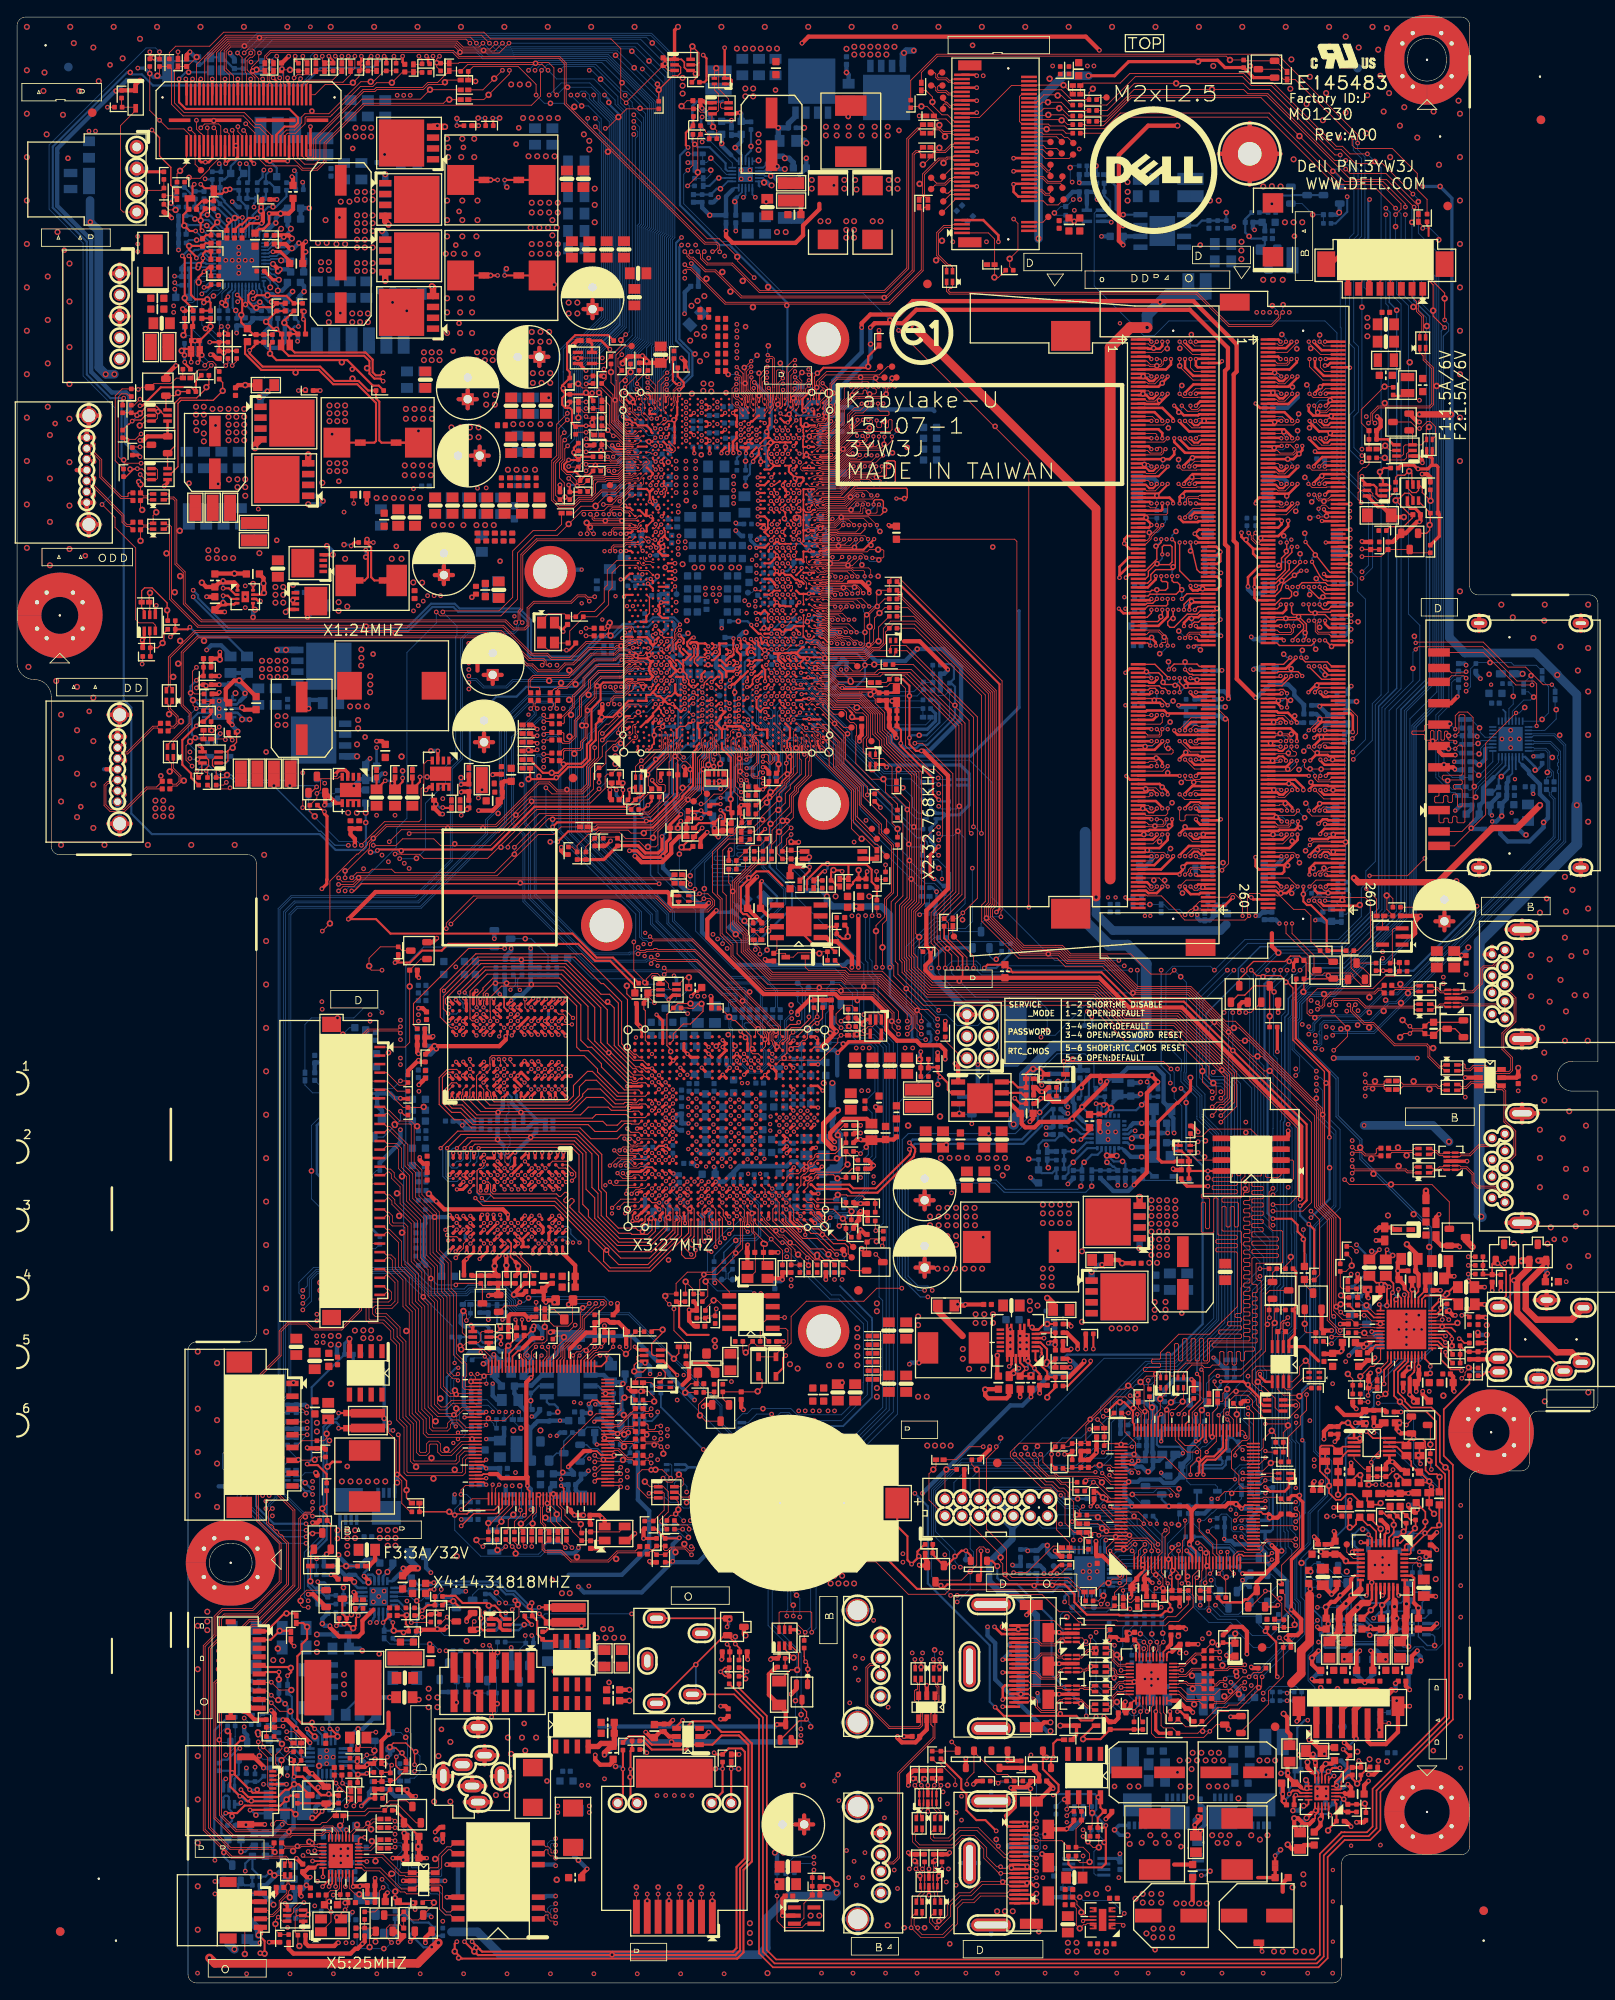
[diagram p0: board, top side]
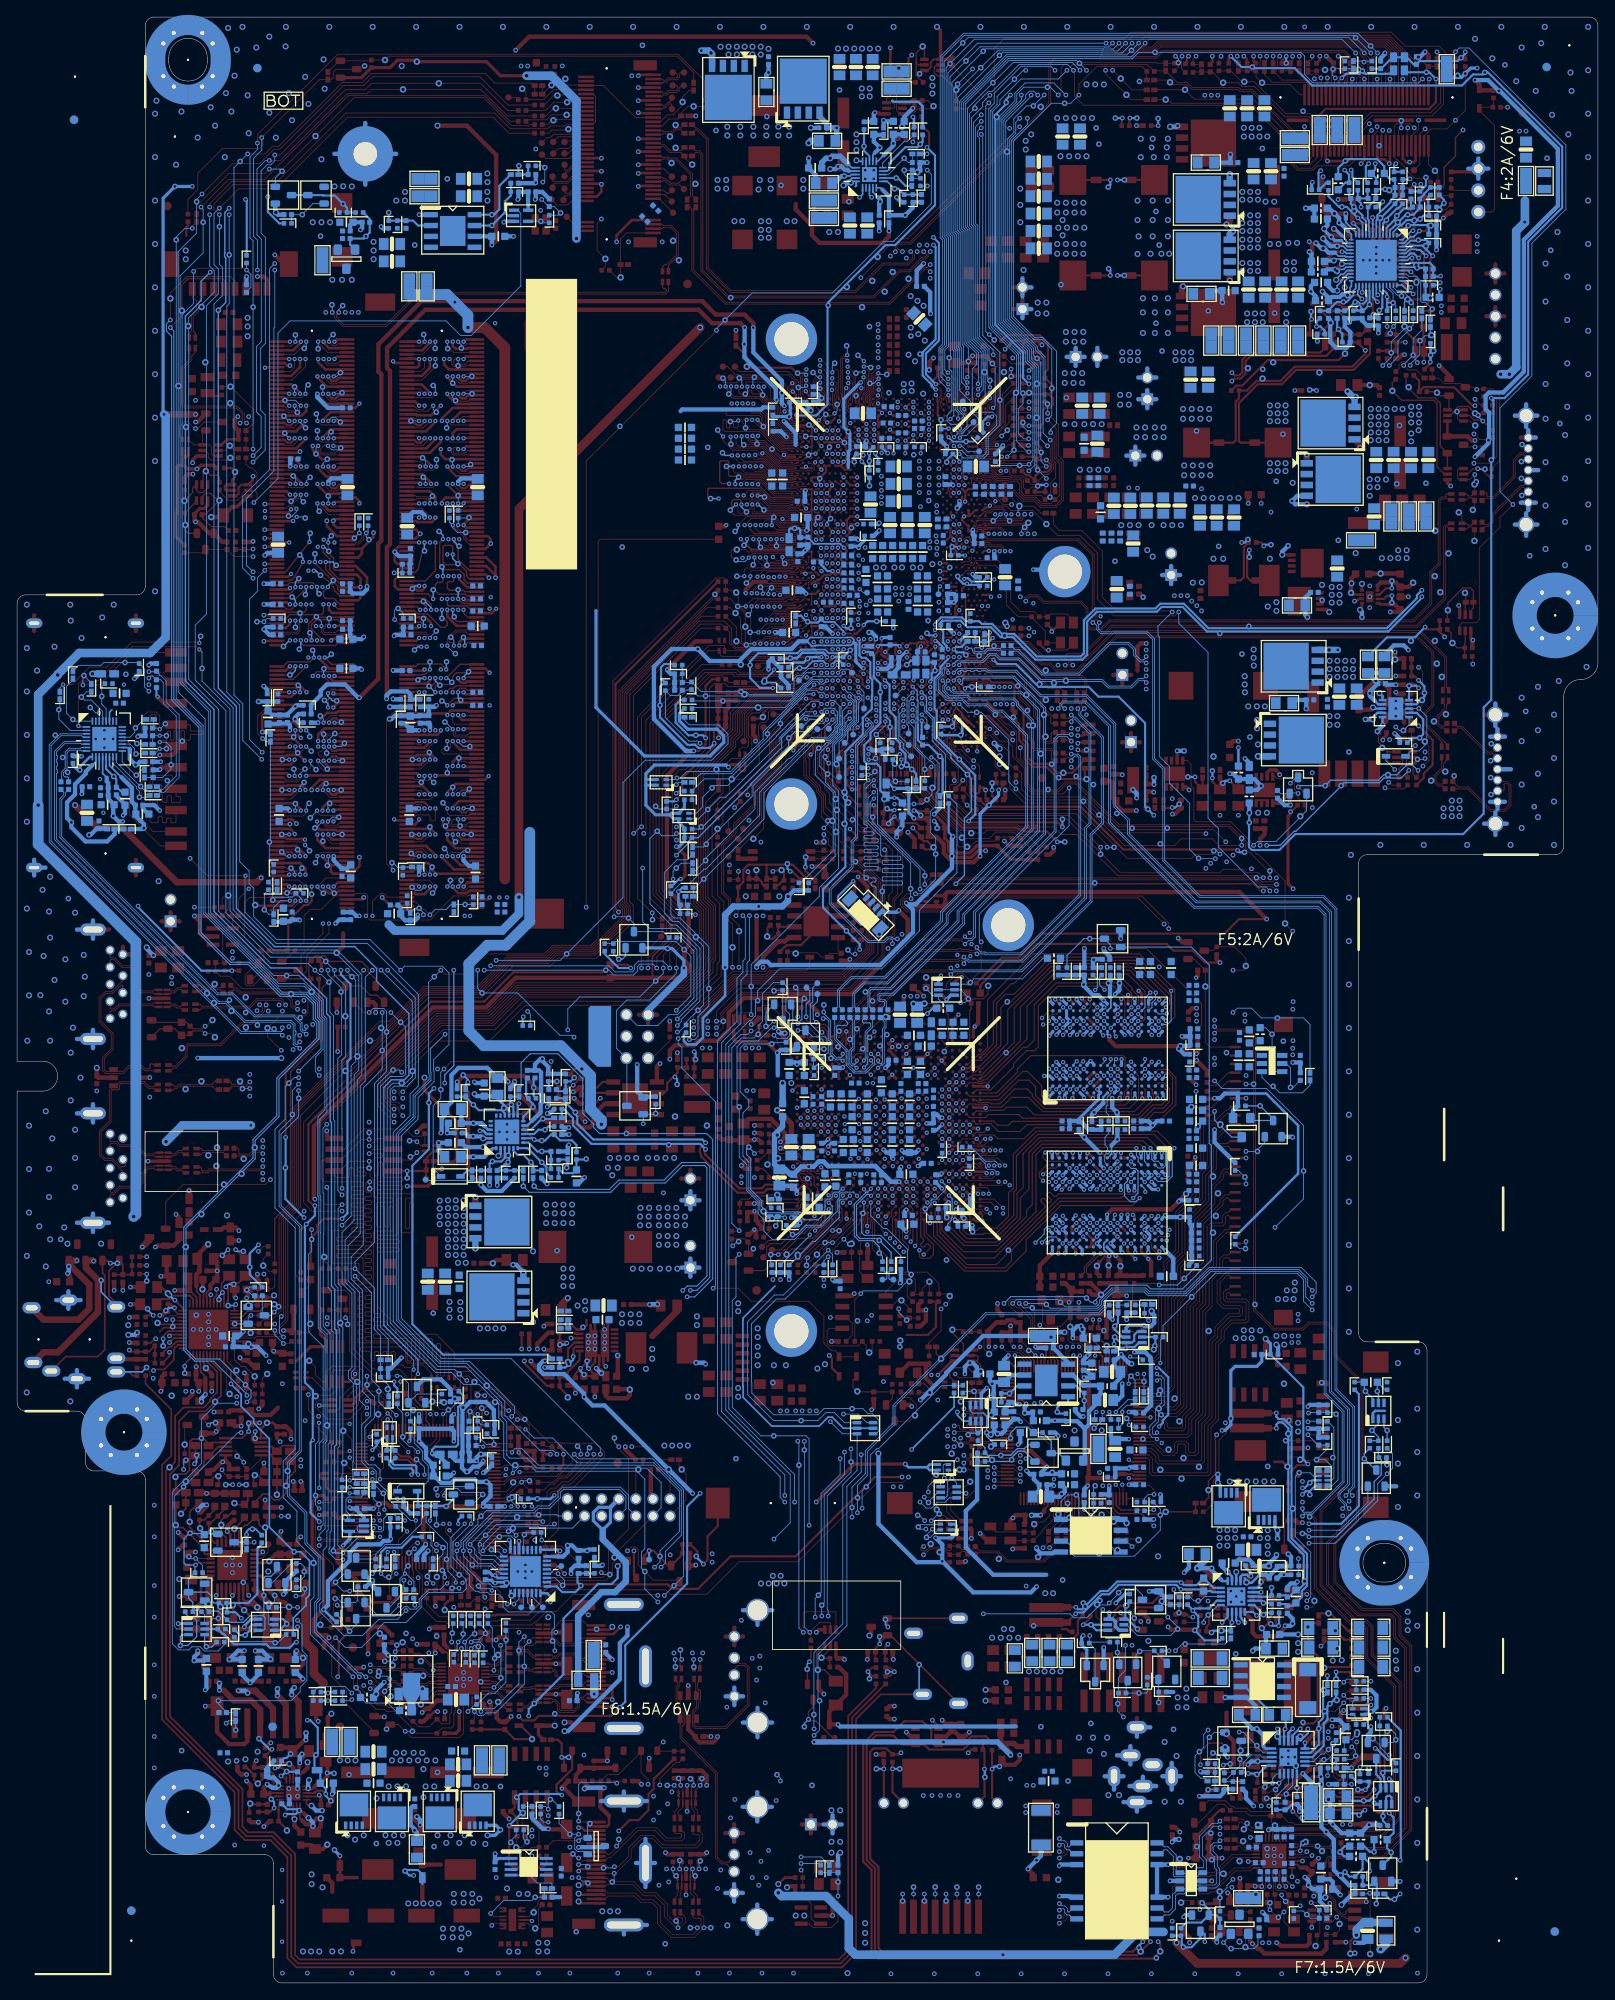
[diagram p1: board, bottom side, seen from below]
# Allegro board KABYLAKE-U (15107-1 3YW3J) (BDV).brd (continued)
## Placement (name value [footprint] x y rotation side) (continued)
R766  4K7R2J-2-GP  [R402H16]  53.5 55.24 270 bottom
R767  10KR2J-3-GP  [R402H16]  132.49 54.61 270 bottom
R768  1KR2J-1-GP  [R402H16]  140.88 54.36 270 bottom
R769  200KR2J-L1-GP  [R402H16]  138.08 55.37 180 bottom
R770  1KR2J-1-GP  [R402H16]  137.07 55.37 180 bottom
R771  -  [0R0402-PAD]  136.05 55.37 180 bottom
R772  10KR2F-2-GP  [R402H16]  140.88 53.34 270 bottom
R773  0R2J-2-GP  [R402H16]  124.11 52.7 270 bottom
R774  20KR2J-L2-GP  [R402H16]  156.37 51.94 0 bottom
R775  -  [0R0402-PAD]  158.15 51.18 180 bottom
R776  0R2J-2-GP  [R402H16]  117.43 50.27 0 bottom
R777  10KR2F-2-GP  [R402H16]  143.04 49.15 0 bottom
R778  -  [0R0402-PAD]  140.75 49.15 180 bottom
R779  -  [0R0402-PAD]  136.3 49.15 0 bottom
R780  0R2J-2-GP  [R402H16]  117.43 48.36 180 bottom
R781  0R2J-2-GP  [R402H16]  163.74 48.01 90 bottom
R782  1KR2J-1-GP  [R402H16]  144.69 46.35 90 bottom
R783  0R2J-2-GP  [R402H16]  139.05 46.02 90 bottom
R784  1KR2J-1-GP  [R402H16]  139.05 45.01 90 bottom
R785  160KR2F-GP  [R402H16]  49.03 44.7 180 bottom
R786  20KR2J-L2-GP  [R402H16]  160.94 44.45 270 bottom
R787  20KR2J-L2-GP  [R402H16]  160.43 42.93 180 bottom
R788  10KR2J-3-GP  [R402H16]  155.1 43.94 270 bottom
R789  0R2J-2-GP  [R402H16]  164.88 43.43 270 bottom
R790  0R2J-2-GP  [R402H16]  162.97 43.43 270 bottom
R791  100KR2J-1-GP  [R402H16]  147.61 42.67 0 bottom
R792  4K7R2F-GP  [R402H16]  133.97 42.49 180 bottom
R793  4K7R2F-GP  [R402H16]  132.95 42.49 180 bottom
R794  4K7R2F-GP  [R402H16]  131.94 42.49 180 bottom
R795  4K7R2F-GP  [R402H16]  130.92 42.49 180 bottom
R796  4K7R2F-GP  [R402H16]  129.9 42.49 180 bottom
R797  4K7R2F-GP  [R402H16]  127.8 41.66 180 bottom
R798  4K7R2J-2-GP  [R402H16]  161.07 41.4 270 bottom
R799  10KR2J-3-GP  [R402H16]  159.57 40.89 0 bottom
R800  1KR2J-1-GP  [R402H16]  153.07 40.77 270 bottom
R801  0R2J-2-GP  [R402H16]  161.2 39.88 270 bottom
R802  33R2J-2-GP  [R402H16]  56.68 39.88 270 bottom
R803  1K5R2J-3-GP  [R402H16]  59.98 39.75 90 bottom
R804  1R5J-2-GP  [R805H24]  37.88 39.12 270 bottom
R805  10KR2J-3-GP  [R402H16]  51.47 38.86 270 bottom
R806  4K7R2F-GP  [R402H16]  133.89 37.97 180 bottom
R807  D33R6F-GP  [R1206H26]  45.37 37.97 270 bottom
R808  4K7R2F-GP  [R402H16]  132.49 37.95 180 bottom
R809  4K99R2F-L-GP  [R402H16]  131.48 37.9 180 bottom
R810  4K7R2F-GP  [R402H16]  130.46 37.9 180 bottom
R811  D33R6F-GP  [R1206H26]  45.37 35.69 270 bottom
R812  100KR2J-1-GP  [R402H16]  52.74 35.31 0 bottom
R813  1KR2J-1-GP  [R402H16]  27.85 35.31 270 bottom
R814  -  [0R0402-PAD]  31.66 34.42 180 bottom
R815  -  [0R0402-PAD]  30.64 34.42 180 bottom
R816  10KR2J-3-GP  [R402H16]  27.85 34.29 270 bottom
R817  15KR2F-GP  [R402H16]  50.96 34.04 90 bottom
R818  36R3F-GP  [R603H22]  144.05 33.4 90 bottom
R819  1KR2J-1-GP  [R402H16]  27.85 33.27 270 bottom
R820  4K7R2F-GP  [R402H16]  131.22 33.02 0 bottom
R822  180R3F-GP  [R603H22]  139.48 31.88 270 bottom
R823  0R5J-5-GP  [R805H24]  41.05 31.37 270 bottom
R824  200R5J-GP  [R805H24]  37.5 31.37 90 bottom
R826  10KR2J-3-GP  [R402H16]  25.08 31.09 270 bottom
R827  1KR2J-1-GP  [R402H16]  27.85 30.23 270 bottom
R828  10KR2J-3-GP  [R402H16]  25.08 30.07 90 bottom
R829  10KR2F-2-GP  [R402H16]  30.64 28.83 0 bottom
R830  100R2F-L1-GP-U  [R402H14]  30.13 27.18 90 bottom
R831  33R2J-2-GP  [R402H16]  30.13 26.16 90 bottom
R832  4K7R2J-2-GP  [R402H16]  45.25 25.65 270 bottom
R833  10KR2J-3-GP  [R402H16]  23.63 25.27 180 bottom
R834  4K7R2J-2-GP  [R402H16]  32.04 25.15 270 bottom
R835  100KR2J-1-GP  [R402H16]  45.25 24.64 270 bottom
R836  10KR2F-2-GP  [R402H16]  42.2 24.64 270 bottom
R837  33R2J-2-GP  [R402H16]  29.32 24.18 270 bottom
R838  4K7R2J-2-GP  [R402H16]  43.72 24.13 180 bottom
R839  10KR2F-2-GP  [R402H16]  27.85 24 180 bottom
R840  -  [0R0402-PAD]  45.25 23.62 270 bottom
R841  10KR2J-3-GP  [R402H16]  42.71 23.11 0 bottom
R842  1KR2J-1-GP  [R402H16]  44.23 22.61 270 bottom
R843  10KR5F-2-GP  [R805H24]  30.39 21.84 90 bottom
R844  0R1206-PAD-1-GP  [0R1206-PAD-1]  33.56 21.08 180 bottom
R845  1KR2F-3-GP  [R402H16]  37.63 20.7 180 bottom
R846  100KR2F-L1-GP  [R402H16]  35.21 21.34 180 bottom
R847  4K7R2J-2-GP  [R402H16]  125.76 20.19 0 bottom
R848  0R2J-2-GP  [R402H16]  123.73 20.19 180 bottom
R849  47R2J-2-GP  [R402H16]  121.57 20.19 0 bottom
R850  10KR5F-2-GP  [R805H24]  30.39 19.84 90 bottom
R851  10KR2J-3-GP  [R402H16]  25.05 18.41 90 bottom
R852  75R3F-GP  [R603H22]  29.04 16.76 180 bottom
R853  75R3F-GP  [R603H22]  27.77 16.76 180 bottom
R854  75R3F-GP  [R603H22]  25.43 16.76 90 bottom
R855  75R3F-GP  [R603H22]  28.3 14.81 90 bottom
R856  0R2J-2-GP  [R402H16]  90.97 13.34 180 bottom
R857  -  [0R0402-PAD]  89.95 13.34 180 bottom
R858  0R2J-2-GP  [R402H16]  27.97 12.45 270 bottom
R859  0R2J-2-GP  [R402H16]  126.14 17.91 270 bottom
R860  4K7R2J-2-GP  [R402H16]  27.97 11.43 90 bottom
R861  -  [0R0402-PAD]  122.84 11.05 90 bottom
R862  10KR2J-3-GP  [R402H16]  27.97 10.41 90 bottom
R863  -  [0R0402-PAD]  25.43 10.41 90 bottom
R864  -  [0R0805-PAD]  40.93 9.91 270 bottom
R865  2KR2F-3-GP  [R402H16]  32.16 8.51 270 bottom
R868  1KR2J-1-GP  [R402H16]  35.59 7.98 180 bottom
R869  10KR2J-3-GP  [R402H16]  44.23 7.95 180 bottom
R870  10KR2J-3-GP  [R402H16]  49.82 5.97 0 bottom
R871  0R2J-2-GP  [R402H16]  48.8 5.97 180 bottom
R872  1KR2F-3-GP  [R402H16]  55.79 99.82 270 bottom
R873  1KR2F-3-GP  [R402H16]  59.22 100.33 180 bottom
R874  10KR2F-2-GP  [R402H16]  133.31 68.78 0 bottom
R875  -  [0R0402-PAD]  148.62 223.14 180 top
R876  10KR2J-3-GP  [R402H16]  165.01 206.5 180 top
R877  10KR2J-3-GP  [R402H16]  108.49 127.89 180 bottom
R879  10KR2J-3-GP  [R402H16]  43.47 20.19 270 top
R881  -  [0R0402-PAD]  33.69 106.05 180 bottom
R882  330R3J-L-GP  [R603H22]  39.53 111 180 bottom
R883  100KR2J-1-GP  [R402H16]  140.24 55.75 270 bottom
R884  0R2J-2-GP  [R402H16]  147.73 62.1 270 top
R885  0R2J-2-GP  [R402H16]  147.73 63.25 270 top
R886  10KR2J-3-GP  [R402H16]  86.14 141.73 0 bottom
R888  10KR2J-3-GP  [R402H16]  110.27 103.25 0 bottom
R889  0R2J-2-GP  [R402H16]  155.61 85.72 0 top
R890  10KR2J-3-GP  [R402H16]  152.31 48.64 180 bottom
R891  0R2J-2-GP  [R402H16]  152.31 46.74 0 bottom
R892  330R2F-GP  [R402H16]  82.56 26.29 0 top
R893  330R2F-GP  [R402H16]  72.42 28.32 270 top
R894  330R2F-GP  [R402H16]  70.9 27.69 0 top
R895  330R2F-GP  [R402H16]  72.42 27.3 270 top
RJ1  RJ45-8P-199-GP  [23-01120-2A03-A]  76.92 21.04 180 top
RN1  SRN10KJ-5-GP  [ARES2H18]  82.2 222.5 90 top
RN2  SRN10KJ-5-GP  [ARES2H18]  165.29 179.98 0 top
RN3  SRN10KJ-5-GP  [ARES2H18]  102.52 156.46 180 top
RN4  SRN2K2J-4-GP  [ARES8-CN24-UH20]  81.82 140.97 0 top
RN5  SRN10KJ-5-GP  [ARES2H18]  136.69 97.66 270 top
RN6  SRN2K2J-1-GP  [ARES2H16]  151.8 71.12 90 top
RN7  SRN33J-5-GP-U  [SMD-ARES4H18]  134.15 70.23 0 top
RN8  SRN33J-5-GP-U  [SMD-ARES4H18]  136.18 70.23 0 top
RN9  SRN10KJ-5-GP  [ARES2H18]  148.24 59.31 90 top
RN10  SRN10KJ-5-GP  [ARES2H18]  109.63 140.46 90 bottom
RN11  SRN10KJ-5-GP  [ARES2H18]  106.97 136.53 90 bottom
RN13  SRN10KJ-5-GP  [ARES2H18]  141.38 64.39 180 bottom
RN14  SRN33J-7-GP-U  [ARES8-CN24-UH20]  32.16 59.05 270 bottom
RN15  SRN10KJ-5-GP  [ARES2H18]  76.36 53.34 90 bottom
RN16  SRN10KJ-5-GP  [ARES2H18]  72.7 140.46 180 top
RN17  SRN10KJ-5-GP  [ARES2H18]  78.01 126.87 270 top
RN18  SRN10KJ-5-GP  [ARES2H18]  100.13 143.15 180 top
RN19  SRN4K7J-8-GP  [SMD-ARES4H18]  76.61 60.33 90 bottom
RN20  SRN10KJ-5-GP  [ARES2H18]  28.1 31.75 90 bottom
RN21  SRN10KJ-5-GP  [ARES2H18]  75.85 69.98 90 top
RV1  P4500SCLHLRP-GP  [TVS5436-1121H105]  65.06 18.16 0 top
SATAP1  CLX-CON5-18-GP-U  [CI2505P1H00-LF-U]  12 195 270 top
SCA1  RTD2506S-CG-GP  [LQFP128H63]  61.37 64.39 270 top
SPK1  JWT-CON6-20-GP  [A1501WV0-6PS-5E]  155.8 32.38 180 top
SRCON1  SKT-G6179HT0321-001-GP  [G6179HT0321-001]  144.42 96.9 270 top
SSUSB1  SKT-USB11-112-GP-U  [SKT-USB11-138165-1]  176.12 116.84 90 top
SSUSB2  SKT-USB11-112-GP-U  [SKT-USB11-138165-1]  176.12 95.34 90 top
TC1  ST330U2D5VDM-9GP  [CT7343H75]  146.97 205.1 180 top
TC2  ST100U6D3VBM-7GP  [CT3528H79]  15.91 201.52 180 top
TC3  E100U16VM-108-GP-U  [ECAP-100D6D3H237]  167.04 125.48 0 top
TC4  E100U16VM-108-GP-U  [ECAP-100D6D3H237]  90.84 18.54 90 top
TOUCH1  ENT-CON5-GP  [3703K-Q05N-11L]  24.7 8.5 270 top
TP1  -  [TPAD30]  106.94 223.52 90 top
TP2  -  [TPAD30]  108.26 223.52 90 top
TP3  -  [TPAD30]  106.97 222 90 top
TP4  -  [TPAD30]  108.29 222 90 top
TP5  -  [TPAD30]  108.36 220.57 90 top
TP6  -  [TPAD30]  127.49 220.6 0 top
TP7  -  [TPAD30]  108.36 219.25 270 top
TP8  -  [TPAD30]  120.94 215.39 0 top
TP9  -  [TPAD30]  122.26 215.39 0 top
TP10  -  [TPAD30]  123.6 215.26 0 top
TP11  -  [TPAD30]  120.94 214.05 0 top
TP12  -  [TPAD30]  122.26 214.05 0 top
TP13  -  [TPAD30]  123.58 213.92 0 top
TP14  -  [TPAD30]  120.94 212.72 0 top
TP15  -  [TPAD30]  21.52 212.09 0 top
TP16  -  [TPAD30]  120.94 211.4 0 top
TP17  -  [TPAD30]  108.36 211.33 90 top
TP18  -  [TPAD30]  122.33 211.35 0 top
TP19  -  [TPAD30]  106.97 211.2 90 top
TP20  -  [TPAD30]  122.33 210.03 0 top
TP21  -  [TPAD30]  106.97 209.88 90 top
TP22  -  [TPAD30]  120.94 209.93 0 top
TP23  -  [TPAD30]  108.36 209.75 0 top
TP24  -  [TPAD30]  121.06 208.61 0 top
TP25  -  [TPAD30]  108.24 207.11 0 top
TP26  -  [TPAD30]  108.39 208.43 0 top
TP27  -  [TPAD30]  122.46 208.66 0 top
TP28  -  [TPAD30]  120.68 206.63 0 top
TP29  -  [TPAD30]  71.92 191.52 0 top
TP30  -  [TPAD30]  101 189.1 0 top
TP31  -  [TPAD30]  102.4 189.1 0 top
TP32  -  [TPAD30]  101.51 187.83 0 top
TP33  -  [TPAD30]  102.9 187.83 0 top
TP34  -  [TPAD30]  69.38 175.23 0 top
TP35  -  [TPAD30]  69.38 173.58 0 top
TP36  -  [TPAD30]  98.33 154.05 0 top
TP37  -  [TPAD30]  96.48 148.44 0 top
TP38  -  [TPAD30]  97.65 146.89 0 top
TP39  -  [TPAD30]  99.98 145.29 0 top
TP40  -  [TPAD30]  80.73 139.12 0 top
TP41  -  [TPAD30]  79.18 138.25 0 top
TP42  -  [TPAD30]  100.03 135.03 0 top
TP43  -  [TPAD30]  101.76 134.75 0 top
TP44  -  [TPAD30]  100.62 133.86 0 top
TP45  -  [TPAD30]  101.76 131.83 0 top
TP46  -  [TPAD28]  91.35 115.7 180 bottom
TP47  -  [TPAD28]  92.62 116.46 180 bottom
TP48  -  [TPAD28]  91.35 116.97 180 bottom
TP49  -  [TPAD30]  96.65 85.75 0 top
TP50  -  [TPAD30]  97.67 84.89 0 top
TP51  -  [TPAD30]  97.85 86.11 0 top
TP52  -  [TPAD30]  155.61 51.31 0 top
TP53  -  [TPAD28]  111.03 49.53 90 bottom
TP54  -  [TPAD28]  74.33 185.04 180 bottom
TP55  -  [TPAD28]  73.06 182.63 180 bottom
TP56  -  [TPAD28]  72.42 179.2 180 bottom
TP57  -  [TPAD28]  85.53 162.66 180 bottom
TP58  -  [TPAD28]  77.17 162.48 180 bottom
TP59  -  [TPAD28]  87.28 153.29 180 bottom
TP60  -  [TPAD28]  93.51 152.4 180 bottom
TP61  -  [TPAD28]  82.2 150.62 180 bottom
TP62  -  [TPAD28]  85.89 149.1 180 bottom
TP63  -  [TPAD28]  93.25 147.07 180 bottom
TP64  -  [TPAD28]  78.52 146.94 180 bottom
TP65  -  [TPAD28]  91.35 146.69 180 bottom
TP66  -  [TPAD28]  90 146.74 180 bottom
TP67  -  [TPAD28]  80.68 146.18 180 bottom
TP68  -  [TPAD28]  87.16 146.05 180 bottom
TP69  -  [TPAD28]  88.15 145.08 180 bottom
TP70  -  [TPAD28]  80.65 144.83 180 bottom
TP71  -  [TPAD28]  80.37 143.51 180 bottom
TP72  -  [TPAD28]  88.81 143.26 180 bottom
TP73  -  [TPAD28]  88.81 141.1 180 bottom
TP74  -  [TPAD28]  137.19 93.98 180 bottom
TP75  -  [TPAD28]  76.11 88.27 180 bottom
TP76  -  [TPAD28]  83.73 82.3 180 bottom
TP77  -  [TPAD28]  82.46 82.3 180 bottom
TP78  -  [TPAD28]  121.32 48.77 270 bottom
TP79  -  [TPAD28]  126.02 43.94 270 bottom
TP80  -  [TPAD28]  124.75 43.94 270 bottom
TP81  -  [TPAD28]  123.48 43.94 270 bottom
TP82  -  [TPAD30]  109.63 122.43 0 top
TR1  MCM1012B900FBP-GP-U  [L125100-4P-1H37]  109.13 199.64 270 top
TR2  FILTER-4P-184-GP  [L125100-4P-4H28]  164.5 191.9 90 top
TR3  FILTER-4P-184-GP  [L125100-4P-4H28]  167.93 107.06 0 top
TR4  FILTER-4P-184-GP  [L125100-4P-4H28]  167.93 104.78 0 top
TR5  FILTER-4P-120-GP  [L125100-4P-1H28]  126.78 38.87 0 top
TR6  FILTER-4P-120-GP  [L125100-4P-1H28]  126.78 36.71 0 top
TR7  FILTER-4P-184-GP  [L125100-4P-4H28]  105.44 36.2 270 top
TR8  FILTER-4P-184-GP  [L125100-4P-4H28]  107.6 36.2 270 top
TR9  FILTER-4P-120-GP  [L125100-4P-1H28]  126.78 34.43 0 top
TR10  FILTER-4P-120-GP  [L125100-4P-1H28]  126.78 32.27 0 top
TR11  DLM11SN900HY2L-GP  [L125100-4P-4H24]  105.57 18.67 270 top
TR12  DLM11SN900HY2L-GP  [L125100-4P-4H24]  107.73 18.67 270 top
TR13  MCM1012B900FBP-GP-U  [L125100-4P-1H37]  31.66 13.21 90 top
TR14  DLM11SN900HY2L-GP  [L125100-4P-4H24]  105.57 8.89 270 top
TR15  DLM11SN900HY2L-GP  [L125100-4P-4H24]  107.73 8.89 270 top
U1  74LVC1G07GW-GP  [SC70-5H44]  66.45 190.12 90 top
U2  MMBT3904DW-GP  [SOT-363H44]  162.36 179.3 90 top
U3  AOZ1334DI-01-GP  [DFN8F3-G2517H32]  49.56 141.48 0 top
U4  AOZ1334DI-01-GP  [DFN8F3-G2517H32]  39.02 139.57 0 top
U5  G524B1T11U-GP  [SOT-23-5H58]  160.94 122.43 90 top
U6  AZ1045-04F-R7G-GP  [DFN10G2510H26]  167.93 115.19 270 top
U7  NL17SZ08DFT2G-GP  [SC70-5H44]  100.49 111.89 0 top
U8  W25Q128FVSIQ-GP  [SOIC8-1H86]  144.43 96.9 90 top
U9  AZ1045-04F-R7G-GP  [DFN10G2510H26]  167.8 96.14 270 top
U10  MX25L1006EMI-10G-GP  [SOIC8H69]  85.89 78.49 90 top
U11  ALC3661-CG-GP  [QFN48J6-G465H40]  162.59 76.45 90 top
U12  NCT7718W-GP  [MSOP8-1H44]  147.86 72.39 180 top
U13  TS5A22364DGSR-1-GP  [MSOP10H44]  158.53 62.74 270 top
U14  TPA3131D2RHBR-GP-U  [QFN32-G3D55H40]  159.8 48.9 0 top
U15  AZ1045-04F-R7G-GP  [DFN10G2510H26]  123.48 40.89 270 top
U16  AZ1045-04F-R7G-GP  [DFN10G2510H26]  123.48 37.36 90 top
U17  PS8407ATQFN40GTR2-A1-GP  [QFN40J5-G3D65H32]  132.75 35.56 270 top
U18  AZ1045-04F-R7G-GP  [DFN10G2510H26]  123.48 33.78 270 top
U19  AO4407AL-GP  [SOIC8H69]  64.93 30.2 0 top
U20  AZ1215-04S-R7G-GP  [SOT-6H58]  78.52 28.83 90 top
U21  AZ23C6V2-1-GP  [SOT-23-9H44]  111.03 26.16 180 top
U22  M24C02-WMN6TP-1-GP  [SOIC8H69]  124.87 24.26 180 top
U23  RTL8111G-CGT-1-GP-U2  [QFN32J4-G2D85H36]  37.88 14.86 270 top
U24  AZ1215-04S-R7G-GP  [SOT-6H58]  47.58 11.94 270 top
U25  G524B1T11U-GP  [SOT-23-5H58]  92.11 7.87 270 top
U26  AP22966DC8-7-GP  [SON14J3020-G2610H32]  127.03 7.37 270 top
U27  SN74AUP1G08DCKR-GP  [SC70-5H44]  126.02 206.76 90 bottom
U28  RTS5250S-GR-GP-U  [QFN32J4-G2D85H36]  174.79 145.54 90 bottom
U30  NCP81172MNTXG-GP-U  [LFQFN24G4-G2D9H40]  127.67 99.57 0 bottom
U31  G9661-25ADJF11U-1-GP  [SOIC8-G371264H65]  64.55 70.48 90 bottom
U32  TC7SZ08FU-2-GP  [SC70-5H44]  145.23 53.47 270 bottom
U33  W25Q80DVSSIG-1-GP  [SOIC8-1H86]  59.34 52.32 270 bottom
U34  NPCT650JA0YX-GP  [QFN32G5-G3D6H32]  125.51 48.13 270 bottom
U35  AZ1117CR-ADJTRG1-GP-U  [SOT-89-4541-3PH63]  138.84 33.78 180 bottom
U36  OZ554ALN-B-0-TR-GP  [QFN20-G2D1H32]  36.23 26.42 90 bottom
U37  AZ23C6V2-1-GP  [SOT-23-9H44]  117.23 16 270 bottom
U38  SY6288C10CAC-GP  [MSOP8-1H44]  125.13 13.59 270 bottom
U39  AZ1215-04S-R7G-GP  [SOT-6H58]  47.58 11.94 270 bottom
U40  NCT3521U-2-GP  [SOT-6-1H58]  38.13 107.57 270 bottom
UHS1  AUDIO-JK500-GP  [2SJ3082-038111F]  176.5 75.29 90 top
USB3  SKT-USB6-174-GP  [SKT-USB6-135063]  98.35 37.03 90 top
USB4  SKT-USB6-174-GP  [SKT-USB6-135063]  98.38 14.03 90 top
VRAM1  H5GC4H24AJR-T2C-GP  [BGA170D1214H48]  57.39 109.34 90 top
VRAM2  H5GC4H24AJR-T2C-GP  [BGA170D1214H48]  57.44 91.31 270 top
VRAM3  H5GC4H24AJR-T2C-GP  [BGA170D1214H48]  57.39 109.34 90 bottom
VRAM4  H5GC4H24AJR-T2C-GP  [BGA170D1214H48]  57.44 91.31 270 bottom
WEBCM1  JWT-CON8-4-GP  [A1251WR0-8PS-5E]  160.12 201.1 180 top
X1  XTAL-24MHZ-126-GP  [OSC-3225-4P-4H36]  62.14 157.99 270 top
X2  XTAL-32D768KHZ-67-GP  [SMD49-6914-0403H56]  95.54 131.95 0 top
X3  XTAL-27MHZ-85-GP-U  [OSC-3225-4P-4H30]  86.65 83.19 0 top
X4  XTAL-14D31818MHZ-37-GP  [OSC-3225-4P-3H36]  69.93 52.58 0 top
X5  XTAL-25MHZ-181-GP  [OSC-3225-4P-4H36]  36.74 6.73 0 top
XDP1  PAD-60P-GP  [PAD-60P]  27.08 217.93 0 top
XF1  XFORM-12P-48-GP  [XFORM12A127097H91]  56.29 11.94 90 top
XF2  XFORM-12P-48-GP  [XFORM12A127097H91]  56.29 11.94 270 bottom

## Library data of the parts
AFTP1 TP46-TP48 TP53-TP81 = TPAD28: tolerance: ZZ.PAD28.XXX
BAT2 = 51202-00901-W01-U: tolerance: 020.F0592.0009
BT1 = AAA-BAT-034-K01: tolerance: 62.70010.031
C1-C3 C6 C11 C16 C36 C42 C43 C45 C72 C74 C77 C80 C85 C93-C95 C99 C102 C105 C113 C118 C123 C127 C138 C139 C142 C143 C147 C156-C158 C160 C161 C163 C164 C167 C168 C171-C173 C190 C195 C198 C205 C210 C214 C233-C238 C241 C246 C251 C262 C265 C268 C269 C272 C281 C283 C284 C288 C293 C294 C310 C334 C337-C339 C343 C346 C355 C356 C359 C360 C363 C369 C378 C384 C388-C391 C400-C402 C406 C411 C414 C415 C417-C419 C422-C424 C430-C432 C453 C454 C459-C461 C480-C482 C488-C492 C500 C501 C503 C506 C508-C512 C516 C517 C520 C532-C534 C540-C543 C545-C547 C550 C552-C554 C556 C557 C559-C561 C563 C575 C578 C586 C588 C591 C592 C597-C603 C605 C609 C611 C612 C621 C627 C634 C637 C638 PC78 PC86 PC89 PC90 PC92 PC111 PC129 PC157 PC262 PC274 PC289 PC293 = C402H22: tolerance: 78.10421.2FLDL
C4 C119 C196 C239 C275 C291 C412 C413 C555 PC19 PC74 = C603H36: tolerance: 78.22523.5BLDL
C5 C130 = C402H22: tolerance: 78.10421.2FLLL
C7-C9 C97 C120 C136 C140 C141 C145 C146 C159 C301 C306 C308 C309 C315 C341 C426 C444 C445 C449-C451 C456 C483 C526 C529 PC81-PC83 = C603H36: tolerance: 78.10610.5BLDL
C10 C114 C121 C152 C154 C177 C178 C240 C428 C429 C443 C447 C469 C479 C502 C504 C513 C515 C519 C521 C530 PC7 PC11 PC84 PC91 PC113 PC133 PC134 PC141 PC142 PC146 PC259 = C603H36: tolerance: 078.10524.05BD
C12 C13 C18-C20 C35 C37 C39 C51 C55 C57 C59 C63 C66-C69 C73 C103 C131 C132 C134 C144 C162 C174 C175 C182 C274 C279 C280 C282 C290 C292 C296-C300 C302-C305 C307 C313 C314 C317-C319 C321 C322 C330-C333 C335 C336 C340 C342 C344 C345 C347-C349 C354 C357 C361 C362 C364 C365 C367 C371-C373 C375 C379 C381 C382 C386 C396 C403 C462 C464-C467 C470 C471 C478 C531 C593 C604 C606 C610 C620 C624 C628 C633 PC59 PC67 PC68 PC175 PC252 PC256 PC265 PC282 PC295 = C402H22: tolerance: 78.10523.5FLDL
C14 C15 C17 C75 C76 C109-C112 C115 C122 C126 C243 C261 C263 C264 C278 C407 C441 C442 C536 C537 C539 C549 C558 C585 C623 PC5 PC93 PC94 PC96 PC97 PC154 PC155 PC170-PC172 PC176 = C805H50: tolerance: 78.10623.51LDL
C21 C22 C24 C25 C40 C41 C52 C53 = C402H22: tolerance: 78.10324.2FLDL; signal model: 2pins
C23 C26 C324-C329 C350-C353 C358 C366 C377 C409 C410 PC200 PC201 PC209 PC225 PC241 PC243-PC246 PC251 = C603H40: tolerance: 78.22610.5BLDL
C27 C30 C254 C376 C380 C394 C395 C594 PC166 = C402H22: tolerance: 78.33034.1FLDL
C28 C29 C33 C34 C81 C82 C100 C101 C165 C166 C169 C170 C187 C189 C215 C219-C221 C223 C228 C230 C232 C257 C259 C370 C374 C398 C399 = C402H22: tolerance: 78.10421.2FLDL; signal model: 2pins
C31 C32 C38 C44 C46 C47 C49 C50 = C402H22: tolerance: 078.22423.05FD; signal model: 2pins
C48 C54 C151 C255 C258 C260 C383 C392 C393 C404 C405 C408 C420 C421 C455 C457 C458 C463 C468 C472-C477 C484-C487 C493-C497 C505 C514 C518 C596 C614 C630-C632 PC128 PC261 PC290 = C603H36: tolerance: 78.47520.5BLDL
C56 C65 C320 C368 C565 C567 PC25 PC27 PC30 PC34 PC35 PC38 PC39 PC45 PC49-PC51 PC62-PC66 PC72 PC73 PC79 PC80 PC210-PC212 PC214-PC217 PC229 PC230 PC234-PC236 PC238 PC239 PC247 PC249 PC250 = C402-TO0D2H28: tolerance: 078.10610.05FD
C58 C106 C116 C128 C135 C137 C148 C155 C183 C216 C217 C242 C528 C535 PC85 PC88 PC145 PC258 = C402H22: tolerance: 78.10134.1FLDL
C60-C62 C89-C92 C98 C104 C149 C499 C507 PC2 PC3 PC14-PC17 PC21 PC22 PC37 PC40 PC42-PC44 PC46-PC48 PC52-PC58 PC60 PC61 PC71 PC98 PC103 PC104 PC114 PC115 PC143 PC144 PC147 PC156 PC162 PC167 PC173 PC177 PC193 PC195-PC199 PC202 PC207 PC208 PC213 PC218-PC224 PC226-PC228 PC231-PC233 PC237 PC242 PC248 = C805H54: tolerance: 78.22610.51LDL
C64 = C603H40: tolerance: 078.4761T.05BN
C70 C71 = C402H22: tolerance: 78.3R374.1FLDL
C78 C125 C247 C248 C570 PC9 PC36 PC164 PC165 PC189 PC279 PC285 PC299 PC302 = C402H22: tolerance: 78.10422.5FLDL
C79 C117 C185 C224-C227 C249 C271 C273 C277 C427 PC6 PC18 PC24 PC28 PC33 PC41 PC76 PC99 PC101 PC131 PC135 PC149 PC192 PC255 PC267 PC273 PC294 PC296 = C402H22: tolerance: 78.10224.2FLDL
C84 C124 C211-C213 C244 C245 C256 C425 C571 C584 C589 PC8 PC10 PC110 PC124 PC190 = C402H22: tolerance: 78.10324.2FLDL
C86 PC20 PC26 PC29 PC119 PC174 PC194 PC278 = C402H22: tolerance: 78.47124.2FLDL
C87 C88 C446 C448 C522-C525 = C402H22: tolerance: 78.82124.2FLDL
C96 C498 = C805H54: tolerance: 78.47610.51LDL
C107 C108 C184 C186 C270 C276 PC13 PC191 = C402H22: tolerance: 78.15034.1FLDL
C129 PC87 PC106 PC126 PC130 PC183 PC257 = C402H22: tolerance: 78.22034.1FLDL
C133 C636 PC23 PC109 PC161 = C402H22: tolerance: 78.22224.2FLDL
C150 C193 C197 C222 C229 C285 PC69 PC100 PC102 PC105 PC108 PC117 PC118 PC136-PC140 PC152 PC153 PC184-PC187 PC203-PC206 PC240 PC253 PC254 PC269-PC271 PC280 PC286-PC288 PC297 PC303 PC304 = C805H58: tolerance: 78.10622.51LDL
C153 = C402H22: tolerance: 78.10322.2FLDL
C176 C179-C181 = C603H36: tolerance: 78.27324.2BLDL
C188 C192 C194 C231 C527 C544 C590 PC1 PC77 PC95 PC107 PC112 PC116 PC121 PC122 PC125 PC127 PC132 PC151 PC263 PC272 PC281 PC283 PC284 PC291 PC292 = C603H35: tolerance: 78.10424.2BLDL
C191 C548 C562 C566 C568 C569 = C402H22: tolerance: 78.10423.2FL
C199 = C402H22: tolerance: 78.10134.1FL
C200 = C402H22: tolerance: 78.22124.2FL
C201-C204 PC70 PC169 PC179 PC182 = C603H36: tolerance: 78.22422.2BLDL
C206-C209 = C603H36: tolerance: 078.68421.02BD
C218 = C603H36: tolerance: 78.10492.4BLLL
C250 C253 = C402H22: tolerance: 78.10491.4FLDL
C252 = C402H22: tolerance: 78.27034.1FLDL
C266 C267 PC276 PC277 = C402H22: tolerance: 78.10034.1FLDL
C286 C287 C289 C538 = C402H22: tolerance: 78.10520.5FL
C295 C385 C387 C629 = C402H22: tolerance: 78.22321.2FLDL
C311 C312 C316 C323 = C805H54: tolerance: 78.22610.51LLL
C397 = C402H22: tolerance: 78.6R874.1FLDL
C416 PC123 PC159 = C402H22: tolerance: 78.22124.2FLDL
C433-C440 = C402H22: tolerance: 078.22423.05FD
C551 = C402H22: tolerance: 78.22510.5FL
C564 = C603H36: tolerance: 78.10521.5BLDL
C572 C573 C576 C577 C583 = C1206H75: tolerance: 078.10525.022D
C574 = C603H36: tolerance: 78.33135.1BL
C579-C582 = C603H36: tolerance: 78.10324.2BLDL
C587 PC120 = C603H36: tolerance: 78.47422.5BLDL
C595 = C1808H87: tolerance: 078.1013N.014D
C607 = C603H36: tolerance: 78.10522.5BLDL
C615 = C402H22: tolerance: 78.10520.5FLDL
C635 = C402H22: tolerance: 78.8R064.1FLDL
CN1 = 88459-047N: tolerance: 20.F1897.004
CONVT1 = CI1410M1HRL-NH: tolerance: 20.F2266.010
CPU1 = BGA1356M4224-U2H52: tolerance: 071.SKYLA.000U
D1 D2 D5 D6 D9 D19 D23 D24 PD2 = SOD323AKH38: tolerance: 83.00355.D1F
D3 D8 = SOT-6H58: tolerance: 075.02304.007C
D4 = SOD523AKH28: tolerance: 83.02015.0AF
D7 = SOT-23-9H44: tolerance: 75.00040.07D
D10 = SOT-23-9H44: tolerance: 83.6R803.E31
D11 = SOT-23-9H44: tolerance: 75.00054.A7D
D12 = DO214AAAK-1121H97: tolerance: 83.P6SMB.KAG
D13 D14 = SLP2510P8-1H22: tolerance: 83.03010.0A0
D15 D25 = D402H24: tolerance: 83.05325.AA0
D16 = SOT23-2D4-312H44: tolerance: 75.00054.T7D
D17 D18 = SOT23-2D4-312H48: tolerance: 75.00054.R7D
D20 = SOT23-2D4-312H48: tolerance: 75.00099.F7D
D21 = D4724AKH44: tolerance: 83.3R010.C8M
D22 = SOD882-10D6-1H20: tolerance: 83.05725.0A0
DCIN1 = JPDA3B1-V4501-7F: tolerance: 022.10015.0581
DCIN2 = 88314-077N: tolerance: 20.F1498.007
DIMM1 = 40-42271-26001RHF: tolerance: 062.10011.00Q1
DIMM2 = 40-42275-26001RHF: tolerance: 062.10011.0E11
F1 F2 F6 F7 = POLYSW-2114H30: tolerance: 069.50001.0031
F3 = FUSE-1608H22: tolerance: 69.43001.441
F4 = POLYSW-2114H30: tolerance: 069.50003.0001
FANC3 = HF1804H: tolerance: 021.D0086.0104
GPU1 = BGA595M23H83: tolerance: 071.0N16S.0A0U
H1-H5 = HOLE237R158: tolerance: ZZ.0HOLE.011
H6 H9 = GEN8D5X8R5X4D5-8-F-A: tolerance: ZZ.00PAD.BV1
H7 = GEN315R138-8-F-A-1: tolerance: ZZ.00PAD.BU1
H10 = GEN315R178-8-F-A-1: tolerance: ZZ.00PAD.BR1
H11 = GEN315R138-8-F-A-2-S: tolerance: ZZ.00PAD.HK1
HDD1 ODD1 = 15-02070-5A61-A: tolerance: 020.80244.0007
HDMI1 HDMI2 = SKT-HDMI22-150077: tolerance: 062.10012.0121
HDMI3 HDMI4 = LVDFH-02004-TP00: tolerance: 20.F2139.020
HS6 = STF256R109H99: tolerance: 34.3NH01.001
JMP1 = 21S-92-03GB16: tolerance: 021.60308.0203
KBC1 = LQFP128H63: tolerance: 071.00285.0A0G
L1-L4 = L125100-4P-1H24: tolerance: 68.11500.201; signal model: 4pins1
L5 L6 L9 L10 = L125100-4P-1H36: tolerance: 68.12105.201; signal model: 4pins1
L7 L24-L28 L31 L32 = L603H38: tolerance: 68.00335.081
L8 L23 = L603H38: tolerance: 68.00335.051
L11 = L603H38: tolerance: 68.00230.231
L12 L13 L19 L20 = L402H24: tolerance: 68.00213.031
L14 = L603H38: tolerance: 68.00335.141
L15-L18 = L20125H42: tolerance: 68.00216.111
L21 = L8080-6020H158: tolerance: 068.33010.1061
L29 PR3 PR6 PR32-PR36 PR49-PR52 PR64 PR67 PR122 PR123 PR128-PR130 PR134 PR138 PR139 PR142 PR163 PR169 PR175 PR176 PR191-PR196 PR198-PR201 PR261 PR262 PR264 PR265 R67 R68 R156 R533 R535 R542 R711 R745 R864 = 0R0805-PAD: tolerance: ZZ.R0805.ZZZ
L30 = L402H22: tolerance: 68.00084.541
LED1 = LED1608AKH30: tolerance: 83.01608.Q70
LOUT1 = JAC331-0140A8B-9H: tolerance: 22.10277.2M1
LPC1 = HL5507F: tolerance: 21.60964.207
LVDS1 = 50524-0300N-001: tolerance: 020.K0005.0030
MEMCD1 = 156-5101902601: tolerance: 062.10002.0161
NGFF1 = 2199230-7: tolerance: 62.10043.K51
P1-P4 R46 R50 R53-R56 = 0R0402-PAD-1: tolerance: ZZ.00PAD.M11; signal model: 2pins
PC4 = C402H22: tolerance: 78.15224.2FLDL
PC12 PC31 PC180 = C402H22: tolerance: 78.15322.2FLDL
PC32 = C402H22: tolerance: 078.33322.02FD
PC75 = C402H22: tolerance: 78.18034.1FLDL
PC148 = C402H22: tolerance: 78.10421.L0L
PC158 = C402H22: tolerance: 78.15134.1FLDL
PC160 = C402H22: tolerance: 78.33124.2FLDL
PC163 = C402H22: tolerance: 78.18034.1FL
PC168 = C402H22: tolerance: 78.47322.2FL
PC181 = C402H22: tolerance: 78.68222.2FLDL
PC188 = C603H36: tolerance: 78.10224.2BLDL
PC260 = C402H22: tolerance: 78.47034.1FLDL
PC264 = C402H22: tolerance: 78.27224.2FLDL
PC266 = C402H22: tolerance: 78.10322.L0L
PC268 = C603H36: tolerance: 78.56224.2BLDL
PC275 = C603H36: tolerance: 78.10522.5BL
PD1 = SOD323AKH42: tolerance: 83.04148.D1H
PD3 = D1608-035030AKH28: tolerance: 83.1R003.N8F
PG1-PG23 = GAP-CLOSE-PWR-3: tolerance: ZZ.CLOSE.001
PL1 PL8 = L686647-127318H119: tolerance: 68.1R01B.10K
PL2-PL4 = L112100-2030H158: tolerance: 068.R1510.1011
PL5 = L686647-127318H119: tolerance: 68.R4710.10V
PL6 = L115100-2030H158: tolerance: 68.1R01B.10J
PL7 = L115100-2H158: tolerance: 68.R3610.10M
PL9 = L686647-127318H119: tolerance: 68.5R610.10U
PL10 PL11 = L686647-127318H119: tolerance: 68.2R21B.10J
PL13-PL15 = VARISTOR-402-H24: tolerance: 069.80001.0021
PQ1 Q52 Q59 = SOT23CBE2D4H44: tolerance: 84.T3906.A11
PQ2 PQ3 Q4 Q7 Q11 Q14 Q16 Q23 Q31 Q37 Q38 Q43 Q44 Q48 Q51 Q54 Q56 Q57 Q66 Q68-Q70 Q74 Q79 Q83 Q84 = SOT23DGS2D4H48: tolerance: 84.2N702.E31
PQ4 PQ8 Q34 Q36 Q39 Q60 Q65 Q72 = SOT-363H44: tolerance: 84.2N702.A3F
PQ5 Q9 = SOT-363H44: tolerance: 75.27002.F7C
PQ6 = SOT323CBE2D2H40: tolerance: 84.05212.B11
PQ7 = SOT323EBC2D2H40: tolerance: 084.05112.001K
PQ9 PQ11 = SOT-363H44: tolerance: 84.00512.03F
PQ10 Q2 Q28 Q29 Q40 Q63 Q67 Q82 = SOT23DGS2D4H44: tolerance: 84.2N702.J31
PR1 PR28 PR29 PR37 PR75 = NTC-402H22-U: tolerance: 69.60011.221
PR2 = NTC-402H22-U: tolerance: 69.60011.081
PR4 PR38 PR43 PR87 PR167 PR179 R752 = R603H22: tolerance: 64.2R205.55L
PR5 PR8 PR20 PR23 PR158 PR165 R253 R258 R483 R518 R545 R546 R596 R597 R600 R605 R676 R679 R684 R845 R872 R873 = R402H16: tolerance: 64.10015.6DL
PR7 = R402H16: tolerance: 64.24315.6DL
PR9 = R402H16: tolerance: 64.14025.6DL
PR10 = R402H16: tolerance: 64.29425.6DL
PR11 = R402H16: tolerance: 64.32425.6DL
PR12 PR53 = R402H16: tolerance: 64.12425.6DL
PR13 PR119 = R402H16: tolerance: 64.84525.6DL
PR14 PR181 = R402H16: tolerance: 64.51025.6DL
PR15 PR197 = R402H16: tolerance: 64.12415.6DL
PR16 R318 R336 R809 = R402H16: tolerance: 64.49915.6DL
PR17 PR18 PR228 R315 R865 = R402H16: tolerance: 64.20015.6DL
PR19 = R402H16: tolerance: 64.26115.6DL
PR21 PR178 = R603H22: tolerance: 64.75015.55L
PR22 PR182 PR215 PR217 R40 R69 R75 R87 R259 R565 R566 R580 R591 R607 R830 = R402H14: tolerance: 64.10005.6DL
PR24 PR174 = R402H16: tolerance: 64.13725.6DL
PR25 = R402H16: tolerance: 64.45R35.6DL
PR26 PR30 PR31 PR42 PR47 PR57 PR80 PR91 PR243 PR244 R16 R21 R26 R27 R36 R37 R39 R45 R47-R49 R51 R52 R64 R130 R177 R202 R208 R209 R214 R245 R247 R264 R268 R291 R292 R314 R328 R350 R360 R365 R370 R374 R378 R390 R394 R402 R404 R428 R439 R442 R443 R502 R504 R536 R550 R551 R561 R589 R640-R642 R647 R649 R650 R668 R672 R695 R696 R723 R725 R731 R743 R773 R776 R780 R781 R783 R789 R790 R801 R848 R856 R858 R859 R871 R884 R885 R889 R891 = R402H16: tolerance: 63.R0034.1DL
PR27 PR70-PR72 PR112 PR114 PR120 PR121 PR124 PR136 PR144 PR150 PR177 PR202 PR203 PR208 PR216 PR225 PR268 PR270 PR273 = R805H24: tolerance: 63.2R231.16L
PR39 PR55 PR74 PR115 PR118 PR137 PR159 PR190 PR207 PR241 PR251 PR254 R129 R131 R262 R263 R266 R267 R270 R271 R274-R276 R283-R285 R308 R309 R322 R334 R345 R376 R408 R487 R655 R685 R722 R732 R734 R762 R772 R777 R829 R836 R839 R874 = R402H16: tolerance: 64.10025.6DL
PR40 = R402H16: tolerance: 64.23725.6DL
PR41 = R402H16: tolerance: 64.47035.6DL
PR44 PR45 PR54 PR63 PR65 PR66 PR69 PR84 PR126 PR221 PR222 PR227 PR235 PR267 PR271 R6 R24 R29 R38 R42 R71 R77 R78 R85 R90 R91 R95 R97 R104 R106 R108 R109 R116 R118 R120 R121 R147 R152 R157-R159 R165-R167 R171 R172 R187-R192 R206 R216 R223 R226 R229 R235 R240-R242 R246 R252 R255 R297 R312 R316 R321 R324-R326 R330-R332 R341 R342 R379 R393 R398 R400 R434 R441 R466 R480 R488-R491 R501 R506 R510-R513 R515 R517 R522 R524 R534 R539-R541 R579 R588 R595 R628 R635 R645 R670 R673-R675 R681 R693 R706 R708-R710 R716 R718 R729 R735 R736 R740 R759 R761 R763 R764 R767 R788 R799 R805 R816 R826 R828 R833 R841 R851 R862 R869 R870 R876 R877 R879 R886 R888 R890 = R402H16: tolerance: 63.10334.1DL
PR46 PR48 PR82 PR184 PR213 PR218 PR233 R30 R34 R60 R88 R89 R217 R305 R401 R412 R427 R429 R456 R594 R683 R705 R707 R724 = 0R0402-PAD-1: tolerance: ZZ.00PAD.M11
PR58 PR108 PR231 R2 R3 R9 R20 R58 R65 R72-R74 R76 R81 R94 R98 R102 R107 R135 R160 R173 R185 R195 R199 R200 R213 R224 R225 R228 R261 R279 R281 R337 R344 R363 R364 R426 R449 R479 R495 R527 R530 R613 R618 R620 R633 R634 R654 R656 R726 R737 R768 R770 R782 R784 R800 R813 R819 R827 R842 R868 = R402H16: tolerance: 63.10234.1DL
PR59 = R402H16: tolerance: 64.31625.6DL
PR60 PR73 PR168 PR209 PR211 PR242 PR263 R296 R485 R733 R741 R846 = R402H16: tolerance: 64.10035.6DL
PR61 PR154 PR155 PR183 PR250 R294 R340 R484 = R402H14: tolerance: 64.10R05.6DL
PR62 PR131 PR141 PR146 PR149 PR223 PR240 = 0R0402-PAD: tolerance: ZZ.R0402.001
PR68 = R603H22: tolerance: 64.59015.55L
PR76 PR78 PR79 PR81 PR83 PR85 PR93 PR170 PR186 PR188 PR210 PR212 PR229 PR236-PR238 PR256 R4 R10-R12 R14 R15 R18 R22 R23 R28 R31 R43 R62 R63 R66 R80 R96 R101 R115 R125 R136 R138-R142 R144 R146 R148-R150 R153 R161 R163 R169 R170 R175 R178-R181 R184 R193 R201 R203-R205 R207 R210 R215 R220 R251 R256 R257 R265 R317 R339 R347 R348 R359 R361 R362 R367 R380 R388 R389 R397 R399 R410 R417 R418 R421 R422 R436 R440 R444-R446 R452 R475 R476 R482 R486 R498 R499 R505 R531 R571 R574 R575 R586 R592 R603 R617 R619 R627 R631 R632 R636-R639 R643 R646 R648 R652 R653 R682 R689 R713-R715 R720 R721 R730 R749-R751 R754 R756 R758 R760 R771 R775 R778 R779 R814 R815 R840 R857 R861 R863 R875 R881 = 0R0402-PAD: tolerance: ZZ.R0402.ZZZ
PR77 = R402H16: tolerance: 64.69815.6DL
PR86 = 0R0603-PAD-U: tolerance: ZZ.R0603.001
PR88 PR98 = R3720H40: tolerance: 64.R0105.7FL
PR89 PR100-PR103 PR107 PR132 PR248 R17 R25 R83 R288-R290 R354 R356 R358 R387 R405 R425 R432 R447 R451 R455 R457 R458 R468 R493 R500 R651 R692 R697 R699-R703 R727 R739 R744 R791 R812 R835 R883 = R402H16: tolerance: 63.10434.1DL
PR90 R128 R423 R424 R433 R629 = R402H16: tolerance: 63.10534.1DL
PR92 = R402H16: tolerance: 64.10735.6DL
PR94 = R402H16: tolerance: 64.56225.6DL
PR95 PR232 PR266 PR272 = R402H16: tolerance: 64.33025.6DL
PR96 PR219 R282 R306 = R402H16: tolerance: 64.47025.6DL
PR97 = R402H16: tolerance: 64.11035.6DL
PR99 R162 R164 R269 = R402H16: tolerance: 64.49925.6DL
PR104 = R402H16: tolerance: 64.30935.6DL
PR105 PR106 = R402H16: tolerance: 63.33234.1DL
PR109 PR110 PR257-PR260 R343 R823 = R805H24: tolerance: 63.R0031.16L
PR111 = R1206H28: tolerance: 63.33232.11L
PR113 PR214 = R402H16: tolerance: 64.82025.6DL
PR116 = R402H16: tolerance: 64.66515.6DL
PR117 = R402H16: tolerance: 64.15425.6DL
PR125 = R402H16: tolerance: 64.14335.6DL
PR127 = R603H22: tolerance: 64.5R105.55L
PR133 = R402H16: tolerance: 64.75035.6DL
PR135 = R402H16: tolerance: 64.21525.6DL
PR145 = R603H22: tolerance: 64.11035.55L
PR147 = R402H16: tolerance: 64.56035.6DL
PR148 = R402H16: tolerance: 64.22035.6DL
PR151 = R603H22: tolerance: 64.11535.55L
PR152 PR180 = R402H16: tolerance: 64.90905.6DL
PR153 PR156 = R402H16: tolerance: 64.35715.6DL
PR157 PR189 = R402H16: tolerance: 64.12725.6DL
PR160 R792-R797 R806 R808 R810 R820 = R402H16: tolerance: 64.47015.6DL
PR161 PR172 PR224 PR234 R313 R448 R578 R590 = R402H16: tolerance: 64.20025.6DL
PR162 = R402H16: tolerance: 64.15825.6DL
PR164 = R402H16: tolerance: 64.14725.6DL
PR166 PR185 R547 R548 R553 R587 R593 = R402H16: tolerance: 64.49R95.6DL
PR171 = R402H16: tolerance: 64.30925.6DL
PR173 = R603H24: tolerance: 64.2R205.L0L
PR187 = R402H16: tolerance: 64.11835.6DL
PR204 = R402H16: tolerance: 64.53625.6DL
PR206 = R402H16: tolerance: 64.51R05.6DL
PR220 = R402H16: tolerance: 64.35725.6DL
PR226 = R402H16: tolerance: 64.18025.6DL
PR230 R738 R746 R755 = R402H16: tolerance: 63.47334.1DL
PR239 = R402H16: tolerance: 63.47434.1DL
PR245 = R402H16: tolerance: 64.68035.6DL
PR246 = R805H24: tolerance: 64.20R05.16L
PR247 = R402H16: tolerance: 64.1R505.6DL
PR249 = R402H16: tolerance: 64.12035.6DL
PR252 = R402H16: tolerance: 63.33534.1DL
PR253 = R402H16: tolerance: 64.7R505.6DL
PR255 = R402H16: tolerance: 64.10235.6DL
PT1 PT2 PT5 PT9 PT13 PT17-PT19 = SE361414H241: tolerance: 79.47612.3GL
PT3 PT4 = CT7343H83: tolerance: 077.53371.0001
PT6-PT8 PT10 PT11 = ECAP-100D6D3H375: tolerance: 09.56710.A8L
PT12 PT14-PT16 = ECAP-100D6D3H375: tolerance: 09.8271V.08L
PT20 PT21 = SE3116H241: tolerance: 79.22710.30L
PU1 PU4 PU6 PU13 PU18 PU26 PU29 PU31 = PPAK-8P-5262H40: tolerance: 84.06520.037
PU2 PU3 PU5 PU12 PU19 PU22 PU23 PU25 PU27 PU30 = PPAK-8P-5262H40: tolerance: 084.06510.0037
PU7 PU35 PU36 = PPAK-8P-3232H36: tolerance: 84.07410.A37
PU8 = LFDFN8G2-G1309H40: tolerance: 074.81253.0AE3
PU9 PU37 PU38 = PPAK-8P-3232H36: tolerance: 84.07506.037
PU10 PU21 = SOIC8-G3530H63: tolerance: 74.05930.B3D
PU11 = SOIC8-G3530H63: tolerance: 74.05912.03D
PU14 = QFN23G4-G2P-1H42: tolerance: 074.08713.0043
PU15 PU16 U19 = SOIC8H69: tolerance: 84.04407.G37
PU17 = QFN20-G1D75H32: tolerance: 074.06575.0A43
PU20 = QFN20-G1D75H32: tolerance: 074.08231.0073
PU24 = LFQFN52J6-G4D8-1H40: tolerance: 074.81206.0B73
PU28 = DFN10G3-G265175H32: tolerance: 74.08237.B73
PU32 PU33 = PPAK-8P-2H45: tolerance: 84.00412.037
PU34 = QFN20G3D5-G2D15H40: tolerance: 74.24727.A73
PWRCN1 = 51530-01041-W01: tolerance: 20.K0642.010
Q1 Q3 Q5 Q8 Q10 Q12 Q13 Q33 Q45 Q58 Q71 Q78 U2 = SOT-363H44: tolerance: 84.M3904.B1F
Q6 Q22 Q30 Q46 Q47 Q49 Q73 Q76 Q77 Q80 = SOT23CBE2D4H44: tolerance: 84.T3904.C11
Q17 Q18 = SOT23DGS2D4H48: tolerance: 84.05067.031
Q21 Q53 = SOT-363H44: tolerance: 75.27002.D7C
Q24 = SOT23CBE2D4H44: tolerance: 84.T3904.H11
Q25 = SOT23DGS2D4H44: tolerance: 84.27002.W31
Q26 Q27 Q42 = SOT23-2D4-312H46: tolerance: 75.05125.07D
Q32 Q61 = SOT23DGS2D8H50: tolerance: 84.03418.A31
Q35 Q50 Q55 Q81 = SOT23DGS2D8H50: tolerance: 84.03413.B31
Q41 = SOT23DGS2D4H48: tolerance: 84.02130.031
Q62 = SOT23CBE2D4H44: tolerance: 84.T3906.E11
Q75 = SOIC8H69: tolerance: 084.04286.0037
R1 R13 R99 R100 R103 R105 R110 R111 R113 R114 R554 = R402H16: tolerance: 63.51034.1DL
R5 R453 R532 R803 = R402H16: tolerance: 63.15234.1DL
R7 R8 R32 R35 R182 R419 R420 R604 R608 R611 R616 R621 R624 = 0R0402-PAD: tolerance: ZZ.R0402.ZZZ; signal model: 2pins
R19 = R402H16: tolerance: 63.15134.1DL
R33 R280 R286 R287 R323 R333 R338 R467 R471-R473 = R402H16: tolerance: 63.22234.1DL
R41 R44 R320 = R402H16: tolerance: 63.R0034.1DL; signal model: 2pins
R57 R254 R329 R381 R470 R492 R503 R509 R585 R712 R765 R766 R798 R832 R834 R838 R847 R860 = R402H16: tolerance: 63.47234.1DL
R59 R626 = R402H16: tolerance: 64.82015.6DL
R61 R644 R717 R774 R786 R787 = R402H16: tolerance: 63.20334.1DL
R70 R680 R690 R691 = R402H16: tolerance: 64.60R45.6DL
R79 R84 R230 R304 R614 R625 R630 = R603H22: tolerance: 63.00000.00L
R82 = R402H16: tolerance: 64.49905.6DL
R86 = R402H16: tolerance: 64.54R95.6DL
R92 R413 = R402H16: tolerance: 63.56034.1DL
R93 = R402H16: tolerance: 63.22134.1DL
R112 R119 R250 = NTC-603H38: tolerance: 69.60035.041
R117 = R1206H28: tolerance: 63.10032.11L
R122 = R402H16: tolerance: 63.15434.1DL
R123 R124 = R402H16: tolerance: 63.33034.1DL; signal model: 2pins
R126 R127 R134 R311 R319 R327 R335 R474 R477 R802 R831 R837 = R402H16: tolerance: 63.33034.1DL
R132 = R402H16: tolerance: 64.18015.6DL
R133 R407 = R402H16: tolerance: 64.56015.6DL
R137 R273 R277 R278 R307 R366 R369 R373 R375 R377 R391 R392 R395 R396 R528 R529 R563 R581-R584 R615 R622 R667 R748 = 0R0603-PAD-1-U: tolerance: ZZ.00PAD.M21
R151 = R402H16: tolerance: 63.30234.1DL
R168 R244 R610 = R402H16: tolerance: 64.20005.6DL
R174 R186 R414-R416 R623 = R402H16: tolerance: 63.22034.1DL
R176 R196 R197 = R402H16: tolerance: 63.15034.1DL
R183 R194 = R402H16: tolerance: 63.15034.1DL; signal model: 2pins
R198 R430 = R402H16: tolerance: 63.10634.1DL
R231 R368 R516 R526 R817 = R402H16: tolerance: 64.15025.6DL
R233 R248 R353 R520 R525 R537 = R402H16: tolerance: 63.82234.1DL
R237 R238 R465 R664 R666 = R603H22: tolerance: 63.10333.15L
R243 R519 = R402H16: tolerance: 64.24915.6DL
R249 R298 R658 R698 = R402H16: tolerance: 64.93105.6DL
R260 = R402H16: tolerance: 64.40225.6DL
R293 R521 = R603H22: tolerance: 64.10045.55L
R295 R657 R671 R688 = R402H16: tolerance: 64.54905.6DL
R299 R659 R669 R694 = R402H16: tolerance: 64.13315.6DL
R300 R301 R577 R662 R663 = R402H16: tolerance: 64.12105.6DL
R302 R303 R660 R661 = R402H16: tolerance: 64.40R25.6DL
R310 R371 R372 R382 R383 = R402H16: tolerance: 64.24925.6DL
R346 = R402H16: tolerance: 64.51015.6DL
R349 = R402H16: tolerance: 64.68R05.6DL
R355 = R402H16: tolerance: 64.18725.6DL
R357 R523 R538 = R402H16: tolerance: 64.39225.6DL
R385 R386 = R603H22: tolerance: 64.10525.55L
R403 = R402H16: tolerance: 64.12025.6DL
R406 = R402H16: tolerance: 64.39015.6DL
R409 R411 R463 R464 R508 R849 = R402H16: tolerance: 63.47034.1DL
R431 = R603H22: tolerance: 63.10033.15L
R438 = R402H16: tolerance: 63.43034.1DL
R450 R742 = R402H16: tolerance: 63.33434.1DL
R454 R844 = 0R1206-PAD-1: tolerance: ZZ.R1206.ZZ1
R459-R462 = R603H22: tolerance: 64.3R305.55L
R469 = R603H22: tolerance: 63.24434.15L
R478 = R603H22: tolerance: 63.47333.15L
R481 R496 = R402H16: tolerance: 64.30035.6DL
R494 R507 R549 R552 R555 R556 R567 R568 R572 R573 = R402H14: tolerance: 63.10134.1DL
R514 R852-R855 = R603H22: tolerance: 64.75R05.55L
R543 R562 R598 R606 = R402H16: tolerance: 64.24R95.6DL
R544 R599 R601 = R402H16: tolerance: 63.2R034.1DL
R557-R560 R569 R570 = R402H16: tolerance: 64.24005.6DL
R564 = R402H16: tolerance: 64.27015.6DL
R576 = R402H16: tolerance: 64.80R65.6DL
R602 = R402H16: tolerance: 64.47005.6DL
R609 = R402H16: tolerance: 64.11305.6DL
R612 = R402H16: tolerance: 64.62015.6DL
R686 R687 = R402H16: tolerance: 64.40R25.6D1
R704 = R402H16: tolerance: 63.33334.1DL
R719 = R402H16: tolerance: 64.43225.6DL
R769 = R402H16: tolerance: 63.20434.1DL
R785 = R402H16: tolerance: 64.16035.6DL
R804 = R805H24: tolerance: 63.1R031.16L
R807 R811 = R1206H26: tolerance: 64.R3305.41L
R818 = R603H22: tolerance: 64.36R05.55L
R822 = R603H22: tolerance: 64.18005.55L
R824 = R805H24: tolerance: 63.20131.16L
R843 R850 = R805H24: tolerance: 64.10025.16L
R882 = R603H22: tolerance: 63.33133.15L
R892-R895 = R402H16: tolerance: 64.33005.6DL
RJ1 = 23-01120-2A03-A: tolerance: 062.10032.0041
RN1-RN3 RN5 RN9-RN11 RN13 RN15-RN18 RN20 RN21 = ARES2H18: tolerance: 66.10336.04L
RN4 = ARES8-CN24-UH20: tolerance: 66.22236.A8L
RN6 = ARES2H16: tolerance: 66.22236.04L
RN7 RN8 = SMD-ARES4H18: tolerance: 66.33036.04L
RN14 = ARES8-CN24-UH20: tolerance: 66.33036.A8L
RN19 = SMD-ARES4H18: tolerance: 66.47236.04L
RV1 = TVS5436-1121H105: tolerance: 069.A0007.0001
SATAP1 = CI2505P1H00-LF-U: tolerance: 021.60197.0105
SCA1 = LQFP128H63: tolerance: 071.02506.000G
SPK1 = A1501WV0-6PS-5E: tolerance: 21.D0278.106
SRCON1 = G6179HT0321-001: tolerance: 62.10089.011
SSUSB1 SSUSB2 = SKT-USB11-138165-1: tolerance: 022.10005.0391
TC1 = CT7343H75: tolerance: 77.23371.13L
TC2 = CT3528H79: tolerance: 77.21071.07L
TC3 TC4 = ECAP-100D6D3H237: tolerance: 09.1071D.F5L
TOUCH1 = 3703K-Q05N-11L: tolerance: 020.F0146.0005
TP1-TP45 TP49-TP52 TP82 = TPAD30: tolerance: ZZ.PAD30.XXX
TR1 TR13 = L125100-4P-1H37: tolerance: 68.01012.201; signal model: 4pins1
TR2 TR3 TR7 TR8 = L125100-4P-4H28: tolerance: 068.01012.2011; signal model: 4pins1
TR4 = L125100-4P-4H28: tolerance: 068.01012.2011
TR5 TR6 TR9 TR10 = L125100-4P-1H28: tolerance: 68.10129.201; signal model: 4pins1
TR11 TR12 TR14 TR15 = L125100-4P-4H24: tolerance: 68.00396.011; signal model: 4pins1
U1 = SC70-5H44: tolerance: 73.01G07.0HG
U3 U4 = DFN8F3-G2517H32: tolerance: 074.01334.0093
U5 U25 = SOT-23-5H58: tolerance: 074.00524.0B9F
U6 U9 U15 = DFN10G2510H26: tolerance: 75.01045.073
U7 = SC70-5H44: tolerance: 73.7SZ08.DAH
U8 = SOIC8-1H86: tolerance: 72.25128.0E1
U10 = SOIC8H69: tolerance: 72.25106.001
U11 = QFN48J6-G465H40: tolerance: 71.03661.003
U12 = MSOP8-1H44: tolerance: 74.07718.0B9
U13 = MSOP10H44: tolerance: 73.52364.009
U14 = QFN32-G3D55H40: tolerance: 74.03131.013
U16 U18 = DFN10G2510H26: tolerance: 75.01045.073; signal model: 10pins2
U17 = QFN40J5-G3D65H32: tolerance: 071.08407.0003
U20 U24 U39 = SOT-6H58: tolerance: 75.01215.07C
U21 U37 = SOT-23-9H44: tolerance: 75.23C62.07D
U22 = SOIC8H69: tolerance: 72.24C02.0C1
U23 = QFN32J4-G2D85H36: tolerance: 71.08111.U03
U26 = SON14J3020-G2610H32: tolerance: 074.22966.0093
U27 = SC70-5H44: tolerance: 73.01G08.DHH
U28 = QFN32J4-G2D85H36: tolerance: 071.05250.0A03
U30 = LFQFN24G4-G2D9H40: tolerance: 74.81172.073
U31 = SOIC8-G371264H65: tolerance: 074.09661.003D
U32 = SC70-5H44: tolerance: 73.7SZ08.EAH
U33 = SOIC8-1H86: tolerance: 072.25Q80.0A01
U34 = QFN32G5-G3D6H32: tolerance: 071.00650.0B03
U35 = SOT-89-4541-3PH63: tolerance: 074.01117.0038
U36 = QFN20-G2D1H32: tolerance: 074.00554.0073
U38 = MSOP8-1H44: tolerance: 074.06288.0079
U40 = SOT-6-1H58: tolerance: 74.03521.07P
UHS1 = 2SJ3082-038111F: tolerance: 022.10002.0881
USB3 USB4 = SKT-USB6-135063: tolerance: 022.10005.01E1
VRAM1-VRAM4 = BGA170D1214H48: tolerance: 072.05424.0A0U
WEBCM1 = A1251WR0-8PS-5E: tolerance: 20.F1245.008
X1 = OSC-3225-4P-4H36: tolerance: 082.30006.0021
X2 = SMD49-6914-0403H56: tolerance: 82.30001.G11
X3 = OSC-3225-4P-4H30: tolerance: 82.30034.641
X4 = OSC-3225-4P-3H36: tolerance: 82.30005.E21
X5 = OSC-3225-4P-4H36: tolerance: 82.30020.G71
XDP1 = PAD-60P: tolerance: ZZ.00PAD.Q81
XF1 XF2 = XFORM12A127097H91: tolerance: 68.68167.30D

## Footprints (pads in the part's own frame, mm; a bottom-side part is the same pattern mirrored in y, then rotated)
0R0402-PAD
  custom 0.14x0.14 smd: 1(0,0.445) 2(0,-0.445)
0R0402-PAD-1
  custom 0.14x0.14 smd: 1(0,0.445) 2(0,-0.445)
0R0603-PAD-1-U
  custom 0.216x0.216 smd: 1(0,0.762) 2(0,-0.762)
0R0603-PAD-U
  custom 0.216x0.216 smd: 1(0,0.762) 2(0,-0.762)
0R0805-PAD
  rect 1.397x1.562 smd: 1(0,0.965)
  rect 1.397x1.569 smd: 2(0,-0.965)
0R1206-PAD-1
  rect 1.651x2.057 smd: 1(0,1.397) 2(0,-1.397)
2SJ3082-038111F
  round 0.254 hole 1.27 unplated: (0,0) (0,-6)
  oval 1.321x2.134 hole 0.61x1.422: 1(3.8,3.1) 2(-3.7,-4.5) 3(3.7,-6.8) 4(-2.7,-6.6) 5(-2.2,3.1) 6(-3.8,3.1) MS1(-4.6,-1.5) MS2(4.6,-2.5)
15-02070-5A61-A
  round 1.041 hole 0.762: 1(3.81,-0.25) 2(2.54,-0.25) 3(1.27,-0.25) 4(0,-0.25) 5(-1.27,-0.25) 6(-2.54,-0.25) 7(-3.81,-0.25)
  round 1.93 hole 1.524: 8(6.37,0) 9(-6.37,0)
21S-92-03GB16
  round 1.422 hole 1.016: 1(-2.54,-1.27) 2(-2.54,1.27) 3(0,-1.27) 4(0,1.27) 5(2.54,-1.27) 6(2.54,1.27)
23-01120-2A03-A
  rect 0.813x3.988 smd: 1(-4.445,13.3) 2(-3.175,13.3) 3(-1.905,13.3) 4(-0.635,13.3) 5(0.635,13.3) 6(1.905,13.3) 7(3.175,13.3) 8(4.445,13.3)
  round 1.321 hole 0.914: 9(-6.645,0) 10(-4.355,0) 11(4.355,0) 12(6.645,0)
  rect 8.992x3.404 smd: 13(0,-3.5)
40-42271-26001RHF
  round 0.254 hole 1.6 unplated: (-34.4,0)
  round 0.254 hole 1.118 unplated: (34.4,0)
  rect 0.305x1.753 smd: 1(-33.375,-4.1) 2(-33.125,4.1) 3(-32.875,-4.1) 4(-32.625,4.1) 5(-32.375,-4.1) 6(-32.125,4.1) 7(-31.875,-4.1) 8(-31.625,4.1) 9(-31.375,-4.1) 10(-31.125,4.1) 11(-30.875,-4.1) 12(-30.625,4.1) 13(-30.375,-4.1) 14(-30.125,4.1) 15(-29.875,-4.1) 16(-29.625,4.1) 17(-29.375,-4.1) 18(-29.125,4.1) 19(-28.875,-4.1) 20(-28.625,4.1) 21(-28.375,-4.1) 22(-28.125,4.1) 23(-27.875,-4.1) 24(-27.625,4.1) 25(-27.375,-4.1) 26(-27.125,4.1) 27(-26.875,-4.1) 28(-26.625,4.1) 29(-26.375,-4.1) 30(-26.125,4.1) 31(-25.875,-4.1) 32(-25.625,4.1) 33(-25.375,-4.1) 34(-25.125,4.1) 35(-24.875,-4.1) 36(-24.625,4.1) 37(-24.375,-4.1) 38(-24.125,4.1) 39(-23.875,-4.1) 40(-23.625,4.1) 41(-23.375,-4.1) 42(-23.125,4.1) 43(-22.875,-4.1) 44(-22.625,4.1) 45(-22.375,-4.1) 46(-22.125,4.1) 47(-21.875,-4.1) 48(-21.625,4.1) 49(-21.375,-4.1) 50(-21.125,4.1) 51(-20.875,-4.1) 52(-20.625,4.1) 53(-20.375,-4.1) 54(-20.125,4.1) 55(-19.875,-4.1) 56(-19.625,4.1) 57(-19.375,-4.1) 58(-19.125,4.1) 59(-18.875,-4.1) 60(-18.625,4.1) 61(-18.375,-4.1) 62(-18.125,4.1) 63(-17.875,-4.1) 64(-17.625,4.1) 65(-17.375,-4.1) 66(-17.125,4.1) 67(-16.875,-4.1) 68(-16.625,4.1) 69(-16.375,-4.1) 70(-16.125,4.1) 71(-15.875,-4.1) 72(-15.625,4.1) 73(-15.375,-4.1) 74(-15.125,4.1) 75(-14.875,-4.1) 76(-14.625,4.1) 77(-14.375,-4.1) 78(-14.125,4.1) 79(-13.875,-4.1) 80(-13.625,4.1) 81(-13.375,-4.1) 82(-13.125,4.1) 83(-12.875,-4.1) 84(-12.625,4.1) 85(-12.375,-4.1) 86(-12.125,4.1) 87(-11.875,-4.1) 88(-11.625,4.1) 89(-11.375,-4.1) 90(-11.125,4.1) 91(-10.875,-4.1) 92(-10.625,4.1) 93(-10.375,-4.1) 94(-10.125,4.1) 95(-9.875,-4.1) 96(-9.625,4.1) 97(-9.375,-4.1) 98(-9.125,4.1) 99(-8.875,-4.1) 100(-8.625,4.1) 101(-8.375,-4.1) 102(-8.125,4.1) 103(-7.875,-4.1) 104(-7.625,4.1) 105(-7.375,-4.1) 106(-7.125,4.1) 107(-6.875,-4.1) 108(-6.625,4.1) 109(-6.375,-4.1) 110(-6.125,4.1) 111(-5.875,-4.1) 112(-5.625,4.1) 113(-5.375,-4.1) 114(-5.125,4.1) 115(-4.875,-4.1) 116(-4.625,4.1) 117(-4.375,-4.1) 118(-4.125,4.1) 119(-3.875,-4.1) 120(-3.625,4.1) 121(-3.375,-4.1) 122(-3.125,4.1) 123(-2.875,-4.1) 124(-2.625,4.1) 125(-2.375,-4.1) 126(-2.125,4.1) 127(-1.875,-4.1) 128(-1.625,4.1) 129(-1.375,-4.1) 130(-1.125,4.1) 131(-0.875,-4.1) 132(-0.625,4.1) 133(-0.375,-4.1) 134(-0.125,4.1) 135(0.125,-4.1) 136(0.375,4.1) 137(0.625,-4.1) 138(0.875,4.1) 139(1.125,-4.1) 140(1.375,4.1) 141(1.625,-4.1) 142(1.875,4.1) 143(2.125,-4.1) 144(2.375,4.1) 145(4.625,-4.1) 146(4.875,4.1) 147(5.125,-4.1) 148(5.375,4.1) 149(5.625,-4.1) 150(5.875,4.1) 151(6.125,-4.1) 152(6.375,4.1) 153(6.625,-4.1) 154(6.875,4.1) 155(7.125,-4.1) 156(7.375,4.1) 157(7.625,-4.1) 158(7.875,4.1) 159(8.125,-4.1) 160(8.375,4.1) 161(8.625,-4.1) 162(8.875,4.1) 163(9.125,-4.1) 164(9.375,4.1) 165(9.625,-4.1) 166(9.875,4.1) 167(10.125,-4.1) 168(10.375,4.1) 169(10.625,-4.1) 170(10.875,4.1) 171(11.125,-4.1) 172(11.375,4.1) 173(11.625,-4.1) 174(11.875,4.1) 175(12.125,-4.1) 176(12.375,4.1) 177(12.625,-4.1) 178(12.875,4.1) 179(13.125,-4.1) 180(13.375,4.1) 181(13.625,-4.1) 182(13.875,4.1) 183(14.125,-4.1) 184(14.375,4.1) 185(14.625,-4.1) 186(14.875,4.1) 187(15.125,-4.1) 188(15.375,4.1) 189(15.625,-4.1) 190(15.875,4.1) 191(16.125,-4.1) 192(16.375,4.1) 193(16.625,-4.1) 194(16.875,4.1) 195(17.125,-4.1) 196(17.375,4.1) 197(17.625,-4.1) 198(17.875,4.1) 199(18.125,-4.1) 200(18.375,4.1) 201(18.625,-4.1) 202(18.875,4.1) 203(19.125,-4.1) 204(19.375,4.1) 205(19.625,-4.1) 206(19.875,4.1) 207(20.125,-4.1) 208(20.375,4.1) 209(20.625,-4.1) 210(20.875,4.1) 211(21.125,-4.1) 212(21.375,4.1) 213(21.625,-4.1) 214(21.875,4.1) 215(22.125,-4.1) 216(22.375,4.1) 217(22.625,-4.1) 218(22.875,4.1) 219(23.125,-4.1) 220(23.375,4.1) 221(23.625,-4.1) 222(23.875,4.1) 223(24.125,-4.1) 224(24.375,4.1) 225(24.625,-4.1) 226(24.875,4.1) 227(25.125,-4.1) 228(25.375,4.1) 229(25.625,-4.1) 230(25.875,4.1) 231(26.125,-4.1) 232(26.375,4.1) 233(26.625,-4.1) 234(26.875,4.1) 235(27.125,-4.1) 236(27.375,4.1) 237(27.625,-4.1) 238(27.875,4.1) 239(28.125,-4.1) 240(28.375,4.1) 241(28.625,-4.1) 242(28.875,4.1) 243(29.125,-4.1) 244(29.375,4.1) 245(29.625,-4.1) 246(29.875,4.1) 247(30.125,-4.1) 248(30.375,4.1) 249(30.625,-4.1) 250(30.875,4.1) 251(31.125,-4.1) 252(31.375,4.1) 253(31.625,-4.1) 254(31.875,4.1) 255(32.125,-4.1) 256(32.375,4.1) 257(32.625,-4.1) 258(32.875,4.1) 259(33.125,-4.1) 260(33.375,4.1)
  rect 3.505x4.597 smd: 261(33.8,-12) 262(-33.8,-12)
40-42275-26001RHF
  round 0.254 hole 1.6 unplated: (-34.4,0)
  round 0.254 hole 1.118 unplated: (34.4,0)
  rect 0.305x1.753 smd: 1(-33.375,-4.1) 2(-33.125,4.1) 3(-32.875,-4.1) 4(-32.625,4.1) 5(-32.375,-4.1) 6(-32.125,4.1) 7(-31.875,-4.1) 8(-31.625,4.1) 9(-31.375,-4.1) 10(-31.125,4.1) 11(-30.875,-4.1) 12(-30.625,4.1) 13(-30.375,-4.1) 14(-30.125,4.1) 15(-29.875,-4.1) 16(-29.625,4.1) 17(-29.375,-4.1) 18(-29.125,4.1) 19(-28.875,-4.1) 20(-28.625,4.1) 21(-28.375,-4.1) 22(-28.125,4.1) 23(-27.875,-4.1) 24(-27.625,4.1) 25(-27.375,-4.1) 26(-27.125,4.1) 27(-26.875,-4.1) 28(-26.625,4.1) 29(-26.375,-4.1) 30(-26.125,4.1) 31(-25.875,-4.1) 32(-25.625,4.1) 33(-25.375,-4.1) 34(-25.125,4.1) 35(-24.875,-4.1) 36(-24.625,4.1) 37(-24.375,-4.1) 38(-24.125,4.1) 39(-23.875,-4.1) 40(-23.625,4.1) 41(-23.375,-4.1) 42(-23.125,4.1) 43(-22.875,-4.1) 44(-22.625,4.1) 45(-22.375,-4.1) 46(-22.125,4.1) 47(-21.875,-4.1) 48(-21.625,4.1) 49(-21.375,-4.1) 50(-21.125,4.1) 51(-20.875,-4.1) 52(-20.625,4.1) 53(-20.375,-4.1) 54(-20.125,4.1) 55(-19.875,-4.1) 56(-19.625,4.1) 57(-19.375,-4.1) 58(-19.125,4.1) 59(-18.875,-4.1) 60(-18.625,4.1) 61(-18.375,-4.1) 62(-18.125,4.1) 63(-17.875,-4.1) 64(-17.625,4.1) 65(-17.375,-4.1) 66(-17.125,4.1) 67(-16.875,-4.1) 68(-16.625,4.1) 69(-16.375,-4.1) 70(-16.125,4.1) 71(-15.875,-4.1) 72(-15.625,4.1) 73(-15.375,-4.1) 74(-15.125,4.1) 75(-14.875,-4.1) 76(-14.625,4.1) 77(-14.375,-4.1) 78(-14.125,4.1) 79(-13.875,-4.1) 80(-13.625,4.1) 81(-13.375,-4.1) 82(-13.125,4.1) 83(-12.875,-4.1) 84(-12.625,4.1) 85(-12.375,-4.1) 86(-12.125,4.1) 87(-11.875,-4.1) 88(-11.625,4.1) 89(-11.375,-4.1) 90(-11.125,4.1) 91(-10.875,-4.1) 92(-10.625,4.1) 93(-10.375,-4.1) 94(-10.125,4.1) 95(-9.875,-4.1) 96(-9.625,4.1) 97(-9.375,-4.1) 98(-9.125,4.1) 99(-8.875,-4.1) 100(-8.625,4.1) 101(-8.375,-4.1) 102(-8.125,4.1) 103(-7.875,-4.1) 104(-7.625,4.1) 105(-7.375,-4.1) 106(-7.125,4.1) 107(-6.875,-4.1) 108(-6.625,4.1) 109(-6.375,-4.1) 110(-6.125,4.1) 111(-5.875,-4.1) 112(-5.625,4.1) 113(-5.375,-4.1) 114(-5.125,4.1) 115(-4.875,-4.1) 116(-4.625,4.1) 117(-4.375,-4.1) 118(-4.125,4.1) 119(-3.875,-4.1) 120(-3.625,4.1) 121(-3.375,-4.1) 122(-3.125,4.1) 123(-2.875,-4.1) 124(-2.625,4.1) 125(-2.375,-4.1) 126(-2.125,4.1) 127(-1.875,-4.1) 128(-1.625,4.1) 129(-1.375,-4.1) 130(-1.125,4.1) 131(-0.875,-4.1) 132(-0.625,4.1) 133(-0.375,-4.1) 134(-0.125,4.1) 135(0.125,-4.1) 136(0.375,4.1) 137(0.625,-4.1) 138(0.875,4.1) 139(1.125,-4.1) 140(1.375,4.1) 141(1.625,-4.1) 142(1.875,4.1) 143(2.125,-4.1) 144(2.375,4.1) 145(4.625,-4.1) 146(4.875,4.1) 147(5.125,-4.1) 148(5.375,4.1) 149(5.625,-4.1) 150(5.875,4.1) 151(6.125,-4.1) 152(6.375,4.1) 153(6.625,-4.1) 154(6.875,4.1) 155(7.125,-4.1) 156(7.375,4.1) 157(7.625,-4.1) 158(7.875,4.1) 159(8.125,-4.1) 160(8.375,4.1) 161(8.625,-4.1) 162(8.875,4.1) 163(9.125,-4.1) 164(9.375,4.1) 165(9.625,-4.1) 166(9.875,4.1) 167(10.125,-4.1) 168(10.375,4.1) 169(10.625,-4.1) 170(10.875,4.1) 171(11.125,-4.1) 172(11.375,4.1) 173(11.625,-4.1) 174(11.875,4.1) 175(12.125,-4.1) 176(12.375,4.1) 177(12.625,-4.1) 178(12.875,4.1) 179(13.125,-4.1) 180(13.375,4.1) 181(13.625,-4.1) 182(13.875,4.1) 183(14.125,-4.1) 184(14.375,4.1) 185(14.625,-4.1) 186(14.875,4.1) 187(15.125,-4.1) 188(15.375,4.1) 189(15.625,-4.1) 190(15.875,4.1) 191(16.125,-4.1) 192(16.375,4.1) 193(16.625,-4.1) 194(16.875,4.1) 195(17.125,-4.1) 196(17.375,4.1) 197(17.625,-4.1) 198(17.875,4.1) 199(18.125,-4.1) 200(18.375,4.1) 201(18.625,-4.1) 202(18.875,4.1) 203(19.125,-4.1) 204(19.375,4.1) 205(19.625,-4.1) 206(19.875,4.1) 207(20.125,-4.1) 208(20.375,4.1) 209(20.625,-4.1) 210(20.875,4.1) 211(21.125,-4.1) 212(21.375,4.1) 213(21.625,-4.1) 214(21.875,4.1) 215(22.125,-4.1) 216(22.375,4.1) 217(22.625,-4.1) 218(22.875,4.1) 219(23.125,-4.1) 220(23.375,4.1) 221(23.625,-4.1) 222(23.875,4.1) 223(24.125,-4.1) 224(24.375,4.1) 225(24.625,-4.1) 226(24.875,4.1) 227(25.125,-4.1) 228(25.375,4.1) 229(25.625,-4.1) 230(25.875,4.1) 231(26.125,-4.1) 232(26.375,4.1) 233(26.625,-4.1) 234(26.875,4.1) 235(27.125,-4.1) 236(27.375,4.1) 237(27.625,-4.1) 238(27.875,4.1) 239(28.125,-4.1) 240(28.375,4.1) 241(28.625,-4.1) 242(28.875,4.1) 243(29.125,-4.1) 244(29.375,4.1) 245(29.625,-4.1) 246(29.875,4.1) 247(30.125,-4.1) 248(30.375,4.1) 249(30.625,-4.1) 250(30.875,4.1) 251(31.125,-4.1) 252(31.375,4.1) 253(31.625,-4.1) 254(31.875,4.1) 255(32.125,-4.1) 256(32.375,4.1) 257(32.625,-4.1) 258(32.875,4.1) 259(33.125,-4.1) 260(33.375,4.1)
  rect 2.007x3.505 smd: 261(37.75,-12) 262(-37.75,-8)
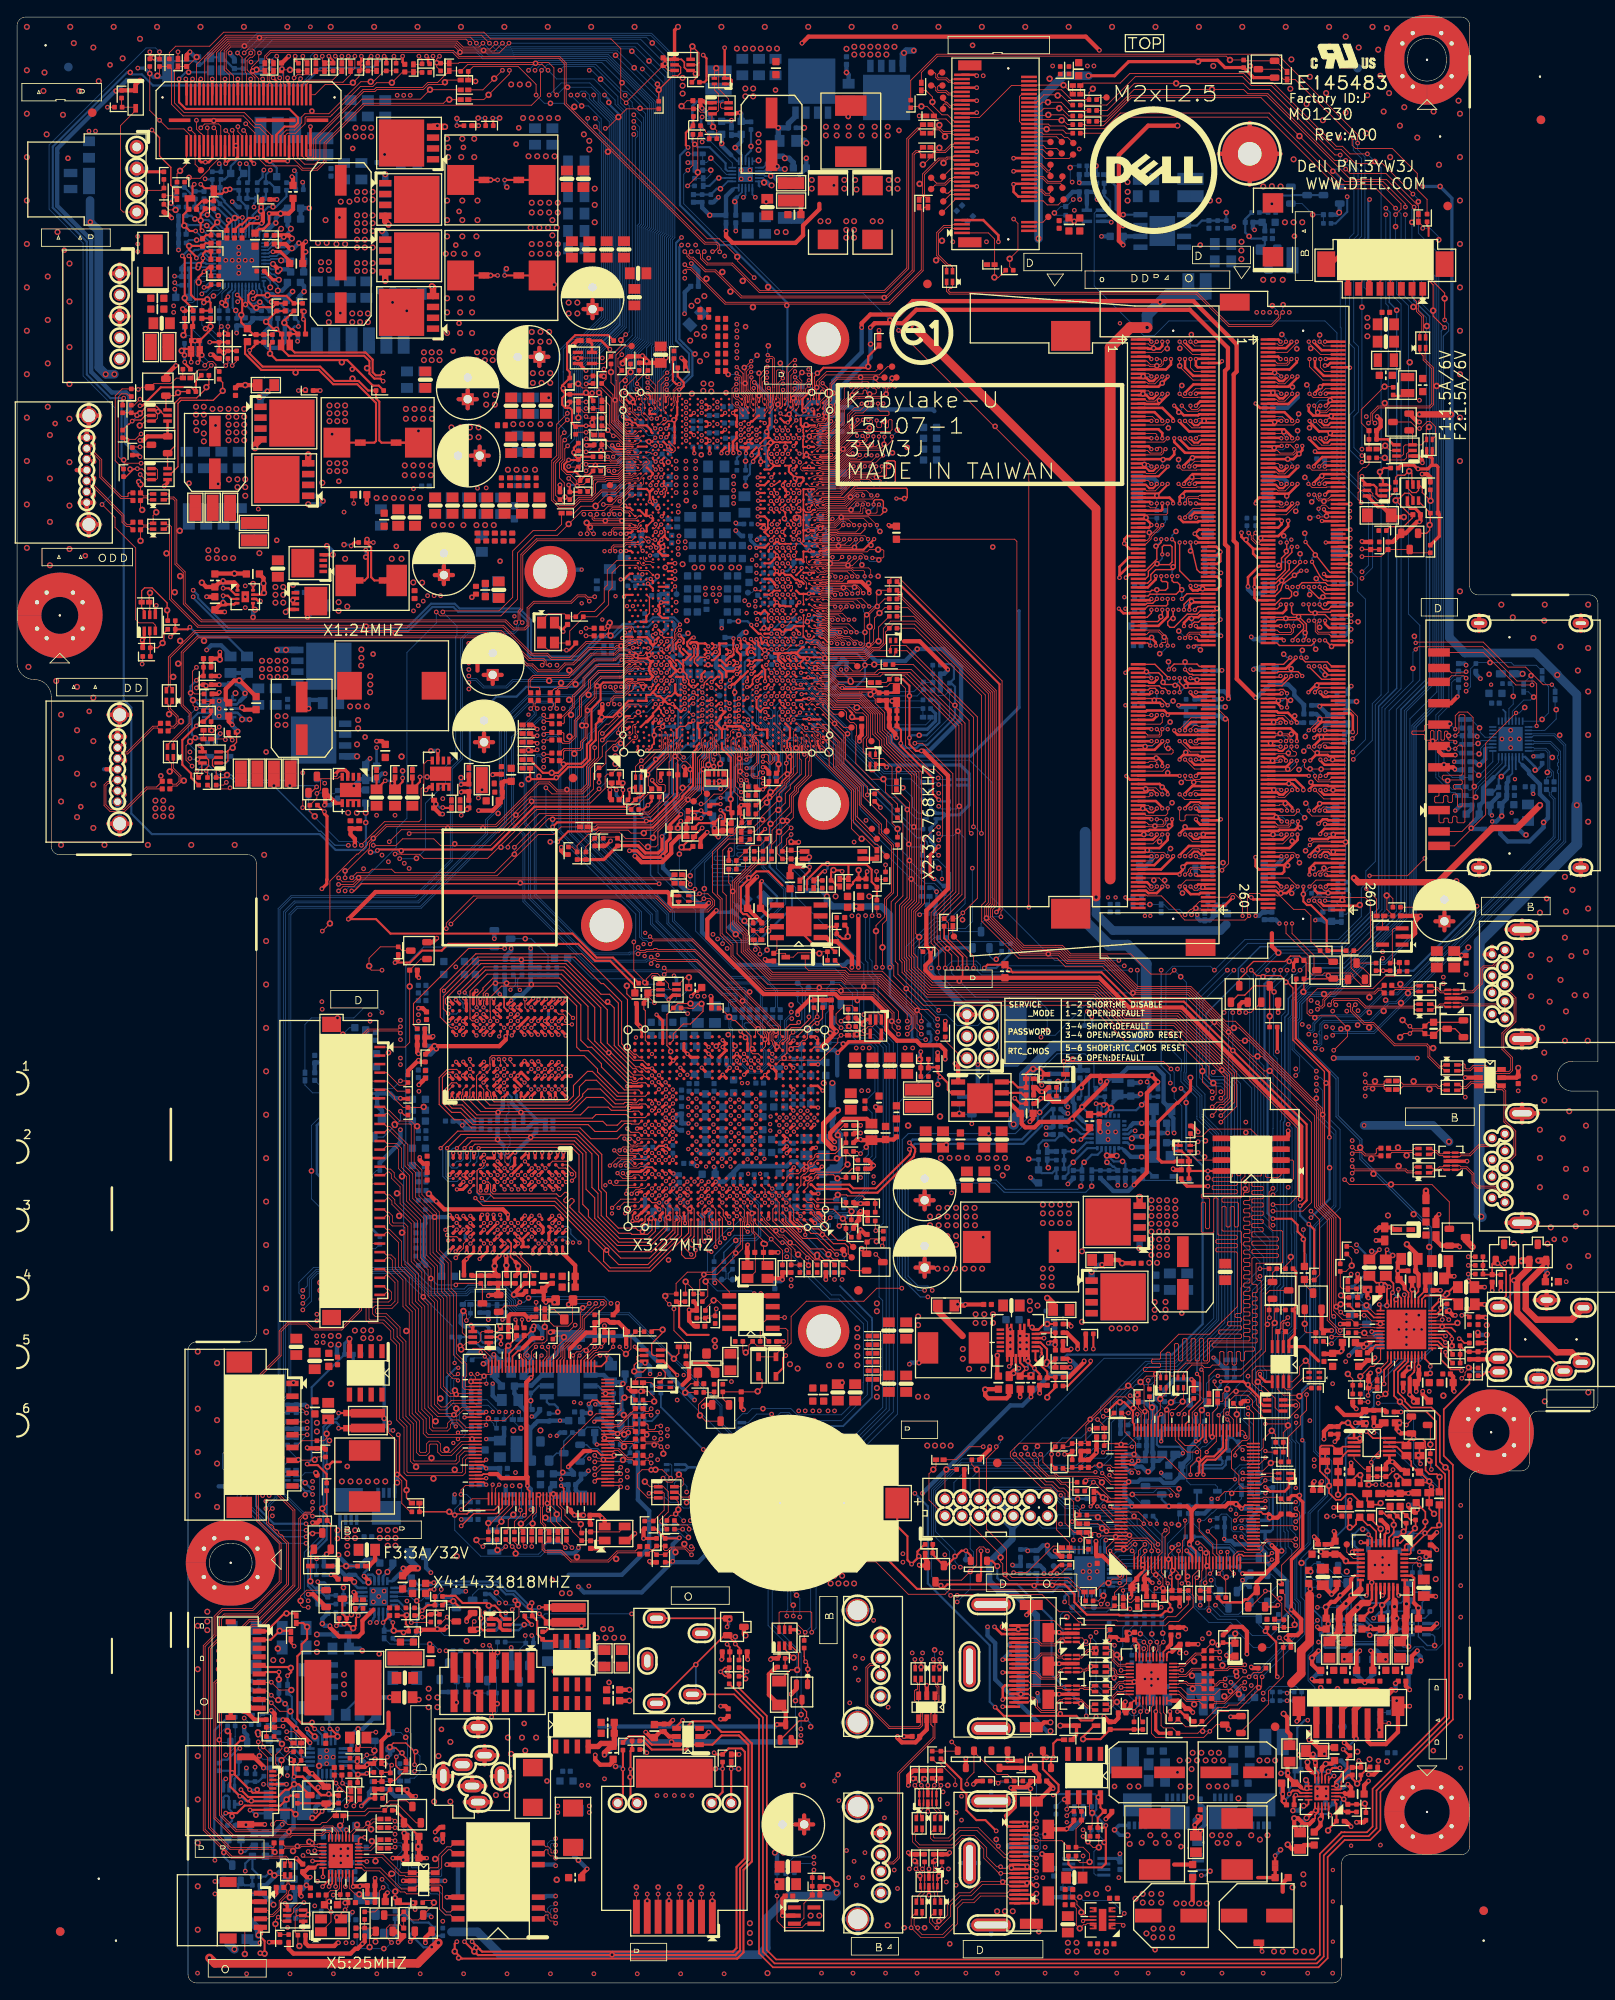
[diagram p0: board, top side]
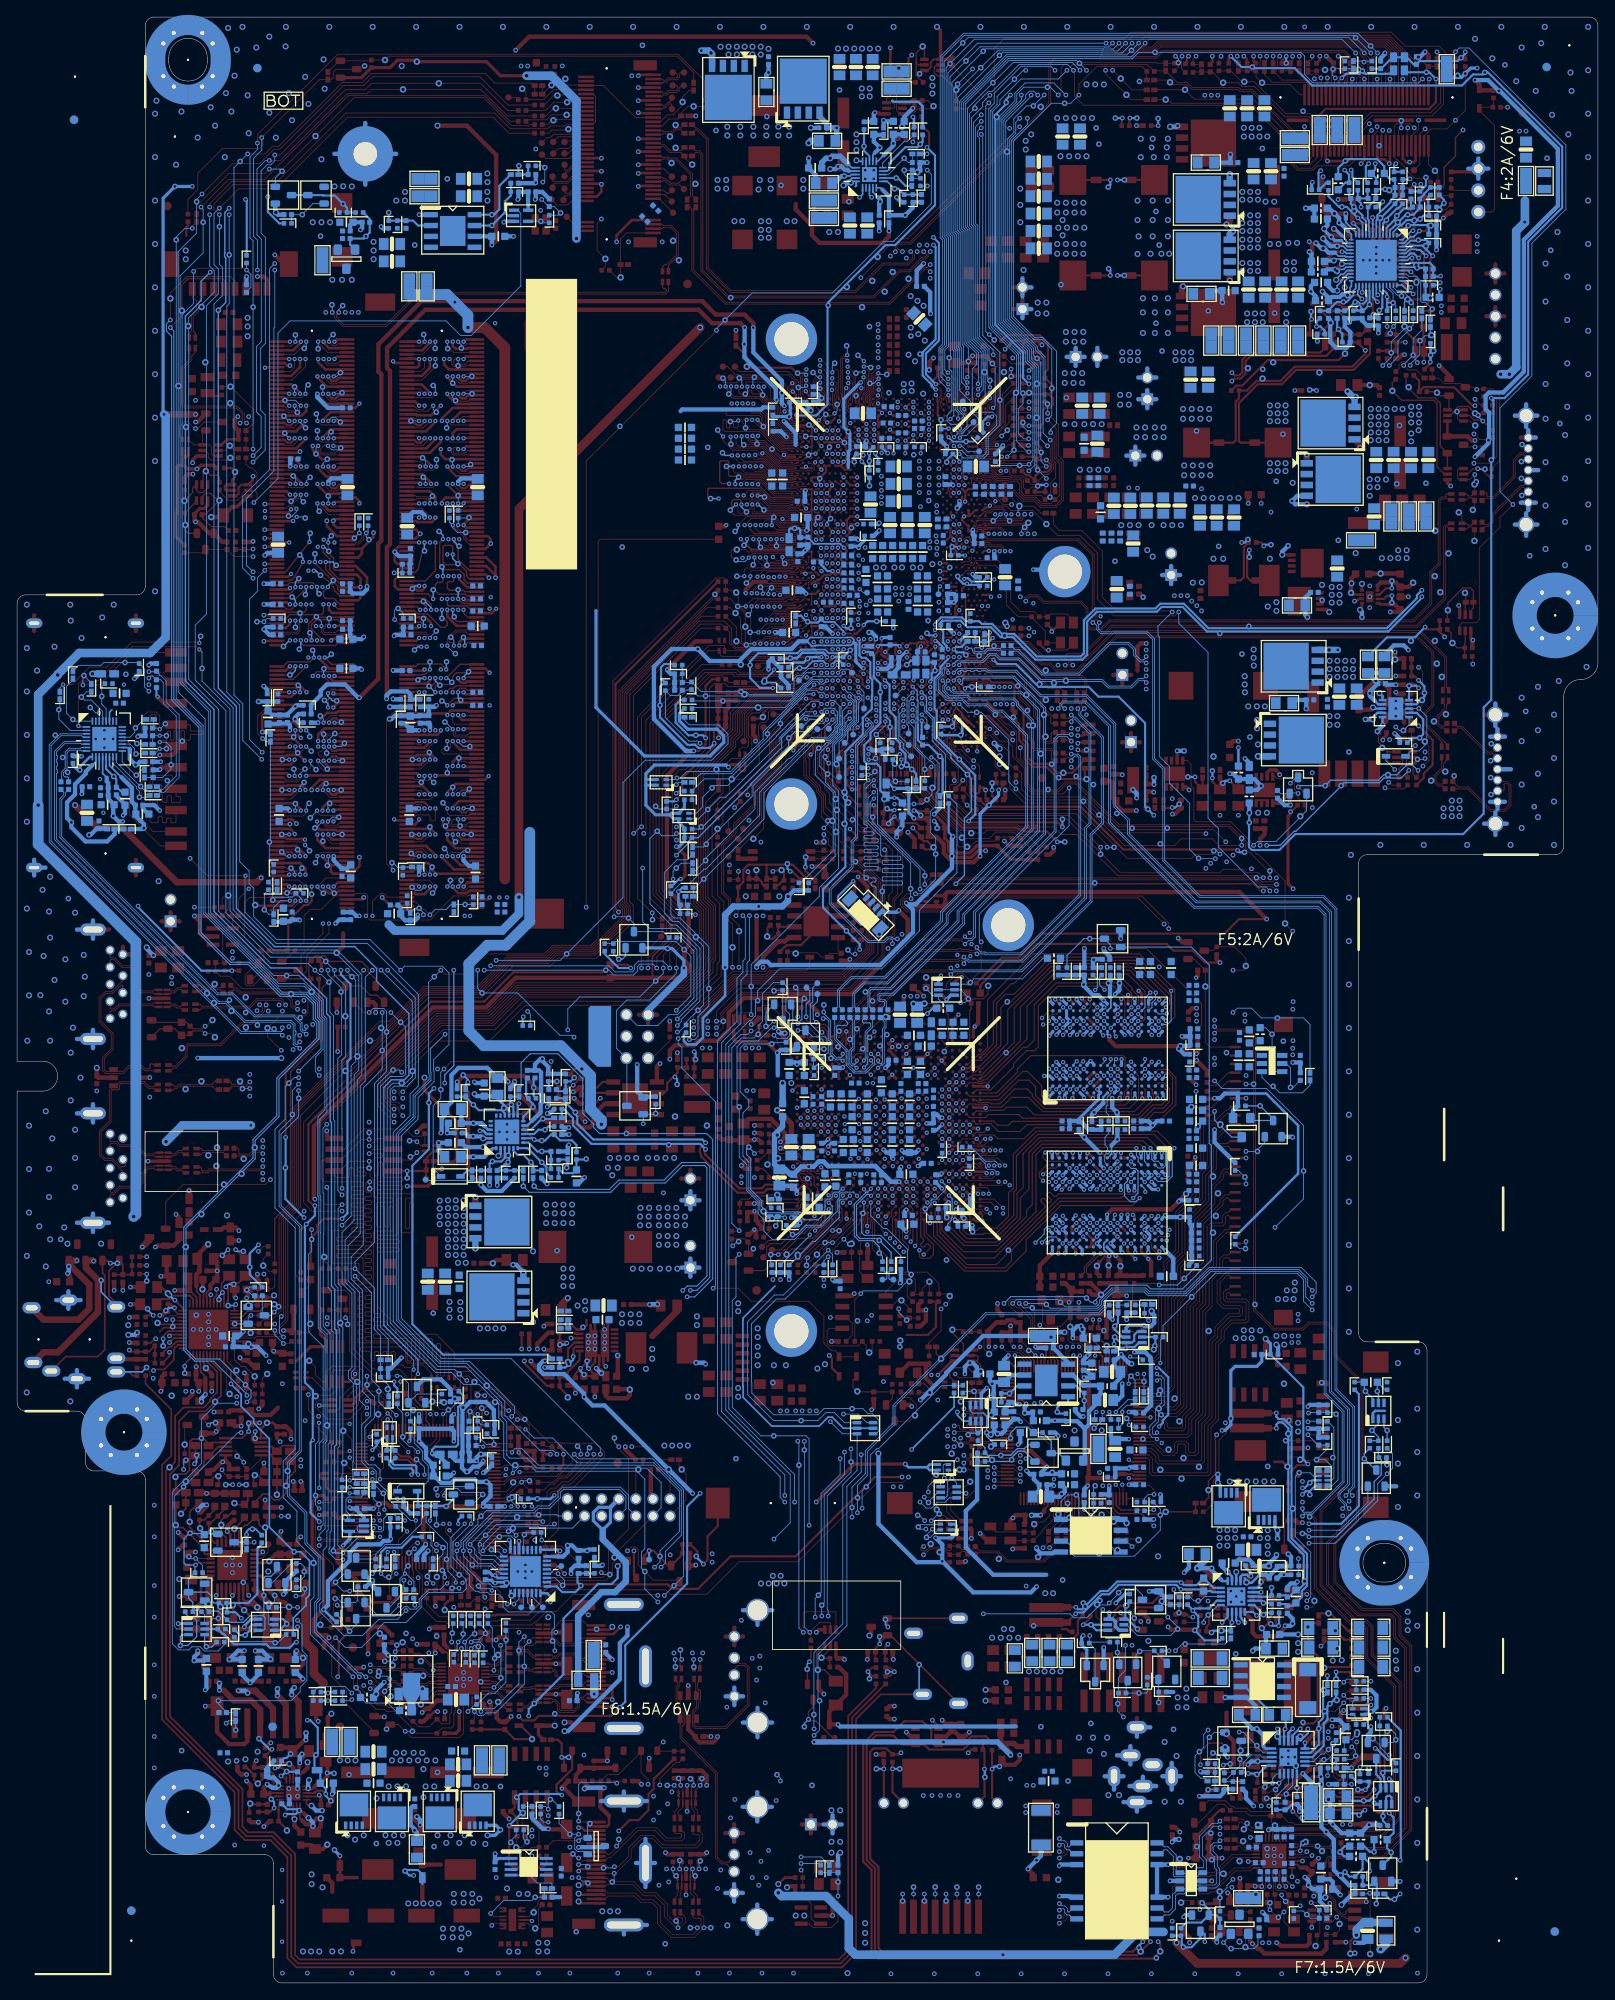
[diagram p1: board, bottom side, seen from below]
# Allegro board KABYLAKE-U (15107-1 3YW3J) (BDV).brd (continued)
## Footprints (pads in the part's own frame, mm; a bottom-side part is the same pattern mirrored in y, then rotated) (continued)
156-5101902601
  round 0.254 hole 1.702 unplated: (-12.65,0) (12.65,0)
  rect 0.991x2.54 smd: 1(-7.57,8.245) 2(-5.07,8.245) 3(-2.57,8.245) 4(-0.07,8.245) 5(2.43,8.245) 6(4.93,8.245) 7(7.43,8.245) 8(9.055,8.245) 9(-10.07,8.245) 10(10.875,8.245) 11(-11.755,8.245)
  oval 1.118x1.93 hole 0.406x1.219: 12(-14.3,3.55) 13(14.3,3.55) 14(-14.3,-8.35) 15(14.3,-8.35)
3703K-Q05N-11L
  rect 0.61x1.549 smd: 1(-2,3.775) 2(-1,3.775) 3(0,3.775) 4(1,3.775) 5(2,3.775)
  rect 1.194x2.007 smd: 6(-3.3,0) 7(3.3,0)
50524-0300N-001
  rect 0.305x1.295 smd: 1(-14.5,5.65) 2(-13.5,5.65) 3(-12.5,5.65) 4(-11.5,5.65) 5(-10.5,5.65) 6(-9.5,5.65) 7(-8.5,5.65) 8(-7.5,5.65) 9(-6.5,5.65) 10(-5.5,5.65) 11(-4.5,5.65) 12(-3.5,5.65) 13(-2.5,5.65) 14(-1.5,5.65) 15(-0.5,5.65) 16(0.5,5.65) 17(1.5,5.65) 18(2.5,5.65) 19(3.5,5.65) 20(4.5,5.65) 21(5.5,5.65) 22(6.5,5.65) 23(7.5,5.65) 24(8.5,5.65) 25(9.5,5.65) 26(10.5,5.65) 27(11.5,5.65) 28(12.5,5.65) 29(13.5,5.65) 30(14.5,5.65)
  rect 1.803x2.21 smd: 31(-17.15,0) 32(17.15,0)
51202-00901-W01-U
  rect 0.66x1.448 smd: 1(-6,6.225) 2(-4.5,6.225) 3(-3,6.225) 4(-1.5,6.225) 5(0,6.225) 6(1.5,6.225) 7(3,6.225) 8(4.5,6.225) 9(6,6.225)
  rect 2.489x2.997 smd: 10(-8.5,0) 11(8.5,0)
51530-01041-W01
  rect 0.305x0.838 smd: 1(-2.25,3.175) 2(-1.75,3.175) 3(-1.25,3.175) 4(-0.75,3.175) 5(-0.25,3.175) 6(0.25,3.175) 7(0.75,3.175) 8(1.25,3.175) 9(1.75,3.175) 10(2.25,3.175)
  rect 0.813x2.007 smd: 11(-3.95,0) 12(3.95,0)
88314-077N
  rect 0.838x3.556 smd: 1(-4.5,-3.225) 2(-3,-3.225) 3(-1.5,-3.225) 4(0,-3.225) 5(1.5,-3.225) 6(3,-3.225) 7(4.5,-3.225)
  rect 0.838x2.642 smd: 8(-4.5,0.675) 9(-3,0.675) 10(-1.5,0.675) 11(0,0.675) 12(1.5,0.675) 13(3,0.675) 14(4.5,0.675)
88459-047N
  rect 0.508x0.991 smd: 1(1.2,1.455) 2(0.4,1.455) 3(-0.4,1.455) 4(-1.2,1.455)
  rect 1.194x1.702 smd: 5(2.5,0) 6(-2.5,0)
2199230-7
  round 0.254 hole 1.6 unplated: (-10,0)
  round 0.254 hole 1.118 unplated: (10,0)
  rect 0.305x1.854 smd: 1(9.25,-5.423) 2(9,2.423) 3(8.75,-5.423) 4(8.5,2.423) 5(8.25,-5.423) 6(8,2.423) 7(7.75,-5.423) 16(5.5,2.423) 17(5.25,-5.423) 18(5,2.423) 19(4.75,-5.423) 20(4.5,2.423) 21(4.25,-5.423) 22(4,2.423) 23(3.75,-5.423) 24(3.5,2.423) 25(3.25,-5.423) 26(3,2.423) 27(2.75,-5.423) 28(2.5,2.423) 29(2.25,-5.423) 30(2,2.423) 31(1.75,-5.423) 32(1.5,2.423) 33(1.25,-5.423) 34(1,2.423) 35(0.75,-5.423) 36(0.5,2.423) 37(0.25,-5.423) 38(0,2.423) 39(-0.25,-5.423) 40(-0.5,2.423) 41(-0.75,-5.423) 42(-1,2.423) 43(-1.25,-5.423) 44(-1.5,2.423) 45(-1.75,-5.423) 46(-2,2.423) 47(-2.25,-5.423) 48(-2.5,2.423) 49(-2.75,-5.423) 50(-3,2.423) 51(-3.25,-5.423) 52(-3.5,2.423) 53(-3.75,-5.423) 54(-4,2.423) 55(-4.25,-5.423) 56(-4.5,2.423) 57(-4.75,-5.423) 58(-5,2.423) 59(-5.25,-5.423) 60(-5.5,2.423) 61(-5.75,-5.423) 62(-6,2.423) 63(-6.25,-5.423) 64(-6.5,2.423) 65(-6.75,-5.423) 66(-7,2.423) 67(-7.25,-5.423) 68(-7.5,2.423) 69(-7.75,-5.423) 70(-8,2.423) 71(-8.25,-5.423) 72(-8.5,2.423) 73(-8.75,-5.423) 74(-9,2.423) 75(-9.25,-5.423)
  rect 1.194x2.743 smd: 76(10.35,-4.5) 77(-10.35,-4.5)
A1251WR0-8PS-5E
  rect 0.813x1.6 smd: 1(-4.375,2.9) 2(-3.125,2.9) 3(-1.875,2.9) 4(-0.625,2.9) 5(0.625,2.9) 6(1.875,2.9) 7(3.125,2.9) 8(4.375,2.9)
  rect 2.108x2.997 smd: 9(-6.925,0) 10(6.925,0)
A1501WV0-6PS-5E
  rect 0.711x3.505 smd: 1(3.75,2) 2(2.25,2) 3(0.75,2) 4(-0.75,2) 5(-2.25,2) 6(-3.75,2)
  rect 1.499x2.311 smd: 7(5.8,0) 8(-5.8,0)
AAA-BAT-034-K01
  round 0.254 hole 1.067 unplated: (-7.5,0)
  round 0.254 hole 1.372 unplated: (0,0)
  rect 2.794x3.607 smd: 1(6.2,0)
  rect 2.997x2.591 smd: 2(-15.1,0)
ARES2H16
  rect 0.356x0.66 smd: 1(-0.325,-0.599) 2(0.325,-0.599) 3(0.325,0.599) 4(-0.325,0.599)
ARES2H18
  rect 0.356x0.66 smd: 1(-0.325,-0.599) 2(0.325,-0.599) 3(0.325,0.599) 4(-0.325,0.599)
ARES8-CN24-UH20
  rect 0.61x0.66 smd: 1(-0.9,-0.486) 4(0.9,-0.486) 5(0.9,0.486) 8(-0.9,0.486)
  rect 0.305x0.66 smd: 2(-0.25,-0.486) 3(0.25,-0.486) 6(0.25,0.486) 7(-0.25,0.486)
BGA170D1214H48
  round 0.406 smd: A1(-5.2,6.4) A2(-4.4,6.4) A3(-3.6,6.4) A12(3.6,6.4) A13(4.4,6.4) A14(5.2,6.4) B1(-5.2,5.6) B2(-4.4,5.6) B3(-3.6,5.6) B12(3.6,5.6) B13(4.4,5.6) B14(5.2,5.6) C1(-5.2,4.8) C2(-4.4,4.8) C3(-3.6,4.8) C12(3.6,4.8) C13(4.4,4.8) C14(5.2,4.8) R1(-5.2,-4.8) R2(-4.4,-4.8) R3(-3.6,-4.8) R12(3.6,-4.8) R13(4.4,-4.8) R14(5.2,-4.8) T1(-5.2,-5.6) T2(-4.4,-5.6) T3(-3.6,-5.6) T12(3.6,-5.6) T13(4.4,-5.6) T14(5.2,-5.6) U1(-5.2,-6.4) U2(-4.4,-6.4) U3(-3.6,-6.4) U12(3.6,-6.4) U13(4.4,-6.4) U14(5.2,-6.4)
  round 0.356 smd: A4(-2.8,6.4) A5(-2,6.4) A10(2,6.4) A11(2.8,6.4) B4(-2.8,5.6) B5(-2,5.6) B10(2,5.6) B11(2.8,5.6) C4(-2.8,4.8) C5(-2,4.8) C10(2,4.8) C11(2.8,4.8) D1(-5.2,4) D2(-4.4,4) D3(-3.6,4) D4(-2.8,4) D5(-2,4) D10(2,4) D11(2.8,4) D12(3.6,4) D13(4.4,4) D14(5.2,4) E1(-5.2,3.2) E2(-4.4,3.2) E3(-3.6,3.2) E4(-2.8,3.2) E5(-2,3.2) E10(2,3.2) E11(2.8,3.2) E12(3.6,3.2) E13(4.4,3.2) E14(5.2,3.2) F1(-5.2,2.4) F2(-4.4,2.4) F3(-3.6,2.4) F4(-2.8,2.4) F5(-2,2.4) F10(2,2.4) F11(2.8,2.4) F12(3.6,2.4) F13(4.4,2.4) F14(5.2,2.4) G1(-5.2,1.6) G2(-4.4,1.6) G3(-3.6,1.6) G4(-2.8,1.6) G5(-2,1.6) G10(2,1.6) G11(2.8,1.6) G12(3.6,1.6) G13(4.4,1.6) G14(5.2,1.6) H1(-5.2,0.8) H2(-4.4,0.8) H3(-3.6,0.8) H4(-2.8,0.8) H5(-2,0.8) H10(2,0.8) H11(2.8,0.8) H12(3.6,0.8) H13(4.4,0.8) H14(5.2,0.8) J1(-5.2,0) J2(-4.4,0) J3(-3.6,0) J4(-2.8,0) J5(-2,0) J10(2,0) J11(2.8,0) J12(3.6,0) J13(4.4,0) J14(5.2,0) K1(-5.2,-0.8) K2(-4.4,-0.8) K3(-3.6,-0.8) K4(-2.8,-0.8) K5(-2,-0.8) K10(2,-0.8) K11(2.8,-0.8) K12(3.6,-0.8) K13(4.4,-0.8) K14(5.2,-0.8) L1(-5.2,-1.6) L2(-4.4,-1.6) L3(-3.6,-1.6) L4(-2.8,-1.6) L5(-2,-1.6) L10(2,-1.6) L11(2.8,-1.6) L12(3.6,-1.6) L13(4.4,-1.6) L14(5.2,-1.6) M1(-5.2,-2.4) M2(-4.4,-2.4) M3(-3.6,-2.4) M4(-2.8,-2.4) M5(-2,-2.4) M10(2,-2.4) M11(2.8,-2.4) M12(3.6,-2.4) M13(4.4,-2.4) M14(5.2,-2.4) N1(-5.2,-3.2) N2(-4.4,-3.2) N3(-3.6,-3.2) N4(-2.8,-3.2) N5(-2,-3.2) N10(2,-3.2) N11(2.8,-3.2) N12(3.6,-3.2) N13(4.4,-3.2) N14(5.2,-3.2) P1(-5.2,-4) P2(-4.4,-4) P3(-3.6,-4) P4(-2.8,-4) P5(-2,-4) P10(2,-4) P11(2.8,-4) P12(3.6,-4) P13(4.4,-4) P14(5.2,-4) R4(-2.8,-4.8) R5(-2,-4.8) R10(2,-4.8) R11(2.8,-4.8) T4(-2.8,-5.6) T5(-2,-5.6) T10(2,-5.6) T11(2.8,-5.6) U4(-2.8,-6.4) U5(-2,-6.4) U10(2,-6.4) U11(2.8,-6.4)
BGA595M23H83
  round 0.432 smd: A2(-9.9,10.7) A3(-9.1,10.7) A25(9.1,10.7) A26(9.9,10.7) AE1(-10.7,-9.1) AE2(-9.9,-9.1) AE3(-9.1,-9.1) AE25(9.1,-9.1) AE26(9.9,-9.1) AE27(10.7,-9.1) AF1(-10.7,-9.9) AF2(-9.9,-9.9) AF3(-9.1,-9.9) AF25(9.1,-9.9) AF26(9.9,-9.9) AF27(10.7,-9.9) AG2(-9.9,-10.7) AG3(-9.1,-10.7) AG25(9.1,-10.7) AG26(9.9,-10.7) B1(-10.7,9.9) B2(-9.9,9.9) B3(-9.1,9.9) B25(9.1,9.9) B26(9.9,9.9) B27(10.7,9.9) C1(-10.7,9.1) C2(-9.9,9.1) C3(-9.1,9.1) C25(9.1,9.1) C26(9.9,9.1) C27(10.7,9.1)
  round 0.381 smd: A4(-8.3,10.7) A6(-6.6,10.7) A7(-5.8,10.7) A9(-4.12,10.7) A10(-3.32,10.7) A12(-1.64,10.7) A13(-0.84,10.7) A15(0.84,10.7) A16(1.64,10.7) A18(3.32,10.7) A19(4.12,10.7) A21(5.8,10.7) A22(6.6,10.7) A24(8.3,10.7) AA1(-10.7,-5.8) AA2(-9.9,-5.8) AA3(-9.1,-5.8) AA4(-8.3,-5.8) AA5(-7.5,-5.8) AA6(-6.66,-5.8) AA7(-5.8,-5.8) AA8(-4.96,-5.8) AA9(-4.12,-5.86) AA10(-3.32,-5.86) AA12(-1.64,-5.86) AA13(-0.84,-5.86) AA14(0,-5.86) AA15(0.84,-5.86) AA16(1.64,-5.86) AA18(3.32,-5.86) AA19(4.12,-5.86) AA20(4.96,-5.8) AA21(5.8,-5.8) AA22(6.66,-5.8) AA23(7.5,-5.8) AA24(8.3,-5.8) AA25(9.1,-5.8) AA26(9.9,-5.8) AA27(10.7,-5.8) AB1(-10.7,-6.6) AB2(-9.9,-6.6) AB3(-9.1,-6.6) AB4(-8.3,-6.6) AB5(-7.5,-6.6) AB6(-6.6,-6.6) AB7(-5.8,-6.66) AB8(-4.96,-6.66) AB9(-4.12,-6.66) AB10(-3.32,-6.66) AB11(-2.48,-6.66) AB12(-1.64,-6.66) AB13(-0.84,-6.66) AB14(0,-6.66) AB15(0.84,-6.66) AB16(1.64,-6.66) AB17(2.48,-6.66) AB18(3.32,-6.66) AB19(4.12,-6.66) AB20(4.96,-6.66) AB21(5.8,-6.66) AB22(6.6,-6.6) AB23(7.5,-6.6) AB24(8.3,-6.6) AB25(9.1,-6.6) AB26(9.9,-6.6) AB27(10.7,-6.6) AC2(-9.9,-7.45) AC3(-9.1,-7.45) AC4(-8.3,-7.45) AC5(-7.45,-7.45) AC6(-6.6,-7.5) AC7(-5.8,-7.5) AC8(-4.96,-7.5) AC9(-4.12,-7.5) AC10(-3.32,-7.5) AC11(-2.48,-7.5) AC12(-1.64,-7.5) AC13(-0.84,-7.5) AC14(0,-7.5) AC15(0.84,-7.5) AC16(1.64,-7.5) AC17(2.48,-7.5) AC18(3.32,-7.5) AC19(4.12,-7.5) AC20(4.96,-7.5) AC21(5.8,-7.5) AC22(6.6,-7.5) AC23(7.45,-7.45) AC24(8.3,-7.45) AC25(9.1,-7.45) AC26(9.9,-7.45) AD1(-10.7,-8.3) AD2(-9.9,-8.3) AD3(-9.1,-8.3) AD4(-8.3,-8.3) AD5(-7.45,-8.3) AD6(-6.6,-8.3) AD7(-5.8,-8.3) AD8(-4.96,-8.3) AD9(-4.12,-8.3) AD10(-3.32,-8.3) AD11(-2.48,-8.3) AD12(-1.64,-8.3) AD13(-0.84,-8.3) AD14(0,-8.3) AD15(0.84,-8.3) AD16(1.64,-8.3) AD17(2.48,-8.3) AD18(3.32,-8.3) AD19(4.12,-8.3) AD20(4.96,-8.3) AD21(5.8,-8.3) AD22(6.6,-8.3) AD23(7.45,-8.3) AD24(8.3,-8.3) AD25(9.1,-8.3) AD26(9.9,-8.3) AD27(10.7,-8.3) AE4(-8.3,-9.1) AE5(-7.45,-9.1) AE6(-6.6,-9.1) AE7(-5.8,-9.1) AE8(-4.96,-9.1) AE9(-4.12,-9.1) AE10(-3.32,-9.1) AE11(-2.48,-9.1) AE12(-1.64,-9.1) AE13(-0.84,-9.1) AE14(0,-9.1) AE15(0.84,-9.1) AE16(1.64,-9.1) AE17(2.48,-9.1) AE18(3.32,-9.1) AE19(4.12,-9.1) AE20(4.96,-9.1) AE21(5.8,-9.1) AE22(6.6,-9.1) AE23(7.45,-9.1) AE24(8.3,-9.1) AF4(-8.3,-9.9) AF5(-7.45,-9.9) AF6(-6.6,-9.9) AF7(-5.8,-9.9) AF8(-4.96,-9.9) AF9(-4.12,-9.9) AF10(-3.32,-9.9) AF11(-2.48,-9.9) AF12(-1.64,-9.9) AF13(-0.84,-9.9) AF14(0,-9.9) AF15(0.84,-9.9) AF16(1.64,-9.9) AF17(2.48,-9.9) AF18(3.32,-9.9) AF19(4.12,-9.9) AF20(4.96,-9.9) AF21(5.8,-9.9) AF22(6.6,-9.9) AF23(7.45,-9.9) AF24(8.3,-9.9) AG4(-8.3,-10.7) AG6(-6.6,-10.7) AG7(-5.8,-10.7) AG9(-4.12,-10.7) AG10(-3.32,-10.7) AG12(-1.64,-10.7) AG13(-0.84,-10.7) AG15(0.84,-10.7) AG16(1.64,-10.7) AG18(3.32,-10.7) AG19(4.12,-10.7) AG21(5.8,-10.7) AG22(6.6,-10.7) AG24(8.3,-10.7) B4(-8.3,9.9) B5(-7.45,9.9) B6(-6.6,9.9) B7(-5.8,9.9) B8(-4.96,9.9) B9(-4.12,9.9) B10(-3.32,9.9) B11(-2.48,9.9) B12(-1.64,9.9) B13(-0.84,9.9) B14(0,9.9) B15(0.84,9.9) B16(1.64,9.9) B17(2.48,9.9) B18(3.32,9.9) B19(4.12,9.9) B20(4.96,9.9) B21(5.8,9.9) B22(6.6,9.9) B23(7.45,9.9) B24(8.3,9.9) C4(-8.3,9.1) C5(-7.45,9.1) C6(-6.6,9.1) C7(-5.8,9.1) C8(-4.96,9.1) C9(-4.12,9.1) C10(-3.32,9.1) C11(-2.48,9.1) C12(-1.64,9.1) C13(-0.84,9.1) C14(0,9.1) C15(0.84,9.1) C16(1.64,9.1) C17(2.48,9.1) C18(3.32,9.1) C19(4.12,9.1) C20(4.96,9.1) C21(5.8,9.1) C22(6.6,9.1) C23(7.45,9.1) C24(8.3,9.1) D1(-10.7,8.3) D2(-9.9,8.3) D3(-9.1,8.3) D4(-8.3,8.3) D5(-7.45,8.3) D6(-6.6,8.3) D7(-5.8,8.3) D8(-4.96,8.3) D9(-4.12,8.3) D10(-3.32,8.3) D11(-2.48,8.3) D12(-1.64,8.3) D13(-0.84,8.3) D14(0,8.3) D15(0.84,8.3) D16(1.64,8.3) D17(2.48,8.3) D18(3.32,8.3) D19(4.12,8.3) D20(4.96,8.3) D21(5.8,8.3) D22(6.6,8.3) D23(7.45,8.3) D24(8.3,8.3) D25(9.1,8.3) D26(9.9,8.3) D27(10.7,8.3) E2(-9.9,7.45) E3(-9.1,7.45) E4(-8.3,7.45) E5(-7.45,7.45) E6(-6.6,7.5) E7(-5.8,7.5) E8(-4.96,7.5) E9(-4.12,7.5) E10(-3.32,7.5) E11(-2.48,7.5) E12(-1.64,7.5) E13(-0.84,7.5) E14(0,7.5) E15(0.84,7.5) E16(1.64,7.5) E17(2.48,7.5) E18(3.32,7.5) E19(4.12,7.5) E20(4.96,7.5) E21(5.8,7.5) E22(6.6,7.5) E23(7.45,7.45) E24(8.3,7.45) E25(9.1,7.45) E26(9.9,7.45) F1(-10.7,6.6) F2(-9.9,6.6) F3(-9.1,6.6) F4(-8.3,6.6) F5(-7.5,6.6) F6(-6.6,6.6) F7(-5.8,6.66) F8(-4.96,6.66) F9(-4.12,6.66) F10(-3.32,6.66) F11(-2.48,6.66) F12(-1.64,6.66) F13(-0.84,6.66) F14(0,6.66) F15(0.84,6.66) F16(1.64,6.66) F17(2.48,6.66) F18(3.32,6.66) F19(4.12,6.66) F20(4.96,6.66) F21(5.8,6.66) F22(6.6,6.6) F23(7.5,6.6) F24(8.3,6.6) F25(9.1,6.6) F26(9.9,6.6) F27(10.7,6.6) G1(-10.7,5.8) G2(-9.9,5.8) G3(-9.1,5.8) G4(-8.3,5.8) G5(-7.5,5.8) G6(-6.66,5.8) G7(-5.8,5.8) G8(-4.96,5.8) G9(-4.12,5.86) G10(-3.32,5.86) G12(-1.64,5.86) G13(-0.84,5.86) G14(0,5.86) G15(0.84,5.86) G16(1.64,5.86) G18(3.32,5.86) G19(4.12,5.86) G20(4.96,5.8) G21(5.8,5.8) G22(6.66,5.8) G23(7.5,5.8) G24(8.3,5.8) G25(9.1,5.8) G26(9.9,5.8) G27(10.7,5.8) H2(-9.9,4.96) H3(-9.1,4.96) H4(-8.3,4.96) H5(-7.5,4.96) H6(-6.66,4.96) H22(6.66,4.96) H23(7.5,4.96) H24(8.3,4.96) H25(9.1,4.96) H26(9.9,4.96) J1(-10.7,4.12) J2(-9.9,4.12) J3(-9.1,4.12) J4(-8.3,4.12) J5(-7.5,4.12) J6(-6.66,4.12) J7(-5.86,4.12) J21(5.86,4.12) J22(6.66,4.12) J23(7.5,4.12) J24(8.3,4.12) J25(9.1,4.12) J26(9.9,4.12) J27(10.7,4.12) K1(-10.7,3.32) K2(-9.9,3.32) K3(-9.1,3.32) K4(-8.3,3.32) K5(-7.5,3.32) K6(-6.66,3.32) K7(-5.86,3.32) K21(5.86,3.32) K22(6.66,3.32) K23(7.5,3.32) K24(8.3,3.32) K25(9.1,3.32) K26(9.9,3.32) K27(10.7,3.32) L2(-9.9,2.48) L3(-9.1,2.48) L4(-8.3,2.48) L5(-7.5,2.48) L6(-6.66,2.48) L22(6.66,2.48) L23(7.5,2.48) L24(8.3,2.48) L25(9.1,2.48) L26(9.9,2.48) M1(-10.7,1.64) M2(-9.9,1.64) M3(-9.1,1.64) M4(-8.3,1.64) M5(-7.5,1.64) M6(-6.66,1.64) M7(-5.86,1.64) M21(5.86,1.64) M22(6.66,1.64) M23(7.5,1.64) M24(8.3,1.64) M25(9.1,1.64) M26(9.9,1.64) M27(10.7,1.64) N1(-10.7,0.84) N2(-9.9,0.84) N3(-9.1,0.84) N4(-8.3,0.84) N5(-7.5,0.84) N6(-6.66,0.84) N7(-5.86,0.84) N21(5.86,0.84) N22(6.66,0.84) N23(7.5,0.84) N24(8.3,0.84) N25(9.1,0.84) N26(9.9,0.84) N27(10.7,0.84) P2(-9.9,0) P3(-9.1,0) P4(-8.3,0) P5(-7.5,0) P6(-6.66,0) P22(6.66,0) P23(7.5,0) P24(8.3,0) P25(9.1,0) P26(9.9,0) R1(-10.7,-0.84) R2(-9.9,-0.84) R3(-9.1,-0.84) R4(-8.3,-0.84) R5(-7.5,-0.84) R6(-6.66,-0.84) R7(-5.86,-0.84) R21(5.86,-0.84) R22(6.66,-0.84) R23(7.5,-0.84) R24(8.3,-0.84) R25(9.1,-0.84) R26(9.9,-0.84) R27(10.7,-0.84) T1(-10.7,-1.64) T2(-9.9,-1.64) T3(-9.1,-1.64) T4(-8.3,-1.64) T5(-7.5,-1.64) T6(-6.66,-1.64) T7(-5.86,-1.64) T21(5.86,-1.64) T22(6.66,-1.64) T23(7.5,-1.64) T24(8.3,-1.64) T25(9.1,-1.64) T26(9.9,-1.64) T27(10.7,-1.64) U2(-9.9,-2.48) U3(-9.1,-2.48) U4(-8.3,-2.48) U5(-7.5,-2.48) U6(-6.66,-2.48) U22(6.66,-2.48) U23(7.5,-2.48) U24(8.3,-2.48) U25(9.1,-2.48) U26(9.9,-2.48) V1(-10.7,-3.32) V2(-9.9,-3.32) V3(-9.1,-3.32) V4(-8.3,-3.32) V5(-7.5,-3.32) V6(-6.66,-3.32) V7(-5.86,-3.32) V21(5.86,-3.32) V22(6.66,-3.32) V23(7.5,-3.32) V24(8.3,-3.32) V25(9.1,-3.32) V26(9.9,-3.32) V27(10.7,-3.32) W1(-10.7,-4.12) W2(-9.9,-4.12) W3(-9.1,-4.12) W4(-8.3,-4.12) W5(-7.5,-4.12) W6(-6.66,-4.12) W7(-5.86,-4.12) W21(5.86,-4.12) W22(6.66,-4.12) W23(7.5,-4.12) W24(8.3,-4.12) W25(9.1,-4.12) W26(9.9,-4.12) W27(10.7,-4.12) Y2(-9.9,-4.96) Y3(-9.1,-4.96) Y4(-8.3,-4.96) Y5(-7.5,-4.96) Y6(-6.66,-4.96) Y22(6.66,-4.96) Y23(7.5,-4.96) Y24(8.3,-4.96) Y25(9.1,-4.96) Y26(9.9,-4.96)
  round 0.457 smd: K10(-4,4) K11(-3,4) K12(-2,4) K13(-1,4) K14(0,4) K15(1,4) K16(2,4) K17(3,4) K18(4,4) L10(-4,3) L11(-3,3) L12(-2,3) L13(-1,3) L14(0,3) L15(1,3) L16(2,3) L17(3,3) L18(4,3) M10(-4,2) M11(-3,2) M12(-2,2) M13(-1,2) M14(0,2) M15(1,2) M16(2,2) M17(3,2) M18(4,2) N10(-4,1) N11(-3,1) N12(-2,1) N13(-1,1) N14(0,1) N15(1,1) N16(2,1) N17(3,1) N18(4,1) P10(-4,0) P11(-3,0) P12(-2,0) P13(-1,0) P14(0,0) P15(1,0) P16(2,0) P17(3,0) P18(4,0) R10(-4,-1) R11(-3,-1) R12(-2,-1) R13(-1,-1) R14(0,-1) R15(1,-1) R16(2,-1) R17(3,-1) R18(4,-1) T10(-4,-2) T11(-3,-2) T12(-2,-2) T13(-1,-2) T14(0,-2) T15(1,-2) T16(2,-2) T17(3,-2) T18(4,-2) U10(-4,-3) U11(-3,-3) U12(-2,-3) U13(-1,-3) U14(0,-3) U15(1,-3) U16(2,-3) U17(3,-3) U18(4,-3) V10(-4,-4) V11(-3,-4) V12(-2,-4) V13(-1,-4) V14(0,-4) V15(1,-4) V16(2,-4) V17(3,-4) V18(4,-4)
BGA1356M4224-U2H52
  round 0.356 smd: A3(19.349,-11.314) A70(-19.852,-11.314) B2(19.832,-10.832) B71(-20.314,-10.852) BA1(20.314,10.852) BA71(-20.314,10.852) BB2(19.852,11.314) BB70(-19.852,11.314) C1(20.314,-10.349)
  round 0.33 smd: A4(18.699,-11.314) A69(-19.202,-11.314) AY1(20.314,10.202) AY71(-20.314,10.202) B3(19.197,-10.679) B70(-19.685,-10.685) BA2(19.685,10.685) BA70(-19.685,10.685) BB3(19.202,11.314) BB69(-19.202,11.314) C2(19.679,-10.197) C71(-20.314,-10.202) D1(20.314,-9.699)
  round 0.305 smd: A5(18.048,-11.314) A68(-18.552,-11.314) AA2(19.339,-0.511) AA4(18.363,-0.511) AA63(-15.112,-0.596) AA64(-15.763,-0.596) AA65(-16.413,-0.596) AA66(-17.063,-0.596) AA67(-17.713,-0.596) AA68(-18.364,-0.596) AA69(-19.014,-0.596) AA70(-19.664,-0.596) AA71(-20.314,-0.596) AB4(18.363,0.152) AB6(17.585,-0.133) AB7(16.935,-0.133) AB8(16.285,-0.133) AB9(15.635,-0.133) AB10(14.984,-0.133) AB11(14.334,-0.133) AB12(13.684,-0.133) AB13(13.034,-0.133) AB15(12.188,-0.009) AB16(11.538,-0.009) AB17(10.888,-0.009) AB18(10.237,-0.009) AB19(9.587,-0.009) AB20(8.937,-0.009) AB21(8.287,-0.009) AB62(-14.644,-0.138) AC3(18.689,0.815) AC63(-15.112,0.319) AC64(-15.763,0.319) AC65(-16.413,0.319) AC66(-17.063,0.319) AC67(-17.713,0.319) AC68(-18.364,0.319) AC69(-19.014,0.319) AC70(-19.664,0.319) AC71(-20.314,0.319) AD4(18.363,1.478) AD6(17.585,0.934) AD7(16.935,0.934) AD8(16.285,0.934) AD9(15.635,0.934) AD10(14.984,0.934) AD11(14.334,0.934) AD12(13.684,0.934) AD13(13.034,0.934) AD15(12.188,0.829) AD16(11.538,0.829) AD17(10.888,0.829) AD18(10.237,0.829) AD19(9.587,0.829) AD20(8.937,0.829) AD21(8.287,0.829) AD62(-14.644,0.776) AE62(-14.644,1.69) AE63(-15.112,1.233) AE64(-15.763,1.233) AE65(-16.413,1.233) AE66(-17.063,1.233) AE67(-17.713,1.233) AE68(-18.364,1.233) AE69(-19.014,1.233) AF2(19.339,2.141) AF4(18.363,2.141) AF6(17.585,2.001) AF7(16.935,2.001) AF8(16.285,2.001) AF9(15.635,2.001) AF10(14.984,2.001) AF11(14.334,2.001) AF12(13.684,2.001) AF13(13.034,2.001) AF15(12.188,1.668) AF16(11.538,1.668) AF17(10.888,1.668) AF18(10.237,1.668) AF19(9.587,1.668) AF20(8.937,1.668) AF21(8.287,1.668) AF63(-15.112,2.148) AF64(-15.763,2.148) AF65(-16.413,2.148) AF66(-17.063,2.148) AF67(-17.713,2.148) AF68(-18.364,1.939) AF69(-19.014,1.939) AG4(18.363,2.804) AG15(12.188,2.506) AG16(11.538,2.506) AG17(10.888,2.506) AG18(10.237,2.506) AG19(9.587,2.506) AG20(8.937,2.506) AG21(8.287,2.506) AG62(-14.644,2.605) AG69(-18.689,2.602) AH3(18.689,3.467) AH6(17.585,3.067) AH7(16.935,3.067) AH8(16.285,3.067) AH9(15.635,3.067) AH10(14.984,3.067) AH11(14.334,3.067) AH12(13.684,3.067) AH13(13.034,3.067) AH63(-15.112,3.062) AH64(-15.763,3.062) AH65(-16.413,3.062) AH66(-17.063,3.062) AH67(-17.713,3.062) AJ4(18.363,4.13) AJ15(12.188,3.344) AJ16(11.538,3.344) AJ17(10.888,3.344) AJ18(10.237,3.344) AJ19(9.587,3.344) AJ20(8.937,3.344) AJ21(8.287,3.344) AJ62(-14.644,3.519) AK6(17.585,4.007) AK7(16.935,4.007) AK8(16.285,4.007) AK9(15.635,4.007) AK10(14.984,4.007) AK11(14.334,4.007) AK12(13.684,4.007) AK13(13.034,4.007) AK15(12.188,4.182) AK16(11.538,4.182) AK17(10.888,4.182) AK18(10.237,4.182) AK19(9.587,4.182) AK20(8.937,4.182) AK21(8.287,4.182) AK22(7.596,4.009) AK23(6.681,4.009) AK25(5.767,4.009) AK27(4.852,4.009) AK28(3.938,4.009) AK30(3.024,4.009) AK32(2.109,4.009) AK33(1.195,4.009) AK35(0.28,4.009) AK37(-0.634,4.009) AK38(-1.548,4.009) AK40(-2.463,4.009) AK42(-3.377,4.009) AK43(-4.292,4.009) AK45(-5.206,4.009) AK46(-6.12,4.009) AK48(-7.035,4.009) AK50(-7.949,4.009) AK52(-8.864,4.009) AK53(-9.778,4.009) AK55(-10.692,4.009) AK56(-11.607,4.009) AK58(-12.521,4.009) AK60(-13.436,4.009) AK62(-14.46,4.144) AK63(-15.112,3.976) AK64(-15.763,3.976) AK65(-16.413,3.976) AK66(-17.063,3.976) AK67(-17.713,3.976) AK68(-18.364,3.829) AK69(-19.339,3.829) AL2(19.339,4.793) AL4(18.363,4.793) AL23(7.138,4.474) AL25(6.224,4.474) AL27(5.31,4.474) AL28(4.395,4.474) AL30(3.481,4.474) AL32(2.566,4.474) AL33(1.652,4.474) AL35(0.738,4.474) AL37(-0.177,4.474) AL38(-1.091,4.474) AL40(-2.006,4.474) AL42(-2.92,4.474) AL43(-3.834,4.474) AL45(-4.749,4.474) AL46(-5.663,4.474) AL48(-6.578,4.474) AL50(-7.492,4.474) AL52(-8.406,4.474) AL53(-9.321,4.474) AL55(-10.235,4.474) AL56(-11.15,4.474) AL58(-12.064,4.474) AL60(-12.978,4.474) AL61(-13.893,4.474) AL63(-15.112,4.845) AL64(-15.763,4.845) AL65(-16.413,4.845) AL66(-17.063,4.845) AM4(18.363,5.456) AM5(17.654,4.946) AM7(16.74,4.946) AM8(15.825,4.946) AM10(14.911,4.946) AM11(13.996,4.946) AM13(13.082,4.946) AM15(12.168,4.946) AM16(11.253,4.946) AM18(10.339,4.946) AM20(9.424,4.946) AM21(8.51,4.946) AM22(7.596,4.946) AM23(6.681,4.946) AM25(5.767,4.946) AM27(4.852,4.946) AM28(3.938,4.946) AM30(3.024,4.946) AM32(2.109,4.946) AM33(1.195,4.946) AM35(0.28,4.946) AM37(-0.634,4.946) AM38(-1.548,4.946) AM40(-2.463,4.946) AM42(-3.377,4.946) AM43(-4.292,4.946) AM45(-5.206,4.946) AM46(-6.12,4.946) AM48(-7.035,4.946) AM50(-7.949,4.946) AM52(-8.864,4.946) AM53(-9.778,4.946) AM55(-10.692,4.946) AM56(-11.607,4.946) AM58(-12.521,4.946) AM60(-13.436,4.946) AM61(-14.35,4.946) AM68(-18.039,5.056) AM69(-18.689,5.056) AN3(18.689,6.119) AN5(17.654,5.597) AN7(16.74,5.597) AN8(15.825,5.597) AN10(14.911,5.597) AN11(13.996,5.597) AN13(13.082,5.597) AN15(12.168,5.597) AN16(11.253,5.597) AN18(10.339,5.597) AN20(9.424,5.597) AN21(8.51,5.597) AN22(7.596,5.597) AN23(6.681,5.597) AN25(5.767,5.597) AN27(4.852,5.597) AN28(3.938,5.597) AN30(3.024,5.597) AN32(2.109,5.597) AN33(1.195,5.597) AN35(0.28,5.597) AN37(-0.634,5.597) AN38(-1.548,5.597) AN40(-2.463,5.597) AN42(-3.377,5.597) AN43(-4.292,5.597) AN45(-5.206,5.597) AN46(-6.12,5.597) AN48(-7.035,5.597) AN50(-7.949,5.597) AN52(-8.864,5.597) AN53(-9.778,5.597) AN55(-10.692,5.597) AN56(-11.607,5.597) AN58(-12.521,5.597) AN60(-13.436,5.597) AN61(-14.35,5.597) AN63(-15.264,5.597) AN65(-16.179,5.597) AN66(-17.093,5.597) AN68(-18.364,5.719) AN69(-19.014,5.719) AP4(18.363,6.782) AP5(17.654,6.247) AP7(16.74,6.247) AP8(15.825,6.247) AP10(14.911,6.247) AP11(13.996,6.247) AP13(13.082,6.247) AP15(12.168,6.247) AP16(11.253,6.247) AP18(10.339,6.247) AP20(9.424,6.247) AP21(8.51,6.247) AP22(7.596,6.247) AP23(6.681,6.247) AP25(5.767,6.247) AP27(4.852,6.247) AP28(3.938,6.247) AP30(3.024,6.247) AP32(2.109,6.247) AP33(1.195,6.247) AP35(0.28,6.247) AP37(-0.634,6.247) AP38(-1.548,6.247) AP40(-2.463,6.247) AP42(-3.377,6.247) AP43(-4.292,6.247) AP45(-5.206,6.247) AP46(-6.12,6.247) AP48(-7.035,6.247) AP50(-7.949,6.247) AP52(-8.864,6.247) AP53(-9.778,6.247) AP55(-10.692,6.247) AP56(-11.607,6.247) AP58(-12.521,6.247) AP60(-13.436,6.247) AP61(-14.35,6.247) AP63(-15.264,6.247) AP65(-16.179,6.247) AP66(-17.093,6.247) AP68(-18.039,6.332) AP70(-19.258,6.332) AR5(17.654,6.897) AR7(16.74,6.897) AR8(15.825,6.897) AR10(14.911,6.897) AR11(13.996,6.897) AR13(13.082,6.897) AR15(12.168,6.897) AR16(11.253,6.897) AR18(10.339,6.897) AR20(9.424,6.897) AR21(8.51,6.897) AR22(7.596,6.897) AR23(6.681,6.897) AR25(5.767,6.897) AR27(4.852,6.897) AR28(3.938,6.897) AR30(3.024,6.897) AR32(2.109,6.897) AR33(1.195,6.897) AR35(0.28,6.897) AR37(-0.634,6.897) AR38(-1.548,6.897) AR40(-2.463,6.897) AR42(-3.377,6.897) AR43(-4.292,6.897) AR45(-5.206,6.897) AR46(-6.12,6.897) AR48(-7.035,6.897) AR50(-7.949,6.897) AR52(-8.864,6.897) AR53(-9.778,6.897) AR55(-10.692,6.897) AR56(-11.607,6.897) AR58(-12.521,6.897) AR60(-13.436,6.897) AR61(-14.35,6.897) AR63(-15.264,6.897) AR65(-16.179,6.897) AR66(-17.093,6.897) AR68(-18.364,6.945) AR69(-19.014,6.945) AT2(19.339,7.445) AT4(18.363,7.445) AT5(17.654,7.547) AT7(16.74,7.547) AT8(15.825,7.547) AT10(14.911,7.547) AT11(13.996,7.547) AT13(13.082,7.547) AT15(12.168,7.547) AT16(11.253,7.547) AT18(10.339,7.547) AT20(9.424,7.547) AT21(8.51,7.547) AT22(7.596,7.547) AT23(6.681,7.547) AT25(5.767,7.547) AT27(4.852,7.547) AT28(3.938,7.547) AT30(3.024,7.547) AT32(2.109,7.547) AT33(1.195,7.547) AT35(0.28,7.547) AT37(-0.634,7.547) AT38(-1.548,7.547) AT40(-2.463,7.547) AT42(-3.377,7.547) AT43(-4.292,7.547) AT45(-5.206,7.547) AT46(-6.12,7.547) AT48(-7.035,7.547) AT50(-7.949,7.547) AT52(-8.864,7.547) AT53(-9.778,7.547) AT55(-10.692,7.547) AT56(-11.607,7.547) AT58(-12.521,7.547) AT60(-13.436,7.547) AT61(-14.35,7.547) AT63(-15.264,7.547) AT65(-16.179,7.547) AT66(-17.093,7.547) AT68(-18.039,7.509) AT69(-18.689,7.509) AU4(18.363,8.108) AU5(17.654,8.198) AU7(16.74,8.198) AU8(15.825,8.198) AU10(14.911,8.198) AU11(13.996,8.198) AU13(13.082,8.198) AU15(12.168,8.198) AU16(11.253,8.198) AU18(10.339,8.198) AU20(9.424,8.198) AU21(8.51,8.198) AU22(7.596,8.198) AU23(6.681,8.198) AU25(5.767,8.198) AU27(4.852,8.198) AU28(3.938,8.198) AU30(3.024,8.198) AU32(2.109,8.198) AU33(1.195,8.198) AU35(0.28,8.198) AU37(-0.634,8.198) AU38(-1.548,8.198) AU40(-2.463,8.198) AU42(-3.377,8.198) AU43(-4.292,8.198) AU45(-5.206,8.198) AU46(-6.12,8.198) AU48(-7.035,8.198) AU50(-7.949,8.198) AU52(-8.864,8.198) AU53(-9.778,8.198) AU55(-10.692,8.198) AU56(-11.607,8.198) AU58(-12.521,8.198) AU60(-13.436,8.198) AU61(-14.35,8.198) AU63(-15.264,8.198) AU65(-16.179,8.198) AU66(-17.093,8.198) AV3(18.689,8.799) AV68(-18.029,8.711) AV69(-19.014,8.901) AV70(-19.664,8.901) AW1(20.314,9.551) AW5(17.781,8.911) AW6(17.13,9.038) AW7(16.564,9.363) AW8(15.986,9.038) AW9(15.416,9.363) AW10(14.753,9.038) AW11(14.143,9.363) AW12(13.565,9.038) AW13(12.995,9.363) AW14(12.332,9.038) AW15(11.723,9.363) AW16(11.145,9.038) AW17(10.575,9.363) AW18(9.912,9.038) AW20(9.302,9.363) AW21(8.724,9.038) AW22(8.154,9.363) AW23(7.466,9.038) AW25(6.828,9.363) AW26(6.264,9.038) AW27(5.601,9.363) AW28(4.988,9.038) AW29(4.374,9.363) AW30(3.711,9.038) AW31(3.148,9.363) AW32(2.485,9.038) AW33(1.847,9.363) AW34(1.283,9.038) AW35(0.62,9.363) AW36(0.007,9.038) AW37(-0.607,9.363) AW38(-1.269,9.038) AW39(-1.833,9.363) AW41(-2.471,9.038) AW42(-3.108,9.363) AW43(-3.672,9.038) AW44(-4.335,9.363) AW45(-4.949,9.038) AW46(-5.562,9.363) AW47(-6.163,9.038) AW48(-6.727,9.363) AW49(-7.355,9.038) AW50(-7.984,9.363) AW51(-8.548,9.038) AW52(-9.149,9.363) AW53(-9.762,9.038) AW54(-10.375,9.363) AW55(-11.038,9.038) AW56(-11.602,9.363) AW57(-12.24,9.038) AW59(-12.877,9.363) AW60(-13.441,9.038) AW61(-14.104,9.363) AW62(-14.718,9.038) AW63(-15.331,9.363) AW64(-15.994,9.038) AW65(-16.558,9.363) AW66(-17.093,8.9) AW67(-18.018,9.371) AW68(-18.622,9.622) AW69(-19.267,9.536) AW70(-19.685,10.035) AW71(-20.314,9.551) AY2(19.685,10.034) AY3(19.028,10.028) AY4(18.274,10.043) AY5(17.665,9.689) AY8(15.986,9.689) AY12(13.565,9.689) AY16(11.145,9.689) AY21(8.724,9.689) AY26(6.264,9.689) AY27(5.601,10.014) AY29(4.374,10.014) AY30(3.711,9.689) AY34(1.283,9.689) AY35(0.62,10.014) AY37(-0.607,10.014) AY38(-1.269,9.689) AY43(-3.672,9.689) AY44(-4.335,10.014) AY46(-5.562,10.014) AY47(-6.163,9.689) AY51(-8.548,9.689) AY52(-9.149,10.014) AY54(-10.375,10.014) AY55(-11.038,9.689) AY60(-13.441,9.689) AY61(-14.104,10.014) AY63(-15.331,10.014) AY64(-15.994,9.689) AY66(-17.221,9.689) AY68(-18.535,10.267) B5(18.048,-10.664) B6(17.467,-10.339) B10(14.989,-10.339) B14(12.511,-10.339) B18(10.033,-10.339) B22(7.555,-10.339) B26(5.077,-10.339) B30(2.599,-10.339) B34(0.121,-10.339) B39(-2.357,-10.339) B44(-4.835,-10.339) B48(-7.313,-10.339) B53(-9.791,-10.339) B58(-12.269,-10.339) B62(-14.747,-10.339) B66(-17.226,-10.339) B69(-19.035,-10.685) BA3(19.035,10.685) BA5(17.715,10.626) BA8(15.986,10.339) BA12(13.565,10.339) BA16(11.145,10.339) BA21(8.724,10.339) BA23(7.466,10.258) BA28(4.988,10.258) BA32(2.485,10.258) BA36(0.007,10.258) BA41(-2.471,10.258) BA45(-4.949,10.258) BA49(-7.355,10.339) BA53(-9.762,10.258) BA57(-12.24,10.258) BA62(-14.718,10.258) BA68(-19.035,10.685) BB4(18.551,11.314) BB68(-18.552,11.314) C4(18.615,-10.336) C5(18.048,-10.014) C7(16.791,-10.014) C8(16.228,-10.339) C9(15.664,-10.014) C11(14.313,-10.014) C12(13.75,-10.339) C13(13.186,-10.014) C15(11.835,-10.014) C16(11.272,-10.339) C17(10.708,-10.014) C19(9.357,-10.014) C20(8.794,-10.339) C21(8.23,-10.014) C23(6.879,-10.014) C24(6.316,-10.339) C25(5.752,-10.014) C27(4.401,-10.014) C28(3.838,-10.339) C29(3.274,-10.014) C31(1.923,-10.014) C32(1.36,-10.339) C33(0.796,-10.014) C36(-0.555,-10.014) C37(-1.118,-10.339) C38(-1.682,-10.014) C40(-3.033,-10.014) C41(-3.596,-10.339) C42(-4.16,-10.014) C45(-5.511,-10.014) C46(-6.074,-10.339) C47(-6.638,-10.014) C50(-7.989,-10.014) C51(-8.552,-10.339) C52(-9.116,-10.014) C54(-10.467,-10.014) C55(-11.03,-10.339) C56(-11.594,-10.014) C59(-12.945,-10.014) C60(-13.508,-10.339) C61(-14.072,-10.014) C63(-15.423,-10.014) C64(-15.987,-10.339) C65(-16.55,-10.014) C67(-18.485,-10.299) C68(-18.622,-9.622) C70(-19.685,-10.034) D3(19.339,-9.608) D4(18.691,-9.669) D5(18.09,-9.363) D6(17.441,-9.323) D7(16.791,-9.363) D8(16.228,-9.689) D9(15.664,-9.363) D10(14.989,-9.323) D11(14.313,-9.363) D12(13.75,-9.689) D13(13.186,-9.363) D14(12.511,-9.323) D15(11.835,-9.363) D16(11.272,-9.689) D17(10.708,-9.363) D18(10.033,-9.323) D19(9.357,-9.363) D20(8.794,-9.689) D21(8.23,-9.363) D22(7.555,-9.323) D23(6.879,-9.363) D24(6.316,-9.689) D25(5.752,-9.363) D26(5.077,-9.323) D27(4.401,-9.363) D28(3.838,-9.689) D29(3.274,-9.363) D30(2.599,-9.323) D31(1.923,-9.363) D32(1.36,-9.689) D33(0.796,-9.363) D34(0.121,-9.323) D36(-0.555,-9.363) D37(-1.118,-9.689) D38(-1.682,-9.363) D39(-2.357,-9.323) D40(-3.033,-9.363) D41(-3.596,-9.689) D42(-4.16,-9.363) D44(-4.835,-9.323) D45(-5.511,-9.363) D46(-6.074,-9.689) D47(-6.638,-9.363) D48(-7.313,-9.323) D50(-7.989,-9.363) D51(-8.552,-9.689) D52(-9.116,-9.363) D53(-9.791,-9.323) D54(-10.467,-9.363) D55(-11.03,-9.689) D56(-11.594,-9.363) D58(-12.269,-9.323) D59(-12.945,-9.363) D60(-13.508,-9.689) D61(-14.072,-9.363) D62(-14.747,-9.323) D63(-15.423,-9.363) D64(-15.987,-9.689) D65(-16.55,-9.363) D66(-17.226,-9.323) D67(-17.899,-10.014) D68(-19.267,-9.535) D69(-18.562,-8.971) D71(-20.314,-9.551) E1(20.314,-9.04) E2(19.664,-9.04) E3(19.014,-9.04) E5(17.654,-8.591) E6(16.74,-8.591) E8(15.825,-8.591) E10(14.911,-8.591) E11(13.996,-8.591) E13(13.082,-8.591) E15(12.168,-8.591) E16(11.253,-8.591) E18(10.339,-8.591) E20(9.424,-8.591) E21(8.51,-8.591) E22(7.596,-8.591) E23(6.681,-8.591) E25(5.767,-8.591) E27(4.852,-8.591) E28(3.938,-8.591) E30(3.024,-8.591) E32(2.109,-8.591) E33(1.195,-8.591) E35(0.28,-8.591) E37(-0.634,-8.591) E38(-1.548,-8.591) E40(-2.463,-8.591) E42(-3.377,-8.591) E43(-4.292,-8.591) E45(-5.206,-8.591) E46(-6.12,-8.591) E48(-7.035,-8.591) E50(-7.949,-8.591) E52(-8.864,-8.591) E53(-9.778,-8.591) E55(-10.692,-8.591) E56(-11.607,-8.591) E58(-12.521,-8.591) E60(-13.436,-8.591) E61(-14.35,-8.591) E63(-15.315,-8.655) E65(-16.331,-8.655) E66(-17.347,-8.655) E68(-17.899,-9.363) F2(19.339,-8.466) F4(18.363,-8.466) F5(17.654,-7.941) F6(16.74,-7.941) F8(15.825,-7.941) F10(14.911,-7.941) F11(13.996,-7.941) F13(13.082,-7.941) F15(12.168,-7.941) F16(11.253,-7.941) F18(10.339,-7.941) F20(9.424,-7.941) F21(8.51,-7.941) F22(7.596,-7.941) F23(6.681,-7.941) F25(5.767,-7.941) F27(4.852,-7.941) F28(3.938,-7.941) F30(3.024,-7.941) F32(2.109,-7.941) F33(1.195,-7.941) F35(0.28,-7.941) F37(-0.634,-7.941) F38(-1.548,-7.941) F40(-2.463,-7.941) F42(-3.377,-7.941) F43(-4.292,-7.941) F45(-5.206,-7.941) F46(-6.12,-7.941) F48(-7.035,-7.941) F50(-7.949,-7.941) F52(-8.864,-7.941) F53(-9.778,-7.941) F55(-10.692,-7.941) F56(-11.607,-7.941) F58(-12.521,-7.941) F60(-13.436,-7.941) F61(-14.35,-7.941) F63(-15.315,-8.005) F65(-16.331,-8.005) F66(-17.347,-8.005) F68(-18.562,-8.32) G4(18.363,-7.803) G5(17.654,-7.291) G6(16.74,-7.291) G8(15.825,-7.291) G10(14.911,-7.291) G11(13.996,-7.291) G13(13.082,-7.291) G15(12.168,-7.291) G16(11.253,-7.291) G18(10.339,-7.291) G20(9.424,-7.291) G21(8.51,-7.291) G22(7.596,-7.291) G23(6.681,-7.291) G25(5.767,-7.291) G27(4.852,-7.291) G28(3.938,-7.291) G30(3.024,-7.291) G32(2.109,-7.291) G33(1.195,-7.291) G35(0.28,-7.291) G37(-0.634,-7.291) G38(-1.548,-7.291) G40(-2.463,-7.291) G42(-3.377,-7.291) G43(-4.292,-7.291) G45(-5.206,-7.291) G46(-6.12,-7.291) G48(-7.035,-7.291) G50(-7.949,-7.291) G52(-8.864,-7.291) G53(-9.778,-7.291) G55(-10.692,-7.291) G56(-11.607,-7.291) G58(-12.521,-7.291) G60(-13.436,-7.291) G61(-14.35,-7.291) G63(-15.315,-7.354) G65(-16.331,-7.354) G66(-17.347,-7.354) G68(-18.364,-7.66) G69(-19.014,-7.66) H3(18.689,-7.14) H5(17.654,-6.641) H6(16.74,-6.641) H8(15.825,-6.641) H10(14.911,-6.641) H11(13.996,-6.641) H13(13.082,-6.641) H15(12.168,-6.641) H16(11.253,-6.641) H18(10.339,-6.641) H20(9.424,-6.641) H21(8.51,-6.641) H63(-15.315,-6.704) H65(-16.331,-6.704) H66(-17.347,-6.704) H69(-18.689,-7.096) J4(18.363,-6.477) J5(17.654,-5.99) J6(16.74,-5.99) J8(15.825,-5.99) J10(14.911,-5.99) J11(13.996,-5.99) J13(13.082,-5.99) J22(7.138,-6.827) J23(6.224,-6.827) J25(5.31,-6.827) J27(4.395,-6.827) J28(3.481,-6.827) J30(2.566,-6.827) J32(1.652,-6.827) J33(0.738,-6.827) J35(-0.177,-6.827) J37(-1.091,-6.827) J38(-2.006,-6.827) J40(-2.92,-6.827) J42(-3.834,-6.827) J43(-4.749,-6.827) J45(-5.663,-6.827) J46(-6.578,-6.827) J48(-7.492,-6.827) J50(-8.406,-6.827) J52(-9.321,-6.827) J53(-10.235,-6.827) J55(-11.15,-6.827) J56(-12.064,-6.827) J58(-12.978,-6.827) J60(-13.893,-6.827) J68(-18.362,-6.52) K15(12.188,-5.876) K16(11.538,-5.876) K17(10.888,-5.876) K18(10.237,-5.876) K19(9.587,-5.876) K20(8.937,-5.876) K21(8.287,-5.876) K22(7.596,-6.362) K23(6.681,-6.362) K25(5.767,-6.362) K27(4.852,-6.362) K28(3.938,-6.362) K30(3.024,-6.362) K32(2.109,-6.362) K33(1.195,-6.362) K35(0.28,-6.362) K37(-0.634,-6.362) K38(-1.548,-6.362) K40(-2.463,-6.362) K42(-3.377,-6.362) K43(-4.292,-6.362) K45(-5.206,-6.362) K46(-6.12,-6.362) K48(-7.035,-6.362) K50(-7.949,-6.362) K52(-8.864,-6.362) K53(-9.778,-6.362) K55(-10.692,-6.362) K56(-11.607,-6.362) K58(-12.521,-6.362) K60(-13.436,-6.362) K61(-14.35,-6.362) K63(-15.133,-6.054) K64(-15.783,-6.054) K65(-16.433,-6.054) K66(-17.084,-6.054) K67(-17.734,-6.054) K68(-18.352,-5.846) K70(-19.339,-5.744) L2(19.339,-5.814) L4(18.363,-5.814) L6(17.585,-5.34) L7(16.935,-5.34) L8(16.285,-5.34) L9(15.635,-5.34) L10(14.984,-5.34) L11(14.334,-5.34) L12(13.684,-5.34) L13(13.034,-5.34) L15(12.188,-5.038) L16(11.538,-5.038) L17(10.888,-5.038) L18(10.237,-5.038) L19(9.587,-5.038) L20(8.937,-5.038) L21(8.287,-5.038) L62(-14.644,-5.625) L63(-15.112,-5.168) L64(-15.763,-5.168) L65(-16.413,-5.168) L66(-17.063,-5.168) L67(-17.713,-5.168) L68(-18.364,-5.168) L69(-19.014,-5.168) L70(-19.664,-5.168) L71(-20.314,-5.168) M4(18.363,-5.151) M62(-14.644,-4.71) N3(18.689,-4.488) N6(17.585,-4.4) N7(16.935,-4.4) N8(16.285,-4.4) N9(15.635,-4.4) N10(14.984,-4.4) N11(14.334,-4.4) N12(13.684,-4.4) N13(13.034,-4.4) N15(12.188,-4.2) N16(11.538,-4.2) N17(10.888,-4.2) N18(10.237,-4.2) N19(9.587,-4.2) N20(8.937,-4.2) N21(8.287,-4.2) N63(-15.112,-4.253) N64(-15.763,-4.253) N65(-16.413,-4.253) N66(-17.063,-4.253) N67(-17.713,-4.253) N68(-18.364,-4.253) N69(-19.014,-4.253) N70(-19.664,-4.253) N71(-20.314,-4.253) P4(18.363,-3.825) P15(12.188,-3.362) P16(11.538,-3.362) P17(10.888,-3.362) P18(10.237,-3.362) P19(9.587,-3.362) P20(8.937,-3.362) P21(8.287,-3.362) P62(-14.644,-3.796) R6(17.585,-3.333) R7(16.935,-3.333) R8(16.285,-3.333) R9(15.635,-3.333) R10(14.984,-3.333) R11(14.334,-3.333) R12(13.684,-3.333) R13(13.034,-3.333) R63(-15.112,-3.339) R64(-15.763,-3.339) R65(-16.413,-3.339) R66(-17.063,-3.339) R67(-17.713,-3.339) R68(-18.364,-3.339) R69(-19.014,-3.339) R70(-19.664,-3.339) R71(-20.314,-3.339) T2(19.339,-3.162) T4(18.363,-3.162) T15(12.188,-2.523) T16(11.538,-2.523) T17(10.888,-2.523) T18(10.237,-2.523) T19(9.587,-2.523) T20(8.937,-2.523) T21(8.287,-2.523) T62(-14.644,-2.882) U4(18.363,-2.499) U6(17.585,-2.267) U7(16.935,-2.267) U8(16.285,-2.267) U9(15.635,-2.267) U10(14.984,-2.267) U11(14.334,-2.267) U12(13.684,-2.267) U13(13.034,-2.267) U63(-15.112,-2.424) U64(-15.763,-2.424) U65(-16.413,-2.424) U66(-17.063,-2.424) U67(-17.713,-2.424) U68(-18.364,-2.424) U69(-19.014,-2.424) U70(-19.664,-2.424) U71(-20.314,-2.424) V3(18.689,-1.836) V15(12.188,-1.685) V16(11.538,-1.685) V17(10.888,-1.685) V18(10.237,-1.685) V19(9.587,-1.685) V20(8.937,-1.685) V21(8.287,-1.685) V62(-14.644,-1.967) W4(18.363,-1.173) W6(17.585,-1.2) W7(16.935,-1.2) W8(16.285,-1.2) W9(15.635,-1.2) W10(14.984,-1.2) W11(14.334,-1.2) W12(13.684,-1.2) W13(13.034,-1.2) W63(-15.112,-1.51) W64(-15.763,-1.51) W65(-16.413,-1.51) W66(-17.063,-1.51) W67(-17.713,-1.51) W68(-18.364,-1.51) W69(-19.014,-1.51) W70(-19.664,-1.51) W71(-20.314,-1.51) Y15(12.188,-0.847) Y16(11.538,-0.847) Y17(10.888,-0.847) Y18(10.237,-0.847) Y19(9.587,-0.847) Y20(8.937,-0.847) Y21(8.287,-0.847) Y62(-14.644,-1.053)
  oval 0.254x0.343 smd: A6(17.467,-10.989) A7(16.791,-11.314) A9(15.664,-11.314) A10(14.989,-10.989) A11(14.313,-11.314) A13(13.186,-11.314) A14(12.511,-10.989) A15(11.835,-11.314) A17(10.708,-11.314) A18(10.033,-10.989) A19(9.357,-11.314) A21(8.23,-11.314) A22(7.555,-10.989) A23(6.879,-11.314) A25(5.752,-11.314) A26(5.077,-10.989) A27(4.401,-11.314) A29(3.274,-11.314) A30(2.599,-10.989) A31(1.923,-11.314) A33(0.796,-11.314) A34(0.121,-10.989) A36(-0.555,-11.314) A38(-1.682,-11.314) A39(-2.357,-10.989) A40(-3.033,-11.314) A42(-4.16,-11.314) A44(-4.835,-10.989) A45(-5.511,-11.314) A47(-6.638,-11.314) A48(-7.313,-10.989) A50(-7.989,-11.314) A52(-9.116,-11.314) A53(-9.791,-10.989) A54(-10.467,-11.314) A56(-11.594,-11.314) A58(-12.269,-10.989) A59(-12.945,-11.314) A61(-14.072,-11.314) A62(-14.747,-10.989) A63(-15.423,-11.314) A65(-16.55,-11.314) A66(-17.226,-10.989) A67(-17.901,-11.314) AY7(16.551,10.014) AY9(15.416,10.014) AY11(14.131,10.014) AY13(12.995,10.014) AY15(11.71,10.014) AY17(10.575,10.014) AY20(9.289,10.014) AY22(8.154,10.014) AY25(6.828,10.014) AY31(3.148,10.014) AY33(1.847,10.014) AY39(-1.833,10.014) AY42(-3.108,10.014) AY48(-6.789,10.014) AY50(-7.922,10.014) AY56(-11.602,10.014) AY59(-12.877,10.014) AY65(-16.558,10.014) AY67(-17.901,10.014) B7(16.791,-10.664) B9(15.664,-10.664) B11(14.313,-10.664) B13(13.186,-10.664) B15(11.835,-10.664) B17(10.708,-10.664) B19(9.357,-10.664) B21(8.23,-10.664) B23(6.879,-10.664) B25(5.752,-10.664) B27(4.401,-10.664) B29(3.274,-10.664) B31(1.923,-10.664) B33(0.796,-10.664) B36(-0.555,-10.664) B38(-1.682,-10.664) B40(-3.033,-10.664) B42(-4.16,-10.664) B45(-5.511,-10.664) B47(-6.638,-10.664) B50(-7.989,-10.664) B52(-9.116,-10.664) B54(-10.467,-10.664) B56(-11.594,-10.664) B59(-12.945,-10.664) B61(-14.072,-10.664) B63(-15.423,-10.664) B65(-16.55,-10.664) B67(-17.901,-10.664) BA4(18.366,10.689) BA6(17.173,10.258) BA7(16.61,10.664) BA9(15.416,10.664) BA10(14.753,10.258) BA11(14.189,10.664) BA13(12.995,10.664) BA14(12.332,10.258) BA15(11.768,10.664) BA17(10.575,10.664) BA18(9.912,10.258) BA20(9.348,10.664) BA22(8.154,10.664) BA25(6.828,10.664) BA26(6.165,10.339) BA27(5.502,10.664) BA29(4.473,10.664) BA30(3.811,10.339) BA31(3.148,10.664) BA33(1.847,10.664) BA34(1.184,10.339) BA35(0.521,10.664) BA37(-0.507,10.664) BA38(-1.17,10.339) BA39(-1.833,10.664) BA42(-3.108,10.664) BA43(-3.771,10.339) BA44(-4.434,10.664) BA46(-5.463,10.664) BA47(-6.126,10.339) BA48(-6.789,10.664) BA50(-7.922,10.664) BA51(-8.585,10.339) BA52(-9.248,10.664) BA54(-10.276,10.664) BA55(-10.939,10.339) BA56(-11.602,10.664) BA59(-12.877,10.664) BA60(-13.54,10.339) BA61(-14.203,10.664) BA63(-15.232,10.664) BA64(-15.895,10.339) BA65(-16.558,10.664) BA66(-17.221,10.339) BA67(-17.901,10.664) BB5(17.786,11.314) BB6(17.173,10.989) BB7(16.61,11.314) BB9(15.416,11.314) BB10(14.753,10.989) BB11(14.189,11.314) BB13(12.995,11.314) BB14(12.332,10.989) BB15(11.768,11.314) BB17(10.575,11.314) BB18(9.912,10.989) BB20(9.348,11.314) BB22(8.154,11.314) BB23(7.466,10.908) BB25(6.828,11.314) BB26(6.165,10.989) BB27(5.502,11.314) BB29(4.473,11.314) BB30(3.811,10.989) BB31(3.148,11.314) BB32(2.485,10.908) BB33(1.847,11.314) BB34(1.184,10.989) BB35(0.521,11.314) BB37(-0.507,11.314) BB38(-1.17,10.989) BB39(-1.833,11.314) BB41(-2.471,10.908) BB42(-3.108,11.314) BB43(-3.771,10.989) BB44(-4.434,11.314) BB46(-5.463,11.314) BB47(-6.126,10.989) BB48(-6.789,11.314) BB50(-7.922,11.314) BB51(-8.585,10.989) BB52(-9.248,11.314) BB54(-10.276,11.314) BB55(-10.939,10.989) BB56(-11.602,11.314) BB57(-12.24,10.908) BB59(-12.877,11.314) BB60(-13.54,10.989) BB61(-14.203,11.314) BB63(-15.232,11.314) BB64(-15.895,10.989) BB65(-16.558,11.314) BB66(-17.221,10.989) BB67(-17.901,11.314)
  oval 0.343x0.254 smd: AA1(19.989,-0.511) AB1(20.314,0.152) AB2(19.664,0.152) AB3(19.014,0.152) AC1(19.989,0.815) AC2(19.339,0.815) AD1(20.314,1.478) AD2(19.664,1.478) AD3(19.014,1.478) AF1(19.989,2.141) AF70(-19.664,1.84) AF71(-20.314,1.84) AG1(20.314,2.804) AG2(19.664,2.804) AG3(19.014,2.804) AG70(-19.339,2.503) AG71(-19.989,2.503) AH1(19.989,3.467) AH2(19.339,3.467) AH68(-18.364,3.166) AH69(-19.014,3.166) AH70(-19.664,3.166) AH71(-20.314,3.166) AJ1(20.314,4.13) AJ2(19.664,4.13) AJ3(19.014,4.13) AK70(-19.989,3.829) AL1(19.989,4.793) AL68(-18.364,4.492) AL69(-19.014,4.492) AL70(-19.664,4.492) AL71(-20.314,4.492) AM1(20.314,5.456) AM2(19.664,5.456) AM3(19.014,5.456) AM70(-19.339,5.155) AM71(-19.989,5.155) AN1(19.989,6.119) AN2(19.339,6.119) AN70(-19.664,5.818) AN71(-20.314,5.818) AP1(20.314,6.782) AP2(19.664,6.782) AP3(19.014,6.782) AR70(-19.664,6.846) AR71(-20.314,6.846) AT1(19.989,7.445) AT70(-19.339,7.509) AT71(-19.989,7.509) AU1(20.314,8.108) AU2(19.664,8.108) AU3(19.014,8.108) AU68(-18.364,8.147) AU69(-19.014,8.172) AU70(-19.664,8.172) AU71(-20.314,8.172) AV1(20.314,8.828) AV2(19.364,8.799) AV71(-20.314,8.901) AW2(19.689,9.362) AW3(19.039,9.362) E70(-19.664,-9.009) E71(-20.314,-8.901) F1(19.989,-8.466) F70(-19.212,-8.32) F71(-19.862,-8.384) G1(20.314,-7.803) G2(19.664,-7.803) G3(19.014,-7.803) G70(-19.664,-7.759) G71(-20.314,-7.759) H1(19.989,-7.14) H2(19.339,-7.14) H70(-19.339,-7.096) H71(-19.989,-7.096) J1(20.314,-6.477) J2(19.664,-6.477) J3(19.014,-6.477) J69(-19.014,-6.433) J70(-19.664,-6.433) J71(-20.314,-6.433) K71(-19.989,-5.744) L1(19.989,-5.814) M1(20.314,-5.151) M2(19.664,-5.151) M3(19.014,-5.151) N1(19.989,-4.488) N2(19.339,-4.488) P1(20.314,-3.825) P2(19.664,-3.825) P3(19.014,-3.825) T1(19.989,-3.162) U1(20.314,-2.499) U2(19.664,-2.499) U3(19.014,-2.499) V1(19.989,-1.836) V2(19.339,-1.836) W1(20.314,-1.173) W2(19.664,-1.173) W3(19.014,-1.173)
C402-TO0D2H28
  custom 0.152x0.152 smd: 1(0,0.457) 2(0,-0.457)
C402H22
  custom 0.152x0.152 smd: 1(0,0.445) 2(0,-0.445)
C603H35
  custom 0.216x0.216 smd: 1(0,0.762) 2(0,-0.762)
C603H36
  custom 0.216x0.216 smd: 1(0,0.762) 2(0,-0.762)
C603H40
  custom 0.216x0.216 smd: 1(0,0.762) 2(0,-0.762)
C805H50
  rect 1.397x1.143 smd: 1(0,0.965) 2(0,-0.965)
C805H54
  rect 1.397x1.143 smd: 1(0,0.965) 2(0,-0.965)
C805H58
  rect 1.397x1.143 smd: 1(0,0.965) 2(0,-0.965)
C1206H75
  rect 1.651x1.27 smd: 1(0,1.397) 2(0,-1.397)
C1808H87
  rect 2.286x1.27 smd: 1(0,2.032) 2(0,-2.032)
CI1410M1HRL-NH
  rect 0.61x1.549 smd: 1(-4.5,3.325) 2(-3.5,3.325) 3(-2.5,3.325) 4(-1.5,3.325) 5(-0.5,3.325) 6(0.5,3.325) 7(1.5,3.325) 8(2.5,3.325) 9(3.5,3.325) 10(4.5,3.325)
  rect 0.61x1.194 smd: 11(-5.6,0) 12(5.6,0)
CI2505P1H00-LF-U
  round 1.422 hole 1.016: 1(-5,0) 2(-2.5,0) 3(0,0) 4(2.5,0) 5(5,0)
CT3528H79
  rect 2.286x2.286 smd: 1(0,1.905) 2(0,-1.905)
CT7343H75
  rect 2.413x2.286 smd: 1(0,3.15) 2(0,-3.15)
CT7343H83
  rect 2.413x2.286 smd: 1(0,3.15) 2(0,-3.15)
D402H24
  custom 0.14x0.14 smd: 1(0,0.445) 2(0,-0.445)
D1608-035030AKH28
  rect 0.559x0.991 smd: A(0,0.691) K(0,-0.691)
D4724AKH44
  rect 2.007x1.549 smd: A(0,2.221) K(0,-2.221)
DFN8F3-G2517H32
  rect 0.406x0.94 smd: 1(0.975,1.538) 2(0.325,1.538) 3(-0.325,1.538) 4(-0.975,1.538) 5(-0.975,-1.538)
  rect 0.025x0.025 smd: 6(-0.325,-1.538) 8(0.975,-1.538)
  custom 0.235x0.235 smd: 7(0.325,-1.538)
  rect 2.489x1.676 smd: 9(0,0)
DFN10G3-G265175H32
  rect 0.305x0.914 smd: 1(1,1.549) 2(0.5,1.549) 3(0,1.549) 4(-0.5,1.549) 5(-1,1.549) 6(-1,-1.549) 7(-0.5,-1.549) 8(0,-1.549) 9(0.5,-1.549) 10(1,-1.549)
  rect 2.642x1.753 smd: 11(0,0)
DFN10G2510H26
  rect 0.305x0.787 smd: 1(1,0.494) 5(-1,0.494) 6(-1,-0.494) 10(1,-0.494)
  rect 0.254x0.787 smd: 2(0.521,0.494) 4(-0.521,0.494) 7(-0.521,-0.494) 9(0.521,-0.494)
  rect 0.025x0.025 smd: 3(0,0.494)
  rect 0.406x1.753 smd: 8(0,-0.494)
DO214AAAK-1121H97
  rect 2.311x2.032 smd: A(0,2.322) K(0,-2.322)
ECAP-100D6D3H237
  rect 1.397x1.397 hole 0.991: 1(0,-1.27)
  round 1.397 hole 0.991: 2(0,1.27)
ECAP-100D6D3H375
  rect 1.397x1.397 hole 0.991: 1(0,-1.27)
  round 1.397 hole 0.991: 2(0,1.27)
FUSE-1608H22
  custom 0.216x0.216 smd: 1(0,0.762) 2(0,-0.762)
G6179HT0321-001
  rect 0.635x2.108 smd: 1(1.905,3.466) 2(0.635,3.466) 3(-0.635,3.466) 4(-1.905,3.466) 5(-1.905,-3.466) 6(-0.635,-3.466) 7(0.635,-3.466) 8(1.905,-3.466)
GAP-CLOSE-PWR-3
  rect 0.66x0.762 smd: 1(-0.305,0) 2(0.305,0)
GEN8D5X8R5X4D5-8-F-A
  round 0.254 hole 5.004x4.521 unplated: (0,0)
  round 0.864 hole 0.508: 1(3.136,1.664) 2(1.918,2.882) 3(-1.918,2.882) 4(-3.136,1.664) 5(-3.136,-1.664) 6(-1.918,-2.882) 7(1.918,-2.882) 8(3.136,-1.664)
GEN315R138-8-F-A-1
  round 0.254 hole 3.505 unplated: (0,0)
  round 0.864 hole 0.508: 1(2.667,1.54) 2(1.54,2.667) 3(-1.54,2.667) 4(-2.667,1.54) 5(-2.667,-1.54) 6(-1.54,-2.667) 7(1.54,-2.667) 8(2.667,-1.54)
GEN315R138-8-F-A-2-S
  round 0.254 hole 3.505 unplated: (0,0)
  round 0.864 hole 0.508: 1(2.667,1.54) 2(1.54,2.667) 3(-1.54,2.667) 4(-2.667,1.54) 5(-2.667,-1.54) 6(-1.54,-2.667) 7(1.54,-2.667) 8(2.667,-1.54)
GEN315R178-8-F-A-1
  round 0.254 hole 4.521 unplated: (0,0)
  round 0.864 hole 0.508: 1(2.882,1.664) 2(1.664,2.882) 3(-1.664,2.882) 4(-2.882,1.664) 5(-2.882,-1.664) 6(-1.664,-2.882) 7(1.664,-2.882) 8(2.882,-1.664)
HF1804H
  round 1.651 hole 1.016: 1(-3.81,0) 2(-1.27,0) 3(1.27,0) 4(3.81,0)
HL5507F
  round 0.254 hole 1.016 unplated: (5,0)
  round 1.321 hole 0.914: 1(-6,-1) 2(-6,1) 3(-4,-1) 4(-4,1) 5(-2,-1) 6(-2,1) 7(0,-1) 8(0,1) 9(2,-1) 10(2,1) 11(4,-1) 12(4,1) 13(6,-1) 14(6,1)
HOLE237R158
  round 6.02 hole 4.013: 1(0,0)
JAC331-0140A8B-9H
  oval 1.321x2.235 hole 0.61x1.524: 1(-4.95,2.1) 4(5,2.1) P(3.25,-3.15) Q(-3.9,-2.1)
  oval 2.235x1.422 hole 1.524x0.711: 5(0,3.17)
JPDA3B1-V4501-7F
  oval 1.422x2.413 hole 0.711x1.702: 1(-1.1,1.46)
  oval 1.473x2.413 hole 0.762x1.702: 2(2.5,0) 5(4.375,0.7) 7(-4.375,0.7)
  oval 1.524x2.413 hole 0.813x1.702: 3(0,-1.13)
  oval 2.413x1.473 hole 1.702x0.762: 4(1.35,3.375) 6(1.35,-3.375)
L402H22
  custom 0.14x0.14 smd: 1(0,0.445) 2(0,-0.445)
L402H24
  custom 0.14x0.14 smd: 1(0,0.445) 2(0,-0.445)
L603H38
  custom 0.216x0.216 smd: 1(0,0.762) 2(0,-0.762)
L8080-6020H158
  rect 6.502x3.15 smd: 1(0,2.944) 2(0,-2.944)
L20125H42
  rect 1.397x1.143 smd: 1(0,0.965) 2(0,-0.965)
L112100-2030H158
  rect 3.505x3.15 smd: 1(0,4.769) 2(0,-4.769)
L115100-2H158
  rect 3.759x3.251 smd: 1(0,5.022) 2(0,-5.022)
L115100-2030H158
  rect 3.251x2.896 smd: 1(0,4.944) 2(0,-4.944)
L125100-4P-1H24
  rect 0.762x0.432 smd: 1(0.625,0.341) 2(-0.625,0.341) 3(-0.625,-0.341) 4(0.625,-0.341)
L125100-4P-1H28
  rect 0.762x0.432 smd: 1(0.625,0.341) 2(-0.625,0.341) 3(-0.625,-0.341) 4(0.625,-0.341)
L125100-4P-1H36
  rect 0.762x0.432 smd: 1(0.625,0.341) 2(-0.625,0.341) 3(-0.625,-0.341) 4(0.625,-0.341)
L125100-4P-1H37
  rect 0.762x0.432 smd: 1(0.625,0.341) 2(-0.625,0.341) 3(-0.625,-0.341) 4(0.625,-0.341)
L125100-4P-4H24
  rect 0.762x0.432 smd: 1(-0.625,0.341) 2(0.625,0.341) 3(0.625,-0.341) 4(-0.625,-0.341)
L125100-4P-4H28
  rect 0.762x0.432 smd: 1(-0.625,0.341) 2(0.625,0.341) 3(0.625,-0.341) 4(-0.625,-0.341)
L686647-127318H119
  rect 3.683x2.413 smd: 1(0,2.986) 2(0,-2.986)
LED1608AKH30
  custom 0.216x0.216 smd: A(0,0.762) K(0,-0.762)
LFDFN8G2-G1309H40
  rect 0.305x0.483 smd: 1(0.75,0.911) 2(0.25,0.911) 3(-0.25,0.911) 4(-0.75,0.911) 5(-0.75,-0.911) 6(-0.25,-0.911) 7(0.25,-0.911) 8(0.75,-0.911)
  rect 1.295x0.889 smd: 9(0,0)
LFQFN24G4-G2D9H40
  rect 0.305x0.508 smd: 1(1.25,1.905) 2(0.75,1.905) 3(0.25,1.905) 4(-0.25,1.905) 5(-0.75,1.905) 6(-1.25,1.905) 13(-1.25,-1.905) 14(-0.75,-1.905) 15(-0.25,-1.905) 16(0.25,-1.905) 17(0.75,-1.905) 18(1.25,-1.905)
  rect 0.508x0.305 smd: 7(-1.905,1.25) 8(-1.905,0.75) 9(-1.905,0.25) 10(-1.905,-0.25) 11(-1.905,-0.75) 12(-1.905,-1.25) 19(1.905,-1.25) 20(1.905,-0.75) 21(1.905,-0.25) 22(1.905,0.25) 23(1.905,0.75) 24(1.905,1.25)
  rect 2.896x2.896 smd: 25(0,0)
LFQFN52J6-G4D8-1H40
  rect 0.203x0.533 smd: 1(2.4,2.911) 13(-2.4,2.911) 27(-2.4,-2.911) 39(2.4,-2.911)
  rect 0.203x0.584 smd: 2(2,2.911) 3(1.6,2.911) 4(1.2,2.911) 5(0.8,2.911) 6(0.4,2.911) 7(0,2.911) 8(-0.4,2.911) 9(-0.8,2.911) 10(-1.2,2.911) 11(-1.6,2.911) 12(-2,2.911) 28(-2,-2.911) 29(-1.6,-2.911) 30(-1.2,-2.911) 31(-0.8,-2.911) 32(-0.4,-2.911) 33(0,-2.911) 34(0.4,-2.911) 35(0.8,-2.911) 36(1.2,-2.911) 37(1.6,-2.911) 38(2,-2.911)
  rect 0.533x0.203 smd: 14(-2.911,2.4) 26(-2.911,-2.4) 40(2.911,-2.4) 52(2.911,2.4)
  rect 0.584x0.203 smd: 15(-2.911,2) 16(-2.911,1.6) 17(-2.911,1.2) 18(-2.911,0.8) 19(-2.911,0.4) 20(-2.911,0) 21(-2.911,-0.4) 22(-2.911,-0.8) 23(-2.911,-1.2) 24(-2.911,-1.6) 25(-2.911,-2) 41(2.911,-2) 42(2.911,-1.6) 43(2.911,-1.2) 44(2.911,-0.8) 45(2.911,-0.4) 46(2.911,0) 47(2.911,0.4) 48(2.911,0.8) 49(2.911,1.2) 50(2.911,1.6) 51(2.911,2)
  rect 4.801x4.801 smd: 53(0,0)
LQFP128H63
  rect 0.203x1.524 smd: 1(6.2,7.747) 2(5.8,7.747) 3(5.4,7.747) 4(5,7.747) 5(4.6,7.747) 6(4.2,7.747) 7(3.8,7.747) 8(3.4,7.747) 9(3,7.747) 10(2.6,7.747) 11(2.2,7.747) 12(1.8,7.747) 13(1.4,7.747) 14(0.999,7.747) 15(0.599,7.747) 16(0.199,7.747) 17(-0.199,7.747) 18(-0.599,7.747) 19(-0.999,7.747) 20(-1.4,7.747) 21(-1.8,7.747) 22(-2.2,7.747) 23(-2.6,7.747) 24(-3,7.747) 25(-3.4,7.747) 26(-3.8,7.747) 27(-4.2,7.747) 28(-4.6,7.747) 29(-5,7.747) 30(-5.4,7.747) 31(-5.8,7.747) 32(-6.2,7.747) 65(-6.2,-7.747) 66(-5.8,-7.747) 67(-5.4,-7.747) 68(-5,-7.747) 69(-4.6,-7.747) 70(-4.2,-7.747) 71(-3.8,-7.747) 72(-3.4,-7.747) 73(-3,-7.747) 74(-2.6,-7.747) 75(-2.2,-7.747) 76(-1.8,-7.747) 77(-1.4,-7.747) 78(-0.999,-7.747) 79(-0.599,-7.747) 80(-0.199,-7.747) 81(0.199,-7.747) 82(0.599,-7.747) 83(0.999,-7.747) 84(1.4,-7.747) 85(1.8,-7.747) 86(2.2,-7.747) 87(2.6,-7.747) 88(3,-7.747) 89(3.4,-7.747) 90(3.8,-7.747) 91(4.2,-7.747) 92(4.6,-7.747) 93(5,-7.747) 94(5.4,-7.747) 95(5.8,-7.747) 96(6.2,-7.747)
  rect 1.524x0.203 smd: 33(-7.747,6.2) 34(-7.747,5.8) 35(-7.747,5.4) 36(-7.747,5) 37(-7.747,4.6) 38(-7.747,4.2) 39(-7.747,3.8) 40(-7.747,3.4) 41(-7.747,3) 42(-7.747,2.6) 43(-7.747,2.2) 44(-7.747,1.8) 45(-7.747,1.4) 46(-7.747,0.999) 47(-7.747,0.599) 48(-7.747,0.199) 49(-7.747,-0.199) 50(-7.747,-0.599) 51(-7.747,-0.999) 52(-7.747,-1.4) 53(-7.747,-1.8) 54(-7.747,-2.2) 55(-7.747,-2.6) 56(-7.747,-3) 57(-7.747,-3.4) 58(-7.747,-3.8) 59(-7.747,-4.2) 60(-7.747,-4.6) 61(-7.747,-5) 62(-7.747,-5.4) 63(-7.747,-5.8) 64(-7.747,-6.2) 97(7.747,-6.2) 98(7.747,-5.8) 99(7.747,-5.4) 100(7.747,-5) 101(7.747,-4.6) 102(7.747,-4.2) 103(7.747,-3.8) 104(7.747,-3.4) 105(7.747,-3) 106(7.747,-2.6) 107(7.747,-2.2) 108(7.747,-1.8) 109(7.747,-1.4) 110(7.747,-0.999) 111(7.747,-0.599) 112(7.747,-0.199) 113(7.747,0.199) 114(7.747,0.599) 115(7.747,0.999) 116(7.747,1.4) 117(7.747,1.8) 118(7.747,2.2) 119(7.747,2.6) 120(7.747,3) 121(7.747,3.4) 122(7.747,3.8) 123(7.747,4.2) 124(7.747,4.6) 125(7.747,5) 126(7.747,5.4) 127(7.747,5.8) 128(7.747,6.2)
LVDFH-02004-TP00
  rect 0.305x1.295 smd: 1(-4.75,-1.95) 2(-4.25,-1.95) 3(-3.75,-1.95) 4(-3.25,-1.95) 5(-2.75,-1.95) 6(-2.25,-1.95) 7(-1.75,-1.95) 8(-1.25,-1.95) 9(-0.75,-1.95) 10(-0.25,-1.95) 11(0.25,-1.95) 12(0.75,-1.95) 13(1.25,-1.95) 14(1.75,-1.95) 15(2.25,-1.95) 16(2.75,-1.95) 17(3.25,-1.95) 18(3.75,-1.95) 19(4.25,-1.95) 20(4.75,-1.95)
  rect 1.194x2.692 smd: 21(-7.15,0) 22(7.15,0)
  rect 2.261x1.346 smd: 23(3.9,1.975) 24(0,1.975) 25(-3.9,1.975)
MSOP8-1H44
  rect 0.356x1.524 smd: 1(-0.975,-2.055) 2(-0.325,-2.055) 3(0.325,-2.055) 4(0.975,-2.055) 5(0.975,2.055) 6(0.325,2.055) 7(-0.325,2.055) 8(-0.975,2.055)
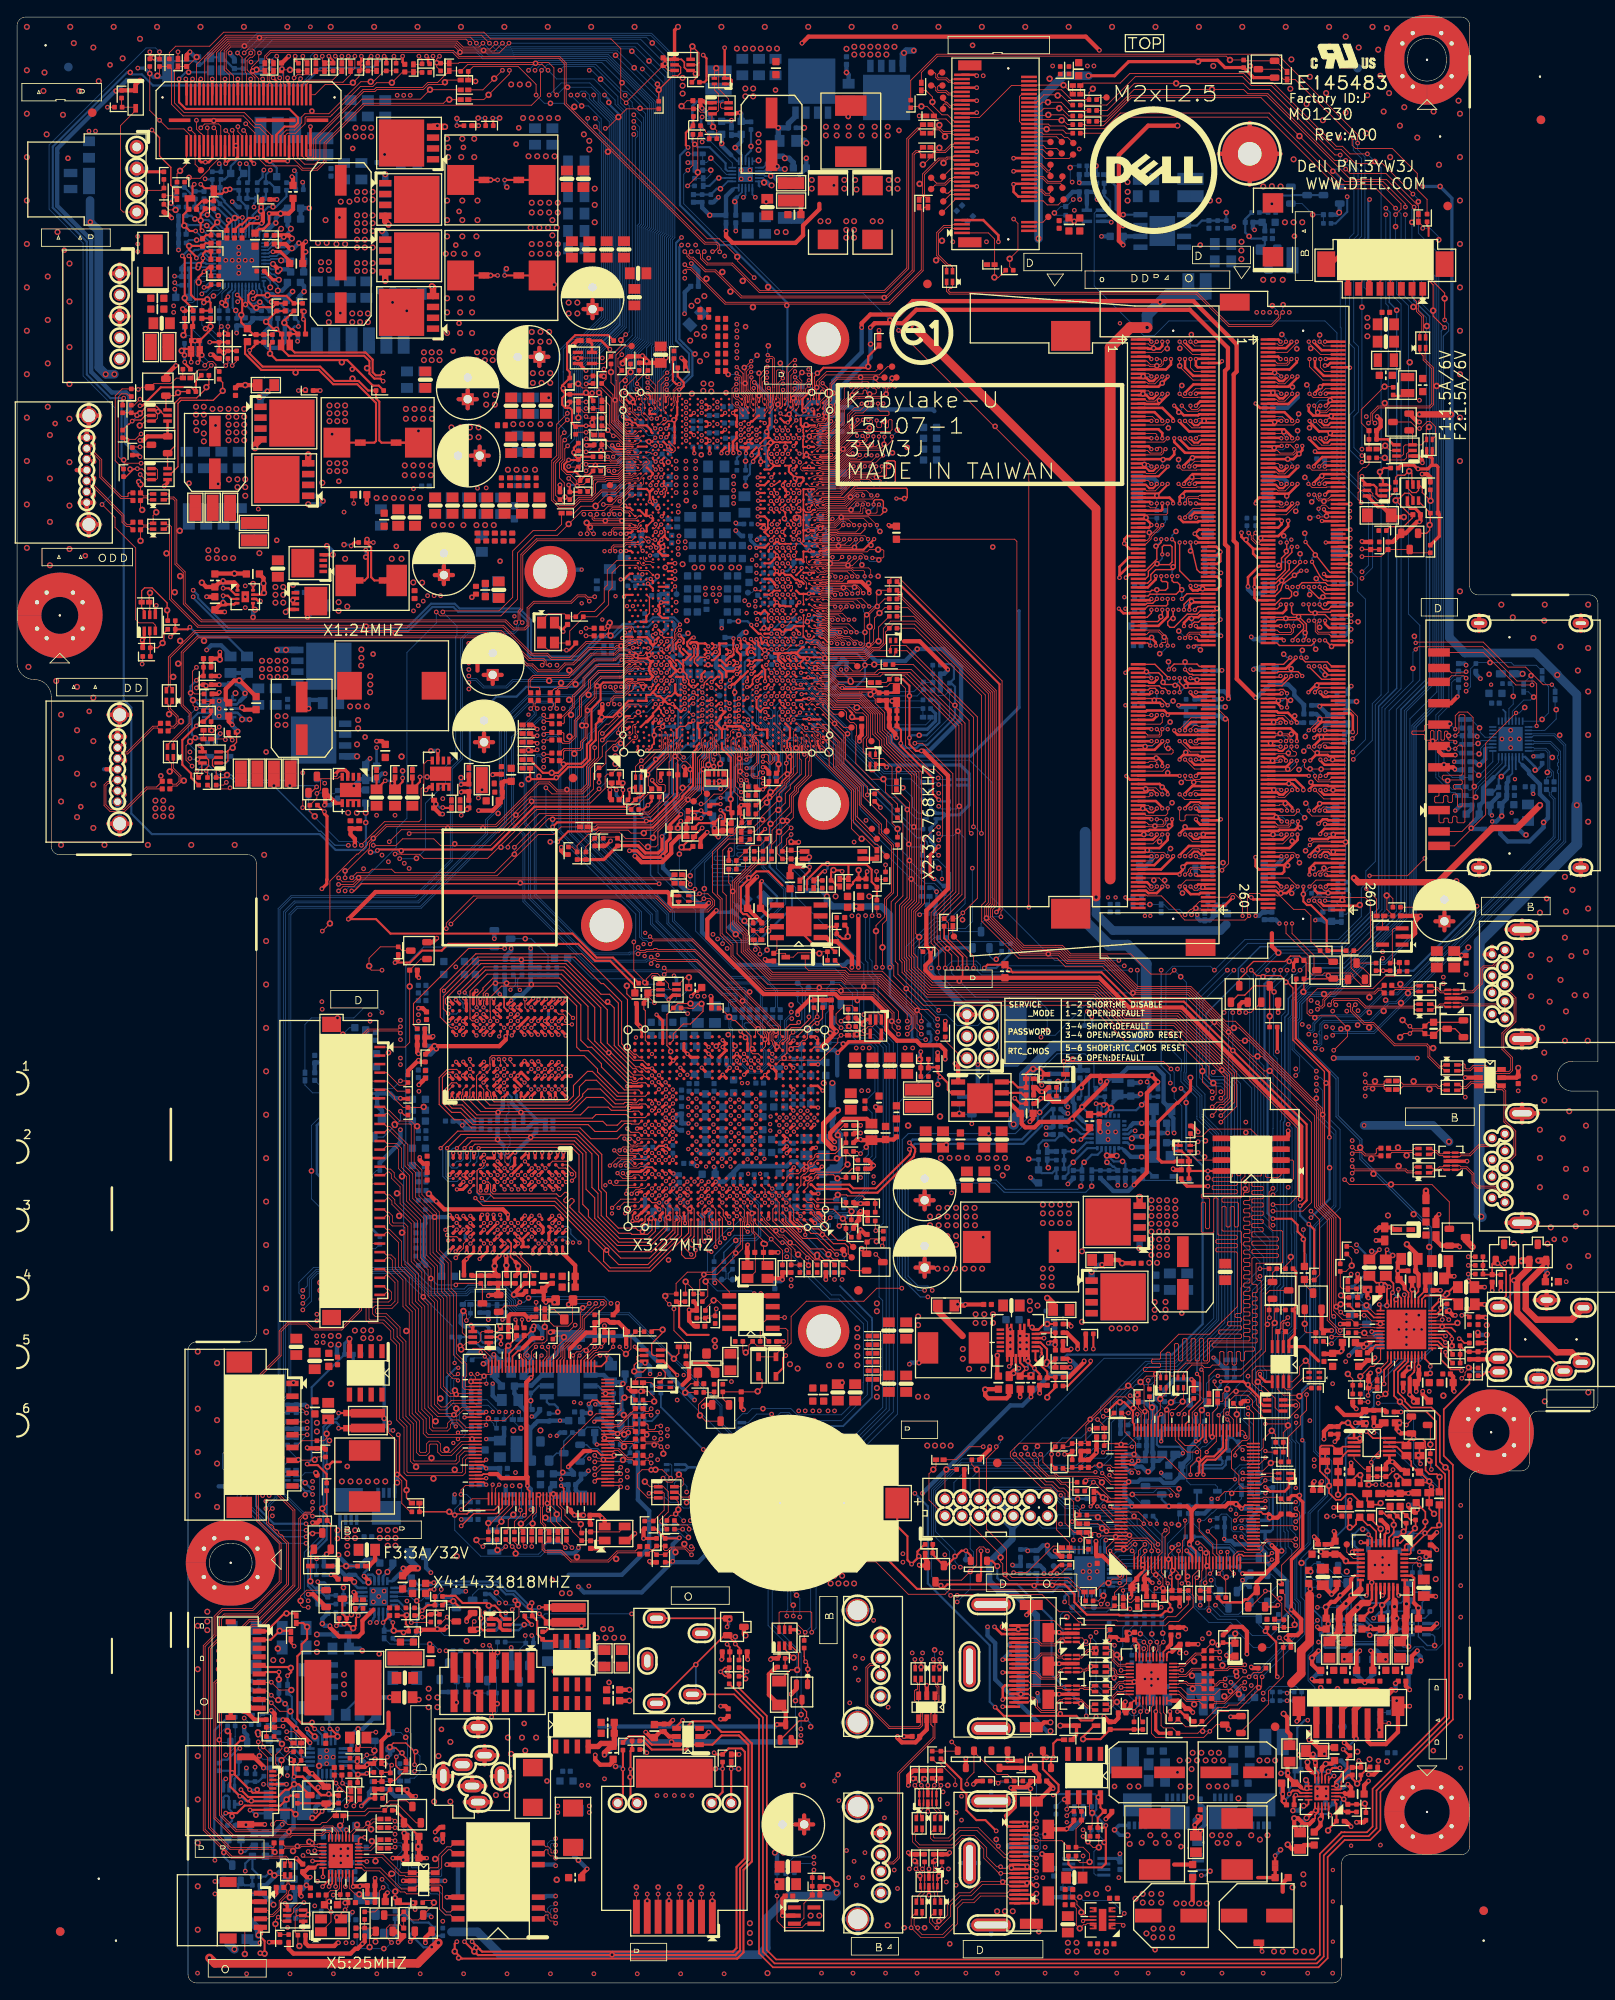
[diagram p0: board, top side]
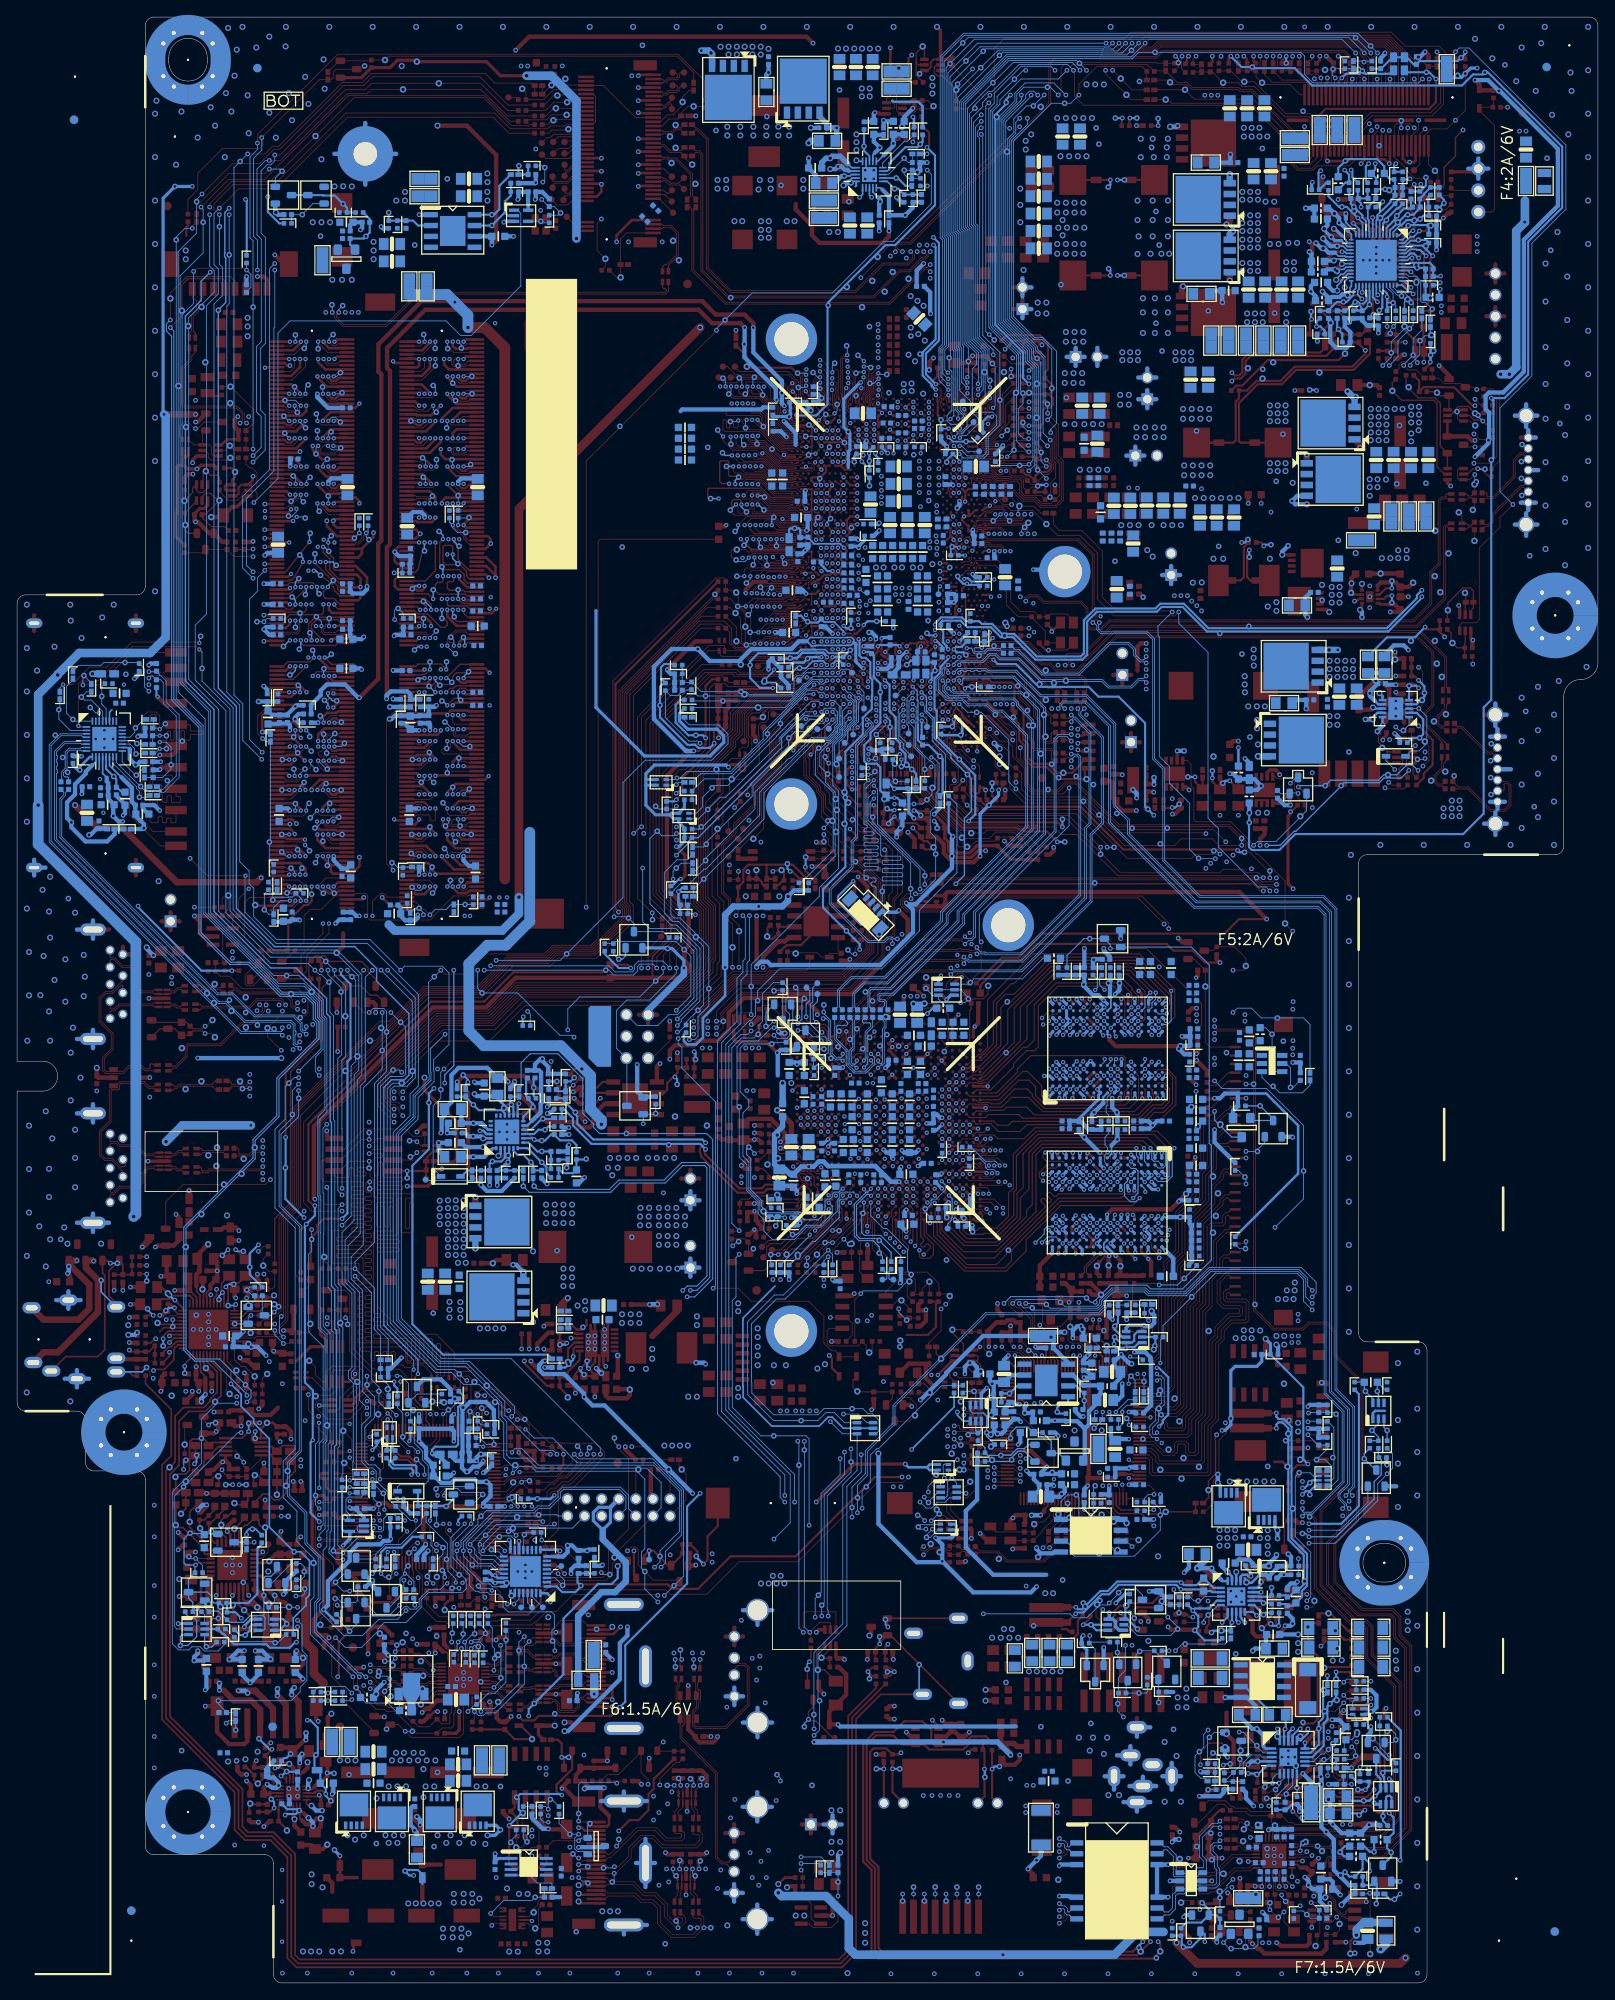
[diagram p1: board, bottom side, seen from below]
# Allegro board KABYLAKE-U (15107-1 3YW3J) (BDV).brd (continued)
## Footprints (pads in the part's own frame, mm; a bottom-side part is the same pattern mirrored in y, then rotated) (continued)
MSOP10H44
  rect 0.305x1.524 smd: 1(-0.999,-2.07) 2(-0.5,-2.07) 3(0,-2.07) 4(0.5,-2.07) 5(0.999,-2.07) 6(0.999,2.07) 7(0.5,2.07) 8(0,2.07) 9(-0.5,2.07) 10(-0.999,2.07)
NTC-402H22-U
  custom 0.14x0.14 smd: 1(0,0.445) 2(0,-0.445)
NTC-603H38
  custom 0.216x0.216 smd: 1(0,0.762) 2(0,-0.762)
OSC-3225-4P-3H36
  rect 1.397x0.914 smd: 1(-1.171,-0.825) 2(1.171,-0.825) 3(1.171,0.825) 4(-1.171,0.825)
OSC-3225-4P-4H30
  rect 1.397x1.067 smd: 1(-1.171,-0.756) 2(1.171,-0.756) 3(1.171,0.756) 4(-1.171,0.756)
OSC-3225-4P-4H36
  rect 1.397x1.067 smd: 1(-1.171,-0.756) 2(1.171,-0.756) 3(1.171,0.756) 4(-1.171,0.756)
PAD-60P
  round 0.254 hole 1.016 unplated: (-10.066,2.67) (10.066,2.67)
  rect 0.305x2.515 smd: 1(-7.25,-2.99) 2(-7.25,2.99) 3(-6.75,-2.99) 4(-6.75,2.99) 5(-6.25,-2.99) 6(-6.25,2.99) 7(-5.751,-2.99) 8(-5.751,2.99) 9(-5.25,-2.99) 10(-5.25,2.99) 11(-4.75,-2.99) 12(-4.75,2.99) 13(-4.249,-2.99) 14(-4.249,2.99) 15(-3.75,-2.99) 16(-3.75,2.99) 17(-3.25,-2.99) 18(-3.25,2.99) 19(-2.75,-2.99) 20(-2.75,2.99) 21(-2.25,-2.99) 22(-2.25,2.99) 23(-1.75,-2.99) 24(-1.75,2.99) 25(-1.25,-2.99) 26(-1.25,2.99) 27(-0.751,-2.99) 28(-0.751,2.99) 29(-0.25,-2.99) 30(-0.25,2.99) 31(0.25,-2.99) 32(0.25,2.99) 33(0.751,-2.99) 34(0.751,2.99) 35(1.25,-2.99) 36(1.25,2.99) 37(1.75,-2.99) 38(1.75,2.99) 39(2.25,-2.99) 40(2.25,2.99) 41(2.75,-2.99) 42(2.75,2.99) 43(3.25,-2.99) 44(3.25,2.99) 45(3.75,-2.99) 46(3.75,2.99) 47(4.249,-2.99) 48(4.249,2.99) 49(4.75,-2.99) 50(4.75,2.99) 51(5.25,-2.99) 52(5.25,2.99) 53(5.751,-2.99) 54(5.751,2.99) 55(6.25,-2.99) 56(6.25,2.99) 57(6.75,-2.99) 58(6.75,2.99) 59(7.25,-2.99) 60(7.25,2.99)
  rect 2.54x0.432 smd: 61(-8.065,0) 64(8.065,0)
  rect 4.699x0.432 smd: 62(-3.175,0) 63(3.175,0)
POLYSW-2114H30
  rect 1.6x0.965 smd: 1(0,0.94) 2(0,-0.94)
PPAK-8P-2H45
  rect 0.406x1.168 smd: 1(-0.975,-2.351) 2(-0.325,-2.351) 3(0.325,-2.351) 4(0.975,-2.351)
  rect 3.404x2.769 smd: 5(0,0)
  rect 0.025x0.025 smd: 6(1.029,0.902) 7(0.013,0.902) 8(-0.991,0.902)
PPAK-8P-3232H36
  rect 0.406x0.914 smd: 1(-0.975,-2.396) 2(-0.325,-2.396) 3(0.325,-2.396) 4(0.975,-2.396)
  rect 3.353x2.692 smd: 5(0,0)
  rect 0.025x0.025 smd: 6(0.65,0.838) 7(0,0.838) 8(-0.65,0.838)
PPAK-8P-5262H40
  rect 0.762x1.448 smd: 1(-1.905,-3.684) 2(-0.635,-3.684) 3(0.635,-3.684) 4(1.905,-3.684)
  rect 5.512x5.309 smd: 5(0,0)
  rect 0.025x0.025 smd: 6(0.635,2.146) 7(-0.635,2.146) 8(-1.905,2.146)
QFN20-G1D75H32
  rect 0.203x0.914 smd: 1(0.8,1.551) 2(0.4,1.551) 3(0,1.551) 4(-0.4,1.551) 5(-0.8,1.551) 11(-0.8,-1.551) 12(-0.4,-1.551) 13(0,-1.551) 14(0.4,-1.551) 15(0.8,-1.551)
  rect 0.914x0.203 smd: 6(-1.551,0.8) 7(-1.551,0.4) 8(-1.551,0) 9(-1.551,-0.4) 10(-1.551,-0.8) 16(1.551,-0.8) 17(1.551,-0.4) 18(1.551,0) 19(1.551,0.4) 20(1.551,0.8)
  rect 1.753x1.753 smd: 21(0,0)
QFN20-G2D1H32
  rect 0.305x1.092 smd: 1(0.999,1.956) 5(-0.999,1.956) 11(-0.999,-1.956) 15(0.999,-1.956)
  rect 0.305x1.143 smd: 2(0.5,1.93) 3(0,1.93) 4(-0.5,1.93) 12(-0.5,-1.93) 13(0,-1.93) 14(0.5,-1.93)
  rect 1.092x0.305 smd: 6(-1.956,0.999) 10(-1.956,-0.999) 16(1.956,-0.999) 20(1.956,0.999)
  rect 1.143x0.305 smd: 7(-1.93,0.5) 8(-1.93,0) 9(-1.93,-0.5) 17(1.93,-0.5) 18(1.93,0) 19(1.93,0.5)
  rect 2.108x2.108 smd: 21(0,0)
QFN20G3D5-G2D15H40
  rect 0.305x0.914 smd: 1(1,1.801) 5(-1,1.801) 11(-1,-1.801) 15(1,-1.801)
  rect 0.305x0.965 smd: 2(0.5,1.775) 3(0,1.775) 4(-0.5,1.775) 12(-0.5,-1.775) 13(0,-1.775) 14(0.5,-1.775)
  rect 0.914x0.305 smd: 6(-1.801,1) 10(-1.801,-1) 16(1.801,-1) 20(1.801,1)
  rect 0.965x0.305 smd: 7(-1.775,0.5) 8(-1.775,0) 9(-1.775,-0.5) 17(1.775,-0.5) 18(1.775,0) 19(1.775,0.5)
  rect 2.159x2.159 smd: 21(0,0)
QFN23G4-G2P-1H42
  rect 0.305x0.914 smd: 1(1.25,2.051) 2(0.75,2.051) 3(0.25,2.051) 4(-0.25,2.051) 5(-0.75,2.051) 6(-1.25,2.051)
  rect 0.914x0.305 smd: 7(-2.051,1.25) 18(2.051,-1.25) 19(2.051,-0.75) 20(2.051,-0.25) 21(2.051,0.25) 22(2.051,0.75) 23(2.051,1.25)
  rect 0.025x0.025 smd: 8(-2.051,0.75) 9(-2.051,0.25) 10(-2.051,-0.75) 11(-2.051,-1.25)
  rect 0.305x0.889 smd: 12(-1.25,-2.063) 13(-0.75,-2.063) 14(-0.25,-2.063) 15(0.25,-2.063) 16(0.75,-2.063) 17(1.25,-2.063)
  custom 0.36x0.36 smd: 24(0,0.67)
  custom 0.251x0.251 smd: 25(0,-0.926)
QFN32-G3D55H40
  rect 0.305x0.838 smd: 1(1.75,2.591) 8(-1.75,2.591) 17(-1.75,-2.591) 24(1.75,-2.591)
  rect 0.305x0.94 smd: 2(1.25,2.54) 3(0.751,2.54) 4(0.25,2.54) 5(-0.25,2.54) 6(-0.751,2.54) 7(-1.25,2.54) 18(-1.25,-2.54) 19(-0.751,-2.54) 20(-0.25,-2.54) 21(0.25,-2.54) 22(0.751,-2.54) 23(1.25,-2.54)
  rect 0.838x0.305 smd: 9(-2.591,1.75) 16(-2.591,-1.75) 25(2.591,-1.75) 32(2.591,1.75)
  rect 0.94x0.305 smd: 10(-2.54,1.25) 11(-2.54,0.751) 12(-2.54,0.25) 13(-2.54,-0.25) 14(-2.54,-0.751) 15(-2.54,-1.25) 26(2.54,-1.25) 27(2.54,-0.751) 28(2.54,-0.25) 29(2.54,0.25) 30(2.54,0.751) 31(2.54,1.25)
  rect 3.531x3.531 smd: 33(0,0)
QFN32G5-G3D6H32
  rect 0.305x0.914 smd: 1(1.75,2.551) 8(-1.75,2.551) 17(-1.75,-2.551) 24(1.75,-2.551)
  rect 0.305x0.991 smd: 2(1.25,2.513) 3(0.75,2.513) 4(0.25,2.513) 5(-0.25,2.513) 6(-0.75,2.513) 7(-1.25,2.513) 18(-1.25,-2.513) 19(-0.75,-2.513) 20(-0.25,-2.513) 21(0.25,-2.513) 22(0.75,-2.513) 23(1.25,-2.513)
  rect 0.914x0.305 smd: 9(-2.551,1.75) 16(-2.551,-1.75) 25(2.551,-1.75) 32(2.551,1.75)
  rect 0.991x0.305 smd: 10(-2.513,1.25) 11(-2.513,0.75) 12(-2.513,0.25) 13(-2.513,-0.25) 14(-2.513,-0.75) 15(-2.513,-1.25) 26(2.513,-1.25) 27(2.513,-0.75) 28(2.513,-0.25) 29(2.513,0.25) 30(2.513,0.75) 31(2.513,1.25)
  rect 3.607x3.607 smd: 33(0,0)
QFN32J4-G2D85H36
  rect 0.203x0.864 smd: 1(1.4,2.085) 2(1,2.085) 3(0.6,2.085) 4(0.2,2.085) 5(-0.2,2.085) 6(-0.6,2.085) 7(-1,2.085) 8(-1.4,2.085) 17(-1.4,-2.085) 18(-1,-2.085) 19(-0.6,-2.085) 20(-0.2,-2.085) 21(0.2,-2.085) 22(0.6,-2.085) 23(1,-2.085) 24(1.4,-2.085)
  rect 0.864x0.203 smd: 9(-2.085,1.4) 10(-2.085,1) 11(-2.085,0.6) 12(-2.085,0.2) 13(-2.085,-0.2) 14(-2.085,-0.6) 15(-2.085,-1) 16(-2.085,-1.4) 25(2.085,-1.4) 26(2.085,-1) 27(2.085,-0.6) 28(2.085,-0.2) 29(2.085,0.2) 30(2.085,0.6) 31(2.085,1) 32(2.085,1.4)
  rect 2.845x2.845 smd: 33(0,0)
QFN40J5-G3D65H32
  rect 0.203x0.94 smd: 1(1.8,2.538) 10(-1.8,2.538) 21(-1.8,-2.538) 30(1.8,-2.538)
  rect 0.203x0.965 smd: 2(1.4,2.526) 3(1,2.526) 4(0.6,2.526) 5(0.2,2.526) 6(-0.2,2.526) 7(-0.6,2.526) 8(-1,2.526) 9(-1.4,2.526) 22(-1.4,-2.526) 23(-1,-2.526) 24(-0.6,-2.526) 25(-0.2,-2.526) 26(0.2,-2.526) 27(0.6,-2.526) 28(1,-2.526) 29(1.4,-2.526)
  rect 0.94x0.203 smd: 11(-2.538,1.8) 20(-2.538,-1.8) 31(2.538,-1.8) 40(2.538,1.8)
  rect 0.965x0.203 smd: 12(-2.526,1.4) 13(-2.526,1) 14(-2.526,0.6) 15(-2.526,0.2) 16(-2.526,-0.2) 17(-2.526,-0.6) 18(-2.526,-1) 19(-2.526,-1.4) 32(2.526,-1.4) 33(2.526,-1) 34(2.526,-0.6) 35(2.526,-0.2) 36(2.526,0.2) 37(2.526,0.6) 38(2.526,1) 39(2.526,1.4)
  rect 3.658x3.658 smd: 41(0,0)
QFN48J6-G465H40
  rect 0.203x0.965 smd: 1(2.2,3.025) 2(1.8,3.025) 3(1.4,3.025) 4(1,3.025) 5(0.6,3.025) 6(0.2,3.025) 7(-0.2,3.025) 8(-0.6,3.025) 9(-1,3.025) 10(-1.4,3.025) 11(-1.8,3.025) 12(-2.2,3.025) 25(-2.2,-3.025) 26(-1.8,-3.025) 27(-1.4,-3.025) 28(-1,-3.025) 29(-0.6,-3.025) 30(-0.2,-3.025) 31(0.2,-3.025) 32(0.6,-3.025) 33(1,-3.025) 34(1.4,-3.025) 35(1.8,-3.025) 36(2.2,-3.025)
  rect 0.965x0.203 smd: 13(-3.025,2.2) 14(-3.025,1.8) 15(-3.025,1.4) 16(-3.025,1) 17(-3.025,0.6) 18(-3.025,0.2) 19(-3.025,-0.2) 20(-3.025,-0.6) 21(-3.025,-1) 22(-3.025,-1.4) 23(-3.025,-1.8) 24(-3.025,-2.2) 37(3.025,-2.2) 38(3.025,-1.8) 39(3.025,-1.4) 40(3.025,-1) 41(3.025,-0.6) 42(3.025,-0.2) 43(3.025,0.2) 44(3.025,0.6) 45(3.025,1) 46(3.025,1.4) 47(3.025,1.8) 48(3.025,2.2)
  rect 4.648x4.648 smd: 49(0,0)
R402H14
  custom 0.14x0.14 smd: 1(0,0.445) 2(0,-0.445)
R402H16
  custom 0.14x0.14 smd: 1(0,0.445) 2(0,-0.445)
R603H22
  custom 0.216x0.216 smd: 1(0,0.762) 2(0,-0.762)
R603H24
  custom 0.216x0.216 smd: 1(0,0.762) 2(0,-0.762)
R805H24
  rect 1.397x1.143 smd: 1(0,0.965) 2(0,-0.965)
R1206H26
  rect 1.651x1.27 smd: 1(0,1.397) 2(0,-1.397)
R1206H28
  rect 1.651x1.27 smd: 1(0,1.397) 2(0,-1.397)
R3720H40
  rect 4.013x1.041 smd: 1(0,0.867) 2(0,-0.867)
SC70-5H44
  rect 0.406x1.219 smd: 1(0.65,0.826) 2(0,0.826) 3(-0.65,0.826) 4(-0.65,-0.826) 5(0.65,-0.826)
SE3116H241
  rect 1.626x3.099 smd: 1(0,2.654) 2(0,-2.654)
SE361414H241
  rect 1.372x3.607 smd: 1(0,2.499) 2(0,-2.499)
SKT-HDMI22-150077
  rect 0.305x2.007 smd: 1(4.21,3.37) 2(3.71,3.37) 3(3.21,3.37) 4(2.71,3.37) 5(2.21,3.37) 6(1.71,3.37) 7(1.21,3.37) 8(0.71,3.37) 9(0.21,3.37) 10(-0.29,3.37) 11(-0.79,3.37) 12(-1.29,3.37) 13(-1.79,3.37) 14(-2.29,3.37) 15(-2.79,3.37) 16(-3.29,3.37) 17(-3.79,3.37) 18(-4.29,3.37) 19(-4.79,3.37)
  oval 4.928x1.524 hole 4.216x0.813: 20(0,-2.53)
  oval 1.524x4.674 hole 0.813x3.962: 21(-7.25,0) 22(7.25,0)
SKT-USB6-135063
  round 1.346 hole 0.94: 1(3.5,-2.71) 2(1,-2.71) 3(-1,-2.71) 4(-3.5,-2.71)
  round 2.718 hole 2.311: 5(6.57,0) 6(-6.57,0)
SKT-USB11-138165-1
  round 1.067 hole 0.711: 1(3.5,3.5) 2(1,3.5) 3(-1,3.5) 4(-3.5,3.5) 5(-4,2) 6(-2,2) 7(0,2) 8(2,2) 9(4,2)
  oval 1.422x3.023 hole 0.711x2.311: 10(-6.4,0) 11(6.4,0)
SLP2510P8-1H22
  rect 0.305x0.762 smd: 1(-1,-0.5) 5(1,-0.5) 6(1,0.5) 10(-1,0.5)
  rect 0.203x0.762 smd: 2(-0.5,-0.5) 4(0.5,-0.5) 7(0.5,0.5) 9(-0.5,0.5)
  rect 0.406x0.762 smd: 3(0,-0.5) 8(0,0.5)
SMD49-6914-0403H56
  rect 1.168x0.559 smd: 1(-3.38,-0.427) 2(3.38,-0.427) 3(3.38,0.427) 4(-3.38,0.427)
SMD-ARES4H18
  rect 0.356x0.66 smd: 1(-0.325,-0.599) 2(0.325,-0.599) 3(0.325,0.599) 4(-0.325,0.599)
SOD323AKH38
  rect 0.559x1.016 smd: A(0,1.143) K(0,-1.143)
SOD323AKH42
  rect 0.559x1.016 smd: A(0,1.143) K(0,-1.143)
SOD523AKH28
  rect 0.559x1.016 smd: A(0,0.762) K(0,-0.762)
SOD882-10D6-1H20
  custom 0.114x0.114 smd: 1(0,0.445) 2(0,-0.445)
SOIC8-1H86
  rect 0.635x1.651 smd: 1(-1.905,-3.493) 2(-0.635,-3.493) 3(0.635,-3.493) 4(1.905,-3.493) 5(1.905,3.493) 6(0.635,3.493) 7(-0.635,3.493) 8(-1.905,3.493)
SOIC8-G3530H63
  rect 0.635x1.651 smd: 1(-1.905,-2.555) 2(-0.635,-2.555) 3(0.635,-2.555) 4(1.905,-2.555) 5(1.905,2.555) 6(0.635,2.555) 7(-0.635,2.555) 8(-1.905,2.555)
  rect 3.505x2.997 smd: 9(0,0)
SOIC8-G371264H65
  rect 0.635x1.651 smd: 1(-1.905,-2.555) 2(-0.635,-2.555) 3(0.635,-2.555) 4(1.905,-2.555) 5(1.905,2.555) 6(0.635,2.555) 7(-0.635,2.555) 8(-1.905,2.555)
  rect 3.708x2.642 smd: 9(0,0)
SOIC8H69
  rect 0.635x1.651 smd: 1(-1.905,-2.54) 2(-0.635,-2.54) 3(0.635,-2.54) 4(1.905,-2.54) 5(1.905,2.54) 6(0.635,2.54) 7(-0.635,2.54) 8(-1.905,2.54)
SON14J3020-G2610H32
  rect 0.025x0.025 smd: 1(1.2,1.105) 6(-0.8,1.105) 9(-0.8,-1.105) 14(1.2,-1.105)
  custom 0.151x0.151 smd: 2(0.8,1.105) 7(-1.2,1.105) 8(-1.2,-1.105) 13(0.8,-1.105)
  rect 0.203x0.813 smd: 3(0.4,1.105) 4(0,1.105) 5(-0.4,1.105) 10(-0.4,-1.105) 11(0,-1.105) 12(0.4,-1.105)
  rect 2.591x0.889 smd: 15(0,0)
SOT23-2D4-312H44
  custom 0.191x0.191 smd: 1(-0.984,-0.953) 2(0.984,-0.953) 3(0,0.953)
SOT23-2D4-312H46
  custom 0.191x0.191 smd: 1(-0.984,-0.953) 2(0.984,-0.953) 3(0,0.953)
SOT23-2D4-312H48
  custom 0.191x0.191 smd: 1(-0.984,-0.953) 2(0.984,-0.953) 3(0,0.953)
SOT23CBE2D4H44
  custom 0.191x0.191 smd: B(-0.984,-0.953) C(0,0.953) E(0.984,-0.953)
SOT23DGS2D4H44
  custom 0.191x0.191 smd: D(0,0.953) G(-0.984,-0.953) S(0.984,-0.953)
SOT23DGS2D4H48
  custom 0.191x0.191 smd: D(0,0.953) G(-0.984,-0.953) S(0.984,-0.953)
SOT23DGS2D8H50
  custom 0.254x0.254 smd: D(0,1.118) G(-1.016,-1.118) S(1.016,-1.118)
SOT323CBE2D2H40
  custom 0.152x0.152 smd: B(-0.65,-0.902) C(0,0.902) E(0.65,-0.902)
SOT323EBC2D2H40
  custom 0.152x0.152 smd: B(-0.65,-0.902) C(0.65,-0.902) E(0,0.902)
SOT-6-1H58
  rect 0.584x1.219 smd: 1(-0.95,-1.194) 2(0,-1.194) 3(0.95,-1.194) 4(0.95,1.194) 5(0,1.194) 6(-0.95,1.194)
SOT-6H58
  rect 0.584x1.016 smd: 1(-0.953,-1.346) 2(0,-1.346) 3(0.953,-1.346) 4(0.953,1.346) 5(0,1.346) 6(-0.953,1.346)
SOT-23-5H58
  rect 0.508x1.524 smd: 1(-0.95,-1.143) 2(0,-1.143) 3(0.95,-1.143) 4(0.95,1.143) 5(-0.95,1.143)
SOT-23-9H44
  custom 0.178x0.178 smd: 1(-0.95,-0.999) 2(0.95,-0.999) 3(0,0.999)
SOT-89-4541-3PH63
  rect 0.991x1.499 smd: 1(-1.5,0) 3(1.5,0)
  custom 0.502x0.502 smd: 2(0,0)
SOT-363H44
  rect 0.406x1.016 smd: 1(-0.65,-0.94) 2(0,-0.94) 3(0.65,-0.94) 4(0.65,0.94) 5(0,0.94) 6(-0.65,0.94)
STF256R109H99
  round 6.502 hole 2.769: 1(0,0)
TPAD28
  round 0.711 smd: 1(0,0)
TPAD30
  round 0.762 smd: 1(0,0)
TVS5436-1121H105
  rect 2.337x2.007 smd: 1(0,2.299) 2(0,-2.299)
unnamed#2
  round 1.016 smd: (0,0)
VARISTOR-402-H24
  custom 0.14x0.14 smd: 1(0,0.445) 2(0,-0.445)
XFORM12A127097H91
  rect 0.635x1.524 smd: 1(-4.445,-4.699) 2(-3.175,-4.699) 3(-1.905,-4.699) 4(1.905,-4.699) 5(3.175,-4.699) 6(4.445,-4.699) 7(4.445,4.699) 8(3.175,4.699) 9(1.905,4.699) 10(-1.905,4.699) 11(-3.175,4.699) 12(-4.445,4.699)

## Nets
1V1_EN: C540.1 R718.2 U31.2
1V1_FB: R719.2 R727.1 U31.7
1V1_POK: R729.2 U31.1
1V_CPU_XDP_AB: R529.2 XDP1.43
1V_CPU_XDP_CD: R528.2 XDP1.44
1V_DCPDSW: C51.1 CPU1.AL1
1V_EDRAM: CPU1.AB62 CPU1.P62 CPU1.V62 R549.1 R550.2
1V_EOPIO: CPU1.AE62 CPU1.AG62 R551.2 R555.1
1V_S3: C65.1 R169.2 R170.2 R444.1 U3.6 U3.7 U3.8
1V_SIP_S5: CPU1.AB17 CPU1.Y18 R180.2
1V_VCC19P2: CPU1.A14 R142.2
1V_VCC24TBT: C39.1 CPU1.A10 R144.2
1V_VCCAMPHYPLL: C375.1 CPU1.K15 CPU1.L15 R583.2
1V_VCCAPLL: C634.1 CPU1.V15 R627.2
1V_VCCAPLLEBB: C373.1 CPU1.N18 R582.2
1V_VCCDTS: CPU1.T1 R139.2
1V_VCCF24NS: C61.1 CPU1.L19 R149.2 R564.2
1V_VCCF100: C60.1 CPU1.K19 R148.2
1V_VCCF100OC: C62.1 CPU1.N20 R150.2
1V_VCCF135: CPU1.L21 R138.2
1V_VCCFHV: CPU1.AK20 R141.2
1V_VCCFUSEPRG: CPU1.G20 R575.2
1V_VCCGT: C12.1 C13.1 C294.1 C296.1 C298.1 C299.1 C300.1 C302.1 C303.1 C304.1 C305.1 CPU1.A48 CPU1.A53 CPU1.A58 CPU1.A62 CPU1.A66 CPU1.AA63 CPU1.AA64 CPU1.AA66 CPU1.AA67 CPU1.AA69 CPU1.AA70 CPU1.AA71 CPU1.AC64 CPU1.AC65 CPU1.AC66 CPU1.AC67 CPU1.AC68 CPU1.AC69 CPU1.AC70 CPU1.AC71 CPU1.J43 CPU1.J45 CPU1.J46 CPU1.J48 CPU1.J50 CPU1.J52 CPU1.J53 CPU1.J55 CPU1.J56 CPU1.J58 CPU1.J60 CPU1.K48 CPU1.K50 CPU1.K52 CPU1.K53 CPU1.K55 CPU1.K56 CPU1.K58 CPU1.K60 CPU1.L62 CPU1.L63 CPU1.L64 CPU1.L65 CPU1.L66 CPU1.L67 CPU1.L68 CPU1.L69 CPU1.L70 CPU1.L71 CPU1.M62 CPU1.N63 CPU1.N64 CPU1.N66 CPU1.N67 CPU1.N69 CPU1.N70 CPU1.N71 CPU1.R63 CPU1.R64 CPU1.R65 CPU1.R66 CPU1.R67 CPU1.R68 CPU1.R69 CPU1.R70 CPU1.R71 CPU1.T62 CPU1.U65 CPU1.U68 CPU1.U71 CPU1.W63 CPU1.W64 CPU1.W65 CPU1.W66 CPU1.W67 CPU1.W68 CPU1.W69 CPU1.W70 CPU1.W71 CPU1.Y62 PC2.1 PC3.1 PC14.1 PC15.1 PC16.1 PC17.1 PC21.1 PC22.1 PC25.1 PC27.1 PC30.1 PC34.1 PC35.1 PC37.1 PC38.1 PC39.1 PC42.1 PC43.1 PC44.1 PC143.1 PC144.1 PC147.1 PC156.1 PC162.1 PC167.1 PC173.1 PC177.1 PC193.1 PC197.1 PC198.1 PC199.1 PC207.1 PC208.1 PC210.1 PC213.1 PC218.1 PC219.1 PC229.1 PC230.1 PC231.1 PC232.1 PC233.1 PG2.2 PG6.2 PL2.2 PL3.2 PT6.1 PT7.1 R69.1
1V_VCCGTUS: CPU1.AK42 CPU1.AK43 CPU1.AK45 CPU1.AK46 CPU1.AK48 CPU1.AK50 CPU1.AK52 CPU1.AK53 CPU1.AK55 CPU1.AK56 CPU1.AK58 CPU1.AK60 CPU1.AK70 CPU1.AL43 CPU1.AL46 CPU1.AL50 CPU1.AL53 CPU1.AL56 CPU1.AL60 CPU1.AM48 CPU1.AM50 CPU1.AM52 CPU1.AM53 CPU1.AM56 CPU1.AM58 CPU1.AU58 CPU1.AU63 CPU1.BB57 CPU1.BB66 R561.2
1V_VCCIO: C321.1 C340.1 C344.1 C348.1 CPU1.AK28 CPU1.AK30 CPU1.AL30 CPU1.AL42 CPU1.AM28 CPU1.AM30 CPU1.AM42 PC79.1 PC80.1 R19.1 R90.1 R562.1 R567.1 R574.2 R625.2 U4.6 U4.7 U4.8
1V_VCCMPHYAON: C55.1 CPU1.K17 CPU1.L1 R140.2
1V_VCCMPHYGTAON: C56.1 C59.1 C64.1 CPU1.N15 CPU1.N16 CPU1.N17 CPU1.P15 CPU1.P16 R156.2 R581.1 R582.1 R583.1
1V_VCCPRIM: C57.1 CPU1.AB19 CPU1.AB20 CPU1.P18 R146.2
1V_VCCPRIM_CORE: C365.1 CPU1.AF18 CPU1.AF19 CPU1.V20 CPU1.V21 R614.2 R615.2 R625.1
1V_VCCSA: C23.1 C26.1 C350.1 C351.1 C352.1 C353.1 C354.1 CPU1.AK23 CPU1.AK25 CPU1.G23 CPU1.G25 CPU1.G27 CPU1.G28 CPU1.J22 CPU1.J23 CPU1.J27 CPU1.K23 CPU1.K25 CPU1.K27 CPU1.K28 CPU1.K30 PC60.1 PC61.1 PC62.1 PC63.1 PC64.1 PC65.1 PC66.1 PC71.1 PC72.1 PC73.1 PC226.1 PC227.1 PC228.1 PC234.1 PC235.1 PC236.1 PC237.1 PC247.1 PC248.1 PC249.1 PC250.1 PG14.2 PL5.2 PT11.1 R568.1 R614.1
1V_VCCSFR: C367.1 CPU1.K20 CPU1.K21 R169.1
1V_VCCSRAM: C368.1 C372.1 CPU1.AF20 CPU1.AF21 CPU1.T19 CPU1.T20 R581.2
1V_VCCST: C66.1 CPU1.A18 PC36.1 PR22.1 PR23.1 PR25.1 PR26.1 R65.1 R83.2 R86.1 R87.1 R92.1 R94.1 R170.1
1V_VCCSTG: C362.1 CPU1.A22 R13.2 R81.1 R100.2 R103.2 R105.2 R107.2 R110.2 R111.2 R114.2 R574.1 R575.1
1V_XDP_S5: C283.1 C284.1 R1.1 R528.1 R529.1 R532.1 R533.2
3V3_VDD33: C508.1 C509.1 C510.1 C513.1 C514.2 C518.2 C519.1 GPU1.G8 GPU1.G9 GPU1.G10 GPU1.G12 R683.2
3V3AUX: GPU1.F11
3V3AUX_CR: C383.1 C384.2 R584.2 R588.2 U28.27
3V_VA: C142.2 C143.1 C145.1 C146.1 L13.2 U11.23 U11.25
+19V_AMP_AVCC: C188.1 R431.2 U14.12
+19V_AMP_PVCC: C192.1 C193.1 C194.1 C197.1 L14.2 R431.1 U14.13 U14.14 U14.27 U14.28
+VCCPRTC_3P3: C35.1 C36.2 CPU1.AK19 CPU1.BB14 R137.2
AGND: C109.2 C110.2 C113.1 C115.2 C116.2 C119.2 C122.2 C123.1 C126.2 C128.2 C135.2 C137.2 C142.1 C143.2 C144.2 C145.2 C146.2 C161.2 C162.2 C173.1 C177.1 C178.1 C185.2 C188.2 C216.2 C217.2 C234.2 LOUT1.5 LOUT1.P Q25.S Q38.S R277.2 R278.2 R297.2 R304.2 R307.2 R313.2 R341.2 R366.2 R385.2 R386.2 R387.2 R389.1 R395.1 R396.1 R401.2 R406.1 R407.2 R427.2 U11.22 U11.28 U11.42 U13.6 U14.4 UHS1.5
AV12: R631.1 R632.2 U28.10
AV12_L: C411.2 R631.2
DV12S: C406.2 C408.1 R632.1 U28.14
DV33_18: C396.2 U28.18
GND: AFTP1.1 BAT2.8 BAT2.9 BAT2.10 BAT2.11 BT1.2 C1.2 C2.2 C3.2 C4.2 C5.2 C6.2 C7.2 C8.2 C9.2 C10.2 C11.2 C12.2 C13.2 C14.2 C15.2 C16.2 C17.2 C18.2 C19.2 C20.2 C23.2 C26.2 C27.2 C30.2 C35.2 C36.1 C37.2 C39.2 C42.2 C43.2 C45.2 C48.2 C51.2 C54.2 C55.2 C56.2 C57.2 C58.2 C59.2 C60.2 C61.2 C62.2 C63.2 C64.2 C65.2 C66.2 C67.2 C68.2 C69.2 C70.2 C71.2 C72.2 C73.2 C74.2 C75.2 C76.2 C77.2 C78.2 C79.2 C80.2 C84.2 C85.2 C87.2 C88.2 C89.2 C90.2 C91.2 C92.2 C93.2 C94.1 C95.2 C96.2 C97.2 C98.2 C99.2 C102.2 C103.2 C104.2 C105.2 C106.1 C107.2 C108.2 C114.2 C117.2 C118.2 C120.2 C121.2 C124.1 C127.2 C129.1 C130.1 C134.2 C136.2 C138.2 C139.2 C140.2 C141.2 C148.1 C149.2 C150.2 C151.1 C152.2 C153.1 C155.1 C157.2 C159.2 C164.2 C167.2 C168.2 C171.2 C172.2 C182.2 C184.2 C185.1 C186.2 C190.2 C191.2 C192.2 C193.2 C194.2 C195.2 C196.2 C197.2 C198.2 C199.2 C200.2 C206.2 C207.2 C208.2 C209.2 C210.2 C211.2 C212.2 C213.2 C214.2 C218.2 C222.2 C224.2 C225.2 C226.2 C227.2 C229.2 C231.2 C233.2 C234.1 C235.2 C236.2 C237.2 C238.2 C239.2 C241.2 C246.2 C250.2 C251.2 C252.2 C253.2 C254.2 C255.2 C256.2 C258.2 C260.2 C261.2 C262.2 C263.2 C264.2 C265.2 C266.2 C267.2 C268.2 C269.2 C270.2 C271.2 C272.2 C273.2 C274.2 C275.2 C276.2 C277.2 C278.2 C279.2 C280.2 C281.2 C282.2 C283.2 C284.2 C285.2 C286.2 C287.2 C288.2 C289.2 C290.2 C291.2 C292.2 C293.2 C294.2 C296.2 C297.2 C298.2 C299.2 C300.2 C301.2 C302.2 C303.2 C304.2 C305.2 C306.2 C307.2 C308.2 C309.2 C310.2 C311.2 C312.2 C313.2 C314.2 C315.2 C316.2 C317.2 C318.2 C319.2 C320.2 C321.2 C322.2 C323.2 C324.2 C325.2 C326.2 C327.2 C328.2 C329.2 C330.2 C331.2 C332.2 C333.2 C334.2 C335.2 C336.2 C337.2 C338.2 C339.2 C340.2 C341.2 C342.2 C343.2 C344.2 C345.2 C346.2 C347.2 C348.2 C349.2 C350.2 C351.2 C352.2 C353.2 C354.2 C355.2 C356.2 C357.2 C358.2 C359.2 C360.2 C361.2 C362.2 C363.2 C364.2 C365.2 C366.2 C367.2 C368.2 C369.2 C371.2 C372.2 C373.2 C375.2 C376.2 C377.2 C378.2 C379.2 C380.2 C381.2 C382.2 C383.2 C384.1 C386.2 C388.2 C389.2 C390.2 C391.2 C392.2 C393.2 C394.2 C395.2 C396.1 C397.2 C400.1 C401.1 C402.1 C403.1 C404.2 C405.2 C406.1 C407.2 C408.2 C409.2 C410.2 C411.1 C412.2 C413.2 C414.2 C415.2 C416.2 C417.2 C418.2 C419.2 C420.2 C421.2 C422.2 C423.2 C424.2 C425.1 C426.2 C427.2 C428.2 C429.2 C430.2 C431.2 C432.2 C441.2 C442.2 C443.2 C444.2 C445.2 C446.2 C447.2 C448.2 C449.1 C450.2 C451.1 C453.2 C454.2 C455.1 C456.2 C457.1 C458.1 C459.2 C460.2 C461.2 C462.2 C463.1 C464.2 C465.2 C466.2 C467.2 C468.1 C469.2 C470.2 C471.2 C472.1 C473.1 C474.1 C475.1 C476.1 C477.1 C478.2 C479.2 C480.2 C481.2 C482.2 C483.2 C484.1 C485.1 C486.1 C487.1 C488.2 C489.2 C490.2 C491.2 C492.2 C493.1 C494.1 C495.1 C496.1 C497.1 C498.2 C499.2 C500.2 C501.2 C502.2 C503.2 C504.2 C505.1 C506.2 C507.2 C508.2 C509.2 C510.2 C511.2 C512.2 C513.2 C514.1 C515.2 C516.2 C517.2 C518.1 C519.2 C520.2 C521.2 C522.2 C523.2 C524.2 C525.2 C526.2 C527.2 C529.2 C531.2 C532.2 C534.1 C535.2 C537.2 C538.2 C539.2 C540.2 C541.2 C542.1 C543.2 C544.2 C545.2 C546.2 C549.2 C552.1 C553.2 C554.2 C555.2 C556.1 C557.1 C558.2 C559.1 C560.1 C561.2 C562.2 C563.2 C564.2 C565.2 C566.2 C567.2 C568.2 C569.2 C571.2 C572.2 C573.2 C574.2 C575.2 C576.2 C577.2 C578.2 C579.2 C580.2 C581.2 C582.2 C583.2 C584.2 C585.2 C586.2 C588.2 C589.2 C590.2 C591.2 C592.2 C594.2 C595.2 C596.2 C597.2 C598.2 C599.2 C600.2 C601.2 C602.2 C603.2 C604.2 C605.2 C606.2 C607.2 C609.2 C610.2 C611.2 C612.2 C614.2 C615.2 C620.2 C621.2 C623.2 C624.2 C627.2 C628.2 C629.2 C630.2 C631.2 C632.2 C633.2 C634.2 C635.2 C636.2 C637.2 C638.2 CN1.4 CN1.5 CN1.6 CONVT1.10 CONVT1.11 CONVT1.12 CPU1.A5 CPU1.A67 CPU1.A70 CPU1.AA2 CPU1.AA4 CPU1.AA65 CPU1.AA68 CPU1.AB8 CPU1.AB15 CPU1.AB16 CPU1.AB18 CPU1.AB21 CPU1.AD8 CPU1.AD13 CPU1.AD16 CPU1.AD19 CPU1.AD20 CPU1.AD21 CPU1.AD62 CPU1.AE64 CPU1.AE65 CPU1.AE66 CPU1.AE67 CPU1.AE68 CPU1.AE69 CPU1.AF1 CPU1.AF2 CPU1.AF4 CPU1.AF10 CPU1.AF15 CPU1.AF17 CPU1.AF63 CPU1.AG16 CPU1.AG17 CPU1.AG18 CPU1.AG19 CPU1.AG20 CPU1.AG21 CPU1.AG71 CPU1.AH6 CPU1.AH13 CPU1.AH63 CPU1.AH64 CPU1.AH67 CPU1.AJ4 CPU1.AJ15 CPU1.AJ18 CPU1.AJ20 CPU1.AK8 CPU1.AK11 CPU1.AK16 CPU1.AK18 CPU1.AK21 CPU1.AK22 CPU1.AK27 CPU1.AK63 CPU1.AK68 CPU1.AK69 CPU1.AL2 CPU1.AL4 CPU1.AL28 CPU1.AL32 CPU1.AL35 CPU1.AL38 CPU1.AL45 CPU1.AL48 CPU1.AL52 CPU1.AL55 CPU1.AL58 CPU1.AL64 CPU1.AL65 CPU1.AL66 CPU1.AM8 CPU1.AM13 CPU1.AM21 CPU1.AM25 CPU1.AM27 CPU1.AM43 CPU1.AM45 CPU1.AM46 CPU1.AM55 CPU1.AM60 CPU1.AM61 CPU1.AM68 CPU1.AM71 CPU1.AN20 CPU1.AN23 CPU1.AN28 CPU1.AN30 CPU1.AN32 CPU1.AN33 CPU1.AN35 CPU1.AN37 CPU1.AN38 CPU1.AN40 CPU1.AN42 CPU1.AN58 CPU1.AN63 CPU1.AP10 CPU1.AP18 CPU1.AP20 CPU1.AP23 CPU1.AP28 CPU1.AP32 CPU1.AP35 CPU1.AP38 CPU1.AP42 CPU1.AP58 CPU1.AP63 CPU1.AP68 CPU1.AP70 CPU1.AR5 CPU1.AR8 CPU1.AR11 CPU1.AR15 CPU1.AR16 CPU1.AR20 CPU1.AR23 CPU1.AR28 CPU1.AR35 CPU1.AR42 CPU1.AR43 CPU1.AR45 CPU1.AR46 CPU1.AR48 CPU1.AR50 CPU1.AR52 CPU1.AR53 CPU1.AR55 CPU1.AR58 CPU1.AR63 CPU1.AT2 CPU1.AT4 CPU1.AT20 CPU1.AT23 CPU1.AT28 CPU1.AT35 CPU1.AT42 CPU1.AT56 CPU1.AT58 CPU1.AT63 CPU1.AT68 CPU1.AT71 CPU1.AU10 CPU1.AU15 CPU1.AU20 CPU1.AU32 CPU1.AU38 CPU1.AV1 CPU1.AV68 CPU1.AV69 CPU1.AV70 CPU1.AV71 CPU1.AW6 CPU1.AW8 CPU1.AW10 CPU1.AW12 CPU1.AW14 CPU1.AW16 CPU1.AW18 CPU1.AW21 CPU1.AW23 CPU1.AW26 CPU1.AW28 CPU1.AW30 CPU1.AW32 CPU1.AW34 CPU1.AW36 CPU1.AW38 CPU1.AW41 CPU1.AW43 CPU1.AW45 CPU1.AW47 CPU1.AW49 CPU1.AW51 CPU1.AW53 CPU1.AW55 CPU1.AW57 CPU1.AW60 CPU1.AW62 CPU1.AW64 CPU1.AW66 CPU1.AY66 CPU1.B10 CPU1.B14 CPU1.B18 CPU1.B22 CPU1.B30 CPU1.B34 CPU1.B39 CPU1.B44 CPU1.B48 CPU1.B53 CPU1.B58 CPU1.B62 CPU1.B66 CPU1.B71 CPU1.BA1 CPU1.BA2 CPU1.BA6 CPU1.BA10 CPU1.BA14 CPU1.BA18 CPU1.BA23 CPU1.BA28 CPU1.BA32 CPU1.BA36 CPU1.BA41 CPU1.BA45 CPU1.BA49 CPU1.BA53 CPU1.BA57 CPU1.BA62 CPU1.BA66 CPU1.BA71 CPU1.BB6 CPU1.BB18 CPU1.BB26 CPU1.BB30 CPU1.BB34 CPU1.BB38 CPU1.BB43 CPU1.BB55 CPU1.BB60 CPU1.BB64 CPU1.BB67 CPU1.BB70 CPU1.C1 CPU1.C5 CPU1.C25 CPU1.D6 CPU1.D10 CPU1.D11 CPU1.D14 CPU1.D18 CPU1.D22 CPU1.D25 CPU1.D26 CPU1.D30 CPU1.D34 CPU1.D39 CPU1.D44 CPU1.D45 CPU1.D47 CPU1.D48 CPU1.D53 CPU1.D58 CPU1.D62 CPU1.D66 CPU1.D69 CPU1.E6 CPU1.E11 CPU1.E15 CPU1.E18 CPU1.E21 CPU1.E46 CPU1.E50 CPU1.E53 CPU1.E56 CPU1.E65 CPU1.E71 CPU1.F1 CPU1.F2 CPU1.F4 CPU1.F8 CPU1.F13 CPU1.F22 CPU1.F23 CPU1.F27 CPU1.F28 CPU1.F32 CPU1.F33 CPU1.F35 CPU1.F37 CPU1.F38 CPU1.F40 CPU1.F42 CPU1.F68 CPU1.G5 CPU1.G6 CPU1.G10 CPU1.G22 CPU1.G43 CPU1.G45 CPU1.G48 CPU1.G52 CPU1.G55 CPU1.G58 CPU1.G60 CPU1.G63 CPU1.G66 CPU1.H15 CPU1.H18 CPU1.H71 CPU1.J8 CPU1.J11 CPU1.J13 CPU1.J25 CPU1.J28 CPU1.J32 CPU1.J35 CPU1.J38 CPU1.J42 CPU1.K16 CPU1.K18 CPU1.K22 CPU1.K61 CPU1.K63 CPU1.K64 CPU1.K65 CPU1.K66 CPU1.K67 CPU1.K68 CPU1.K70 CPU1.K71 CPU1.L2 CPU1.L4 CPU1.L8 CPU1.L11 CPU1.L16 CPU1.L17 CPU1.L18 CPU1.L20 CPU1.N6 CPU1.N10 CPU1.N13 CPU1.N19 CPU1.N21 CPU1.N65 CPU1.N68 CPU1.P17 CPU1.P19 CPU1.P20 CPU1.P21 CPU1.R6 CPU1.R13 CPU1.T2 CPU1.T4 CPU1.T15 CPU1.T17 CPU1.T18 CPU1.T21 CPU1.U10 CPU1.U63 CPU1.U64 CPU1.U66 CPU1.U67 CPU1.U69 CPU1.U70 CPU1.V16 CPU1.V17 CPU1.V18 CPU1.W6 CPU1.W9 CPU1.W13 CPU1.Y17 CPU1.Y19 CPU1.Y20 CPU1.Y21 D3.2 D4.A D8.2 D10.1 D12.A D13.3 D13.8 D14.3 D14.8 D15.2 D20.1 D22.1 D25.2 DCIN1.2 DCIN1.4 DCIN1.5 DCIN1.6 DCIN1.7 DCIN2.5 DCIN2.6 DCIN2.7 DCIN2.12 DCIN2.13 DCIN2.14 DIMM1.1 DIMM1.2 DIMM1.5 DIMM1.6 DIMM1.9 DIMM1.10 DIMM1.14 DIMM1.15 DIMM1.18 DIMM1.19 DIMM1.22 DIMM1.23 DIMM1.26 DIMM1.27 DIMM1.30 DIMM1.31 DIMM1.35 DIMM1.36 DIMM1.39 DIMM1.40 DIMM1.43 DIMM1.44 DIMM1.47 DIMM1.48 DIMM1.51 DIMM1.52 DIMM1.56 DIMM1.57 DIMM1.60 DIMM1.61 DIMM1.64 DIMM1.65 DIMM1.68 DIMM1.69 DIMM1.72 DIMM1.73 DIMM1.77 DIMM1.78 DIMM1.81 DIMM1.82 DIMM1.85 DIMM1.86 DIMM1.89 DIMM1.90 DIMM1.93 DIMM1.94 DIMM1.98 DIMM1.99 DIMM1.102 DIMM1.103 DIMM1.106 DIMM1.107 DIMM1.167 DIMM1.168 DIMM1.171 DIMM1.172 DIMM1.175 DIMM1.176 DIMM1.180 DIMM1.181 DIMM1.184 DIMM1.185 DIMM1.188 DIMM1.189 DIMM1.192 DIMM1.193 DIMM1.196 DIMM1.197 DIMM1.201 DIMM1.202 DIMM1.205 DIMM1.206 DIMM1.209 DIMM1.210 DIMM1.213 DIMM1.214 DIMM1.217 DIMM1.218 DIMM1.222 DIMM1.223 DIMM1.226 DIMM1.227 DIMM1.230 DIMM1.231 DIMM1.234 DIMM1.235 DIMM1.238 DIMM1.239 DIMM1.243 DIMM1.244 DIMM1.247 DIMM1.248 DIMM1.251 DIMM1.252 DIMM1.261 DIMM1.262 DIMM2.1 DIMM2.2 DIMM2.5 DIMM2.6 DIMM2.9 DIMM2.10 DIMM2.14 DIMM2.15 DIMM2.18 DIMM2.19 DIMM2.22 DIMM2.23 DIMM2.26 DIMM2.27 DIMM2.30 DIMM2.31 DIMM2.35 DIMM2.36 DIMM2.39 DIMM2.40 DIMM2.43 DIMM2.44 DIMM2.47 DIMM2.48 DIMM2.51 DIMM2.52 DIMM2.56 DIMM2.57 DIMM2.60 DIMM2.61 DIMM2.64 DIMM2.65 DIMM2.68 DIMM2.69 DIMM2.72 DIMM2.73 DIMM2.77 DIMM2.78 DIMM2.81 DIMM2.82 DIMM2.85 DIMM2.86 DIMM2.89 DIMM2.90 DIMM2.93 DIMM2.94 DIMM2.98 DIMM2.99 DIMM2.102 DIMM2.103 DIMM2.106 DIMM2.107 DIMM2.167 DIMM2.168 DIMM2.171 DIMM2.172 DIMM2.175 DIMM2.176 DIMM2.180 DIMM2.181 DIMM2.184 DIMM2.185 DIMM2.188 DIMM2.189 DIMM2.192 DIMM2.193 DIMM2.196 DIMM2.197 DIMM2.201 DIMM2.202 DIMM2.205 DIMM2.206 DIMM2.209 DIMM2.210 DIMM2.213 DIMM2.214 DIMM2.217 DIMM2.218 DIMM2.222 DIMM2.223 DIMM2.226 DIMM2.227 DIMM2.230 DIMM2.231 DIMM2.234 DIMM2.235 DIMM2.238 DIMM2.239 DIMM2.243 DIMM2.244 DIMM2.247 DIMM2.248 DIMM2.251 DIMM2.252 DIMM2.261 DIMM2.262 FANC3.1 GPU1.A2 GPU1.A26 GPU1.AA7 GPU1.AB7 GPU1.AB11 GPU1.AB14 GPU1.AB17 GPU1.AB20 GPU1.AB24 GPU1.AC2 GPU1.AC5 GPU1.AC8 GPU1.AC22 GPU1.AC26 GPU1.AD12 GPU1.AD13 GPU1.AD15 GPU1.AD16 GPU1.AD18 GPU1.AD19 GPU1.AD21 GPU1.AD22 GPU1.AE11 GPU1.AE14 GPU1.AE17 GPU1.AE20 GPU1.AF1 GPU1.AF5 GPU1.AF8 GPU1.AF11 GPU1.AF14 GPU1.AF17 GPU1.AF20 GPU1.AF23 GPU1.AG2 GPU1.AG26 GPU1.B1 GPU1.B5 GPU1.B8 GPU1.B11 GPU1.B14 GPU1.B17 GPU1.B20 GPU1.B23 GPU1.B27 GPU1.E2 GPU1.E5 GPU1.E8 GPU1.E11 GPU1.E14 GPU1.E17 GPU1.E20 GPU1.E22 GPU1.E25 GPU1.H2 GPU1.H5 GPU1.H23 GPU1.H25 GPU1.K11 GPU1.K13 GPU1.K15 GPU1.K17 GPU1.L2 GPU1.L5 GPU1.L10 GPU1.L12 GPU1.L14 GPU1.L16 GPU1.L18 GPU1.L23 GPU1.L25 GPU1.M11 GPU1.M13 GPU1.M15 GPU1.M17 GPU1.N10 GPU1.N12 GPU1.N14 GPU1.N16 GPU1.N18 GPU1.P2 GPU1.P5 GPU1.P11 GPU1.P13 GPU1.P15 GPU1.P17 GPU1.P23 GPU1.P26 GPU1.R10 GPU1.R12 GPU1.R14 GPU1.R16 GPU1.R18 GPU1.T11 GPU1.T13 GPU1.T15 GPU1.T17 GPU1.U2 GPU1.U5 GPU1.U10 GPU1.U12 GPU1.U14 GPU1.U16 GPU1.U18 GPU1.U23 GPU1.U26 GPU1.V11 GPU1.V13 GPU1.V15 GPU1.V17 GPU1.Y2 GPU1.Y5 GPU1.Y23 GPU1.Y26 H1.1 H2.1 H3.1 H4.1 H5.1 H6.1 H6.2 H6.3 H6.4 H6.5 H6.6 H6.7 H6.8 H7.1 H7.2 H7.3 H7.4 H7.5 H7.6 H7.7 H7.8 H9.1 H9.2 H9.3 H9.4 H9.5 H9.6 H9.7 H9.8 H10.1 H10.2 H10.3 H10.4 H10.5 H10.6 H10.7 H10.8 H11.1 H11.2 H11.3 H11.4 H11.5 H11.6 H11.7 H11.8 HDD1.1 HDD1.4 HDD1.7 HDD1.8 HDD1.9 HDMI1.2 HDMI1.5 HDMI1.8 HDMI1.11 HDMI1.17 HDMI1.20 HDMI1.21 HDMI1.22 HDMI2.2 HDMI2.5 HDMI2.8 HDMI2.17 HDMI2.20 HDMI2.21 HDMI2.22 HDMI3.3 HDMI3.9 HDMI3.12 HDMI3.15 HDMI3.18 HDMI3.20 HDMI3.21 HDMI3.22 HDMI3.23 HDMI3.24 HDMI3.25 HDMI4.3 HDMI4.12 HDMI4.15 HDMI4.18 HDMI4.20 HDMI4.21 HDMI4.22 HDMI4.23 HDMI4.24 HDMI4.25 HS6.1 JMP1.4 KBC1.5 KBC1.18 KBC1.45 KBC1.78 KBC1.89 KBC1.116 LED1.K LPC1.12 LPC1.14 LVDS1.7 LVDS1.14 LVDS1.31 LVDS1.32 MEMCD1.3 MEMCD1.6 MEMCD1.12 MEMCD1.13 MEMCD1.14 MEMCD1.15 NGFF1.7 NGFF1.18 NGFF1.23 NGFF1.24 NGFF1.29 NGFF1.30 NGFF1.33 NGFF1.36 NGFF1.39 NGFF1.45 NGFF1.57 NGFF1.63 NGFF1.69 NGFF1.75 NGFF1.76 NGFF1.77 ODD1.1 ODD1.4 ODD1.7 ODD1.8 ODD1.9 PC1.2 PC2.2 PC3.2 PC5.2 PC7.2 PC8.2 PC9.2 PC10.2 PC11.2 PC13.1 PC14.2 PC15.2 PC16.2 PC17.2 PC18.2 PC19.2 PC20.1 PC21.2 PC22.2 PC25.2 PC27.2 PC30.2 PC34.2 PC35.2 PC36.2 PC37.2 PC38.2 PC39.2 PC40.2 PC41.2 PC42.2 PC43.2 PC44.2 PC45.2 PC46.2 PC47.2 PC48.2 PC49.2 PC50.2 PC51.2 PC52.2 PC53.2 PC54.2 PC55.2 PC56.2 PC57.2 PC58.2 PC59.2 PC60.2 PC61.2 PC62.2 PC63.2 PC64.2 PC65.2 PC66.2 PC67.2 PC68.2 PC69.2 PC71.2 PC72.2 PC73.2 PC74.2 PC76.2 PC78.2 PC79.2 PC80.2 PC81.1 PC82.2 PC83.1 PC84.2 PC86.2 PC87.2 PC89.2 PC90.2 PC91.2 PC92.2 PC93.2 PC94.2 PC95.2 PC96.2 PC97.2 PC98.2 PC99.2 PC100.2 PC101.2 PC102.2 PC103.2 PC104.2 PC105.2 PC107.2 PC108.2 PC109.2 PC110.2 PC111.2 PC113.2 PC114.2 PC115.2 PC116.2 PC117.2 PC118.2 PC119.2 PC127.2 PC128.2 PC129.2 PC131.2 PC133.2 PC134.2 PC135.2 PC136.2 PC137.2 PC138.2 PC139.2 PC140.2 PC141.2 PC142.2 PC143.2 PC144.2 PC146.2 PC147.2 PC148.2 PC149.2 PC152.2 PC153.2 PC154.2 PC155.2 PC156.2 PC157.2 PC162.2 PC167.2 PC168.2 PC170.2 PC171.2 PC172.2 PC173.2 PC174.1 PC176.2 PC177.2 PC183.1 PC184.2 PC185.2 PC186.2 PC187.2 PC188.2 PC189.2 PC191.2 PC192.2 PC193.2 PC194.1 PC195.2 PC196.2 PC197.2 PC198.2 PC199.2 PC200.2 PC201.2 PC202.2 PC203.2 PC204.2 PC205.2 PC206.2 PC207.2 PC208.2 PC209.2 PC210.2 PC211.2 PC212.2 PC213.2 PC214.2 PC215.2 PC216.2 PC217.2 PC218.2 PC219.2 PC220.2 PC221.2 PC222.2 PC223.2 PC224.2 PC225.2 PC226.2 PC227.2 PC228.2 PC229.2 PC230.2 PC231.2 PC232.2 PC233.2 PC234.2 PC235.2 PC236.2 PC237.2 PC238.2 PC239.2 PC240.2 PC241.2 PC242.2 PC243.2 PC244.2 PC245.2 PC246.2 PC247.2 PC248.2 PC249.2 PC250.2 PC251.2 PC252.2 PC253.2 PC254.2 PC255.2 PC256.2 PC259.2 PC261.2 PC262.2 PC264.2 PC265.2 PC266.2 PC267.2 PC268.2 PC269.2 PC270.2 PC271.2 PC272.2 PC274.2 PC276.2 PC277.2 PC278.2 PC279.2 PC280.2 PC282.1 PC286.2 PC287.2 PC288.2 PC289.2 PC290.2 PC291.2 PC292.2 PC293.2 PC294.2 PC296.2 PC297.2 PC299.2 PC302.2 PC303.2 PC304.2 PL13.2 PL14.2 PL15.2 PQ2.S PQ3.S PQ5.1 PQ5.4 PQ6.E PQ8.1 PQ8.4 PQ9.1 PQ9.4 PQ10.S PQ11.1 PQ11.4 PR1.1 PR8.1 PR9.2 PR10.2 PR11.1 PR12.2 PR13.2 PR14.1 PR28.2 PR31.1 PR40.2 PR41.2 PR47.1 PR55.2 PR60.2 PR63.2 PR69.2 PR74.2 PR75.2 PR82.2 PR90.2 PR93.1 PR113.2 PR115.2 PR118.2 PR119.2 PR125.2 PR137.2 PR157.1 PR161.2 PR168.2 PR171.1 PR172.1 PR181.2 PR187.2 PR189.1 PR197.2 PR204.2 PR217.2 PR219.2 PR220.2 PR221.2 PR223.2 PR231.2 PR235.2 PR239.2 PR242.1 PR245.2 PR249.2 PT1.2 PT2.2 PT3.2 PT4.2 PT5.2 PT6.2 PT7.2 PT8.2 PT9.2 PT10.2 PT11.2 PT12.2 PT13.2 PT14.2 PT15.2 PT16.2 PT17.2 PT18.2 PT19.2 PT20.2 PT21.2 PU2.1 PU2.2 PU2.3 PU3.1 PU3.2 PU3.3 PU5.1 PU5.2 PU5.3 PU8.6 PU8.9 PU9.1 PU9.2 PU9.3 PU10.1 PU11.1 PU12.1 PU12.2 PU12.3 PU14.4 PU14.12 PU14.13 PU14.14 PU14.15 PU14.19 PU17.21 PU19.1 PU19.2 PU19.3 PU20.1 PU20.3 PU20.14 PU20.21 PU21.1 PU22.1 PU22.2 PU22.3 PU23.1 PU23.2 PU23.3 PU24.53 PU25.1 PU25.2 PU25.3 PU27.1 PU27.2 PU27.3 PU28.11 PU30.1 PU30.2 PU30.3 PU33.1 PU33.2 PU33.3 PU34.14 PU34.21 PU37.1 PU37.2 PU37.3 PU38.1 PU38.2 PU38.3 PWRCN1.4 PWRCN1.11 PWRCN1.12 Q1.1 Q1.4 Q3.1 Q3.4 Q4.S Q5.4 Q6.E Q7.S Q8.4 Q9.1 Q9.4 Q10.4 Q11.S Q12.1 Q12.4 Q13.4 Q14.S Q16.S Q21.1 Q21.4 Q22.E Q23.S Q26.3 Q27.3 Q30.E Q31.S Q32.S Q33.1 Q33.4 Q34.1 Q34.4 Q37.S Q40.S Q42.3 Q43.S Q44.S Q45.1 Q45.4 Q46.E Q47.E Q48.S Q49.E Q51.S Q53.1 Q53.4 Q56.S Q58.1 Q58.4 Q59.C Q63.S Q66.S Q67.S Q68.S Q69.S Q71.4 Q72.1 Q73.E Q76.E Q77.E Q78.1 Q78.4 Q79.S Q80.E Q83.S Q84.S R16.2 R24.2 R25.2 R43.1 R61.1 R63.1 R66.1 R71.2 R72.2 R73.2 R74.2 R75.2 R98.2 R99.2 R112.2 R113.2 R119.2 R132.2 R147.2 R168.2 R173.1 R185.2 R187.2 R190.2 R191.2 R193.1 R231.2 R240.1 R241.2 R242.1 R243.2 R246.1 R253.2 R254.2 R255.2 R260.1 R261.2 R263.2 R266.2 R270.2 R271.2 R276.2 R277.1 R278.1 R283.2 R284.2 R288.2 R299.2 R300.2 R301.2 R304.1 R306.2 R307.1 R310.2 R318.2 R330.1 R331.1 R336.2 R356.2 R358.1 R364.2 R366.1 R368.2 R370.1 R374.1 R379.1 R389.2 R393.2 R401.1 R403.2 R424.2 R427.1 R430.2 R432.2 R451.2 R455.2 R458.2 R465.2 R468.1 R478.2 R485.2 R488.1 R489.1 R490.1 R491.1 R493.2 R500.2 R510.1 R511.1 R512.1 R513.1 R516.2 R517.2 R519.1 R526.2 R543.2 R546.2 R547.2 R548.2 R550.1 R551.1 R552.2 R553.2 R554.2 R556.2 R561.1 R565.2 R572.2 R573.2 R576.2 R577.2 R580.2 R585.2 R587.2 R591.2 R593.2 R596.2 R598.2 R605.2 R606.2 R609.2 R610.2 R612.2 R613.2 R637.1 R638.1 R647.1 R648.1 R651.2 R652.1 R653.1 R659.2 R662.2 R663.2 R669.2 R676.2 R684.2 R687.2 R691.2 R692.2 R694.2 R697.2 R699.2 R700.2 R701.2 R706.2 R710.2 R713.1 R714.1 R717.2 R727.2 R736.1 R738.2 R750.2 R755.2 R761.2 R764.2 R769.2 R775.2 R782.2 R806.2 R807.2 R808.2 R809.2 R810.2 R811.2 R817.2 R818.2 R820.2 R835.2 R844.1 R868.2 R873.2 R883.1 R886.2 R888.2 R890.2 RJ1.13 RN3.1(A) RN3.2(A) RV1.1 SATAP1.2 SATAP1.4 SCA1.3 SCA1.13 SCA1.33 SCA1.75 SCA1.90 SCA1.95 SPK1.5 SPK1.7 SPK1.8 SRCON1.4 SSUSB1.4 SSUSB1.7 SSUSB1.10 SSUSB1.11 SSUSB2.4 SSUSB2.7 SSUSB2.10 SSUSB2.11 TC1.2 TC2.2 TC3.2 TC4.2 TOUCH1.2 U1.3 U2.1 U2.4 U3.5 U4.5 U5.2 U6.3 U6.8 U7.3 U8.4 U9.3 U9.8 U10.4 U11.49 U12.5 U14.8 U14.9 U14.10 U14.17 U14.20 U14.21 U14.24 U14.33 U15.3 U15.8 U16.3 U16.8 U17.8 U17.15 U17.35 U17.41 U18.3 U18.8 U20.2 U21.3 U22.1 U22.2 U22.3 U22.4 U23.33 U24.2 U25.2 U26.11 U26.15 U27.3 U28.33 U30.22 U30.25 U31.8 U31.9 U32.3 U33.4 U34.9 U34.16 U34.23 U34.32 U34.33 U36.20 U37.3 U38.1 U39.2 U40.2 UHS1.MS1 UHS1.MS2 USB3.4 USB3.5 USB3.6 USB4.4 USB4.5 USB4.6 VRAM1.A1 VRAM1.A3 VRAM1.A12 VRAM1.A14 VRAM1.B5 VRAM1.B10 VRAM1.C1 VRAM1.C3 VRAM1.C4 VRAM1.C11 VRAM1.C12 VRAM1.C13 VRAM1.C14 VRAM1.D10 VRAM1.E1 VRAM1.E3 VRAM1.E12 VRAM1.E14 VRAM1.F5 VRAM1.F10 VRAM1.G5 VRAM1.G10 VRAM1.H1 VRAM1.H2 VRAM1.H13 VRAM1.H14 VRAM1.K1 VRAM1.K2 VRAM1.K13 VRAM1.K14 VRAM1.L5 VRAM1.L10 VRAM1.M5 VRAM1.M10 VRAM1.N1 VRAM1.N3 VRAM1.N12 VRAM1.N14 VRAM1.P10 VRAM1.R1 VRAM1.R3 VRAM1.R4 VRAM1.R11 VRAM1.R12 VRAM1.R14 VRAM1.T5 VRAM1.T10 VRAM1.U1 VRAM1.U3 VRAM1.U12 VRAM1.U14 VRAM2.A1 VRAM2.A3 VRAM2.A12 VRAM2.A14 VRAM2.B5 VRAM2.B10 VRAM2.C1 VRAM2.C3 VRAM2.C4 VRAM2.C11 VRAM2.C12 VRAM2.C13 VRAM2.C14 VRAM2.D10 VRAM2.E1 VRAM2.E3 VRAM2.E12 VRAM2.E14 VRAM2.F5 VRAM2.F10 VRAM2.G5 VRAM2.G10 VRAM2.H1 VRAM2.H2 VRAM2.H13 VRAM2.H14 VRAM2.K1 VRAM2.K2 VRAM2.K13 VRAM2.K14 VRAM2.L5 VRAM2.L10 VRAM2.M5 VRAM2.M10 VRAM2.N1 VRAM2.N3 VRAM2.N12 VRAM2.N14 VRAM2.P10 VRAM2.R1 VRAM2.R3 VRAM2.R4 VRAM2.R11 VRAM2.R12 VRAM2.R14 VRAM2.T5 VRAM2.T10 VRAM2.U1 VRAM2.U3 VRAM2.U12 VRAM2.U14 VRAM3.A1 VRAM3.A3 VRAM3.A12 VRAM3.A14 VRAM3.B5 VRAM3.B10 VRAM3.C1 VRAM3.C3 VRAM3.C4 VRAM3.C11 VRAM3.C12 VRAM3.C13 VRAM3.C14 VRAM3.D10 VRAM3.E1 VRAM3.E3 VRAM3.E12 VRAM3.E14 VRAM3.F5 VRAM3.F10 VRAM3.G5 VRAM3.G10 VRAM3.H1 VRAM3.H2 VRAM3.H13 VRAM3.H14 VRAM3.K1 VRAM3.K2 VRAM3.K13 VRAM3.K14 VRAM3.L5 VRAM3.L10 VRAM3.M5 VRAM3.M10 VRAM3.N1 VRAM3.N3 VRAM3.N12 VRAM3.N14 VRAM3.P10 VRAM3.R1 VRAM3.R3 VRAM3.R4 VRAM3.R11 VRAM3.R12 VRAM3.R14 VRAM3.T5 VRAM3.T10 VRAM3.U1 VRAM3.U3 VRAM3.U12 VRAM3.U14 VRAM4.A1 VRAM4.A3 VRAM4.A12 VRAM4.A14 VRAM4.B5 VRAM4.B10 VRAM4.C1 VRAM4.C3 VRAM4.C4 VRAM4.C11 VRAM4.C12 VRAM4.C13 VRAM4.C14 VRAM4.D10 VRAM4.E1 VRAM4.E3 VRAM4.E12 VRAM4.E14 VRAM4.F5 VRAM4.F10 VRAM4.G5 VRAM4.G10 VRAM4.H1 VRAM4.H2 VRAM4.H13 VRAM4.H14 VRAM4.K1 VRAM4.K2 VRAM4.K13 VRAM4.K14 VRAM4.L5 VRAM4.L10 VRAM4.M5 VRAM4.M10 VRAM4.N1 VRAM4.N3 VRAM4.N12 VRAM4.N14 VRAM4.P10 VRAM4.R1 VRAM4.R3 VRAM4.R4 VRAM4.R11 VRAM4.R12 VRAM4.R14 VRAM4.T5 VRAM4.T10 VRAM4.U1 VRAM4.U3 VRAM4.U12 VRAM4.U14 WEBCM1.6 WEBCM1.8 WEBCM1.9 WEBCM1.10 X1.2 X1.4 X2.2 X2.3 X3.2 X3.4 X4.2 X4.4 X5.2 X5.4 XDP1.2 XDP1.7 XDP1.8 XDP1.13 XDP1.14 XDP1.19 XDP1.20 XDP1.25 XDP1.26 XDP1.31 XDP1.32 XDP1.37 XDP1.38 XDP1.49 XDP1.50 XDP1.59
GND_AUD: C109.1 C113.2 U11.40
PVCC_3V3: C127.1 C542.2 C552.2 C557.2 C560.2 C563.1 L26.2 R321.1 R325.1 R329.2 R716.2 R735.2 R763.1 R765.2 R766.2 SCA1.40 SCA1.76 SCA1.89 SCA1.94 SCA1.108 U33.7 U33.8
V0.85A_VID0: CPU1.AN11 TP73.1
V0.85A_VID1: CPU1.AN13 TP69.1
VBAT1: BT1.1 R426.1
VBAT1_R: D7.2 Q40.G R426.2 R430.1 TP53.1
VCC: C278.1 C281.1 C586.1 C628.1 D9.A F4.1 F6.1 LPC1.8 PC91.1 PR80.2 PR87.1 PR208.1 PR216.1 PU11.6 R67.1 R68.1 R233.1 R475.1 R535.1 R704.1 RN19.3(B) RN19.4(B) U26.13 U26.14 U40.6
VCC3: C138.1 C139.1 C140.1 C141.1 C147.2 C157.1 C159.1 C195.1 C196.1 C214.1 C263.1 C268.1 C400.2 C407.1 C412.1 C413.1 C414.1 C415.1 C529.1 C531.1 C584.1 C585.1 D1.K DIMM1.255 DIMM2.255 F2.1 KBC1.4 L13.1 LPC1.4 PR190.1 Q35.S Q36.2 Q36.5 Q72.5 R9.1 R33.1 R76.2 R84.1 R97.1 R102.2 R160.1 R162.2 R164.2 R165.1 R166.2 R167.2 R172.2 R188.1 R189.1 R192.1 R224.1 R225.1 R235.1 R292.2 R312.1 R315.1 R316.1 R324.1 R332.1 R342.1 R343.2 R353.2 R354.1 R355.1 R381.1 R400.1 R425.1 R433.1 R434.2 R467.1 R473.1 R501.1 R524.2 R527.1 R540.2 R541.1 R584.1 R626.2 R628.2 R633.1 R634.1 R640.2 R641.2 R642.2 R643.2 R649.2 R650.2 R726.1 R745.1 R784.2 R792.1 R793.1 R794.1 R795.1 R796.1 R797.1 R798.2 R826.1 R841.1 R842.1 R877.1 RN1.1(A) RN1.2(A) RN6.1(A) RN6.2(A) RN10.3(B) RN10.4(B) RN11.3(B) RN11.4(B) RN15.1(A) RN15.2(A) RN16.3(B) RN16.4(B) RN17.1(A) RN17.2(A) RN18.3(B) RN18.4(B) RN21.1(A) RN21.2(A) U11.7 U11.11 U12.1 U17.11 U17.37 U26.8 U26.9 U28.11 U35.3
VCC3_CAM: C11.1 C15.1 C17.1 F1.2 F2.2 R79.2 R84.2 WEBCM1.3
VCC5_33_CT1: C277.1 U26.12
VCC5_33_CT2: C273.1 U26.10
VCC5_33_EN: C615.1 R861.1 U26.3 U26.5
VCC5_PANEL: C449.2 C451.2 C453.1 C630.1 LVDS1.2 LVDS1.3 Q55.S R258.1 R675.1 R693.1 R882.2 U40.1
VCC_CORE: C19.1 C20.1 C310.1 C313.1 C317.1 C318.1 C322.1 C324.1 C325.1 C326.1 C327.1 C328.1 C329.1 C332.1 C335.1 C336.1 C342.1 C345.1 CPU1.A30 CPU1.A34 CPU1.A39 CPU1.A44 CPU1.AK33 CPU1.AK35 CPU1.AK37 CPU1.AK38 CPU1.AK40 CPU1.AL33 CPU1.AL37 CPU1.AL40 CPU1.AM32 CPU1.AM33 CPU1.AM35 CPU1.AM37 CPU1.AM38 CPU1.G30 CPU1.G32 CPU1.G33 CPU1.G35 CPU1.G37 CPU1.G38 CPU1.G40 CPU1.G42 CPU1.J30 CPU1.J33 CPU1.J37 CPU1.J40 CPU1.K33 CPU1.K35 CPU1.K37 CPU1.K38 CPU1.K40 CPU1.K42 CPU1.K43 PC40.1 PC45.1 PC46.1 PC47.1 PC48.1 PC49.1 PC50.1 PC51.1 PC52.1 PC53.1 PC54.1 PC55.1 PC56.1 PC57.1 PC58.1 PC195.1 PC196.1 PC201.1 PC202.1 PC211.1 PC212.1 PC214.1 PC215.1 PC216.1 PC217.1 PC220.1 PC221.1 PC222.1 PC223.1 PC224.1 PC225.1 PC238.1 PC239.1 PC241.1 PC242.1 PC243.1 PC244.1 PC245.1 PC246.1 PG12.2 PL4.2 PT8.1 PT10.1 R566.1
VCC_FAN: C285.1 F4.2 FANC3.2 R57.1 R535.2
VCCCORE_SENSE: CPU1.E32 PG8.2 R566.2
VCCCOREG0: CPU1.K32 TP58.1
VCCCOREG1: CPU1.AK32 TP57.1
VCCGT_SENSE: CPU1.J70 PG4.2 R69.2
VCCIO_EN_C_1: Q13.6 Q14.G R157.1
VCCIO_EN_C_2: Q13.2 R159.2
VCCIO_EN_C_3: PC67.1 Q13.5 R120.1 R158.2
VCCIO_EN_C_4: PR47.2 Q13.1 Q13.3
VCCIO_VR_FB: CPU1.AM23 R567.2
VCCK_1V1: C534.2 C559.2 C631.1 L31.2 SCA1.51 SCA1.93 SCA1.109
VCCRTCEXT: C43.1 CPU1.BB10
VCCSA_SENSE: CPU1.H20 PG9.2 R568.2
VCCSENSE_EDRAM_VR: CPU1.AC63 R549.2
VCCSENSE_EOPIO_VR: CPU1.AL63 R555.2
VCCST_GD_1: Q1.2 R38.2
VCCST_GD_2: Q1.5 Q1.6 R29.1
VCCST_GD_CPU: CPU1.B65 R70.2
VCCST_GD_R: C633.1 Q1.3 R3.1 R65.2 R70.1 U1.4
VCCSTG_EN: D16.1 PC256.1 Q14.D R171.1 U4.4
VCCSTU_EN: D16.2 PC68.1 Q11.D R121.1 U3.4
VCCSTU_EN_C_1: Q10.6 Q11.G R116.1
VCCSTU_EN_C_2: Q10.2 R109.2
VCCSTU_EN_C_3: PC59.1 Q10.5 R118.1
VCCSTU_EN_C_4: PR31.2 Q10.1 Q10.3
VDDQ_BLEED_R1: Q9.6 R117.2
VDDQ_BLEED_R2: Q9.2 Q9.3 R106.2
VSS_AY3: CPU1.AY3 R193.2
VSS_AY71: CPU1.AY71 R66.2
VSSCORE_SENSE: CPU1.E33 PG7.2 R565.1
VSSGT_SENSE: CPU1.J69 PG3.2 R75.1
VSSIO_VR_FB: CPU1.AM22 R572.1
VSSSA_SENSE: CPU1.H21 PG10.2 R573.1
VSSSENSE_EDRAM_VR: CPU1.AE63 R556.1
VSSSENSE_EOPIO_VR: CPU1.AJ62 R552.1
1D0V_S5: C48.1 C54.1 PC75.1 PC78.1 PL6.2 PR39.1 PT12.1 PT14.1 R138.1 R139.1 R140.1 R141.1 R142.1 R144.1 R146.1 R148.1 R149.1 R150.1 R156.1 R180.1 R533.1 R615.1 R627.1 U3.1 U3.2 U3.9 U4.1 U4.2 U4.9
1D2V_VCCSFR_OC: C357.1 CPU1.AL23 R571.1
1D2V_VDDQ_CPUCLK: C319.1 C320.1 CPU1.AM40 R563.2
1D8V_EDRAM: CPU1.G61 CPU1.H63
1D8V_S5: PC82.1 PC83.2 PC85.1 PR53.1 PU10.3 PU10.4 R177.1 R178.1 R179.2 R208.1 R209.1 R630.1
1D8V_SIP_S5: C68.1 CPU1.AA1 R179.1
1D8V_VCCPGPPF: CPU1.AF16 R178.2
1P8V_PWR_PG: PR48.1 R220.1
2D5V_VPP: C418.1 C419.1 C423.1 C424.1 DIMM1.257 DIMM1.259 DIMM2.257 DIMM2.259 PR175.2 PR176.2
3D3V_1D8V_VCCHDA: C371.1 CPU1.AJ19 R122.1 R622.2 R630.2
3D3V_1D8V_VCCPGPPA: CPU1.AK15 R203.2 R209.2
3D3V_1D8V_VCCPGPPD: CPU1.Y15 R177.2 R181.2
3D3V_1D8V_VCCPSPI: CPU1.AJ16 R207.2 R208.2
3D3V_AUX_KBC: PR103.1 PR105.1 PR106.1 Q41.D R268.1 R372.1 R382.1 R441.2 R447.2 R744.2 R748.2 R752.2 R759.1 R762.2 R777.1 R874.2 RN9.1(A) RN9.2(A) RN13.1(A) RN13.2(A) U32.5
3D3V_AUX_KBC_VCC: C545.1 C546.1 C555.1 C561.1 C562.1 C566.1 KBC1.19 KBC1.46 KBC1.76 KBC1.88 KBC1.115 R752.1
3D3V_VCCPDSW: C606.1 CPU1.AD17 CPU1.AD18 CPU1.AJ17 R135.1 R216.2 R226.1 R230.2 R595.1 U38.6 U38.7 U38.8
3D3V_VCCPGPPB: CPU1.AG15 R210.2
3D3V_VCCPGPPC: C69.1 CPU1.Y16 R184.2
3D3V_VCCPGPPE: C67.1 CPU1.T16 R175.2
3D3V_VCCPGPPG: CPU1.AD15 R619.2
3D3V_VCCPRIM: C63.1 CPU1.AJ21 CPU1.V19 R151.1 R161.2
3D3V_VCCPRTCPRIM: C72.1 C73.1 CPU1.AK17 R204.2
3P3V_SPI: C103.1 R265.2 R268.2 RN5.1(A) RN5.2(A) SRCON1.8 U8.8
14MHZ_IN_SCALAR: C184.1 R423.2 SCA1.118 X4.3
14MHZ_OUT_SCALAR: C186.1 R423.1 SCA1.117 X4.1
1117_ADJ: R818.1 R822.2 U35.1
2136_HPD_C: R347.2 R356.1 R363.2 RN21.4(B)
+V_1P05_VGA: C89.1 C90.1 C91.1 C92.1 C443.1 C444.1 C445.1 C450.1 C455.2 C456.1 C462.1 C463.2 C464.1 C465.1 C466.1 GPU1.AA10 GPU1.AA12 GPU1.AA13 GPU1.AA16 GPU1.AA18 GPU1.AA19 GPU1.AA20 GPU1.AA21 GPU1.AA22 GPU1.AB22 GPU1.AB23 GPU1.AC23 GPU1.AC24 GPU1.AD24 GPU1.AD25 GPU1.AE25 GPU1.AE26 GPU1.AE27 GPU1.AF26 GPU1.AF27 L7.1 L8.1 L23.2 PR64.2 PR67.2 R237.1 R667.2
+V_1P05_VGA_DISCHIG: Q21.6 R237.2
+V_1P35_VGA: C85.1 C93.1 C102.1 C105.1 C114.1 C118.1 C120.1 C121.1 C149.1 C150.1 C151.2 C152.1 C426.1 C428.1 C429.1 C430.1 C431.1 C432.1 C459.1 C461.1 C469.1 C479.1 C480.1 C481.1 C482.1 C483.1 C489.1 C490.1 C491.1 C492.1 C502.1 C503.1 C504.1 C505.2 C506.1 C516.1 C517.1 C520.1 C521.1 C526.1 GPU1.B26 GPU1.C25 GPU1.E23 GPU1.E26 GPU1.F14 GPU1.F21 GPU1.G13 GPU1.G14 GPU1.G15 GPU1.G16 GPU1.G18 GPU1.G19 GPU1.G20 GPU1.G21 GPU1.H24 GPU1.H26 GPU1.J21 GPU1.K21 GPU1.L22 GPU1.L24 GPU1.L26 GPU1.M21 GPU1.N21 GPU1.R21 GPU1.T21 GPU1.V21 GPU1.W21 PR76.2 PR78.2 PR79.2 PR81.2 PR83.2 PR85.2 PR222.1 PR227.1 R295.1 R657.1 R664.1 R671.1 R679.1 R680.2 R686.2 R688.1 R690.2 R872.1 VRAM1.B1 VRAM1.B3 VRAM1.B12 VRAM1.B14 VRAM1.C5 VRAM1.C10 VRAM1.D1 VRAM1.D3 VRAM1.D11 VRAM1.D12 VRAM1.D14 VRAM1.E5 VRAM1.E10 VRAM1.F1 VRAM1.F3 VRAM1.F12 VRAM1.F14 VRAM1.G1 VRAM1.G2 VRAM1.G4 VRAM1.G11 VRAM1.G13 VRAM1.G14 VRAM1.H3 VRAM1.H12 VRAM1.K3 VRAM1.K12 VRAM1.L1 VRAM1.L2 VRAM1.L4 VRAM1.L11 VRAM1.L13 VRAM1.L14 VRAM1.M1 VRAM1.M3 VRAM1.M12 VRAM1.M14 VRAM1.N5 VRAM1.N10 VRAM1.P1 VRAM1.P3 VRAM1.P11 VRAM1.P12 VRAM1.P14 VRAM1.R5 VRAM1.R10 VRAM1.T1 VRAM1.T3 VRAM1.T12 VRAM1.T14 VRAM2.B1 VRAM2.B3 VRAM2.B12 VRAM2.B14 VRAM2.C5 VRAM2.C10 VRAM2.D1 VRAM2.D3 VRAM2.D11 VRAM2.D12 VRAM2.D14 VRAM2.E5 VRAM2.E10 VRAM2.F1 VRAM2.F3 VRAM2.F12 VRAM2.F14 VRAM2.G1 VRAM2.G2 VRAM2.G4 VRAM2.G11 VRAM2.G13 VRAM2.G14 VRAM2.H3 VRAM2.H12 VRAM2.K3 VRAM2.K12 VRAM2.L1 VRAM2.L2 VRAM2.L4 VRAM2.L11 VRAM2.L13 VRAM2.L14 VRAM2.M1 VRAM2.M3 VRAM2.M12 VRAM2.M14 VRAM2.N5 VRAM2.N10 VRAM2.P1 VRAM2.P3 VRAM2.P11 VRAM2.P12 VRAM2.P14 VRAM2.R5 VRAM2.R10 VRAM2.T1 VRAM2.T3 VRAM2.T12 VRAM2.T14 VRAM3.B1 VRAM3.B3 VRAM3.B12 VRAM3.B14 VRAM3.C5 VRAM3.C10 VRAM3.D1 VRAM3.D3 VRAM3.D11 VRAM3.D12 VRAM3.D14 VRAM3.E5 VRAM3.E10 VRAM3.F1 VRAM3.F3 VRAM3.F12 VRAM3.F14 VRAM3.G1 VRAM3.G2 VRAM3.G4 VRAM3.G11 VRAM3.G13 VRAM3.G14 VRAM3.H3 VRAM3.H12 VRAM3.K3 VRAM3.K12 VRAM3.L1 VRAM3.L2 VRAM3.L4 VRAM3.L11 VRAM3.L13 VRAM3.L14 VRAM3.M1 VRAM3.M3 VRAM3.M12 VRAM3.M14 VRAM3.N5 VRAM3.N10 VRAM3.P1 VRAM3.P3 VRAM3.P11 VRAM3.P12 VRAM3.P14 VRAM3.R5 VRAM3.R10 VRAM3.T1 VRAM3.T3 VRAM3.T12 VRAM3.T14 VRAM4.B1 VRAM4.B3 VRAM4.B12 VRAM4.B14 VRAM4.C5 VRAM4.C10 VRAM4.D1 VRAM4.D3 VRAM4.D11 VRAM4.D12 VRAM4.D14 VRAM4.E5 VRAM4.E10 VRAM4.F1 VRAM4.F3 VRAM4.F12 VRAM4.F14 VRAM4.G1 VRAM4.G2 VRAM4.G4 VRAM4.G11 VRAM4.G13 VRAM4.G14 VRAM4.H3 VRAM4.H12 VRAM4.K3 VRAM4.K12 VRAM4.L1 VRAM4.L2 VRAM4.L4 VRAM4.L11 VRAM4.L13 VRAM4.L14 VRAM4.M1 VRAM4.M3 VRAM4.M12 VRAM4.M14 VRAM4.N5 VRAM4.N10 VRAM4.P1 VRAM4.P3 VRAM4.P11 VRAM4.P12 VRAM4.P14 VRAM4.R5 VRAM4.R10 VRAM4.T1 VRAM4.T3 VRAM4.T12 VRAM4.T14
+V_1P35_VGA_DISCHG: Q53.6 R664.2
+V_3P3_VGA: C130.2 C457.2 C458.2 C460.1 C627.1 GPU1.AA8 GPU1.AA9 GPU1.AB8 PR65.1 PR66.1 PR84.1 PR209.2 PR211.2 PR230.1 PR232.1 Q35.D Q54.G Q60.2 Q60.5 R262.1 R267.1 R269.1 R274.1 R275.1 R285.1 R286.1 R287.1 R289.2 R290.2 R308.1 R309.1 R322.1 R334.1 R343.1 R670.1 R673.1 R674.1 R683.1 R685.2 R702.1 R703.1 U7.5 U10.3 U10.7 U10.8
+V_VGA_CORE: C104.1 C467.1 C468.2 C470.1 C471.1 C472.2 C473.2 C474.2 C475.2 C476.2 C477.2 C478.1 C484.2 C485.2 C486.2 C487.2 C493.2 C494.2 C495.2 C496.2 C497.2 C498.1 C499.1 GPU1.K10 GPU1.K12 GPU1.K14 GPU1.K16 GPU1.K18 GPU1.L11 GPU1.L13 GPU1.L15 GPU1.L17 GPU1.M10 GPU1.M12 GPU1.M14 GPU1.M16 GPU1.M18 GPU1.N11 GPU1.N13 GPU1.N15 GPU1.N17 GPU1.P10 GPU1.P12 GPU1.P14 GPU1.P16 GPU1.P18 GPU1.R11 GPU1.R13 GPU1.R15 GPU1.R17 GPU1.T10 GPU1.T12 GPU1.T14 GPU1.T16 GPU1.T18 GPU1.U11 GPU1.U13 GPU1.U15 GPU1.U17 GPU1.V10 GPU1.V12 GPU1.V14 GPU1.V16 GPU1.V18 PC98.1 PL7.2 PR215.1 PT15.1 PT16.1 R666.1
AC_IN: PQ3.D PQ11.2 PR102.2
AC_IN_KBC#: KBC1.65 PQ5.6 Q63.G R744.1
AC_OK#: PQ3.G PR101.2 PU34.5 R359.1
AC_PRESENT: CPU1.AY15 KBC1.52 R759.2
AC_PROTECT: PR248.2 PR249.1 PR252.1 PU34.3 R785.1
AD+_2: C240.2 PQ7.C R469.2 R478.1 U19.4
AD+_G_1: PQ11.5 PQ11.6 PR99.2
AD+_G_2: PR99.1 PR107.2 PU16.4
AD+_TO_SYS: PG18.1 PR98.1 PR107.1 PR109.2 PR110.2 PR257.2 PR258.2 PR259.2 PR260.2 PU16.1 PU16.2 PU16.3
AD_IA: PR256.2 R367.1
AD_IA_HW1: KBC1.54 PQ4.2 RN9.4(B)
AD_IA_HW2: KBC1.55 PQ4.5 RN9.3(B)
AD_IA_R: C164.1 KBC1.97 R367.2 R368.1
AD_JK: C240.1 C589.1 C590.1 D12.K DCIN1.1 DCIN2.1 DCIN2.2 DCIN2.3 DCIN2.8 DCIN2.9 DCIN2.10 PQ7.E PR111.1 R457.1 R469.1 U19.1 U19.2 U19.3
AD_OFF_L: PQ6.C PQ7.B
ADAPTOR_PSID: D20.3 KBC1.99 R802.2 R803.2
ADAPTOR_PSID_R: Q74.S R802.1
ADC_3V3: C541.1 L25.2 SCA1.25
ADP_V_DET: PQ5.2 R455.1 R457.2
ALERT#: R355.2 U12.6
ALL_PWRGD_2: Q37.D R353.1 R357.1
ALL_SYS_PWRGD: KBC1.10 PR30.2 Q4.D R38.1 R76.1 R80.2 R108.1 U1.2
AMD_RST#_L: D17.2 R245.1 R246.2 R247.2 R251.1 U7.4
AMP_SPKR_L: R377.1 R385.1 R391.2 U13.4
AMP_SPKR_R: R375.1 R386.1 R392.2 U13.8
AMP_SWITCH_C_L: R373.1 R377.2
AMP_SWITCH_C_R: R369.1 R375.2
AUD_BEEP_C: C125.2 U11.2
AUD_BEEP_R: C125.1 R282.2 R305.2 R306.1 R889.2
AUD_DMIC_CLK: C155.2 L12.2 WEBCM1.4
AUD_DMIC_CLK_R: R349.1 U11.12
AUD_DMIC_CLK_R_1: L12.1 R349.2
AUD_DMIC_DATA: C148.2 R348.1 WEBCM1.5
AUD_DMIC_DATA_R: R348.2 U11.13
AUD_GP3: R312.2 U11.3
AUD_LINK_BCLK: C129.2 R124.1 U11.5
AUD_LINK_RST_N: R127.1 R337.1 U11.6
AUD_LINK_RST_N_2: Q71.1 Q71.3
AUD_LINK_RST_N_R: C134.1 Q30.B R337.2
AUD_LINK_SDIN: CPU1.BA21 R327.1
AUD_LINK_SDIN_1: R327.2 U11.8
AUD_LINK_SDO: C528.2 Q57.D R123.1 R320.2
AUD_LINK_SDO_1: C528.1 Q57.G R704.2
AUD_LINK_SDO_N: Q57.S R320.1 U11.4
AUD_LINK_SDO_R1: JMP1.5 R654.1
AUD_LINK_SYNC: R126.1 U11.9
AUD_REGREF: C136.1 U11.10
AUDIO_3V3: C533.1 C536.1 L24.2 SCA1.62
BAT_ALERT: BAT2.7 R374.2
BAT_IN#: KBC1.14 R447.1 RN14.2(A)
BAT_IN#_1: BAT2.5 PC278.1 PL15.1 RN14.7(B)
BATA_SCL_1: BAT2.3 PC276.1 PL13.1 RN14.5(B)
BATA_SDA_1: BAT2.4 PC277.1 PL14.1 RN14.6(B)
BATLOW#: CPU1.AU13 R595.2
BATT_AMBER_LED#_C: PWRCN1.10 R850.2
BATT_WHITE_LED#_C: PWRCN1.8 Q77.C Q78.3 R843.2
BIST_DISABLE: KBC1.118 R706.1 R707.1 R708.2
BIST_DISABLE_1: Q58.5 R707.2
BIST_EN: Q33.2 Q58.3 Q58.6 R332.2
BIST_EN_INV: KBC1.42 Q33.3 Q33.6 R324.2 SCA1.63
BIST_ENABLE: KBC1.43 R705.1
BIST_ENABLE_1: Q33.5 R705.2 R709.2 R710.1
BIST_PIN25: KBC1.82 Q56.G
BKLT_ADJ: C251.1 C252.1 R487.2 R492.2
BKLT_EN: C592.1 Q76.C R836.2 R838.2 R841.2
BKLT_EN1: Q76.B R832.2
BP_PWRGD_RST#: C1.1 R4.1 XDP1.41
BPM_CPU_N0: CPU1.C55 XDP1.21
BPM_CPU_N1: CPU1.D55 XDP1.23
BPM_CPU_N2: CPU1.B54 TP35.1
BPM_CPU_N3: CPU1.C56 TP34.1
BQ24737_REGN: PC282.2 PD3.A PR248.1 PU34.16
BT+: BAT2.1 BAT2.2 PC105.1 PC107.1 PC108.1 PC109.1 PC116.1 PC117.1 PG15.1 PR88.2 PU15.5 PU15.6 PU15.7 PU15.8
BUFRST_N: GPU1.D11 R697.1
BUZZER_SPKR_R: C183.1 R305.1
CAGND: C242.2 C243.1 C244.2 C245.2 C247.2 C248.2 C249.2 C587.2 C593.2 R481.2 R496.2 R829.2 R844.2 R845.2 R846.2 U36.15 U36.21
CATERR#_CPU: CPU1.D63 TP56.1
CBN: C154.2 U11.21
CBP: C154.1 U11.24
CE: R416.1 R761.1 R765.1 SCA1.106
CE#_1: R416.2 U33.1
CFG: R796.2 U17.23
CFG0: CPU1.E68 R20.1 XDP1.9
CFG1: CPU1.B67 XDP1.11
CFG2: CPU1.D65 R72.1 XDP1.15
CFG3: CPU1.D67 R58.1 R73.1 XDP1.17
CFG4: CPU1.E70 R74.1 XDP1.27
CFG5: CPU1.C68 XDP1.29
CFG6: CPU1.D68 XDP1.33
CFG7: CPU1.C67 XDP1.35
CFG8: CPU1.F71 XDP1.10
CFG9: CPU1.G69 XDP1.12
CFG10: CPU1.F70 XDP1.16
CFG11: CPU1.G68 XDP1.18
CFG12: CPU1.H70 XDP1.28
CFG13: CPU1.G71 XDP1.30
CFG14: CPU1.H69 XDP1.34
CFG15: CPU1.G70 XDP1.36
CFG16: CPU1.E63 XDP1.6
CFG17: CPU1.F63 XDP1.4
CFG18: CPU1.E66 XDP1.24
CFG19: CPU1.F66 XDP1.22
CFG_RCOMP: CPU1.E60 R553.1
CHG_AGND: C570.2 PC120.2 PC121.2 PC122.2 PC123.2 PC124.2 PC285.2 PQ4.1 PQ4.4 PR93.2 PR95.2 PR96.2 PR97.2
CHG_ON#: KBC1.28 PQ2.G PR103.2
CHG_SMB2_CLK: KBC1.70 PR105.2 PU34.9 RN14.4(A)
CHG_SMB2_DATA: KBC1.69 PR106.2 PU34.8 RN14.3(A)
CLINK_CLK_LAN: NGFF1.42 TP12.1
CLINK_DATA_LAN: NGFF1.40 TP11.1
CLINK_RST_LAN_N: NGFF1.38 TP13.1
CLK: R413.2 SCA1.103
CLK_1: R413.1 U33.6
CLK_CR_N: CPU1.D40 U28.6
CLK_CR_P: CPU1.C40 U28.5
CLK_GFX_N: CPU1.D42 GPU1.AD8
CLK_GFX_P: CPU1.C42 GPU1.AE8
CLK_GLAN_N: CPU1.B42 U23.16
CLK_GLAN_P: CPU1.A42 U23.15
CLK_WLAN_N: CPU1.D41 R46.2
CLK_WLAN_P: CPU1.C41 R50.2
CLKA0: GPU1.D24 R303.1 VRAM2.J12 VRAM4.J12
CLKA0#: GPU1.D25 R302.1 VRAM2.J11 VRAM4.J11
CLKA1: GPU1.N22 R660.1 VRAM1.J12 VRAM3.J12
CLKA1#: GPU1.M22 R661.1 VRAM1.J11 VRAM3.J11
CORE_PLLVDD: C98.1 C99.1 C501.1 GPU1.L6 L8.2
CPU_A16_TP: CPU1.BB9 TP38.1
CPU_A17_TP: CPU1.BA9 TP37.1
CPU_B16_TP: CPU1.AP7 TP65.1
CPU_B17_TP: CPU1.AP8 TP66.1
CPU_C18_TP: CPU1.U8 TP70.1
CPU_C19_TP: CPU1.U9 TP71.1
CPU_D4_TP: CPU1.V1 TP40.1
CPU_D5_TP: CPU1.V2 TP41.1
CPU_FAN_CTRL_SIO: KBC1.81 R40.1
CPU_FAN_TACH_SIO: KBC1.31 R60.1
CPU_POPIRCOMP: CPU1.AT16 R587.1
CPU_SCALAR_SCL: R411.2 R421.2 RN15.4(B)
CPU_SCALAR_SDA: R409.2 R422.2 RN15.3(B)
CPVEE: C144.1 U11.20
CR_CLKREQ_R: R594.1 U28.2
CRCLK_REQ_N: R594.2 R617.2 RN10.1(A)
CSI2_COMP: CPU1.E13 R591.1
DACA_VDD: GPU1.W5
DACA_VREF: C84.1 GPU1.AE2
DB_UART1_RX: KBC1.113 R394.2
DB_UART1_TX: KBC1.111 R390.2
DC_19V: C231.1 PC273.2 PR89.1 PR104.1 PR109.1 PR110.1 PR239.1 PR246.1 PR251.1 PR257.1 PR258.1 PR259.1 PR260.1 PU15.4 PU16.5 PU16.6 PU16.7 PU16.8 R465.1 U19.5 U19.6 U19.7 U19.8
DC_IN_D: PQ11.3 PR251.2
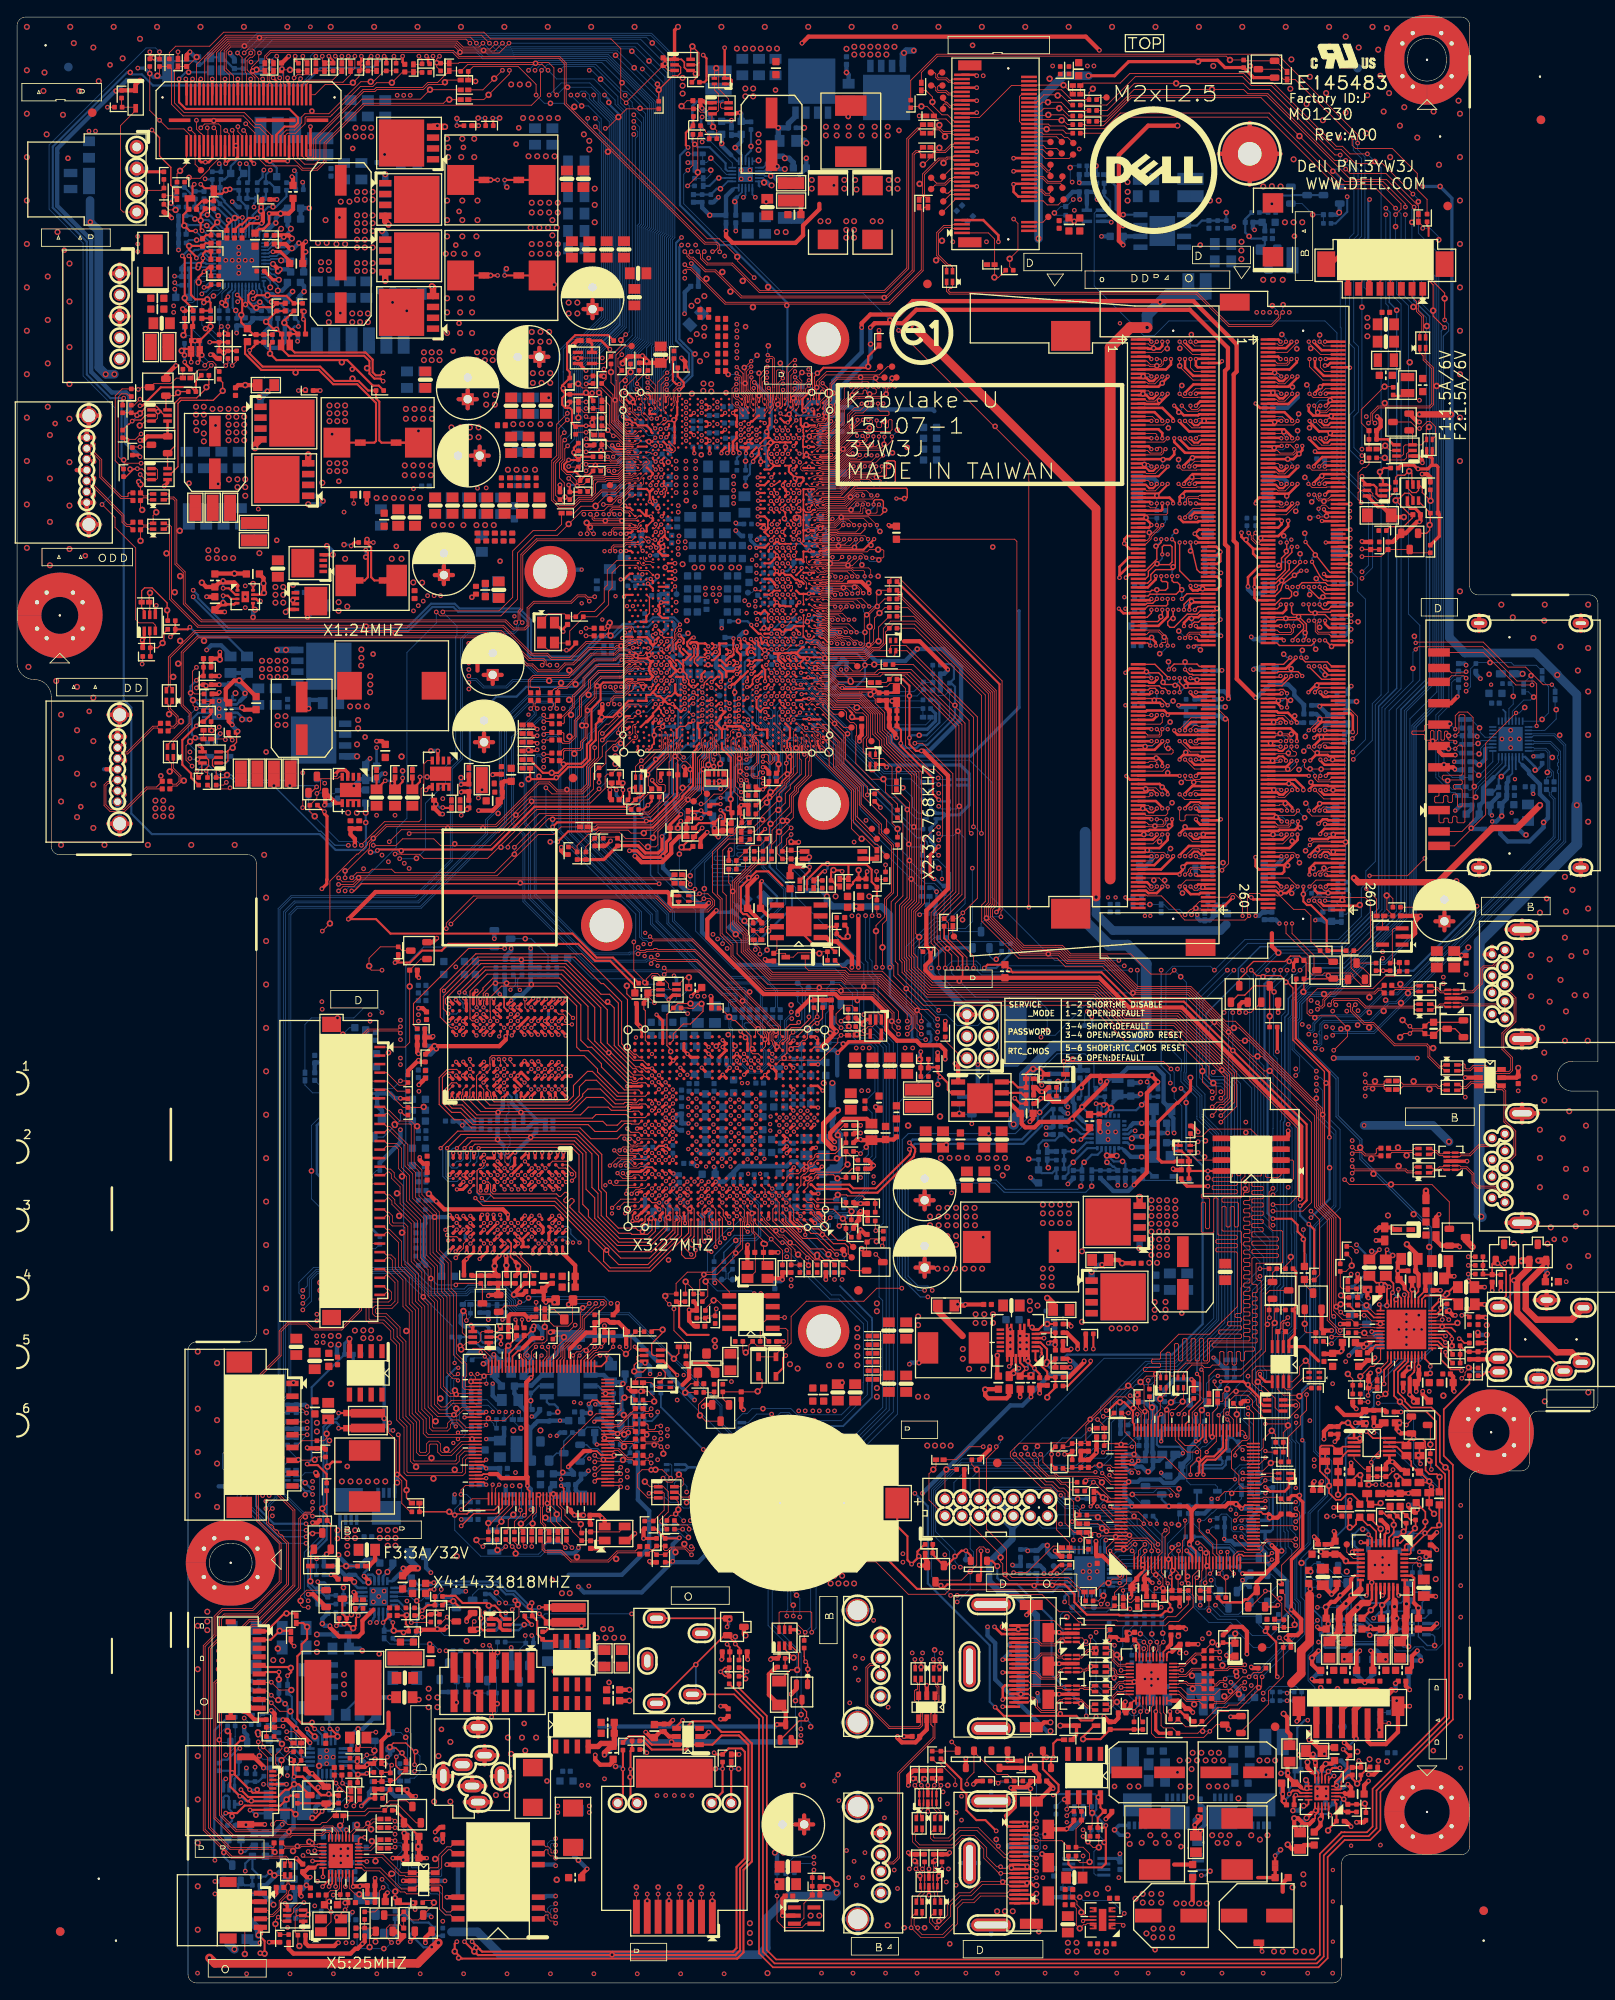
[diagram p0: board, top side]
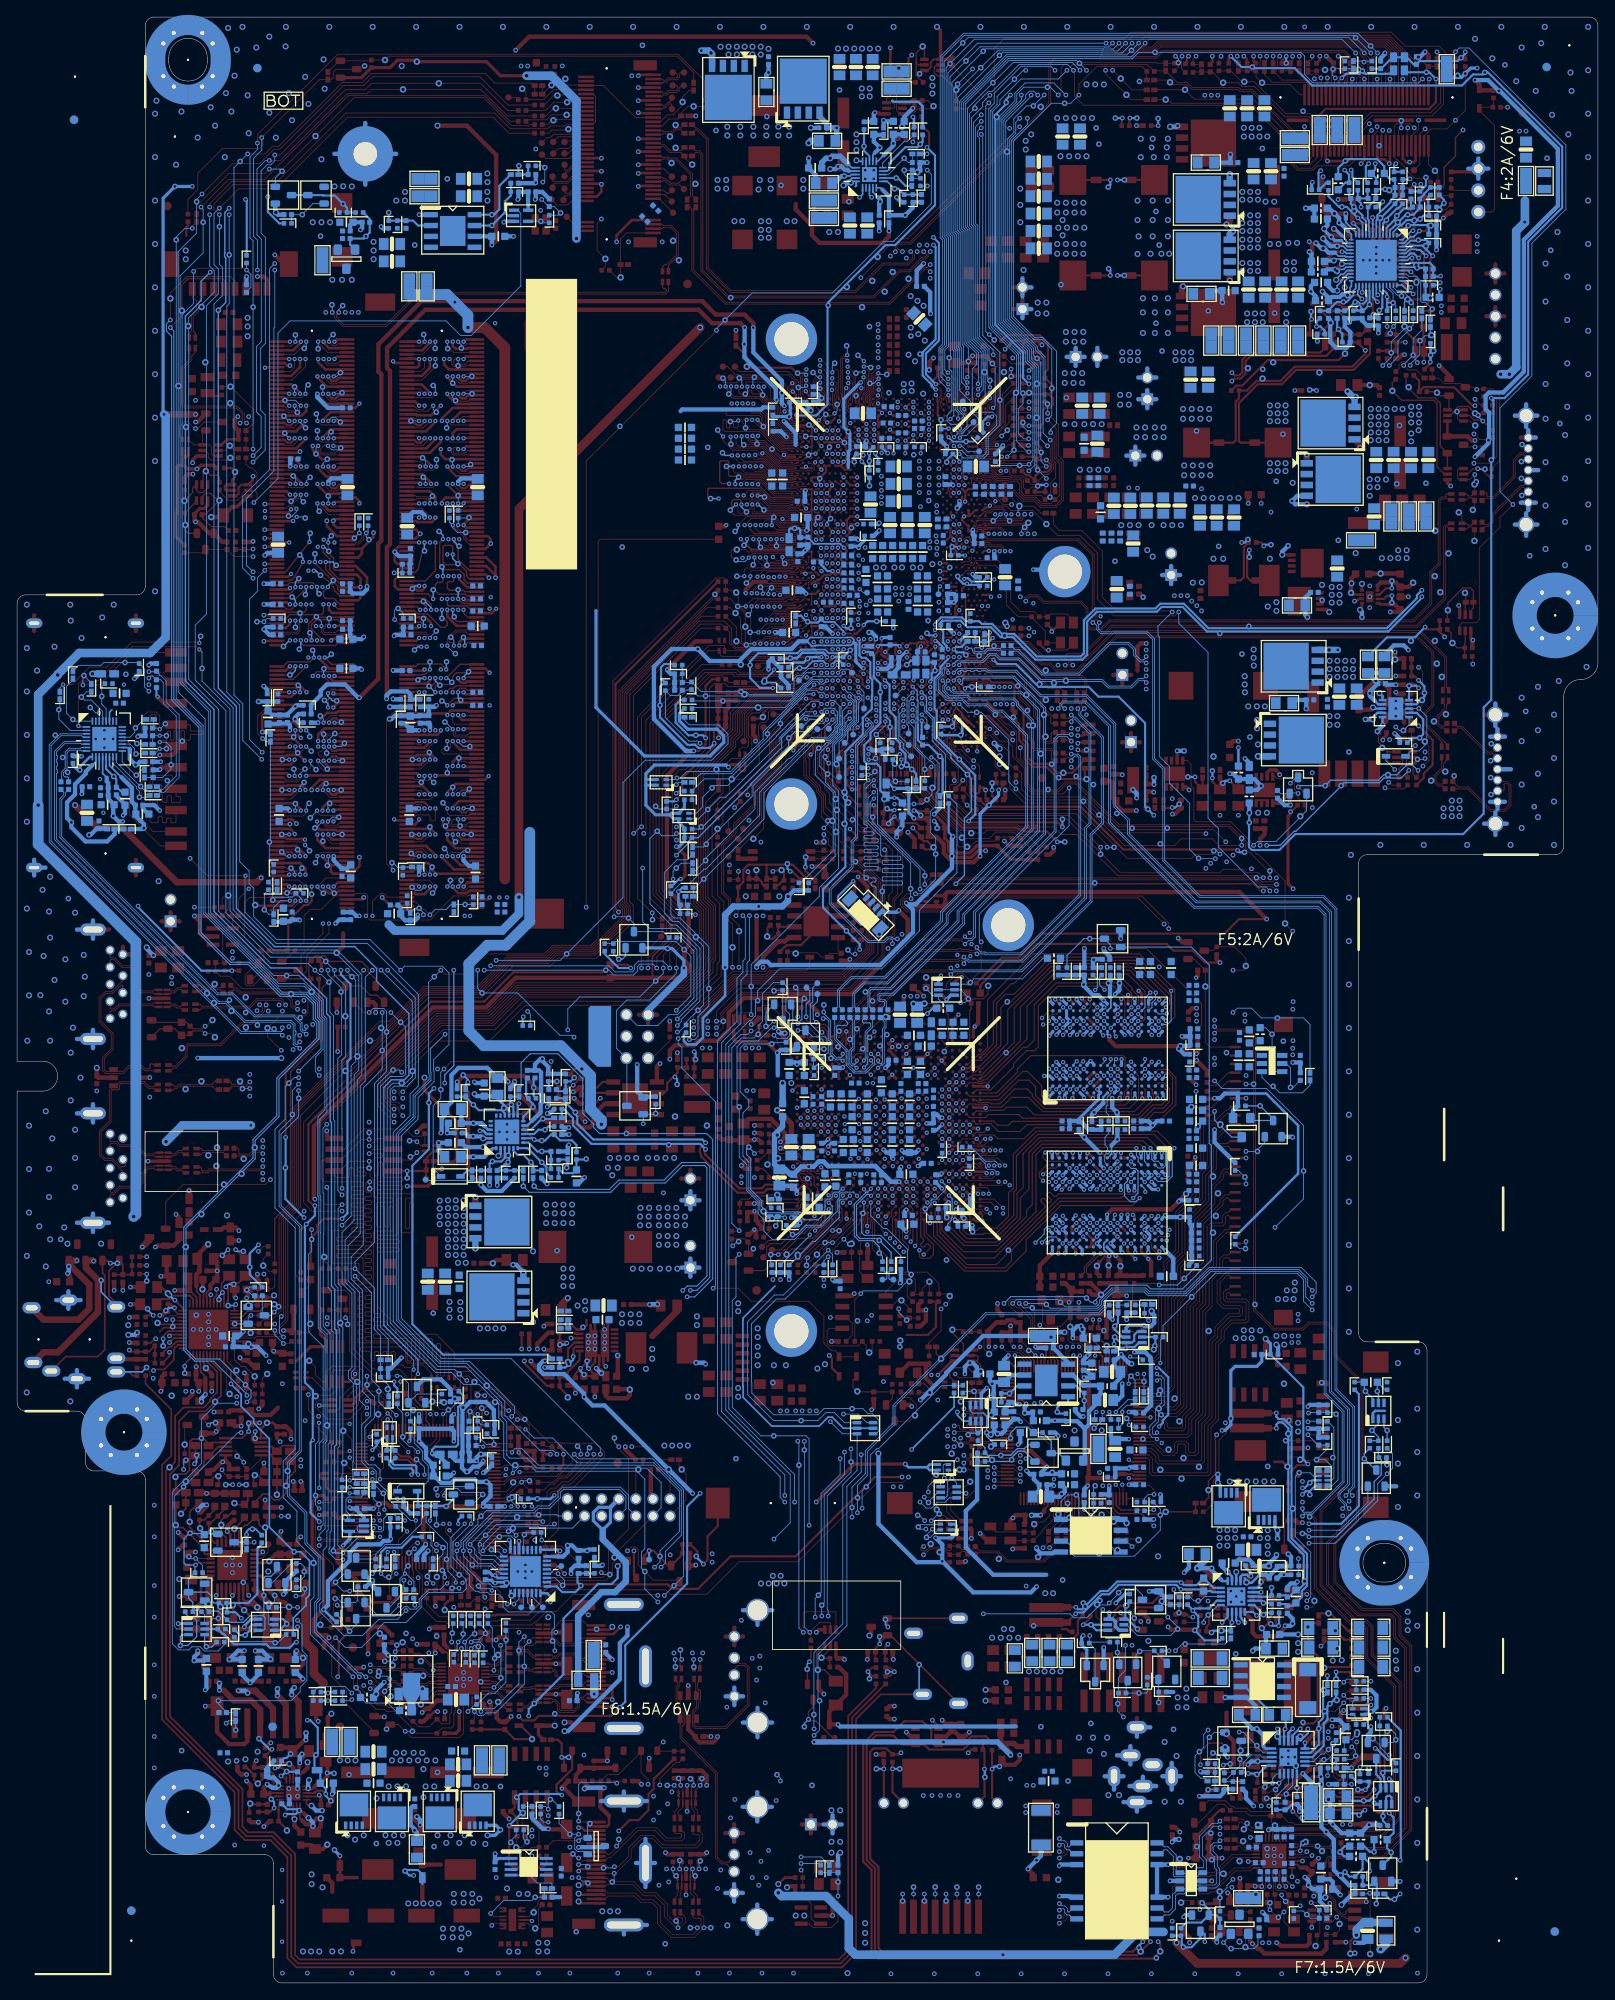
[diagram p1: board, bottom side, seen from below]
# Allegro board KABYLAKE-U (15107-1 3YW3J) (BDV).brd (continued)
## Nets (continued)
DCBATOUT: C218.1 C527.1 F3.1 L14.1 PC100.1 PC118.1 PC269.1 PC270.1 PC273.1 PC279.1 PC280.1 PG17.1 PR32.2 PR33.2 PR34.2 PR35.1 PR36.1 PR49.1 PR50.1 PR51.1 PR52.1 PR73.1 PR91.1 PR98.2 PR114.1 PR122.1 PR123.1 PR128.1 PR129.1 PR130.1 PR134.1 PR142.1 PR191.1 PR192.1 PR193.1 PR194.1 PR195.1 PR196.1 PR198.2 PR199.2 PR200.2 PR201.1 PR236.1 PR237.1 PR238.1 PR261.1 PR262.1 PR264.1 PR265.1 PT17.1 PU13.5 PU13.6 PU13.7 PU13.8 PU15.1 PU15.2 PU15.3 PU31.5 PU31.6 PU31.7 PU31.8 PU32.5 PU32.6 PU32.7 PU32.8 R454.1 R742.1 R746.1
DCBATOUT_1D35V_VGA: PC102.1 PC271.1 PC272.1 PR236.2 PR237.2 PR238.2 PU14.8 PU14.9 PU14.22 PU14.24
DCBATOUT_RT6575_1: PC127.1 PR114.2 PU17.12
DCBATOUT_RT6575_3V: PC288.1 PC292.1 PC297.1 PR264.2 PR265.2 PT18.1 PU36.5 PU36.6 PU36.7 PU36.8
DCBATOUT_RT6575_5V: PC286.1 PC287.1 PC291.1 PR261.2 PR262.2 PT19.1 PU35.5 PU35.6 PU35.7 PU35.8
DCBATOUT_VCCGTA: PC139.1 PC140.1 PC152.1 PC153.1 PC299.1 PC304.1 PR5.2 PR128.2 PR129.2 PR130.2 PR134.2 PR142.2 PT2.1 PU1.5 PU1.6 PU1.7 PU1.8
DCBATOUT_VCCGTB: PC184.1 PC185.1 PC186.1 PC187.1 PR191.2 PR192.2 PR193.2 PR194.2 PR195.2 PR196.2 PT5.1 PU4.5 PU4.6 PU4.7 PU4.8
DCBATOUT_VCCSA: PC69.1 PC240.1 PR35.2 PR36.2 PR201.2 PU7.5 PU7.6 PU7.7 PU7.8
DCBATOUT_VCORE: PC203.1 PC204.1 PC205.1 PC206.1 PC303.1 PR32.1 PR33.1 PR34.1 PR198.1 PR199.1 PR200.1 PT9.1 PU6.5 PU6.6 PU6.7 PU6.8 PU26.5 PU26.6 PU26.7 PU26.8
DCIN_EN: R792.2 U17.13
DDC5V_HDMI: C253.1 D11.3 R506.1 R509.1 R847.1 U22.8
DDC5V_HDMI_R: D11.2 R475.2
DDC_WP: R507.2 SCA1.34
DDC_WP_1: R506.2 R507.1 U22.7
DDCBUF: R793.2 R806.1 U17.14
DDPB_CTRL_CLK_CONN: HDMI1.15 HDMI3.5 R471.2 U15.1 U15.10 U17.32
DDPB_CTRL_DATA_CONN: HDMI1.16 HDMI3.4 R472.2 U15.2 U15.9 U17.33
DDR0_A_ALERT_N: CPU1.AW50 DIMM1.116
DDR0_A_PARITY: CPU1.AT52 DIMM1.143
DDR1_B_ALERT_N: CPU1.AN43 DIMM2.116
DDR1_B_PARITY: CPU1.AP43 DIMM2.143
DDR_VDDQ: C297.1 C301.1 C306.1 C307.1 C308.1 C309.1 C311.1 C312.1 C314.1 C315.1 C316.1 C323.1 C330.1 C331.1 C333.1 C337.1 C338.1 C339.1 C341.1 C343.1 C346.1 C347.1 C349.1 C355.1 C356.1 C358.1 C359.1 C360.1 C361.1 C363.1 C364.1 C366.1 C369.1 C377.1 C378.1 C382.1 C386.1 C409.1 C410.1 C635.1 C636.1 CPU1.AU23 CPU1.AU28 CPU1.AU35 CPU1.AU42 CPU1.BB23 CPU1.BB32 CPU1.BB41 CPU1.BB47 CPU1.BB51 DIMM1.12 DIMM1.33 DIMM1.54 DIMM1.75 DIMM1.96 DIMM1.111 DIMM1.112 DIMM1.117 DIMM1.118 DIMM1.123 DIMM1.124 DIMM1.129 DIMM1.130 DIMM1.135 DIMM1.136 DIMM1.141 DIMM1.142 DIMM1.147 DIMM1.148 DIMM1.153 DIMM1.154 DIMM1.159 DIMM1.160 DIMM1.163 DIMM1.178 DIMM1.199 DIMM1.220 DIMM1.241 DIMM2.12 DIMM2.33 DIMM2.54 DIMM2.75 DIMM2.96 DIMM2.111 DIMM2.112 DIMM2.117 DIMM2.118 DIMM2.123 DIMM2.124 DIMM2.129 DIMM2.130 DIMM2.135 DIMM2.136 DIMM2.141 DIMM2.142 DIMM2.147 DIMM2.148 DIMM2.153 DIMM2.154 DIMM2.159 DIMM2.160 DIMM2.163 DIMM2.178 DIMM2.199 DIMM2.220 DIMM2.241 PC7.1 PC96.1 PC97.1 PC200.1 PC209.1 PC251.1 PL1.2 PR3.1 PR6.1 PR170.2 PT3.1 PT4.1 PU11.5 PU11.9 R117.1 R118.2 R120.2 R545.1 R557.1 R558.1 R559.1 R560.1 R563.1 R569.1 R570.1 R571.2 R597.1 R600.1 R602.1
DDR_VREF_CA: C385.1 CPU1.AY67 R599.1
DDR_VTT_CNTL: CPU1.AW67 R42.1 R47.1
DDR_VTT_CNTL_L1: C5.1 Q3.2 R42.2
DDR_VTT_CNTL_L2: Q3.5 Q3.6 RN1.3(B)
DDR_VTT_CNTL_L3: Q3.3 R48.1 RN1.4(B)
DDSP_B_HPD_CONN: HDMI1.19 HDMI3.1 R451.1 U15.4 U15.7 U17.28
DET_HDMI#: Q70.G R479.1 R480.2 SCA1.38 U21.2
DET_HDMI_C: HDMI2.11 HDMI4.9 R479.2
DGPU_PWR_EN#: Q21.2 Q21.3 Q53.2 Q53.5 R238.2
DIMM_CA_CPU_VREF_A_RC: C385.2 R598.1
DIMM_CA_VREF_A_R: C390.1 C391.1 C393.1 DIMM1.164 R599.2 R600.2 R605.1
DIMM_CB_CPU_VREF_A_RC: C387.2 R606.1
DIMM_CB_VREF_A_R: C388.1 C389.1 C392.1 DIMM2.164 R596.1 R597.2 R601.2
DISP_UTIL_CPU: CPU1.B52 R402.2
DP_AUXN: NGFF1.20 TP24.1
DP_AUXN_C: C187.2 R420.2
DP_AUXP: NGFF1.22 TP22.1
DP_AUXP_C: C189.2 R419.2
DP_HPD: NGFF1.31 TP17.1
DP_LANE0N_C: C169.2 SCA1.12
DP_LANE0P_C: C170.2 SCA1.11
DP_LANE1N_C: C165.2 SCA1.15
DP_LANE1P_C: C166.2 SCA1.14
DP_LANE2N_C: C160.2 SCA1.17
DP_LANE2P_C: C163.2 SCA1.16
DP_LANE3N_C: C156.2 SCA1.19
DP_LANE3P_C: C158.2 SCA1.18
DP_ML0N: NGFF1.32 TP16.1
DP_ML0P: NGFF1.34 TP14.1
DP_ML1N: NGFF1.26 TP20.1
DP_ML1P: NGFF1.28 TP18.1
DP_ML2N: NGFF1.25 TP21.1
DP_ML2P: NGFF1.27 TP19.1
DP_ML3N: NGFF1.19 TP26.1
DP_ML3P: NGFF1.21 TP23.1
DPLVDS_BL_EN: KBC1.26 R766.1 R772.1 R840.2 SCA1.97
DPLVDS_HPD: R363.1 SCA1.21
DPLVDS_PANEL_VCC: R716.1 R881.1 SCA1.64
DPLVDS_PWMIN: R399.1 R402.1 SCA1.100
DPLVDS_PWMOUT: R486.2 SCA1.101
DS3_PWRCTL: R859.2 U38.4
EAPD_DEPOP: R800.1 U11.14
EAPD_DEPOP_1: R798.1 R799.1 R800.2
EAPD_DEPOP_2: Q71.5 R799.2
EAPD_DEPOP_2_D: Q72.6 R790.2
EC_AGND: C547.2 C548.1 C550.2 C551.2 KBC1.103 R733.2 R741.2 R750.1
EC_AVCC: C550.1 C551.1 KBC1.102 R734.1 R740.2 R748.1
EC_BEEP_GPIO: KBC1.121 R891.1
EC_BEEP_GPIO_R: Q84.G R890.1 R891.2
EC_CLEAR_RTC: KBC1.32 Q83.G R888.1
EC_HDMI_PD_N: KBC1.117 Q43.G R466.2
EC_LAN_DISABLE_N: KBC1.119 R522.1 R767.1
EC_OSD_MENU: KBC1.56 R378.1
EC_PECI: R115.2 R438.2
EC_PECI_R: C199.1 KBC1.13 R438.1
EC_PROCHOT#: KBC1.24 Q69.G R783.2 R784.1
EC_PROCHOT#_G: C571.1 PQ10.G R785.2
EC_SCI#: CPU1.N9 R628.1 R778.1
EC_SCI#_R: KBC1.29 R778.2
EC_SERIRQ: KBC1.125 R436.1
EC_SMI#: CPU1.G4 R779.1 RN16.2(A)
EC_SMI#_R: KBC1.11 R779.2
EC_SPI_CLK: KBC1.92 RN7.1(A)
EC_SPI_CS0#: KBC1.90 RN7.2(A)
EC_SPI_SI: KBC1.87 RN8.1(A)
EC_SPI_SO: KBC1.86 RN8.2(A)
EC_SPKR: KBC1.22 R889.1
EC_SWI#: CPU1.J3 R167.1 R410.1
EC_SWI#_R: KBC1.123 R410.2
EC_VBKUP: KBC1.114 R397.1
EC_VTT: C198.1 KBC1.12 R444.2
ECRST#: C538.1 KBC1.85 Q59.E R725.2 R874.1
EDID_RDY: CPU1.J1 R152.1 SCA1.46
EDP_AUX_CPU_N: C187.1 CPU1.E45 R424.1 R425.2
EDP_AUX_CPU_P: C189.1 CPU1.F45 R432.1 R433.2
EDP_HPD_CPU: CPU1.L10 R347.1
EDP_RCOMP_CPU: CPU1.E52 R562.2
EDP_TX_CPU_N0: C169.1 CPU1.C47
EDP_TX_CPU_N1: C165.1 CPU1.D46
EDP_TX_CPU_N2: C160.1 CPU1.A45
EDP_TX_CPU_N3: C156.1 CPU1.A47
EDP_TX_CPU_P0: C170.1 CPU1.C46
EDP_TX_CPU_P1: C166.1 CPU1.C45
EDP_TX_CPU_P2: C163.1 CPU1.B45
EDP_TX_CPU_P3: C158.1 CPU1.B47
EDRAM_OPIO_RCOMP: CPU1.H66 R547.1
EMMC_RCOMP: CPU1.AT1 R168.1
EOPIO_RCOMP: CPU1.H65 R548.1
EQ: R795.2 R810.1 U17.17
ESPI_RST#: CPU1.BA11 TP39.1
EXT_PWR_GATE#: CPU1.AM10 R644.2
FB_CAL_PD_VDDQ: GPU1.D22 R686.1
FB_CAL_PU_GND: GPU1.C24 R687.1
FB_CAL_TERM_GND: GPU1.B25 R691.1
FB_PLLAVDD: C488.1 C507.1 C511.1 C512.1 C515.1 GPU1.F16 GPU1.H22 GPU1.P22 L23.1
FB_VREF: GPU1.D23 TP75.1
FBA_CMD0: GPU1.C27 VRAM2.G12 VRAM4.L12
FBA_CMD1: GPU1.C26 VRAM2.H10 VRAM4.K10
FBA_CMD2: GPU1.E24 VRAM2.H11 VRAM4.K11
FBA_CMD3: GPU1.F24 VRAM2.K11 VRAM4.H11
FBA_CMD4: GPU1.D27 VRAM2.K10 VRAM4.H10
FBA_CMD5: GPU1.D26 VRAM2.L12 VRAM4.G12
FBA_CMD6: GPU1.F25 VRAM2.K4 VRAM4.H4
FBA_CMD7: GPU1.F26 VRAM2.K5 VRAM4.H5
FBA_CMD8: GPU1.F23 VRAM2.J4 VRAM4.J4
FBA_CMD9: GPU1.G22 VRAM2.J5 VRAM4.J5
FBA_CMD10: GPU1.G23 VRAM2.H4 VRAM4.K4
FBA_CMD11: GPU1.G24 VRAM2.H5 VRAM4.K5
FBA_CMD12: GPU1.F27 VRAM2.G3 VRAM4.L3
FBA_CMD13: GPU1.G25 PR235.1 VRAM2.J2 VRAM4.J2
FBA_CMD14: GPU1.G27 PR227.2 VRAM2.J3 VRAM4.J3
FBA_CMD15: GPU1.G26 VRAM2.L3 VRAM4.G3
FBA_CMD16: GPU1.M24 VRAM1.L12 VRAM3.G12
FBA_CMD17: GPU1.M23 VRAM1.K10 VRAM3.H10
FBA_CMD18: GPU1.K24 VRAM1.K11 VRAM3.H11
FBA_CMD19: GPU1.K23 VRAM1.H11 VRAM3.K11
FBA_CMD20: GPU1.M27 VRAM1.H10 VRAM3.K10
FBA_CMD21: GPU1.M26 VRAM1.G12 VRAM3.L12
FBA_CMD22: GPU1.M25 VRAM1.H4 VRAM3.K4
FBA_CMD23: GPU1.K26 VRAM1.H5 VRAM3.K5
FBA_CMD24: GPU1.K22 VRAM1.J4 VRAM3.J4
FBA_CMD25: GPU1.J23 VRAM1.J5 VRAM3.J5
FBA_CMD26: GPU1.J25 VRAM1.K4 VRAM3.H4
FBA_CMD27: GPU1.J24 VRAM1.K5 VRAM3.H5
FBA_CMD28: GPU1.K27 VRAM1.L3 VRAM3.G3
FBA_CMD29: GPU1.K25 PR221.1 VRAM1.J2 VRAM3.J2
FBA_CMD30: GPU1.J27 PR222.2 VRAM1.J3 VRAM3.J3
FBA_CMD31: GPU1.J26 VRAM1.G3 VRAM3.L3
FBA_DBI0: GPU1.D19 VRAM2.D2
FBA_DBI1: GPU1.D14 VRAM4.P13
FBA_DBI2: GPU1.C17 VRAM2.P13
FBA_DBI3: GPU1.C22 VRAM4.D2
FBA_DBI4: GPU1.P24 VRAM3.D2
FBA_DBI5: GPU1.W24 VRAM1.P13
FBA_DBI6: GPU1.AA25 VRAM3.P13
FBA_DBI7: GPU1.U25 VRAM1.D2
FBA_DEBUG0: GPU1.F22 R690.1
FBA_DEBUG1: GPU1.J22 R680.1
FBA_EDC0: GPU1.E19 VRAM2.C2
FBA_EDC1: GPU1.C15 VRAM4.R13
FBA_EDC2: GPU1.B16 VRAM2.R13
FBA_EDC3: GPU1.B22 VRAM4.C2
FBA_EDC4: GPU1.R25 VRAM3.C2
FBA_EDC5: GPU1.W23 VRAM1.R13
FBA_EDC6: GPU1.AB26 VRAM3.R13
FBA_EDC7: GPU1.T26 VRAM1.C2
FBA_SEN0: R684.1 VRAM2.J10 VRAM4.J10
FBA_SEN2: R253.1 VRAM1.J10 VRAM3.J10
FBA_SOE0: R676.1 VRAM2.J1
FBA_SOE1: R872.2 VRAM4.J1
FBA_SOE2: R679.2 VRAM1.J1
FBA_SOE3: R873.1 VRAM3.J1
FBA_VREF_FET_H: Q51.D R249.2 R658.2
FBA_VREF_FET_L: Q31.D R298.2 R698.2
FBA_VREFC0: C117.1 R295.2 R298.1 R299.1 VRAM2.J14 VRAM4.J14
FBA_VREFC1: C427.1 R657.2 R658.1 R659.1 VRAM1.J14 VRAM3.J14
FBA_VREFD_H: C87.1 C88.1 C446.1 C448.1 R249.1 R669.1 R671.2 VRAM1.A10 VRAM1.U10 VRAM3.A10 VRAM3.U10
FBA_VREFD_L: C522.1 C523.1 C524.1 C525.1 R688.2 R694.1 R698.1 VRAM2.A10 VRAM2.U10 VRAM4.A10 VRAM4.U10
FBA_WCK01: GPU1.D18 VRAM2.D4 VRAM4.P4
FBA_WCK01#: GPU1.C18 VRAM2.D5 VRAM4.P5
FBA_WCK23: GPU1.D17 VRAM2.P4 VRAM4.D4
FBA_WCK23#: GPU1.D16 VRAM2.P5 VRAM4.D5
FBA_WCK45: GPU1.T24 VRAM1.P4 VRAM3.D4
FBA_WCK45#: GPU1.U24 VRAM1.P5 VRAM3.D5
FBA_WCK67: GPU1.V24 VRAM1.D4 VRAM3.P4
FBA_WCK67#: GPU1.V25 VRAM1.D5 VRAM3.P5
FBA_ZQ0: R301.1 VRAM2.J13
FBA_ZQ1: R300.1 VRAM4.J13
FBA_ZQ2: R663.1 VRAM1.J13
FBA_ZQ3: R662.1 VRAM3.J13
FIVR_EN_R: R19.2 R20.2 XDP1.45
FLASH_WP: R763.2 R764.1 SCA1.96 U33.3
FWH_ID0: LPC1.6 R379.2
GC6_FB_EN: GPU1.C6 R264.2
GDI_1V1: C537.1 L31.1 L32.1 R719.1 U31.6
GDI_1V1_SCALAR: C543.1 C632.1 L32.2 SCA1.20
GPD2/LAN_WAKE#: CPU1.AM15 R226.2
GPIO: R588.1 U28.28
GPIO0_TPM: TP80.1 U34.29
GPIO1_FBVDDQCTL: GPU1.B2 TP51.1
GPIO1_TPM: TP81.1 U34.30
GPIO2_BL_PWM: GPU1.D6 R692.1
GPIO2_TPM: R434.1 U34.3
GPIO3_PPEN_R: GPU1.C7 R288.1
GPIO4_BLEN: GPU1.F9 R701.1
GPIO5_PWM_VID_BOOT_EN: GPU1.A3 TP50.1
GPIO6_FB_CLAMP_TGL_REQ: GPU1.A4 TP49.1
GPIO7_3D_STEREO: GPU1.B6 R699.1
GPIO8_OVERT#: GPU1.A6 Q28.S R290.1
GPIO9_ALERT#: GPU1.F8 PR212.1 R685.1
GPIO10_MEM_VREF_CTL: GPU1.C5 Q31.G Q51.G R700.1
GPIO11_PWM_VID: GPU1.E7 PR233.2
GPIO12_AC_DETECT: GPU1.D7 R289.1
GPIO13_NVVDD_PSI: GPU1.B4 R682.2
GPIO_FB_CLAMP_GPU: GPU1.F3 PR69.1 R264.1
GPP_B2/VRALERT#: CPU1.AM11 TP72.1
GPP_B18/GSPI0_MOSI: CPU1.AR7 R633.2
GPP_B22/GSPI1_MOSI: CPU1.AN5 R160.2
GPP_B23/SML1ALERT#: CPU1.AM7 R645.1
GPP_C2/SMBALERT#: CPU1.R10 R620.1
GPP_C5/SML0ALERT#: CPU1.W1 R613.1 R618.2
GPU_1D05V: PC93.1 PC94.1 PC95.1 PR61.2 PR64.1 PR67.1 PU11.3 PU11.4
GPU_1D05V_EN: D2.A PC89.1 PR62.2 PU11.8
GPU_1D05V_FB_M: PC88.2 PR59.2 PR60.1 PU11.2
GPU_1D05V_FB_M1: PC88.1 PR59.1 PR61.1
GPU_1D05V_PG: D6.A PC274.1 PR240.2 PU14.2
GPU_1D05V_POK: PC90.1 PR66.2 PR240.1 PU11.7
GPU_1D05V_VGA_EN: PR62.1 PR210.1
GPU_ALLPWR: CPU1.A7 KBC1.96 R350.1
GPU_CLK0_TER: C124.2 R302.2 R303.2
GPU_CLK1_TER: C425.2 R660.2 R661.2
GPU_DMINUS: R696.1 TP77.1
GPU_DMINUS_G: GPU1.E12 R696.2
GPU_DPLUS: R695.1 TP76.1
GPU_DPLUS_G: GPU1.F12 R695.2
GPU_PEX_RST_HOLD: D17.1 R670.2 R689.1
GPU_PEX_RST_HOLD_GPU#: GPU1.C4 R689.2
GPU_TESTMODE: GPU1.AD9 R241.1
GPU_THERM_SHUTDOWN_N: PR229.1 TP74.1
GPU_VCC3_CTL: C153.2 D5.A Q37.G R354.2
GPU_VCC3_CTL_2: C147.1 Q35.G R357.2
H_CPUPWRGD: CPU1.A68 R71.1
H_PROCHOT_N: PQ10.D PR23.2 PR182.1 PR244.1 Q69.D R81.2 R82.1 R783.1
H_RCIN#: CPU1.AW13 R404.1 RN10.2(A)
H_RCIN#_R: KBC1.122 R404.2
HDA_BITCLK_CPU: CPU1.AY22 R124.2
HDA_RST#_CPU: CPU1.AW22 R127.2
HDA_SDOUT_CPU: CPU1.BB22 Q52.C R122.2 R123.2 R654.2
HDA_SPKR: CPU1.AW5 R282.1 R634.2
HDA_SYNC_CPU: CPU1.BA22 R126.2
HDMI1_CK+: D13.4 D13.7 R490.2 SCA1.8 TR12.4
HDMI1_CK+_C: HDMI2.10 HDMI4.10 TR12.3
HDMI1_CK-: D13.5 D13.6 R491.2 SCA1.9 TR12.1
HDMI1_CK-_C: HDMI2.12 HDMI4.8 TR12.2
HDMI1_CTRL_CLK_CPU: CPU1.L13 R473.2 U17.38
HDMI1_CTRL_DATA_CPU: CPU1.L12 R467.2 R468.2 U17.39
HDMI1_D0+: D13.1 D13.10 R488.2 SCA1.2 TR11.4
HDMI1_D0+_C: HDMI2.7 HDMI4.13 TR11.3
HDMI1_D0-: D13.2 D13.9 R489.2 SCA1.1 TR11.1
HDMI1_D0-_C: HDMI2.9 HDMI4.11 TR11.2
HDMI1_D1+: D14.2 D14.9 R512.2 SCA1.5 TR15.4
HDMI1_D1+_C: HDMI2.4 HDMI4.16 TR15.3
HDMI1_D1-: D14.1 D14.10 R513.2 SCA1.4 TR15.1
HDMI1_D1-_C: HDMI2.6 HDMI4.14 TR15.2
HDMI1_D2+: D14.5 D14.6 R510.2 SCA1.7 TR14.4
HDMI1_D2+_C: HDMI2.1 HDMI4.19 TR14.3
HDMI1_D2-: D14.4 D14.7 R511.2 SCA1.6 TR14.1
HDMI1_D2-_C: HDMI2.3 HDMI4.17 TR14.2
HDMI1_DATA_CPU_N0: C230.1 CPU1.E55
HDMI1_DATA_CPU_N1: C223.1 CPU1.E58
HDMI1_DATA_CPU_N2: C220.1 CPU1.F53
HDMI1_DATA_CPU_N3: C215.1 CPU1.F56
HDMI1_DATA_CPU_P0: C232.1 CPU1.F55
HDMI1_DATA_CPU_P1: C228.1 CPU1.F58
HDMI1_DATA_CPU_P2: C221.1 CPU1.G53
HDMI1_DATA_CPU_P3: C219.1 CPU1.G56
HDMI1_DATA_IC_N0: C230.2 U17.2
HDMI1_DATA_IC_N1: C223.2 U17.5
HDMI1_DATA_IC_N2: C220.2 U17.7
HDMI1_DATA_IC_N3: C215.2 U17.10
HDMI1_DATA_IC_P0: C232.2 U17.1
HDMI1_DATA_IC_P1: C228.2 U17.4
HDMI1_DATA_IC_P2: C221.2 U17.6
HDMI1_DATA_IC_P3: C219.2 U17.9
HDMI1_OUT_HPD: CPU1.L9 R458.1 U17.3
HDMI1_SCL: R417.2 R504.2
HDMI1_SDA: R418.2 R848.2
HDMI_5V: C250.1 D10.3 D11.1 HDMI2.18 HDMI4.2 R485.1 R495.1
HDMI_DET_SIO: KBC1.9 Q70.D R791.2
HDMI_HDCP_READY: R494.1 R495.2 SCA1.22 U21.1
HDMI_HPDET: HDMI2.19 HDMI4.1 R493.1 R494.2
HDMI_IN_DET#_R: Q70.S R782.1
HDMI_LANE0_DN: HDMI1.3 HDMI3.17 TR10.2 U18.2 U18.9
HDMI_LANE0_DP: HDMI1.1 HDMI3.19 TR10.3 U18.1 U18.10
HDMI_LANE0_IC_DN: TR10.1 U17.29
HDMI_LANE0_IC_DP: TR10.4 U17.30
HDMI_LANE1_DN: HDMI1.6 HDMI3.14 TR9.2 U18.5 U18.6
HDMI_LANE1_DP: HDMI1.4 HDMI3.16 TR9.3 U18.4 U18.7
HDMI_LANE1_IC_DN: TR9.1 U17.26
HDMI_LANE1_IC_DP: TR9.4 U17.27
HDMI_LANE2_DN: HDMI1.9 HDMI3.11 TR6.2 U16.4 U16.7
HDMI_LANE2_DP: HDMI1.7 HDMI3.13 TR6.3 U16.5 U16.6
HDMI_LANE2_IC_DN: TR6.1 U17.24
HDMI_LANE2_IC_DP: TR6.4 U17.25
HDMI_LANE3_DN: HDMI1.12 HDMI3.8 TR5.2 U16.1 U16.10
HDMI_LANE3_DP: HDMI1.10 HDMI3.10 TR5.3 U16.2 U16.9
HDMI_LANE3_IC_DN: TR5.1 U17.21
HDMI_LANE3_IC_DP: TR5.4 U17.22
HDMI_OUT_DDC_VCC: C237.1 D9.K R471.1 R472.1
HDMI_SCL_IN: HDMI2.15 HDMI4.5 R508.1 U37.1
HDMI_SCL_IN_C: C254.1 R504.1 R508.2 R509.2 U22.6
HDMI_SDA_IN: HDMI2.16 HDMI4.4 R849.1 U37.2
HDMI_SDA_IN_C: C594.1 R847.2 R848.1 R849.2 U22.5
HP_MUTE: R330.2 R801.1 SCA1.36
HP_MUTE_D: Q72.3 R789.2
HP_MUTE_L: Q72.4 R801.2
HPOL_CON: C116.1 Q26.1 R280.2 R281.2 R294.2 R297.1 UHS1.1
HPOR_CON: C137.1 Q26.2 R338.2 R340.2 R341.1 R344.2 UHS1.2
HPOUT-JD: R346.1 UHS1.6
HPOUT-L: R294.1 U11.26
HPOUT-R: R340.1 U11.27
HSI_C_DN8: C399.1 U28.8
HSI_C_DP8: C398.1 U28.7
HSI_LAN_DN1_R: C259.1 U23.18
HSI_LAN_DP1_R: C257.1 U23.17
I2CC_SCL_PU: GPU1.A9 R286.2
I2CC_SDA_PU: GPU1.B9 R287.2
I2CS_SCL_G: GPU1.D9 Q60.1 R703.2
I2CS_SDA_G: GPU1.D8 Q60.4 R702.2
IFPA_IOVDD: GPU1.W6
IFPAB_PLLVDD_1: GPU1.V7
IFPAB_PLLVDD_2: GPU1.W7
IFPB_IOVDD: GPU1.Y6
IFPC_IOVDD: GPU1.P6
IFPC_PLLVDD_1: GPU1.M7
IFPC_PLLVDD_2: GPU1.N7
IFPD_IOVDD: GPU1.R6
IFPD_PLLVDD_1: GPU1.R7
IFPD_PLLVDD_2: GPU1.T7
IFPE_IOVDD: GPU1.H6
IFPEF_PLLVDD_1: GPU1.J7
IFPEF_PLLVDD_2: GPU1.K7
IFPF_IOVDD: GPU1.J6
IMS: KBC1.35 LVDS1.4 R255.1 R731.2
IMS_SCALAR: R731.1 R735.1 R736.2 SCA1.78
INIT_3V: LPC1.2 R381.2
ISEN1: R446.2 U36.17
ISEN2: R452.2 U36.16
ISEN3: R814.2 U36.14
ISEN4: R815.2 U36.13
ISET: R797.2 R820.1 U17.34
ISP_CLK1: Q39.6 Q65.6 RN19.1(A)
ISP_DAT1: Q39.3 Q65.3 RN19.2(A)
ISW: C242.1 R824.2 U36.19
ISW_1: Q75.1 Q75.2 Q75.3 R807.1 R811.1 R824.1
ITP_PMODE: CPU1.E8 R531.2 R532.2
JACK_PSID: DCIN1.3 DCIN2.4 DCIN2.11 L30.1
JDREF: R313.1 U11.35
JTAG_TCLK: GPU1.AE5 R242.2
JTAG_TDI: GPU1.AE6 TP46.1
JTAG_TDO: GPU1.AF6 TP47.1
JTAG_TMS: GPU1.AD6 TP48.1
JTAG_TRST: GPU1.AG4 R240.2
KBC_ON#_GATE: C205.1 Q41.G Q67.G R448.2
KBC_ON#_GATE_L: R448.1 R449.2 R450.1
KBC_VCORF: C182.1 KBC1.44
L_AD0: CPU1.AY13 KBC1.126 LPC1.5 U34.24
L_AD1: CPU1.BA13 KBC1.127 LPC1.7 U34.21
L_AD2: CPU1.BB13 KBC1.128 LPC1.9 U34.18
L_AD3: CPU1.AY12 KBC1.1 LPC1.11 U34.15
L_BKLTCTL: CPU1.R11 R399.2
L_FRAME_N: KBC1.3 LPC1.13 R153.1 U34.20
L_FRAME_N_R: CPU1.BA12 R153.2
LAN_DISABLE_N: CPU1.AW17 R216.1 R869.1
LAN_DISABLE_N_1: C624.1 Q80.B R869.2 R871.1
LAN_DISABLE_N_2: Q47.B Q80.C R870.1 R871.2
LAN_DISABLE_N_3: Q46.C Q47.C R520.2 R523.1
LAN_DISABLE_N_4: C280.1 PC295.2 Q81.G R523.2
LAN_DISABLE_V3: C279.1 Q46.B R522.2 R524.1
LAN_LEDACT_R#: R892.2 RJ1.10
LAN_MDI0_C_DN: RJ1.2 XF1.2
LAN_MDI0_C_DP: RJ1.1 XF1.1
LAN_MDI0_DN: U23.2 U24.3 XF1.11
LAN_MDI0_DP: U23.1 U24.4 XF1.12
LAN_MDI1_C_DN: RJ1.6 XF1.6
LAN_MDI1_C_DP: RJ1.3 XF1.5
LAN_MDI1_DN: U23.5 U24.1 XF1.7
LAN_MDI1_DP: U23.4 U24.6 XF1.8
LAN_MDI2_C_DN: RJ1.5 XF2.5
LAN_MDI2_C_DP: RJ1.4 XF2.6
LAN_MDI2_DN: P3.2 U39.3 XF2.8
LAN_MDI2_DN_R: P3.1 U23.7
LAN_MDI2_DP: P4.2 U39.4 XF2.7
LAN_MDI2_DP_R: P4.1 U23.6
LAN_MDI3_C_DN: RJ1.8 XF2.1
LAN_MDI3_C_DP: RJ1.7 XF2.2
LAN_MDI3_DN: P1.2 U39.1 XF2.12
LAN_MDI3_DN_R: P1.1 U23.10
LAN_MDI3_DP: P2.2 U39.6 XF2.11
LAN_MDI3_DP_R: P2.1 U23.9
LAN_RSET: R519.2 U23.31
LAN_XTALI: C270.1 R521.2 U23.28 X5.1
LAN_XTALO: R518.1 R521.1 U23.29
LAN_XTALO_C: C276.1 R518.2 X5.3
LANCLK_REQ_N: Q82.D R505.2 R635.2 R636.2
LANCLK_REQ_U_N: Q82.S R505.1 R879.2 U23.12
LDR: R823.2 U36.1
LDR_1: Q75.4 R823.1
LED_5VSB: LED1.A R453.2
LEDC_ISET: R829.1 U36.12
LINE2-VREFO: R323.1 R333.1 U11.29
LINEOUT-JD: LOUT1.Q R345.1
LINEOUT-L: R463.1 U11.19
LINEOUT-R: R464.1 U11.18
LINEOUT_C-L: L19.1 R463.2
LINEOUT_C-R: L20.1 R464.2
LINEOUT_CON-L: C216.1 L19.2 LOUT1.4 Q42.1
LINEOUT_CON-R: C217.1 L20.2 LOUT1.1 Q42.2
LINK_ACTIVITY_N: R892.1 U20.4 U23.27
LINK_PWR: R482.1 RJ1.9
LPC_CLK0: R174.1 R380.2
LPC_CLK0_R: CPU1.AW9 R174.2
LPC_CLK1: KBC1.2 R186.1 U34.19
LPC_CLK1_R: CPU1.AY9 R186.2
LPC_CLK_D: LPC1.1 R380.1
LPC_CLKRUN#_CPU: CPU1.AW11 R623.2 R626.1
LPC_PME#: KBC1.91 R360.1
LPC_PME_N: CPU1.AU11 R339.1 R342.2 R360.2
LPCPD_TPM: TP79.1 U34.28
LPF: C593.1 U36.9
LPSS_UART2_RXD: CN1.3 CPU1.AD1 R162.1
LPSS_UART2_TXD: CN1.2 CPU1.AD2 R164.1
LVDS_BL_ADJ: R486.1 R492.1 R500.1 R501.2
LVDS_DET_A*: KBC1.59 LVDS1.17 R681.2
LVDS_DET_B*: KBC1.58 Q16.D R223.2
LVDS_DET_B_C*: C80.1 LVDS1.1 Q16.G
LVDS_PU_5: LVDS1.5 R258.2
LVDS_PU_6: LVDS1.6 R259.2
LVDS_PU_6_1: Q55.D R259.1
LVDS_PU_24: LVDS1.24 R693.2
LX: D21.A L21.2 Q75.5 Q75.6 Q75.7 Q75.8 R804.1
M1_SMB_CLK: NGFF1.60 R41.2
M1_SMB_DATA: NGFF1.58 R44.2
M_A_A0: CPU1.AY50 DIMM1.144
M_A_A1: CPU1.BB50 DIMM1.133
M_A_A2: CPU1.AY51 DIMM1.132
M_A_A3: CPU1.BA50 DIMM1.131
M_A_A4: CPU1.BB52 DIMM1.128
M_A_A5: CPU1.BA51 DIMM1.126
M_A_A6: CPU1.BA52 DIMM1.127
M_A_A7: CPU1.AW52 DIMM1.122
M_A_A8: CPU1.AY52 DIMM1.125
M_A_A9: CPU1.BB54 DIMM1.121
M_A_A10: CPU1.AT50 DIMM1.146
M_A_A11: CPU1.BA54 DIMM1.120
M_A_A12: CPU1.AW54 DIMM1.119
M_A_A13: CPU1.AU46 DIMM1.158
M_A_A14: CPU1.AT46 DIMM1.151
M_A_A15: CPU1.AU48 DIMM1.156
M_A_A16: CPU1.AU50 DIMM1.152
M_A_ACT_N: CPU1.BA55 DIMM1.114
M_A_BG0: CPU1.AY55 DIMM1.115
M_A_BG1: CPU1.AY54 DIMM1.113
M_A_BS0: CPU1.AU52 DIMM1.150
M_A_BS1: CPU1.AT48 DIMM1.145
M_A_CKE0: CPU1.BA56 DIMM1.109
M_A_CKE1: CPU1.BB56 DIMM1.110
M_A_CLK0: CPU1.AT53 DIMM1.137
M_A_CLK1: CPU1.AT55 DIMM1.138
M_A_CLK#0: CPU1.AU53 DIMM1.139
M_A_CLK#1: CPU1.AU55 DIMM1.140
M_A_CS#0: CPU1.AU45 DIMM1.149
M_A_CS#1: CPU1.AU43 DIMM1.157
M_A_DQ0: CPU1.AL71 DIMM1.8
M_A_DQ1: CPU1.AL68 DIMM1.7
M_A_DQ2: CPU1.AN68 DIMM1.17
M_A_DQ3: CPU1.AN69 DIMM1.20
M_A_DQ4: CPU1.AL70 DIMM1.4
M_A_DQ5: CPU1.AL69 DIMM1.3
M_A_DQ6: CPU1.AN70 DIMM1.21
M_A_DQ7: CPU1.AN71 DIMM1.16
M_A_DQ8: CPU1.AR70 DIMM1.25
M_A_DQ9: CPU1.AR68 DIMM1.24
M_A_DQ10: CPU1.AU71 DIMM1.42
M_A_DQ11: CPU1.AU68 DIMM1.38
M_A_DQ12: CPU1.AR71 DIMM1.29
M_A_DQ13: CPU1.AR69 DIMM1.28
M_A_DQ14: CPU1.AU70 DIMM1.41
M_A_DQ15: CPU1.AU69 DIMM1.37
M_A_DQ16: CPU1.BB65 DIMM1.45
M_A_DQ17: CPU1.AW65 DIMM1.49
M_A_DQ18: CPU1.AW63 DIMM1.59
M_A_DQ19: CPU1.AY63 DIMM1.63
M_A_DQ20: CPU1.BA65 DIMM1.50
M_A_DQ21: CPU1.AY65 DIMM1.46
M_A_DQ22: CPU1.BA63 DIMM1.58
M_A_DQ23: CPU1.BB63 DIMM1.62
M_A_DQ24: CPU1.BA61 DIMM1.66
M_A_DQ25: CPU1.AW61 DIMM1.67
M_A_DQ26: CPU1.BB59 DIMM1.84
M_A_DQ27: CPU1.AW59 DIMM1.80
M_A_DQ28: CPU1.BB61 DIMM1.70
M_A_DQ29: CPU1.AY61 DIMM1.71
M_A_DQ30: CPU1.BA59 DIMM1.79
M_A_DQ31: CPU1.AY59 DIMM1.83
M_A_DQ32: CPU1.AY39 DIMM1.173
M_A_DQ33: CPU1.AW39 DIMM1.170
M_A_DQ34: CPU1.AY37 DIMM1.182
M_A_DQ35: CPU1.AW37 DIMM1.187
M_A_DQ36: CPU1.BB39 DIMM1.169
M_A_DQ37: CPU1.BA39 DIMM1.174
M_A_DQ38: CPU1.BA37 DIMM1.183
M_A_DQ39: CPU1.BB37 DIMM1.186
M_A_DQ40: CPU1.AY35 DIMM1.191
M_A_DQ41: CPU1.AW35 DIMM1.190
M_A_DQ42: CPU1.AY33 DIMM1.203
M_A_DQ43: CPU1.AW33 DIMM1.207
M_A_DQ44: CPU1.BB35 DIMM1.194
M_A_DQ45: CPU1.BA35 DIMM1.195
M_A_DQ46: CPU1.BA33 DIMM1.208
M_A_DQ47: CPU1.BB33 DIMM1.204
M_A_DQ48: CPU1.AY31 DIMM1.211
M_A_DQ49: CPU1.AW31 DIMM1.212
M_A_DQ50: CPU1.AY29 DIMM1.224
M_A_DQ51: CPU1.AW29 DIMM1.229
M_A_DQ52: CPU1.BB31 DIMM1.215
M_A_DQ53: CPU1.BA31 DIMM1.216
M_A_DQ54: CPU1.BA29 DIMM1.228
M_A_DQ55: CPU1.BB29 DIMM1.225
M_A_DQ56: CPU1.AY27 DIMM1.237
M_A_DQ57: CPU1.AW27 DIMM1.236
M_A_DQ58: CPU1.AY25 DIMM1.245
M_A_DQ59: CPU1.AW25 DIMM1.249
M_A_DQ60: CPU1.BB27 DIMM1.232
M_A_DQ61: CPU1.BA27 DIMM1.233
M_A_DQ62: CPU1.BA25 DIMM1.246
M_A_DQ63: CPU1.BB25 DIMM1.250
M_A_DQS_DN0: CPU1.AM70 DIMM1.11
M_A_DQS_DN1: CPU1.AT69 DIMM1.32
M_A_DQS_DN2: CPU1.BA64 DIMM1.53
M_A_DQS_DN3: CPU1.AY60 DIMM1.74
M_A_DQS_DN4: CPU1.BA38 DIMM1.177
M_A_DQS_DN5: CPU1.AY34 DIMM1.198
M_A_DQS_DN6: CPU1.BA30 DIMM1.219
M_A_DQS_DN7: CPU1.AY26 DIMM1.240
M_A_DQS_DN8: DIMM1.95 R558.2
M_A_DQS_DP0: CPU1.AM69 DIMM1.13
M_A_DQS_DP1: CPU1.AT70 DIMM1.34
M_A_DQS_DP2: CPU1.AY64 DIMM1.55
M_A_DQS_DP3: CPU1.BA60 DIMM1.76
M_A_DQS_DP4: CPU1.AY38 DIMM1.179
M_A_DQS_DP5: CPU1.BA34 DIMM1.200
M_A_DQS_DP6: CPU1.AY30 DIMM1.221
M_A_DQS_DP7: CPU1.BA26 DIMM1.242
M_A_DQS_DP8: DIMM1.97 R557.2
M_A_EVENT#: DIMM1.134 R570.2
M_A_ODT0: CPU1.AT45 DIMM1.155
M_A_ODT1: CPU1.AT43 DIMM1.161
M_B_A0: CPU1.BA46 DIMM2.144
M_B_A1: CPU1.AY46 DIMM2.133
M_B_A2: CPU1.AY47 DIMM2.132
M_B_A3: CPU1.BB46 DIMM2.131
M_B_A4: CPU1.BA47 DIMM2.128
M_B_A5: CPU1.AY48 DIMM2.126
M_B_A6: CPU1.BA48 DIMM2.127
M_B_A7: CPU1.AP48 DIMM2.122
M_B_A8: CPU1.BB48 DIMM2.125
M_B_A9: CPU1.AP50 DIMM2.121
M_B_A10: CPU1.AW46 DIMM2.146
M_B_A11: CPU1.AN48 DIMM2.120
M_B_A12: CPU1.AN50 DIMM2.119
M_B_A13: CPU1.BA43 DIMM2.158
M_B_A14: CPU1.AY44 DIMM2.151
M_B_A15: CPU1.AY43 DIMM2.156
M_B_A16: CPU1.AW44 DIMM2.152
M_B_ACT_N: CPU1.AN53 DIMM2.114
M_B_BG0: CPU1.AP52 DIMM2.115
M_B_BG1: CPU1.AN52 DIMM2.113
M_B_BS0: CPU1.BB44 DIMM2.150
M_B_BS1: CPU1.BA44 DIMM2.145
M_B_CKE0: CPU1.AN56 DIMM2.109
M_B_CKE1: CPU1.AP55 DIMM2.110
M_B_CLK0: CPU1.AP45 DIMM2.137
M_B_CLK1: CPU1.AP46 DIMM2.138
M_B_CLK#0: CPU1.AN45 DIMM2.139
M_B_CLK#1: CPU1.AN46 DIMM2.140
M_B_CS#0: CPU1.BB42 DIMM2.149
M_B_CS#1: CPU1.AY42 DIMM2.157
M_B_DQ0: CPU1.AF65 DIMM2.28
M_B_DQ1: CPU1.AF64 DIMM2.24
M_B_DQ2: CPU1.AK65 DIMM2.42
M_B_DQ3: CPU1.AK64 DIMM2.41
M_B_DQ4: CPU1.AF66 DIMM2.29
M_B_DQ5: CPU1.AF67 DIMM2.25
M_B_DQ6: CPU1.AK67 DIMM2.37
M_B_DQ7: CPU1.AK66 DIMM2.38
M_B_DQ8: CPU1.AF70 DIMM2.8
M_B_DQ9: CPU1.AF68 DIMM2.4
M_B_DQ10: CPU1.AH71 DIMM2.21
M_B_DQ11: CPU1.AH68 DIMM2.17
M_B_DQ12: CPU1.AF71 DIMM2.3
M_B_DQ13: CPU1.AF69 DIMM2.7
M_B_DQ14: CPU1.AH70 DIMM2.16
M_B_DQ15: CPU1.AH69 DIMM2.20
M_B_DQ16: CPU1.AT66 DIMM2.58
M_B_DQ17: CPU1.AU66 DIMM2.62
M_B_DQ18: CPU1.AP65 DIMM2.46
M_B_DQ19: CPU1.AN65 DIMM2.50
M_B_DQ20: CPU1.AN66 DIMM2.49
M_B_DQ21: CPU1.AP66 DIMM2.45
M_B_DQ22: CPU1.AT65 DIMM2.63
M_B_DQ23: CPU1.AU65 DIMM2.59
M_B_DQ24: CPU1.AT61 DIMM2.71
M_B_DQ25: CPU1.AU61 DIMM2.67
M_B_DQ26: CPU1.AP60 DIMM2.80
M_B_DQ27: CPU1.AN60 DIMM2.84
M_B_DQ28: CPU1.AN61 DIMM2.66
M_B_DQ29: CPU1.AP61 DIMM2.70
M_B_DQ30: CPU1.AT60 DIMM2.83
M_B_DQ31: CPU1.AU60 DIMM2.79
M_B_DQ32: CPU1.AU40 DIMM2.174
M_B_DQ33: CPU1.AT40 DIMM2.170
M_B_DQ34: CPU1.AT37 DIMM2.183
M_B_DQ35: CPU1.AU37 DIMM2.186
M_B_DQ36: CPU1.AR40 DIMM2.173
M_B_DQ37: CPU1.AP40 DIMM2.169
M_B_DQ38: CPU1.AP37 DIMM2.182
M_B_DQ39: CPU1.AR37 DIMM2.187
M_B_DQ40: CPU1.AT33 DIMM2.195
M_B_DQ41: CPU1.AU33 DIMM2.190
M_B_DQ42: CPU1.AU30 DIMM2.208
M_B_DQ43: CPU1.AT30 DIMM2.204
M_B_DQ44: CPU1.AR33 DIMM2.194
M_B_DQ45: CPU1.AP33 DIMM2.191
M_B_DQ46: CPU1.AR30 DIMM2.203
M_B_DQ47: CPU1.AP30 DIMM2.207
M_B_DQ48: CPU1.AU27 DIMM2.225
M_B_DQ49: CPU1.AT27 DIMM2.215
M_B_DQ50: CPU1.AT25 DIMM2.228
M_B_DQ51: CPU1.AU25 DIMM2.211
M_B_DQ52: CPU1.AP27 DIMM2.216
M_B_DQ53: CPU1.AN27 DIMM2.212
M_B_DQ54: CPU1.AN25 DIMM2.224
M_B_DQ55: CPU1.AP25 DIMM2.229
M_B_DQ56: CPU1.AT22 DIMM2.236
M_B_DQ57: CPU1.AU22 DIMM2.237
M_B_DQ58: CPU1.AU21 DIMM2.232
M_B_DQ59: CPU1.AT21 DIMM2.245
M_B_DQ60: CPU1.AN22 DIMM2.249
M_B_DQ61: CPU1.AP22 DIMM2.233
M_B_DQ62: CPU1.AP21 DIMM2.246
M_B_DQ63: CPU1.AN21 DIMM2.250
M_B_DQS_DN0: CPU1.AH66 DIMM2.32
M_B_DQS_DN1: CPU1.AG69 DIMM2.11
M_B_DQS_DN2: CPU1.AR66 DIMM2.53
M_B_DQS_DN3: CPU1.AR61 DIMM2.74
M_B_DQS_DN4: CPU1.AT38 DIMM2.177
M_B_DQS_DN5: CPU1.AT32 DIMM2.198
M_B_DQS_DN6: CPU1.AR25 DIMM2.219
M_B_DQS_DN7: CPU1.AR22 DIMM2.240
M_B_DQS_DN8: DIMM2.95 R559.2
M_B_DQS_DP0: CPU1.AH65 DIMM2.34
M_B_DQS_DP1: CPU1.AG70 DIMM2.13
M_B_DQS_DP2: CPU1.AR65 DIMM2.55
M_B_DQS_DP3: CPU1.AR60 DIMM2.76
M_B_DQS_DP4: CPU1.AR38 DIMM2.179
M_B_DQS_DP5: CPU1.AR32 DIMM2.200
M_B_DQS_DP6: CPU1.AR27 DIMM2.221
M_B_DQS_DP7: CPU1.AR21 DIMM2.242
M_B_DQS_DP8: DIMM2.97 R560.2
M_B_EVENT#: DIMM2.134 R569.2
M_B_ODT0: CPU1.BA42 DIMM2.155
M_B_ODT1: CPU1.AW42 DIMM2.161
M_VREF_DQ_DIM0: C295.1 CPU1.AY68 R544.1
M_VREF_DQ_DIM0_R: R544.2 R545.2 R546.1
M_VREF_DQ_DIM0_RC: C295.2 R543.1
M_VREF_DQ_DIM1: C387.1 CPU1.BA67 R601.1
MCT_R: R514.2 RV1.2 XF1.3 XF1.4 XF2.3 XF2.4
MCT_R_1: C595.1 R514.1
MDA0: GPU1.E18 VRAM2.A4
MDA1: GPU1.F18 VRAM2.A2
MDA2: GPU1.E16 VRAM2.B4
MDA3: GPU1.F17 VRAM2.B2
MDA4: GPU1.D20 VRAM2.E4
MDA5: GPU1.D21 VRAM2.E2
MDA6: GPU1.F20 VRAM2.F4
MDA7: GPU1.E21 VRAM2.F2
MDA8: GPU1.E15 VRAM4.U11
MDA9: GPU1.D15 VRAM4.U13
MDA10: GPU1.F15 VRAM4.T11
MDA11: GPU1.F13 VRAM4.T13
MDA12: GPU1.C13 VRAM4.N11
MDA13: GPU1.B13 VRAM4.N13
MDA14: GPU1.E13 VRAM4.M11
MDA15: GPU1.D13 VRAM4.M13
MDA16: GPU1.B15 VRAM2.U11
MDA17: GPU1.C16 VRAM2.U13
MDA18: GPU1.A13 VRAM2.T11
MDA19: GPU1.A15 VRAM2.T13
MDA20: GPU1.B18 VRAM2.N11
MDA21: GPU1.A18 VRAM2.N13
MDA22: GPU1.A19 VRAM2.M11
MDA23: GPU1.C19 VRAM2.M13
MDA24: GPU1.B24 VRAM4.A4
MDA25: GPU1.C23 VRAM4.A2
MDA26: GPU1.A25 VRAM4.B4
MDA27: GPU1.A24 VRAM4.B2
MDA28: GPU1.A21 VRAM4.E4
MDA29: GPU1.B21 VRAM4.E2
MDA30: GPU1.C20 VRAM4.F4
MDA31: GPU1.C21 VRAM4.F2
MDA32: GPU1.R22 VRAM3.A4
MDA33: GPU1.R24 VRAM3.A2
MDA34: GPU1.T22 VRAM3.B4
MDA35: GPU1.R23 VRAM3.B2
MDA36: GPU1.N25 VRAM3.E4
MDA37: GPU1.N26 VRAM3.E2
MDA38: GPU1.N23 VRAM3.F4
MDA39: GPU1.N24 VRAM3.F2
MDA40: GPU1.V23 VRAM1.U11
MDA41: GPU1.V22 VRAM1.U13
MDA42: GPU1.T23 VRAM1.T11
MDA43: GPU1.U22 VRAM1.T13
MDA44: GPU1.Y24 VRAM1.N11
MDA45: GPU1.AA24 VRAM1.N13
MDA46: GPU1.Y22 VRAM1.M11
MDA47: GPU1.AA23 VRAM1.M13
MDA48: GPU1.AD27 VRAM3.U11
MDA49: GPU1.AB25 VRAM3.U13
MDA50: GPU1.AD26 VRAM3.T11
MDA51: GPU1.AC25 VRAM3.T13
MDA52: GPU1.AA27 VRAM3.N11
MDA53: GPU1.AA26 VRAM3.N13
MDA54: GPU1.W26 VRAM3.M11
MDA55: GPU1.Y25 VRAM3.M13
MDA56: GPU1.R26 VRAM1.A4
MDA57: GPU1.T25 VRAM1.A2
MDA58: GPU1.N27 VRAM1.B4
MDA59: GPU1.R27 VRAM1.B2
MDA60: GPU1.V26 VRAM1.E4
MDA61: GPU1.V27 VRAM1.E2
MDA62: GPU1.W27 VRAM1.F4
MDA63: GPU1.W25 VRAM1.F2
ME_CNTL: KBC1.23 R655.1 R656.2
ME_CNTL1: Q52.B R656.1
MEM_VTT: C417.1 C420.1 C421.1 C422.1 DIMM1.258 DIMM2.258 PR163.1 PR169.1
MHL_3V3: C554.1 L27.2 SCA1.10
MIC2-L: C112.1 U11.47
MIC2-L-1: C112.2 R281.1
MIC2-R: C111.1 U11.48
MIC2-R-1: C111.2 R344.1
MIC2-VREFO-L: R280.1 U11.1
MIC2-VREFO-R: R338.1 U11.30
MIC-CAP: C126.1 U11.36
MINI_POWER_CTRL: KBC1.27 R62.2 R441.1
MODEL_ID_DET: C547.1 KBC1.95 R733.1 R734.2
MONITOR_NAME_ID0: CPU1.BA5 SCA1.98
MONITOR_NAME_ID1: CPU1.AY5 SCA1.99
MPCIE_DISABLE_N: KBC1.40 R45.1
NCP81172_FB1: PC260.1 PR206.1
NCT_CLK: Q36.1 RN6.3(B) U12.8
NCT_DATA: Q36.4 RN6.4(B) U12.7
NGFF_ALERT#: CPU1.H2 R39.1 RN16.1(A)
NGFF_ALERT_N: NGFF1.62 R39.2
NGFF_BT_DISABLE: CPU1.W4 R49.1 R365.1
NGFF_BT_DISABLE_EC: KBC1.100 R365.2
NGFF_CLKREQ0_N: NGFF1.53 R31.1
NGFF_CLKREQ0_NGFF#: Q2.S R6.2 R31.2 R875.2
NGFF_CLKREQ1_N: NGFF1.68 R36.2
NGFF_CLKREQ1_N_TP: R36.1 TP6.1
NGFF_DETECT_PCIE: CPU1.BB7 R37.2 R166.1
NGFF_DETECT_PCIE_C: NGFF1.51 R37.1 R43.2
NGFF_DETECT_USB: CPU1.U6 R64.2
NGFF_DETECT_USB_C: NGFF1.1 R63.2 R64.1
NGFF_PCIE0_RXN: NGFF1.43 R53.1
NGFF_PCIE0_RXP: NGFF1.41 R54.1
NGFF_PCIE0_TXN: NGFF1.37 R55.1
NGFF_PCIE0_TXP: NGFF1.35 R56.1
NGFF_PCIE1_RXN: NGFF1.67 TP4.1
NGFF_PCIE1_RXP: NGFF1.65 TP3.1
NGFF_PCIE1_TXN: NGFF1.61 TP5.1
NGFF_PCIE1_TXP: NGFF1.59 TP7.1
NGFF_PEWAKE0_N: NGFF1.55 NGFF1.70 R30.1 R34.2
NGFF_POWER_CTRL_1: Q48.G R62.1
NGFF_POWER_CTRL_V2: C290.1 Q49.B R540.1
NGFF_REFCLKN0: NGFF1.49 R46.1
NGFF_REFCLKN1: NGFF1.73 TP2.1
NGFF_REFCLKP0: NGFF1.47 R50.1
NGFF_REFCLKP1: NGFF1.71 TP1.1
NGFF_W_DISABLE1_N: NGFF1.56 R45.2
NGFF_W_DISABLE2_N: NGFF1.54 R49.2
NGFFCLK_REQ_N: Q2.D R639.2 R875.1 R876.2
OS_MODE_SEL: CPU1.AC2 RN17.3(B) SCA1.47
OSD_BIST_N: KBC1.39 R476.2 R712.1
OSD_BIST_N_1: Q58.2 R712.2
OSD_CONTROL_SEL: CPU1.M2 RN17.4(B) SCA1.48
OSD_DN: C236.1 R205.2 R470.1 R474.1 SCA1.43
OSD_DN_CPU: CPU1.AD4 R205.1
OSD_DN_R: PWRCN1.2 R474.2
OSD_MENU: C588.1 R163.2 R378.2 R831.1 R834.1 SCA1.44
OSD_MENU_CPU: CPU1.M3 R163.1
OSD_MENU_R: PWRCN1.1 R831.2
OSD_UP: C246.1 R201.2 R476.1 R477.1 R483.2 SCA1.42
OSD_UP_CPU: CPU1.AD3 R201.1
OSD_UP_R: PWRCN1.3 R477.2
OZ554_ENA: C244.1 R481.1 R836.1 U36.3
OZ554_PWM: C249.1 R487.1 R496.1 U36.5
OZ554_VIN: C245.1 R484.2 U36.4
P3P3V: C161.1 C162.1 C539.1 C549.1 C553.1 L24.1 L25.1 L26.1 L27.1 L28.1 Q61.S R718.1 R729.1 R745.2 R755.1 U13.1 U31.3
P5P0V: C532.1 R711.2 U31.4
P2800_DXN: C86.2 C133.2 Q24.E R250.2 U12.3
P2800_DXP: C86.1 C133.1 Q24.B Q24.C R250.1 U12.2
PANEL_OFF: CPU1.J4 Q32.D R316.2 R317.2
PANEL_OFF_C: Q32.G R317.1 R321.2 SCA1.53
PANEL_ON: R325.2 R326.1 SCA1.52
PANEL_ON1: Q34.2 R326.2
PANEL_ON2: Q34.5 Q34.6 RN21.3(B)
PANEL_ON3: Q34.3 R339.2
PANEL_ON_1: R881.2 U40.3
PANEL_ON_2: C629.1 U40.5
PANEL_ON_3: R882.1 U40.4
PANEL_SEL1_CABLE: KBC1.107 R721.1 R813.1
PANEL_SEL1_CABLE_C: CONVT1.7 R813.2 R816.2
PANEL_SEL1_CABLE_S: R721.2 SCA1.65
PANEL_SEL2_CABLE: KBC1.106 R720.1 R819.1
PANEL_SEL2_CABLE_C: CONVT1.8 R819.2 RN20.3(B)
PANEL_SEL2_CABLE_S: R720.2 SCA1.66
PANEL_SEL3_CABLE: KBC1.105 R730.1 R827.1
PANEL_SEL3_CABLE_C: CONVT1.9 R827.2 RN20.4(B)
PANEL_SEL3_CABLE_S: R730.2 SCA1.77
PB_IN_N_1: C190.1 R362.1 R428.2 R429.2
PB_IN_SW1: D22.2 PWRCN1.6 R837.1 R839.2
PC_MONITOR_SW: R329.1 R388.2 SCA1.39 U13.5 U13.7
PC_MONITOR_SW_G: C173.2 Q38.G R387.1 R388.1
PCB_VER_ID: C548.2 KBC1.98 R740.1 R741.1
PCH_ALW_ON: KBC1.20 R859.1
PCH_AUD_RST_N: KBC1.30 R788.1
PCH_AUD_RST_N_1: Q71.2 R788.2
PCH_DPWROK: CPU1.BB20 R130.2 R358.2 R884.1 R885.1
PCH_DPWROK_EC13: KBC1.62 R885.2
PCH_DPWROK_EC76: KBC1.83 R884.2
PCH_DVI_CLK: Q39.1 R411.1
PCH_DVI_DATA: Q39.4 R409.1
PCH_JTAG_TCK: CPU1.B56 R26.2 R28.1 R113.1
PCH_JTAG_TDI: CPU1.D59 R14.1 R110.1
PCH_JTAG_TDO: CPU1.A56 R11.1 R114.1
PCH_JTAG_TMS: CPU1.C59 R15.1 R105.1
PCH_POPIRCOMP: CPU1.AU16 R593.1
PCH_PWROK: Q7.D R102.1 R217.1 TP82.1
PCH_PWROK_C_1: Q7.G Q8.6 R77.2
PCH_PWROK_C_2: Q8.2 R108.2
PCH_PWROK_C_3: Q8.5 R78.2
PCH_RTCRST_DOWN: JMP1.2 R254.1
PCH_RTCRST_PULLUP: C381.1 CPU1.AM16 JMP1.1 Q83.D R589.1 R590.2
PCH_SATA_LED_1: Q78.5 Q78.6 R851.2
PCH_SATA_LED_R: Q78.2 R833.2
PCH_SRTCRSTB_PULLUP: C379.1 CPU1.AN18 R578.2 R585.1 R589.2
PCH_SYSPWROK_G: Q29.G R291.1 R292.1
PCH_THERMTRIP_N: R94.2 R96.1
PCH_WAKE_N: CPU1.BB15 R136.1
PCIE_CLKREQ1_CPU_N: CPU1.AT7 R636.1
PCIE_CLKREQ2_CPU_N: CPU1.AT8 R639.1
PCIE_CLKREQ3_CPU_N: CPU1.AT10 R617.1
PCIE_RST#: NGFF1.52 NGFF1.66 R754.2
PCIE_RX_CPU_N4: C259.2 CPU1.F16
PCIE_RX_CPU_N5: CPU1.G18 R53.2
PCIE_RX_CPU_N8: C399.2 CPU1.E22
PCIE_RX_CPU_P4: C257.2 CPU1.E16
PCIE_RX_CPU_P5: CPU1.F18 R54.2
PCIE_RX_CPU_P8: C398.2 CPU1.E23
PCIE_TX_CON_N4: C33.1 U23.14
PCIE_TX_CON_N5: C374.1 R55.2
PCIE_TX_CON_N8: C28.1 U28.4
PCIE_TX_CON_P4: C34.1 U23.13
PCIE_TX_CON_P5: C370.1 R56.2
PCIE_TX_CON_P8: C29.1 U28.3
PCIE_TX_CPU_N4: C33.2 CPU1.C19
PCIE_TX_CPU_N5: C374.2 CPU1.D20
PCIE_TX_CPU_N8: C28.2 CPU1.B23
PCIE_TX_CPU_P4: C34.2 CPU1.D19
PCIE_TX_CPU_P5: C370.2 CPU1.C20
PCIE_TX_CPU_P8: C29.2 CPU1.A23
PD4405_A: PD1.A PQ1.B
PD4405_K: PD1.K PR91.2
PD_N: Q43.D U17.36
PECI_EC: CPU1.A54 R115.1
PEG_C_RXN0: C435.2 GPU1.AB9
PEG_C_RXN1: C437.2 GPU1.AC10
PEG_C_RXN2: C434.2 GPU1.AC11
PEG_C_RXN3: C440.2 GPU1.AB12
PEG_C_RXP0: C436.2 GPU1.AC9
PEG_C_RXP1: C438.2 GPU1.AB10
PEG_C_RXP2: C433.2 GPU1.AD11
PEG_C_RXP3: C439.2 GPU1.AC12
PEG_C_TXN0: C47.2 CPU1.B17
PEG_C_TXN1: C49.2 CPU1.D16
PEG_C_TXN2: C38.2 CPU1.D17
PEG_C_TXN3: C31.2 CPU1.B19
PEG_C_TXP0: C46.2 CPU1.A17
PEG_C_TXP1: C50.2 CPU1.C16
PEG_C_TXP2: C44.2 CPU1.C17
PEG_C_TXP3: C32.2 CPU1.A19
PEG_CLK_CPU: CPU1.E43 R7.2
PEG_CLK_CPU#: CPU1.F43 R8.2
PEG_CLK_XDP: R7.1 XDP1.40
PEG_CLK_XDP#: R8.1 XDP1.42
PEG_CLKREQ0_CPU#: CPU1.AR10 Q54.D R672.1 R877.2
PEG_CLKREQ4_CPU#: CPU1.AU8 RN11.2(A)
PEG_CLKREQ5_CPU#: CPU1.AU7 RN11.1(A)
PEG_RCOMPN_CPU: CPU1.F5 R607.1
PEG_RCOMPP_CPU: CPU1.E5 R607.2
PEG_RXN0: C435.1 CPU1.H13
PEG_RXN1: C437.1 CPU1.G11
PEG_RXN2: C434.1 CPU1.H16
PEG_RXN3: C440.1 CPU1.G15
PEG_RXP0: C436.1 CPU1.G13
PEG_RXP1: C438.1 CPU1.F11
PEG_RXP2: C433.1 CPU1.G16
PEG_RXP3: C439.1 CPU1.F15
PEG_TXN0: C47.1 GPU1.AG7
PEG_TXN1: C49.1 GPU1.AE7
PEG_TXN2: C38.1 GPU1.AF9
PEG_TXN3: C31.1 GPU1.AG10
PEG_TXP0: C46.1 GPU1.AG6
PEG_TXP1: C50.1 GPU1.AF7
PEG_TXP2: C44.1 GPU1.AE9
PEG_TXP3: C32.1 GPU1.AG9
PEX_CLKREQ: GPU1.AC6 Q54.S R672.2 R674.2
PEX_PLLVDD_GPU: C441.1 C442.1 C447.1 C454.1 GPU1.AA14 GPU1.AA15 R667.1
PEX_RST_GPU: GPU1.AC7 R251.2 R279.1 R668.2 R673.2
PEX_RST_GPU_D#: D17.3 R668.1
PEX_TERMP: GPU1.AF25 R243.1
PEX_TSTCLK_OUT: GPU1.AF22 R244.2
PEX_TSTCLK_OUT#: GPU1.AE22 R244.1
PIRQA#: CPU1.BB11 RN18.1(A)
PLT_RST#_EC: C200.1 KBC1.7 R445.1
PLT_RST#_TPM: R443.2 U34.17
PLTRST#_PCH: CPU1.AN10 D25.1 R646.1
PLTRST*_SIO: R445.2 R749.2 R751.2
PLTRST_CR: R758.2 U28.1
PLTRST_LAN_N: R760.2 U23.19
PLTRST_N: C416.1 LPC1.3 R443.1 R530.1 R646.2 R651.1 R749.1 U32.1 U32.2
PLTRST_N_1A: C106.2 Q28.G R279.2
PLTRST_N_D: R751.1 R754.1 R756.1 R758.1 R760.1 U32.4
PLTRST_SL_N: R247.1 R756.2 U7.2
PM_CLKRUN#_EC: KBC1.8 R623.1 R773.1
PM_CLKRUN#_TPM: R773.2 U34.13
PM_PCH_PWROK: CPU1.BA20 R217.2 RN3.3(B)
PM_PWRBTN_N: CPU1.BA15 R4.2 R412.2 R428.1
PM_RSMRST_PWRGD_XDP: R2.2 R3.2 XDP1.39
PM_SLP_S3#_R: R328.1 SCA1.45
PORTC_SPK_L: C174.1 U11.43
PORTC_SPK_L_1: C174.2 R391.1
PORTC_SPK_R: C175.1 U11.44
PORTC_SPK_R_1: C175.2 R392.1
PP_TPM: TP78.1 U34.4
PQ4206_D: PQ5.3 PR111.2
PQ4406_2: PQ8.2 PR243.2 R743.1
PQ4406_3: PQ8.3 PR244.2
PQ4406_5: PC275.1 PQ8.5 PR242.2
PQ4406_6: PC275.2 PQ8.6 PR241.1
PQ4409_C: PQ1.C PR243.1 PR245.1
PQ4409_E: PQ1.E PR89.2 PR90.1
PRE: R794.2 R808.1 U17.16
PROC_SELECT#: CPU1.C64 R83.1
PROCHOT#_CPU: CPU1.C65 R82.2
PSID_D: L30.2 Q74.D R812.1
PSID_D_1: Q73.B R812.2 R817.1
PSID_G: Q73.C Q74.G R805.2
PSL_IN1#: KBC1.73 R359.2
PSL_IN2#: KBC1.93 R362.2
PSL_OUT#: KBC1.74 R449.1
PSYS: PR172.2 PU24.50
PURE_HW_SHUTDOWN#: D19.K Q28.D Q29.D Q59.B R725.1 R732.2
PW_CLEAR: CPU1.U7 JMP1.3 R252.1
PWR_1D0V_BOOT: PR43.1 PU28.10
PWR_1D0V_BOOT_R: PC77.2 PR43.2
PWR_1D0V_CS: PR204.1 PU28.2
PWR_1D0V_EN: D23.A PC76.1 PR42.2 PR44.2 PU28.3
PWR_1D0V_FB: PC75.2 PR39.2 PR40.1 PU28.4
PWR_1D0V_LGATE: PU27.4 PU28.6
PWR_1D0V_PG: PR45.2 PR46.1 PU28.1
PWR_1D0V_PHASE: PC77.1 PL6.1 PR203.1 PU27.5 PU27.6 PU27.7 PU27.8 PU28.8 PU29.1 PU29.2 PU29.3
PWR_1D0V_RF: PR41.1 PU28.5
PWR_1D0V_SNB: PC255.1 PR203.2
PWR_1D0V_UGATE: PU28.9 PU29.4
PWR_1D0V_VCC: PC252.1 PR202.1 PR273.1 PU28.7
PWR_1D35V_VGA: PC103.1 PC104.1 PC106.1 PC114.1 PC115.1 PL8.2 PR76.1 PR77.1 PR78.1 PR79.1 PR81.1 PR83.1 PR85.1
PWR_2D5V_EN_R: PR146.2 PU21.8
PWR_2D5V_FB: PC145.2 PR135.2 PR137.1 PU21.2
PWR_2D5V_PG: PC157.1 PR159.2 PU21.7 U27.2
PWR_2D5V_VIN: PC154.1 PC155.1 PR138.1 PR139.1 PU21.5 PU21.9
PWR_2D5V_VOUT: PC145.1 PC172.1 PC176.1 PR135.1 PR175.1 PR176.1 PU21.3 PU21.4
PWR_2V5_EN: C287.1 PR146.1 R534.2
PWR_3D3V_5V_PG: PR263.2 PU17.7
PWR_3D3V_BOOT2: PR112.2 PU17.9
PWR_3D3V_BOOT2_A: PC125.2 PR112.1
PWR_3D3V_CS2: PR113.1 PU17.5
PWR_3D3V_EN2: PC289.1 PR266.1 PR272.1 PU17.6
PWR_3D3V_FB2: PC126.2 PR115.1 PR116.2 PU17.4
PWR_3D3V_FB2_A: PC126.1 PG23.1 PR116.1
PWR_3D3V_HG2: PU17.10 PU36.4
PWR_3D3V_LDO3: PC128.1 PG21.2 PU17.3
PWR_3D3V_LG2: PU17.11 PU38.4
PWR_3D3V_PH2: PC125.1 PL10.2 PR268.1 PU17.8 PU36.1 PU36.2 PU36.3 PU38.5 PU38.6 PU38.7 PU38.8
PWR_3D3V_SN: PC294.1 PR268.2
PWR_5V3V_EMN_R: D18.3 D19.A R769.1 R770.1 R771.1
PWR_5V_BOOT1: PR120.1 PU17.17
PWR_5V_BOOT1_A: PC132.1 PR120.2
PWR_5V_BYP1: PC129.1 PG19.1 PU17.14
PWR_5V_CS1: PR119.1 PU17.1
PWR_5V_EN1: PC293.1 PR267.1 PR271.1 PU17.20
PWR_5V_FB1: PC130.2 PR117.2 PR118.1 PU17.2
PWR_5V_FB1_A: PC130.1 PG20.1 PR117.1
PWR_5V_HG1: PU17.16 PU35.4
PWR_5V_LDO5: PC290.1 PG22.1 PU17.13
PWR_5V_LG1: PU17.15 PU37.4
PWR_5V_PH1: PC132.2 PL11.1 PR121.1 PU17.18 PU35.1 PU35.2 PU35.3 PU37.5 PU37.6 PU37.7 PU37.8
PWR_5V_SN: PC131.1 PR121.2
PWR_CHG_ACDET: PC124.1 PR96.1 PR104.2 PU34.6
PWR_CHG_ACN: PC121.1 PC283.2 PG17.2 PU34.1
PWR_CHG_ACP: PC122.1 PC283.1 PG18.2 PU34.2
PWR_CHG_AD_OFF: KBC1.63 PQ5.5 PR108.1
PWR_CHG_AD_OFF_R: PQ6.B PR108.2
PWR_CHG_BT_LR: PG16.1 PL9.2 PR88.1
PWR_CHG_BTST: PR247.1 PU34.17
PWR_CHG_BTST_1: PC281.1 PD3.K PR247.2
PWR_CHG_CMPIN: PR92.1 PR94.2 PR97.1 PR252.2 PR255.2 PU34.4
PWR_CHG_CMPIN_R: PQ4.6 PR92.2
PWR_CHG_CMPIN_RR: PQ4.3 PR94.1
PWR_CHG_HIDRV: PU32.4 PU34.18
PWR_CHG_ILIM: PQ2.D PR95.1 PR100.2 PU34.10
PWR_CHG_IOUT: PC123.1 PR255.1 PR256.1 PU34.7
PWR_CHG_LODRV: PC119.1 PU33.4 PU34.15
PWR_CHG_NC: PR254.1 PU34.11
PWR_CHG_PHASE: PC281.2 PL9.1 PU32.1 PU32.2 PU32.3 PU33.5 PU33.6 PU33.7 PU33.8 PU34.19
PWR_CHG_SRN: PR253.1 PU34.12
PWR_CHG_SRN_1: PC284.2 PC285.1 PG15.2 PR253.2
PWR_CHG_SRP: PR250.1 PU34.13
PWR_CHG_SRP_1: C570.1 PC284.1 PG16.2 PR250.2
PWR_CHG_VCC: PC120.1 PR246.2 PU34.20
PWR_DCBATOUT_1D0V: PC253.1 PC254.1 PC302.1 PR49.2 PR50.2 PR51.2 PR52.2 PT13.1 PU29.5 PU29.6 PU29.7 PU29.8
PWR_DCBATOUT_VDDQ: PC1.1 PC136.1 PC137.1 PC138.1 PR122.2 PR123.2 PR133.1 PT1.1 PU18.5 PU18.6 PU18.7 PU18.8
PWR_DDR_SN: PC135.1 PR124.2
PWR_LED_YELLOW_C: PWRCN1.9 Q79.D R502.1 R854.2
PWR_LED_YELLOW_C2: R853.2 R854.1
PWR_V1P8A_EN: D24.A PC87.1 PR57.1 PR58.2 PU10.8
PWR_V1P8A_FB: PC85.2 PR53.2 PR55.1 PU10.2
PWR_V1P8A_PG: PC86.1 PR54.2 PU10.7 R220.2
PWR_VCC_CSN_SA: PC180.1 PC181.2 PG14.1 PR37.2 PU24.45
PWR_VCCGT_BSTA: PR167.2 PU24.14
PWR_VCCGT_BSTA_R: PC169.1 PR167.1
PWR_VCCGT_BSTB: PR173.1 PU24.22
PWR_VCCGT_BSTB_R: PC179.1 PR173.2
PWR_VCCGT_COMP: PC161.2 PC166.1 PU24.4
PWR_VCCGT_COMP_R: PC161.1 PR160.1
PWR_VCCGT_CSCOMP: PC158.1 PC160.1 PR2.2 PR148.1 PR164.2 PU24.6
PWR_VCCGT_CSNA: PG2.1 PR154.1
PWR_VCCGT_CSNB: PG6.1 PR155.1
PWR_VCCGT_CSPA: PC164.1 PR153.1 PU24.10
PWR_VCCGT_CSPB: PC165.2 PR156.1 PR165.2 PU24.9
PWR_VCCGT_CSREF: PC8.1 PC164.2 PC165.1 PR154.2 PR155.2 PU24.8
PWR_VCCGT_CSSUM: PC158.2 PC160.2 PR145.1 PR147.2 PR151.1 PU24.7
PWR_VCCGT_DIFFOUT: PR158.1 PR166.1 PR168.1 PU24.2
PWR_VCCGT_DIFFOUT_R: PC159.2 PR166.2
PWR_VCCGT_FB: PC159.1 PC166.2 PR158.2 PR160.2 PU24.3
PWR_VCCGT_ILIM: PR164.1 PU24.5
PWR_VCCGT_ILIM_NTC: PR2.1 PR147.1 PR148.2
PWR_VCCGT_IOUT: PC174.2 PR171.2 PU24.1
PWR_VCCGT_LGA: PR9.1 PU2.4 PU22.4 PU24.17
PWR_VCCGT_LGB: PR10.1 PU3.4 PU23.4 PU24.19
PWR_VCCGT_SNB1: PC149.1 PR144.2
PWR_VCCGT_SNB2: PC188.1 PR177.2
PWR_VCCGT_SWA: PC169.2 PG1.2 PL2.1 PR144.1 PU1.1 PU1.2 PU1.3 PU2.5 PU2.6 PU2.7 PU2.8 PU22.5 PU22.6 PU22.7 PU22.8 PU24.16
PWR_VCCGT_SWB: PC179.2 PG5.2 PL3.1 PR177.1 PU3.5 PU3.6 PU3.7 PU3.8 PU4.1 PU4.2 PU4.3 PU23.5 PU23.6 PU23.7 PU23.8 PU24.20
PWR_VCCGT_SWNA: PG1.1 PR151.2 PR153.2
PWR_VCCGT_SWNB: PG5.1 PR145.2 PR156.2
PWR_VCCGT_TSENSE: PC9.1 PR152.1 PU24.11
PWR_VCCGT_TSENSE_NTC: PR1.2 PR152.2 PR157.2
PWR_VCCGT_UGA: PU1.4 PU24.15
PWR_VCCGT_UGB: PU4.4 PU24.21
PWR_VCCGT_VSN: PC4.2 PR7.2 PU24.52
PWR_VCCGT_VSN_G: PC4.1 PC6.1 PG3.1 PR7.1
PWR_VCCGT_VSP: PC6.2 PG4.1 PU24.51
PWR_VCCSA_BST: PR38.1 PU8.1
PWR_VCCSA_BST_RC: PC70.1 PR38.2
PWR_VCCSA_COMP: PC12.2 PC13.2 PU24.47
PWR_VCCSA_COMP_1: PC12.1 PR8.2
PWR_VCCSA_CSP: PC180.2 PC181.1 PR174.2 PR178.1 PU24.44
PWR_VCCSA_CSP_R: PR37.1 PR174.1
PWR_VCCSA_DRVH: PU7.4 PU8.8
PWR_VCCSA_DRVL: PU8.5 PU9.4
PWR_VCCSA_ILIM: PC18.1 PR11.2 PU24.46
PWR_VCCSA_IOUT: PC20.2 PR13.1 PU24.43
PWR_VCCSA_PH: PC70.2 PG13.2 PL5.1 PR270.2 PU7.1 PU7.2 PU7.3 PU8.7 PU9.5 PU9.6 PU9.7 PU9.8
PWR_VCCSA_PWM: PR14.2 PU8.2 PU24.40
PWR_VCCSA_SNB: PC296.1 PR270.1
PWR_VCCSA_SWN: PG13.1 PR178.2
PWR_VCCSA_VSN: PC24.2 PR20.2 PU24.48
PWR_VCCSA_VSN_G: PC24.1 PC33.1 PG10.1 PR20.1
PWR_VCCSA_VSP_: PR18.2 PR19.1 PU24.49
PWR_VCCSA_VSP_G: PC26.1 PC33.2 PG9.1 PR19.2
PWR_VCCSA_VSP_RC: PC26.2 PR18.1
PWR_VCORE_ALERT#: PR184.2 PU24.37
PWR_VCORE_BST: PR179.1 PU24.26
PWR_VCORE_BST_R: PC182.2 PR179.2
PWR_VCORE_COMP: PC190.1 PC191.1 PU24.30
PWR_VCORE_COMP_RC: PC190.2 PR197.1
PWR_VCORE_CSN: PC31.2 PC32.2 PG12.1 PR29.1 PU24.32
PWR_VCORE_CSP: PC31.1 PC32.1 PR21.1 PR24.1 PU24.33
PWR_VCORE_CSP_NTC: PR24.2 PR29.2
PWR_VCORE_DRON: PU8.3 PU24.39
PWR_VCORE_EN: PR186.1 PU24.41
PWR_VCORE_ILIM: PC192.1 PR181.1 PU24.31
PWR_VCORE_IOUT: PC194.2 PR187.1 PU24.34
PWR_VCORE_LG: PR12.1 PU5.4 PU24.23 PU25.4
PWR_VCORE_SCLK: PR185.2 PU24.38
PWR_VCORE_SDIO: PR183.2 PU24.36
PWR_VCORE_SNB: PC41.1 PR27.2
PWR_VCORE_SW: PC182.1 PG11.2 PL4.1 PR27.1 PU5.5 PU5.6 PU5.7 PU5.8 PU6.1 PU6.2 PU6.3 PU24.24 PU25.5 PU25.6 PU25.7 PU25.8 PU26.1 PU26.2 PU26.3
PWR_VCORE_SWN: PG11.1 PR21.2
PWR_VCORE_TSENSE: PC189.1 PR180.1 PU24.27
PWR_VCORE_TSENSE_NTC: PR28.1 PR180.2 PR189.2
PWR_VCORE_UG: PU6.4 PU24.25 PU26.4
PWR_VCORE_VCC: PC11.1 PR4.2 PU24.13
PWR_VCORE_VR_RDY: PR188.1 PU24.42
PWR_VCORE_VRHOT#: PR182.2 PU24.35
PWR_VCORE_VRMP: PC10.1 PR5.1 PU24.12
PWR_VCORE_VSN: PC23.1 PR15.1 PU24.29
PWR_VCORE_VSN_G: PC23.2 PC28.1 PG7.1 PR15.2
PWR_VCORE_VSP: PR16.2 PR17.1 PU24.28
PWR_VCORE_VSP_G: PC28.2 PC29.2 PG8.1 PR16.1
PWR_VCORE_VSP_RC: PC29.1 PR17.2
PWR_VDDQ_BOOT: PR150.1 PU20.18
PWR_VDDQ_BOOT_A: PC151.1 PR150.2
PWR_VDDQ_CS: PR125.1 PU20.13
PWR_VDDQ_EN: PC148.1 PR141.2 PU20.8
PWR_VDDQ_EN_R: C289.1 PR141.1 R539.2
PWR_VDDQ_FB: PC163.2 PR161.1 PR162.2 PU20.6
PWR_VDDQ_HG: PR136.2 PU20.17
PWR_VDDQ_HG_R: PR126.1 PR136.1 PU18.4
PWR_VDDQ_LG: PU19.4 PU20.15
PWR_VDDQ_PG: D16.3 KBC1.101 PR132.2 PU20.10 R91.1
PWR_VDDQ_PG_N: Q5.5 R90.2 R91.2
PWR_VDDQ_PH: PC151.2 PL1.1 PR124.1 PR126.2 PU18.1 PU18.2 PU18.3 PU19.5 PU19.6 PU19.7 PU19.8 PU20.16
PWR_VDDQ_TON: PR133.2 PU20.9
PWR_VDDQ_VDD: PC141.1 PR131.1 PU20.12
PWR_VDDQ_VDDQ: PC163.1 PR162.1 PR170.1 PU20.5
PWR_VDDQ_VID: PC142.1 PR127.1 PU20.11
PWR_VDDQ_VLDOIN: PC5.1 PR3.2 PR6.2 PU20.19
PWR_VDDQ_VTT: PC170.1 PC171.1 PR163.2 PR169.2 PU20.2 PU20.20
PWR_VDDQ_VTTREF: PC168.1 PU20.4
PWR_VGA_CORE_BOOT1: PR225.1 U30.1
PWR_VGA_CORE_BOOT1_1: PC263.1 PR225.2
PWR_VGA_CORE_COMP: PC257.1 PR214.2 U30.12
PWR_VGA_CORE_COMP_1: PC258.2 PR214.1
PWR_VGA_CORE_EN: PC265.1 PD2.A PR229.2 PR230.2 U30.3
PWR_VGA_CORE_FB: PC257.2 PC258.1 PR206.2 PR207.1 U30.11
PWR_VGA_CORE_FBRTN: PR218.2 U30.10
PWR_VGA_CORE_FS: PR219.1 U30.9
PWR_VGA_CORE_LGATE1: PR220.1 PU12.4 PU30.4 U30.23
PWR_VGA_CORE_PGOOD: PR209.1 PR210.2 U30.16
PWR_VGA_CORE_PHASE1: PC263.2 PL7.1 PR70.2 PU12.5 PU12.6 PU12.7 PU12.8 PU13.1 PU13.2 PU13.3 PU30.5 PU30.6 PU30.7 PU30.8 PU31.1 PU31.2 PU31.3 U30.24
PWR_VGA_CORE_PSI: PC266.1 PR231.1 PR232.2 R682.1 U30.4
PWR_VGA_CORE_PVCC: PC261.1 PR216.2 U30.21
PWR_VGA_CORE_REFIN: PC264.1 PR226.1 PR228.2 U30.7
PWR_VGA_CORE_SENCE+: GPU1.F2 PR213.1 PR215.2
PWR_VGA_CORE_SENCE-: GPU1.F1 PR217.1 PR218.1
PWR_VGA_CORE_SENSE+_1: PC260.2 PR207.2 PR213.2
PWR_VGA_CORE_SNB: PC99.1 PR70.1
PWR_VGA_CORE_TALERT#: PR211.1 PR212.2 U30.14
PWR_VGA_CORE_TSNS: PC92.1 PR68.2 PR75.1 U30.13
PWR_VGA_CORE_UGATE1: PR72.1 U30.2
PWR_VGA_CORE_UGATE1_R: PR72.2 PU13.4 PU31.4
PWR_VGA_CORE_VCC: PC259.1 PR208.2 U30.15
PWR_VGA_CORE_VID: PC267.1 PR233.1 U30.5
PWR_VGA_CORE_VIDBUF: PR234.1 U30.6
PWR_VGA_CORE_VREF: PC262.1 PR68.1 PR224.1 U30.8
PWR_VGA_CORE_VREF_1: PC268.1 PR224.2 PR228.1 PR234.2
PWR_VGA_CORE_VREF_2: PR223.1 PR226.2
PWR_VGA_VRAM_BOOT: PR86.1 PU14.20
PWR_VGA_VRAM_BOOT_RC: PC112.1 PR86.2
PWR_VGA_VRAM_FB: PC106.2 PR74.1 PR77.2 PU14.5
PWR_VGA_VRAM_LX: PC112.2 PL8.1 PR71.2 PU14.10 PU14.11 PU14.16 PU14.17 PU14.18 PU14.25
PWR_VGA_VRAM_PFM: PR80.1 PR82.1 PU14.3
PWR_VGA_VRAM_POK: PC111.1 PR84.2 PU14.1 R350.2
PWR_VGA_VRAM_SNB: PC101.1 PR71.1
PWR_VGA_VRAM_SS: PC110.1 PU14.23
PWR_VGA_VRAM_TON: PR73.2 PU14.6
PWR_VGA_VRAM_VCC: PC113.1 PR87.2 PU14.21
PWR_VTT_EN: PR149.2 PU20.7
PWR_VTT_EN_R: C286.1 PR149.1 R536.2
PWRBTN_N: C591.1 R429.1 R837.2
PWRCN_DET_N: C58.1 CPU1.H3 PWRCN1.5 R172.1
PWRGD_3V: C535.1 Q23.G R291.2 R715.2 R717.1 R724.2
PWRGD_3V_B: Q22.B Q23.D R248.2
PWRGD_3V_C: C78.1 Q17.G Q18.G Q22.C R233.2
PWROK3_1: KBC1.84 R724.1 R726.2
Q1212_G: Q79.G R858.1 R860.2 R863.1
Q9637_AB_EC: Q5.1 Q5.3
Q9639_AB_EC: Q8.1 Q8.3
Q9664_D: Q63.D R743.2
REXT: R809.1 U17.18
RING2: C135.1 Q27.2 R333.2 U11.31 UHS1.3
ROM_CS*: GPU1.D12 R335.1
ROM_CS_R*: R334.2 R335.2 U10.1
ROM_SCLK: GPU1.C12 R318.1 R319.1 R322.2
ROM_SCLK_R: R319.2 U10.6
ROM_SI: GPU1.B12 R309.2 R310.1 R311.1
ROM_SI_R: R311.2 U10.5
ROM_SO: GPU1.A12 R308.2 R336.1 U10.2
RREF: R612.1 U28.9
RSMRST_N: CPU1.AY17 KBC1.15 Q12.3 R2.1 R130.1 R768.1 RN3.4(B)
RSMRST_N_B: Q12.5 R125.1
RSMRST_PWRGD#: KBC1.51 PR30.1 PR46.2 PR48.2
RSVD_TP_AK12: CPU1.AK12 TP68.1
RSVD_TP_AK13: CPU1.AK13 TP62.1
RSVD_TP_BA68: CPU1.BA68 TP31.1
RSVD_TP_BA70: CPU1.BA70 TP30.1
RSVD_TP_BB68: CPU1.BB68 TP33.1
RSVD_TP_BB69: CPU1.BB69 TP32.1
RSVD_TP_F65: CPU1.F65 TP54.1
RSVD_TP_G65: CPU1.G65 TP55.1
RT: R846.1 U36.10
RTC_DET#: KBC1.120 Q40.D R762.1
RTD2506S_VREF: C530.1 SCA1.57
RTD_PIN110: R417.1 SCA1.110
RTD_PIN111: R418.1 SCA1.111
RTD_PIN112: R419.1 SCA1.112
RTD_PIN113: R420.1 SCA1.113
RTD_PIN114: R421.1 SCA1.114
RTD_PIN115: R422.1 SCA1.115
RTD_REXT: R403.1 SCA1.120
RTL_ISOLATE_N: Q45.6 R526.1 R527.2 U23.20
RTL_ISOLATE_N_1: C620.1 Q45.5 R865.2 R868.1
RTL_ISOLATE_N_2: Q45.2 Q45.3 R525.2
RTN1: CONVT1.1 R446.1
RTN2: CONVT1.2 R452.1
RTN3: CONVT1.5 R814.1
RTN4: CONVT1.6 R815.1
RX_3V3: C556.2 C558.1 L28.2 SCA1.119
S5_ENABLE: KBC1.6 Q67.D R770.2 R777.2
S_LVDS_BL_EN: R832.1 R835.1 R838.1 R840.1 R842.2
S_TXE0+: LVDS1.18 SCA1.73
S_TXE0-: LVDS1.19 SCA1.74
S_TXE1+: LVDS1.15 SCA1.71
S_TXE1-: LVDS1.16 SCA1.72
S_TXE2+: LVDS1.12 SCA1.69
S_TXE2-: LVDS1.13 SCA1.70
S_TXE3+: LVDS1.8 SCA1.67
S_TXE3-: LVDS1.9 SCA1.68
S_TXO0+: LVDS1.29 SCA1.87
S_TXO0-: LVDS1.30 SCA1.88
S_TXO1+: LVDS1.27 SCA1.85
S_TXO1-: LVDS1.28 SCA1.86
S_TXO2+: LVDS1.25 SCA1.83
S_TXO2-: LVDS1.26 SCA1.84
S_TXO3+: LVDS1.20 SCA1.79
S_TXO3-: LVDS1.21 SCA1.80
S_TXOC+: LVDS1.10 LVDS1.22 SCA1.81
S_TXOC-: LVDS1.11 LVDS1.23 SCA1.82
SA0_DIMM1: DIMM1.256 R650.1 R653.2
SA0_DIMM2: DIMM2.256 R642.1 R648.2
SA1_DIMM1: DIMM1.260 R649.1 R652.2
SA1_DIMM2: DIMM2.260 R643.1 R647.2
SA2_DIMM1: DIMM1.166 R638.2 R641.1
SA2_DIMM2: DIMM2.166 R637.2 R640.1
SATA__RXN0_C: C41.2 HDD1.5
SATA__RXN1_C: C22.2 ODD1.5
SATA__RXP0_C: C40.2 HDD1.6
SATA__RXP1_C: C21.2 ODD1.6
SATA__TXN0_C: C53.2 HDD1.3
SATA__TXN1_C: C24.2 ODD1.3
SATA__TXP0_C: C52.2 HDD1.2
SATA__TXP1_C: C25.2 ODD1.2
SATA_LED_N: CPU1.H1 R165.2 R833.1
SATA_RXN0_C_N: C41.1 L3.1
SATA_RXN1_C_N: C22.1 L1.1
SATA_RXP0_C_N: C40.1 L3.4
SATA_RXP1_C_N: C21.1 L1.4
SATA_TXN0_C_N: C53.1 L4.1
SATA_TXN1_C_N: C24.1 L2.4
SATA_TXP0_C_N: C52.1 L4.4
SATA_TXP1_C_N: C25.1 L2.1
SATAHDR_RX_DN0: CPU1.F20 L3.2
SATAHDR_RX_DN1: CPU1.G21 L1.2
SATAHDR_RX_DP0: CPU1.E20 L3.3
SATAHDR_RX_DP1: CPU1.F21 L1.3
SATAHDR_TX_DN0: CPU1.B21 L4.2
SATAHDR_TX_DN1: CPU1.D21 L2.3
SATAHDR_TX_DP0: CPU1.A21 L4.3
SATAHDR_TX_DP1: CPU1.C21 L2.2
SB3V: C16.1 C274.1 C275.1 C288.1 C291.1 C293.1 C621.1 C638.1 D20.2 F1.1 JMP1.6 PC81.2 PC133.1 PC175.1 PC295.1 PG23.2 PL10.1 PR44.1 PR45.1 PR54.1 PR58.1 PR132.1 PR138.2 PR139.2 PR159.1 PT20.1 PU10.5 PU10.9 Q50.S Q52.E Q61.D Q81.S R5.1 R17.1 R29.2 R77.1 R79.1 R85.1 R106.1 R116.2 R121.2 R152.2 R157.2 R161.1 R171.2 R175.1 R181.1 R184.1 R199.1 R203.1 R204.1 R206.1 R207.1 R210.1 R213.1 R223.1 R228.1 R229.1 R238.1 R252.2 R265.1 R398.2 R466.1 R470.2 R480.1 R483.1 R503.1 R515.1 R520.1 R525.1 R537.1 R542.1 R579.1 R618.1 R619.1 R620.2 R622.1 R635.1 R644.1 R645.2 R681.1 R708.1 R709.1 R722.1 R767.2 R768.2 R772.2 R776.1 R780.1 R791.1 R803.1 R816.1 R834.2 R860.1 R862.1 R864.1 R870.2 R876.1 RN2.1(A) RN2.2(A) RN4.1(A) RN4.2(A) RN4.3(A) RN4.4(A) RN20.1(A) RN20.2(A) U1.5 U26.6 U26.7 U27.5
SB5V: C282.1 CN1.1 F7.1 PC19.1 PC74.1 PC84.1 PC134.1 PC146.1 PG19.2 PG20.2 PL11.2 PR4.1 PR127.2 PR131.2 PR165.1 PR273.2 PT21.1 PU8.4 PU10.6 PU21.6 PU24.18 R248.1 R273.2 R453.1 R711.1 R805.1 R843.1 R850.1 R851.1 R852.1 R853.1 U3.3 U4.3 U5.5 U25.5 U26.1 U26.2 U26.4
SCA_AGND: C530.2 C533.2 C536.2 R713.2 R714.2 SCA1.54
SCALAR_EN: KBC1.33 R722.2 R723.2
SCALAR_EN_G: PQ9.2 R723.1
SCALAR_MUTE: Q72.2 R331.2 SCA1.35
SCALAR_OUT_L: C132.1 SCA1.58
SCALAR_OUT_L_C: C132.2 U13.2
SCALAR_OUT_R: C131.1 SCA1.59
SCALAR_OUT_R_C: C131.2 U13.10
SCALAR_PC_SW1: Q62.E R746.2
SCALAR_PC_SW2: Q62.B R739.1 R742.2
SCALAR_PC_SW3: C544.1 Q61.G Q62.C R737.1 R738.1
SCALAR_PC_SW4: PQ9.5 PQ9.6 R739.2
SCALAR_PC_SW5: PQ9.3 R737.2
SD_CD#: MEMCD1.11 U28.30
SD_CLK_C_1: C397.1 MEMCD1.5 R616.2
SD_CMD: MEMCD1.2 R611.2
SD_DAT0: C380.1 MEMCD1.7 R621.2
SD_DAT1: C376.1 MEMCD1.8 R624.2
SD_DAT2: C394.1 MEMCD1.9 R604.2
SD_DAT3: C395.1 MEMCD1.1 R608.2
SD_RCOMP: CPU1.AB7 R610.1
SD_VDD2: C402.2 C404.1 U28.13
SD_WAKE#_IC: R586.2 U28.32
SD_WAKE_N: CPU1.B7 R579.2 R586.1
SD_WP: MEMCD1.10 R592.2
SDIN: R414.2 SCA1.104
SDIN_1: R414.1 U33.5
SDOUT: R415.1 SCA1.105
SDREG2: U28.24
SE_BJT_B1: R104.2 U2.2
SE_BJT_B2: C18.1 R97.2 R98.1 R101.2
SE_BJT_B3: R101.1 U2.5
SE_VDDQ_EN: R539.1 U27.4
SE_VPP_EN: Q6.C R534.1 RN2.3(B)
SE_VPP_EN_B: Q6.B RN2.4(B) U2.3 U2.6
SE_VTT_EN: R47.2 R48.2 R51.2 R536.1
SENSE_A: R376.2 U11.34
SENSE_A_C: Q38.D R376.1
SENSE_B: R345.2 R346.2 U11.33
SERIRQ_CPU: CPU1.AY11 R436.2 R442.1 RN18.2(A)
SERIRQ_TPM: R442.2 U34.27
SIDE_USB3_RX0+: L6.3 SSUSB1.6 U6.2 U6.9
SIDE_USB3_RX0-: L6.2 SSUSB1.5 U6.1 U6.10
SIDE_USB3_RX1+: L10.3 SSUSB2.6 U9.2 U9.9
SIDE_USB3_RX1-: L10.2 SSUSB2.5 U9.1 U9.10
SIDE_USB3_TX0+: L5.3 SSUSB1.9 U6.5 U6.6
SIDE_USB3_TX0-: L5.2 SSUSB1.8 U6.4 U6.7
SIDE_USB3_TX1+: L9.3 SSUSB2.9 U9.5 U9.6
SIDE_USB3_TX1-: L9.2 SSUSB2.8 U9.4 U9.7
SIO_EUP_EN: D23.K D24.K PR266.2 PR267.2 R771.2
SIO_GPU_EN: CPU1.A6 D2.K D5.K D6.K PD2.K PR63.1 PR65.2 Q21.5 R235.2
SIO_GPU_RST: CPU1.AN7 U7.1
SIO_GREEN_PWM: KBC1.16 R863.2
SIO_HDD_LED: KBC1.109 R826.2 R828.1
SIO_HDD_LED_1: Q77.B R828.2
SIO_SMCLK0: KBC1.67 Q36.6 Q60.6 R499.2 RN13.3(B)
SIO_SMDAT0: KBC1.68 Q36.3 Q60.3 R498.2 RN13.4(B)
SIO_UART1_RX: R394.1 SCA1.50
SIO_UART1_TX: R390.1 SCA1.49
SIO_YELLOW: KBC1.47 Q44.G R502.2 R503.2
SKEW1: CPU1.U1 R191.1 R192.2
SKEW2: CPU1.U2 R189.2 R190.1
SKEW3: CPU1.U3 R187.1 R188.2
SKTOCC#: CPU1.A65 TP29.1
SLEEVE: C128.1 Q25.D Q27.1 R323.2 U11.32 UHS1.4
SLEEVE_G: Q25.G Q30.C R293.1 R296.2
SLP_A_N: CPU1.AN16 TP59.1
SLP_LAN_N: CPU1.AW15 TP60.1
SLP_S0_N: CPU1.AT11 R158.1
SLP_S3_N: CPU1.AP15 KBC1.64 R51.1 R95.1 R159.1 R328.2 R861.2
SLP_S4_N: CPU1.BA16 Q9.5 R104.1 R109.1 R215.1 R440.2 R857.1 U27.1
SLP_S4_N_SIO: KBC1.21 R439.1 R440.1
SLP_S5_N: CPU1.AY16 R439.2
SLP_SUSB: CPU1.AN15 KBC1.108 PR42.1 PR57.2 PR271.2 PR272.2 R133.1
SLP_SUSB_C: Q12.6 R125.2 R129.1
SLP_SUSB_R: Q12.2 R131.1 R132.1 R133.2
SLP_WLAN_N: CPU1.BB17 TP36.1
SM_DRAMRST#: CPU1.AT13 R602.2 R603.1
SM_DRAMRST#_R: C334.1 D15.1 DIMM1.108 DIMM2.108 R603.2
SM_INTRUDER#: CPU1.AP16 R629.2
SM_RCOMP_0: CPU1.AR18 R577.1
SM_RCOMP_1: CPU1.AT18 R576.1
SM_RCOMP_2: CPU1.AU18 R580.1
SMB0_CVT_CLK: C248.1 R499.1 U36.6
SMB0_CVT_DATA: C247.1 R498.1 U36.7
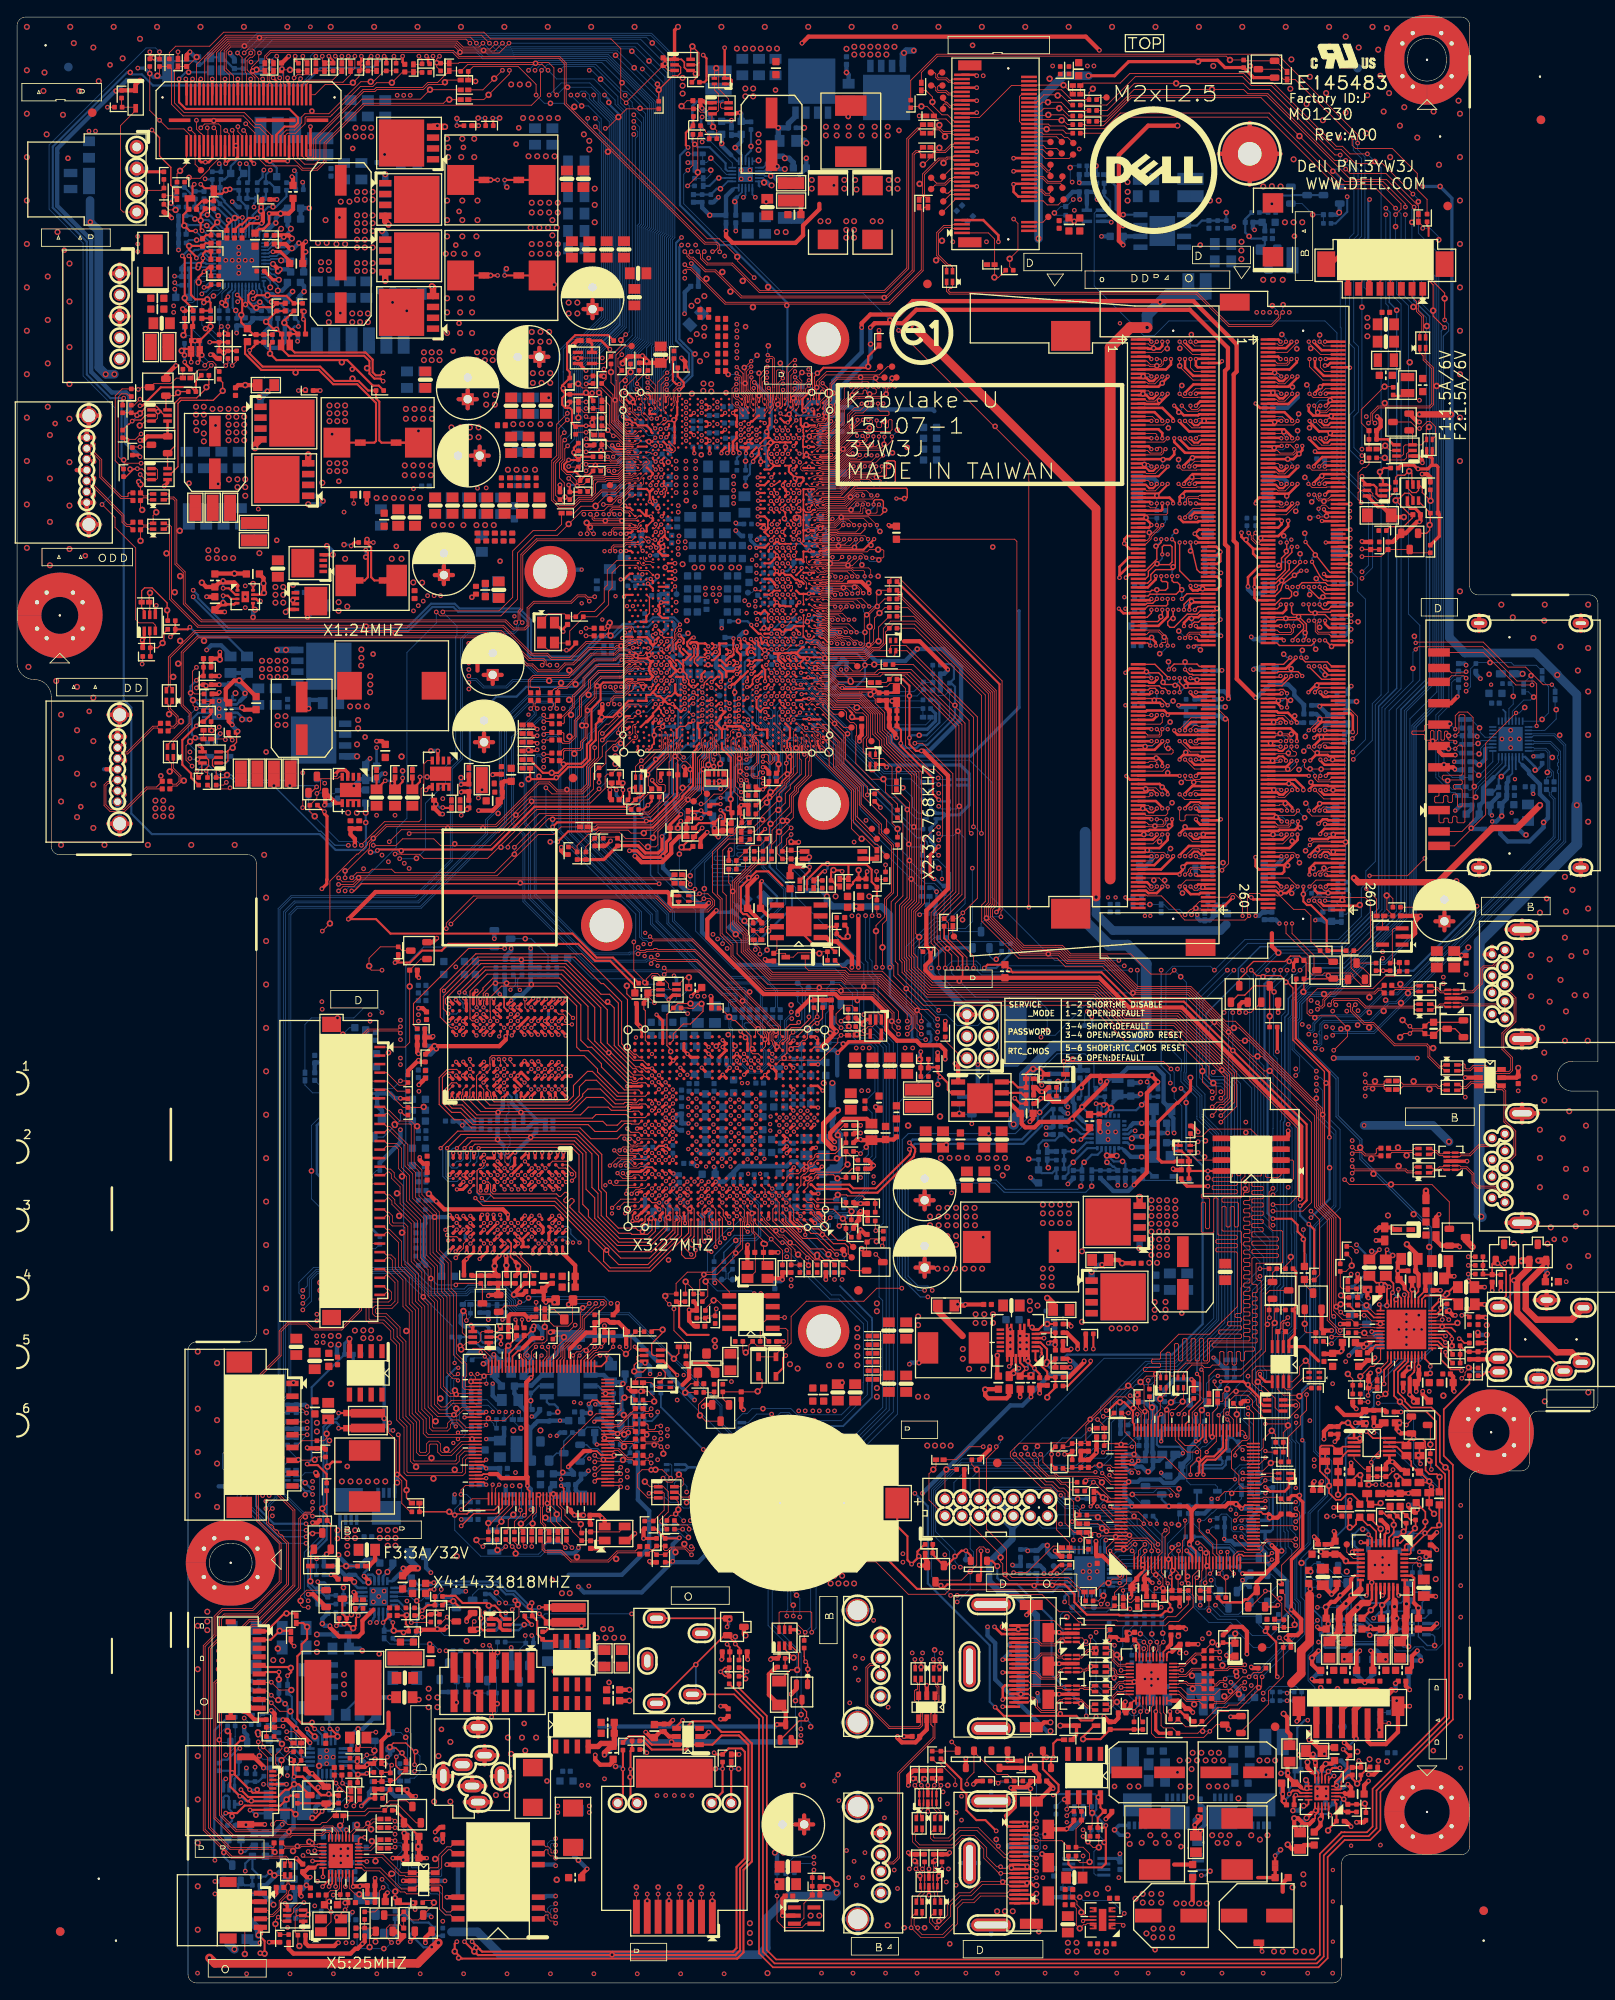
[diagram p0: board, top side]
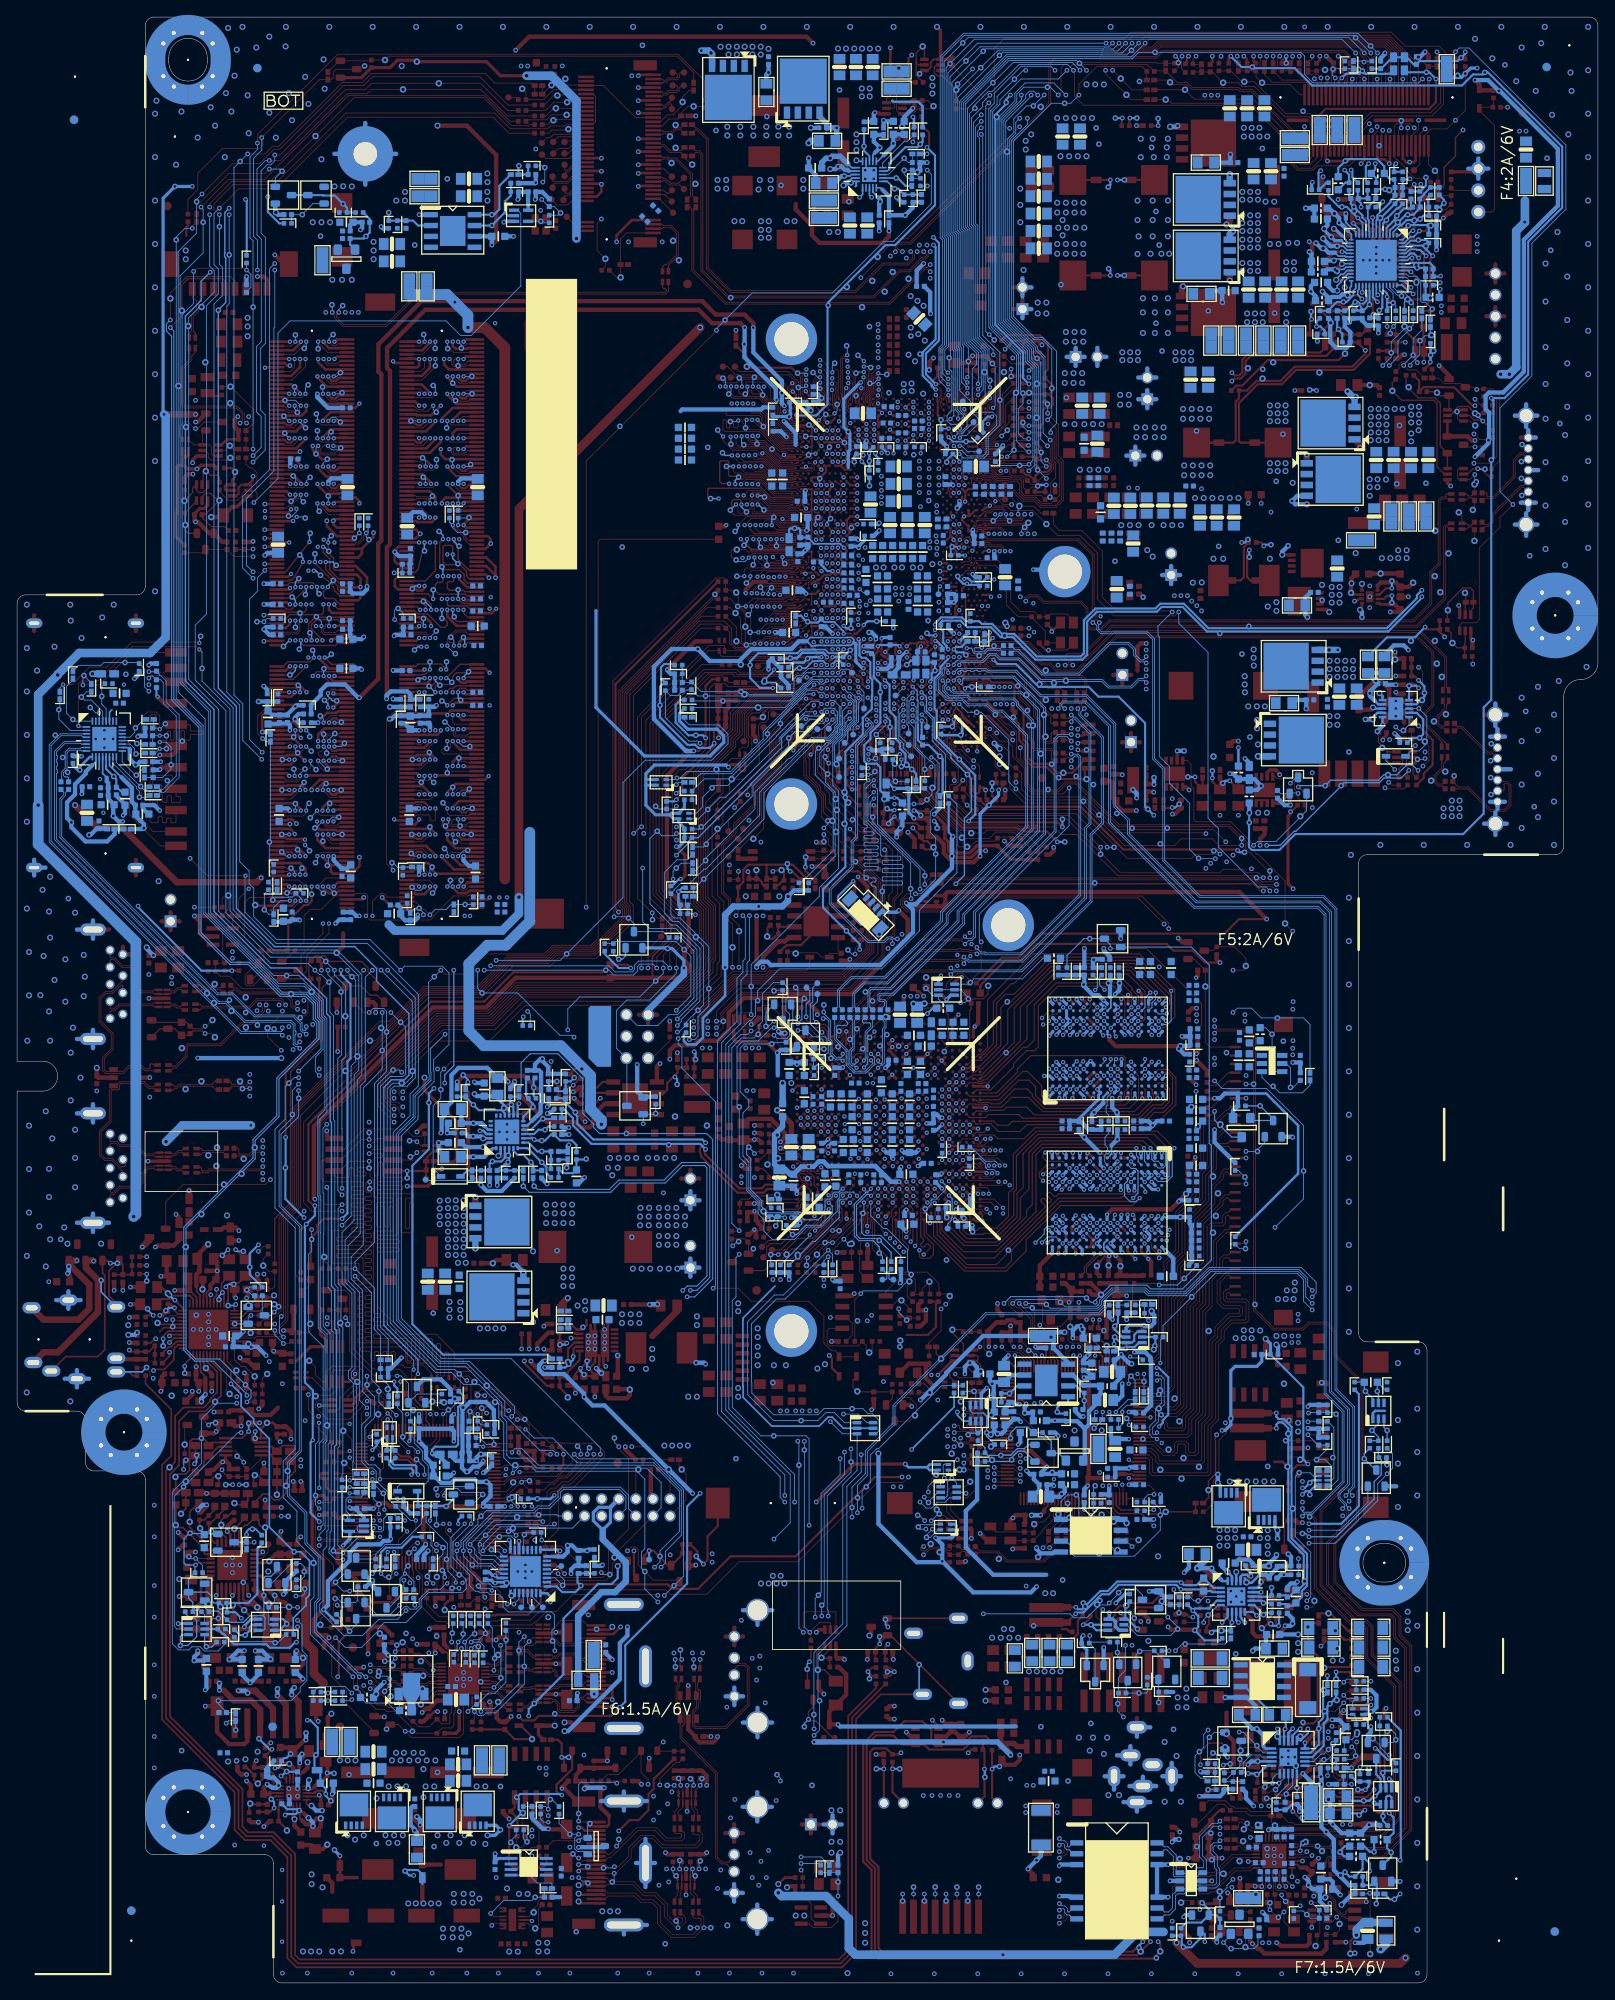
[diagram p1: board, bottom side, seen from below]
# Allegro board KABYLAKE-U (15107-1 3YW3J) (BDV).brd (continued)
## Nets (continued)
SMB_CLK_MAIN: DIMM1.253 DIMM2.253 Q17.S Q65.1 R32.2 R224.2
SMB_CLK_RESUME: CPU1.R7 Q17.D R41.1 R213.2
SMB_DATA_MAIN: DIMM1.254 DIMM2.254 Q18.S Q65.4 R35.2 R225.2
SMB_DATA_RESUME: CPU1.R8 Q18.D R44.1 R228.2
SMBUS_ISP: KBC1.50 Q39.2 Q39.5 Q65.2 Q65.5 R393.1 R400.2
SML0_CLK: CPU1.R9 RN4.5(B)
SML0_DATA: CPU1.W2 RN4.6(B)
SML1_CLK: CPU1.W3 RN4.7(B)
SML1_DATA: CPU1.V3 RN4.8(B)
SNB: C574.1 R804.2
SO_1: R415.2 U33.2
SP1: R624.1 U28.15
SP2: R621.1 U28.16
SP3: R616.1 U28.17
SP4: R611.1 U28.19
SP5: R608.1 U28.20
SP6: R604.1 U28.21
SP7: R592.1 U28.29
SP_PLLVDD: C95.1 C96.1 C97.1 C500.1 GPU1.M6 GPU1.N6 L7.2
SPDIF_IC: SCA1.37 U11.16
SPEAKER1_L1: C180.1 R373.2 U13.3
SPEAKER1_R1: C176.1 R369.2 U13.9
SPEED_100*_CON: R894.2 RJ1.12
SPEED_100_N: R894.1 U20.6 U23.25
SPEED_1000*_CON: R893.2 R895.2 RJ1.11
SPEED_1000_N: R893.1 U20.1 U23.26
SPI_CLK: R183.1 RN7.4(B) SRCON1.6 U8.6
SPI_CLK_CPU: CPU1.AV2 R183.2
SPI_CS0_N: R182.2 RN7.3(B) SRCON1.1 U8.1
SPI_CS_CPU_N0: CPU1.AU3 R182.1
SPI_HOLD_CPU: CPU1.AU4 R173.2 R176.2
SPI_IO2: R196.1 R261.1 RN5.4(B) SRCON1.3 U8.3
SPI_IO3: R176.1 RN5.3(B) SRCON1.7 U8.7
SPI_MISO: R197.1 RN8.3(B) SRCON1.2 U8.2
SPI_MOSI: R194.1 RN8.4(B) SRCON1.5 U8.5
SPI_SI_CPU: CPU1.AV3 R185.1 R194.2 R199.2 R200.2
SPI_SI_XDP: R5.2 R23.2 R200.1
SPI_SO_CPU: CPU1.AW3 R197.2
SPI_WP_CPU: CPU1.AW2 R195.2 R196.2
SPI_WP_XDP: R18.1 R195.1
SPKR_DET: C637.1 KBC1.48 R398.1 R456.1
SPKR_DET_C: R456.2 SPK1.6
SPKR_IN_L: C180.2 C183.2 U14.6
SPKR_IN_R: C176.2 U14.31
SPKR_L+_C: C224.1 L15.2 R459.1 SPK1.1
SPKR_L+_SNB: C582.1 R459.2
SPKR_L-_C: C225.1 L16.2 R460.1 SPK1.2
SPKR_L-_SNB: C581.1 R460.2
SPKR_OUT_L+: C201.2 C206.1 L15.1 U14.16
SPKR_OUT_L-: C202.2 C207.1 L16.1 U14.18
SPKR_OUT_R+: C204.2 C209.1 L18.1 U14.25
SPKR_OUT_R-: C203.2 C208.1 L17.1 U14.23
SPKR_R+_C: C227.1 L18.2 R462.1 SPK1.4
SPKR_R+_SNB: C579.1 R462.2
SPKR_R-_C: C226.1 L17.2 R461.1 SPK1.3
SPKR_R-_SNB: C580.1 R461.2
SSTCMP: R830.1 U36.11
SSTCMP_1: C587.1 R830.2
STATUS: R845.1 U36.8
STRAP0: GPU1.D1 R269.2 R270.1
STRAP1: GPU1.D2 R271.1 R274.2
STRAP2: GPU1.E4 R262.2 R263.1
STRAP3: GPU1.E3 R266.1 R267.2
STRAP4: GPU1.D3 R275.2 R276.1
STRAP_REF0: GPU1.F6 R260.2
SUS_CLK: R52.1 R134.2 R361.2
SUS_CLK_EC: KBC1.77 R361.1
SUS_CLK_PCH: CPU1.BA17 R134.1
SUS_LED_GREEN_C: PWRCN1.7 Q44.D R855.2 R858.2
SUS_LED_GREEN_C2: R852.2 R855.1
SUS_PWR_ACK: CPU1.AP11 KBC1.25 R202.2 R883.2
SUS_WARNB: CPU1.AR13 KBC1.79 R202.1 R206.2
SUSCLK_NGFF: NGFF1.50 R52.2
SW_ON_N_SIO: KBC1.124 R412.1
SYS_FAN_TACH1_1: FANC3.3 R57.2 R59.2
SYS_FAN_TACH1_2: R59.1 R60.2 R61.2
SYS_PEX_RST_MON_GPU#: GPU1.D10 R245.2
SYS_PRES: BAT2.6 R370.2
SYS_PWROK: CPU1.B6 R27.1 R147.1 R715.1
SYSTEM_FAN_PWM1_1: D1.A FANC3.4 R33.2 R40.2
T_CRIT#: R314.1 R315.2 U12.4
THERM_SYS_SHDN#: Q29.S R314.2
THERMTRIP#_CPU: CPU1.C63 R96.2
TP1_AY4: CPU1.AY4 TP44.1
TP2_BB3: CPU1.BB3 TP42.1
TP4_BB5: CPU1.BB5 TP43.1
TP5_AU5: CPU1.AU5 TP45.1
TP6_AT5: CPU1.AT5 TP63.1
TP3131_GVDD: C177.2 R405.1 R408.2 U14.2
TP_DDPC_CTRLDATA: CPU1.N8 TP64.1
TP_DET_N: KBC1.72 R862.2 TOUCH1.1
TP_L_BKLTEN: CPU1.R12 TP67.1
TP_L_VDDEN: CPU1.U13 TP61.1
TP_NGFF_COEX1: NGFF1.48 TP10.1
TP_NGFF_COEX2: NGFF1.46 TP9.1
TP_NGFF_COEX3: NGFF1.44 TP8.1
TP_NGFF_LED1: NGFF1.6 TP28.1
TP_NGFF_LED2: NGFF1.16 TP27.1
TP_NGFF_MLDIR: NGFF1.17 TP25.1
TP_PMODE_XDP_RST_R_N: R530.2 R531.1 XDP1.46
TPA3113_SD: Q68.G Q71.6 Q84.D R787.2 R790.1
TPA3113_SD1#: C564.1 Q66.G Q68.D R781.1 R786.2 R789.1 U14.29
TPA3131_BSNL: C202.1 U14.19
TPA3131_BSNR: C203.1 U14.22
TPA3131_BSPL: C201.1 U14.15
TPA3131_BSPR: C204.1 U14.26
TPA3131_FAULT#: R781.2 U14.30
TPA3131_GAIN: R405.2 R407.1 U14.3
TPA3131_LINN: C181.2 U14.5
TPA3131_LINN_1: C181.1 R396.2
TPA3131_MUTE: Q66.D R774.2 R775.1 U14.7
TPA3131_PLIMIT: C178.2 R406.2 R408.1 U14.1
TPA3131_RINN: C179.2 U14.32
TPA3131_RINN_1: C179.1 R395.2
TPA3131_SYNC: TP52.1 U14.11
TPM_VDD: C191.1 C565.1 C569.1 R776.2 U34.8 U34.14 U34.22
TPM_VSB: C567.1 C568.1 R780.2 U34.1
USB2_C_N1: R257.1 TR4.4
USB2_C_P1: R256.1 TR4.1
USB2_ID: CPU1.AG3 R886.1
USB2_N0: CPU1.AB9 TR3.4
USB2_N1: CPU1.AD6 R257.2
USB2_N2: CPU1.AH3 TR7.1
USB2_N3: CPU1.AD9 TR8.4
USB2_N4: CPU1.AJ1 TR2.1
USB2_N5: CPU1.AF6 TR13.4
USB2_N6: CPU1.AH1 TR1.4
USB2_NGFF_N6: NGFF1.5 TR1.3
USB2_NGFF_P6: NGFF1.3 TR1.2
USB2_P0: CPU1.AB10 TR3.1
USB2_P1: CPU1.AD7 R256.2
USB2_P2: CPU1.AJ3 TR7.4
USB2_P3: CPU1.AD10 TR8.1
USB2_P4: CPU1.AJ2 TR2.4
USB2_P5: CPU1.AF7 TR13.1
USB2_P6: CPU1.AH2 TR1.1
USB2_PWR_EN: C605.1 R856.2 R857.2 U25.4
USB2N_EXT: D8.3 TR7.2 USB3.2
USB2P_EXT: D8.4 TR7.3 USB3.3
USB3_PWR_EN: C74.1 R214.2 R215.2 U5.4
USB3_TX0_EMI_DN: C82.2 L5.1
USB3_TX0_EMI_DP: C81.2 L5.4
USB3_TX1_EMI_DN: C101.2 L9.1
USB3_TX1_EMI_DP: C100.2 L9.4
USB3N_EXT: D8.1 TR8.3 USB4.2
USB3P_EXT: D8.6 TR8.2 USB4.3
USB30_RX_CPU_N0: CPU1.H8 L6.1
USB30_RX_CPU_N1: CPU1.J6 L10.1
USB30_RX_CPU_P0: CPU1.G8 L6.4
USB30_RX_CPU_P1: CPU1.H6 L10.4
USB30_TX_CPU_N0: C82.1 CPU1.C13
USB30_TX_CPU_N1: C101.1 CPU1.B13
USB30_TX_CPU_P0: C81.1 CPU1.D13
USB30_TX_CPU_P1: C100.1 CPU1.A13
USB_EN_S3WAKE: KBC1.71 R214.1 R856.1
USB_OC#0_1: C79.1 CPU1.A9 R229.2 R231.1 U5.3
USB_OC#2_3: C271.1 CPU1.C9 R515.2 R516.1 U25.3
USB_PCH_DN4_NN: TR2.2 WEBCM1.2
USB_PCH_DP4_PP: TR2.3 WEBCM1.1
USB_TOUCH_N: C267.1 TOUCH1.4 TR13.3
USB_TOUCH_P: C266.1 TOUCH1.3 TR13.2
USBCOMP: CPU1.AB6 R609.1
USBP0N_EXT: D3.1 SSUSB1.2 TR3.3
USBP0P_EXT: D3.6 SSUSB1.3 TR3.2
USBP1N_EXT: D3.3 SSUSB2.2 TR4.3
USBP1P_EXT: D3.4 SSUSB2.3 TR4.2
USBVCC01: C75.1 C76.1 C77.1 C94.2 D3.5 SSUSB1.1 SSUSB2.1 TC3.1 U5.1
USBVCC23: C241.1 C261.1 C264.1 C272.1 D8.5 TC4.1 U25.1 USB3.1 USB4.1
USBVCCTP: C623.1 F7.2 TOUCH1.5
V_1P5_HDMI: C210.1 C211.1 C212.1 C213.1 C233.1 C235.1 C575.1 R822.1 U17.12 U17.19 U17.20 U17.31 U17.40 U35.2
V_1P05_LAN: C269.1 C596.1 C600.1 C601.1 C602.1 C603.1 C607.1 C610.1 C611.1 C612.1 U23.3 U23.8 U23.22 U23.24 U23.30
V_3_CARD: C401.2 C403.2 C405.1 MEMCD1.4 U28.12
V_3P0_BAT_VREG: C37.1 C42.1 C45.1 D7.3 R137.1 R293.2 R397.2 R578.1 R590.1 R629.1
V_3P3_A: C205.2 C604.1 D7.1 KBC1.75 PG21.1 PR100.1 PR101.1 PR102.1 PR241.2 PR254.2 PR263.1 Q41.S R230.1 R296.1 R371.1 R383.1 R450.2 R655.2 R732.1 R774.1 R786.1 R787.1 R839.1 U38.2 U38.3
V_3P3_LAN: C238.1 C239.1 C255.1 C258.1 C260.1 C262.1 C265.1 C597.1 C598.1 C599.1 C609.1 C614.1 Q81.D Q82.G R482.2 R517.1 R864.2 R865.1 R879.1 R895.1 U20.5 U23.11 U23.23 U23.32 U24.5 U39.5
V_3P3_PCIVAUX: C4.1 C6.1 C7.1 C8.1 NGFF1.2 NGFF1.4 NGFF1.72 NGFF1.74 Q2.G Q50.D R6.1 R24.1 R25.1 R542.2 TC1.1
V_5_CODEC: C110.1 C115.1 C123.2 L11.1 U11.39
V_5_CODEC_R: D4.K L11.2 R273.1
V_5HDD: C9.1 C10.1 C14.1 R67.2 R68.2 SATAP1.1 SATAP1.3 TC2.1
V_5P0_A: PG22.2 PR202.2 R129.2 R131.2
V_5P0_HDMI_CONN: C578.1 HDMI1.18 HDMI3.2 L29.1
V_5P0_HDMI_CONN_L: F6.2 L29.2
V_19_INV: C222.1 C229.1 F3.2 L21.1 R454.2 R484.1
VD1_EN#: KBC1.66 R364.1
VD_IN1: C171.1 C172.1 KBC1.104 R112.1 R382.2 R383.2
VD_IN2: C167.1 C168.1 KBC1.94 R119.1 R371.2 R372.2
VD_OUT1#: D18.2 KBC1.110
VD_OUT2#: D18.1 KBC1.112
VGA_CORE_DISCHG: Q53.3 R666.2
VIDALERT#_CPU: CPU1.B63 R93.1
VIDALERT#_CPU_R: PR26.2 PR184.1 R92.2 R93.2
VIDSCK_CPU: CPU1.A63 R89.2
VIDSCK_CPU_R: PR25.2 PR185.1 R86.2 R89.1
VIDSOUT_CPU: CPU1.D64 R88.2
VIDSOUT_CPU_R: PR22.2 PR183.1 R87.2 R88.1
VOUT_INV: C572.1 C573.1 C576.1 C577.1 C583.1 CONVT1.3 CONVT1.4 D21.K U36.18
VR_EN: PR186.2 R80.1
VR_EN_C_1: Q4.G Q5.6 R85.2
VR_EN_C_2: Q5.2 R95.2
VR_RDY: PR188.2 PR190.2 R78.1
VREF: C243.2 U36.2
VREF_1: C119.1 U11.41
VREG_PCIAUX_PCH: Q48.D Q49.C R537.2 R538.1
VREG_PCIAUX_PCH_1: C292.1 PC175.2 Q50.G R538.2
VRP: C122.1 U11.38
WAKE_N: R30.2 R34.1 R135.2 R136.2 U23.21
WEBCAM_DET_N: KBC1.34 PC183.2 R541.2 WEBCM1.7
XCLK_BIASREF: CPU1.E42 R564.1
XDP_DBRESET#: CPU1.B5 R10.1 R151.2
XDP_DBRESET_XDP#: C2.1 R9.2 R10.2 XDP1.48
XDP_PRDY#: CPU1.D56 TP15.1 XDP1.5
XDP_PREQ#: CPU1.D61 R1.2 XDP1.3
XDP_PRSENT_PIN60: R16.1 R17.2 R18.2 XDP1.60
XDP_PRSNT_PIN1: R58.2 XDP1.1
XDP_SMBCLK: R32.1 XDP1.53
XDP_SMBDAT: R35.1 XDP1.51
XDP_SYS_PWROK: C3.1 R23.1 R27.2 XDP1.47
XDP_TCK_JTAGX: CPU1.A59 R21.2 R22.1 R107.1
XDP_TCLK: CPU1.B61 R22.2 R26.1 R99.1 XDP1.57
XDP_TCLK1: R28.2 XDP1.55
XDP_TDI: CPU1.D60 R14.2 R111.1 XDP1.56
XDP_TDO: R11.2 R12.1 R13.1 R21.1 XDP1.52
XDP_TDO_CPU: CPU1.A61 R12.2 R100.1
XDP_TMS: CPU1.C60 R15.2 R103.1 XDP1.58
XDP_TRST#: CPU1.B59 CPU1.C61 R554.1 XDP1.54
XRF_TDC2: C256.1 XF1.9 XF1.10 XF2.9 XF2.10
XTAL_OUTBUFF: GPU1.C10 R284.1 R285.2
XTAL_SSFOUT: GPU1.A10 R283.1
XTALIN: C107.1 GPU1.C11 X3.1
XTALOUT: C108.1 GPU1.B10 X3.3
XTL_24M_X1_CPU: C27.1 CPU1.E37 R128.1 X1.1
XTL_24M_X2_CPU: C30.1 CPU1.E35 R128.2 X1.3
XTL_32K_X1_CPU: C71.1 CPU1.AM18 R198.1 X2.1
XTL_32K_X2_CPU: C70.1 CPU1.AM20 R198.2 X2.4
N37189306: Q55.G Q56.D R675.2

Pads without a net: CPU1 A3 A4 A11 A15 A25 A26 A27 A29 A31 A33 A36 A38 A40 A50 A52 A69 AB1 AB2 AB3 AB4 AB11 AB12 AB13 AC1 AC3 AD11 AD12 AF8 AF9 AF11 AF12 AF13 AG1 AG2 AG4 AH7 AH8 AH9 AH10 AH11 AH12 AK6 AK7 AK9 AK10 AK62 AL25 AL27 AL61 AM1 AM2 AM3 AM4 AM5 AN1 AN2 AN3 AN8 AN55 AP1 AP2 AP3 AP4 AP5 AP13 AP53 AP56 AR56 AT15 AU1 AU2 AU56 AW1 AW7 AW20 AW48 AW56 AW68 AW69 AW70 AW71 AY1 AY2 AY7 AY8 AY20 AY21 AY56 B2 B3 B9 B11 B15 B25 B26 B27 B29 B31 B33 B36 B38 B40 B50 B69 B70 BA3 BA4 BA7 BA8 BB2 BB4 C2 C4 C7 C8 C11 C12 C15 C23 C24 C27 C28 C29 C31 C32 C33 C36 C37 C38 C50 C51 C52 C54 C70 C71 D1 D3 D4 D5 D7 D8 D9 D12 D15 D23 D24 D27 D28 D29 D31 D32 D33 D36 D37 D38 D50 D51 D52 D54 D71 E1 E2 E3 E10 E25 E27 E28 E30 E38 E40 E48 E61 F6 F10 F25 F30 F46 F48 F50 F52 F60 F61 G1 G2 G3 G46 G50 H5 H10 H11 J2 J5 J10 J68 J71 K45 K46 L6 L7 M1 M4 N1 N2 N3 N7 N11 N12 P1 P2 P3 P4 U4 U11 U12 W7 W8 W10 W11 W12; D10 2; DIMM1 87 88 91 92 100 101 104 105 162 165; DIMM2 87 88 91 92 100 101 104 105 162 165; GPU1 A7 A16 A22 AA1 AA2 AA3 AA4 AA5 AA6 AB1 AB2 AB3 AB4 AB5 AB6 AB13 AB15 AB16 AB18 AB19 AB21 AB27 AC3 AC4 AC13 AC14 AC15 AC16 AC17 AC18 AC19 AC20 AC21 AD1 AD2 AD3 AD4 AD5 AD7 AD10 AD14 AD17 AD20 AD23 AE1 AE3 AE4 AE10 AE12 AE13 AE15 AE16 AE18 AE19 AE21 AE23 AE24 AF2 AF3 AF4 AF10 AF12 AF13 AF15 AF16 AF18 AF19 AF21 AF24 AG3 AG12 AG13 AG15 AG16 AG18 AG19 AG21 AG22 AG24 AG25 B3 B7 B19 C1 C2 C3 C8 C9 C14 D4 D5 E6 E9 E10 F4 F5 F7 F10 F19 G1 G2 G3 G4 G5 G6 G7 H3 H4 J1 J2 J3 J4 J5 K1 K2 K3 K4 K5 K6 L3 L4 M1 M2 M3 M4 M5 N1 N2 N3 N4 N5 P3 P4 P25 R1 R2 R3 R4 R5 T1 T2 T3 T4 T5 T6 T27 U3 U4 U6 V1 V2 V3 V4 V5 V6 W1 W2 W3 W4 W22 Y3 Y4; HDMI1 13 14; HDMI2 13 14; HDMI3 6 7; HDMI4 6 7; KBC1 17 36 37 38 41 49 53 57 60 61 80; LPC1 10; NGFF1 64; PU14 7; PU17 19; RN14 1 8; SATAP1 5; SCA1 23 24 26 27 28 29 30 31 32 41 55 56 60 61 91 92 102 107 116 121 122 123 124 125 126 127 128; TOUCH1 6 7; U1 1; U11 15 17 37 45 46; U15 5 6; U20 3; U28 22 23 25 26 31; U30 17 18 19 20; U31 5; U34 2 5 6 7 10 11 12 25 26 31; U38 5; VRAM1 A5 A11 A13 B11 B13 D13 E11 E13 F11 F13 M2 M4 N2 N4 P2 R2 T2 T4 U2 U4 U5; VRAM2 A5 A11 A13 B11 B13 D13 E11 E13 F11 F13 M2 M4 N2 N4 P2 R2 T2 T4 U2 U4 U5; VRAM3 A5 A11 A13 B11 B13 D13 E11 E13 F11 F13 M2 M4 N2 N4 P2 R2 T2 T4 U2 U4 U5; VRAM4 A5 A11 A13 B11 B13 D13 E11 E13 F11 F13 M2 M4 N2 N4 P2 R2 T2 T4 U2 U4 U5; XDP1 61 62 63 64

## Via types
v1: diameter 0.508, hole 0.254, TOP to BOTTOM, 1994 vias
v2: diameter 0.66, hole 0.33, TOP to BOTTOM, 1238 vias
v3: diameter 0.559, hole 0.305, TOP to BOTTOM, 2025 vias
v4: diameter 0.762, hole 0.381, TOP to BOTTOM, 500 vias
v5: diameter 0.711, hole 0.406, TOP to BOTTOM, 1057 vias

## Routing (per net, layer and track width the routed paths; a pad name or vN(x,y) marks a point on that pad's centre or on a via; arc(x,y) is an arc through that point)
1V1_EN: length 4.2
  BOTTOM w0.254: U31.2 61.07,69.85 60.24,69.02 R718.2 v2(60.1,68.12) 60.1,67.25 C540.1
1V1_FB: length 4.1
  BOTTOM w0.254: R727.1 R719.2 v2(68.87,68.96) 67.98,69.85 U31.7
1V1_POK: length 3.8
  BOTTOM w0.254: R729.2 63.09,66.61 v2(63.28,66.8) 63.28,67.31 62.9,67.69 62.26,67.69 61.99,67.96 U31.1
1V_CPU_XDP_AB: length 26.5
  TOP w0.254: v3(18.96,222.76) 18.96,220.03 19.73,219.25 31.86,219.25 32.86,218.25 32.86,217.61 32.45,217.2 31.3,217.2 30.33,216.23 XDP1.43
  BOTTOM w0.254: v3(18.96,222.76) 19.74,223.55 v2(20.07,223.55) 22.41,223.55 R529.2
1V_CPU_XDP_CD: length 8.8
  TOP w0.254: v3(29.97,222.88) 30.33,222.52 XDP1.44
  BOTTOM w0.254: R528.2 24.32,223.37 27.24,223.37 v2(27.57,223.7) 27.9,223.37 29.49,223.37 v3(29.97,222.88)
1V_DCPDSW: length 4.1
  TOP w0.127: CPU1.AL1 87.79,144.9 88.49,144.21
  TOP w0.254: C51.1 89.11,141.77 v4(89.11,142.6) 89.11,143.59 88.49,144.21
1V_EDRAM: length 2.2
  TOP w0.305: CPU1.P62 79.2,179.02 v1(79.26,178.97) ; CPU1.AB62 82.86,179.63 82.43,179.2 v1(82.43,178.97) ; CPU1.V62 81.03,178.99 v1(81.06,178.97)
  vias: v2(80.07,178.79)
1V_EOPIO: length 4.6
  TOP w0.305: CPU1.AE62 CPU1.AG62 85.3,179.34 v1(85.3,178.97)
  BOTTOM w0.305: R551.2 85.3,179.18 v1(85.3,178.97) 85.25,178.92 v2(85.25,178.05) R555.1
1V_S3: length 186.1
  TOP w0.254: R444.1 134.53,44.64 134.6,44.64 134.96,44.28 v4(134.96,43.64) 134.81,43.48 134.36,43.48 133.88,43 129,43 128.92,43.08 125.19,43.08 123.73,44.54 123.73,45.49 122.59,46.63 122.07,46.63 108.86,46.63 108.33,46.1 105.32,46.1 101.51,49.91 93.89,49.91 84.62,59.18 v3(81.44,59.18)
  L3 w0.254: v3(58.33,59.72) 56.32,61.72 51.78,61.72 46.63,66.87 46.63,76.16 36.79,86 36.79,120.18 49.26,132.65 49.26,137.71 49.82,138.27 v3(49.82,138.56)
  L4 w0.254: v3(58.33,59.72) 64.78,59.72 66.35,58.14 67.82,58.14 68.94,59.27 68.94,59.84 69.96,60.86 71.25,60.86 71.94,60.16 71.94,60 73.93,58.01 80.32,58.01 81.44,59.14 v3(81.44,59.18)
1V_SIP_S5: length 26.1
  TOP w0.254: v1(83.4,154.43) 83.08,154.11 CPU1.AB17 82.34,154.76 CPU1.Y18 ; v3(77.68,135.93) 77.31,135.56 R180.2
  L4 w0.254: v1(83.4,154.43) 81.44,154.43 79.61,152.6 79.61,151.89 79.64,151.86 79.64,147.03 77.15,144.54 77.15,136.46 v3(77.68,135.93)
  BOTTOM w0.254: v3(77.68,135.93) 77.33,135.58 v2(77.33,135.1)
1V_VCC19P2: length 21.3
  TOP w0.254: R142.2 60.49,142.68 60.49,142.63 61.53,141.58 v4(62.57,141.58) 63.3,141.58 64.36,142.65 66.01,142.65 66.68,143.32 66.68,144.9 67.22,145.44 67.22,149.05 68.28,150.12 68.28,151.85 68.58,152.15 70.92,152.15 71.3,152.53 71.97,152.53 CPU1.A14
1V_VCC24TBT: length 19.3
  TOP w0.254: R144.2 60.04,141.03 v4(59.85,140.84) 63.1,140.84 64.52,142.27 66.16,142.27 67.06,143.17 67.06,144.75 67.72,145.41 67.72,147.26 C39.1 68.57,148.11 69.7,148.11 71.11,149.51 71.11,149.56 71.56,150.01 CPU1.A10
1V_VCCAMPHYPLL: length 5
  TOP w0.254: v1(78.13,152.27) 77.96,152.44 CPU1.L15 CPU1.K15
  BOTTOM w0.254: v1(78.13,152.27) 77.97,152.43 77.97,153.17 77.63,153.52 77.6,153.52 v2(77.58,153.54) 77.58,154.44 C375.1 78.43,154.5 R583.2
1V_VCCAPLL: length 16.5
  TOP w0.152: v1(80.19,151.66) 80.42,151.89 80.42,152.1 81.13,152.81 CPU1.V15
  BOTTOM w0.152: 79.58,147.23 79.58,147.87 79.57,147.87 79.57,150.06 79.66,150.15 79.66,151.14 v1(80.19,151.66)
  BOTTOM w0.254: R627.2 76.66,139.2 76.66,143.18 v2(77,143.51) 78.33,144.84 C634.1 79.58,145.39 79.58,147.23
1V_VCCAPLLEBB: length 4.9
  TOP w0.191: v1(79.22,156.35) 79.22,155.28 78.8,154.86 CPU1.N18
  BOTTOM w0.254: v2(80.88,154.23) 80.4,154.71 R582.2 79.62,154.9 C373.1 79.62,155.95 v1(79.22,156.35)
1V_VCCDTS: length 40.6
  TOP w0.254: v3(63.26,133.5) 64.48,134.72 67.14,134.72 67.37,134.95 67.75,134.95 67.98,135.18 74.41,135.18 77.86,138.63 77.86,138.84 79.1,140.08 79.1,143.97 79.52,144.39 79.52,144.69 CPU1.T1 ; R139.2 60.29,145.92 v3(60.87,145.92)
  L3 w0.254: v3(63.26,133.5) 62.11,133.5 59.95,135.66 59.95,145.01 v3(60.87,145.92)
  BOTTOM w0.254: v2(62.39,133.5) v3(63.26,133.5)
1V_VCCF24NS: length 60.5
  TOP w0.254: R149.2 C61.1 45.12,140.54 v3(45.12,140.97) ; CPU1.L19 77.54,155.83 v1(77.54,156.35)
  L3 w0.254: v1(74.07,167) 74.07,165.1 76.61,162.56 76.61,156.61 76.87,156.35 v1(77.54,156.35)
  L4 w0.191: 74.84,156.46 74.86,156.49 76.22,156.49 76.36,156.35 v1(77.54,156.35)
  L4 w0.203: 74.01,155.64 74.84,156.46
  L4 w0.254: 74.01,155.64 70.52,152.15 59.76,152.15 56.73,149.11 56.73,143.43 56.04,142.75 46.9,142.75 v3(45.12,140.97)
  BOTTOM w0.254: v3(45.12,140.97) v2(45.12,141.81) ; R564.2 74.1,167.03 v1(74.07,167)
1V_VCCF100: length 52.4
  TOP w0.089: v1(77.58,158.29) 77.1,157.82 77.1,157.21 76.84,156.95 76.84,155.7 CPU1.K19
  TOP w0.254: v3(43.09,140.65) 43.03,140.59 43.01,140.59 C60.1 R148.2
  L4 w0.178: v1(77.58,158.29) 76.66,158.29 75.79,157.41 74.5,157.41 73.33,156.25 73.33,155.45
  L4 w0.254: 73.33,155.45 70.41,152.53 59.47,152.53 55.99,149.05 55.99,144.06 55.76,143.83 55.76,143.48 55.41,143.13 46.26,143.13 43.78,140.65 v3(43.09,140.65)
  BOTTOM w0.254: v2(43.9,140.36) 43.61,140.65 v3(43.09,140.65)
1V_VCCF100OC: length 47.9
  TOP w0.254: R150.2 C62.1 47.15,140.54 v3(47.15,141.1) ; v1(79.18,157.4) 78.97,157.4 78.43,156.87 78.43,156.43 CPU1.N20
  L4 w0.203: v1(79.18,157.4) 79.18,156.96 76.88,154.66 74.55,154.66 74.2,154.32 74.2,154.31
  L4 w0.254: v3(47.15,141.1) 48.04,141.99 56.36,141.99 58.3,143.93 58.3,148.59 60.46,150.75 70.97,150.75 74.2,153.98 74.2,154.31
  BOTTOM w0.254: v3(47.15,141.1) v2(47.99,141.1)
1V_VCCF135: length 33.4
  TOP w0.254: CPU1.L21 78.01,156.76 78.01,157.22 77.58,157.66 v1(77.53,157.66) ; v3(60.87,146.69) 60.36,147.19 R138.2
  L4 w0.178: 74.06,153.27 74.54,153.75 77.24,153.75 79.66,156.17 79.66,157.55 79.36,157.85 77.72,157.85 v1(77.53,157.66)
  L4 w0.203: 71.06,150.41 71.2,150.41 74.06,153.27
  L4 w0.254: v3(60.87,146.69) 60.83,146.69 59.34,148.18 59.34,149.09 60.37,150.11 70.77,150.11 71.06,150.41
  BOTTOM w0.254: v2(78.52,157.91) 78.27,157.66 v1(77.53,157.66)
1V_VCCFHV: length 81.8
  TOP w0.254: v1(86.52,157.22) 86.75,156.84 86.75,156.49 CPU1.AK20 ; v3(60.87,144.27) 60.74,144.15 R141.2
  L3 w0.254: v3(86.39,120.9) 85.57,120.9 78.46,128.02 72.26,128.02 60.87,139.41 v3(60.87,144.27)
  BOTTOM w0.254: v3(86.39,120.9) 86.39,121.54 v2(87.94,123.09) 90.69,125.83 90.69,127.96 88.07,130.58 v2(88.07,138.68) 88.07,144.04 86.03,146.08 86.03,148.01 84.98,149.06 84.98,150.49 84.93,150.54 84.93,152.47 85.15,152.7 85.15,154.53 85.66,155.04 86.15,155.04 86.42,155.31 86.42,157.12 v1(86.52,157.22)
1V_VCCFUSEPRG: length 4.3
  TOP w0.254: v1(75.38,156.03) 75.38,155.9 CPU1.G20
  BOTTOM w0.254: R575.2 73.79,156.97 74.46,156.31 75.11,156.31 v1(75.38,156.03) 75.03,155.68 74.26,155.68 v2(73.96,155.37)
1V_VCCGT: length 50
  TOP w0.127: CPU1.A53 71.88,174.79 70.52,173.43 v1(70.52,173.35) ; CPU1.A62 72,179.76 70.51,179.76 v1(70.33,179.94) ; CPU1.A58 71.06,177.27 70.28,176.49 69.67,176.49 v1(69.25,176.91) ; v1(71.37,182.41) 71.82,182.41 71.93,182.3 71.93,182.3 CPU1.A66
  TOP w0.254: CPU1.A48 71.73,172.59 71.41,172.59 v1(71.16,172.84) ; PG6.2 PL3.2 ; PL2.2 PG2.2
  TOP w0.508: PT6.1 68.4,195.83 ; PT6.1 67.34,194.78 ; PT6.1 66.29,195.83 ; PT6.1 67.34,196.89 ; 60.07,190.25 PT7.1 ; PT7.1 61.12,189.19 ; PT7.1 62.17,190.25 ; PT7.1 61.12,191.3
  L3 w0.508: 60.07,190.25 PT7.1 ; PT7.1 62.17,190.25 ; PT7.1 61.12,189.19 ; PT7.1 61.12,191.3 ; 66.29,195.83 PT6.1 67.34,196.89
  L4 w0.508: v1(69.25,176.91) 69.25,174.62 v1(70.52,173.35) 70.65,173.35 v1(71.16,172.84) 71.28,172.72 75.47,172.72 v3(77.12,174.37)
  BOTTOM w0.508: C294.1 78.14,197.8 78.14,195.33 v3(78.11,195.29) ; 66.29,195.83 PT6.1 67.34,194.78 ; PT7.1 61.12,191.3 ; PT7.1 60.07,190.25 ; PT7.1 61.12,189.19 ; PT7.1 62.17,190.25
  vias: v1(78.29,184.99) v1(78.29,184.34) v1(78.29,183.69) v1(78.29,183.03) v1(78.29,182.38) v1(78.29,181.73) v1(78.29,181.08) v1(78.29,180.43) v1(80.12,184.99) v1(80.12,184.34) v1(80.12,183.69) v1(80.12,181.08) v1(80.12,180.43) v1(81.95,184.99) v1(81.95,184.34) v1(81.95,182.38) v1(81.95,180.43) v2(58.4,215.14) v2(62.21,185.47) v2(62.85,198.7) v2(78.32,173.43) v2(80.4,192.68) v2(82.96,186.06) v3(77.12,178.05) v3(77.12,177.16) v3(77.12,176.15) v3(77.12,175.26) v3(77.38,172.85) v3(77.38,172.09) v3(78.27,178.05) v3(78.27,177.16) v3(78.27,176.15) v3(78.27,175.26) v3(78.27,174.37) v3(79.28,172.72) v3(79.41,178.05) v3(79.41,177.16) v3(79.41,176.15) v3(79.41,175.26) v3(79.41,174.37) v5(59.85,213.72) v5(60.1,205.36) v5(60.23,208.28) v5(60.23,207.14) v5(60.23,203.45) v5(60.23,202.31) v5(60.23,193.17) v5(60.23,192.02) v5(60.36,188.34) v5(60.36,187.2) v5(60.87,213.72) v5(61.12,205.36) v5(61.25,208.28) v5(61.25,207.14) v5(61.25,203.45) v5(61.25,202.31) v5(61.25,193.17) v5(61.25,192.02) v5(61.37,188.34) v5(61.37,187.2) v5(61.88,213.72) v5(62.14,205.36) v5(62.26,208.28) v5(62.26,207.14) v5(62.26,203.45) v5(62.26,202.31) v5(62.26,193.17) v5(62.26,192.02) v5(62.39,188.34) v5(62.39,187.2) v5(62.64,206.25) v5(62.64,204.47) v5(62.9,213.72) v5(63.15,205.36) v5(63.28,208.28) v5(63.28,207.14) v5(63.28,203.45) v5(63.28,202.31) v5(64.55,196.6) v5(64.55,195.33) v5(65.57,196.6) v5(65.57,195.33) v5(78.77,192.15) v5(78.97,185.94) v5(79.54,192.91) v5(79.92,189.74) v5(80.32,187.13) v5(80.3,186.27) v5(80.42,193.68) v5(80.68,190.5) v5(81.23,187.06) v5(81.24,186.2)
1V_VCCGTUS: length 27.5
  TOP w0.102: CPU1.BB57 95.75,177.24 97.47,178.97 v1(97.78,178.97)
  TOP w0.127: CPU1.BB66 94.77,182.22 v1(95.26,182.72)
  TOP w0.152: v3(86.27,187.26) 86.67,186.86 86.67,186.17 86.9,185.94 86.9,185.06 CPU1.AK70
  TOP w0.254: v1(86.68,170.66) 86.68,170.66 CPU1.AL46 ; CPU1.AL50 86.68,172.49 v1(86.68,172.49) ; v1(86.68,176.14) 86.68,176.15 CPU1.AL56 ; CPU1.AL53 86.68,174.32 v1(86.68,174.32)
  TOP w0.305: v1(90.87,179.81) 91.2,180.13 CPU1.AU63 ; CPU1.AU58 91.2,177.39 v1(90.87,177.06)
  BOTTOM w0.381: 87.74,177.32 87.74,177.74 87.73,177.75 87.73,178.2 87.74,178.22 87.74,178.65 87.73,178.67 87.73,179.15 87.54,179.34 87.54,181.27 87.73,181.46 v2(87.73,181.48) 88.25,182 88.25,185.33 87.98,185.6 86.32,187.26 v3(86.27,187.26)
  BOTTOM w0.508: 93.89,179.96 93.89,181.34 v1(95.26,182.72)
  vias: v2(87.36,170.26) v2(96.65,179.45)
1V_VCCIO: length 197
  TOP w0.254: R90.1 12.35,185.29 v3(12.48,185.42) ; v1(86.52,167.89) 86.57,167.94 87.45,167.94 CPU1.AL42 87.49,167.92 CPU1.AM42
  TOP w0.305: R19.1 43.21,225.17 v3(42.96,225.43)
  L4 w0.381: v1(86.39,161.67) 87.1,162.37 87.1,167.32 v1(86.52,167.89)
  L4 w0.508: v1(71.15,157.99) 73.06,159.89 79.77,159.89 80.48,159.18 84.69,159.18 85.63,158.25 86.93,158.25 87.28,158.59 87.28,160.32 86.56,161.04 v1(86.39,161.04)
  BOTTOM w0.254: v5(40.8,136.91) v2(40.8,135.76) 40.83,135.74 40.83,132.88 40.51,132.56 37.28,132.56 35.42,134.41 15.77,134.41 13.37,136.81 13.37,149.22 12.48,150.11 v2(12.48,178.18) 12.23,178.44 12.23,185.17 v3(12.48,185.42) 10.93,185.42 8.16,188.19 8.16,203.72 4.18,207.71 4.18,214.84 12.86,223.52 v2(13.24,223.52) 13.47,223.29 14.61,223.29 15.91,222 33.45,222 35.48,224.03 40.32,224.03 v2(40.44,224.16) 41.69,224.16 v3(42.96,225.43)
  BOTTOM w0.305: R574.2 71.34,157.8 v1(71.15,157.99)
  BOTTOM w0.381: C321.1 86.71,168.08 v1(86.52,167.89) 86.52,168.09 86.34,168.27 86.33,168.27 86.33,168.28 85.97,168.64 85.82,168.79 R562.1
  BOTTOM w0.508: R625.2 v5(40.8,136.91) ; v5(70.01,144.4) v2(70.64,145.03)
  vias: v5(38.74,136.91) v5(39.76,136.91) v5(70.01,143.51) v5(70.01,142.62)
1V_VCCMPHYAON: length 58.9
  TOP w0.127: 77.31,142.56 77.31,143.07 77.04,143.34 77.04,144.24 77.19,144.55 77.19,144.69 CPU1.L1
  TOP w0.178: CPU1.K17 77.12,154.3 76.79,154.63 76.79,154.69 76.37,155.12 v1(76.03,155.12)
  TOP w0.254: 77.31,142.56 C55.1 77.25,141.29 77.25,138.88 74.31,135.94 v3(73.64,135.94) 73.49,135.79 63.2,135.79 v3(62.67,135.25) ; R140.2 60.74,145.16 v3(60.87,145.03)
  L3 w0.254: v3(62.67,135.25) 60.33,137.59 60.33,144.5 v3(60.87,145.03)
  BOTTOM w0.254: v1(76.03,155.12) 76.03,154.89 76.94,153.99 76.94,153.33 77.63,152.64 77.63,149.09 77.38,148.84 77.38,145.8 v2(74.73,143.15) 72.87,141.29 72.87,136.72 v3(73.64,135.94) ; v3(62.67,135.25) v2(62.67,136.14)
1V_VCCMPHYGTAON: length 33.1
  L4 w0.508: v3(53.98,138.63) 55.87,138.63 58.18,140.94 62.16,140.94 62.92,141.7 62.92,142.39 68.11,147.57 71.53,147.57 74.46,150.5 75.93,150.5 77.38,151.94 77.38,152.39 77.87,152.88 78.54,152.88 v1(79.11,152.32)
  BOTTOM w0.508: v3(53.98,138.63) 53.98,139.17 v2(54.41,139.6)
1V_VCCPRIM: length 43.8
  TOP w0.163: v1(80.87,155.09) 80.62,155.09 80.62,155.09 80.34,155.09 80.34,155.09 79.97,155.09 CPU1.P18
  TOP w0.254: CPU1.AB20 83.07,156.06 v1(83.4,155.73) 83.08,155.41 CPU1.AB19
  TOP w0.508: R146.2 C57.1 52.01,140.27 v3(51.95,140.21)
  L4 w0.203: 74.13,152.57 74.4,152.83 76.92,152.83 79.17,155.09 v1(80.87,155.09)
  L4 w0.254: v1(80.87,155.09) 81.05,154.91 82.57,154.91 v1(83.4,155.73)
  L4 w0.508: 74.13,152.57 71.13,149.57 71.13,149.35 70.11,148.34 67.98,148.34 67.85,148.21 67.84,148.21 62.29,142.66 62.29,141.97 61.9,141.58 57.92,141.58 56.55,140.21 v3(51.95,140.21)
  BOTTOM w0.508: v3(51.95,140.21) v2(51.95,141.02)
1V_VCCPRIM_CORE: length 62.7
  TOP w0.254: CPU1.V21 81.38,156.71 v1(81.72,156.38) 81.69,156.35 81.6,156.35 CPU1.V20
  TOP w0.305: v1(84.27,156.39) 84.24,156.36 84.24,155.81 84.63,155.41 CPU1.AF19 CPU1.AF18
  L4 w0.254: v3(43.09,141.48) 44.07,141.48 46.1,143.51 54.34,143.51 55.61,144.78 55.61,149.21 59.31,152.91 69.52,152.91 73.06,156.44 73.06,157.79 74.7,159.42 79.57,159.42 81.72,157.28 v1(81.72,156.38)
  BOTTOM w0.254: v1(81.72,156.38) 81.87,156.53 C365.1 84.13,156.53 v1(84.27,156.39)
  BOTTOM w0.508: R625.1 39.89,139.57 v2(39.41,140.06) 40.2,140.84 R615.2 R614.2 42.71,141.48 v3(43.09,141.48)
1V_VCCSA: length 48.7
  TOP w0.305: PG14.2 PL5.2
  TOP w0.508: 48.89,164.72 PT11.1 ; PT11.1 51,164.72 ; PT11.1 49.94,163.66 ; PT11.1 49.94,165.77
  L4 w0.305: v3(42.07,144.53) 42.32,144.78 47.94,144.78 49.77,146.61 51.14,146.61 58.05,153.52 58.05,156.57 56.42,158.19 56.42,164.97 54.52,166.88 v5(52.1,166.88)
  BOTTOM w0.305: v3(42.07,144.53) R614.1
  BOTTOM w0.508: PT11.1 51,164.72 ; PT11.1 49.94,165.77 ; PT11.1 48.89,164.72 ; PT11.1 49.94,163.66
  vias: v1(71.38,161.09) v1(72.07,161.09) v1(74.73,160.61) v1(85.38,160.27) v1(86.61,159.56) v1(86.56,158.89) v2(44.38,168.07) v2(56.52,166.34) v2(69.15,158.72) v2(78.39,159.38) v3(77.12,161.54) v3(77.12,160.53) v5(43.85,166.62) v5(44.99,166.62) v5(46.36,163.86) v5(47.4,163.83) v5(52.74,167.64)
1V_VCCSFR: length 52.2
  TOP w0.203: CPU1.K20 77.09,156.1 77.09,156.68 CPU1.K21
  TOP w0.254: CPU1.K21 77.14,156.71 77.45,157.02 v1(77.53,157.02) ; R169.1 49.86,137.48 v3(49.82,137.52)
  L4 w0.178: v1(77.53,157.02) 77.62,157.02 77.99,156.65 77.99,156.17 77.39,155.57 74.55,155.57 74.19,155.21
  L4 w0.254: v3(49.82,137.52) 48.83,138.5 48.83,139.35 47.97,140.21 47.28,140.21 46.62,140.88 46.62,141.32 47.67,142.37 56.2,142.37 57.49,143.66 57.49,148.67 59.94,151.13 70.87,151.13 72.15,152.41 72.15,153.16 74.19,155.21
  BOTTOM w0.254: v2(49,137.92) 49.06,137.92 49.46,137.52 v3(49.82,137.52) ; v1(77.53,157.02) 77.4,157.02 76.74,156.36 C367.1
1V_VCCSRAM: length 11.8
  TOP w0.254: CPU1.T20 80.48,156.05 80.79,155.73 ; v1(84.49,157.23) 84.67,157.05 CPU1.AF21 84.75,156.63 84.75,156.14 CPU1.AF20 ; 80.79,155.73 v1(80.89,155.73) ; 80.79,155.73 CPU1.T19
  L4 w0.254: v1(84.49,157.23) 84.44,157.23 84.03,156.82 83.53,156.82 81.96,155.25 81.39,155.25 81.07,155.57 81.05,155.57 v1(80.89,155.73)
  BOTTOM w0.356: C372.1 81.67,155.07 81,155.73 v1(80.89,155.73)
  BOTTOM w0.508: R581.2 82.53,153.21 81.82,153.92 C368.1 81.82,155.05 C372.1 ; v2(85.3,158.01) 85,158.01 84.49,157.51 v1(84.49,157.23)
1V_VCCST: length 169.8
  TOP w0.127: v1(70.75,154.81) 70.9,154.97 CPU1.A18
  TOP w0.254: R87.1 67.42,185.22 v4(66.58,186.06) 66.39,185.86 R86.1 64.23,185.86 ; PR23.1 PR22.1 ; PR22.1 PC36.1 PR25.1 PR26.1 ; PR22.1 v3(22.54,191.96) ; 64.23,185.86 63.79,185.42 63.79,184.66 64.17,184.28 64.68,184.28 64.93,184.02 64.93,182.51 R94.1 65.46,182.18 v3(66.58,182.18) R92.1 ; 64.23,185.86 63.79,186.31 63.79,186.88 R83.2 64.68,188.47 64.37,188.77 64.37,191.85 65.31,192.79 69.18,192.79 R65.1
  L4 w0.254: 60.25,175.62 63.35,178.71 64.06,178.71 65.06,179.71 65.06,180.85 66.39,182.18 v3(66.58,182.18) ; 60.25,175.62 63,172.87 63,170.92 68.69,165.23 71.58,165.23 71.85,165.5 73.6,165.5 74.63,164.46 74.63,162.86 70.07,158.3 70.07,155.49 v1(70.75,154.81) ; 60.25,175.62 52.91,175.62 47.04,169.75 26.37,169.75 18.6,177.52 18.6,179.7 17.74,180.57 17.74,190.17 19.53,191.96 v3(22.54,191.96)
  BOTTOM w0.254: v3(51.98,136.61) 51.98,136.63 v2(52.66,137.31) 52.99,137.64 52.99,147.4 56.09,150.5 58.45,150.5 59.6,151.64 65.44,151.64 68.11,154.31 70.24,154.31 v1(70.75,154.81)
1V_VCCSTG: length 135.8
  TOP w0.254: R100.2 65.16,179.62 65.16,178.78 R105.2 ; R13.2 36.99,224.92 v3(36.48,225.43) ; R105.2 65.63,178.18 v3(64.55,178.18) 64.02,177.65 64.02,177.2 64.43,176.78 65.36,176.78 65.88,176.26 R110.2 66.49,176.38 66.87,176.38 R107.2 ; R105.2 66.01,178.56 R103.2 ; v3(66.58,187.07) 67.33,187.07 R81.1 ; v3(64.55,175.26) 64.68,175.13 R114.2 65.82,174.43 R111.2 ; CPU1.A22 71.95,157.51 70.98,157.51 v1(70.82,157.35)
  L4 w0.254: v3(66.58,187.07) 67.98,185.67 67.98,182.82 67.65,182.49 67.65,179.15 67.1,178.6 64.97,178.6 v3(64.55,178.18) 64.02,177.65 64.02,175.79 v3(64.55,175.26) 64.55,170.19 68.8,165.94 73.64,165.94 74.97,164.61 74.97,162.57 70.62,158.22 70.62,157.56 v1(70.82,157.35) ; v3(68.74,220.88) 68.62,220.88 63.5,226 51.81,226 50.83,226.97 38.03,226.97 v3(36.48,225.43)
  BOTTOM w0.254: v3(68.74,220.88) 69.25,220.37 v2(69.25,220.01) 69.25,219.84 70.52,218.57 70.52,194 67.27,190.75 67.27,187.76 v3(66.58,187.07) ; v3(64.55,175.26) 65.44,175.26 v2(65.57,175.13) ; v2(36.48,224.61) v3(36.48,225.43) ; v1(70.82,157.35) 71.27,156.91 R574.1 72.8,156.91 R575.1 C362.1
1V_XDP_S5: length 13.4
  TOP w0.254: R1.1 v3(15.53,225.93)
  BOTTOM w0.254: R532.1 C284.1 25.37,223.96 24.04,225.3 R528.1 R529.1 22.39,225.3 21.56,224.47 C283.1 20.86,224.85 17.7,224.85 R533.2 16.39,224.87 v2(16.01,225.25) 15.53,225.73 v3(15.53,225.93)
3V3_VDD33:
  vias: v1(85.55,94.67) v1(86.95,94.67) v2(92.49,94.11)
3V3AUX_CR: length 1.5
  BOTTOM w0.203: 173.9,148.97 174.19,148.68 U28.27
  vias: v2(172.27,153.11)
3V_VA: length 5.7
  TOP w0.203: U11.25 165.62,74.06
  TOP w0.508: L13.2 v3(161.96,66.8)
  L3 w0.508: v3(161.96,66.8) 163.48,66.8 165.26,68.58 v3(165.26,69.22)
  vias: v4(166.91,68.71)
+19V_AMP_AVCC: length 4.6
  TOP w0.305: U14.12 155.74,49.15 155.61,49.28
  TOP w0.508: R431.2 C188.1 154.72,50.16 155.51,49.38 v4(155.51,49.35) 155.53,49.35 155.61,49.28
+19V_AMP_PVCC: length 14.3
  L3 w1.016: v5(155.61,48.13) 155.61,46.23 157.51,44.32 163.1,44.32 v5(166.02,47.24)
  vias: v4(150.31,49.14)
+VCCPRTC_3P3: length 28.2
  TOP w0.127: v1(96.55,151.51) 96.27,151.51 95,152.77 94.1,152.77 CPU1.BB14 ; CPU1.AK19 87.8,156.03 v1(88.27,156.03)
  TOP w0.254: R137.2 102.46,150.94 C36.2 C35.1 100.43,151.38 96.68,151.38 v1(96.55,151.51)
  BOTTOM w0.203: 91.61,155.99 90.42,155.99 90,155.58 88.73,155.58 v1(88.27,156.03)
  BOTTOM w0.254: 91.61,155.99 93.26,155.99 93.67,155.57 98.25,155.57 99.22,154.61 v2(99.22,154.18) 99.22,152.68 98.05,151.51 v1(96.55,151.51)
AGND: length 68.3
  TOP w0.203: U11.22 163.99,72.26 164.04,72.22 v3(164.04,72.1) ; U11.28 166.64,75.45 v3(167.17,74.93) ; 162.38,81.22 162.85,80.75 162.85,80.26 162.79,80.21 U11.42
  TOP w0.305: U14.4 160.05,52.47 v3(160.41,52.83) ; v3(160.94,60.96) 160.6,61.3 U13.6
  TOP w0.381: C161.2 C162.2 154.59,63.7 v3(154.21,63.32)
  TOP w0.508: C185.2 165.58,52.13 v3(166.15,52.7) ; R277.2 v3(159.04,86.87) ; 167.24,82.68 v3(168.18,82.68) ; 167.24,82.68 167.5,82.93 C110.2 ; 167.24,82.68 C115.2 ; R386.2 162.34,60.02 161.98,60.02 161.04,60.96 v3(160.94,60.96) 160.46,60.96 160.18,60.68 C173.1 R387.2 ; v3(152.69,58.67) 152.55,58.53 R389.1 ; C109.2 161.58,84.3 v3(161.58,83.31) ; R427.2 153.86,51.31 C188.2 154.24,52.7 v3(154.11,52.83) ; C144.2 v3(162.21,69.22) ; C216.2 82.52,37.91 v3(82.46,37.85) ; v3(162.82,55.93) 162.82,55.73 163.49,55.05 R406.1 ; v3(163.74,69.22) C145.2 164.05,70.55 C142.1 164.05,72.08 v3(164.04,72.1) ; C123.1 v3(166.56,81.03) ; UHS1.5 173.27,72.96 C137.2 R341.2 ; C217.2 85.44,37.91 v3(85.5,37.85) ; C234.2 82.9,32.38 v3(82.33,32.38) ; v3(161.58,83.31) 161.58,82.45 C119.2 161.73,82.28 162.38,81.64 162.38,81.22 ; v3(161.58,83.31) C113.1 ; v3(159.42,80.14) 159.55,80.26 R307.2 ; C126.2 171.71,79.4 v3(171.74,79.38) ; C128.2 171.8,77.91 v3(171.86,77.85) ; C122.2 v3(171.74,81.41) ; v3(179.1,83.01) 178.85,82.75 R304.2 ; R385.2 v3(156.12,60.83) ; v3(155.99,56.52) 155.93,56.45 R401.2 ; C143.2 168.05,70.93 C146.2 168.05,69.34 v3(168.18,69.22) ; R407.2 159.66,54.14 160.35,53.45 160.35,53.27 160.41,53.21 v3(160.41,52.83) ; R395.1 163.05,57.35 162.97,57.28 v3(162.82,57.28) C178.1 C177.1 159.55,57.28 R396.1 ; C135.2 171.8,74.87 v3(171.86,74.93) ; R297.2 v3(173.64,81.03) ; R313.2 167.61,78.55 168.05,78.11 v3(168.31,78.11) ; C116.2 v3(172.63,81.03) ; v3(168.82,86.11) 168.66,86.26 Q25.S 166.68,86.26 166.05,86.89 R278.2 ; Q38.S 161.93,64.29 v3(161.7,64.52) 161.45,64.77 R366.2
  BOTTOM w0.508: v3(162.82,55.93) 163.28,55.93 v2(163.84,55.37) ; v3(179.1,83.01) 178.95,83.16 v2(178.95,83.82)
AV12: length 17.6
  BOTTOM w0.203: U28.10 175.79,142.89 176.18,142.49
  BOTTOM w0.508: R632.2 R631.1 173.58,134.43 174.45,133.55 176.99,133.55 178.64,135.2 v2(178.64,135.78) 179.15,136.29 179.15,138.13 178.21,139.06 178.21,140.23 176.94,141.5 176.94,141.73 176.18,142.49
AV12_L: length 2.5
  BOTTOM w0.508: v2(176.59,134.32) 176.41,134.32 175.66,135.06 C411.2 174.53,135.06 R631.2
DV12S: length 11.6
  BOTTOM w0.203: 172.8,141.07 174.19,142.45 U28.14
  BOTTOM w0.508: 172.8,141.07 171.56,139.83 171.56,138.19 C406.2 171.17,136.82 C408.1 171.1,136.49 170.58,135.97 170.54,135.97 170.16,135.59 v2(170.16,135.1) 170.27,135.1 170.37,135 R632.1
DV33_18: length 4.4
  BOTTOM w0.203: 171.79,144.34 171.99,144.54 U28.18
  BOTTOM w0.508: 171.79,144.34 171.81,144.32 171.81,143.18 v2(171.14,142.52) 170.98,142.52 170.62,142.88 C396.2
GND: length 2611.6
  TOP w0.089: CPU1.BB67 94.51,183.1 94.52,183.1 95.18,183.77 v1(95.18,183.87) ; CPU1.B62 72.4,179.49 71.88,179.49 71.83,179.51 71.21,179.51 71.16,179.46 ; v1(86.21,186.6) 86.21,186.28 86.6,185.89 86.6,185.21 86.57,185.07 86.57,184.91 86.62,184.72 86.62,184.55 CPU1.AK69 ; v1(69.88,176.91) 70.34,176.91 70.91,177.48 71.79,177.48 71.8,177.48 71.92,177.53 72.12,177.53 72.25,177.47 72.46,177.47 CPU1.B58
  TOP w0.102: 73.31,166.85 73.31,166.55 73.54,166.32 74.18,166.32 74.3,166.19 74.56,166.19 ; CPU1.BB38 94.02,166.14 94.73,166.14 94.84,166.03 97.3,166.03 v1(98.04,166.78) ; v3(64.3,155.93) 62.29,155.93 62.26,155.97 62.12,155.97 61.38,156.71 X1.2 ; CPU1.G5 75.36,146.99 74.89,146.99 CPU1.F4
  TOP w0.127: CPU1.BB30 95.57,161.19 v1(95.74,161.02) ; CPU1.AP70 89.56,184.49 89.56,186.31 v1(89.64,186.39) ; CPU1.AW32 92.01,162.48 92.01,161.72 92.04,161.69 CPU1.AW30 ; v1(95.48,168.92) 95.17,168.92 95.04,168.8 94.02,168.8 CPU1.BB43 ; CPU1.AG71 85.5,185.63 84.96,186.17 84.96,188.3 v1(84.22,189.04) ; v1(97.89,177.44) 97.62,177.44 96.13,175.95 94.24,175.95 94.2,175.94 CPU1.BB55 ; v1(94.96,180.86) 94.93,180.89 CPU1.BB64 ; CPU1.D18 73.68,155 74.03,155.35 74.03,155.72 74.41,156.1 CPU1.E21 ; CPU1.AW28 92.04,159.58 92.01,159.55 92.01,158.77 CPU1.AW26 ; CPU1.AT71 90.51,185.84 90.99,186.32 v1(90.99,186.54) ; 97.34,163.93 97.16,163.75 94.74,163.75 94.67,163.82 CPU1.BB34 ; v1(94.27,187.17) 94.83,186.61 94.83,185.4 94.31,184.88 CPU1.BB70 ; CPU1.BA28 93.5,160.01 93.65,159.86 94.42,159.86 94.62,159.65 95.25,159.65 v1(95.41,159.49) ; CPU1.AM71 88.17,185 88.17,186.39 v1(87.97,186.59) ; v1(96.31,158.03) 96.09,158.25 95.24,158.25 94.65,158.83 CPU1.BB26 ; CPU1.AW60 92.01,178.47 92.01,179.69 CPU1.AW62
  TOP w0.152: CPU1.L4 77.57,147.02 78.21,147.02 CPU1.N6 ; v1(75.38,157.86) 75.38,157.73 CPU1.G22 75.71,157.41 76.63,157.41 CPU1.K22 ; CPU1.G52 75.85,174 75.85,174.46 76.03,174.64 76.03,174.92 75.79,175.16 75.54,175.16 v1(75.47,175.23) ; CPU1.D26 74,160.25 74,162.07 CPU1.D30 ; CPU1.BA23 92.94,157.22 92.36,157.22 CPU1.AW23 92,157.58 92,158.69 CPU1.AW26 ; CPU1.K67 76.14,182.73 75.76,182.35 CPU1.G66
  TOP w0.178: CPU1.G45 75.71,170.03 75.82,169.91 75.82,169.41 CPU1.G43 ; 92.02,171.87 92.02,172.34 CPU1.AW49 92.33,172.06 92.81,172.06 92.84,172.09 92.88,172.09 93.14,172.36 CPU1.BA49 ; CPU1.AM25 87.83,159.35 87.83,160.03 CPU1.AM27 ; CPU1.N13 78.6,152.43 78.38,152.65 78.38,153.05 CPU1.L16 ; CPU1.AW66 92.02,181.98 92.02,181.75 91.98,181.72 91.98,181.4 92.04,181.34 CPU1.AW64 ; CPU1.AT42 CPU1.AR42 CPU1.AP42 ; CPU1.P17 79.26,154.49 79.26,154.92 79.64,155.3 CPU1.P19 ; CPU1.AM60 87.83,178.55 87.83,179.23 CPU1.AM61 ; CPU1.AP20 CPU1.AR20
  TOP w0.203: VRAM1.D10 53.39,111.23 v1(53.76,110.85) ; CPU1.A67 72.03,182.56 72.32,182.56 72.65,182.23 CPU1.B66 ; v1(133.38,137.41) 133.26,137.29 133.26,137.24 132.95,136.93 132.48,136.93 132.13,137.28 DIMM1.213 ; U17.8 136.29,36.56 v3(136.3,36.58) ; v1(61.12,89.79) 61.44,89.47 VRAM2.D10 ; CPU1.AW12 90.9,151.43 v1(90.87,151.46) ; v1(77.49,185.79) 77.31,185.61 77.31,185.04 CPU1.K71 CPU1.K70 ; v1(90.11,144.29) 90.12,144.29 90.12,145.33 CPU1.AT2 ; v1(146.08,55.63) 145.95,55.5 KBC1.45 ; CPU1.AD19 83.85,155.44 83.85,156.04 CPU1.AD20 83.81,156.08 83.81,156.69 CPU1.AD21 ; CPU1.AW49 92.02,172.37 92.02,173.53 CPU1.AW51 92.02,173.57 92.02,174.74 CPU1.AW53 92.57,174.76 v1(92.73,174.6) ; CPU1.D45 73.8,170.51 CPU1.E46 ; CPU1.AM8 87.41,149.17 87.01,148.78 CPU1.AK8 ; v1(85.52,88.57) 85.48,88.61 GPU1.B11 ; v1(73.74,144.21) 73.79,144.26 74.02,144.26 74.3,144.54 74.3,144.78 CPU1.F1 CPU1.F2 CPU1.F4 ; v1(137.96,66.55) 137.94,66.53 KBC1.78 ; Q1.4 78.44,223.76 78.09,224.11 78.09,224.71 77.74,225.06 Q1.1 ; CPU1.AM45 87.87,170.28 87.87,171.04 CPU1.AM46 ; DIMM1.205 132.22,139.28 132.49,139.55 132.95,139.55 133.38,139.11 v1(133.38,139.06) ; CPU1.AJ15 86.34,152.78 86.07,152.51 CPU1.AH13 ; v3(136.88,50.56) 137.3,50.14 137.33,50.14 137.47,50.01 137.47,49.97 137.54,49.9 KBC1.18 ; CPU1.L8 77.2,149.17 CPU1.J8 ; v1(54.9,60.2) 54.51,60.59 53.63,60.59 ; v1(68.99,73.41) 68.99,72.77 68.36,72.14 SCA1.33 ; CPU1.AR45 89.9,170.11 v1(89.55,169.77) 89.55,169.7 89.9,169.36 CPU1.AR43 ; SCA1.3 67.91,58.99 v3(67.6,58.67) ; CPU1.G6 75.36,148.61 75.36,148.87 CPU1.F8 75.06,149.31 v1(75.38,149.63) ; CPU1.AP32 CPU1.AN32 ; SCA1.13 67.85,62.99 v1(67.85,62.99) ; CPU1.AR11 89.9,150.87 v1(89.57,150.55) ; GPU1.B27 72.03,89.83 72.03,89.15 v1(72.03,89.15) 72.04,89.15 72.11,89.08 72.75,89.08 72.97,89.3 GPU1.A26 ; CPU1.AK63 87.63,180.76 CPU1.AL64 88.1,180.76 CPU1.AN63 ; v1(85.12,157.23) 85.12,157.1 85.51,156.72 CPU1.AG21 ; CPU1.AN63 CPU1.AP63 ; CPU1.AN63 87.95,179.61 CPU1.AM61 ; v1(92.64,179.72) CPU1.AW62 91.97,179.79 91.97,180.53 92.04,180.6 CPU1.AW64 ; KBC1.5 132.34,48.01 ; v1(54.9,58.29) 54.6,58.59 53.63,58.59 ; CPU1.G10 76.17,150.55 76.55,150.55 77,151 CPU1.J11 ; v1(133.89,66.55) 133.54,66.2 KBC1.89 ; v1(92.74,164.87) 92.62,164.99 CPU1.AW36 ; 92.02,166.29 92.02,167.45 CPU1.AW41 92.63,167.47 v1(92.76,167.59) ; GPU1.AF11 85.48,110.49 v1(84.67,111.3) ; GPU1.E8 88.35,92.11 v1(88.37,92.11) ; U17.15 132.95,39.06 v3(133,39.12) ; KBC1.116 128.18,55.5 v1(127.92,55.75) ; v1(87.96,111.32) GPU1.AF8 ; CPU1.K18 77.31,154.76 CPU1.L17 CPU1.L18 ; CPU1.AW18 CPU1.BA18 CPU1.BB18 ; 53.63,66.59 54.68,66.59 v1(54.9,66.8) ; CPU1.AR58 90.47,177.52 ; CPU1.AR50 89.53,172.59 v1(89.53,172.48) 89.53,172.4 CPU1.AR48 CPU1.AR46 ; U26.11 124.87,7.37 v1(124.75,7.24) ; v3(132.75,34.8) 132.55,34.6 U17.35 ; CPU1.BA2 93.68,144.98 93.76,144.91 93.76,144.78 CPU1.BA1 ; 92.02,171.87 92.02,171.18 CPU1.AW47 92.02,171.14 92.02,169.97 CPU1.AW45 92.02,169.93 92.02,168.69 CPU1.AW43
  TOP w0.254: R185.2 86.84,134.3 v1(87.54,135) ; CPU1.AW57 92.53,177.24 v1(92.68,177.39) 92.83,177.24 CPU1.BA57 ; v1(83.83,157.3) CPU1.AD21 ; CPU1.U67 80.71,182.71 v1(81.03,182.39) 80.71,182.06 CPU1.U66 ; v1(88.92,165.18) 88.6,165.5 CPU1.AN37 ; v1(88.92,165.18) 88.6,164.85 CPU1.AN35 ; v1(88.92,165.18) 88.92,165.04 CPU1.AP35 89.25,164.74 89.57,165.07 ; v1(134.65,177.42) 134.65,177.34 133.59,176.28 DIMM1.65 ; R500.2 41.18,21.59 v3(40.29,20.7) ; v1(85.94,154.46) 86.04,154.46 CPU1.AJ18 CPU1.AK18 ; v1(85.94,154.46) 85.63,154.76 CPU1.AG18 ; v1(85.94,154.46) 85.85,154.46 CPU1.AG17 ; DIMM2.69 147.31,175.28 147.7,174.88 148.16,174.88 148.58,175.3 v1(148.58,175.39) ; CPU1.F68 CPU1.D69 ; v3(74.33,140.72) 74.33,140.58 75.15,139.75 C58.2 ; DIMM2.176 153.1,146.53 v1(153.07,146.56) ; CPU1.U69 80.71,184.01 v1(81.03,184.34) 80.71,184.66 CPU1.U70 ; CPU1.N65 78.88,181.41 v1(79.2,181.09) ; CPU1.AW8 91.75,149.3 v1(91.75,149.5) ; v1(85.34,144.4) 85.14,144.6 CPU1.AF1 CPU1.AF2 ; CPU1.AW14 92.5,152.67 v1(92.58,152.75) 92.6,152.75 92.68,152.67 CPU1.BA14 ; CPU1.B71 71.41,186.06 v1(71.15,186.06) ; v1(137.32,134.37) 137.32,134.28 137.74,133.86 138.2,133.86 138.37,134.03 DIMM1.226 ; v1(85.46,150.37) 85.11,150.02 CPU1.AF10 ; CPU1.E71 74.1,185.66 v1(73.78,185.98) ; CPU1.AM46 87.93,171.12 CPU1.AL48 86.68,171.58 v1(86.68,171.57) ; DIMM2.40 153.71,182.53 153.43,182.25 152.94,182.25 152.52,182.67 v1(152.52,182.75) ; CPU1.BA1 93.85,144.52 v1(94.16,144.21) ; CPU1.G55 75.71,175.47 v1(75.47,175.23) ; CPU1.AM13 87.95,151.9 v1(87.55,151.5) ; 88.93,168.82 88.81,168.7 88.81,168.59 CPU1.AN42 ; 88.93,168.82 v1(88.93,168.83) ; 88.93,168.82 88.93,168.69 CPU1.AP42 ; CPU1.AL4 CPU1.AJ4 86.89,146.64 v1(86.63,146.89) 86.34,147.19 86.3,147.19 CPU1.AH6 ; CPU1.A70 71.15,185.38 v1(71.15,185.42) ; CPU1.Y17 82.34,154.11 CPU1.AB16 ; CPU1.AN32 88.27,162.57 v1(88.27,162.43) 88.27,162.43 CPU1.AL32 ; v1(70.9,183.26) 71.26,182.9 CPU1.A67 ; CPU1.AN30 88.6,161.84 v1(88.92,161.52) ; v1(85.6,180.42) 85.77,180.6 85.9,180.6 CPU1.AH64 ; v1(85.6,180.42) 85.91,180.11 CPU1.AH63 ; v1(85.6,180.42) 85.29,180.11 CPU1.AF63 ; DIMM1.61 132.13,177.28 132.49,176.91 132.96,176.91 133.38,177.34 v1(133.38,177.42) ; HDMI2.8 119.05,13.32 v3(119.29,13.08) ; CPU1.AW16 91.87,153.86 v1(91.52,154.2) 91.52,154.31 92.04,154.83 CPU1.AW18 ; CPU1.L2 CPU1.L4 ; v1(80.2,147.62) 80,147.41 CPU1.R6 79.67,146.81 CPU1.T4 CPU1.T2 ; CPU1.AN58 88.62,177.5 89.22,177.5 CPU1.AP58 ; CPU1.AN58 88.27,177.85 v1(88.27,177.98) 87.95,178.3 CPU1.AM60 ; CPU1.AN58 88.14,177.06 CPU1.AL58 ; CPU1.F40 75.31,167.72 75.31,168.12 CPU1.F42 ; DIMM2.185 147.52,144.28 147.65,144.15 148.07,144.15 148.5,144.57 v1(148.5,144.65) ; CPU1.AL52 86.72,173.41 v1(86.72,173.41) ; v1(91.55,175.26) 92.04,175.75 CPU1.AW55 91.92,176.15 91,176.15 CPU1.AT56 90.32,176.83 90.32,177.3 CPU1.AT58 90.47,177.52 ; v1(152.52,131.83) 152.52,131.91 152.94,132.33 153.4,132.33 153.71,132.03 DIMM2.234 ; v1(75.4,168.84) 75.4,168.99 CPU1.G43 75.72,169.29 CPU1.J42 ; CPU1.AK11 86.68,150.34 v1(86.54,150.34) 86.54,149.18 CPU1.AK8 ; DIMM1.48 139.4,180.52 138.51,180.52 138.2,180.21 137.74,180.21 137.32,180.64 v1(137.32,180.72) ; v1(78.17,88.88) 78.13,88.92 78.13,89.69 78.04,89.79 GPU1.B20 ; CPU1.AP68 89.8,182.57 v1(90.19,182.57) ; CPU1.U63 80.71,180.11 v1(81.03,180.44) 80.71,180.76 CPU1.U64 ; CPU1.B53 CPU1.D53 74.04,174.43 74.04,173.33 v1(74.04,173.33) 74.41,172.96 CPU1.E50 ; Q9.4 158.77,175.28 159.09,174.96 159.09,174.21 159.32,173.97 Q9.1 ; v1(137.32,131.83) 137.32,131.95 137.73,132.36 138.18,132.36 138.51,132.03 DIMM1.234 ; CPU1.AR8 89.58,149.5 89.58,149.63 v1(89.57,149.63) 89.25,149.96 CPU1.AP10 ; v1(88.92,167.01) 88.92,167.14 CPU1.AN40 ; v1(88.92,167.01) 88.92,166.95 88.6,166.63 CPU1.AN38 88.14,166.09 CPU1.AL38 ; v1(88.92,167.01) 89.25,166.68 CPU1.AP38 ; v1(78.14,149.03) 78.04,149.03 77.72,148.71 CPU1.L8 ; CPU1.K63 CPU1.K64 CPU1.K65 CPU1.K66 CPU1.K67 77.15,182.94 CPU1.K68 77.26,183.45 CPU1.K70 ; v1(92.14,143.72) 91.83,144.02 CPU1.AV1 ; CPU1.AW34 91.79,163.97 91.56,163.97 91.35,164.18 91.09,164.18 CPU1.AT35 90.52,164.74 89.92,164.74 CPU1.AR35 89.57,165.04 89.57,165.07 ; CPU1.B66 CPU1.D66 74.19,181.71 74.19,181.49 CPU1.E65 ; CPU1.AB21 CPU1.Y21 82.2,156.66 82.2,156.11 CPU1.Y20 82.24,155.98 82.24,155.5 CPU1.Y19 81.5,154.76 CPU1.V18 ; CPU1.AW6 92.67,147.87 v1(92.7,147.89) 92.7,147.87 92.74,147.83 CPU1.BA6 CPU1.BB6 ; CPU1.BA53 92.89,174.76 v1(92.73,174.6) ; CPU1.AW45 92.59,169.95 v3(92.6,169.94) ; CPU1.AM43 87.93,169.29 CPU1.AL45 87.49,169.75 CPU1.AM45 ; v1(94.22,186.19) 93.85,185.82 CPU1.BA71 ; CPU1.BA41 92.88,167.47 v1(92.76,167.59) ; CPU1.H71 75.9,185.66 v1(76.01,185.77) ; v1(148.5,147.45) 148.5,147.53 148.07,147.96 147.65,147.96 147.47,147.77 146.4,147.77 DIMM2.171 ; CPU1.BB60 94.03,178.58 95.08,178.58 v1(95.26,178.77) ; CPU1.BA10 v1(92.67,150.25) CPU1.AW10 91.88,150.09 CPU1.AU10 ; CPU1.AK68 86.71,183.36 CPU1.AH67 85.93,182.71 v1(85.6,182.39) ; CPU1.AB8 82.73,148.71 82.39,149.05 v1(82.35,149.05) ; v1(89.57,165.18) 89.57,165.07 ; v1(82.86,183.69) 82.54,183.36 CPU1.AA68 ; GPU1.AA7 88.85,105.85 88.85,106.61 GPU1.AB7 ; GPU1.H23 75.87,94.67 v1(75.92,94.67) ; DIMM1.40 139.4,182.52 138.48,182.52 138.2,182.25 137.74,182.25 137.32,182.67 v1(137.32,182.75) ; v3(64.3,155.93) 64.62,155.93 65.36,156.68 65.36,156.76 C30.2 ; v1(85.42,151.62) 85.72,151.62 CPU1.AH13 ; CPU1.W9 82.12,149.69 v1(82.37,149.69) ; CPU1.N10 78.92,150.33 79.1,150.33 v1(79.12,150.35) ; CPU1.AL64 87.86,180.78 87.86,180.78 87.92,180.84 87.92,181.34 CPU1.AL65 CPU1.AL66 88.06,182.27 CPU1.AM68 ; 75.08,163.35 CPU1.J32 ; CPU1.L18 78.15,154.76 CPU1.N19 78.61,155.41 CPU1.L20 ; DIMM2.189 147.42,143.28 147.65,143.51 148.12,143.51 148.5,143.13 v1(148.5,143) ; CPU1.D45 73.68,170.47 CPU1.D44 73.41,169.84 73.22,170.02 v1(73.16,170.02) 72.97,169.84 CPU1.B44 ; CPU1.AJ15 86.46,152.93 86.65,152.93 CPU1.AK16 ; v1(79.2,183.69) 78.88,183.36 CPU1.N68 ; CPU1.BA62 v1(92.64,179.72) ; v1(72.65,144.1) 72.65,144.31 CPU1.C1 ; CPU1.AP63 89.27,180.24 89.87,180.24 CPU1.AR63 89.92,180.24 90.52,180.24 CPU1.AT63 ; CPU1.AD16 84.15,153.78 v1(84.26,153.78) ; CPU1.B48 72.86,172.31 73.54,171.64 CPU1.D47 74.11,171.64 v1(74.18,171.58) ; CPU1.AV69 CPU1.AV70 CPU1.AV71 92.7,186.11 v1(92.7,186.23) ; CPU1.N6 78.88,147.41 v1(79.14,147.68) ; v1(86.68,175.25) 86.69,175.24 CPU1.AL55 87.93,175.69 CPU1.AM55 ; v1(82.35,151.6) 82.17,151.6 CPU1.W13 ; CPU1.J25 75.52,159.69 CPU1.F27 75.22,160.31 75.22,160.9 CPU1.F28 75.06,161.2 v1(75.38,161.52) 75.39,161.52 CPU1.J28 ; CPU1.G60 75.38,178.11 v1(75.38,177.98) 75.71,177.65 CPU1.G58 ; CPU1.AU20 91.9,156.28 CPU1.AW21 ; CPU1.L17 CPU1.L16 CPU1.K16 76.49,152.83 CPU1.H15 ; CPU1.D58 73.75,177.27 CPU1.E56 74.41,176.5 v1(74,176.09) ; CPU1.B14 CPU1.D14 ; CPU1.E11 74.41,151.06 74.76,151.41 74.76,151.62 CPU1.F13 ; CPU1.E11 74.09,150.69 CPU1.D11 73.64,150.05 CPU1.D10 CPU1.B10 ; CPU1.E11 74.87,150.55 75.25,150.55 CPU1.G10 76.17,149.63 v1(76.69,149.63) ; CPU1.AN23 88.62,158.34 89.22,158.34 CPU1.AP23 89.57,158 v1(89.57,157.86) 89.9,158.19 CPU1.AR23 CPU1.AT23 90.97,158.74 91.66,158.74 91.66,158.74 CPU1.AW26 ; CPU1.AM21 v1(87.63,156.98) CPU1.AK21 CPU1.AK22 ; v1(88.92,161.52) 89.25,161.19 CPU1.AP28 89.31,161.12 89.84,161.12 CPU1.AR28 CPU1.AT28 ; v1(88.92,161.52) 88.6,161.19 CPU1.AN28 ; v1(92.74,164.87) 92.88,164.87 93,164.99 CPU1.BA36 ; CPU1.B18 CPU1.D18 73.76,154.97 74.06,154.66 CPU1.E18 ; CPU1.AT20 90.52,155.6 89.92,155.6 CPU1.AR20 ; CPU1.AR16 89.61,154.04 89.61,154.18 v1(89.59,154.2) ; v1(85.93,156.39) 86.26,156.06 CPU1.AJ20 ; 71.16,179.46 70.08,179.46 v1(69.65,179.88) ; CPU1.F23 75.38,158 75.38,157.86 v1(75.38,157.86) ; CPU1.D26 73.64,159.88 CPU1.D25 CPU1.C25 ; CPU1.AU38 91.76,166.55 CPU1.AW38 ; v1(90.87,153.29) 90.88,153.29 90.88,153.15 CPU1.AU15 ; CPU1.AR5 90.44,146.8 CPU1.AT4 CPU1.AT2 ; CPU1.AE68 CPU1.AE67 ; v1(81.27,150.24) 81.05,150.02 CPU1.U10 ; CPU1.BA32 93.23,162.55 v1(92.67,162.55) 92.63,162.52 CPU1.AW32 91.57,162.52 CPU1.AU32 ; v1(74.3,107) 74.28,107.02 73.61,107.02 73.18,107.45 GPU1.AC26 ; CPU1.D62 CPU1.B62 ; CPU1.N13 78.9,151.66 v1(79.15,151.66) 79.37,151.66 CPU1.R13 ; CPU1.BA66 CPU1.AY66 92.56,182.09 CPU1.AW66 91.71,182.28 CPU1.AV68 ; DIMM1.73 131.92,174.27 131.93,174.27 133.62,174.27 134.65,175.3 v1(134.65,175.39) ; v1(80.89,156.38) 80.56,156.71 CPU1.T21 CPU1.P21 79.7,156.65 79.7,156.13 CPU1.P20 CPU1.P19 ; v1(75.45,171.58) 75.71,171.84 CPU1.G48 ; v1(84.46,148.93) 84.25,148.71 CPU1.AD8 ; CPU1.AR15 90.22,153.16 v1(90.22,153.29) ; v1(133.38,175.39) 133.38,175.3 132.96,174.88 132.5,174.88 132.11,175.28 DIMM1.69 ; CPU1.AR53 89.62,175.05 v1(89.62,175.23) 89.62,175.42 CPU1.AR55 ; CPU1.C5 73.59,147.56 CPU1.D6 ; CPU1.F8 74.41,148.52 CPU1.E6 ; CPU1.AG16 84.86,152.81 CPU1.AF15 ; v1(137.96,146.56) 137.99,146.53 DIMM1.176 ; CPU1.G63 76.18,179.78 v1(76.18,179.75) 76.24,179.75 CPU1.K61 ; DIMM2.48 153.68,180.53 153.37,180.21 152.94,180.21 152.52,180.64 v1(152.52,180.72) ; v1(136.69,137.41) 136.69,137.5 137.34,138.15 138.39,138.15 138.51,138.03 DIMM1.210 ; CPU1.AA2 CPU1.AA4 ; v1(86.45,160.29) 86.87,160.29 CPU1.AK27 87.47,160.6 CPU1.AL28 87.93,160.15 CPU1.AM27 ; v3(77,165.18) CPU1.J35 ; CPU1.D22 CPU1.B22
  TOP w0.305: CPU1.F42 75.06,168.49 v1(75.4,168.84) ; v1(137.96,173.1) 138.03,173.03 DIMM1.78 ; CPU1.J13 CPU1.J11 77.35,150.67 CPU1.L11 ; DIMM2.172 152.64,147.53 151.8,146.69 v1(151.8,146.56) ; C233.2 136.71,31.2 136.16,31.75 v3(135.8,31.75) ; DIMM2.231 148.9,132.78 149.85,133.73 v1(149.85,134.37) ; DIMM2.68 153.17,175.53 v1(153.03,175.39) ; v3(112.3,223.14) 112.19,223.25 NGFF1.75 ; DIMM2.209 148.48,138.28 149.22,137.53 149.22,137.2 v1(149.26,137.16) ; v1(147.86,145.29) 147.85,145.28 DIMM2.181 ; CPU1.AE69 84.1,184.01 v1(83.78,183.69) 84.1,183.36 CPU1.AE68 ; DIMM2.235 147.9,131.78 v1(147.95,131.83) ; NGFF1.69 112.29,221.75 v3(112.3,221.74) ; v1(132.75,146.69) 132.66,146.77 131.2,146.77 DIMM1.175 ; v1(84.26,153.78) 84.34,153.78 CPU1.AF17 ; v1(147.99,137.16) 147.87,137.28 DIMM2.213 ; VRAM2.H13 58.41,86.74 v1(58.64,86.51) ; NGFF1.36 116.63,213.5 v3(116.62,213.49) ; CPU1.AB18 83.45,155.22 83.64,155.22 CPU1.AD19 ; DIMM2.31 147.41,184.78 147.45,184.73 148.78,184.73 149.85,185.81 v1(149.85,185.93) ; DIMM1.19 132.17,187.78 132.52,187.43 132.97,187.43 133.38,187.84 v1(133.38,187.96) ; DIMM2.65 147.26,176.28 147.31,176.23 148.78,176.23 149.85,177.3 v1(149.85,177.42) ; DIMM1.193 132.66,142.28 v1(132.75,142.37) ; GPU1.B5 90.45,89.19 v1(91.61,88.02) ; GPU1.AB20 78.03,106.66 v1(77.63,107.06) ; DIMM1.107 130.09,165.78 129.01,164.7 ; v3(45.12,225.43) 45.12,224.73 C3.2 ; NGFF1.23 112.24,210.25 v3(112.3,210.19) ; DIMM1.93 129.94,169.27 129.57,168.91 v3(129.57,168.4) 130.2,167.78 DIMM1.99 ; DIMM2.56 152.74,178.53 151.76,177.54 v1(151.76,177.42) ; v1(94.18,95.5) 93.86,95.19 93.32,95.19 93.17,95.04 GPU1.H2 ; v1(147.86,189.99) 147.58,190.28 DIMM2.9 ; CPU1.AR53 89.9,174.63 v1(90.23,174.29) 89.9,173.96 CPU1.AR52 ; DIMM1.185 133.12,144.28 134.02,145.17 v1(134.02,145.29) ; DIMM1.89 132.46,170.27 v1(132.75,170.56) 132.75,170.65 132.12,171.27 DIMM1.85 ; DIMM1.15 134.45,188.78 135.03,189.36 v1(135.03,189.99) ; v1(137.96,184.53) 138.45,185.03 DIMM1.30 ; v1(148.58,187.96) 148.58,187.84 148.17,187.43 147.72,187.43 147.37,187.78 DIMM2.19 ; VRAM2.C14 62.24,85.52 v1(62.39,85.37) ; HDMI4.20 119.08,9.32 v5(119.29,9.53) ; DIMM2.103 145.09,166.78 144.65,167.22 144.65,167.78 ; DIMM2.64 152.78,176.53 151.76,175.51 v1(151.76,175.39) ; DIMM1.94 138.35,169.03 v3(137.83,169.54) 138.31,170.03 DIMM1.90 ; v1(153.16,129.67) 153.3,129.53 DIMM2.244 ; CPU1.D22 74.12,157.01 74.12,156.78 CPU1.E21 74.73,156.82 v1(74.73,156.95) 74.73,157.08 CPU1.F22 ; v1(132.75,173.1) 132.57,173.27 DIMM1.77 ; DIMM2.193 148.52,142.28 149.13,142.88 v1(149.13,143) ; 144.65,167.78 DIMM2.99 ; 144.65,167.78 144.65,167.82 143.29,169.18 v3(143.29,169.67) ; DIMM1.214 138.34,137.03 v1(137.96,137.41) ; DIMM1.197 136,141.28 v1(136.05,141.22) ; DIMM2.248 153.41,128.53 v1(153.16,128.27) ; XDP1.31 27.33,213.24 v3(27.72,212.85) ; DIMM2.188 153.51,143.53 153.38,143.66 151.98,143.66 v1(151.34,143.03) ; PU14.19 116.38,72.4 v3(116.11,72.14) ; v1(90.19,182.57) 90.51,182.89 CPU1.AT68 ; v3(112.3,218.82) 112.23,218.75 NGFF1.57 ; CPU1.E53 74.38,174.78 74.04,174.43 ; v3(119.29,18.16) 118.91,18.16 118.56,17.82 HDMI2.17 HDMI4.3 ; PU8.6 27.97,161.93 28.23,161.67 v3(28.48,161.67) ; v1(149.85,187.96) 149.85,187.84 148.78,186.77 147.45,186.77 147.44,186.78 DIMM2.23 ; v1(151.25,139.57) 151.25,139.69 151.66,140.11 153.38,140.11 153.46,140.03 DIMM2.202 ; DIMM2.86 152.72,171.03 v1(152.7,171.05) ; U14.24 161.55,45.49 v3(161.7,45.34) ; R147.2 v3(68.11,140.46) ; GPU1.E14 83.4,92.9 83.4,92.91 v1(83.42,92.93) ; DIMM1.184 137.33,144.53 136.69,145.17 v1(136.69,145.29) ; v1(63.94,97.16) 63.94,96.62 VRAM2.A1 ; v3(140.81,167.42) 140.41,167.03 DIMM1.102 ; v3(140.81,167.42) 140.81,166.34 140.5,166.03 DIMM1.106 ; v3(140.81,167.42) 140.81,167.58 140.36,168.03 DIMM1.98 ; v1(133.38,185.93) 133.38,185.81 132.97,185.39 132.53,185.39 132.15,185.78 DIMM1.27 ; DIMM1.103 130.11,166.78 129.01,165.68 129.01,164.7 ; C67.2 81.25,137.92 v1(82.33,137.92) ; v1(137.96,192.02) 137.96,192.03 DIMM1.2 ; v1(149.85,139.57) 149.85,139.69 149.27,140.28 DIMM2.201 ; v1(137.96,139.06) 137.99,139.03 DIMM1.206 ; DIMM1.251 131.2,127.78 132.12,127.78 132.39,127.51 133.38,127.51 134.02,128.15 v1(134.02,128.27) ; v1(83.4,151.64) 83.72,151.97 CPU1.AD13 84.67,152.7 CPU1.AF15 ; v1(136.69,146.56) 136.69,146.8 137.41,147.53 DIMM1.172 ; XDP1.25 25.83,213.63 25.56,213.36 24.93,213.36 v3(24.42,212.85) 24.33,212.93 XDP1.19 ; XDP1.8 21.33,222.6 v3(21.5,222.76) ; DIMM2.14 155.94,189.03 v1(155.99,188.98) ; v3(120.18,75.44) 120.17,75.43 PU14.4 ; GPU1.H5 90.51,95.04 v1(90.9,95.43) ; DIMM1.201 133.7,140.28 134.65,139.32 v1(134.65,139.06) ; CPU1.AE65 84.18,181.36 84.18,180.81 CPU1.AE64 83.78,180.31 CPU1.AD62 83.78,179.05 v1(83.83,178.99) ; v1(88.91,163.37) 88.6,163.69 CPU1.AN33 88.14,164.26 CPU1.AL35 ; HDMI2.5 118.52,11.82 118.91,11.43 v5(119.29,11.43) ; DIMM1.218 140.76,136.03 v1(140.88,136.14) ; v1(72.93,111.89) 73.09,111.73 73.09,111.33 73.1,111.31 GPU1.AG26 ; v1(153.16,189.99) 153.19,190.03 DIMM2.10 ; U14.17 158.05,45.49 v3(157.89,45.34) ; DIMM2.230 152.33,133.03 151.25,131.95 v1(151.25,131.83) ; GPU1.Y5 90.5,104.89 v1(90.85,104.54) ; R16.2 40.29,224.85 v3(40.29,225.43) ; v1(136.69,192.02) 136.69,191.9 137.56,191.03 DIMM1.6 ; v1(134.65,185.93) 134.65,185.81 133.58,184.73 131.95,184.73 131.91,184.78 DIMM1.31 ; v1(136.05,173.1) 136.05,173.86 136.71,174.52 139.4,174.52 DIMM1.72 ; v1(136.69,185.93) 136.69,186.05 137.66,187.03 DIMM1.22 ; XDP1.2 19.83,222.64 19.74,222.73 v3(19.74,222.76) ; CPU1.AG19 85.4,155.52 85.4,155.96 CPU1.AG20 85.83,156.39 v1(85.93,156.39) 85.61,156.71 CPU1.AG21 ; CPU1.AB8 82.33,148.18 82.33,147.94 CPU1.W6 81.8,147.33 CPU1.AA4 82.87,147.02 83.03,147.02 83.04,147.03 83.76,147.03 83.77,147.02 84.1,147.02 84.11,147.03 84.75,147.03 CPU1.AF4 ; XDP1.13 22.83,213.43 22.44,213.03 v3(22.04,213.03) 21.52,213.03 21.33,213.22 XDP1.7 ; v1(137.96,128.27) 138.21,128.53 DIMM1.248 ; DIMM1.238 136.9,131.03 136.41,130.53 136.41,130.2 136.05,129.84 v1(136.05,129.67) 135.94,129.78 DIMM1.243 ; GPU1.Y23 75.5,104.98 v1(75.08,105.39) ; VRAM2.N14 54.14,86.01 v1(54.14,85.47) ; CPU1.BA45 93.24,169.94 93.21,169.94 v3(92.6,169.94) ; v3(114.84,203.71) 114.84,204.47 113.06,206.25 NGFF1.7 ; v1(153.07,144.65) 153.2,144.53 DIMM2.184 ; DIMM1.39 132.73,182.78 v1(132.75,182.75) ; CPU1.E46 74.41,171.34 v1(74.18,171.58) ; v1(153.16,185.93) 153.25,186.03 DIMM2.26 ; CPU1.AD16 CPU1.AB16 CPU1.AB15 ; v1(134.02,131.83) 134.02,131.71 133.09,130.78 DIMM1.239 ; v1(151.32,133.76) 151.49,133.76 151.56,133.83 153.38,133.83 153.57,134.03 DIMM2.226 ; DIMM1.235 132.7,131.78 v1(132.75,131.83) ; CPU1.H18 76.36,154.6 76.46,154.5 76.46,154.49 76.55,154.41 76.55,154.12 77.12,153.54 CPU1.K16 ; v3(157.39,176.28) 157.45,176.22 157.45,175.8 Q9.4 ; CPU1.G10 75.71,149.96 v1(75.38,149.63) ; DIMM2.168 156.05,148.53 156.32,148.26 156.32,146.38 v3(156.29,146.35) ; GPU1.AC8 87.99,107.5 88.36,107.13 v1(88.36,107.13) ; v1(152.52,139.57) 152.52,139.45 152.95,139.03 DIMM2.206 ; v3(116.62,211.96) 116.66,212 NGFF1.30 ; CPU1.AW18 91.68,155.09 CPU1.AU20 91.14,155.58 91.09,155.63 90.6,155.63 CPU1.AT20 ; v1(153.16,184.53) 153.65,185.03 DIMM2.30 ; DIMM2.85 147.78,171.27 v3(147.99,171.07) 147.99,170.66 147.61,170.27 DIMM2.89 ; DIMM2.43 148.28,181.78 149.22,180.84 v1(149.22,180.72) ; U14.9 156.47,50.65 v3(156.24,50.42) 156.52,50.14 U14.10 ; v1(134.02,192.02) 134.02,191.52 133.7,191.19 132.37,191.19 132.29,191.28 DIMM1.5 ; v1(132.75,128.27) 132.24,128.78 DIMM1.247 ; DIMM1.26 138.05,186.03 v1(137.96,185.93) ; v1(89.59,154.2) 89.59,154.32 CPU1.AP18 89.06,154.85 89.06,155.35 89.25,155.53 CPU1.AP20 89.2,155.52 88.65,155.52 CPU1.AN20 ; VRAM2.C4 62.25,94.11 v1(62.64,93.72) ; XDP1.50 31.83,222.23 31.66,222.4 v3(31.66,222.88) ; DIMM2.197 151.11,141.28 v1(151.16,141.22) ; v1(149.89,135.89) 149.89,135.25 149.54,134.9 147.73,134.9 147.6,134.78 DIMM2.223 ; v1(137.83,177.42) 137.93,177.52 139.4,177.52 DIMM1.60 ; v3(31.53,23.24) 31.52,23.25 PWRCN1.4 ; v1(137.96,145.29) 138.19,145.53 DIMM1.180 ; v1(50.88,103.5) 50.88,104.04 VRAM1.A1 ; DIMM2.72 153.48,174.53 v1(153.07,174.12) ; CPU1.F40 75.52,167.01 CPU1.J38 ; v1(134.02,137.41) 134.02,137.53 133.28,138.28 DIMM1.209 ; v1(151.89,128.27) 151.89,127.83 152.2,127.51 153.5,127.51 153.51,127.53 DIMM2.252 ; v1(153.07,192.02) 153.07,192.03 DIMM2.2 ; v3(152.31,135.64) 152.81,136.14 153.3,136.14 153.42,136.03 DIMM2.218 ; DIMM2.81 148.51,172.27 149.22,172.98 v1(149.22,173.1) ; v1(151.25,180.72) 151.25,180.6 152.33,179.52 152.33,179.53 DIMM2.52 ; DIMM1.23 132.24,186.78 132.25,186.77 133.58,186.77 134.65,187.84 v1(134.65,187.96) ; GPU1.Y2 93.7,104.96 v1(94.27,104.39) ; DIMM1.82 137.78,172.03 137.32,171.57 v1(137.32,171.45) ; v1(145.45,71.25) 145.45,70.99 146.11,70.34 U12.5 ; DIMM1.18 137.64,188.03 136.69,188.98 v1(136.69,189.99) ; GPU1.U5 90.5,102.41 v1(90.85,102.06) ; v1(80.93,109.5) 80.53,109.9 GPU1.AF17 ; v1(134.02,182.75) 134.02,182.87 133.12,183.78 DIMM1.35 ; XDP1.26 v3(25.83,222.76) ; v1(83.4,107.06) GPU1.AB14 ; DIMM1.14 138.16,189.03 137.96,189.23 v1(137.96,189.99) 137.99,190.03 DIMM1.10 ; DIMM1.227 132.91,133.78 133.38,134.25 v1(133.38,134.37) ; v1(150.4,179.83) 150.4,179.32 149.35,178.28 DIMM2.57 ; DIMM2.239 148.29,130.78 ; 148.29,130.78 149.22,131.71 v1(149.22,131.83) ; 148.29,130.78 148.29,130.03 148.03,129.78 DIMM2.243 ; GPU1.AD16 81.33,108.3 v1(80.93,108.7) 80.53,109.1 GPU1.AE17 ; v1(136.05,134.37) 136.05,134.49 136.59,135.03 DIMM1.222 ; v1(152.51,134.42) 152.51,134.53 153.01,135.03 DIMM2.222 ; DIMM2.1 147.61,192.28 v1(147.86,192.02) ; v1(149.13,192.02) 149.13,191.9 148.49,191.26 147.55,191.26 147.53,191.28 DIMM2.5 ; LVDS1.14 41.2,96.5 v3(41.18,96.52) ; R98.2 160.43,180.59 161.08,179.95 U2.4 ; DIMM2.27 147.35,185.78 147.73,185.39 148.17,185.39 148.58,185.81 v1(148.58,185.93) ; GPU1.AC22 76.79,107.89 v1(76.79,107.9) 76.79,107.91 GPU1.AD22 ; XDP1.38 28.83,222.66 v3(28.74,222.76) ; U14.8 157.34,51.49 v3(157.26,51.56) ; v1(93.73,102.41) 93.66,102.48 GPU1.U2 ; DIMM2.247 147.44,128.78 v1(147.95,128.27) ; DIMM2.60 154.6,177.52 153.13,177.52 v1(153.03,177.42) ; DIMM2.251 147.32,127.78 147.59,127.51 148.58,127.51 149.22,128.15 v1(149.22,128.27) ; HDMI3.3 115.22,40.82 v3(114.38,41.66) ; DIMM1.1 132.5,192.28 v1(132.75,192.02) ; DIMM1.56 139.4,178.52 137.54,178.52 136.56,177.54 v1(136.56,177.42) ; v1(153.16,141.22) 153.46,141.52 DIMM2.196 ; DIMM2.94 v3(156.01,169.03) ; v1(135.42,179.45) 135.42,178.82 134.87,178.28 DIMM1.57 ; v1(132.75,145.29) 132.74,145.28 DIMM1.181 ; DIMM1.167 132.12,148.78 132.22,148.87 134.25,148.87 134.65,148.46 v1(134.65,148.34) 134.84,148.53 DIMM1.168 ; v1(147.95,173.1) 147.77,173.27 DIMM2.77 ; CPU1.AL2 CPU1.AL4 ; v1(136.05,171.45) 136.05,171.33 136.46,170.92 138.18,170.92 138.28,171.03 DIMM1.86 ; v3(112.3,211.71) 112.26,211.75 NGFF1.29 ; LVDS1.7 41.19,103.5 v3(41.18,103.5) ; DIMM2.82 153.23,172.03 152.94,172.31 v1(152.94,172.42) ; DIMM2.175 146.4,146.77 149.04,146.77 149.77,146.05 v1(149.77,145.29) ; v1(151.8,137.16) 151.8,137.29 152.54,138.03 DIMM2.210 ; DIMM2.73 147.41,174.27 147.44,174.24 148.83,174.24 149.85,175.27 v1(149.85,175.39) ; v1(60.36,85.34) 60.36,85.83 VRAM2.E14 ; DIMM2.214 153.23,137.03 153.09,137.16 v1(153.07,137.16) ; DIMM1.188 138.31,143.53 138.18,143.66 136.46,143.66 136.05,143.25 v1(136.05,143.13) ; v1(134.02,173.1) 134.02,172.38 133.89,172.25 132.07,172.25 132.05,172.27 DIMM1.81 ; v1(137.83,175.39) 137.97,175.52 139.4,175.52 DIMM1.68 ; CPU1.A5 71.45,146.72 v1(71.15,146.72) ; GPU1.Y26 73.04,104.9 71.88,104.9 71.87,104.9 v1(71.41,104.9) ; v1(136.69,139.06) 136.69,139.18 137.53,140.03 DIMM1.202 ; XDP1.32 27.33,222.75 v3(27.34,222.76) ; DIMM2.180 152.55,145.53 151.8,144.77 v1(151.8,144.65) ; v1(75.95,102.87) 75.56,102.48 GPU1.U23 ; DIMM2.51 147.93,179.78 v1(147.99,179.83) ; DIMM2.90 v3(156.01,170.03) ; GPU1.U26 73.03,102.41 71.71,102.41 v1(71.66,102.36) ; DIMM1.244 138.1,129.53 v1(137.96,129.67) ; NGFF1.63 112.27,220.25 v3(112.3,220.22) ; v5(119.29,10.44) 119.17,10.32 HDMI2.2 ; DIMM1.47 132.69,180.78 v1(132.75,180.72) ; NGFF1.18 117.17,209 116.62,209.55 v3(116.62,210.44) 116.68,210.5 NGFF1.24 ; v1(151.89,189.99) 151.89,189.05 152.91,188.03 DIMM2.18 ; XDP1.59 v3(34.33,217.18) ; Q5.4 17.61,180.96 Q7.S ; XDP1.37 28.83,213.51 29.2,213.15 v3(31.66,213.15) 31.66,213.16 31.83,213.33 XDP1.49 ; v1(147.95,180.72) 147.89,180.78 DIMM2.47 ; v1(151.25,129.67) 151.25,130.39 151.89,131.03 DIMM2.238 ; v1(137.32,143.13) 137.32,143.01 137.8,142.52 DIMM1.192 ; v1(136.56,175.39) 136.66,175.49 136.66,175.61 137.58,176.52 139.4,176.52 DIMM1.64 ; v1(137.96,141.22) 138.26,141.52 DIMM1.196 ; CPU1.P21 79.49,156.86 78.95,156.86 CPU1.N21 ; v1(152.52,143.13) 152.52,143.01 153,142.52 DIMM2.192 ; XDP1.14 v3(22.83,222.76) ; C254.2 123.67,18.81 122.89,18.03 v3(122.84,18.03) ; XDP1.20 v3(24.33,222.76) ; v1(134.02,180.72) 134.02,181.33 133.57,181.78 DIMM1.43 ; v1(76.69,149.63) 77.01,149.31 CPU1.J8 ; DIMM1.44 139.4,181.52 137.16,181.52 136.05,182.63 v1(136.05,182.75) ; U14.21 160.05,45.59 v3(159.8,45.34) 159.55,45.59 U14.20 ; DIMM1.51 132.42,179.78 v1(132.75,179.45) ; v1(135.42,184.53) 136.54,183.41 138.21,183.41 138.33,183.52 139.4,183.52 DIMM1.36 ; v1(136.05,131.83) 136.05,131.95 137.13,133.03 DIMM1.230 ; v1(148.58,134.37) 148.58,134.25 148.11,133.78 DIMM2.227 ; GPU1.AD12 84.63,108.3 v1(84.23,108.7) 83.84,108.3 GPU1.AD13 ; DIMM2.6 152.68,191.03 151.8,191.9 v1(151.8,192.02) ; NGFF1.45 112.28,215.75 v3(112.3,215.77) ; CPU1.D69 74.03,184 v1(74.15,184.12) ; C27.2 63.91,158.43 v3(63.91,158.12) 62.89,159.14 X1.4 ; v1(77.25,71.12) 75.61,72.76 Q34.1 ; HDMI3.20 v3(115.35,32.32) ; v3(112.3,212.72) 112.28,212.75 NGFF1.33 ; v3(144.05,163.38) 144.05,164.47 145.36,165.78 DIMM2.107 ; v1(136.05,180.72) 136.05,180.6 137.13,179.52 139.4,179.52 DIMM1.52 ; v1(82.86,181.74) 82.54,181.41 CPU1.AA65 ; v3(148.75,171.07) 148.75,170.43 147.59,169.27 DIMM2.93 ; v1(151.89,185.93) 151.89,186.05 152.86,187.03 DIMM2.22 ; v1(133.38,148.34) 133.38,148.22 132.94,147.77 131.2,147.77 DIMM1.171 ; v1(148.58,139.57) 148.58,139.45 148.17,139.04 147.74,139.04 147.68,139.11 147.66,139.11 147.49,139.28 DIMM2.205 ; v3(115.35,37.82) HDMI3.9 ; v1(147.95,182.75) 147.93,182.78 DIMM2.39 ; HDMI1.8 v3(115.35,36.32) ; DIMM1.9 132.46,190.28 v1(132.75,189.99) ; DIMM2.15 148.93,188.78 149.77,189.61 v1(149.77,189.99) ; CPU1.E18 74.08,154.33 74.08,154.05 73.96,153.93 73.96,153.56 74.08,153.45 74.08,153.22 74.41,152.89 CPU1.E15 74.07,152.49 CPU1.D14 ; DIMM2.35 148.32,183.78 149.22,182.87 v1(149.22,182.75) ; DIMM1.217 132.62,136.28 v1(132.75,136.14) ; GPU1.AE11 GPU1.AF11 ; DIMM2.98 v3(156.01,168.03) ; v1(149.77,147.45) 149.77,147.57 148.73,148.61 147.59,148.61 147.42,148.78 DIMM2.167 ; v1(134.65,134.37) 134.65,133.73 133.7,132.78 DIMM1.231 ; v1(148.58,177.42) 148.58,177.3 148.17,176.89 147.72,176.89 147.33,177.28 DIMM2.61 ; 129.01,164.7 v3(129.01,164.41) ; HDMI1.5 HDMI3.15 115.62,34.82 115.35,34.54 v3(115.35,33.15) 115.52,33.32 HDMI1.2 ; v1(147.99,135.89) 147.6,136.28 DIMM2.217 ; CPU1.D47 73.64,172.27 CPU1.D48 ; v1(136.69,128.27) 136.69,128.02 137.33,127.38 138.33,127.38 138.48,127.53 DIMM1.252 ; DIMM1.223 132.4,134.78 132.53,134.9 134.68,134.9 135.16,135.38 v1(135.16,136.14) ; DIMM2.106 v3(156.01,166.03) ; DIMM1.189 133.59,143.28 134.02,142.85 v1(134.02,142.37) ; DIMM2.78 v3(156.01,173.03) ; GPU1.AB24 v1(74.3,107) ; DIMM2.102 v3(156.01,167.03) ; NGFF1.39 112.3,214.25 v3(112.3,214.25) ; DIMM2.36 153.68,183.53 153.53,183.38 151.68,183.38 151.16,183.9 v1(151.16,184.53) ; CPU1.AE67 84.23,182.65 84.18,182.6 84.18,182.18 84.23,182.13 CPU1.AE66 ; DIMM2.44 152.36,181.53 152.36,181.52 151.25,182.63 v1(151.25,182.75)
  TOP w0.33: VRAM1.A3 50.98,105.74 50.58,106.14 v1(50.55,106.14) ; VRAM2.A3 63.85,94.91 64.25,94.52 v1(64.27,94.52) ; v1(61.02,115.08) 61.02,114.97 VRAM1.N14
  TOP w0.356: v1(55.05,89.88) 55.05,89.84 55.04,89.83 VRAM2.M10 ; VRAM1.B10 51.79,111.36 v1(52.18,111.75) ; VRAM1.E12 v1(54.59,112.54) ; v1(51.44,88.13) 51.44,88.11 VRAM2.U12 ; 58.24,95.71 58.24,96.51 VRAM2.H1 ; 58.24,95.71 VRAM2.H2 ; 58.24,95.71 v1(57.84,95.31) ; VRAM1.M10 60.19,110.93 v1(60.21,110.93) ; 52.19,106.15 52.19,106.14 VRAM1.C3 ; 52.19,106.15 52.58,106.54 VRAM1.C4 ; 52.19,106.15 v1(52.19,106.16) ; v1(58.64,86.51) 58.24,86.12 VRAM2.H14 ; VRAM1.R11 62.17,112.14 v1(61.78,112.53) 62.18,112.94 VRAM1.R12 ; GPU1.AB17 80.17,107.01 80.17,107.04 v1(80.13,107.08) ; v1(60.21,89.75) 60.21,89.74 59.84,89.37 VRAM2.F10 ; VRAM2.A12 63.89,87.71 v1(64.27,88.09) ; v1(54.64,88.11) 54.24,87.71 VRAM2.N12 ; v1(56.23,96.11) 56.63,95.71 VRAM2.K2 ; VRAM2.F5 59.84,93.31 v1(60.24,93.71) ; VRAM1.P10 61.39,111.3 v1(61.78,110.91) ; Q12.1 14.88,157.34 v3(14.64,157.1) ; GPU1.AB11 85.48,106.65 v1(85.08,106.25) ; GPU1.B23 75.25,89.8 v1(75.25,89.31) ; VRAM1.E1 v1(54.19,103.55) ; v1(75.93,97.14) 75.55,97.52 GPU1.L23 ; 57.78,114.14 58.18,113.74 VRAM1.K13 ; 57.78,114.14 v1(57.77,114.14) ; 57.78,114.14 57.78,114.14 58.19,114.54 VRAM1.K14 ; v1(62.43,97.13) 62.43,97.12 62.26,96.95 62.26,96.54 VRAM2.C1 ; v1(50.6,94.54) 50.98,94.91 VRAM2.U3 ; v1(60.98,106.14) 60.59,105.74 VRAM1.N3 ; VRAM1.F10 54.99,111.33 v1(54.59,110.94) ; v1(63.45,92.89) 63.04,93.3 VRAM2.B5 ; 82.98,109.9 v1(82.57,109.5) 82.97,109.1 ; 82.98,109.9 GPU1.AF14 ; 82.98,109.9 82.97,109.9 v1(82.57,110.3) ; 82.97,109.1 82.17,108.3 GPU1.AD15 ; 82.97,109.1 GPU1.AE14 ; VRAM1.E14 54.19,115.06 v1(54.23,115.1) ; v1(72.55,99.95) 72.6,100 GPU1.P26 ; v1(60.13,103.58) 60.21,103.66 60.21,103.76 VRAM1.N1 ; v1(63.39,112.52) 63.79,112.92 63.79,112.94 ; v1(51.47,89.72) 51.47,89.68 VRAM2.T10 ; VRAM1.G5 55.79,107.38 55.74,107.42 v1(55.74,108.08) ; v1(53.04,89.74) 53.44,89.35 VRAM2.P10 ; v1(73.5,94.64) 73.9,95.04 GPU1.H25 ; VRAM2.R11 53.03,88.12 v1(53.04,88.12) 52.64,87.71 VRAM2.R12 ; GPU1.E20 78.11,92.5 v1(78.47,92.13) ; v1(75.92,99.63) 75.55,100 GPU1.P23 ; VRAM2.R1 v1(52.64,97.08) ; VRAM2.U14 51.04,86.11 v1(50.58,85.65) ; GPU1.AF5 90.5,109.9 v1(90.86,110.26) ; v1(76.78,92.95) 76.71,92.88 76.71,92.81 GPU1.E22 ; VRAM1.H2 v1(56.19,104.54) 56.59,104.14 VRAM1.H1 ; VRAM2.T5 51.84,93.33 v1(52.23,93.72) ; v1(88.36,107.13) 88.36,107.13 88.8,106.69 GPU1.AB7 ; VRAM1.E3 54.19,105.74 v1(54.59,106.14) ; v1(52.61,85.47) 52.64,85.5 VRAM2.R14 ; GPU1.E5 90.43,92.55 v1(90.03,92.15) ; v1(62.59,106.16) 62.19,105.75 VRAM1.R3 ; VRAM2.E1 60.64,97.08 v1(60.61,97.1) ; VRAM2.G10 59.04,89.38 v1(59.43,89.77) ; VRAM2.R3 52.64,94.89 v1(52.24,94.49) 52.27,94.49 52.64,94.13 VRAM2.R4 ; Q12.4 16.18,161.05 v3(16.29,161.16) ; VRAM1.R1 62.39,103.94 v1(62.39,103.58) ; v1(73.48,92.14) 73.51,92.14 73.9,92.53 GPU1.E25 ; v1(55.76,89.87) 55.76,89.39 VRAM2.L10 ; v1(50.55,112.56) 50.93,112.94 VRAM1.A12 ; VRAM2.B10 63.04,89.29 v1(62.65,88.9) ; v1(62.77,115.08) 62.75,115.08 62.21,114.54 VRAM1.R14 ; VRAM1.L10 59.37,110.95 v1(59.37,110.93) ; v1(72.3,74.42) 72.66,74.06 Q34.4 ; v1(62.57,106.95) 62.57,106.92 VRAM1.R4 ; v1(80.93,90.46) 80.89,90.46 80.53,90.1 GPU1.B17 ; GPU1.L25 73.9,97.48 v1(73.53,97.11) ; GPU1.AF23 75.55,112.57 v1(74.84,113.28) ; v1(50.55,114.95) 50.58,114.95 VRAM1.A14 ; v1(63.91,85.34) 63.84,85.42 VRAM2.A14 ; VRAM2.K14 56.64,86.12 v1(57.04,86.51) 56.64,86.91 VRAM2.K13 ; v1(59.42,92.87) 59.42,92.89 59.04,93.28 VRAM2.G5 ; GPU1.B14 83,90 v1(83.34,89.66) ; v1(93.73,107.46) 93.71,107.45 GPU1.AC2 ; VRAM1.L5 58.99,107.47 v1(59.38,107.87) 59.79,107.46 VRAM1.M5 ; VRAM1.F5 54.98,107.34 v1(54.59,106.94) ; GPU1.AF1 93.7,110.41 v1(93.55,110.56) 93.41,110.7 GPU1.AG2 ; GPU1.AF20 GPU1.AE20 78.05,109.1 v1(78.46,108.69) 78.85,108.3 GPU1.AD19 GPU1.AD18 ; v1(87.92,89.41) 87.96,89.45 GPU1.B8 ; v1(90.84,107.06) 90.45,107.45 GPU1.AC5 ; v1(54.64,96.9) 54.63,96.9 VRAM2.N1 ; 63.79,114.54 63.79,114.55 64.17,114.93 v1(64.17,115.04) ; GPU1.E2 93.12,92.33 v1(93.76,92.33) ; v1(63.35,110.93) 63.35,110.97 VRAM1.T10 ; VRAM1.G10 55.79,111.32 v1(55.38,110.91) ; VRAM2.N3 v1(54.64,94.51) ; VRAM2.C13 VRAM2.C12 62.24,87.74 v1(62.63,88.13) 62.6,88.13 62.24,88.5 VRAM2.C11 ; VRAM1.C13 VRAM1.C14 52.52,114.6 52.52,115.01 v1(52.33,115.21) ; VRAM2.L5 v1(55.84,92.77) ; VRAM1.B5 51.79,107.35 v1(51.38,107.76) ; v1(80.88,92.91) 80.88,92.86 GPU1.E17 ; GPU1.AD21 77.19,108.3 v1(76.79,107.9) ; VRAM1.C1 52.59,103.9 52.43,103.74 v1(52.43,103.53) ; VRAM1.C11 52.59,112.16 52.22,112.52 v1(52.19,112.52) 52.59,112.92 VRAM1.C12 ; v1(62.64,94.49) 62.24,94.89 VRAM2.C3 ; GPU1.E11 85.53,92.5 85.89,92.86 v1(85.89,92.86) ; v1(64.3,103.63) 63.79,104.14 ; v1(63.38,107.73) VRAM1.T5 ; VRAM1.K2 58.2,104.94 v1(58.58,104.56) 58.58,104.53 VRAM1.K1 ; VRAM1.H14 56.58,114.54 v1(56.18,114.14) 56.58,113.74 VRAM1.H13 ; VRAM2.E12 v1(60.24,88.11) ; VRAM2.M5 55.04,92.98 54.9,92.84 v1(54.9,92.71) ; VRAM1.N12 60.58,112.94 v1(60.18,112.54) ; VRAM2.U1 v1(51.04,97.08) ; v1(64.8,106.11) 64.14,106.11 63.79,105.76 63.79,105.74 ; v1(56.45,97.18) 56.64,97 VRAM2.K1 ; VRAM2.E3 60.64,94.91 v1(60.24,94.51)
  TOP w0.381: C51.2 87.98,141.8 87.54,142.24 v1(87.28,142.24) ; v1(132.88,46.81) 132.8,46.81 132.37,47.24 C195.2 131.92,47.59 132.34,48.01 ; Q1.1 75.77,225.06 C633.2 ; CPU1.E6 73.71,147.56 CPU1.D6 ; U3.5 48.22,139.94 v3(47.85,139.57) ; PR47.1 24.73,145.99 25.18,145.54 v3(25.18,145.41) ; v3(69.45,133.6) 68.88,133.03 R191.2 ; GPU1.L2 93.09,97.71 v1(93.48,97.71) ; v1(90.08,97.08) 90.5,97.5 GPU1.L5 ; U1.3 65.76,189.47 v3(66.58,188.65) ; R424.2 v3(73.31,52.01) ; D14.8 v3(106.71,10.29) ; GPU1.P5 90.86,100.36 90.86,100.38 v1(90.89,100.41) ; GPU1.P2 93.28,100.38 v1(93.28,100.41) ; GPU1.B1 93.83,90.1 v3(94.39,89.53) ; v3(149.39,118.49) 149.39,119.32 C78.2 ; Q13.4 21.7,144.45 v3(21.37,144.78) ; D13.3 v3(106.59,20.07) ; Q10.4 162.7,172.89 163.08,172.52 163.61,172.52 164.23,171.89 PC59.2 ; D13.8 v3(106.59,23.11) ; D14.3 v3(106.71,13.34)
  TOP w0.406: v3(121.95,41.02) 122.08,40.89 U15.8 U15.3 ; PQ5.1 89.17,38.15 R455.2 ; Q21.1 75.29,117.09 74.72,117.67 v1(74.46,117.67) ; v3(84.62,218.82) 84.25,218.82 84.11,218.68 Q3.4 ; C5.2 80.3,220.22 80.54,219.98 Q3.1 ; v3(121.95,37.34) 121.97,37.36 U16.3 U16.8 ; Q1.1 76.94,228.46 v5(77.34,228.86) ; v3(164.46,177.85) 164.46,178.17 163.98,178.65 U2.1 ; 37.29,138.03 U4.5 ; U18.3 U18.8 v3(121.95,33.78) ; Q33.4 53.32,76.76 v3(53.12,76.96) ; PQ5.4 91.17,41.33 v3(91.47,41.02) ; v1(93.38,88.9) 93.3,88.9 GPU1.A2 ; Q45.1 v3(33.48,6.49) ; Q21.4 76.73,115.55 v1(76.23,115.06) ; v3(169.68,96.14) U9.3 U9.8 ; v3(55.28,74.17) 55.2,74.24 Q33.1 ; v3(99.09,112.14) 99.09,112.46 99.35,112.71 U7.3 ; v3(17.23,175.13) 17.61,175.51 Q8.4 ; v3(31.36,9.31) 31.61,9.07 Q45.4 ; U6.8 U6.3 v3(169.58,115.19)
  TOP w0.457: 97.34,163.93 98.81,163.93
  TOP w0.508: C39.2 68.49,148.91 v1(68.49,149.61) ; C54.2 57.01,140.59 C56.2 56.75,139.36 C59.2 56.8,139.31 56.8,138.68 C64.2 56.42,137.92 55.66,137.16 v3(54.01,137.16) ; 53.95,20.06 DCIN1.5 ; DCIN1.5 52.39,21.16 ; DCIN1.5 55.51,21.16 ; 7.08,170.63 ODD1.8 ; ODD1.8 8.4,171.95 ; ODD1.8 8.4,169.31 ; ODD1.8 9.72,170.63 ; 10.68,135.63 HDD1.8 ; HDD1.8 13.32,135.63 ; HDD1.8 12,134.31 ; v3(111.92,23.24) 112.3,23.62 R493.2 ; 148.12,10.67 148.12,11.68 PC134.2 ; X3.2 89.44,82.43 v3(89.57,82.3) R283.2 R284.2 ; PR74.2 122.84,76.07 124.11,74.8 v3(124.11,74.17) ; v3(14.38,180.47) 14.77,180.47 15.24,180.94 Q7.S ; v1(85.5,86.36) 85.44,86.3 C107.2 85.48,85.44 X3.4 ; 57.53,190.25 PT7.2 ; PT7.2 58.58,191.3 ; PT7.2 58.58,189.19 ; Q43.S 143.14,31.13 v3(142.02,31.13) ; R61.1 17.34,207.04 17.56,207.04 v3(18.09,206.5) ; C168.2 C167.2 C171.2 C172.2 125.47,61.2 126.3,62.03 v1(126.3,62.06) 126.3,62.26 126.33,62.29 R368.2 C164.2 ; v3(136.76,41.4) 136.57,41.59 C211.2 C210.2 ; TOUCH1.2 v3(27.11,9.5) ; PR118.2 157.6,18.8 v3(156.75,18.8) ; PQ2.S 34.67,45.47 v3(34.07,45.47) ; v3(76.74,30.73) 76.3,30.29 C238.2 74.65,30.29 C239.2 ; D10.1 v3(115.92,25.97) R485.2 ; v3(127.19,31.17) 127.81,30.54 C237.2 128.43,30.54 128.87,30.99 C235.2 ; Q42.3 85.06,40.83 v5(85.25,40.64) ; v3(82.33,30.86) 82.9,30.86 C234.1 ; PC80.2 PC79.2 39.02,134.37 39.53,133.86 v3(39.53,133.1) ; WEBCM1.8 155.75,199.28 156.12,199.64 v3(156.88,199.64) ; v3(109.13,15.24) 108.94,15.05 R513.1 R512.1 ; HDMI3.23 121.28,33.78 v3(121.95,33.78) ; v3(91.47,133.48) 91.41,133.41 C70.2 ; R276.2 98.52,87.95 v1(98.71,88.14) 99.28,87.57 C106.1 ; PQ6.E 91.2,34.4 v3(90.58,33.78) ; v3(85,67.06) 84.74,67.31 C153.1 ; Q16.S 48.64,121.76 v3(49.12,122.24) ; DCIN1.6 50.97,24.18 ; DCIN1.6 49.88,22.62 ; DCIN1.6 48.78,24.18 ; DCIN1.6 49.88,25.74 ; R526.2 v3(29.5,4.76) ; v3(135.29,95.25) 135.42,95.12 C103.2 ; v3(30.13,10.29) 30.32,10.48 C266.2 ; v3(118.14,43.05) 118.69,43.6 HDMI3.21 ; PC78.2 55.72,141.41 v3(55.66,141.35) ; SRCON1.4 U8.4 148.5,98.81 148.75,99.06 v3(148.75,99.69) ; v3(109.76,107.57) 110.13,107.2 PU11.1 ; 53.95,28.81 DCIN1.7 ; DCIN1.7 52.39,29.9 ; DCIN1.7 53.95,31 ; PC113.2 v3(117.38,68.55) ; v3(143.04,113.54) 143.04,114.43 143.35,114.74 Q22.E ; v3(159.04,88.01) 159.42,88.39 R277.1 160.82,88.39 161.07,88.14 D4.A ; v3(102.9,145.67) 102.78,145.8 102.78,146.18 102.08,146.88 C45.2 C42.2 C37.2 101.76,149.16 C36.1 C35.2 ; X2.2 100.51,131.53 R193.1 ; R266.2 99.86,95.25 v3(100.24,95.63) 99.6,96.27 PR69.2 ; HDD1.9 12,149.69 ; HDD1.9 10.68,148.37 ; HDD1.9 13.32,148.37 ; HDD1.9 12,147.05 ; C120.2 61.63,79.88 v3(61.88,79.63) 62.11,79.86 Q32.S ; C120.2 62.33,81.85 C118.2 ; C120.2 61.37,80.9 C124.1 ; C214.2 v3(138.21,39.62) ; R455.2 88.3,37.97 v3(88.17,37.85) ; C233.2 137.41,30.61 R468.1 ; v3(28.99,18.54) 28.98,18.55 PWRCN1.12 ; v5(94.9,11.18) 94.78,11.3 R516.2 C271.2 ; v3(119.67,69) PC110.2 PC111.2 ; C198.2 C199.2 v3(136.05,44.07) ; PT6.2 67.34,199.43 ; PT6.2 66.29,198.37 ; PT6.2 68.4,198.37 ; PC92.2 126.65,99.69 v3(126.78,99.57) ; v5(137.45,9.3) 137.57,9.42 137.57,12.32 ; SSUSB1.11 176.12,124.31 ; SSUSB1.11 176.12,122.17 ; SSUSB1.11 174.25,123.24 ; SSUSB1.11 177.99,123.24 ; PC67.2 157.45,168.59 v3(157.39,168.66) ; C5.2 79.98,219.52 v3(80.17,219.33) ; R74.2 75.31,189.55 PC37.2 ; R74.2 73.82,189.74 v3(73.19,190.37) 73.12,190.31 R71.2 71.57,190.31 70.8,189.55 R72.2 ; R74.2 R73.2 ; v3(156.12,18.29) 155.48,18.92 PR119.2 ; PR115.2 159.23,24.83 158.78,24.38 v3(158.15,24.38) ; v3(14.64,157.1) 14.7,157.04 R132.2 ; R261.2 137.51,100.27 v3(138.21,99.57) ; PT15.2 107.26,94.11 ; PT15.2 105.15,94.11 ; PT15.2 106.21,95.16 ; v3(164.42,176.53) 165.01,176.53 165.39,176.15 PR31.1 ; v3(151.8,52.2) 152.24,51.75 R427.1 ; v3(34.58,53.85) 35.15,53.85 PR90.2 ; 98.81,163.93 99.73,163.02 v1(99.73,162.6) ; v3(33.78,203.73) 33.43,203.38 PC19.2 ; SPK1.5 158.05,28.29 158.4,27.94 160.18,27.94 161.6,29.36 SPK1.8 v3(162.97,32.38) ; PR82.2 v3(123.25,72.01) ; C68.2 84.55,137.6 v1(84.74,137.79) R168.2 R173.1 ; PT8.2 52.74,188.89 ; PT8.2 53.79,187.83 ; PT8.2 51.68,187.83 ; v3(158.39,71.36) 158.39,71.36 158.15,71.12 C148.1 ; v3(162.97,34.29) 162.53,34.73 C227.2 ; v3(73.31,52.01) 73.31,53.02 R393.2 ; U25.2 v3(89.57,7.87) 89.57,9.84 C272.2 ; v3(141.54,38.33) 141.64,38.23 LED1.K ; 56.62,22.62 DCIN1.4 ; DCIN1.4 55.53,24.18 ; DCIN1.4 57.72,24.18 ; X4.2 71.47,51.75 v3(72.3,52.58) ; C256.2 49.5,18.22 v3(48.93,17.65) ; v3(42.07,145.29) 42.71,145.29 C48.2 ; TC4.2 89.57,19.6 ; TC4.2 89.57,17.49 ; TC4.2 88.51,18.54 ; 7.27,173.19 ODD1.1 ; ODD1.1 9.03,173.19 ; ODD1.1 8.15,172.31 ; R310.2 79.54,79.36 R318.2 78.71,78.68 v3(78.65,78.74) 78.65,77.47 79.28,76.83 C130.1 ; v3(158.15,80.14) 158.02,80.26 R307.1 ; R253.2 47.16,107.76 v3(46.97,107.95) 45.75,106.73 R255.2 ; Q46.E 44.42,6.03 44.93,5.52 C280.2 45.25,5.41 v3(44.59,4.76) ; R358.1 137.7,70.36 v1(137.45,70.61) ; C231.2 v5(71.66,33.02) ; 176.12,87.87 SSUSB2.10 ; SSUSB2.10 174.25,88.94 ; SSUSB2.10 177.99,88.94 ; SSUSB2.10 176.12,90.01 ; 171.1,131.4 MEMCD1.12 171.1,129.58 ; v3(81.19,115.44) 81.25,115.38 R241.2 ; R491.1 R490.1 R489.1 R488.1 104.87,24.83 104.3,24.26 v3(104.3,23.11) ; R75.2 78.2,189.67 v3(77.76,190.12) ; v3(36.74,47.75) 37.05,47.75 PC119.2 ; v3(51.98,139.32) 52.04,139.38 C57.2 C66.2 ; C117.2 R299.2 ; C117.2 56.29,80.55 Q31.S 55.25,80.49 v3(55.15,80.39) ; C117.2 R300.2 R301.2 ; v3(166.02,45.21) 165.97,45.26 C197.2 ; v3(151.8,58.67) 151.66,58.53 R389.2 ; C184.2 67.03,53.75 R403.2 68.13,54.74 v3(68.46,54.41) 68.76,54.11 X4.4 ; v3(164.12,50.42) 164.88,50.42 C192.2 ; R430.2 106.27,49.66 106.49,49.43 Q40.S 105.63,48.83 v3(105.57,48.9) ; PC128.2 157.64,23.11 v3(158.15,23.62) ; C190.2 122.11,49.91 v3(121.47,50.55) ; C246.2 34.27,24.5 v3(34.53,24.5) 36.08,22.96 Q44.S ; v3(166.4,89.92) 166.05,89.56 R278.1 ; v3(113.83,62.74) 113.83,62.42 R379.1 ; v1(102.01,170.56) 102.14,170.43 R119.2 ; v3(23.66,151) 23.46,150.81 PC76.2 ; v3(166.15,50.67) 165.58,51.24 C185.1 ; v1(149.64,54.74) 149.13,54.74 149,54.86 C182.2 ; 37.29,138.03 Q14.S 36.07,137.89 v3(35.97,137.79) ; SSUSB1.10 176.12,111.51 ; SSUSB1.10 176.12,109.37 ; SSUSB1.10 177.99,110.44 ; DCIN1.2 53.25,24.12 ; DCIN1.2 51.69,23.03 ; DCIN1.2 54.81,23.03 ; HS6.1 147.86,214 ; HS6.1 140.64,214 ; HS6.1 144.25,217.61 ; HS6.1 144.25,210.39 ; 183,131.4 MEMCD1.14 183,129.58 ; D8.2 v3(106.46,34.8) ; D3.2 v3(169.48,105.92) ; v3(70.26,79.5) 70.26,78.68 C127.2 ; PC36.2 23.36,190.06 22.91,190.5 v3(22.64,190.5) ; v3(47.02,105.08) 47.44,105.5 47.44,105.51 C93.2 ; PR75.2 v3(125.06,74.17) ; C95.2 102.59,98.68 C97.2 101.56,98.6 C96.2 98.79,98.6 v3(98.71,98.68) 98.27,98.68 R263.2 ; PR28.2 v3(35.47,186.31) ; C250.2 121.24,22.87 v1(121.24,22.73) 120.94,22.73 119.42,21.22 HDMI4.21 ; v3(32.7,14.58) 33.37,13.91 C262.2 ; 177.58,79.89 UHS1.MS2 ; UHS1.MS2 179,78.87 ; UHS1.MS2 179,80.91 ; UHS1.MS2 180.42,79.89 ; v1(168.26,141.99) 168.26,142.04 168.07,142.22 MEMCD1.3 ; v3(43.34,10.54) 43.09,10.29 C275.2 ; U24.2 v3(45.19,11.94) ; R364.2 143.48,68.07 v1(144.05,68.07) ; PC129.2 148.12,21.27 v3(148.12,22.1) 148.12,23.24 PC127.2 ; v3(47.79,4.7) 47.79,5.3 Q47.E ; v5(120.94,30.48) 120.18,30.48 119.61,29.92 HDMI3.22 ; ODD1.9 9.72,183.37 ; ODD1.9 8.4,182.05 ; ODD1.9 7.08,183.37 ; ODD1.9 8.4,184.69 ; ODD1.7 8.15,181.69 ; ODD1.7 9.03,180.81 ; ODD1.7 7.27,180.81 ; R270.2 v3(98.71,91.19) 98.01,91.19 R271.2 ; C105.2 C102.2 47.54,95.85 47.12,96.27 v1(47.12,96.6) ; R451.2 128.62,40.45 v3(128.94,40.13) C213.2 C212.2 ; v3(152.18,41.66) 152.43,41.4 C206.2 ; Q6.E 163.89,182.63 v3(164.12,182.63) ; R366.1 159.55,65.15 v3(158.78,65.15) C157.2 ; v3(28.84,25.15) 28.84,25.3 27.68,26.45 PWRCN1.11 ; v3(39.4,45.72) 39.59,45.53 PR93.1 ; Q4.S 17.42,188.07 v3(18.58,189.23) ; PR113.2 155.39,28.09 v3(155.3,28.09) ; SPK1.7 150,30.84 v3(149.77,30.61) ; R500.2 41.88,22.61 C251.2 C252.2 ; C2.2 30.98,224.62 v3(31.78,225.43) ; v3(74.01,49.33) 74.12,49.21 R432.2 ; v3(151.54,35.56) 151.8,35.31 C224.2 ; v3(121.95,37.34) 120.93,37.34 HDMI3.24 ; 171.1,160 MEMCD1.13 171.1,158.17 ; CONVT1.12 25,31.93 v3(24.8,32.13) ; C136.2 155.1,74.04 v3(154.97,73.91) 154.85,73.79 154.08,73.79 C140.2 153.89,73.6 C139.2 ; PC86.2 87.16,124.05 PC84.2 85.48,128.3 v1(86.6,129.41) ; C80.2 46.83,117.79 v1(47.02,117.6) ; v3(65.06,191.64) 65.57,192.15 C16.2 ; C69.2 79.98,133.85 v3(80.75,134.62) ; v3(166.15,42.04) 165.51,41.4 C209.2 ; R246.1 98.5,112.55 98.51,112.55 98.92,112.14 v3(99.09,112.14) ; R112.2 v3(40.93,173.1) ; v3(104.3,15.24) 104.49,15.05 R510.1 R511.1 ; v3(68.74,76.89) R330.1 R331.1 ; v3(100.87,193.35) R66.1 ; C159.2 157.59,65.53 v3(156.62,65.53) ; R254.2 v3(108.62,112.52) ; R478.2 69.76,25.91 69.38,25.53 68.23,25.53 67.66,26.1 v3(67.66,26.67) ; v3(158.91,73.15) 158.59,72.83 C138.2 157.32,72.14 C141.2 ; v3(87.03,80.64) 87.28,80.39 88.43,80.39 ; PR1.1 v3(54.01,217.3) ; C108.2 v3(89.06,85.47) ; v3(156.88,82.93) 156.88,82.23 R306.2 ; C63.2 69.38,138.62 v3(69.38,139.57) ; C194.2 154.47,46.1 v3(153.83,45.47) 152.81,46.48 C193.2 ; SSUSB2.11 176.12,102.81 ; SSUSB2.11 176.12,100.67 ; SSUSB2.11 177.99,101.74 ; v1(72.93,111.89) 72.52,112.29 72.52,114.54 R243.2 ; v3(122.84,18.03) 122.78,17.97 HDMI4.25 ; v1(168.56,150.5) 167.79,149.72 MEMCD1.6 ; v1(78.01,142.29) 78.2,142.1 C55.2 ; U5.2 163.23,122.43 163.61,122.81 163.61,124.21 v3(164.24,124.84) C74.2 ; v1(63.91,85.34) 65.31,83.95 C114.2 C121.2 ; v3(156.73,67.16) 156.31,67.58 C155.1 ; v3(80.3,67.44) 80.49,67.63 Q37.S ; v3(33.26,10.14) 33.12,10.29 C267.2 ; v3(46.97,114.05) 47.47,114.05 C85.2 ; R98.2 C18.2 159.57,182.08 159.57,182.85 v3(159.16,183.26) ; 103.79,156.97 105.62,156.97 v1(108.92,153.67) ; C65.2 49.51,136.75 v3(49.79,136.75) ; PC91.2 118.91,101.14 v3(118.52,100.76) ; PR40.2 v3(23.66,152.91) ; v3(127.41,19.18) 128.11,19.88 C253.2 ; R401.1 v3(154.08,55.63) ; PC74.2 v3(22.18,162.18) ; v3(97.7,118.82) 97.7,120.08 PR55.2 95.16,121.86 94.71,122.3 PU10.1 ; R374.1 35.97,62.55 R370.1 34.01,62.55 v3(33.94,62.61) ; 10.87,145.81 HDD1.7 ; HDD1.7 12.63,145.81 ; HDD1.7 11.75,146.69 ; C43.2 98.84,146.02 98.59,145.76 v3(98.59,145.29) ; 183,158.17 MEMCD1.15 183,160 ; PC87.2 87.73,119.57 v3(87.54,119.76) ; WEBCM1.6 158.25,199.54 v3(158.15,199.64) ; C200.2 132.18,46.04 C196.2 131.99,47.18 C195.2 ; v3(121.95,41.02) 120.72,41.02 HDMI3.25 ; v3(153.83,76.33) 153.13,76.33 C134.2 152.88,76.33 152.66,76.55 Q30.E ; C87.2 C88.2 46.83,108.85 v3(46.97,108.71) ; R43.1 v3(105.57,218.44) ; C241.2 v3(103.79,28.83) ; C129.1 v3(154.85,77.09) ; C226.2 157.92,35.31 v3(157.72,35.1) 157.51,35.31 C225.2 ; v3(63.69,132.87) 63.69,132.46 64.13,132.02 R187.2 ; C208.2 158.66,41.4 v3(158.4,41.66) 158.15,41.4 C207.2 ; R190.2 R191.2 ; v3(94.65,82.3) R288.2 ; ODD1.4 6.98,177 ; PR60.2 v3(107.73,108.84) ; R113.2 v3(63.53,175.26) ; PC59.2 164.23,171.06 v3(164.12,170.94) 163.84,170.94 162.5,169.61 Q11.S 160.97,168.59 PC68.2 ; v3(68.49,50.76) 68.41,50.84 C186.2 ; v3(80.93,29.34) 80.42,28.83 U20.2 ; R465.2 v5(71.66,34.29) ; HDD1.4 10.43,142 ; v3(154.85,202.18) 153.76,201.1 WEBCM1.10 ; v3(23.66,151.89) PR41.2 ; R458.2 144.56,36.83 v3(144.43,36.96) ; v3(41.89,12.24) 41.89,11.39 C265.2 R517.2 R519.1 ; Q23.S v3(147.58,113.54) ; U21.3 v3(111.03,26.29) ; v3(20.23,225.93) 19.85,225.55 C1.2 ; v1(71.53,69.6) 71.92,69.22 R356.2 ; PC90.2 PC89.2 119.24,104.78 119.75,104.27 v3(119.92,104.27) 120.18,104.27 120.68,104.78 PR63.2 ; v3(91.98,130.63) 91.97,130.62 C71.2 90.46,130.49 PC81.1 ; R260.1 v3(98.71,100.33) ; v3(52.61,42.29) 52.61,42.58 PQ3.S ; v3(66.64,179.89) 67.47,179.89 R99.2 ; C255.2 C258.2 C260.2 v3(43.98,14.61) ; C236.2 30.13,31.5 v3(29.75,31.88) ; CONVT1.10 27.45,32.15 27.08,32.51 v3(26.58,32.51) ; v3(91.35,113.28) 91.35,113.67 92.68,115 R240.1 R242.1 C84.2 ; R336.2 v3(89.7,75.06)
  L3 w0.508: 9.03,177 ODD1.4 7.27,177 ; 7.27,173.19 ODD1.1 ; ODD1.1 8.15,172.31 ; ODD1.1 9.03,173.19 ; 12.63,142 HDD1.4 10.87,142 ; ODD1.9 9.72,183.37 ; ODD1.9 7.08,183.37 ; ODD1.9 8.4,184.69 ; ODD1.9 8.4,182.05 ; DCIN1.6 49.88,25.74 ; DCIN1.6 49.88,22.62 ; DCIN1.6 50.97,24.18 ; DCIN1.6 48.78,24.18 ; HDD1.8 12,136.95 ; HDD1.8 13.32,135.63 ; HDD1.8 12,134.31 ; HDD1.8 10.68,135.63 ; ODD1.7 9.03,180.81 ; ODD1.7 8.15,181.69 ; ODD1.7 7.27,180.81 ; HDD1.1 12.63,138.19 ; HDD1.1 11.75,137.31 ; HDD1.1 10.87,138.19 ; SSUSB1.10 177.99,110.44 ; SSUSB1.10 176.12,109.37 ; SSUSB1.10 174.25,110.44 ; SSUSB1.10 176.12,111.51 ; HDD1.9 12,149.69 ; HDD1.9 13.32,148.37 ; HDD1.9 12,147.05 ; HDD1.9 10.68,148.37 ; HDD1.7 11.75,146.69 ; HDD1.7 10.87,145.81 ; HDD1.7 12.63,145.81 ; 52.39,21.16 DCIN1.5 55.51,21.16 ; SSUSB2.10 176.12,90.01 ; SSUSB2.10 177.99,88.94 ; SSUSB2.10 174.25,88.94 ; SSUSB2.10 176.12,87.87 ; SSUSB2.11 176.12,102.81 ; SSUSB2.11 176.12,100.67 ; SSUSB2.11 177.99,101.74 ; SSUSB2.11 174.25,101.74 ; 181.68,130.49 MEMCD1.14 ; MEMCD1.14 183,131.4 ; MEMCD1.14 183,129.58 ; H5.1 96.95,76.25 ; H5.1 91.82,76.25 ; H5.1 94.39,73.68 ; H5.1 94.39,78.82 ; 180.42,79.89 UHS1.MS2 179,78.87 ; 51.69,23.03 DCIN1.2 ; DCIN1.2 53.25,24.12 ; DCIN1.2 54.81,23.03 ; 66.43,123.75 H4.1 ; H4.1 71.57,123.75 ; H4.1 69,121.18 ; SSUSB1.11 177.99,123.24 ; SSUSB1.11 176.12,124.31 ; SSUSB1.11 176.12,122.17 ; ODD1.8 9.72,170.63 ; ODD1.8 8.4,171.95 ; ODD1.8 8.4,169.31 ; ODD1.8 7.08,170.63 ; 56.62,22.62 DCIN1.4 ; DCIN1.4 57.72,24.18 ; DCIN1.4 55.53,24.18
  L4 w0.508: 10.68,148.37 HDD1.9 ; HDD1.9 12,147.05 ; HDD1.9 12,149.69 ; HDD1.9 13.32,148.37 ; 162.12,222.29 H6.7 161.33,223.08 ; 10.87,142 HDD1.4 12.63,142 ; SSUSB2.10 176.12,90.01 ; SSUSB2.10 176.12,87.87 ; SSUSB2.10 177.99,88.94 ; SSUSB2.10 174.25,88.94 ; 8.4,169.31 ODD1.8 ; ODD1.8 9.72,170.63 ; ODD1.8 8.4,171.95 ; ODD1.8 7.08,170.63 ; 162.55,228.14 H6.5 ; H6.5 164.12,228.14 ; H6.5 163.34,228.92 ; 7.27,173.19 ODD1.1 ; ODD1.1 9.03,173.19 ; ODD1.1 8.15,172.31 ; H5.1 96.95,76.25 ; H5.1 91.82,76.25 ; H5.1 94.39,73.68 ; H5.1 94.39,78.82 ; UHS1.MS2 180.42,79.89 ; UHS1.MS2 179,80.91 ; UHS1.MS2 179,78.87 ; 7.08,183.37 ODD1.9 ; ODD1.9 8.4,182.05 ; ODD1.9 8.4,184.69 ; 176.12,109.37 SSUSB1.10 ; SSUSB1.10 174.25,110.44 ; SSUSB1.10 177.99,110.44 ; SSUSB1.10 176.12,111.51 ; 165.88,221.86 H6.1 ; H6.1 166.66,221.08 ; H6.1 167.45,221.86 ; 162.12,227.71 H6.6 161.33,226.92 ; 181.68,130.49 MEMCD1.14 ; MEMCD1.14 183,131.4 ; MEMCD1.14 183,129.58 ; 10.87,145.81 HDD1.7 ; HDD1.7 11.75,146.69 ; HDD1.7 12.63,145.81 ; H6.4 166.66,228.92 ; H6.4 165.88,228.14 ; H6.4 167.45,228.14 ; 9.03,177 ODD1.4 7.27,177 ; HDD1.1 12.63,138.19 ; HDD1.1 10.87,138.19 ; HDD1.1 11.75,137.31 ; 167.88,227.71 H6.3 168.67,226.92 ; 167.88,222.29 H6.2 168.67,223.08 ; 162.55,221.86 H6.8 ; H6.8 164.12,221.86 ; H6.8 163.34,221.08 ; ODD1.7 8.15,181.69 ; ODD1.7 7.27,180.81 ; ODD1.7 9.03,180.81 ; HDD1.8 13.32,135.63 ; HDD1.8 12,136.95 ; HDD1.8 10.68,135.63 ; HDD1.8 12,134.31 ; 176.12,100.67 SSUSB2.11 ; SSUSB2.11 174.25,101.74 ; SSUSB2.11 176.12,102.81 ; SSUSB2.11 177.99,101.74 ; 176.12,122.17 SSUSB1.11 177.99,123.24
  BOTTOM w0.203: v1(61.12,89.79) 61.44,89.47 VRAM2.D10 ; v3(74.96,66.8) 74.96,66.42 74.28,65.74 PQ9.4 ; PU20.14 85.65,212.2 v3(85.76,212.09) ; v3(85,208.91) 85.25,209.17 PU20.3 ; v3(86.39,208.91) 86.05,209.26 PU20.1 ; v1(53.76,110.85) 53.39,111.23 VRAM1.D10
  BOTTOM w0.254: Q58.1 53.7,74.91 54.21,74.41 55.04,74.41 v3(55.28,74.17) ; v1(51.34,65.1) 50.93,65.51 50.93,65.82 50.28,66.48 50.28,70.87 51.37,71.96 v1(51.63,71.96) ; C634.2 79.14,145.85 v1(79.14,147.68) ; R647.1 151.89,127.89 v1(151.89,128.27) ; v1(89.57,165.18) 90.15,165.18 90.58,165.61 ; R548.2 71.96,182.71 71.41,183.26 v1(70.9,183.26) ; C380.2 168.69,150.62 v1(168.56,150.5) ; R577.2 88.47,154.4 88.47,154.4 88.76,154.68 89.16,154.68 89.59,154.25 v1(89.59,154.2)
  BOTTOM w0.305: U34.16 127.26,51.66 v3(127.41,51.82) ; v1(129.04,46.77) 128.98,46.84 128.86,46.84 128.82,46.88 U34.23 ; Q71.4 157.62,42.56 158.4,41.78 v3(158.4,41.66) ; v1(62.39,85.37) 62.24,85.52 VRAM2.C14 ; v3(166.15,42.04) 166.13,42.05 Q72.1 ; D25.2 107.13,128.14 v3(107.6,127.67) 107.6,126.3 C416.2 R651.2 ; PQ8.1 26.34,66.66 26.07,66.93 24.93,66.93 ; v1(57.77,114.14) 58.05,114.42 58.07,114.42 VRAM1.K14 ; v1(62.64,93.72) 62.25,94.11 VRAM2.C4 ; C333.2 90.9,165.93 90.58,165.61 ; U30.22 130.04,99.32 130.42,99.69 v3(130.84,99.69) ; v3(121.47,50.55) 121.6,50.55 121.74,50.68 U34.9 ; VRAM2.N14 54.14,86.01 v1(54.14,85.47) ; VRAM2.H13 58.45,86.7 58.45,86.7 v1(58.64,86.51) ; v3(39.4,45.72) 39.58,45.72 39.59,45.71 PU34.14 ; U34.32 122.96,45.58 122.59,45.21 v3(122.59,44.58) ; U36.20 37.23,28.81 37.5,29.08 v3(37.5,29.72) ; v1(56.45,97.18) 56.45,96.7 VRAM2.K1
  BOTTOM w0.356: v1(54.59,106.94) 54.98,107.34 VRAM1.F5 ; 63.79,105.74 64.16,106.11 v1(64.8,106.11) ; v1(63.91,85.34) 63.84,85.42 VRAM2.A14 ; VRAM1.C14 52.59,114.95 v1(52.33,115.21) ; v1(59.37,110.93) 59.37,110.95 VRAM1.L10 ; v1(64.17,115.04) 64.17,114.93 63.79,114.55 63.79,114.54 ; VRAM1.G10 55.79,111.32 v1(55.38,110.91) ; VRAM2.B5 63.04,93.3 v1(63.45,92.89) ; VRAM2.K14 56.64,86.12 v1(57.04,86.51) 56.64,86.91 VRAM2.K13 ; v1(50.55,114.95) 50.58,114.95 VRAM1.A14 ; v1(54.9,92.71) 54.9,92.84 55.04,92.98 VRAM2.M5 ; v1(63.35,110.93) 63.35,110.97 VRAM1.T10 ; U38.1 128.66,14.56 C604.2 ; VRAM1.A1 50.88,104.04 v1(50.88,103.5) ; v1(54.59,110.94) 54.99,111.33 VRAM1.F10 ; VRAM1.N1 60.21,103.76 60.21,103.66 v1(60.13,103.58) ; 58.24,95.71 58.24,96.51 VRAM2.H1 ; 58.24,95.71 VRAM2.H2 ; 58.24,95.71 v1(57.84,95.31) ; VRAM2.A1 63.84,97.05 v1(63.94,97.16) ; VRAM1.N12 60.58,112.94 v1(60.18,112.54) ; VRAM2.E3 60.64,94.91 v1(60.24,94.51) ; VRAM2.B10 63.04,89.29 v1(62.65,88.9) ; v1(52.61,85.47) 52.64,85.5 VRAM2.R14 ; v1(55.74,108.08) 55.74,107.42 55.79,107.38 VRAM1.G5 ; 63.79,112.94 63.79,112.92 v1(63.39,112.52) ; v1(62.57,106.95) 62.57,106.92 VRAM1.R4 ; VRAM2.C11 62.6,88.15 62.61,88.15 v1(62.63,88.13) 62.61,88.13 62.24,87.76 VRAM2.C12 ; VRAM1.C12 52.59,112.9 52.21,112.52 v1(52.19,112.52) 52.21,112.5 52.23,112.5 VRAM1.C11 ; v1(62.39,103.58) 62.39,103.94 VRAM1.R1 ; VRAM1.A3 50.98,105.74 50.58,106.14 v1(50.55,106.14) ; v1(50.58,85.65) 51.04,86.11 VRAM2.U14 ; v1(63.38,107.73) VRAM1.T5 ; VRAM1.E1 v1(54.19,103.55) ; v1(62.77,115.08) 62.75,115.08 62.21,114.54 VRAM1.R14 ; VRAM1.N3 60.59,105.74 v1(60.98,106.14) ; v1(58.64,86.51) 58.24,86.12 VRAM2.H14 ; v1(61.02,115.08) 61.02,115 60.59,114.57 VRAM1.N14 ; VRAM2.A3 63.87,94.91 v1(64.27,94.52) ; VRAM2.R1 v1(52.64,97.08) ; v1(62.59,106.16) 62.19,105.75 VRAM1.R3 ; v1(51.44,88.13) 51.04,87.73 VRAM2.U12 ; VRAM1.C1 52.59,103.68 v1(52.43,103.53) ; VRAM1.P10 61.39,111.3 v1(61.78,110.91) ; v1(60.24,93.71) 59.84,93.31 VRAM2.F5 ; v1(62.43,97.13) 62.24,96.94 VRAM2.C1 ; v1(54.23,115.1) 54.19,115.06 VRAM1.E14 ; v1(54.64,88.11) 54.24,87.71 VRAM2.N12 ; VRAM1.K13 58.18,113.74 57.78,114.14 v1(57.77,114.14) ; VRAM1.B5 51.79,107.35 v1(51.38,107.76) ; VRAM1.C4 52.58,106.54 52.45,106.41 52.44,106.41 v1(52.19,106.16) 52.43,105.92 52.43,105.89 VRAM1.C3 ; v1(60.36,85.34) 60.36,85.83 VRAM2.E14 ; VRAM2.T5 51.84,93.33 v1(52.23,93.72) ; VRAM2.E12 v1(60.24,88.11) ; VRAM2.R3 52.64,94.87 52.26,94.49 v1(52.24,94.49) 52.26,94.47 52.28,94.47 VRAM2.R4 ; v1(50.6,94.54) 50.98,94.91 VRAM2.U3 ; v1(60.21,89.75) 60.21,89.74 59.84,89.37 VRAM2.F10 ; v1(51.47,89.72) 51.47,89.68 VRAM2.T10 ; v1(59.42,92.87) 59.04,93.25 VRAM2.G5 ; VRAM2.A12 63.89,87.71 v1(64.27,88.09) ; v1(55.05,89.88) 55.04,89.87 VRAM2.M10 ; VRAM2.L5 v1(55.84,92.77) ; VRAM2.K2 56.24,96.11 v1(56.23,96.11) ; v1(53.04,89.74) 53.44,89.35 VRAM2.P10 ; v1(54.59,106.14) 54.19,105.74 VRAM1.E3 ; v1(54.64,96.9) 54.63,96.9 VRAM2.N1 ; VRAM1.M10 60.19,110.93 v1(60.21,110.93) ; VRAM2.C3 62.24,94.89 v1(62.64,94.49) ; VRAM2.L10 55.81,89.34 55.81,89.81 v1(55.76,89.87) ; VRAM2.E1 60.64,97.08 v1(60.61,97.1) ; VRAM2.N3 v1(54.64,94.51) ; v1(64.3,103.63) 63.79,104.14 ; VRAM1.K2 58.2,104.94 v1(58.58,104.56) 58.58,104.53 VRAM1.K1 58.45,103.87 58.45,103.38 60.74,101.09 R676.2 ; VRAM1.E12 v1(54.59,112.54) ; VRAM2.U1 v1(51.04,97.08) ; VRAM2.R11 52.65,88.51 v1(53.04,88.12) 52.64,87.71 VRAM2.R12 52.43,87.51 52.43,87.12 VRAM4.C13 ; VRAM1.H13 56.19,114.14 v1(56.18,114.14) 56.58,114.54 VRAM1.H14 ; VRAM1.A12 50.93,112.94 v1(50.55,112.56) ; VRAM2.G10 59.04,89.38 v1(59.43,89.77) ; VRAM1.B10 51.79,111.36 v1(52.18,111.75) ; VRAM1.M5 59.79,107.46 v1(59.38,107.87) 58.99,107.47 VRAM1.L5 ; VRAM1.H2 v1(56.19,104.54) 56.59,104.14 VRAM1.H1 ; v1(62.59,111.75) 62.58,111.75 62.19,112.14 VRAM1.R11 62.03,112.29 62.02,112.29 v1(61.78,112.53) 61.78,112.53 VRAM1.R12 VRAM3.C13
  BOTTOM w0.381: v1(83.83,157.3) 83.72,157.42 C365.2 ; v3(26.2,21.08) 26.02,20.9 Q78.4 ; R886.2 85.75,142.18 85.68,142.11 v1(85.38,142.11) ; C512.2 76.79,92.95 v1(76.78,92.95) ; v1(74.73,156.95) 73.76,157.93 C362.2 ; v1(129.04,46.77) 129.1,46.84 129.22,46.84 129.5,47.12 130.14,47.12 C569.2 ; v3(33.42,210.68) 33.5,210.6 PR157.1
  BOTTOM w0.406: U32.3 144.41,54.47 144.99,55.06 145,55.06 145.26,55.31 C562.2 ; Q78.1 24.15,23.61 v3(24.42,23.88) ; Q53.1 77.17,117.55 v1(76.87,117.86) ; PQ11.1 56.02,41.26 56.45,41.69 56.45,42.26 56.76,42.56 PQ11.4 57.18,42.74 v3(57.18,43.31) ; v3(128.05,205.99) 127.94,206.11 U27.3 ; Q58.4 55.2,76.66 54.9,76.96 v3(53.12,76.96) ; Q53.4 75.74,115.55 v1(76.23,115.06) ; v1(71.53,69.6) 72.15,68.98 PQ9.1
  BOTTOM w0.457: C389.2 153.49,147.35 154.17,147.35 C388.2 154.45,147.29 C392.2
  BOTTOM w0.508: C562.2 145.96,55.5 v1(146.08,55.63) ; v5(37.63,74.68) 37.43,74.49 PR239.2 ; v3(57.82,121.03) 57.82,120.78 57.12,120.08 C425.1 ; R605.2 139.67,147.38 C393.2 138.84,146.56 v1(137.96,146.56) ; v1(85.6,180.42) 85.69,180.33 R551.1 85.78,179.77 R552.2 ; 56.62,22.62 DCIN1.4 ; DCIN1.4 57.72,24.18 ; DCIN1.4 55.53,24.18 ; UHS1.MS2 179,80.91 ; UHS1.MS2 177.58,79.89 ; UHS1.MS2 180.42,79.89 ; UHS1.MS2 179,78.87 ; PR82.2 v3(123.25,72.01) ; PR204.2 23.19,145.58 v3(23.78,146.18) ; C537.2 69.5,72.9 v1(68.99,73.41) ; v1(60.23,66.27) 60.54,66.27 61.16,66.89 C540.2 ; C503.2 79.15,95.89 79.46,95.58 v1(79.59,95.58) ; C526.2 49.69,84.76 v1(50.58,85.65) ; v3(81.66,81.9) 81.57,81.99 R697.2 ; C413.2 132.11,130.68 132.75,131.32 v1(132.75,131.83) ; R612.2 178.38,143.51 v1(177.45,143.51) ; C571.2 50.74,45.15 PQ10.S 52.5,45.82 v3(52.51,45.82) ; v1(147.95,131.83) 147.95,131.34 C414.2 146.4,130.37 C412.2 ; v3(122.97,101.73) 122.72,101.73 122.57,101.88 122.5,101.88 PR217.2 ; C505.1 81.69,95.33 v1(81.54,95.48) ; C316.2 138.67,172.09 137.69,172.09 137.32,171.71 v1(137.32,171.45) ; C294.2 79.72,198.5 79.72,200.35 v3(78.9,201.17) ; C338.2 C343.2 145.77,162.56 144.55,162.56 144.05,163.06 v3(144.05,163.38) ; C559.1 v1(60.1,55.37) ; v1(133.89,59.69) 134.27,59.31 C555.2 ; v3(23.66,151.89) 24.73,151.89 PC252.2 ; v3(151.54,35.56) 152.31,36.32 C582.2 ; C591.2 v3(31.53,23.24) ; C563.2 v3(51.98,54.23) ; v1(92.67,162.55) 93.06,162.94 C341.2 ; C286.2 PC148.2 v3(78.49,212.98) ; C357.2 90.39,158.69 v1(89.57,157.86) ; v3(66.86,59.92) 66.46,59.51 C554.2 66.01,58.93 C556.1 65.37,57.67 C558.2 ; C290.2 154.47,206.88 v5(154.72,207.14) 154.78,207.2 Q48.S ; PC289.2 v3(152.18,22.73) ; HDD1.8 12,136.95 ; HDD1.8 12,134.31 ; HDD1.8 13.32,135.63 ; HDD1.8 10.68,135.63 ; 111.46,11.21 HDMI2.20 ; HDMI2.20 110.34,14.03 ; HDMI2.20 112.58,14.03 ; HDMI2.20 111.46,16.85 ; PT8.2 53.79,187.83 ; PT8.2 52.74,188.89 ; PT8.2 51.68,187.83 ; R699.2 R700.2 R288.2 v3(94.65,82.3) ; v3(80.17,219.33) 81.19,218.31 PC142.2 ; 8.4,169.31 ODD1.8 ; ODD1.8 8.4,171.95 ; ODD1.8 7.08,170.63 ; ODD1.8 9.72,170.63 ; v1(78.57,100.56) 77.85,100.56 C488.2 C478.2 77.52,101.66 77.49,101.65 77.4,101.63 76.98,101.22 v1(76.74,101.22) ; v3(33.94,64.9) 33.88,64.83 PC277.2 ; v1(67.67,67.69) 68.21,67.69 68.46,67.94 R727.2 68.93,67.73 69.38,67.28 C632.2 69.31,66.87 C543.2 ; v1(79.51,97.46) 79.81,97.16 C497.1 81.19,97.16 v1(81.45,97.41) ; 100.03,33.53 USB3.4 ; USB3.4 101.06,34.56 ; USB3.4 102.09,33.53 ; USB3.4 101.06,32.5 ; C458.1 93.49,107.7 v1(93.73,107.46) 93.96,107.7 C457.1 ; R598.2 140.94,150.18 v3(141,150.24) ; C408.2 169.63,136.75 170.28,137.4 C406.1 168.94,137.79 v1(168.31,137.16) ; USB4.5 98.38,22.31 ; USB4.5 100.1,20.6 ; USB4.5 98.38,18.88 ; USB4.5 96.67,20.6 ; DCIN1.2 54.81,23.03 ; DCIN1.2 51.69,23.03 ; DCIN1.2 53.25,24.12 ; v3(89.57,82.3) 89.38,82.11 C627.2 ; USB4.4 102.12,10.53 ; USB4.4 100.06,10.53 ; USB4.4 101.09,11.56 ; USB4.4 101.09,9.5 ; v1(85.93,156.39) 85.01,156.39 C371.2 ; C321.2 86.71,168.97 v1(86.57,168.84) ; v3(24.93,225.81) 24.93,225.68 25.43,225.17 C284.2 ; C381.2 C379.2 R585.2 108.49,153.16 108.92,153.59 v1(108.92,153.67) ; v1(153.03,177.42) 153.03,178.28 C307.2 ; USB3.6 100.07,30.46 ; USB3.6 98.35,32.17 ; USB3.6 96.64,30.46 ; USB3.6 98.35,28.74 ; DCIN1.6 50.97,24.18 ; DCIN1.6 49.88,22.62 ; DCIN1.6 48.78,24.18 ; DCIN1.6 49.88,25.74 ; 53.95,28.81 DCIN1.7 52.39,29.9 ; 57.53,190.25 PT7.2 ; PT7.2 58.58,189.19 ; PT7.2 58.58,191.3 ; PC256.2 36.67,137.79 v3(35.97,137.79) ; R736.1 56.99,63.94 C549.2 56.32,63.63 v1(54.9,63.63) ; C575.2 142.02,38.81 v3(141.54,38.33) ; HDD1.4 10.18,142 ; 176.12,122.17 SSUSB1.11 ; SSUSB1.11 177.99,123.24 ; SSUSB1.11 176.12,124.31 ; C376.2 169.39,154.37 v3(169.58,154.18) ; R706.2 57.18,77.98 v1(56.8,77.6) ; v1(80.93,90.46) 81.12,90.27 C520.2 ; 176.12,87.87 SSUSB2.10 ; SSUSB2.10 176.12,90.01 ; SSUSB2.10 177.99,88.94 ; SSUSB2.10 174.25,88.94 ; v3(153.83,45.47) 153.61,45.69 Q84.S 153.61,46.96 152.74,47.83 152.67,47.83 R890.2 ; v3(65.69,50.93) 65.69,50.76 65.2,50.27 63.81,50.27 63.66,50.42 U33.4 ; C565.2 C567.2 ; C567.2 119.72,48.82 120.18,48.36 v3(120.18,47.88) ; C567.2 119.27,48.81 C568.2 ; C312.2 131.15,176.02 133.01,176.02 133.38,175.65 v1(133.38,175.39) ; v1(85.34,144.4) 85.31,144.38 85.1,144.38 84.93,144.21 R609.2 ; v1(172.6,136.6) 172.6,136.6 172.37,136.83 C404.2 172.37,137.9 173.39,138.91 C402.1 ; 176.12,100.67 SSUSB2.11 ; SSUSB2.11 176.12,102.81 ; SSUSB2.11 177.99,101.74 ; v3(35.71,107.7) 34.89,107.7 C628.2 C629.2 ; v3(84.11,170.81) 84.23,170.69 R561.1 ; v1(82.48,96.42) 82.58,96.52 C496.1 83.26,97.16 v1(83.6,97.5) ; v3(43.34,26.42) 43.66,26.73 Q76.E ; PR137.2 142.21,205.3 v3(142.4,205.49) ; SSUSB1.10 176.12,111.51 ; SSUSB1.10 176.12,109.37 ; SSUSB1.10 177.99,110.44 ; PR125.2 84.81,217.74 PC141.2 84.74,218.69 v3(84.62,218.82) ; U37.3 116.36,15.88 v3(119.29,15.88) ; v1(90.99,186.54) 91.21,186.54 91.43,186.75 R543.2 ; v3(52.1,100.33) 52.61,100.84 C481.2 ; v3(52.1,100.33) 52.48,99.95 C490.2 ; v3(52.1,100.33) 51.6,100.84 C482.2 ; R687.2 73.5,90.81 73.48,90.83 v1(73.48,92.14) ; v3(34.53,24.5) 33.56,23.53 R844.1 ; R546.2 95.65,181.55 v1(94.96,180.86) ; v3(128.81,93.32) PC266.2 PR231.2 ; ODD1.9 9.72,183.37 ; ODD1.9 8.4,182.05 ; ODD1.9 7.08,183.37 ; ODD1.9 8.4,184.69 ; v1(92.73,174.6) 92.81,174.53 C314.2 ; C315.2 92.49,170.05 v3(92.6,169.94) ; v1(65.82,74.42) 65.69,74.3 C532.2 ; v1(55.66,70.1) 55.66,68.71 56.17,68.2 C539.2 ; R554.2 69.63,179.77 69.63,179.86 v1(69.65,179.88) ; v1(137.96,137.41) C410.2 ; v3(140.81,167.42) 140.33,166.94 C330.2 138.97,166.05 C334.2 D15.2 ; v3(162.97,34.29) 162.85,34.42 C579.2 ; v3(28.42,4.7) 27.39,4.7 C623.2 ; v1(83.4,107.06) 83.03,107.42 C454.2 ; C592.2 41.18,22.29 41.18,21.59 v3(40.29,20.7) ; C545.2 v1(137.96,66.55) ; 181.68,130.49 MEMCD1.14 ; MEMCD1.14 183,129.58 ; MEMCD1.14 183,131.4 ; TC4.2 89.57,19.6 ; TC4.2 88.51,18.54 ; TC4.2 89.57,17.49 ; TC4.2 90.62,18.54 ; PC259.2 131.35,105.28 v3(131.48,105.41) ; Q63.S 23.59,58.1 ; R710.2 51.92,78.11 51.92,77.23 52.31,76.84 52.48,76.84 52.48,76.83 52.99,76.83 v3(53.12,76.96) ; v3(84.11,204.98) PC168.2 ; R613.2 83.41,143.64 R609.2 ; C423.2 C424.2 145.77,125.29 145.32,124.84 v1(144.94,124.84) ; v3(129.07,15.11) C604.2 ; v3(32.82,192.07) 32.86,192.11 PR189.1 ; HDMI2.21 116.68,21.28 ; HDMI2.21 113.99,22.4 ; HDMI2.21 111.3,21.28 ; HDMI2.21 113.99,20.16 ; C287.2 v3(124.3,210.63) 124.37,210.57 PC157.2 ; v1(75.47,175.23) 75.55,175.31 PC210.2 ; R692.2 93.63,88.65 v1(93.38,88.9) 93.38,89.15 93.76,89.53 v3(94.39,89.53) ; PC264.2 120.62,97.28 PR223.2 120.56,97.92 v3(120.43,98.04) ; R738.2 63.53,64.39 v1(63.15,64.01) ; v1(73.17,164.81) 72.83,164.47 R565.2 ; C293.2 146.02,205.68 C291.2 C292.2 144.62,205.3 v3(144.81,205.1) ; v3(24.67,60.58) 24.73,60.64 PR245.2 ; C624.2 44.59,5.24 v3(44.59,4.76) ; C552.1 54.77,60.33 v1(54.9,60.2) C553.2 R755.2 ; R638.1 137.93,130.52 137.93,130.12 137.96,130.09 v1(137.96,129.67) ; v3(153.2,21.84) 153.13,21.78 PC293.2 ; v1(88.36,107.13) 88.42,107.07 C460.2 ; C322.2 C317.2 73.16,169.45 v1(73.16,170.02) ; v3(18.89,202.76) PR172.1 PC174.1 PR171.1 PR168.2 ; v3(143.42,47.12) 144.18,46.35 R782.2 ; v3(143.42,47.12) 143.64,47.12 Q67.S ; v3(143.42,47.12) 143.38,47.09 143.38,46.42 Q69.S ; UHS1.MS1 179.42,70.69 ; UHS1.MS1 176.58,70.69 ; UHS1.MS1 178,71.71 ; UHS1.MS1 178,69.67 ; v1(136.69,146.56) 136.69,147.26 C391.2 C390.2 ; R835.2 46.39,24.64 v3(46.52,24.77) ; C360.2 C364.2 140.75,157.73 v3(140.88,157.61) ; R593.2 94.71,151.85 95.6,152.74 R587.2 R580.2 95.77,153.92 96.62,154.77 R576.2 96.68,154.94 97.06,154.56 v1(97.06,153.67) ; HDD1.7 11.75,146.69 ; HDD1.7 12.63,145.81 ; HDD1.7 10.87,145.81 ; USB4.6 100.1,7.46 ; USB4.6 96.67,7.46 ; USB4.6 98.38,9.17 ; USB4.6 98.38,5.74 ; C594.2 124.75,19.3 123.48,18.03 v3(122.84,18.03) ; v1(54.9,66.8) 54.2,66.8 C542.1 ; C607.2 31.35,12.14 31.02,11.81 C614.2 30.82,10.97 v3(30.13,10.29) ; v3(156.14,151.72) 155.74,151.32 R596.2 ; Q79.S v3(23.15,11.87) ; C394.2 C395.2 170.77,145.92 v3(170.87,145.82) ; R691.2 74.9,88.96 v1(75.25,89.31) ; 7.27,173.19 ODD1.1 ; ODD1.1 8.15,172.31 ; ODD1.1 9.03,173.19 ; v3(82.08,208.91) 81.5,208.34 PR161.2 ; v3(26.58,29.97) 26.58,29.34 26.93,28.99 Q77.E ; v1(140.01,73.15) 141.28,71.88 C535.2 R717.2 ; 11.75,137.31 HDD1.1 ; HDD1.1 10.87,138.19 ; HDD1.1 12.63,138.19 ; Q56.S 35.78,99 v3(35.72,98.93) ; C631.2 60.17,72.52 C534.1 60.23,72.89 59.98,73.14 59.98,73.15 v1(59.72,73.41) 59.53,73.6 R713.1 ; v3(55.28,74.17) 55.3,74.19 56.22,74.19 56.5,73.91 R714.1 ; v1(119.41,33.91) 119.48,33.85 C586.2 ; USB3.5 100.07,43.6 ; USB3.5 98.35,41.88 ; USB3.5 96.64,43.6 ; C621.2 38.76,7.79 v3(39.25,8.28) ; 111.3,6.78 HDMI2.22 113.99,5.66 ; C574.2 v5(35.09,40.77) ; v1(153.07,146.56) 153.07,147.15 C389.2 ; C615.2 121.45,10.03 ; 67.34,197.32 PT6.2 ; PT6.2 66.29,198.37 ; PT6.2 67.34,199.43 ; C578.2 116.11,38.58 v3(115.35,37.82) ; v1(130.46,59.69) 130.34,59.69 129.45,60.58 R750.2 ; H2.1 62.62,165.35 v1(66.07,165.35) ; v1(51.21,57.15) 51.15,57.09 R764.2 ; v1(67.85,62.99) 67.6,63.25 C544.2 ; 10.68,148.37 HDD1.9 ; HDD1.9 12,149.69 ; HDD1.9 12,147.05 ; PC268.2 119.23,93.6 v3(118.6,94.23) ; ODD1.4 6.98,177 ; C489.2 C480.2 60.8,100.84 R676.2 60.52,100.77 59.63,99.89 R873.2 59.15,99.82 PR235.2 PR221.2 ; PC277.2 PL14.2 ; PC277.2 PC278.2 PL15.2 ; v3(136.88,50.56) 137.38,50.06 C566.2 ; R609.2 83.79,144.4 82.77,144.4 R610.2 ; v3(124.37,208.66) 124.3,208.72 C288.2 123.54,209.55 C289.2 ; v3(156.01,167.03) 155.73,167.31 C323.2 ; C397.2 168.32,141.92 v1(168.26,141.99) ; v1(93.76,92.33) 93.76,92.71 C515.2 94.32,93.27 C507.2 ; R761.2 57.25,57.15 C560.1 v1(57.18,58.17) ; C378.2 140.97,153.54 v3(141,153.57) ; v1(54.9,58.29) C557.1 ; C588.2 v3(28.84,25.15) ; v3(144.43,157.48) 144.69,157.23 C366.2 146.02,157.54 C361.2 C356.2 ; v3(33.94,67.44) 33.75,67.63 PC276.2 PL13.2 ; R591.2 v1(70.7,151.64) ; C363.2 155.48,157.73 v3(156.12,158.37) 155.86,158.62 C359.2 ; C580.2 158.66,36.04 v3(157.72,35.1) 156.75,36.07 C581.2 ; PR220.2 v3(134.65,99.44) 134.65,100.46 PC261.2 ; v1(149.85,185.93) 149.85,185.51 148.62,184.28 C297.2 ; C377.2 144.81,153.8 v3(144.69,153.67) ; v3(112.43,107.44) 112.43,104.3 Q83.S 111.63,103.7 R888.2 ; C605.2 88.93,14.99 v5(88.68,15.24) ; D22.1 v3(26.83,25.15) ; C311.2 146.39,176.02 148.21,176.02 148.58,175.65 v1(148.58,175.39) ; v3(148.12,22.1) 147.99,22.23 PC127.2 ; C417.2 140.11,125.79 C420.2 140.11,124.84 139.59,124.32 R652.1 138.42,124.32 138.11,124.64 v1(138.11,124.97) ; PC251.2 96.27,157.99 v1(96.31,158.03) ; HS6.1 144.25,217.61 ; HS6.1 147.86,214 ; HS6.1 144.25,210.39 ; HS6.1 140.64,214 ; PC146.2 v3(126.91,204.34) ; R659.2 C427.2 v3(60.1,121.03) ; C331.2 93.15,167.2 v1(92.76,167.59) 92.41,167.94 92.41,168.26 C319.2 93.29,168.26 C320.2 ; C400.1 177.39,139.16 v1(177.43,139.12) ; Q51.S v3(55.85,122.17) ; v1(70.65,167.51) 70.65,166.81 C332.2 ; Q59.C 138.21,69.85 v1(137.45,70.61) 135.42,70.61 134.27,69.47 C538.2 ; Q80.E 48.25,7.94 v3(48.47,7.72) ; v1(80.96,87.93) 81.57,88.54 C521.2 ; 7.27,180.81 ODD1.7 8.15,181.69 ; v1(75.38,157.86) 76.01,158.49 R573.2 ; C409.2 153.32,137.41 v1(153.07,137.16) ; v3(156.29,146.35) 155.6,146.35 R637.1 ; PC262.2 v3(120.4,99.26) ; DCIN1.5 55.51,21.16 ; DCIN1.5 53.95,20.06 ; DCIN1.5 52.39,21.16 ; v1(168.18,142.88) C396.1 ; PR219.2 121.13,100.08 v3(120.43,100.08) ; PC267.2 123.6,94.11 v3(122.97,93.47) ; v3(20.23,225.93) 20.8,225.36 C283.2 ; PC282.1 37.5,47.37 37.12,47.75 v3(36.74,47.75) PR249.2 ; C337.2 v3(156.12,163.7) ; R606.2 v1(149.77,147.45) ; v3(25.69,193.04) PR187.2 25.74,193.92 PC194.1 27.01,193.92 27.59,194.5 PC192.2 PR181.2 PC191.2 29.62,193.78 28.96,193.12 28.96,192.04 PR197.2 29.03,191.71 29.42,191.31 30.64,191.31 31.33,192 31.33,194.55 PC189.2 ; C372.2 82.7,154.19 C368.2 82.79,154.15 83.19,153.75 84.22,153.75 v1(84.26,153.78) ; C349.2 v3(156.12,161.29) ; R818.2 143.01,33.68 143.01,34.21 v3(142.04,35.18) ; v1(82.46,158.5) 82.46,159.3 R572.2 ; v1(139.78,56.64) 139.78,55.77 R883.1 138.97,54.93 R769.2 ; U39.2 v3(50.07,11.94) ; D20.1 57.85,39.21 v3(57.82,39.24) ; v1(133.89,66.55) 134.15,66.29 C546.2 ; R817.2 49.69,34.04 ; C561.2 v1(127.92,55.75) ; PC265.2 v3(129.7,93.32) ; v1(151.93,124.33) 151.99,124.4 C422.2 153,124.21 C421.2 153.89,124.14 R648.1 ; PC183.1 v3(158.15,199.64) ; R553.2 76.36,178.9 76.36,179.15 76.18,179.32 v1(76.18,179.75) 76.87,180.43 R547.2 ; PU21.1 v3(137.96,206.88) ; C342.2 75.34,162.5 C345.2 75.15,161.75 v1(75.38,161.52) 76.07,161.52 C354.2 C342.2
  vias: v1(51.05,63.17) v1(58.2,159.89) v1(59.85,148.39) v1(65.18,67.94) v1(65.95,67.82) v1(65.99,158.04) v1(66.07,161.42) v1(66.96,61.34) v1(68.49,159.51) v1(68.79,151.64) v1(68.84,93.33) v1(69.62,90.03) v1(70.03,162.25) v1(70.52,149.61) v1(73.31,121.54) v1(73.44,120.14) v1(73.51,122.85) v1(74.96,120.27) v1(74.96,119) v1(79.51,103.45) v1(79.51,101.5) v1(81.49,103.48) v1(81.47,101.45) v1(81.55,99.58) v1(83.47,103.35) v1(83.53,101.5) v1(83.5,95.5) v1(83.57,99.52) v1(84.54,102.46) v1(84.51,100.48) v1(84.49,98.5) v1(86.32,98.5) v1(86.49,102.51) v1(86.47,100.48) v1(86.52,96.49) v1(87.28,144.15) v1(87.28,140.34) v1(97.6,186.76) v1(97.98,159.51) v1(98.3,181.02) v1(99.61,175.38) v1(99.86,177.43) v1(99.99,178.73) v1(100.81,186.77) v1(101.38,184.79) v1(102.72,186.79) v1(129.07,194.18) v1(129.57,162.13) v1(129.7,160.78) v1(129.7,149.48) v1(131.99,124.84) v1(132.62,124.84) v1(134.65,146.69) v1(149.77,144.65) v1(151.16,174.12) v1(153.98,13.21) v1(153.98,9.53) v1(153.98,4.83) v1(156.12,16.05) v1(172.5,151.89) v1(174.91,136.91) v1(175.29,140.84) v2(4.45,182.45) v2(5.52,202.72) v2(7.45,137.62) v2(7.98,166.98) v2(8.44,148.77) v2(10.88,224.41) v2(23.22,182.22) v2(23.58,36.7) v2(28.46,3.48) v2(32.27,161.77) v2(37.73,206.55) v2(38.72,15.72) v2(47.02,33.15) v2(49.66,29.67) v2(51.01,190.93) v2(51.67,2.92) v2(53.22,162.13) v2(58.71,217.04) v2(62.39,182.37) v2(85.25,193.78) v2(86.82,185.7) v2(91.98,23.11) v2(104.17,179.65) v2(109.15,4.57) v2(111.82,226.69) v2(130.74,35.23) v2(135.8,24.64) v2(144.33,224.28) v2(158.53,46.86) v2(164.04,78.13) v2(165.74,27.18) v2(179,126.87) v2(179.89,87) v3(8.42,216.66) v3(9.18,216.66) v3(14.13,204.34) v3(14.13,203.45) v3(14.13,202.56) v3(18.32,196.22) v3(18.32,195.45) v3(21.12,1.14) v3(23.66,149.99) v3(23.66,149.1) v3(23.66,148.21) v3(24.42,201.55) v3(25.18,201.55) v3(25.94,203.07) v3(25.94,202.31) v3(25.94,201.55) v3(25.94,200.79) v3(25.94,200.03) v3(26.7,201.55) v3(26.7,163.45) v3(26.7,162.18) v3(26.7,160.91) v3(26.86,1.07) v3(27.47,201.55) v3(28.23,172.44) v3(29.12,56.36) v3(29.88,54.65) v3(31.66,6.48) v3(31.94,1.07) v3(34.32,228.85) v3(34.58,58.67) v3(34.58,56.26) v3(34.83,9.02) v3(35.09,78.23) v3(35.09,77.47) v3(35.06,75.69) v3(35.06,74.93) v3(35.67,114.81) v3(35.71,113.92) v3(35.82,75.69) v3(35.82,74.93) v3(37.02,1.07) v3(37.07,14.86) v3(37.88,15.67) v3(37.88,14.86) v3(37.88,14.05) v3(38.49,4.7) v3(38.69,14.86) v3(39.25,4.7) v3(41.18,106.17) v3(41.31,113.28) v3(41.31,112.52) v3(41.69,45.85) v3(41.69,44.58) v3(42.07,136.61) v3(42.1,1.07) v3(42.32,45.21) v3(42.96,45.85) v3(42.96,44.58) v3(44.23,136.61) v3(44.23,17.4) v3(44.48,220.85) v3(44.86,112.65) v3(44.86,110.36) v3(45.25,220.85) v3(46.01,220.85) v3(46.39,174.82) v3(46.39,160.53) v3(46.95,161.14) v3(46.97,113.28) v3(46.97,112.52) v3(47.02,104.32) v3(47.18,1.07) v3(47.53,161.67) v3(48.04,162.31) v3(48.8,162.31) v3(49.56,162.31) v3(51.34,118.87) v3(52.26,1.07) v3(52.87,155.96) v3(52.87,153.67) v3(52.87,151.38) v3(57.34,1.07) v3(61.63,149.1) v3(61.63,146.81) v3(61.63,144.53) v3(61.63,142.24) v3(62.42,1.07) v3(63.18,154.18) v3(63.28,20.7) v3(63.28,19.94) v3(63.91,149.1) v3(66.07,23.11) v3(66.84,23.11) v3(66.96,20.7) v3(66.96,19.94) v3(67.5,1.07) v3(71.41,59.94) v3(71.41,59.18) v3(71.41,57.94) v3(72.58,1.07) v3(74.58,63.75) v3(74.89,21.93) v3(74.96,61.21) v3(75.9,21.93) v3(76.11,64.77) v3(76.11,64.01) v3(76.11,62.74) v3(76.92,21.93) v3(77.66,1.07) v3(77.94,21.93) v3(78.14,199.44) v3(78.19,168.63) v3(78.19,167.89) v3(78.52,203.33) v3(78.95,21.93) v3(79.41,203.33) v3(79.66,115.44) v3(80.42,115.44) v3(80.55,163.19) v3(80.55,162.43) v3(80.93,201.8) v3(81.44,163.19) v3(81.44,162.43) v3(81.44,122.68) v3(81.57,58.04) v3(81.82,161.67) v3(82.2,163.19) v3(82.2,162.43) v3(82.46,58.04) v3(82.74,1.07) v3(82.8,202.04) v3(83.09,121.03) v3(83.85,176.28) v3(83.85,175.39) v3(83.85,174.62) v3(83.85,173.86) v3(83.85,173.1) v3(84.23,194.06) v3(84.23,193.29) v3(84.23,192.53) v3(84.23,191.64) v3(84.23,190.88) v3(84.23,190.12) v3(84.74,212.09) v3(84.74,211.07) v3(85.15,161.72) v3(85.63,161.21) v3(85.76,211.07) v3(85.76,167.94) v3(91.47,66.93) v3(92.24,66.93) v3(93.12,66.93) v3(93.89,66.93) v3(94.14,1.14) v3(94.9,66.93) v3(95.66,66.93) v3(96.17,21.34) v3(97.06,15.49) v3(97.32,12.32) v3(97.44,32.77) v3(97.82,1.14) v3(97.95,133.48) v3(97.95,14.22) v3(98.08,38.23) v3(98.08,36.83) v3(98.2,109.39) v3(98.2,11.43) v3(98.46,35.43) v3(98.84,104.39) v3(98.97,109.39) v3(98.97,37.97) v3(98.97,12.32) v3(99.22,15.24) v3(99.6,104.39) v3(99.73,109.39) v3(100.24,42.42) v3(101,21.46) v3(101.51,19.3) v3(101.63,1.14) v3(101.94,32.26) v3(102.65,13.21) v3(103.03,11.05) v3(103.92,109.39) v3(104.43,13.34) v3(104.81,109.39) v3(104.76,38.61) v3(105.32,1.14) v3(105.96,38.61) v3(108.13,38.59) v3(108.36,22.35) v3(108.75,11.81) v3(108.87,20.95) v3(109,13.34) v3(109.51,203.71) v3(109.89,19.94) v3(109.89,11.43) v3(110.52,21.84) v3(110.52,19.05) v3(111.03,1.14) v3(113.06,223.14) v3(113.44,203.71) v3(114.71,1.14) v3(120.05,12.32) v3(120.3,1.14) v3(121.19,224.28) v3(123.1,25.15) v3(123.1,24.38) v3(123.73,207.39) v3(123.86,25.15) v3(123.99,1.14) v3(124.3,214.57) v3(124.75,48.13) v3(125.26,224.28) v3(125.51,48.9) v3(125.51,48.13) v3(125.51,47.37) v3(126.02,224.28) v3(126.4,48.13) v3(127.67,100.46) v3(127.67,99.57) v3(127.67,98.68) v3(128.56,99.57) v3(128.68,1.14) v3(131.99,35.56) v3(132.37,1.14) v3(132.75,36.32) v3(132.75,35.56) v3(133.51,35.56) v3(136.43,1.14) v3(140.88,104.27) v3(141,1.14) v3(144.43,34.8) v3(145.07,195.45) v3(145.83,195.45) v3(145.83,1.14) v3(146.59,195.45) v3(148.88,195.45) v3(150.4,112.14) v3(151.04,1.14) v3(151.43,114.95) v3(151.42,113.67) v3(151.93,110.87) v3(152.18,21.84) v3(152.7,109.2) v3(153.2,111.89) v3(153.2,110.62) v3(153.2,22.73) v3(153.96,113.7) v3(153.96,1.14) v3(155.61,113.7) v3(156.24,98.55) v3(156.24,96.27) v3(156.24,93.98) v3(156.93,113.75) v3(157.77,106.3) v3(157.77,103.76) v3(157.89,183.26) v3(158.91,48.9) v3(159.55,16.13) v3(159.8,49.78) v3(159.8,48.9) v3(159.8,48.01) v3(160.56,48.9) v3(161.7,76.45) v3(162.59,78.23) v3(162.59,77.34) v3(162.59,76.45) v3(162.59,75.56) v3(162.59,74.68) v3(163.48,76.45) v3(164.37,76.45) v3(166.91,117.68) v3(166.91,116.92) v3(168.94,55.88) v3(168.94,52.2) v3(168.94,46.48) v3(168.94,42.8) v3(168.94,37.21) v3(168.94,33.53) v3(168.94,28.83) v3(168.94,25.15) v3(169.48,103.63) v3(169.58,151.89) v3(169.58,117.98) v3(173.77,145.54) v3(174.79,146.56) v3(174.79,145.54) v3(174.79,144.53) v3(175.67,104.37) v3(175.8,145.54) v3(181.29,82.04) v5(1.14,228.86) v5(1.14,223.78) v5(1.14,218.7) v5(1.14,213.62) v5(1.14,208.54) v5(1.14,203.46) v5(1.14,198.38) v5(1.14,193.3) v5(1.14,188.22) v5(1.14,183.14) v5(1.14,178.06) v5(1.14,172.98) v5(1.14,167.9) v5(1.33,153.97) v5(3.08,221.36) v5(3.21,223.52) v5(3.46,216.28) v5(3.59,199.64) v5(3.59,194.56) v5(3.59,189.48) v5(3.59,184.4) v5(3.84,181.1) v5(3.84,176.02) v5(3.84,170.94) v5(3.84,165.86) v5(4.58,152.32) v5(4.73,204.85) v5(5.14,148.38) v5(5.14,143.3) v5(5.14,138.22) v5(5.14,133.14) v5(5.37,218.57) v5(6.13,201.17) v5(6.13,196.72) v5(6.13,191.39) v5(6.13,187.07) v5(6.13,183.01) v5(6.13,177.93) v5(6.13,172.85) v5(6.13,167.77) v5(6.22,228.86) v5(6.64,226.95) v5(7.02,151.64) v5(7.02,146.56) v5(7.02,141.48) v5(7.02,136.4) v5(7.27,221.36) v5(8.92,226.44) v5(8.92,150.37) v5(8.92,145.29) v5(8.92,140.21) v5(8.92,135.13) v5(9.56,222.5) v5(10.22,133.14) v5(11.3,228.86) v5(12.35,225.17) v5(14.38,227.46) v5(15.3,133.14) v5(16.38,228.86) v5(20.38,133.14) v5(20.94,184.4) v5(20.94,183.49) v5(20.94,182.58) v5(20.99,181.66) v5(21.14,73.86) v5(21.14,67.18) v5(21.14,62.1) v5(21.14,57.02) v5(21.14,41.78) v5(21.14,36.7) v5(21.14,31.62) v5(21.14,26.54) v5(21.14,21.46) v5(21.14,16.38) v5(21.14,11.3) v5(21.14,6.22) v5(21.46,228.86) v5(21.85,184.4) v5(21.85,183.49) v5(21.85,182.58) v5(21.85,181.28) v5(21.85,180.37) v5(22.87,184.15) v5(23.4,72.52) v5(23.4,65.84) v5(23.4,60.76) v5(23.4,55.68) v5(23.66,38.86) v5(23.66,37.72) v5(23.78,184.15) v5(24.75,184.15) v5(24.75,183.24) v5(24.75,182.32) v5(24.75,181.41) v5(24.75,180.49) v5(25.46,133.14) v5(25.66,184.15) v5(25.66,183.24) v5(25.66,182.32) v5(25.66,181.41) v5(25.66,180.49) v5(26.54,228.86) v5(26.58,184.15) v5(26.58,183.24) v5(26.58,182.32) v5(26.58,181.41) v5(26.58,180.49) v5(28.66,154.69) v5(28.66,153.72) v5(28.66,152.81) v5(28.91,131.98) v5(29.14,126.97) v5(29.14,121.89) v5(29.14,116.81) v5(29.14,111.73) v5(29.14,106.65) v5(29.14,101.57) v5(29.14,96.49) v5(29.14,91.41) v5(29.14,86.33) v5(29.14,81.25) v5(29.14,76.17) v5(29.57,154.69) v5(29.57,153.72) v5(29.57,152.81) v5(30.23,163.32) v5(30.23,162.41) v5(30.23,161.49) v5(30.49,154.69) v5(30.49,153.72) v5(30.49,152.81) v5(31.15,163.32) v5(31.15,162.41) v5(31.15,161.49) v5(31.4,154.69) v5(31.4,153.72) v5(31.4,152.81) v5(31.62,228.86) v5(32.29,163.58) v5(35.09,65.53) v5(35.09,64.52) v5(35.09,39.75) v5(35.09,38.73) v5(35.21,203.58) v5(35.57,201.32) v5(35.57,200.41) v5(36.1,206.25) v5(36.23,203.58) v5(36.48,201.32) v5(36.48,200.41) v5(36.7,228.86) v5(36.71,75.69) v5(36.71,74.68) v5(37.37,203.45) v5(37.63,75.69) v5(37.88,208.41) v5(38.39,203.45) v5(38.64,52.96) v5(38.64,52.04) v5(38.64,51.13) v5(38.64,50.22) v5(38.9,208.41) v5(39.56,52.96) v5(39.56,52.04) v5(39.78,209.55) v5(39.78,208.64) v5(39.78,206.81) v5(39.78,205.89) v5(39.78,204.98) v5(39.78,203.96) v5(39.78,203.05) v5(39.78,201.22) v5(39.78,200.3) v5(40.7,209.55) v5(40.7,208.64) v5(40.7,206.81) v5(40.7,205.89) v5(40.7,204.98) v5(40.7,203.96) v5(40.7,203.05) v5(40.7,201.22) v5(40.7,200.3) v5(41.61,209.55) v5(41.61,208.64) v5(41.61,206.81) v5(41.61,205.89) v5(41.61,204.98) v5(41.61,203.96) v5(41.61,203.05) v5(41.61,201.22) v5(41.61,200.3) v5(41.78,228.86) v5(42.07,173.74) v5(43.09,173.74) v5(44.1,173.74) v5(45.12,173.74) v5(46.13,173.74) v5(46.86,228.86) v5(47.15,173.74) v5(47.61,190.78) v5(47.61,189.87) v5(48.17,34.42) v5(48.17,33.4) v5(48.17,32.26) v5(48.52,190.78) v5(48.52,189.87) v5(48.8,170.56) v5(48.8,21.21) v5(49.18,33.4) v5(49.18,32.26) v5(49.31,26.54) v5(49.44,190.78) v5(49.44,189.87) v5(49.82,170.56) v5(50.71,28.19) v5(50.71,21.21) v5(50.83,170.56) v5(51.94,228.86) v5(52.23,170.56) v5(53.83,190.78) v5(53.83,189.87) v5(53.75,170.56) v5(54.74,190.78) v5(54.74,189.87) v5(54.77,170.56) v5(55.66,190.78) v5(55.66,189.87) v5(55.79,170.56) v5(56.04,21.97) v5(57.02,228.86) v5(57.28,21.97) v5(57.44,177.04) v5(58.07,182.37) v5(58.45,177.04) v5(59.09,182.37) v5(59.22,218.19) v5(59.47,177.04) v5(60.1,182.37) v5(60.23,218.19) v5(60.61,177.04) v5(61.25,218.19) v5(61.25,182.37) v5(62.1,228.86) v5(62.26,218.19) v5(63.28,218.19) v5(66.33,216.28) v5(66.96,215.52) v5(66.96,214.5) v5(67.18,228.86) v5(67.22,200.41) v5(67.6,209.93) v5(67.6,208.03) v5(67.6,205.99) v5(72.26,228.86) v5(78.92,196.22) v5(79.63,196.8) v5(80.42,197.36) v5(82.42,228.86) v5(84.23,226.31) v5(85.2,226.31) v5(86.11,226.31) v5(86.77,216.28) v5(86.77,215.37) v5(86.77,214.45) v5(87.03,226.31) v5(87.5,228.86) v5(87.82,1.14) v5(87.99,226.31) v5(88.68,20.19) v5(88.68,16.51) v5(88.93,226.31) v5(88.93,204.85) v5(89.7,20.19) v5(89.7,16.51) v5(89.7,15.24) v5(89.95,204.85) v5(92.58,228.86) v5(94.01,206.12) v5(94.93,206.12) v5(97.04,206.12) v5(97.04,205.1) v5(97.04,204.19) v5(97.06,226.29) v5(97.66,228.86) v5(97.98,226.53) v5(97.98,225.62) v5(97.95,206.12) v5(97.95,205.1) v5(97.95,204.19) v5(98.94,226.53) v5(98.94,225.62) v5(99.73,127.13) v5(99.86,226.53) v5(99.86,225.62) v5(100.13,206.12) v5(100.62,79.5) v5(100.62,78.59) v5(100.62,69.6) v5(100.62,68.58) v5(100.77,226.53) v5(100.77,225.62) v5(101.05,206.12) v5(101.73,226.53) v5(101.73,225.62) v5(102.74,228.86) v5(102.67,226.53) v5(105.44,77.98) v5(105.44,76.96) v5(105.44,68.58) v5(106.46,68.58) v5(107.82,228.86) v5(108.11,96.52) v5(109.13,96.52) v5(110.14,96.52) v5(111.16,96.52) v5(112.17,78.23) v5(112.17,77.22) v5(112.56,96.52) v5(112.9,228.86) v5(113.19,78.23) v5(113.19,77.22) v5(113.57,96.52) v5(114.21,78.23) v5(114.21,77.22) v5(114.59,96.52) v5(114.71,95.38) v5(115.35,94.49) v5(115.6,96.52) v5(115.86,95.38) v5(117.98,228.86) v5(123.06,228.86) v5(126.4,3.66) v5(127.41,3.66) v5(127.67,11.05) v5(128.14,228.86) v5(129.97,211.71) v5(129.95,210.69) v5(129.97,209.55) v5(129.95,208.53) v5(132.49,84.25) v5(132.75,91.57) v5(132.75,90.65) v5(132.75,89.74) v5(132.75,88.82) v5(132.75,87.91) v5(132.75,87) v5(132.75,86.08) v5(132.75,85.17) v5(133.22,228.86) v5(133.41,84.25) v5(133.66,91.57) v5(133.66,90.65) v5(133.66,89.74) v5(133.66,88.82) v5(133.66,87.91) v5(133.66,87) v5(133.66,86.08) v5(133.66,85.17) v5(134.58,91.57) v5(134.58,90.65) v5(134.58,89.74) v5(134.58,88.82) v5(134.58,87.91) v5(134.58,87) v5(134.58,86.08) v5(134.58,85.17) v5(135.54,91.52) v5(135.54,90.6) v5(135.54,89.69) v5(135.54,88.77) v5(135.67,9.3) v5(136.05,26.04) v5(136.18,22.99) v5(136.56,9.3) v5(137.07,26.04) v5(137.19,22.99) v5(137.45,25.02) v5(137.57,26.92) v5(138.08,26.04) v5(138.3,228.86) v5(138.34,9.3) v5(138.59,26.92) v5(139.1,26.04) v5(139.23,9.3) v5(139.48,22.99) v5(139.73,26.92) v5(139.99,224.28) v5(140.11,26.04) v5(140.5,22.99) v5(140.65,26.92) v5(141.13,26.04) v5(141.51,22.99) v5(143.29,203.71) v5(143.28,202.69) v5(143.28,201.68) v5(143.38,228.86) v5(145.83,210.19) v5(146.85,210.21) v5(147.1,3.68) v5(147.86,210.19) v5(148.12,3.68) v5(148.46,228.86) v5(149,221.62) v5(149.13,225.04) v5(149.39,213.36) v5(149.64,3.68) v5(150.6,3.68) v5(150.91,219.84) v5(151.29,223.01) v5(151.54,3.68) v5(152.81,217.93) v5(153.2,221.11) v5(153.54,228.86) v5(153.58,226.57) v5(154.72,215.9) v5(155.48,227.71) v5(155.48,218.82) v5(157.01,226.44) v5(157.89,216.41) v5(158.02,220.85) v5(158.02,194.82) v5(158.02,193.8) v5(158.02,192.66) v5(158.62,228.86) v5(159.29,226.19) v5(159.55,223.14) v5(159.93,218.95) v5(160.31,228.73) v5(160.56,221.11) v5(160.69,213.61) v5(161.83,217.3) v5(162.34,219.46) v5(163.86,215.9) v5(165.77,218.95) v5(166.4,212.72) v5(168.69,220.22) v5(168.86,218.7) v5(168.86,213.62) v5(168.86,208.54) v5(168.86,203.46) v5(168.86,198.38) v5(168.86,193.3) v5(168.86,188.22) v5(168.86,183.14) v5(168.86,178.06) v5(168.86,162.82) v5(173.7,161.26) v5(175.04,159.77) v5(175.17,86.49) v5(177.07,117.73) v5(177.2,120.27) v5(177.2,115.44) v5(177.45,157.35) v5(177.58,105.92) v5(178.21,125.22) v5(178.21,99.82) v5(178.21,96.52) v5(178.21,93.09) v5(178.47,111.76) v5(178.72,159.38) v5(178.72,108.84) v5(178.72,103.25) v5(178.78,161.26) v5(178.78,68.04) v5(179.1,86.49) v5(179.36,119.76) v5(179.36,114.81) v5(179.48,88.39) v5(180.63,156.34) v5(180.63,117.35) v5(180.88,98.81) v5(181.14,129.41) v5(181.14,122.3) v5(181.14,110.24) v5(181.14,87) v5(181.26,125.35) v5(181.26,113.67) v5(181.26,95.25) v5(181.26,91.95) v5(181.64,101.98) v5(181.64,83.82) v5(181.9,120.14) v5(182.02,127.89) v5(182.28,115.57) v5(182.41,88.52) v5(182.66,153.54) v5(183.6,120.62) v5(183.6,115.54) v5(183.6,100.3) v5(183.6,95.22) v5(183.6,90.14) v5(183.8,110.24) v5(183.86,161.26) v5(183.86,156.18) v5(183.86,151.1) v5(183.86,146.02) v5(183.86,140.94) v5(183.86,135.86) v5(183.86,125.7) v5(183.86,85.06) v5(183.88,69.09)
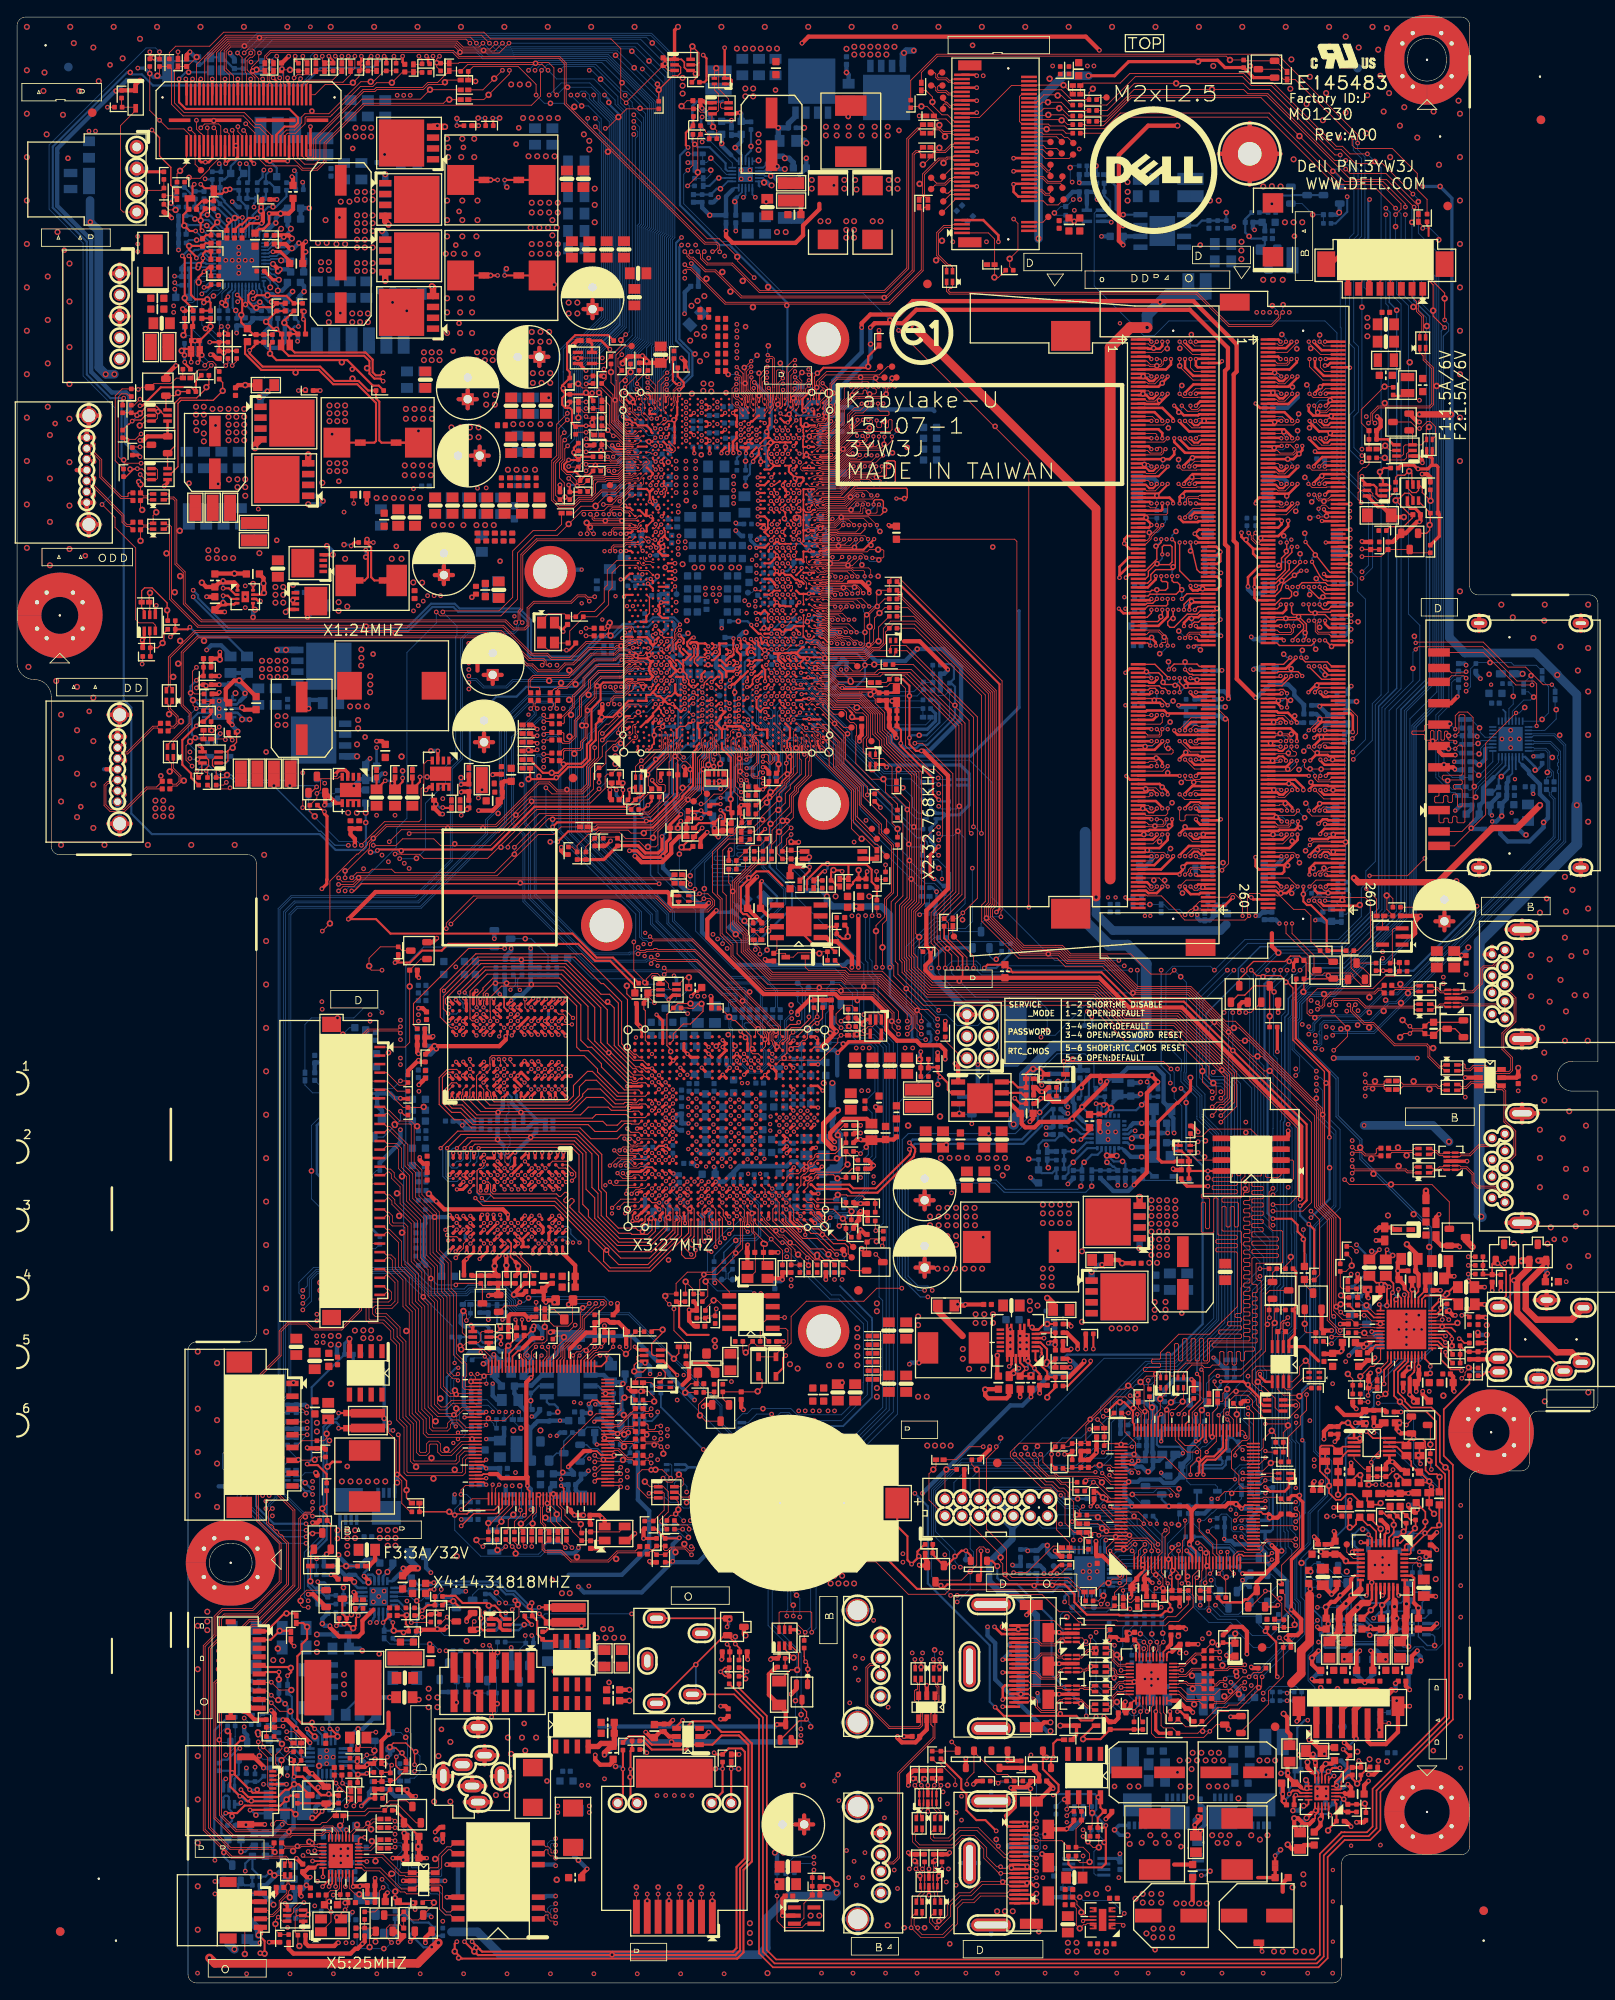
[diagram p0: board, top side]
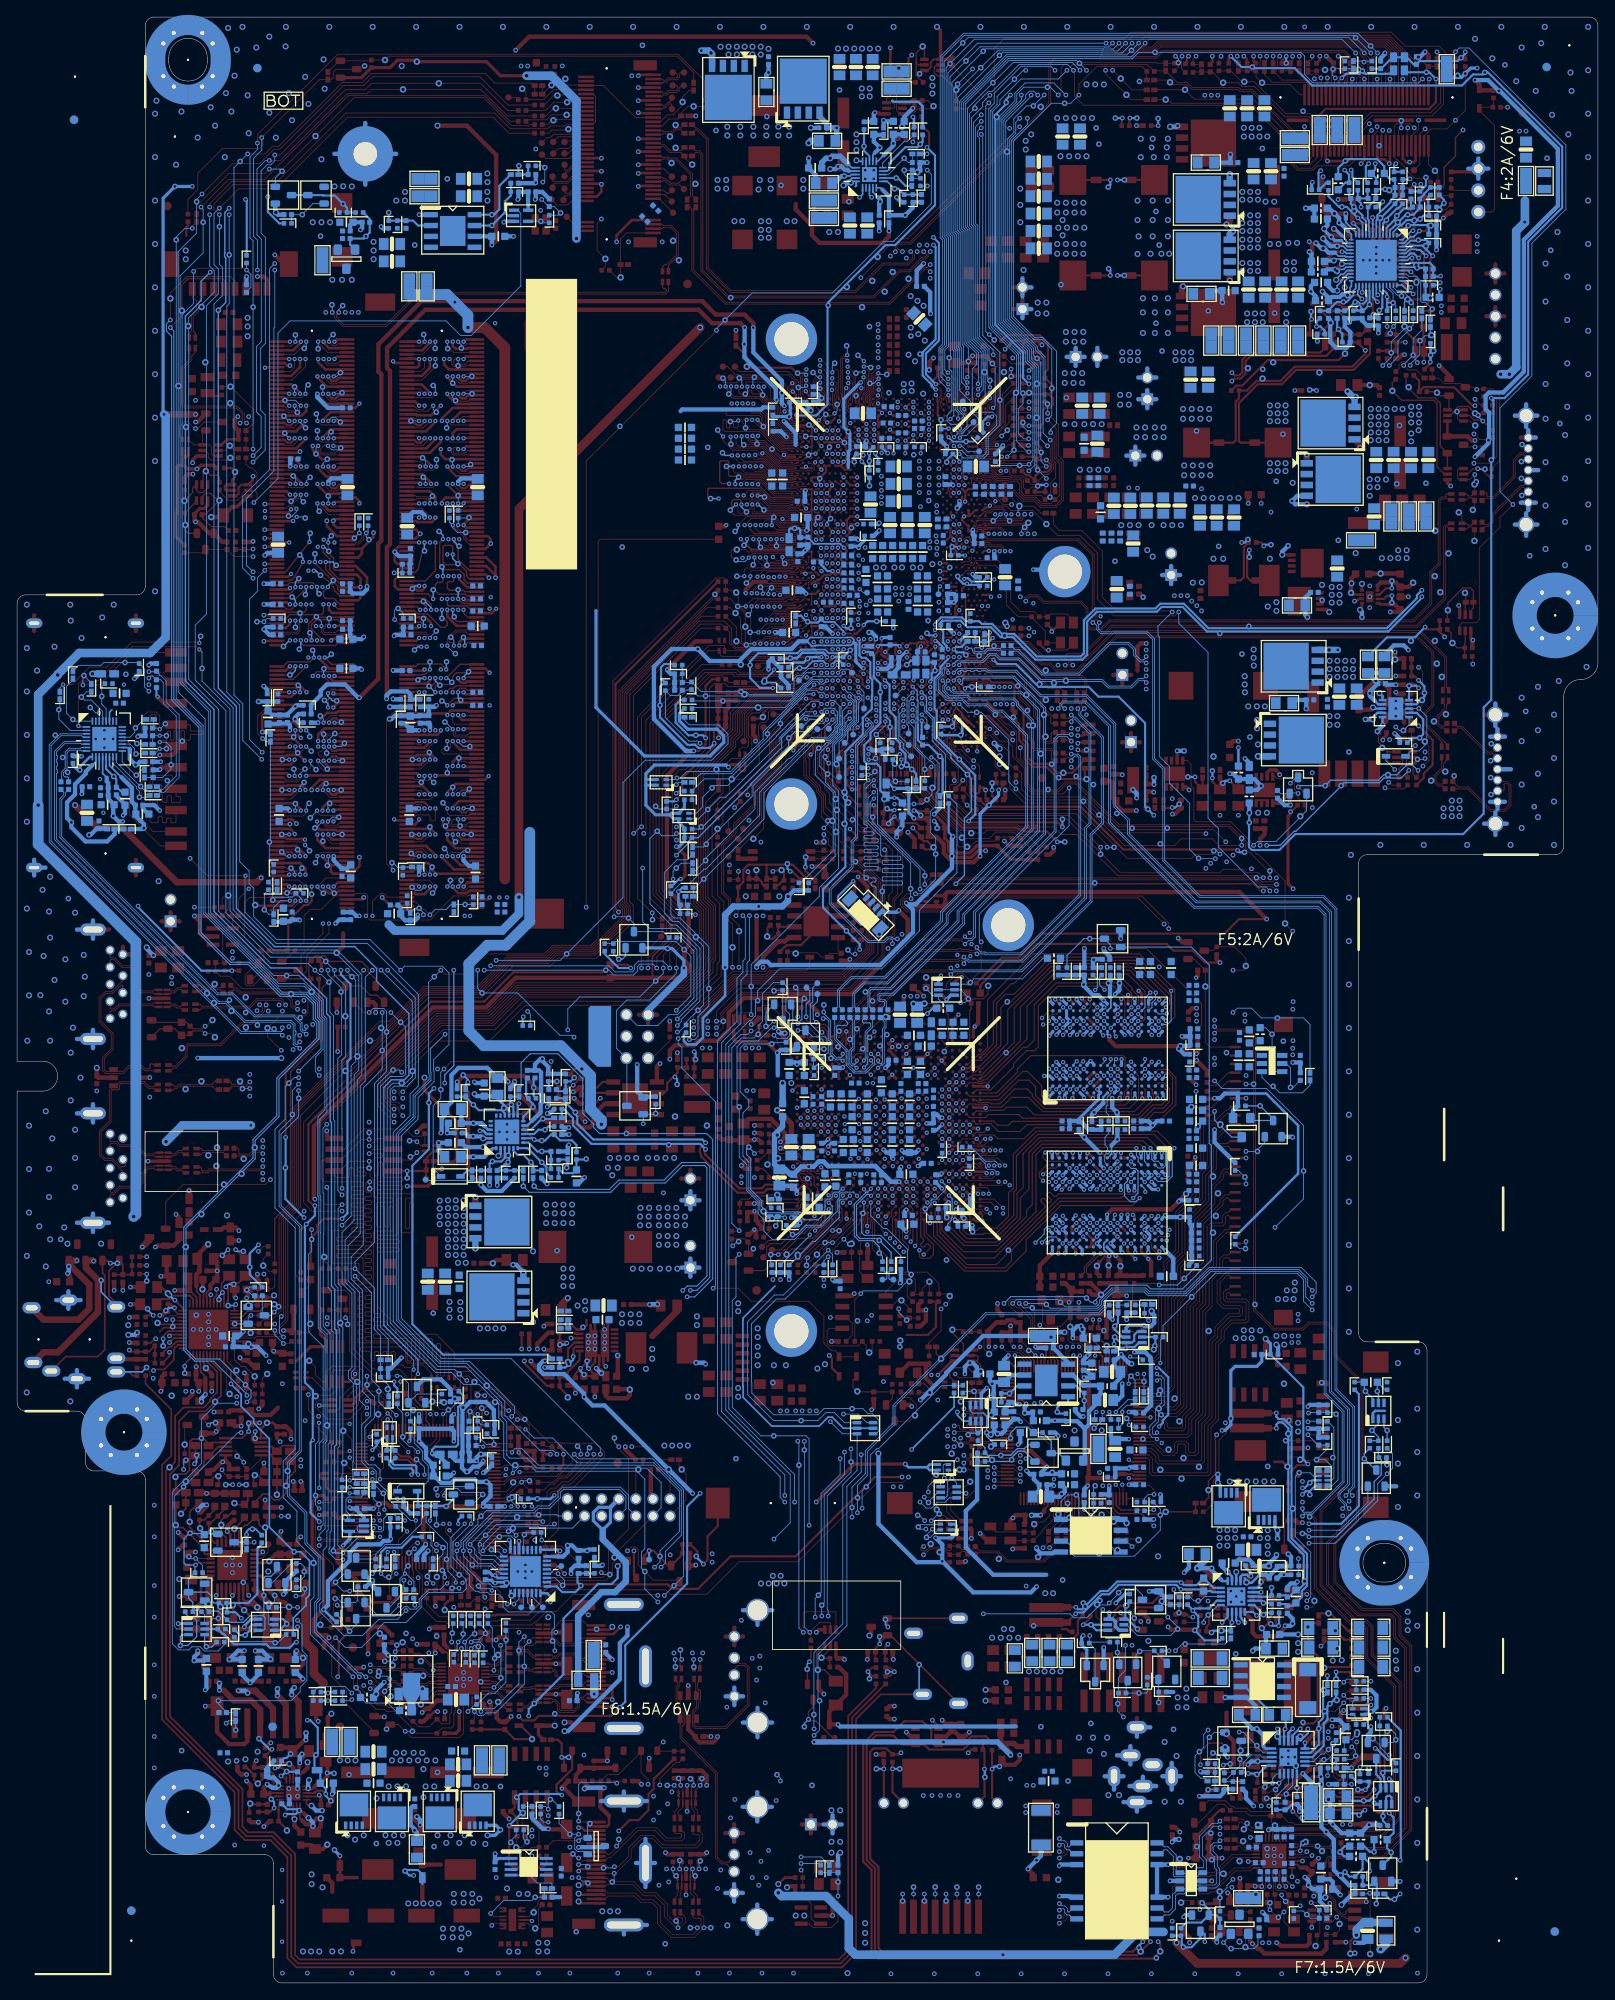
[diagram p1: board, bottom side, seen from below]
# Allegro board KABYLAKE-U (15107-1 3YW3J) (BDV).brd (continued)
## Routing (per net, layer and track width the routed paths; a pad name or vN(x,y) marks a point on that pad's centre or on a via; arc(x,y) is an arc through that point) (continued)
GND_AUD: length 7.9
  TOP w0.203: 164.02,81.52 163.99,81.49 163.99,80.9 163.59,80.5 U11.40
  TOP w0.508: v4(162.64,86.42) 163.91,85.15 C109.1 163.67,84.47 C113.2 163.67,83.23 164.02,82.89 164.02,81.52
PVCC_3V3: length 51.1
  TOP w0.203: 53.63,58.99 54.83,58.99 v1(54.9,59.05) ; SCA1.40 64.77,73.01 64.57,73.21 64.57,74.08 64.69,74.19 ; v3(59.36,54.71) 59.57,54.92 SCA1.108 ; 53.63,66.19 52.38,66.19 v1(52.36,66.17) ; v1(54.9,61.21) 54.67,60.99 53.63,60.99
  TOP w0.508: v1(71.28,74.42) 71.28,76.01 R325.1 70.39,77.28 C127.1 69.36,77.28 69.09,77.55 68.41,77.55 68.14,77.28 R321.1 R329.2 66.58,76.09 64.69,74.19
  L4 w0.508: v1(54.25,73.8) 54.26,73.81 54.26,74.09 55.82,75.64 60.76,75.64 61.19,76.07 63.1,76.07 63.74,75.44 70.4,75.44 71.28,74.56 v1(71.28,74.42)
  BOTTOM w0.356: U33.8 56.08,54.46 59.07,54.46 59.32,54.71 v3(59.36,54.71)
  BOTTOM w0.508: v1(54.25,73.8) 52.98,73.8 52.37,73.19 R716.2 52.28,72.81 52.28,67.58 C542.2
  vias: v2(53.25,63.63)
V0.85A_VID0: length 11.9
  TOP w0.102: v1(88.27,150.55) 88.6,150.87 CPU1.AN11
  BOTTOM w0.102: v1(88.27,150.55) 87.79,150.07 87.38,150.07 87.14,149.83 87.14,147.76 87.83,147.08 87.83,146.89 88.21,146.51 88.21,146.04 89.34,144.92 89.34,142.9 88.81,142.37 TP73.1
V0.85A_VID1: length 8.4
  TOP w0.102: v1(88.27,151.46) 88.6,151.79 CPU1.AN13
  BOTTOM w0.102: TP69.1 87.83,145.4 87.83,146.35 87.45,146.73 87.45,146.92 86.76,147.61 86.76,149.99 86.94,150.17 86.94,150.47 87.48,151 87.81,151 v1(88.27,151.46)
VBAT1: length 12.1
  TOP w0.254: R426.1 106.21,51.31 105.37,50.47 105.37,49.68 v3(104.68,49) 104.2,49.48 104.2,52.25 103,53.45 BT1.1
  BOTTOM w0.254: v2(105.52,49.91) 105.52,49.83 v3(104.68,49)
VBAT1_R: length 8.8
  TOP w0.254: R426.2 R430.1 107.16,50.13 Q40.G 108.78,48.83 110.52,50.57 v3(111.03,50.57) 111.61,50 D7.2
  BOTTOM w0.254: TP53.1 v3(111.03,50.57)
VCC: length 325.9
  TOP w0.254: R233.1 149.64,117.41 149.64,110.49 153.58,106.55 v3(153.58,98.93)
  TOP w0.381: v3(91.47,56.26) 87.03,60.71 v3(81.06,60.71) ; D9.A 123.99,29.02 R475.1
  TOP w0.508: v3(123.22,72.77) 122.97,73.03 PR80.2 ; D9.A v5(122.08,30.1) ; PR87.1 v3(118.65,68.55) ; PU11.6 116.24,102.87 PC91.1 117.56,101.55 117.56,100.53 117.99,100.1 119.06,100.1 119.69,100.74 122.99,100.74 127.44,105.19 127.44,105.36 v3(127.54,105.46)
  TOP w1.016: v5(22.51,2.92) 23.15,2.29 46.9,2.29 v5(49.31,4.7)
  L3 w0.381: v3(105.95,57.28) 105.35,57.87 93.09,57.87 v3(91.47,56.26)
  L3 w0.508: v3(105.95,57.28) 106.98,58.3 112.91,58.3 LPC1.8
  L4 w0.254: v3(156.75,86.36) 154.59,86.36 v3(151.42,89.53)
  L4 w0.381: v3(127.54,105.46) 128.32,104.69 135.17,104.69 139.82,100.04 141.85,100.04 143.29,101.47 144.31,101.47 146.85,98.93 v3(153.58,98.93)
  L4 w0.508: v3(123.22,72.77) 123.23,72.78 123.77,72.78 124.54,72.01 131.99,72.01 137.92,77.94 137.92,94.39 135.45,96.86 135.45,99.4 v3(135.42,99.44)
  L4 w1.016: 121.22,5.11 121.22,16.61 120.84,16.99 120.84,19.77 120.35,20.26 120.35,27.03 122.08,28.76 v5(122.08,30.1)
  BOTTOM w0.254: v3(151.42,89.53) 153.6,91.72 v2(153.6,95.38) 153.6,95.61 153.58,95.63 v3(153.58,98.93) ; v3(156.75,86.36) 157.77,85.34 v2(157.77,83.74) 157.77,82.87 R704.1
  BOTTOM w0.305: 78.52,60.33 78.19,60 RN19.4 ; 78.52,60.33 80.68,60.33 v3(81.06,60.71) ; 78.52,60.33 78.19,60.65 RN19.3
  BOTTOM w0.381: 115.56,53.89 116.47,52.98 117.56,54.08 117.56,55.03 116.95,55.65 115.56,55.65 115.56,53.89
  BOTTOM w0.508: v3(105.95,57.28) 116.24,67.56 117.66,67.56 v3(118.65,68.55) 118.65,68.92 120.98,71.25 123.42,71.25 123.91,71.74 123.91,72.28 123.42,72.77 v3(123.22,72.77) ; v3(135.42,99.44) 135.31,99.54 135.31,101.15 134.98,101.48 PR216.1 134.17,103.05 134.17,106.22 133.33,107.06 129.98,107.06 PR208.1 127.95,105.87 v3(127.54,105.46) ; LPC1.8 115.56,55.65
  BOTTOM w0.762: F6.1 119.34,42.97 116.59,45.72 115.02,45.72 113.76,46.98 113.76,49.21 116.47,51.92 116.47,52.98
  BOTTOM w1.016: v5(11.39,188.21) v5(10.37,188.21) 9.56,189.03 9.56,204.98 8.54,205.99 ; 8.54,208.53 8.54,205.99 ; 8.54,205.99 v2(8.57,206.02)
  vias: v2(36.81,110.19) v2(122.08,31.5) v3(35.68,110.24) v3(35.72,109.35) v3(35.72,108.58) v5(22.26,43.43) v5(22.26,42.29) v5(22.26,41.27) v5(85.76,6.99) v5(85.76,5.84) v5(85.76,4.7) v5(92.87,7.87) v5(93.89,7.87) v5(122.97,4.7) v5(122.97,3.68) v5(123.99,4.7) v5(123.99,3.68)
VCC3: length 1121.6
  TOP w0.203: 135.16,38.73 134.78,38.73 134.55,38.5 U17.11 ; U11.7 158.58,76.25 v3(158.53,76.2) ; 158.53,74.17 159.01,74.65 U11.11 ; KBC1.4 131.94,48.34 131.61,48.01 ; v3(133.26,31.75) 133.35,31.84 U17.37
  TOP w0.254: v3(38.77,124.46) 42.01,124.46 43.7,122.77 65,122.77 67.81,119.96 69.74,119.96 R235.1 ; F2.1 162.39,185.67 161.16,185.67 R97.1 ; v3(71.66,139.57) 71.66,138.62 R165.1 ; R433.1 76.61,49.21 v3(76.73,49.33) ; v3(101.04,137.52) 101,137.56 101,137.6 R166.2 ; v5(154.92,80.44) 155.16,80.2 R312.1 ; RN18.4 100.46,141.96 100.28,141.78 99.92,141.78 99.81,141.89 RN18.3 ; R434.2 121.95,48.9 v3(120.94,47.88) ; R400.1 74.71,53.15 R425.1 77.44,52.01 v3(77.5,52.07) ; R224.1 153.26,120.9 153.26,124.27 151.42,126.11 150.95,126.11 150.53,126.54 v1(150.53,128.27) ; R167.2 74.26,138.24 v3(73.82,137.79) 73.31,137.29 R172.2
  TOP w0.305: R160.1 87.98,140.31 87.3,139.64 v1(87.28,139.64) ; v1(140.87,70.36) 143.53,70.36 145.45,68.44 145.45,67.94 145.83,67.56 Q36.2 ; RN1.1 83.4,222.18 83.6,222.38 83.6,222.63 83.4,222.83 RN1.2 v3(82.8,226.41) ; R225.1 R224.1 ; R9.1 32.58,224.94 32.55,224.94 v3(32.55,225.43) ; R76.2 20.29,188.82 19.62,189.49 v3(19.62,189.64) ; DIMM2.255 144.66,126.78 v3(144.43,127) ; R292.2 149.66,83.22 149.66,79.08 R315.1 149.52,78.54 149.52,75.87 148.84,75.18 U12.1 ; v1(129.7,127) 129.92,126.78 DIMM1.255 ; v3(71.66,139.57) 71.95,139.86 RN16.3 72.38,139.36 72.55,139.19 72.85,139.19 73.03,139.37 RN16.4 ; v3(149.64,67.56) Q36.5
  TOP w0.356: RN17.1 76.54,127.2 76.36,127.38 ; RN17.2 77.41,125.99 77.38,125.96 ; RN18.4 101.45,142.55 v3(101.76,142.24)
  TOP w0.381: R164.2 R162.2 86.77,139.64 v1(87.28,139.64) ; R188.1 R189.1 68.66,131.43 R192.1 70.29,133.06 72.66,133.06 73.52,132.21 75.04,132.21 75.47,132.64 v3(75.47,134.12) ; R473.1 133.64,29.21 133.26,29.59 v3(133.26,31.75) ; v3(134.91,31.75) 134.97,31.69 R467.1 ; v1(107.35,129.16) 107.22,129.16 106.84,129.54 106.84,131.95 v3(107.84,132.95) ; 131.61,48.01 131.03,47.43 C195.1 130.46,46.67 C196.1 130.44,46.2 130.44,45.29 v3(130.26,45.11) ; R102.2 14.19,178.75 v3(14.38,178.56) ; 152.31,72.77 150.63,74.44 U12.1
  TOP w0.508: R524.2 40.67,4.83 v3(40.42,4.57) 39.85,4 39.59,4 39.02,3.43 32.34,3.43 31.78,3.99 R527.1 ; L13.1 160.05,66.99 C157.1 157.73,66.99 C159.1 157.18,66.45 155.33,66.45 154.47,67.31 ; R381.1 110.84,56.88 LPC1.4 ; C138.1 158.08,73.72 158.53,74.17 ; v3(14.38,222.63) 13.88,222.12 D1.K 13.69,221.42 R33.1 ; R332.1 R324.1 57.5,77.98 57.75,78.23 59.35,78.23 59.85,77.73 v1(59.85,77.6) 60.17,77.91 R316.1 ; v3(136.05,38.61) 136.11,38.67 C214.1 136.05,39.62 135.16,38.73 ; 77.88,69.98 78.65,70.74 78.65,72.07 R342.1 80.64,72.45 Q35.S ; v3(46.64,21.84) 46.13,21.84 45.37,22.61 R501.1 ; v3(98.46,118.82) v3(98.46,124.84) ; v3(38.77,124.46) 41.94,127.64 76.11,127.64 76.36,127.38 76.36,126.34 76.74,125.96 80.55,125.96 v3(80.94,126.35)
  TOP w0.762: v5(178.21,137.79) 175.55,135.13 172.64,135.13 166.29,128.78 156.95,128.78 v3(156.45,129.29) ; v3(164.12,183.51) v3(167.8,183.51)
  L3 w0.254: 119.73,45.91 120.94,47.12 v3(120.94,47.88) ; v3(158.28,208.66) 157.95,208.98 v3(155.66,208.98)
  L3 w0.305: 15.15,181.61 16.1,182.57 16.1,185.38 16.11,185.39 16.11,185.95 19.62,189.46 v3(19.62,189.64)
  L3 w0.381: v3(71.66,139.57) 73.44,137.79 v3(73.82,137.79) ; 15.15,181.61 15.15,179.32 v3(14.38,178.56) ; 107.48,129.79 107.48,129.92 101.04,136.36 v3(101.04,137.52) 99.53,136.02 v3(99.35,136.02) ; v3(158.28,208.66) 159.8,210.19 v3(164.5,210.19)
  L3 w0.508: v1(59.85,77.6) 65.01,77.6 65.04,77.62 76.33,77.62 v3(83.6,70.36) ; v3(98.46,124.84) 98.46,127.76 99.86,129.16 v1(107.35,129.16) 107.35,129.67 107.48,129.79 108.77,129.79 110.2,128.36 128.34,128.36 v1(129.7,127) ; v3(40.42,4.57) 40.42,4.98 45.47,10.03 46.56,10.03 48.19,11.66 48.19,13.06 46.01,15.24 46.01,21.21 v3(46.64,21.84) 47.73,22.94 47.73,29.54 54.52,36.32 v3(54.52,39.5) ; LPC1.4 109.55,57.67 107.87,57.67 106.33,56.13 105.62,56.13 98.21,48.72 98.16,48.72
  L3 w0.762: v3(164.12,185.17) v3(164.12,183.51)
  L3 w1.27: v5(84.2,61.94) 84.33,61.81 84.33,55.33 86.85,52.81 89.21,52.81 92.39,49.63 97.25,49.63 99.92,46.96 118.68,46.96 v5(122.84,42.8)
  L4 w0.305: v3(14.38,222.63) 14.38,223.27 14.89,223.77 28.1,223.77 29.12,224.79 31.94,224.79 32.55,225.4 v3(32.55,225.43) ; v3(75.47,134.12) 74.2,135.39 74.2,137.41 v3(73.82,137.79) ; v3(46.64,21.84) 46.64,21.72 45.5,20.57 42.74,20.57 42.24,20.07 37.12,20.07 34.58,17.53 33.31,17.53 30.13,14.35 v3(23.15,14.35) ; v3(82.8,226.41) 83.9,227.51 138.13,227.51 154.78,210.86 156.08,210.86 v3(158.28,208.66) ; v3(149.64,67.56) 151.29,65.91 v3(151.29,65.79)
  L4 w0.381: v1(87.28,139.64) 87.28,139.32 91.73,134.87 98.2,134.87 v3(99.35,136.02) ; v3(153.96,70.1) 153.7,70.36 v1(140.87,70.36)
  L4 w0.508: v3(54.52,39.5) 54.52,39.33 55.26,38.58 59.16,38.58 65.69,45.11 v3(65.69,46.35) ; v3(38.77,124.46) 38.29,124.46 34.25,128.5 34.25,133.45 29.85,137.85 24.07,137.85 18.64,143.27 18.64,159.88 13.93,164.59 13.93,175.21 13.27,175.87 13.27,177.98 13.75,178.46 14.28,178.46 v3(14.38,178.56)
  L4 w0.711: v3(77.25,68.2) 72.26,68.2 72.16,68.1 68.66,68.1 68.08,68.68 63.86,68.68 59.82,64.64 v5(58.07,64.64)
  L4 w0.762: v5(84.2,61.94) 80.93,65.21 80.23,65.21 v3(77.25,68.2) ; v5(180.25,153.03) 176.31,153.03 v5(176.18,153.16)
  BOTTOM w0.203: 175.42,141.99 175.38,142.02 U28.11
  BOTTOM w0.254: v3(155.66,208.98) 155.66,207.21 154.31,205.87 R540.2 ; v3(23.15,14.35) 23.07,14.43 23.07,29.53 R826.1 ; v1(140.87,70.36) 140.87,69.9 140.5,69.53 R726.1 ; R628.2 75.98,134.63 v3(75.47,134.12) ; v3(158.28,208.66) 158.12,208.51 158.12,202.15 R541.1 ; v3(152.31,39.88) 152.43,39.88 153.09,39.22 155.43,39.22 155.84,39.62 159.62,39.62 160.83,40.83 160.94,40.83 R798.2 Q72.5 ; v1(107.35,129.16) 107.52,129.16 108.34,128.33 R877.1
  BOTTOM w0.305: PR190.1 19.59,190.45 v2(19.59,190.45) 19.59,190.45 19.59,189.66 19.62,189.64 v3(19.62,189.64) ; v3(138.46,44.2) 138.46,44.87 R784.2
  BOTTOM w0.356: R633.1 106.9,135.13 107.57,135.79 RN11.4 108.17,136.2 108.63,136.66 ; v3(77.5,52.07) 75.57,52.07 75.11,52.54 75.11,53.01 ; 108.63,136.66 110.28,136.66 111.41,137.79 ; 108.63,136.66 108.44,136.85 RN11.3 106.9,137.51 R626.2 ; RN10.3 111.36,140.79 111.41,140.84 ; 111.41,140.08 111.36,140.14 RN10.4 ; 75.11,53.01 75.09,53.03 75.09,53.53 75.23,53.67 RN15.2 ; 75.11,53.01 RN15.1
  BOTTOM w0.381: 111.41,137.79 111.41,141.48 110.4,142.49 102.01,142.49 v3(101.76,142.24) ; v3(164.5,210.19) v2(166.53,210.19) 167.91,208.8 167.91,183.63 v3(167.8,183.51) ; R633.1 R634.1 106.9,133.57 107.52,132.95 v3(107.84,132.95)
  BOTTOM w0.508: v3(46.64,21.84) 44.23,21.84 43.78,22.29 R842.1 43.72,22.67 R841.1 ; v3(75.47,134.12) 75.6,133.99 v2(75.6,131.83) 75.6,130.44 79.84,126.2 80.79,126.2 ; 157.61,74.42 156.88,74.42 v3(155.86,73.41) ; 157.61,74.42 C531.1 159.67,74.49 159.67,75.44 C529.1 159.04,75.69 v3(158.53,76.2) ; 157.61,74.42 v2(157.59,74.4) ; v3(65.69,46.35) 66.35,45.69 73.1,45.69 v3(76.73,49.33) ; v3(80.94,126.35) 80.79,126.2 ; 80.79,126.2 80.15,125.56 80.15,122.93 83.98,119.1 96.81,119.1 97.19,119.48 97.97,119.48 98.46,118.99 v3(98.46,118.82) ; v5(84.2,61.94) 84.2,53.71 79.71,49.23 76.83,49.23 v3(76.73,49.33) ; v3(76.73,49.33) 76.73,51.3 v3(77.5,52.07) ; v3(14.38,222.63) 12.86,222.63 v2(11.59,221.36) 11.46,221.36 4.69,214.59 4.69,214.11 4.69,214.11 4.69,207.92 8.67,203.93 8.67,188.49 11.08,186.08 12.75,186.08 13.14,185.69 13.14,184.12 12.73,183.72 12.73,180.57 v2(12.81,180.49) 12.81,180.14 v3(14.38,178.56)
  BOTTOM w0.762: v5(176.18,153.16) R584.1
  BOTTOM w1.016: v5(182.53,137.79) 182.53,150.75 v5(180.25,153.03) 180.25,153.09 177.73,155.6 169.43,155.6 167.61,157.42 167.61,183.32 v3(167.8,183.51)
  BOTTOM w1.27: v5(182.53,137.79) 182.53,133.22 171.1,121.79 171.1,89.92 v5(171.36,89.66)
  vias: v2(135.9,40.56) v3(136.81,38.61) v3(151.8,61.21) v3(151.8,60.45) v3(155.48,72.69) v5(125.26,10.41) v5(126.27,10.41) v5(160.43,89.79)
VCC3_CAM:
  vias: v4(162.97,189.61)
VCC5_33_CT1: length 4.9
  TOP w0.102: C277.1 123.96,8.72 123.96,6.73 124.32,6.38 v4(124.37,6.38) 124.8,6.81 125.08,6.81 125.24,6.97 U26.12
VCC5_33_CT2: length 3.8
  TOP w0.102: U26.10 125.12,7.77 124.63,8.26 v4(124.54,8.26) 124.54,8.64 124.04,9.15 124.04,9.54 C273.1
VCC5_33_EN: length 12.5
  TOP w0.102: v3(129.45,6.73) 129.21,6.97 U26.3 ; v3(129.57,8.13) 129.21,7.77 U26.5
  L4 w0.127: v3(129.45,6.73) 129.45,8 v3(129.57,8.13)
  BOTTOM w0.102: R861.1 C615.1 v2(124.37,10.03) 124.75,9.65 128.05,9.65 v3(129.57,8.13)
VCC5_PANEL: length 36.1
  TOP w0.381: R258.1 44.93,103.44 v3(44.86,103.5)
  L4 w0.381: v3(44.86,103.5) 44.27,104.1 44.27,106.85 v3(44.86,107.44)
  BOTTOM w0.305: 42.07,104.06 38.82,104.06 35.09,100.33 35.09,94.68 R693.1
  BOTTOM w0.508: Q55.S 42.71,102.04 R675.1 42.13,104 42.07,104.06 43.67,104.06 44.23,103.5 v3(44.86,103.5)
  vias: v2(43.47,108.84) v3(44.86,108.2)
VCC_CORE: length 25.2
  TOP w0.254: CPU1.A44 71.85,169.67 71.43,169.67 v1(71.31,169.54) ; CPU1.A34 71.7,164.88 71.03,164.21 v1(70.65,164.21) ; v1(71.28,167.55) 71.82,167.55 CPU1.A39 ; v3(77,166.09) CPU1.J37 ; v1(71.03,162.18) 71.25,162.4 CPU1.A30 ; v3(77,164.26) CPU1.J33
  TOP w0.305: PG12.2 PL4.2
  TOP w0.508: 53.08,178.69 PT10.1 ; PT10.1 54.14,177.63 ; PT10.1 54.14,179.74 ; PT10.1 55.19,178.69 ; PT8.1 52.74,186.35 ; PT8.1 52.74,184.24 ; PT8.1 53.79,185.29 ; PT8.1 51.68,185.29
  BOTTOM w0.508: PT10.1 55.19,178.69 ; PT10.1 54.14,177.63 ; PT10.1 54.14,179.74 ; PT10.1 53.08,178.69 ; PT8.1 52.74,186.35 ; PT8.1 53.79,185.29 ; PT8.1 51.68,185.29 ; PT8.1 52.74,184.24
  vias: v1(68.63,171.83) v1(68.74,169.54) v1(68.74,167.51) v1(70.54,171.83) v1(70.65,169.54) v1(86.01,166.5) v1(86.52,167) v1(86.52,165.86) v1(86.52,164.97) v1(86.52,164.21) v2(46.97,181.58) v2(64.12,173.84) v2(75.85,165.61) v3(65.95,169.54) v3(66.33,171.83) v3(77.38,168.61) v3(77.35,167.84) v3(77.38,167.13) v3(77.46,169.29) v5(45.37,177.55) v5(45.37,176.4) v5(45.5,184.15) v5(45.5,183.01) v5(46.39,177.55) v5(46.39,176.4) v5(46.52,184.15) v5(46.52,183.01) v5(47.4,177.55) v5(47.4,176.4) v5(47.53,184.15) v5(47.53,183.01) v5(48.42,177.55) v5(48.42,176.4) v5(48.55,184.15) v5(48.55,183.01) v5(50.83,181.99) v5(50.83,180.85) v5(51.85,181.99) v5(51.85,180.85) v5(52.99,181.99) v5(52.99,180.85) v5(54.01,181.99) v5(54.01,180.85) v5(54.9,185.8) v5(54.9,184.66) v5(55.91,185.8) v5(55.91,184.66) v5(77.88,165.99) v5(79.28,165.61) v5(80.17,165.61) v5(81.44,165.61) v5(82.33,165.61) v5(83.6,165.61) v5(84.49,165.61)
VCC_FAN: length 8.1
  TOP w0.381: R57.1 14.37,211.9 FANC3.2
  BOTTOM w0.508: FANC3.2 15.18,212.27 ; FANC3.2 14,211.09 ; FANC3.2 12.82,212.27 ; FANC3.2 14,213.45
  vias: v2(5.95,213.49)
VCCCORE_SENSE: length 65.2
  TOP w0.254: CPU1.E32 74.41,163.13 v1(73.83,163.71) ; v3(42.83,188.39) 42.53,188.09 41.97,188.09 41.61,188.45 41.61,189.92 40.77,190.75 32.49,190.75 PG8.2
  L3 w0.254: v3(53.88,174.88) 53.62,174.62 52.61,174.62 49.94,177.29 49.94,186.97 48.83,188.09 43.14,188.09 v3(42.83,188.39)
  L4 w0.254: v1(73.83,163.71) 73.66,163.88 72.48,163.88 71.79,163.19 69.07,163.19 58.53,173.74 54.9,173.74 53.88,174.75 v3(53.88,174.88)
  BOTTOM w0.254: v2(74.91,164.57) 74.91,164.34 74.29,163.71 v1(73.83,163.71) 73.7,163.58 72.49,163.58 R566.2
VCCCOREG0: length 1.6
  TOP w0.102: v1(77,163.4) 76.64,163.04 CPU1.K32
  BOTTOM w0.102: TP58.1 77.17,163.22 v1(77,163.4)
VCCCOREG1: length 1.7
  TOP w0.102: CPU1.AK32 86.57,162.89 v1(86.39,163.07)
  BOTTOM w0.102: TP57.1 85.99,162.66 v1(86.39,163.07)
VCCGT_SENSE: length 101.7
  TOP w0.089: v1(77.49,187.06) 76.78,186.35 76.78,185.58 76.79,185.54 76.84,185.4 76.84,185.4 76.84,185.21 76.78,185.08 76.78,184.87 CPU1.J70
  TOP w0.254: PG4.2 20.53,210.24 v3(20.73,210.44) ; R69.2 76.74,189.93 76.74,187.45 77.14,187.06 v1(77.49,187.06)
  L4 w0.254: v3(77.76,204.22) 77.41,204.57 77.41,210.03 68.11,219.33 59.12,219.33 56.2,222.25 48.55,222.25 47.91,222.88 34.67,222.88 27.05,215.26 22.86,215.26 20.99,213.39 20.99,210.69 v3(20.73,210.44)
  BOTTOM w0.254: v2(78.27,188.72) 78.64,188.72 ; 78.64,188.72 78.64,188.22 v1(77.49,187.06) ; 78.64,188.72 78.64,190.63 77.6,191.67 77.12,192.15 77.12,203.58 v3(77.76,204.22)
VCCIO_EN_C_1: length 19.4
  TOP w0.152: Q14.G 34.38,139.26 v3(35.05,139.93) ; Q13.6 21.62,142.66 21.62,141.41 R157.1 21.05,141.22 v3(21.05,141.86)
  BOTTOM w0.152: v3(21.05,141.86) 21.69,142.49 22.39,142.49 23.53,141.35 25.05,141.35 25.69,140.72 31.28,140.72 v2(31.91,140.08) 34.9,140.08 v3(35.05,139.93)
VCCIO_EN_C_2: length 4.5
  TOP w0.152: v4(24.57,141.33) 24.28,141.03 R159.2 23.3,142.01 22.87,142.45 22.87,143.1 23.15,143.38 Q13.2
VCCIO_EN_C_3: length 217.4
  TOP w0.152: R120.1 PC67.1 157.45,167.7 v3(157.39,167.77) ; R158.2 22.28,141.71 v3(22.13,141.86) 22.13,142.11 22.41,142.39 22.41,143.1 22.13,143.38 Q13.5
  L4 w0.152: v3(134.96,105.28) 134.87,105.28 133.69,106.46 122.09,106.46 118.91,109.65 118.91,111 113.67,116.23 82.77,116.23 71.24,127.76 45.05,127.76 40.28,132.52 39.34,132.52 v3(38.77,133.1) ; v3(157.39,167.77) 158.73,166.42 158.73,127.67 153.76,122.69 137.21,122.69 133.89,119.38 v3(133.89,118.49)
  BOTTOM w0.152: v3(38.77,133.1) 37.2,133.1 35.56,134.74 35.35,134.74 30.06,140.03 v2(30.06,140.08) 29.7,140.44 25.57,140.44 25.04,140.97 23.02,140.97 v3(22.13,141.86) ; v3(134.96,105.28) 134.96,106.25 133.89,107.31 v3(133.89,118.49)
VCCIO_EN_C_4: length 6.2
  TOP w0.152: PR47.2 25.69,146.24 25.69,145.16 25.23,144.7 v4(25.23,144.5) 25.03,144.5 24.67,144.15 ; 24.67,144.15 24.66,144.16 24.53,144.03 Q13.3 ; 24.67,144.15 24.67,143 24.4,142.73 Q13.1
VCCIO_VR_FB: length 2.5
  TOP w0.254: CPU1.AM23 87.95,158.45 v1(88.27,158.78)
  BOTTOM w0.254: v1(88.27,158.78) 87.99,158.5 v2(87.41,158.5) R567.2
VCCK_1V1: length 43.5
  TOP w0.203: v1(59.72,58.17) 59.72,57.78 59.97,57.53 SCA1.109 ; 55.31,59.54 54.56,59.54 54.41,59.39 53.63,59.39 ; SCA1.51 60.37,71.05 v1(60.15,70.83)
  TOP w0.508: v1(60.15,70.83) 59.6,70.27 59.6,59.31 59.72,59.18 ; 59.72,59.18 v1(59.72,58.17) ; 59.72,59.18 59.6,59.05 56.68,59.05 56.19,59.54 55.31,59.54
  L4 w0.381: v1(60.15,70.83) 60.57,71.25 v1(74.07,71.25)
  BOTTOM w0.508: C559.2 60.1,57.78 v1(59.72,58.17) ; L31.2 72.68,72.06 73.16,72.54 v2(73.49,72.54) 73.62,72.54 74.07,72.09 v1(74.07,71.25) ; v1(60.15,70.83) 59.38,70.83 C631.1 59.91,71.69 C534.2
VCCRTCEXT: length 6.1
  TOP w0.102: 97.44,148.84 97.09,149.2 95.66,149.2
  TOP w0.114: 95.66,149.2 94.62,150.25 CPU1.BB10
  TOP w0.254: C43.1 97.91,147.92 v4(97.72,148.11) 97.72,148.56 97.44,148.84
VCCSA_SENSE: length 103
  TOP w0.089: v1(77.58,158.93) 77.05,158.39 77.05,158.16 76.92,158.04 76.92,157.29 76.66,157.02 76.66,155.88 CPU1.H20
  TOP w0.254: v3(20.38,189.63) 20.35,189.65 PG9.2
  L3 w0.254: v3(20.38,189.63) 20.54,189.46 20.54,189.07 16.63,185.16 16.63,182.31 15.91,181.59 15.91,168.15 20.61,163.45 v3(20.61,162.94)
  BOTTOM w0.254: v2(40.85,158.72) 40.85,158.5 ; 40.85,158.5 24.7,158.5 21.18,162.02 21.18,162.37 v3(20.61,162.94) ; 40.85,158.5 45.58,158.5 48.45,161.37 51.21,161.37 51.77,160.81 58.79,160.81 60.15,159.44 60.15,155.56 60.52,155.19 65.66,155.19 68.3,157.84 69.73,157.84 70.89,159 72.11,159 72.42,159.32 R568.2 73.98,159.32 74.42,159.77 76.87,159.77 77.58,159.06 v1(77.58,158.93)
VCCSENSE_EDRAM_VR: length 2.2
  TOP w0.254: CPU1.AC63 83.32,179.2 v3(83.12,178.99)
  BOTTOM w0.254: v3(83.12,178.99) 83.14,178.99 83.79,179.64 R549.2
VCCSENSE_EOPIO_VR: length 6.3
  TOP w0.102: CPU1.AL63 87.56,179.83 87.1,179.83 86.8,179.53 86.8,179.32
  TOP w0.254: 86.8,179.32 86.8,178.82 86.14,178.16 v3(86.14,178)
  BOTTOM w0.254: v2(85.25,175.16) R555.2 85.31,176.09 85.76,176.53 85.76,177.62 v3(86.14,178)
VCCST_GD_1: length 6.2
  TOP w0.152: Q1.2 77.38,224.41 77.66,224.13 77.66,223.47 77.32,223.14 76.74,223.14 v4(75.09,221.49) R38.2
VCCST_GD_2: length 7.5
  TOP w0.152: Q1.5 79.54,224.41 79.79,224.66 ; 79.79,224.66 79.79,223.2 R29.1 ; 79.79,224.66 79.79,225.81 v4(79.03,226.57) 78.82,226.36 Q1.6
VCCST_GD_CPU: length 10
  TOP w0.089: 71.39,181.3 71.4,181.29 72.08,181.29 CPU1.B65
  TOP w0.102: 71.39,181.3 71.37,181.3 69.92,182.74 69.92,186.82 69.5,187.24 v4(69.5,188.47) R70.2
VCCST_GD_R: length 103.9
  TOP w0.102: v3(71.23,192.86) 70.71,192.34 R65.2 70.71,191.59 69.6,190.48 69.6,190.48 69.5,190.38 R70.1 68.66,189.47 U1.4 ; Q1.3 76.18,223.76 C633.1 71.28,220.03 v3(71.28,219.96) 70.65,220.6 70.65,226.31 69.5,227.46 55.41,227.46 54.63,228.23 24.18,228.23 22.54,226.59 18.56,226.59 17.81,225.85 R3.1
  BOTTOM w0.102: v3(71.28,219.96) 71.64,219.61 71.64,193.21 71.29,192.86 v3(71.23,192.86) 71.23,192.8 70.65,192.23 v2(70.65,192.23)
VCCSTG_EN: length 11
  TOP w0.102: v4(34.83,136.5) 34.26,137.07 R171.1 35.09,138.62 v3(35.09,139.17) 35.51,139.59 35.51,140.74 35.35,140.89 ; 35.35,140.89 37.51,140.89 37.72,141.11 U4.4 ; 35.35,140.89 Q14.D
  BOTTOM w0.102: v3(35.09,139.17) 35.15,139.23 35.97,139.23 D16.1 37.12,139.13 PC256.1
VCCSTU_EN: length 209.6
  TOP w0.102: R121.1 163.36,167.32 Q11.D PC68.1 159.61,166.88 v3(157.39,166.88) ; v3(40.29,133.1) 40.29,133.17 42.98,135.86 47.02,135.86 47.28,136.12 47.28,139.7 47.59,140.02 47.59,140.27 47.61,140.28 47.61,142.62 48.01,143.02 U3.4
  L4 w0.127: v3(119.83,110.65) 119.81,110.65 113.84,116.62 82.93,116.62 71.4,128.16 45.23,128.16 v3(40.29,133.1) ; v3(157.39,166.88) 157.86,166.41 157.86,164.14 157.83,164.12 157.83,128.78 158.34,128.27 158.34,127.83 153.6,123.09 137.04,123.09 132.45,118.49 v3(131.1,118.49)
  BOTTOM w0.102: D16.2 34.1,137.12 37.66,133.55 39.83,133.55 v3(40.29,133.1) ; v3(119.83,110.65) 120.05,110.87 121.48,110.87 126.44,115.82 v2(130.59,115.82) 131.1,116.33 v3(131.1,118.49)
VCCSTU_EN_C_1: length 5.6
  TOP w0.152: Q10.6 164.01,173.35 R116.1 165.4,170.68 v4(165.31,170.59) 165.31,169.95 164.97,169.61 Q11.G
VCCSTU_EN_C_2: length 4.2
  TOP w0.152: Q10.2 163.23,175.44 163.23,176.63 162.99,176.87 v4(162.91,176.87) 162.86,176.87 162.39,176.4 161.58,176.4 161.32,176.15 R109.2
VCCSTU_EN_C_3: length 9.8
  TOP w0.152: Q10.5 163.36,173.86 162.93,174.29 162.39,174.29 161.82,173.72 161.56,173.72 161.35,173.51 161.35,173.48 v4(161.32,173.46) 162.97,171.81 163.32,171.81 PC59.1 163.28,171.72 163.28,171.4 162.26,170.38 160.7,170.38 R118.1
VCCSTU_EN_C_4: length 6.6
  TOP w0.152: PR31.2 165.51,174.56 165.51,173.51 v4(165.41,173.41) 164.45,174.37 164.45,174.9 164.04,175.31 Q10.1 164.01,174.64 163.74,174.37 163.24,174.37 162.7,174.91 Q10.3
VDDQ_BLEED_R1: length 5.3
  TOP w0.406: Q9.6 157.99,173.97 159.25,172.72 159.8,172.72
  TOP w0.508: 159.8,172.72 R117.2 161.02,171.5 v4(162.29,171.5)
VDDQ_BLEED_R2: length 5.3
  TOP w0.254: R106.2 159.95,177.24 v4(159.49,176.78) 159.49,176.2 159.85,175.84 Q9.3 160.55,175.28 160.69,175.13 160.69,174.75 160.56,174.62 Q9.2
VSS_AY3: length 16.9
  TOP w0.089: CPU1.AY3 93.03,145.89 93.38,145.54 93.38,144.93 93.51,144.81 93.51,144.27
  TOP w0.102: 93.51,144.27 93.51,143.64 97.65,139.5 97.65,135.05 v4(98.84,133.86) 99.28,133.86 R193.2
VSS_AY71: length 12.4
  TOP w0.127: 93.8,188.4 93.32,187.93 93.32,185.75 93.2,185.62 CPU1.AY71
  TOP w0.254: 93.8,188.4 94.37,188.98 99.47,188.98 v4(99.6,189.1) 99.6,190.31 R66.2
VSSCORE_SENSE: length 66.7
  TOP w0.254: v4(40.95,188.93) 41.23,188.93 ; 41.23,188.93 41.23,189.76 40.62,190.37 31.78,190.37 30.89,191.26 PG7.2 ; 41.23,188.93 41.23,188.29 41.82,187.71 42.53,187.71 v3(42.83,187.4) ; v1(74.15,164.26) 74.41,164 CPU1.E33
  L3 w0.254: v3(54.9,174.92) 54.22,174.24 52.45,174.24 49.56,177.13 49.56,186.82 48.67,187.71 43.14,187.71 v3(42.83,187.4)
  L4 w0.254: v1(74.15,164.26) 72.32,164.26 71.63,163.58 69.23,163.58 58.69,174.12 55.06,174.12 54.9,174.27 v3(54.9,174.92)
  BOTTOM w0.254: v1(74.15,164.26) 74.07,164.34 73.69,164.34 73.31,163.96 71.98,163.96 R565.1
VSSGT_SENSE: length 101
  TOP w0.089: v1(77.49,186.42) 77.41,186.49 77.19,186.49 76.97,186.27 76.97,186.27 76.97,185.57 77.03,185.44 77.03,185.19 76.97,185.07 76.97,184.61 76.79,184.43 76.79,184.24 CPU1.J69
  TOP w0.254: v1(77.49,186.42) 77.62,186.42 78.01,186.82 78.01,187.26 77.31,187.96 R75.1 ; PG3.2 21.95,209.98 v3(21.5,210.44)
  L4 w0.254: v3(77.76,203.33) 77.03,204.06 77.03,209.87 67.95,218.95 58.96,218.95 56.04,221.87 48.39,221.87 47.75,222.5 34.83,222.5 27.21,214.88 23.02,214.88 21.37,213.23 21.37,210.57 v3(21.5,210.44)
  BOTTOM w0.254: v2(79.33,190.58) 79.03,190.58 ; 79.03,190.58 79.03,188.06 77.97,187 77.97,186.86 77.53,186.42 v1(77.49,186.42) ; 79.03,190.58 79.03,190.79 77.99,191.83 77.5,192.31 77.5,203.07 v3(77.76,203.33)
VSSIO_VR_FB: length 5.5
  TOP w0.127: 87,157.86 87.46,157.4 CPU1.AM22
  TOP w0.254: v1(85.92,158.88) 85.92,158.72 86.77,157.86 87,157.86 87,157.86
  BOTTOM w0.254: v1(85.92,158.88) 85.49,159.31 v2(84.41,159.31) R572.1
VSSSA_SENSE: length 103.2
  TOP w0.254: v1(76.03,156.03) 76.03,156.16 CPU1.H21 ; PG10.2 21.37,189.81 v3(21.14,189.57)
  L3 w0.254: v3(21.14,189.57) 20.92,189.36 20.92,188.91 17.02,185 17.02,182.16 16.29,181.43 16.29,168.31 21.24,163.35 21.24,162.81 v3(20.61,162.18)
  BOTTOM w0.254: 44.25,158.12 24.54,158.12 20.61,162.05 v3(20.61,162.18) ; 44.25,158.12 45.74,158.12 48.61,160.99 51.06,160.99 51.61,160.43 58.63,160.43 59.77,159.28 59.77,155.4 60.36,154.81 65.82,154.81 68.46,157.45 69.88,157.45 71.05,158.62 73.82,158.62 74.58,159.38 76.71,159.38 76.9,159.19 R573.1 76.9,158.4 76.61,158.12 76.61,156.82 76.22,156.43 76.22,156.22 v1(76.03,156.03) ; 44.25,158.12 v2(44.25,157.89)
VSSSENSE_EDRAM_VR: length 2.5
  TOP w0.254: v3(84.54,178.99) 84.54,179.1 84.23,179.4 CPU1.AE63
  BOTTOM w0.254: R556.1 84.23,178.44 84.54,178.74 v3(84.54,178.99)
VSSSENSE_EOPIO_VR: length 3
  TOP w0.254: CPU1.AJ62 85.96,179.09 v3(85.96,178.74)
  BOTTOM w0.254: v2(87.03,177.98) 87.03,178.63 R552.1 86.1,178.88 v3(85.96,178.74)
1D0V_S5: length 214.8
  TOP w0.381: v3(71.66,132.46) 72.54,132.46 73.3,131.7 75.25,131.7 75.98,132.43 75.98,133.46 76.42,133.9 R180.1 76.42,135.52 77.63,136.73 v3(77.68,136.73)
  TOP w0.508: PT12.1 56.71,153.03 ; PT12.1 54.6,153.03 ; PT12.1 55.66,151.98 ; 53.59,145.16 PT14.1 ; PT14.1 54.64,146.22 ; PT14.1 54.64,144.11 ; PT14.1 55.7,145.16 ; 53.88,153.54 53.88,156.34 53.5,156.72 v3(52.87,156.72) ; PR39.1 PC75.1 23.63,154.94 v4(23.73,154.84) v3(23.73,155.7)
  L4 w0.381: v3(41.31,143.26) 40.36,142.3 37.35,142.3 36.65,141.6 36.65,136.92 38.44,135.13 44.36,135.13 45.61,133.87 46.68,133.87 47.81,132.74 55.13,132.74 55.6,132.27 71.47,132.27 v3(71.66,132.46) ; PT12.1 54.01,154.69 54.01,157.99 53.02,158.98 22.87,158.98 16.44,165.41 16.44,178.99 15.7,179.73 15.7,192.95 15.72,192.97 15.72,215.8 13.72,217.79 13.72,223.62 v3(14.13,224.03)
  L4 w0.508: v3(23.73,155.7) 23.73,155.78 25.92,157.96 51.62,157.96 v3(52.87,156.72)
  BOTTOM w0.381: v3(14.13,224.03) 14.89,224.03 v2(15.53,223.39) 15.98,222.94 R533.1 ; v3(77.68,136.73) 77,137.41 R627.1
  BOTTOM w0.508: R615.1 40.8,142.75 v3(41.31,143.26)
  vias: v4(44.99,143.48)
1D2V_VCCSFR_OC: length 7.8
  TOP w0.254: v1(88.27,157.86) CPU1.AL23
  BOTTOM w0.203: C357.1 90.55,159.23 89.76,159.23 89.76,159.23 89.38,159.23 88.27,158.12 v1(88.27,157.86)
  BOTTOM w0.254: C357.1 91.31,159.16 92.39,159.16 v2(92.49,159.26) 92.56,159.26 93.26,159.96 R571.1
1D2V_VDDQ_CPUCLK: length 9.6
  TOP w0.254: CPU1.AM40 87.95,167.63 v1(88.24,167.92)
  BOTTOM w0.201: C319.1 92.44,169.09 91.72,168.37 91.34,168.37 91.33,168.38 89.82,168.38 89.81,168.37 89.43,168.37 89.42,168.38 88.7,168.38 v1(88.24,167.92)
  BOTTOM w0.254: C319.1 92.48,169.11 C320.1 93.35,170.03 93.51,170.18 v2(94.01,170.18) 94.52,170.18 94.65,170.05 R563.2
1D8V_EDRAM: length 2.9
  TOP w0.127: CPU1.G61 75.74,179.32 76.23,179.32 76.51,179.05 76.76,179.05 77.01,179.29 77.01,179.6 CPU1.H63
1D8V_S5: length 22.5
  TOP w0.508: R179.2 R178.1 R177.1 81.57,134.57 v3(82.08,134.06)
  L4 w0.762: v3(82.08,134.06) 85.43,134.06 90.97,128.52 94.64,128.52 95.79,127.37 v5(95.79,127.13)
  BOTTOM w0.508: R630.1 81.39,135.33 v2(81.62,135.1) 82.08,134.65 v3(82.08,134.06)
1D8V_SIP_S5: length 9.9
  TOP w0.254: CPU1.AA1 82.49,144.4 83.51,143.38 v4(83.51,138.51) 83.51,137.13 83.47,137.1 C68.1 83.6,136.84 R179.1
1D8V_VCCPGPPF: length 21.1
  TOP w0.254: CPU1.AF16 84.34,153.14 v1(84.23,153.14) ; v1(82.33,137.21) 82.84,136.7 82.84,135.95 R178.2
  L4 w0.254: v1(82.33,137.21) 82.32,137.21 81.03,138.5 81.03,144.42 82.86,146.25 82.86,150.39 83.98,151.51 83.98,152.88 v1(84.23,153.14)
  BOTTOM w0.254: v1(82.33,137.21) 83.01,137.21 v2(83.19,137.39)
1P8V_PWR_PG: length 78.6
  TOP w0.102: PR48.1 24.29,145.54 v3(24.37,145.46) ; R220.1 86.2,121.48 86.27,121.41 86.55,121.41 86.93,121.03 v3(86.93,120.37)
  L4 w0.127: v3(86.93,120.37) 86.93,120.37 86.58,120.02 85.08,120.02 74.07,131.03 47.23,131.03 45.53,132.73 45.01,132.73 43.75,133.99 37.96,133.99 34.87,137.08 34.87,137.8 31.83,140.84 28.99,140.84 24.89,144.95 v3(24.37,145.46)
  BOTTOM w0.102: v2(87.77,120.85) 87.28,120.37 v3(86.93,120.37)
2D5V_VPP: length 81.3
  TOP w0.508: 146.85,122.81 146.85,121.28 v4(147.61,120.52)
  TOP w1.27: v5(132.24,193.68) 130.27,193.68 127.92,191.33 127.92,129.16
  BOTTOM w0.508: C424.1 C423.1 147.29,124.4 v1(147.73,123.95)
  BOTTOM w1.27: PR175.2 PR176.2 134.65,197.54 v2(133.76,196.65) 132.24,195.12 v5(132.24,193.68)
  vias: v1(127.67,127) v1(128.56,127)
3D3V_1D8V_VCCHDA: length 105.2
  TOP w0.254: R122.1 114.97,151.96 114.97,125.65 v3(114.61,125.29) ; CPU1.AJ19 86.03,155.73 v1(85.91,155.73)
  L4 w0.254: v3(114.61,125.29) 113.11,126.8 101.82,126.8 99.73,128.89 95.76,128.89 95.16,129.49 94.33,129.49 94.27,129.54 91.26,129.54 85,135.8 85,135.99 v1(82.33,138.66)
  BOTTOM w0.254: v1(85.91,155.73) 85.21,155.73 C371.1 84.74,155.26 84.74,152.77 83.98,152.01 v2(83.98,151) 83.97,151 83.97,147.41 85.13,146.25 85.13,145.55 85.86,144.82 85.86,142.96 85.55,142.65 84.39,142.65 83.98,142.24 83.98,139.5 R622.2 83.14,138.66 v1(82.33,138.66) 82,138.66 R630.2
3D3V_1D8V_VCCPGPPA: length 32.7
  TOP w0.254: CPU1.AK15 87.07,152.81 86.63,152.37 v1(86.63,152.34) ; v3(96.55,130.05) 96.43,130.17 95.57,130.17 v4(95.54,130.2) 95.26,129.92 R209.2 95.34,128.99 95.89,128.45 96.11,128.45 R203.2
  L3 w0.203: v1(86.63,152.34) 87.09,151.88 87.09,149.47 87.39,149.17 87.73,149.17 88.3,148.6 88.3,148.24
  L3 w0.254: v3(96.55,130.05) 98.48,131.98 98.48,134.98 98.34,135.11 98.34,138.19 88.3,148.24
3D3V_1D8V_VCCPGPPD: length 23.3
  TOP w0.254: CPU1.Y15 81.9,152.81 v1(81.29,152.2) ; R181.2 79.79,135.7 R177.2 82.33,136.46 v1(82.33,136.47)
  L4 w0.254: v1(82.33,136.47) 80.65,138.15 80.65,144.88 82.17,146.4 82.17,148.14 81.83,148.48 81.83,151.66 v1(81.29,152.2)
  BOTTOM w0.254: v1(82.33,136.47) 82.89,135.92 82.89,135.76 v2(83.01,135.64)
3D3V_1D8V_VCCPSPI: length 40.6
  TOP w0.254: v3(94.52,130.05) 94.28,130.05 R207.2 R208.2 ; v1(85.94,153.16) 86.04,153.16 CPU1.AJ16
  L4 w0.254: v3(94.52,130.05) 94.52,130.43 94.78,130.68 99.73,130.68 99.98,130.94 99.98,135.18 99.88,135.29 99.88,136.65 93,143.53 93,143.54 90.47,146.06 86.78,146.06 86.06,146.79 86.06,153.04 v1(85.94,153.16)
  BOTTOM w0.254: v2(94.85,130.94) 94.85,130.38 v3(94.52,130.05)
3D3V_AUX_KBC: length 151.2
  TOP w0.305: Q41.D 144.01,44.86 143.7,44.86 143.37,44.53 141.05,44.53 140.56,45.02 R441.2 ; v3(122.59,61.85) 123.11,61.85 R372.1 R382.1 ; RN9.2 149.34,59.63 149.51,59.46 149.51,59.16 149.36,59.01 149.34,59.01 149.31,58.98 RN9.1 148.84,58 148.34,57.51 146.62,57.51 146.32,57.81 146.28,57.81 v1(146.08,58.01)
  TOP w0.381: v3(139.35,93.22) 136.91,93.22 136.24,93.89 R268.1
  TOP w0.508: Q41.D 145.07,46.86 146.08,47.88 ; 146.08,47.88 147.1,48.9 147.11,48.9 147.48,49.27 147.48,50.56 146.85,51.18 v1(146.85,51.18) ; 146.08,47.88 v3(143.42,47.88)
  L3 w0.305: v1(122.14,57.05) 122.14,61.37 122.38,61.62 122.38,61.65 v3(122.59,61.85)
  L3 w0.381: v3(139.35,93.22) 139.48,93.09 139.48,77.07 133.72,71.31 131.24,71.31 129.01,69.09 129.01,66.23 125.78,62.99 122.92,62.99 122.59,62.66 v3(122.59,61.85)
  L3 w0.483: v1(143.42,62.36) 143.67,62.36 144.04,61.99 144.04,51.69 143.42,51.06 v3(143.42,47.88)
  L4 w0.381: v1(136.43,61.98) 136.33,62.08 130.16,62.08 129.29,62.94 126.28,62.94 126.27,62.93 125.32,62.93 125.28,62.89 125.1,62.89 124.82,62.61 123.35,62.61 v3(122.59,61.85)
  L4 w0.508: v1(143.42,62.36) 140.5,62.36 139.61,61.47 136.94,61.47 v1(136.43,61.98)
  BOTTOM w0.254: RN13.2 141.06,62.6 PR105.1 PR106.1 141.71,62.35 RN13.1 142.24,63.79 142.72,63.31 R744.2 142.91,62.87 v1(143.42,62.36) ; v1(136.43,61.98) 136.43,62.36 136.05,62.74 133.64,62.74 133.38,62.99 133.38,67.36 132.77,67.97 132.77,68.69 R874.2 ; v1(146.08,58.01) 146.12,57.98 R759.1 146.97,53.09 146.7,52.82 U32.5 ; PR103.1 142.4,48.7 142.4,50.38 141.85,50.93 139.99,50.93 138.72,52.2 R447.2
  BOTTOM w0.305: 142.4,48.7 R777.1 143.04,48.26 v3(143.42,47.88) ; v1(122.14,57.05) 122.54,56.64 v2(124.11,56.64) R762.2
  BOTTOM w0.406: U32.5 146.06,51.97 v1(146.85,51.18)
  BOTTOM w0.508: R752.2 134.78,60.81 135.54,61.57 R748.2 136.3,61.85 v1(136.43,61.98)
3D3V_AUX_KBC_VCC: length 52.2
  TOP w0.203: v3(137.19,51.31) 137.94,50.56 KBC1.19 ; KBC1.115 130.32,55.9 v1(130.46,55.75) ; v1(143.29,55.5) 143.69,55.9 KBC1.46 ; v1(137.96,63.37) 138.26,63.37 138.74,63.86 KBC1.76 ; v1(133.89,63.37) 133.94,63.42 KBC1.88
  TOP w0.508: v1(143.29,55.5) 142.65,56.13 141.77,56.13 141.38,55.75 137.96,55.75 137.45,55.24 ; v1(130.46,55.75) 136.94,55.75 137.45,55.24 ; 137.45,55.24 137.45,51.83 137.19,51.57 v3(137.19,51.31)
  BOTTOM w0.508: C561.1 v1(130.46,55.75) 130.46,56.08 129.6,56.95 129.6,58.24 129.98,58.62 v2(130.08,58.62) 131.17,58.62 131.44,58.9 133.79,58.9 134.19,58.5 135.36,58.5 136.18,59.31 C555.1 R752.1 137.14,61.42 137.14,62.56 v1(137.96,63.37) C545.1 C546.1 133.89,64.58 v1(133.89,63.37) ; v3(137.19,51.31) 137.19,51.18 137.54,50.83 137.54,50.8 138.27,50.06 C566.1 ; C562.1 v1(143.29,55.5)
3D3V_VCCPDSW: length 277.9
  TOP w0.203: R216.2 108.49,122.24 110.65,120.08 110.65,117.73 110.52,117.6
  TOP w0.254: v3(105.82,144.15) 105.2,144.15 104.43,144.91 v3(104.43,145.67) 104.43,151.76 103.67,152.53 R135.1 ; 84.24,154.43 84.15,154.43 CPU1.AD17 ; 84.24,154.43 v1(84.26,154.43) ; 84.24,154.43 83.91,154.76 CPU1.AD18 ; CPU1.AJ17 86.04,153.81 v1(85.94,153.81)
  TOP w0.508: v3(105.82,144.15) 106.05,144.15 108.95,141.25 108.95,128.02 106.41,125.48 106.41,121.34 106.9,120.84 R226.1 106.9,119.63 106.31,119.04 106.31,118.47 107.18,117.6 R230.2 126.65,117.6 130.13,114.12 136.34,114.12 150.27,100.19 150.27,91.82 v3(150.15,91.69)
  L3 w0.508: v3(113.57,41.66) 113.57,41.78 114.19,42.39 117.03,42.39 119.17,40.26 122.7,40.26 123.67,39.29 125.47,39.29 128.81,42.63 128.81,43.28 129.96,44.42 131.1,44.42 131.35,44.68 133.64,44.68 134.73,45.77 140.29,45.77 141.36,46.84 141.36,48.04 140.24,49.16 140.24,50.68 140.62,51.06 140.62,52.49 141.19,53.06 141.19,55.72 141.82,56.35 141.82,63.55 143.29,65.02 143.29,71.58 147.92,76.21 147.92,86.17 149.39,87.63 149.39,91.1 149.98,91.69 v3(150.15,91.69)
  L4 w0.381: v1(85.94,153.81) 85.1,153.81 84.47,154.43 v1(84.26,154.43)
  L4 w0.508: v3(120.3,15.88) 119.95,16.23 119.95,19.41 119.46,19.89 119.46,20 119.46,27.99 v5(120.94,29.46)
  BOTTOM w0.178: 87.06,156.84 87.06,157.14 87.35,157.43 87.81,157.43 87.83,157.4 91.85,157.4 92.18,157.4 92.59,157
  BOTTOM w0.203: 87.06,156.84 87.41,156.49 87.73,156.49 87.74,156.49 88.73,156.49 88.73,156.49 91.51,156.49 91.59,156.41 92,156.41 92.59,157 92.62,156.97
  BOTTOM w0.254: v3(104.43,145.67) 104.73,145.97 v2(105.57,145.97) 106.44,145.97 107.93,147.46 107.93,149.53 107.35,150.11 R595.1
  BOTTOM w0.381: v1(85.94,153.81) 86.06,153.81 86.84,154.58 86.84,156.62 87.06,156.84
  BOTTOM w0.508: 92.62,156.97 93.51,156.97 94.41,156.07 99.08,156.07 100.49,154.66 103.94,154.66 v2(105.34,156.07) 108.4,156.07 110.47,153.99 110.47,147.88 106.73,144.15 v3(105.82,144.15) ; v5(120.94,29.46) 120.52,29.46 114.46,35.52 114.46,39.76 113.57,40.65 v3(113.57,41.66)
3D3V_VCCPGPPB: length 30.2
  TOP w0.254: v1(85.41,152.27) 85.41,152.27 85.51,152.37 CPU1.AG15 ; R210.2 92.74,130.11 v3(92.74,130.56)
  L4 w0.254: v1(85.41,152.27) 85.4,152.27 84.94,151.82 84.94,150.52 84.98,150.49 84.98,147.04 85.86,146.15 85.86,135.96 91.72,130.1 92.29,130.1 v3(92.74,130.56)
  BOTTOM w0.254: v3(92.74,130.56) 92.72,130.58 v2(92.72,131.72)
3D3V_VCCPGPPC: length 25
  TOP w0.254: v1(82.36,152.24) 82.52,152.39 82.52,153.09 CPU1.Y16 ; v3(80.17,135.13) 79.22,134.18 R184.2 79.22,133.89 78.9,133.58 78.47,133.58 v4(77.76,132.86) 78.01,132.61 78.73,132.61 C69.1
  L3 w0.254: v1(82.36,152.24) 82.39,152.24 82.86,151.77 82.86,143.79 81.41,142.34 81.41,136.35 80.19,135.13 v3(80.17,135.13)
3D3V_VCCPGPPE: length 20.7
  TOP w0.254: v1(80.09,152.4) 80.09,153.08 CPU1.T16 ; R175.2 79.98,137.1 v3(80.04,137.16) 80.36,136.84 C67.1
  L3 w0.254: v3(80.04,137.16) 80.65,137.77 80.65,145.9 80.7,145.94 80.7,151.84 80.13,152.4 v1(80.09,152.4)
  BOTTOM w0.254: v3(80.04,137.16) 79.81,137.16 v2(79.26,136.6)
3D3V_VCCPGPPG: length 13.8
  TOP w0.254: CPU1.AD15 83.44,152.42 v1(83.44,152.4)
  BOTTOM w0.254: v1(83.44,152.4) 82.9,151.85 82.9,148.8 82.18,148.08 82.18,145.54 81.67,145.03 81.67,144.42 81.03,143.79 81.03,142.72 v2(80.3,141.99) 79.79,141.48 R619.2
3D3V_VCCPRIM: length 42.6
  TOP w0.254: v1(81.76,155.73) 81.63,155.73 CPU1.V19 ; CPU1.AJ21 85.89,157.17 v1(85.89,157.23) ; R151.1 R161.2 70.9,139.97 v3(70.9,139.57) 70.9,138.87 C63.1
  L3 w0.254: v1(81.76,155.73) 81.76,155.69 81.77,155.67 81.77,146.54 81.03,145.8 81.03,136.51 80.19,135.66 79.95,135.66 79.69,135.4 75.07,135.4 v3(70.9,139.57)
  L4 w0.254: v1(81.76,155.73) 82.46,156.43 82.46,156.61 83.63,157.78 85.33,157.78 v1(85.89,157.23)
  BOTTOM w0.254: v3(70.9,139.57) v2(70.9,140.39)
3D3V_VCCPRTCPRIM: length 38.5
  TOP w0.254: CPU1.AK17 87.18,153.98 87.55,153.61 87.55,152.32 v1(87.53,152.3) ; C72.1 v4(98.48,130.2) ; C72.1 C73.1 99.35,129.9 v3(99.47,130.02) ; C72.1 98.22,129.17 97.82,128.78 97.82,128.6 97.51,128.28 R204.2
  L4 w0.254: v1(87.53,152.3) 87.18,151.95 87.18,151.81 87.07,151.7 87.07,150.85 87.02,150.81 87.02,150.14 86.88,150 86.88,147.47 87.18,147.17 91.98,147.17 92.15,147.33 92.55,147.33 98.97,140.91 98.97,138.1 100.42,136.65 100.42,130.74 99.7,130.02 v3(99.47,130.02)
3P3V_SPI: length 10.5
  TOP w0.254: U8.8 v3(139.35,95) 137.26,95 C103.1 ; RN5.1 135.49,97.99 135.29,97.79 135.29,97.54 135.49,97.34 RN5.2 136.27,97.34 137.13,96.48 R265.2 C103.1 ; C103.1 R268.2
  BOTTOM w0.254: v2(139.35,94.18) v3(139.35,95)
14MHZ_IN_SCALAR: length 10.9
  TOP w0.102: SCA1.118 63.57,55.88 64.12,55.33 64.12,54.69 64.89,53.92 65.72,53.92 v4(65.97,53.67) 65.97,52.74 R423.2 66.2,52.77 C184.1 67.99,52.77 70.47,52.77 X4.3
14MHZ_OUT_SCALAR: length 8.8
  TOP w0.102: SCA1.117 63.17,55.93 63.72,55.38 63.72,54.23 65.03,52.93 65.03,52.8 R423.1 66.1,51.73 C186.1 68.74,51.73 X4.1
1117_ADJ: length 8.5
  BOTTOM w0.102: U35.1 140.34,32.61 140.24,32.51 R822.2 140.75,31.88 141.61,32.74 144.15,32.74 R818.1 144.81,34.04 v2(145.32,34.54)
2136_HPD_C: length 6.7
  TOP w0.102: RN21.4 74.78,69.65 74.2,70.23 R347.2 R356.1 73.87,69.22 74.56,68.53 v4(74.56,68.03) 73.42,68.03 R363.2
+V_1P05_VGA: length 14.4
  TOP w0.305: v3(78.9,115.44) 79.1,115.65 79.1,115.67 79.43,116 79.66,116 R237.1
  L3 w0.254: v3(78.9,115.44) 77.86,114.4 77.86,113.27 78.98,112.15 78.98,106.78 v1(78.44,106.24)
  BOTTOM w0.762: v5(95.41,105.28) L23.2
  vias: v1(72.42,110.62) v1(74.3,108.68) v1(77.6,106.24) v1(84.84,105.28) v1(85.5,105.28) v2(76.49,108.97) v5(94.39,105.28)
+V_1P05_VGA_DISCHIG: length 3
  TOP w0.102: Q21.6 77.44,116.86 78.24,117.65 v4(78.62,117.65) 78.62,116.48 R237.2
+V_1P35_VGA: length 93.6
  TOP w0.203: GPU1.H26 73.25,95.04 73.65,95.43 74.31,95.43 GPU1.H24
  TOP w0.254: GPU1.L24 75.12,97.94 75.92,97.94 v1(75.93,97.94) 75.93,97.93 GPU1.L22
  TOP w0.305: VRAM2.G2 58.24,94.91 VRAM2.H3 ; GPU1.E26 73.05,92.55 72.77,92.55 v1(72.55,92.33) ; GPU1.H26 72.98,94.92 71.71,94.92 v1(71.53,94.74) ; v1(71.92,97.41) 72.66,97.41 72.77,97.52 GPU1.L26 ; v1(51.32,85.59) 51.84,86.11 VRAM2.T14 ; v1(56.21,88.91) 56.21,88.89 56.01,88.68 56,88.68 VRAM2.L11 55.04,87.71 VRAM2.M12 ; VRAM2.D1 61.44,97.09 61.45,97.1 v1(61.45,97.13) ; VRAM2.B3 63.04,94.89 v1(63.43,94.49) ; v1(72.55,89.53) 72.55,89.6 73.05,90.1 GPU1.B26 ; v1(53.31,103.49) 53.39,103.56 VRAM1.D1 ; VRAM2.B14 63.15,86 v1(63.15,85.34) ; VRAM2.F14 VRAM2.G14 ; VRAM1.F14 54.99,114.78 54.99,114.78 54.99,115.41 54.99,115.42 54.99,115.58 v1(54.97,115.6) ; VRAM2.F12 VRAM2.G13
  TOP w0.33: v1(60.39,115.18) 60.39,115.16 59.79,114.56 VRAM1.M14 ; v1(54.14,84.71) 55.04,85.61 VRAM2.M14
  TOP w0.356: VRAM1.D12 53.39,112.95 v1(53.79,113.35) ; v1(63.51,115.07) 63.3,114.86 63.3,114.86 VRAM1.T14 ; VRAM2.C10 62.61,89.69 v1(62.61,89.74) ; v1(57.83,94.52) 58.23,94.91 VRAM2.H3 ; VRAM1.G14 55.79,115.1 v1(55.77,115.12) ; v1(51.34,115.03) 51.42,114.95 51.42,114.91 VRAM1.B14 ; v1(54.64,107.77) 54.62,107.77 VRAM1.E5 ; VRAM1.N5 60.59,107.47 v1(60.23,107.82) ; v1(55.07,103.55) 54.99,103.63 54.99,103.93 54.99,103.93 VRAM1.F1 ; VRAM1.H12 56.59,112.94 v1(56.19,113.34) VRAM1.G13 ; VRAM2.F1 59.84,96.97 v1(59.72,97.08) 59.61,97.08 VRAM2.G1 ; v1(60.24,95.31) 59.84,94.91 VRAM2.F3 ; 58.59,114.14 VRAM1.L14 ; 58.59,114.14 v1(58.58,114.14) ; 58.59,114.14 58.98,113.74 VRAM1.L13 ; VRAM2.N5 54.25,93.3 v1(54.25,92.71) ; VRAM2.P12 53.05,87.32 v1(53.05,87.31) ; v1(55.82,97.09) 55.84,97.07 VRAM2.L1 VRAM2.M1 ; v1(54.41,89.86) 54.24,89.69 VRAM2.N10 ; VRAM1.M1 59.79,104.07 59.23,103.5 v1(59.11,103.5) 58.99,103.63 VRAM1.L1 ; VRAM1.T1 63,104.13 63,103.55 v1(63.02,103.53) ; VRAM1.F3 54.98,105.74 v1(54.59,105.34) ; v1(52.21,110.91) 52.21,110.96 VRAM1.C10 ; v1(58.58,113.32) 58.52,113.26 58.51,113.26 VRAM1.K12 ; v1(59.43,88.93) 59.43,88.91 VRAM2.G11 ; v1(53.79,111.73) 53.39,112.14 VRAM1.D11 ; v1(53,106.14) 53,106.12 VRAM1.D3 ; VRAM1.D14 53.39,115.71 v1(53.75,116.08) ; v1(62.59,110.91) 62.59,110.93 VRAM1.R10 ; VRAM1.P1 61.39,103.63 61.5,103.52 v1(61.5,103.5) ; v1(53.05,94.51) 53.05,94.52 53.44,94.91 VRAM2.P3 ; VRAM2.D12 61.57,87.85 61.57,88.38 VRAM2.D11 61.28,88.67 61.28,88.68 v1(61.03,88.92) ; VRAM1.C5 52.22,107.71 v1(52.22,107.78) ; v1(60.21,88.91) 60.61,89.31 VRAM2.E10 ; VRAM2.L13 55.84,86.92 v1(56.24,87.31) 56.63,87.71 VRAM2.K12 ; VRAM2.G4 59.42,93.73 v1(59.42,93.71) ; VRAM2.B1 63.25,96.73 63.25,97.14 v1(63.27,97.16) ; v1(55.66,85.47) 55.84,85.65 VRAM2.L14 ; v1(55.96,103.55) 55.96,103.72 55.86,103.82 55.86,103.87 55.79,103.95 VRAM1.G1 ; VRAM1.P11 v1(61.78,111.75) ; v1(53.49,97.06) 53.44,97.01 VRAM2.P1 ; VRAM1.M12 59.79,112.94 VRAM1.L11 v1(58.59,111.74) ; VRAM2.L4 55.84,94.11 56.21,93.73 v1(56.21,93.71) ; VRAM2.D3 v1(61.04,94.51) ; v1(61.12,85.34) 61.12,85.8 VRAM2.D14 ; VRAM1.N10 60.84,111.09 60.84,111.06 v1(60.97,110.93) ; VRAM2.P11 v1(53.05,88.9) ; v1(51.56,103.5) 51.57,103.51 51.57,103.92 VRAM1.B1 ; v1(55.39,111.74) 55.79,112.14 VRAM1.G11 ; VRAM1.P3 61.39,105.74 61.78,106.13 v1(61.78,106.16) ; VRAM2.K3 56.64,94.91 v1(56.24,95.31) VRAM2.L2 ; v1(75.95,92.95) 75.95,92.95 GPU1.E23 ; VRAM1.T3 62.99,105.76 63.38,106.16 v1(63.38,106.16) ; v1(54.61,111.74) 54.21,111.34 VRAM1.E10 ; VRAM1.G2 55.79,104.94 v1(56.19,105.34) 56.58,105.74 VRAM1.H3 ; VRAM1.P14 61.39,114.61 v1(61.88,115.1) ; VRAM2.G14 59.22,86.29 59.22,86.73 VRAM2.G13 v1(58.63,87.31) 58.24,87.71 VRAM2.H12 ; VRAM1.R5 62.58,107.73 v1(62.59,107.73) ; v1(51.79,97.08) 51.84,97.03 VRAM2.T1 ; v1(52.23,89.74) 52.23,89.72 VRAM2.R10 ; VRAM1.M3 59.79,105.74 VRAM1.L4 58.58,106.14 v1(58.58,106.13) 58.58,106.13 58.58,106.13 VRAM1.K3 VRAM1.L2 ; VRAM1.F12 v1(54.59,113.34) ; v1(56.19,106.94) 55.79,106.54 VRAM1.G4 ; VRAM2.P14 53.44,85.54 v1(52.61,84.71) ; v1(62.59,112.52) 62.99,112.92 VRAM1.T12 ; v1(51.47,92.84) 51.48,92.83 52.15,92.83 VRAM2.R5 ; VRAM2.E5 60.14,92.82 v1(60.14,92.81) ; GPU1.C25 GPU1.B26 ; VRAM2.T12 51.84,87.73 v1(52.24,88.14) ; v1(60.99,112.54) 61.38,112.94 VRAM1.P12 ; VRAM2.C5 62.24,93.31 v1(62.75,92.81) ; VRAM2.M3 v1(55.44,94.51)
  TOP w0.406: VRAM1.B12 51.79,112.91 v1(51.39,112.51) ; VRAM2.T3 51.84,94.89 v1(51.44,94.49) ; v1(63.44,88.14) 63.04,87.74 VRAM2.B12 ; v1(51.39,106.16) 51.39,106.14 VRAM1.B3
  TOP w0.508: v1(52.61,84.71) 52.29,84.39 R295.1
  L4 w0.305: v1(61.04,94.51) v1(60.24,95.31) ; v1(57.83,94.52) 58.64,93.71 v1(59.42,93.71)
  BOTTOM w0.356: VRAM2.B3 63.04,94.89 v1(63.43,94.49) ; v1(53.49,97.06) 53.44,97.01 VRAM2.P1 ; v1(51.79,97.08) 51.84,97.03 VRAM2.T1 ; VRAM2.N5 54.25,93.3 v1(54.25,92.71) ; VRAM2.P3 53.44,94.91 53.32,94.79 53.32,94.79 v1(53.05,94.51) ; 54.99,115.58 v1(54.97,115.6) ; v1(58.63,87.31) 58.24,87.71 VRAM2.H12 ; v1(60.14,92.81) 60.14,92.82 VRAM2.E5 ; v1(55.66,85.47) 55.84,85.65 VRAM2.L14 ; v1(51.47,92.84) 52.16,92.84 VRAM2.R5 ; VRAM2.D3 v1(61.04,94.51)
  BOTTOM w0.406: v1(63.44,88.14) 63.04,87.74 VRAM2.B12 ; VRAM2.T3 51.84,94.89 v1(51.44,94.49)
  vias: v1(76.74,104.52) v1(79.28,93.75) v2(68.99,85.72) v2(69.12,114.81) v2(69.25,108.84) v2(76.23,84.58) v2(81.69,74.42) v2(96.55,70.23) v5(90.46,72.39) v5(91.35,71.88) v5(95.03,72.26) v5(96.43,72.26) v5(98.33,76.58) v5(98.33,75.56) v5(98.33,74.42) v5(98.33,73.41) v5(98.33,72.26)
+V_1P35_VGA_DISCHG: length 12.1
  BOTTOM w0.102: Q53.6 73.63,116.86 v2(73.44,117.04) 73.01,117.47 67.34,117.47 64.92,119.89 R664.2
+V_3P3_VGA: length 162.2
  TOP w0.254: v1(87.54,106.22) 87.79,105.97 87.79,105.97 GPU1.AA8 ; v1(87.54,106.22) 87.5,106.22 87.14,105.86 GPU1.AA9 ; v1(87.54,106.22) 87.96,106.65 GPU1.AB8 ; 80.93,75.82 78.39,75.82 77.48,76.73 77.48,79.39 R308.1 R309.1
  TOP w0.406: U7.5 101.14,110.38 100.87,110.11 97.32,110.11 v3(96.05,108.84)
  TOP w0.508: v3(126.78,105.46) 126.78,106.12 ; 126.78,106.12 132.8,106.12 v3(133.51,105.41) 132.21,104.11 132.21,94.84 v3(130.72,93.34) ; 126.78,106.12 125.67,106.12 122.64,103.1 121.22,103.1 120.75,103.57 PR65.1 120.49,103.5 v3(119.79,103.5) 119.16,102.87 PR66.1 ; v3(98.71,99.44) 98.01,99.44 R262.1 ; PR84.1 123.1,70.87 124.87,72.64 v3(124.87,72.77) ; R673.1 R269.1 98.84,90.17 v1(98.71,90.3) 98.52,90.11 R274.1 98.28,89.04 98.28,88.85 97.89,88.46 R275.1
  L3 w0.508: v3(96.05,108.84) 96.43,108.46 104.1,108.46 110.07,102.49 118.78,102.49 v3(119.79,103.5)
  L4 w0.508: v3(124.87,72.77) 124.87,73.03 125.28,73.43 131.76,73.43 132.37,74.04 132.49,74.04 136.78,78.33 136.78,92.58 136.02,93.34 v3(130.72,93.34)
  BOTTOM w0.203: Q60.5 Q60.2 88.31,64.9 89.6,66.19 90.09,66.19 91.13,65.15 96.68,65.15 100.03,68.5 100.03,69.84 100.07,69.87 100.07,77.54 100.03,77.57 100.03,77.8 96.3,81.53
  BOTTOM w0.508: v3(96.05,108.84) 96.01,108.81 ; 96.01,108.81 95.66,109.16 R670.1 94.11,109.16 Q54.G ; 96.01,108.81 95.98,108.78 95.98,106.17 ; PR230.1 v3(130.72,93.34) 130.03,92.66 128.28,92.66 127.13,93.81 127.13,93.81 PR232.1 ; v3(126.78,105.46) 126.78,105.26 127.29,104.76 PR211.2 ; PR209.2 v3(133.51,105.41)
  vias: v1(100.24,94.36) v1(100.24,93.6) v2(86.65,77.47) v2(98.84,85.9) v3(85,78.11) v3(85.5,77.47) v3(90.58,82.3) v3(90.58,81.53) v3(95.66,82.3) v3(96.55,82.3) v3(98.71,94.23) v4(81.64,75.16)
+V_VGA_CORE: length 67.3
  TOP w0.508: 105.15,91.57 PT15.1 ; PT15.1 106.21,90.51 ; PT15.1 107.26,91.57 ; PT15.1 106.21,92.62 ; PT16.1 106.21,84.75 ; PT16.1 105.15,83.69 ; PT16.1 107.26,83.69 ; PT16.1 106.21,82.64
  L3 w0.254: v1(78.56,103.45) 78.56,105.68 79.36,106.48 79.36,112.52 v3(78.47,113.41)
  L3 w0.508: 105.15,91.57 PT15.1 ; PT15.1 106.21,92.62 ; PT15.1 107.26,91.57 ; PT15.1 106.21,90.51 ; PT16.1 107.26,83.69 ; PT16.1 105.15,83.69 ; PT16.1 106.21,82.64 ; PT16.1 106.21,84.75 ; v3(109.36,92.43) 116.09,92.43 117,93.34 117,97.92 121.57,102.49 v3(122.97,102.49)
  L4 w0.508: 106.21,82.64 PT16.1 ; PT16.1 105.15,83.69 ; PT16.1 107.26,83.69 ; PT16.1 106.21,84.75 ; 105.15,91.57 PT15.1 ; PT15.1 106.21,90.51 ; PT15.1 107.26,91.57 ; PT15.1 106.21,92.62
  BOTTOM w0.254: R666.1 77.83,114.05 v3(78.47,113.41)
  BOTTOM w0.508: v3(122.97,102.49) 122.78,102.68 PR215.1 ; PT16.1 106.21,84.75 ; PT16.1 107.26,83.69 ; PT16.1 106.21,82.64 ; PT16.1 105.15,83.69 ; PT15.1 107.26,91.57 ; PT15.1 106.21,92.62 ; PT15.1 106.21,90.51 ; PT15.1 105.15,91.57
  vias: v1(78.52,102.49) v1(78.54,99.47) v1(78.54,97.56) v1(78.6,101.52) v1(79.52,102.44) v1(79.51,100.43) v1(79.51,98.45) v1(79.48,96.42) v1(80.63,95.51) v1(81.49,102.46) v1(81.49,100.43) v1(81.5,98.46) v1(81.45,96.45) v1(82.52,95.56) v1(83.53,102.49) v1(83.5,100.51) v1(83.53,98.5) v1(83.46,96.42) v1(84.41,97.44) v1(84.48,103.34) v1(84.49,101.42) v1(84.46,99.4) v1(85.48,96.37) v1(86.32,97.5) v1(86.44,99.44) v1(86.49,103.43) v1(86.49,101.5) v1(87.46,96.42) v1(88.13,100.48) v1(88.15,99.72) v1(88.18,101.37) v1(89.25,101.25) v1(89.19,100.36) v1(89.21,99.59) v1(90.05,101.25) v1(90.05,100.41) v1(90.1,99.59) v1(90.89,101.25) v1(90.91,99.59) v1(91.7,102.03) v1(91.69,101.25) v1(91.69,100.41) v1(92.49,102.03) v1(92.49,101.25) v1(92.49,100.41) v1(93.3,101.22) v2(113.06,87.25) v5(106.84,89.66) v5(106.84,88.65) v5(107.73,83.57) v5(107.86,90.68) v5(107.86,89.66) v5(107.86,88.65) v5(107.86,87.38) v5(107.86,86.36) v5(108.75,83.57) v5(108.87,90.68) v5(108.87,89.66) v5(108.87,88.65) v5(108.87,87.38) v5(108.87,86.36) v5(109.76,83.57) v5(109.89,90.68) v5(109.89,89.66) v5(109.89,88.65) v5(109.89,87.38) v5(109.89,86.36) v5(110.9,83.57) v5(111.03,90.68) v5(111.08,89.66) v5(111.08,88.65) v5(111.92,83.57) v5(112.05,90.68) v5(112.1,89.66) v5(112.1,88.65) v5(112.94,83.57)
AC_IN: length 11.4
  TOP w0.102: PR102.2 49.75,42.23 v3(50.33,42.8) 50.83,42.29 PQ3.D
  BOTTOM w0.102: PQ11.2 55.15,41.91 53.88,40.64 49.99,40.64 49.23,41.4 v2(49.18,41.4) 49.18,41.66 v3(50.33,42.8)
AC_IN_KBC#: length 216.3
  TOP w0.102: KBC1.65 143.43,64.64 143.75,64.33 v1(143.75,63.88) ; v3(93,41.02) 93,43.31 92.87,43.43 89.3,43.43 89.17,43.31 PQ5.6
  L4 w0.127: v3(93,41.02) 92.24,40.26 87.84,40.26 87.21,39.62 87.21,32.46 85.01,30.26 67.11,30.26 64.55,32.83 52.76,32.83 46.97,27.04 46.97,26.82 42.76,22.61 39.45,22.61 38.72,21.88 30.13,21.88 27.61,19.37 25.99,19.37 22.65,22.7 22.65,34.81 28.21,40.37 29.23,40.37 33.22,44.36 33.22,45.82 33.35,45.95 33.35,52.49 v3(33.82,52.96) ; v1(143.75,63.88) 143.69,63.82 130.21,63.82 129.95,64.08 125.81,64.08 125.8,64.07 125.22,64.07 125.21,64.08 124.86,64.08 124.53,63.75 94.01,63.75 v3(93.63,63.37)
  BOTTOM w0.102: Q63.G 26.93,56.24 30.2,52.96 v3(33.82,52.96) ; R744.1 143.43,64.2 v1(143.75,63.88) ; v3(93.63,63.37) 93.51,63.25 v2(93.51,60.58) 93.51,41.53 v3(93,41.02)
AC_OK#: length 123.9
  TOP w0.102: v3(53.5,42.29) 53.31,42.1 PQ3.G ; v1(140.14,70.36) 140.14,69.95 140.5,69.6 R359.1 ; PR101.2 48.36,42.16 v3(46.13,42.16)
  L3 w0.127: v1(140.14,70.36) 139.86,70.08 139.86,66.17 139.45,65.76 139.12,65.76 134.91,61.54 134.91,59.23 132.09,56.41 130.44,56.41 127.44,53.42 127.44,52.52 126.96,52.04 126.96,52.02 126.94,52.01 126.94,51.47 126.02,50.55 123.35,50.55 122.87,50.06 117.86,50.06 117.51,50.42 114.21,50.42 113.7,49.91 112.43,49.91 112.25,50.09 v3(108.57,50.09)
  L4 w0.127: v3(46.13,42.16) 46.13,42.96 47.21,44.03 51.76,44.03 v3(53.5,42.29) 57.21,42.29 58.41,43.49 58.41,46.37 61.72,49.67 69.1,49.67 69.36,49.92 72.66,49.92 73.71,50.98 78.05,50.98 79.13,52.06 95.63,52.06 96.23,51.46 105.27,51.46 106.64,50.09 v3(108.57,50.09)
  BOTTOM w0.102: PU34.5 44.44,44.21 v2(45.61,43.04) 46.13,42.52 v3(46.13,42.16)
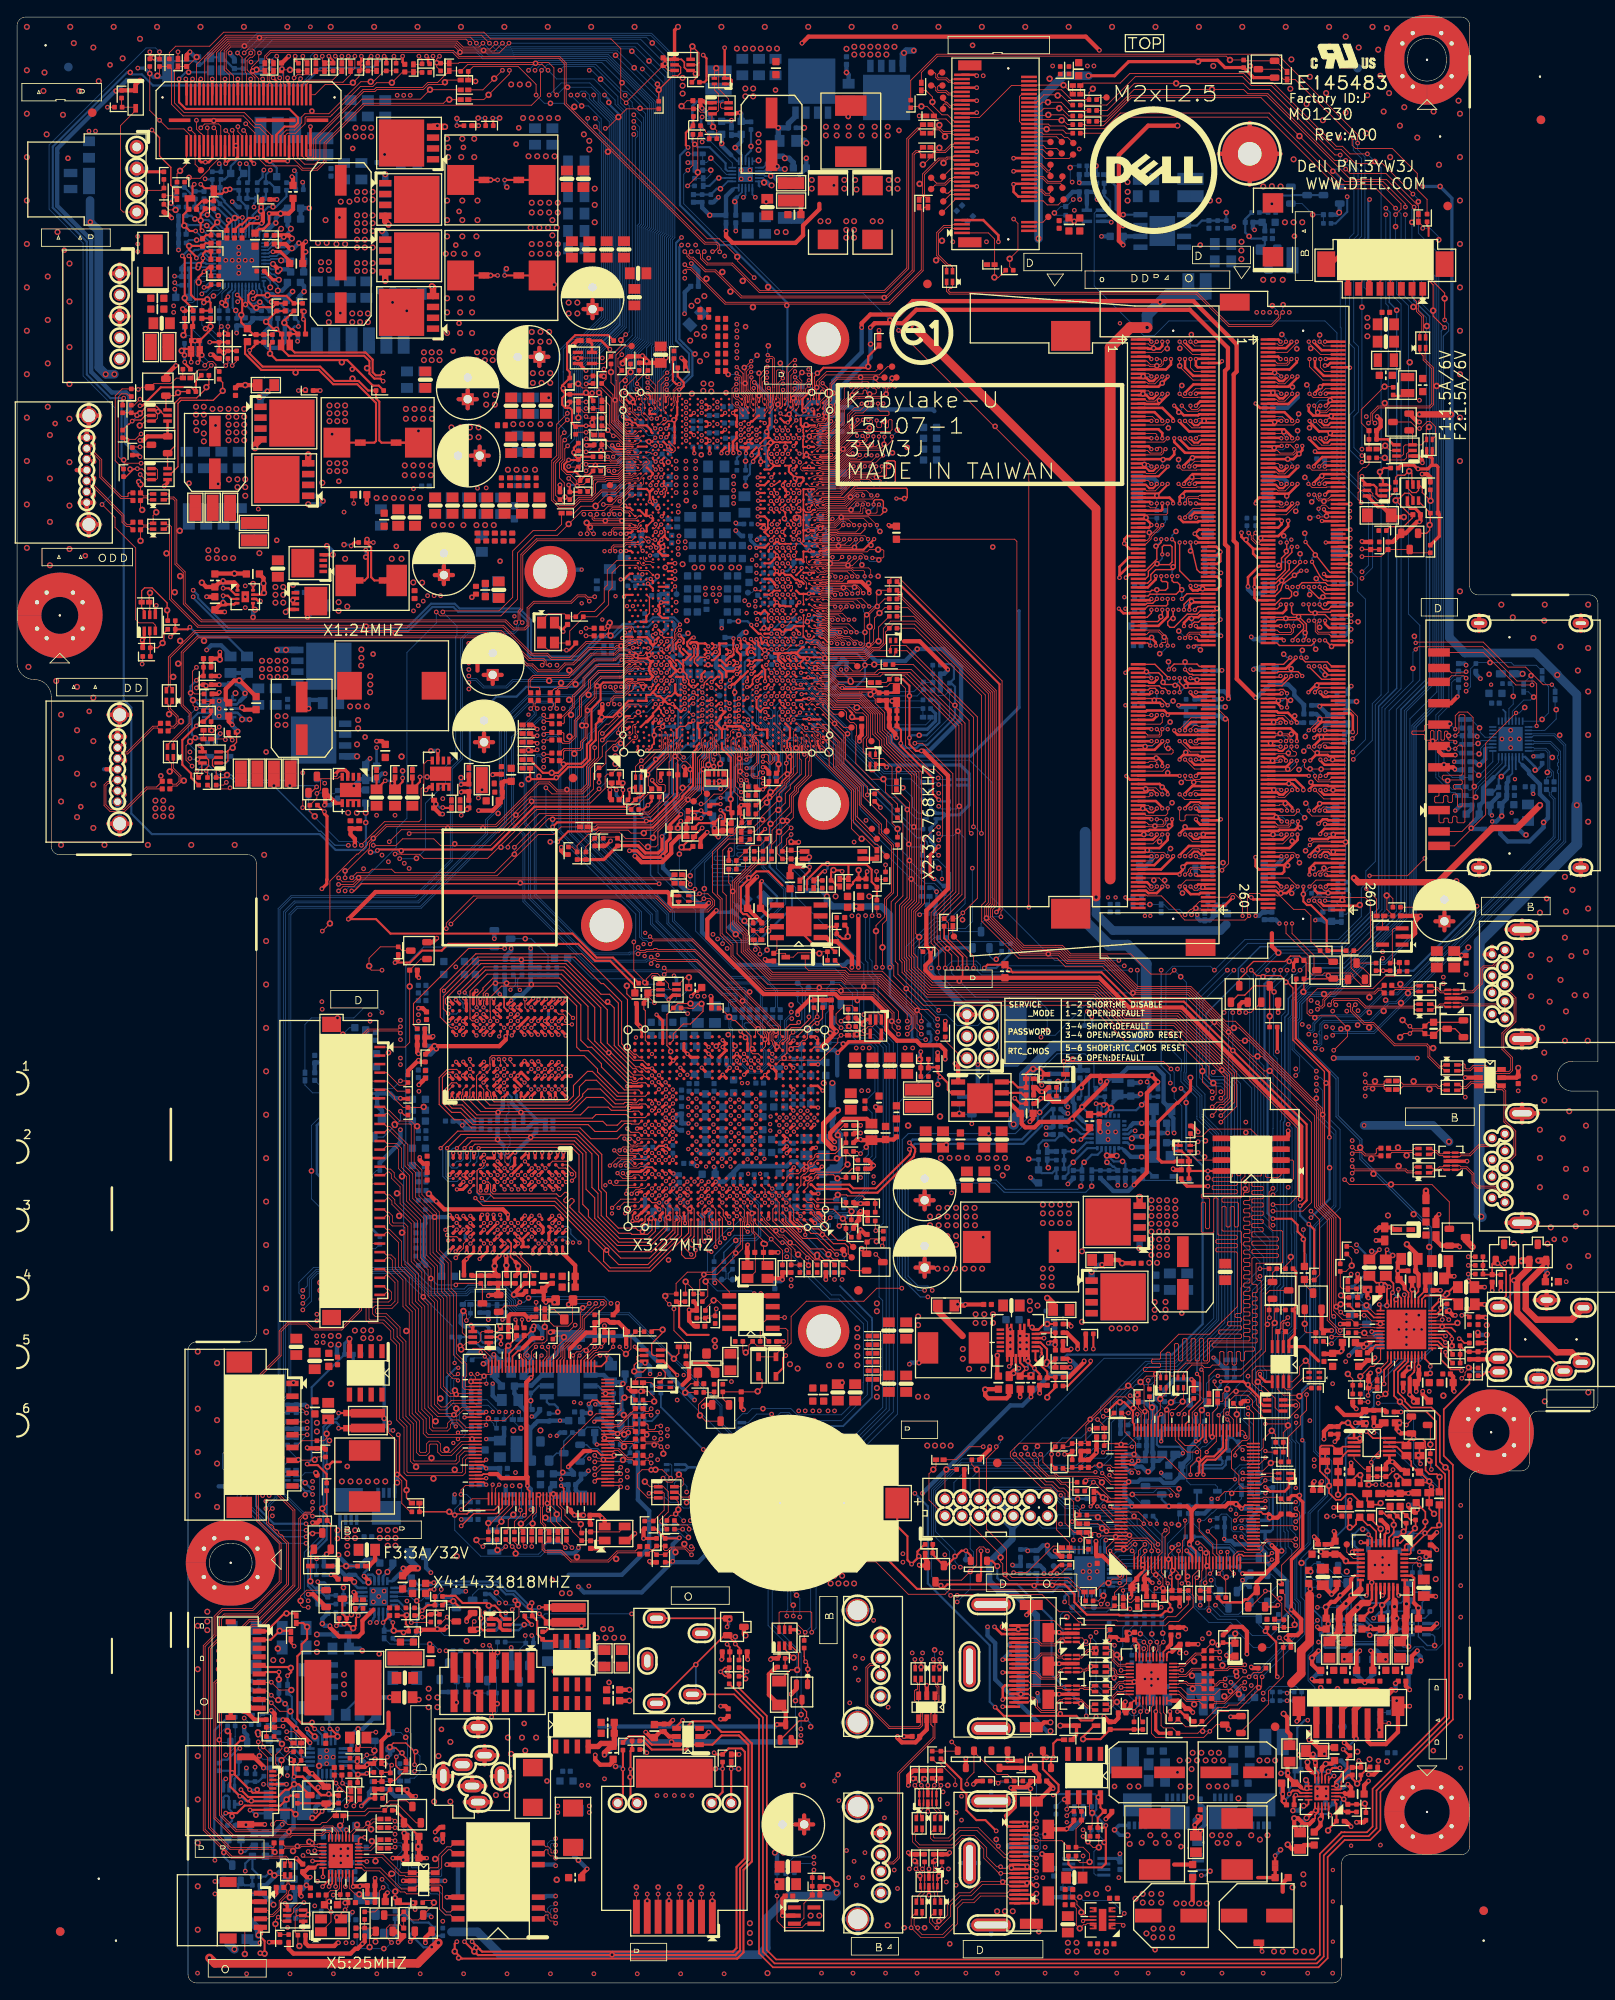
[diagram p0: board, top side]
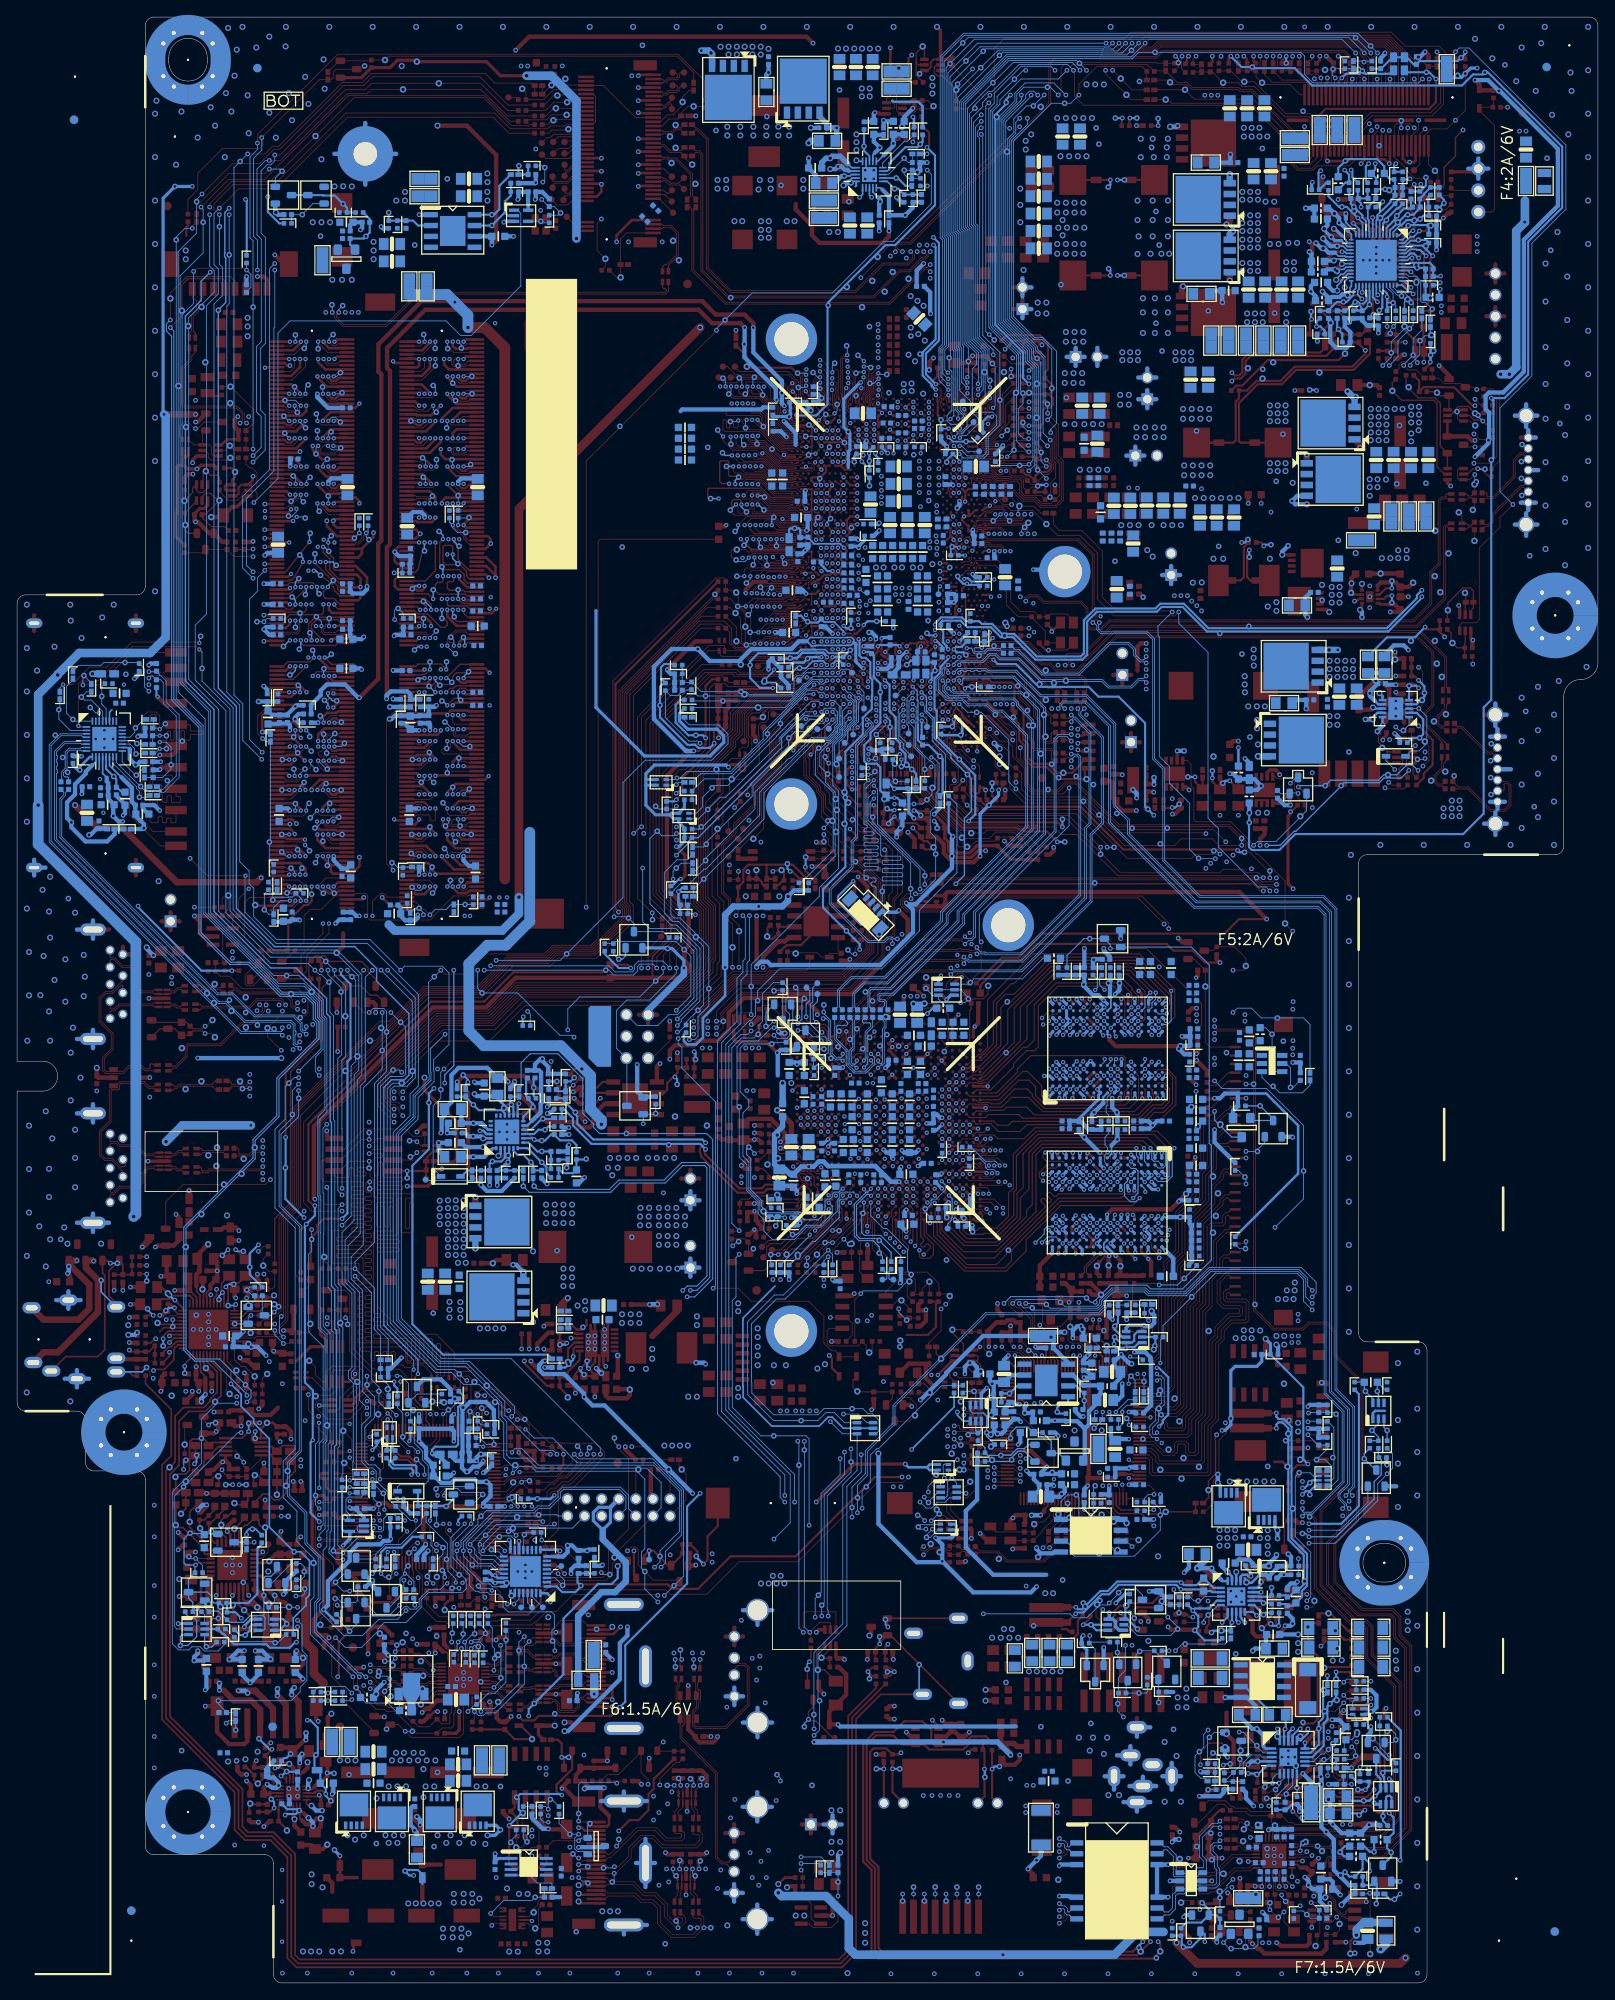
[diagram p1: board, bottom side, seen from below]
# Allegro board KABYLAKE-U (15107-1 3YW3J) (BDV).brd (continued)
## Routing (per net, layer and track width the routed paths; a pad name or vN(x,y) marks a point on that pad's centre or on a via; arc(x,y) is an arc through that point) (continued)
AC_PRESENT: length 141.7
  TOP w0.089: CPU1.AY15 93.18,153.29 93.64,152.83 93.64,152.61 93.81,152.43 93.91,152.41 94.08,152.41 94.17,152.44 95.04,152.44 96.45,151.03
  TOP w0.102: 96.45,151.03 98.57,151.03 99.6,151.03 v4(99.88,150.75) 100.43,150.2 100.43,149.73 101.53,148.63 101.53,146.69 102.31,145.91 102.31,145.2 105.82,141.69 105.82,126.28 104.94,125.39 104.94,120.41 105.34,120 105.34,118.83 107.15,117.02 126.63,117.02 129.95,113.69 136.16,113.69 149.84,100.01 149.84,92.04 148.87,91.06 v3(146.97,91.06) ; v1(146.08,58.8) 145.58,58.3 KBC1.52
  BOTTOM w0.102: v3(146.97,91.06) 147.43,90.6 147.43,81.8 147.09,81.46 147.09,76.84 146.88,76.64 146.88,59.56 146.97,59.47 R759.2 146.91,58.8 v1(146.08,58.8)
AC_PROTECT: length 28.2
  L4 w0.127: v3(35.06,49.63) 35.8,48.9 36.36,48.9 37.5,47.75 37.5,46.61 40.11,43.99 43.64,43.99 45.4,45.76 46.81,45.76 48.35,47.3 49,47.3 49.64,46.66 v3(49.64,46.02)
  BOTTOM w0.102: PU34.3 46.01,45.21 46.52,44.7 v2(46.77,44.7) 47.28,44.7 47.72,45.15 PR252.1 R785.1 49.64,45.76 v3(49.64,46.02) ; PR249.1 PR248.2 35.02,49.59 v3(35.06,49.63)
AD+_2: length 32.5
  TOP w0.635: U19.4 67.98,27.66 68.33,28.02 69.43,28.02 R478.1 ; PQ7.C 90.63,28.44 90.88,28.19 v3(91.73,28.19) ; v3(68.74,26.67) 68.74,26.92 69.5,27.69 R478.1 ; R469.2 C240.2 69.88,27.81 R478.1
  BOTTOM w0.635: v3(68.74,26.67) 70.26,28.19 v2(76.59,28.19) v3(91.73,28.19)
AD+_G_1: length 6.5
  TOP w0.254: PR99.2 59.41,42.74 v3(60.23,41.91)
  BOTTOM w0.254: PQ11.6 58.69,41.26 v2(59.34,41.91) ; v2(59.34,41.91) v3(60.23,41.91) ; v2(59.34,41.91) PQ11.5
AD+_G_2: length 6.1
  TOP w0.254: PU16.4 61.69,40.01 PR107.2 60.87,40.83 60.87,42.35 PR99.1 60.29,43.62 60,43.92 v4(60,44.04)
AD+_TO_SYS: length 1.4
  TOP w0.254: 62.77,41.4 62.14,41.4 61.82,41.08 PR107.1
  vias: v2(66.05,41.78) v5(67.85,40.39) v5(68.59,41.4) v5(68.87,40.39) v5(69.5,41.4) v5(69.88,40.39) v5(70.9,40.39)
AD_IA: length 106
  TOP w0.102: R367.1 125.64,64.9 v1(125.51,64.77)
  L4 w0.127: v3(49.44,38.86) 49.91,39.33 53.3,39.33 54.14,40.17 57.79,40.17 60.62,43.01 60.62,45.88 62.51,47.76 70.79,47.76 70.99,47.97 79.8,47.97 81.28,49.44 101.76,49.44 101.76,49.4 102.78,48.39 109.38,48.39 v3(109.63,48.64)
  BOTTOM w0.102: v1(125.51,64.77) 124.49,63.75 122.32,63.75 120.56,61.99 120.56,61.96 119.45,60.86 110.47,60.86 107.27,57.66 107.27,52.35 109.13,50.5 109.13,49.15 v3(109.63,48.64) ; PR256.2 43.63,39.65 v2(48.29,39.65) 48.65,39.65 v3(49.44,38.86)
AD_IA_HW1: length 111.8
  TOP w0.102: v3(54.77,43.31) 54.77,42.29 55.15,41.91 PQ4.2 ; v1(143.42,58.93) 143.58,59.1 KBC1.54 145.49,59.1 145.63,59.23 147.04,59.23 147.29,58.98 RN9.4
  L4 w0.127: v3(54.77,43.31) 55.24,42.84 56.06,42.84 56.55,43.33 56.55,43.34 57.19,43.98 57.38,43.98 57.65,44.26 57.65,46.33 61.51,50.18 68.89,50.18 69.15,50.43 72.45,50.43 73.5,51.48 77.84,51.48 79.01,52.65 105.15,52.65 106.49,51.32 122.16,51.32 122.89,50.58 126.87,50.58 128.4,52.12 134.73,52.12 135.15,52.54 139.02,52.54 140.06,51.5 143.47,51.5 144.5,52.52 144.5,57.85 v1(143.42,58.93)
  BOTTOM w0.102: v2(54.26,42.67) 54.26,42.8 v3(54.77,43.31)
AD_IA_HW2: length 110.9
  TOP w0.102: v3(57.95,43.69) 58.02,43.69 v4(58.61,44.27) 58.61,44.22 58.73,44.09 58.73,42.88 57.77,41.91 PQ4.5 ; v1(143.42,59.69) 143.61,59.5 KBC1.55 145.57,59.5 145.7,59.63 RN9.3
  L4 w0.127: v1(143.42,59.69) 144.75,58.36 144.75,52.29 143.71,51.24 139.95,51.24 138.91,52.29 135.25,52.29 134.83,51.87 128.56,51.87 127.02,50.33 122.78,50.33 122.05,51.06 106.39,51.06 105.05,52.4 79.11,52.4 77.94,51.23 73.61,51.23 72.55,50.18 69.25,50.18 69,49.92 61.61,49.92 58.07,46.38 58.07,43.81 v3(57.95,43.69)
AD_IA_R: length 6.3
  TOP w0.102: KBC1.97 127.45,63.1 R368.1 C164.1 R367.2 127.22,65.16 126.47,65.92 v3(126.44,65.92)
  BOTTOM w0.102: v2(125.59,65.94) 126.42,65.94 v3(126.44,65.92)
AD_JK: length 41.1
  TOP w0.508: v3(88.93,30.23) 88.95,30.24 PQ7.E 89.95,31.75 PR111.1 87.98,33.72 87.98,36.1 88.84,36.96 R457.1 ; DCIN1.1 54.71,27.7 ; DCIN1.1 56.27,26.63 ; DCIN1.1 54.71,25.56
  L3 w0.508: DCIN1.1 54.71,27.7 ; DCIN1.1 56.27,26.63 ; DCIN1.1 54.71,25.56
  BOTTOM w0.508: DCIN1.1 56.27,26.63 ; DCIN1.1 54.71,25.56 ; DCIN1.1 54.71,27.7 ; 68.13,30 88.7,30 v3(88.93,30.23)
  vias: v2(59.34,30.35) v2(62.01,23.62) v2(65.18,29.97) v5(57.44,28.7) v5(57.82,26.8) v5(59.09,28.7) v5(59.47,27.18) v5(60.74,28.7)
AD_OFF_L: length 7.7
  TOP w0.152: PQ6.C 91.85,32.26 92.39,31.72 v3(92.39,30.84) 92.21,30.66 91.52,30.66 PQ7.B
  BOTTOM w0.152: v2(92.87,29.97) 92.87,30.35 v3(92.39,30.84)
ADAPTOR_PSID: length 99.7
  TOP w0.102: KBC1.99 127.42,62.3 127.19,62.06 v1(127.08,62.06)
  L4 w0.127: v3(59.47,40.64) 59.98,41.15 60.13,41.15 61.59,42.6 61.59,46.33 62.77,47.51 70.89,47.51 71.1,47.71 79.91,47.71 81.38,49.19 98.11,49.19 99.23,48.07 109.82,48.07 v3(110.4,48.64)
  BOTTOM w0.102: R802.2 59.41,39.88 R803.2 ; v3(59.47,40.64) 59.53,40.58 R803.2 ; R803.2 58.83,39.05 D20.3 ; v3(110.4,48.64) 109.76,49.28 v2(109.76,49.91) 109.76,50.55 107.49,52.81 107.49,57.56 110.51,60.58 124.01,60.58 125.94,62.51 126.75,62.51 127.08,62.18 v1(127.08,62.06)
ADAPTOR_PSID_R: length 2.7
  BOTTOM w0.102: R802.1 v2(56.23,38.66) 56.23,38.23 56.01,38 Q74.S
ADC_3V3: length 5.7
  TOP w0.203: v1(66.91,67.75) 67.33,68.17 67.87,68.17 68.26,67.79 SCA1.25
  BOTTOM w0.508: v1(66.91,67.75) 66.91,67.56 67.04,67.44 67.04,67.43 67.09,67.38 v2(67.09,66.67) 66.26,66.67 C541.1 66.14,65.85 66.07,65.79
ADP_V_DET: length 3.9
  TOP w0.152: PQ5.2 89.82,39.09 v4(90.86,38.05) 90.79,37.97 R455.1 R457.2
ALERT#: length 5.6
  TOP w0.102: U12.6 147.54,69.41 148.19,68.76 149.89,68.76 150,68.65 v4(150.07,68.65) 151.01,69.6 R355.2
ALL_PWRGD_2: length 8
  TOP w0.102: Q37.D 80.59,65.72 v4(79.92,66.4) 79.74,66.57 79.74,67.67 80.57,68.5 81.34,68.5 81.57,68.73 R353.1 81.5,69.09 R357.1
ALL_SYS_PWRGD: length 378.3
  TOP w0.102: U1.2 v3(68.49,190.12) ; R38.1 71.33,219.27 v4(70.37,218.3) 69.05,216.98 v3(68.84,216.98) ; R108.1 11.49,178.09 11.49,185.7 12.29,186.5 PR30.2 14.12,186.5 v3(14.18,186.44) 14.31,186.44 14.56,186.69 Q4.D 15.59,186.69 16.02,187.12 17.98,187.12 18.63,187.76 19.38,187.76 R80.2 R76.1 ; KBC1.10 134.34,50.2 134.35,50.21 134.35,52.2 134.83,52.68 134.83,53.29 v1(134.4,53.72)
  L3 w0.127: v3(68.84,216.98) 68.56,216.7 66.68,216.7 66.55,216.83 58.71,216.83 56.46,219.07 40.04,219.07 39.62,218.66 29.33,218.66 26.45,215.77 18.03,215.77 16.04,213.78 16.04,188.16 14.31,186.44 v3(14.18,186.44)
  L4 w0.127: v3(68.84,216.98) 68.84,216.95 68.7,216.82 68.7,194.02 68.49,193.8 v3(68.49,190.12) ; v1(134.4,53.72) 133.95,53.28 124.53,53.28 123.71,52.46 106.96,52.46 105.61,53.81 93.58,53.81 93.38,54.01 90.61,54.01 90.41,53.81 88.72,53.81 88.33,53.42 80.72,53.42 78.63,55.5 74.83,55.5 73.06,57.27 72.86,57.47 55.09,57.47 52.42,60.14 52.42,65.47 51.91,65.98 51.91,67.58 37.32,82.17 37.32,110.92 33.04,115.2 33.04,132.95 29.36,136.64 23.57,136.64 17.17,143.04 17.17,158.54 13.36,162.35 13.36,174.97 12.45,175.87 12.45,184.58 14.18,186.31 v3(14.18,186.44)
AMD_RST#_L: length 10.4
  TOP w0.102: R246.2 96.81,112.9 v3(96.43,112.52) ; R246.2 R247.2 98.14,111 R251.1 99.23,110.87 99.42,111.06 U7.4 ; R246.2 R245.1
  BOTTOM w0.102: v3(96.43,112.52) 96.45,112.52 97.06,111.91 v2(97.37,111.91) 97.37,113.52 D17.2
AMP_SPKR_L: length 6.3
  TOP w0.203: U13.4 155.72,62.24 155.2,61.72 155.2,61.65 R377.1 R385.1 R391.2 v4(154.59,57.12)
AMP_SPKR_R: length 7.9
  TOP w0.203: U13.8 161.45,62.74 162.49,61.7 R375.1 162.59,61.59 163.15,61.04 163.15,60.5 163.89,59.77 R386.1 164.17,59.77 v4(165.26,58.67) 165.13,58.55 R392.2
AMP_SWITCH_C_L: length 2.4
  TOP w0.203: R373.1 R377.2 153.35,60.76 v4(153.35,59.89)
AMP_SWITCH_C_R: length 3.3
  TOP w0.203: R369.1 R375.2 164.12,60.96 164.24,60.83 v3(164.24,60.73)
  BOTTOM w0.203: v2(163.99,61.72) 163.99,60.99 v3(164.24,60.73)
AUD_BEEP_C: length 3.1
  TOP w0.102: U11.2 158.94,78.25 v4(157.92,79.27) 157.88,79.31 C125.2
AUD_BEEP_R: length 8.1
  TOP w0.102: R889.2 156.19,84.7 v4(156.19,83.92) 155.52,83.25 R282.2 154.85,81.46 155.09,81.22 R305.2 R306.1 156.88,81.09 C125.1
AUD_DMIC_CLK: length 161.1
  TOP w0.127: v3(167.06,193.68) 165.72,195.02 v4(165.72,195.66) 165.72,198.68 165.01,199.39 160.94,199.39 160.75,199.2 WEBCM1.4 ; L12.2 C155.2 158.1,67.97 v3(158.1,67.97)
  BOTTOM w0.127: v3(158.1,67.97) 157.63,68.44 157.63,69.33 v2(158.28,69.98) 161.3,73 164.09,73 165.24,74.14 165.24,88.31 157.13,96.41 157.13,98.57 154.35,101.36 154.35,105.77 149.68,110.44 149.68,112.44 150.09,112.85 150.09,114.63 151.13,115.67 154.11,115.67 157.85,119.42 159.99,119.42 163.47,122.89 163.47,147.01 166.66,150.2 166.66,193.27 v3(167.06,193.68)
AUD_DMIC_CLK_R: length 5.6
  TOP w0.127: R349.1 v4(157.2,70.97) 158.36,72.14 158.78,72.14 159.57,72.92 U11.12
AUD_DMIC_CLK_R_1: length 2.6
  TOP w0.127: v4(155.74,71.25) 156.31,70.68 R349.2 L12.1
AUD_DMIC_DATA: length 161.7
  TOP w0.127: WEBCM1.5 159.5,199.09 160.05,199.64 165.13,199.64 167.06,197.71 v4(167.06,197.08) v3(167.06,194.56) ; v3(158.1,68.73) 158.15,68.78 C148.2 R348.1
  BOTTOM w0.127: v3(167.06,194.56) 167.53,194.09 167.53,193.28 166.91,192.66 166.91,150.1 163.72,146.91 163.72,122.79 160.1,119.16 157.96,119.16 154.21,115.42 151.24,115.42 150.34,114.53 150.34,112.75 149.93,112.34 149.93,110.55 154.6,105.88 154.6,101.46 157.39,98.68 157.39,96.52 165.49,88.41 165.49,74.04 164.2,72.75 161.98,72.75 158.1,68.86 v3(158.1,68.73)
AUD_DMIC_DATA_R: length 3.4
  TOP w0.127: U11.13 160.39,72.71 v4(159.34,71.65) 159.34,71.65 159.16,71.48 R348.2
AUD_GP3: length 5.3
  TOP w0.203: v4(154.9,79.4) 155.77,79.4 R312.2 156.56,78.61 158.02,78.61 158.78,77.85 U11.3
AUD_LINK_BCLK: length 120.8
  TOP w0.102: R124.1 103.55,161.93 114.35,151.12 114.35,126.1 113.93,125.68 113.93,124.64 117.64,120.93 122.13,120.93 123.13,119.94 127.48,119.94 131.06,116.36 137.27,116.36 141.89,111.73 v4(142.4,111.73) 143.02,111.73 152.51,102.24 152.51,91.06 154.08,89.49 154.08,78.65 155.14,77.6 156.18,77.6 C129.2 156.72,77.05 U11.5
AUD_LINK_RST_N: length 123.9
  TOP w0.102: v3(153.83,74.8) 153.13,74.8 R337.1 ; R127.1 104.93,159.89 113.89,150.93 113.89,126.29 113.47,125.87 113.47,124.45 117.45,120.48 121.94,120.48 122.94,119.48 127.29,119.48 130.87,115.9 137.08,115.9 144.57,108.41 v4(145.17,108.41) 145.7,108.41 152.05,102.05 152.05,90.87 153.58,89.35 153.58,77.6 v3(154.85,76.33) 155.1,76.58 157.13,76.58 157.26,76.71 158.78,76.71 158.84,76.65 U11.6
  BOTTOM w0.102: v3(153.83,74.8) 154.85,75.82 v3(154.85,76.33)
AUD_LINK_RST_N_2: length 3.6
  BOTTOM w0.254: Q71.3 153.87,42.56 153.45,42.14 v2(153.45,42.01) 153.53,42.01 154.28,41.26 Q71.1
AUD_LINK_RST_N_R: length 4.9
  TOP w0.102: Q30.B v4(150.69,77.11) 150.69,76.28 150.89,76.07 C134.1 R337.2
AUD_LINK_SDIN: length 129.6
  TOP w0.089: CPU1.BA21 93.66,156.28 94.03,155.91 94.47,155.91 94.95,155.43 95.51,155.43
  TOP w0.102: R327.1 155.6,75.87 154.66,75.87 154.39,76.14 154.39,76.46 153.32,77.53 153.32,89.28 151.82,90.78 151.82,101.47 v4(146.59,106.71) 145.95,106.71 136.98,115.67 130.78,115.67 127.19,119.25 122.84,119.25 121.85,120.25 117.35,120.25 113.24,124.36 113.24,125.96 113.67,126.39 113.67,150.84 105.17,159.33 102.23,159.33 101.38,158.48 101.38,156.74 100.88,156.25 100.07,156.25 99.27,155.45 95.54,155.45 95.51,155.43
AUD_LINK_SDIN_1: length 3.1
  TOP w0.102: U11.8 158.95,75.85 158.78,75.69 158.02,75.69 v4(157.67,76.05) 157.64,76.07 R327.2
AUD_LINK_SDO: length 121.4
  TOP w0.102: R123.1 102.97,162.83 114.58,151.21 114.58,126.01 114.16,125.58 114.16,124.74 117.73,121.16 122.23,121.16 123.22,120.17 127.57,120.17 131.15,116.59 137.36,116.59 141.43,112.52 142.56,112.52 152.74,102.34 152.74,91.16 154.34,89.56 154.34,79.04 v3(154.9,78.49) 155.28,78.11 R320.2
  BOTTOM w0.102: v2(154.39,79.12) 154.39,78.99 v3(154.9,78.49) 155.28,78.11 Q57.D 156.31,78.36 C528.2
AUD_LINK_SDO_1: length 3.9
  BOTTOM w0.102: R704.2 157.79,81.41 v2(158.12,81.08) 157.44,80.39 C528.1 157.2,79.85 Q57.G
AUD_LINK_SDO_N: length 5.9
  TOP w0.102: U11.4 158.53,77.45 157.88,78.11 v3(157.64,78.11) R320.1
  BOTTOM w0.102: v3(157.64,78.11) 157.96,77.79 Q57.S v2(159.55,77.12)
AUD_LINK_SDO_R1: length 17.9
  BOTTOM w0.102: JMP1.5 112.43,112.01 110.02,112.01 108.75,113.28 107.72,113.28 105.8,115.2 105.8,120.75 107.35,122.3 R654.1
AUD_LINK_SYNC: length 123.2
  TOP w0.102: U11.9 157.16,75.45 157,75.62 153.88,75.62 v3(153.83,75.56) ; R126.1 104.24,160.91 114.12,151.02 114.12,126.2 113.7,125.77 113.7,124.55 117.54,120.71 122.04,120.71 123.03,119.71 127.38,119.71 130.97,116.13 137.17,116.13 143.07,110.24 v4(143.7,110.24) 144.19,110.24 152.28,102.15 152.28,90.97 153.83,89.42 153.83,78.23 v3(154.08,77.98)
  BOTTOM w0.102: v3(154.08,77.98) 154.29,77.77 154.29,76.02 v3(153.83,75.56)
AUD_REGREF: length 3.2
  TOP w0.203: U11.10 158.53,75.05 158.4,74.93
  TOP w0.508: C136.1 156.85,74.7 157.88,74.7 v4(157.93,74.75) 158.11,74.93 158.4,74.93
AUDIO_3V3: length 8
  TOP w0.203: v3(55.79,73.53) 55.97,73.35 SCA1.62
  BOTTOM w0.508: v2(54.57,72.44) 54.77,72.44 54.97,72.64 55,72.64 55.79,73.43 v3(55.79,73.53) 56.42,72.9 C533.1 56.61,72.22 C536.1 55.89,70.77 56.68,69.99 L24.2
BAT_ALERT: length 4
  TOP w0.102: R374.2 35.15,61.53 v4(34.83,61.21) 34.78,61.16 32.25,61.16 BAT2.7
BAT_IN#: length 133
  TOP w0.102: v3(135.92,50.55) 135.94,50.53 KBC1.14
  L4 w0.127: v3(135.92,50.55) 134.6,50.55 133.87,49.81 128.88,49.81 128.87,49.82 125.77,49.82 125.57,49.62 120.32,49.62 118.01,47.31 98.91,47.31 97.79,48.43 81.7,48.43 80.23,46.95 71.41,46.95 71.18,46.72 68.65,46.72 59.56,37.63 43.87,37.63 38.18,43.32 35.45,43.32 v3(34.07,44.7)
  BOTTOM w0.102: R447.1 136.56,52.01 136.56,51.18 v3(135.92,50.55) ; v3(34.07,44.7) 33.61,45.16 33.61,50.39 35.42,52.2 35.42,59.23 v2(34.96,59.69) 33.69,59.69 33.31,59.31 RN14.2
BAT_IN#_1: length 10.4
  TOP w0.102: v3(33.94,64.14) 33.94,64.14 BAT2.5
  BOTTOM w0.102: v3(33.94,64.14) 32.74,62.93 PC278.1 PL15.1 31.66,62.48 v2(32.93,61.21) 31.91,61.21 31.15,60.45 31.15,59.44 31.28,59.31 RN14.7
BATA_SCL_1: length 14.5
  TOP w0.102: v3(33.87,66.68) 33.41,67.14 BAT2.3
  BOTTOM w0.102: RN14.5 31.11,58.15 30.41,58.85 30.41,66.32 v2(30.64,66.55) 30.83,66.74 PL13.1 PC276.1 33.81,66.74 v3(33.87,66.68)
BATA_SDA_1: length 12
  TOP w0.102: v3(33.94,65.66) 33.92,65.64 BAT2.4
  BOTTOM w0.102: RN14.6 31.14,58.8 30.89,59.05 30.89,61.34 v2(31.02,61.47) 30.89,61.59 30.89,64.96 PL14.1 PC277.1 33.88,65.72 v3(33.94,65.66)
BATLOW#: length 16.9
  TOP w0.102: v1(90.87,152.38) 91.2,152.05 CPU1.AU13
  BOTTOM w0.102: v1(90.87,152.38) 90.99,152.49 91.95,152.49 92.6,151.84 92.76,151.84 94.61,149.99 v2(102.4,149.99) 105.89,149.99 R595.2
BATT_AMBER_LED#_C: length 8
  TOP w0.254: v3(27.26,20.22) 27.3,20.25 PWRCN1.10 32.08,20.25 v4(32.6,19.74)
  BOTTOM w0.254: R850.2 28.15,19.84 v2(27.95,19.63) 27.37,20.22 v3(27.26,20.22)
BATT_WHITE_LED#_C: length 20.9
  TOP w0.254: v4(24.65,29.46) 24.95,29.16 24.95,22.96 v3(26.07,21.84) 26.38,21.84 26.98,21.25 PWRCN1.8
  BOTTOM w0.254: R843.2 28.89,21.31 v2(27.41,21.31) 26.72,21.31 26.19,21.84 v3(26.07,21.84) 25.45,22.46 Q78.3 25.45,23.89 25.94,24.38 Q77.C
BIST_DISABLE: length 91
  TOP w0.102: KBC1.118 128.22,54.7 v1(127.16,55.75)
  L4 w0.127: v3(86.66,55.01) 87.52,55.01 87.7,54.83 89.98,54.83 90.19,55.03 93.8,55.03 94,54.83 106.05,54.83 107.35,53.52 121.25,53.52 122.91,55.18 126.59,55.18 v1(127.16,55.75)
  BOTTOM w0.102: v3(86.66,55.01) 86.65,55.02 v2(86.65,56.77) 86.65,58.21 85.5,59.35 85.5,62.15 82.26,65.39 82.26,67.48 71.56,78.18 58.31,78.18 R706.1 R707.1 R708.2
BIST_DISABLE_1: length 3.8
  BOTTOM w0.254: Q58.5 55.66,75.56 56.55,76.45 v2(56.55,76.83) 56.17,77.22 R707.2
BIST_EN: length 7.5
  TOP w0.254: v3(56.62,74.75) 56.61,74.76 R332.2 Q33.2
  BOTTOM w0.254: v3(56.62,74.75) 56.62,75.49 v2(56.55,75.56) 55.9,74.91 Q58.6 54.53,74.91 54.26,75.18 54.26,75.82 53.87,76.22 Q58.3
BIST_EN_INV: length 119.8
  TOP w0.102: v1(53.88,71.25) 53.93,71.2 55.48,71.2 55.57,71.29 SCA1.63 55.57,73.1 54.43,74.24 53.37,74.24 53.25,74.12 v4(51.98,74.12) 51.98,74.32 52.57,74.91 Q33.6 53.99,74.91 54.26,75.18 54.26,76.07 54.4,76.22 Q33.3 56.25,76.22 R324.2 ; v1(143.29,54.1) 143.48,54.3 KBC1.42
  L4 w0.127: v1(53.88,71.25) 53.94,71.18 53.94,65.24 56.53,62.66 65.02,62.66 66.55,64.2 70.33,64.2 73.65,60.88 73.65,60.71 74.01,60.36 79.81,60.36 80.62,61.18 81.26,61.18 83.72,58.71 103.57,58.71 104.41,57.87 122.96,57.87 123.86,56.97 131.88,56.97 132.76,57.85 141.61,57.85 143.73,55.72 143.73,54.55 v1(143.29,54.1)
BIST_ENABLE: length 111
  TOP w0.102: v1(142.53,54.1) 143.12,54.7 KBC1.43
  L4 w0.127: v3(87.3,54.5) 87.62,54.18 88.01,54.18 88.41,54.57 90.09,54.57 90.29,54.78 93.69,54.78 93.9,54.57 105.94,54.57 107.29,53.22 123.39,53.22 125.1,54.93 132.93,54.93 133.31,55.31 141.35,55.31 142.53,54.13 v1(142.53,54.1)
  BOTTOM w0.102: v3(87.3,54.5) v2(87.3,55.63) 87.3,58 85.73,59.56 85.73,62.24 82.49,65.48 82.49,67.57 71.66,78.41 58.44,78.41 57.64,79.21 57.64,79.59 57.4,79.83 52.51,79.83 52.17,79.49 R705.1
BIST_ENABLE_1: length 8.5
  TOP w0.102: v3(52.58,77.5) 52.58,78.26 v4(52.23,78.61) 52.1,78.49 52.1,76.07 52.61,75.56 Q33.5
  BOTTOM w0.102: v3(52.58,77.5) 53.06,77.98 R710.1 R705.2 53.12,79.31 R709.2
BIST_PIN25: length 122.2
  TOP w0.102: KBC1.82 136.34,66.25 v1(136.63,66.55)
  L4 w0.127: v3(41.18,97.28) 42.68,95.78 42.68,85.02 51.51,76.19 60.67,76.19 61,76.52 64.55,76.52 65.19,75.88 75.03,75.88 75.47,75.44 81.96,75.44 89.36,68.03 97.66,68.03 99.59,66.1 121.38,66.1 123.81,68.53 129.21,68.53 129.9,67.84 130.39,67.84 130.76,67.48 135.71,67.48 v1(136.63,66.55)
  BOTTOM w0.102: Q56.G 39.02,98.96 39.02,98.3 39.85,97.47 v2(39.85,97.28) v3(41.18,97.28)
BKLT_ADJ: length 4.9
  TOP w0.165: v3(43.84,25.48) 43.84,25.47 43.67,25.3 R492.2 43.61,24.64 R487.2 42.64,23.62 C252.1 C251.1
  BOTTOM w0.165: v2(43.04,25.62) 43.7,25.62 v3(43.84,25.48)
BKLT_EN: length 7.7
  BOTTOM w0.102: C592.1 R841.2 43.59,23.56 R838.2 43.59,23.69 R836.2 41.9,25.38 v2(41.9,26.17) 41.9,28.18 Q76.C
BKLT_EN1: length 5.2
  BOTTOM w0.102: R832.2 45.69,28.51 v2(45.47,28.73) 44.9,29.31 Q76.B
BP_PWRGD_RST#: length 21.3
  TOP w0.102: XDP1.41 29.83,216.11 28.52,217.42 27.95,217.42 27.57,217.81 27.57,217.86 26.6,218.82 19.55,218.82 18.42,219.95 18.42,223.81 R4.1 C1.1 19.91,224.22 v4(21.01,225.32)
BPM_CPU_N0: length 106.9
  TOP w0.089: 70.39,175.19 71.12,175.93 72.03,175.93 72.13,176.03 CPU1.C55
  TOP w0.102: 70.39,175.19 69.87,174.68 68.35,174.68 67.26,173.58 65.84,173.58 65.12,172.87 63.47,172.87 62.8,173.54 62.8,177.89 63.41,178.5 63.41,181.89 v3(64.4,182.88) ; XDP1.21 24.83,216.32 v3(24.42,216.73)
  L3 w0.127: v3(24.42,216.73) 24.42,216.78 26.92,219.29 39.36,219.29 39.77,219.71 56.72,219.71 58.88,217.55 66.17,217.55 v3(66.77,218.16)
  BOTTOM w0.102: v3(64.4,182.88) 64.4,182.91 63.91,183.39 63.91,186.46 63.92,186.46 v2(63.92,186.57) 63.92,188.49 63.91,188.49 63.91,191.15 65.07,192.3 66.03,192.3 68.61,194.88 68.61,215.59 66.77,217.42 v3(66.77,218.16)
BPM_CPU_N1: length 114.7
  TOP w0.089: CPU1.D55 73.31,175.39 73.06,175.13 72.26,175.13 71.9,175.05 arc(71.85,175.03) 71.81,175 70.61,173.81 70.4,173.81 70.11,173.51
  TOP w0.102: 70.11,173.51 70.04,173.44 70.04,173.38 69.63,172.97 v3(68.61,172.97) ; XDP1.23 25.33,216.61 v3(25.18,216.76) ; v3(86.26,199.51) 84.28,201.49 v4(84.28,201.96) 82.18,204.06 80.78,204.06 v3(67.67,217.17)
  L3 w0.127: v3(67.67,217.17) 67.64,217.21 58.87,217.21 56.62,219.46 39.88,219.46 39.46,219.04 27.03,219.04 25.18,217.19 v3(25.18,216.76)
  L4 w0.127: v3(68.61,172.97) 68.61,184.73 70.73,186.86 70.73,186.86 70.98,187.11 70.99,187.11 83.39,199.51 v3(86.26,199.51)
BPM_CPU_N2: length 3.7
  TOP w0.089: 70.49,173.99 71.61,175.11 arc(71.68,175.16) 71.75,175.19 71.88,175.25 CPU1.B54
  TOP w0.102: 70.49,173.99 70.26,173.99 69.86,173.58 TP35.1
BPM_CPU_N3: length 4.2
  TOP w0.089: CPU1.C56 72.79,176.59 72.5,176.3 72.12,176.3 71.95,176.13 71.01,176.13 70.49,175.61 69.75,175.61 TP34.1
BQ24737_REGN: length 8.3
  BOTTOM w0.305: 39.58,47.75 40.52,46.81 41.12,46.81 PU34.16
  BOTTOM w0.508: v2(36.23,50.16) 35.91,49.85 PR248.1 PD3.A 38.45,47.63 PC282.2 38.83,47.75 39.58,47.75
BT+:
  vias: v4(36.74,70.1)
BUFRST_N: length 10.6
  TOP w0.127: v1(85.9,91.3) 85.5,91.7 GPU1.D11
  BOTTOM w0.127: R697.1 81.57,85.09 83.94,87.46 85.85,87.46 86.16,87.78 86.16,89.89 v2(86.01,90.04) 85.9,90.16 v1(85.9,91.3)
BUZZER_SPKR_R: length 35.9
  TOP w0.102: v3(156.12,82.93) 155.74,82.55 R305.1 ; C183.1 v3(154.08,54.61)
  L3 w0.127: v3(156.12,82.93) 157.64,81.41 157.64,79.76 158.11,79.29 158.11,76.45 157.92,76.26 157.92,69.75 151.33,63.16 151.33,57.37 v3(154.08,54.61)
  BOTTOM w0.102: v2(153.27,54.58) 153.37,54.58 153.37,54.58 154.06,54.58 v3(154.08,54.61)
CAGND: length 19.6
  TOP w0.508: v3(31.1,30.78) 31.59,30.78 v3(34.27,28.1)
  L3 w0.508: v3(36.23,25.65) 36.23,21.97 34.93,20.68 v3(34.93,20.07)
  BOTTOM w0.254: R845.2 C593.2 36.42,20.26 35.78,20.89 R846.2
  BOTTOM w0.305: U36.15 v3(34.27,28.1)
  BOTTOM w0.508: 33.56,19.68 33.94,20.07 v3(34.93,20.07) 34.93,20.61 R846.2 ; v3(31.1,30.78) 30.31,30.78 C587.2 30.2,29.27 R829.2
  vias: v3(35.47,26.42) v3(36.23,27.18) v3(36.23,26.42) v3(36.99,26.42) v4(35.34,25.4)
CATERR#_CPU: length 3.8
  TOP w0.102: CPU1.D63 74.22,179.84 v1(74.69,179.84)
  BOTTOM w0.102: TP56.1 73.82,179.2 74.46,179.84 v1(74.69,179.84)
CBN: length 6.9
  TOP w0.203: 162.97,70.76 162.97,70.96 163.51,71.49 163.51,71.65 163.53,71.67 163.53,72.57 163.59,72.63 U11.21
  TOP w0.508: 162.97,70.76 v3(162.97,68.83) C154.2
  BOTTOM w0.508: v2(163.43,68.02) 163.43,68.38 v3(162.97,68.83)
CBP: length 7.1
  TOP w0.203: U11.24 164.79,72.98 165.39,72.39 v3(165.39,72.14)
  TOP w0.508: C154.1 164.5,68.83 v3(164.5,69.22)
  L3 w0.508: v3(164.5,69.22) 164.5,71.25 v3(165.39,72.14)
  BOTTOM w0.203: v3(165.39,72.14) v2(165.39,71.32)
CE: length 7.2
  TOP w0.102: SCA1.106 58.77,55.43 v3(58.9,55.31) 58.9,54.67 58.2,53.98 R416.1
  BOTTOM w0.102: v2(58.83,58.17) 59.02,57.98 R761.1 R765.1 59.02,55.44 v3(58.9,55.31)
CE#_1: length 12.3
  TOP w0.102: R416.2 58.2,51.56 v3(58.71,51.05)
  BOTTOM w0.102: U33.1 62.83,56.32 62.06,57.1 v2(61.04,57.1) 60.74,56.79 60.74,54.61 58.71,52.58 v3(58.71,51.05)
CFG: length 6.9
  TOP w0.102: v3(129.2,36.57) 129.21,36.56 U17.23
  BOTTOM w0.102: v3(129.2,36.57) 129.2,36.58 129.12,36.66 v2(129.12,37.97) 129.12,39.1 129.4,39.38 129.4,41.54 R796.2
CFG0: length 103
  TOP w0.089: CPU1.E68 73.63,182.9 73.04,183.48 73.04,183.96 v1(72.81,184.19)
  TOP w0.102: v3(44.1,225.43) 44.36,225.17 R20.1 ; v3(20.99,217.93) 20.99,216.9 21.51,216.38 21.56,216.38 21.83,216.1 XDP1.9
  L4 w0.127: v3(71.15,220.85) 70.45,220.15 64.86,220.15 64.17,220.85 64.17,222.41 62.04,224.54 44.99,224.54 v3(44.1,225.43) 43.02,224.35 29.3,224.35 27.97,223.02 27.97,220.06 25.84,217.93 v3(20.99,217.93)
  BOTTOM w0.102: v3(71.15,220.85) 71.99,220.01 71.99,219.53 73.31,218.21 73.31,205.71 73.03,205.43 73.03,192.32 71.71,191 71.71,185.29 72.06,184.94 v2(72.07,184.94) 72.07,184.93 v1(72.81,184.19)
CFG1: length 93.1
  TOP w0.089: v1(70.78,184.28) 70.89,184.17 70.89,183.95 71.65,183.18 72.03,183.18 72.31,182.9 CPU1.B67
  TOP w0.102: v3(22.26,217.04) 22.33,216.97 XDP1.11
  L3 w0.127: v3(22.26,217.04) 25.94,220.73 34.04,220.73 35.43,222.11 55.5,222.11 55.5,222.11 56.12,222.11 58.39,219.84 69.51,219.84 71.54,217.81 v3(72.17,217.81)
  BOTTOM w0.102: v1(70.78,184.28) 70.54,184.52 70.54,189.13 v2(70.87,189.46) 71.25,189.84 71.25,191.19 72.58,192.51 72.58,205.62 72.85,205.9 72.85,217.12 v3(72.17,217.81)
CFG2: length 95.8
  TOP w0.089: CPU1.D65 73.25,181.94 71.26,181.94 70.99,182.21
  TOP w0.102: v3(70.77,190.5) 70.31,190.04 70.31,189.12 R72.1 70.31,188.2 70.31,182.89 70.99,182.21 ; v3(23.02,217.04) 23.33,216.73 XDP1.15
  L3 w0.127: v3(23.02,217.04) 23.02,217.08 26.41,220.47 34.14,220.47 35.53,221.86 56.01,221.86 58.29,219.58 69.41,219.58 71.95,217.04 v3(72.17,217.04)
  BOTTOM w0.102: v3(70.77,190.5) 70.77,191.03 72.35,192.61 72.35,215.81 72.63,216.09 72.63,216.59 v3(72.17,217.04) ; v2(23.02,217.88) v3(23.02,217.04)
CFG3: length 107.1
  TOP w0.102: R73.1 72.8,188.34 v1(71.15,186.69) 70.75,186.28 70.75,185.19 71.38,184.56 71.38,184.08 71.56,183.9 71.79,183.9 72.79,182.9 CPU1.D67 ; v3(21.5,217.04) 21.95,217.5 23.58,217.5 23.83,217.24 XDP1.17 23.83,213.62 23.53,213.31 23.47,213.31 22.51,212.36 22.51,212.23 21.42,211.14 20.05,211.14 R58.1
  L3 w0.127: v3(72.17,218.57) 71.14,218.57 69.62,220.09 58.5,220.09 56.22,222.37 55.4,222.37 55.4,222.37 35.26,222.37 33.87,220.98 25.43,220.98 v3(21.5,217.04)
  BOTTOM w0.102: v3(72.17,218.57) 73.08,217.65 73.08,205.8 72.8,205.52 72.8,192.42 71.48,191.1 71.48,187.83 71.16,187.51 v2(71.16,187.48) 71.15,187.47 v1(71.15,186.69)
CFG4: length 96.8
  TOP w0.089: CPU1.E70 73.82,184.84 73.82,185.35 73.19,185.98 73.19,186.46 v1(72.55,187.1)
  TOP w0.102: v1(72.55,187.1) 72.55,187.38 73.82,188.65 R74.1 ; v3(25.84,217.18) 25.84,216.6 26.33,216.1 XDP1.27
  L4 w0.127: v3(25.84,217.18) 25.84,217.57 28.27,219.99 28.27,222.95 29.4,224.09 43.13,224.09 43.28,224.24 59.38,224.24 v3(59.85,223.77)
  BOTTOM w0.102: v1(72.55,187.1) 72.5,187.15 72.5,190.77 73.72,191.99 73.72,205.14 74,205.42 74,219.84 68.93,224.92 60.99,224.92 v2(60.67,224.6) v3(59.85,223.77)
CFG5: length 102
  TOP w0.102: v3(26.5,216.74) 26.83,216.4 XDP1.29 ; CPU1.C68 73.46,183.62 74.06,183.02 v1(74.24,183.02)
  L4 w0.127: v3(26.5,216.74) 26.64,216.74 29.5,219.6 29.5,223.08 30,223.58 48.61,223.58 49.18,223.01 61.68,223.01 63.91,220.78 63.91,220.74 64.82,219.84 69.63,219.84 69.97,219.49 71.47,219.49 73.06,221.08 73.06,223.82 v3(73.17,223.93)
  BOTTOM w0.102: v3(73.17,223.93) 73.17,223.91 v2(74.94,222.15) 75.37,221.72 75.37,204.85 75.09,204.57 75.09,191.31 74.92,191.14 74.92,184.05 74.24,183.37 v1(74.24,183.02)
CFG6: length 93.8
  TOP w0.089: v1(72.54,186.45) 72.93,186.06 72.93,185.96 72.94,185.96 72.94,185.6 73.1,185.44 73.1,185.05 73.46,184.68 CPU1.D68
  TOP w0.102: v3(26.76,217.52) 27.83,216.44 XDP1.33
  L4 w0.127: v3(26.76,217.52) 29.24,220.01 29.24,223.18 29.9,223.84 48.72,223.84 49.25,223.3 60.14,223.3 v3(60.61,223.77)
  BOTTOM w0.102: v3(60.61,223.77) 61.53,224.69 68.44,224.69 v2(70.8,222.33) 73.77,219.35 73.77,205.52 73.49,205.24 73.49,192.09 72.17,190.77 72.17,187.4 72.14,187.37 72.14,186.84 v1(72.54,186.45)
CFG7: length 94.8
  TOP w0.089: v1(72.54,185.79) 72.5,185.76 72.5,185.23 72.32,185.05 72.21,184.98 72.19,184.98 72.03,184.82 72.02,184.71 72.02,183.93 72.46,183.49 CPU1.C67
  TOP w0.102: v3(61.37,223.77) 61.25,223.65 61.25,220.74 60.19,219.68 40.65,219.68 36.15,215.19 36.15,213.09 35.15,212.08 33.34,212.08 32.83,212.6 29.12,212.6 28.33,213.38 XDP1.35
  BOTTOM w0.102: v3(61.37,223.77) 62.06,224.46 67.72,224.46 70.87,221.31 71.34,221.31 72.91,219.75 72.91,219.34 v2(72.91,219.33) 73.54,218.7 73.54,205.61 73.26,205.33 73.26,192.23 71.94,190.91 71.94,186.39 v1(72.54,185.79)
CFG8: length 97.1
  TOP w0.089: CPU1.F71 74.56,184.92 74.56,186.48 v1(73.78,187.25)
  TOP w0.102: XDP1.10 21.83,222.45 21.95,222.57 21.95,225.1 24.5,227.65 53.06,227.65 v3(53.75,226.95)
  BOTTOM w0.102: v3(53.75,226.95) v2(54.59,226.11) 55.13,225.58 58.13,225.58 58.16,225.6 69.21,225.6 74.68,220.13 74.68,205.14 74.4,204.86 74.4,191.71 74.23,191.53 74.23,187.7 v1(73.78,187.25)
CFG9: length 97.4
  TOP w0.089: CPU1.G69 74.88,184.48 74.88,185.01 74.74,185.15 74.74,186.93 v1(73.78,187.88)
  TOP w0.102: v3(52.99,226.95) 52.52,227.42 24.6,227.42 22.33,225.16 XDP1.12
  BOTTOM w0.102: v3(52.99,226.95) 54.59,225.35 58.23,225.35 58.25,225.37 69.11,225.37 74.46,220.03 74.46,205.23 74.18,204.95 74.18,191.8 73.68,191.3 v2(73.68,189.73) 73.68,187.99 v1(73.78,187.88)
CFG10: length 97.4
  TOP w0.089: v1(73.78,186.61) 74.36,186.04 74.36,185.16 74.36,185.16 74.36,184.69 74.68,184.37 CPU1.F70
  TOP w0.102: XDP1.16 23.33,225.83 24.69,227.19 51.5,227.19 52.2,226.49 54.06,226.49 v3(54.52,226.95)
  BOTTOM w0.102: v3(54.52,226.95) 55.66,225.81 58.04,225.81 58.06,225.83 69.71,225.83 70.01,225.53 v2(70.04,225.53) 70.04,225.5 74.91,220.62 74.91,205.04 74.63,204.76 74.63,191.5 74.46,191.33 74.46,187.29 v1(73.78,186.61)
CFG11: length 100
  TOP w0.102: v1(74.87,183.01) 75.23,183.36 CPU1.G68 ; v3(56.04,226.95) 55.35,226.26 52.11,226.26 51.41,226.96 24.79,226.96 23.83,226.01 XDP1.18
  BOTTOM w0.102: v1(74.87,183.01) 74.87,183.73 75.15,184.01 75.15,191.04 75.32,191.21 75.32,204.48 75.6,204.76 75.6,222.35 v2(71.94,226.01) 71.66,226.29 57.87,226.29 57.85,226.26 56.73,226.26 v3(56.04,226.95)
CFG12: length 100.5
  TOP w0.089: CPU1.H70 76.21,184.64 76.21,185.37 76.42,185.58 76.42,186 v1(76.01,186.4)
  TOP w0.102: v3(25.79,225.81) 26.33,225.26 XDP1.28
  BOTTOM w0.102: v1(76.01,186.4) 77.12,187.51 77.12,191.32 76.69,191.75 76.69,203.91 76.97,204.19 76.97,225.37 74.24,228.1 28.09,228.1 v2(26.6,226.62) v3(25.79,225.81)
CFG13: length 96.7
  TOP w0.089: CPU1.G71 75.36,185.43 75.36,186.99
  TOP w0.102: v3(27.34,225.81) 26.69,225.16 26.69,223.56 26.83,223.41 XDP1.30 ; 75.36,186.99 v1(76.04,187.67)
  BOTTOM w0.102: v3(27.34,225.81) 29.17,227.63 73.67,227.63 v2(74.33,226.97) 76.51,224.79 76.51,204.38 76.23,204.1 76.23,191.56 76.66,191.13 76.66,188.3 v1(76.04,187.67)
CFG14: length 102.2
  TOP w0.089: CPU1.H69 75.9,183.82 75.7,184.02 75.67,184.13 75.63,184.24 75.61,184.25 75.61,186.63
  TOP w0.102: v3(26.58,225.81) 27.03,226.26 27.59,226.26 27.83,226.02 27.83,225.6 27.53,225.3 27.29,225.3 26.92,224.93 26.92,223.82 27.83,222.91 XDP1.34 ; 75.61,186.63 v1(76.02,187.04)
  BOTTOM w0.102: v3(26.58,225.81) v2(28.36,227.59) 28.63,227.86 74.16,227.86 76.74,225.28 76.74,204.28 76.46,204.01 76.46,191.66 76.89,191.23 76.89,187.91 v1(76.02,187.04)
CFG15: length 96
  TOP w0.089: CPU1.G70 75.24,184.9 74.98,185.16 74.98,187.3
  TOP w0.102: XDP1.36 28.33,222.07 28.28,222.12 28.28,222.79 27.44,223.63 27.44,224.13 28.28,224.97 28.28,225.73 v3(28.35,225.81) ; 74.98,187.3 v1(76.08,188.4)
  BOTTOM w0.102: v3(28.35,225.81) 29.95,227.41 72.97,227.41 v2(75.83,224.55) 76.28,224.1 76.28,204.47 76,204.19 76,191.47 76.44,191.03 76.44,188.76 v1(76.08,188.4)
CFG16: length 105.2
  TOP w0.102: CPU1.E63 74.35,180.42 74.68,180.76 v1(74.68,180.79) ; v3(55.28,226.95) 54.35,227.88 24.41,227.88 20.99,224.46 20.99,222.53 20.83,222.38 XDP1.6
  BOTTOM w0.102: v1(74.68,180.79) 74.42,181.05 73.88,181.05 72.52,182.41 72.52,183.06 73.44,183.97 73.44,185.06 74.69,186.31 74.69,191.23 74.86,191.4 74.86,204.67 75.14,204.95 75.14,221.16 v2(72.22,224.08) 70.24,226.06 57.97,226.06 57.94,226.03 56.19,226.03 v3(55.28,226.95)
CFG17: length 110.8
  TOP w0.102: v3(20.53,222.76) 20.33,222.56 XDP1.4 ; CPU1.F63 75,180.2 v1(75.37,179.83)
  BOTTOM w0.102: v1(75.37,179.83) 74.85,179.31 74.46,179.31 73.81,178.66 71.94,178.66 71.6,179.01 71.6,181.01 70.36,182.25 70.36,183.3 70.83,183.77 72.97,183.77 73.22,184.02 73.22,188.84 72.73,189.33 72.73,190.68 73.95,191.9 73.95,205.05 74.23,205.33 74.23,219.94 69.02,225.15 58.35,225.15 58.32,225.12 54.5,225.12 53.74,225.88 v2(51.82,225.88) 34.77,225.88 34.32,225.44 34.32,223.3 33.33,222.3 20.99,222.3 v3(20.53,222.76)
CFG18: length 103.1
  TOP w0.102: v1(74.68,181.88) 74.35,182.21 CPU1.E66 ; v3(57.56,226.95) 56.42,225.81 51.92,225.81 51.22,226.5 24.98,226.5 24.47,226 24.47,223.98 25.33,223.11 XDP1.24
  BOTTOM w0.102: v3(57.56,226.95) 72.59,226.95 76.06,223.48 76.06,204.57 75.78,204.29 75.78,190.3 v2(75.93,190.14) 75.93,188.86 75.65,188.58 75.65,188.57 75.6,188.52 75.6,183.94 76.18,183.37 76.18,182.8 75.72,182.35 75.15,182.35 v1(74.68,181.88)
CFG19: length 101
  TOP w0.102: v3(56.8,226.95) 55.89,226.03 52.01,226.03 51.31,226.73 24.88,226.73 24.24,226.09 24.24,223.82 24.83,223.23 XDP1.22 ; CPU1.F66 75.15,182.35 v1(75.77,182.97)
  BOTTOM w0.102: v1(75.77,182.97) 75.38,183.37 75.38,190.95 75.55,191.12 75.55,204.38 75.83,204.66 75.83,222.99 v2(73.95,224.87) 72.3,226.52 57.78,226.52 57.75,226.49 57.26,226.49 v3(56.8,226.95)
CFG_RCOMP: length 3.1
  TOP w0.203: CPU1.E60 74.41,178.3 v1(74.73,177.98)
  BOTTOM w0.203: v2(76.21,177.93) 76.21,178.17 R553.1 74.73,178.14 v1(74.73,177.98)
CHG_AGND: length 32.2
  TOP w0.406: v3(55.86,43.31) 55.48,42.93 PQ4.1 56.15,42.56 56.52,42.19 56.52,41.57 56.83,41.26 PQ4.4
  TOP w0.508: v3(36.61,41.78) 36.61,41.61 37.68,40.54 39.96,40.54 40.42,41 40.42,42.39 41.69,43.66
  L3 w0.508: v3(35.19,46.94) 36.61,45.51 v3(36.61,41.78)
  L4 w0.508: v3(55.86,43.31) 54.49,44.68 v3(45.63,44.68)
  BOTTOM w0.508: v3(36.61,41.78) 35.97,41.78 v2(35.72,42.04) 35.72,42.61 PC285.2 ; v3(35.19,46.94) 35.38,46.74 35.93,46.74 36.36,46.31 C570.2
CHG_ON#: length 124.7
  TOP w0.102: PQ2.G 33.87,45.94 33.18,45.26 v4(33.18,44.7) 33.18,44.2 33.43,43.94 v3(34.07,43.94) ; v1(141.64,50.42) 141.54,50.32 KBC1.28
  L4 w0.127: v3(34.07,43.94) 34.95,43.07 38.07,43.07 43.76,37.38 59.66,37.38 68.75,46.47 71.29,46.47 71.52,46.7 80.33,46.7 81.8,48.17 97.69,48.17 98.8,47.05 118.11,47.05 120.43,49.36 125.67,49.36 125.88,49.57 128.76,49.57 128.78,49.56 133.97,49.56 134.43,50.01 136.08,50.01 136.77,49.31 140.53,49.31 v1(141.64,50.42)
  BOTTOM w0.102: PR103.2 141.77,50.29 v1(141.64,50.42)
CHG_SMB2_CLK: length 150.4
  TOP w0.203: KBC1.70 141.14,63.23 141.13,63.22
  TOP w0.254: 141.13,63.22 141.13,62.64 140.08,61.59 139.09,61.59 138.36,60.86 138.36,59.72 138.08,59.44 v1(138.08,59.46)
  L3 w0.254: v1(138.08,59.46) 138.08,59.44 138.31,59.2 138.31,58.82 134.8,55.3 131.15,55.3 128.43,52.58 128.43,50.34 127.9,49.81 123.75,49.81 123.41,49.47 117.83,49.47 117.39,49.91 114.33,49.91 113.88,49.47 110.86,49.47 110.77,49.56 107.2,49.56 106.84,49.91 105.47,49.91 103.95,51.44 102.65,51.44 102.17,50.96 102.17,50.01 102.65,49.53 103.36,49.53 v3(103.67,49.23) ; v3(41.31,42.16) 41.48,42.34 41.48,42.85 40.52,43.81 39.35,43.81 35.59,47.57 35.59,56.99 35.2,57.39 34.82,57.39 v3(34.58,57.15)
  L4 w0.254: v3(103.67,49.23) 103.36,49.53 102.7,49.53 102.34,49.89 81.09,49.89 79.62,48.41 69.91,48.41 69.71,48.21 62.32,48.21 60.04,45.93 60.04,43.05 57.6,40.61 42.86,40.61 v3(41.31,42.16)
  BOTTOM w0.254: v2(33.71,57.12) 33.71,57.53 ; 33.71,57.53 34.2,57.53 v3(34.58,57.15) ; 33.71,57.53 33.09,58.15 RN14.4 ; v1(138.08,59.46) 138.26,59.64 138.26,60.41 138.43,60.58 140.88,60.58 141.07,60.77 141.07,61.09 PR105.2 ; v3(41.31,42.16) 41.69,42.55 41.69,42.67 41.82,42.81 PU34.9
CHG_SMB2_DATA: length 148.7
  TOP w0.203: 141.54,63.53 KBC1.69
  TOP w0.254: 141.54,63.53 141.51,63.51 141.51,62.48 140.24,61.21 139.25,61.21 138.74,60.71 138.74,59.54 138.84,59.44 v1(138.84,59.46)
  L3 w0.254: v1(138.84,59.46) 138.84,59.44 138.7,59.29 138.7,58.66 134.96,54.92 131.31,54.92 128.81,52.42 128.81,50.18 128.06,49.43 123.91,49.43 123.57,49.09 117.67,49.09 117.23,49.53 114.48,49.53 114.04,49.09 110.71,49.09 110.62,49.17 107.04,49.17 106.68,49.53 105.32,49.53 103.79,51.05 102.81,51.05 102.55,50.8 102.55,50.16 102.81,49.91 103.36,49.91 v3(103.67,50.21) ; v3(34.58,57.91) 34.72,57.77 35.35,57.77 35.97,57.15 35.97,47.73 39.5,44.2 40.67,44.2 41.86,43 41.86,42.37 v3(42.07,42.16)
  L4 w0.254: v3(42.07,42.16) 42.07,41.94 43.02,41 57.44,41 59.66,43.21 59.66,46.09 62.16,48.59 69.55,48.59 69.75,48.79 79.46,48.79 80.94,50.27 102.5,50.27 102.85,49.91 103.36,49.91 v3(103.67,50.21)
  BOTTOM w0.254: RN14.3 33.43,58.8 v2(33.71,58.52) 34.32,57.91 v3(34.58,57.91) ; v1(138.84,59.46) 138.64,59.66 138.64,59.94 138.89,60.2 141.03,60.2 141.45,60.61 141.45,61.09 PR106.2 ; PU34.8 42.32,42.42 v3(42.07,42.16)
CLINK_CLK_LAN: length 4.2
  TOP w0.102: NGFF1.42 120.06,215 120.43,214.63 121.67,214.63 TP12.1
CLINK_DATA_LAN: length 2.7
  TOP w0.102: TP11.1 120.51,214.05 120.05,214.5 NGFF1.40
CLINK_RST_LAN_N: length 5.6
  TOP w0.102: NGFF1.38 119.79,214 120.33,213.46 123.12,213.46 TP13.1
CLK: length 5.1
  TOP w0.102: SCA1.103 57.57,55.89 55.48,53.8 v4(55.15,53.8) R413.2
CLK_1: length 4.2
  TOP w0.102: v3(54.52,51.05) 54.39,51.05 53.75,51.69 v4(53.75,51.82) 53.88,51.94 55.09,51.94 R413.1
  BOTTOM w0.102: v3(54.52,51.05) 55.15,51.69 U33.6
CLK_CR_N: length 198.5
  TOP w0.102: CPU1.D40 74.06,168.03 v1(74.15,167.94)
  L3 w0.127: v1(74.15,167.94) 74.15,167.82 73.48,167.14 73.48,166.41 71.78,164.71 68.6,164.71 64.87,160.97 61.08,160.97 60.17,160.06 60.17,153.35 62.26,151.26 62.9,151.26 64.8,149.35 64.8,148.72 63.28,147.19 63.28,138.08 72.02,129.34 79.09,129.34 93.87,114.55 125.49,114.55 129.93,110.11 150.58,110.11 150.93,109.75 151.57,109.75 v3(151.93,110.11)
  BOTTOM w0.102: v3(151.93,110.11) 152.24,109.79 152.34,109.79 152.47,109.92 152.47,110.91 152.36,111.02 152.36,111.31 152.47,111.42 152.47,112.18 152.9,112.61 158.29,112.61 160.41,114.73 ; U28.6 177.46,144.94 177.55,145.03 179.38,145.03 180.4,144.02 180.4,143.66 180.29,143.55 180.29,143.24 180.4,143.13 180.4,142.83 180.29,142.71 180.29,142.41 180.4,142.3 180.4,141.99 180.29,141.88 180.29,141.58 180.4,141.46 180.4,133.84 161.35,114.8 160.47,114.8 160.41,114.73 ; v2(160.15,114.99) 160.41,114.73
CLK_CR_P: length 198.5
  TOP w0.102: CPU1.C40 72.99,167.78 v1(73.21,167.56)
  L3 w0.127: v1(73.21,167.56) 73.21,166.52 71.66,164.97 68.49,164.97 64.75,161.24 60.97,161.24 59.9,160.17 59.9,153.24 62.15,150.99 62.79,150.99 64.54,149.24 64.54,148.83 63.01,147.3 63.01,137.97 71.91,129.07 78.98,129.07 93.76,114.29 125.38,114.29 129.82,109.84 150.46,109.84 150.82,109.49 151.79,109.49 v3(151.93,109.35)
  BOTTOM w0.102: v3(151.93,109.35) 152.15,109.58 152.43,109.58 152.69,109.83 152.69,112.09 152.99,112.39 156.88,112.39 ; U28.5 177.46,145.34 177.55,145.25 179.47,145.25 180.61,144.11 180.61,133.75 161.44,114.58 160.56,114.58 158.38,112.39 156.88,112.39 ; v2(156.88,112.06) 156.88,112.39
CLK_GFX_N: length 99.7
  TOP w0.102: v1(88.37,107.9) 87.97,108.3 GPU1.AD8 ; CPU1.D42 73.95,169.16 74.26,168.85 v1(74.68,168.85)
  L3 w0.127: v1(74.68,168.85) 74.46,169.06 73.72,169.06 73.44,168.78 73.44,168.78 72.41,167.75 72.41,166.86 71.25,165.7 68.2,165.7 64.44,161.94 58.67,161.94 57.46,160.73 57.46,158.7 59.08,157.09 59.08,150.43 58.49,149.84 58.49,134.71 59.36,133.85 64.29,128.92 65.95,127.25 78.14,127.25 89.36,116.04 89.36,113.16 89.69,112.83 v3(90.66,112.83)
  BOTTOM w0.102: v1(88.37,107.9) 88.48,108 89.16,108 89.56,108.39 ; 89.56,108.39 v2(89.77,108.18) ; 89.56,108.39 89.85,108.69 89.85,110.11 90.01,110.27 90.01,112.54 90.3,112.83 v3(90.66,112.83)
CLK_GFX_P: length 100.2
  TOP w0.102: v1(73.9,168.63) 73.72,168.63 73.19,169.16 CPU1.C42 ; v1(88.37,108.7) 87.97,109.1 GPU1.AE8
  L3 w0.127: v3(90.61,113.59) 90.12,113.09 89.8,113.09 89.62,113.27 89.62,116.15 87.77,118.01 87.77,118.2 87.5,118.47 87.3,118.47 87.04,118.74 87.04,118.93 86.77,119.2 86.57,119.2 86.3,119.47 86.3,119.67 86.03,119.94 85.84,119.94 78.25,127.52 68.8,127.52 68.66,127.66 68.28,127.66 68.15,127.52 67.77,127.52 67.63,127.66 67.25,127.66 67.11,127.52 66.06,127.52 63.88,129.7 63.88,129.89 63.61,130.16 63.42,130.16 63.15,130.43 63.15,130.63 62.88,130.9 62.68,130.9 62.41,131.17 62.41,131.36 62.15,131.63 61.95,131.63 60.96,132.62 60.96,132.82 60.69,133.09 60.49,133.09 60.22,133.36 60.22,133.55 59.95,133.82 59.76,133.82 58.76,134.82 58.76,149.73 59.34,150.32 59.34,157.2 57.73,158.81 57.73,160.62 58.78,161.67 64.55,161.67 68.31,165.43 71.36,165.43 72.68,166.75 72.68,167.64 73.67,168.63 v1(73.9,168.63)
  BOTTOM w0.102: v1(88.37,108.7) 88.37,108.47 88.63,108.22 89.07,108.22 89.63,108.78 89.63,110.2 89.8,110.36 89.8,112.63 90.61,113.44 v3(90.61,113.59) 90.58,113.62 v2(90.58,114.43)
CLK_GLAN_N: length 209.9
  TOP w0.102: v3(29.5,57.02) 29.2,57.32 29.2,57.54 29.36,57.7 29.84,57.7 32.29,55.24 32.29,46.54 28.28,42.53 27.16,42.53 26.32,41.7 26.32,38.43 23.03,35.14 23.03,19.27 23.16,19.14 23.16,19.14 25.23,17.07 32,17.07 32.21,17.27 35.75,17.27 36.1,17.63 36.47,17.63 36.57,17.53 36.57,17.4 36.48,17.31 U23.16 ; v3(59.11,159.16) 58.85,159.42 58.85,160.4 59.18,160.73 59.18,167.04 60.87,168.74 71.91,168.74 CPU1.B42
  BOTTOM w0.102: v2(51.21,133.27) 50.92,133.27 ; 50.92,133.27 50.92,142.01 52.1,143.19 52.1,157.17 52.79,157.86 58.17,157.86 58.64,158.33 58.64,158.8 59,159.16 v3(59.11,159.16) ; 50.92,133.27 50.92,131.28 46.63,126.99 32.15,126.99 30.77,125.6 30.77,69.4 28.68,67.32 28.68,58.14 29.2,57.62 29.2,57.32 v3(29.5,57.02)
CLK_GLAN_P: length 209.9
  TOP w0.102: CPU1.A42 71.48,168.95 60.78,168.95 58.96,167.13 58.96,160.82 58.63,160.49 58.63,159.44 v3(58.35,159.16) ; U23.15 36.88,17.33 36.79,17.42 36.79,17.62 36.56,17.84 36.01,17.84 35.66,17.49 32.12,17.49 31.91,17.28 25.32,17.28 23.25,19.36 23.25,35.05 26.54,38.34 26.54,41.61 27.25,42.32 28.37,42.32 32.51,46.45 32.51,55.33 29.93,57.91 29.27,57.91 28.99,57.63 28.99,57.28 v3(28.74,57.02)
  BOTTOM w0.102: 50.71,135.1 50.71,131.37 46.54,127.2 32.06,127.2 30.55,125.69 30.55,69.49 28.47,67.41 28.47,58.05 28.99,57.53 28.99,57.28 v3(28.74,57.02) ; 50.71,135.1 v2(50.4,135.1) ; 50.71,135.1 50.71,142.1 51.89,143.28 51.89,157.26 52.7,158.08 58.08,158.08 58.43,158.42 58.43,159.08 v3(58.35,159.16)
CLK_WLAN_N: length 96.1
  TOP w0.102: R46.2 105.61,217.02 105.35,217.02 104.12,215.79 104.12,200.65 101.46,197.99 87.89,197.99 ; v3(80.42,202.56) 80.2,202.34 80.2,201.83 80.81,201.22 83.73,201.22 86.95,197.99 87.89,197.99 ; 87.89,197.99 v4(87.89,198.42) ; CPU1.D41 73.13,168.6 72.8,168.28 72.55,168.28 72.5,168.33 71.33,168.33 71.03,168.02 69.88,168.02 69.76,167.89 69.76,167.77 v1(70.01,167.51)
  L3 w0.127: v3(80.42,202.56) 80.18,202.33 80.18,200.42 78.07,198.31 75.35,198.31 67.71,190.67 67.71,176.29 68.99,175.01 70.26,175.01 72.17,173.1 72.17,169.42 71.15,168.4 70.21,168.4 69.83,168.02 69.83,167.7 v1(70.01,167.51)
CLK_WLAN_P: length 96
  TOP w0.102: R50.2 105.61,216.81 105.44,216.81 104.34,215.7 104.34,200.56 101.55,197.78 86.86,197.78 85.21,199.43 ; v4(84.92,199.14) 85.21,199.43 ; 85.21,199.43 83.64,201 80.72,201 79.99,201.74 79.99,202.24 v3(79.66,202.56) ; CPU1.C41 72.61,168.54 71.24,168.54 70.94,168.24 69.79,168.24 69.54,167.98 69.54,167.68 v1(69.38,167.51)
  L3 w0.127: v1(69.38,167.51) 69.56,167.7 69.56,168.13 70.1,168.67 71.04,168.67 71.9,169.53 71.9,172.99 70.15,174.74 68.88,174.74 67.44,176.18 67.44,190.78 75.24,198.58 77.96,198.58 79.92,200.53 79.92,202.31 v3(79.66,202.56)
CLKA0: length 38.1
  TOP w0.127: v1(57.81,88.12) 57.44,87.74 VRAM2.J12 ; v1(58.96,85.34) 58.96,84.94 60.1,83.8 60.1,83.12 R303.1 ; v1(75.16,92.14) 74.72,91.7 GPU1.D24
  L3 w0.152: v1(57.81,88.12) 57.35,87.65 57.35,87.39 57.81,86.92 57.81,86.16 58.15,85.83 58.48,85.83 v1(58.96,85.34) 58.76,85.14 58.76,84.91 58.96,84.71 74.43,84.71 75.19,85.48 76.13,85.48 76.31,85.65 76.31,85.91 76.13,86.09 75.19,86.09 74.86,86.42 74.86,86.97 75.19,87.3 76.31,87.3 76.49,87.48 76.49,87.74 76.31,87.91 75.24,87.91 74.38,88.77 74.38,90.95 74.71,91.28 74.71,91.69 v1(75.16,92.14)
  BOTTOM w0.127: VRAM2.J12 57.44,87.74 v1(57.81,88.12)
CLKA0#: length 38.6
  TOP w0.127: v1(58.2,85.34) 59.47,84.07 59.85,83.69 59.85,83.12 R302.1 ; v1(57.04,88.11) 57.44,88.51 VRAM2.J11 ; v1(75.14,91.28) 74.32,91.28 GPU1.D25
  L3 w0.152: v1(57.04,88.11) 57.04,87.26 57.51,86.8 57.51,86.03 v1(58.2,85.34) 58.45,85.09 58.45,84.79 58.83,84.4 74.55,84.4 75.32,85.17 76.26,85.17 76.61,85.53 76.61,86.03 76.26,86.39 75.32,86.39 75.17,86.54 75.17,86.85 75.32,87 76.43,87 76.79,87.36 76.79,87.86 76.43,88.22 75.36,88.22 74.68,88.9 74.68,90.82 v1(75.14,91.28)
  BOTTOM w0.127: VRAM2.J11 57.44,88.51 v1(57.04,88.11)
CLKA1: length 42
  TOP w0.127: VRAM1.J12 57.39,112.94 v1(57.79,113.35) ; GPU1.N22 76.34,99.41 76.49,99.56 v1(76.74,99.56)
  L4 w0.152: v1(76.74,99.56) 76.74,99.32 76.87,99.19 77.07,99.19 77.39,99.51 77.39,104.64 76.74,105.29 76.74,106.35 75.9,107.19 75.9,107.8 66.77,116.93 58.24,116.93 58.05,116.74 58.05,116.5 58.36,116.19 58.82,116.19 v1(58.83,116.18) 58.83,115.82 58.58,115.57 57.74,115.57 57.19,115.02 57.19,113.11 57.31,112.99 57.69,112.99 57.79,113.09 v1(57.79,113.35)
  BOTTOM w0.127: VRAM1.J12 57.39,112.94 v1(57.79,113.35) ; v1(58.83,116.18) 58.58,116.43 58.58,117.41 R660.1
CLKA1#: length 42
  TOP w0.127: v1(57.79,112.56) 57.39,112.16 VRAM1.J11 ; GPU1.M22 v1(76.74,98.76)
  L4 w0.152: v1(57.79,112.56) 57.67,112.68 57.19,112.68 56.88,112.99 56.88,115.14 57.74,116 v1(57.74,116.2) 57.74,116.87 58.11,117.23 66.9,117.23 76.21,107.92 76.21,107.31 77.05,106.48 77.05,105.42 77.7,104.77 77.7,99.38 77.2,98.88 76.86,98.88 v1(76.74,98.76)
  BOTTOM w0.127: VRAM1.J11 57.39,112.16 v1(57.79,112.56) ; R661.1 58.33,117.67 58.33,116.78 v1(57.74,116.2)
CORE_PLLVDD: length 13.4
  TOP w0.381: v1(90.08,97.87) 90.01,97.87 GPU1.L6
  TOP w0.635: v4(96.05,102.11) 95.97,102.11 94.39,100.53 94.39,98.68 95.41,97.66 v3(95.66,97.66)
  L3 w0.508: v3(95.66,97.66) 94.65,97.66 93.9,98.41 93.01,98.41 92.7,98.1 90.31,98.1 v1(90.08,97.87)
  BOTTOM w0.381: C501.1 89.72,98.23 v1(90.08,97.87)
CPU_A16_TP: length 4.6
  TOP w0.102: CPU1.BB9 94.31,149.3 96.73,146.89 TP38.1
CPU_A17_TP: length 3.6
  TOP w0.089: 94.83,149.17 94.83,149.48 94.47,149.84 94.21,149.84 94.1,149.8 94.02,149.8 CPU1.BA9
  TOP w0.102: TP37.1 95.56,148.44 94.83,149.17
CPU_B16_TP: length 2.8
  TOP w0.102: v1(89.57,147.8) 89.25,148.13 CPU1.AP7
  BOTTOM w0.102: v1(89.57,147.8) 89.98,147.4 90.09,147.4 90.81,146.69 TP65.1
CPU_B17_TP: length 3.1
  TOP w0.102: CPU1.AP8 89.25,149.05 v1(89.57,148.72)
  BOTTOM w0.102: v1(89.57,148.72) 89.16,148.31 89.16,147.62 90,146.79 TP66.1
CPU_C18_TP: length 5.3
  TOP w0.102: CPU1.U8 80.75,148.71 80.95,148.92 v1(81.26,148.92)
  BOTTOM w0.102: v1(81.26,148.92) 81.69,148.49 81.69,145.87 TP70.1
CPU_C19_TP: length 7.6
  TOP w0.102: CPU1.U9 80.95,149.59 v1(81.28,149.59)
  BOTTOM w0.102: TP71.1 80.37,143.59 81.26,144.47 81.26,145 81.88,145.63 81.88,148.98 v1(81.28,149.59)
CPU_D4_TP: length 6.4
  TOP w0.089: 81.06,144.47 81.16,144.57 CPU1.V1
  TOP w0.102: TP40.1 80.32,139.52 80.32,142.86 80.86,143.4 80.86,144.27 81.06,144.47
CPU_D5_TP: length 8.2
  TOP w0.089: 80.46,143.26 80.68,143.48 80.68,144.4 80.81,144.53 80.81,145.16 81.16,145.52 CPU1.V2
  TOP w0.102: 80.46,143.26 80.09,142.9 80.09,139.17 TP41.1
CPU_FAN_CTRL_SIO: length 328.6
  TOP w0.165: v1(138.08,71.25) 138.43,70.9 138.43,68.19 137.14,66.9 137.14,65.8 136.74,65.4 KBC1.81 ; R40.1 v3(10.57,219.46)
  L3 w0.165: v3(160.18,207.65) 159.74,208.08 145.07,208.08 137.1,216.05 130.74,216.05 123.99,222.8 123.99,226.19 122.21,227.97 16.87,227.97 10.57,221.67 v3(10.57,219.46)
  BOTTOM w0.165: v1(138.08,71.25) 138.08,72.94 142.08,76.93 142.08,104.76 141.18,105.66 139.69,105.66 139.14,106.2 139.14,113.41 142.93,117.2 142.93,118.69 145.47,121.24 154.85,121.24 159.34,125.73 159.34,149.35 161.45,151.47 v2(161.45,195.71) 161.45,195.75 160.58,196.61 160.58,201.83 160.72,201.96 160.72,202.41 160.69,202.44 160.69,207.14 v3(160.18,207.65)
CPU_FAN_TACH_SIO: length 351.8
  TOP w0.165: v1(146.85,50.29) 146.51,49.95 143.5,49.95 143.33,50.12 142.95,50.12 142.74,49.91 KBC1.31 ; v3(15.78,216.79) 16.67,215.9 16.67,213.74 17.99,212.42 17.99,210.32 R60.1
  L3 w0.165: v3(15.78,216.79) 15.78,220.63 17.04,221.89 33.45,221.89 35.07,223.5 48.2,223.5 49.8,225.1 58.63,225.1 59.22,225.69 78.04,225.69 80.04,223.7 80.04,220.28 79.68,219.93 79.68,216.57 80.68,215.58 80.68,209.62 82.63,207.66 86.97,207.66 87.7,208.39 120.12,208.39 126.21,214.48 136.46,214.48 144.42,206.52 146.77,206.52 148.24,205.05 157.5,205.05 v3(162.39,200.15)
  BOTTOM w0.165: v3(162.39,200.15) 163.46,199.08 163.46,196.83 165.3,194.99 165.3,152.36 161.96,149.01 161.96,125.39 155.31,118.75 152.34,118.75 148.78,115.18 148.78,113.4 148.36,112.99 148.36,100.83 148.21,100.68 148.21,81.53 147.83,81.15 147.83,76.53 147.63,76.33 147.63,62.96 147.85,62.73 147.85,51.04 147.99,50.91 v2(147.99,50.55) 147.73,50.29 v1(146.85,50.29)
CPU_POPIRCOMP: length 6
  TOP w0.203: CPU1.AT16 90.55,153.88 v1(90.23,154.2)
  BOTTOM w0.203: v1(90.23,154.2) 90.23,154.21 90.69,154.66 91.33,154.66 91.86,154.66 92.67,153.85 v2(93.43,153.85) 93.77,153.85 R587.1
CPU_SCALAR_SCL: length 23
  TOP w0.102: R411.2 v3(77.88,53.09) ; R421.2 63.28,51.82 v3(64.17,50.93)
  L4 w0.127: v3(77.88,53.09) 77.38,53.59 74.04,53.59 72.12,55.52 67.2,55.52 67.06,55.37 64.17,52.48 v3(64.17,50.93)
  BOTTOM w0.102: RN15.4 77.22,53.01 78.11,52.12 v2(78.57,52.12) 78.57,52.4 v3(77.88,53.09)
CPU_SCALAR_SDA: length 24.8
  TOP w0.102: v3(78.65,53.09) 78.65,53.34 78.42,53.57 77.46,53.57 R409.2 ; R422.2 64.3,51.56 v3(64.93,50.93)
  L4 w0.127: v3(78.65,53.09) 78.14,52.58 77.67,52.58 77.17,53.09 73.83,53.09 71.91,55.01 67.41,55.01 64.93,52.53 v3(64.93,50.93)
  BOTTOM w0.102: RN15.3 77.76,53.67 77.82,53.61 79.27,53.61 v2(79.54,53.34) 79.28,53.09 v3(78.65,53.09)
CPVEE: length 2.8
  TOP w0.203: v4(162.9,71.94) 163.12,72.16 163.12,72.56 163.19,72.63 U11.20
  TOP w0.508: v4(162.9,71.94) 162.21,71.25 C144.1
CR_CLKREQ_R: length 6.2
  BOTTOM w0.102: U28.2 178.42,146.54 178.43,146.55 178.79,146.55 180.12,147.88 v2(180.12,148.97) 179.99,149.1 R594.1
CRCLK_REQ_N: length 119
  TOP w0.102: v1(163.67,156.78) 163.76,156.87 171.58,156.87 174.51,153.95 176.54,153.95 178.6,151.89 v1(179.61,151.89)
  L4 w0.127: v1(163.67,156.78) 164.12,156.34 164.12,132.42 153.94,122.25 137.9,122.25 134.4,118.75 134.4,118.33 134.09,118.02 129.89,118.02 122.72,125.19 122.72,125.74 111.04,137.42 111.04,138.04 108.87,140.21 v3(107.86,140.21)
  BOTTOM w0.102: R594.2 179.99,151.51 v1(179.61,151.89) ; R617.2 107.6,140.46 v3(107.86,140.21) 107.93,140.14 RN10.1 ; v2(163.52,157.55) 163.67,157.41 v1(163.67,156.78)
CSI2_COMP: length 2.5
  TOP w0.203: CPU1.E13 74.41,151.79 v1(74.08,151.45)
  BOTTOM w0.203: v1(74.08,151.45) 73.89,151.64 v2(73.26,151.64) R591.1
DACA_VREF: length 7.8
  TOP w0.152: 94.17,109.57 94.1,109.49 93.29,109.49 GPU1.AE2
  TOP w0.508: C84.1 95.28,111.94 v3(95.89,111.33) 95.28,110.72 95.28,110.67 94.17,109.57
  BOTTOM w0.508: v3(95.89,111.33) 95.69,111.12 v2(95.16,111.12)
DB_UART1_RX: length 6.5
  TOP w0.102: R394.2 125.76,58.38 125.76,58.39 125.95,58.59 v3(125.97,58.59) 126.08,58.59 127.97,56.7 KBC1.113
  BOTTOM w0.102: v3(125.97,58.59) 125.8,58.75 v2(125.05,58.75)
DB_UART1_TX: length 5.3
  TOP w0.102: R390.2 125.41,59.04 126.48,59.04 v4(126.95,58.57) 127.03,58.49 127.03,58.18 127.72,57.5 KBC1.111
DC_19V: length 95.2
  TOP w0.254: PR89.1 36.23,59.54 35.19,60.58 34.07,60.58 v3(33.94,60.71)
  TOP w0.508: 38.9,73.91 v5(38.9,75.36) ; PR104.1 46.88,41.33 49.97,41.33 v3(50.3,41.66)
  L3 w0.381: v3(48.42,48.01) 48.42,48.51 51.72,51.82 52.61,51.82 ; 52.61,51.82 56.42,48.01 v3(56.42,44.45) 56.46,44.41 56.46,42.81 62.82,36.45 v5(62.9,36.45) ; 52.61,51.82 52.61,57.33 51.02,58.93 48.97,58.93 43.98,63.92 v3(43.98,64.64)
  L3 w0.508: v3(48.42,48.01) 48.85,48.01 50.3,46.56 50.3,45.59 49.44,44.73 49.44,42.52 v3(50.3,41.66)
  BOTTOM w0.254: PR239.1 34.48,69.68 34.48,61.24 v3(33.94,60.71)
  BOTTOM w0.381: PR251.1 55.34,45.5 55.82,45.02 55.85,45.02 v3(56.42,44.45) ; v5(38.9,75.36) 38.32,74.79 PR239.1 PC273.2 39.34,72.71 39.91,72.14 42.45,72.14 42.96,71.63 v2(42.96,66.04) 42.96,65.32 43.64,64.64 v3(43.98,64.64)
  BOTTOM w0.508: PR246.1 47.86,48.56 v3(48.42,48.01)
  vias: v2(69.27,35.15) v5(63.84,36.45) v5(64.75,36.45) v5(65.67,36.45) v5(66.58,36.45)
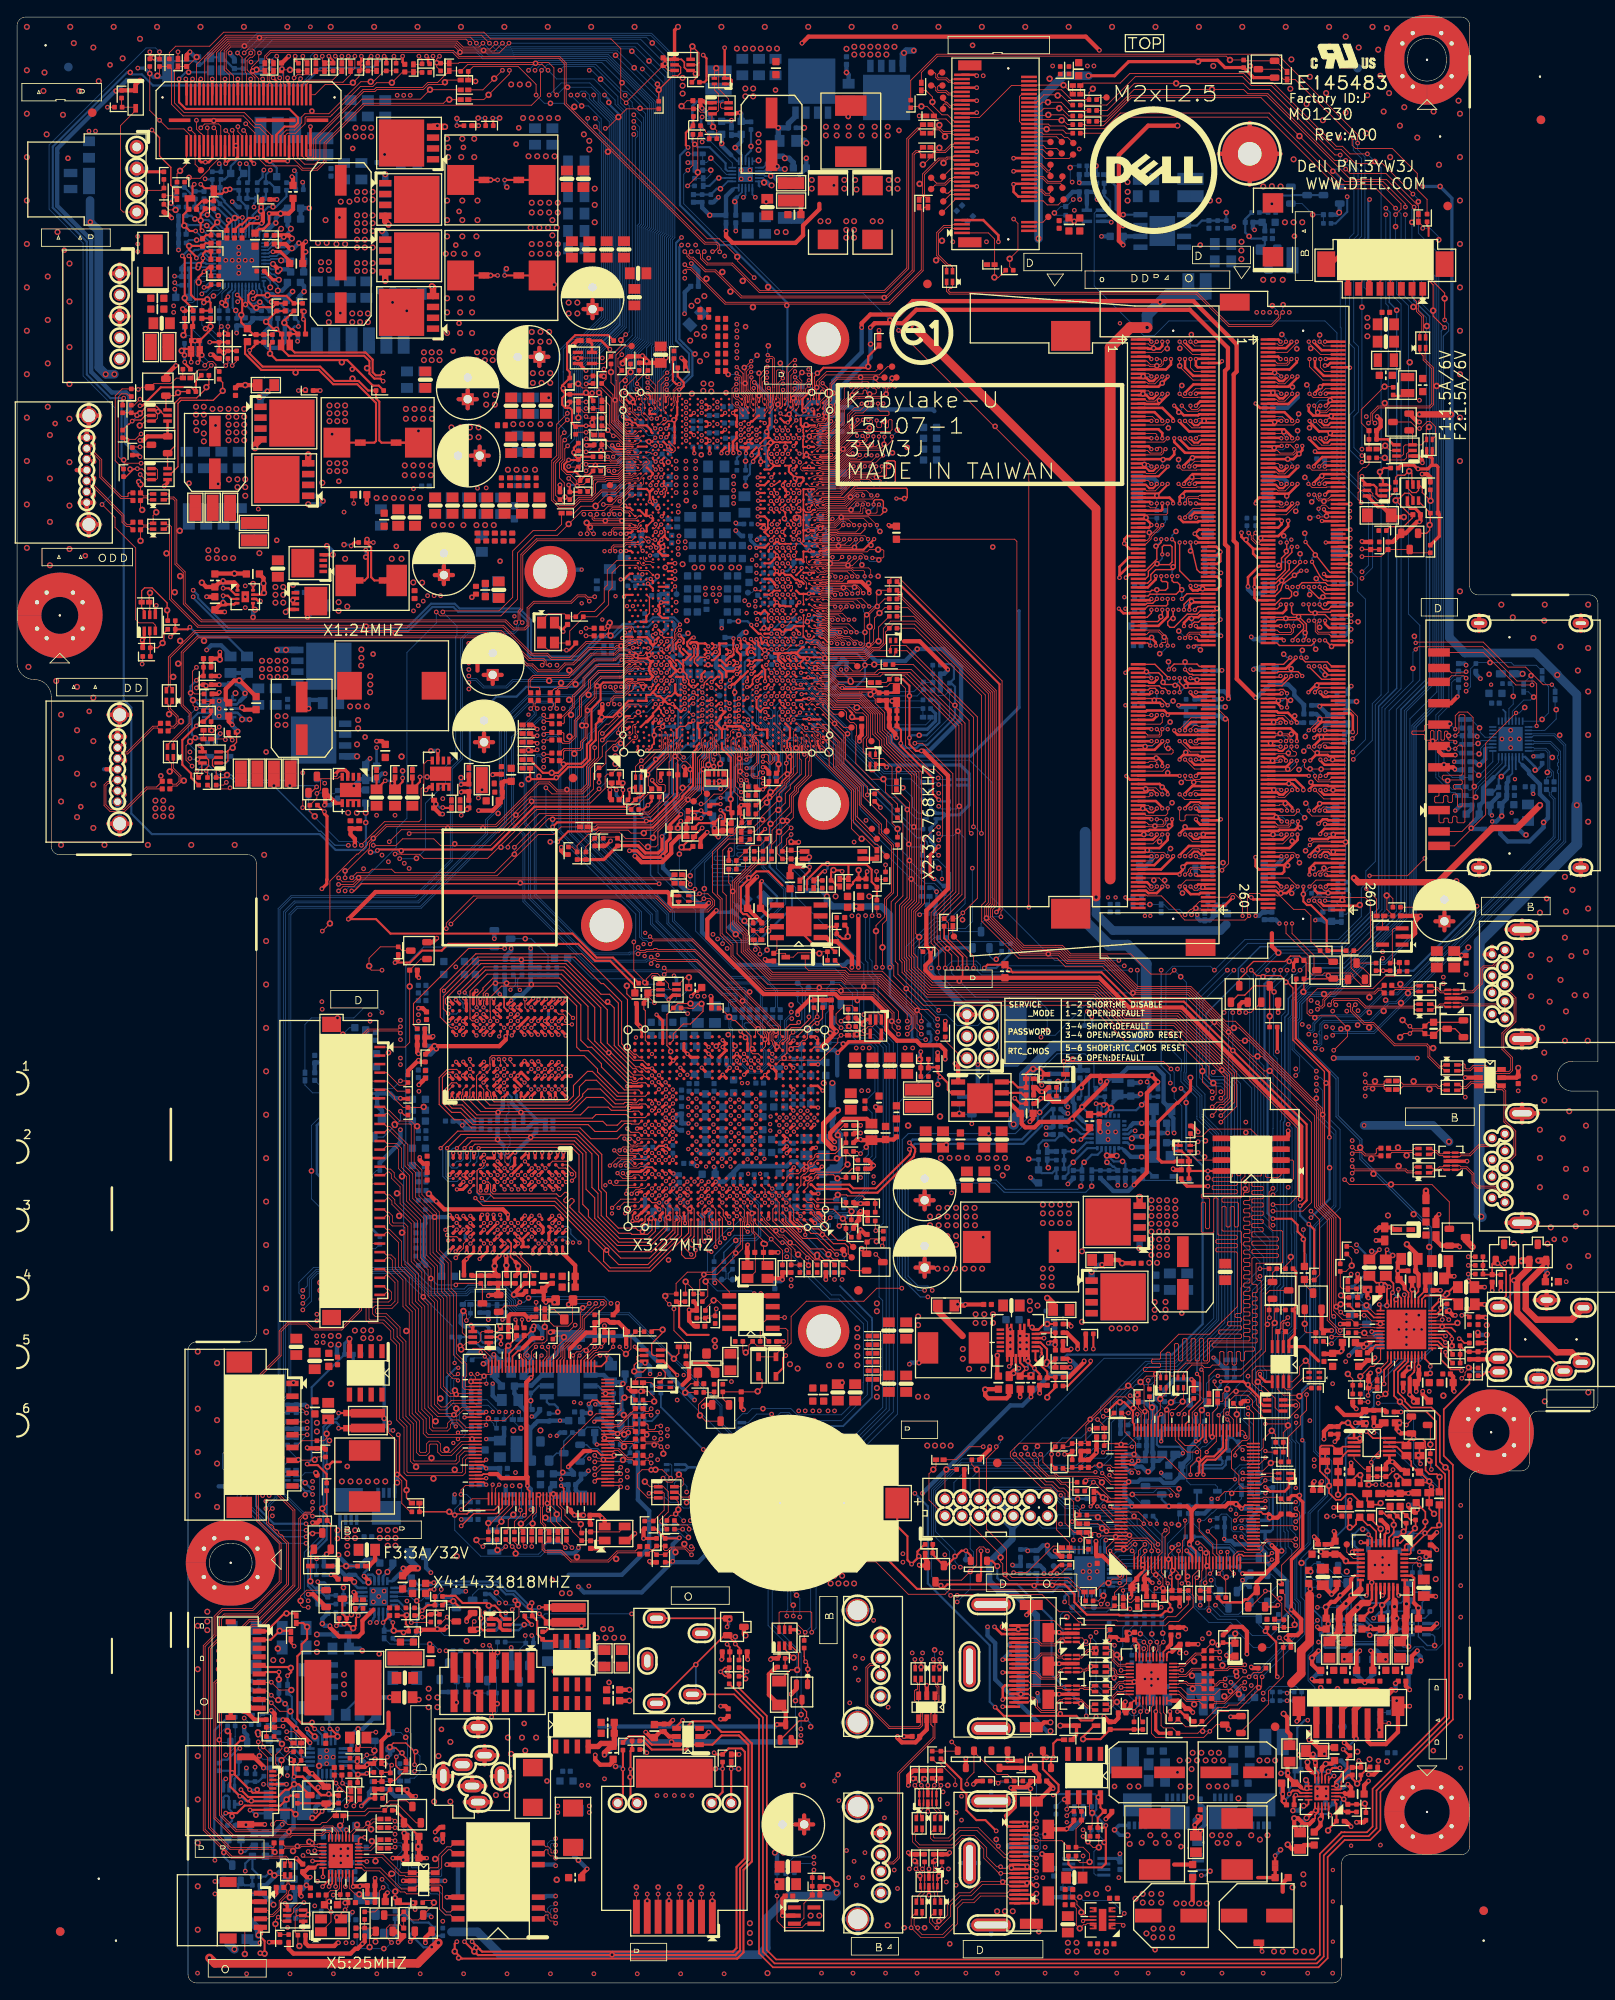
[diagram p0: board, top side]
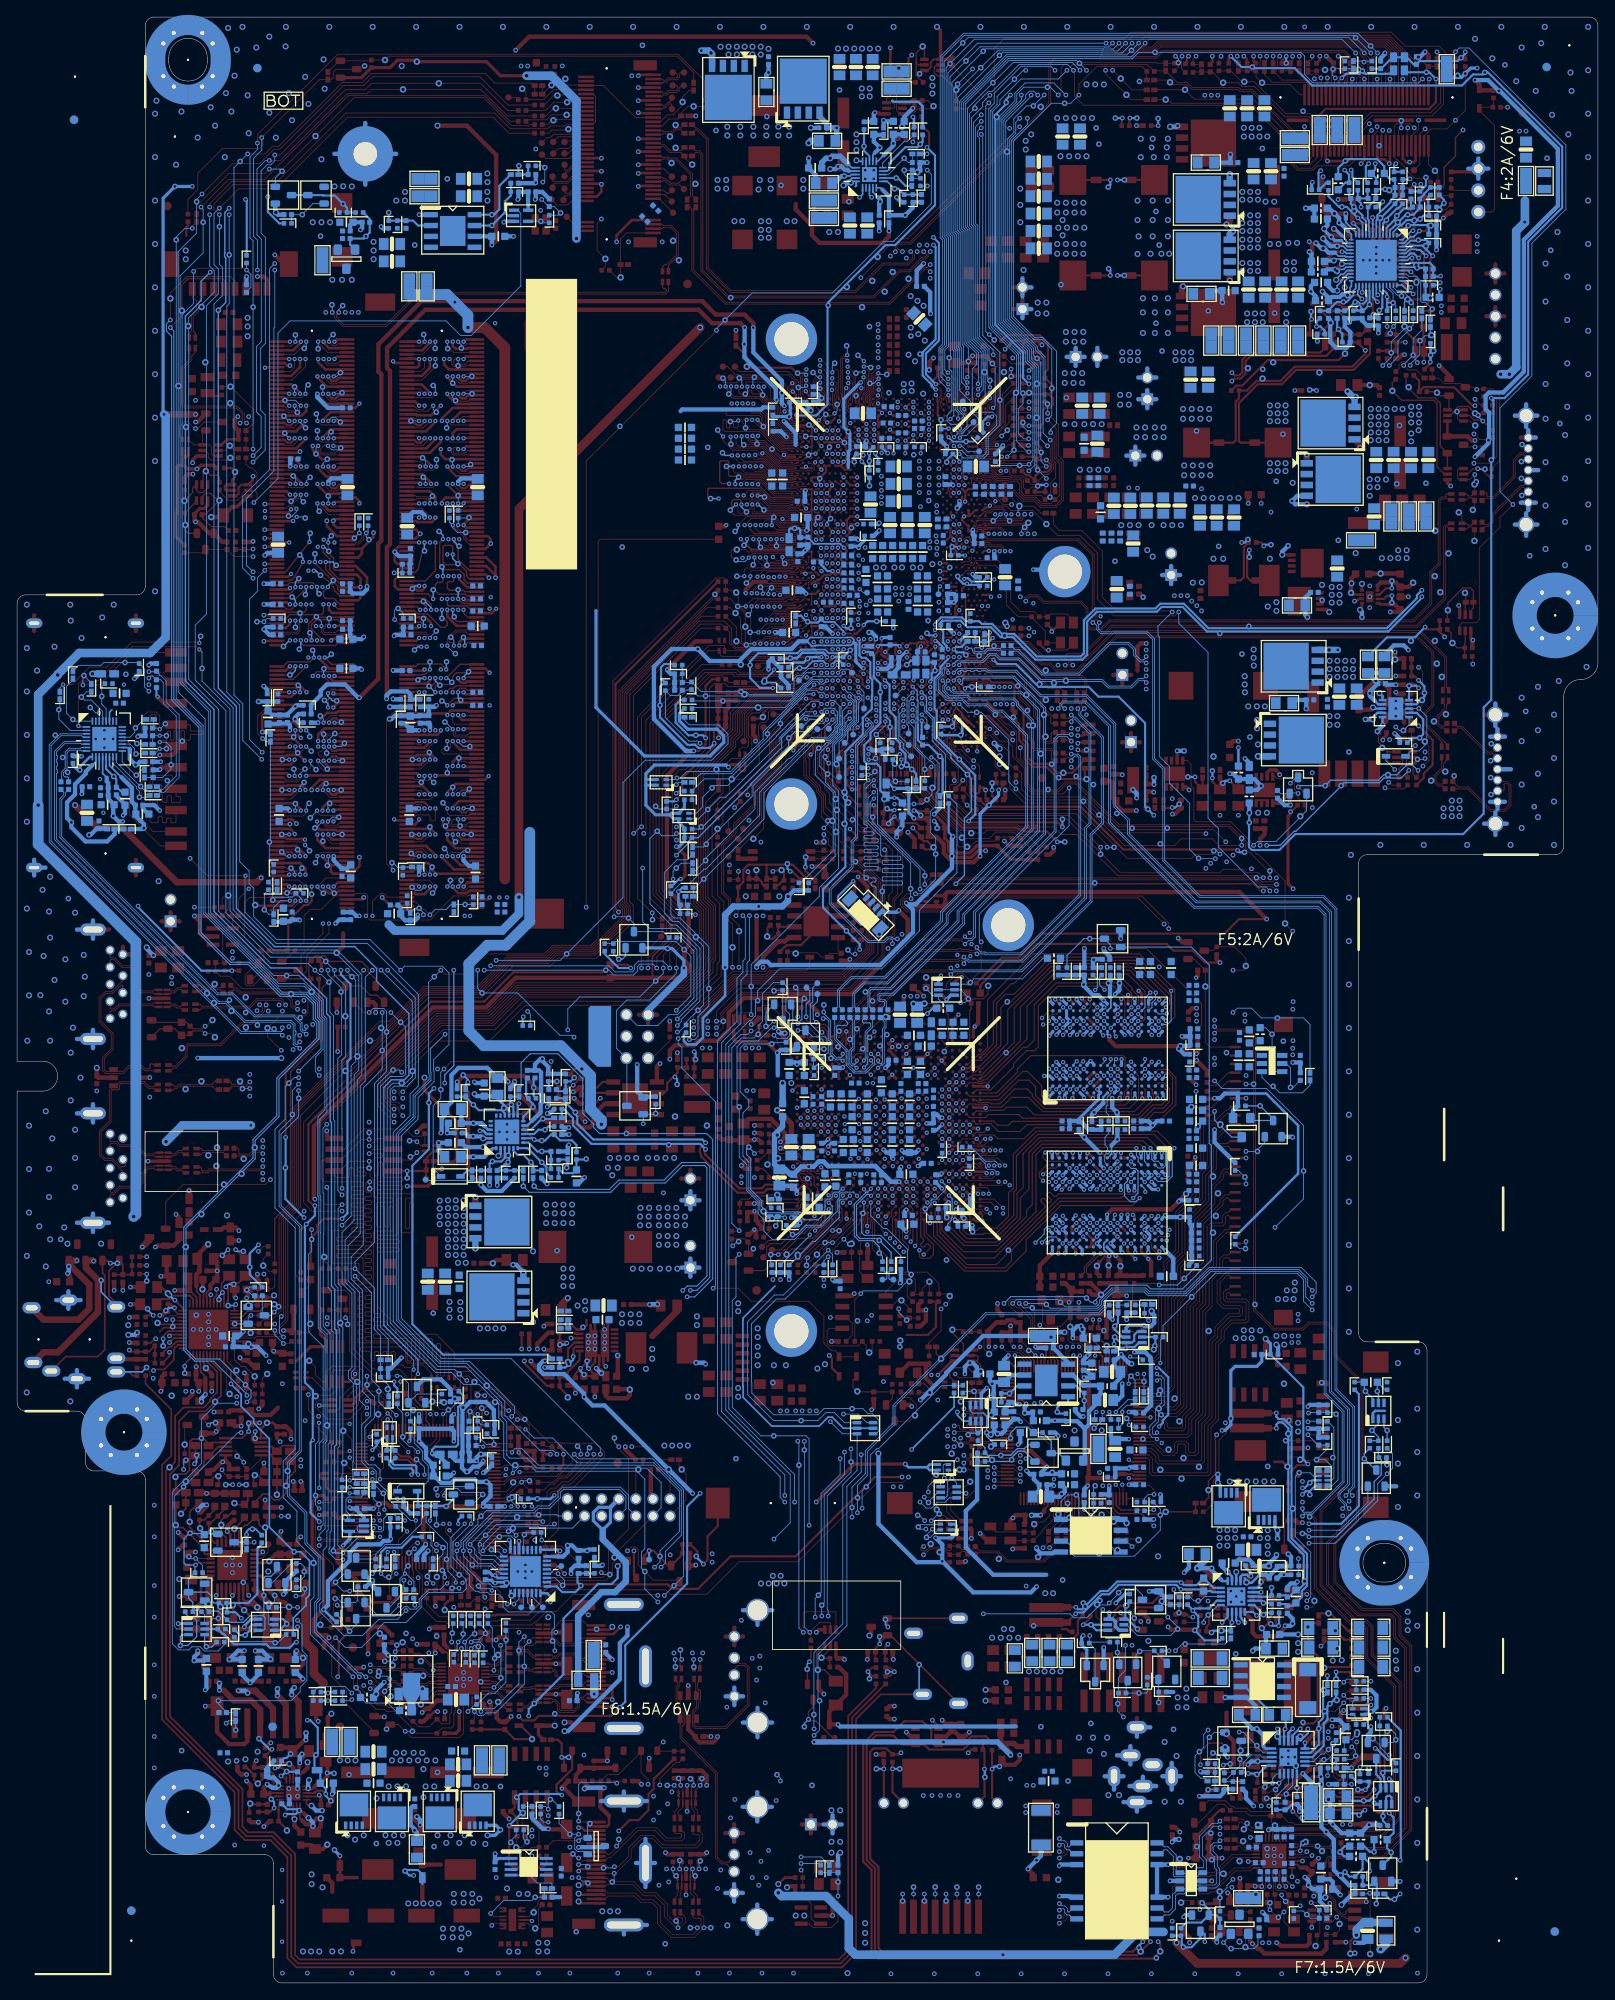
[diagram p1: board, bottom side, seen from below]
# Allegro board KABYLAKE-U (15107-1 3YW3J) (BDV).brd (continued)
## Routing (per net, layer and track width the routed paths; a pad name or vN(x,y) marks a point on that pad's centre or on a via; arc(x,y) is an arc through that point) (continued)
DC_IN_D: length 4.4
  BOTTOM w0.254: PR251.2 55.3,44.11 55.3,42.74 PQ11.3 55.04,42.56 v2(53.88,41.4)
DCBATOUT: length 51.7
  TOP w0.508: PC118.1 41.89,49.48 41.18,48.77 PR91.1 ; PR114.1 149,27.91 149,29.08 148.65,29.44 148.65,30.96 148.62,31.09 v5(148.22,31.5) ; v3(123.35,76.83) 123.1,77.09 PR73.1
  TOP w1.016: 151.26,45.36 151.26,39.85 150.27,38.86 150.27,36.2 149.13,35.05
  L3 w1.27: v5(52.61,40.01) 51.47,41.15 v5(51.47,49.91)
  BOTTOM w0.508: 64.55,47.75 70.77,47.75 73.97,50.95 73.97,55.22 72.65,56.54 72.65,60.97 R746.1 R742.1
  vias: v2(16.49,183.85) v2(16.82,141.22) v2(25.61,214.96) v2(39.23,188.8) v2(40.14,79.38) v2(53.65,222.48) v2(62.64,47.14) v2(79.38,223.37) v2(100.87,61.34) v2(136.3,78.36) v2(141.77,29.69) v5(16.19,138.33) v5(16.19,137.41) v5(16.19,136.5) v5(17.1,138.33) v5(17.1,137.41) v5(17.1,136.5) v5(18.07,137.41) v5(18.07,136.5) v5(22.39,167.61) v5(22.39,166.7) v5(23.38,167.61) v5(23.38,166.7) v5(24.29,166.7) v5(25.28,166.7) v5(35.47,81.94) v5(35.49,81.03) v5(35.62,80.01) v5(36.41,81.03) v5(36.53,80.01) v5(37.45,80.01) v5(39.53,76.33) v5(40.52,76.35) v5(40.52,75.44) v5(41.44,76.35) v5(41.44,75.44) v5(42.4,75.44) v5(42.45,52.98) v5(42.45,52.07) v5(43.37,52.98) v5(43.37,52.07) v5(43.37,51.16) v5(44.28,52.98) v5(44.28,52.07) v5(44.28,51.16) v5(57.82,222.12) v5(58.83,222.12) v5(59.85,222.12) v5(63.76,45.59) v5(64.68,45.59) v5(77.88,222.88) v5(77.88,221.97) v5(77.88,221.06) v5(95.21,46.74) v5(95.64,47.62) v5(96.12,46.74) v5(96.55,47.62) v5(97.04,46.74) v5(97.95,46.74) v5(106.51,62.87) v5(107.42,62.87) v5(108.34,62.87) v5(109.25,62.87) v5(128.1,76.58) v5(129.01,76.58) v5(129.93,76.58) v5(130.84,76.58) v5(133.13,79.65) v5(133.13,78.74) v5(133.13,77.83) v5(134.4,79.68) v5(134.4,78.77) v5(134.4,77.85)
DCBATOUT_1D35V_VGA: length 1.1
  TOP w0.305: PU14.22 117.88,73.9 v3(118.14,74.17)
  vias: v2(118.78,76.71) v3(117.38,75.69) v3(117.38,74.93) v3(117.38,74.17) v3(118.14,75.69) v3(118.14,74.93) v5(118.52,79.76) v5(118.52,78.74) v5(119.41,79.25)
DCBATOUT_RT6575_1: length 5.8
  TOP w0.203: PU17.12 150.51,22.63 150.27,22.86
  TOP w0.508: 150.27,22.86 149.77,23.37 PC127.1 148.67,24.21 148.67,24.51 v3(148.72,24.56) 148.67,24.61 148.67,25.65 PR114.2
  BOTTOM w0.305: v3(148.72,24.56) 147.96,24.56 v2(147.91,24.51)
DCBATOUT_RT6575_3V:
  vias: v2(128.43,22.99) v5(130.21,22.99) v5(131.22,22.99)
DCBATOUT_RT6575_5V:
  vias: v2(146.16,24.36) v5(145.4,26.04) v5(146.31,26.04) v5(147.23,26.04)
DCBATOUT_VCCGTA: length 12.2
  TOP w0.508: PR5.2 v3(30.41,208.66)
  L4 w0.254: v5(38.69,216.03) 38.01,216.03 33.51,211.53 33.51,211.53 30.64,208.66 v3(30.41,208.66)
  vias: v2(34.5,219) v2(39.28,214.63) v5(39.61,217.04) v5(39.61,216.03) v5(40.52,217.04) v5(40.52,216.03) v5(41.44,217.04) v5(41.44,216.03)
DCBATOUT_VCCGTB:
  vias: v2(37.83,195.38) v2(45.6,195.63) v5(36.46,195.33) v5(36.48,194.31) v5(39.23,195.33) v5(39.23,194.31) v5(40.14,195.33) v5(40.14,194.31) v5(41.05,195.33) v5(41.05,194.31)
DCBATOUT_VCCSA:
  vias: v2(30.39,168.78) v5(28.35,167.28)
DCBATOUT_VCORE:
  vias: v2(20.12,175.46) v2(23.53,175.39) v5(24.8,175.9) v5(25.79,175.92) v5(25.79,175.01) v5(26.7,175.92) v5(26.7,175.01) v5(26.7,173.99)
DCIN_EN: length 4.2
  TOP w0.102: U17.13 133.75,39.48 v3(134.15,39.88)
  BOTTOM w0.102: v3(134.15,39.88) 134.15,40.84 v2(134.07,40.92) 134.07,41.95 R792.2
DDC5V_HDMI: length 31.6
  TOP w0.254: 126.78,21.72 126.78,20.51 C253.1 126.46,19.3 R506.1 127.16,18.16 v3(127.41,18.41) 127.41,13.97 126.96,13.51 123.43,13.51 123.03,13.91 R509.1 ; D11.3 120.05,25.01 121.88,23.18 121.88,22.4 121.45,21.97 v1(121.24,21.97)
  BOTTOM w0.254: v1(121.24,21.97) 121.37,22.1 126.14,22.1 v2(126.53,21.72) 126.3,21.49 126.3,20.28 R847.1 126.08,19.75 v3(127.41,18.41)
DDC5V_HDMI_R: length 5.2
  TOP w0.254: R475.2 121.7,28.45 121.27,28.02 v3(121.27,26.39) 121,26.12 D11.2
  BOTTOM w0.254: v2(120.45,26.39) v3(121.27,26.39)
DDC_WP: length 97.7
  TOP w0.102: SCA1.34 67.17,72.86 67.72,73.41 v1(68.23,73.41) ; R507.2 126.59,17.02 v4(126.59,15.85) 125.92,15.85 124.75,17.02 v3(124.75,17.14)
  L3 w0.127: v1(68.23,73.41) 68.79,72.85 74.25,72.85 78.47,68.62 78.47,58.7 86.59,50.57 88.25,50.57 97.3,41.52 97.3,35.33 101.89,30.74 101.89,28.95 103.15,27.69 107.18,27.69 109.47,25.4 119.2,25.4 123.86,20.75 123.86,18.03 v3(124.75,17.14)
DDC_WP_1: length 4.8
  TOP w0.102: 125.51,21.72 125.51,20.21 v4(125.81,19.9) 125.81,18.4 R506.2 R507.1
DDCBUF: length 6.1
  TOP w0.102: v3(133.38,39.88) 133.51,39.75 133.51,38.98 133.35,38.82 U17.14
  BOTTOM w0.102: R806.1 133.51,38.8 133.51,39.75 v3(133.38,39.88) 132.8,40.46 v2(132.8,40.83) 132.8,40.98 132.8,40.98 132.8,41.9 R793.2
DDPB_CTRL_CLK_CONN: length 23.9
  TOP w0.102: R471.2 v3(130.72,31.75) 130.72,31.88 131.35,32.51 U17.32 ; HDMI1.15 119.44,39.82 119.82,39.43 121.51,39.43 121.97,39.89 U15.10 U15.1 124.19,39.89 124.59,39.49 125.26,39.49 125.64,39.87 v3(125.64,40.51)
  BOTTOM w0.102: v3(130.72,31.75) 130.39,32.08 129.19,32.08 126.27,35 v2(126.27,38.89) 126.27,39.88 v3(125.64,40.51)
DDPB_CTRL_DATA_CONN: length 23.9
  TOP w0.102: HDMI1.16 119.26,40.32 119.92,39.66 121.41,39.66 122.12,40.37 U15.9 U15.2 124.65,40.37 v3(125.07,39.95) ; R472.2 131.48,30.8 v3(131.48,31.75) 131.75,32.02 U17.33
  BOTTOM w0.102: v3(131.48,31.75) 131.02,31.29 130.44,31.29 130.13,31.6 128.99,31.6 125.64,34.95 v2(125.64,37.03) 125.64,39.38 v3(125.07,39.95)
DDR0_A_ALERT_N: length 59.2
  TOP w0.089: CPU1.AW50 92.92,173.18 93.1,173.18 93.2,173.15 93.25,173.1 93.32,173.03 93.32,173 93.35,172.86 93.41,172.76 93.44,172.74 93.5,172.64 93.67,172.47 94.56,172.47 94.76,172.67 97.03,172.67 97.08,172.72 97.97,173.61 100.1,173.61 100.53,174.04 v1(100.68,174.04)
  TOP w0.165: v1(137.96,163.45) 138.03,163.53 DIMM1.116
  L3 w0.089: 103.57,173.33 103.45,173.21 102.78,173.21 v1(100.68,174.04)
  L3 w0.216: v1(137.96,163.45) 138.34,160.78 138.34,160.4 137.68,159.74 136.18,159.74 134.15,159.26 131.99,159.26 131,159.8 128.51,160.15 114.66,174 107.79,174 107.38,173.6 103.84,173.6 103.57,173.33
  BOTTOM w0.165: v1(137.96,163.45) 138.41,163.45 v2(138.74,163.12)
DDR0_A_PARITY: length 58
  TOP w0.165: v1(90.25,173.4) 90.55,173.7 CPU1.AT52 ; v1(132.62,156.46) 132.31,156.78 DIMM1.143
  L3 w0.089: 103.56,171.22 103.13,171.65 96.55,171.65 96.36,171.84 96.36,171.97 96.58,172.19 96.58,172.31 96.45,172.44 96.33,172.44 96.11,172.22 95.99,172.22 95.86,172.35 95.86,172.47 96.08,172.69 96.08,172.81 95.95,172.94 95.83,172.94 95.61,172.72 95.48,172.72 95.36,172.85 95.36,172.97 95.57,173.19 95.57,173.32 95.45,173.44 95.32,173.44 95.11,173.23 94.98,173.23 94.78,173.43 94.27,173.43 94.18,173.34 94.18,172.95 94.08,172.85 93.93,172.85 93.82,172.95 93.82,173.34 93.74,173.43 93.56,173.43 93.47,173.34 93.47,172.95 93.36,172.85 93.22,172.85 93.11,172.95 93.11,173.34 93.02,173.43 92.85,173.43 92.76,173.34 92.76,173.06 92.67,172.97 92.49,172.97 92.4,173.06 92.4,173.34 92.31,173.43 92.04,173.43 91.61,173.86 90.5,173.86 90.25,173.61 v1(90.25,173.4)
  L3 w0.216: v1(132.62,156.46) 132.49,156.34 127.82,156.34 113.29,170.87 103.99,170.87 103.79,171.07 103.72,171.07 103.56,171.22
  BOTTOM w0.165: v1(132.62,156.46) 132.62,157.28 v2(132.77,157.42)
DDR1_B_ALERT_N: length 79.6
  TOP w0.165: DIMM2.116 153.39,163.53 153.09,163.83 150.38,163.83 150.06,163.51 150.06,163.49 v1(149.89,163.32) ; v3(88.27,168.81) 88.27,168.97 CPU1.AN43
  L4 w0.089: v3(88.27,168.81) 88.27,169.06 87.79,169.54 87.79,171.45 88.24,171.9 94.08,171.9 96.93,174.75 101.68,174.75 101.81,174.89
  L4 w0.216: 101.81,174.89 102.16,175.23 123.68,175.23 132.29,166.62 134.19,166.62 134.4,166.41 134.4,165.82 134.62,165.61 135.05,165.61 135.26,165.82 135.26,166.41 135.48,166.62 136.05,166.62 137.05,165.62 141.4,165.62 142.63,164.39 147.93,164.39 148.36,163.96 149.31,163.96 149.89,163.38 v1(149.89,163.32)
  BOTTOM w0.165: v1(149.89,163.32) 149.89,162.76 v2(149.65,162.52)
DDR1_B_PARITY: length 80.2
  TOP w0.165: DIMM2.143 147.43,156.78 147.73,156.48 151.47,156.48 151.8,156.81 v1(151.8,157.08) ; v1(89.62,168.83) 89.25,169.2 CPU1.AP43
  L4 w0.089: v1(89.62,168.83) 90.1,169.31 91.69,169.31 91.71,169.33 94.3,169.33 96.19,171.22 102.88,171.22 103.01,171.09
  L4 w0.216: v1(151.8,157.08) 151.8,157.68 151.54,157.93 150.52,157.93 150.38,158.07 147.56,158.07 146.92,158.71 144.18,158.71 142.56,157.09 140.5,157.09 138.21,159.38 136.43,159.38 135.29,158.25 131.57,158.25 130.67,159.16 130.67,160.76 129.79,161.63 129.78,161.64 128.44,161.64 126.31,163.77 124.17,163.77 117.81,170.13 103.97,170.13 103.01,171.09
  BOTTOM w0.165: v2(151.97,156.04) 151.8,156.21 v1(151.8,157.08)
DDR_VDDQ: length 277.3
  TOP w0.127: v1(98.28,175.33) 96.72,173.78 94.18,173.78 CPU1.BB51 ; CPU1.AU42 91.2,168.17 v1(90.91,167.89) ; v1(95.73,162.4) 95.61,162.52 CPU1.BB32 ; CPU1.BB47 95.26,171.13 v1(95.42,171.29)
  TOP w0.203: v1(91.81,165.55) 91.81,165.33 CPU1.AU35 ; v1(95.3,156.79) 95.2,156.88 94.85,156.88 94.38,157.35 94.09,157.35 CPU1.BB23
  TOP w0.254: v1(100.3,168.93) 99.06,167.69 94.7,167.69 94.57,167.56 94,167.56 CPU1.BB41 ; CPU1.AU28 91.2,161.19 v1(91.53,161.53) ; v1(91.52,157.86) 91.52,157.99 CPU1.AU23
  TOP w0.305: DIMM1.159 131.2,150.77 132.52,150.77 v1(132.75,151) ; v1(144.81,163.32) 144.81,164.34 145.25,164.78 DIMM2.111 ; v1(144.81,163.32) 144.81,162.05 145.09,161.78 DIMM2.123 ; v1(144.81,163.32) 144.86,163.28 DIMM2.117 ; DIMM1.117 132.32,163.28 133.26,164.21 v1(133.26,164.59) ; v3(144.94,131.7) 144.94,130.66 145.32,130.28 DIMM2.241 ; v1(153.07,154.05) 153.59,153.53 DIMM2.148 ; DIMM1.136 138.18,158.53 v1(137.96,158.75) ; DIMM2.141 148.05,157.28 v1(148.24,157.08) ; DIMM2.142 156.06,157.03 v3(156.12,156.97) ; v1(147.99,149.22) 147.44,149.78 DIMM2.163 ; v1(133.26,156.46) 133.26,156.84 132.83,157.28 DIMM1.141 ; DIMM1.153 132.37,152.28 132.53,152.12 133.03,152.12 133.38,152.48 v1(133.38,152.65) ; v1(137.32,153.67) 137.46,153.53 DIMM1.148 ; v1(137.96,157.35) 138.28,157.03 DIMM1.142 ; v1(136.69,152.65) 136.69,152.4 137.06,152.03 DIMM1.154 ; v3(153.07,135.58) 153.13,135.53 DIMM2.220 ; v1(137.19,160.66) 137.19,161.16 137.56,161.53 DIMM1.124 ; DIMM2.129 148.12,160.28 148.51,160.67 v1(148.51,161.29) ; v1(148.5,152.91) 148.5,152.79 147.98,152.28 DIMM2.153 ; DIMM2.124 153.43,161.53 153.2,161.29 v1(153.07,161.29) ; v1(137.32,151) 137.32,150.88 137.73,150.47 138.18,150.47 138.23,150.53 DIMM1.160 ; v1(153.16,168.53) 153.16,168.53 DIMM2.96 ; v3(153.07,189.23) 153.38,189.23 153.68,189.53 DIMM2.12 ; v1(129.82,141.2) 130.24,140.77 131.2,140.77 DIMM1.199 ; v1(141,189.74) 140.79,189.52 139.4,189.52 DIMM1.12 ; v1(129.7,153.29) 130.19,153.77 131.2,153.77 DIMM1.147 ; DIMM1.112 140.45,164.53 140.81,164.16 140.81,163.43 140.41,163.03 DIMM1.118 138.29,163.03 138.18,162.92 137.6,162.92 137.32,163.19 v1(137.32,163.45) ; DIMM1.220 138.45,135.53 137.96,136.02 v1(137.96,136.14) ; v1(152.52,151) 152.52,150.88 152.93,150.47 153.38,150.47 153.43,150.53 DIMM2.160 ; v1(151.12,151) 152.15,152.03 DIMM2.154 ; DIMM1.33 134.02,184.28 135.29,183.01 v1(135.29,182.75) ; v1(136.56,158.75) 136.56,159.13 137.21,159.79 138.23,159.79 138.47,160.03 DIMM1.130 ; v3(151.89,179.17) 152.04,179.03 DIMM2.54 ; v1(147.86,158.75) 147.84,158.78 DIMM2.135 ; DIMM2.159 147.89,150.78 v1(147.99,150.88) ; DIMM1.96 139.4,168.52 137.96,168.52 v1(137.96,168.53) ; DIMM1.111 130.14,164.78 v3(129.78,164.41) ; DIMM2.199 146.4,140.77 149.58,140.77 150.53,139.83 v3(150.53,139.57) ; DIMM1.54 136.68,179.03 135.42,180.29 v1(135.42,180.72) ; DIMM1.135 133.56,158.78 134.65,159.87 v1(134.65,160.66) ; DIMM2.118 153.24,163.03 v1(153.07,163.19) ; v1(153.07,159.38) 153.07,159 153.55,158.53 DIMM2.136 ; v1(152.94,164.85) 153.26,164.53 DIMM2.112 ; DIMM2.75 145.36,173.78 144.94,173.35 v1(144.94,173.1) ; v1(149.64,155.07) 149.64,154.95 148.47,153.77 146.4,153.77 DIMM2.147 ; DIMM2.33 145.45,184.28 v1(144.94,184.78) ; DIMM1.129 130.21,160.28 130.18,160.25 129.47,160.25 v1(128.94,160.78) ; v1(135.42,146.56) 135.42,146.43 135.82,146.02 138.18,146.02 138.18,146.03 DIMM1.178 ; v1(151.8,145.67) 152.15,146.02 153.29,146.02 153.29,146.03 DIMM2.178 ; DIMM1.123 132.09,161.78 132.09,161.78 132.6,161.78 v1(132.75,161.93) ; v1(135.29,173.1) 135.29,173.35 134.87,173.78 DIMM1.75 ; v1(134.02,149.48) 133.72,149.77 131.2,149.77 DIMM1.163 ; DIMM2.130 156.11,160.03 v3(156.12,160.02) ; v1(135.29,131.83) 135.29,131.7 133.86,130.28 DIMM1.241
  TOP w0.508: PR6.1 91.73,208.36 PC7.1 ; v3(82.96,204.98) 82.96,204.34 83.73,203.58 91.09,203.58 91.98,204.47 91.98,205.61 93.89,207.52 93.89,208.15
  BOTTOM w0.381: 117.25,160.53 117.25,149.22 111.58,143.55 103.92,143.55 102.31,145.16 102.31,145.92 103.07,146.69 106.52,146.69 107.49,147.65 107.49,148.51 R602.1
  BOTTOM w0.508: PR170.2 v3(82.96,204.98) ; R545.1 97.7,184.34 97.94,184.1 107.14,184.1 107.35,183.9
  BOTTOM w1.27: v5(116.62,100.46) 116.62,100.97 117.89,102.23 117.89,106.17 121.37,109.65 130.39,109.65 132.14,111.4 132.14,119.23 129.95,121.41 127.8,121.41 125,124.21 125,134.62
  vias: v1(133.26,168.91) v1(133.38,160.66) v1(134.02,161.93) v1(134.02,151) v1(134.53,168.91) v1(134.53,164.59) v1(134.65,167.13) v1(135.29,161.93) v1(135.29,156.46) v1(135.42,153.67) v1(135.42,152.65) v1(135.42,151) v1(135.8,164.59) v1(135.92,160.66) v1(136.05,157.35) v1(136.69,168.53) v1(137.07,156.34) v1(147.86,168.53) v1(149.12,168.86) v1(149.26,163.32) v1(149.51,166.24) v1(149.82,168.02) v1(149.77,152.91) v1(149.89,157.08) v1(150.02,158.75) v1(150.53,163.32) v1(150.53,161.29) v1(150.78,166.24) v1(150.91,165.23) v1(150.91,155.07) v1(151.16,159.38) v1(151.16,157.08) v1(151.8,163.32) v1(151.8,161.29) v1(151.8,154.05) v1(152.43,157.08) v1(155.99,172.21) v1(155.99,171.45) v2(95.59,210.31) v2(103.33,162.46) v2(114.18,168) v2(114.46,182.12) v5(93,210.95) v5(93,209.93) v5(96.81,210.95) v5(96.81,209.93) v5(98.08,210.95) v5(98.23,209.83) v5(102.01,210.95) v5(102.01,209.93) v5(103.03,210.95) v5(103.03,209.93)
DDR_VREF_CA: length 106.1
  TOP w0.089: CPU1.AY67 93.29,182.63 93.69,182.63 93.81,182.66 94.17,182.66 94.23,182.64 94.47,182.64 94.65,182.82 94.65,182.92 95.12,183.39 95.33,183.39 95.44,183.5
  TOP w0.127: 95.97,185.08 95.64,184.75 95.64,183.7 95.44,183.5
  TOP w0.508: v3(99.86,193.68) 100.36,194.18 103.67,194.18 105.24,195.76 137.24,195.76 141.7,191.29 141.7,188.95 141.36,188.61 141.36,168.32 141.72,167.96 141.72,150.28 v3(141.77,150.24) ; 95.97,185.08 v1(96.11,185.22)
  BOTTOM w0.508: v3(99.86,193.68) 99.86,191.77 v2(99.88,191.74) 99.88,190.2 96.21,186.53 96.21,185.33 v1(96.11,185.22) ; v3(141.77,150.24) 141.77,150.62 141.28,151.11 139.33,151.11 138.97,150.75 C385.1 R599.1
DDR_VTT_CNTL: length 46.3
  TOP w0.102: v1(93.82,183.43) 93.58,183.19 92.55,183.19 CPU1.AW67
  TOP w0.254: v3(78.52,214.76) 78.27,215.01 78.27,216.47 R47.1 79.15,217.36 R42.1
  BOTTOM w0.254: v3(78.52,214.76) 77.58,213.82 77.58,208.85 77.58,208.85 77.58,207.99 82.24,203.33 83.37,203.33 83.65,203.05 90.08,196.63 v2(90.08,196.27) 90.15,196.19 90.15,184.71 91.47,183.39 93.77,183.39 v1(93.82,183.43)
DDR_VTT_CNTL_L1: length 5.7
  TOP w0.102: Q3.2 81.06,219.33 80.6,218.87 79.98,218.87 79.59,219.27 R42.2 78.07,219.27 v4(77.76,219.58) 78.39,220.22 C5.1
DDR_VTT_CNTL_L2: length 8.3
  TOP w0.102: Q3.5 82.46,219.33 82.31,219.47 82.31,219.84 82.46,219.98 Q3.6 83.27,220.42 82.11,221.58 82.11,223.74 v4(81.82,224.03) 81.6,223.81 RN1.3
DDR_VTT_CNTL_L3: length 7.3
  TOP w0.102: RN1.4 81.6,221.49 82.08,221.02 82.08,219.05 81.97,218.95 81.95,218.95 81.68,218.68 Q3.3 81.31,218.6 81.31,217.55 81.44,217.42 v4(81.44,217.17) 81.88,216.73 R48.1
DDSP_B_HPD_CONN: length 20.3
  TOP w0.102: HDMI1.19 118.23,41.82 118.83,42.42 121.32,42.42 122.32,41.41 U15.7 U15.4 124.3,41.41 124.37,41.48 127.78,41.48 R451.1 127.46,40.88 127.46,40.01 127.77,39.7 128.23,39.7 v3(128.43,39.5) ; U17.28 129.21,34.56 v3(129.2,34.57)
  BOTTOM w0.102: v3(129.2,34.57) 128.38,35.39 v2(128.38,35.69) 128.38,39.45 v3(128.43,39.5)
DET_HDMI#: length 123.8
  TOP w0.102: v3(109.38,28.19) 110.08,27.49 U21.2 110.03,27.11 R480.2 R479.1 ; v1(65.82,73.41) 65.57,73.16 SCA1.38
  L3 w0.127: v3(109.38,28.19) 109.13,27.94 103.25,27.94 102.14,29.05 102.14,30.85 97.56,35.43 97.56,40.99 97.56,41.63 88.33,50.85 86.67,50.85 78.72,58.8 78.72,68.83 74.35,73.2 69.83,73.2 69.18,73.85 66.26,73.85 v1(65.82,73.41)
  L4 w0.127: v3(109.38,28.19) 109.38,28.63 112.12,31.37 115.49,31.37 120.57,36.45 122.36,36.45 128.08,42.16 133.39,42.16 136.42,45.2 139.24,45.2 v3(140.24,44.2)
  BOTTOM w0.102: Q70.G 142.95,43.13 141.31,43.13 v3(140.24,44.2) ; v2(66.61,73.99) 66.4,73.99 v1(65.82,73.41)
DET_HDMI_C: length 22.6
  TOP w0.102: v3(109.79,23.16) 109.79,23.89 107.9,25.78 107.54,25.78 R479.2 ; v3(119.29,14.61) 119.07,14.82 HDMI2.11
  L3 w0.127: v3(119.29,14.61) 118.27,14.61 117.71,15.16 117.71,17.32 115.6,19.43 111.84,19.43 109.79,21.49 v3(109.79,23.16)
  BOTTOM w0.102: v2(119.95,15.09) 119.46,14.61 v3(119.29,14.61)
DGPU_PWR_EN#: length 9.8
  TOP w0.102: R238.2 73.82,115.44 v3(74.58,114.68) ; R238.2 74.09,115.55 Q21.3 ; R238.2 74.2,116.2 Q21.2
  BOTTOM w0.102: v3(74.58,114.68) 74.1,114.68 v2(73.67,115.11) 73.67,115.29 74.58,116.2 Q21.2 Q53.2
DIMM_CA_CPU_VREF_A_RC: length 2.4
  BOTTOM w0.508: C385.2 R598.1 v2(141.38,149.29)
DIMM_CA_VREF_A_R: length 11.3
  TOP w0.305: DIMM1.164 135.97,149.53 v3(135.92,149.48)
  BOTTOM w0.508: R599.2 R600.2 ; R600.2 C391.1 C390.1 137.89,148.21 C393.1 139.03,148.27 R605.1 140.79,148.27 141.18,147.88 v2(141.41,147.88) ; R600.2 136.11,149.29 v3(135.92,149.48)
DIMM_CB_CPU_VREF_A_RC: length 2.5
  BOTTOM w0.508: R606.1 152.05,147.45 v2(152.46,147.85) 152.46,148.06 152.05,148.46 C387.2
DIMM_CB_VREF_A_R: length 10.5
  TOP w0.305: v3(152.43,149.35) 152.61,149.53 DIMM2.164
  BOTTOM w0.457: C388.1 155.16,148.35 C392.1
  BOTTOM w0.508: R596.1 155.74,148.92 C392.1 ; R596.1 R597.2 ; R596.1 v2(156.75,149.92) ; C388.1 C389.1 153.37,148.41 v3(152.43,149.35) 152.31,149.48 R601.2
DISP_UTIL_CPU: length 153
  TOP w0.102: v3(43.59,65.53) 43.47,65.41 43.47,64.39 44.36,63.5 44.36,59.41 45.02,58.75 45.02,56.11 46.01,55.12 R402.2 ; v3(49.06,160.4) 49.51,159.94 56.61,159.94 58.55,161.89 58.55,167.3 60.61,169.36 63.22,169.36 v4(64.55,170.69) 66.12,172.26 68.66,172.26 69.18,172.78 70.52,172.78 71.59,173.85 72.07,173.85 CPU1.B52
  L3 w0.127: v3(38.39,127.76) 33.22,122.59 33.22,82.74 34.41,81.55 34.41,79.79 36.1,78.11 40.51,78.11 43.34,75.27 43.34,65.79 v3(43.59,65.53)
  BOTTOM w0.102: v3(49.06,160.4) 49.06,159.09 45.63,155.66 45.63,136.27 44.42,135.06 44.42,132.91 39.73,128.22 38.84,128.22 v3(38.39,127.76)
DP_AUXN: length 3.3
  TOP w0.102: TP24.1 121.06,208.91 120.81,209.17 120.3,209.17 119.83,209.64 119.64,209.64 119.5,209.5 NGFF1.20
DP_AUXN_C: length 14.1
  TOP w0.102: R420.2 61.65,51.27 61.65,50.8 61.84,50.61 63.75,50.61 64.89,49.47 65.51,49.47 ; C187.2 72.35,50.53 70.2,50.53 69.13,49.47 65.51,49.47 ; 65.51,49.47 v4(65.51,49.83)
DP_AUXP: length 3.2
  TOP w0.102: NGFF1.22 119.5,210 119.64,209.86 119.92,209.86 120.39,209.38 120.81,209.38 120.94,209.51 TP22.1
DP_AUXP_C: length 14.2
  TOP w0.102: 69.84,49.87 70.29,50.32 72.72,50.32 C189.2 ; 69.84,49.87 v4(70.11,49.61) ; 69.84,49.87 69.22,49.25 64.8,49.25 63.66,50.39 61.75,50.39 61.44,50.71 61.44,51.69 R419.2
DP_HPD: length 2.6
  TOP w0.102: TP17.1 109.29,212.25 NGFF1.31
DP_LANE0N_C: length 3.8
  TOP w0.102: C169.2 72.07,61.43 71.5,61.43 70.43,62.5 69.88,62.5 69.79,62.59 SCA1.12
DP_LANE0P_C: length 4.3
  TOP w0.102: C170.2 71.98,61.21 71.41,61.21 71.17,61.46 ; SCA1.11 69.79,62.19 69.88,62.28 70.34,62.28 71.17,61.46 ; 71.17,61.46 v4(70.9,61.19)
DP_LANE1N_C: length 3.5
  TOP w0.102: C165.2 72.07,63.33 70.86,63.33 70.5,63.7 69.88,63.7 69.79,63.79 SCA1.15
DP_LANE1P_C: length 4
  TOP w0.102: C166.2 71.98,63.12 71.03,63.12 ; v4(71.03,62.74) 71.03,63.12 ; 71.03,63.12 70.77,63.12 70.41,63.48 69.88,63.48 69.79,63.39 SCA1.14
DP_LANE2N_C: length 3.7
  TOP w0.102: SCA1.17 69.79,64.59 69.88,64.5 70.55,64.5 71.17,65.11 72.07,65.11 C160.2
DP_LANE2P_C: length 4.1
  TOP w0.102: 70.78,64.43 71.26,64.9 71.98,64.9 C163.2 ; 70.78,64.43 70.64,64.28 69.88,64.28 69.79,64.19 SCA1.16 ; 70.78,64.43 v4(71.05,64.16)
DP_LANE3N_C: length 4.4
  TOP w0.102: SCA1.19 69.79,65.39 69.88,65.3 70.36,65.3 71.25,66.19 ; v4(71,66.45) 71.25,66.19 ; 71.25,66.19 71.83,66.76 71.94,66.76 C156.2
DP_LANE3P_C: length 4
  TOP w0.102: SCA1.18 69.79,64.99 69.88,65.08 70.45,65.08 71.92,66.55 72.11,66.55 C158.2
DP_ML0N: length 3.3
  TOP w0.102: NGFF1.32 119.5,212.5 119.64,212.64 119.74,212.64 120.52,211.86 120.81,211.86 120.94,211.74 TP16.1
DP_ML0P: length 3.5
  TOP w0.102: NGFF1.34 119.5,213 119.64,212.86 119.83,212.86 120.61,212.08 120.81,212.08 120.94,212.21 TP14.1
DP_ML1N: length 4.6
  TOP w0.102: NGFF1.26 119.5,211 119.64,211.14 119.98,211.14 120.56,210.57 122.08,210.57 122.33,210.31 TP20.1
DP_ML1P: length 4.7
  TOP w0.102: NGFF1.28 119.5,211.5 119.64,211.36 120.07,211.36 120.65,210.78 122.17,210.78 122.33,210.95 TP18.1
DP_ML2N: length 4.1
  TOP w0.102: NGFF1.25 109.5,210.75 109.36,210.89 109.2,210.89 108.66,210.35 107.44,210.35 TP21.1
DP_ML2P: length 4.2
  TOP w0.102: TP19.1 107.6,210.57 108.57,210.57 109.11,211.11 109.36,211.11 109.5,211.25 NGFF1.27
DP_ML3N: length 2.5
  TOP w0.102: TP26.1 109.21,209.25 NGFF1.19
DP_ML3P: length 2.5
  TOP w0.102: TP23.1 108.71,209.4 108.98,209.4 109.33,209.75 NGFF1.21
DPLVDS_BL_EN: length 138.4
  TOP w0.102: KBC1.26 140.74,49.92 140.39,50.27 140.39,51.79 v1(139.35,52.83) ; v3(51.98,55.37) 53.25,56.64 SCA1.97
  L3 w0.127: v3(45.63,29.59) 45.63,34.24 47.95,36.57 47.95,45.24 47.49,45.7 47.49,48.9 51.47,52.87 51.47,54.86 v3(51.98,55.37)
  L4 w0.127: v1(139.35,52.83) 139.23,52.96 135.03,52.96 134.57,52.5 127.44,52.5 126.94,52.01 126.94,51.57 126.33,50.97 123.05,50.97 122.32,51.7 106.65,51.7 105.31,53.04 80.56,53.04 78.48,55.12 74.68,55.12 72.75,57.04 53.65,57.04 v3(51.98,55.37)
  BOTTOM w0.102: v3(45.63,29.59) 46.13,29.08 46.13,27.56 v2(46.64,27.05) 47.15,26.54 47.15,24.61 46.49,23.95 46.02,23.95 R840.2 ; R766.1 52.1,55.24 v3(51.98,55.37) ; R772.1 139.86,53.34 v1(139.35,52.83)
DPLVDS_HPD: length 5
  TOP w0.102: SCA1.21 69.84,66.19 70.67,67.03 70.67,68.08 v4(71.08,68.48) 71.13,68.53 72.03,68.53 R363.1
DPLVDS_PANEL_VCC: length 64.7
  TOP w0.102: SCA1.64 55.17,72.88 54.77,73.28 v1(54.74,73.28)
  L3 w0.127: v3(42.71,113.54) 42.71,90.99 44.44,89.25 44.44,86.02 52.09,78.38 52.09,74.47 53.25,73.3 54.7,73.3 54.73,73.28 v1(54.74,73.28)
  BOTTOM w0.102: v1(54.74,73.28) 54.58,73.13 53.49,73.13 R716.1 ; R881.1 33.69,112.14 34.45,112.9 v2(37.5,112.9) 39.4,112.9 40.55,114.05 42.2,114.05 v3(42.71,113.54)
DPLVDS_PWMIN: length 11.6
  TOP w0.165: SCA1.100 56.37,55.88 55.82,55.33 53.13,55.33 52.66,54.86 50.83,54.86 v4(50.58,55.12) R402.1 R399.1
DPLVDS_PWMOUT: length 45.3
  TOP w0.165: SCA1.101 56.77,55.56 56.12,54.91 53.42,54.91 v3(51.98,53.47) ; R486.2 45.5,26.31 44.33,27.48 43.72,27.48 v4(43.62,27.58) 43.62,27.66 44.03,28.07 45.5,28.07 46.52,27.05 v3(46.52,25.53)
  L3 w0.165: v3(51.98,53.47) 51.98,52.82 47.89,48.73 47.89,45.87 48.35,45.41 48.35,36.4 46.52,34.56 v3(46.52,25.53)
DS3_PWRCTL: length 7.2
  BOTTOM w0.102: R859.2 126.59,17.27 127.22,16.64 v2(127.22,16.43) 127.07,16.43 126.02,15.38 126.02,12.83 126.23,12.61 U38.4
EAPD_DEPOP: length 38.1
  TOP w0.203: v3(159.98,70.08) 159.98,71.73 160.79,72.55 U11.14
  BOTTOM w0.203: R800.1 152.69,40.83 152.69,42.67 151.19,44.17 151.19,44.96 150.78,45.37 150.78,49.41 151.81,50.44 v2(152.58,50.44) 155.48,53.34 155.48,63.67 157.31,65.5 157.31,65.99 158.78,67.46 158.78,68.88 v3(159.98,70.08)
EAPD_DEPOP_1: length 8.2
  BOTTOM w0.102: R800.2 154.48,39.8 v2(154.8,39.8) 154.92,39.93 159.05,39.93 R799.1 160.52,41.4 R798.1
EAPD_DEPOP_2: length 3.8
  BOTTOM w0.254: R799.2 158.92,40.69 v2(158.3,40.69) 157.77,41.22 157.77,41.66 157.51,41.91 Q71.5
EAPD_DEPOP_2_D: length 3.4
  BOTTOM w0.102: v2(161.45,42.65) 161.48,42.62 162.09,42.62 162.65,42.05 Q72.6 163.05,43.07 R790.2
EC_AGND: length 10.4
  TOP w0.203: v1(131.22,61.09) 130.74,60.6 130.26,60.6 130.17,60.7 KBC1.103
  BOTTOM w0.508: R733.2 C547.2 132.18,64.77 R741.2 C548.1 132.18,62.1 C550.2 C551.2 v1(131.22,61.09) 131.22,61.47 130.84,61.85 v2(130.72,61.85) 129.76,61.85 R750.1
EC_AVCC: length 20.2
  TOP w0.203: v1(130.46,61.09) 130.45,61.1 KBC1.102
  BOTTOM w0.508: C551.1 133.64,61.09 134.02,61.47 R748.1 ; C551.1 132.94,60.26 132.49,59.82 v2(132.37,59.82) 132.19,59.82 131.61,60.4 131.01,60.4 130.46,60.95 v1(130.46,61.09) ; C551.1 C550.1 132.88,62.04 132.88,67.08 131.99,67.97 130.13,67.97 129.19,67.03 129.19,65.88 129.13,65.82 R734.1 R740.2
EC_BEEP_GPIO: length 47.1
  TOP w0.102: KBC1.121 131.47,53.5 133.51,51.46 v3(133.51,51.31)
  L4 w0.127: v3(152.37,45.28) 151.16,46.48 151.16,55.37 150.15,56.38 150.15,58.03 148.68,59.5 145.79,59.5 145,58.71 145,52.18 143.81,50.99 139.85,50.99 138.8,52.03 135.62,52.03 134.9,51.31 v3(133.51,51.31)
  BOTTOM w0.102: R891.1 151.53,46.29 v2(151.34,46.1) 151.34,45.54 151.61,45.28 v3(152.37,45.28)
EC_BEEP_GPIO_R: length 7.5
  BOTTOM w0.102: R891.2 151.73,47.18 151.39,47.52 v2(151.39,48.13) 151.39,48.68 151.8,49.09 R890.1 152.88,49.09 155.16,46.8 Q84.G
EC_CLEAR_RTC: length 95.1
  TOP w0.102: KBC1.32 146.46,49.15 v1(146.85,49.53)
  L4 w0.127: v3(148.75,93.09) 148.37,93.47 144.69,93.47 144.47,93.26 142.74,93.26 141.64,94.36 138.76,94.36 137.52,95.6 135.9,97.22 135.9,99.62 134.29,101.23 112.44,101.23 v3(111.73,100.52)
  BOTTOM w0.102: v3(111.73,100.52) Q83.G 110.36,101.63 v2(110.27,101.73) R888.1 ; v3(148.75,93.09) 148.6,92.94 148.6,81.37 148.22,80.99 148.22,76.37 148.01,76.17 148.01,63.12 148.24,62.89 148.24,52.84 148.39,52.69 148.39,50.91 148.5,50.81 148.5,50.34 147.69,49.53 v1(146.85,49.53)
EC_HDMI_PD_N: length 45.8
  TOP w0.102: v3(147.73,40.39) 148.24,39.88 148.24,39.31 R466.2 148.18,35.87 146.46,34.15 146.46,32.64 143.23,29.4 Q43.G ; KBC1.117 131.25,55.1 v1(132.62,53.72)
  BOTTOM w0.102: v3(147.73,40.39) 146.59,39.24 144.69,39.24 142.76,41.17 142.76,41.42 142.01,42.16 139.48,42.16 137.73,43.92 137.73,44.8 136.95,45.57 136.85,45.67 132.9,45.67 132.44,46.13 132.44,47.17 133.03,47.75 v2(133.26,47.75) 134.22,48.72 134.22,52.12 v1(132.62,53.72)
EC_LAN_DISABLE_N: length 125.1
  TOP w0.102: KBC1.119 131.28,54.3 v1(131.86,53.72) ; R522.1 41.88,8.32 42.39,8.83 42.39,10.73 v3(42.83,11.18)
  L4 w0.127: v3(122.08,38.86) 121.38,38.86 116.14,33.62 114.61,33.62 112.99,32 110.67,32 103.68,25.02 88.1,25.02 87.21,24.13 69.3,24.13 69.08,24.35 63.81,24.35 58.05,18.59 49.2,18.59 45.37,14.76 45.37,13.84 42.83,11.3 v3(42.83,11.18)
  BOTTOM w0.102: R767.1 131.86,54.42 v1(131.86,53.72) 133.99,51.59 133.99,49.73 132.04,47.78 132.04,46.48 131.38,45.82 131,45.82 130.87,45.69 129.95,45.69 129.73,45.47 128.64,45.47 128.13,44.95 128.13,44.01 127.52,43.41 122.47,43.41 122.12,43.06 122.12,41.5 122.41,41.21 122.41,40.08 v2(122.33,40.01) 122.08,39.75 v3(122.08,38.86)
EC_OSD_MENU: length 3.7
  TOP w0.102: KBC1.56 145.78,59.9 v4(146.72,60.83) 146.85,60.96 R378.1
EC_PECI: length 239.9
  TOP w0.102: R115.2 63.72,170.65 62.99,169.92 60.38,169.92 58,167.53 58,167.07 58,167.07 58,162.12 56.41,160.53 49.94,160.53 v3(49.82,160.4) ; R438.2 137.07,44.32 135.59,42.85 134.63,42.85 134.12,42.34 128.76,42.34 128.66,42.44 124.92,42.44 123.1,44.27 123.1,45.22 122.33,45.99 109.12,45.99 108.6,45.47 104.3,45.47 100.49,49.28 93.62,49.28 84.35,58.55 81.31,58.55 v3(80.68,59.18)
  L3 w0.127: v3(44.77,131.54) 44.77,131.45 35.2,121.88 35.2,85.5 45.55,75.15 45.55,65.93 54.4,57.09 56.87,57.09 v3(57.95,58.17)
  L4 w0.127: v3(80.68,59.18) 80.08,58.59 74.17,58.59 72.51,60.24 72.51,60.4 70.43,62.48 66.45,62.48 65.44,61.47 59.41,61.47 57.86,59.91 57.86,58.25 v3(57.95,58.17)
  BOTTOM w0.102: v3(44.77,131.54) 46.69,131.54 v2(46.73,131.58) 47.79,132.63 47.79,138.03 50.15,140.39 50.15,142.33 51.33,143.51 51.33,157.5 51.48,157.65 51.48,158.74 v3(49.82,160.4)
EC_PECI_R: length 4.5
  TOP w0.102: R438.1 C199.1 135.87,46.09 135.87,47.49 v4(135.88,47.5) 135.88,48 135.54,48.34 KBC1.13
EC_PROCHOT#: length 8.8
  TOP w0.102: KBC1.24 139.94,48.21 v1(139.61,47.88)
  BOTTOM w0.102: v1(139.61,47.88) 139.46,47.88 138.58,47 138.58,46.05 R783.2 138.6,45.9 R784.1 ; v1(139.61,47.88) 139.62,47.88 140.19,47.31 140.19,46.57 140.78,45.98 Q69.G ; v1(139.61,47.88) 139.63,47.9 139.63,48.41 v2(139.25,48.79)
EC_PROCHOT#_G: length 3.5
  BOTTOM w0.102: v2(49.03,43.31) R785.2 C571.1 50.99,44.26 PQ10.G
EC_SCI#: length 170.6
  TOP w0.102: CPU1.N9 78.91,149.68 v1(79.13,149.68)
  L4 w0.127: v1(140.88,50.42) 140.53,50.08 136.7,50.08 136.39,50.38 136.39,51.5 136.12,51.78 135.73,51.78 134.79,50.84 134.49,50.84 133.73,50.08 123.42,50.08 110.31,50.08 109.58,50.81 106.28,50.81 105.16,51.93 v3(96.43,51.93)
  BOTTOM w0.102: v3(96.43,51.93) 94.52,53.84 94.52,59.48 102.06,67.03 102.06,109.82 99.28,112.6 99.13,112.6 98.59,113.15 98.59,114.68 v2(98.33,114.94) 98.33,116.08 95.77,118.64 83.83,118.64 79.41,123.07 79.41,125.5 75.01,129.89 75.01,137.91 R628.1 76.36,139.26 76.36,143.76 77.9,145.31 77.9,147.87 78.8,148.76 78.8,149.34 v1(79.13,149.68) ; R778.1 140.75,50.29 v1(140.88,50.42)
EC_SCI#_R: length 4.1
  TOP w0.102: KBC1.29 141.94,48.34 v1(142.4,47.88)
  BOTTOM w0.102: R778.2 140.75,48.51 141.13,48.13 141.13,47.79 141.45,47.47 v2(141.51,47.47) 141.99,47.47 v1(142.4,47.88)
EC_SERIRQ: length 10.8
  TOP w0.102: R436.1 126.05,45.99 126.35,45.99 127.15,46.79 v4(127.72,46.79) 128.18,47.24 129.23,47.24 129.48,47.5 129.48,47.51 129.5,47.52 129.5,48.27 127.49,50.27 127.49,50.91 128.48,51.9 KBC1.125
EC_SMI#: length 172.6
  TOP w0.089: CPU1.G4 75.46,146.38 75.46,145.23 75.42,145.16 75.42,144.87 75.46,144.78 75.46,144.58 75.41,144.49 75.2,144.27
  TOP w0.102: 75.2,144.27 74.51,144.27 73.24,143 v3(73.06,143) 72.38,142.32 RN16.2
  L3 w0.127: v3(149.64,106.93) 150.11,106.46 150.11,105.1 149.22,104.21 149.22,92.54 148.58,91.91 148.58,87.82 145.98,85.22 145.98,82.32 145.27,81.61 145.27,74.54 142.59,71.87 142.59,65.31 141.12,63.84 141.12,56.64 140.5,56.01 140.5,53.35 139.42,52.27 139.42,48.67 138.68,47.94 138.68,47.42 138.67,47.41 138.67,47.27 137.66,46.27 136.77,46.27 v1(136.3,46.74)
  L4 w0.127: v3(73.06,143) 73.31,143 74.84,141.48 74.84,139.36 75.53,138.67 75.53,135.08 76.19,134.42 76.19,134.1 87.8,122.5 112.95,122.5 125.98,109.47 146.21,109.47 148.75,106.93 v3(149.64,106.93)
  BOTTOM w0.102: R779.1 136.3,48.51 136.98,47.84 v2(136.98,47.56) 136.98,47.41 v1(136.3,46.74)
EC_SMI#_R: length 5.7
  TOP w0.102: v3(135.92,51.31) 134.74,50.12 KBC1.11
  BOTTOM w0.102: R779.2 135.73,49.59 135.16,50.16 v2(135.16,50.93) 135.54,51.31 v3(135.92,51.31)
EC_SPI_CLK: length 9.9
  TOP w0.102: RN7.1 133.22,69.63 133.13,69.72 133.13,70.87 133,70.99 132.16,70.99 v4(131.48,70.31) 131.88,69.9 131.88,67.4 132.42,66.86 132.42,65.97 132.34,65.88 KBC1.92
EC_SPI_CS0#: length 5.5
  TOP w0.102: KBC1.90 133.14,65.81 133.18,65.85 133.18,66.5 133.79,67.1 133.79,68.32 v4(133.78,68.33) 134.47,69.02 RN7.2
EC_SPI_SI: length 5.6
  TOP w0.102: KBC1.87 134.34,67.22 v4(135.03,67.92) 135.85,68.74 RN8.1
EC_SPI_SO: length 6
  TOP w0.102: RN8.2 136.5,68.12 v4(136.41,68.02) 135.49,67.11 135.08,67.11 134.73,66.75 134.73,65.58 134.74,65.57 KBC1.86
EC_SPKR: length 64.8
  TOP w0.102: KBC1.22 139.14,46.91 v3(139.04,46.81) ; R889.1 156.18,86.17 v3(156.75,85.6)
  L4 w0.127: v3(139.04,46.81) 139.2,46.65 143.61,46.65 145.45,48.48 145.45,58.79 145.9,59.25 148.31,59.25 v1(149.64,57.91) ; v3(156.75,85.6) 153.07,85.6 v3(150.53,88.14)
  BOTTOM w0.102: v3(150.53,88.14) v2(150.53,87) 150.53,85.6 150.88,85.24 150.88,76.17 149.18,74.47 149.18,63.61 149.64,63.15 v1(149.64,57.91)
EC_SWI#: length 177
  TOP w0.089: 76.11,143.39 76.25,143.53 76.25,144.77 76.3,144.87 76.3,145.14 76.26,145.23 76.26,145.44 76.3,145.52 76.3,145.76 CPU1.J3
  TOP w0.102: v3(57.44,132.87) 57.44,133.15 61.09,136.8 73.03,136.8 73.21,136.98 73.91,136.98 75.15,138.23 R167.1 75.85,139.46 75.85,140.08 75.73,140.21 75.13,140.21 74.86,140.48 74.86,142.14 76.11,143.39 ; v3(117.51,61.85) 117.51,61.57 120.46,58.62 121.23,58.62 121.97,57.89 122.49,57.89 122.99,57.39 122.99,56.93 123.65,56.28 123.65,54.45 123.93,54.16 123.93,54.09 R410.1
  L3 w0.127: v1(78.01,71.12) 72.72,76.42 65.19,76.42 64.48,77.13 54.96,77.13 45.59,86.5 45.59,89.72 44.39,90.92 44.39,115.99 56.12,127.71 56.12,131.55 v3(57.44,132.87)
  L4 w0.127: v3(117.51,61.85) 116.96,61.3 105.86,61.3 105.03,62.14 91.9,62.14 90.58,63.46 87.09,63.46 79.43,71.12 v1(78.01,71.12)
  BOTTOM w0.102: v2(56.62,132.87) v3(57.44,132.87)
EC_SWI#_R: length 4.4
  TOP w0.102: KBC1.123 127.48,52.7 127.46,52.71 127.46,52.72 127,53.19 v4(126.98,53.19) 126.98,53.21 126.47,53.72 R410.2
EC_VBKUP: length 3.7
  TOP w0.203: 127.96,56.3 KBC1.114
  TOP w0.254: R397.1 126.4,57.47 127.06,56.8 v4(127.07,56.8) 127.58,56.3 127.96,56.3
EC_VTT: length 5.3
  TOP w0.203: C198.1 135.14,45.93 135.14,47.29 v3(134.96,47.47) 134.96,47.68 135.14,47.86 KBC1.12
  TOP w0.254: C198.1 R444.2
  BOTTOM w0.254: v3(134.96,47.47) 134.96,47.98 v2(135.24,48.26)
ECRST#: length 8.7
  TOP w0.102: KBC1.85 135.14,66.53 v1(135.16,66.55)
  BOTTOM w0.102: 133.32,68.33 133.79,68.33 134.11,68.01 C538.1 R725.2 135.42,67.88 Q59.E ; 133.32,68.33 R874.1 ; 133.32,68.33 133.32,68.11 134.25,67.18 134.4,67.18 v2(134.53,67.06) 135.03,66.55 v1(135.16,66.55)
EDID_RDY: length 106.8
  TOP w0.102: v3(58.2,132.87) 61.91,136.58 73.13,136.58 73.31,136.75 74.01,136.75 76.3,139.04 R152.1 76.3,142.86 76.52,143.09 CPU1.J1 ; SCA1.46 62.37,73.06 62.93,73.62 62.93,74.35 v1(62.86,74.42)
  L3 w0.127: v3(58.2,132.87) 57.73,133.34 57.24,133.34 55.86,131.96 55.86,127.82 44.14,116.09 44.14,90.81 45.33,89.62 45.33,86.39 54.89,76.83 61.4,76.83 62.86,75.38 v1(62.86,74.42)
  BOTTOM w0.102: v2(58.2,132.05) v3(58.2,132.87)
EDP_AUX_CPU_N: length 177
  TOP w0.102: 78.09,50.99 78.25,50.99 78.7,50.55 79.1,50.55 79.23,50.67 79.23,50.93 79.1,51.05 v3(78.9,51.05) ; 78.09,50.99 v4(78.09,51.36) ; 78.09,50.99 76.5,50.99 76.11,50.6 75.79,50.6 75.66,50.72 75.66,50.93 R425.2 R424.1 74.44,50.72 74.09,50.72 C187.1 ; v1(74.74,170.67) 74.83,170.58 74.83,170.39 74.59,170.16 74.46,170.16 CPU1.E45
  L3 w0.127: v1(74.74,170.67) 74.72,170.69 74.34,170.69 73.96,170.31 73.96,169.82 73.17,169.02 73.05,169.02 72.04,168.02 72.04,167.13 71.11,166.2 67.99,166.2 64.23,162.45 57.75,162.45 56.95,161.65 56.95,158.49 58.57,156.88 58.57,150.74 57.95,150.11 57.95,134.8 42.19,119.04 42.19,90.79 43.94,89.04 43.94,85.81 51.51,78.24 51.51,74.33 53.04,72.8 54.49,72.8 54.95,72.34 72.23,72.34 77.83,66.74 77.83,54.65 77.03,53.85 77.03,51.59 77.88,50.74 78.59,50.74 v3(78.9,51.05)
EDP_AUX_CPU_P: length 177.1
  TOP w0.102: CPU1.F45 75.06,170.32 v1(75.37,170.63) ; v3(78.93,50.09) 78.85,50.09 78.16,50.77 77.05,50.77 ; C189.1 74.09,50.5 74.44,50.5 R432.1 R433.2 75.92,50.1 76.59,50.77 77.05,50.77 ; v4(77.05,50.39) 77.05,50.77
  L3 w0.127: v1(75.37,170.63) 75.06,170.94 75.06,170.94 74.91,171.09 74.37,171.09 73.69,170.42 73.69,169.93 73.06,169.29 72.93,169.29 71.78,168.13 71.78,167.24 71,166.47 67.88,166.47 64.12,162.71 57.64,162.71 56.69,161.76 56.69,158.38 58.3,156.77 58.3,150.85 57.68,150.22 57.68,134.91 41.92,119.15 41.92,90.68 43.67,88.93 43.67,85.7 51.24,78.13 51.24,74.22 52.93,72.53 54.38,72.53 54.84,72.07 72.12,72.07 77.57,66.63 77.57,54.76 76.77,53.96 76.77,51.48 77.77,50.48 78.54,50.48 v3(78.93,50.09)
EDP_HPD_CPU: length 146
  TOP w0.102: CPU1.L10 77.98,150.34 v1(78.13,150.34) ; v3(35.72,123.06) 35.9,123.24 35.91,123.24 36.18,123.51 36.18,123.52 v4(36.61,123.95) 36.61,128.92 38.9,131.21 38.9,131.23 39.23,131.55 39.25,131.55 39.77,132.08 39.92,132.08 41,133.16 41,133.38 43.13,135.51 56,135.51 61,140.51 62.31,140.51 63.25,139.57 65.97,139.57 66.63,140.24 66.63,142.3 67.57,143.24 67.57,144.5 v3(67.6,144.53) ; v1(75.22,71.25) 74.79,70.82 72.56,70.82 72.36,70.61 R347.1
  L4 w0.127: v3(35.72,123.06) 39.28,119.51 39.28,86.04 50.52,74.8 51.57,74.8 54.52,71.86 61.08,71.86 61.25,71.69 74.77,71.69 v1(75.22,71.25) ; v1(78.13,150.34) 77.11,149.32 77.11,147.63 76.62,147.14 70.98,147.14 70.91,147.07 68.71,147.07 67.6,145.95 v3(67.6,144.53)
EDP_RCOMP_CPU: length 13.5
  TOP w0.254: CPU1.E52 74.41,173.66 v1(74.71,173.36)
  L3 w0.508: v3(84.11,169.93) 83.55,169.93 79.99,173.48 74.84,173.48 v1(74.71,173.36)
  BOTTOM w0.508: v2(74.99,172.57) 74.71,172.84 v1(74.71,173.36) ; v3(84.11,169.93) 84.74,169.29 R562.2
EDP_TX_CPU_N0: length 159.8
  TOP w0.102: CPU1.C47 72.76,171.64 72.49,171.37 72.47,171.37 72.4,171.3 67.59,171.3 67.51,171.38 67.51,171.49 v3(67.85,171.83) ; v3(74.2,61.72) 73.86,61.39 73.59,61.39 C169.1
  L3 w0.127: v3(67.85,171.83) 67.36,171.34 67.36,171.23 66.46,170.33 60.25,170.33 53.8,163.89 53.8,149.6 52.74,148.53 52.74,133.97 38.31,119.55 38.31,89.87 39.4,88.77 39.4,85.9 48.41,76.89 48.41,70.18 50.5,68.08 64.28,68.08 68.18,64.19 70.59,64.19 73.45,61.33 73.81,61.33 v3(74.2,61.72)
  BOTTOM w0.102: v2(67.72,172.72) 67.85,172.59 v3(67.85,171.83)
EDP_TX_CPU_N1: length 160.3
  TOP w0.089: v1(69.38,169.54) 69.55,169.72 69.55,170.02 69.83,170.3 70.95,170.3 70.96,170.29 71.47,170.29 71.63,170.21 71.73,170.21 71.89,170.28 72.14,170.28 72.23,170.25 72.36,170.24 72.44,170.25 72.49,170.27 72.51,170.28 72.57,170.33 72.59,170.34 72.78,170.77 CPU1.D46
  TOP w0.102: v3(75.34,63.63) 75.01,63.29 73.59,63.29 C165.1
  L3 w0.127: v1(69.38,169.54) 69.38,168.91 69.19,168.72 68.8,168.72 67.36,167.27 65.21,167.27 64.21,168.28 61.1,168.28 55.87,163.05 55.87,157.9 57.53,156.25 57.53,151.33 56.9,150.71 56.9,135.23 40.37,118.69 40.37,91.06 42.8,88.64 42.8,85.48 50.46,77.81 50.46,73.9 52.61,71.75 54.06,71.75 54.54,71.27 71.83,71.27 76.75,66.35 76.75,63.88 76.35,63.47 75.5,63.47 v3(75.34,63.63)
  BOTTOM w0.102: v2(74.56,62.94) 74.65,62.94 v3(75.34,63.63)
EDP_TX_CPU_N2: length 158.7
  TOP w0.102: v3(67.47,169.54) 67.34,169.54 66.92,169.96 66.92,170.27 67.22,170.56 71.64,170.56 CPU1.A45 ; v3(75.33,65.16) 75.24,65.25 74.81,65.25 74.71,65.15 74.71,64.9 74.54,64.73 73.97,64.73 73.85,64.86 73.85,65.28 73.72,65.41 C160.1
  L3 w0.127: v3(67.47,169.54) 67.24,169.32 67.24,169.01 66.89,168.67 65.65,168.67 64.76,169.56 60.57,169.56 54.58,163.57 54.58,149.28 53.51,148.21 53.51,133.65 39.09,119.23 39.09,90.29 40.23,89.15 40.23,86.17 49.18,77.22 49.18,70.5 50.82,68.86 69.36,68.86 73.57,64.66 74.71,64.66 74.84,64.78 74.84,65.04 74.96,65.16 v3(75.33,65.16)
  BOTTOM w0.102: v2(67.09,170.31) 67.47,169.93 v3(67.47,169.54)
EDP_TX_CPU_N3: length 156.6
  TOP w0.102: v3(74.2,67.18) 73.86,66.85 73.59,66.85 C156.1 ; CPU1.A47 71.69,171.88 71.57,172 71.06,172 70.68,172.38 69.73,172.38 69.6,172.25 69.6,172.06 69.83,171.83 v1(69.9,171.83)
  L3 w0.127: v3(74.2,67.18) 73.71,66.69 72.92,66.69 69.95,69.66 51.12,69.66 49.96,70.82 49.96,77.58 42.17,85.37 42.17,88.34 39.86,90.65 39.86,118.9 56.4,135.44 56.4,150.92 57.02,151.54 57.02,155.99 55.35,157.65 55.35,163.25 60.89,168.78 64.44,168.78 65.33,167.89 67.22,167.89 68.32,169 68.32,170.51 69.01,171.2 70.04,171.2 70.21,171.37 70.21,171.52 v1(69.9,171.83)
  BOTTOM w0.102: v2(70.77,171.07) 70.66,171.07 v1(69.9,171.83)
EDP_TX_CPU_P0: length 159.6
  TOP w0.102: CPU1.C46 72.49,171.07 72.49,171.08 67.5,171.08 67.3,171.29 67.3,171.62 v3(67.09,171.83) ; C170.1 73.59,61.17 73.86,61.17 v3(74.2,60.83)
  L3 w0.127: v3(74.2,60.83) 73.97,61.06 73.34,61.06 70.48,63.92 68.07,63.92 64.17,67.82 50.39,67.82 48.14,70.07 48.14,76.78 39.14,85.79 39.14,88.66 38.04,89.75 38.04,119.66 52.47,134.08 52.47,148.64 53.54,149.71 53.54,164 60.14,170.6 66.35,170.6 67.09,171.34 v3(67.09,171.83)
  BOTTOM w0.102: v2(74.2,60.02) v3(74.2,60.83)
EDP_TX_CPU_P1: length 160.1
  TOP w0.089: CPU1.C45 72.72,170.19 72.65,170.15 72.6,170.12 72.44,170.06 72.39,170.05 72.24,170.05 72.15,170.08 72.1,170.1 71.92,170.1 71.76,170.04 71.59,170.04 71.43,170.11 70.96,170.11 70.95,170.11 69.91,170.11 69.74,169.94 69.74,169.81 v1(70.01,169.54)
  TOP w0.102: C166.1 73.59,63.07 75.01,63.07 v3(75.34,62.74) 75.63,62.46 v4(75.63,61.92)
  L3 w0.127: v1(70.01,169.54) 69.97,169.54 69.64,169.22 69.64,168.8 69.3,168.45 68.91,168.45 67.47,167 65.1,167 64.1,168.01 61.21,168.01 56.14,162.94 56.14,158.01 57.79,156.36 57.79,151.22 57.17,150.6 57.17,135.12 40.63,118.58 40.63,91.17 43.06,88.75 43.06,85.59 50.73,77.92 50.73,74.01 52.72,72.02 54.17,72.02 54.65,71.54 71.94,71.54 77.02,66.46 77.02,63.77 76.46,63.21 75.81,63.21 v3(75.34,62.74)
EDP_TX_CPU_P2: length 158.2
  TOP w0.102: 66.92,170.57 66.71,170.36 v3(66.71,169.54) ; 66.92,170.57 v4(66.66,170.84) ; 66.92,170.57 67.13,170.78 71.84,170.78 CPU1.B45 ; C163.1 75.2,64.52 v3(75.32,64.39)
  L3 w0.127: v3(66.71,169.54) 66.97,169.28 66.97,169.12 66.78,168.94 65.76,168.94 64.87,169.82 60.46,169.82 54.31,163.68 54.31,149.39 53.25,148.32 53.25,133.76 38.82,119.34 38.82,90.18 39.96,89.04 39.96,86.06 48.92,77.11 48.92,70.39 50.71,68.59 69.25,68.59 73.46,64.39 v3(75.32,64.39)
EDP_TX_CPU_P3: length 156.3
  TOP w0.102: C158.1 73.59,66.63 73.99,66.63 v3(74.2,66.42) ; v1(69.27,171.83) 69.39,171.95 69.39,172.34 69.64,172.59 70.77,172.59 71.15,172.21 71.69,172.21 72.26,171.64 CPU1.B47
  L3 w0.127: v3(74.2,66.42) 72.81,66.42 69.84,69.39 51.01,69.39 49.69,70.71 49.69,77.47 41.9,85.26 41.9,88.23 39.59,90.54 39.59,119.02 56.13,135.55 56.13,151.03 56.75,151.65 56.75,155.88 55.09,157.54 55.09,163.36 60.78,169.05 64.55,169.05 65.44,168.16 67.11,168.16 68.05,169.11 68.05,170.62 v1(69.27,171.83)
  BOTTOM w0.102: v2(68.84,171.07) 69.27,171.49 v1(69.27,171.83)
EDRAM_OPIO_RCOMP: length 2.6
  TOP w0.203: v1(75.98,181.85) 76.3,182.17 CPU1.H66
  BOTTOM w0.203: v2(76.87,182.88) R547.1 76.82,181.85 v1(75.98,181.85)
EMMC_RCOMP: length 9.2
  TOP w0.203: R168.1 86.57,137.79 88.1,139.32 v4(88.17,139.32) 88.41,139.32 89.49,140.4 89.49,140.54 90.57,141.62 90.57,144.48 90.44,144.6 CPU1.AT1
EOPIO_RCOMP: length 4.4
  TOP w0.203: CPU1.H65 76.3,181.15 v1(75.99,180.85)
  BOTTOM w0.203: R548.1 73.03,180.34 v2(73.95,180.34) 73.96,180.33 75.48,180.33 75.81,180.66 75.81,180.67 v1(75.99,180.85)
EQ: length 8.4
  TOP w0.102: U17.17 132.15,38.76 132.32,38.93 132.32,39.42 v3(131.86,39.88)
  BOTTOM w0.102: R795.2 130.18,41.31 v2(130.18,40.89) 130.92,40.16 131.58,40.16 v3(131.86,39.88) 130.84,39.88 130.36,39.4 130.36,38.44 R810.1
ESPI_RST#: length 10.6
  TOP w0.089: 95.95,149.85 94.73,151.07 93.93,151.07 93.67,150.81 CPU1.BA11
  TOP w0.102: TP39.1 99.86,145.41 99.86,148.48 98.49,149.84 95.96,149.84 95.95,149.85
EXT_PWR_GATE#: length 26.2
  TOP w0.102: v1(87.55,149.66) 87.95,150.06 CPU1.AM10
  BOTTOM w0.102: v1(87.55,149.66) 88.4,148.81 88.4,147.13 88.79,146.74 88.79,146.28 89.9,145.16 90.23,145.16 90.91,144.48 v2(91.19,144.48) 91.57,144.09 91.57,141.33 89.49,139.25 89.49,132.48 93.26,128.71 R644.2
FB_CAL_PD_VDDQ: length 2.5
  TOP w0.356: v1(75.99,91.32) 76.37,91.7 GPU1.D22
  BOTTOM w0.457: v2(76.21,89.56) 76.3,89.65 R686.1
  BOTTOM w0.508: R686.1 76.3,91.01 v1(75.99,91.32)
FB_CAL_PU_GND: length 2.4
  TOP w0.356: GPU1.C24 74.74,90.9 v1(75.15,90.49)
  BOTTOM w0.508: v1(75.15,90.49) 75.08,90.42 R687.1 74.39,89.65 v2(74.2,89.46)
FB_CAL_TERM_GND: length 3.4
  TOP w0.152: GPU1.B25 73.9,90.1 73.49,89.69 73.49,89.08 73.21,88.8 v1(73.21,88.65)
  BOTTOM w0.508: R691.1 73.88,88.65 v1(73.21,88.65) 73.21,88.03 73.19,88 v2(73.19,87.88)
FB_PLLAVDD: length 26.7
  TOP w0.305: GPU1.P22 76.34,100.05 v1(76.73,100.44)
  TOP w0.356: GPU1.F16 81.37,93.34 v1(81.76,93.74) ; v1(76.81,94.7) 76.68,94.7 GPU1.H22
  BOTTOM w0.381: C488.1 77.42,99.76 v1(76.73,100.44)
  BOTTOM w0.508: v1(76.81,94.7) 76.96,94.55 C512.1
  BOTTOM w0.559: v1(81.76,93.74) 82.72,93.74 83.54,94.55 C511.1 83.85,94.86 84.56,95.57 90.09,95.57 90.62,96.1 91.18,96.1 91.77,95.5 v2(92.36,95.5) 93.23,95.5 94.12,94.61 C515.1
  BOTTOM w0.635: L23.1 95.41,100.2 96.36,99.25 96.36,95.77 C507.1 95.11,95.2 94.52,94.61 C515.1
FB_VREF: length 4.8
  TOP w0.127: GPU1.D23 75.55,91.74 v1(75.95,92.14)
  BOTTOM w0.127: TP75.1 76.11,88.77 75.67,89.21 75.67,89.48 75.57,89.58 75.57,91.76 v1(75.95,92.14)
FBA_CMD0: length 25.1
  TOP w0.102: VRAM2.G12 59.04,87.72 58.65,88.1 v1(58.65,88.11) ; GPU1.C27 71.88,90.9 v1(71.53,90.55)
  L3 w0.127: v1(58.65,88.11) 59.14,87.62 59.14,87.43 60.49,86.08 64.24,86.08 64.76,85.56 73.59,85.56 74,85.97 74,87.74 73.87,87.87 73.87,89.48 72.8,90.55 v1(71.53,90.55)
  BOTTOM w0.102: VRAM2.G12 59.04,87.72 58.65,88.1 v1(58.65,88.11)
FBA_CMD1: length 27.1
  TOP w0.102: GPU1.C26 72.72,90.52 72.2,90.52 71.72,90.04 v1(71.15,90.04) ; VRAM2.H10 58.24,89.3 v1(58.62,88.91)
  L3 w0.127: v1(58.62,88.91) 59.06,89.34 60.03,89.34 60.04,89.33 60.39,89.33 60.4,89.34 61.21,89.34 61.55,89 61.55,87.23 61.74,87.03 65.99,87.03 67.1,85.93 73.44,85.93 73.63,86.12 73.63,89.28 72.87,90.04 v1(71.15,90.04)
  BOTTOM w0.102: VRAM2.H10 58.34,89.21 58.34,89.2 v1(58.62,88.91)
FBA_CMD2: length 27.9
  TOP w0.102: v1(57.83,88.91) 58.23,88.51 VRAM2.H11 ; v1(74.31,92.15) 74.7,92.54 GPU1.E24
  L3 w0.127: v1(57.83,88.91) 58.23,88.51 58.23,87.51 58.22,87.49 58.22,86.34 58.46,86.1 59.44,86.1 59.71,85.83 64.13,85.83 64.76,85.19 73.79,85.19 74.37,85.76 74.37,87.74 74.1,88.01 74.1,91.94 v1(74.31,92.15)
  BOTTOM w0.102: v1(57.83,88.91) 58.23,88.51 VRAM2.H11
FBA_CMD3: length 31.4
  TOP w0.102: GPU1.F24 74.7,93.34 v1(74.3,92.94) ; v1(57.06,88.91) 57.04,88.91 56.64,88.51 VRAM2.K11
  L3 w0.127: v1(57.06,88.91) 57.47,89.33 58.12,89.33 59,90.21 61.29,90.21 61.81,89.69 61.81,87.55 62.06,87.3 66.25,87.3 67.25,86.3 72.91,86.3 73.26,86.65 73.26,87.78 72.37,88.67 71.71,88.67 70.73,89.65 70.73,90.34 71.91,91.52 72.34,91.52 73.06,92.25 73.06,92.31 73.69,92.94 v1(74.3,92.94)
  BOTTOM w0.102: VRAM2.K11 56.64,88.51 57.04,88.91 v1(57.06,88.91)
FBA_CMD4: length 27.8
  TOP w0.102: VRAM2.K10 56.64,89.75 v1(56.52,89.87) ; GPU1.D27 70.65,91.7 v1(69.63,90.68)
  L3 w0.127: v1(56.52,89.87) 56.52,89.92 57.32,90.72 61.79,90.72 62.31,90.2 63.58,90.2 63.89,89.89 63.89,88.82 64.04,88.67 64.47,88.67 65.11,88.03 66.65,88.03 67.65,87.03 72.23,87.03 72.42,87.22 72.42,87.6 72.16,87.87 71.43,87.87 71.16,88.14 70.07,89.23 70.07,90.23 v1(69.63,90.68)
  BOTTOM w0.102: v1(56.52,89.87) 56.64,89.75 VRAM2.K10
FBA_CMD5: length 30.8
  TOP w0.102: v1(56.24,88.11) 55.84,87.72 VRAM2.L12 ; v1(70.39,90.68) 71.05,91.34 72.74,91.34 GPU1.D26
  L3 w0.127: v1(56.24,88.11) 56.63,88.51 56.63,89.09 56.98,89.44 56.98,90.02 57.42,90.46 61.4,90.46 62.06,89.8 62.06,87.66 62.17,87.55 64.6,87.55 64.71,87.66 66.4,87.66 67.4,86.66 72.69,86.66 72.89,86.87 72.89,87.57 72.22,88.24 71.58,88.24 70.44,89.38 70.44,90.63 v1(70.39,90.68)
  BOTTOM w0.102: v1(56.24,88.11) 55.84,87.72 VRAM2.L12
FBA_CMD6: length 29.4
  TOP w0.102: VRAM2.K4 56.64,94.11 v1(57.04,94.51) ; v1(71.92,92.33) 72.44,92.85 72.92,92.85 73.03,92.96 73.46,92.96 GPU1.F25
  L3 w0.127: v1(57.04,94.51) 56.63,94.11 56.63,92.66 58.09,91.21 61.88,91.21 62.52,90.58 63.79,90.58 64.3,90.07 64.3,89.41 65.3,88.4 66.83,88.4 67.83,87.4 70.39,87.4 70.67,87.68 70.67,88.11 69.17,89.61 69.17,90.81 69.46,91.1 70.68,91.1 v1(71.92,92.33)
  BOTTOM w0.102: VRAM2.K4 57.04,94.51 v1(57.04,94.51)
FBA_CMD7: length 27.1
  TOP w0.102: v1(71.28,92.33) 71.28,92.81 71.53,93.06 72.76,93.06 GPU1.F26 ; v1(57.05,92.84) 57.05,92.84 56.64,93.26 VRAM2.K5
  L3 w0.127: v1(57.05,92.84) 57.06,92.84 57.06,92.72 58.26,91.52 62.16,91.52 62.72,90.96 64.24,90.96 64.68,90.53 64.68,89.61 65.52,88.77 67.93,88.77 68.05,88.64 68.05,87.9 68.18,87.77 69.87,87.77 69.98,87.88 69.98,88.24 69.86,88.37 68.93,88.37 68.8,88.49 68.8,90.97 69.26,91.43 70.38,91.43 v1(71.28,92.33)
  BOTTOM w0.102: v1(57.05,92.84) 57.05,92.84 56.64,93.26 VRAM2.K5
FBA_CMD8: length 29.8
  TOP w0.102: v1(75.1,92.96) 75.5,93.36 GPU1.F23 ; v1(57.05,93.72) 57.44,94.1 VRAM2.J4
  L3 w0.127: v1(57.05,93.72) 57.05,93.7 57.47,93.28 57.47,92.66 58.34,91.8 62.44,91.8 62.9,91.34 64.75,91.34 65.06,91.03 65.06,89.79 65.71,89.14 67.23,89.14 67.36,89.26 67.36,91.21 67.48,91.34 67.74,91.34 67.86,91.21 67.86,89.28 67.99,89.15 68.26,89.15 68.38,89.28 68.38,91.11 69.07,91.8 70.1,91.8 71.11,92.81 72.99,92.81 73.54,93.36 74.7,93.36 v1(75.1,92.96)
  BOTTOM w0.102: VRAM2.J4 57.44,94.1 v1(57.05,93.72)
FBA_CMD9: length 30
  TOP w0.102: v1(75.94,93.81) 76.33,94.2 GPU1.G22 ; VRAM2.J5 57.44,93.29 v1(57.89,92.84)
  L3 w0.127: v1(57.89,92.84) 58.59,92.14 62.68,92.14 63.1,91.72 63.94,91.72 64.24,92.02 64.24,92.53 64.37,92.66 64.57,92.66 64.7,92.53 64.7,91.87 64.83,91.74 65.08,91.74 65.21,91.87 65.21,92.71 65.34,92.84 65.59,92.84 65.72,92.71 65.72,91.11 65.45,90.84 65.45,90.13 66.07,89.51 66.76,89.51 66.99,89.74 66.99,92.04 67.11,92.16 67.43,92.16 67.56,92.04 67.56,91.85 67.68,91.72 67.94,91.72 68.07,91.85 68.07,92.04 68.19,92.16 69.97,92.16 71.06,93.26 72.64,93.26 73.01,93.62 73.93,93.62 74.41,94.11 75.64,94.11 v1(75.94,93.81)
  BOTTOM w0.102: v1(57.89,92.84) 57.44,93.29 VRAM2.J5
FBA_CMD10: length 29
  TOP w0.102: GPU1.G23 75.49,94.2 v1(75.09,94.6) ; v1(57.83,93.72) 58.23,94.11 VRAM2.H4
  L3 w0.127: v1(57.83,93.72) 58.12,94.01 58.35,94.01 58.48,93.88 58.48,93.4 58.61,93.27 58.87,93.27 59,93.4 59,94.31 59.03,94.34 59.03,94.7 60.07,95.73 62.27,95.73 62.4,95.61 62.4,95.15 62.53,95.02 62.78,95.02 62.91,95.15 62.91,95.61 63.03,95.73 63.29,95.73 63.42,95.61 63.42,95.15 63.54,95.02 63.8,95.02 63.92,95.15 63.92,95.61 64.05,95.73 64.3,95.73 64.43,95.61 64.43,95.24 64.64,95.03 66.21,95.03 66.48,94.77 66.48,93.22 66.8,92.9 70,92.9 71.13,94.03 71.8,94.03 72.02,94.25 72.02,94.95 72.14,95.07 72.43,95.07 72.55,94.95 72.55,94.54 72.68,94.41 72.94,94.41 73.06,94.54 73.06,95.12 73.19,95.25 74.79,95.25 75.09,94.94 v1(75.09,94.6)
  BOTTOM w0.102: v1(57.83,93.72) 58.23,94.11 VRAM2.H4
FBA_CMD11: length 28.5
  TOP w0.102: v1(58.65,92.84) 58.24,93.25 VRAM2.H5 ; v1(74.32,94.62) 74.7,94.25 GPU1.G24
  L3 w0.127: v1(74.32,94.62) 73.73,94.03 72.67,94.03 72.31,93.68 71.1,93.68 69.96,92.53 66.78,92.53 66.62,92.37 66.62,90.04 66.49,89.92 66.23,89.92 66.1,90.04 66.1,94.46 65.97,94.59 65.58,94.59 65.45,94.46 65.45,93.46 65.26,93.27 64.42,93.27 63.54,92.39 61.39,92.39 61.26,92.52 61.26,93.12 61.14,93.24 60.88,93.24 60.75,93.12 60.75,92.52 60.63,92.39 59.1,92.39 v1(58.65,92.84)
  BOTTOM w0.102: v1(58.65,92.84) 58.24,93.25 VRAM2.H5
FBA_CMD12: length 28.2
  TOP w0.102: v1(58.61,94.51) 59.01,94.91 VRAM2.G3 ; GPU1.F27 72.22,93.32 69.78,93.32 v1(69.38,93.73)
  L3 w0.127: v1(58.61,94.51) 58.28,94.85 58.28,95.38 58.4,95.5 58.86,95.5 58.99,95.63 58.99,95.94 58.86,96.06 58.4,96.06 58.28,96.19 58.28,96.54 58.4,96.66 59.71,96.66 59.93,96.44 59.93,96.25 60.07,96.1 60.65,96.1 60.78,96.23 60.78,96.6 60.9,96.72 61.16,96.72 61.28,96.6 61.28,96.23 61.41,96.1 61.67,96.1 61.79,96.23 61.79,96.6 61.92,96.72 62.17,96.72 62.3,96.6 62.3,96.23 62.43,96.1 62.68,96.1 62.81,96.23 62.81,96.6 62.94,96.72 63.19,96.72 63.32,96.6 63.32,96.23 63.44,96.1 63.7,96.1 63.82,96.23 63.82,96.6 63.95,96.72 64.21,96.72 64.33,96.6 64.33,96.23 64.46,96.1 64.7,96.1 64.83,95.97 64.83,95.55 64.96,95.43 65.21,95.43 65.34,95.55 65.34,95.97 65.46,96.1 65.68,96.1 66.85,94.93 66.85,93.4 66.97,93.27 67.25,93.27 67.36,93.37 67.36,94.01 67.48,94.13 67.74,94.13 67.86,94.01 67.86,93.4 67.99,93.27 68.26,93.27 68.38,93.4 68.38,93.88 68.51,94.01 69.1,94.01 v1(69.38,93.73)
  BOTTOM w0.102: v1(58.61,94.51) 59.01,94.91 VRAM2.G3
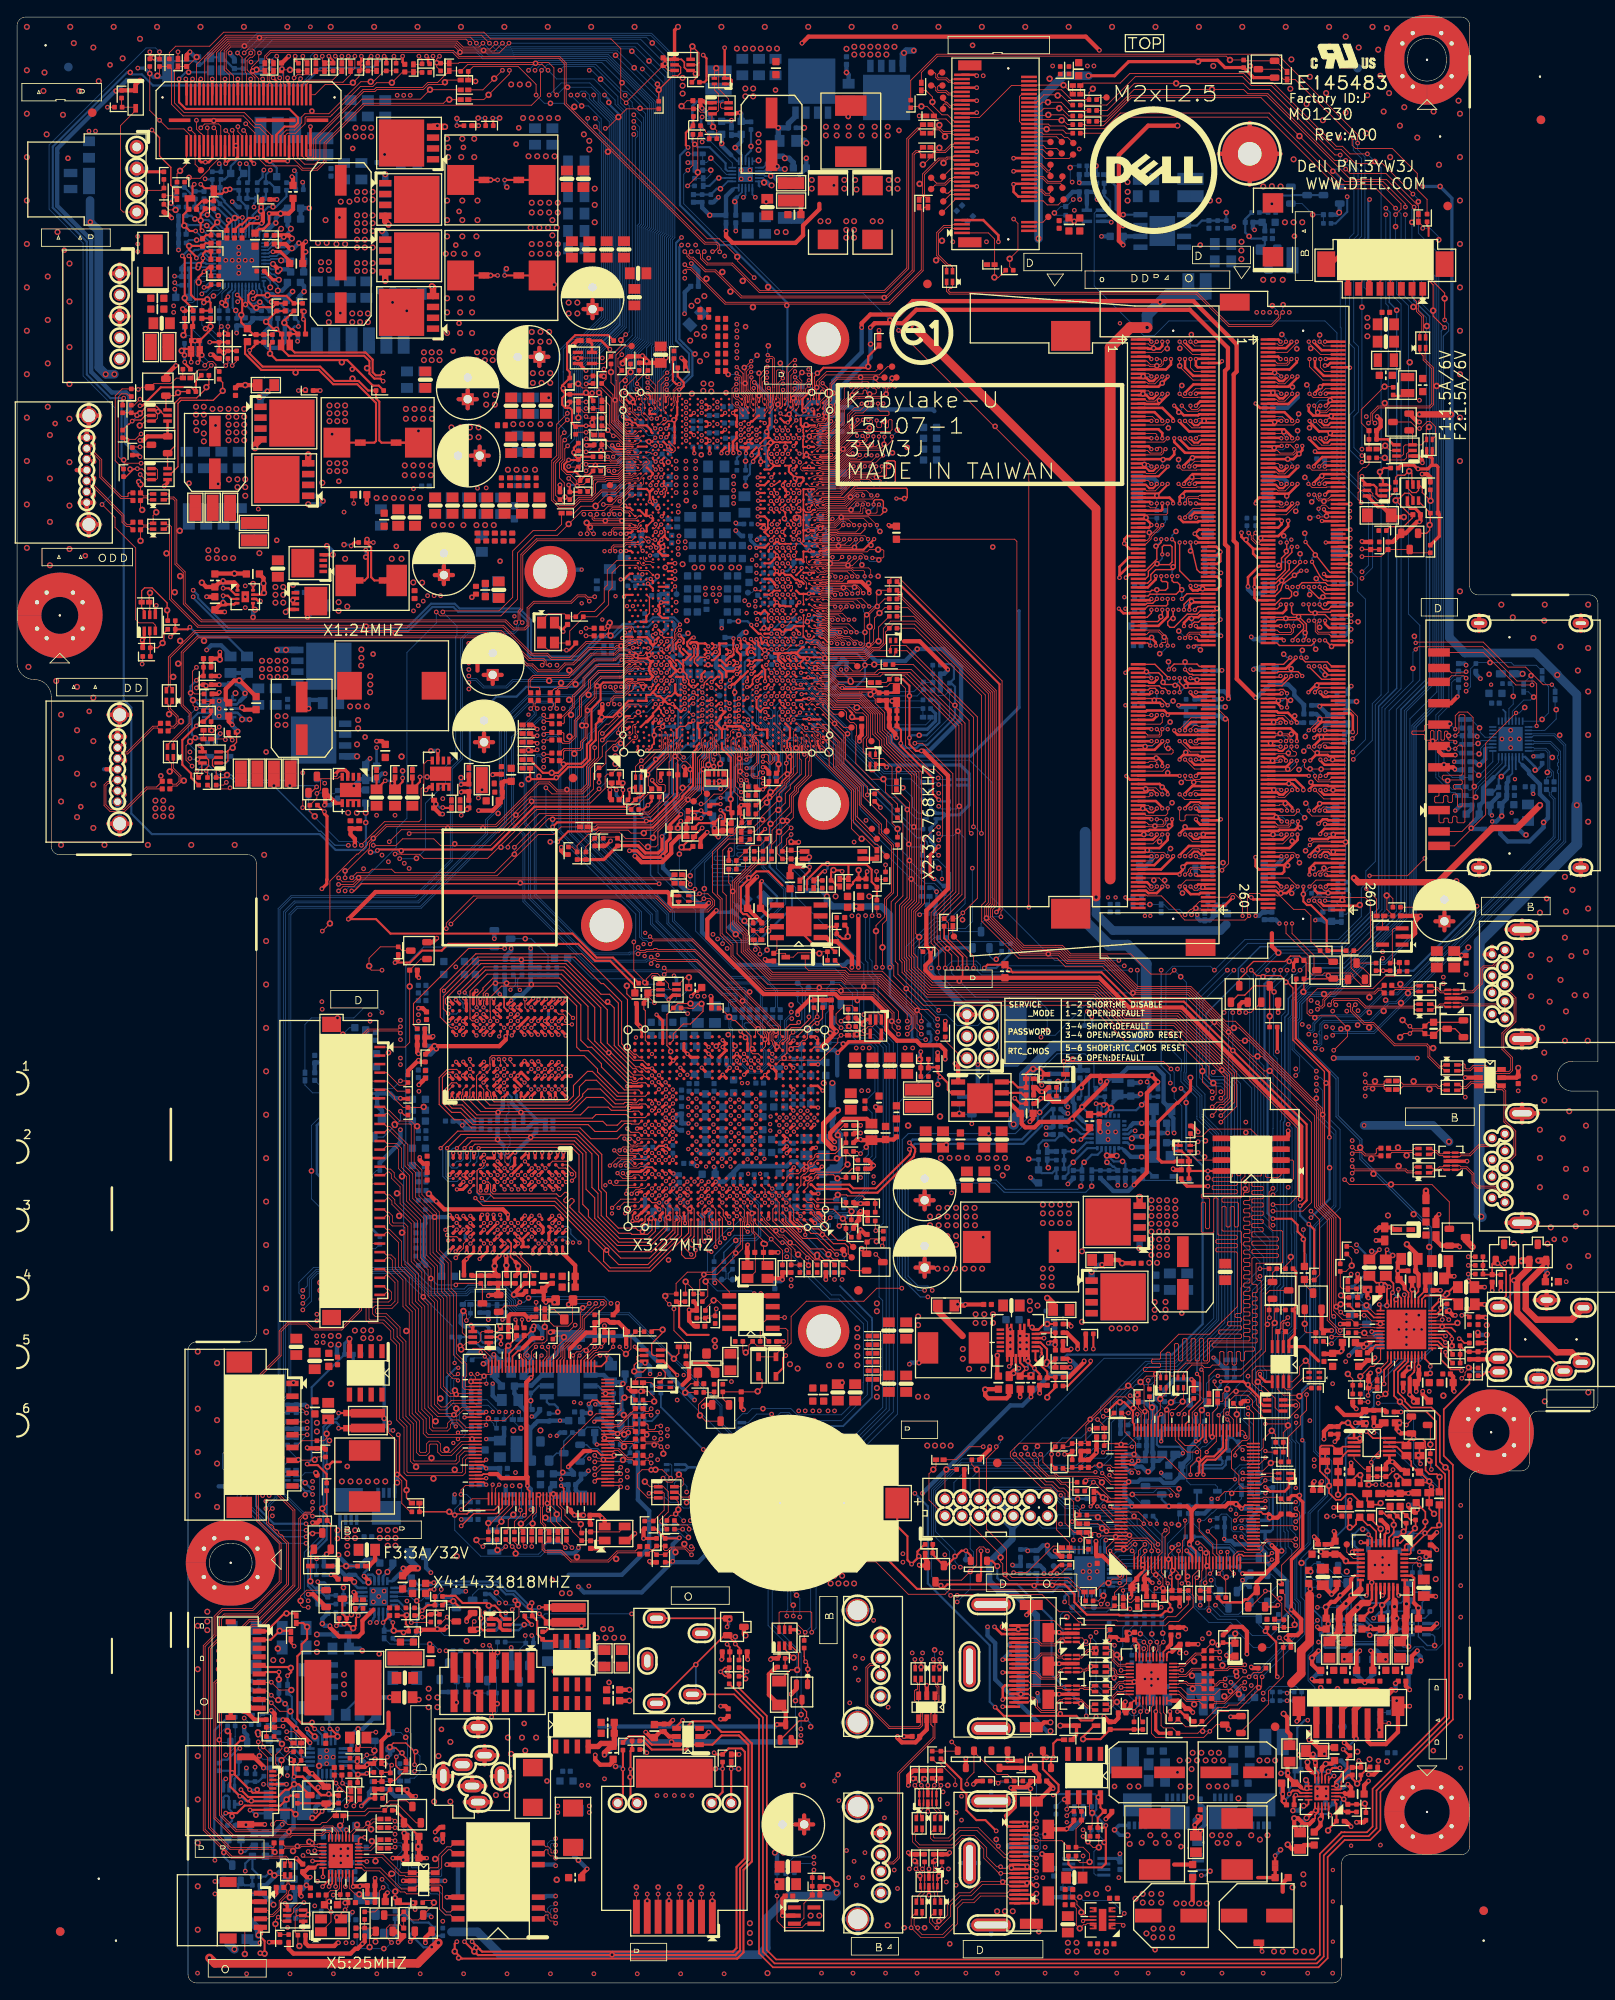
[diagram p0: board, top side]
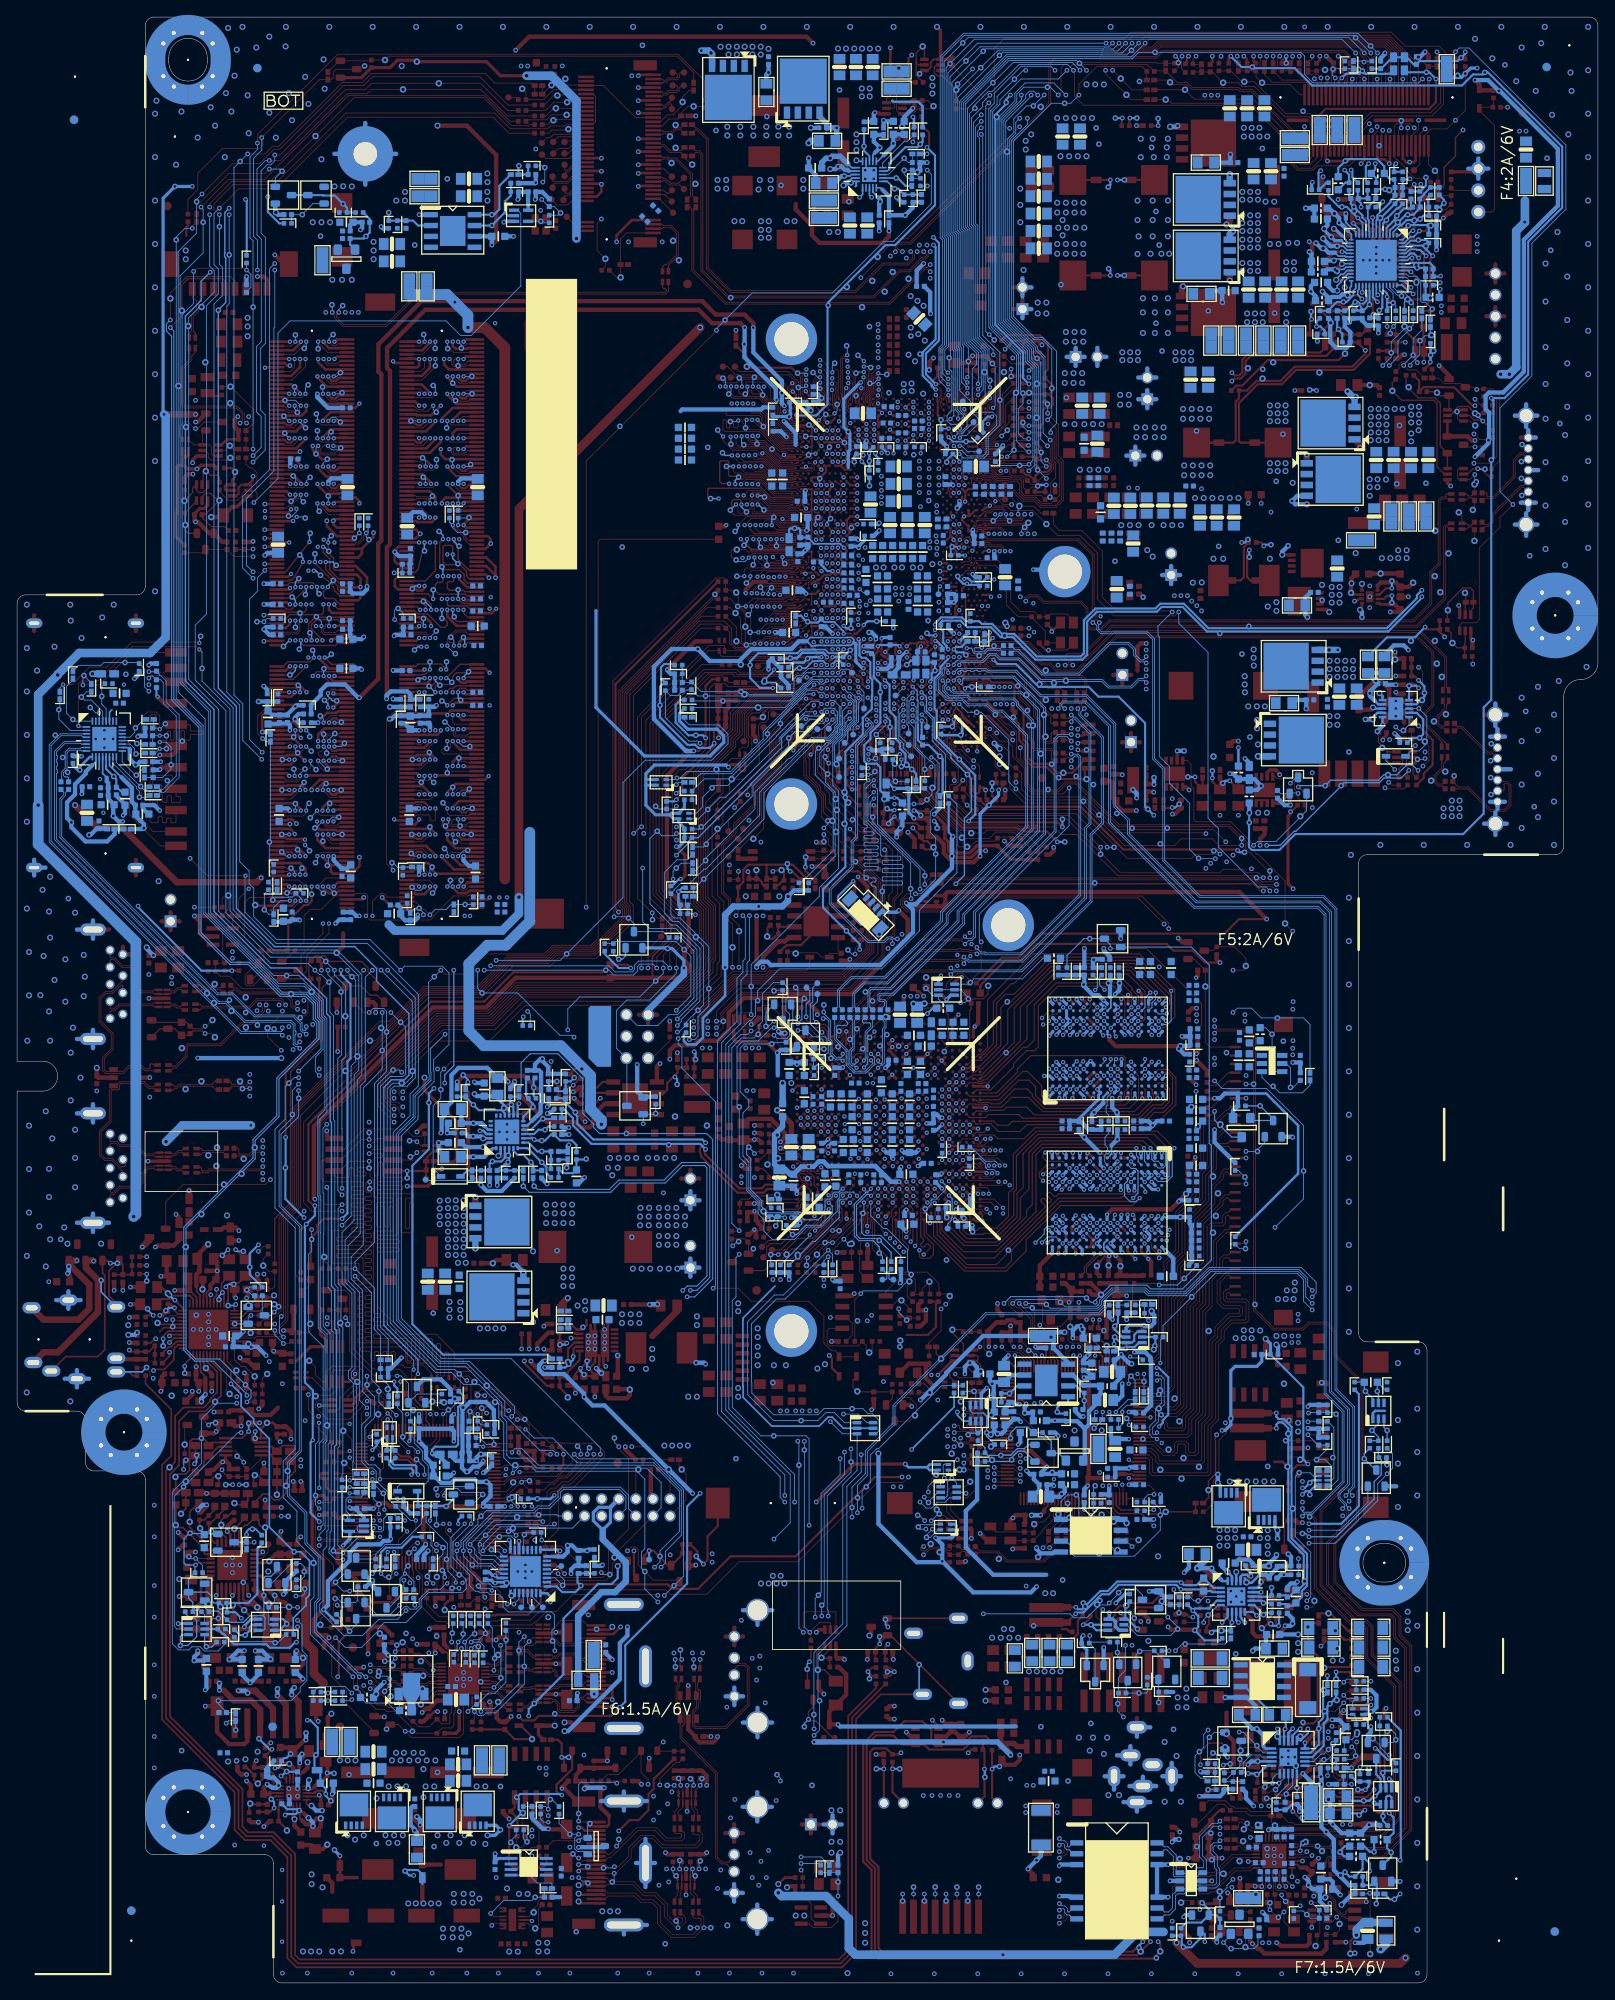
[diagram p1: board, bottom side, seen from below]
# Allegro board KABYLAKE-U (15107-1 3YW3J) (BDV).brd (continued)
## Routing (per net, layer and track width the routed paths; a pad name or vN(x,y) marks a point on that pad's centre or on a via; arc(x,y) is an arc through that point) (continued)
FBA_CMD13: length 32.6
  TOP w0.102: VRAM2.J2 57.09,96.06 57.09,96.87 v1(57.38,97.16) ; GPU1.G25 73.56,93.86 70.27,93.86 v1(70.14,93.73)
  L3 w0.127: v1(57.38,97.16) 57.38,98.32 57.56,98.5 57.76,98.5 57.89,98.37 57.89,97.74 58.02,97.61 58.27,97.61 58.4,97.74 58.4,98.37 58.52,98.5 58.78,98.5 58.91,98.37 58.91,97.74 59.03,97.61 59.29,97.61 59.41,97.74 59.41,98.37 59.54,98.5 59.79,98.5 59.92,98.37 59.92,97.74 60.05,97.61 60.3,97.61 60.43,97.74 60.43,98.37 60.56,98.5 60.81,98.5 60.94,98.37 60.94,97.74 61.06,97.61 61.32,97.61 61.45,97.74 61.45,98.37 61.57,98.5 61.83,98.5 61.95,98.37 61.95,97.74 62.08,97.61 64.81,97.61 68.02,94.4 69.46,94.4 v1(70.14,93.73)
  BOTTOM w0.102: PR235.1 57.25,99.38 57.69,98.93 57.69,98.04 57.38,97.73 v1(57.38,97.16) 57.77,96.78 57.77,96.27 57.65,95.93 VRAM2.J2
FBA_CMD14: length 32.1
  TOP w0.102: v1(57.04,95.31) 57.44,94.92 VRAM2.J3 ; v1(70.26,94.74) 70.87,94.13 72.23,94.13 GPU1.G27
  L3 w0.127: v1(70.26,94.74) 70.24,94.77 68.24,94.77 64.14,98.87 63.96,98.87 63.83,98.74 63.83,98.12 63.71,97.99 63.45,97.99 63.33,98.12 63.33,98.74 63.2,98.87 62.95,98.87 62.82,98.74 62.82,98.12 62.69,97.99 62.44,97.99 62.31,98.12 62.31,98.74 62.18,98.87 55.51,98.87 55.38,98.74 55.38,98.48 55.51,98.35 56.81,98.35 56.96,98.2 56.96,95.39 v1(57.04,95.31)
  BOTTOM w0.102: PR227.2 72.3,96.46 71.69,95.84 71.69,95.46 71.64,95.41 71.64,95.4 71.41,95.17 70.7,95.17 v1(70.26,94.74) ; VRAM2.J3 57.44,94.92 v1(57.04,95.31)
FBA_CMD15: length 29.8
  TOP w0.102: VRAM2.L3 55.84,94.91 v1(56.23,94.51) ; GPU1.G26 72.76,94.54 72.14,94.54 71.93,94.34 71.31,94.34 v1(70.9,94.74)
  L3 w0.127: v1(56.23,94.51) 55.19,95.56 55.19,98.06 54.83,98.42 53.45,98.42 53.32,98.55 53.32,99.11 53.45,99.24 64.29,99.24 68.37,95.16 70.48,95.16 v1(70.9,94.74)
  BOTTOM w0.102: v1(56.23,94.51) 55.84,94.91 VRAM2.L3
FBA_CMD16: length 35.5
  TOP w0.102: v1(58.59,112.54) 58.99,112.94 VRAM1.L12 ; v1(72.7,98.75) 74.31,98.75 GPU1.M24
  L3 w0.127: v1(58.59,112.54) 59.37,113.32 65.93,113.32 67.3,111.95 67.3,111.78 66.53,111 66.53,110.83 66.71,110.65 66.88,110.65 67.66,111.42 67.84,111.42 68.02,111.24 68.02,111.06 67.24,110.29 67.24,110.11 67.42,109.93 67.6,109.93 68.37,110.7 68.55,110.7 68.73,110.52 68.73,110.34 67.96,109.57 67.96,109.39 68.14,109.21 68.32,109.21 69.09,109.98 69.27,109.98 70.9,108.35 70.9,101.05 71.83,100.12 71.83,99.63 v1(72.7,98.75)
  BOTTOM w0.102: VRAM1.L12 58.99,112.94 v1(58.59,112.54)
FBA_CMD17: length 39.4
  TOP w0.102: v1(57.89,110.86) 58.19,111.16 VRAM1.K10 ; v1(75.9,98.73) 75.54,98.37 75.51,98.37 GPU1.M23
  L3 w0.127: v1(57.89,110.86) 57.54,111.21 56.95,111.21 56.59,111.57 56.59,112.14 56.71,112.27 56.71,115.21 57.03,115.53 57.03,116.08 57.57,116.62 64.14,116.62 73.07,107.68 73.07,99.41 73.35,99.13 75.5,99.13 v1(75.9,98.73)
  BOTTOM w0.102: v1(57.89,110.86) 58.19,111.16 VRAM1.K10
FBA_CMD18: length 36.2
  TOP w0.102: VRAM1.K11 58.18,112.14 v1(57.78,111.75) ; GPU1.K24 74.7,96.71 v1(74.31,97.1)
  L3 w0.127: v1(57.78,111.75) 59.13,110.4 66.42,110.4 68.38,108.43 68.59,108.43 69.26,109.1 69.44,109.1 69.62,108.92 69.62,108.75 68.83,107.96 68.83,107.78 69.01,107.6 69.19,107.6 69.98,108.39 70.16,108.39 70.34,108.21 70.34,108.03 69.55,107.24 69.55,107.06 70.49,106.12 70.49,102.78 70.37,102.65 69.6,102.65 69.48,102.52 69.48,102.27 69.6,102.14 70.37,102.14 70.49,102.01 70.49,101.76 70.37,101.63 69.6,101.63 69.48,101.51 69.48,101.25 69.6,101.13 70.37,101.13 70.49,101 70.49,100.05 71.01,99.53 71.51,99.53 72.16,98.88 72.16,98.7 73.2,97.66 73.74,97.66 v1(74.31,97.1)
  BOTTOM w0.102: v1(57.78,111.75) 58.18,112.14 VRAM1.K11
FBA_CMD19: length 36
  TOP w0.102: v1(57,111.75) 56.61,112.14 VRAM1.H11 ; v1(75.11,97.1) 75.5,96.7 GPU1.K23
  L3 w0.127: v1(75.11,97.1) 74.62,97.58 74.47,97.58 72.6,99.44 72.47,99.44 72.13,99.78 72.13,107.99 64.37,115.75 57.69,115.75 57,115.06 v1(57,111.75)
  BOTTOM w0.102: VRAM1.H11 56.61,112.14 v1(57,111.75)
FBA_CMD20: length 31
  TOP w0.102: v1(71.7,98.75) 71.91,98.75 GPU1.M27 ; VRAM1.H10 56.59,110.91 v1(56.42,110.74)
  L3 w0.127: v1(71.7,98.75) 71.7,98.75 71.24,99.21 70.83,99.21 69.07,100.96 69.07,103.3 69.2,103.43 69.96,103.43 70.09,103.55 70.09,103.81 69.96,103.93 69.2,103.93 69.07,104.06 69.07,104.31 69.2,104.44 69.96,104.44 70.09,104.57 70.09,104.82 69.96,104.95 69.2,104.95 69.07,105.08 69.07,105.33 69.2,105.46 69.96,105.46 70.09,105.58 70.09,105.84 69.96,105.97 69.2,105.97 69.07,106.09 69.07,106.95 66.02,110.01 57.16,110.01 v1(56.42,110.74)
  BOTTOM w0.102: VRAM1.H10 56.59,110.91 v1(56.42,110.74)
FBA_CMD21: length 32.6
  TOP w0.102: GPU1.M26 72.91,98.17 72.6,98.17 72.44,98.02 72.16,98.02 72.16,98.02 71.84,98.02 v1(71.07,98.79) ; v1(56.18,112.54) 55.79,112.94 VRAM1.G12
  L3 w0.127: v1(56.18,112.54) 56,112.36 56,110.57 56.82,109.75 65.75,109.75 68.71,106.8 68.71,103.95 68.58,103.82 67.83,103.82 67.7,103.69 67.7,103.44 67.83,103.31 68.58,103.31 68.71,103.18 68.71,102.93 68.58,102.8 67.83,102.8 67.7,102.68 67.7,102.42 67.83,102.29 68.58,102.29 68.71,102.17 68.71,100.72 70.54,98.88 70.97,98.88 v1(71.07,98.79)
  BOTTOM w0.102: VRAM1.G12 55.79,112.94 v1(56.18,112.54)
FBA_CMD22: length 32.4
  TOP w0.102: v1(56.99,106.94) 56.59,106.54 VRAM1.H4 ; v1(70.52,97.41) 70.92,97.82 72.07,97.82 72.07,97.81 72.53,97.81 72.63,97.92 73.46,97.92 GPU1.M25
  L3 w0.127: v1(56.99,106.94) 59.03,106.94 60.49,105.49 65.18,105.49 65.31,105.36 65.31,102.59 65.18,102.46 61.35,102.46 61.22,102.34 61.22,102.03 61.35,101.9 65.31,101.9 69.39,97.83 70.06,97.83 70.48,97.41 v1(70.52,97.41)
  BOTTOM w0.102: v1(56.99,106.94) 56.99,106.94 VRAM1.H4
FBA_CMD23: length 31.6
  TOP w0.102: GPU1.K26 72.76,97.02 72.1,97.02 72.08,97 71.56,97 v1(71.15,97.41) ; v1(56.38,108.08) 56.59,107.87 VRAM1.H5
  L3 w0.127: v1(56.38,108.08) 57.05,107.4 58.28,107.4 59.21,108.33 63.95,108.33 64.08,108.2 64.08,107.59 64.2,107.47 64.46,107.47 64.58,107.59 64.58,108.2 64.71,108.33 65.41,108.33 65.72,108.03 65.72,107.3 65.59,107.18 64.96,107.18 64.83,107.05 64.83,106.8 64.96,106.67 65.59,106.67 65.72,106.54 65.72,102.97 65.84,102.84 66.4,102.84 66.53,102.71 66.53,102.46 66.4,102.33 65.84,102.33 65.72,102.2 65.72,102.03 69.69,98.06 70.51,98.06 v1(71.15,97.41)
  BOTTOM w0.102: v1(56.38,108.08) 56.59,107.87 VRAM1.H5
FBA_CMD24: length 41.2
  TOP w0.102: VRAM1.J4 57.37,106.54 v1(56.99,106.16) ; v1(75.9,96.28) 76.3,96.68 GPU1.K22
  L3 w0.127: v1(56.99,106.16) 57.39,106.55 58.76,106.55 59,106.31 59,105.96 58.97,105.93 58.97,105.16 59.53,104.6 59.53,102.65 58.86,101.98 53.04,101.98 52.79,101.73 52.79,101.35 53.06,101.08 65.09,101.08 69.37,96.8 72.17,96.8 73.44,95.53 75.15,95.53 v1(75.9,96.28)
  BOTTOM w0.102: v1(56.99,106.16) 57.01,106.16 VRAM1.J4
FBA_CMD25: length 35.6
  TOP w0.102: VRAM1.J5 57.39,107.41 57.01,107.78 v1(57.01,108.08) ; v1(75.11,96.28) 75.5,95.88 GPU1.J23
  L3 w0.127: v1(75.11,96.28) 74.68,95.86 73.86,95.86 72.64,97.07 72.64,97.27 71.87,98.04 70.9,98.04 70.52,98.42 69.85,98.42 66.91,101.36 66.91,103.28 66.78,103.41 66.23,103.41 66.1,103.54 66.1,103.79 66.23,103.92 66.78,103.92 66.91,104.05 66.91,104.3 66.78,104.43 66.23,104.43 66.1,104.55 66.1,104.81 66.23,104.93 66.78,104.93 66.91,105.06 66.91,105.32 66.78,105.44 66.23,105.44 66.1,105.57 66.1,105.82 66.23,105.95 66.78,105.95 66.91,106.08 66.91,106.33 66.78,106.46 66.23,106.46 66.1,106.59 66.1,106.84 66.23,106.97 66.78,106.97 66.91,107.09 66.91,107.55 65.73,108.74 59.06,108.74 57.98,107.66 57.43,107.66 v1(57.01,108.08)
  BOTTOM w0.102: VRAM1.J5 57.39,107.41 57.01,107.78 v1(57.01,108.08)
FBA_CMD26: length 38.2
  TOP w0.102: VRAM1.K4 58.19,106.53 v1(57.79,106.13) ; GPU1.J25 73.71,95.88 73.34,95.5 72.93,95.5 72.76,95.33 71.58,95.33 v1(71.28,95.63)
  L3 w0.127: v1(71.28,95.63) 70.62,96.29 70.31,96.29 70.05,96.55 69.11,96.55 64.94,100.71 52.91,100.71 52.45,101.17 51.28,101.17 51.14,101.31 51.14,101.93 51.44,102.23 57.72,102.23 58.16,102.68 58.16,105.76 v1(57.79,106.13)
  BOTTOM w0.102: VRAM1.K4 57.79,106.14 v1(57.79,106.13)
FBA_CMD27: length 33.1
  TOP w0.102: GPU1.J24 74.7,95.88 v1(74.3,96.28) ; v1(57.71,108.08) 57.71,107.81 VRAM1.K5
  L3 w0.127: v1(57.71,108.08) 58.76,109.12 65.87,109.12 67.29,107.69 67.29,107.02 67.42,106.89 68.08,106.89 68.21,106.77 68.21,106.51 68.08,106.38 67.42,106.38 67.29,106.26 67.29,106 67.42,105.88 68.08,105.88 68.21,105.75 68.21,105.5 68.08,105.37 67.42,105.37 67.29,105.24 67.29,104.99 67.42,104.86 68.08,104.86 68.21,104.73 68.21,104.48 68.08,104.35 67.42,104.35 67.29,104.23 67.29,101.57 70.21,98.65 70.61,98.65 70.97,98.3 71.94,98.3 72.93,97.31 72.93,97.11 73.76,96.28 v1(74.3,96.28)
  BOTTOM w0.102: VRAM1.K5 57.71,107.81 v1(57.71,108.08)
FBA_CMD28: length 30.9
  TOP w0.102: GPU1.K27 72.18,96.8 70.49,96.8 v1(69.88,97.41) ; VRAM1.L3 v1(59.39,105.34)
  L3 w0.127: v1(69.88,97.41) 69.28,97.41 65.24,101.45 59.88,101.45 59.75,101.57 59.75,101.85 59.88,101.98 60.66,101.98 60.79,102.11 60.79,102.41 60.66,102.54 60.05,102.54 59.93,102.67 59.93,102.96 60.05,103.09 64.65,103.09 64.78,103.21 64.78,104.83 64.65,104.96 59.77,104.96 v1(59.39,105.34)
  BOTTOM w0.102: VRAM1.L3 v1(59.39,105.34)
FBA_CMD29: length 42.9
  TOP w0.102: v1(69.38,95.63) 70.27,96.52 71.97,96.52 72.16,96.34 73.56,96.34 GPU1.K25 ; v1(56.99,104.55) 56.99,104.56 57.36,104.94 VRAM1.J2
  L3 w0.127: v1(56.99,104.55) 56.42,103.99 50.35,103.99 49.99,103.63 49.99,99.92 50.73,99.19 52.2,99.19 52.62,99.61 64.45,99.61 68.42,95.63 v1(69.38,95.63)
  BOTTOM w0.102: PR221.1 57.25,101.54 57.56,101.85 57.56,102.49 57.44,102.62 57.44,103.62 56.99,104.07 v1(56.99,104.55) 56.99,104.56 57.36,104.94 VRAM1.J2
FBA_CMD30: length 42.3
  TOP w0.102: VRAM1.J3 57.39,105.73 56.99,105.33 v1(56.99,105.31) ; v1(70.01,95.63) 70.7,96.32 71.86,96.32 GPU1.J27
  L3 w0.127: v1(70.01,95.63) 69.59,96.05 68.52,96.05 64.6,99.97 52.47,99.97 52.05,99.56 50.88,99.56 50.36,100.08 50.36,102.53 50.83,103 57.18,103 57.46,103.28 57.46,104.84 v1(56.99,105.31)
  BOTTOM w0.102: v1(56.99,105.31) 56.99,105.33 57.39,105.73 VRAM1.J3 ; v1(70.01,95.63) 70.52,96.14 71.69,96.14 73.35,97.79 PR222.2
FBA_CMD31: length 40.5
  TOP w0.102: VRAM1.G3 55.79,105.74 v1(56.19,106.14) ; GPU1.J26 72.8,95.88 72.46,95.54 72.16,95.54 71.62,96.07 71.09,96.07 v1(70.65,95.63)
  L3 w0.127: v1(70.65,95.63) 69.96,96.32 68.78,96.32 64.75,100.34 52.76,100.34 52.3,100.8 51.84,100.8 51.63,100.6 51.63,100.18 51.42,99.96 51,99.96 50.73,100.23 50.73,102.36 50.99,102.62 57.31,102.62 57.82,103.12 57.82,105.08 57.16,105.73 56.59,105.73 v1(56.19,106.14)
  BOTTOM w0.102: VRAM1.G3 56.19,106.14 v1(56.19,106.14)
FBA_DBI0: length 19.8
  TOP w0.127: VRAM2.D2 v1(61.84,95.31) ; v1(78.47,91.31) 78.86,91.7 GPU1.D19
  L4 w0.102: v1(78.47,91.31) 78.09,91.69 77.45,91.69 76.38,92.77 76.38,93.1 76.08,93.4 75.34,93.4 74.88,93.87
  L4 w0.165: 74.88,93.87 70.62,93.87 70.32,94.16 67.26,94.16 65.93,95.5 62.02,95.5 v1(61.84,95.31)
FBA_DBI1: length 32.6
  TOP w0.127: v1(83.43,92.06) 83.07,91.7 GPU1.D14
  L4 w0.165: v1(61.83,86.51) 62.39,85.95 63.92,85.95 64.36,85.51 64.36,83.37 64.9,82.83 79.2,82.83 83.78,87.41 83.78,90.02 83.6,90.2 83.6,91.88 v1(83.43,92.06)
  BOTTOM w0.127: VRAM4.P13 61.44,86.9 v1(61.83,86.51)
FBA_DBI2: length 38.6
  TOP w0.127: VRAM2.P13 53.44,86.89 v1(53.05,86.51) ; v1(80.93,87.25) 80.47,87.71 80.47,89.64 80.16,89.95 80.16,90.54 GPU1.C17
  L3 w0.165: v1(53.05,86.51) 53.05,84.58 54.65,82.98 57.13,82.98 57.89,82.23 77.75,82.23 80.77,85.25 80.77,85.71 80.93,85.87 v1(80.93,87.25)
FBA_DBI3: length 38
  TOP w0.127: GPU1.C22 76.76,90.54 76.76,88.07 74.23,85.55 70.44,85.55 65.76,90.23 65.76,96.9 64.91,97.75 54.1,97.75 v1(54.01,97.66)
  BOTTOM w0.127: VRAM4.D2 53.81,96.08 53.81,96.6 54.01,96.8 v1(54.01,97.66)
FBA_DBI4: length 16.4
  TOP w0.127: v1(74.3,100.38) 74.33,100.38 74.7,100.01 GPU1.P24
  L4 w0.102: v1(74.3,100.38) 73.92,100 73.12,100 72.73,100.39 71.13,100.39
  L4 w0.165: 71.13,100.39 70.88,100.39 70.67,100.18 65.17,100.18 61.94,103.41 61.94,104.37 v1(61.77,104.54)
  BOTTOM w0.127: v1(61.77,104.54) 61.39,104.92 VRAM3.D2
FBA_DBI5: length 19
  TOP w0.127: VRAM1.P13 61.39,113.76 v1(61.77,114.14) ; GPU1.W24 74.7,104.15 v1(75.11,104.56)
  L4 w0.102: 73.31,106 73.55,105.76 73.55,105.27 74.27,104.56 v1(75.11,104.56)
  L4 w0.165: v1(61.77,114.14) 62.38,113.54 65.29,113.54 65.84,112.98 65.84,112.56 71.03,107.37 71.94,107.37 73.31,106
FBA_DBI6: length 32.9
  TOP w0.127: GPU1.AA25 73.61,105.8 73.19,106.22 72.12,106.22 68.31,110.03 68.31,114.09 63.9,118.5 54.81,118.5 52.38,116.07 v1(52.38,115.87)
  BOTTOM w0.127: VRAM3.P13 53.01,114.12 53.01,115.24 v1(52.38,115.87)
FBA_DBI7: length 24.9
  TOP w0.127: VRAM1.D2 52.99,104.55 52.99,103.76 52.89,103.66 52.89,103.31 54.26,101.94 64.97,101.94 66.63,103.6 68.62,103.6 69.74,102.48 71.18,102.48 71.49,102.78 71.83,102.78 71.88,102.74 72.76,102.74 72.86,102.84 73.54,102.84 GPU1.U25
FBA_DEBUG0: length 6.6
  TOP w0.127: GPU1.F22 76.41,93.4 v1(76.8,93.79)
  BOTTOM w0.102: 78.04,91.57 77.91,91.69 77.45,91.69 76.38,92.77 76.38,93.37 v1(76.8,93.79)
  BOTTOM w0.127: 78.04,91.57 78.04,91.1 78.57,90.58 v2(78.72,90.58) 78.72,90.18 R690.1
FBA_DEBUG1: length 1.4
  TOP w0.127: v1(76.74,96.28) GPU1.J22
  BOTTOM w0.127: R680.1 v1(76.74,96.28)
FBA_EDC0: length 20.6
  TOP w0.127: VRAM2.C2 62.66,96.14 64.55,96.14 64.93,96.52 64.93,96.9 v1(64.68,97.16) ; GPU1.E19 78.88,92.5 v1(78.46,92.92)
  L4 w0.165: v1(78.46,92.92) 78,93.38 78,94.51 76.95,95.55 73.7,95.55 72.7,96.55 69.55,96.55 68.94,97.16 v1(64.68,97.16)
FBA_EDC1: length 29.6
  TOP w0.127: v1(83.35,88.9) 82.92,89.32 82.92,89.49 82.64,89.77 82.64,90.42 GPU1.C15
  L4 w0.165: v1(83.35,88.9) 83.35,88.41 80.51,85.58 80.51,85.28 78.49,83.26 67.52,83.26 66.18,84.6 65.95,84.6 65.46,84.11 65.23,84.11 64.99,84.34 64.99,84.58 65.48,85.07 65.48,85.3 64.71,86.07 64.3,86.07 63.86,86.51 v1(62.64,86.51)
  BOTTOM w0.127: VRAM4.R13 v1(62.64,86.51)
FBA_EDC2: length 41.2
  TOP w0.127: v1(81.25,85.53) 80.83,85.53 80.69,85.67 80.69,86.25 81.38,86.93 81.38,88.76 81,89.14 81,89.74 GPU1.B16 ; VRAM2.R13 52.64,86.89 52.23,86.49 52.23,85.98 51.72,85.47 51.72,85.22 v3(51.34,84.84)
  L3 w0.165: v3(51.34,84.84) 53.61,82.56 56.96,82.56 57.71,81.81 77.92,81.81 81.25,85.13 v1(81.25,85.53)
FBA_EDC3: length 37
  TOP w0.127: GPU1.B22 76.21,89.91 76.21,89.65 76.04,89.48 76.04,88.15 74.17,86.28 70.24,86.28 66.86,89.66 66.86,90.42 66.2,91.08 66.2,97 65.06,98.13 53.59,98.13 v1(53.12,97.66)
  BOTTOM w0.127: v1(53.12,97.66) 53.07,97.61 53.07,96.14 VRAM4.C2
FBA_EDC4: length 13.9
  TOP w0.127: GPU1.R25 73.9,100.79 v1(73.52,100.41)
  L4 w0.165: v1(73.52,100.41) 73.09,100.41 72.77,100.72 70.75,100.72 70.62,100.6 66.57,100.6 63.2,103.97 63.16,103.97 v1(62.59,104.54)
  BOTTOM w0.127: VRAM3.C2 v1(62.59,104.54)
FBA_EDC5: length 21.9
  TOP w0.127: VRAM1.R13 v1(62.59,114.14) ; GPU1.W23 75.5,104.12 v1(75.93,104.55)
  L4 w0.102: 73.74,106.16 73.91,105.99 73.91,105.2 74.15,104.96 75.51,104.96 v1(75.93,104.55)
  L4 w0.165: 73.74,106.16 69.95,109.95 69.72,109.95 69.55,109.78 69.32,109.78 69.09,110.02 69.09,110.25 69.25,110.42 69.25,110.65 69.02,110.88 68.78,110.88 68.62,110.72 68.38,110.72 68.15,110.95 68.15,111.19 68.32,111.35 68.32,111.59 68.08,111.82 67.85,111.82 67.68,111.65 67.45,111.65 67.22,111.89 67.22,112.12 67.38,112.29 67.38,112.52 67.15,112.75 66.92,112.75 66.75,112.59 66.52,112.59 66.28,112.82 66.28,113.05 66.45,113.22 66.45,113.45 65.76,114.14 v1(62.59,114.14)
FBA_EDC6: length 32.5
  TOP w0.127: GPU1.AB26 72.8,106.6 72.45,106.96 72.07,106.96 70.69,108.34 70.68,108.34 69.07,109.95 69.07,113.86 64.06,118.88 54.65,118.88 51.75,115.97 v1(51.75,115.86)
  BOTTOM w0.127: v1(51.75,115.86) 51.79,115.82 51.79,115.07 52.19,114.67 52.19,114.14 VRAM3.R13
FBA_EDC7: length 24.4
  TOP w0.127: GPU1.T26 72.74,102 72.1,102 72.05,101.94 71.49,101.94 71.33,102.1 69.54,102.1 69.17,102.46 66.84,102.46 65.94,101.56 53.81,101.56 52.01,103.36 52.01,103.85 52.16,103.99 52.16,104.51 VRAM1.C2
FBA_SEN0: length 12.7
  TOP w0.356: v1(57.44,89.88) VRAM2.J10
  TOP w0.508: v4(48.19,92.33) 48.19,92.3 v3(49.06,91.44) 49.99,90.5 56.85,90.5 57.44,89.92 v1(57.44,89.88)
  BOTTOM w0.356: VRAM2.J10 v1(57.44,89.88)
  BOTTOM w0.508: R684.1 48.93,91.57 v3(49.06,91.44)
FBA_SEN2: length 11.8
  TOP w0.254: VRAM1.J10 57.39,110.96 v1(57.18,110.76)
  TOP w0.508: v1(57.18,110.76) 57.18,110.35 56.43,109.6 v4(48.85,109.6) 48.74,109.6 R253.1
  BOTTOM w0.254: VRAM1.J10 57.39,110.96 v1(57.18,110.76)
FBA_SOE0: length 4.9
  TOP w0.254: VRAM2.J1 58.08,97.16 v1(58.28,97.16)
  BOTTOM w0.508: R676.1 60.74,99.57 v2(60.1,98.93) 58.33,97.16 v1(58.28,97.16)
FBA_SOE1: length 3.8
  BOTTOM w0.203: 56.92,97.99 56.92,96.97 57.38,96.51 VRAM4.J1
  BOTTOM w0.508: R872.2 v2(56.23,98.68) 56.92,97.99
FBA_SOE2: length 3.8
  TOP w0.356: VRAM1.J1 57.39,104.05 v1(56.84,103.5)
  BOTTOM w0.508: R679.2 56.23,101.79 v2(56.29,101.85) 56.84,102.4 v1(56.84,103.5)
FBA_SOE3: length 4.1
  BOTTOM w0.254: 57.88,103 57.88,103.65 VRAM3.J1
  BOTTOM w0.508: R873.1 59.22,101.6 v2(58.96,101.85) 57.88,102.93 57.88,103
FBA_VREF_FET_H: length 24.5
  TOP w0.127: R249.2 46.39,112.08 46.39,114.58 52.84,121.03 v3(57.06,121.03)
  BOTTOM w0.127: R658.2 62.14,120.19 60.15,122.17 v2(59.47,122.17) Q51.D 57.06,121.48 v3(57.06,121.03)
FBA_VREF_FET_L: length 10.8
  TOP w0.127: Q31.D 54.45,81.66 R298.2 51.53,81.85 v3(51.34,81.66)
  BOTTOM w0.127: v3(51.34,81.66) 49.18,81.66 v2(48.42,82.42) 46.96,83.88 R698.2
FBA_VREFC0: length 8.8
  TOP w0.305: v1(56.44,85.07) 56.44,85.08 57.44,86.08 VRAM2.J14
  TOP w0.508: v1(56.44,85.07) 55.89,84.53 v4(55.89,83.87) 55.89,83.15 C117.1 R299.1 R298.1 53.25,82.74 R295.2
  BOTTOM w0.305: v1(56.44,85.07) 56.44,85.08 57.44,86.08 VRAM2.J14
FBA_VREFC1: length 8.6
  TOP w0.356: VRAM1.J14 57.41,114.54 57.83,114.96 v1(57.83,114.96)
  BOTTOM w0.356: VRAM1.J14 57.41,114.54 57.78,114.9 57.78,114.9 v1(57.83,114.96)
  BOTTOM w0.508: v1(57.83,114.96) 58.45,115.57 59.09,115.57 60.18,116.66 v2(60.18,116.81) 60.1,116.89 C427.1 R659.1 R658.1 R657.2
FBA_VREFD_H: length 27.7
  TOP w0.356: v1(51.39,110.9) 50.99,111.3 VRAM1.A10 ; v1(64.19,110.83) 64.19,110.93 63.79,111.34
  TOP w0.508: C87.1 48.55,110.62 v3(48.67,110.74) ; C87.1 C88.1 ; C87.1 R249.1
  L4 w0.508: v3(48.67,110.74) 51.23,110.74 v1(51.39,110.9) 51.39,110.6 51.85,110.13 59.82,110.13 59.99,110.3 63.66,110.3 v1(64.19,110.83)
  BOTTOM w0.305: v1(64.19,110.83) 64.19,110.84 63.79,111.24 63.79,111.34
  BOTTOM w0.356: VRAM1.A10 50.99,111.3 v1(51.39,110.9)
  BOTTOM w0.508: C448.1 C88.1 47.82,109.63 48.72,109.63 v2(49.06,109.3) 48.41,108.65 R671.2 ; C448.1 v3(48.67,110.74) ; C448.1 R249.1
FBA_VREFD_L: length 24.8
  TOP w0.356: VRAM2.A10 63.84,89.35 v1(63.44,89.75) ; v1(50.63,89.82) 50.94,89.51 50.94,89.5 51.04,89.4 VRAM2.U10
  L4 w0.508: v1(50.63,89.82) 51.3,90.49 62.73,90.49 63.22,89.99 63.22,89.96 v1(63.44,89.75)
  BOTTOM w0.356: VRAM2.A10 63.84,89.35 v1(63.44,89.75) ; VRAM2.U10 51.04,89.4 50.94,89.5 50.94,89.51 v1(50.63,89.82)
  BOTTOM w0.508: R698.1 47.85,84.11 47.54,84.42 R694.1 47.57,85.06 C525.1 C524.1 C523.1 C522.1 47.79,88.86 R688.2 v2(48.86,89.6) 50.41,89.6 v1(50.63,89.82)
FBA_WCK01: length 26.9
  TOP w0.127: VRAM2.D4 61.44,94.11 v1(61.83,93.73) ; GPU1.D18 79.74,91.7 v1(80.12,92.08)
  L4 w0.102: v1(61.83,93.73) 62.31,93.24 62.31,92.51 62.49,92.33 62.64,92.33 ; v1(80.12,92.08) 79.71,91.67 79.71,89.82 79.51,89.61
  L4 w0.152: 62.64,92.33 65.42,92.33 66.59,91.16 66.59,89.99 69.31,87.26 74.71,87.26 74.91,87.46 76.23,87.46 77.19,88.42 78.31,88.42 79.51,89.61
  BOTTOM w0.127: VRAM2.D4 61.44,94.11 v1(61.83,93.73)
FBA_WCK01#: length 27.1
  TOP w0.127: VRAM2.D5 61.82,92.93 v1(61.82,92.91) ; GPU1.C18 79.68,91.19 79.8,91.31 v1(80.12,91.31)
  L4 w0.102: v1(80.12,91.31) 79.92,91.1 79.92,89.73 79.75,89.57 79.75,89.42
  L4 w0.152: v1(61.82,92.91) 61.42,92.51 61.42,92.15 61.55,92.02 65.3,92.02 66.28,91.04 66.28,89.86 69.19,86.96 74.84,86.96 75.03,87.15 76.35,87.15 77.31,88.11 78.44,88.11 79.75,89.42
  BOTTOM w0.127: v1(61.82,92.91) 61.82,92.93 VRAM2.D5
FBA_WCK23: length 37.4
  TOP w0.127: VRAM2.P4 53.44,94.11 v1(53.04,93.71) ; GPU1.D17 80.53,91.7 v1(80.92,92.09)
  L4 w0.102: 53.7,91.36 53.47,91.36 53.2,91.64 53.2,92.12 53.45,92.38 53.45,93.3 v1(53.04,93.71)
  L4 w0.152: v1(80.92,92.09) 80.55,91.72 80.55,91.13 80.18,90.75 80.18,89.49 77.25,86.56 75.19,86.56 75.06,86.44 68.94,86.44 64.02,91.36 53.7,91.36
  BOTTOM w0.127: VRAM2.P4 53.44,94.11 v1(53.04,93.71)
FBA_WCK23#: length 37.8
  TOP w0.127: GPU1.D16 81.36,91.39 81.27,91.3 v1(80.99,91.3) ; VRAM2.P5 52.97,92.84 v1(52.97,92.56)
  L4 w0.152: v1(80.99,91.3) 80.99,91.14 80.86,91.01 80.86,91 80.48,90.63 80.48,89.36 77.38,86.26 75.32,86.26 75.19,86.13 68.82,86.13 63.89,91.06 53.35,91.06 52.28,92.13 52.28,92.43 52.41,92.56 v1(52.97,92.56)
  BOTTOM w0.127: VRAM2.P5 52.97,92.84 v1(52.97,92.56)
FBA_WCK45: length 27
  TOP w0.127: GPU1.T24 74.71,101.64 v1(75.13,102.06) ; VRAM1.P4 61.4,106.54 v1(61.78,106.92)
  L4 w0.102: v1(75.13,102.06) 74.74,101.67 74.11,101.67 73.25,102.53 72.71,102.53 72.2,103.04 72.12,103.04 72.11,103.06
  L4 w0.152: v1(61.78,106.92) 61.78,106.97 62.1,107.28 62.1,108.37 62.29,108.56 65.2,108.56 66.16,107.6 66.16,107.38 65.84,107.07 65.84,106.56 66.2,106.2 66.7,106.2 67.02,106.52 67.23,106.52 67.45,106.3 67.45,106.09 66.68,105.31 66.68,104.81 67.04,104.45 67.54,104.45 68.31,105.23 68.53,105.23 68.74,105.01 68.74,104.8 67.59,103.64 67.59,103.13 67.95,102.78 68.45,102.78 69.61,103.93 69.82,103.93 70.45,103.3 71.86,103.3 72.11,103.06
  BOTTOM w0.127: v1(61.78,106.92) 61.4,106.54 VRAM1.P4
FBA_WCK45#: length 27.4
  TOP w0.127: v1(74.3,102.08) 74.54,102.08 74.7,102.23 GPU1.U24 ; VRAM1.P5 61.39,107.43 v1(60.99,107.82)
  L4 w0.102: 72.32,103.28 72.34,103.26 72.34,103.19 72.8,102.73 73.33,102.73 73.99,102.08 v1(74.3,102.08)
  L4 w0.152: v1(60.99,107.82) 60.99,107.53 61.17,107.35 61.63,107.35 61.79,107.52 61.79,108.5 62.16,108.86 65.32,108.86 66.46,107.73 66.46,107.26 66.14,106.94 66.14,106.69 66.32,106.51 66.57,106.51 66.89,106.83 67.36,106.83 67.76,106.43 67.76,105.96 66.98,105.19 66.98,104.94 67.17,104.76 67.41,104.76 68.19,105.53 68.66,105.53 69.05,105.14 69.05,104.67 67.89,103.51 67.89,103.26 68.07,103.08 68.32,103.08 69.48,104.24 69.95,104.24 70.58,103.61 71.99,103.61 72.32,103.28
  BOTTOM w0.127: VRAM1.P5 61.39,107.43 v1(60.99,107.82)
FBA_WCK67: length 28.2
  TOP w0.127: GPU1.V24 74.7,103.32 v1(75.11,102.91) ; v1(53,106.93) 53.39,106.54 VRAM1.D4
  L4 w0.102: v1(75.11,102.91) 74.92,102.91 74.49,102.48 74.02,102.48 73.53,102.97 73.27,102.97 72.11,104.14 71.79,104.14 71.72,104.14 71.69,104.1 71.67,104.1
  L4 w0.152: 71.67,104.1 70.79,104.1 65.59,109.3 61.37,109.3 60.93,108.85 54.91,108.85 54.15,108.09 54.15,107.39 53.83,107.06 53.12,107.06 v1(53,106.93)
  BOTTOM w0.127: VRAM1.D4 53,106.93 v1(53,106.93)
FBA_WCK67#: length 28.7
  TOP w0.127: GPU1.V25 74.23,103.32 74.32,103.24 v1(74.32,102.89) ; VRAM1.D5 53,107.73 v1(53,108.08)
  L4 w0.102: v1(74.32,102.89) 73.9,102.89 73.62,103.17 73.36,103.17 72.19,104.34 71.72,104.34 71.7,104.37 71.7,104.38 71.67,104.41
  L4 w0.152: 71.67,104.41 70.91,104.41 65.72,109.6 61.25,109.6 60.8,109.15 54.79,109.15 53.85,108.22 53.85,107.51 53.7,107.36 53.17,107.36 53,107.54 v1(53,108.08)
  BOTTOM w0.127: v1(53,108.08) 53,107.73 VRAM1.D5
FBA_ZQ0: length 4.9
  TOP w0.203: 58.33,84.35 57.74,84.94 57.74,85.53 57.82,85.61 57.82,86.53 VRAM2.J13
  TOP w0.508: 58.33,84.35 58.63,84.05 v4(58.63,83.88) 58.63,83.04 R301.1
FBA_ZQ1: length 4.6
  TOP w0.508: R300.1 57.26,82.79 v4(57.26,83.95) 57.26,84.96 v1(57.18,85.04)
  BOTTOM w0.203: VRAM4.J13 57.82,86.53 57.82,85.81 57.31,85.31 57.31,85.16 v1(57.18,85.04)
FBA_ZQ2: length 4.8
  TOP w0.203: v1(56.49,115.67) 56.99,115.17 56.99,114.13 VRAM1.J13
  BOTTOM w0.508: R663.1 55.99,117.87 v2(55.99,116.97) 55.99,116.17 v1(56.49,115.67)
FBA_ZQ3: length 4.6
  BOTTOM w0.203: VRAM3.J13 56.99,114.13 56.99,115.25 57.1,115.36
  BOTTOM w0.508: R662.1 57.06,117.2 v2(57.28,116.97) 57.28,116.92 57.1,116.73 57.1,115.36
FIVR_EN_R: length 18.2
  TOP w0.102: R20.2 R19.2 42.96,223.71 41.69,222.44 v4(41.38,222.44) 40.23,222.44 36.48,218.69 33.67,218.69 33.31,218.33 33.31,217.62 32.47,216.79 31.52,216.79 30.83,216.11 XDP1.45
FLASH_WP: length 22.9
  TOP w0.102: v3(51.95,57.15) 51.95,57.68 52.46,58.19 53.63,58.19
  BOTTOM w0.102: U33.3 62.26,51.69 61.76,51.18 61.76,50.42 61.26,49.92 54.25,49.92 51.21,52.96 v2(51.21,54.74) 51.21,55.44 R764.1 R763.2 53.06,56.71 52.62,57.15 v3(51.95,57.15)
FWH_ID0: length 4.9
  TOP w0.102: LPC1.6 112.59,59.78 v4(112.3,60.07) 111.73,60.64 R379.2
GC6_FB_EN: length 19.3
  TOP w0.127: v3(98.71,97.03) 98.59,97.03 98.33,97.28 R264.2 ; GPU1.C6 89.63,90.9 v1(90.02,90.51)
  BOTTOM w0.127: v1(90.02,90.51) 91.25,89.28 92.88,89.28 93.57,89.98 95.52,89.98 95.65,90.11 97.14,90.11 97.86,90.83 97.86,91.54 99.16,92.83 99.16,96.46 99.63,96.93 99.63,97.54 v2(99.37,97.79) 98.71,97.13 v3(98.71,97.03)
GDI_1V1: length 8.9
  BOTTOM w0.508: L32.1 70.71,66.87 R719.1 70.71,69.91 v2(70.9,70.1) ; v2(70.9,70.1) 70.72,70.28 C537.1 68.66,71.12 U31.6 ; v2(70.9,70.1) 71.15,70.36 L31.1
GDI_1V1_SCALAR: length 6.8
  TOP w0.203: SCA1.20 67.68,65.79 v1(67.55,65.66)
  BOTTOM w0.508: v1(67.55,65.66) 67.86,65.98 C543.1 69.06,65.28 C632.1 69.38,64.64 69.77,64.25 v2(70.27,64.25) 70.65,64.62 L32.2
GPD2/LAN_WAKE#: length 44.4
  TOP w0.102: v3(107.84,135.24) 107.59,135.24 106.21,133.86 106.21,126.34 105.16,125.3 105.16,122.77 v4(105.57,122.37) 105.57,121.1 R226.2 ; CPU1.AM15 87.95,152.7 v1(88.27,152.37)
  L3 w0.127: v3(107.84,135.24) 106.59,136.49 106.59,137.29 106.06,137.81 106.06,138.69 93.45,151.31 91.63,151.31 91.05,151.88 88.77,151.88 v1(88.27,152.37)
GPIO: length 4.8
  BOTTOM w0.102: R588.1 175.09,151.65 v2(175.09,150.53) 175.09,149.61 174.59,149.1 U28.28
GPIO0_TPM: length 1.9
  BOTTOM w0.102: U34.29 125.26,44.45 TP80.1
GPIO1_FBVDDQCTL: length 6.7
  TOP w0.127: GPU1.B2 93.12,89.88 93.12,89.86 94.9,88.07 94.9,88.01 96.05,86.87 97.09,86.87 TP51.1
GPIO1_TPM: length 2.2
  BOTTOM w0.102: TP81.1 123.48,43.94 124.76,45.22 U34.30
GPIO2_BL_PWM: length 9.1
  TOP w0.127: GPU1.D6 89.61,91.7 v1(90.03,91.29)
  BOTTOM w0.127: v1(90.03,91.29) 89.6,90.86 89.6,90.01 90.96,88.65 92.67,88.65 93.77,87.55 v2(94.24,87.55) 94.97,88.28 R692.1
GPIO2_TPM: length 5.9
  TOP w0.102: R434.1 122.14,47.88 v3(121.7,47.88)
  BOTTOM w0.102: U34.3 122.03,47.38 v2(121.16,46.51) 120.94,46.74 120.94,47.12 v3(121.7,47.88)
GPIO3_PPEN_R: length 11
  TOP w0.127: R288.1 94.55,84.01 93.96,84.59 93.37,84.59 89.95,88.01 89.59,88.01 v3(89.57,88.03) 88.44,89.15 88.44,90.54 GPU1.C7
  BOTTOM w0.127: v2(88.81,88.01) 89.55,88.01 v3(89.57,88.03)
GPIO4_BLEN: length 13
  TOP w0.127: v1(87.54,92.1) 87.54,92.84 87.12,93.25 GPU1.F9
  BOTTOM w0.102: 88.68,91.62 88.6,91.69 87.97,91.69 87.56,92.1 v1(87.54,92.1)
  BOTTOM w0.127: 88.68,91.62 88.79,91.5 88.79,89.55 91.6,86.74 91.85,86.74 v2(93.63,84.96) 94.58,84.01 R701.1
GPIO5_PWM_VID_BOOT_EN: length 7.9
  TOP w0.127: TP50.1 97.26,85.29 97.26,86.11 96.88,86.49 95.54,86.49 93.81,88.21 93.19,88.21 GPU1.A3
GPIO6_FB_CLAMP_TGL_REQ: length 6.8
  TOP w0.127: TP49.1 95.64,85.75 93.7,87.69 92.91,87.69 GPU1.A4
GPIO7_3D_STEREO: length 10.9
  TOP w0.127: GPU1.B6 89.96,89.74 89.96,89.09 91.94,87.11 93.65,87.11 94.95,85.8 95.19,85.8 95.78,85.22 v3(95.92,85.22)
  BOTTOM w0.127: R699.1 96.81,84.14 v2(96.81,85.22) v3(95.92,85.22)
GPIO8_OVERT#: length 12.4
  TOP w0.127: GPU1.A6 89.6,89.12 92.84,85.88 94.31,85.88 v4(94.95,85.23) 95.5,84.68 96.01,84.68 R290.1 96.88,83.81 97.09,83.81 97.55,83.34 Q28.S
GPIO9_ALERT#: length 91.7
  TOP w0.127: v1(88.38,92.93) 87.96,93.34 GPU1.F8
  L4 w0.165: v3(106.59,80.26) 106.46,80.39 99.61,80.39 97.01,82.99 96.37,82.99 93.76,85.6 93.76,86.62 91.74,88.65 89.53,88.65 86.26,91.91 86.26,92.28 86.91,92.93 v1(88.38,92.93)
  BOTTOM w0.127: PR212.1 126.02,104.84 126.02,107.65 124.95,108.71 121.72,108.71 118.8,105.79 118.8,101.75 117.53,100.48 117.53,100.08 116.83,99.38 v2(113.7,99.38) 104.3,99.38 103.59,98.67 103.59,82.37 105.7,80.26 v3(106.59,80.26) ; R685.1 95.38,90.21 93.48,90.21 93.38,90.11 91.88,90.11 91.87,90.12 90.79,90.12 90.46,90.45 90.46,91.45 90.2,91.71 89.87,91.71 89.61,91.97 89.61,92.27 89.36,92.52 88.85,92.52 88.44,92.93 v1(88.38,92.93)
GPIO10_MEM_VREF_CTL: length 111.8
  TOP w0.127: v3(58.83,79.63) 58.43,79.22 57.06,79.22 Q31.G ; v1(92.24,87.53) 92.24,87.99 91.29,88.94 91.15,88.94 90.88,89.22 90.88,90.47 GPU1.C5
  L4 w0.165: v3(69.5,79.5) 69.99,79.99 70.47,79.99 70.96,79.5 75.73,79.5 76.13,79.89 82.13,79.89 89.76,87.53 v1(92.24,87.53)
  BOTTOM w0.127: Q51.G 47.56,121.19 45.49,119.11 45.49,98.23 45.23,97.98 45.23,84.58 48.62,81.19 52.32,81.19 52.77,81.64 57.03,81.64 58.83,79.84 v3(58.83,79.63) 59.34,79.63 v2(59.85,80.14) 60,80.29 68.71,80.29 v3(69.5,79.5) ; v1(92.24,87.53) 92.24,87.44 R700.1
GPIO11_PWM_VID: length 62.9
  TOP w0.127: v1(89.19,92.1) 88.8,92.49 GPU1.E7
  L4 w0.165: v3(106.21,81.03) 105.95,80.77 99.86,80.77 96.81,83.82 96.05,83.82 94.39,85.47 94.39,86.49 91.85,89.03 90.88,89.03 89.19,90.72 v1(89.19,92.1)
  BOTTOM w0.127: v3(106.21,81.03) 105.44,81.03 103.93,82.54 103.93,95.5 104.4,95.97 107.24,95.97 109.28,93.93 114.58,93.93 115.66,92.85 124.12,92.85 v2(124.49,93.22) 124.62,93.34 PR233.2
GPIO12_AC_DETECT: length 11.3
  TOP w0.127: R289.1 95.07,84.61 94.47,84.61 93.89,85.19 v4(93.63,85.19) 93.21,85.19 89.19,89.21 89.19,91.31 GPU1.D7
GPIO13_NVVDD_PSI: length 60.4
  TOP w0.127: GPU1.B4 91.3,90.09 v1(91.69,89.7)
  L4 w0.165: v3(107.09,81.03) 106.33,81.79 99.47,81.79 96.93,84.33 96.15,84.33 95.03,85.45 95.03,86.36 91.69,89.7 v1(91.69,89.7)
  BOTTOM w0.127: v3(107.09,81.03) 106.59,81.53 105.44,81.53 104.27,82.7 104.27,95.36 104.54,95.63 107.09,95.63 109.14,93.59 114.44,93.59 115.52,92.51 125.05,92.51 v2(125.76,93.22) R682.2
GPIO_FB_CLAMP_GPU: length 9.8
  TOP w0.127: PR69.1 98.1,96.27 97.08,97.28 R264.1 97,95.95 v4(97.19,95.76) 97.12,95.76 96.24,94.87 93.45,94.87 93.26,94.68 92.88,94.68 92.54,94.35 92.54,94.14 92.1,93.7 GPU1.F3
GPP_B2/VRALERT#: length 8.9
  TOP w0.102: v1(87.57,150.52) 87.57,150.66 87.92,151 CPU1.AM11
  BOTTOM w0.102: v1(87.57,150.52) 87.57,150.52 86.95,149.91 86.95,147.69 87.64,147 87.64,146.81 88.02,146.43 88.02,145.96 88.81,145.18 TP72.1
GPP_B18/GSPI0_MOSI: length 22.8
  TOP w0.127: v1(90.22,148.72) 89.9,148.39 CPU1.AR7
  BOTTOM w0.127: R633.2 105.19,135 v2(104.94,135.25) 104.78,135.25 95.52,144.51 95.52,145.66 92.87,148.31 92.53,148.31 92.42,148.21 91.06,148.21 91.05,148.22 90.72,148.22 v1(90.22,148.72)
GPP_B22/GSPI1_MOSI: length 8.8
  TOP w0.089: CPU1.AN5 89.5,146.44 89.5,144.29
  TOP w0.127: 89.5,144.29 90.03,143.76 90.03,142.71 v3(90.02,142.7) 90.03,142.69 90.03,141.74 R160.2
  BOTTOM w0.127: v2(90.43,143.46) 90.43,143.12 v3(90.02,142.7)
GPP_B23/SML1ALERT#: length 24.3
  TOP w0.102: CPU1.AM7 87.95,148.31 v1(87.57,148.69)
  BOTTOM w0.102: v1(87.57,148.69) 88.21,148.04 88.21,147.05 88.59,146.67 88.59,146.2 89.82,144.97 90,144.97 90.69,144.29 90.69,144.26 91.07,143.88 91.07,142.36 v2(90.15,141.44) 90.38,141.21 90.38,140.46 89.26,139.34 89.26,131.81 R645.1
GPP_C2/SMBALERT#: length 11.3
  TOP w0.102: v1(80.21,150.32) 79.97,150.32 CPU1.R10
  BOTTOM w0.102: R620.1 v2(78.77,141.99) 78.77,143.3 80.03,144.56 80.03,146.87 80.62,147.46 80.62,149.92 v1(80.21,150.32)
GPP_C5/SML0ALERT#: length 6.2
  TOP w0.102: v1(81.69,143.76) 81.83,143.9 CPU1.W1
  BOTTOM w0.102: R618.2 80.87,140.59 v2(82.2,140.59) 82.52,140.91 R613.1 81.88,143.76 v1(81.69,143.76)
GPU_1D05V:
  vias: v4(108.01,101.37)
GPU_1D05V_EN: length 7.5
  TOP w0.254: PU11.8 116.49,105.41 117.13,104.78 PC89.1 PR62.2 118.08,106.36 118.65,106.93 v4(118.91,106.93) 119.77,106.93 D2.A
GPU_1D05V_FB_M: length 7.7
  TOP w0.254: PU11.2 109.29,104.14 108.92,104.51 108.92,105.28 108.21,105.99 v3(108.01,105.99) 108.01,106.2 107.73,106.48 PR60.1 106.71,107.12 PC88.2 PR59.2
  BOTTOM w0.254: v3(108.01,105.99) 107.75,105.74 v2(107.75,105.13)
GPU_1D05V_FB_M1: length 3.9
  TOP w0.254: v3(105.76,108.95) PR59.1 PC88.1 PR61.1
  BOTTOM w0.254: v3(105.76,108.95) 105.6,108.79 v2(105.6,108.05)
GPU_1D05V_PG: length 41.9
  TOP w0.254: D6.A 88.81,71.12 89.64,71.96 89.64,73.1 v3(89.95,73.41) ; PU14.2 119.65,74.43 119.89,74.19 119.89,73.75 119.92,73.71 v3(119.92,73.28)
  L4 w0.254: v3(89.95,73.41) 90.97,73.41 92.74,71.63 102.4,71.63 104.05,69.98 118.52,69.98 119.92,71.38 v3(119.92,73.28)
  BOTTOM w0.254: v3(119.92,73.28) 119.92,72.89 v2(120.43,72.39) 120.81,72.01 PC274.1 PR240.2
GPU_1D05V_POK: length 74.3
  TOP w0.254: v3(116.75,103.5) 117.38,102.87 PR66.2 PC90.1 117.76,103.89 117.51,104.14 PU11.7
  L3 w0.254: v3(136.22,104.65) 136.22,104.99 134.7,106.5 118.98,106.5 116.75,104.27 v3(116.75,103.5)
  BOTTOM w0.254: v3(136.22,104.65) 136.81,104.06 v2(136.81,103) 136.81,97.54 138.74,95.61 138.74,77.09 135.16,73.51 122.88,73.51 PR240.1
GPU_1D05V_VGA_EN: length 16.2
  TOP w0.254: v3(119.92,105.03) 119.16,105.79 PR62.1
  L3 w0.254: v3(132.24,105.41) 131.66,105.99 120.89,105.99 v3(119.92,105.03)
  BOTTOM w0.254: PR210.1 132.49,105.16 v3(132.24,105.41) 132.24,105.66 v2(132.8,106.22)
GPU_ALLPWR: length 153.6
  TOP w0.203: KBC1.96 130.74,65.41 130.56,65.58
  TOP w0.254: CPU1.A7 71.28,148.21 v3(68.49,145.41) ; v3(125.64,72.77) 125.64,72.51 122.98,69.85 R350.1 ; v3(127.46,66.96) 127.7,66.96 128.68,67.94 v4(129.07,67.94) 129.57,67.94 130.56,66.95 130.56,66.92 130.59,66.9 130.59,66.45 130.56,66.43 130.56,65.58
  L3 w0.254: v3(127.46,66.96) 127.41,67.01 127.41,70.99 v3(125.64,72.77) 132.67,72.77 137.68,77.77 137.68,104.7 135.8,106.58 v3(135.8,106.93)
  L4 w0.254: v3(68.49,145.41) 69.82,145.41 71.38,143.85 71.38,141.35 72.19,140.54 72.19,135.43 74.95,132.67 75.56,132.67 87.39,120.84 112.55,120.84 125.71,107.68 135.05,107.68 v3(135.8,106.93)
GPU_CLK0_TER: length 4.5
  TOP w0.508: R303.2 R302.2 59.35,81.85 58.15,80.64 v4(58.15,80.52) 59.15,80.52 C124.2
GPU_CLK1_TER: length 3
  BOTTOM w0.508: R661.2 R660.2 59.09,119.63 v2(59.01,119.71) 58.96,119.76 C425.2
GPU_DMINUS: length 1.7
  BOTTOM w0.127: TP77.1 82.84,82.3 82.96,82.42 82.96,83.25 R696.1
GPU_DMINUS_G: length 12.4
  TOP w0.127: v1(85.07,92.09) 85.05,92.09 GPU1.E12
  BOTTOM w0.127: R696.2 82.71,85.47 v2(84.11,86.87) 84.34,87.1 86.36,87.1 86.77,87.51 86.77,91.01 86.07,91.72 85.69,92.09 85.55,92.24 85.21,92.24 v1(85.07,92.09)
GPU_DPLUS: length 1.9
  BOTTOM w0.127: R695.1 83.22,82.99 83.22,82.42 83.35,82.3 TP76.1
GPU_DPLUS_G: length 12.4
  TOP w0.127: GPU1.F12 84.77,93.21 84.79,93.21 v1(85.09,92.91)
  BOTTOM w0.127: R695.2 83.73,85.01 v2(84.11,85.39) 84.11,86.13 84.82,86.84 86.47,86.84 87.03,87.4 87.03,91.12 86.17,91.97 85.87,92.27 85.72,92.42 85.65,92.5 85.5,92.5 v1(85.09,92.91)
GPU_PEX_RST_HOLD: length 32.5
  BOTTOM w0.102: R689.1 97.29,89.66 98.08,90.45 98.08,91.45 99.37,92.74 99.37,96.06 100.06,96.75 100.06,101.78 99.37,102.46 99.37,103.27 100.39,104.29 100.39,109.37 99.92,109.84 96.69,109.84 v2(96.68,109.86) 96.49,110.05 R670.2 94.22,110.86 94.22,114.28 D17.1
GPU_PEX_RST_HOLD_GPU#: length 7
  TOP w0.102: GPU1.C4 91.73,90.47 93.05,90.47 93.33,90.19 93.33,89.95 94.18,89.1 94.72,89.1 v3(95.16,89.53)
  BOTTOM w0.102: v2(96.22,88.57) 95.98,88.81 R689.2 95.28,89.66 v3(95.16,89.53)
GPU_TESTMODE: length 8.5
  TOP w0.127: R241.1 82.33,114.05 v4(83.35,113.03) 83.78,112.6 84.06,112.6 85.89,110.77 85.89,108.92 86.09,108.71 86.74,108.71 87.12,108.33 GPU1.AD9
GPU_THERM_SHUTDOWN_N: length 5.6
  BOTTOM w0.127: PR229.1 132.01,93.89 137.1,93.89 TP74.1
GPU_VCC3_CTL: length 8.1
  TOP w0.127: D5.A 87.18,70.56 87.18,69.72 v4(86.67,69.22) 86.61,69.15 C153.2 R354.2 82.58,68.36 Q37.G
GPU_VCC3_CTL_2: length 4.6
  TOP w0.127: R357.2 78.21,69.09 v4(78.19,69.06) 78.19,69.47 78.82,70.1 C147.1 79.66,70.29 Q35.G
H_CPUPWRGD: length 6.9
  TOP w0.102: CPU1.A68 71.64,183.55 71.19,184 71.19,184.48 70.52,185.15 70.52,187.2 v4(71.79,188.47) R71.1
H_PROCHOT_N: length 358.7
  TOP w0.102: v3(33.43,141.58) 33.43,137.52 v3(33.42,137.5) ; v3(66.58,187.83) 66.77,188.02 R81.2 R82.1 ; PR23.2 v3(24.67,193.8)
  L3 w0.127: v3(33.42,137.5) 29.92,134 29.92,64.81 v3(24.67,59.56) ; v3(33.43,141.58) 26.98,141.58 22.75,145.8 22.75,157.91 25.51,160.67 25.51,165.81 26.07,166.37 26.07,166.93 30.97,171.83 38.01,171.83 v3(38.26,172.09)
  L4 w0.127: v3(66.58,187.83) 65.77,187.83 62.14,184.2 62.14,182.49 58.97,179.32 56.42,179.32 54.81,177.71 52.02,177.71 46.39,172.09 v3(38.26,172.09) 38.02,171.84 27.24,171.84 20.7,178.39 20.7,179.73 20.7,180.63 19.97,181.36 19.97,185.23 20.8,186.06 23.44,186.06 26.2,188.81 26.2,189.99 24.67,191.52 v3(24.67,193.8) ; v3(139.73,47.12) 138.96,47.89 135.97,47.89 135.92,47.94 132.1,47.94 131.38,47.22 127.68,47.22 126.27,45.81 112.26,45.81 108.35,41.9 88.89,41.9 86.86,43.93 72.66,43.93 v3(71.92,43.18) ; v3(33.82,51.44) 33.82,49.68 39.94,43.56 43.82,43.56 45.56,45.3 56.33,45.3 v3(57.18,44.45)
  BOTTOM w0.102: PR244.1 24.04,61.91 24.04,60.2 v3(24.67,59.56) 24.67,59.51 25.76,58.42 25.76,56.43 30.76,51.44 v3(33.82,51.44) ; Q69.D 141.48,43.88 140.22,45.14 140.22,45.29 R783.1 139.73,46.27 v3(139.73,47.12) ; PQ10.D 53.31,45.4 54,46.09 55.67,46.09 v2(56.09,45.67) 56.09,45.55 56.97,44.68 56.97,44.67 v3(57.18,44.45) 57.41,44.22 58.3,44.22 59.8,42.72 61.31,42.72 61.77,43.18 v3(71.92,43.18) ; PR182.1 v3(24.67,193.8)
H_RCIN#: length 155.6
  TOP w0.102: v1(124.75,55.75) 124.3,55.31 R404.1 ; v1(91.71,151.89) 91.82,152 CPU1.AW13
  L3 w0.127: v1(124.75,55.75) 125.7,56.71 128.51,56.71 129.64,57.84 130.72,57.84 132.49,59.61 132.49,61.2 134.4,63.11 134.4,67.82 136.95,70.38 136.95,70.75 142.32,76.12 142.32,87.55 v3(146.97,92.2)
  L4 w0.127: v3(148.62,118.49) 145.83,121.28 139.01,121.28 134.93,117.21 129.43,117.21 121.9,124.73 121.9,125.23 113.27,133.86 112.82,133.86 112.38,134.3 112.38,135.06 112.39,135.07 112.39,135.46 110.61,137.24 110.61,137.86 109.13,139.34 108.77,139.7 107.7,139.7 107.39,140.01 107.39,140.56 v3(107.79,140.97)
  BOTTOM w0.102: RN10.2 107.98,140.79 v3(107.79,140.97) 107.41,140.97 106.65,141.73 101.49,141.73 97.7,145.53 97.7,146.36 92.68,151.38 92.22,151.38 v1(91.71,151.89) ; v3(148.62,118.49) 148.62,117.98 147.1,116.46 v2(147.1,115.95) 147.1,115.7 147.02,115.62 147.02,108.58 147.47,108.14 147.47,92.7 v3(146.97,92.2)
H_RCIN#_R: length 4.7
  TOP w0.102: KBC1.122 127.88,53.1 v4(126.49,54.49) 126.24,54.74 R404.2
HDA_BITCLK_CPU: length 14.1
  TOP w0.089: 95.3,156.04 95.1,156.04 94.69,156.45 94.3,156.45 93.99,156.76 93.99,156.94 93.81,157.11 93.28,157.11 CPU1.AY22
  TOP w0.102: 95.3,156.04 98.94,156.04 99.78,156.87 v4(99.78,158.67) 99.78,160.18 101.52,161.93 R124.2
HDA_RST#_CPU: length 13
  TOP w0.089: 95.13,155.64 94.99,155.64 94.54,156.09 94.11,156.09 93.62,156.58 93.51,156.58 93.48,156.61 93.19,156.61 93.17,156.59 92.86,156.59 92.6,156.85 CPU1.AW22
  TOP w0.102: 95.13,155.64 99.19,155.64 100.52,156.97 v4(100.82,156.97) 100.82,158.64 R127.2
HDA_SDOUT_CPU: length 68.6
  TOP w0.102: CPU1.BB22 94.52,156.64 94.77,156.64 95.16,156.25 98.87,156.25 99.15,156.53 99.15,159.82 100.6,161.28 100.6,162.45 v4(100.85,162.69) 101.1,162.94 R123.2 R122.2 102.08,164.15 102.31,164.38 103.23,164.38 115.27,152.33 115.27,125.52 115.13,125.38 v3(115.13,124.74)
  BOTTOM w0.102: v3(115.13,124.74) 113.59,124.74 v2(113.44,124.59) 112.81,123.95 Q52.C 109.38,123 R654.2
HDA_SPKR: length 109.6
  TOP w0.152: v1(92.35,146.85) 91.98,147.22 CPU1.AW5 ; R282.1 154.85,89.41 152.99,91.26 152.99,106.63 149.31,110.31 149.31,116.41 147.86,117.86 145.07,117.86 v3(144.43,118.49)
  L4 w0.152: v3(144.43,118.49) 143.63,117.69 140.3,117.69 136.64,114.03 136.45,113.84 128.03,113.84 116.81,125.06 116.81,125.5 113.81,128.5 111.82,128.5 109.49,130.82 108.96,130.82 v3(107.84,131.94)
  BOTTOM w0.152: v1(92.35,146.85) 92.79,146.41 93.94,146.41 v2(94.7,145.64) 94.7,144.68 99.14,140.24 99.14,140.15 105.31,133.99 R634.2 106.51,133.49 106.51,133.41 106.52,133.4 106.52,133.26 v3(107.84,131.94)
HDA_SYNC_CPU: length 12.5
  TOP w0.089: CPU1.BA22 93.66,156.78 94.18,156.27 94.61,156.27 95.05,155.83 95.35,155.83
  TOP w0.102: R126.2 101.56,160.91 v4(100.92,160.27) 100.34,159.69 100.34,158.44 100.24,158.34 100.24,156.95 99.12,155.83 95.35,155.83
HDMI1_CK+: length 90
  TOP w0.089: R490.2 107.48,23.56 107.48,23.24 v3(107.35,23.11) 107.09,22.85 D13.7 D13.4 107.09,20.55 107.68,19.96 107.68,19.79 107.39,19.49 TR12.4 ; SCA1.8 68.29,60.99 68.23,61.05 67.68,61.05 v3(67.6,60.96)
  L3 w0.102: v3(67.6,60.96) 67.98,60.96 68.11,61.09 68.11,61.26 68.23,61.39 71.78,61.39 75.38,57.79 75.38,57.39 75.68,57.09 76.51,57.09 76.61,56.99 76.61,56.68 76.51,56.58 75.68,56.58 75.38,56.29 75.38,55.71 75.68,55.41 76.51,55.41 76.61,55.31 76.61,55.01 76.51,54.91 75.68,54.91 75.38,54.61 75.38,51.41 78.15,48.64 80.18,48.64 80.48,48.94 80.48,51.13 80.61,51.26 80.86,51.26 80.99,51.13 80.99,48.94 81.28,48.64 81.86,48.64 82.15,48.94 82.15,49.99 82.26,50.09 82.56,50.09 82.66,49.99 82.66,48.94 82.96,48.64 87.58,48.64 95.46,40.76 95.46,34.56 96.35,33.67 96.35,29.71 98.66,27.4 99.08,27.4 99.66,27.98 99.8,27.98 100.02,27.77 100.02,27.62 99.44,27.04 99.44,26.62 100.4,25.65 104.22,25.65 104.33,25.55 104.33,24.73 104.62,24.43 105.2,24.43 105.49,24.73 105.49,25.55 105.6,25.65 106.51,25.65 107.78,24.39 107.78,23.67 107.65,23.55 107.48,23.55 107.35,23.42 v3(107.35,23.11)
  BOTTOM w0.089: v3(107.35,23.11) 107.35,23.7 v2(107.58,23.93)
HDMI1_CK+_C: length 17.2
  TOP w0.089: v3(119.29,13.84) 118.81,14.32 HDMI2.10 116.17,14.32 115.84,14.65 115.52,14.65 112.35,17.82 110.33,17.82 109.13,16.61 107.21,16.61 106.89,16.93 106.89,17.55 TR12.3
  BOTTOM w0.089: v2(118.21,13.59) 118.46,13.84 v3(119.29,13.84)
HDMI1_CK-: length 89.9
  TOP w0.089: SCA1.9 67.93,61.39 v3(67.6,61.72) ; R491.2 107.86,23.69 107.86,23.37 v3(108.11,23.11) 107.59,22.59 D13.6 D13.5 107.59,20.54 108.03,20.1 108.03,19.34 TR12.1
  L3 w0.102: v3(67.6,61.72) 71.91,61.72 75.71,57.92 75.71,57.52 75.81,57.42 76.65,57.42 76.94,57.13 76.94,56.55 76.65,56.25 75.81,56.25 75.71,56.15 75.71,55.85 75.81,55.74 76.65,55.74 76.94,55.45 76.94,54.87 76.65,54.58 75.81,54.58 75.71,54.47 75.71,51.55 78.29,48.97 80.05,48.97 80.15,49.07 80.15,51.27 80.47,51.59 81,51.59 81.32,51.27 81.32,49.07 81.42,48.97 81.72,48.97 81.82,49.07 81.82,50.12 82.12,50.42 82.7,50.42 82.99,50.12 82.99,49.07 83.09,48.97 87.71,48.97 95.79,40.89 95.79,34.7 96.68,33.81 96.68,29.84 98.79,27.73 98.94,27.73 99.52,28.31 99.94,28.31 100.35,27.9 100.35,27.49 99.77,26.9 99.77,26.76 100.54,25.98 104.36,25.98 104.66,25.69 104.66,24.87 104.76,24.77 105.06,24.77 105.16,24.87 105.16,25.69 105.46,25.98 106.65,25.98 108.11,24.52 v3(108.11,23.11)
  BOTTOM w0.089: v2(108.92,23.11) v3(108.11,23.11)
HDMI1_CK-_C: length 14.8
  TOP w0.089: TR12.2 108.07,17.54 108.01,17.48 107.35,17.48 107.23,17.36 107.23,17.07 107.35,16.95 108.98,16.95 110.19,18.16 112.49,18.16 114.65,16 v3(114.84,16) 114.84,15.81 115.66,14.99 115.84,14.99 116.17,15.32 HDMI2.12
  BOTTOM w0.089: v3(114.84,16) 114.59,16.26 v2(114.59,16.79)
HDMI1_CTRL_CLK_CPU: length 201.5
  TOP w0.102: v1(78.12,151.63) 77.79,151.97 CPU1.L13 ; v3(145.7,35.81) 145.65,35.76 145.65,34.67 143.01,32.03 142.01,32.03 141.74,31.76 140.72,31.76 138.18,29.21 R473.2 135.35,29.72 135.34,29.72 135.23,29.83 134.16,29.83 133.88,30.11 133.88,31.5 133.75,31.63 U17.38
  L4 w0.089: v1(78.12,151.63) 78.72,151.03 78.72,148.82 78.73,148.8
  L4 w0.127: v3(152.05,105.92) 151.42,106.55 151.42,107.12 148.05,110.49 126.4,110.49 113.06,123.83 112.64,123.83 87.91,123.82 77.21,134.53 77.21,134.84 76.55,135.5 76.55,145.38 78.63,147.46 78.63,148.46 78.73,148.56 78.73,148.8
  BOTTOM w0.102: v3(152.05,105.92) 152.56,105.92 v2(153.2,105.28) 153.63,104.85 153.63,101.06 154.82,99.86 154.82,90.68 152.46,88.32 152.46,62.46 153.86,61.06 153.86,56.79 152.26,55.19 152.26,51.64 150.25,49.63 150.25,45.15 150.66,44.74 150.66,40.77 v3(145.7,35.81)
HDMI1_CTRL_DATA_CPU: length 199.4
  TOP w0.102: v3(144.94,35.81) 145.17,35.59 145.17,34.87 142.81,32.51 141.81,32.51 141.54,32.24 140.52,32.24 138.89,30.61 R468.2 138.02,29.97 136.75,29.97 R467.2 135.31,30.31 134.48,30.31 134.36,30.43 134.36,31.44 134.15,31.66 U17.39 ; CPU1.L12 77.8,151.32 v1(78.13,150.98)
  L4 w0.089: v1(78.13,150.98) 78.54,150.58 78.54,148.73 78.49,148.69
  L4 w0.127: 78.49,148.69 78.42,148.62 78.42,147.55 76.04,145.17 76.04,135.29 76.7,134.63 76.7,134.32 87.7,123.32 112.85,123.32 126.19,109.98 147.84,109.98 150.91,106.91 150.91,106.3 v3(152.05,105.16)
  BOTTOM w0.102: v3(144.94,35.81) 150.17,41.05 150.17,44.54 149.77,44.95 149.77,49.83 151.32,51.38 151.32,54.94 153.37,56.99 153.37,60.86 151.98,62.26 151.98,88.52 154.34,90.88 154.34,99.66 152.79,101.21 v2(152.79,101.6) 152.79,104.42 v3(152.05,105.16)
HDMI1_D0+: length 87.2
  TOP w0.089: TR11.4 105.4,19.46 105.4,20.22 105.68,20.51 105.68,20.99 D13.1 D13.10 105.59,22.59 v3(105.06,23.11) 105.37,23.43 105.37,23.63 R488.2 ; SCA1.2 70.43,58.59 v3(70.65,58.8)
  L3 w0.102: v3(105.06,23.11) 105.06,22.83 105.24,22.66 105.72,22.66 105.85,22.53 105.85,22.02 105.6,21.77 104.49,21.77 102.77,23.48 102.77,23.63 103.48,24.33 103.48,24.78 103.17,25.1 102.59,25.1 101.95,24.45 101.8,24.45 101.36,24.89 100.48,24.89 95.87,29.51 95.87,33.47 94.98,34.36 94.98,37.11 94.68,37.4 93.92,37.4 93.78,37.53 93.78,37.78 93.91,37.91 94.68,37.91 94.98,38.2 94.98,38.78 94.68,39.08 91.6,39.08 91.47,39.2 91.47,39.46 91.6,39.58 94.68,39.58 94.98,39.88 94.98,40.56 87.5,48.03 76.07,48.03 74.9,49.21 74.9,51.67 74.6,51.97 74.2,51.97 74.1,52.07 74.1,52.37 74.2,52.47 74.6,52.47 74.9,52.77 74.9,53.35 74.6,53.64 74.2,53.64 74.1,53.74 74.1,54.05 74.2,54.15 74.6,54.15 74.9,54.45 74.9,55.44 74.6,55.73 73.16,55.73 73.03,55.86 73.03,56.11 73.16,56.24 74.6,56.24 74.9,56.54 74.9,57.47 73.64,58.72 70.72,58.72 v3(70.65,58.8)
  BOTTOM w0.089: v3(105.06,23.11) 104.86,23.32 v2(104.86,23.9)
HDMI1_D0+_C: length 17.8
  TOP w0.089: TR11.3 105.23,17.84 104.78,17.39 104.78,16.51 105.49,15.8 109.53,15.8 110.62,16.89 111.89,16.89 113.13,15.66 113.13,14.62 114.92,12.82 v3(115.12,12.82) HDMI4.13
  BOTTOM w0.089: v2(115.35,11.81) 115.12,12.04 v3(115.12,12.82)
HDMI1_D0-: length 87.2
  TOP w0.089: R489.2 105.72,23.58 105.72,23.22 v3(105.82,23.11) 106.09,22.85 D13.9 D13.2 106.03,21.04 106.03,20.37 105.74,20.08 105.74,19.46 TR11.1 ; SCA1.1 70.5,58.19 v3(70.65,58.04)
  L3 w0.102: v3(70.65,58.04) 71,58.39 73.51,58.39 74.57,57.33 74.57,56.67 74.47,56.57 73.02,56.57 72.7,56.25 72.7,55.72 73.02,55.4 74.47,55.4 74.57,55.3 74.57,54.58 74.47,54.48 74.06,54.48 73.77,54.19 73.77,53.61 74.06,53.31 74.47,53.31 74.57,53.21 74.57,52.91 74.47,52.8 74.06,52.8 73.77,52.51 73.77,51.93 74.06,51.64 74.47,51.64 74.57,51.53 74.57,49.07 75.94,47.7 87.37,47.7 94.65,40.42 94.65,40.02 94.55,39.91 91.46,39.91 91.14,39.59 91.14,39.07 91.46,38.75 94.55,38.75 94.65,38.64 94.65,38.34 94.55,38.24 93.77,38.24 93.45,37.92 93.45,37.4 93.78,37.07 94.55,37.07 94.65,36.97 94.65,34.23 95.54,33.34 95.54,29.37 100.35,24.56 101.23,24.56 101.67,24.12 102.08,24.12 102.73,24.77 103.03,24.77 103.15,24.65 103.15,24.47 102.44,23.76 102.44,23.35 104.35,21.44 105.73,21.44 106.18,21.88 106.18,22.76 v3(105.82,23.11)
  BOTTOM w0.089: v2(106.21,23.88) 105.82,23.5 v3(105.82,23.11)
HDMI1_D0-_C: length 18
  TOP w0.089: HDMI4.11 116.16,13.82 115.73,13.39 115.3,13.39 v3(115.1,13.59) 114.64,13.59 113.47,14.76 113.47,15.8 112.03,17.23 110.48,17.23 109.39,16.14 105.64,16.14 105.13,16.65 105.13,17.25 105.25,17.37 105.78,17.37 105.91,17.5 TR11.2
  BOTTOM w0.089: v2(116.37,13.46) 115.22,13.46 v3(115.1,13.59)
HDMI1_D1+: length 88.8
  TOP w0.089: SCA1.5 70.11,59.79 v3(70.65,60.33) ; R512.2 107.22,13.59 v3(107.48,13.34) 107.21,13.07 D14.2 D14.9 107.29,11.23 107.29,10.55 107.39,10.45 TR15.4
  L3 w0.102: v3(107.48,13.34) 107.48,14.38 106.51,15.34 106.51,18.12 104.19,20.44 101.06,23.57 100.19,23.57 94.72,29.03 94.72,32.38 92.67,34.43 92.67,35.95 89.26,39.36 89.26,40.27 89.56,40.57 90.46,40.57 90.58,40.69 90.58,40.95 90.46,41.07 89.56,41.07 89.26,41.37 89.26,44.17 86.54,46.89 72,46.89 71.71,47.18 71.71,48.56 71.58,48.69 71.33,48.69 71.2,48.56 71.2,47.18 70.91,46.89 70.13,46.89 67.04,49.98 67.04,55.4 69.17,57.53 69.17,59.74 69.76,60.33 v3(70.65,60.33)
  BOTTOM w0.089: v3(107.48,13.34) 107.48,14.3 v2(107.45,14.33)
HDMI1_D1+_C: length 16.1
  TOP w0.089: TR15.3 106.76,7.64 106.76,7.11 107.42,6.45 v3(107.65,6.45) 107.9,6.45 109.25,7.8 109.25,9.1 110.36,10.2 111.65,10.2 112.97,11.52 115.98,11.52 116.19,11.32 HDMI2.4
  BOTTOM w0.089: v3(107.65,6.45) 107.65,7.02 v2(107.88,7.25)
HDMI1_D1-: length 88.7
  TOP w0.089: SCA1.4 70.47,59.39 v3(70.65,59.56) ; TR15.1 108.07,9.87 107.73,10.21 107.73,10.6 107.63,10.69 107.63,11.23 D14.10 D14.1 107.71,12.94 108.11,13.34 v3(108.24,13.34) R513.2
  L3 w0.102: v3(70.65,59.56) 70.21,59.99 69.89,59.99 69.5,59.6 69.5,57.39 67.37,55.26 67.37,50.11 70.26,47.22 70.77,47.22 70.87,47.32 70.87,48.7 71.19,49.02 71.72,49.02 72.04,48.7 72.04,47.32 72.14,47.22 86.68,47.22 89.59,44.3 89.59,41.51 89.7,41.41 90.59,41.41 90.91,41.08 90.91,40.56 90.59,40.24 89.7,40.24 89.59,40.14 89.59,39.5 93,36.09 93,34.57 95.05,32.52 95.05,29.17 100.32,23.9 101.19,23.9 104.42,20.67 106.84,18.25 106.84,15.48 107.81,14.52 107.81,13.65 108.12,13.34 v3(108.24,13.34)
  BOTTOM w0.089: v2(107.88,12.52) 108.24,12.88 v3(108.24,13.34)
HDMI1_D1-_C: length 18.5
  TOP w0.089: v3(119.29,12.32) 119.29,12.32 HDMI2.6 116.06,12.32 115.6,11.86 112.83,11.86 111.51,10.54 110.21,10.54 108.91,9.24 108.91,7.95 107.89,6.92 107.44,6.92 107.11,7.25 107.11,7.47 107.31,7.67 107.94,7.67 108.07,7.8 TR15.2
  BOTTOM w0.089: v2(118.19,11.68) 118.43,11.91 118.88,11.91 v3(119.29,12.32)
HDMI1_D2+: length 86.4
  TOP w0.089: R510.2 105.42,13.93 105.42,13.56 v3(105.19,13.34) 105.31,13.34 105.71,12.94 D14.5 D14.6 105.82,11.21 105.82,10.61 105.4,10.19 105.4,9.68 TR14.4 ; v3(67.6,60.2) 67.87,60.2 68.27,60.59 SCA1.7
  L3 w0.102: v3(67.6,60.2) 68.03,59.77 68.23,59.77 68.69,59.3 68.69,57.9 66.56,55.77 66.56,49.78 70.08,46.25 86.49,46.25 88.78,43.97 88.78,39.16 92.19,35.75 92.19,34.23 94.13,32.29 94.13,28.95 94.24,28.83 99.99,23.09 100.86,23.09 105.24,18.7 105.24,14.95 103.87,13.58 103.87,12.95 104.08,12.75 104.27,12.55 105.52,12.55 105.62,12.65 105.62,13.02 105.3,13.34 v3(105.19,13.34)
  BOTTOM w0.089: v2(105.04,14.28) 105.19,14.13 v3(105.19,13.34)
HDMI1_D2+_C: length 18.7
  TOP w0.089: TR14.3 104.63,7.67 v3(104.63,6.45) 105.76,5.32 108.46,5.32 110.07,6.93 110.07,8.76 110.69,9.39 111.99,9.39 112.76,10.16 115.86,10.16 116.2,9.82 HDMI4.19
  BOTTOM w0.089: v3(104.63,6.45) v2(103.82,6.45)
HDMI1_D2-: length 86.3
  TOP w0.089: SCA1.6 68.35,60.19 v3(67.6,59.44) ; TR14.1 105.74,9.69 105.74,10.05 106.16,10.47 106.16,11.26 D14.7 D14.4 106.21,13.07 v3(105.95,13.34) 106.21,13.59 R511.2
  L3 w0.102: v3(105.95,13.34) 105.95,12.51 105.66,12.22 104.14,12.22 103.84,12.51 103.54,12.82 103.54,13.72 104.91,15.09 104.91,18.57 100.72,22.76 99.85,22.76 94.01,28.6 93.8,28.81 93.8,32.16 91.86,34.09 91.86,35.61 88.45,39.02 88.45,43.83 86.36,45.92 69.94,45.92 69.32,46.55 66.23,49.64 66.23,55.91 68.36,58.04 68.36,59.17 68.09,59.44 v3(67.6,59.44)
  BOTTOM w0.089: v3(105.95,13.34) 105.95,12.83 v2(105.65,12.52)
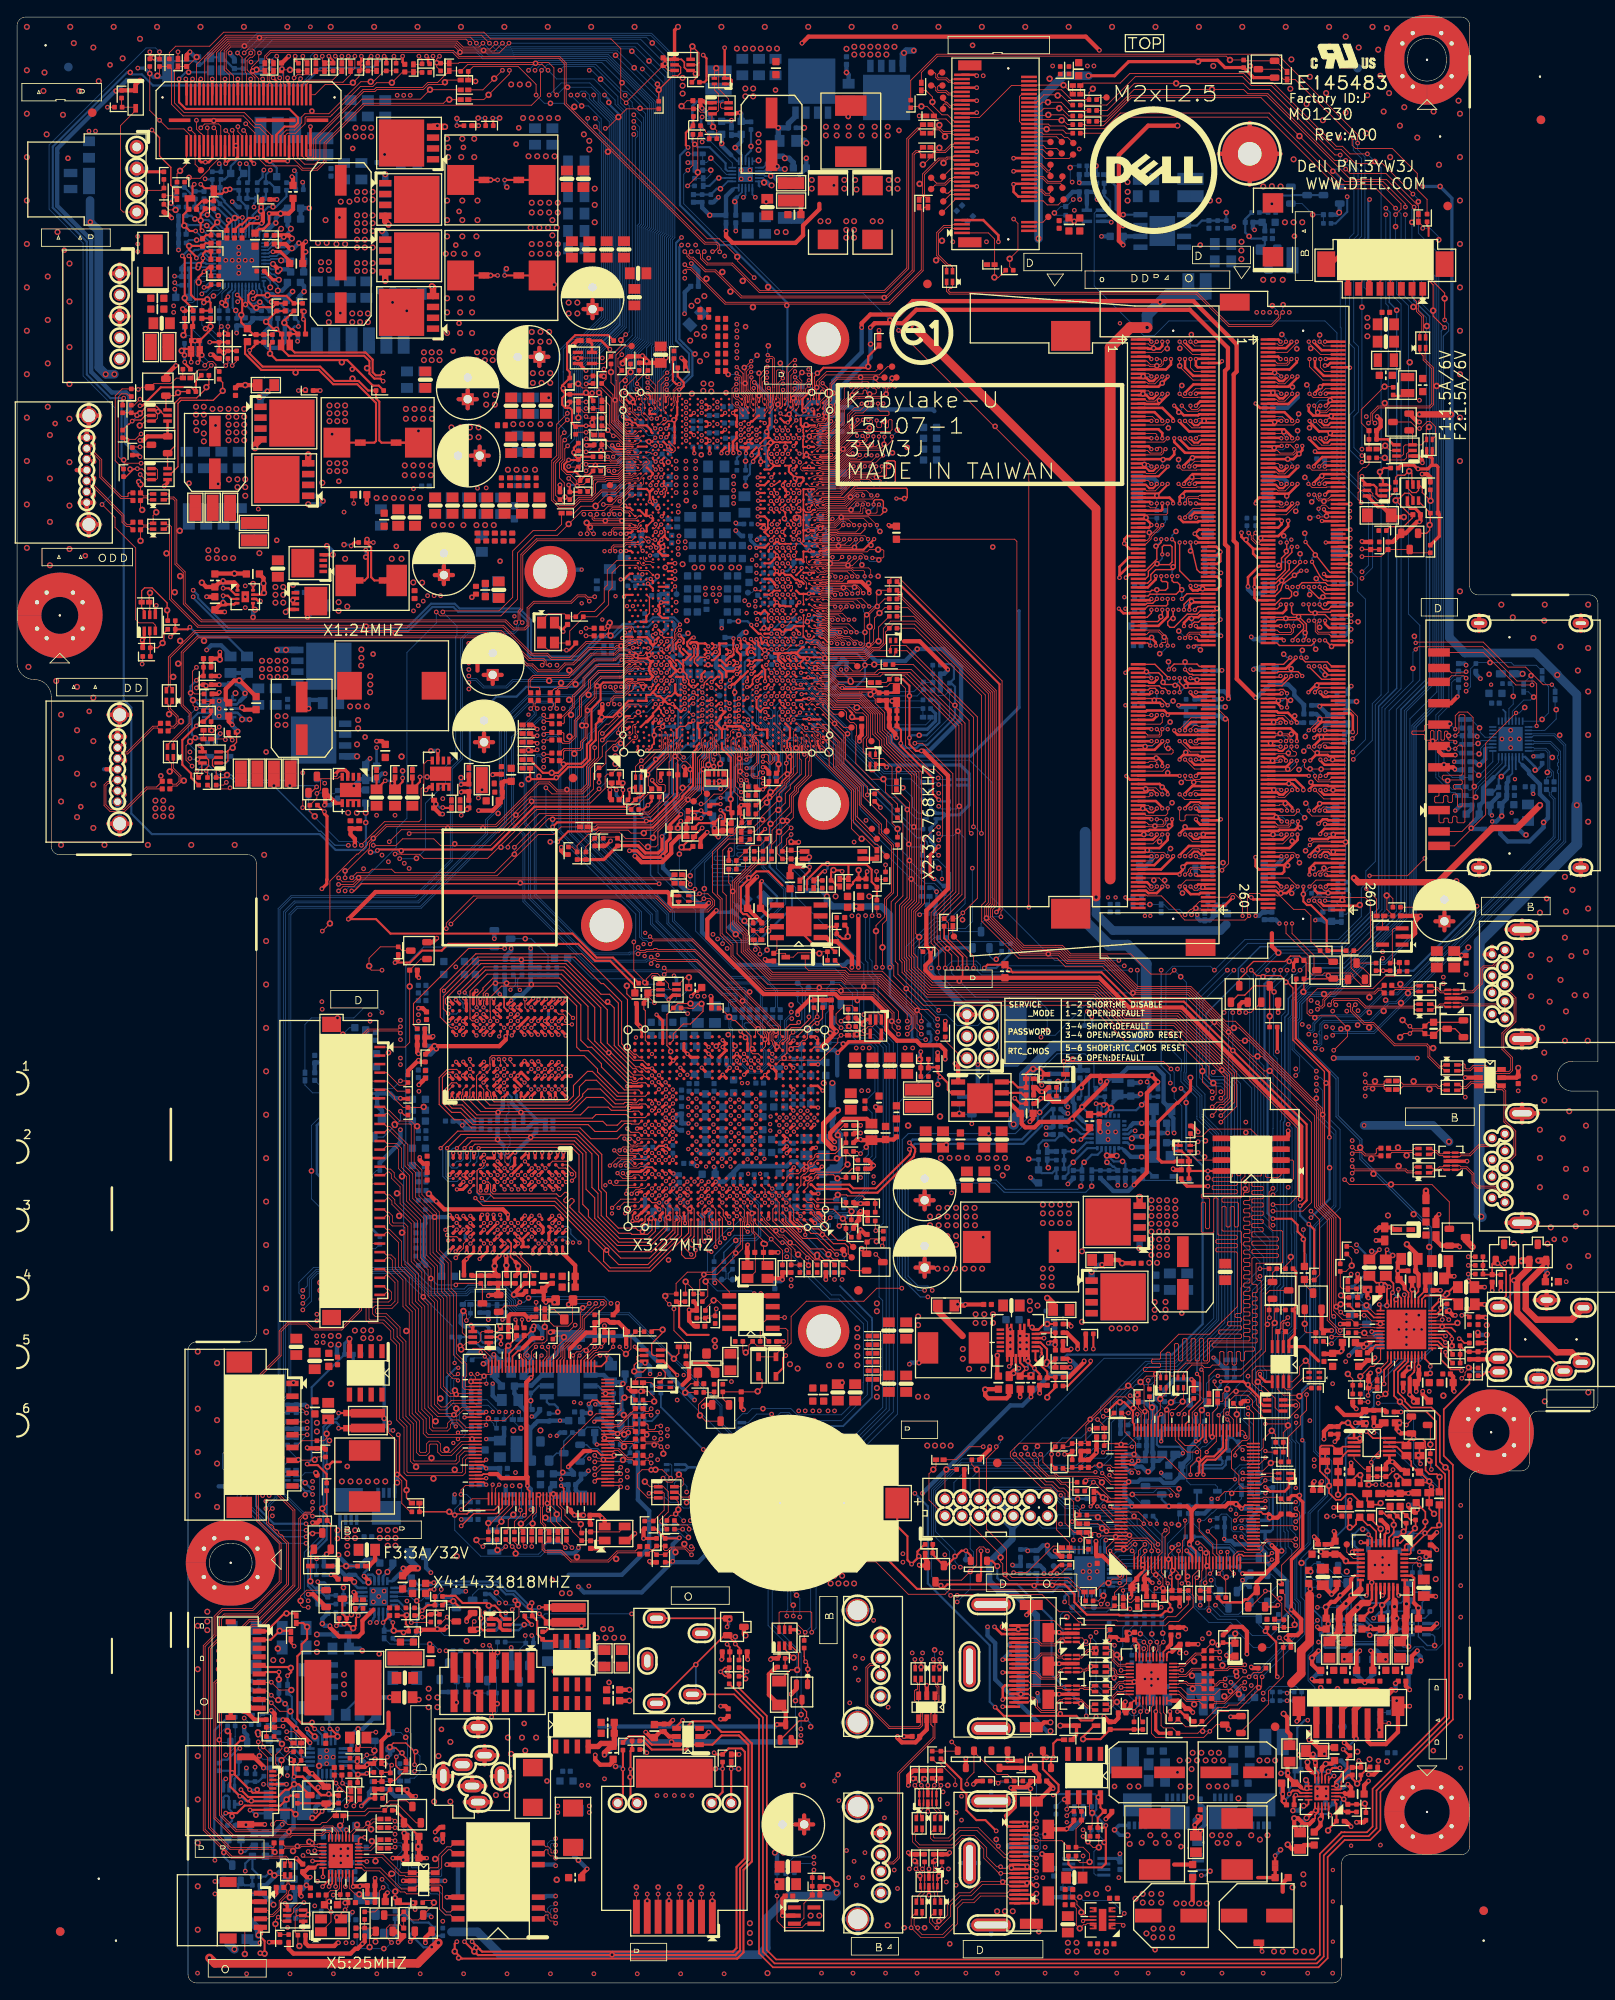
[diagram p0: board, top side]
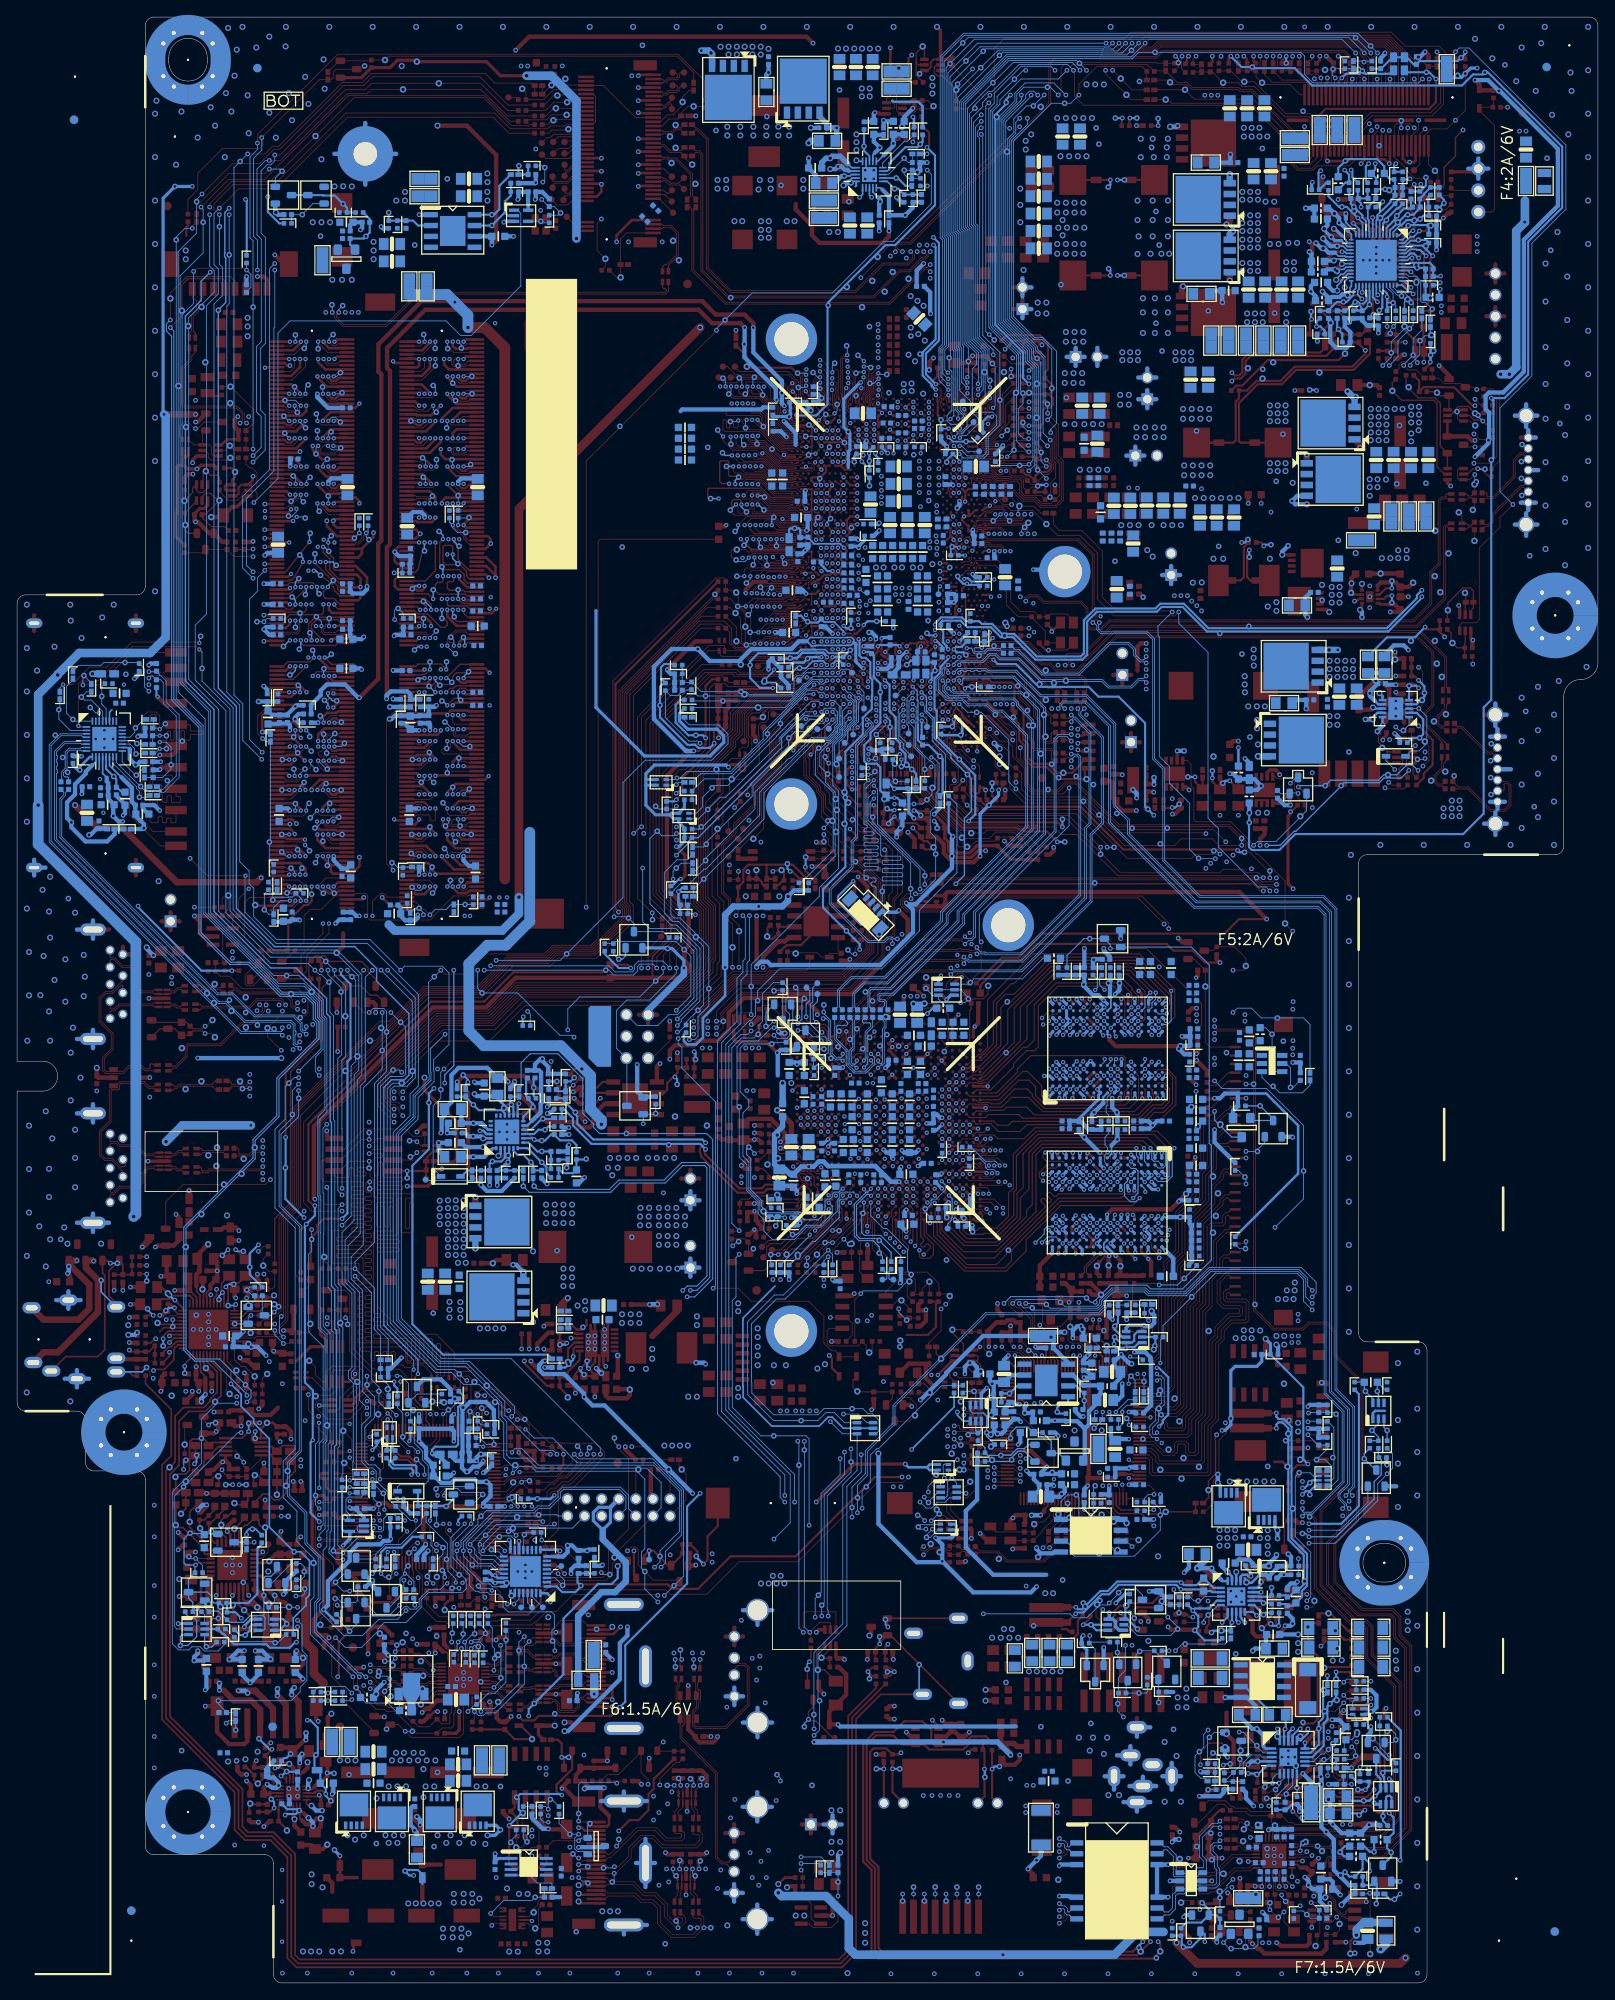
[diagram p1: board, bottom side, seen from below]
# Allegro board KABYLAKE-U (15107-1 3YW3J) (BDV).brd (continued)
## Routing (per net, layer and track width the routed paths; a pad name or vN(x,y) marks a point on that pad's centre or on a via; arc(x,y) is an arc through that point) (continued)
HDMI1_D2-_C: length 18.7
  TOP w0.089: HDMI4.17 116.2,10.82 115.88,10.5 112.62,10.5 111.84,9.73 110.55,9.73 109.72,8.9 109.72,7.07 108.31,5.66 105.9,5.66 105.39,6.17 v3(105.39,6.45) 105.29,6.45 104.97,6.77 104.97,7.45 105.09,7.57 105.74,7.57 105.91,7.74 TR14.2
  BOTTOM w0.089: v3(105.39,6.45) v2(106.21,6.45)
HDMI1_DATA_CPU_N0: length 288.8
  TOP w0.102: C230.1 140.13,32.94 141.25,32.94 141.56,33.25 ; v4(141.28,33.53) 141.56,33.25 ; 141.56,33.25 143.19,34.87 143.36,34.87 v3(143.67,35.18) ; v1(74.13,175.23) 74.13,175.53 74.3,175.69 CPU1.E55
  L3 w0.127: v3(143.67,35.18) 143.16,35.18 143.04,35.3 143.04,35.94 142.27,36.7 142.27,39.9 148.38,46.01 148.38,68.79 152.47,72.88 152.47,84.62 161.72,93.86 161.72,116.6 162.3,117.18 162.3,192.44 156.97,197.78 129.18,197.78 124.82,202.14 86.25,202.14 73.98,189.87 73.24,189.87 69.95,186.57 69.95,182.11 71.32,180.74 71.32,177.26 73.18,175.4 73.97,175.4 v1(74.13,175.23)
HDMI1_DATA_CPU_N1: length 277.7
  TOP w0.102: v1(74.73,177.06) 74.41,177.39 CPU1.E58 ; v3(141.38,35.56) 141.18,35.36 140.71,35.36 140.32,34.96 140.14,34.96 C223.1
  L3 w0.127: v3(141.38,35.56) 141.02,35.2 139.63,35.2 139.23,35.6 139.23,39.7 145.77,46.24 145.77,50.09 146.4,50.72 146.4,54.7 146.83,55.13 146.83,69.43 150.92,73.52 150.92,85.26 160.07,94.4 160.07,117.23 160.75,117.92 160.75,187.51 156.38,191.88 156.38,194.42 154.58,196.23 128.54,196.23 124.19,200.58 88.98,200.58 77.67,189.27 75.92,189.27 75.18,188.53 75.18,186.22 73.31,184.35 73.31,178.37 74.41,177.28 74.52,177.28 v1(74.73,177.06)
  BOTTOM w0.102: v3(141.38,35.56) 141.72,35.89 142.48,35.89 v2(142.73,35.89)
HDMI1_DATA_CPU_N2: length 291.6
  TOP w0.102: 141.05,36.75 141.56,36.75 141.81,37 143.46,37 v3(143.67,37.21) ; 141.05,36.75 v4(141.05,37.16) ; 141.05,36.75 140.13,36.75 C220.1 ; CPU1.F53 75.06,174.55 74.87,174.36 v1(74.76,174.36)
  L3 w0.127: v3(143.67,37.21) 143.42,36.96 143.16,36.96 143.05,37.07 143.05,38.48 149.16,44.59 149.16,68.44 153.25,72.53 153.25,84.29 162.49,93.54 162.49,116.28 163.08,116.86 163.08,192.81 157.34,198.55 129.5,198.55 125.14,202.91 85.58,202.91 81.11,198.45 80,198.45 72.04,190.5 72.04,189.76 68.96,186.68 68.96,179.54 69.42,179.08 70.08,179.08 70.44,178.72 70.44,176.99 72.9,174.54 74.58,174.54 v1(74.76,174.36)
HDMI1_DATA_CPU_N3: length 276.8
  TOP w0.102: CPU1.F56 75.06,176.46 v1(74.74,176.14) ; C215.1 140.62,38.86 v3(140.75,38.73)
  L3 w0.127: v3(140.75,38.73) 140.52,38.51 140.24,38.51 140.13,38.62 140.13,38.85 147.61,46.33 147.61,69.11 151.7,73.2 151.7,84.94 160.84,94.08 160.84,116.87 161.53,117.56 161.53,187.88 157.27,192.13 157.27,194.79 155.06,197 128.86,197 124.5,201.36 86.59,201.36 74.2,188.98 73.46,188.98 71.78,187.29 71.78,183.45 72.36,182.87 72.36,177.86 73.69,176.53 74.2,176.53 74.58,176.15 74.73,176.15 v1(74.74,176.14)
  BOTTOM w0.102: v2(140.56,39.53) 140.56,38.93 v3(140.75,38.73)
HDMI1_DATA_CPU_P0: length 288.8
  TOP w0.102: CPU1.F55 75.06,175.51 v1(74.79,175.24) ; v4(142.98,33.78) 142.69,34.07 ; 142.69,34.07 141.34,32.72 140.13,32.72 C232.1 ; 142.69,34.07 143.28,34.66 143.43,34.66 v3(143.67,34.42)
  L3 w0.127: v3(143.67,34.42) 143.56,34.53 143.43,34.53 142.77,35.19 142.77,35.83 142.01,36.59 142.01,40.01 148.12,46.12 148.12,68.9 152.2,72.99 152.2,84.73 161.45,93.97 161.45,116.71 162.03,117.29 162.03,192.33 156.86,197.51 129.07,197.51 124.71,201.87 86.36,201.87 74.09,189.6 73.35,189.6 70.21,186.46 70.21,182.22 71.58,180.85 71.58,177.37 73.29,175.67 74.3,175.67 74.73,175.24 v1(74.79,175.24)
HDMI1_DATA_CPU_P1: length 277.1
  TOP w0.102: v1(75.38,177.06) 75.06,177.39 CPU1.F58 ; v3(141.38,34.8) 141.38,34.92 141.17,35.14 140.8,35.14 140.41,34.75 140.13,34.75 C228.1
  L3 w0.127: v1(75.38,177.06) 74.9,177.55 74.52,177.55 73.58,178.48 73.58,184.24 75.45,186.11 75.45,188.42 76.03,189 77.78,189 89.09,200.31 124.08,200.31 128.43,195.96 154.47,195.96 156.12,194.31 156.12,191.77 160.48,187.4 160.48,118.03 159.8,117.34 159.8,94.51 150.66,85.37 150.66,73.63 146.57,69.54 146.57,55.24 146.13,54.81 146.13,50.83 145.5,50.2 145.5,46.35 138.96,39.81 138.96,35.49 139.51,34.93 141.25,34.93 v3(141.38,34.8)
  BOTTOM w0.102: v2(141.99,34.11) 141.99,34.14 141.38,34.75 v3(141.38,34.8)
HDMI1_DATA_CPU_P2: length 291.5
  TOP w0.102: 142.65,36.79 141.9,36.79 141.65,36.54 140.14,36.54 C221.1 ; 142.65,36.79 v4(142.65,36.4) ; 142.65,36.79 143.33,36.79 v3(143.67,36.45) ; v1(75.4,174.31) 75.4,174.46 CPU1.G53
  L3 w0.127: v3(143.67,36.45) 143.43,36.69 143.05,36.69 142.78,36.96 142.78,38.59 148.89,44.7 148.89,68.55 152.98,72.64 152.98,84.4 162.22,93.65 162.22,116.39 162.81,116.97 162.81,192.7 157.22,198.29 129.39,198.29 125.03,202.65 85.69,202.65 81.22,198.18 80.11,198.18 72.31,190.39 72.31,189.65 69.22,186.57 69.22,179.65 69.53,179.35 70.19,179.35 70.71,178.83 70.71,177.1 73.01,174.8 74.91,174.8 75.4,174.32 v1(75.4,174.31)
HDMI1_DATA_CPU_P3: length 277.4
  TOP w0.102: C219.1 140.03,38.2 140.52,38.2 v3(140.75,37.97) ; CPU1.G56 75.71,176.46 v1(75.39,176.14)
  L3 w0.127: v1(75.39,176.14) 75.35,176.14 74.9,176.59 74.51,176.59 74.31,176.8 73.8,176.8 72.63,177.97 72.63,182.98 72.04,183.56 72.04,187.18 73.57,188.71 74.32,188.71 86.7,201.09 124.39,201.09 128.75,196.74 154.95,196.74 157.01,194.68 157.01,192.02 161.26,187.77 161.26,117.67 160.57,116.98 160.57,94.19 151.43,85.05 151.43,73.31 147.34,69.22 147.34,46.44 139.86,38.96 139.86,38.51 140.13,38.24 140.48,38.24 v3(140.75,37.97)
  BOTTOM w0.102: v2(141.97,37.64) 141.08,37.64 v3(140.75,37.97)
HDMI1_DATA_IC_N0: length 4.2
  TOP w0.102: C230.2 138.72,33.09 138.51,33.09 138.44,33.16 136.91,33.16 135.91,34.16 U17.2
HDMI1_DATA_IC_N1: length 3.9
  TOP w0.102: U17.5 135.91,35.36 136.01,35.27 136.84,35.27 137.08,35.03 138.63,35.03 C223.2
HDMI1_DATA_IC_N2: length 4.1
  TOP w0.102: U17.7 135.91,36.16 136.01,36.07 136.74,36.07 137.48,36.81 138.63,36.81 C220.2
HDMI1_DATA_IC_N3: length 5.7
  TOP w0.102: v4(139.89,39.85) 138.91,38.87 C215.2 138.63,38.59 137.88,38.59 136.56,37.27 136.01,37.27 135.91,37.36 U17.10
HDMI1_DATA_IC_P0: length 4.5
  TOP w0.102: U17.1 136.01,33.76 136.82,32.94 137.75,32.94 ; C232.2 138.35,32.94 137.75,32.94 ; v4(137.75,32.59) 137.75,32.94
HDMI1_DATA_IC_P1: length 4.3
  TOP w0.102: v4(137.57,34.42) 137.57,34.82 ; 137.57,34.82 136.99,34.82 136.75,35.05 136.01,35.05 135.91,34.96 U17.4 ; 137.57,34.82 138.51,34.82 C228.2
HDMI1_DATA_IC_P2: length 4.6
  TOP w0.102: 137.21,36.23 137.57,36.6 138.51,36.6 C221.2 ; 137.21,36.23 136.83,35.85 136.01,35.85 135.91,35.76 U17.6 ; 137.21,36.23 v4(137.5,35.94)
HDMI1_DATA_IC_P3: length 4.7
  TOP w0.102: C219.2 138.51,38.37 137.97,38.37 137.5,37.9 ; 137.5,37.9 136.65,37.05 136.01,37.05 135.91,36.96 U17.9 ; 137.5,37.9 v4(137.75,37.64)
HDMI1_OUT_HPD: length 193.5
  TOP w0.102: U17.3 136.2,34.56 137,33.76 138.71,33.76 140.16,33.76 140.72,34.32 141.92,34.32 143.42,35.81 v3(144.18,35.81) 144.68,36.32 145.64,36.32 R458.1 ; CPU1.L9 77.82,149.37 v1(78.13,149.67)
  L4 w0.127: v3(152.05,104.39) 150.66,105.79 150.66,106.58 147.51,109.73 126.08,109.73 112.83,122.99 87.67,122.99 76.45,134.21 76.45,134.52 75.79,135.18 75.79,145.23 77.4,146.84 77.4,148.95 v1(78.13,149.67)
  BOTTOM w0.102: v3(152.05,104.39) v2(152.05,103.5) 152.05,101.35 154.11,99.29 154.11,90.98 151.75,88.61 151.75,62.16 153.14,60.77 153.14,57.09 151.09,55.03 151.09,51.49 149.54,49.94 149.54,44.85 149.94,44.44 149.94,41.19 145.03,36.27 144.75,36.27 144.29,35.81 v3(144.18,35.81)
HDMI1_SCL: length 90.6
  TOP w0.102: R504.2 123.35,20.07 v3(122.84,19.56) ; v3(59.47,51.05) 59.22,51.31 R417.2
  L3 w0.127: v3(122.84,19.56) 122.72,19.56 117.38,24.89 109.26,24.89 106.97,27.18 102.94,27.18 101.38,28.74 101.38,30.53 96.79,35.11 96.79,41.31 88.04,50.06 84.84,50.06 80.82,54.09 v3(78.79,54.09)
  L4 w0.127: v3(59.47,51.05) 59.47,53.11 61.07,54.71 61.07,55.91 61.7,56.53 72.54,56.53 74.46,54.61 78.25,54.61 78.63,54.23 78.65,54.23 v3(78.79,54.09)
  BOTTOM w0.102: v3(78.79,54.09) 79.41,54.71 v2(79.61,54.71)
HDMI1_SDA: length 88.5
  TOP w0.102: R418.2 v3(60.23,51.05)
  L3 w0.127: v3(78.01,54.06) 78.5,53.58 80.61,53.58 84.63,49.56 87.83,49.56 96.29,41.1 96.29,34.9 100.87,30.32 100.87,28.53 102.73,26.67 106.76,26.67 109.05,24.38 117.13,24.38 122.72,18.8 v1(122.84,18.8)
  L4 w0.127: v3(78.01,54.06) 77.97,54.1 74.25,54.1 72.33,56.03 65.2,56.03 v3(60.23,51.05)
  BOTTOM w0.102: v1(122.84,18.8) 123.35,18.8 123.73,19.18 R848.2 ; v3(78.01,54.06) 77.21,54.86 v2(77.07,54.86)
HDMI_5V: length 18.7
  TOP w0.305: 115.73,19.56 115.73,18.54 115.95,18.32 HDMI2.18
  TOP w0.508: 115.73,19.56 116.75,20.57 116.75,22.38 v3(116.29,22.83) 116.34,22.83 116.42,22.91 118.07,22.91 118.59,23.43 R495.1 C250.1 119.6,24.32 119.1,24.83 D11.1 117.59,25.16 R485.1 117.43,25.16 D10.3
  BOTTOM w0.508: v3(116.29,22.83) 118.5,22.83 v2(118.6,22.73)
HDMI_DET_SIO: length 20.2
  TOP w0.102: KBC1.9 133.94,47.98 134.45,47.47 134.45,46.94 v1(134.65,46.74)
  BOTTOM w0.102: v1(134.65,46.74) 134.78,46.74 135.47,46.05 136.79,46.05 137.05,45.8 137.96,44.89 137.96,44.06 138.27,43.74 139.01,43.74 139.29,44.02 139.67,44.02 140.79,42.9 145.03,42.9 Q70.D 145.32,41.91 v2(146.08,41.15) 147.1,42.16 147.1,42.61 R791.2
HDMI_HDCP_READY: length 97.6
  TOP w0.102: SCA1.22 67.76,66.59 63.66,62.48 v1(63.66,58.93) ; v3(111.16,23.24) 111.16,23.82 111.98,24.64 U21.1 112.3,26.84 112.3,26.71 114.63,24.38 115.92,24.38 R494.1 R495.2
  L3 w0.127: v1(63.66,58.93) 63.22,58.48 63.22,51.21 69.1,45.33 85.89,45.33 87.96,43.26 87.96,38.82 91.37,35.41 91.37,33.89 93.3,31.95 93.3,28.6 95.66,26.24 v3(95.66,23.62)
  L4 w0.127: v3(95.66,23.62) 95.75,23.71 110.69,23.71 v3(111.16,23.24)
  BOTTOM w0.102: v2(96.07,24.36) 95.66,23.95 v3(95.66,23.62)
HDMI_HPDET: length 13
  TOP w0.102: HDMI2.19 119.18,18.82 v3(119.29,18.92) ; R494.2 115.07,23.62 v3(114.82,23.37) 114.56,23.62 R493.1
  BOTTOM w0.102: v3(114.82,23.37) 114.92,23.47 119.03,23.47 119.29,23.22 v2(119.29,19.81) v3(119.29,18.92)
HDMI_IN_DET#_R: length 4.5
  BOTTOM w0.102: v2(147.78,44.97) 147.5,44.97 147.04,44.51 Q70.S 145.38,44.51 145.13,44.77 R782.1
HDMI_LANE0_DN: length 11.4
  TOP w0.102: TR10.2 126,32.61 125.76,32.38 125.34,32.38 124.58,33.13 124.37,33.13 124.24,33.26 U18.2 U18.9 122.44,33.26 122.31,33.13 121.99,33.13 121.57,32.71 121.57,32.02 121.41,31.86 119.92,31.86 119.41,32.37 119.41,33.01 118.99,33.43 118.71,33.43 118.32,33.82 HDMI1.3
HDMI_LANE0_DP: length 11.4
  TOP w0.102: HDMI1.1 118.32,32.82 118.71,33.21 118.91,33.21 119.2,32.92 119.2,32.28 119.83,31.65 121.5,31.65 121.79,31.93 121.79,32.62 122.08,32.91 122.31,32.91 122.44,32.78 U18.10 U18.1 124.23,32.78 124.37,32.91 124.49,32.91 125.25,32.16 125.76,32.16 126,31.93 TR10.3
HDMI_LANE0_IC_DN: length 4.2
  TOP w0.102: U17.29 129.56,34.16 129.48,34.08 128.73,34.08 128.13,33.48 128.13,32.58 127.92,32.38 127.8,32.38 127.56,32.61 TR10.1
HDMI_LANE0_IC_DP: length 4.5
  TOP w0.102: v4(128.71,32.87) 128.34,32.87 ; 128.34,32.87 128.34,32.49 128.01,32.16 127.8,32.16 127.56,31.93 TR10.4 ; 128.34,32.87 128.34,33.39 128.82,33.86 129.48,33.86 129.58,33.76 U17.30
HDMI_LANE1_DN: length 9.3
  TOP w0.102: TR9.2 126,34.77 125.76,34.53 124.95,34.53 124.84,34.65 124.37,34.65 124.23,34.78 U18.5 U18.6 122.44,34.78 122.31,34.65 121.83,34.65 121.55,34.93 118.71,34.93 118.32,35.32 HDMI1.6
HDMI_LANE1_DP: length 9.3
  TOP w0.102: TR9.3 125.94,34.09 125.7,34.32 124.86,34.32 124.75,34.43 124.37,34.43 124.23,34.3 U18.4 U18.7 122.44,34.3 122.31,34.43 121.74,34.43 121.46,34.71 118.71,34.71 118.32,34.32 HDMI1.4
HDMI_LANE1_IC_DN: length 3.3
  TOP w0.102: TR9.1 127.56,34.77 127.8,34.53 128.29,34.53 128.43,34.67 128.43,34.76 128.95,35.28 129.48,35.28 129.56,35.36 U17.26
HDMI_LANE1_IC_DP: length 3.3
  TOP w0.102: U17.27 129.58,34.96 129.48,35.06 129.04,35.06 128.65,34.67 128.65,34.58 128.38,34.32 127.82,34.32 127.59,34.09 TR9.4
HDMI_LANE2_DN: length 10.1
  TOP w0.102: TR6.2 125.62,37.05 125.39,36.82 125.12,36.82 125,36.71 124.64,36.71 124.51,36.84 U16.7 U16.4 122.44,36.84 122.31,36.71 122.12,36.71 121.83,36.41 121.83,36.07 121.52,35.76 119.92,35.76 119.25,36.43 118.71,36.43 118.32,36.82 HDMI1.9
HDMI_LANE2_DP: length 10.1
  TOP w0.102: HDMI1.7 118.32,35.82 118.71,36.21 119.16,36.21 119.83,35.55 121.61,35.55 122.04,35.98 122.04,36.32 122.21,36.49 122.31,36.49 122.44,36.36 U16.5 U16.6 124.51,36.36 124.64,36.49 125.09,36.49 125.21,36.6 125.39,36.6 125.62,36.37 TR6.3
HDMI_LANE2_IC_DN: length 3.4
  TOP w0.102: TR6.1 127.54,37.05 127.77,36.82 128.36,36.82 128.65,36.53 128.65,36.28 128.85,36.08 129.75,36.08 129.83,36.16 U17.24
HDMI_LANE2_IC_DP: length 3.4
  TOP w0.102: U17.25 129.85,35.76 129.75,35.86 128.76,35.86 128.43,36.2 128.43,36.44 128.27,36.6 127.8,36.6 127.56,36.37 TR6.4
HDMI_LANE3_DN: length 9.9
  TOP w0.102: TR5.2 125.99,39.21 125.75,38.98 125.25,38.98 124.49,38.23 124.37,38.23 124.24,38.36 U16.10 U16.1 122.44,38.36 122.31,38.23 121.9,38.23 121.53,38.59 119.83,38.59 119.16,37.93 118.71,37.93 118.32,38.32 HDMI1.12
HDMI_LANE3_DP: length 9.9
  TOP w0.102: TR5.3 126,38.53 125.76,38.76 125.34,38.76 124.58,38.01 124.37,38.01 124.23,37.88 U16.9 U16.2 122.44,37.88 122.31,38.01 121.81,38.01 121.45,38.38 119.92,38.38 119.25,37.71 118.71,37.71 118.32,37.32 HDMI1.10
HDMI_LANE3_IC_DN: length 4.5
  TOP w0.102: U17.21 129.83,37.36 129.75,37.28 128.92,37.28 128.34,37.86 128.34,38.38 ; 128.34,38.38 128.34,38.75 128.11,38.98 127.82,38.98 127.59,39.21 TR5.1 ; 128.34,38.38 v4(128.71,38.38)
HDMI_LANE3_IC_DP: length 4.2
  TOP w0.102: TR5.4 127.56,38.53 127.8,38.76 128.02,38.76 128.13,38.66 128.13,37.77 128.83,37.06 129.75,37.06 129.85,36.96 U17.22
HDMI_OUT_DDC_VCC: length 9.8
  TOP w0.254: R472.1 R471.1 C237.1 126.79,28.52 v4(124.75,28.52) 124.75,28.8 126.04,30.1 D9.K
HDMI_SCL_IN: length 9.1
  TOP w0.102: HDMI2.15 119.1,16.82 v3(119.29,16.64) 122.27,16.64 R508.1
  BOTTOM w0.102: v2(117.97,18.64) 118.23,18.38 U37.1 118.97,16.95 v3(119.29,16.64)
HDMI_SCL_IN_C: length 11.2
  TOP w0.102: 124.24,21.72 124.24,20.38 R504.1 C254.1 124.56,18.67 123.92,18.03 R508.2 124.75,15.88 125.51,15.11 v4(125.51,14.15) 125.43,14.07 124.39,14.07 123.92,14.54 R509.2
HDMI_SDA_IN: length 9.5
  TOP w0.102: HDMI2.16 119.21,17.32 v3(119.29,17.4)
  BOTTOM w0.102: R849.1 121.57,18.67 v2(120.3,17.4) v3(119.29,17.4) 119.74,16.94 119.74,15.69 119.42,15.37 118.54,15.37 U37.2
HDMI_SDA_IN_C: length 7.1
  TOP w0.102: 122.97,21.72 122.97,20.45 v3(122.84,20.32)
  BOTTOM w0.102: R847.2 C594.1 R848.1 123.16,20.64 v3(122.84,20.32) 122.84,21.21 v2(122.59,21.46) 122.4,21.46 R849.2
HP_MUTE: length 145.7
  TOP w0.102: R330.2 68.74,74.8 v1(68.36,74.42) 68.21,74.42 67.78,73.99 67.51,73.99 66.37,72.85 SCA1.36
  L4 w0.127: v3(159.29,67.82) 159.25,67.78 159.25,64.19 158.19,63.13 155.79,63.13 154.31,64.6 144.62,64.6 144.33,64.9 141.74,64.9 141.43,64.58 130.6,64.58 129.97,65.21 126.76,65.21 126.74,65.2 126.14,65.2 125.83,65.51 125.08,65.51 124.09,64.52 91.33,64.52 91.11,64.73 89.09,64.73 86.14,67.68 86.14,68.84 81.32,73.66 69.73,73.66 68.97,74.42 v1(68.36,74.42)
  BOTTOM w0.102: v3(159.29,67.82) 161.59,67.82 163.43,65.98 v2(163.43,63.73) 163.43,60.76 165.64,58.55 165.72,58.55 166.83,57.44 166.83,39.69 166.11,38.96 164.9,38.96 164.55,39.32 163.56,39.32 163.08,38.84 161.48,38.84 160.75,39.56 R801.1
HP_MUTE_D: length 8.2
  BOTTOM w0.152: R789.2 165.32,43.24 164.75,42.67 164.24,42.67 163.99,42.42 163.99,40.51 165.03,39.47 v2(165.9,39.47) 165.9,40.51 165.66,40.75 Q72.3
HP_MUTE_L: length 3
  BOTTOM w0.152: Q72.4 163.05,39.55 v2(162.85,39.34) 162.8,39.29 162.22,39.29 R801.2
HPOL_CON: length 16.1
  TOP w0.203: UHS1.1 173.4,79.54 174.25,80.39 174.25,83.31 Q26.1 172.63,84.11 C116.1 ; R280.2 R281.2 R294.2 171.61,82.87 C116.1 ; C116.1 R297.1
  BOTTOM w0.203: UHS1.1 175.17,80.86 v2(175.17,82.19)
HPOR_CON: length 37.2
  TOP w0.203: v3(174.09,84.2) 174.4,84.52 Q26.2 175.01,83.08 174.73,82.8 174.73,74.09 175.55,73.28 179.31,73.28 UHS1.2 ; R344.2 R340.2 R338.2 169.58,73.85 R341.1 C137.1 171.67,73.85 v3(171.86,74.04)
  L3 w0.203: v3(174.09,84.2) 173.77,84.2 170.85,81.28 170.85,75.06 v3(171.86,74.04)
  BOTTOM w0.203: v3(174.09,84.2) v2(173.26,84.2)
HPOUT-JD: length 6.4
  TOP w0.203: UHS1.6 171.92,71.49 171.48,71.06 R346.1
  BOTTOM w0.203: v2(169.84,72.01) 170.36,71.49 UHS1.6
HPOUT-L: length 19
  TOP w0.203: v3(169.04,71.64) 168.9,71.78 167.77,71.78 166.66,72.9 166.66,74.19 166.2,74.65 U11.26 ; R294.1 v3(169.83,82.93)
  L3 w0.203: v3(169.04,71.64) 169.07,71.67 169.07,73.28 170.26,74.47 170.26,82.5 v3(169.83,82.93)
  BOTTOM w0.203: v3(169.83,82.93) v2(169.83,82.12)
HPOUT-R: length 3.1
  TOP w0.203: R340.1 167.99,73.68 167.25,74.42 166.95,74.42 166.66,74.72 166.32,75.05 U11.27
HSI_C_DN8: length 6.8
  BOTTOM w0.102: C399.1 178.98,141 179.08,141.1 179.41,141.1 179.57,141.26 179.57,141.6 179.31,141.86 ; 179.31,141.86 v2(179.08,141.63) ; 179.31,141.86 179.15,142.01 179.15,143.92 178.84,144.23 177.55,144.23 177.46,144.14 U28.8
HSI_C_DP8: length 6.7
  BOTTOM w0.102: U28.7 177.46,144.54 177.55,144.45 178.93,144.45 179.37,144.01 179.37,143.38 ; 179.37,143.38 179.37,142.1 179.79,141.69 179.79,140.61 C398.1 ; 179.37,143.38 v2(179.66,143.38)
HSI_LAN_DN1_R: length 5.5
  TOP w0.102: v4(32.29,15.43) 32.29,15.77 ; 32.29,15.77 33.08,15.77 33.26,15.95 35.11,15.95 35.2,15.86 U23.18 ; 32.29,15.77 31.36,15.77 C259.1
HSI_LAN_DP1_R: length 5.5
  TOP w0.102: C257.1 31.35,15.99 32.99,15.99 33.17,16.17 34.2,16.17 ; v4(34.2,16.51) 34.2,16.17 ; 34.2,16.17 35.11,16.17 35.2,16.26 U23.17
I2CC_SCL_PU: length 7.8
  TOP w0.102: R286.2 92.6,84.01 v4(91.4,85.22) 91.04,85.58 91.04,85.78 89.56,87.26 89.16,87.26 GPU1.A9
I2CC_SDA_PU: length 10.3
  TOP w0.102: GPU1.B9 87.12,89.79 87.46,89.44 87.46,89.29 89.25,87.5 89.7,87.5 90.84,86.36 91.09,86.36 92.49,84.96 v3(92.49,84.84) 92.74,84.84 93.57,84.01 R287.2
  BOTTOM w0.102: v3(92.49,84.84) 92.62,84.71 v2(92.62,83.95)
I2CS_SCL_G: length 45.7
  TOP w0.102: GPU1.D9 87.12,91.67 v1(87.52,91.27)
  L3 w0.127: v3(90.08,85.72) 90.29,85.94 90.29,88.5 v1(87.52,91.27)
  BOTTOM w0.102: R703.2 89.57,85.22 v3(90.08,85.72) 95.31,80.49 96.35,80.49 99.53,77.31 99.53,70.09 99.5,70.06 99.5,68.83 96.46,65.79 v2(93.25,65.79) 91.29,65.79 90.35,66.73 89.34,66.73 88.17,65.55 Q60.1
I2CS_SDA_G: length 47.5
  TOP w0.102: GPU1.D8 87.96,91.7 v1(88.38,91.29)
  L3 w0.127: v1(88.38,91.29) 88.38,90.74 90.52,88.59 90.52,85.41 v3(90.08,84.96)
  BOTTOM w0.102: v3(90.08,84.96) 90.58,84.45 R702.2 91.16,84.01 91.9,83.27 91.9,83.22 95.11,80.01 96.15,80.01 99.05,77.11 99.05,70.29 99.02,70.26 99.02,69.03 96.46,66.47 91.28,66.47 90.55,67.21 87.31,67.21 v2(87.28,67.18) 86.01,67.18 85.42,66.6 84.91,66.6 84.13,65.82 84.13,64.62 84.51,64.25 Q60.4
IMS: length 171.5
  TOP w0.102: v3(44.86,105.54) 45.56,105.54 R255.1 45.44,105.03 44.71,105.03 43.24,106.5 LVDS1.4 ; v1(143.29,52.2) 143.29,52.18 143.97,51.5 KBC1.35
  L3 w0.127: v3(37.79,88.39) 37.79,85.81 47.2,76.39 47.2,69.68 50.27,66.61 54.46,66.61 54.71,66.36 56.74,66.36 v1(57.18,66.8)
  L4 w0.127: v1(143.29,52.2) 144.24,53.15 144.24,55.93 141.82,58.36 132.53,58.36 131.65,57.48 124.07,57.48 123.17,58.38 104.62,58.38 103.79,59.22 83.93,59.22 81.22,61.94 75.01,61.94 72.24,64.71 66.34,64.71 64.8,63.17 57.9,63.17 54.45,66.62 54.45,66.99 54.71,67.25 56.74,67.25 v1(57.18,66.8)
  BOTTOM w0.102: R731.2 56.99,66.61 v1(57.18,66.8) ; v3(44.86,105.54) 43.98,104.65 38.77,104.65 34.45,100.33 v2(34.45,95) 34.45,91.73 v3(37.79,88.39)
IMS_SCALAR: length 5.7
  TOP w0.102: v1(54.9,65.28) 54.79,65.39 53.63,65.39
  BOTTOM w0.102: R731.1 R736.2 55.79,65.21 55.79,65.41 v2(55.15,66.04) 54.9,65.79 v1(54.9,65.28) 54.64,65.02 R735.1
INIT_3V: length 4.7
  TOP w0.102: LPC1.2 108.59,59.91 v4(108.75,60.07) R381.2
ISEN1: length 17
  TOP w0.254: v3(34.83,29.72) 34.2,30.35 33.32,30.35 32.8,30.87 32.8,38.23 33.31,38.73 33.31,39.62 33.94,40.26 v4(33.94,41.66) 33.5,42.1 R446.2
  BOTTOM w0.254: U36.17 35.73,28.95 34.96,29.72 v3(34.83,29.72)
ISEN2: length 15.3
  TOP w0.254: v3(32.42,39.41) 32.04,39.79 R452.2 ; v4(34.83,28.83) v3(33.94,29.72)
  L4 w0.254: v3(32.42,39.41) 32.42,30.1 32.8,29.72 v3(33.94,29.72)
  BOTTOM w0.254: v3(33.94,29.72) 33.94,29.21 34.78,28.37 U36.16
ISEN3: length 8.5
  BOTTOM w0.254: R814.2 32.16,33.46 32.16,30.99 32.67,30.48 v2(32.67,29.76) 32.67,27.87 33.63,26.92 U36.14
ISEN4: length 9.6
  BOTTOM w0.254: U36.13 33.41,26.42 32.09,27.74 32.09,30.34 31.66,30.78 31.66,32.36 v2(31.36,32.66) 30.64,33.38 R815.2
ISET: length 13.2
  TOP w0.102: U17.34 132.15,31.84 v3(132.24,31.75)
  BOTTOM w0.102: v3(132.24,31.75) 131.41,32.58 R820.1 131.17,32.58 129.83,33.91 129.07,33.91 127.8,35.18 v2(127.8,40.13) R797.2
ISP_CLK1: length 7.4
  TOP w0.102: Q39.6 77.72,58.05 77.96,58.29 77.96,58.98 v4(77.45,59.49) 77.45,59.37 76.66,58.59 76.07,58.59 v3(75.6,59.05)
  BOTTOM w0.102: RN19.1 76.01,59.47 v3(75.6,59.05) 75.04,58.5 Q65.6
ISP_DAT1: length 14.4
  TOP w0.102: Q39.3 73.82,56.75 72.63,57.95 72.63,59.54 73.13,60.05 v4(74.71,60.05) 75.5,60.05 v3(76.49,59.05)
  BOTTOM w0.102: RN19.2 76.07,60.71 76.49,60.71 76.61,60.58 76.61,59.18 v3(76.49,59.05) 76.09,58.66 76.09,57.02 76.36,56.75 Q65.3
ISW: length 5.8
  TOP w0.254: v3(36.61,29.72) 36.74,29.72 37.5,28.96 v4(37.5,28.83) 36.22,28.83 C242.1
  BOTTOM w0.254: U36.19 36.73,29.6 v3(36.61,29.72) 36.53,29.79 R824.2
ISW_1: length 5
  BOTTOM w0.254: Q75.3 41.31,34.67 38.46,31.83 R824.1
  vias: v2(42.37,38.49)
ITP_PMODE: length 169.8
  TOP w0.102: v3(45.88,134.47) 45.98,134.57 56.39,134.57 60.22,138.4 66.81,138.4 v3(68.11,139.7) ; v1(74.73,149.63) 74.41,149.31 CPU1.E8
  L3 w0.127: v3(45.88,134.47) 44.46,133.05 43.26,133.05 40.77,135.53 38.74,135.53 36.44,137.83 36.44,137.99 36.12,138.32 34.73,138.32 34.07,138.98 23.21,138.98 16.04,146.15 16.04,149.86 11.76,154.14 11.76,187.01 13.28,188.54 13.28,201.23 12.48,202.04 12.48,219.15 17.6,224.27 26.91,224.27 v3(27.38,224.74)
  BOTTOM w0.102: R532.2 27.26,224.85 v3(27.38,224.74) 27.49,224.85 R531.2 ; v1(74.73,149.63) 73.77,148.67 v2(72.7,148.67) 72.16,148.67 68.94,145.45 68.94,140.54 v3(68.11,139.7)
JACK_PSID: length 22.3
  TOP w0.102: DCIN2.11 55.64,31.22 v3(55.53,31.11) ; DCIN2.4 55.64,39.14 v3(55.28,39.5)
  L3 w0.127: v3(55.53,31.11) 52.74,31.11 52.12,30.5 DCIN1.3
  BOTTOM w0.102: v3(55.53,31.11) 56.19,31.78 v2(56.19,32.66) 56.19,33.82 L30.1 56.1,35.75 55.28,36.58 v3(55.28,39.5)
JDREF: length 3.5
  TOP w0.203: U11.35 166.15,78.25 166.58,78.69
  TOP w0.254: R313.1 167.03,79.44 v3(166.58,78.99) 166.58,78.69
  BOTTOM w0.254: v2(167.59,78.66) 167.26,78.99 v3(166.58,78.99)
JTAG_TCLK: length 10.5
  TOP w0.127: GPU1.AE5 90.89,109.54 91.45,109.54 91.66,109.75 91.66,109.99 91.94,110.28 92.22,110.28 92.48,110.54 92.48,111.44 93.31,112.27 v3(93.63,112.27) 94.27,112.9 R242.2
  BOTTOM w0.127: v2(92.87,115.19) 93.15,114.91 93.15,112.75 v3(93.63,112.27)
JTAG_TDI: length 8.6
  TOP w0.102: 89.96,111.38 89.96,110.57 89.74,110.36 89.57,110.36 89.26,110.04 89.26,109.44 GPU1.AE6
  TOP w0.127: v3(91.47,112.39) 91.22,112.14 90.46,112.14 89.96,111.64 89.96,111.38
  BOTTOM w0.127: v3(91.47,112.39) 91.83,112.75 91.83,114.33 91.35,114.81 TP46.1
JTAG_TDO: length 8.8
  TOP w0.127: v3(92.67,113.03) 92.67,112.7 91.73,111.76 90.61,111.76 90.18,111.33 90.18,110.48 GPU1.AF6
  BOTTOM w0.127: v3(92.67,113.03) 92.67,114.5 92.24,114.94 92.24,116.08 TP47.1
JTAG_TMS: length 10.3
  TOP w0.127: GPU1.AD6 90.09,108.79 90.09,110.05 90.41,110.37 90.41,110.83 v3(90.81,111.23)
  BOTTOM w0.127: TP48.1 91.89,116.42 91.89,114.77 92.17,114.49 92.17,112.2 91.19,111.23 v3(90.81,111.23)
JTAG_TRST: length 8.1
  TOP w0.127: GPU1.AG4 91.3,110.74 93.59,113.03 v3(93.63,113.03) 93.63,113.73 R240.2
  BOTTOM w0.127: v2(93.89,116.46) 93.63,116.2 v3(93.63,113.03)
KBC_ON#_GATE: length 12.4
  TOP w0.102: C205.1 147.23,42.48 R448.2 148,42.72 148,44.39 146.54,45.85 v3(146.08,45.85) 146.08,45.72 144.37,44.01 Q41.G
  BOTTOM w0.102: v3(146.08,45.85) 146.85,45.85 147.73,46.73 v2(147.73,46.88) 146.79,47.82 Q67.G
KBC_ON#_GATE_L: length 7
  TOP w0.102: R450.1 147.23,41.59 R448.1 149.26,41.59 149.51,41.85 v4(149.51,41.91) 149.51,42.55 148.37,43.69 148.37,45.4 R449.2
KBC_VCORF: length 3.9
  TOP w0.203: KBC1.44 145.6,55.1 145.83,54.86 146.46,54.86
  TOP w0.508: 146.46,54.86 146.6,54.73 v4(146.6,54.46) 146.85,54.46 146.87,54.43 147.49,54.43 C182.1
L_AD0: length 199.2
  TOP w0.089: 95.83,151.35 94.91,152.27 94.21,152.27 94.12,152.23 93.88,152.23 93.76,152.26 93.74,152.27 93.35,152.27 93.09,152 CPU1.AY13
  TOP w0.102: KBC1.126 129.91,51.5 130.46,52.04 132.29,52.04 133.05,51.28 133.05,51.03 v3(133.54,50.55) ; v3(140.88,100.71) 142.73,102.57 142.73,106.61 135.93,113.41 129.84,113.41 126.51,116.74 107.03,116.74 104.96,118.81 104.96,119.99 104.66,120.29 104.66,125.51 105.54,126.4 105.54,141.57 102.03,145.09 102.03,145.79 101.25,146.57 101.25,148.43 98.84,150.84 96.34,150.84 95.83,151.35
  L3 w0.127: v3(140.88,100.71) 140.83,100.66 140.83,76.51 135.63,71.31 135.63,70.92 132.46,67.75 132.46,65.87 127.54,60.96 125.99,60.96 123.9,58.87 123.9,56.77 123.4,56.28 123.4,55.05 122.66,54.31 122.66,53.58 122.25,53.17 116.84,53.17 115.73,54.28 115.73,54.69 114.94,55.48 113.44,55.48 LPC1.5
  BOTTOM w0.102: U34.24 128.76,46.38 128.81,46.33 129.32,46.33 129.68,46.69 130.53,46.69 133.54,49.69 v3(133.54,50.55) 133.05,51.03 133.05,51.71 131.07,53.69 131.07,54.25 v2(130.72,54.61) 130.06,55.27 124.62,55.27 124.09,55.8 122.77,55.8 121.7,56.87 121.7,57.47 121.18,58 114.38,58 113.44,57.06 113.44,55.48 LPC1.5
L_AD1: length 192
  TOP w0.102: KBC1.127 129.91,51.1 130.58,51.77 132.18,51.77 132.75,51.19 132.75,50.57 v3(132.77,50.55) ; v3(140.88,102.23) 141.04,102.23 142.17,103.36 142.17,106.38 135.7,112.85 129.61,112.85 126.28,116.18 106.8,116.18 104.4,118.58 104.4,119.76 104.1,120.06 104.1,125.74 104.99,126.63 104.99,141.34 101.47,144.85 101.47,145.56 100.69,146.34 100.69,148.45 98.7,150.44 96.17,150.44 94.97,151.65 94.24,151.65 93.88,152 CPU1.BA13
  L3 w0.127: v3(140.88,102.23) 141.35,101.77 141.35,96.59 141.13,96.38 141.13,76.38 135.94,71.19 135.94,70.8 132.76,67.62 132.76,65.75 127.67,60.66 126.12,60.66 124.2,58.74 124.2,56.64 123.71,56.15 123.71,54.92 122.97,54.19 122.97,53.45 122.38,52.86 116.35,52.86 LPC1.7
  BOTTOM w0.102: LPC1.7 113.75,55.46 113.75,56.97 114.49,57.72 121.06,57.72 121.43,57.35 121.43,56.75 122.65,55.52 123.97,55.52 124.5,54.99 129.38,54.99 132.77,51.6 v3(132.77,50.55) 132.77,49.94 v2(131.73,48.9) 131.61,48.77 129.57,48.77 128.9,48.1 128.64,48.1 128.42,47.88 U34.21
L_AD2: length 167.6
  TOP w0.102: KBC1.128 129.98,50.7 130.59,51.31 v3(130.84,51.31) ; v3(140.88,101.47) 142.45,103.05 142.45,106.49 135.81,113.13 129.72,113.13 126.4,116.46 106.92,116.46 104.68,118.7 104.68,119.87 104.38,120.18 104.38,125.62 105.27,126.51 105.27,141.45 101.75,144.97 101.75,145.68 100.97,146.45 100.97,148.44 98.77,150.65 96.25,150.65 95.04,151.86 94.46,151.86 CPU1.BB13
  L3 w0.127: v3(140.88,101.47) 140.41,101 140.41,100.26 140.52,100.15 140.52,76.63 135.33,71.44 135.33,71.05 132.15,67.88 132.15,66 127.42,61.26 125.86,61.26 123.59,58.99 123.59,56.9 123.1,56.4 123.1,55.18 122.36,54.44 122.36,53.94 v3(122.11,53.69) 121.89,53.47 117.74,53.47 LPC1.9
  BOTTOM w0.102: v3(122.11,53.69) 122.31,53.49 123.68,53.49 123.83,53.64 128.91,53.64 v2(130.18,52.37) 130.84,51.71 v3(130.84,51.31) 130.94,51.21 130.94,50.36 130.61,50.02 129.06,50.02 128.42,49.38 U34.18
L_AD3: length 171.1
  TOP w0.089: CPU1.AY12 92.97,151.72 93.53,151.72 93.8,151.45
  TOP w0.102: v3(130.49,50.55) 130.74,50.29 KBC1.1 ; 93.8,151.45 94.9,151.45 96.09,150.25 98.62,150.25 100.41,148.46 100.41,146.22 101.19,145.45 101.19,144.74 104.71,141.22 104.71,126.74 103.82,125.85 103.82,119.95 104.12,119.64 104.12,118.46 106.69,115.9 126.16,115.9 129.49,112.57 135.58,112.57 141.89,106.26 141.89,103.48 141.18,102.77 140.76,102.77 140.32,102.32 140.32,101.93 v3(139.86,101.47)
  L3 w0.127: v3(139.86,101.47) 139.86,100.39 140.1,100.15 140.1,100.14 140.22,100.02 140.22,76.76 135.02,71.57 135.02,71.18 131.85,68 131.85,66.13 127.29,61.57 125.74,61.57 123.29,59.12 123.29,57.02 122.79,56.53 122.79,55.63 120.94,53.78 119.44,53.78 LPC1.11
  BOTTOM w0.102: U34.15 126.76,51.85 127.21,52.3 128.46,52.3 v2(128.56,52.2) 128.84,52.2 v3(130.49,50.55) 130.49,51.02 130.39,51.12 130.39,51.44 128.46,53.37 123.95,53.37 123.79,53.21 120,53.21 LPC1.11
L_BKLTCTL: length 141.8
  TOP w0.165: v3(44.61,64.14) 44.76,63.99 44.76,59.56 45.58,58.74 v4(45.58,57.66) 45.58,56.76 R399.2 ; v3(75.14,128.6) 40.28,128.6 39.45,127.76 v3(39.15,127.76) ; CPU1.R11 79.49,150.67 v1(79.16,151)
  L3 w0.165: v3(44.61,64.14) 44.61,64.76 44.36,65.02 44.36,74.82 33.62,85.56 33.62,122.43 38.46,127.27 38.66,127.27 v3(39.15,127.76)
  BOTTOM w0.165: v3(75.14,128.6) 74.14,129.6 74.14,136.26 73.33,137.06 73.33,140.92 v2(73.79,141.38) 75.72,143.31 75.72,143.71 77.68,145.67 77.68,147.96 78.57,148.85 78.57,150.42 79.15,151 v1(79.16,151)
L_FRAME_N: length 148.6
  TOP w0.102: v3(132.01,50.55) 132.01,50.34 131.54,49.86 KBC1.3 ; R153.1 104.43,138.11 104.43,126.86 103.54,125.97 103.54,119.83 103.84,119.53 103.84,118.35 106.57,115.62 126.05,115.62 129.38,112.29 135.46,112.29 141.61,106.14 141.61,103.59 141.07,103.05 140.42,103.05 v3(139.86,102.49)
  L3 w0.127: LPC1.13 121.36,54.63 122.49,55.75 122.49,56.66 122.98,57.15 122.98,60.39 125.15,62.56 125.96,62.56 129.53,66.13 129.53,66.94 133.47,70.88 133.9,70.88 139.91,76.89 139.91,99.89 139.8,100.01 139.8,100.02 139.39,100.43 139.39,102.02 v3(139.86,102.49)
  BOTTOM w0.102: LPC1.13 121.69,54.63 121.83,54.76 v2(123.96,54.76) 124.1,54.63 129.35,54.63 132.44,51.53 132.44,50.98 v3(132.01,50.55) 132.01,50.06 131.01,49.05 129.46,49.05 128.79,48.38 U34.20
L_FRAME_N_R: length 17.3
  TOP w0.089: 94.82,151.26 93.52,151.26 CPU1.BA12
  TOP w0.102: 94.82,151.26 96.04,150.04 98.57,150.04 100.13,148.47 100.13,146.11 100.91,145.33 100.91,144.62 101.38,144.15 101.8,143.73 103.16,142.37 v4(103.16,141.98) 102.9,141.72 R153.2
LAN_DISABLE_N: length 272.1
  TOP w0.089: 95.83,153.58 95.44,153.97 93.96,153.97 93.77,154.17 92.86,154.17 92.6,154.43 CPU1.AW17
  TOP w0.102: v3(111.16,118.75) 111.16,119.97 109,122.13 109,124.02 R216.1 110.93,126.96 110.93,147.38 104.64,153.67 100.78,153.67 100.38,153.26 96.15,153.26 95.83,153.58
  L3 w0.127: v3(42.71,12.12) 42.71,15.65 39.05,19.3 36.61,19.3 35.21,17.91 30.89,17.91 30.51,18.29 30.51,21.08 30.64,21.21 30.64,28.07 28.44,30.27 28.42,30.42 28.42,38.8 32.2,42.58 32.2,125.21 36.78,129.79 42.07,129.79 v3(43.45,131.18)
  L4 w0.127: v3(111.16,118.75) 109.8,117.39 83.25,117.39 71.72,128.92 45.71,128.92 v3(43.45,131.18)
  BOTTOM w0.102: v3(42.71,12.12) 43.41,11.41 43.41,11.13 44.23,10.31 v2(44.23,9.96) R869.1
LAN_DISABLE_N_1: length 8.2
  BOTTOM w0.254: Q80.B 46.41,7.06 48.15,7.06 R871.1 ; Q80.B 44.66,7.94 R869.2 C624.1 ; Q80.B 45.53,8.59 v2(46.31,9.37)
LAN_DISABLE_N_2: length 8.7
  TOP w0.254: Q47.B 46.55,5.37 v3(46.01,4.83)
  BOTTOM w0.254: R870.1 R871.2 48.7,5.42 48.7,4.37 v2(48.52,4.19) 48.5,4.17 47.56,4.17 46.52,5.21 Q80.C 46.35,6.03 46.01,5.69 v3(46.01,4.83)
LAN_DISABLE_N_3: length 8.9
  TOP w0.102: Q46.C 44.86,7.94 R523.1 46.2,7.37 46.96,7.37 Q47.C 48.78,9.18 48.78,9.4 v4(48.78,9.4) 48.53,9.65 47.72,9.65 R520.2
LAN_DISABLE_N_4: length 12.3
  TOP w0.102: v3(43.82,4.72) 43.24,5.31 43.24,6.41 43.61,6.78 44.88,6.78 C280.1 R523.2
  BOTTOM w0.102: 42.96,5.74 42.96,5.59 v3(43.82,4.72) 43.11,4.01 v2(42.92,4.01) 40.22,4.01 39.78,4.45 39.78,5.4 PC295.2
LAN_DISABLE_V3: length 5.6
  TOP w0.102: R522.2 R524.1 ; R524.1 C279.1 ; R524.1 41.59,6.41 Q46.B 41.26,5.31 41.26,4.19 v4(41.25,4.19)
LAN_LEDACT_R#: length 6.2
  TOP w0.254: RJ1.10 82.56,22.32 v3(82.56,25.04) R892.2
  BOTTOM w0.254: v2(81.72,25.04) v3(82.56,25.04)
LAN_MDI0_C_DN: length 28
  TOP w0.089: v3(63.03,7.75) 62.86,7.58 62.57,7.58 62.48,7.67 62.48,8.01 62.19,8.3 61.88,8.3 61.42,8.76 XF1.2 ; RJ1.2 v3(80.1,10.4)
  L4 w0.102: v3(80.1,10.4) 80.76,10.4 80.89,10.27 80.89,8 79.87,6.99 64.34,6.99 63.8,7.53 63.24,7.53 v3(63.03,7.75)
  BOTTOM w0.089: v2(80.1,11.21) v3(80.1,10.4)
LAN_MDI0_C_DP: length 27.9
  TOP w0.089: XF1.1 61.37,7.49 61.84,7.96 62.05,7.96 62.14,7.87 62.14,7.53 62.43,7.24 62.77,7.24 v3(63.03,6.99) ; RJ1.1 v3(81.37,10.4)
  L4 w0.102: v3(63.03,6.99) 63.24,7.2 63.66,7.2 64.21,6.65 80.01,6.65 81.22,7.86 81.22,10.27 81.34,10.4 v3(81.37,10.4)
  BOTTOM w0.089: v2(81.37,9.58) v3(81.37,10.4)
LAN_MDI0_DN: length 16.4
  TOP w0.089: U23.2 40.38,13.86 40.79,13.45 42.54,13.45 43.51,12.48 ; 43.51,12.48 45,10.99 U24.3 46.43,10.99 46.77,11.33 47.91,11.33 48.03,11.45 49.54,11.45 49.78,11.21 49.78,8.78 50.26,8.3 50.71,8.3 51.17,8.76 XF1.11 ; 43.51,12.48 v4(43.8,12.78)
LAN_MDI0_DP: length 16.4
  TOP w0.089: U23.1 40.3,13.46 40.65,13.11 42.4,13.11 44.53,10.97 ; 44.53,10.97 44.86,10.64 45.37,10.64 45.6,10.41 46.9,10.41 47.02,10.54 47.02,10.92 47.09,10.99 U24.4 49.13,10.99 49.44,10.68 49.44,8.64 50.12,7.96 50.71,7.96 51.17,7.49 XF1.12 ; 44.53,10.97 v4(44.25,10.69)
LAN_MDI1_C_DN: length 29.8
  TOP w0.089: RJ1.6 v3(75.02,10.4) ; XF1.6 61.42,16.38 61.88,15.92 62.19,15.92 62.48,15.63 62.48,15.29 62.57,15.2 62.86,15.2 v3(63.03,15.37)
  L4 w0.102: v3(63.03,15.37) 63.24,15.15 63.9,15.15 64.55,14.5 64.55,9.27 65.57,8.26 76.61,8.26 76.87,8.51 76.87,9.53 76.74,9.65 75.22,9.65 75.02,9.85 v3(75.02,10.4)
  BOTTOM w0.089: v2(75.02,11.21) v3(75.02,10.4)
LAN_MDI1_C_DP: length 29.8
  TOP w0.089: RJ1.3 v3(78.83,10.4) ; XF1.5 61.37,15.11 61.84,15.58 62.05,15.58 62.14,15.49 62.14,15.15 62.43,14.86 62.77,14.86 v3(63.03,14.61)
  L4 w0.102: v3(78.83,10.4) 78.08,9.65 77.39,9.65 77.2,9.46 77.2,8.37 76.75,7.92 65.43,7.92 64.22,9.13 64.22,14.37 63.77,14.82 63.24,14.82 v3(63.03,14.61)
  BOTTOM w0.089: v2(78.83,9.58) v3(78.83,10.4)
LAN_MDI1_DN: length 15.2
  TOP w0.089: 49.35,14.5 49.35,13.63 49.18,13.46 48.29,13.46 47.91,13.08 47.02,13.08 46.83,12.89 U24.1 44.95,12.89 42.84,15 40.6,15 40.54,15.06 U23.5 ; 49.35,14.5 v4(48.93,14.5) ; 49.35,14.5 49.35,14.96 50.31,15.92 50.75,15.92 51.21,16.38 XF1.7
LAN_MDI1_DP: length 15.2
  TOP w0.089: XF1.8 51.21,15.11 50.75,15.58 50.45,15.58 49.69,14.81 49.69,13.48 49.1,12.89 U24.6 48.21,12.89 48.05,12.74 47.19,12.74 46.88,12.43 45.49,12.43 45.37,12.55 44.81,12.55 42.7,14.66 41.94,14.66 ; v4(41.94,14.25) 41.94,14.66 ; 41.94,14.66 U23.4
LAN_MDI2_C_DN: length 23.8
  TOP w0.089: RJ1.5 v3(76.29,10.4)
  L3 w0.102: v3(63.03,9.27) 63.24,9.06 63.96,9.06 65.29,7.73 76.23,7.73 77.02,8.51 77.02,10.27 76.89,10.4 v3(76.29,10.4)
  BOTTOM w0.089: v3(63.03,9.27) 62.77,9.02 62.39,9.02 62.08,8.71 62.08,8.39 61.99,8.3 61.88,8.3 61.42,8.76 XF2.5 ; v3(76.29,10.4) 76.28,10.39 v2(76.28,9.58)
LAN_MDI2_C_DP: length 23.7
  TOP w0.089: RJ1.4 v3(77.56,10.4)
  L3 w0.102: v3(77.56,10.4) 77.35,10.19 77.35,8.37 76.37,7.4 65.15,7.4 65.06,7.49 63.83,8.72 63.24,8.72 v3(63.03,8.51)
  BOTTOM w0.089: v2(77.56,11.23) v3(77.56,10.4) ; XF2.6 61.42,7.49 61.88,7.96 62.14,7.96 62.43,8.25 62.43,8.57 62.53,8.67 62.86,8.67 v3(63.03,8.51)
LAN_MDI2_DN: length 16.7
  TOP w0.089: v3(44.23,16.64) 44.1,16.76 P3.2
  BOTTOM w0.089: v2(45.19,14.4) 44.86,14.4 ; 44.86,14.4 44.86,14.73 45.37,15.24 45.37,16 44.99,16.38 44.48,16.38 v3(44.23,16.64) ; 44.86,14.4 44.86,13.46 44.61,13.21 44.61,11.68 44.84,11.45 47.02,11.45 47.49,10.99 U39.3 49.12,10.99 49.78,10.33 49.78,8.78 50.26,8.3 50.73,8.3 51.19,8.76 XF2.8
LAN_MDI2_DN_R: length 3.3
  TOP w0.089: 41.77,16.33 41.23,15.8 40.42,15.8 40.36,15.86 U23.7 ; 41.77,16.33 41.82,16.38 42.13,16.38 P3.1 ; 41.77,16.33 v4(41.51,16.59)
LAN_MDI2_DP: length 16.7
  TOP w0.089: P4.2 44.1,15.75 v3(44.23,15.88)
  BOTTOM w0.089: XF2.7 51.17,7.49 50.71,7.96 50.12,7.96 49.44,8.64 49.44,10.18 49.2,10.41 48.42,10.41 48.19,10.64 47.34,10.64 47,10.99 U39.4 46.11,11.11 44.7,11.11 44.27,11.54 44.27,12.78 ; 44.27,12.78 44.27,13.35 44.52,13.6 44.52,14.87 45.03,15.38 45.03,15.86 44.85,16.04 44.39,16.04 v3(44.23,15.88) ; 44.27,12.78 v2(43.92,12.78)
LAN_MDI2_DP_R: length 2.9
  TOP w0.089: U23.6 41.38,15.46 41.96,16.04 42.22,16.04 P4.1
LAN_MDI3_C_DN: length 24.9
  TOP w0.089: RJ1.8 v3(72.48,10.4)
  L3 w0.102: v3(72.48,10.4) 73,10.4 73.11,10.29 73.11,9.14 72.93,8.97 66.08,8.97 64.75,10.3 64.75,15.97 64.05,16.68 63.24,16.68 v3(63.03,16.89)
  BOTTOM w0.089: v2(72.48,11.21) v3(72.48,10.4) ; XF2.1 61.42,16.38 61.88,15.92 61.99,15.92 62.08,16.01 62.08,16.33 62.39,16.64 62.77,16.64 v3(63.03,16.89)
LAN_MDI3_C_DP: length 24.9
  TOP w0.089: RJ1.7 v3(73.75,10.4)
  L3 w0.102: v3(73.75,10.4) 73.44,10.09 73.44,9.01 73.07,8.64 65.95,8.64 64.42,10.16 64.42,15.84 63.91,16.34 63.24,16.34 v3(63.03,16.13)
  BOTTOM w0.089: XF2.2 61.42,15.11 61.88,15.58 62.14,15.58 62.43,15.87 62.43,16.19 62.53,16.29 62.86,16.29 v3(63.03,16.13) ; v2(73.74,9.58) 73.74,10.4 v3(73.75,10.4)
LAN_MDI3_DN: length 16.8
  TOP w0.089: v3(44.23,18.92) 43.98,19.18 P1.2
  BOTTOM w0.089: v2(46.95,15.95) 46.6,15.95 ; 46.6,15.95 46.6,17.2 45.13,18.67 44.48,18.67 v3(44.23,18.92) ; 46.6,15.95 46.6,14.72 46.13,14.25 46.13,13.55 46.22,13.46 46.9,13.46 47.02,13.34 47.02,12.89 47.14,12.77 48.42,12.77 48.54,12.89 U39.1 49.14,12.89 49.35,13.1 49.35,14.96 50.31,15.92 50.75,15.92 51.21,16.38 XF2.12
LAN_MDI3_DN_R: length 5.2
  TOP w0.089: P1.1 41.56,19.18 40.51,18.12 39.78,18.12 ; U23.10 38.88,17.49 39.51,18.12 39.78,18.12 ; 39.78,18.12 v4(39.78,18.49)
LAN_MDI3_DP: length 16.8
  TOP w0.089: P2.2 v3(44.23,18.16)
  BOTTOM w0.089: 45.54,17.77 44.99,18.33 44.39,18.33 v3(44.23,18.16) ; 45.54,17.77 46.26,17.06 46.26,14.86 45.79,14.39 45.79,13.17 46.07,12.89 U39.6 46.45,12.89 46.92,12.43 49.56,12.43 49.69,12.55 49.69,14.81 50.45,15.58 50.75,15.58 51.21,15.11 XF2.11 ; 45.54,17.77 v2(45.3,17.53)
LAN_MDI3_DP_R: length 5.3
  TOP w0.089: 41.14,18.27 40.65,17.78 39.66,17.78 39.28,17.4 U23.9 ; 41.14,18.27 v4(41.44,17.98) ; 41.14,18.27 41.7,18.83 41.91,18.83 42.03,18.71 42.03,18.22 42.1,18.16 P2.1
LAN_RSET: length 4.5
  TOP w0.102: R519.2 40.99,9.41 v4(40.04,10.36) 39.58,10.36 38.88,11.06 38.88,12.77 U23.31
LAN_XTALI: length 9.7
  TOP w0.102: X5.1 36.74,7.15 v3(36.74,8.31) 36.74,8.33 35.97,9.09 R521.2 36.16,9.33 C270.1 36.67,10.79 37.45,10.79 37.74,11.08 37.74,12.21 37.68,12.26 U23.28
  BOTTOM w0.102: v3(36.74,8.31) 36.75,8.31 v2(37.4,7.66)
LAN_XTALO: length 5.6
  TOP w0.102: U23.29 38.08,12.26 37.96,12.15 37.96,10.49 R518.1 ; v3(37.02,10.29) 37.07,10.34 R518.1 ; R518.1 37.82,9.46 R521.1
  BOTTOM w0.102: v3(37.02,10.29) 37.02,10.01 v2(36.54,9.53)
LAN_XTALO_C: length 4
  TOP w0.102: X5.3 37.91,8.08 v3(38.39,8.56) 38.7,8.88 C276.1 R518.2
  BOTTOM w0.102: v2(38.39,9.37) v3(38.39,8.56)
LANCLK_REQ_N: length 240.6
  TOP w0.102: Q82.D 45.59,21.31 43.57,21.31 42.9,20.65 42.68,20.65 42.47,20.44 41.04,20.44 40.66,20.07 37.5,20.07 37.31,19.88 R505.2 36.99,19.56 36.2,18.77 35.7,18.77 35.47,18.54 31.67,18.54 31.21,19 30.34,19 v3(29.88,18.54)
  L3 w0.127: v3(40.55,130.35) 36.73,130.35 31.77,125.39 31.77,42.87 27.99,39.09 27.99,30 30.13,27.86 30.13,21.76 29.88,21.51 v3(29.88,18.54)
  L4 w0.127: v3(40.55,130.35) 44.52,126.38 70.92,126.38 82.28,115.01 104.61,115.01 106.83,112.79 106.83,112.4 107.09,112.14 107.09,111.89 v3(107.73,111.25)
  BOTTOM w0.102: v3(107.73,111.25) 107.54,111.25 R635.2 106.71,112.39 v2(105.32,113.79) 104.68,114.43 104.68,121.29 107.57,124.18 108.28,124.18 109.25,125.16 109.25,129.92 107.77,131.41 106.56,131.41 R636.2
LANCLK_REQ_U_N: length 13.4
  TOP w0.102: U23.12 38.08,17.66 37.8,17.94 v4(37.8,18.41) 38.2,18.81 R505.1 40.73,19.56 41.21,20.03 42.86,20.03 R879.2 43.73,20.9 44.53,20.9 46.71,18.73 Q82.S
LDR: length 6.3
  BOTTOM w0.305: 39.15,27.69 38.88,27.42 U36.1
  BOTTOM w0.508: R823.2 42.02,31.29 40.44,29.72 v2(39.91,29.72) 39.15,28.96 39.15,27.69
LDR_1: length 5
  BOTTOM w0.508: R823.1 40.09,32.44 41.05,33.4 Q75.4 v2(43.61,33.4)
LED_5VSB: length 2.6
  TOP w0.254: v4(142.55,40.87) 142.53,40.84 LED1.A 141.19,39.75 R453.2
LEDC_ISET: length 4.8
  BOTTOM w0.102: U36.12 33.26,25.92 32.41,26.77 32.07,26.77 v2(31.53,27.3) 30.64,28.2 R829.1
LINE2-VREFO: length 9.8
  TOP w0.203: R323.1 169.77,78.11 v3(169.07,78.11) ; R333.1 169.37,74.87 168.9,75.34 168.79,75.34 v3(168.77,75.36) ; U11.29 167,75.85 v3(167.17,75.69)
  L3 w0.203: v3(169.07,78.11) 168.77,77.8 v3(168.77,75.36) 168.21,75.92 167.39,75.92 v3(167.17,75.69)
  BOTTOM w0.203: v2(169.73,78.87) 169.73,78.77 v3(169.07,78.11)
LINEOUT-JD: length 185.4
  TOP w0.203: R345.1 169.96,70.1 166.96,67.11 166.96,61.67 168.03,60.6 168.03,30.81 159.55,22.33 159.55,17.91 158.35,16.71 155.36,16.71 153.37,14.72 153.37,2.9 152.3,1.83 88.45,1.83 86.82,3.46 86.82,30.86 83.93,33.76 LOUT1.Q
  BOTTOM w0.203: LOUT1.Q 79.43,34.16 v2(79.43,37.24)
LINEOUT-L: length 182
  TOP w0.203: U11.19 162.79,72.69 161.6,71.5 161.6,69.09 162.44,68.25 162.44,68.03 163.14,67.33 165.51,67.33 166.51,66.33 166.51,60.98 v4(167.17,60.33) 167.57,59.92 167.57,31 159.09,22.52 159.09,18.1 158.16,17.17 155.17,17.17 152.92,14.91 152.92,3.09 152.11,2.29 88.64,2.29 87.28,3.65 87.28,31.05 R463.1
LINEOUT-R: length 180
  TOP w0.203: U11.18 162.39,72.83 161.15,71.58 161.15,68.68 v4(161.83,68) 162.95,66.87 164.89,66.87 166.05,65.71 166.05,60.58 167.11,59.51 167.11,31.19 158.63,22.71 158.63,18.29 157.97,17.63 155.36,17.63 154.98,17.63 152.46,15.1 152.46,3.28 151.93,2.74 88.83,2.74 87.74,3.84 87.74,31.24 84.49,34.49 R464.1
LINEOUT_C-L: length 3.3
  TOP w0.203: R463.2 82.85,35.88 v3(82.33,36.4) 82.82,36.89 L19.1
  BOTTOM w0.203: v2(83.14,36.4) v3(82.33,36.4)
LINEOUT_C-R: length 3.2
  TOP w0.203: L20.1 84.96,36.89 v3(85.43,36.42) 84.88,35.88 R464.2
  BOTTOM w0.203: v2(85.25,35.59) 85.25,36.25 v3(85.43,36.42)
LINEOUT_CON-L: length 14.4
  TOP w0.203: LOUT1.4 83.13,42.66 Q42.1 83.15,41.72 v3(83.09,41.66) ; v3(83.09,39.62) 83.41,39.31 C216.1 83.41,37.85 L19.2
  L3 w0.203: v3(83.09,41.66) v3(83.09,39.62)
  BOTTOM w0.203: v3(83.09,41.66) 83.37,41.94 v2(83.37,42.52)
LINEOUT_CON-R: length 16
  TOP w0.203: LOUT1.1 82.79,40.67 Q42.2 84.06,39.77 v3(84.06,39.65) 84.55,39.15 C217.1 84.55,37.85 L20.2
  BOTTOM w0.203: v2(84.06,40.51) v3(84.06,39.65)
LINK_ACTIVITY_N: length 88.4
  TOP w0.203: U23.27 v3(37.28,11.28)
  TOP w0.254: v3(53.25,4.83) 53.76,4.31 53.77,4.31 54.14,3.94 54.14,3.93 54.41,3.66 83.78,3.66 84.19,4.08 84.19,13.56 85.17,14.54 85.17,27.03 84.77,27.43 83.26,27.43 R892.1 81.76,26.73 v3(81.57,26.92) ; v3(77.88,30.73) 77.17,30.02 U20.4
  L3 w0.254: v3(81.57,26.92) 81.57,27.05 v3(77.88,30.73)
  L4 w0.254: v3(37.28,11.28) 37.84,11.84 40.34,11.84 41.44,10.74 41.44,10.03 46,5.46 49.44,5.46 51.01,3.89 52.31,3.89 v3(53.25,4.83)
  BOTTOM w0.254: v3(53.25,4.83) 53.7,4.37 v2(53.7,4.11)
LINK_PWR: length 5.7
  TOP w0.254: R482.1 v3(83.57,25.04) 83.57,21.05 RJ1.9
  BOTTOM w0.254: v2(84.44,25.04) v3(83.57,25.04)
LPC_CLK0: length 129.5
  TOP w0.102: R174.1 103.67,135.7 103.67,127.17 102.78,126.29 102.78,119.52 103.08,119.21 103.08,118.03 106.25,114.86 125.73,114.86 129.06,111.53 135.15,111.53 135.92,110.76 139.48,107.2 139.48,105.79 v4(139.99,105.28) 140.32,104.95 140.32,103.96 v3(139.86,103.5) ; R380.2 109.89,61.21 111.41,62.74 v3(113.06,62.74)
  L3 w0.127: v3(139.86,103.5) 139.49,103.5 138.58,102.59 138.58,100.09 138.68,99.99 138.68,96.47 138.25,96.04 138.25,77.54 132.91,72.2 130.65,72.2 128.05,69.6 128.05,66.52 125.46,63.93 114.26,63.93 v3(113.06,62.74)
LPC_CLK0_R: length 20.5
  TOP w0.089: CPU1.AW9 92.59,149.58 92.99,149.98 94.07,149.98 94.18,150.02 94.54,150.02 95.06,149.5 95.06,149.4
  TOP w0.102: R174.2 103.03,137.92 101.63,139.32 101.63,140.59 v4(101.38,140.84) 101.36,140.83 100,140.83 98.15,142.67 98.15,145.89 98.23,145.96 98.23,147.14 97.9,147.47 97.49,147.47 97.06,147.9 97.06,148.66 96.72,149 95.46,149 95.06,149.4
LPC_CLK1: length 139.7
  TOP w0.102: R186.1 103.03,127.22 102.29,126.49 102.29,119.32 102.6,119.01 102.6,117.83 106.05,114.38 125.53,114.38 129.7,110.21 135.79,110.21 135.97,110.03 136.49,109.51 138.72,107.28 v4(138.72,106.68) 138.72,105.41 v3(139.86,104.27) ; KBC1.2 131.14,49.82 131.23,49.91 131.23,50.55 v3(131.99,51.31)
  L3 w0.127: v3(123.48,53.98) 124.21,54.71 124.21,55.94 125.49,57.21 128.3,57.21 129.43,58.34 130.51,58.34 131.98,59.82 131.98,61.41 133.27,62.69 133.27,67.41 136.44,70.59 136.44,70.97 141.64,76.17 141.64,96.17 141.85,96.38 141.85,103.95 141.07,104.74 140.33,104.74 v3(139.86,104.27)
  BOTTOM w0.102: v3(123.48,53.98) 123.63,54.13 129.17,54.13 v3(131.99,51.31) 131.45,50.77 131.45,50.18 130.81,49.54 129.26,49.54 128.6,48.88 U34.19
LPC_CLK1_R: length 20
  TOP w0.102: CPU1.AY9 93.18,149.58 93.53,149.23 93.89,149.23 96.94,146.18 96.94,143.2 100.57,139.57 100.66,139.57 102.4,137.83 102.4,135.71 103.03,135.08 v4(103.03,135.03) R186.2
LPC_CLK_D: length 7.7
  TOP w0.102: R380.1 107.54,60.39 v4(107.22,60.07) 106.71,59.56 106.71,56.5 LPC1.1
LPC_CLKRUN#_CPU: length 21.1
  TOP w0.102: CPU1.AW11 92.08,150.86 92.06,150.84 91.89,150.84 91.83,150.78 91.81,150.78 v1(91.81,150.78)
  BOTTOM w0.102: R626.1 R623.2 104.59,140.87 101.64,140.87 95.66,146.84 v2(95.66,147.35) 95.66,147.82 92.71,150.78 v1(91.81,150.78)
LPC_PME#: length 4.2
  TOP w0.102: KBC1.91 132.74,65.8 132.9,65.97 132.9,67.25 v4(132.82,67.34) 132.52,67.64 R360.1
LPC_PME_N: length 193.7
  TOP w0.102: CPU1.AU11 91.2,150.87 v1(90.87,150.55) ; v3(76.87,78.87) 76.87,76.33 78.33,74.87 R339.1 78.27,74.36 R342.2 ; v3(132.37,70.48) 132.37,69.63 R360.2
  L4 w0.127: v3(141.64,118.49) 141.15,118.01 140.17,118.01 136.32,114.16 128.16,114.16 117.13,125.19 117.13,125.63 113.94,128.82 111.95,128.82 109.63,131.14 109.34,131.14 108.07,132.41 107.72,132.41 106.97,133.16 106.97,134.6 94.57,147 94.57,147.58 91.84,150.3 91.66,150.3 91.42,150.55 v1(90.87,150.55) ; v3(132.37,70.48) 131.58,71.27 120.45,71.27 118.71,69.53 102.84,69.53 101.38,70.99 90.67,70.99 83.39,78.27 77.46,78.27 v3(76.87,78.87)
  BOTTOM w0.102: v3(141.64,118.49) 138.4,115.25 138.4,105.9 139.38,104.92 140.87,104.92 141.33,104.46 141.33,77.24 135.88,71.78 133.79,71.78 v2(133.26,71.25) 132.49,70.48 v3(132.37,70.48)
LPCPD_TPM: length 1.8
  BOTTOM w0.102: U34.28 125.76,44.2 TP79.1
LPF: length 3.7
  BOTTOM w0.102: C593.1 36.61,21.97 v2(36.48,22.1) 36.48,22.35 35.73,23.11 U36.9
LPSS_UART2_RXD: length 39.8
  TOP w0.102: CPU1.AD1 84.66,144.51 84.66,141.44 v1(85.38,140.72) 85.57,140.53 R162.1
  BOTTOM w0.102: v1(85.38,140.72) 85.89,140.21 85.89,135.59 85.78,135.49 85.62,135.49 85.5,135.37 85.5,135.2 85.62,135.08 85.78,135.08 85.89,134.98 85.89,134.78 85.78,134.67 84.86,134.67 84.74,134.56 84.74,134.39 84.86,134.27 85.78,134.27 85.89,134.17 85.89,133.96 85.78,133.86 84.34,133.86 84.23,133.76 84.23,133.56 84.34,133.46 85.78,133.46 85.89,133.35 85.89,133.15 85.78,133.05 84.34,133.05 84.23,132.95 84.23,132.74 84.34,132.64 85.78,132.64 85.89,132.54 85.89,132.34 85.78,132.24 84.34,132.24 84.23,132.13 84.23,131.93 84.34,131.83 85.78,131.83 85.89,131.73 85.89,131.52 85.78,131.42 84.34,131.42 84.23,131.32 84.23,131.12 84.34,131.02 85.78,131.02 85.89,130.92 85.89,130.71 85.78,130.61 84.34,130.61 84.23,130.51 84.23,130.31 84.34,130.2 85.78,130.2 85.89,130.1 85.89,129.54 v2(85.63,129.29) 84.62,129.29 84.49,129.16 84.49,128.93 84.62,128.8 84.92,128.8 85.05,128.68 85.05,128.45 84.92,128.32 84.62,128.32 84.49,128.19 84.49,126.93 CN1.3
LPSS_UART2_TXD: length 41.1
  TOP w0.089: CPU1.AD2 84.28,145.14 84.28,144.92 84.22,144.79 84.22,144.41 84.47,144.16 84.47,140.99 v1(84.74,140.72)
  TOP w0.102: R164.1 85.57,139.13 85.15,139.55 85.15,140.31 v1(84.74,140.72)
  BOTTOM w0.102: v1(84.74,140.72) 85.66,139.8 85.66,135.89 83.93,134.16 83.93,131.95 83.8,131.83 81.69,131.83 81.59,131.73 81.59,131.45 81.69,131.35 83.65,131.35 83.75,131.24 83.75,130.96 83.65,130.86 81.44,130.86 81.31,130.74 81.31,130.51 81.44,130.38 83.65,130.38 83.75,130.28 83.75,130 83.65,129.9 81.49,129.9 81.36,129.77 81.36,129.54 81.49,129.42 83.65,129.42 83.75,129.31 83.75,129.03 83.65,128.93 81.52,128.93 81.39,128.81 81.39,128.58 81.52,128.45 83.65,128.45 83.75,128.35 v2(83.75,127.71) 83.75,126.54 CN1.2
LVDS_BL_ADJ: length 8.1
  TOP w0.165: v3(44.38,26.44) 44.33,26.39 44.33,25.4 44.78,24.96 R486.1 44.23,23.69 R492.1 43.67,22.62 R501.2 42.77,21.72 R500.1
  BOTTOM w0.165: v3(44.38,26.44) 44.84,26.9 v2(45.05,26.9)
LVDS_DET_A*: length 126.7
  TOP w0.102: LVDS1.17 41.21,93.5 v3(41.18,93.47) ; v1(143.42,61.34) 143.66,61.1 KBC1.59
  L4 w0.127: v3(41.18,93.47) 41.18,89 40.71,88.53 40.71,86.26 54.79,72.19 61.11,72.19 61.35,71.95 75.44,71.95 76.96,70.42 79.41,70.42 86.88,62.95 90.37,62.95 91.69,61.63 104.81,61.63 105.65,60.79 124.98,60.79 125.54,61.35 127.8,61.35 128.76,60.39 141.85,60.39 142.48,61.02 143.1,61.02 v1(143.42,61.34)
  BOTTOM w0.102: v3(41.18,93.47) 41.18,94.16 v2(41.31,94.28) 42.08,95.06 R681.2
LVDS_DET_B*: length 160.1
  TOP w0.102: v1(146.08,61.47) 146.08,61.38 145.4,60.7 KBC1.58 ; Q16.D 45.05,120.78 R223.2 42.51,121.22 41.18,119.89 41.18,119 v4(41.2,118.98) 41.2,118.75 41.45,118.49 v3(42.71,118.49)
  L4 w0.127: v3(42.71,118.49) 40.71,116.5 40.71,95.59 42.43,93.88 42.43,84.91 54.87,72.47 61.19,72.47 61.46,72.2 75.54,72.2 77.06,70.68 79.51,70.68 86.98,63.21 90.48,63.21 91.8,61.89 104.92,61.89 105.76,61.05 124.87,61.05 125.43,61.61 127.9,61.61 128.87,60.64 141.74,60.64 142.38,61.28 142.74,61.28 142.97,61.51 142.97,61.53 143.23,61.79 145.77,61.79 v1(146.08,61.47)
LVDS_DET_B_C*: length 14.7
  TOP w0.102: Q16.G 47.25,119.79 C80.1 v4(45.94,116.59) 45.94,110.05 45.4,109.5 LVDS1.1
LVDS_PU_5: length 6.1
  TOP w0.102: v3(41.18,105.16) 41.53,105.5 LVDS1.5 43.33,105.5 44.5,104.33 R258.2
  BOTTOM w0.102: v3(41.18,105.16) v2(40.29,105.16)
LVDS_PU_6: length 6.1
  TOP w0.102: v4(47.58,102.49) 47.52,102.43 R259.2 45.18,102.43 44.18,103.43 44.18,103.63 43.31,104.5 LVDS1.6
LVDS_PU_6_1: length 6.1
  TOP w0.152: R259.1 45.31,101.54 v3(44.86,101.98)
  BOTTOM w0.152: v3(44.86,101.98) 44.86,100.97 v2(44.23,100.33) 42.86,98.96 Q55.D
LVDS_PU_24: length 3.7
  TOP w0.102: v3(41.18,86.74) 41.42,86.5 LVDS1.24
  BOTTOM w0.102: R693.2 41.93,85.9 v2(41.24,85.9) 41.18,85.96 v3(41.18,86.74)
LX:
  vias: v2(34.52,30.48) v5(38.26,36.07) v5(38.26,34.92) v5(38.26,33.78)
M1_SMB_CLK: length 7.6
  TOP w0.102: NGFF1.60 119.44,219.5 119.98,220.04 v4(120.63,220.04) 122.18,220.04 123.14,219.07 R41.2
M1_SMB_DATA: length 5.6
  TOP w0.102: NGFF1.58 119.85,219 120.18,219.33 121.95,219.33 v4(121.95,219.33) 122.21,219.33 123.1,218.44 R44.2
M_A_A0: length 56.2
  TOP w0.165: CPU1.AY50 93.01,172.86 v1(92.66,172.51) ; DIMM1.144 137.89,156.53 v1(137.7,156.34)
  L3 w0.089: v1(92.66,172.51) 94.58,172.51 94.67,172.6 94.67,172.89 94.76,172.97 94.94,172.97 95.03,172.89 95.03,172.6 95.12,172.51 95.3,172.51 96.33,171.48 102.88,171.48 103.16,171.2
  L3 w0.216: v1(137.7,156.34) 137.7,156.21 137.31,155.82 127.64,155.82 113.08,170.37 103.98,170.37 103.16,171.2
  BOTTOM w0.165: v1(137.7,156.34) 138.11,156.34 v2(138.49,155.96)
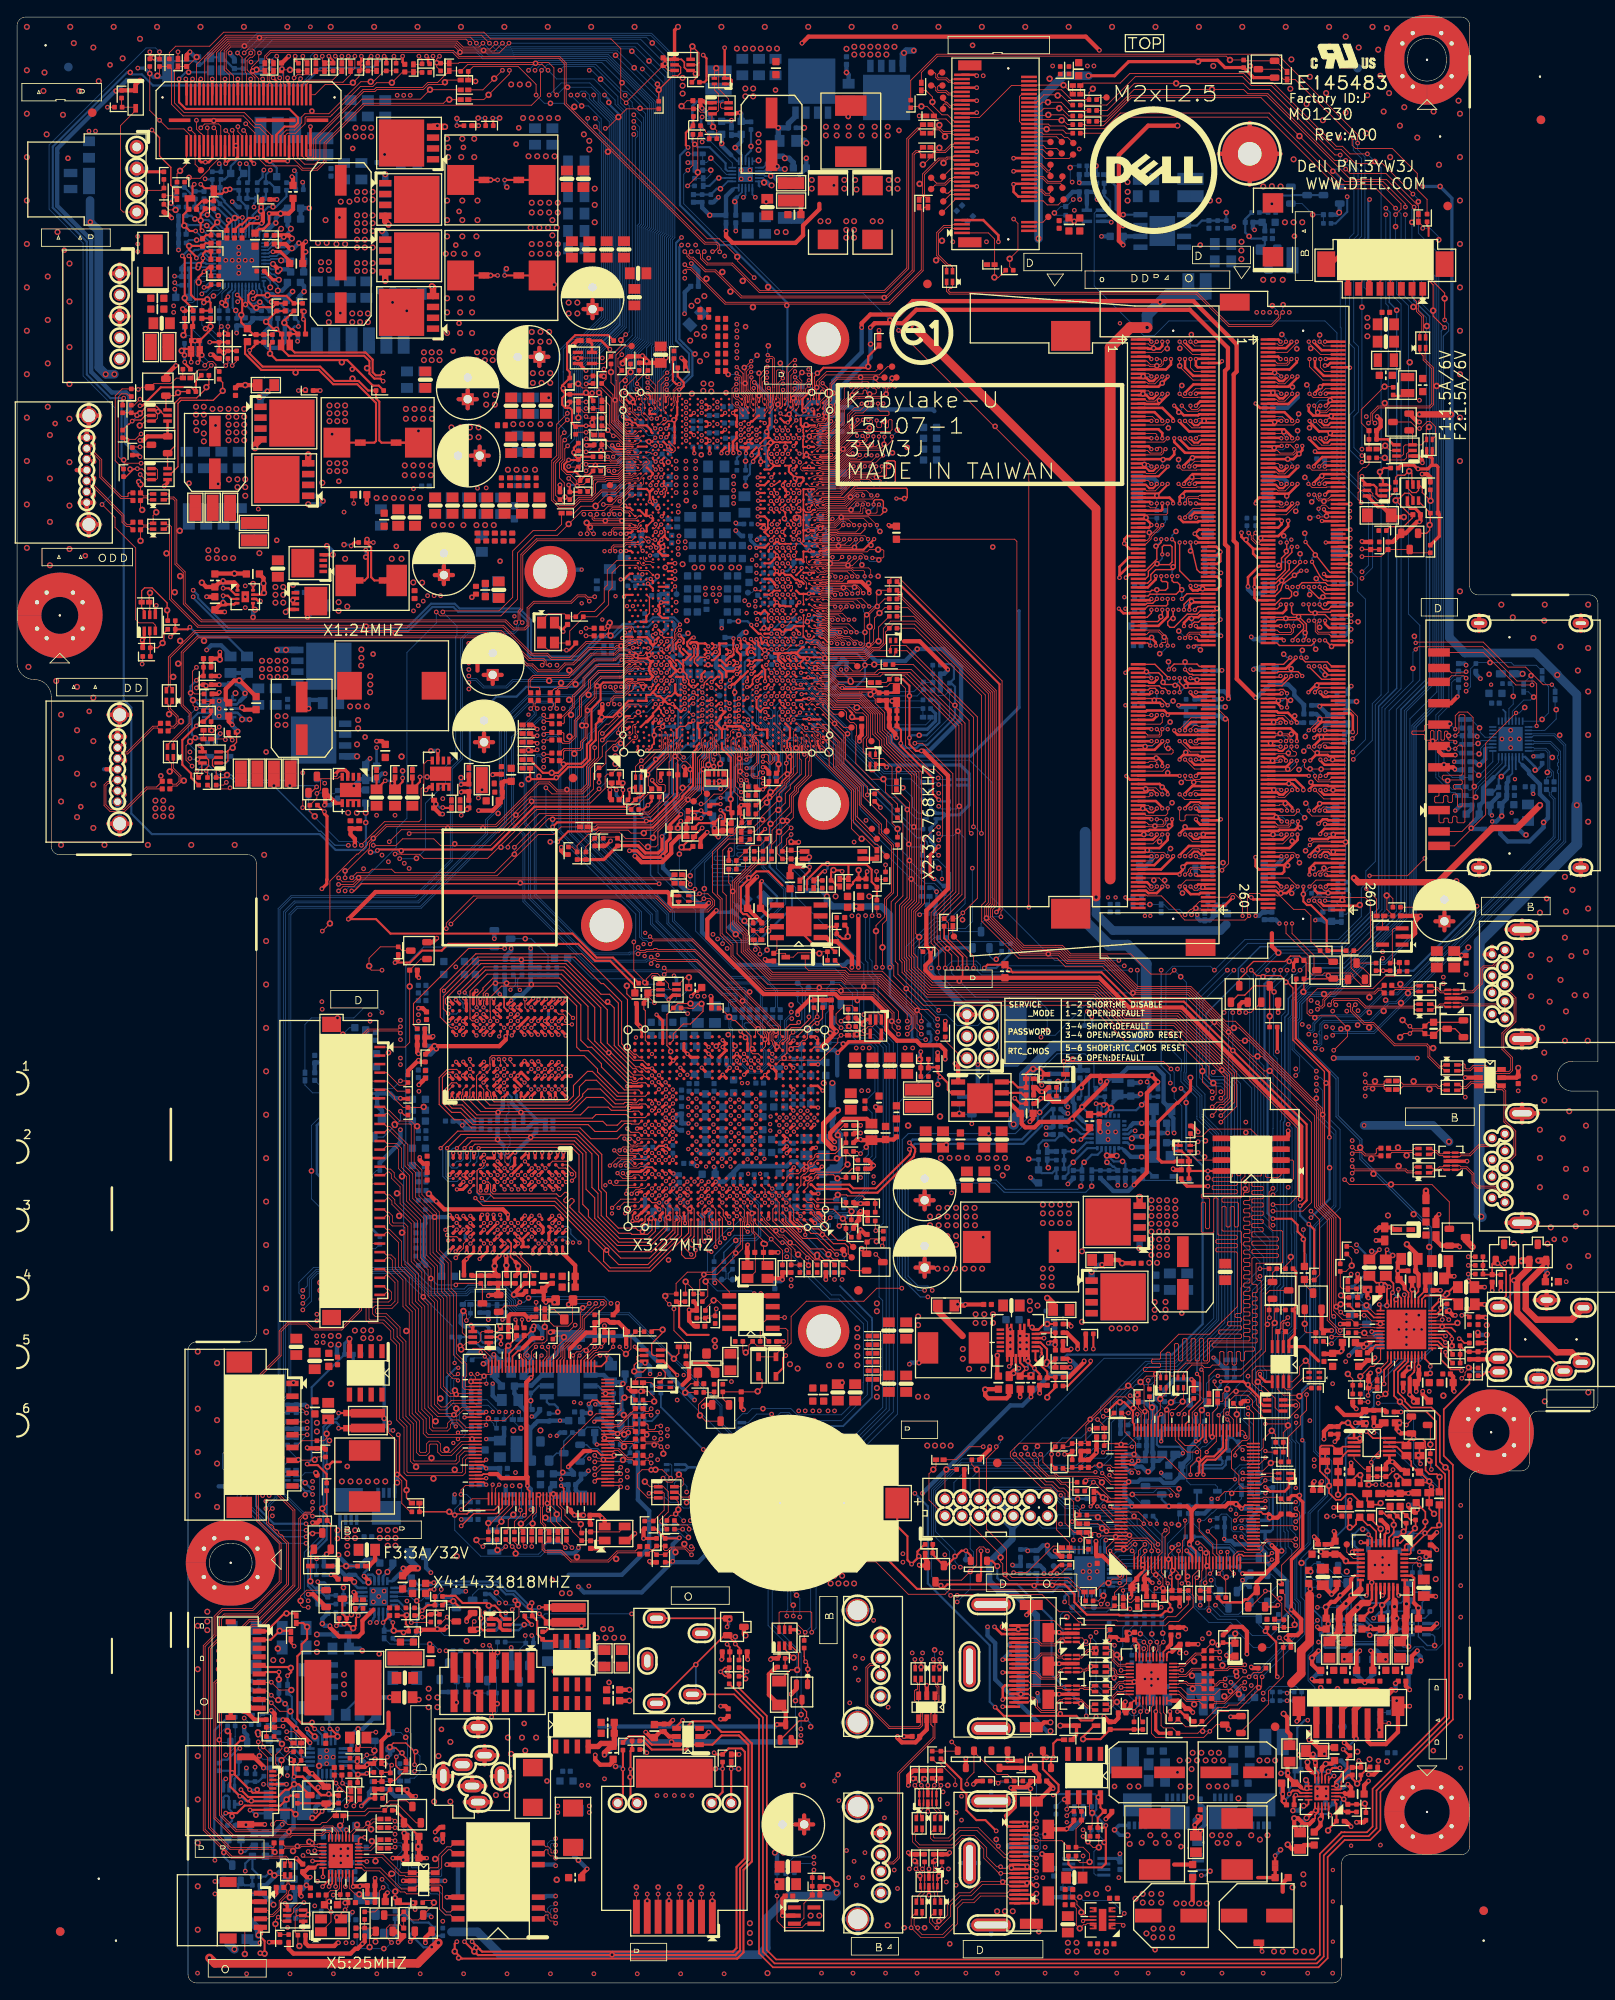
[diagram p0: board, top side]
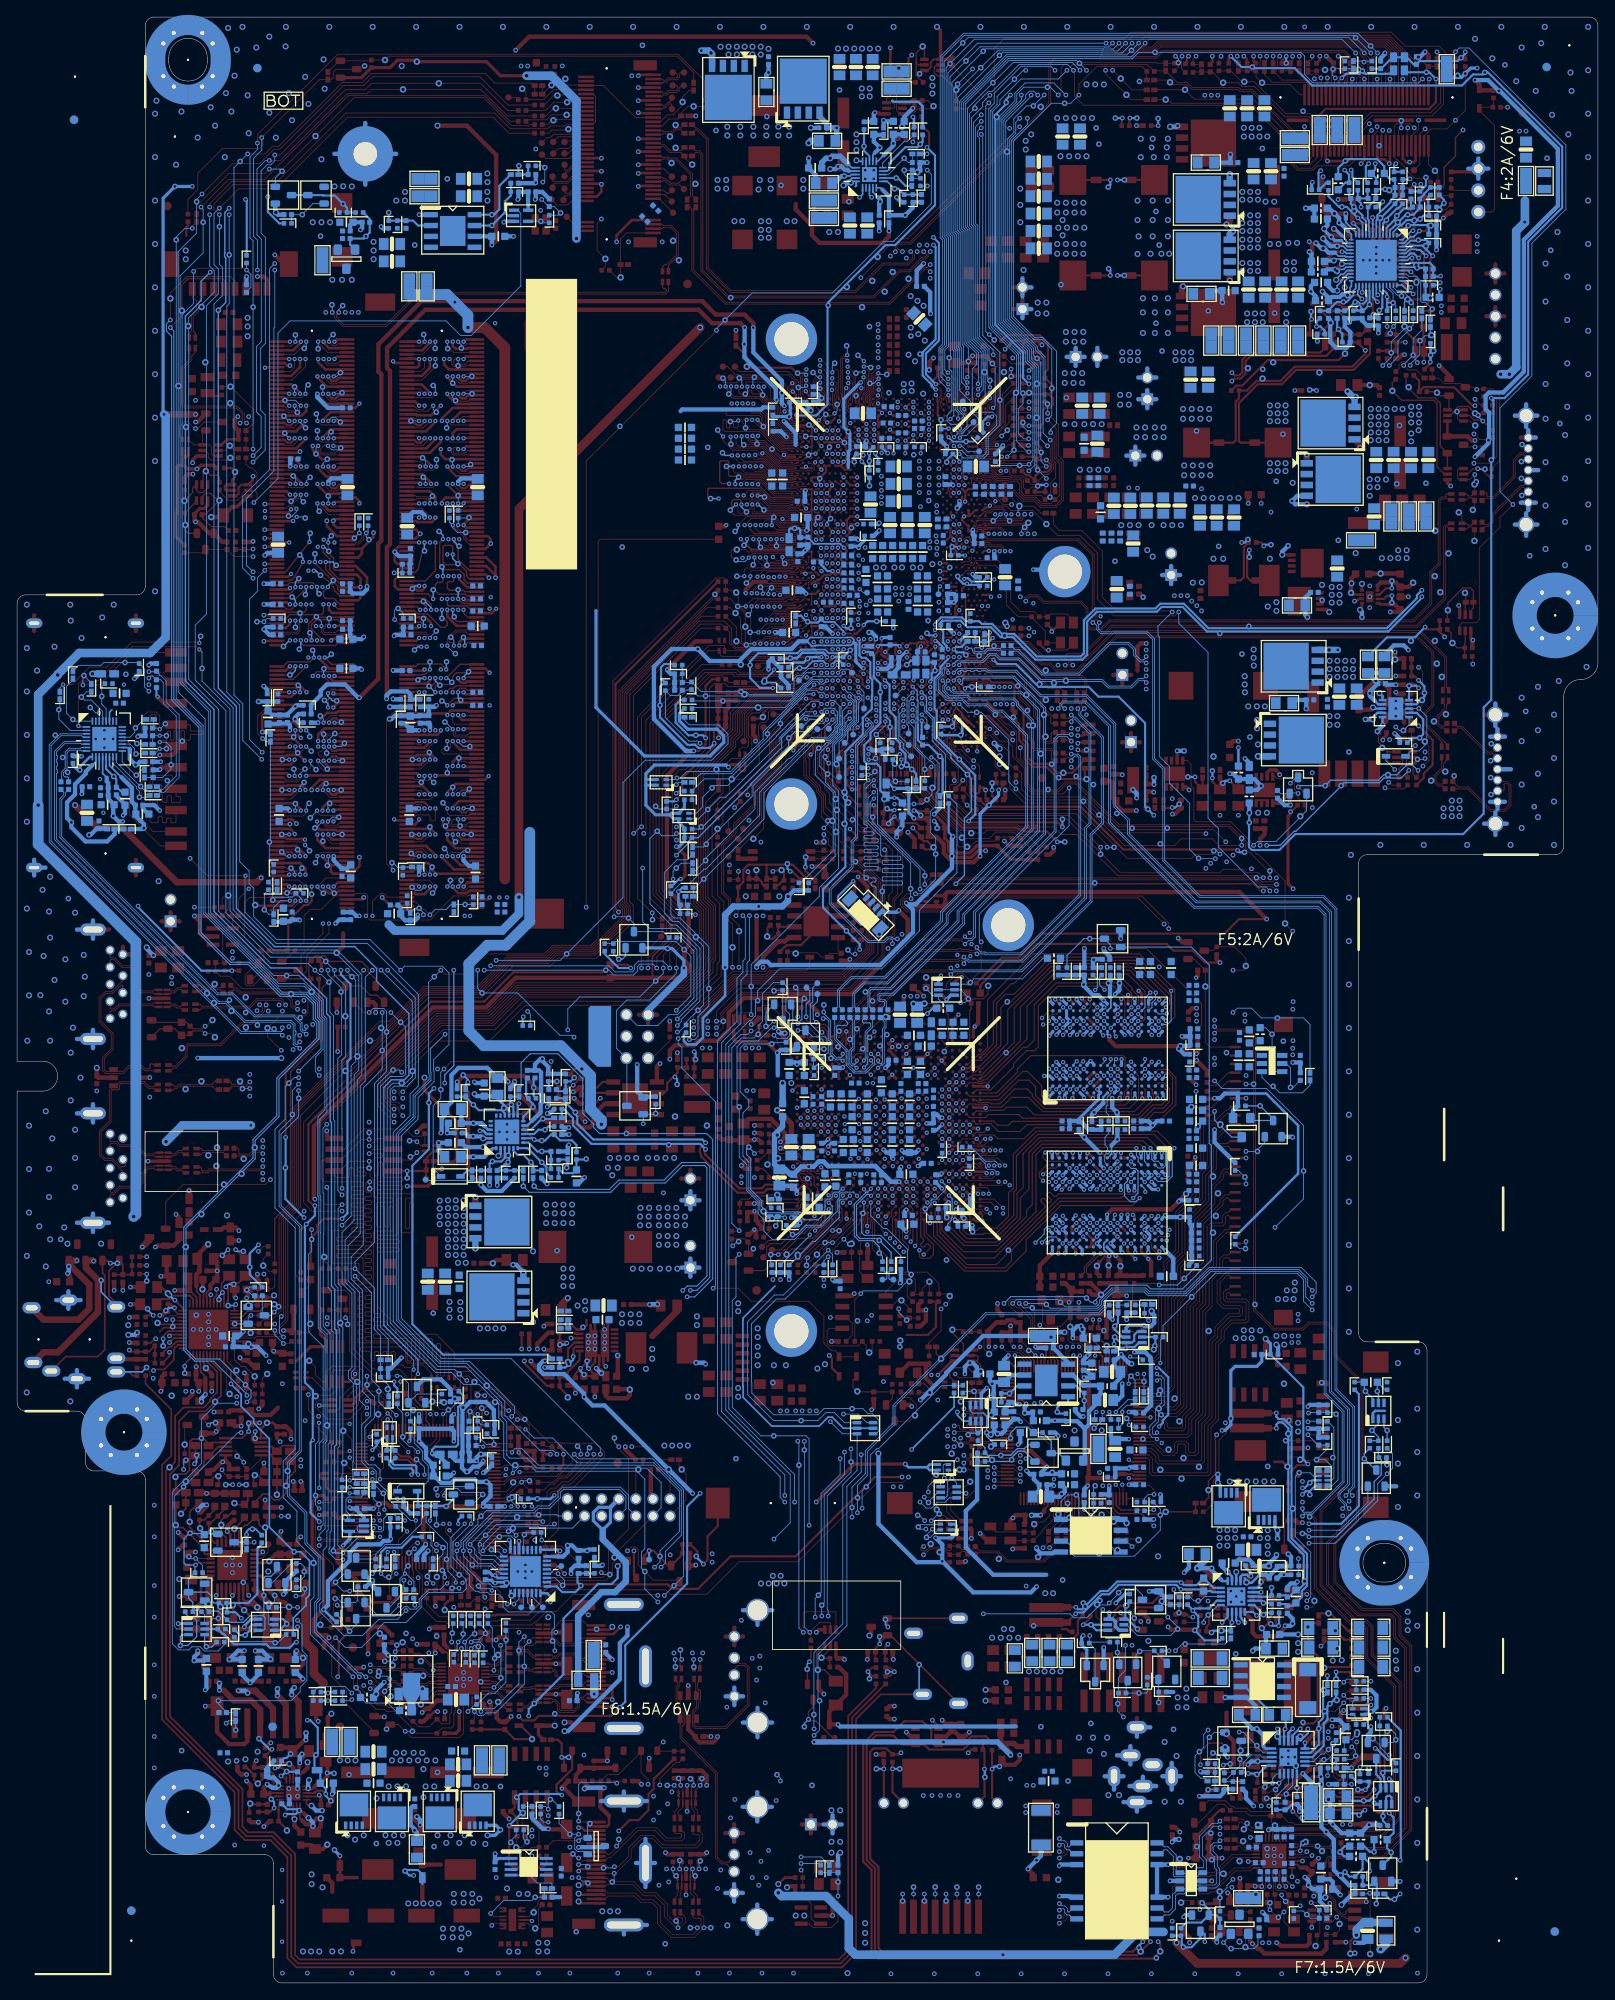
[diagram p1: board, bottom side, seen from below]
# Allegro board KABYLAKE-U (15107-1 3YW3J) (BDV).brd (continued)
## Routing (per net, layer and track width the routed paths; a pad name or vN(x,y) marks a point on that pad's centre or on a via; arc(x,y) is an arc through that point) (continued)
M_A_A1: length 56.6
  TOP w0.089: CPU1.BB50 94.47,172.92 94.65,173.1 96.87,173.1 98.18,174.41 98.88,174.41 99.01,174.28 v1(99.01,174.04)
  TOP w0.165: v1(134.02,160.66) 134.02,159.82 133.48,159.28 DIMM1.133
  L3 w0.089: 107.47,174.99 107,174.52 102.55,174.52 102.46,174.43 102.46,173.84 102.36,173.74 102.21,173.74 102.1,173.84 102.1,174.43 102.01,174.52 101.84,174.52 101.75,174.43 101.75,174.08 101.66,173.99 101.48,173.99 101.39,174.08 101.39,174.43 101.3,174.52 99.12,174.52 99.01,174.42 v1(99.01,174.04)
  L3 w0.216: 107.47,174.99 115.07,174.99 128.29,161.77 128.79,161.77 128.94,161.93 128.94,162.69 129.14,162.89 130,162.89 130.21,162.69 130.21,161.98 130.41,161.77 130.74,161.77 132.44,160.07 133.8,160.07 134.02,160.29 v1(134.02,160.66)
  BOTTOM w0.165: v1(134.02,160.66) 134.02,160.02 v2(133.84,159.84)
M_A_A2: length 59.9
  TOP w0.089: CPU1.AY51 93.57,173.19 93.73,173.19 93.86,173.15 94.09,173.15 94.36,173.21 94.48,173.33 96.81,173.33 98.07,174.59 99.42,174.59 v1(99.97,174.04)
  TOP w0.165: DIMM1.132 138.57,159.53 138.26,159.21 137.76,159.21 137.49,158.94 137.49,158.92 v1(137.32,158.75)
  L3 w0.089: 108.11,173.51 107.77,173.16 103.98,173.16 103.67,172.85 101.8,172.85 101.19,173.46 100.55,173.46 v1(99.97,174.04)
  L3 w0.216: 108.11,173.51 114.35,173.51 128.57,159.28 130.81,159.28 131.35,158.75 135.16,158.75 136.05,157.86 137.96,157.86 138.59,158.5 138.59,159 138.21,159.38 137.9,159.38 137.32,158.81 v1(137.32,158.75)
  BOTTOM w0.165: v1(137.32,158.75) 137.45,158.88 v2(137.45,159.64)
M_A_A3: length 57.5
  TOP w0.089: v1(98.34,174.01) 98.1,174.01 97.74,173.66 96.93,172.85 94.67,172.85 94.47,172.65 93.94,172.65 CPU1.BA50
  TOP w0.165: v1(132.75,160.66) 132.75,160.27 132.25,159.78 DIMM1.131
  L3 w0.089: 106.78,175.01 106.67,174.89 102.53,174.89 102.4,174.75 97.49,174.75 97.08,175.17 97.08,176.43 96.95,176.56 96.2,176.56 96.07,176.43 96.07,175.06 97.12,174.01 v1(98.34,174.01)
  L3 w0.216: v1(132.75,160.66) 132.56,160.66 131.52,161.69 131.52,162.22 130.35,163.39 127.37,163.39 115.14,175.62 107.39,175.62 106.78,175.01
  BOTTOM w0.165: v2(97.53,173.85) 97.69,174.01 v1(98.34,174.01)
M_A_A4: length 58.3
  TOP w0.089: v1(100.28,175.35) 99.72,175.91 98.04,175.91 96.4,174.27 96.4,174.25 CPU1.BB52
  TOP w0.165: v1(135.29,160.66) 135.29,159.89 134.65,159.26 134.65,158.88 134.92,158.61 135.4,158.61 136.94,160.15 138.08,160.15 138.46,160.53 DIMM1.128
  L3 w0.089: 106.46,175.39 106.45,175.37 102.46,175.37 102.04,174.96 100.67,174.96 v1(100.28,175.35)
  L3 w0.216: v1(135.29,160.66) 135.29,161.16 135.03,161.42 132.49,161.42 132.01,161.9 132.01,162.43 130.56,163.88 127.58,163.88 115.35,176.11 107.19,176.11 106.46,175.39
  BOTTOM w0.165: v1(135.29,160.66) v2(135.29,159.64)
M_A_A5: length 58.7
  TOP w0.089: CPU1.BA51 93.62,173.37 93.77,173.37 93.89,173.32 94.07,173.32 94.25,173.37 94.43,173.55 96.78,173.55 98.1,174.88 98.33,174.88
  TOP w0.165: 98.33,174.88 104.05,174.88 104.17,174.75 104.17,173.79 104.05,173.67 v1(102.9,173.67) ; DIMM1.126 138.2,161.03 v1(137.83,160.66)
  L3 w0.216: v1(137.83,160.66) 137.83,160.6 137.38,160.15 134.53,160.15 134.04,159.66 132.15,159.66 131.54,160.27 131.1,160.27 130.87,160.5 130.87,160.94 130.53,161.27 128.08,161.27 114.86,174.5 107.59,174.5 107.18,174.09 103.33,174.09 v1(102.9,173.67)
  BOTTOM w0.165: v2(103.84,173.67) v1(102.9,173.67)
M_A_A6: length 57.6
  TOP w0.089: v1(100.95,175.36) 101.13,175.53 101.13,175.77 101,175.9 100.11,175.9 99.92,176.09 97.97,176.09 96.4,174.52 93.94,174.52 CPU1.BA52
  TOP w0.165: v1(134.65,161.93) 134.65,161.29 134.48,161.12 132.37,161.12 132.03,160.78 DIMM1.127
  L3 w0.089: 105.87,176.2 105.8,176.12 101.72,176.12 101.56,175.97 100.82,175.97 100.71,175.86 100.71,175.6 v1(100.95,175.36)
  L3 w0.216: 105.87,176.2 105.98,176.3 106.78,177.1 116.12,177.1 127.53,165.69 130.15,165.69 132.39,163.45 135.19,163.45 135.44,163.19 135.44,162.77 135.26,162.59 134.81,162.59 134.65,162.43 v1(134.65,161.93)
  BOTTOM w0.165: v1(100.95,175.36) 100.95,175.79 v2(100.57,176.17)
M_A_A7: length 60
  TOP w0.089: CPU1.AW52 92.65,173.86 93.15,173.86 93.26,173.97 96.37,173.97 96.57,174.17 96.57,174.19 98.11,175.73 98.62,175.73 v1(98.97,175.38)
  TOP w0.165: DIMM1.122 137.29,162.03 136.56,161.29 v1(136.56,160.66)
  L3 w0.089: v1(98.97,175.38) 98.97,175.77 99.35,176.15 101.38,176.15 101.73,176.5 105.42,176.5 105.57,176.66
  L3 w0.216: v1(136.56,160.66) 136.56,160.78 135.8,161.54 135.8,162.12 135.94,162.26 135.94,163.4 135.38,163.96 132.9,163.96 131.76,165.1 131.45,165.1 130.28,166.27 127.78,166.27 116.45,177.6 106.51,177.6 105.57,176.66
  BOTTOM w0.165: v1(136.56,160.66) 136.56,160.91 137.29,161.65 v2(137.45,161.65)
M_A_A8: length 58.7
  TOP w0.089: 100.54,176.28 100.34,176.28 100.32,176.3 97.88,176.3 97.75,176.17 97.75,176.15 96.41,174.81 93.73,174.81 93.38,174.46 93.33,174.46 CPU1.AY52
  TOP w0.165: v1(101.67,175.4) 102.51,175.4 102.78,175.67 102.78,177.95 102.65,178.08 101.85,178.08 101.73,177.95 101.73,176.4 101.6,176.28 100.54,176.28 ; v1(133.38,161.93) 133.21,161.75 133.21,161.73 132.9,161.42 132.24,161.42 132.1,161.28 DIMM1.125
  L3 w0.089: 106.56,176.18 106.12,175.74 102.01,175.74 v1(101.67,175.4)
  L3 w0.216: v1(133.38,161.93) 133.38,161.98 133.77,162.37 133.77,162.68 133.5,162.95 132.19,162.95 130.09,165.05 127.26,165.05 115.7,176.61 106.98,176.61 106.56,176.18
  BOTTOM w0.165: v1(133.38,161.93) v2(133.38,162.99)
M_A_A9: length 57.7
  TOP w0.089: CPU1.BB54 96.36,175.28 97.74,176.65 99.76,176.65 v1(100.54,177.43)
  TOP w0.165: DIMM1.121 132.37,162.28 132.58,162.48 135.64,162.48 136.08,162.92 136.08,163.58 135.8,163.86 135.36,163.86 135.16,164.06 v1(135.16,164.59)
  L3 w0.089: v1(100.54,177.43) 100.95,177.85 101.58,177.85 102.15,177.28 104.78,177.28 105.04,177.55
  L3 w0.216: 105.04,177.55 106.08,178.59 116.86,178.59 128.18,167.26 130.84,167.26 132.01,166.09 134.81,166.09 135.16,165.74 v1(135.16,164.59)
  BOTTOM w0.165: v2(135.29,165.68) 135.16,165.56 v1(135.16,164.59)
M_A_A10: length 58.5
  TOP w0.165: v1(90.84,172.51) 90.84,172.55 90.55,172.85 CPU1.AT50 ; DIMM1.146 138.36,154.03 138.08,154.31 135.39,154.31 134.78,153.69 v1(134.78,153.67)
  L3 w0.089: 104.33,168.38 102.88,169.82 95.46,169.82 93.84,171.45 91.6,171.45 90.84,172.21 v1(90.84,172.51)
  L3 w0.216: 104.33,168.38 112.15,168.38 126.86,153.67 129.39,153.67 129.5,153.78 134.67,153.78 v1(134.78,153.67)
  BOTTOM w0.165: v1(134.78,153.67) 134.78,154.53 v2(134.74,154.57)
M_A_A11: length 58.4
  TOP w0.089: v1(99.21,177.44) 98.61,176.83 97.61,176.83 96.31,175.54 94.23,175.54 94.13,175.51 93.82,175.44 CPU1.BA54
  TOP w0.165: v1(136.3,161.93) 136.9,162.53 DIMM1.120
  L3 w0.089: v1(99.21,177.44) 99.83,178.05 101.76,178.05 102.16,177.65 104.43,177.65 104.73,177.95
  L3 w0.216: v1(136.3,161.93) 136.43,162.05 136.43,165.74 135.58,166.59 132.21,166.59 130.97,167.83 128.32,167.83 117.06,179.08 105.86,179.08 104.73,177.95
  BOTTOM w0.165: v1(136.3,161.93) v2(136.3,162.99)
M_A_A12: length 58.8
  TOP w0.089: CPU1.AW54 92.49,175.38 92.79,175.07 93.44,175.07 93.49,175.02 96.35,175.02 97.81,176.48 100.06,176.48 100.24,176.66 101,176.66 101.2,176.85 v1(101.2,177.43)
  TOP w0.165: v1(133.89,164.59) 133.89,164.08 134.02,163.96 134.51,163.96 134.65,163.81 134.65,163.19 134.4,162.94 132.79,162.94 132.62,162.78 DIMM1.119
  L3 w0.089: 105.34,177.14 105.09,176.88 101.51,176.88 101.03,176.4 100.29,176.4 100.11,176.59 100.11,176.85 100.29,177.03 100.8,177.03 v1(101.2,177.43)
  L3 w0.216: v1(133.89,164.59) 133.89,165.23 133.52,165.6 131.66,165.6 130.49,166.76 127.98,166.76 116.65,178.09 106.29,178.09 105.34,177.14
  BOTTOM w0.165: v1(101.2,177.43) v2(101.99,177.43)
M_A_A13: length 61.2
  TOP w0.165: v1(91.55,170.6) 91.7,170.75 91.7,171.55 91.57,171.68 90.97,171.68 90.84,171.55 90.84,171.29 91.01,171.12 CPU1.AU46 ; DIMM1.158 137.98,151.03 v1(137.96,151)
  L3 w0.089: 104.45,166.85 102.9,168.4 94.14,168.4 93.12,169.42 93.12,170.18 92.7,170.6 v1(91.55,170.6)
  L3 w0.216: v1(137.96,151) 137.96,151.89 137.7,152.15 133.76,152.15 133.62,152 132.48,152 131.93,151.45 126.96,151.45 111.56,166.85 104.45,166.85
  BOTTOM w0.165: v1(91.55,170.6) 91.55,171.19 v2(91.27,171.48)
M_A_A14: length 59.9
  TOP w0.165: CPU1.AT46 90.92,170.75 v1(90.92,170.63) ; DIMM1.151 131.2,152.77 132.63,152.77 v1(132.75,152.65)
  L3 w0.089: v1(90.92,170.63) 91.29,171 93.5,171 93.63,170.87 93.63,170.75 93.35,170.47 93.35,170.34 93.47,170.21 93.6,170.21 93.88,170.5 94.01,170.5 94.13,170.37 94.13,170.25 93.54,169.66 93.54,169.51 93.65,169.4 93.79,169.4 94.38,169.99 94.51,169.99 94.63,169.87 94.63,169.74 94.04,169.15 94.04,169.01 94.15,168.9 94.3,168.9 94.89,169.49 95.01,169.49 95.14,169.37 100.82,169.37 100.91,169.28 100.91,168.87 100.99,168.78 101.17,168.78 101.26,168.87 101.26,169.28 101.35,169.37 101.53,169.37 101.62,169.28 101.62,168.87 101.71,168.78 101.88,168.78 101.97,168.87 101.97,169.28 102.06,169.37 102.45,169.37 102.81,169
  L3 w0.216: 102.81,169 104.45,167.36 111.77,167.36 127.18,151.95 131.66,151.95 132.12,152.4 132.5,152.4 v1(132.75,152.65)
  BOTTOM w0.165: v2(132.16,153.42) 132.75,152.83 v1(132.75,152.65)
M_A_A15: length 59.9
  TOP w0.165: v1(136.05,152.65) 136.05,152.15 136.67,151.53 DIMM1.156 ; CPU1.AU48 91.6,172.03 91.71,172.15 91.71,172.44 91.61,172.54 v1(91.52,172.54)
  L3 w0.089: 104.33,168.88 104.07,168.88 102.88,170.08 95.66,170.08 94.11,171.63 92.06,171.63 91.52,172.17 v1(91.52,172.54)
  L3 w0.216: 104.33,168.88 112.34,168.88 126.92,154.31 135.47,154.31 136.05,153.73 v1(136.05,152.65)
  BOTTOM w0.165: v1(136.05,152.65) 136.05,152.35 v2(135.52,151.82)
M_A_A16: length 59.6
  TOP w0.165: DIMM1.152 137.45,152.53 v1(137.32,152.65) ; v1(91.54,173.37) 91.54,173.29 CPU1.AU50
  L3 w0.089: v1(91.54,173.37) 91.59,173.37 92.26,172.69 92.26,172.31 92.49,172.09 95.31,172.09 96.17,171.22 102.63,171.22 103.54,170.31
  L3 w0.216: v1(137.32,152.65) 137.81,153.14 137.81,153.94 136.43,155.32 127.41,155.32 112.86,169.88 103.97,169.88 103.54,170.31
  BOTTOM w0.165: v2(138.08,152.45) 137.88,152.65 v1(137.32,152.65)
M_A_ACT_N: length 58.4
  TOP w0.089: v1(101.33,178.72) 100.46,177.84 97.64,177.84 95.96,176.16 94.21,176.16 94.08,176.2 93.91,176.2 93.72,176.15 93.62,176.15 CPU1.BA55
  TOP w0.165: DIMM1.114 137.25,164.03 136.05,165.23 v1(136.05,168.53)
  L3 w0.216: v1(136.05,168.53) 136.05,168.15 135.7,167.8 132.56,167.8 130.73,169.63 127.92,169.63 117.47,180.07 105.43,180.07 104.07,178.72 v1(101.33,178.72)
  BOTTOM w0.165: v1(101.33,178.72) 102.14,178.72 v2(102.45,179.02)
M_A_BG0: length 59.9
  TOP w0.089: CPU1.AY55 93.29,176.33 93.69,176.33 93.89,176.38 94.1,176.38 94.23,176.34 95.88,176.34 97.56,178.02 99.98,178.02 v1(100.67,178.72)
  TOP w0.165: DIMM1.115 132.31,163.78 132.68,164.15 132.68,164.78 133.26,165.35 135.29,165.35 135.54,165.61 135.54,168.53 v1(135.16,168.91)
  L3 w0.089: 104.7,180.06 104.64,180 104.62,180 103.8,179.18 101.14,179.18 v1(100.67,178.72)
  L3 w0.216: 104.7,180.06 105.21,180.57 117.68,180.57 128.12,170.13 130.95,170.13 132.78,168.29 134.93,168.29 135.16,168.53 v1(135.16,168.91)
  BOTTOM w0.165: v2(135.62,169.82) 135.16,169.37 v1(135.16,168.91)
M_A_BG1: length 58.8
  TOP w0.089: CPU1.AY54 93.23,175.6 93.73,175.6 93.76,175.6 93.84,175.68 94.07,175.68 94.21,175.71 96.21,175.71 97.54,177.04 98.15,177.04 v1(98.55,177.44)
  TOP w0.165: DIMM1.113 132.05,164.28 132.39,164.61 132.39,165.15 133.17,165.94 134.86,165.94 135.16,166.24 135.16,168.02 134.99,168.2 134.19,168.2 134.02,168.02 v1(134.02,167.13)
  L3 w0.089: 104.43,178.36 104,177.93 102.52,177.93 102.14,178.31 99.02,178.31 98.55,177.85 v1(98.55,177.44)
  L3 w0.216: v1(134.02,167.13) 132.52,167.13 130.65,169.01 127.84,169.01 117.27,179.58 105.65,179.58 104.43,178.36
  BOTTOM w0.165: v1(134.02,167.13) 134.02,166.65 v2(133.41,166.04)
M_A_BS0: length 58.7
  TOP w0.165: CPU1.AU52 91.2,173.71 v1(90.89,173.4) ; v1(136.69,153.67) 136.69,153.64 137.21,153.12 137.51,153.12 137.6,153.03 DIMM1.150
  L3 w0.089: v1(90.89,173.4) 91.34,172.94 91.68,172.94 91.92,172.71 91.92,172.35 92.41,171.86 94.19,171.86 95.18,170.87 96.16,170.87 96.26,170.96 102.49,170.96 104.07,169.38 104.33,169.38
  L3 w0.216: 104.33,169.38 112.62,169.38 127.19,154.81 135.54,154.81 v1(136.69,153.67)
  BOTTOM w0.165: v1(136.69,153.67) v2(136.69,154.56)
M_A_BS1: length 59.2
  TOP w0.165: DIMM1.145 133.16,154.28 v1(134.78,152.65) ; CPU1.AT48 90.55,172.12 v1(90.19,172.48)
  L3 w0.089: 104.29,168.03 102.75,169.57 95.31,169.57 93.63,171.25 91.42,171.25 v1(90.19,172.48)
  L3 w0.216: v1(134.78,152.65) 134.15,153.29 132.37,153.29 131.52,152.44 127.38,152.44 111.96,167.87 104.45,167.87 104.29,168.03
  BOTTOM w0.165: v1(134.78,152.65) 134.6,152.65 v2(134.11,152.17)
M_A_CKE0: length 58.4
  TOP w0.089: CPU1.BA56 93.7,176.6 93.97,176.78 94.21,176.87 95.9,176.87 97.42,178.38 98.23,178.38 v1(98.62,178.76)
  TOP w0.165: v1(133.89,168.91) 133.89,168.53 133.38,168.02 133.38,166.56 132.1,165.28 DIMM1.109
  L3 w0.089: v1(98.62,178.76) 98.51,178.87 98.51,179.72 98.62,179.83 98.78,179.83 98.89,179.72 98.89,179.29 98.97,179.2 99.15,179.2 99.24,179.29 99.24,179.71 99.37,179.83 99.54,179.83 99.67,179.71 99.67,179.29 99.76,179.2 99.94,179.2 100.02,179.29 100.02,179.73 100.13,179.83 100.28,179.83 100.38,179.73 100.38,179.29 100.47,179.2 100.65,179.2 100.74,179.29 100.74,179.72 100.84,179.83 101,179.83 101.1,179.72 101.1,179.54 101.19,179.45 101.37,179.45 101.46,179.54 101.46,179.65 101.55,179.74 101.74,179.74 101.83,179.65 101.83,179.45 101.92,179.36 102.09,179.36 102.18,179.45 102.18,179.65 102.27,179.74 103.69,179.74 104.5,180.56
  L3 w0.216: v1(133.89,168.91) 133.89,169.16 133.51,169.55 133.47,169.56 132.24,169.56 131.15,170.65 128.6,170.65 118.19,181.06 105.01,181.06 104.5,180.56
  BOTTOM w0.165: v1(133.89,168.91) 133.89,168.71 v2(133.28,168.1)
M_A_CKE1: length 59.2
  TOP w0.089: v1(99.35,178.73) 98.59,178.2 97.49,178.2 95.89,176.6 CPU1.BB56
  TOP w0.165: v1(137.32,168.53) 138.08,165.35 138.41,165.03 139.25,165.03 DIMM1.110
  L3 w0.089: v1(99.35,178.73) 98.71,178.33 98.43,178.33 98.2,178.56 98.2,179.83 98.49,180.12 103.36,180.12 104,180.76
  L3 w0.216: v1(137.32,168.53) 137,168.97 133.51,170.07 132.43,170.07 131.35,171.14 128.81,171.14 118.39,181.56 104.8,181.56 104,180.76
  BOTTOM w0.165: v1(137.32,168.53) v2(137.32,167.54)
M_A_CLK0: length 60.6
  TOP w0.102: v1(134.65,156.46) 134.65,157.3 133.68,158.28 DIMM1.137 ; CPU1.AT53 v1(90.89,174.32)
  L3 w0.089: 104.35,171.81 103.57,171.81 103.32,172.06 103.08,172.06 97.6,172.06 95.68,173.99 95.23,173.99 95.15,174.08 95.15,174.47 94.93,174.69 94.62,174.69 94.41,174.47 94.41,174.08 94.32,173.99 94.14,173.99 94.05,174.08 94.05,174.47 93.84,174.69 93.53,174.69 93.32,174.47 93.32,174.08 93.23,173.99 92.74,173.99 91.87,174.86 91.52,174.86 90.97,174.32 v1(90.89,174.32)
  L3 w0.127: v1(134.65,156.46) 134.61,156.5 134.61,157.01 134.34,157.28 128.21,157.28 113.68,171.81 104.35,171.81
  BOTTOM w0.102: v2(133.71,155.52) 133.81,155.52 134.65,156.36 v1(134.65,156.46)
M_A_CLK1: length 60
  TOP w0.102: CPU1.AT55 90.55,175.51 90.28,175.24 v1(90.26,175.24) ; v1(136.69,157.35) 136.92,157.59 136.92,157.77 137.18,158.03 DIMM1.138
  L3 w0.127: v1(90.26,175.24) 90.44,175.43 90.44,175.75 90.71,176.02 94.56,176.02 98.04,172.55 104,172.55 104.17,172.72 114.05,172.72 128.27,158.5 130.97,158.5 131.4,158.07 134.7,158.07 135.87,156.91 136.24,156.91 v1(136.69,157.35)
  BOTTOM w0.102: v1(136.69,157.35) 136.69,157.43 v2(135.95,158.17)
M_A_CLK#0: length 60.4
  TOP w0.102: CPU1.AU53 91.57,174.78 91.73,174.62 91.73,174.5 v1(91.52,174.29) ; DIMM1.139 132.2,157.78 132.48,158.06 133.59,158.06 134.44,157.21 134.44,156.88 134.37,156.82 133.99,156.82 133.89,156.72 v1(133.89,156.46)
  L3 w0.089: 104.35,171.55 104.24,171.55 104.16,171.62 103.49,171.62 103.24,171.87 97.52,171.87 95.6,173.8 95.16,173.8 94.95,174 94.95,174.39 94.85,174.5 94.7,174.5 94.6,174.39 94.6,174 94.4,173.8 94.06,173.8 93.86,174 93.86,174.39 93.76,174.5 93.61,174.5 93.51,174.39 93.51,174 93.31,173.8 92.66,173.8 91.79,174.67 91.6,174.67 91.5,174.57 91.5,174.32 v1(91.52,174.29)
  L3 w0.127: 104.35,171.55 113.57,171.55 128.1,157.02 134.23,157.02 134.35,156.9 134.35,156.79 134.02,156.46 v1(133.89,156.46)
  BOTTOM w0.102: v1(133.89,156.46) 133.89,157.1 v2(134.25,157.45)
M_A_CLK#1: length 59.8
  TOP w0.102: DIMM1.140 138.62,157.53 138.34,157.81 137.27,157.81 137.14,157.68 137.14,157.54 v1(137.32,157.35) ; v1(90.91,175.24) 90.93,175.24 91.2,175.51 CPU1.AU55
  L3 w0.127: v1(137.32,157.35) 136.61,156.64 135.76,156.64 134.59,157.8 131.28,157.8 130.86,158.23 128.16,158.23 113.94,172.45 104.28,172.45 104.11,172.28 97.93,172.28 94.45,175.76 90.82,175.76 90.71,175.64 90.71,175.44 v1(90.91,175.24)
  BOTTOM w0.102: v2(91.07,176.02) 91.07,175.4 v1(90.91,175.24)
M_A_CS#0: length 62.9
  TOP w0.165: DIMM1.149 133.6,153.28 134.02,152.86 134.02,152.12 134.22,151.91 135.8,151.91 136.05,151.66 v1(136.05,151) ; v1(90.89,169.76) 91.2,170.06 CPU1.AU45
  L3 w0.089: 104.33,166.34 102.52,168.15 93.99,168.15 93,169.14 92.46,169.14 92.11,169.49 92.11,169.93 91.83,170.2 91.34,170.2 v1(90.89,169.76)
  L3 w0.216: 104.33,166.34 111.37,166.34 126.76,150.96 132.01,150.96 132.64,151.59 133.78,151.59 133.93,151.74 135.97,151.74 136.18,151.54 136.18,151.13 v1(136.05,151)
  BOTTOM w0.165: v1(136.05,151) 136.08,151 v2(136.79,151.71)
M_A_CS#1: length 64.4
  TOP w0.165: DIMM1.157 132.36,151.28 132.56,151.47 133.18,151.47 133.38,151.26 v1(133.38,151) ; v1(91.53,169.71) 91.2,169.38 CPU1.AU43
  L3 w0.089: 104.12,166.04 102.22,167.94 94.57,167.94 94.44,167.82 94.44,167 94.33,166.88 94.16,166.88 94.04,167 94.04,167.84 93.94,167.94 93.73,167.94 93.66,167.87 93.66,166.96 93.55,166.85 93.39,166.85 93.28,166.96 93.28,168.28 93.15,168.4 92.99,168.4 92.23,167.64 92.11,167.64 91.98,167.77 91.98,167.89 92.6,168.51 92.6,168.64 v1(91.53,169.71)
  L3 w0.216: 104.12,166.04 104.31,165.85 110.73,165.85 111.12,165.46 111.53,165.46 111.94,165.06 111.94,164.64 112.34,164.24 112.76,164.24 113.16,163.84 113.16,163.42 113.56,163.02 113.98,163.02 114.38,162.62 114.38,162.2 114.78,161.8 115.2,161.8 115.6,161.39 115.6,160.98 116,160.57 116.42,160.57 116.82,160.17 116.82,159.75 117.22,159.35 117.64,159.35 118.04,158.95 118.04,158.53 118.45,158.13 118.86,158.13 119.27,157.73 119.27,157.31 119.67,156.91 120.09,156.91 120.49,156.51 120.49,156.09 120.89,155.69 121.31,155.69 121.71,155.28 121.71,154.87 122.11,154.46 122.53,154.46 122.93,154.06 122.93,153.64 123.33,153.24 123.75,153.24 124.15,152.84 124.15,152.42 124.55,152.02 124.97,152.02 125.38,151.62 125.38,151.2 126.61,149.96 128.64,149.96 129.15,150.46 130.36,150.46 130.86,149.96 131.79,149.96 132.29,150.46 132.97,150.46 132.97,150.47 133.23,150.47 133.38,150.62 v1(133.38,151)
  BOTTOM w0.165: v1(133.38,151) 133.38,150.37 v2(133.08,150.07)
M_A_DQ0: length 70.7
  TOP w0.089: CPU1.AL71 87.49,185.91 87.07,186.33 87.07,187.76 v1(87.76,188.45)
  TOP w0.102: v1(136.05,192.02) 137.55,190.52 139.4,190.52 DIMM1.8
  L3 w0.127: v1(87.76,188.45) 87.16,189.06 87.16,195.2 90.99,199.03 114.28,199.03 115.1,198.22 115.53,198.22 115.65,198.35 115.65,198.68 115.78,198.81 116.04,198.81 116.16,198.68 116.16,198.35 116.29,198.22 116.54,198.22 116.67,198.35 116.67,198.6 116.8,198.73 117.05,198.73 117.18,198.6 117.18,198.35 117.31,198.22 123.73,198.22 130.38,191.58 135.61,191.58 v1(136.05,192.02)
  BOTTOM w0.102: v1(136.05,192.02) 136.08,192 v2(136.08,191.24)
M_A_DQ1: length 71.3
  TOP w0.089: 87.94,186.05 87.96,186.03 87.96,185.23 87.89,185.09 87.89,184.89 87.94,184.77 87.94,184.57 87.87,184.36 87.87,184.02 87.49,183.51 CPU1.AL68
  TOP w0.102: 87.94,186.05 87.93,186.05 87.56,186.42 87.56,187.01 v1(87.73,187.18) ; DIMM1.7 133.91,190.78 134.65,191.52 v1(134.65,192.02)
  L3 w0.127: v1(87.73,187.18) 87.73,187.22 86.47,188.48 86.47,195.53 90.71,199.77 123.17,199.77 128.15,194.79 129.5,194.79 131.48,192.81 133.87,192.81 v1(134.65,192.02)
  BOTTOM w0.102: v1(134.65,192.02) 134.6,191.97 v2(134.6,191.21)
M_A_DQ2: length 71.9
  TOP w0.102: v1(88.82,182.7) 88.72,182.8 CPU1.AN68 ; v1(132.75,187.96) 132.43,188.28 DIMM1.17
  L3 w0.127: v1(88.82,182.7) 87.87,183.65 87.87,184.56 88.35,185.04 88.96,185.04 90.24,186.32 90.24,188.82 89.93,189.13 89.93,190.6 90.13,190.8 90.13,193.98 92.48,196.33 97.12,196.33 97.95,195.5 98.14,195.5 98.27,195.63 98.27,196.11 98.4,196.24 98.65,196.24 98.78,196.11 98.78,195.63 98.91,195.5 99.16,195.5 99.29,195.63 99.29,196.11 99.41,196.24 99.67,196.24 99.79,196.11 99.79,195.63 99.92,195.5 100.18,195.5 100.3,195.63 100.3,196.11 100.43,196.24 100.68,196.24 100.81,196.11 100.81,195.63 100.94,195.5 101.19,195.5 101.32,195.63 101.32,196.11 101.45,196.24 101.7,196.24 101.83,196.11 101.83,195.63 101.95,195.5 102.21,195.5 102.33,195.63 102.33,196.11 102.46,196.24 102.72,196.24 102.84,196.11 102.84,195.63 102.97,195.5 103.22,195.5 103.35,195.63 103.35,196.11 103.48,196.24 103.73,196.24 103.86,196.11 103.86,195.63 103.99,195.5 104.24,195.5 104.37,195.63 104.37,196.11 104.49,196.24 104.75,196.24 104.87,196.11 104.87,195.63 105,195.5 117.03,195.5 118.27,194.26 123.65,194.26 129.95,187.96 v1(132.75,187.96)
  BOTTOM w0.102: v1(132.75,187.96) v2(131.78,187.96)
M_A_DQ3: length 71.6
  TOP w0.089: CPU1.AN69 89,184.41 89.15,184.61 89.37,184.83 89.37,185.8 89.23,185.94 89.23,186.86 89.48,187.11 v1(89.64,187.11)
  TOP w0.102: DIMM1.20 139.4,187.52 137.63,187.52 136.05,189.1 v1(136.05,189.99)
  L3 w0.127: v1(89.64,187.11) 89.64,187.01 89.51,186.88 89.51,186.88 89.32,186.69 88.55,186.69 88.43,186.82 88.43,188.98 88.9,189.45 88.9,192.71 88.9,192.71 88.9,194.53 91.73,197.36 110.85,197.36 111.67,196.55 117.51,196.55 118.73,195.33 124.11,195.33 130.23,189.2 134.98,189.2 135.34,188.85 135.82,188.85 136.05,189.08 v1(136.05,189.99)
  BOTTOM w0.102: v2(136.05,189.2) 136.05,189.2 v1(136.05,189.99)
M_A_DQ4: length 71.3
  TOP w0.089: CPU1.AL70 87.28,184.87 87.23,185.06 87.23,185.91 86.89,186.25 86.89,188.19 v1(87.81,189.1)
  TOP w0.102: DIMM1.4 139.4,191.52 137.82,191.52 v1(137.32,192.02)
  L3 w0.127: v1(137.32,192.02) 136.53,191.24 130.23,191.24 123.91,197.56 123.31,197.56 123.18,197.43 123.18,196.98 123.05,196.85 122.8,196.85 122.67,196.98 122.67,197.43 122.54,197.56 122.29,197.56 122.16,197.43 122.16,196.98 122.04,196.85 121.78,196.85 121.66,196.98 121.66,197.43 121.53,197.56 118.38,197.56 118.06,197.88 114.96,197.88 114.14,198.69 91.16,198.69 87.52,195.06 87.52,195.05 87.5,195.02 87.5,190.74 87.42,190.66 87.42,189.49 v1(87.81,189.1)
  BOTTOM w0.102: v1(137.32,192.02) 137.32,192.76 v2(137.42,192.86)
M_A_DQ5: length 72.1
  TOP w0.089: CPU1.AL69 87.7,184.22 87.7,184.39 87.76,184.6 87.76,184.74 87.71,184.88 87.71,185.12 87.78,185.27 87.78,185.9 87.25,186.44 87.25,187.3 v1(87.76,187.82)
  TOP w0.102: DIMM1.3 132.39,191.78 132.57,191.59 132.95,191.59 v1(133.38,192.02)
  L3 w0.127: v1(87.76,187.82) 86.81,188.77 86.81,195.36 90.88,199.43 117.92,199.43 118.04,199.3 118.04,198.73 118.17,198.6 118.42,198.6 118.55,198.73 118.55,199.3 118.68,199.43 118.93,199.43 119.06,199.3 119.06,198.73 119.19,198.6 119.44,198.6 119.57,198.73 119.57,199.3 119.69,199.43 119.95,199.43 120.07,199.3 120.07,198.73 120.2,198.6 120.46,198.6 120.58,198.73 120.58,199.3 120.71,199.43 120.96,199.43 121.09,199.3 121.09,198.88 121.22,198.75 121.47,198.75 121.6,198.88 121.6,199.3 121.73,199.43 123.01,199.43 128.91,193.54 129.71,193.54 130.78,192.47 132.94,192.47 v1(133.38,192.02)
  BOTTOM w0.102: v1(133.38,192.02) 133,191.64 v2(133,191.26)
M_A_DQ6: length 70.3
  TOP w0.089: v1(89.61,187.74) 89.05,187.18 89.05,185.49 89.19,185.36 89.19,185.03 CPU1.AN70
  TOP w0.102: DIMM1.21 132.2,187.28 132.38,187.1 133.15,187.1 v1(134.02,187.96)
  L3 w0.127: v1(134.02,187.96) 133.46,188.52 129.93,188.52 123.81,194.64 118.42,194.64 117.2,195.86 110.71,195.86 110.58,195.99 110.58,196.55 110.46,196.67 110.2,196.67 110.08,196.55 110.08,195.99 109.95,195.86 109.7,195.86 109.57,195.99 109.57,196.55 109.44,196.67 109.19,196.67 109.06,196.55 109.06,195.99 108.93,195.86 108.68,195.86 108.55,195.99 108.55,196.55 108.43,196.67 108.17,196.67 108.04,196.55 108.04,195.99 107.92,195.86 107.66,195.86 107.54,195.99 107.54,196.55 107.41,196.67 107.16,196.67 107.03,196.55 107.03,195.99 106.9,195.86 106.65,195.86 106.52,195.99 106.52,196.55 106.39,196.67 106.14,196.67 106.01,196.55 106.01,195.99 105.89,195.86 105.63,195.86 105.5,195.99 105.5,196.55 105.38,196.67 92.31,196.67 89.75,194.11 89.75,190.93 89.58,190.77 89.58,189.07 90.02,188.63 90.02,188.15 v1(89.61,187.74)
  BOTTOM w0.102: v2(134.02,187.17) v1(134.02,187.96)
M_A_DQ7: length 69.6
  TOP w0.089: CPU1.AN71 88.82,185.6 88.87,185.65 88.87,188.59 89,188.72 89.3,188.72 v1(89.6,188.43)
  TOP w0.102: DIMM1.16 139.4,188.52 137.77,188.52 137.32,188.98 v1(137.32,189.99)
  L3 w0.127: v1(89.6,188.43) 89.24,188.79 89.24,192.85 89.24,194.36 91.89,197.02 110.6,197.02 111.41,196.2 117.35,196.2 118.56,194.98 123.97,194.98 130.09,188.86 134.77,188.86 135.66,187.97 137.05,187.97 137.32,188.24 v1(137.32,189.99)
  BOTTOM w0.102: v2(89.31,189.51) 89.6,189.22 v1(89.6,188.43)
M_A_DQ8: length 65
  TOP w0.089: CPU1.AR70 89.95,184.77 89.95,184.98 90.07,185.1 90.08,185.14 90.11,185.24 90.11,185.47 90.1,185.47 90.1,185.96 90.13,185.99 90.13,186 90.27,186.15 90.27,186.17 90.28,186.18 90.28,188.42 91.04,189.18 v1(91.04,189.23)
  TOP w0.102: DIMM1.25 132.4,186.28 v1(132.75,185.93)
  L3 w0.127: v1(132.75,185.93) 132.19,186.49 131.48,186.49 131.35,186.36 131.35,186.08 131.22,185.95 130.97,185.95 130.84,186.08 130.84,186.36 130.71,186.49 130.46,186.49 130.33,186.36 130.33,186.08 130.21,185.95 129.95,185.95 129.83,186.08 129.83,186.36 129.7,186.49 129.2,186.49 123.1,192.58 116.43,192.58 116.31,192.71 116.31,193.68 116.18,193.8 115.92,193.8 115.8,193.68 115.8,192.71 115.67,192.58 115.42,192.58 115.29,192.71 115.29,193.68 115.16,193.8 114.91,193.8 114.78,193.68 114.78,192.71 114.65,192.58 114.4,192.58 114.27,192.71 114.27,193.68 114.15,193.8 113.89,193.8 113.77,193.68 113.77,192.71 113.64,192.58 113.38,192.58 113.26,192.71 113.26,193.68 113.13,193.8 112.88,193.8 112.75,193.68 112.75,192.71 112.62,192.58 112.26,192.58 111.03,193.82 108.23,193.82 106.97,192.56 98.81,192.56 95.74,189.48 93.42,189.48 93.1,189.8 91.61,189.8 v1(91.04,189.23)
  BOTTOM w0.102: v1(132.75,185.93) v2(131.76,185.93)
M_A_DQ9: length 66.1
  TOP w0.102: v1(137.32,185.93) 137.92,186.52 139.4,186.52 DIMM1.24 ; CPU1.AR68 89.6,183.36 v1(89.34,183.63)
  L3 w0.127: v1(137.32,185.93) 136.9,186.35 133.69,187.52 129.63,187.52 123.49,193.65 118.12,193.65 116.83,194.94 97.68,194.94 96.84,195.78 92.69,195.78 90.76,193.85 90.76,190.8 90.27,190.31 90.27,189.09 90.45,188.91 90.45,186.06 v1(89.34,183.63)
  BOTTOM w0.102: v1(89.34,183.63) 89.03,183.93 v2(89.03,184.68)
M_A_DQ10: length 63.3
  TOP w0.089: v1(92.67,188.15) 92.67,188.21 92.54,188.34 91.73,188.34 91.6,188.21 91.6,187.7 91.83,187.47 91.83,186.25 91.6,186.01 91.6,186 91.25,185.65 91.25,185.52 CPU1.AU71
  TOP w0.102: DIMM1.42 138.45,182.03 138.36,181.94 137.5,181.94 v1(136.69,182.75)
  L3 w0.127: v1(92.67,188.15) 93.01,187.81 94.65,187.81 94.84,187.61 94.84,186.03 94.97,185.9 95.22,185.9 95.35,186.03 95.35,187.58 95.48,187.71 95.73,187.71 95.86,187.58 95.86,186.46 95.99,186.33 96.24,186.33 96.37,186.46 96.37,187.58 96.49,187.71 96.98,187.71 99.96,190.69 99.96,190.72 100.09,190.84 122.47,190.84 129.43,183.88 134.69,183.88 135.03,183.54 135.9,183.54 v1(136.69,182.75)
  BOTTOM w0.102: v2(93.66,188.34) 92.86,188.34 v1(92.67,188.15)
M_A_DQ11: length 64.8
  TOP w0.089: CPU1.AU68 91.19,183.41 91.77,183.41 92.24,183.87 92.24,184.08 92.2,184.22 92.2,184.37 92.28,184.55 92.87,185.15 92.87,185.67 93.1,185.9 93.1,186.56
  TOP w0.102: 93.1,186.56 93.1,188.3 v1(92.62,188.78) ; v1(137.96,182.75) 138.23,183.03 DIMM1.38
  L3 w0.127: v1(137.96,182.75) 137.96,181.79 138.08,181.66 138.69,181.66 138.82,181.79 138.82,183.79 138.69,183.92 137.24,183.92 137.12,183.79 137.12,183.46 136.99,183.34 136.73,183.34 136.61,183.46 136.61,183.79 136.48,183.92 135.14,183.92 134.66,184.4 129.4,184.4 122.61,191.19 99.81,191.19 96.93,188.3 93.16,188.3 92.85,188.62 92.68,188.78 v1(92.62,188.78)
  BOTTOM w0.102: v1(137.96,182.75) v2(138.92,182.75)
M_A_DQ12: length 63.3
  TOP w0.089: CPU1.AR71 89.85,186 90.08,186.24 90.08,188.45
  TOP w0.102: 90.08,188.45 90.08,189.1 90.86,189.88 v1(91.03,189.88) ; DIMM1.29 132,185.28 132.21,185.06 133.15,185.06 v1(134.02,185.93)
  L3 w0.127: v1(91.03,189.88) 91.52,190.36 91.52,193.59 93.02,195.09 96.56,195.09 97.39,194.26 101.56,194.26 101.69,194.13 101.69,193.42 101.82,193.29 102.07,193.29 102.2,193.42 102.2,194.13 102.32,194.26 103.59,194.26 103.85,194 103.85,193.23 104.11,192.98 106.9,192.98 108.18,194.26 116.54,194.26 117.84,192.96 123.21,192.96 129.34,186.83 133.12,186.83 v1(134.02,185.93)
  BOTTOM w0.102: v2(133.68,185.13) 134.02,185.47 v1(134.02,185.93)
M_A_DQ13: length 64.7
  TOP w0.089: CPU1.AR69 90.12,184.37 90.25,184.63 90.25,185.07 90.3,185.28 90.3,185.92 90.56,186.18 90.56,188.07 v1(91.04,188.55)
  TOP w0.102: v1(136.05,185.93) 136.48,185.5 138.13,185.5 138.16,185.52 139.4,185.52 DIMM1.28
  L3 w0.127: v1(91.04,188.55) 91.04,188.64 90.61,189.07 90.61,190.15 91.18,190.71 91.18,193.76 92.85,195.43 96.7,195.43 97.53,194.6 116.69,194.6 117.98,193.31 123.35,193.31 129.48,187.17 133.43,187.17 134.23,186.37 135.61,186.37 v1(136.05,185.93)
  BOTTOM w0.102: v1(136.05,185.93) 136.05,186.64 v2(136.31,186.89)
M_A_DQ14: length 63.9
  TOP w0.089: v1(92.67,187.52) 92.08,186.93 92.08,186.23 91.43,185.58 91.43,185.23 91.37,184.97 CPU1.AU70
  TOP w0.102: v1(134.65,182.75) 134.18,182.28 DIMM1.41
  L3 w0.127: v1(134.65,182.75) 133.87,183.54 129.29,183.54 122.33,190.5 100.26,190.5 96.71,186.95 96.71,183.31 95.51,182.12 94.22,182.12 92.49,183.85 92.49,185.14 93.28,185.93 93.28,186.91 v1(92.67,187.52)
  BOTTOM w0.102: v2(134.73,181.94) 134.65,182.02 v1(134.65,182.75)
M_A_DQ15: length 64.3
  TOP w0.089: v1(92.66,186.88) 92.28,186.5 92.28,186.14 91.62,185.49 91.62,185.23 91.48,184.64 91.48,184.44 91.45,184.37 CPU1.AU69
  TOP w0.102: v1(133.38,182.75) 132.86,183.28 DIMM1.37
  L3 w0.127: v1(92.66,186.88) 92.24,186.45 92.24,185.8 92.11,185.68 91.3,185.68 91.17,185.55 91.17,185.3 91.3,185.17 91.88,185.17 92.01,185.04 92.01,184.79 91.88,184.66 91.22,184.66 91.09,184.53 91.09,184.28 91.22,184.15 91.83,184.15 91.96,184.02 91.96,183.74 94.01,181.69 95.69,181.69 97.12,183.12 97.12,186.88 100.4,190.16 122.19,190.16 129.15,183.2 132.94,183.2 v1(133.38,182.75)
  BOTTOM w0.102: v2(93.58,186.66) 92.88,186.66 v1(92.66,186.88)
M_A_DQ16: length 54
  TOP w0.089: 95.31,181.63 94.57,181.63 CPU1.BB65
  TOP w0.102: v1(100.18,186.77) 100.54,186.4 100.54,186.06 100.4,185.92 99.52,185.92 99.42,186.02 99.42,186.24 99.3,186.36 99.13,186.36 99.01,186.24 99.01,186.02 98.91,185.92 98.14,185.92 97.46,185.24 97.46,185.23 96.4,184.16 96.4,182.72 95.31,181.63 ; DIMM1.45 133.26,181.28 133.38,181.15 v1(133.38,180.72)
  L3 w0.127: v1(100.18,186.77) 100.18,187.35 100.53,187.7 100.71,187.7 100.82,187.58 101,187.58 101.18,187.76 101.18,187.94 101.07,188.06 101.07,188.24 101.29,188.47 121.48,188.47 128.68,181.26 129.27,181.26 129.4,181.14 129.4,180.94 129.52,180.81 129.78,180.81 129.91,180.94 129.91,181.14 130.03,181.26 130.29,181.26 130.41,181.14 130.41,180.94 130.54,180.81 130.79,180.81 130.92,180.94 130.92,181.14 131.05,181.26 131.3,181.26 131.43,181.14 131.43,180.94 131.56,180.81 131.81,180.81 131.94,180.94 131.94,181.14 132.06,181.26 132.84,181.26 v1(133.38,180.72)
  BOTTOM w0.102: v2(100.49,187.78) 100.18,187.47 v1(100.18,186.77)
M_A_DQ17: length 56
  TOP w0.089: CPU1.AW65 92.53,181.56 92.93,181.96 93.43,181.96 93.51,181.98 93.66,182.13 93.67,182.14 93.67,182.31 93.84,182.48 93.84,182.48 94.14,182.48 94.21,182.46 94.66,182.46 94.83,182.63 94.83,182.85 95.1,183.12 95.34,183.12 95.85,183.63 95.85,184.38 96.81,185.34 96.81,186.56 97.53,187.29 98.86,187.29 98.9,187.32 99.58,187.32 99.7,187.2 99.7,186.89 99.58,186.76 v1(99.54,186.76)
  TOP w0.102: v1(134.65,180.72) 134.21,180.28 DIMM1.49
  L3 w0.127: v1(134.65,180.72) 134.2,181.18 133.41,181.18 132.98,181.61 128.83,181.61 121.51,188.93 101.25,188.93 99.83,187.5 99.83,187.05 v1(99.54,186.76)
  BOTTOM w0.102: v1(99.54,186.76) 99.54,186.14 v2(99.78,185.9)
M_A_DQ18: length 56.3
  TOP w0.089: CPU1.AW63 92.62,180.52 92.88,180.67 93.15,180.67 93.19,180.63 94.07,180.63 94.17,180.66 94.18,180.67 94.55,180.67 94.78,180.44 95.13,180.44 97.19,182.5 97.19,183.51 98,184.32 98.39,184.32 v1(98.84,184.77)
  TOP w0.102: v1(132.75,177.42) 132.39,177.78 DIMM1.59
  L3 w0.127: v1(98.84,184.77) 98.42,184.35 97.52,184.35 97.39,184.22 97.39,183.69 97.52,183.57 99.37,183.57 100.17,184.37 101.55,184.37 102.46,185.28 102.68,185.28 103.25,185.28 103.31,185.34 103.32,185.34 104.09,186.11 120.35,186.11 129.03,177.42 129.38,177.42 129.5,177.55 129.5,178.05 129.63,178.18 129.89,178.18 130.01,178.05 130.01,177.55 130.14,177.42 130.39,177.42 130.52,177.55 130.52,177.98 130.65,178.1 130.9,178.1 131.03,177.98 131.03,177.55 131.16,177.42 v1(132.75,177.42)
  BOTTOM w0.102: v2(131.92,177.66) 132.16,177.42 v1(132.75,177.42)
M_A_DQ19: length 55.6
  TOP w0.089: CPU1.AY63 93.63,179.88 95.37,179.88 97.9,182.41 97.9,183.16 98.12,183.38 98.84,183.38
  TOP w0.102: DIMM1.63 131.99,176.78 132.16,176.61 133.21,176.61 v1(134.02,177.42) ; 98.84,183.38 101.91,183.38 102.04,183.51 102.04,183.77 101.91,183.9 101,183.9 100.74,184.15 v1(100.74,184.79)
  L3 w0.127: v1(100.74,184.79) 100.74,185.4 100.97,185.62 102.83,185.62 102.83,185.62 103.11,185.62 103.17,185.68 103.18,185.68 103.95,186.45 120.49,186.45 128.15,178.79 130.96,178.79 131.89,177.86 133.57,177.86 v1(134.02,177.42)
  BOTTOM w0.102: v1(134.02,177.42) 134.02,178.13 v2(134.11,178.22)
M_A_DQ20: length 54.6
  TOP w0.089: CPU1.BA65 93.97,181.75 94.23,181.82 95.23,181.82 95.9,182.49 96.21,183.44 96.21,184.24 97.28,185.31 97.28,185.31 98.07,186.11 v1(98.89,186.78)
  TOP w0.102: DIMM1.50 138.59,180.03 138.47,179.91 137.5,179.91 v1(136.69,180.72)
  L3 w0.127: v1(136.69,180.72) 136.27,181.14 133.21,181.95 129.15,181.95 121.83,189.27 101.09,189.27 99.51,187.69 v1(98.89,186.78)
  BOTTOM w0.102: v1(98.89,186.78) 98.89,187.68 v2(98.71,187.86)
M_A_DQ21: length 55.2
  TOP w0.089: CPU1.AY65 93.16,181.56 93.4,181.77 93.78,181.87 93.9,181.92 94.21,182 95.11,182 95.69,182.58 96.03,183.49 96.03,184.31 97.1,185.38 v1(98.23,186.76)
  TOP w0.102: DIMM1.46 138.26,181.03 v1(137.96,180.72)
  L3 w0.127: v1(98.23,186.76) 98.77,187.68 100.7,189.61 121.97,189.61 128.77,182.81 129.6,182.81 132.32,182.29 134.7,182.29 137.54,181.14 v1(137.96,180.72)
  BOTTOM w0.102: v2(97.75,185.78) 97.75,186.28 v1(98.23,186.76)
M_A_DQ22: length 55.1
  TOP w0.089: CPU1.BA63 93.97,180.43 94,180.46 94.13,180.46 94.14,180.47 94.23,180.49 94.48,180.49 94.71,180.26 95.25,180.26 97.38,182.4 97.38,183.39 97.99,183.99 98.67,183.99 v1(99.47,184.8)
  TOP w0.102: DIMM1.58 137.8,178.03 v1(137.19,177.42)
  L3 w0.127: v1(137.19,177.42) 135.95,178.66 132.06,178.66 131.25,179.48 128.58,179.48 120.93,187.13 103.66,187.13 102.9,186.37 102.89,186.37 102.83,186.31 100.41,186.31 99.47,185.37 v1(99.47,184.8)
  BOTTOM w0.102: v1(137.19,177.42) 137.19,178.08 v2(137.55,178.44)
M_A_DQ23: length 53.7
  TOP w0.089: v1(100.11,184.81) 98.99,183.69 98.09,183.69 97.7,183.3 97.7,182.47 95.32,180.09 94.46,180.09 CPU1.BB63
  TOP w0.102: v1(135.92,177.42) 136.35,176.99 138.01,176.99 138.05,177.03 DIMM1.62
  L3 w0.127: v1(135.92,177.42) 135.08,178.26 131.98,178.26 131.11,179.13 128.44,179.13 120.78,186.79 103.8,186.79 103.04,186.03 103.03,186.03 102.97,185.97 100.5,185.97 100.11,185.57 v1(100.11,184.81)
  BOTTOM w0.102: v1(135.92,177.42) v2(135.92,178.23)
M_A_DQ24: length 54.6
  TOP w0.089: v1(98.99,182.88) 98.31,182.2 98.24,182.2 95.57,179.52 93.98,179.52 CPU1.BA61
  TOP w0.102: v1(137.19,175.39) 137.83,176.03 DIMM1.66
  L3 w0.127: v1(137.19,175.39) 137.19,175.79 137.4,176 137.4,176.38 137.18,176.59 129.07,176.59 120.12,185.55 103.89,185.55 103.28,184.94 102.61,184.94 101.7,184.03 100.14,184.03 v1(98.99,182.88)
  BOTTOM w0.102: v1(137.19,175.39) 137.19,175.9 v2(137.47,176.18)
M_A_DQ25: length 56.8
  TOP w0.089: 99.98,181.51 98.1,181.51 95.76,179.17 95.09,179.17 94.77,178.85 93.32,178.85 93.11,178.77 92.86,178.77 92.82,178.78 CPU1.AW61
  TOP w0.102: 99.98,181.51 102.17,181.51 102.39,181.74 102.39,182.8 102.29,182.91 102.09,182.91 101.99,182.8 101.99,182.06 101.87,181.94 101.7,181.94 101.58,182.06 101.58,182.8 101.48,182.91 101.28,182.91 101.18,182.8 101.18,182.09 101.05,181.97 100.72,181.97 100.6,182.09 v1(100.6,182.8) ; DIMM1.67 132.36,175.78 v1(132.75,175.39)
  L3 w0.127: v1(132.75,175.39) 132.57,175.56 128.64,175.56 119.69,184.52 104.14,184.52 103.54,183.92 103.54,183.91 103.12,183.91 102.02,182.8 v1(100.6,182.8)
  BOTTOM w0.102: v1(100.6,182.8) 100.72,182.68 v2(101.53,182.68)
M_A_DQ26: length 54.9
  TOP w0.089: CPU1.BB59 95.62,177.88 97.73,179.98 99.88,179.98
  TOP w0.102: 99.88,179.98 100.22,180.32 v1(100.22,180.95) ; DIMM1.84 139.4,171.52 138.03,171.52 v1(137.96,171.45)
  L3 w0.127: v1(100.22,180.95) 100.68,180.48 101.67,180.48 101.7,180.5 103.03,180.5 104.68,182.16 118.71,182.16 128.9,171.97 132.84,171.97 132.97,171.84 132.97,171.32 133.1,171.2 133.35,171.2 133.48,171.32 133.48,171.84 133.6,171.97 134.77,171.97 135.92,170.81 137.32,170.81 v1(137.96,171.45)
  BOTTOM w0.102: v2(99.96,179.96) 100.22,180.22 v1(100.22,180.95)
M_A_DQ27: length 57.8
  TOP w0.089: 98.46,179.32 98.2,179.06 98.2,178.81 97.94,178.56 97.34,178.56 95.84,177.06 94.24,177.06 94.2,177.05 93.94,176.96 93.66,176.96 93.54,176.9 92.56,176.9 92.52,176.94 92.21,176.94 92.17,176.9 91.9,176.9 91.7,177.1 91.7,177.38 92.13,177.81 92.29,177.81 CPU1.AW59
  TOP w0.102: 98.46,179.32 101.25,179.32 102.38,180.45 v1(102.38,180.92) ; DIMM1.80 139.4,172.52 137.63,172.52 136.69,171.58 v1(136.69,171.45)
  L3 w0.127: v1(136.69,171.45) 135.82,172.31 129.04,172.31 118.85,182.5 104.48,182.5 102.9,180.92 v1(102.38,180.92)
  BOTTOM w0.102: v1(102.38,180.92) 103,181.55 v2(103,181.69)
M_A_DQ28: length 54.4
  TOP w0.089: v1(99.63,182.88) 99.68,182.93 99.96,182.93 100.08,182.8 100.08,182.54 99.25,181.71 98.01,181.71 95.64,179.34 94.46,179.34 CPU1.BB61
  TOP w0.102: DIMM1.70 138.08,175.03 138.01,174.96 136.35,174.96 v1(135.92,175.39)
  L3 w0.127: v1(135.92,175.39) 135.92,175.87 135.54,176.25 128.93,176.25 119.97,185.2 103.89,185.2 103.28,184.59 102.84,184.59 101.93,183.68 101.84,183.68 100.1,183.68 99.63,183.21 v1(99.63,182.88)
  BOTTOM w0.102: v1(99.63,182.88) 99.75,182.75 v2(99.75,181.94)
M_A_DQ29: length 56.3
  TOP w0.089: CPU1.AY61 93.68,179.59 93.79,179.71 95.44,179.71 98.36,182.62 v1(98.36,182.88)
  TOP w0.102: v1(134.02,175.39) 133.21,174.57 132.21,174.57 132.01,174.78 DIMM1.71
  L3 w0.127: v1(134.02,175.39) 133.5,175.91 128.79,175.91 119.83,184.86 104,184.86 103.39,184.25 102.98,184.25 102.12,183.39 102.07,183.34 101.98,183.34 100.54,183.34 100.18,182.98 100.18,182.69 99.73,182.25 98.71,182.25 97.48,181.01 97.3,181.01 96.99,181.33 96.99,181.51 v1(98.36,182.88)
  BOTTOM w0.102: v1(98.36,182.88) 97.67,182.19 v2(97.67,182.09)
M_A_DQ30: length 56
  TOP w0.089: CPU1.BA59 93.77,177.77 93.99,177.77 94.09,177.67 94.22,177.62 95.61,177.62 97.75,179.76 100.53,179.76 100.61,179.84
  TOP w0.102: DIMM1.79 132.44,172.78 132.62,172.59 133.26,172.59 133.38,172.72 v1(133.38,173.1) ; 100.61,179.84 100.86,180.09 v1(100.86,180.93)
  L3 w0.127: v1(133.38,173.1) 133.38,173.35 133.57,173.55 135.92,173.55 136.05,173.67 136.05,173.87 135.87,174.05 128.27,174.05 119.14,183.18 104.26,183.18 102.78,181.7 102.09,181.7 101.71,181.32 101.25,181.32 v1(100.86,180.93)
  BOTTOM w0.102: v2(133.38,174.02) v1(133.38,173.1)
M_A_DQ31: length 56.9
  TOP w0.089: CPU1.AY59 93.42,177.57 93.51,177.53 93.91,177.53 94.19,177.44 95.68,177.44 97.82,179.58 101.12,179.58 101.25,179.71
  TOP w0.102: DIMM1.83 134.47,171.78 134.65,171.96 v1(134.65,173.1) ; v1(101.5,180.9) 101.5,179.96 101.25,179.71
  L3 w0.127: v1(134.65,173.1) 134.21,172.66 131.45,172.66 131.32,172.78 131.32,173.08 131.19,173.2 130.94,173.2 130.81,173.08 130.81,172.78 130.68,172.66 130.34,172.66 130.21,172.78 130.21,173.48 130.09,173.61 129.83,173.61 129.71,173.48 129.71,172.78 129.58,172.66 129.18,172.66 119,182.84 104.39,182.84 102.9,181.36 102.22,181.36 101.76,180.9 v1(101.5,180.9)
  BOTTOM w0.102: v2(101.46,180.04) 101.46,180.86 v1(101.5,180.9)
M_A_DQ32: length 59.6
  TOP w0.089: 99.47,167.43 94.88,167.43 94.75,167.3 94.22,167.3 93.91,167.15 93.57,167.15 93.25,166.83 CPU1.AY39
  TOP w0.102: DIMM1.173 133.8,147.28 134.02,147.5 v1(134.02,148.34) ; 99.47,167.43 99.73,167.69 v4(100.77,167.69) 101.3,167.69 101.43,167.56 101.43,166.85 101.3,166.72 v1(100.09,166.72)
  L3 w0.089: v1(100.09,166.72) 101.82,166.72 104.43,164.12
  L3 w0.127: 104.43,164.12 104.73,163.82 107.28,163.82 108.96,163.82 116.91,155.87 117.09,155.87 117.35,156.13 117.53,156.13 117.71,155.95 117.71,155.77 117.45,155.51 117.45,155.33 117.63,155.15 117.8,155.15 118.07,155.41 118.25,155.41 118.43,155.23 118.43,155.05 118.16,154.79 118.16,154.61 118.34,154.43 118.52,154.43 118.79,154.69 118.97,154.69 119.15,154.51 119.15,154.33 118.88,154.07 118.88,153.89 119.06,153.71 119.24,153.71 119.51,153.97 119.69,153.97 125.6,148.06 132.4,148.06 132.56,147.89 133.57,147.89 v1(134.02,148.34)
M_A_DQ33: length 58.3
  TOP w0.089: CPU1.AW39 92.36,166.19 92.64,165.91 93.42,165.91 93.56,165.95 93.81,165.95 93.89,165.91 94.09,165.91 94.17,165.95 94.65,165.95 94.77,165.82 97.75,165.82 v1(98.71,166.79)
  TOP w0.102: v1(136.05,146.56) 136.05,146.69 137.39,148.03 DIMM1.170
  L3 w0.089: 104.42,163.22 101.59,166.05 99.45,166.05 v1(98.71,166.79)
  L3 w0.127: v1(136.05,146.56) 135.4,147.21 132.2,147.21 132.03,147.37 125.32,147.37 119.81,152.88 118.92,152.88 108.67,163.13 107.57,163.13 104.51,163.13 104.42,163.22
  BOTTOM w0.102: v1(98.71,166.79) 98.71,166.06 v2(98.86,165.91)
M_A_DQ34: length 60.8
  TOP w0.089: v1(99.9,164.58) 99.9,165.31 99.65,165.56 97.83,165.56 97.75,165.64 94.69,165.64 94.57,165.77 94.21,165.77 94.13,165.73 93.85,165.73 93.76,165.77 93.59,165.77 93.49,165.74 93.48,165.74 93.34,165.67 CPU1.AY37
  TOP w0.102: DIMM1.182 138.3,145.03 138.13,144.86 137.75,144.86 v1(137.32,145.29)
  L3 w0.089: v1(99.9,164.58) 100.84,164.58 104.21,161.21 104.34,161.07 104.64,160.77 104.69,160.77 104.73,160.73
  L3 w0.127: v1(137.32,145.29) 137.83,145.8 138.18,145.8 138.49,145.49 138.49,144.96 138.03,144.5 136.31,144.5 135.62,143.81 131.93,143.81 131.61,144.13 124.23,144.13 107.63,160.73 104.73,160.73
  BOTTOM w0.102: v1(99.9,164.58) v2(100.77,164.58)
M_A_DQ35: length 61
  TOP w0.089: v1(97.72,164.55) 97.37,164.9 97.16,165.11 94.64,165.11 94.51,164.98 93.73,164.98 93.42,165.29 92.79,165.29 92.48,165.61 CPU1.AW37
  TOP w0.102: DIMM1.187 131.2,143.77 135.11,143.77 135.29,143.96 135.29,144.22 135.11,144.4 134.46,144.4 134.26,144.6 134.26,144.89 v1(134.65,145.29)
  L3 w0.089: 103.93,162.17 100.94,165.16 99.21,165.16 98.76,164.71 98.76,164.36 98.53,164.13 98.14,164.13 v1(97.72,164.55)
  L3 w0.127: v1(134.65,145.29) 134.65,144.86 134.3,144.5 132.21,144.5 131.89,144.82 124.61,144.82 124.36,145.07 124.36,145.25 124.61,145.5 124.61,145.68 124.43,145.86 124.25,145.86 124,145.61 123.82,145.61 107.98,161.46 104.64,161.46 103.93,162.17
  BOTTOM w0.102: v1(134.65,145.29) 134.65,144.5 v2(134.72,144.43)
M_A_DQ36: length 58.2
  TOP w0.102: DIMM1.169 132.69,148.28 v1(132.75,148.34) ; v1(95.44,166.82) 95.42,166.83 CPU1.BB39
  L3 w0.089: v1(95.44,166.82) 95.87,167.25 101.7,167.25 104.52,164.43
  L3 w0.127: v1(132.75,148.34) 132.68,148.4 125.75,148.4 117.25,156.89 117.07,156.89 116.92,156.75 116.74,156.75 116.56,156.92 116.56,157.1 116.71,157.25 116.71,157.43 116.53,157.61 116.35,157.61 116.09,157.35 115.91,157.35 115.73,157.53 115.73,157.71 115.99,157.97 115.99,158.15 115.82,158.33 115.64,158.33 115.37,158.07 115.19,158.07 115.01,158.25 115.01,158.43 115.28,158.69 115.28,158.87 115.1,159.05 114.92,159.05 114.65,158.79 114.47,158.79 114.29,158.97 114.29,159.15 114.56,159.41 114.56,159.59 114.38,159.77 114.2,159.77 113.93,159.5 113.75,159.5 113.57,159.68 113.57,159.86 113.84,160.13 113.84,160.31 113.66,160.49 113.48,160.49 113.21,160.22 113.03,160.22 112.85,160.4 112.85,160.58 113.12,160.85 113.12,161.03 112.94,161.21 112.76,161.21 112.5,160.94 112.32,160.94 112.14,161.12 112.14,161.3 112.4,161.57 112.4,161.75 112.22,161.93 112.04,161.93 111.78,161.66 111.6,161.66 111.42,161.84 111.42,162.02 111.68,162.29 111.68,162.47 111.5,162.64 111.32,162.64 111.06,162.38 110.88,162.38 110.7,162.56 110.7,162.74 110.96,163 110.96,163.18 110.78,163.36 110.6,163.36 110.34,163.1 110.16,163.1 109.98,163.28 109.98,163.46 110.24,163.72 110.24,163.9 109.94,164.21 104.74,164.21 104.52,164.43
  BOTTOM w0.102: v2(95.16,166.07) 95.44,166.35 v1(95.44,166.82)
M_A_DQ37: length 60.3
  TOP w0.089: CPU1.BA39 93.88,166.94 94.05,167.02 94.21,167.1 95.07,167.1 95.21,167.23 98.89,167.23 v1(99.37,166.75)
  TOP w0.102: DIMM1.174 138.23,147.03 138.13,147.12 137.75,147.12 137.32,146.69 v1(137.32,146.56)
  L3 w0.089: 104.41,163.72 101.82,166.31 99.82,166.31 v1(99.37,166.75)
  L3 w0.127: 104.41,163.72 104.66,163.47 107.42,163.47 108.81,163.47 119.07,153.22 119.95,153.22 125.46,147.72 132.25,147.72 132.42,147.55 137.19,147.55 137.45,147.8 137.45,148.62 137.57,148.74 137.96,148.74 138.08,148.62 138.08,147.32 v1(137.32,146.56)
  BOTTOM w0.102: v2(100.85,166.48) 100.69,166.32 100.26,166.32 100.26,166.32 99.93,166.32 99.93,166.32 99.78,166.32 99.37,166.73 v1(99.37,166.75)
M_A_DQ38: length 60.3
  TOP w0.089: v1(98.36,164.53) 97.6,165.29 94.52,165.29 94.4,165.16 94.01,165.16 CPU1.BA37
  TOP w0.102: DIMM1.183 131.2,144.77 132.87,144.77 v1(133.38,145.29)
  L3 w0.089: v1(98.36,164.53) 98.36,165.13 98.57,165.34 101.14,165.34 104.15,162.33
  L3 w0.127: 104.15,162.33 104.68,161.8 108.12,161.8 118.37,151.55 119.26,151.55 119.5,151.3 119.5,151.12 119.24,150.86 119.24,150.68 119.42,150.5 119.6,150.5 119.86,150.76 120.04,150.76 120.22,150.58 120.22,150.4 119.96,150.14 119.96,149.96 120.14,149.78 120.32,149.78 120.58,150.04 120.76,150.04 120.94,149.86 120.94,149.68 120.68,149.42 120.68,149.25 120.86,149.06 121.04,149.06 121.3,149.32 121.48,149.32 121.66,149.14 121.66,148.96 121.4,148.71 121.4,148.53 121.58,148.35 121.76,148.35 122.02,148.6 122.19,148.6 122.37,148.42 122.37,148.25 122.11,147.99 122.11,147.81 122.29,147.63 122.47,147.63 122.73,147.89 122.91,147.89 123.09,147.71 123.09,147.53 122.83,147.27 122.83,147.09 123.01,146.91 123.19,146.91 123.45,147.17 123.63,147.17 123.81,146.99 123.81,146.81 123.55,146.55 123.55,146.37 123.73,146.19 123.91,146.19 124.17,146.45 124.35,146.45 125.64,145.16 132.04,145.16 132.35,144.84 132.93,144.84 133.25,145.16 133.26,145.16 v1(133.38,145.29)
  BOTTOM w0.102: v1(133.38,145.29) 133.38,145.24 132.8,144.65 v2(132.01,144.65)
M_A_DQ39: length 59
  TOP w0.089: CPU1.BB37 94.36,165.46 97.68,165.46 97.89,165.25 99.04,165.25 99.19,165.1 v1(99.19,164.57)
  TOP w0.102: DIMM1.186 137.31,144.03 v1(136.05,145.29)
  L3 w0.089: v1(99.19,164.57) 99.6,164.98 100.74,164.98 104.6,161.11 104.68,161.11
  L3 w0.127: v1(136.05,145.29) 136.05,145.82 135.85,146.02 135.44,146.02 135.24,145.82 135.24,145.08 135.67,144.65 135.67,144.35 135.48,144.16 132.07,144.16 131.75,144.48 124.47,144.48 109.85,159.09 107.83,161.11 104.68,161.11
  BOTTOM w0.102: v1(99.19,164.57) 99.19,164.24 v2(99.65,163.78)
M_A_DQ40: length 60.6
  TOP w0.089: v1(96.42,164.49) 96.42,164.32 96.22,164.12 95.29,164.12 94.93,164.12 94.85,164.2 94.25,164.2 94.13,164.25 93.86,164.25 93.76,164.22 93.56,164.22 93.46,164.26 93.13,164.26 CPU1.AY35
  TOP w0.102: DIMM1.191 131.2,142.77 132.37,142.77 132.52,142.93 133.23,142.93 133.38,142.77 v1(133.38,142.37)
  L3 w0.089: v1(96.42,164.49) 96.42,164.04 96.69,163.77 100.8,163.77 104.61,159.96
  L3 w0.127: v1(133.38,142.37) 133.38,142.49 132.75,143.13 123.96,143.13 115.2,151.89 115.02,151.89 114.73,151.6 114.55,151.6 114.37,151.78 114.37,151.96 114.66,152.25 114.66,152.43 114.48,152.61 114.3,152.61 114.01,152.32 113.83,152.32 113.65,152.5 113.65,152.68 113.94,152.97 113.94,153.15 113.76,153.33 113.58,153.33 113.29,153.04 113.11,153.04 112.93,153.22 112.93,153.4 113.22,153.69 113.22,153.87 113.04,154.05 112.86,154.05 112.57,153.76 112.39,153.76 112.21,153.94 112.21,154.12 112.5,154.41 112.5,154.59 110.23,156.85 109.88,156.85 109.7,157.04 109.7,157.39 109.51,157.57 109.16,157.57 108.98,157.76 108.98,158.11 108.63,158.46 108.45,158.46 108.14,158.15 107.96,158.15 107.78,158.33 107.78,158.51 108.09,158.82 108.09,159 107.91,159.18 107.73,159.18 107.42,158.87 107.24,158.87 107.06,159.05 107.06,159.23 107.37,159.54 107.37,159.72 107.13,159.96 106.43,159.96 104.61,159.96
  BOTTOM w0.102: v1(133.38,142.37) 133.38,143.23 v2(133.31,143.31)
M_A_DQ41: length 60.7
  TOP w0.089: CPU1.AW35 92.66,164.08 93.43,164.08 93.53,164.04 93.8,164.04 93.89,164.08 94.1,164.08 94.18,164.04 94.18,164.04 94.24,164.01 94.75,164.01 94.82,163.94 94.86,163.94 96.54,163.94 v1(97.06,164.47)
  TOP w0.102: v1(137.96,143.13) 138.06,143.03 DIMM1.190
  L3 w0.089: 104.66,160.39 101.1,163.95 97.58,163.95 v1(97.06,164.47)
  L3 w0.127: v1(137.96,143.13) 139.23,143.13 139.35,143.26 139.35,143.89 139.23,144.02 136.31,144.02 135.76,143.47 135.48,143.47 124.1,143.47 107.27,160.3 104.75,160.3 104.66,160.39
  BOTTOM w0.102: v1(137.96,143.13) v2(138.74,143.13)
M_A_DQ42: length 60.6
  TOP w0.089: CPU1.AY33 93.24,163 93.44,162.86 93.68,162.86 94.03,162.78 94.09,162.74 94.2,162.72 94.21,162.71 95.46,162.71 95.54,162.8 96.09,162.8 v1(96.43,162.45)
  TOP w0.102: v1(134.02,139.06) 133.26,139.83 132.11,139.83 132.06,139.77 131.88,139.77 131.88,139.78 DIMM1.203
  L3 w0.089: 104.56,157.19 104.46,157.19 99.89,161.76 95.61,161.76 95.33,162.04 95.33,162.57 95.56,162.8 96.09,162.8 v1(96.43,162.45)
  L3 w0.127: v1(134.02,139.06) 133.57,139.51 129.74,139.51 128.83,140.42 121.53,140.42 121.13,140.82 121.13,141 121.5,141.37 121.5,141.55 121.32,141.73 121.14,141.73 120.77,141.36 120.59,141.36 120.41,141.54 120.41,141.72 120.88,142.2 120.88,142.38 120.7,142.56 120.52,142.56 120.05,142.08 119.87,142.08 104.76,157.19 104.56,157.19
  BOTTOM w0.102: v1(134.02,139.06) v2(134.02,139.9)
M_A_DQ43: length 58.9
  TOP w0.102: CPU1.AW33 92.36,163.83 91.85,164.34 v1(91.85,164.52) ; v1(132.75,139.06) 132.46,138.77 131.2,138.77 DIMM1.207
  L3 w0.089: v1(91.85,164.52) 92.39,163.99 92.51,163.99 92.83,164.3 92.96,164.3 93.08,164.18 93.08,164.05 92.76,163.73 92.76,163.61 92.89,163.48 93.01,163.48 93.33,163.8 93.46,163.8 93.58,163.67 93.58,163.55 93.27,163.23 93.27,163.11 93.39,162.98 93.52,162.98 93.86,163.33 94.01,163.33 94.11,163.22 94.11,163.07 93.77,162.73 93.77,162.6 94.83,161.54 99.83,161.54 102.32,159.06
  L3 w0.127: v1(132.75,139.06) 129.7,139.06 128.68,140.08 121.39,140.08 104.65,156.82 104.55,156.82 102.32,159.06
  BOTTOM w0.102: v1(132.75,139.06) 132.7,139.06 v2(132.07,139.69)
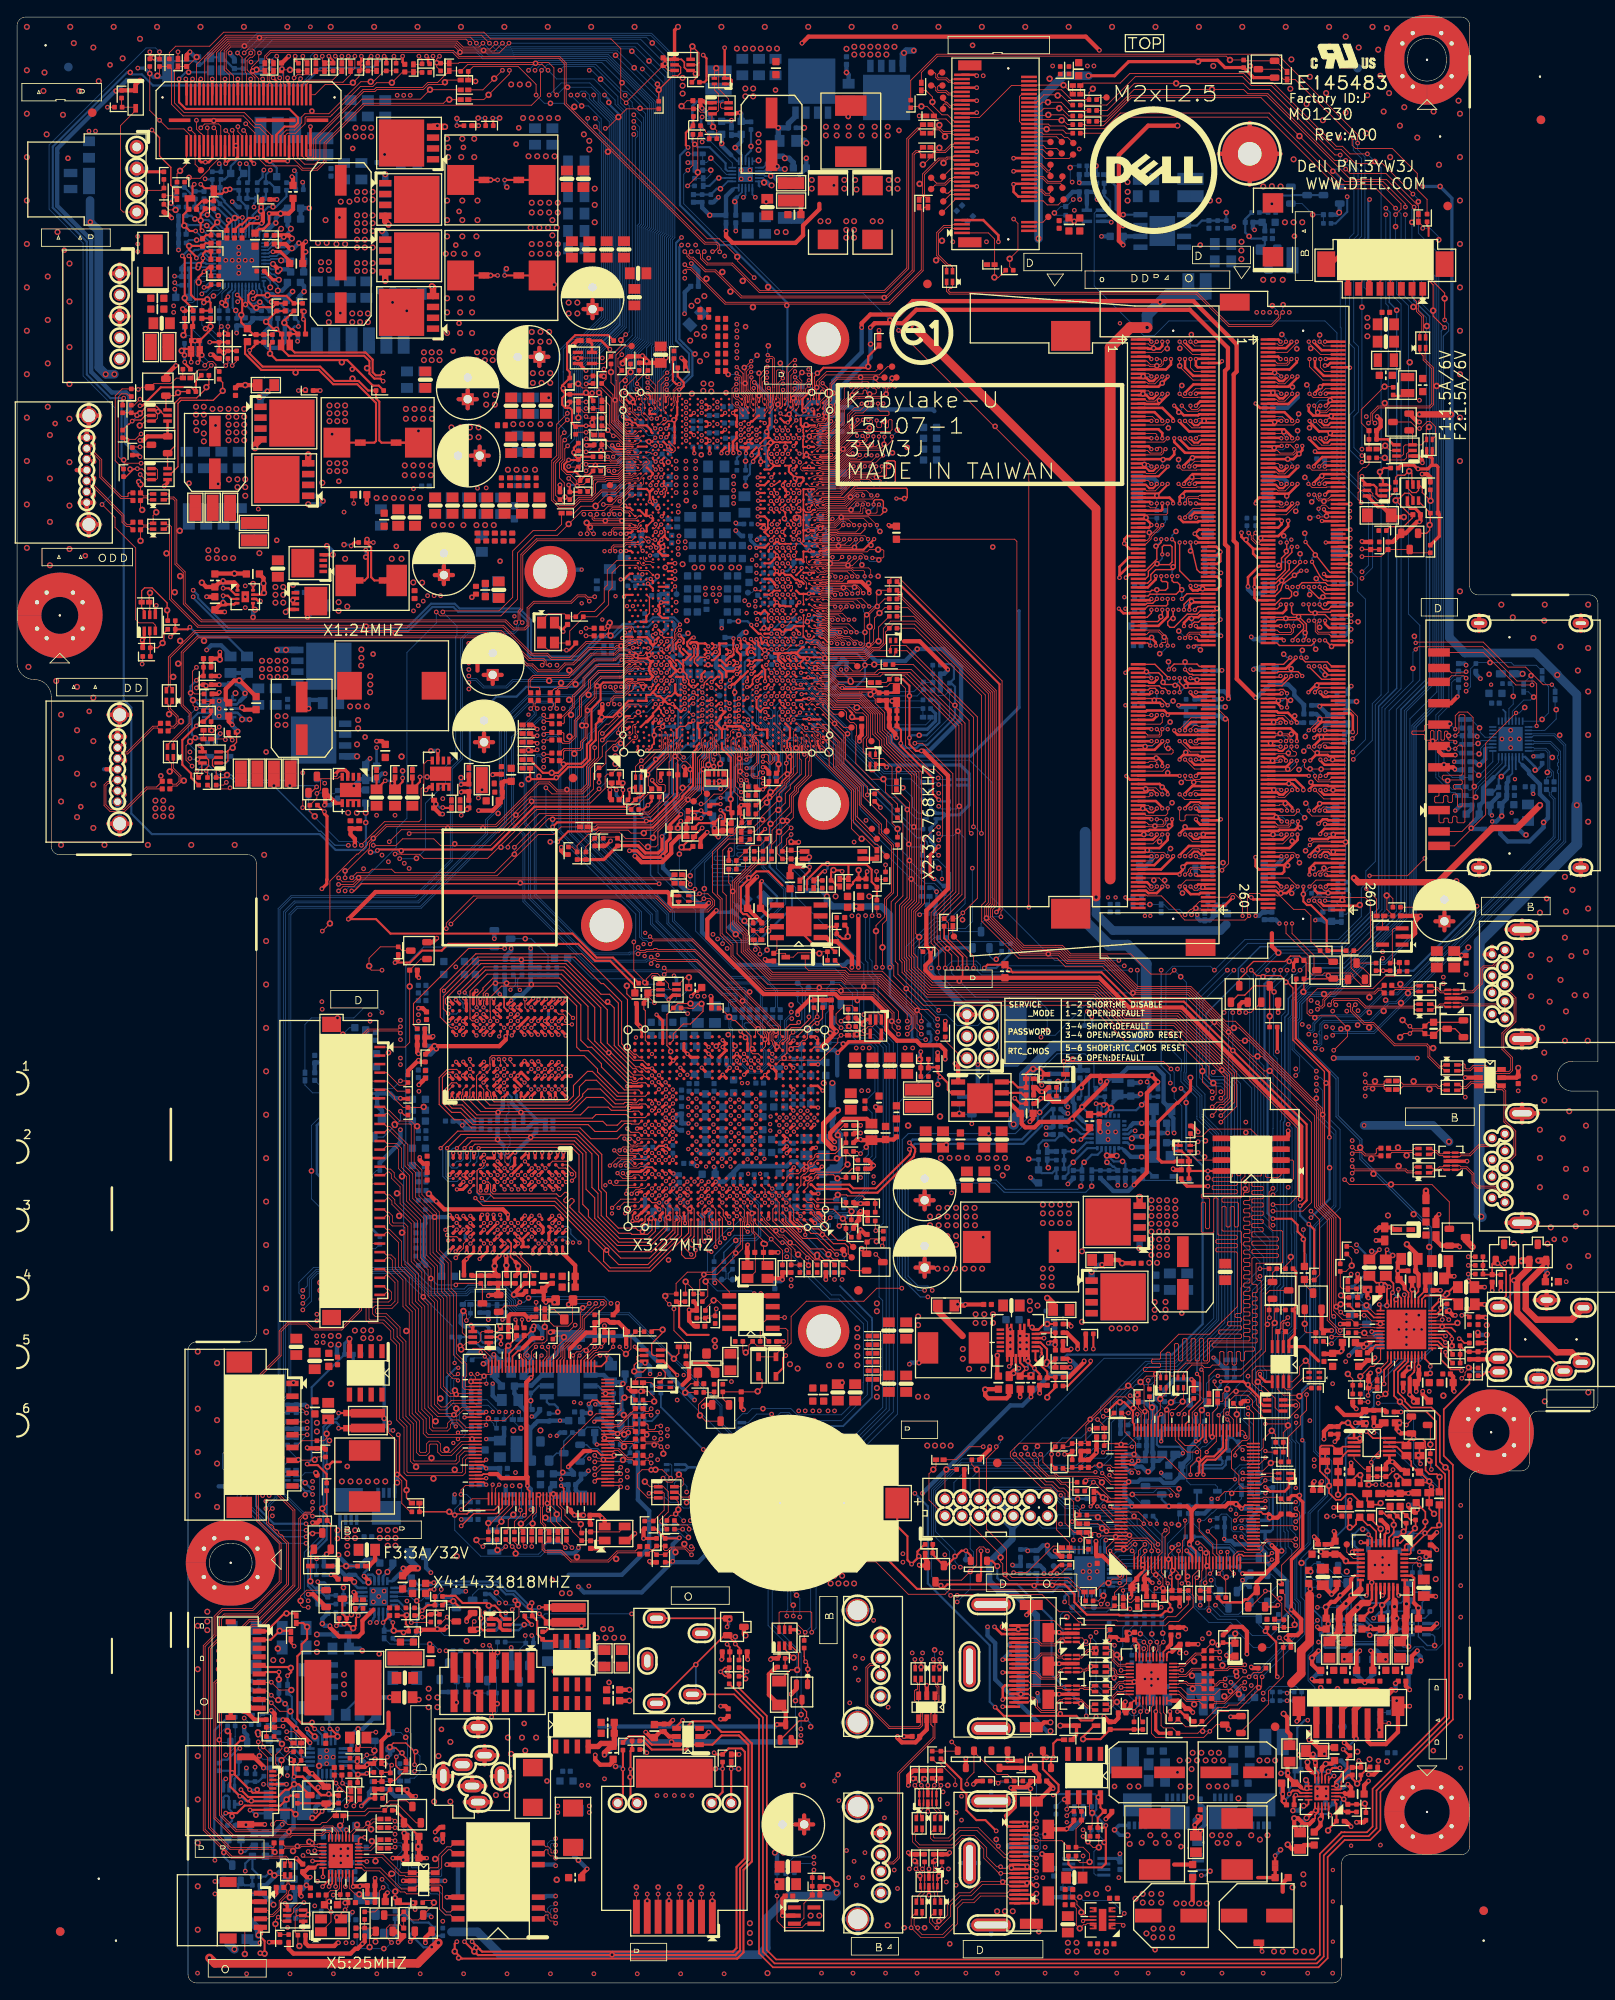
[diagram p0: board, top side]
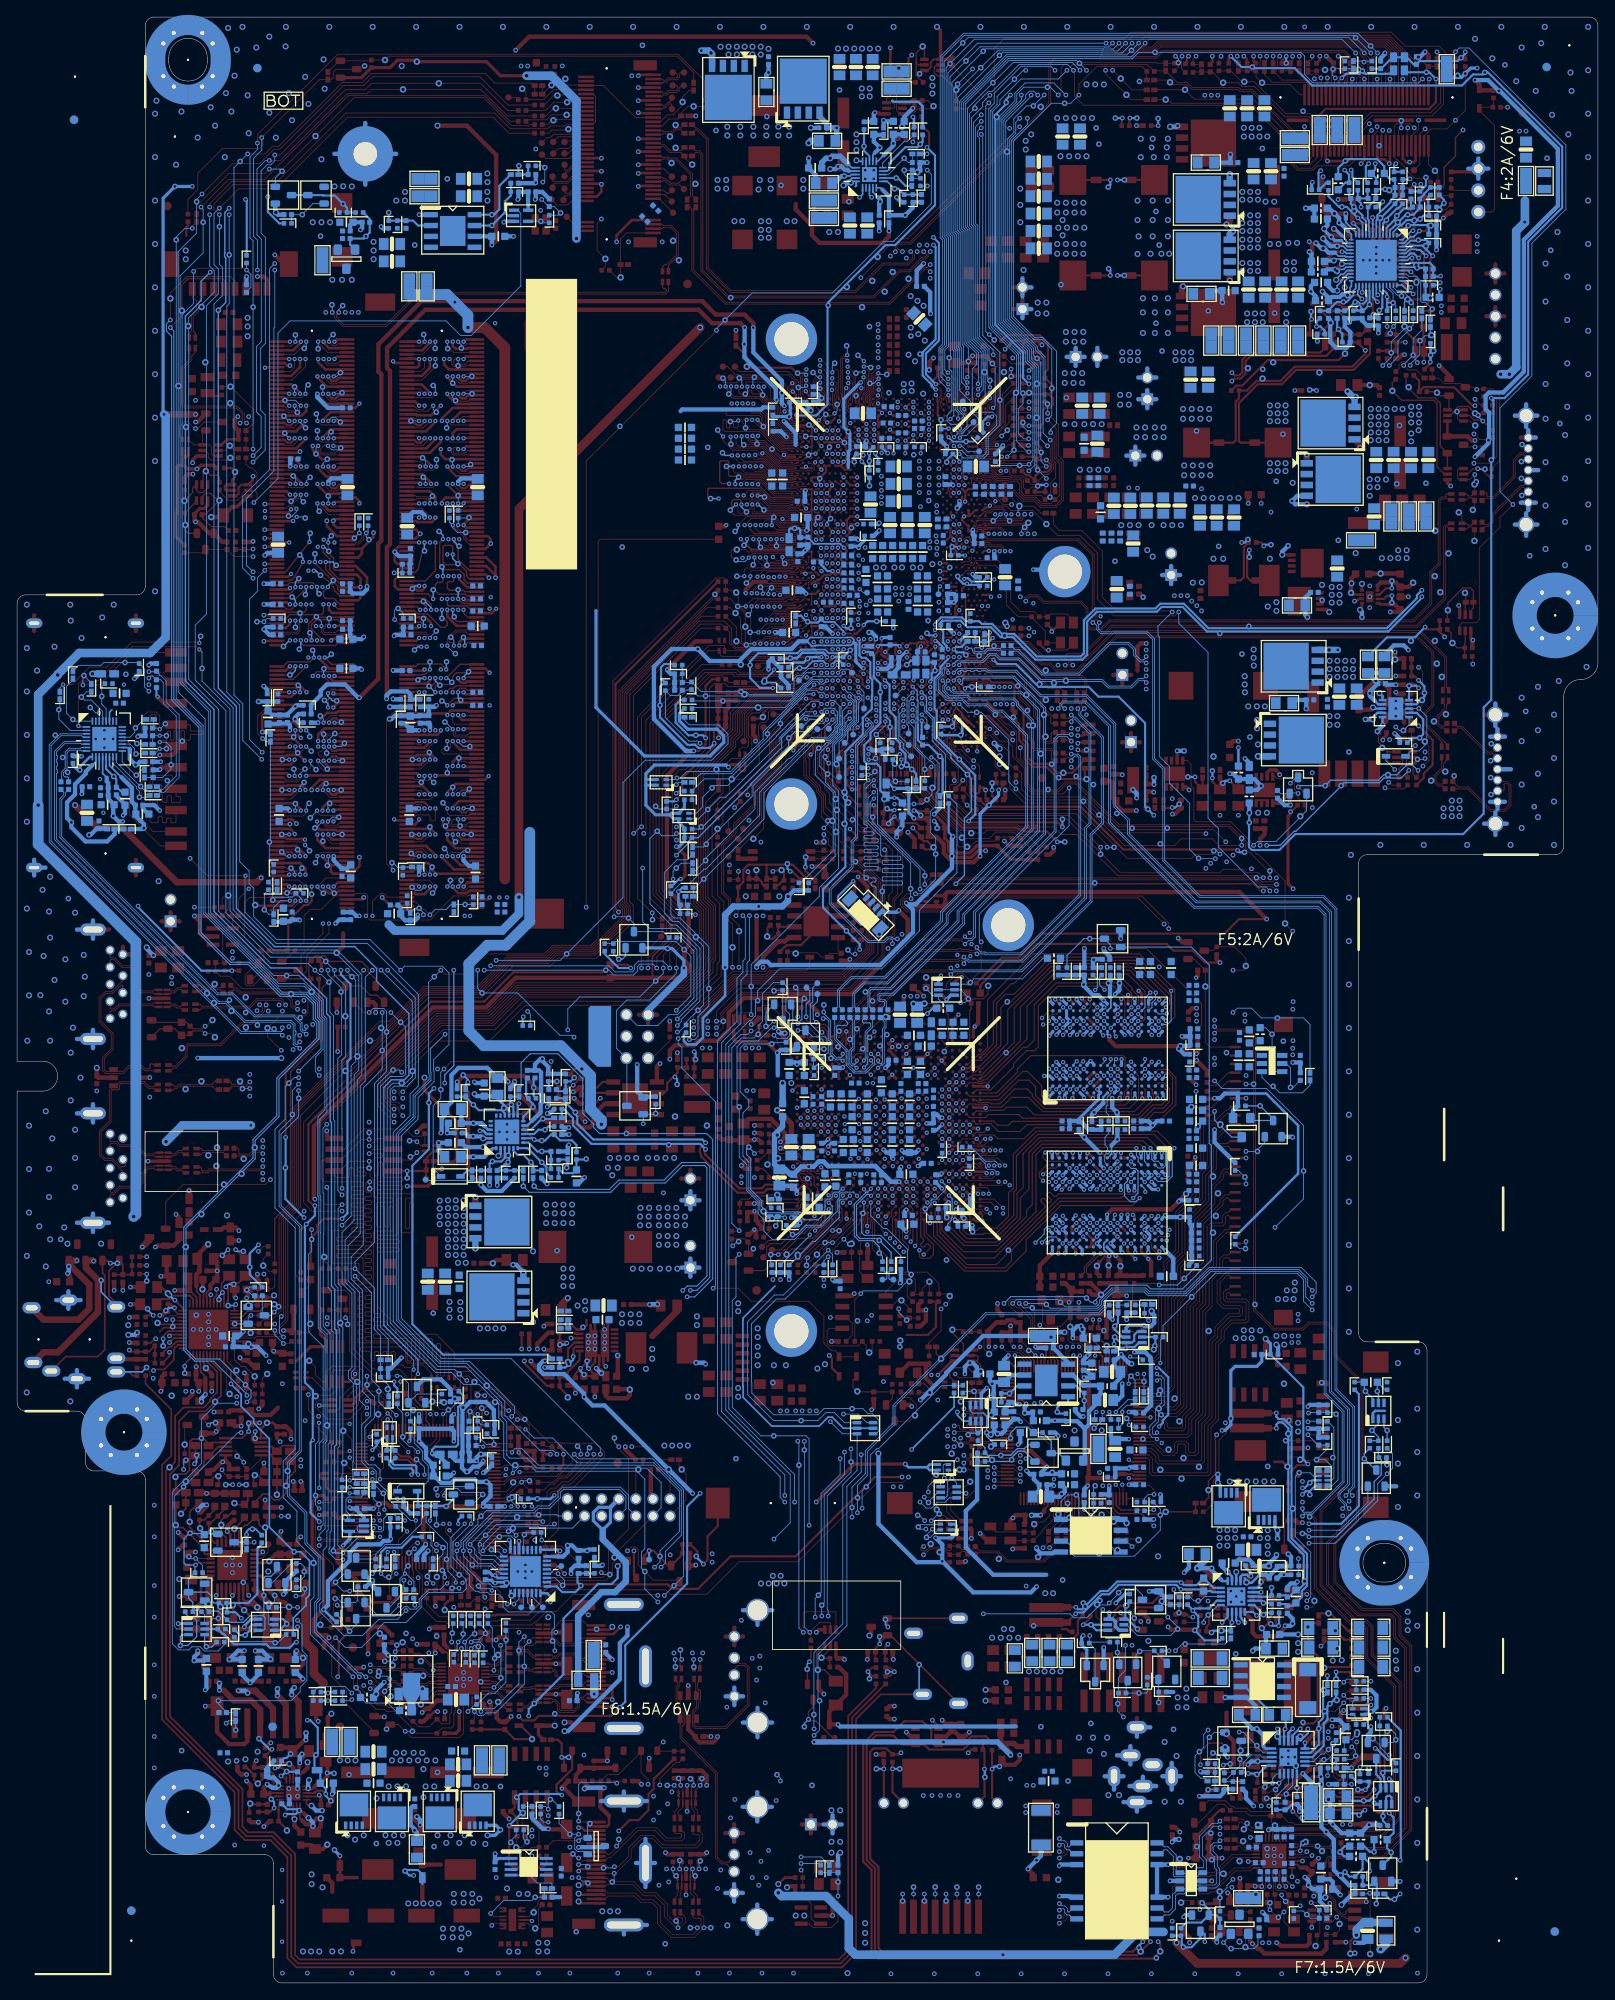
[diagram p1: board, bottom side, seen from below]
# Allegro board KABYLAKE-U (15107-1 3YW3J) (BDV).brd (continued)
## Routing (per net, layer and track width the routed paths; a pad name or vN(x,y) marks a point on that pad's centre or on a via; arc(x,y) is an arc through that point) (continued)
M_A_DQ44: length 59
  TOP w0.102: DIMM1.194 137.79,142.03 v1(136.69,143.13) ; CPU1.BB35 95.03,164.48 v1(95.08,164.53)
  L3 w0.089: v1(95.08,164.53) 95.08,163.67 95.34,163.42 100.27,163.42 104.41,159.27 104.55,159.27
  L3 w0.127: v1(136.69,143.13) 136.25,142.7 136.25,142.7 136.23,142.68 135.75,142.68 134.61,141.54 132.41,141.54 131.51,142.44 123.67,142.44 119.02,147.1 118.84,147.1 118.39,146.65 118.21,146.65 118.03,146.83 118.03,147.01 118.48,147.45 118.48,147.63 118.24,147.88 117.07,147.88 111.34,153.61 111.34,154.3 108.79,156.86 108.23,156.86 105.81,159.27 104.55,159.27
  BOTTOM w0.102: v1(136.69,143.13) 136.69,143.89 v2(136.76,143.97)
M_A_DQ45: length 59.3
  TOP w0.089: CPU1.BA35 93.96,164.78 94.65,164.78 94.8,164.93 95.37,164.93 v1(95.77,164.53)
  TOP w0.102: DIMM1.195 131.2,141.77 134.06,141.77 v1(134.65,142.37)
  L3 w0.089: v1(95.77,164.53) 95.77,163.95 96.13,163.6 100.47,163.6 104.45,159.62 104.68,159.62
  L3 w0.127: v1(134.65,142.37) 134.17,141.88 132.55,141.88 131.65,142.79 123.81,142.79 117.82,148.78 117.64,148.78 117.24,148.38 117.06,148.38 116.88,148.56 116.88,148.74 117.28,149.14 117.28,149.32 117.1,149.5 116.92,149.5 116.52,149.1 116.34,149.1 116.16,149.28 116.16,149.46 116.49,149.79 116.49,149.97 116.31,150.15 116.13,150.15 115.8,149.82 115.62,149.82 115.44,150 115.44,150.48 114.92,151 114.43,151 111.69,153.75 111.69,154.44 108.93,157.2 108.43,157.2 106.01,159.62 104.68,159.62
  BOTTOM w0.102: v2(134.65,141.58) v1(134.65,142.37)
M_A_DQ46: length 59.8
  TOP w0.089: CPU1.BA33 93.78,163.15 94.11,162.95 94.13,162.92 94.15,162.91 94.23,162.89 95.38,162.89 95.47,162.98 96.61,162.98 v1(97.09,162.5)
  TOP w0.102: v1(136.05,139.06) 136.66,138.46 138.49,138.46 138.56,138.52 DIMM1.208
  L3 w0.089: 104.6,157.57 104.46,157.57 100.09,161.94 97.64,161.94 v1(97.09,162.5)
  L3 w0.127: v1(136.05,139.06) 136.05,139.55 135.75,139.85 129.88,139.85 128.97,140.77 122.98,140.77 120.48,143.26 120.3,143.26 119.91,142.86 119.73,142.86 119.55,143.04 119.55,143.22 119.75,143.42 119.75,143.6 119.57,143.78 119.39,143.78 119.19,143.58 119.01,143.58 118.83,143.76 118.83,143.94 119.23,144.34 119.23,144.52 118.98,144.76 117.73,144.76 109.58,152.91 109.58,153.64 108.09,155.13 107.58,155.13 105.14,157.57 104.6,157.57
  BOTTOM w0.102: v1(97.09,162.5) 97.09,162.86 v2(96.71,163.24)
M_A_DQ47: length 59
  TOP w0.089: CPU1.BB33 95.39,163.15 97.12,163.15 v1(97.74,162.54)
  TOP w0.102: v1(137.32,139.06) 137.78,139.52 DIMM1.204
  L3 w0.089: v1(97.74,162.54) 98.14,162.14 100.4,162.14 104.62,157.92
  L3 w0.127: v1(137.32,139.06) 137.32,139.75 137.45,139.88 137.9,139.88 138.03,140 138.03,140.46 137.9,140.59 136.35,140.59 135.96,140.2 130.03,140.2 129.11,141.11 123.12,141.11 119.13,145.1 117.87,145.1 109.92,153.05 109.92,153.79 108.23,155.47 107.72,155.47 105.28,157.91 104.63,157.91 104.62,157.92
  BOTTOM w0.102: v1(97.74,162.54) 97.74,163.04 v2(98,163.3)
M_A_DQ48: length 60.5
  TOP w0.089: v1(97.73,161.01) 97.31,161.43 94.18,161.43 94.03,161.58 93.37,161.58 93.3,161.63 CPU1.AY31
  TOP w0.102: v1(132.75,137.41) 132.39,137.77 131.2,137.77 DIMM1.211
  L3 w0.089: v1(97.73,161.01) 98.11,160.64 98.6,160.64 102.75,156.49
  L3 w0.127: v1(132.75,137.41) 132.72,137.44 125.95,137.44 125.83,137.57 125.83,138.2 125.7,138.33 125.45,138.33 125.32,138.2 125.32,137.34 125.19,137.21 124.94,137.21 124.81,137.34 124.81,138.38 124.68,138.5 124.43,138.5 124.3,138.38 124.3,137.57 124.18,137.44 123.92,137.44 123.79,137.57 123.79,138.38 123.67,138.5 123.41,138.5 123.29,138.38 123.29,137.54 123.16,137.41 122.91,137.41 122.78,137.54 122.78,138.38 122.65,138.5 122.4,138.5 122.27,138.38 122.27,137.57 122.14,137.44 121.83,137.44 121.7,137.57 121.7,138.34 121.57,138.47 120.77,138.47 102.75,156.49
  BOTTOM w0.102: v1(132.75,137.41) v2(131.73,137.41)
M_A_DQ49: length 61.1
  TOP w0.089: CPU1.AW31 92.55,161.85 92.86,162.17 93.97,162.17 94.09,162.29 95.13,162.29 95.42,162 98.38,162
  TOP w0.102: 98.38,162 98.83,162 99.72,161.11 v1(99.72,161.05) ; v1(137.32,137.41) 137.75,137.85 138.26,137.85 138.58,137.52 DIMM1.212
  L3 w0.089: v1(99.72,161.05) 99.72,160.97 103.64,157.06
  L3 w0.127: 103.64,157.06 121.16,139.53 128.69,139.53 129.67,138.54 138.08,138.54 138.21,138.42 138.21,138.05 138.08,137.92 137.45,137.92 137.32,137.79 v1(137.32,137.41)
  BOTTOM w0.102: v1(99.72,161.05) v2(100.67,161.05)
M_A_DQ50: length 59.6
  TOP w0.089: CPU1.AY29 93.41,160.35 93.57,160.23 93.76,160.18 93.87,160.06 94.57,160.06 94.74,159.89 94.76,159.89 94.76,159.89 95.65,159.89 v1(96.05,159.49)
  TOP w0.102: DIMM1.224 138.11,134.53 v1(137.96,134.37)
  L3 w0.089: 98.58,158.48 97.06,158.48 v1(96.05,159.49)
  L3 w0.102: 98.58,158.48 98.76,158.29
  L3 w0.127: v1(137.96,134.37) 137.07,133.48 131.66,133.48 131.15,133.99 121.91,133.99 101.36,154.54 101.36,155.69 98.76,158.29
  BOTTOM w0.102: v1(137.96,134.37) v2(138.82,134.37)
M_A_DQ51: length 60.3
  TOP w0.102: v1(91.8,160.52) 91.86,160.52 91.97,160.63 CPU1.AW29 ; v1(134.02,134.37) 132.93,133.28 DIMM1.229
  L3 w0.089: 98.45,159.63 98.15,159.93 93.68,159.93 93.53,160.09 93.53,160.76 93.31,160.98 91.92,160.98 91.8,160.85 v1(91.8,160.52)
  L3 w0.127: 98.45,159.63 102.21,155.87 102.21,155.14 121.97,135.38 125.71,135.38 126.44,136.11 131.95,136.11 132.77,135.28 133.76,135.28 134.02,135.03 v1(134.02,134.37)
  BOTTOM w0.102: v2(133.7,133.52) 134.02,133.83 v1(134.02,134.37)
M_A_DQ52: length 59
  TOP w0.089: CPU1.BB31 94.78,161.85 95.02,161.61 97.83,161.61 v1(98.41,161.04)
  TOP w0.102: DIMM1.215 131.4,136.78 131.4,136.77 131.94,136.77 132.11,136.61 134.43,136.61 134.65,136.83 v1(134.65,137.41)
  L3 w0.089: 103.03,156.7 99.2,160.53 99,160.53 98.5,161.04 v1(98.41,161.04)
  L3 w0.127: v1(134.65,137.41) 134.21,137.86 129.39,137.86 128.4,138.85 127.99,138.85 127.87,138.72 127.87,137.92 127.74,137.79 127.49,137.79 127.36,137.92 127.36,138.72 127.23,138.85 126.98,138.85 126.85,138.72 126.85,138 126.72,137.87 126.47,137.87 126.34,138 126.34,138.72 126.22,138.85 120.88,138.85 103.03,156.7
  BOTTOM w0.102: v2(135.16,138.07) 134.65,137.57 v1(134.65,137.41)
M_A_DQ53: length 60.1
  TOP w0.089: v1(99.04,161.05) 98.28,161.82 95.35,161.82 95.06,162.11 94.16,162.11 93.9,161.85 CPU1.BA31
  TOP w0.102: v1(136.05,137.41) 136.05,136.09 136.18,135.97 136.56,135.97 136.69,136.09 136.69,136.53 136.81,136.65 138.21,136.65 138.34,136.53 DIMM1.216
  L3 w0.089: 103.33,156.88 99.56,160.65 99.45,160.65 v1(99.04,161.05)
  L3 w0.127: 103.33,156.88 121.02,139.19 128.54,139.19 129.53,138.2 136.3,138.2 136.48,138.02 136.48,137.85 v1(136.05,137.41)
  BOTTOM w0.102: v1(99.04,161.05) 99.04,160.45 v2(99.42,160.07)
M_A_DQ54: length 58.8
  TOP w0.089: CPU1.BA29 93.94,160.35 94.04,160.25 94.65,160.25 94.84,160.07 96.11,160.07 v1(96.7,159.48)
  TOP w0.102: DIMM1.228 137.53,133.53 v1(136.69,134.37)
  L3 w0.089: v1(96.7,159.48) 97.4,158.78 98.56,158.78 98.78,158.56
  L3 w0.127: 98.78,158.56 98.8,158.56 101.58,155.78 101.58,154.81 121.97,134.42 131.21,134.42 131.81,133.82 136.14,133.82 v1(136.69,134.37)
  BOTTOM w0.102: v1(136.69,134.37) v2(136.69,135.25)
M_A_DQ55: length 58
  TOP w0.089: CPU1.BB29 94.7,160.53 94.98,160.25 96.57,160.25 v1(97.33,159.48)
  TOP w0.102: DIMM1.225 132.66,134.28 v1(132.75,134.37)
  L3 w0.089: v1(97.33,159.48) 97.81,159.01 98.71,159.01 98.93,158.78
  L3 w0.127: v1(132.75,134.37) 132.28,134.83 131.26,134.83 131.13,134.96 131.13,135.23 131.01,135.36 130.75,135.36 130.63,135.23 130.63,134.96 130.5,134.83 130.24,134.83 130.12,134.96 130.12,135.48 129.99,135.61 129.74,135.61 129.61,135.48 129.61,134.96 129.48,134.83 129.23,134.83 129.1,134.96 129.1,135.48 128.97,135.61 128.72,135.61 128.59,135.48 128.59,134.96 128.47,134.83 128.21,134.83 128.09,134.96 128.09,135.48 127.96,135.61 127.7,135.61 127.58,135.48 127.58,134.96 127.45,134.83 127.2,134.83 127.07,134.96 127.07,135.48 126.94,135.61 126.69,135.61 126.56,135.48 126.56,134.96 126.43,134.83 122.04,134.83 101.79,155.08 101.79,155.93 98.93,158.78
  BOTTOM w0.102: v1(132.75,134.37) v2(131.86,134.37)
M_A_DQ56: length 63.1
  TOP w0.089: CPU1.AY27 93.3,159.28 93.37,159.22 93.53,159.15 93.86,159.15 94.06,159.1 94.27,159.04 94.74,159.04 95.32,158.46 96.55,158.46 v1(96.98,158.04)
  TOP w0.102: v1(133.38,131.83) 132.83,131.28 DIMM1.237
  L3 w0.089: v1(96.98,158.04) 96.24,158.78 96.06,158.78 95.56,158.28 95.56,158.1 96.29,157.37 98.84,157.37 98.91,157.3 99.36,156.85
  L3 w0.127: v1(133.38,131.83) 133.38,131.83 132.93,132.27 131.1,132.27 130.61,132.77 121.39,132.77 109.57,144.58 109.39,144.58 109.2,144.39 109.02,144.39 108.85,144.57 108.85,144.75 109.04,144.94 109.04,145.12 108.86,145.3 108.68,145.3 108.49,145.11 108.31,145.11 108.13,145.29 108.13,145.47 108.32,145.66 108.32,145.84 108.14,146.02 107.96,146.02 107.77,145.83 107.59,145.83 107.41,146.01 107.41,146.19 107.6,146.38 107.6,146.56 107.42,146.74 107.24,146.74 107.05,146.55 106.87,146.55 106.79,146.63 106.78,146.63 100.29,153.13 100.29,155.4 99.48,156.2 99.48,156.73 99.36,156.85
  BOTTOM w0.102: v2(132.27,132.51) 132.34,132.44 132.77,132.44 v1(133.38,131.83)
M_A_DQ57: length 63.2
  TOP w0.102: v1(137.96,131.83) 138.26,131.53 DIMM1.236 ; CPU1.AW27 92.36,159.74 v1(92.67,160.05)
  L3 w0.089: 99.1,156.5 99.1,156.86 98.83,157.13 95.58,157.13 v1(92.67,160.05)
  L3 w0.127: v1(137.96,131.83) 137.45,131.32 131.57,131.32 130.47,132.42 121.25,132.42 110.92,142.75 110.18,142.75 109.85,143.08 109.85,143.26 110.04,143.45 110.04,143.63 109.8,143.87 109.06,143.87 100.06,152.87 100.06,155.04 99.1,156 99.1,156.5
  BOTTOM w0.102: v2(138.88,132.14) 138.56,131.83 v1(137.96,131.83)
M_A_DQ58: length 62.4
  TOP w0.089: CPU1.AY25 93.37,157.9 93.45,157.86 93.45,157.86 93.79,157.86 94.4,157.67 94.86,157.21 95.44,157.21 v1(95.98,156.68)
  TOP w0.102: DIMM1.245 133.65,129.28 v1(134.65,128.27)
  L3 w0.127: v1(95.98,156.68) 95.98,156.38 98.45,153.91 98.45,151.55 102.27,147.73 102.27,145.47 104.4,143.33 106.66,143.33 109.27,140.73 110.09,140.73 110.33,140.48 110.33,140.3 110.1,140.08 110.1,139.9 110.28,139.72 110.46,139.72 110.69,139.95 110.87,139.95 120.5,130.31 129.48,130.31 130.5,129.3 133.62,129.3 v1(134.65,128.27)
  BOTTOM w0.102: v1(134.65,128.27) 134.3,128.63 v2(134.3,129.01)
M_A_DQ59: length 62.8
  TOP w0.102: CPU1.AW25 v1(92.67,157.65) ; DIMM1.249 132.13,128.28 132.57,127.84 132.95,127.84 v1(133.38,128.27)
  L3 w0.127: v1(92.67,157.65) 95.03,155.96 95.84,155.96 98.13,153.67 98.13,151.38 101.93,147.59 101.93,145.32 101.96,145.29 101.96,145.26 104.27,142.95 106.56,142.95 110.71,138.8 110.89,138.8 111.12,139.03 111.3,139.03 111.48,138.85 111.48,138.67 111.25,138.44 111.25,138.26 111.43,138.08 111.61,138.08 111.84,138.31 112.02,138.31 112.2,138.13 112.2,137.95 111.97,137.72 111.97,137.54 112.15,137.37 112.33,137.37 112.55,137.59 112.73,137.59 112.91,137.41 112.91,137.23 112.69,137.01 112.69,136.83 112.87,136.65 113.05,136.65 113.27,136.87 113.45,136.87 113.63,136.7 113.63,136.52 113.49,136.38 113.49,136.2 113.67,136.02 113.85,136.02 113.99,136.16 114.17,136.16 120.36,129.97 120.36,129.97 129.34,129.97 130.35,128.96 132.7,128.96 v1(133.38,128.27)
  BOTTOM w0.102: v2(133.03,129.01) 133.03,128.63 v1(133.38,128.27)
M_A_DQ60: length 61.4
  TOP w0.102: v1(98.25,158.02) 98.25,158.09 97.33,159 95.31,159 94.88,159.43 94.53,159.43 94.47,159.5 CPU1.BB27 ; v1(136.69,131.83) 137.55,132.69 138.31,132.69 138.48,132.53 DIMM1.232
  L3 w0.089: 100.11,156.46 99.98,156.6 99.98,156.77 98.72,158.02 98.68,158.02
  L3 w0.102: v1(98.25,158.02) 98.68,158.02
  L3 w0.127: v1(136.69,131.83) 136.69,132.69 136.42,132.96 131.39,132.96 130.89,133.45 121.67,133.45 102.53,152.59 102.35,152.59 102.07,152.31 101.89,152.31 101.71,152.49 101.71,152.67 101.99,152.95 101.99,153.13 101.82,153.31 101.64,153.31 101.36,153.03 101.18,153.03 101,153.21 101,153.39 101.28,153.67 101.28,153.85 100.76,154.37 100.76,155.82 100.11,156.46
  BOTTOM w0.102: v1(98.25,158.02) v2(99.22,158.02)
M_A_DQ61: length 61.7
  TOP w0.089: v1(97.61,158.03) 97,158.64 95.39,158.64 94.81,159.22 94.29,159.22 93.97,159.3 CPU1.BA27
  TOP w0.102: DIMM1.233 134.2,132.28 v1(134.65,131.83)
  L3 w0.089: 99.98,156.21 99.73,156.46 99.73,156.76 98.89,157.6 98.04,157.6 v1(97.61,158.03)
  L3 w0.127: v1(134.65,131.83) 133.87,132.61 131.25,132.61 130.75,133.11 121.53,133.11 106.53,148.11 106.35,148.11 106.16,147.92 105.98,147.92 105.8,148.1 105.8,148.28 105.99,148.47 105.99,148.65 105.81,148.83 105.63,148.83 105.44,148.64 105.26,148.64 105.08,148.82 105.08,149 105.27,149.19 105.27,149.37 105.09,149.55 104.91,149.55 104.72,149.36 104.54,149.36 104.36,149.54 104.36,149.72 104.55,149.91 104.55,150.09 104.37,150.27 104.19,150.27 104,150.08 103.82,150.08 103.64,150.26 103.64,150.44 103.83,150.63 103.83,150.81 103.65,150.99 103.47,150.99 103.28,150.8 103.1,150.8 103,150.9 100.54,153.36 100.54,155.65 99.98,156.21
  BOTTOM w0.102: v2(134.98,132.72) 134.65,132.38 v1(134.65,131.83)
M_A_DQ62: length 61.6
  TOP w0.089: CPU1.BA25 94.02,157.98 94.49,157.83 94.92,157.4 95.52,157.4 95.84,157.08 96.22,157.08 v1(96.63,156.68)
  TOP w0.102: v1(136.05,128.27) 136.81,129.03 DIMM1.246
  L3 w0.127: v1(96.63,156.68) 96.63,156.11 98.74,154 98.74,151.74 103.7,146.78 103.7,145.6 105.63,143.68 106.81,143.68 109.41,141.07 110.23,141.07 120.64,130.66 129.62,130.66 130.64,129.64 134.07,129.64 135.44,128.27 v1(136.05,128.27)
  BOTTOM w0.102: v1(136.05,128.27) 136.05,127.84 v2(136.38,127.51)
M_A_DQ63: length 61.3
  TOP w0.089: v1(97.32,156.69) 96.91,157.1 96.5,157.1 96.34,157.26 95.91,157.26 95.6,157.58 95.04,157.58 94.45,158.17 CPU1.BB25
  TOP w0.102: v1(137.32,128.27) 137.75,127.84 138.13,127.84 138.32,128.03 DIMM1.250
  L3 w0.127: v1(97.32,156.69) 97.32,155.9 98.99,154.23 98.99,151.98 109.55,141.41 110.37,141.41 120.79,131 129.77,131 130.78,129.98 134.23,129.98 135.29,128.93 136.66,128.93 v1(137.32,128.27)
  BOTTOM w0.102: v2(138.77,128.19) 138.41,127.84 137.75,127.84 v1(137.32,128.27)
M_A_DQS_DN0: length 71.3
  TOP w0.089: 88.4,186.71 88.4,186.69 88.41,186.68 88.41,186.06 88.37,186.01 88.37,185.67 88.37,185.66 88.37,185.21 88.42,185.06 88.42,184.92 88.36,184.72 88.36,184.54 CPU1.AM70
  TOP w0.102: 88.4,186.71 88.4,189.99 88.32,190.07 88.12,190.07 v1(87.84,189.79) ; DIMM1.11 132.2,189.78 132.66,189.32 133.76,189.32 133.91,189.47 133.91,189.85 133.76,189.99 v1(133.38,189.99)
  L3 w0.127: v1(87.84,189.79) 88.01,189.62 88.21,189.62 88.3,189.71 88.3,194.69 91.5,197.89 111.89,197.89 112.01,197.76 112.01,197.36 112.3,197.08 112.9,197.08 113.18,197.36 113.18,197.76 113.31,197.89 113.69,197.89 113.82,197.76 113.82,197.36 114.1,197.08 117.73,197.08 118.95,195.86 119.84,195.86 120.12,196.14 120.12,196.63 120.25,196.76 120.63,196.76 120.76,196.63 120.76,196.14 121.04,195.86 124.45,195.86 129.87,190.44 130.53,190.44 130.66,190.31 130.66,190.02 130.94,189.74 131.55,189.74 131.83,190.02 131.83,190.31 131.96,190.44 133.75,190.44 133.89,190.3 133.89,189.99 133.79,189.89 133.48,189.89 v1(133.38,189.99)
  BOTTOM w0.102: v2(133.38,189.2) v1(133.38,189.99)
M_A_DQS_DN1: length 64.6
  TOP w0.089: CPU1.AT69 90.51,183.81 90.9,184.2 90.9,184.71 90.95,184.89 90.95,185.08 90.9,185.26 90.9,185.28 90.9,185.57 91.66,186.32 91.66,187.24 v1(91.04,187.86)
  TOP w0.102: v1(137.32,184.53) 137.32,184.24 137.46,184.1 138.13,184.1 138.56,184.53 DIMM1.32
  L3 w0.127: v1(91.04,187.86) 91.82,188.64 91.82,189.06 92.25,189.5 92.98,189.5 93.37,189.1 96.6,189.1 99.48,191.99 108.02,191.99 108.2,192.16 108.2,193 108.48,193.28 109.07,193.28 109.35,193 109.35,192.13 109.48,192 109.87,192 110,192.13 110,192.92 110.29,193.21 110.89,193.21 111.17,192.92 111.17,192.21 111.37,192.01 122.92,192.01 129.54,185.39 137.12,185.39 137.32,185.19 v1(137.32,184.53)
  BOTTOM w0.102: v1(91.04,187.86) 91.3,187.86 v2(91.85,188.42)
M_A_DQS_DN2: length 54.9
  TOP w0.089: 98.63,185.41 98.54,185.41 98.54,185.41 98.46,185.41 98.45,185.42 98.2,185.42 96.83,184.05 96.83,182.47 95.62,181.26 94.78,181.26 94.63,181.11 94.21,181.11 94.06,181.16 93.92,181.16 93.72,181.1 93.54,181.1 CPU1.BA64
  TOP w0.102: v1(102.09,186.79) 101.89,186.59 101.89,186.08 101.22,185.41 98.63,185.41 ; DIMM1.53 132.31,179.28 132.6,178.99 133.84,178.99 133.97,179.12 133.97,179.55 133.84,179.68 133.61,179.68 v1(133.38,179.45)
  L3 w0.127: v1(102.09,186.79) 102.03,186.79 101.9,186.92 101.9,187.34 102.23,187.67 121.15,187.67 128.81,180.01 133.84,180.01 133.95,179.9 133.95,179.39 133.84,179.27 133.56,179.27 v1(133.38,179.45)
  BOTTOM w0.102: v1(102.09,186.79) 102.09,187.45 v2(102.4,187.76)
M_A_DQS_DN3: length 56.1
  TOP w0.089: CPU1.AY60 93.06,178.16 93.69,178.16 93.89,178.1 94.09,178.1 94.24,178.14 95.5,178.14 95.68,178.32 95.7,178.32 95.71,178.34
  TOP w0.102: 95.71,178.34 95.78,178.41 97.61,180.24 99.25,180.24 99.46,180.45 99.46,180.87 v1(99.58,180.98) ; v1(136.69,173.1) 136.85,173.27 136.85,173.7 137.03,173.88 138.23,173.88 138.38,174.03 DIMM1.74
  L3 w0.127: v1(136.69,173.1) 136.94,173.35 136.94,173.74 136.09,174.59 128.49,174.59 119.36,183.72 104.22,183.72 102.74,182.24 101.85,182.24 101.12,181.51 100.1,181.51 v1(99.58,180.98)
  BOTTOM w0.102: v1(136.69,173.1) 136.69,173.66 v2(136.39,173.96)
M_A_DQS_DN4: length 59.5
  TOP w0.089: v1(97.38,166.8) 97.38,166.51 97.09,166.22 95.11,166.22 94.93,166.39 94.21,166.39 94.06,166.44 93.92,166.44 93.72,166.37 93.42,166.37 93.34,166.3 CPU1.BA38
  TOP w0.102: v1(133.38,146.69) 133.73,146.34 133.73,146.09 133.63,145.99 132.32,145.99 132.04,146.28 DIMM1.177
  L3 w0.089: v1(97.38,166.8) 97.19,166.99 97.09,166.99 96.95,166.85 96.95,166.21 97.32,165.85 101.36,165.85 102.45,164.76 104.39,162.82 104.45,162.82 104.46,162.81
  L3 w0.127: v1(133.38,146.69) 133.62,146.44 133.62,146.29 133.53,146.19 132.46,146.19 131.83,146.82 130.62,146.82 130.33,146.54 130.33,146.09 130.21,145.96 129.83,145.96 129.7,146.09 129.7,146.54 129.42,146.82 128.81,146.82 128.53,146.54 128.53,146.09 128.4,145.96 128.02,145.96 127.89,146.09 127.89,146.54 127.61,146.82 127.01,146.82 126.73,146.54 126.73,146.09 126.6,145.96 126.22,145.96 126.09,146.09 126.09,146.54 125.81,146.82 125.12,146.82 119.59,152.35 118.7,152.35 108.45,162.6 107.79,162.6 104.67,162.6 104.46,162.81
  BOTTOM w0.102: v2(97.24,165.86) 97.24,166.66 v1(97.38,166.8)
M_A_DQS_DN5: length 60.2
  TOP w0.089: v1(98.38,162.58) 98.61,162.8 98.61,162.97 98.22,163.35 94.58,163.35 94.51,163.42 94.24,163.42 94.09,163.37 93.89,163.37 93.69,163.43 93.06,163.43 CPU1.AY34
  TOP w0.102: v1(137.32,141.22) 137.75,140.79 138.39,140.79 138.62,141.03 DIMM1.198
  L3 w0.089: 104.58,158.71 104.48,158.71 99.95,163.24 98.71,163.24 98.52,163.05 98.52,162.72 v1(98.38,162.58)
  L3 w0.127: 104.58,158.71 105.61,158.71 108.01,156.32 108.57,156.32 110.73,154.16 110.73,154.16 110.81,154.08 110.81,153.29 118.2,145.9 119.46,145.9 123.45,141.91 131.29,141.91 132.19,141.01 134.83,141.01 135.97,142.15 136.95,142.15 137.23,141.87 137.23,141.31 v1(137.32,141.22)
  BOTTOM w0.102: v2(137.7,140.47) 137.32,140.84 v1(137.32,141.22)
M_A_DQS_DN6: length 59.6
  TOP w0.089: v1(96.38,161) 96.38,160.69 96.31,160.62 95.16,160.62 94.8,160.97 94.21,160.97 94.06,160.92 93.92,160.92 93.72,160.98 93.54,160.98 CPU1.BA30
  TOP w0.102: v1(133.38,136.14) 133.92,136.14 134.15,135.91 134.15,135.62 134.02,135.49 132.46,135.49 132.18,135.78 DIMM1.219
  L3 w0.089: v1(96.38,161) 96.75,160.63 97.2,160.63 97.61,160.22 97.76,160.22 98.36,160.22 102.46,156.13 102.46,155.73 102.69,155.5 102.69,155.42
  L3 w0.127: v1(133.38,136.14) 133.89,136.14 134.02,136.27 134.02,136.53 133.84,136.7 133.18,136.7 133.11,136.64 125.76,136.64 125.63,136.51 125.63,136.24 125.35,135.95 124.75,135.95 124.46,136.24 124.46,136.51 124.34,136.64 123.96,136.64 123.83,136.51 123.83,136.24 123.55,135.95 122.94,135.95 122.66,136.24 122.66,136.51 122.53,136.64 121.47,136.64 103.88,154.23 102.69,155.42
  BOTTOM w0.102: v2(133.15,135.36) 133.38,135.59 v1(133.38,136.14)
M_A_DQS_DN7: length 62.3
  TOP w0.089: v1(98.02,156.69) 97.91,156.8 97.86,156.85 97.82,156.85 97.34,157.33 96.65,157.33 96.54,157.44 96.04,157.44 95.69,157.8 95.12,157.8 94.48,158.44 94.24,158.44 94.09,158.39 93.89,158.39 93.69,158.45 93.06,158.45 CPU1.AY26
  TOP w0.102: DIMM1.240 137.36,130.53 137.1,130.26 137.1,130.09 v1(136.69,129.67)
  L3 w0.127: v1(136.69,129.67) 136.69,130.26 136.43,130.52 131.24,130.52 130.19,131.57 120.97,131.57 110.59,141.95 109.85,141.95 99.46,152.34 99.46,154.5 98.66,155.3 98.06,155.9 98.06,156.65 v1(98.02,156.69)
  BOTTOM w0.102: v1(136.69,129.67) 136.69,130.3 v2(136.43,130.56)
M_A_DQS_DN8: length 5.5
  TOP w0.102: v1(133.38,170.56) 133.53,170.42 133.53,170.29 132.49,169.25 132.49,169.04 132.23,168.78 DIMM1.95
  BOTTOM w0.102: v2(132.12,171.44) 132.18,171.39 R558.2 v1(133.38,170.56)
M_A_DQS_DP0: length 71.8
  TOP w0.089: CPU1.AM69 88.25,183.97 88.54,184.34 88.54,184.69 88.6,184.89 88.6,185.09 88.55,185.24 88.55,185.66 88.56,185.67 88.56,185.93 88.6,185.98 88.6,186.68 88.62,186.69 88.62,186.71
  TOP w0.102: v1(134.4,189.99) 134.13,189.72 134.13,189.38 133.85,189.11 132.57,189.11 132.4,189.28 DIMM1.13 ; 88.62,186.71 88.62,190.08 88.41,190.29 88.02,190.29 v1(87.85,190.46)
  L3 w0.127: v1(134.4,189.99) 134.4,189.99 134.16,190.23 134.16,190.41 133.86,190.7 131.85,190.7 131.56,190.42 131.56,190.13 131.44,190 131.05,190 130.93,190.13 130.93,190.42 130.64,190.7 129.98,190.7 124.56,196.13 121.15,196.13 121.02,196.25 121.02,196.74 120.74,197.03 120.14,197.03 119.85,196.74 119.85,196.25 119.73,196.13 119.06,196.13 117.84,197.35 114.21,197.35 114.08,197.47 114.08,197.87 113.8,198.16 113.2,198.16 112.91,197.87 112.91,197.47 112.79,197.35 112.41,197.35 112.28,197.47 112.28,197.87 112,198.16 91.39,198.16 88.03,194.8 88.03,190.64 v1(87.85,190.46)
  BOTTOM w0.102: v2(87.92,191.54) 87.85,191.47 v1(87.85,190.46)
M_A_DQS_DP1: length 64.5
  TOP w0.089: v1(91.04,187.23) 91.12,187.3 91.33,187.3 91.47,187.17 91.47,186.4 90.71,185.64 90.72,185.63 90.72,185.25 90.73,185.21 90.74,185.2 90.77,185.06 90.77,184.92 90.72,184.73 90.72,184.39 90.67,184.34 CPU1.AT70
  TOP w0.102: DIMM1.34 138.37,184.03 138.22,183.88 136.95,183.88 v1(136.3,184.53)
  L3 w0.127: v1(91.04,187.23) 91.46,187.65 91.46,187.9 92.09,188.53 92.09,188.95 92.36,189.23 92.87,189.23 93.26,188.84 96.71,188.84 99.59,191.72 108.14,191.72 108.47,192.05 108.47,192.89 108.59,193.01 108.96,193.01 109.09,192.89 109.09,192.02 109.37,191.73 109.98,191.73 110.27,192.02 110.27,192.81 110.4,192.94 110.78,192.94 110.9,192.81 110.9,192.1 111.26,191.74 122.81,191.74 129.43,185.13 136.9,185.13 137.02,185.01 137.02,184.86 136.69,184.53 v1(136.3,184.53)
  BOTTOM w0.102: v1(136.3,184.53) 136.3,184.12 v2(135.95,183.77)
M_A_DQS_DP2: length 54.8
  TOP w0.089: CPU1.AY64 92.97,181.28 93.69,181.28 93.89,181.34 94.09,181.34 94.24,181.29 94.56,181.29 94.71,181.44 95.53,181.44 96.64,182.55 96.64,184.13 98.13,185.61 98.61,185.61 98.62,185.62 98.63,185.62
  TOP w0.102: 98.63,185.62 101.13,185.62 101.67,186.17 101.67,186.57 v1(101.45,186.79) ; DIMM1.55 133.93,178.78 134.18,179.03 134.18,179.24 v1(134.4,179.45)
  L3 w0.127: v1(101.45,186.79) 101.64,186.97 101.64,187.45 102.12,187.93 121.26,187.93 128.92,180.28 133.95,180.28 134.22,180.01 134.22,179.63 v1(134.4,179.45)
  BOTTOM w0.102: v1(101.45,186.79) 101.45,186.16 v2(101.71,185.9)
M_A_DQS_DP3: length 56.2
  TOP w0.089: 95.56,178.49 95.54,178.48 95.54,178.46 95.41,178.32 94.21,178.32 94.06,178.27 93.92,178.27 93.72,178.34 93.54,178.34 CPU1.BA60
  TOP w0.102: 95.56,178.49 95.63,178.56 97.52,180.45 99.16,180.45 99.25,180.54 99.25,180.69 v1(98.93,181) ; DIMM1.76 139.4,173.52 138.38,173.52 138.23,173.67 137.12,173.67 137.07,173.61 137.07,173.35 v1(137.32,173.1)
  L3 w0.127: v1(98.93,181) 99.34,181.41 99.63,181.41 99.99,181.78 101.01,181.78 101.73,182.5 102.63,182.5 104.11,183.98 119.47,183.98 128.6,174.85 136.2,174.85 137.21,173.85 137.21,173.22 v1(137.32,173.1)
  BOTTOM w0.102: v2(98.41,180.06) 98.41,180.47 v1(98.93,181)
M_A_DQS_DP4: length 59.7
  TOP w0.089: v1(96.55,166.83) 96.13,166.41 95.19,166.41 95.03,166.57 94.24,166.57 94.09,166.61 93.89,166.61 93.69,166.55 93.06,166.55 CPU1.AY38
  TOP w0.102: DIMM1.179 133.72,145.78 133.94,146 133.94,146.61 v1(134.02,146.69)
  L3 w0.089: v1(96.55,166.83) 96.76,166.62 96.76,166.14 97.24,165.66 101.28,165.66 102.37,164.57 104.26,162.69 104.26,162.63 104.27,162.63
  L3 w0.127: 104.27,162.63 104.56,162.33 107.9,162.33 108.34,162.33 118.59,152.08 119.48,152.08 125.01,146.55 125.7,146.55 125.82,146.43 125.82,145.98 126.11,145.69 126.71,145.69 126.99,145.98 126.99,146.43 127.12,146.55 127.5,146.55 127.63,146.43 127.63,145.98 127.91,145.69 128.51,145.69 128.8,145.98 128.8,146.43 128.92,146.55 129.3,146.55 129.43,146.43 129.43,145.98 129.71,145.69 130.32,145.69 130.6,145.98 130.6,146.43 130.73,146.55 131.72,146.55 132.35,145.92 133.64,145.92 133.89,146.18 133.89,146.56 v1(134.02,146.69)
  BOTTOM w0.102: v1(134.02,146.69) 134.86,147.52 v2(134.93,147.52)
M_A_DQS_DP5: length 60.3
  TOP w0.089: CPU1.BA34 93.54,163.61 93.72,163.61 93.92,163.55 94.06,163.55 94.21,163.6 94.59,163.6 94.64,163.54 98.3,163.54 98.8,163.04 98.8,162.71 98.91,162.6 v1(99.04,162.6)
  TOP w0.102: v1(136.69,141.22) 136.69,140.84 136.81,140.72 137.52,140.72 137.66,140.58 138.37,140.58 138.42,140.52 DIMM1.200
  L3 w0.089: 104.44,158.47 104.44,158.48 104.24,158.69 99.88,163.05 98.79,163.05 98.71,162.97 98.71,162.81 98.93,162.6 v1(99.04,162.6)
  L3 w0.127: v1(136.69,141.22) 136.96,141.5 136.96,141.76 136.84,141.88 136.08,141.88 134.94,140.74 132.08,140.74 131.18,141.64 123.34,141.64 119.35,145.64 118.09,145.64 110.54,153.18 110.54,153.97 108.46,156.06 107.9,156.06 105.5,158.45 104.47,158.45 104.44,158.47
  BOTTOM w0.102: v2(136.25,140.46) 136.69,140.89 v1(136.69,141.22)
M_A_DQS_DP6: length 59.8
  TOP w0.089: v1(97.07,161.03) 96.99,161.03 96.39,160.43 95.08,160.43 94.71,160.79 94.24,160.79 94.09,160.75 93.89,160.75 93.69,160.81 93.36,160.81 CPU1.AY30
  TOP w0.102: v1(134.53,136.14) 134.36,135.98 134.36,135.53 134.11,135.28 DIMM1.221
  L3 w0.089: 102.88,155.6 102.85,155.6 102.65,155.81 102.65,156.21 98.44,160.42 97.68,160.42 97.24,160.86 97.2,160.9 v1(97.07,161.03)
  L3 w0.127: 102.88,155.6 104.15,154.34 121.58,136.91 122.64,136.91 122.93,136.62 122.93,136.35 123.05,136.22 123.43,136.22 123.56,136.35 123.56,136.62 123.85,136.91 124.45,136.91 124.73,136.62 124.73,136.35 124.86,136.22 125.24,136.22 125.37,136.35 125.37,136.62 125.65,136.91 133,136.91 133.07,136.97 133.95,136.97 134.28,136.64 134.28,136.39 v1(134.53,136.14)
  BOTTOM w0.102: v1(134.53,136.14) 134.53,135.69 v2(134.86,135.36)
M_A_DQS_DP7: length 62.2
  TOP w0.089: CPU1.BA26 93.54,158.63 93.72,158.63 93.92,158.57 94.06,158.57 94.21,158.62 94.55,158.62 95.19,157.97 95.76,157.97 96.12,157.62 96.64,157.62 96.73,157.52 97.42,157.52 97.84,157.1 98.3,157.1 v1(98.7,156.69)
  TOP w0.102: v1(137.32,129.67) 137.32,130.18 137.45,130.31 138.33,130.31 138.61,130.03 DIMM1.242
  L3 w0.127: v1(137.32,129.67) 136.95,130.04 136.95,130.37 136.54,130.78 131.35,130.78 130.3,131.84 121.08,131.84 110.7,142.21 109.96,142.21 99.73,152.45 99.73,154.61 98.32,156.01 98.32,156.31 v1(98.7,156.69)
  BOTTOM w0.102: v1(98.7,156.69) 99.5,156.69 v2(99.65,156.54)
M_A_DQS_DP8: length 7
  TOP w0.102: v1(134.02,170.56) 133.74,170.29 133.74,170.2 132.71,169.16 132.71,168.95 132.04,168.28 DIMM1.97
  BOTTOM w0.102: R557.2 134.4,170.94 v1(134.02,170.56) 134.02,170.26 133.48,169.72 132.52,169.72 v2(132.49,169.7)
M_A_EVENT#: length 4.7
  TOP w0.102: v3(140.81,159.51) 140.32,159.03 DIMM1.134
  BOTTOM w0.102: v3(140.81,159.51) 140.85,159.55 140.85,160.58 140.62,160.81 v2(140.42,160.81) 140.39,160.81 139.8,160.21 R570.2
M_A_ODT0: length 63.2
  TOP w0.165: v1(90.21,170.63) 90.26,170.63 90.55,170.34 CPU1.AT45 ; DIMM1.155 131.2,151.77 132.36,151.77 132.38,151.76 133.64,151.76 133.94,151.47 134.32,151.47 v1(134.78,151)
  L3 w0.089: 104.27,165.48 102.04,167.72 94.88,167.72 94.75,167.59 94.75,166.75 94.6,166.6 92.54,166.6 91.73,167.41 91.73,168.19 91.9,168.36 91.9,169.03 91.61,169.31 90.42,169.31 90.21,169.51 v1(90.21,170.63)
  L3 w0.216: 104.27,165.48 104.43,165.33 110.55,165.33 126.41,149.47 128.85,149.47 129.35,149.97 130.15,149.97 130.65,149.47 131.99,149.47 132.49,149.97 134.1,149.97 134.78,150.65 v1(134.78,151)
  BOTTOM w0.165: v2(89.8,171.32) 90.21,170.91 v1(90.21,170.63)
M_A_ODT1: length 64.8
  TOP w0.165: CPU1.AT43 90.85,168.99 90.85,168.9 v1(90.86,168.89) ; DIMM1.161 133.88,150.28 134.48,149.67 134.48,149.65 v1(134.65,149.48)
  L3 w0.089: 104.4,164.97 101.89,167.49 95.13,167.49 94.93,167.28 94.93,166.5 94.7,166.27 92.36,166.27 91.35,167.28 91.35,168.41 v1(90.86,168.89)
  L3 w0.216: v1(134.65,149.48) 135.38,150.2 136.43,150.2 136.63,150 136.63,149.03 136.43,148.82 134.04,148.82 133.89,148.97 126.2,148.97 110.35,164.82 104.55,164.82 104.4,164.97
  BOTTOM w0.165: v1(134.65,149.48) 135.16,149.99 v2(135.29,149.99)
M_B_A0: length 75
  TOP w0.089: v1(99.86,170.56) 99.06,171.36 96.33,171.36 95.66,170.69 95.19,170.69 95.16,170.72 94.23,170.72 93.9,170.64 93.9,170.64 CPU1.BA46
  TOP w0.165: v1(153.07,157.08) 153.09,157.08 153.64,156.53 DIMM2.144
  L4 w0.089: 103.46,168.63 102.8,168.63 101.38,170.05 100.36,170.05 v1(99.86,170.56)
  L4 w0.216: v1(153.07,157.08) 153.07,158.14 153.27,158.34 153.73,158.34 153.93,158.14 153.93,156.29 153.73,156.09 146.03,156.09 145.15,155.21 140.29,155.21 139.77,155.72 131.87,155.72 129.48,158.1 129.18,158.1 128.61,157.53 128.3,157.53 117.2,168.63 103.46,168.63
  BOTTOM w0.165: v2(153.83,156.36) 153.11,157.08 v1(153.07,157.08)
M_B_A1: length 77.4
  TOP w0.089: CPU1.AY46 93.61,170.85 94.02,170.85 94.02,170.85 94.21,170.9 95.23,170.9 95.24,170.89 95.59,170.89 96.24,171.54 99.64,171.54 v1(100.62,170.56)
  TOP w0.165: v1(149.26,157.08) 149.26,157.12 150.55,158.42 150.55,158.9 149.97,159.48 147.48,159.48 147.27,159.28 DIMM2.133
  L4 w0.089: 102.8,169.14 101.38,170.56 v1(100.62,170.56)
  L4 w0.216: 102.8,169.14 117.39,169.14 123.75,162.78 125.53,162.78 125.84,162.47 125.84,162.17 125.26,161.59 125.26,161.28 125.57,160.98 125.87,160.98 126.45,161.55 126.75,161.55 127.06,161.25 127.06,160.94 126.48,160.37 126.48,160.06 126.79,159.76 127.09,159.76 127.67,160.33 127.98,160.33 128.28,160.03 128.28,159.72 127.7,159.15 127.7,158.84 128.01,158.53 128.32,158.53 128.89,159.11 129.2,159.11 131.36,156.95 135.49,156.95 135.6,156.84 139.35,156.84 140.49,155.7 144.94,155.7 145.83,156.59 148.82,156.59 149.26,157.02 v1(149.26,157.08)
  BOTTOM w0.165: v2(100.97,169.82) 100.62,170.18 v1(100.62,170.56)
M_B_A2: length 75.5
  TOP w0.089: v1(100.87,172.97) 100.64,172.75 100.64,172.09 100.52,171.96 99.46,171.96 99.33,172.09 99.33,172.49 99.24,172.57 99.07,172.57 98.98,172.49 98.98,171.99 98.89,171.9 95.07,171.9 94.7,171.53 94.23,171.53 94.1,171.56 93.89,171.56 93.57,171.49 93.14,171.49 CPU1.AY47
  TOP w0.165: DIMM2.132 153.64,159.53 153.07,160.1 149.36,160.1 149.15,160.31 v1(149.15,161.29)
  L4 w0.216: v1(149.15,161.29) 149.15,161.65 148.98,161.82 140.57,161.82 139.75,162.65 136.98,162.65 136.51,163.11 132.64,163.11 129.87,165.89 129.2,165.89 127.57,167.52 127.57,168.29 125.17,170.7 124.86,170.7 124.35,170.19 124.05,170.19 123.74,170.5 123.74,170.8 124.25,171.31 124.25,171.61 123.94,171.92 123.64,171.92 123.13,171.41 122.83,171.41 122.52,171.72 122.52,172.02 123.03,172.53 123.03,172.84 122.71,173.15 103.21,173.15 103.03,172.97 v1(100.87,172.97)
  BOTTOM w0.165: v2(101.53,172.31) v1(100.87,172.97)
M_B_A3: length 73.9
  TOP w0.089: CPU1.BB46 95.69,170.46 96.41,171.18 97.33,171.18 v1(97.95,170.56)
  TOP w0.165: DIMM2.131 150.09,159.78 150.88,158.98 150.88,157.48 150.7,157.29 150.7,157.27 150.53,157.1 v1(150.53,157.08)
  L4 w0.089: v1(97.95,170.56) 98.43,171.04 102.3,171.04 102.52,170.82
  L4 w0.216: v1(150.53,157.08) 150.53,157.14 150.09,157.58 147.35,157.58 146.72,158.21 146.21,158.21 145.99,157.99 145.99,157.34 145.77,157.12 145.34,157.12 145.13,157.34 145.13,157.99 144.91,158.21 144.38,158.21 142.77,156.6 140.3,156.6 138.75,158.14 136.15,158.14 135.75,157.75 131.26,157.75 125.74,163.27 123.96,163.27 117.6,169.63 103.71,169.63 102.52,170.82
  BOTTOM w0.165: v1(150.53,157.08) 150.53,157.76 v2(150.74,157.97)
M_B_A4: length 74.9
  TOP w0.089: 101.15,171.81 101.05,171.71 95.14,171.71 94.77,171.35 94.2,171.35 94.07,171.39 93.91,171.39 93.62,171.31 CPU1.BA47
  TOP w0.165: 101.15,171.81 101.38,172.04 101.38,173.34 101.18,173.54 100.4,173.54 100.24,173.38 v1(100.24,172.97) ; DIMM2.128 153.84,160.53 153.7,160.39 151.38,160.39 151.16,160.6 v1(151.16,161.29)
  L4 w0.089: v1(100.24,172.97) 100.24,173.25 100.39,173.41 101.81,173.41 102.54,174.13
  L4 w0.216: v1(151.16,161.29) 151.16,162.1 150.95,162.32 140.78,162.32 139.13,163.97 137.05,163.97 136.69,163.61 132.85,163.61 130.07,166.38 129.4,166.38 128.07,167.72 128.07,168.5 122.83,173.74 104.05,173.74 103.65,174.13 102.54,174.13
  BOTTOM w0.165: v2(99.64,172.1) 100.24,172.69 v1(100.24,172.97)
M_B_A5: length 76
  TOP w0.089: CPU1.AY48 93.26,172.03 93.44,172.03 93.48,172.04 93.69,172.26 94.62,172.26 94.83,172.47 97.26,172.47 98.17,173.37 99.2,173.37 v1(99.6,172.97)
  TOP w0.165: v1(152.43,161.29) 152.43,161.14 152.88,160.7 153.45,160.7 153.78,161.03 DIMM2.126
  L4 w0.089: v1(99.6,172.97) 100.24,173.61 101.51,173.61 102.37,174.47 102.78,174.47
  L4 w0.216: v1(152.43,161.29) 152.43,160.4 152.64,160.2 153.6,160.2 153.8,160.4 153.8,162.26 153.6,162.46 152.56,162.46 152.2,162.81 140.98,162.81 139.33,164.47 136.79,164.47 136.43,164.1 133.05,164.1 130.28,166.88 129.61,166.88 128.56,167.93 128.56,168.7 123.02,174.24 104.38,174.24 104.15,174.47 102.78,174.47
  BOTTOM w0.165: v2(152.81,162.15) 152.43,161.77 v1(152.43,161.29)
M_B_A6: length 75.3
  TOP w0.089: CPU1.BA48 93.94,172.06 94.7,172.06 94.92,172.29 97.65,172.29 v1(98.33,172.97)
  TOP w0.165: DIMM2.127 147.47,160.78 147.86,161.16 147.86,161.25 v1(147.88,161.27)
  L4 w0.089: 103.41,172.66 103.33,172.57 98.73,172.57 v1(98.33,172.97)
  L4 w0.216: v1(147.88,161.27) 147.86,161.29 140.41,161.29 139.54,162.15 136.77,162.15 136.37,162.56 132.49,162.56 129.66,165.39 128.26,165.39 126.68,166.98 126.68,167.66 126.93,167.91 126.93,168.2 126.61,168.52 126.32,168.52 124.84,167.04 124.53,167.04 124.23,167.35 124.23,167.65 125.68,169.11 125.68,169.4 125.36,169.72 125.07,169.72 123.62,168.26 123.31,168.26 123.01,168.57 123.01,168.87 123.68,169.55 123.68,169.85 123.37,170.16 123.07,170.16 122.39,169.48 122.09,169.48 121.78,169.79 121.78,170.1 122.46,170.77 122.46,171.07 122.15,171.38 121.85,171.38 121.17,170.71 120.87,170.71 120.56,171.01 120.56,171.32 121.23,171.99 121.23,172.3 120.87,172.66 103.41,172.66
  BOTTOM w0.165: v2(97.59,172.34) 98.23,172.97 v1(98.33,172.97)
M_B_A7: length 77.6
  TOP w0.165: v1(151.16,163.32) 151.16,163.17 152.31,162.03 DIMM2.122 ; v1(88.87,172.48) 88.87,172.41 CPU1.AP48
  L4 w0.089: v1(88.87,172.48) 89.27,172.08 94.01,172.08 97.73,175.8 102.56,175.8 102.6,175.84
  L4 w0.216: 102.6,175.84 123.78,175.84 132,167.63 134.85,167.63 135.36,167.12 136.95,167.12 137.14,166.93 137.14,166.32 137.35,166.11 138.05,166.11 138.27,166.33 138.27,167.23 138.47,167.44 138.93,167.44 139.13,167.23 139.13,166.33 139.35,166.11 141.6,166.11 142.77,164.95 148.07,164.95 148.26,164.76 149.22,164.76 149.96,164.02 150.91,164.02 151.16,163.76 v1(151.16,163.32)
  BOTTOM w0.165: v1(151.16,163.32) 151.16,162.53 v2(151.26,162.43)
M_B_A8: length 73.1
  TOP w0.089: v1(98.97,172.97) 98.71,172.72 98.71,172.21 98.59,172.09 95,172.09 94.69,171.79 CPU1.BB48
  TOP w0.165: DIMM2.125 147.23,161.28 147.93,161.98 148.88,161.98 149.15,162.25 149.15,162.77 148.62,163.3 v1(148.62,163.32)
  L4 w0.089: 103.09,174.9 102.33,174.9 101.87,174.44 97.13,174.44 96.86,174.17 96.86,173.05 97.06,172.85 97.49,172.85 97.7,173.05 97.7,173.33 97.9,173.53 98.79,173.53 98.97,173.35 v1(98.97,172.97)
  L4 w0.216: 103.09,174.9 104.15,174.9 104.31,174.74 123.23,174.74 129.06,168.91 129.06,168.13 129.8,167.39 130.73,167.39 132.69,165.42 133.03,165.08 139.42,165.08 140.61,163.89 142.05,163.89 142.47,163.47 142.92,163.47 143.34,163.89 145.61,163.89 146.03,163.47 146.48,163.47 146.9,163.89 147.72,163.89 148.3,163.32 v1(148.62,163.32)
  BOTTOM w0.165: v2(147.99,164.08) 148.62,163.45 v1(148.62,163.32)
M_B_A9: length 72.7
  TOP w0.165: DIMM2.121 147.23,162.28 147.86,162.91 148.13,163.69 v1(150.27,165.23) ; CPU1.AP50 v1(89.55,173.41)
  L4 w0.089: v1(89.55,173.41) 90.07,173.8 91.85,173.8
  L4 w0.216: v1(150.27,165.23) 149.64,165.75 148.67,165.75 148.48,165.94 143.18,165.94 141.3,167.81 138.08,169.03 137.61,169.03 132.75,170.05 132.24,170.05 129.77,171.27 124.19,176.85 104.48,176.85 104.46,176.83 102.17,176.83 101.86,176.53 97.32,176.53 95.09,174.31 93.87,173.8 91.85,173.8
  BOTTOM w0.165: v1(150.27,165.23) 150.02,165.23 v2(149.49,164.7)
M_B_A10: length 75.3
  TOP w0.089: v1(97.32,170.56) 96.91,170.96 96.45,170.96 95.73,170.25 94.62,170.25 94.57,170.2 93.51,170.2 93.42,170.25 93,170.25 92.66,170.36 CPU1.AW46
  TOP w0.165: DIMM2.146 153.86,154.03 153.32,154.56 150.76,154.56 150.27,155.05 v1(150.27,155.07)
  L4 w0.089: v1(97.32,170.56) 98.36,169.52 100.87,169.52 103.14,167.25 103.28,167.25
  L4 w0.216: 103.28,167.25 104.25,167.25 104.41,167.09 115.26,167.09 123.1,159.26 123.89,159.26 129.1,154.05 134.32,154.05 134.51,154.23 138.03,154.23 138.29,153.97 138.29,153.44 138.67,153.06 139.17,153.06 139.38,153.28 139.38,153.5 139.6,153.72 140.03,153.72 140.25,153.5 140.25,153.28 140.46,153.06 141.94,153.06 142.16,153.28 142.16,153.5 142.37,153.72 142.8,153.72 143.02,153.5 143.02,153.28 143.24,153.06 145.26,153.06 146.76,154.56 147.62,154.56 147.84,154.34 147.84,154.17 148.06,153.95 148.49,153.95 148.7,154.17 148.7,154.34 148.92,154.56 150.12,154.56 150.27,154.71 v1(150.27,155.07)
  BOTTOM w0.165: v2(150.41,155.91) 150.27,155.78 v1(150.27,155.07)
M_B_A11: length 78.8
  TOP w0.165: DIMM2.120 153.08,162.53 152.43,163.17 v1(152.43,163.32) ; CPU1.AN48 88.21,172.42 v1(88.21,172.49)
  L4 w0.089: 92.11,172.97 92.08,172.94 88.66,172.94 v1(88.21,172.49)
  L4 w0.216: v1(152.43,163.32) 153.53,164.41 153.53,164.97 153.14,165.35 152.59,165.35 151.74,164.51 150.17,164.51 149.43,165.25 148.47,165.25 148.28,165.44 142.97,165.44 141.81,166.61 140.76,166.61 139.43,167.94 135.23,167.94 135.05,168.12 132.21,168.12 123.99,176.35 102.4,176.35 102.19,176.15 97.57,176.15 94.39,172.97 92.11,172.97
  BOTTOM w0.165: v2(152.03,164.31) 152.43,163.91 v1(152.43,163.32)
M_B_A12: length 76.7
  TOP w0.165: v1(150.15,166.24) 150.15,166.12 147.49,163.45 147.49,163.04 147.23,162.78 DIMM2.119 ; CPU1.AN50 88.6,173.06 88.27,173.38 v1(88.22,173.38)
  L4 w0.089: 101.73,177.84 97.36,177.84 95.18,175.66 89.49,175.66 89.22,175.39 89.22,174.84 89.41,174.66 89.41,174.15 89.06,173.8 88.65,173.8 v1(88.22,173.38)
  L4 w0.216: v1(150.15,166.24) 150.15,166.3 149.52,166.93 143.65,166.93 137.97,172.61 130.21,172.61 124.99,177.84 101.73,177.84
  BOTTOM w0.165: v2(150.15,167.21) v1(150.15,166.24)
M_B_A13: length 72.7
  TOP w0.089: v1(96.13,168.92) 95.72,169.32 95.29,169.32 94.96,169 94.2,169 94.08,169.03 93.91,169.03 93.58,168.95 CPU1.BA43
  TOP w0.165: v1(153.16,151) 153.18,151.03 DIMM2.158
  L4 w0.089: v1(96.13,168.92) 97.85,167.2 100.68,167.2 103.41,164.47 103.46,164.47 103.92,164.01
  L4 w0.216: v1(153.16,151) 153.16,150.95 151.93,149.72 147.5,149.72 146.42,148.64 138.83,148.64 138.54,148.35 135.71,148.35 135.03,147.67 132.42,147.67 131.74,148.35 125.52,148.35 110.57,163.3 104.9,163.3 104.89,163.31 104.62,163.31 103.92,164.01
  BOTTOM w0.165: v1(96.13,168.92) v2(96.13,168.12)
M_B_A14: length 76.7
  TOP w0.089: v1(99.59,168.93) 99.2,169.32 96.02,169.32 95.84,169.5 95.21,169.5 94.89,169.17 94.23,169.17 94.1,169.21 93.89,169.21 93.85,169.2 93.47,169.11 93.24,169.11 CPU1.AY44
  TOP w0.165: DIMM2.151 147.73,152.78 v1(147.86,152.91)
  L4 w0.089: v1(99.59,168.93) 99.99,168.53 100.13,168.53 100.13,168.53 100.47,168.53 101.25,168.53 103.28,166.5 103.92,166.5 104.05,166.37
  L4 w0.216: v1(147.86,152.91) 146.53,152.91 145.61,151.99 128.97,151.99 121.13,159.82 120.82,159.82 120.42,159.42 120.14,159.42 119.81,159.75 119.81,160.03 120.21,160.43 120.21,160.74 119.91,161.05 119.6,161.05 118.84,160.28 118.53,160.28 118.23,160.59 118.23,160.89 118.99,161.66 118.99,161.96 118.69,162.27 118.38,162.27 117.62,161.5 117.31,161.5 117.01,161.81 117.01,162.11 117.77,162.88 117.77,163.18 117.46,163.49 117.16,163.49 116.39,162.72 116.09,162.72 115.78,163.03 115.78,163.34 116.55,164.1 116.55,164.41 116.24,164.71 115.94,164.71 115.17,163.95 114.87,163.95 114.56,164.25 114.56,164.56 115.33,165.32 115.33,165.63 114.86,166.09 104.33,166.09 104.05,166.37
  BOTTOM w0.165: v1(99.59,168.93) 99.59,168.57 99.93,168.22 v2(99.93,168.2)
M_B_A15: length 77.2
  TOP w0.089: v1(96.79,168.91) 96.4,168.52 95.32,168.52 95.29,168.55 94.17,168.55 94.09,168.51 93.91,168.51 93.78,168.55 93.56,168.55 93.42,168.51 93.14,168.51 CPU1.AY43
  TOP w0.165: v1(151.89,151) 152.06,151.17 152.06,151.2 152.39,151.53 DIMM2.156
  L4 w0.089: 103.61,164.75 103.61,164.78 101,167.39 98.31,167.39 v1(96.79,168.91)
  L4 w0.216: v1(151.89,151) 151.1,150.22 147.29,150.22 146.21,149.14 138.62,149.14 138.33,148.84 127.89,148.84 127.68,149.06 127.68,149.99 127.46,150.2 127.03,150.2 126.81,149.99 126.81,149.06 126.6,148.84 125.89,148.84 124.8,149.93 124.8,150.24 125.12,150.55 125.12,150.86 124.81,151.16 124.51,151.16 124.19,150.85 123.89,150.85 123.58,151.15 123.58,151.46 123.9,151.77 123.9,152.08 123.59,152.38 123.29,152.38 122.97,152.07 122.67,152.07 110.73,164.01 104.35,164.01 103.61,164.75
  BOTTOM w0.165: v1(151.89,151) 151.89,151.6 v2(152.1,151.81)
M_B_A16: length 75
  TOP w0.089: v1(96.68,170.56) 96.19,170.07 94.82,170.07 94.75,170 93.73,170 93.35,169.62 92.9,169.62 92.61,169.34 CPU1.AW44
  TOP w0.165: DIMM2.152 152.67,152.53 151.16,154.03 v1(151.16,154.05)
  L4 w0.089: 103.51,166.88 103.23,166.88 100.76,169.34 97.9,169.34 v1(96.68,170.56)
  L4 w0.216: v1(151.16,154.05) 150.55,153.44 146.36,153.44 145.49,152.56 138.17,152.56 137.57,153.16 134.06,153.16 133.71,153.52 133.2,153.52 132.84,153.16 132.33,153.16 131.98,153.52 131.25,153.52 130.26,152.53 129.13,152.53 127.78,153.87 127.78,154.47 127.47,154.78 126.87,154.78 126.56,155.1 126.56,155.69 126.25,156.01 125.65,156.01 125.34,156.32 125.34,156.92 125.02,157.23 124.43,157.23 124.11,157.54 124.11,158.14 123.8,158.45 123.2,158.45 115.05,166.6 104.25,166.6 103.97,166.88 103.51,166.88
  BOTTOM w0.165: v1(96.68,170.56) 96.68,171.25 v2(96.45,171.48)
M_B_ACT_N: length 76.3
  TOP w0.165: v1(88.93,174.27) 88.6,174.61 CPU1.AN53 ; DIMM2.114 153.31,164.03 153.21,164.12 152.9,164.12 152.5,164.53 v1(151.54,166.27)
  L4 w0.089: 95.18,176.2 94.94,175.95 89.5,175.95 89.04,175.5 89.04,174.38 v1(88.93,174.27)
  L4 w0.165: 95.18,176.2 95.18,176.25
  L4 w0.216: v1(151.54,166.27) 150.39,167.42 143.89,167.42 138.84,172.47 138.84,173.13 138.38,173.59 130.16,173.59 125.42,178.34 104.48,178.34 104.47,178.33 102.04,178.33 101.96,178.25 97.18,178.25 95.18,176.25
  BOTTOM w0.165: v1(151.54,166.27) 151.54,166.7 v2(151.92,167.07)
M_B_BG0: length 75.9
  TOP w0.165: v1(88.91,173.4) 89.25,173.74 CPU1.AP52 ; DIMM2.115 147.3,163.78 148.88,165.35 v1(148.88,166.24)
  L4 w0.089: 91.16,174.78 90.13,174.78 89.65,174.29 89.65,174.14 v1(88.91,173.4)
  L4 w0.216: 91.16,174.78 91.9,174.78 92.45,175.32 93.3,175.32 93.52,175.11 93.52,174.75 93.72,174.55 94.18,174.55 94.38,174.75 94.38,175.11 94.6,175.32 95.35,175.32 96.93,176.91 101.58,176.91 102.01,177.34 124.78,177.34 130.05,172.07 131.12,172.07 131.34,171.86 131.34,171.39 131.55,171.17 131.98,171.17 132.2,171.39 132.2,171.86 132.42,172.07 132.85,172.07 133.06,171.86 133.06,171.39 133.28,171.17 133.71,171.17 133.93,171.39 133.93,171.86 134.14,172.07 134.49,172.07 135.67,170.89 138.93,170.89 143.38,166.43 148.69,166.43 v1(148.88,166.24)
  BOTTOM w0.165: v2(147.65,165.85) 148.04,166.24 v1(148.88,166.24)
M_B_BG1: length 75.7
  TOP w0.165: CPU1.AN52 88.6,173.97 v1(88.25,174.32) ; DIMM2.113 147.38,164.28 148.41,165.3 148.41,166.61 149.18,167.39 v1(149.18,168.02)
  L4 w0.089: v1(88.25,174.32) 88.73,174.8 88.73,175.69 89.17,176.13 94.38,176.13 94.58,176.32 94.59,176.32 96.94,178.68 96.94,178.79 97.57,179.42 98.03,179.42
  L4 w0.216: v1(149.18,168.02) 149.17,168.03 144.04,168.03 139.33,172.74 139.33,173.33 138.58,174.09 130.37,174.09 125.62,178.83 102.87,178.83 102.27,179.43 98.03,179.43 98.03,179.42
  BOTTOM w0.165: v2(148.53,167.49) 149.05,168.02 v1(149.18,168.02)
M_B_BS0: length 75.5
  TOP w0.127: CPU1.BB44 94.93,169.51 95.09,169.67 95.11,169.67 95.13,169.7 95.92,169.7 96.06,169.56 98.71,169.56 99.22,170.07 v1(99.22,170.56)
  TOP w0.165: v1(152.43,154.05) 152.6,153.88 152.6,153.86 153.44,153.03 DIMM2.150
  L4 w0.089: v1(99.22,170.56) 99.91,169.88 101.3,169.88 103.08,168.1 103.69,168.1
  L4 w0.216: 103.69,168.1 116.77,168.1 128.2,156.67 128.71,156.67 129.23,157.18 129.66,157.18 131.63,155.22 139.57,155.22 140.08,154.71 145.36,154.71 146.24,155.6 153.66,155.6 154.03,155.22 154.03,153.77 153.82,153.56 152.64,153.56 152.43,153.77 v1(152.43,154.05)
  BOTTOM w0.165: v2(153.07,153.03) 152.94,153.03 152.43,153.54 v1(152.43,154.05)
M_B_BS1: length 75.5
  TOP w0.089: v1(98.59,170.56) 98.54,170.52 98.54,170.14 98.16,169.75 96.14,169.75 96,169.89 94.91,169.89 94.72,169.71 93.83,169.71 93.66,169.54 CPU1.BA44
  TOP w0.165: DIMM2.145 148.21,154.28 v1(149,155.07)
  L4 w0.089: v1(98.59,170.56) 99.45,169.7 101.14,169.7 103.09,167.75 103.41,167.75
  L4 w0.216: 103.41,167.75 104.22,167.75 104.38,167.59 115.5,167.59 115.92,167.18 116.22,167.18 116.45,167.4 116.75,167.4 117.06,167.1 117.06,166.79 116.83,166.56 116.83,166.26 117.14,165.95 117.44,165.95 117.67,166.18 117.98,166.18 118.28,165.88 118.28,165.57 118.05,165.34 118.05,165.04 118.36,164.73 118.66,164.73 118.89,164.96 119.2,164.96 119.5,164.65 119.5,164.35 119.27,164.12 119.27,163.82 119.58,163.51 119.89,163.51 120.11,163.74 120.42,163.74 120.72,163.43 120.72,163.13 120.5,162.9 120.5,162.59 120.8,162.29 121.11,162.29 121.34,162.52 121.64,162.52 121.95,162.21 121.95,161.91 121.72,161.68 121.72,161.37 122.02,161.07 122.33,161.07 122.56,161.29 122.86,161.29 123.17,160.99 123.17,160.68 122.94,160.46 122.94,160.15 123.25,159.84 123.55,159.84 123.78,160.07 124.08,160.07 124.39,159.77 124.39,159.46 127.74,156.11 128.86,156.11 129.31,156.57 129.58,156.57 129.96,156.19 129.96,155.91 129.38,155.33 129.38,154.97 129.62,154.73 139.36,154.73 139.87,154.22 145.56,154.22 146.41,155.07 v1(149,155.07)
  BOTTOM w0.165: v1(149,155.07) 148.62,155.07 v2(148.23,155.46)
M_B_CKE0: length 77.1
  TOP w0.165: DIMM2.109 147.78,165.28 147.97,165.46 147.97,166.69 148.58,167.31 v1(148.58,168.52) ; v1(88.27,176.15) 88.27,176.17 88.6,176.5 CPU1.AN56
  L4 w0.089: 94.37,176.63 94.05,176.31 89.07,176.31 88.91,176.15 v1(88.27,176.15)
  L4 w0.216: v1(148.58,168.52) 148.58,169.1 148.14,169.54 147.26,169.54 146.91,169.2 146.91,168.77 146.7,168.55 146.27,168.55 146.05,168.77 146.05,169.81 145.67,170.19 143.18,170.19 138.79,174.58 132.34,174.58 132.12,174.8 132.12,175.12 131.9,175.34 131.47,175.34 131.26,175.12 131.26,174.8 131.04,174.58 130.75,174.58 125.48,179.84 107.99,179.84 107.58,179.43 107.13,179.43 106.71,179.84 106.27,179.84 105.85,179.43 105.4,179.43 104.99,179.84 104.54,179.84 104.12,179.43 103.68,179.43 103.26,179.84 97.58,179.84 94.37,176.63
  BOTTOM w0.165: v2(148.22,169.31) 148.58,168.95 v1(148.58,168.52)
M_B_CKE1: length 77.9
  TOP w0.165: CPU1.AP55 88.62,175.26 v1(88.3,175.26) ; v1(150.78,168.59) 153.45,165.23 153.65,165.03 DIMM2.110
  L4 w0.089: 97.83,180.34 97.66,180.34 93.8,176.49 88.69,176.49 88.63,176.55 88.11,176.55 87.87,176.31 87.87,175.98 v1(88.3,175.26)
  L4 w0.216: v1(150.78,168.59) 148.03,170.2 145.58,170.81 143.29,170.81 138.23,175.88 130.15,175.88 125.69,180.34 97.83,180.34
  BOTTOM w0.165: v2(150.69,169.61) 150.78,169.52 v1(150.78,168.59)
M_B_CLK0: length 80
  TOP w0.102: CPU1.AP45 88.97,170.21 88.9,170.14 v1(88.9,169.74) ; DIMM2.137 147.46,158.28 147.74,157.99 149.01,157.99 149.17,158.15 149.17,158.36 148.95,158.57 148.95,158.9 148.88,158.98 148.72,158.98 v1(148.5,158.75)
  L4 w0.089: v1(88.9,169.74) 88.9,169.93 89.02,170.06 89.21,170.06 89.22,170.07 89.22,170.07 89.63,170.47 89.63,170.65 90.01,171.03 94.57,171.03 95.23,171.69 95.73,171.69 95.84,171.58 96.16,171.58 96.2,171.54 96.22,171.54
  L4 w0.127: 96.22,171.54 103.63,171.54 104.36,170.81 118.09,170.81 124.45,164.45 125.11,164.45 125.64,164.99 126.05,164.99 128.38,162.66 129.73,162.66 131.36,161.02 131.36,159.21 131.65,158.93 132.12,158.93 132.41,159.21 132.41,159.75 132.53,159.88 132.79,159.88 132.91,159.75 132.91,159.21 133.2,158.93 133.67,158.93 133.95,159.21 133.95,159.75 134.08,159.88 134.34,159.88 134.46,159.75 134.46,159.21 134.75,158.93 135.22,158.93 135.5,159.21 135.5,159.75 135.63,159.88 139.15,159.88 139.42,159.61 139.42,159.19 140,158.61 140.67,158.61 141.32,157.96 142.47,157.96 143.89,159.38 148.76,159.38 148.95,159.19 148.95,158.88 148.83,158.75 v1(148.5,158.75)
  BOTTOM w0.102: v1(148.5,158.75) 148.5,159.61 v2(148.47,159.64)
M_B_CLK1: length 79.1
  TOP w0.102: v1(152.43,159.38) 152.14,159.09 152.14,158.2 152.32,158.03 DIMM2.138 ; CPU1.AP46 89.31,171.05 89.31,170.76 89.2,170.65 v1(88.97,170.65)
  L4 w0.089: 96.09,172.11 96.07,172.11 96.03,172.15 94.97,172.15 94.27,171.45 88.9,171.45 88.74,171.29 88.74,170.88 v1(88.97,170.65)
  L4 w0.127: v1(152.43,159.38) 152.18,159.13 152.18,158.86 151.93,158.61 150.8,158.61 150.4,159.01 150.4,160 150.12,160.29 142.84,160.29 142.68,160.12 142.68,159.48 142.4,159.19 141.65,159.19 141.37,159.48 141.37,159.96 141.16,160.17 140.13,160.17 139.09,161.21 132.45,161.21 130.1,163.56 128.75,163.56 125.81,166.5 125.64,166.5 125.23,166.1 125.23,166.1 124.86,165.72 124.46,165.72 118.47,171.71 104.55,171.71 104.15,172.11 96.09,172.11
  BOTTOM w0.102: v1(152.43,159.38) v2(152.43,158.6)
M_B_CLK#0: length 80.4
  TOP w0.102: CPU1.AN45 v1(88.23,169.76) ; v1(149.39,158.75) 149.39,158.06 149.1,157.78 DIMM2.139
  L4 w0.089: 96.22,171.81 96.2,171.81 96.16,171.77 95.92,171.77 95.81,171.88 95.15,171.88 94.5,171.22 89.93,171.22 89.44,170.73 89.44,170.55 89.14,170.26 89.14,170.26 89.13,170.25 88.88,170.25 v1(88.23,169.76)
  L4 w0.127: v1(149.39,158.75) 149.22,158.92 149.22,159.3 148.87,159.65 143.78,159.65 142.36,158.23 141.43,158.23 140.78,158.88 140.11,158.88 139.68,159.3 139.68,159.72 139.26,160.15 135.52,160.15 135.24,159.86 135.24,159.32 135.11,159.19 134.86,159.19 134.73,159.32 134.73,159.86 134.45,160.15 133.97,160.15 133.69,159.86 133.69,159.32 133.56,159.19 133.31,159.19 133.18,159.32 133.18,159.86 132.9,160.15 132.42,160.15 132.14,159.86 132.14,159.32 132.01,159.19 131.76,159.19 131.63,159.32 131.63,161.13 131.13,161.63 129.84,162.93 128.49,162.93 126.16,165.25 125.53,165.25 125,164.72 124.57,164.72 118.2,171.08 104.47,171.08 103.74,171.81 96.22,171.81
  BOTTOM w0.102: v1(149.39,158.75) 149.39,159.26 v2(149.97,159.84)
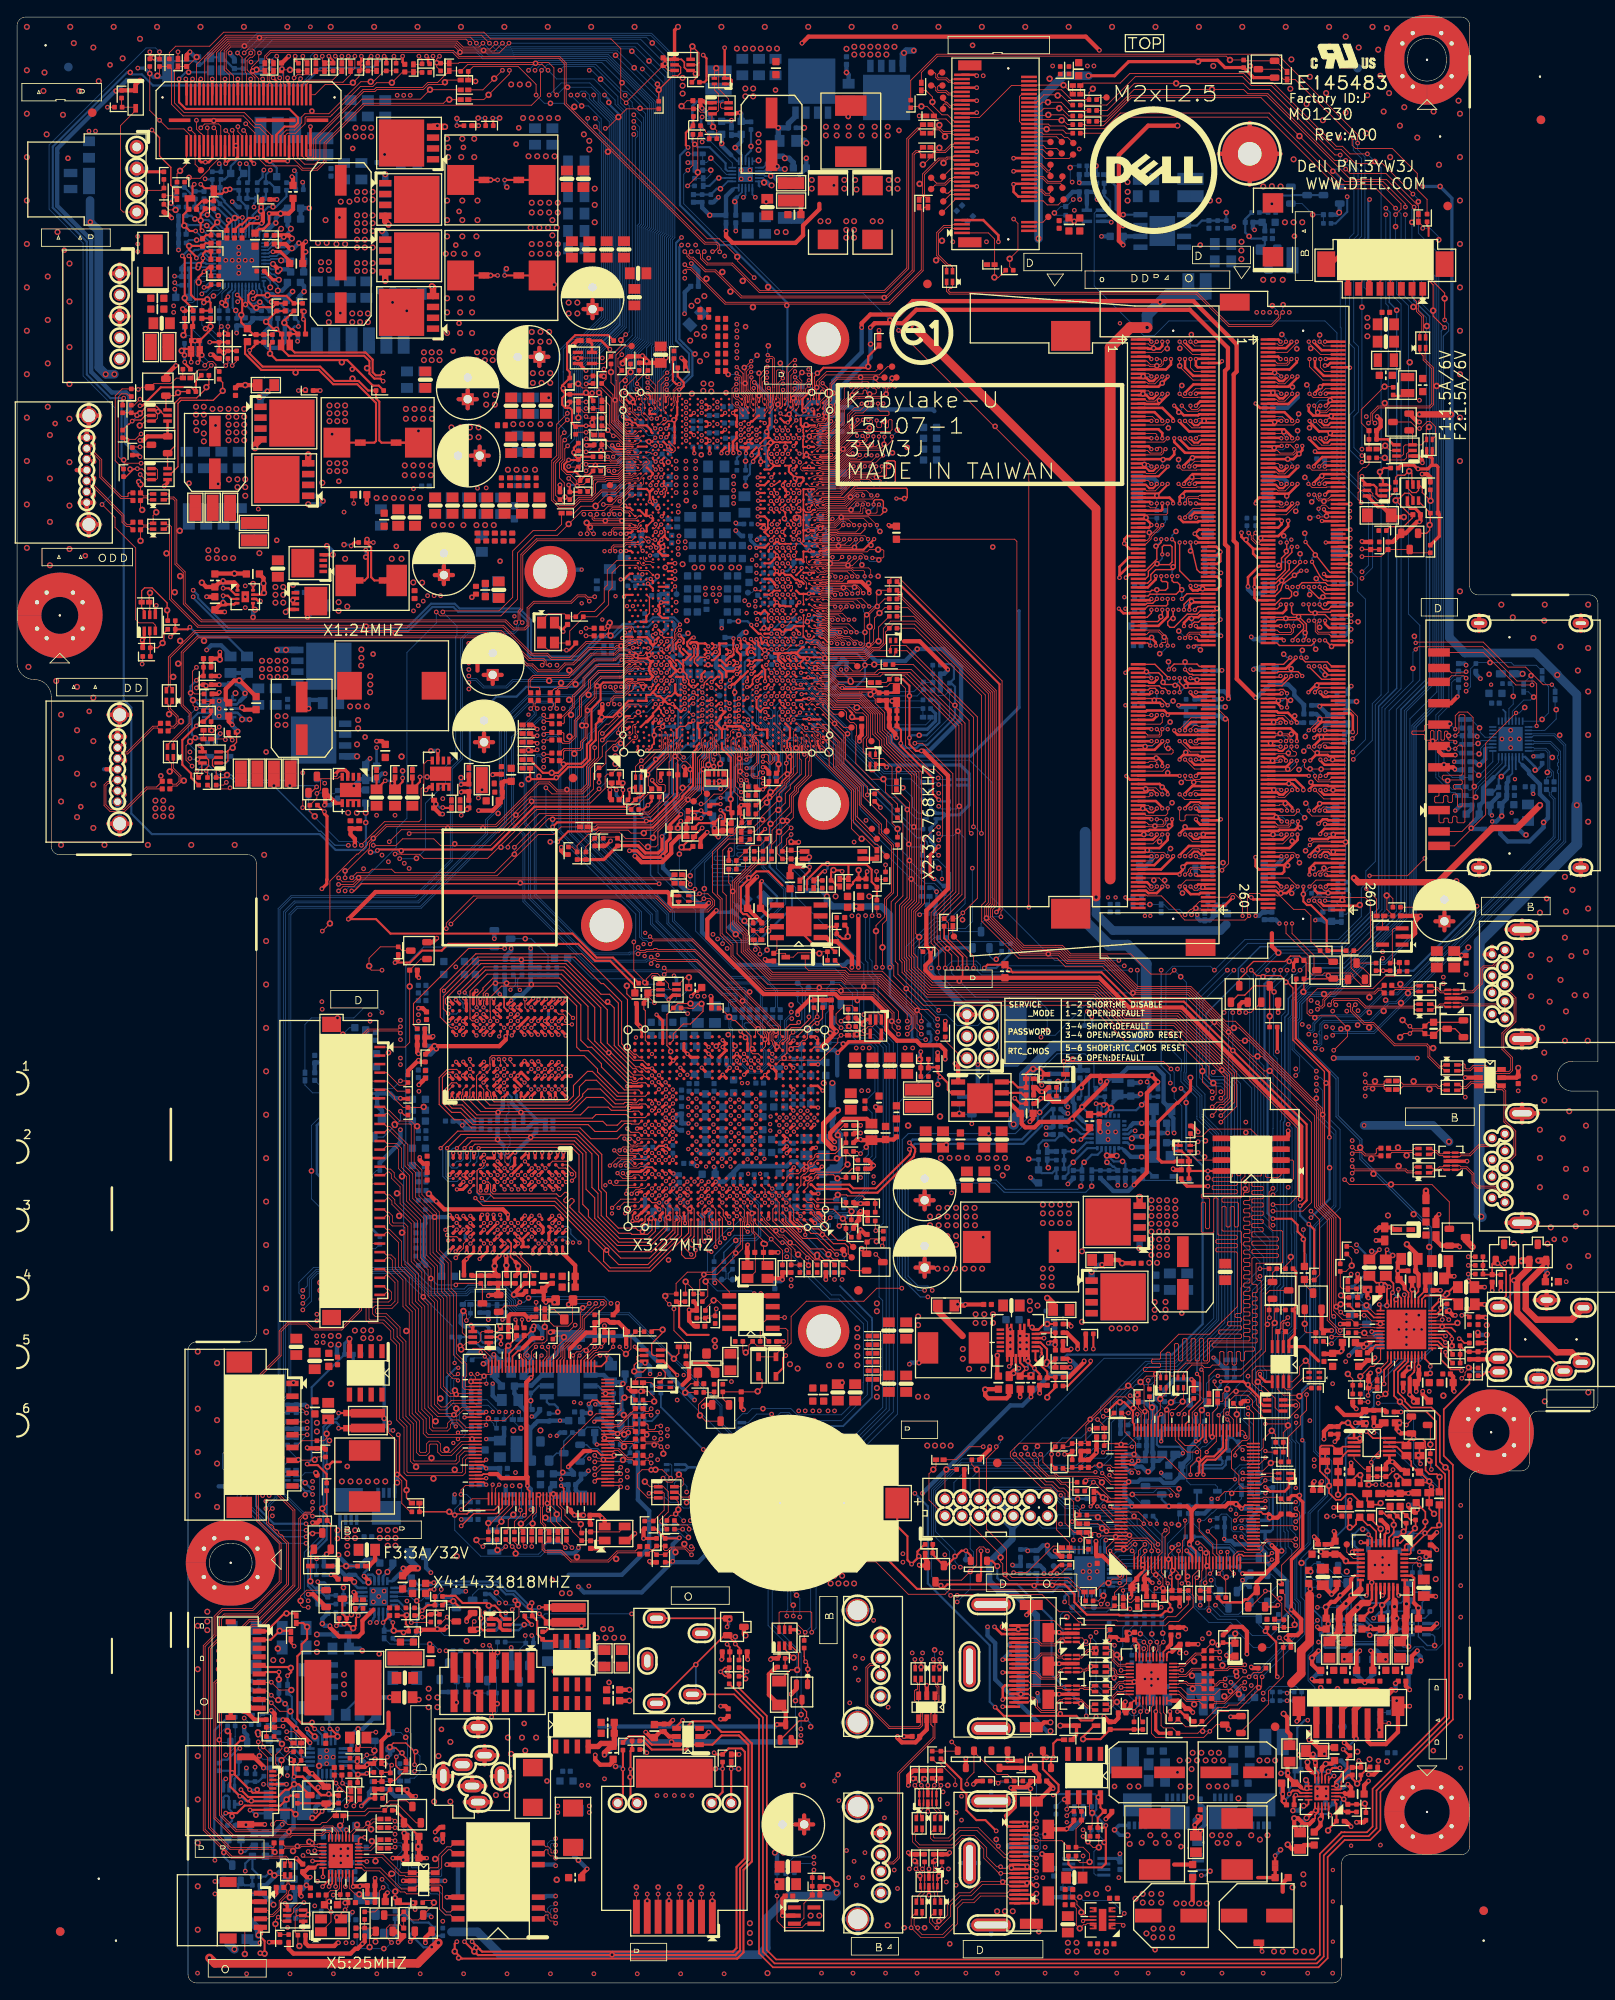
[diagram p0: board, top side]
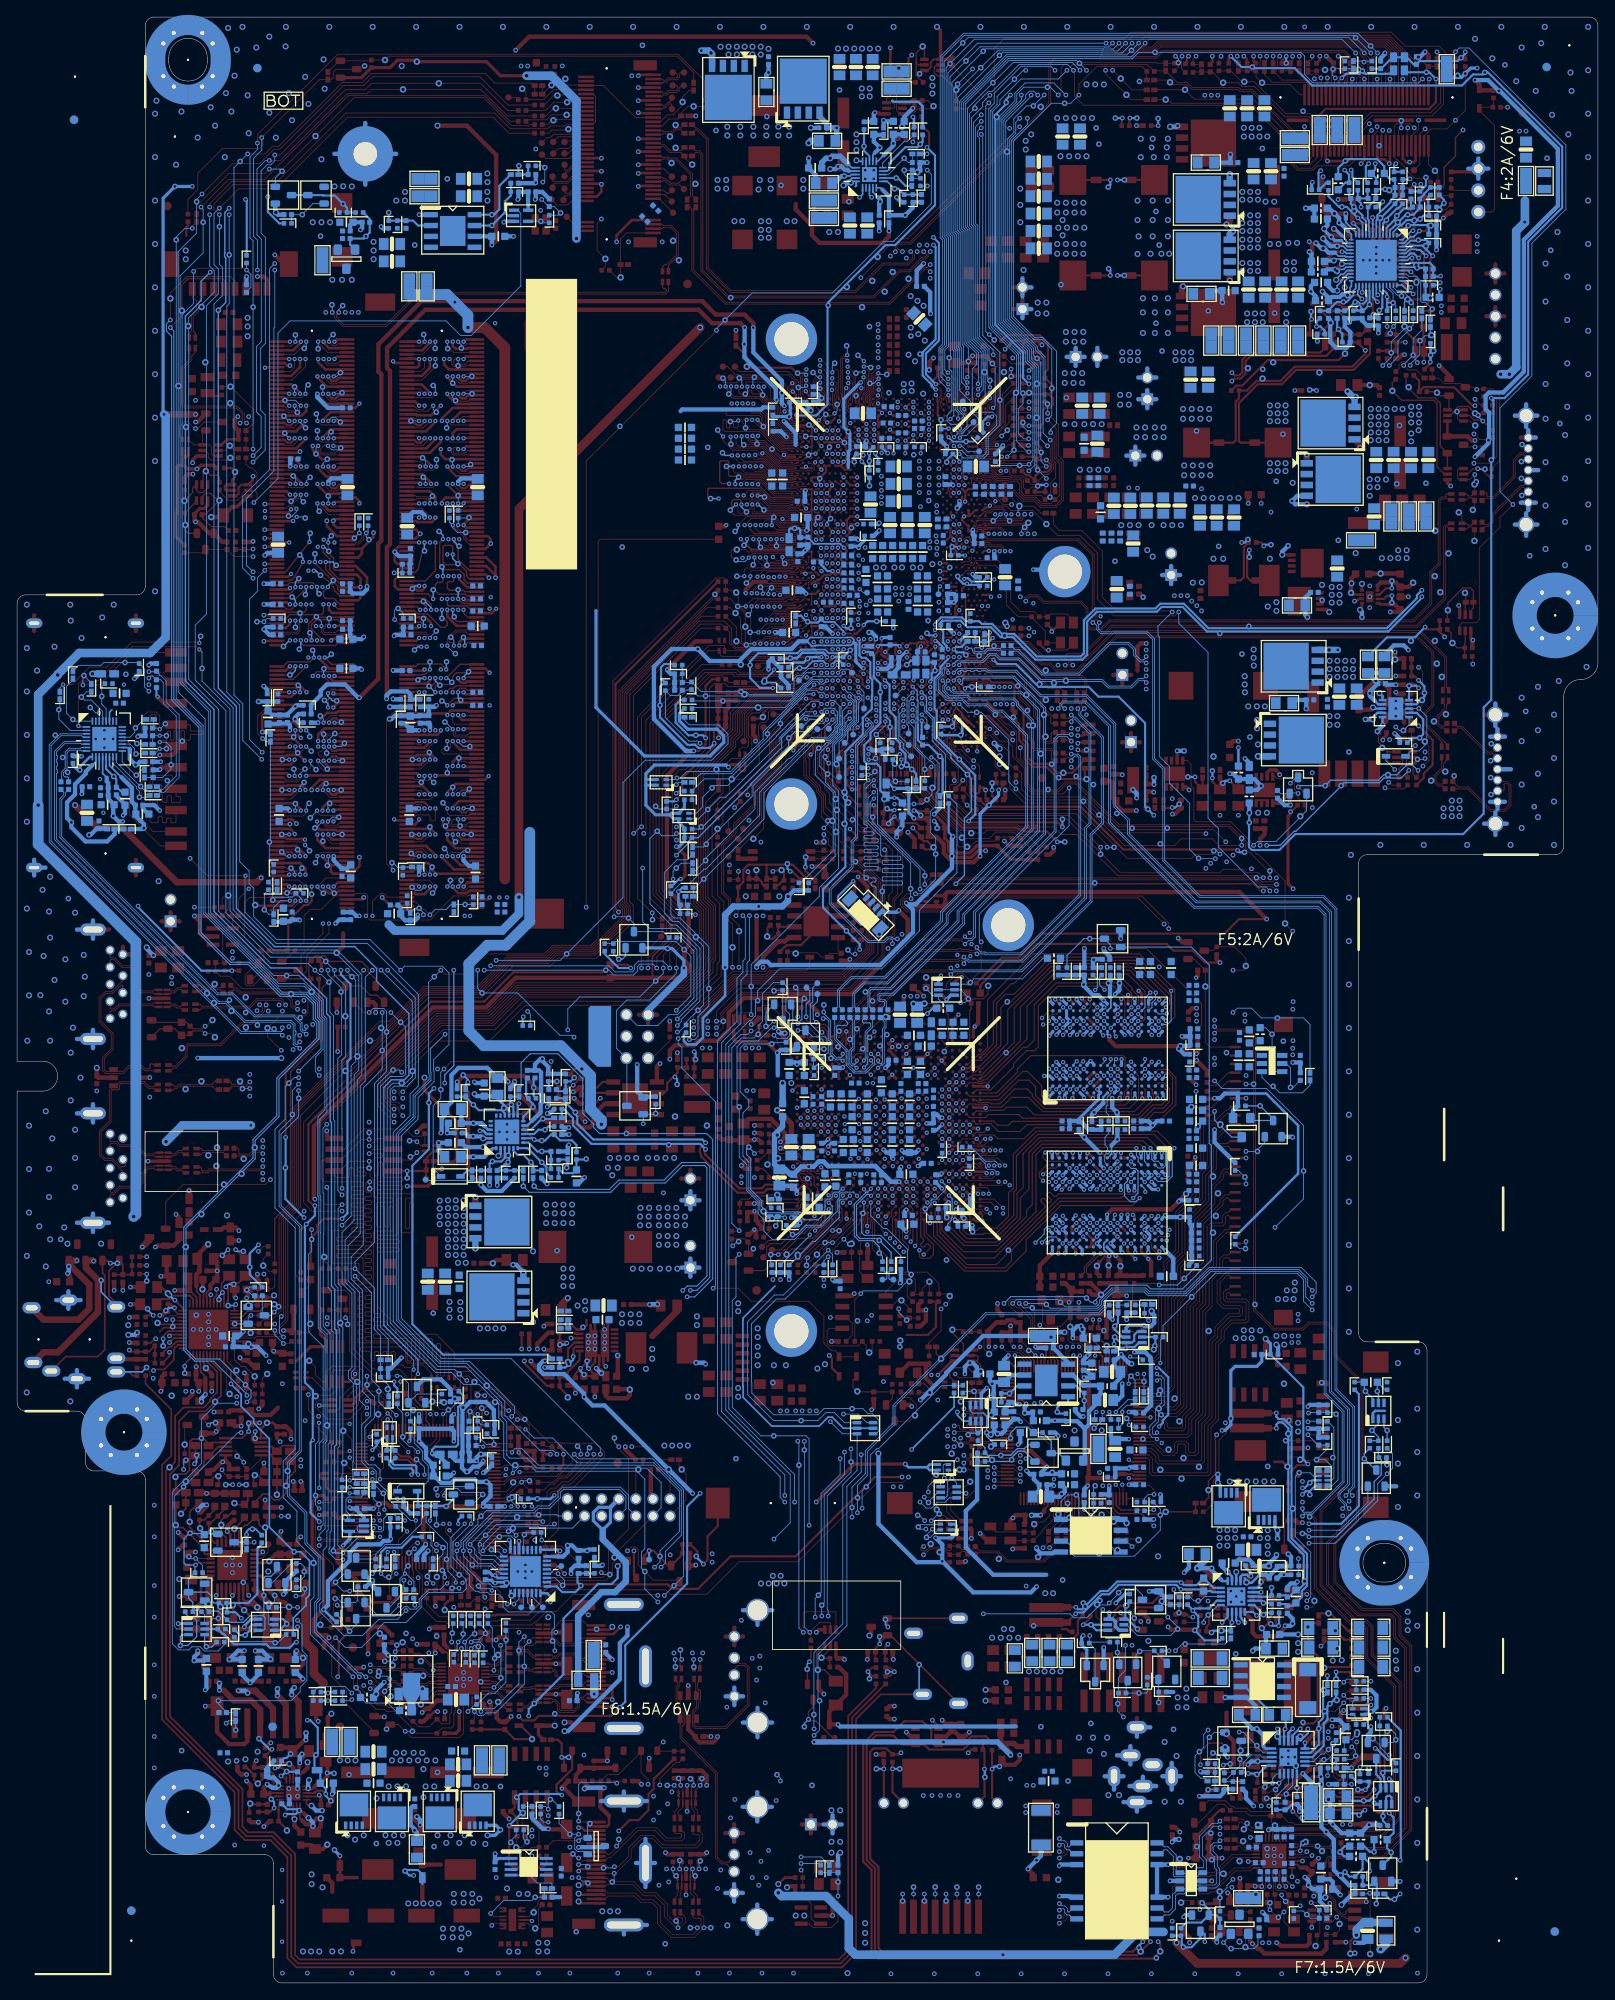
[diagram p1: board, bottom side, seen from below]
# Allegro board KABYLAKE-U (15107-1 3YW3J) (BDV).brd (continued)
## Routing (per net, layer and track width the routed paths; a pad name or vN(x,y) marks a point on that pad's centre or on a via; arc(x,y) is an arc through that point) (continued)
M_B_CLK#1: length 79.2
  TOP w0.102: v1(88.32,170.64) 88.32,170.85 CPU1.AN46 ; v1(151.8,159.38) 151.93,159.26 151.93,158.12 152.23,157.81 153.54,157.81 153.82,157.53 DIMM2.140
  L4 w0.089: v1(88.32,170.64) 88.54,170.86 88.54,171.37 88.82,171.64 94.19,171.64 94.89,172.34 96.03,172.34 96.07,172.38 96.09,172.38
  L4 w0.127: v1(151.8,159.38) 151.91,159.27 151.91,158.97 151.82,158.88 150.91,158.88 150.67,159.12 150.67,160.11 150.23,160.55 142.73,160.55 142.41,160.23 142.41,159.59 142.28,159.46 141.77,159.46 141.64,159.59 141.64,160.07 141.27,160.44 140.24,160.44 139.2,161.48 132.56,161.48 130.21,163.83 128.86,163.83 125.92,166.77 125.53,166.77 125.12,166.36 125.12,166.36 124.75,165.99 124.57,165.99 118.58,171.98 104.66,171.98 104.26,172.38 96.09,172.38
  BOTTOM w0.102: v1(151.8,159.38) 151.8,160.17 v2(151.9,160.27)
M_B_CS#0: length 78.2
  TOP w0.089: v1(98.16,168.89) 97.42,168.15 94.46,168.15 CPU1.BB42
  TOP w0.165: v1(150.4,152.91) 150.4,152.93 149.92,153.41 147.6,153.41 147.47,153.28 DIMM2.149
  L4 w0.089: 103.94,165.25 103.89,165.25 101.25,167.89 99.15,167.89 v1(98.16,168.89)
  L4 w0.216: 103.94,165.25 104.2,165.25 104.4,165.05 112.33,165.05 125.05,152.32 127.23,152.32 129.04,150.51 138.36,150.51 138.84,151 146.14,151 147,151.86 153.98,151.86 154.19,152.06 154.19,152.7 153.98,152.91 v1(150.4,152.91)
  BOTTOM w0.165: v2(98,167.97) 98.16,168.13 v1(98.16,168.89)
M_B_CS#1: length 80.1
  TOP w0.089: CPU1.AY42 93.29,168.3 93.59,168.37 93.74,168.37 93.87,168.33 94.13,168.33 94.21,168.37 94.91,168.37 94.96,168.33 96.86,168.33 96.88,168.34 96.88,168.34 v1(97.45,168.91)
  TOP w0.165: DIMM2.157 147.73,151.28 147.8,151.34 148.18,151.34 148.45,151.07 148.45,151.05 v1(148.62,150.88)
  L4 w0.089: 104.07,164.74 103.71,165.1 103.67,165.1 101.13,167.64 98.72,167.64 v1(97.45,168.91)
  L4 w0.216: v1(148.62,150.88) 148.62,150.93 148.19,151.36 147.21,151.36 145.47,149.63 138.95,149.63 138.56,150.02 128.83,150.02 127.02,151.83 124.85,151.83 123.21,153.46 122.91,153.46 122.59,153.15 122.29,153.15 121.98,153.45 121.98,153.76 122.3,154.07 122.3,154.38 121.99,154.68 121.69,154.68 121.37,154.37 121.07,154.37 120.76,154.67 120.76,154.98 121.08,155.29 121.08,155.6 120.77,155.91 120.46,155.91 120.15,155.59 119.84,155.59 119.54,155.9 119.54,156.2 119.85,156.52 119.85,156.82 119.55,157.13 119.24,157.13 118.93,156.81 118.62,156.81 118.32,157.12 118.32,157.42 118.63,157.74 118.63,158.04 118.33,158.35 118.02,158.35 117.71,158.03 117.4,158.03 117.1,158.34 117.1,158.65 117.41,158.96 117.41,159.27 117.1,159.57 116.8,159.57 116.48,159.26 116.18,159.26 115.87,159.56 115.87,159.87 116.19,160.18 116.19,160.49 115.88,160.79 115.58,160.79 115.26,160.48 114.96,160.48 114.65,160.78 114.65,161.09 114.97,161.4 114.97,161.71 114.66,162.01 114.36,162.01 114.04,161.7 113.74,161.7 113.43,162.01 113.43,162.31 113.74,162.63 113.74,162.93 113.44,163.24 113.13,163.24 112.82,162.92 112.51,162.92 112.21,163.23 112.21,163.53 112.52,163.85 112.52,164.15 112.17,164.5 104.31,164.5 104.07,164.74
  BOTTOM w0.165: v2(147.61,150.01) 148.09,150.01 148.62,150.55 v1(148.62,150.88)
M_B_DQ0: length 92.9
  TOP w0.102: v1(84.69,181.09) 84.85,181.09 85.15,181.38 CPU1.AF65 ; DIMM2.28 153.36,185.53 153.33,185.5 151.68,185.5 v1(151.25,185.93)
  L4 w0.127: v1(84.69,181.09) 84.06,181.72 84.06,182.65 87.57,186.17 88.14,186.17 88.39,186.41 88.39,186.76 88.29,186.86 88.29,193.92 88.29,194.37 91.94,198.02 100.77,198.02 101.98,196.81 110.41,196.81 111.14,196.09 122.41,196.09 122.54,195.96 122.54,195.67 122.66,195.54 122.92,195.54 123.04,195.67 123.04,195.96 123.17,196.09 123.42,196.09 123.55,195.96 123.55,195.67 123.68,195.54 123.93,195.54 124.06,195.67 124.06,195.96 124.19,196.09 124.44,196.09 124.57,195.96 124.57,195.67 124.69,195.54 124.95,195.54 125.08,195.67 125.08,195.96 125.2,196.09 128.79,196.09 129.99,194.88 137.51,194.88 145.41,186.98 150.2,186.98 v1(151.25,185.93)
  BOTTOM w0.102: v2(150.93,186.97) 151.25,186.65 v1(151.25,185.93)
M_B_DQ1: length 91.2
  TOP w0.102: v1(152.52,185.93) 153.12,186.53 DIMM2.24 ; v1(84.69,180.44) 85.02,180.76 CPU1.AF64
  L4 w0.127: v1(84.69,180.44) 83.84,181.29 83.84,183.06 87.31,186.53 87.31,188.59 87.39,188.67 87.39,191.24 87.79,191.64 87.79,194.36 91.8,198.36 100.92,198.36 102.12,197.15 110.55,197.15 111.28,196.43 128.93,196.43 130.13,195.22 137.65,195.22 145.55,187.32 151.12,187.32 v1(152.52,185.93)
  BOTTOM w0.102: v1(152.52,185.93) v2(152.52,186.74)
M_B_DQ2: length 92.2
  TOP w0.102: DIMM2.42 153.74,182.03 153.65,181.94 152.7,181.94 v1(151.89,182.75) ; v1(86.52,181.09) 86.84,181.41 CPU1.AK65
  L4 w0.127: v1(151.89,182.75) 151.3,183.34 149.94,183.34 149.39,183.9 144.2,183.9 139.01,189.09 131.9,189.09 127.86,193.13 116.85,193.13 116.02,192.3 115.77,192.3 115.64,192.43 115.64,193 115.51,193.13 115.26,193.13 115.13,193 115.13,192.43 115.01,192.3 114.75,192.3 114.62,192.43 114.62,193 114.5,193.13 114.24,193.13 114.12,193 114.12,192.43 113.99,192.3 113.74,192.3 113.61,192.43 113.61,193 113.48,193.13 113.23,193.13 113.1,193 113.1,192.43 112.97,192.3 112.72,192.3 112.59,192.43 112.59,193 112.47,193.13 106.72,193.13 105.44,194.41 97.95,194.41 96.81,195.55 93.17,195.55 90.92,193.31 90.92,190.69 91.49,190.13 91.49,186.44 90.24,185.19 89.29,185.19 86.86,182.76 86.86,182.11 86.94,182.03 86.94,181.51 v1(86.52,181.09)
  BOTTOM w0.102: v1(151.89,182.75) 151.89,182.59 v2(151.25,181.95)
M_B_DQ3: length 92.8
  TOP w0.102: DIMM2.41 149.38,182.28 v1(149.85,182.75) ; CPU1.AK64 86.84,180.76 v1(86.52,180.44)
  L4 w0.127: v1(149.85,182.75) 149.05,183.55 144.06,183.55 138.86,188.75 131.76,188.75 127.77,192.74 117.3,192.74 116.5,191.94 112.35,191.94 112.22,192.06 112.22,192.33 112.09,192.46 111.84,192.46 111.71,192.33 111.71,192.06 111.58,191.94 111.33,191.94 111.2,192.06 111.2,192.61 111.08,192.74 110.82,192.74 110.7,192.61 110.7,192.06 110.57,191.94 110.31,191.94 110.19,192.06 110.19,192.61 110.06,192.74 109.81,192.74 109.68,192.61 109.68,192.06 109.55,191.94 109.3,191.94 109.17,192.06 109.17,192.61 109.04,192.74 108.79,192.74 108.66,192.61 108.66,192.06 108.54,191.94 108.28,191.94 108.16,192.06 108.16,192.61 108.03,192.74 107.77,192.74 107.65,192.61 107.65,192.06 107.52,191.94 107.27,191.94 107.14,192.06 107.14,192.61 107.01,192.74 98.2,192.74 97.72,193.22 97.72,193.99 96.5,195.21 93.32,195.21 91.38,193.26 91.38,190.68 91.83,190.23 91.83,186.48 90.01,184.66 89.06,184.66 87.07,182.67 87.07,182.32 87.15,182.24 87.15,181.07 v1(86.52,180.44)
  BOTTOM w0.102: v1(149.85,182.75) 149.85,183.45 v2(149.98,183.57)
M_B_DQ4: length 92.1
  TOP w0.102: CPU1.AF66 85.15,182.02 84.87,181.74 v1(84.69,181.74) ; DIMM2.29 147.38,185.28 147.59,185.06 148.35,185.06 v1(149.22,185.93)
  L4 w0.127: v1(149.22,185.93) 148.51,186.64 145.24,186.64 138.96,192.92 138.78,192.92 138.52,192.66 138.34,192.66 138.16,192.84 138.16,193.02 138.42,193.28 138.42,193.46 138.24,193.64 138.06,193.64 137.8,193.38 137.62,193.38 137.44,193.56 137.44,193.73 137.7,194 137.7,194.18 137.35,194.54 131.57,194.54 131.44,194.41 131.44,193.7 131.32,193.57 131.06,193.57 130.94,193.7 130.94,194.41 130.81,194.54 129.85,194.54 129.19,195.2 128.5,195.2 128.37,195.33 128.37,195.62 128.24,195.75 127.99,195.75 127.86,195.62 127.86,195.33 127.73,195.2 127.48,195.2 127.35,195.33 127.35,195.62 127.23,195.75 126.97,195.75 126.85,195.62 126.85,195.33 126.72,195.2 126.46,195.2 126.34,195.33 126.34,195.62 126.21,195.75 125.96,195.75 125.83,195.62 125.83,195.33 125.7,195.2 122.03,195.2 121.52,195.71 111.03,195.71 110.27,196.47 101.84,196.47 100.7,197.61 92.21,197.61 88.63,194.04 88.63,186.35 88.15,185.87 87.58,185.87 84.27,182.56 84.27,182.21 84.69,181.8 v1(84.69,181.74)
  BOTTOM w0.102: v1(149.22,185.93) 149.22,186.68 v2(149.26,186.72)
M_B_DQ5: length 92
  TOP w0.102: DIMM2.25 147.6,186.28 v1(147.95,185.93) ; CPU1.AF67 84.96,182.71 84.69,182.45 v1(84.69,182.39)
  L4 w0.127: v1(147.95,185.93) 147.58,186.3 145.08,186.3 144.5,186.87 144.32,186.87 144.05,186.6 143.87,186.6 143.69,186.78 143.69,186.96 143.96,187.23 143.96,187.41 143.78,187.59 143.6,187.59 143.33,187.32 143.15,187.32 142.97,187.5 142.97,187.68 143.24,187.95 143.24,188.13 140.86,190.52 140.68,190.52 140.41,190.25 140.23,190.25 140.05,190.43 140.05,190.61 140.32,190.88 140.32,191.06 140.08,191.3 132.6,191.3 129.04,194.86 121.55,194.86 121.42,194.98 121.42,195.24 121.29,195.36 121.04,195.36 120.91,195.24 120.91,194.98 120.78,194.86 120.53,194.86 120.4,194.98 120.4,195.24 120.28,195.36 120.02,195.36 119.89,195.24 119.89,194.98 119.77,194.86 119.51,194.86 119.39,194.98 119.39,195.24 119.26,195.36 119.01,195.36 118.88,195.24 118.88,194.98 118.75,194.86 118.5,194.86 118.37,194.98 118.37,195.24 118.24,195.36 117.99,195.36 117.86,195.24 117.86,194.98 117.74,194.86 117.48,194.86 117.35,194.98 117.35,195.24 117.23,195.36 116.97,195.36 116.85,195.24 116.85,194.98 116.72,194.86 116.47,194.86 116.34,194.98 116.34,195.24 116.21,195.36 115.96,195.36 115.83,195.24 115.83,194.98 115.7,194.86 115.45,194.86 115.32,194.98 115.32,195.24 115.2,195.36 114.94,195.36 114.81,195.24 114.81,194.98 114.69,194.86 114.43,194.86 114.31,194.98 114.31,195.24 114.18,195.36 113.93,195.36 113.8,195.24 113.8,194.98 113.67,194.86 113.42,194.86 113.29,194.98 113.29,195.24 113.16,195.36 112.91,195.36 112.78,195.24 112.78,194.98 112.66,194.86 112.4,194.86 112.27,194.98 112.27,195.24 112.15,195.36 111.89,195.36 111.77,195.24 111.77,194.98 111.64,194.86 111.29,194.86 110.02,196.13 101.7,196.13 100.55,197.27 92.35,197.27 89.06,193.98 89.06,193.86 89.06,186.47 88.23,185.64 87.94,185.64 v1(84.69,182.39)
  BOTTOM w0.102: v2(146.97,186.06) 147.1,185.93 v1(147.95,185.93)
M_B_DQ6: length 91.5
  TOP w0.102: v1(87.49,182.5) 87.28,182.71 CPU1.AK67 ; DIMM2.37 148.06,183.28 v1(148.58,182.75)
  L4 w0.127: v1(87.49,182.5) 87.49,182.69 89.2,184.39 90.05,184.39 92.17,186.52 92.17,188.93 92.69,189.45 95.5,189.45 96.6,190.55 97.31,190.55 97.43,190.68 97.43,192.27 97.56,192.39 97.82,192.39 97.94,192.27 97.94,190.68 98.07,190.55 98.32,190.55 98.45,190.68 98.45,192.27 98.58,192.39 98.83,192.39 98.96,192.27 98.96,190.68 99.09,190.55 99.34,190.55 99.47,190.68 99.47,192.27 99.59,192.39 99.85,192.39 99.97,192.27 99.97,190.68 100.1,190.55 100.46,190.55 101.51,191.59 101.85,191.59 101.98,191.72 101.98,192.27 102.1,192.39 102.36,192.39 102.48,192.27 102.48,191.72 102.61,191.59 102.86,191.59 102.99,191.72 102.99,192.27 103.12,192.39 103.37,192.39 103.5,192.27 103.5,191.72 103.63,191.59 103.88,191.59 104.01,191.72 104.01,192.27 104.13,192.39 104.39,192.39 104.52,192.27 104.52,191.72 104.64,191.59 104.9,191.59 105.02,191.72 105.02,192.27 105.15,192.39 105.4,192.39 105.53,192.27 105.53,191.72 105.66,191.59 105.91,191.59 106.04,191.72 106.04,192.01 106.17,192.14 106.42,192.14 106.55,192.01 106.55,191.72 106.67,191.59 116.67,191.59 117.23,192.15 127.82,192.15 131.57,188.4 134.84,188.4 134.84,188.4 138.66,188.4 143.85,183.21 148.13,183.21 v1(148.58,182.75)
  BOTTOM w0.102: v2(147.17,182.61) 147.75,183.18 148.15,183.18 v1(148.58,182.75)
M_B_DQ7: length 91.3
  TOP w0.102: CPU1.AK66 86.65,181.74 v1(86.52,181.74) ; v1(153.16,182.75) 153.43,183.03 DIMM2.38
  L4 w0.127: v1(86.52,181.74) 86.58,181.8 86.58,182.79 89.24,185.45 90.02,185.45 90.57,186 90.57,193.45 93.04,195.92 96.95,195.92 98.1,194.77 105.6,194.77 106.87,193.5 107.15,193.5 107.27,193.62 107.27,194.41 107.4,194.54 107.65,194.54 107.78,194.41 107.78,193.62 107.91,193.5 108.16,193.5 108.29,193.62 108.29,194.41 108.42,194.54 108.67,194.54 108.8,194.41 108.8,193.62 108.92,193.5 109.18,193.5 109.3,193.62 109.3,194.41 109.43,194.54 109.69,194.54 109.81,194.41 109.81,193.62 109.94,193.5 127.98,193.5 128.6,192.87 128.77,192.87 132.21,189.43 139.15,189.43 144.34,184.24 149.53,184.24 150.07,183.69 152.21,183.69 153.15,182.75 v1(153.16,182.75)
  BOTTOM w0.102: v2(153.78,183.31) 153.22,182.75 v1(153.16,182.75)
M_B_DQ8: length 91.3
  TOP w0.102: DIMM2.8 152.53,190.53 151.16,191.9 v1(151.16,192.02) ; v1(84.18,186.41) 83.85,186.08 83.85,185.58 84.14,185.29 84.33,185.29 84.84,184.78 CPU1.AF70
  L4 w0.127: v1(84.18,186.41) 83.46,187.13 83.46,187.57 83.42,187.61 83.42,194.67 90.75,202 108.59,202 109.35,201.24 116.16,201.24 116.94,200.47 129.51,200.47 131.39,198.59 138.95,198.59 145.96,191.58 150.72,191.58 v1(151.16,192.02)
  BOTTOM w0.102: v1(151.16,192.02) 151.16,191.47 v2(151.39,191.24)
M_B_DQ9: length 92.6
  TOP w0.089: CPU1.AF68 84.6,183.7 84.6,184.12 84.36,184.37 84.11,184.37 83.67,184.81 83.67,186.55 v1(84.18,187.06)
  TOP w0.102: DIMM2.4 152.93,191.53 152.93,191.52 v1(152.43,192.02)
  L4 w0.127: v1(152.43,192.02) 151.65,191.24 145.81,191.24 138.8,198.25 131.25,198.25 129.37,200.13 116.15,200.13 116.02,200.25 116.02,200.57 115.9,200.7 115.64,200.7 115.51,200.57 115.51,200.25 115.39,200.13 115.13,200.13 115.01,200.25 115.01,200.57 114.88,200.7 109.41,200.7 108.57,201.54 90.77,201.54 83.76,194.53 83.76,190.74 83.7,190.68 83.7,187.54 v1(84.18,187.06)
  BOTTOM w0.102: v1(152.43,192.02) v2(152.43,192.81)
M_B_DQ10: length 90.5
  TOP w0.089: CPU1.AH71 86.1,185.38 86.1,185.84 85.54,186.4 85.54,188.11 v1(85.91,188.48)
  TOP w0.102: DIMM2.21 147.4,187.28 147.58,187.1 148.35,187.1 v1(149.22,187.96)
  L4 w0.127: v1(149.22,187.96) 149.22,188.28 148.98,188.52 147.45,188.52 147.19,188.26 145.89,188.26 137.98,196.16 130.44,196.16 128.57,198.03 127.99,198.03 127.86,197.91 127.86,197.45 127.73,197.32 127.48,197.32 127.35,197.45 127.35,197.91 127.23,198.03 126.97,198.03 126.85,197.91 126.85,197.45 126.72,197.32 126.46,197.32 126.34,197.45 126.34,197.91 126.21,198.03 125.96,198.03 125.83,197.91 125.83,197.45 125.7,197.32 125.45,197.32 125.32,197.45 125.32,197.91 125.19,198.03 124.94,198.03 124.81,197.91 124.81,197.45 124.69,197.32 124.43,197.32 124.31,197.45 124.31,197.91 124.18,198.03 123.92,198.03 123.8,197.91 123.8,197.45 123.67,197.32 123.42,197.32 123.29,197.45 123.29,197.91 123.16,198.03 122.91,198.03 122.78,197.91 122.78,197.45 122.65,197.32 122.4,197.32 122.27,197.45 122.27,197.91 122.15,198.03 102.74,198.03 101.48,199.29 91.45,199.29 86.67,194.5 86.67,189.24 v1(85.91,188.48)
  BOTTOM w0.102: v2(86.82,188.34) 86.69,188.48 v1(85.91,188.48)
M_B_DQ11: length 92.9
  TOP w0.089: CPU1.AH68 86.43,183.77 86.43,184.72 86.39,184.89 86.39,185.08 86.43,185.24 86.43,185.82 85.81,186.43 85.81,187.4 85.94,187.53 v1(85.94,187.85)
  TOP w0.102: v1(147.95,187.96) 147.63,188.28 DIMM2.17
  L4 w0.127: v1(147.95,187.96) 147.9,187.91 145.73,187.91 137.82,195.82 130.29,195.82 129.14,196.98 121.82,196.98 121.69,197.1 121.69,197.43 121.57,197.56 121.31,197.56 121.19,197.43 121.19,197.1 121.06,196.98 120.8,196.98 120.68,197.1 120.68,197.56 120.55,197.69 120.3,197.69 120.17,197.56 120.17,197.1 120.04,196.98 119.79,196.98 119.66,197.1 119.66,197.56 119.53,197.69 119.28,197.69 119.15,197.56 119.15,197.1 119.03,196.98 118.77,196.98 118.65,197.1 118.65,197.56 118.52,197.69 118.26,197.69 118.14,197.56 118.14,197.1 118.01,196.98 117.76,196.98 117.63,197.1 117.63,197.56 117.5,197.69 117.25,197.69 117.12,197.56 117.12,197.1 116.99,196.98 116.74,196.98 116.61,197.1 116.61,197.56 116.49,197.69 116.23,197.69 116.11,197.56 116.11,197.1 115.98,196.98 115.72,196.98 115.6,197.1 115.6,197.56 115.47,197.69 115.22,197.69 115.09,197.56 115.09,197.1 114.96,196.98 114.71,196.98 114.58,197.1 114.58,197.56 114.45,197.69 114.2,197.69 114.07,197.56 114.07,197.1 113.95,196.98 113.69,196.98 113.57,197.1 113.57,197.56 113.44,197.69 113.18,197.69 113.06,197.56 113.06,197.1 112.93,196.98 112.68,196.98 112.55,197.1 112.55,197.56 112.42,197.69 112.17,197.69 112.04,197.56 112.04,197.1 111.91,196.98 111.51,196.98 110.8,197.69 102.6,197.69 101.38,198.91 91.55,198.91 87.01,194.36 87.01,188.91 v1(85.94,187.85)
  BOTTOM w0.102: v1(147.95,187.96) 147.61,187.96 v2(147.17,188.4)
M_B_DQ12: length 90.3
  TOP w0.102: v1(148.5,192.02) 148.06,191.59 147.68,191.59 147.5,191.78 DIMM2.3 ; CPU1.AF71 84.69,185.31 v1(84.26,185.75)
  L4 w0.127: v1(148.5,192.02) 148.5,192.03 147.74,192.79 145.26,192.79 139.12,198.93 131.53,198.93 129.65,200.81 120.35,200.81 120.23,200.94 120.23,201.46 120.1,201.59 119.85,201.59 119.72,201.46 119.72,200.94 119.59,200.81 119.34,200.81 119.21,200.94 119.21,201.46 119.08,201.59 118.83,201.59 118.7,201.46 118.7,200.94 118.58,200.81 118.32,200.81 118.19,200.94 118.19,201.46 118.07,201.59 117.81,201.59 117.69,201.46 117.69,200.94 117.56,200.81 117.08,200.81 116.3,201.59 109.56,201.59 108.72,202.43 90.69,202.43 83.08,194.81 83.08,194.25 83.08,194.25 83.08,187.64 83.24,187.48 83.24,186.75 84.25,185.75 v1(84.26,185.75)
  BOTTOM w0.102: v1(148.5,192.02) 148.5,192.38 v2(148.01,192.86)
M_B_DQ13: length 92
  TOP w0.102: CPU1.AF69 84.94,184.1 v1(84.24,184.8) ; DIMM2.7 148.64,190.78 149.77,191.9 v1(149.77,192.02)
  L4 w0.127: v1(84.24,184.8) 84.24,185.16 83.03,186.38 83.03,187.15 82.74,187.68 82.74,193.06 82.74,193.35 82.73,193.35 82.73,194.95 90.55,202.77 108.86,202.77 109.7,201.93 121.01,201.93 121.14,201.8 121.14,201.55 121.27,201.42 121.52,201.42 121.65,201.55 121.65,201.8 121.78,201.93 129.02,201.93 131.68,199.28 139.27,199.28 145.24,193.3 148.48,193.3 149.76,192.02 v1(149.77,192.02)
  BOTTOM w0.102: v2(149.77,191.19) v1(149.77,192.02)
M_B_DQ14: length 91
  TOP w0.089: v1(85.91,189.12) 85.36,188.57 85.36,186.32 85.9,185.79 85.9,185.26 85.96,185.04 85.96,184.87 CPU1.AH70
  TOP w0.102: v1(152.52,189.99) 152.52,189.01 153.01,188.52 153.01,188.53 DIMM2.16
  L4 w0.127: v1(152.52,189.99) 151.39,188.86 146.05,188.86 145.77,188.86 138.11,196.52 130.59,196.52 128.73,198.38 109.07,198.38 108.81,198.63 108.56,198.63 108.31,198.38 108.05,198.38 107.92,198.5 107.92,198.68 107.8,198.81 107.54,198.81 107.42,198.68 107.42,198.5 107.29,198.38 107.04,198.38 106.91,198.5 106.91,198.63 106.78,198.75 106.53,198.75 106.4,198.63 106.4,198.5 106.27,198.38 106.02,198.38 105.89,198.5 105.89,198.69 105.77,198.82 105.51,198.82 105.38,198.69 105.38,198.5 105.26,198.38 105,198.38 104.88,198.5 104.88,198.69 104.75,198.82 104.5,198.82 104.37,198.69 104.37,198.5 104.24,198.38 103.99,198.38 103.86,198.5 103.86,198.69 103.73,198.82 103.48,198.82 103.35,198.69 103.35,198.5 103.23,198.38 102.88,198.38 101.61,199.64 91.32,199.64 86.32,194.65 86.32,194.26 86.32,194.26 86.32,190.24 86.33,190.23 86.33,189.53 v1(85.91,189.12)
  BOTTOM w0.102: v1(85.91,189.12) 85.21,189.12 v2(85.1,189)
M_B_DQ15: length 92
  TOP w0.089: CPU1.AH69 85.77,184.41 85.77,185.05 85.72,185.24 85.72,185.72 85.18,186.25 85.18,188.66
  TOP w0.102: DIMM2.20 152.82,187.53 152.82,187.52 151.25,189.1 v1(151.25,189.99) ; v1(85.91,189.75) 85.18,189.02 85.18,188.66
  L4 w0.127: v1(151.25,189.99) 150.46,189.2 145.91,189.2 138.25,196.86 130.73,196.86 128.88,198.72 114.15,198.72 114.03,198.85 114.03,199.03 113.9,199.16 113.64,199.16 113.52,199.03 113.52,198.85 113.39,198.72 113.14,198.72 113.01,198.85 113.01,199.03 112.88,199.16 112.63,199.16 112.5,199.03 112.5,198.85 112.37,198.72 112.12,198.72 111.99,198.85 111.99,199.03 111.87,199.16 111.61,199.16 111.49,199.03 111.49,198.85 111.36,198.72 111.1,198.72 110.98,198.85 110.98,199.03 110.85,199.16 110.6,199.16 110.47,199.03 110.47,198.85 110.34,198.72 110.09,198.72 109.96,198.85 109.96,199.03 109.83,199.16 102.6,199.16 101.76,200 91.19,200 85.91,194.72 v1(85.91,189.75)
  BOTTOM w0.102: v2(86.6,190.42) 85.92,189.75 v1(85.91,189.75)
M_B_DQ16: length 79.3
  TOP w0.102: v1(152.39,177.42) 153,178.03 DIMM2.58 ; v1(91.19,182.82) 90.55,182.18 CPU1.AT66
  L4 w0.127: v1(91.19,182.82) 92.45,182.82 97.18,187.56 101.91,187.56 102.59,188.23 102.59,188.23 103,188.65 111.13,188.65 111.97,187.81 117.39,187.81 117.51,187.68 117.51,187.46 117.64,187.34 117.89,187.34 118.02,187.46 118.02,187.68 118.15,187.81 118.4,187.81 118.53,187.68 118.53,187.46 118.66,187.34 118.91,187.34 119.04,187.46 119.04,187.68 119.16,187.81 119.42,187.81 119.55,187.68 119.55,187.46 119.67,187.34 119.93,187.34 120.05,187.46 120.05,187.68 120.18,187.81 120.43,187.81 120.56,187.68 120.56,187.46 120.69,187.34 120.94,187.34 121.07,187.46 121.07,187.68 121.2,187.81 121.45,187.81 121.58,187.68 121.58,187.46 121.7,187.34 121.96,187.34 122.09,187.46 122.09,187.68 122.21,187.81 122.47,187.81 122.59,187.68 122.59,187.46 122.72,187.34 122.97,187.34 123.1,187.46 123.1,187.68 123.23,187.81 123.48,187.81 123.61,187.68 123.61,187.46 123.74,187.34 123.99,187.34 124.12,187.46 124.12,187.68 124.24,187.81 124.5,187.81 124.63,187.68 124.63,187.46 124.75,187.34 125.01,187.34 125.13,187.46 125.13,187.68 125.26,187.81 125.51,187.81 125.64,187.68 125.64,187.46 125.77,187.34 126.02,187.34 126.15,187.46 126.15,187.68 126.28,187.81 126.53,187.81 126.66,187.68 126.66,187.46 126.78,187.34 127.04,187.34 127.17,187.46 127.17,187.68 127.29,187.81 128.04,187.81 131.27,184.57 134.69,184.57 135.21,184.05 138.23,184.05 143.71,178.56 151.25,178.56 v1(152.39,177.42)
  BOTTOM w0.102: v1(91.19,182.82) 90.5,183.51 v2(90.36,183.51)
M_B_DQ17: length 78.6
  TOP w0.102: v1(151.12,177.42) 151.55,176.99 153.21,176.99 153.25,177.03 DIMM2.62 ; CPU1.AU66 91.2,181.96 v1(91.52,181.64)
  L4 w0.127: v1(151.12,177.42) 150.32,178.22 143.57,178.22 138.55,183.24 137.73,183.24 137.6,183.36 137.6,183.58 137.48,183.71 137.22,183.71 137.1,183.58 137.1,183.36 136.97,183.24 136.71,183.24 136.59,183.36 136.59,183.58 136.46,183.71 136.21,183.71 136.08,183.58 136.08,183.36 135.95,183.24 135.7,183.24 135.57,183.36 135.57,183.58 135.44,183.71 135.19,183.71 135.06,183.58 135.06,183.36 134.94,183.24 134.26,183.24 134.13,183.36 134.13,184.1 134.01,184.23 133.75,184.23 133.63,184.1 133.63,183.36 133.5,183.24 133.25,183.24 133.12,183.36 133.12,184.1 132.99,184.23 132.74,184.23 132.61,184.1 132.61,183.36 132.48,183.24 132.12,183.24 128.36,186.99 117.2,186.99 117.07,187.12 117.07,187.32 116.95,187.45 116.69,187.45 116.57,187.32 116.57,187.12 116.44,186.99 116.16,186.99 115.69,187.46 111.72,187.46 110.89,188.29 103.13,188.29 102.93,188.09 102.93,188.09 102.05,187.21 97.33,187.21 94.39,184.27 94.39,183.42 93.91,182.93 93.05,182.93 91.75,181.64 v1(91.52,181.64)
  BOTTOM w0.102: v2(92.34,182.3) 92.18,182.3 v1(91.52,181.64)
M_B_DQ18: length 81
  TOP w0.102: v1(153.16,180.72) 153.46,181.03 DIMM2.46 ; v1(89.57,180.72) 89.25,181.05 CPU1.AP65
  L4 w0.127: v1(153.16,180.72) 151.7,182.17 143.97,182.17 138.74,187.4 131.78,187.4 127.59,191.59 117.65,191.59 117.09,191.03 101.97,191.03 100.89,189.95 96.56,189.95 95.62,189.01 94.12,189.01 93.11,188 93.11,187.72 93.12,187.71 93.12,186.06 92.86,185.81 91.91,185.81 90.27,184.16 89.27,184.16 88.29,183.18 88.29,180.76 88.75,180.3 89.15,180.3 v1(89.57,180.72)
  BOTTOM w0.102: v1(153.16,180.72) 153.68,181.24 v2(153.68,181.32)
M_B_DQ19: length 82.1
  TOP w0.102: CPU1.AN65 88.6,181.05 v1(88.92,180.72) ; DIMM2.50 153.79,180.03 153.67,179.91 152.7,179.91 v1(151.89,180.72)
  L4 w0.127: v1(88.92,180.72) 88.5,181.14 88.5,181.81 88.75,182.06 88.77,182.06 89.25,182.53 89.25,182.83 91.97,185.56 92.92,185.56 93.45,186.09 93.45,187.86 94.26,188.67 95.76,188.67 96.7,189.61 101.03,189.61 102.11,190.69 117.23,190.69 117.6,191.06 123.35,191.06 123.58,190.83 123.58,190.6 123.7,190.47 123.96,190.47 124.09,190.6 124.09,191.1 124.21,191.22 124.47,191.22 124.59,191.1 124.59,190.02 124.72,189.89 124.97,189.89 125.1,190.02 125.1,191.1 125.23,191.22 127.48,191.22 131.64,187.06 138.53,187.06 143.76,181.83 150.92,181.83 151.89,180.86 v1(151.89,180.72)
  BOTTOM w0.102: v1(88.92,180.72) 88.68,180.72 88.18,180.23 v2(88.18,180.21)
M_B_DQ20: length 81.3
  TOP w0.102: DIMM2.49 149.41,180.28 v1(149.85,180.72) ; v1(88.92,181.64) 88.6,181.96 CPU1.AN66
  L4 w0.127: v1(149.85,180.72) 149.09,181.49 147.4,181.49 147.28,181.36 147.28,180.8 147.15,180.67 146.9,180.67 146.77,180.8 146.77,181.36 146.64,181.49 143.54,181.49 138.31,186.72 131.5,186.72 128.69,189.52 128.68,189.52 128.67,189.52 127.36,189.52 127.23,189.64 127.23,190.73 127.1,190.86 126.85,190.86 126.72,190.73 126.72,189.64 126.6,189.52 126.34,189.52 126.22,189.64 126.22,190.73 126.09,190.86 125.83,190.86 125.71,190.73 125.71,189.64 125.58,189.52 124.1,189.52 122.91,190.72 117.85,190.72 117.48,190.35 102.25,190.35 101.17,189.27 96.84,189.27 95.87,188.29 94.37,188.29 93.8,187.72 93.8,186.13 92.96,185.29 92.02,185.29 89.51,182.79 89.51,182.23 v1(88.92,181.64)
  BOTTOM w0.102: v1(149.85,180.72) v2(149.85,181.61)
M_B_DQ21: length 80.8
  TOP w0.102: DIMM2.45 148.03,181.28 v1(148.58,180.72) ; v1(89.57,181.64) 89.25,181.96 CPU1.AP66
  L4 w0.127: v1(148.58,180.72) 148.58,180.72 148.13,180.28 146.47,180.28 146.34,180.4 146.34,180.87 146.21,181 145.96,181 145.83,180.87 145.83,180.4 145.7,180.28 145.45,180.28 145.32,180.4 145.32,180.87 145.2,181 144.94,181 144.82,180.87 144.82,180.4 144.69,180.28 144.24,180.28 138.4,186.12 138.39,186.12 138.14,186.37 131.36,186.37 128.55,189.17 123.96,189.17 122.76,190.37 117.99,190.37 117.62,190 117.36,190 117.23,189.88 117.23,189.31 117.1,189.18 116.85,189.18 116.72,189.31 116.72,189.88 116.59,190 116.34,190 116.21,189.88 116.21,189.31 116.09,189.18 115.83,189.18 115.71,189.31 115.71,189.88 115.58,190 115.32,190 115.2,189.88 115.2,189.31 115.07,189.18 114.82,189.18 114.69,189.31 114.69,189.88 114.56,190 114.31,190 114.18,189.88 114.18,189.31 114.05,189.18 113.8,189.18 113.67,189.31 113.67,189.88 113.55,190 113.29,190 113.17,189.88 113.17,189.31 113.04,189.18 112.78,189.18 112.66,189.31 112.66,189.88 112.53,190 102.39,190 101.28,188.89 97,188.89 94.69,186.58 94.69,186.06 93.67,185.04 92.07,185.04 89.77,182.75 89.77,181.84 v1(89.57,181.64)
  BOTTOM w0.102: v2(148.25,181.48) 148.58,181.14 v1(148.58,180.72)
M_B_DQ22: length 80.3
  TOP w0.102: v1(90.87,180.72) 90.55,181.05 CPU1.AT65 ; v1(149.22,177.42) 148.35,176.56 147.58,176.56 147.36,176.78 DIMM2.63
  L4 w0.127: v1(149.22,177.42) 148.76,177.88 143.43,177.88 139,182.31 132.45,182.31 128.11,186.65 115.97,186.65 115.63,186.99 110.7,186.99 110.57,187.12 110.57,187.5 110.45,187.63 110.19,187.63 110.07,187.5 110.07,187.12 109.94,186.99 109.68,186.99 109.56,187.12 109.56,187.81 109.43,187.93 109.18,187.93 109.05,187.81 109.05,187.12 108.92,186.99 108.67,186.99 108.54,187.12 108.54,187.81 108.41,187.93 108.16,187.93 108.03,187.81 108.03,187.12 107.91,186.99 107.65,186.99 107.53,187.12 107.53,187.81 107.4,187.93 107.14,187.93 107.02,187.81 107.02,187.12 106.89,186.99 106.64,186.99 106.51,187.12 106.51,187.81 106.38,187.93 106.13,187.93 106,187.81 106,187.12 105.87,186.99 105.62,186.99 105.49,187.12 105.49,187.81 105.37,187.93 105.11,187.93 104.99,187.81 104.99,187.12 104.86,186.99 104.6,186.99 104.48,187.12 104.48,187.81 104.35,187.93 104.1,187.93 103.97,187.81 103.97,187.12 103.84,186.99 103.61,186.99 102.96,186.34 98.25,186.34 95.36,183.45 94.83,183.45 93.89,182.5 93.12,182.5 91.78,181.15 91.3,181.15 v1(90.87,180.72)
  BOTTOM w0.102: v2(148.7,178.28) 149.22,177.76 v1(149.22,177.42)
M_B_DQ23: length 79.8
  TOP w0.102: CPU1.AU65 91.2,181.06 v1(91.53,180.73) ; v1(147.95,177.42) 147.59,177.78 DIMM2.59
  L4 w0.127: v1(147.95,177.42) 143.4,177.42 138.85,181.97 132.31,181.97 127.96,186.31 116.49,186.31 116.06,185.88 115.65,185.88 115.52,186 115.52,186.52 115.39,186.65 115.14,186.65 115.01,186.52 115.01,186 114.89,185.88 114.63,185.88 114.5,186 114.5,186.52 114.38,186.65 114.12,186.65 114,186.52 114,186 113.87,185.88 113.62,185.88 113.49,186 113.49,186.52 113.36,186.65 113.11,186.65 112.98,186.52 112.98,186 112.85,185.88 112.6,185.88 112.47,186 112.47,186.52 112.35,186.65 112.09,186.65 111.96,186.52 111.96,186 111.84,185.88 111.58,185.88 111.46,186 111.46,186.52 111.33,186.65 111.08,186.65 110.95,186.52 110.95,186 110.82,185.88 110.57,185.88 110.44,186 110.44,186.52 110.31,186.65 110.06,186.65 109.93,186.52 109.93,186 109.81,185.88 109.55,185.88 109.42,186 109.42,186.52 109.3,186.65 109.04,186.65 108.92,186.52 108.92,186 108.79,185.88 108.54,185.88 108.41,186 108.41,186.52 108.28,186.65 108.03,186.65 107.9,186.52 107.9,186 107.77,185.88 107.52,185.88 107.39,186 107.39,186.52 107.27,186.65 107.01,186.65 106.88,186.52 106.88,186 106.76,185.88 106.5,185.88 106.38,186 106.38,186.52 106.25,186.65 106,186.65 105.87,186.52 105.87,186 105.74,185.88 105.49,185.88 105.36,186 105.36,186.52 105.23,186.65 104.98,186.65 104.85,186.52 104.85,186 104.73,185.88 98.36,185.88 95.71,183.23 95.13,183.23 94.01,182.12 93.25,182.12 91.86,180.73 v1(91.53,180.73)
  BOTTOM w0.102: v2(92.72,180.95) 91.75,180.95 v1(91.53,180.73)
M_B_DQ24: length 73.5
  TOP w0.102: DIMM2.71 147.37,174.78 147.58,174.57 148.41,174.57 v1(149.22,175.39) ; v1(90.22,178.89) 90.55,179.22 CPU1.AT61
  L4 w0.127: v1(149.22,175.39) 148.71,175.9 143.01,175.9 138.67,180.24 132.3,180.24 132.03,180.51 127.9,184.64 127.12,184.64 126.99,184.76 126.99,184.95 126.86,185.08 126.61,185.08 126.48,184.95 126.48,184.76 126.35,184.64 126.1,184.64 125.97,184.76 125.97,184.95 125.85,185.08 125.59,185.08 125.47,184.95 125.47,184.76 125.34,184.64 125.08,184.64 124.96,184.76 124.96,184.95 124.83,185.08 124.58,185.08 124.45,184.95 124.45,184.76 124.32,184.64 124.07,184.64 123.94,184.76 123.94,184.95 123.81,185.08 123.56,185.08 123.43,184.95 123.43,184.76 123.31,184.64 123.05,184.64 122.93,184.76 122.93,184.95 122.8,185.08 122.54,185.08 122.42,184.95 122.42,184.76 122.29,184.64 122.04,184.64 121.91,184.76 121.91,184.95 121.78,185.08 121.53,185.08 121.4,184.95 121.4,184.76 121.27,184.64 105.02,184.64 104.73,184.35 98.28,184.35 95.21,181.28 94.79,181.28 94.66,181.16 93.48,181.16 91.91,179.59 91.64,179.59 90.94,178.89 v1(90.22,178.89)
  BOTTOM w0.102: v2(89.92,179.71) 90.22,179.41 v1(90.22,178.89)
M_B_DQ25: length 72.8
  TOP w0.102: CPU1.AU61 91.2,179.29 v1(91.56,178.92) ; v1(147.95,175.39) 147.56,175.78 DIMM2.67
  L4 w0.127: v1(147.95,175.39) 147.17,175.39 147.04,175.26 147.04,175.06 146.92,174.93 146.66,174.93 146.54,175.06 146.54,175.26 146.41,175.39 146.16,175.39 146.03,175.26 146.03,175.06 145.9,174.93 145.65,174.93 145.52,175.06 145.52,175.26 145.39,175.39 145.14,175.39 145.01,175.26 145.01,175.06 144.89,174.93 144.63,174.93 144.5,175.06 144.5,175.26 144.38,175.39 144.12,175.39 144,175.26 144,175.06 143.87,174.93 143.62,174.93 143.49,175.06 143.49,175.26 143.36,175.39 143.04,175.39 138.53,179.9 137.69,179.9 137.56,179.77 137.56,179.68 137.43,179.55 137.18,179.55 137.05,179.68 137.05,179.77 136.92,179.9 136.67,179.9 136.54,179.77 136.54,179.68 136.42,179.55 136.16,179.55 136.03,179.68 136.03,179.77 135.91,179.9 131.38,179.9 130.69,180.59 130.69,180.77 130.89,180.97 130.89,181.15 130.71,181.33 130.53,181.33 130.33,181.13 130.15,181.13 129.97,181.31 129.97,181.48 130.18,181.69 130.18,181.87 130,182.05 129.82,182.05 129.61,181.84 129.43,181.84 129.25,182.02 129.25,182.2 129.46,182.41 129.46,182.59 129.28,182.77 129.1,182.77 128.89,182.56 128.71,182.56 128.53,182.74 128.53,182.92 128.74,183.13 128.74,183.31 128.56,183.49 128.38,183.49 128.17,183.28 127.99,183.28 127.81,183.46 127.81,183.64 128.02,183.85 128.02,184.03 127.84,184.21 127.66,184.21 127.45,184 127.27,184 127.1,184.18 105.22,184.18 105.05,184.01 98.36,184.01 95.38,181.03 95.38,180.69 95.14,180.44 94.14,180.44 92.62,178.92 v1(91.56,178.92)
  BOTTOM w0.102: v2(92.38,178.77) 92.23,178.92 v1(91.56,178.92)
M_B_DQ26: length 76.7
  TOP w0.102: CPU1.AP60 89.25,178.3 v1(88.92,177.98) ; DIMM2.80 153.52,172.53 153.52,172.52 153.14,172.9 152.73,172.9 v1(152.31,172.47)
  L4 w0.089: v1(88.92,177.98) 89.34,177.56 91.08,177.56 91.71,176.92
  L4 w0.127: 91.71,176.92 93.28,176.92 94.63,178.27 94.63,179.03 95,179.4 95.78,179.4 98.29,181.91 103.37,181.91 103.54,181.74 118.84,181.74 119,181.58 126.17,181.58 130.82,176.94 138.62,176.94 143.59,171.96 150.67,171.96 150.8,172.09 150.8,172.67 150.93,172.8 151.18,172.8 151.31,172.67 151.31,172.09 151.44,171.96 151.79,171.96 v1(152.31,172.47)
  BOTTOM w0.102: v1(152.31,172.47) 152.31,172.14 152.82,171.62 v2(153.24,171.62)
M_B_DQ27: length 76.7
  TOP w0.102: DIMM2.84 152.28,171.53 v1(152.28,171.52) ; v1(88.27,178.89) 88.6,178.57 CPU1.AN60
  L4 w0.089: v1(88.27,178.89) 87.87,178.49 87.87,177.81 88.34,177.35 90.02,177.35 90.7,176.66 93.35,176.66 93.76,177.07
  L4 w0.127: v1(152.28,171.52) 152.19,171.62 143.45,171.62 138.47,176.59 130.53,176.59 125.89,181.23 102.9,181.23 102.65,181.48 98.17,181.48 95.87,179.19 95.09,179.19 94.84,178.94 94.84,178.15 93.76,177.07
  BOTTOM w0.102: v1(152.28,171.52) 151.42,171.52 v2(151.29,171.4)
M_B_DQ28: length 75.9
  TOP w0.102: DIMM2.66 153.03,176.03 v1(152.39,175.39) ; v1(88.92,179.81) 88.6,179.48 CPU1.AN61
  L4 w0.127: v1(88.92,179.81) 89.04,179.81 89.45,180.23 91.74,180.23 93.25,181.74 94.88,181.74 98.76,185.62 101.62,185.62 101.92,185.32 116.99,185.32 117.12,185.45 117.12,185.65 117.24,185.78 117.5,185.78 117.63,185.65 117.63,185.45 117.75,185.32 118.01,185.32 118.13,185.45 118.13,185.65 118.26,185.78 118.51,185.78 118.64,185.65 118.64,185.45 118.77,185.32 119.02,185.32 119.15,185.45 119.15,185.65 119.28,185.78 127.73,185.78 132,181.51 138.42,181.51 143.35,176.58 151.2,176.58 v1(152.39,175.39)
  BOTTOM w0.102: v1(152.39,175.39) 152.39,176.02 v2(152.69,176.32)
M_B_DQ29: length 75.1
  TOP w0.102: v1(88.92,178.89) 89.25,179.22 CPU1.AP61 ; v1(151.12,175.39) 151.55,174.96 153.2,174.96 153.26,175.03 DIMM2.70
  L4 w0.127: v1(88.92,178.89) 89.42,179.39 91.05,179.39 91.46,179.81 91.7,179.81 92.46,180.57 92.49,180.57 93.33,181.41 94.61,181.41 94.7,181.5 94.94,181.5 98.72,185.28 101.48,185.28 101.78,184.98 119.59,184.98 119.72,185.11 119.72,185.31 119.85,185.43 120.1,185.43 120.23,185.31 120.23,185.11 120.36,184.98 120.7,184.98 121.14,185.42 127.6,185.42 131.86,181.17 138.28,181.17 143.2,176.24 150.27,176.24 v1(151.12,175.39)
  BOTTOM w0.102: v2(150.71,176.15) 151.12,175.73 v1(151.12,175.39)
M_B_DQ30: length 75.9
  TOP w0.102: DIMM2.83 148.53,171.78 v1(149.85,173.1) ; v1(90.87,177.98) 90.87,178.11 CPU1.AT60
  L4 w0.089: 92.19,177.81 91.88,177.51 91.39,177.51 90.91,177.98 v1(90.87,177.98)
  L4 w0.127: v1(149.85,173.1) 149.29,172.54 143.51,172.54 138.19,177.86 131.72,177.86 131.59,177.74 131.59,177.44 131.46,177.32 131.21,177.32 131.08,177.44 131.08,177.74 130.95,177.86 130.38,177.86 127.53,180.71 127.53,180.89 127.67,181.02 127.67,181.2 127.49,181.38 127.31,181.38 127.17,181.25 126.99,181.25 126.81,181.43 126.81,181.61 126.95,181.74 126.95,181.92 126.77,182.1 126.59,182.1 126.45,181.97 126.27,181.97 125.94,182.3 125.08,182.3 124.96,182.17 124.96,182.07 124.83,181.94 124.57,181.94 124.45,182.07 124.45,182.17 124.32,182.3 124.07,182.3 123.94,182.17 123.94,182.07 123.81,181.94 123.56,181.94 123.43,182.07 123.43,182.17 123.3,182.3 123.05,182.3 122.92,182.17 122.92,182.07 122.8,181.94 122.54,181.94 122.42,182.07 122.42,182.17 122.29,182.3 122.03,182.3 121.91,182.17 121.91,182.07 121.78,181.94 121.53,181.94 121.4,182.07 121.4,182.17 121.27,182.3 121.02,182.3 120.89,182.17 120.89,182.07 120.76,181.94 120.51,181.94 120.38,182.07 120.38,182.17 120.26,182.3 120,182.3 119.88,182.17 119.88,182.07 119.75,181.94 119.49,181.94 119.37,182.07 119.37,182.17 119.24,182.3 102.03,182.3 101.85,182.12 97.95,182.12 95.44,179.62 94.91,179.62 94.41,179.12 94.41,178.48 93.75,177.81 92.19,177.81
  BOTTOM w0.102: v1(149.85,173.1) 149.85,172.4 v2(149.64,172.19)
M_B_DQ31: length 75
  TOP w0.102: v1(91.6,177.91) 91.6,178.03 CPU1.AU60 ; DIMM2.79 147.66,172.78 147.77,172.67 148.15,172.67 v1(148.58,173.1)
  L4 w0.127: v1(91.6,177.91) 91.71,177.91 91.87,178.07 93.5,178.07 94.19,178.77 94.19,179.21 94.82,179.83 95.35,179.83 97.86,182.34 101.76,182.34 102.1,182.67 105.85,182.67 106,182.83 106.36,182.83 106.51,182.67 106.86,182.67 107.02,182.83 107.37,182.83 107.53,182.67 107.88,182.67 108.04,182.83 108.39,182.83 108.54,182.67 108.9,182.67 109.05,182.83 109.4,182.83 109.56,182.67 109.91,182.67 110.07,182.83 110.42,182.83 110.58,182.67 110.93,182.67 111.08,182.83 111.44,182.83 111.59,182.67 111.94,182.67 112.1,182.83 112.45,182.83 112.61,182.67 112.96,182.67 113.12,182.83 113.47,182.83 113.62,182.67 113.98,182.67 114.13,182.83 114.48,182.83 114.64,182.67 114.99,182.67 115.15,182.83 115.5,182.83 115.66,182.67 116.01,182.67 116.16,182.83 116.52,182.83 116.67,182.67 117.02,182.67 117.18,182.83 117.53,182.83 117.69,182.67 118.04,182.67 118.2,182.83 118.55,182.83 118.7,182.67 119.06,182.67 119.21,182.83 119.56,182.83 119.72,182.67 120.07,182.67 120.23,182.83 120.58,182.83 120.74,182.67 121.09,182.67 121.24,182.83 121.6,182.83 121.75,182.67 122.1,182.67 122.26,182.83 122.61,182.83 122.77,182.67 123.12,182.67 123.28,182.83 123.63,182.83 123.78,182.67 124.14,182.67 124.29,182.83 124.64,182.83 124.8,182.67 125.15,182.67 125.31,182.83 125.66,182.83 125.82,182.67 126.71,182.67 128.22,181.16 128.22,180.98 128.1,180.85 128.1,180.67 128.28,180.49 128.46,180.49 128.58,180.62 128.76,180.62 128.94,180.44 128.94,180.26 128.82,180.13 128.82,179.95 129,179.77 129.18,179.77 129.3,179.9 129.48,179.9 129.66,179.72 129.66,179.54 129.54,179.41 129.54,179.23 129.72,179.05 129.9,179.05 130.02,179.18 130.2,179.18 130.38,179 130.38,178.82 130.26,178.69 130.26,178.51 130.43,178.34 130.61,178.34 130.74,178.46 130.92,178.46 131.17,178.21 138.33,178.21 142.97,173.57 143.58,173.57 143.7,173.44 143.7,173.05 143.83,172.92 144.08,172.92 144.21,173.05 144.21,173.44 144.34,173.57 145.5,173.57 145.62,173.44 145.62,173.05 145.75,172.92 146,172.92 146.13,173.05 146.13,173.44 146.26,173.57 146.51,173.57 146.64,173.44 146.64,173.05 146.77,172.92 147.02,172.92 147.15,173.05 147.15,173.44 147.27,173.57 148.11,173.57 v1(148.58,173.1)
  BOTTOM w0.102: v2(148.58,173.96) v1(148.58,173.1)
M_B_DQ32: length 76.2
  TOP w0.102: v1(152.43,146.56) 152.9,147.03 DIMM2.174 ; CPU1.AU40 91.2,167.26 90.92,166.98 v1(90.92,166.98)
  L4 w0.089: v1(90.92,166.98) 93.41,166.98 95.03,165.35 100.49,165.35 104,161.84
  L4 w0.127: 104,161.84 104,161.59 104.71,160.88 109.53,160.88 109.57,160.85 109.57,160.85 125.93,144.49 132.12,144.49 132.24,144.36 134.78,144.36 134.8,144.37 134.81,144.37 134.91,144.48 138.42,144.48 140.58,146.63 149.18,146.63 149.7,146.11 151.98,146.11 152.43,146.56 v1(152.43,146.56)
  BOTTOM w0.102: v2(152.64,145.77) 152.43,145.97 v1(152.43,146.56)
M_B_DQ33: length 77
  TOP w0.102: v1(151.16,146.56) 152.63,148.03 DIMM2.170 ; CPU1.AT40 90.55,167.64 90.27,167.91 v1(90.27,167.92)
  L4 w0.089: v1(90.27,167.92) 90.8,167.4 91.1,167.4 91.32,167.17 93.59,167.17 95.18,165.58 100.64,165.58 104.02,162.2
  L4 w0.127: v1(151.16,146.56) 149.87,147 140.46,147 138.29,144.83 126.07,144.83 109.71,161.19 109.71,161.19 109.67,161.23 109.67,161.23 109.63,161.26 104.86,161.26 104.34,161.78 104.34,161.89 104.02,162.2
  BOTTOM w0.102: v2(150.76,145.82) 150.76,146.15 v1(151.16,146.56)
M_B_DQ34: length 77.9
  TOP w0.102: v1(90.22,166.09) 90.55,165.77 CPU1.AT37 ; v1(147.86,144.65) 147.74,144.78 DIMM2.183
  L4 w0.089: v1(90.22,166.09) 90.53,165.79 90.89,165.79 91.4,166.3 92.72,166.3 94.96,164.07 100.61,164.07
  L4 w0.127: v1(147.86,144.65) 147.68,144.48 147.3,144.48 147.2,144.58 147.2,145.17 147.07,145.3 146.82,145.3 146.69,145.17 146.69,144.78 146.57,144.65 146.31,144.65 146.19,144.78 146.19,145.17 146.06,145.3 145.8,145.3 145.68,145.17 145.68,144.78 145.55,144.65 145.3,144.65 145.17,144.78 145.17,145.17 145.04,145.3 144.79,145.3 144.66,145.17 144.66,144.78 144.53,144.65 144.28,144.65 144.15,144.78 144.15,145.17 144.03,145.3 143.77,145.3 143.65,145.17 143.65,144.78 143.52,144.65 143.26,144.65 142.5,143.89 141.57,143.89 141.27,144.2 140.94,144.2 140.14,143.4 140.14,143.23 140.02,143.1 139.76,143.1 139.63,143.23 139.63,143.45 139.51,143.57 139.19,143.57 139.06,143.45 139.06,143.14 138.94,143.01 138.68,143.01 138.55,143.14 138.55,143.45 138.43,143.57 135.68,143.57 135.26,143.15 125.38,143.15 109.07,159.46 104.55,159.46 103.63,160.39 102.47,161.54 102.47,162.2 100.61,164.07
  BOTTOM w0.102: v1(147.86,144.65) 147.07,144.65 v2(146.69,145.03)
M_B_DQ35: length 77.2
  TOP w0.102: v1(90.86,165.18) 90.92,165.18 91.2,165.46 CPU1.AU37 ; DIMM2.186 151.79,144.03 v1(151.16,144.65)
  L4 w0.089: v1(90.86,165.18) 91.63,165.95 92.52,165.95 94.89,163.58 100.24,163.58 100.36,163.45
  L4 w0.127: 100.36,163.45 101.86,161.95 101.86,161.34 104.45,158.75 108.63,158.75 125.03,142.35 130.56,142.35 130.99,141.92 134.84,141.92 135.27,142.35 141.93,142.35 143.37,143.79 150.3,143.79 v1(151.16,144.65)
  BOTTOM w0.102: v2(150.58,144.12) 150.6,144.12 151.14,144.65 v1(151.16,144.65)
M_B_DQ36: length 77.5
  TOP w0.102: CPU1.AR40 89.9,167.61 v1(89.59,167.92) ; DIMM2.173 147.69,147.28 v1(147.86,147.45)
  L4 w0.089: 103.92,162.69 100.81,165.8 95.42,165.8 93.2,168.02 92.15,168.02 92.06,167.93 92.06,167.68 91.97,167.59 91.79,167.59 91.7,167.68 91.7,167.93 91.61,168.02 91.4,168.02 91.13,168.29 90.46,168.29 90.43,168.32 89.99,168.32 v1(89.59,167.92)
  L4 w0.127: 103.92,162.69 105,161.61 109.78,161.61 109.81,161.57 109.82,161.57 109.85,161.53 109.86,161.53 126.21,145.17 128.49,145.17 128.61,145.3 128.61,145.99 128.74,146.11 129,146.11 129.12,145.99 129.12,145.3 129.25,145.17 129.5,145.17 129.63,145.3 129.63,145.99 129.76,146.11 130.01,146.11 130.14,145.99 130.14,145.3 130.27,145.17 130.52,145.17 130.65,145.3 130.65,145.99 130.77,146.11 131.03,146.11 131.15,145.99 131.15,145.3 131.28,145.17 131.97,145.17 132.11,145.31 132.11,145.57 132.34,145.8 138.72,145.8 140.26,147.34 147.75,147.34 v1(147.86,147.45)
  BOTTOM w0.102: v1(147.86,147.45) 147.1,147.45 v2(147.05,147.5)
M_B_DQ37: length 78.3
  TOP w0.102: CPU1.AP40 88.93,167.78 v1(88.93,167.92) ; DIMM2.169 148.3,148.28 v1(149.13,147.45)
  L4 w0.089: 95.26,166.4 93.23,168.43 91.26,168.43 91.19,168.49 90.51,168.49 90.5,168.5 89.86,168.5 89.78,168.43 89.43,168.43 v1(88.93,167.92)
  L4 w0.127: 95.26,166.4 95.6,166.05 100.94,166.05 104.72,162.27 104.82,162.27 105.01,162.08 110.04,162.08 125.66,146.46 126.33,146.46 126.46,146.33 126.46,145.67 126.59,145.54 126.84,145.54 126.97,145.67 126.97,146.33 127.09,146.46 127.35,146.46 127.47,146.33 127.47,145.67 127.6,145.54 127.86,145.54 127.98,145.67 127.98,146.33 128.11,146.46 132.21,146.46 132.56,146.11 138.55,146.11 140.12,147.68 147.47,147.68 147.68,147.89 148.69,147.89 v1(149.13,147.45)
  BOTTOM w0.102: v1(149.13,147.45) 149.13,147.85 v2(149.51,148.23)
M_B_DQ38: length 79.5
  TOP w0.102: CPU1.AP37 88.92,165.96 v1(88.92,166.09) ; DIMM2.182 153.64,145.03 153.58,145.08 152.86,145.08 v1(152.43,144.65)
  L4 w0.089: 100.24,163.19 100.11,163.32 94.86,163.32 92.91,165.27 92.26,165.27 92.11,165.12 91.45,165.12 91.1,164.78 90.54,164.78 89.74,165.58 89.44,165.58 v1(88.92,166.09)
  L4 w0.127: v1(152.43,144.65) 151.93,144.15 151.14,144.15 150.44,143.45 143.51,143.45 142.08,142.01 135.38,142.01 134.97,141.6 130.82,141.6 130.42,142.01 124.89,142.01 108.56,158.34 104.43,158.34 101.56,161.21 101.56,161.87 100.24,163.19
  BOTTOM w0.102: v2(152.15,143.92) 152.15,143.94 152.43,144.22 v1(152.43,144.65)
M_B_DQ39: length 78.9
  TOP w0.102: v1(149.13,144.65) 149.13,144.32 149.38,144.08 149.56,144.08 149.72,143.92 149.72,143.69 149.56,143.54 148.75,143.54 148.47,143.81 147.35,143.81 147.31,143.78 DIMM2.187 ; v1(89.57,166.09) 89.9,165.77 CPU1.AR37
  L4 w0.089: 100.46,163.74 100.36,163.83 94.9,163.83 92.61,166.12 91.48,166.12 90.94,165.58 90.08,165.58 v1(89.57,166.09)
  L4 w0.127: 100.46,163.74 102.17,162.02 102.17,161.44 104.5,159.11 108.94,159.11 125.24,142.81 134.84,142.81 134.96,142.68 139.45,142.68 139.46,142.7 140.81,142.7 140.94,142.82 140.94,143.51 141.07,143.64 141.32,143.64 141.45,143.51 141.45,142.82 141.57,142.7 141.79,142.7 143.23,144.13 148.89,144.13 149.13,144.37 v1(149.13,144.65)
  BOTTOM w0.102: v1(149.13,144.65) 148.78,144.3 v2(148.78,143.89)
M_B_DQ40: length 79.3
  TOP w0.102: v1(90.22,164.26) 90.55,163.94 CPU1.AT33 ; DIMM2.195 146.4,141.77 149.05,141.77 149.77,142.49 v1(149.77,143)
  L4 w0.089: v1(90.22,164.26) 91.39,164.26 91.55,164.1 93.13,164.1 95.25,161.98 100.49,161.98
  L4 w0.127: v1(149.77,143) 149.77,142.65 149.58,142.46 143.49,142.46 142.03,141 141.63,141 141.37,141.25 141.12,141.25 140.87,141 140.61,141 140.36,141.25 140.1,141.25 139.85,141 139.17,141 138.91,140.73 124.89,140.73 109.19,156.43 107.97,156.43 107.85,156.55 107.85,157.33 107.72,157.45 107.47,157.45 107.34,157.33 107.34,156.55 107.21,156.43 105.28,156.43 100.78,160.93 100.78,161.69 100.49,161.98
  BOTTOM w0.102: v1(149.77,143) 148.78,142.01 v2(148.7,142.01)
M_B_DQ41: length 78.1
  TOP w0.102: v1(91.59,163.47) 91.53,163.47 CPU1.AU33 ; v1(153.16,143.13) 153.26,143.03 DIMM2.190
  L4 w0.089: v1(91.59,163.47) 93.1,163.47 95.1,161.48 99.88,161.48
  L4 w0.127: 99.88,161.48 100.14,161.22 100.14,159.86 101.89,158.11 102.07,158.11 102.22,158.26 102.4,158.26 102.58,158.08 102.58,157.9 102.43,157.75 102.43,157.57 102.61,157.39 102.79,157.39 102.94,157.54 103.12,157.54 103.3,157.36 103.3,157.18 103.15,157.03 103.15,156.85 103.33,156.67 103.51,156.67 103.66,156.82 103.84,156.82 104.02,156.64 104.02,156.46 103.87,156.31 103.87,156.13 104.35,155.65 109,155.65 124.7,139.95 131.26,139.95 131.4,140.09 139.17,140.09 139.38,140.31 142.31,140.31 143.78,141.77 149.94,141.77 150.67,142.49 152.52,142.49 v1(153.16,143.13)
  BOTTOM w0.102: v2(153.96,143.13) v1(153.16,143.13)
M_B_DQ42: length 77.4
  TOP w0.102: v1(90.87,162.43) 91.2,162.11 CPU1.AU30 ; v1(151.89,139.57) 152.93,138.52 DIMM2.208
  L4 w0.089: 95.89,159 95.33,159 91.9,162.43 v1(90.87,162.43)
  L4 w0.127: 95.89,159 99.25,159 104.31,153.94 107.38,153.94 108.54,152.78 109.49,152.78 124.03,138.24 139.11,138.24 139.23,138.37 139.23,138.51 139.36,138.63 139.62,138.63 139.74,138.51 139.74,138.37 139.87,138.24 140.12,138.24 140.25,138.37 140.25,138.51 140.38,138.63 143.01,138.63 144.47,140.09 151.36,140.09 v1(151.89,139.57)
  BOTTOM w0.102: v1(151.89,139.57) 151.89,139.99 v2(151.42,140.46)
M_B_DQ43: length 78.1
  TOP w0.102: v1(90.22,162.43) 90.22,162.31 90.55,161.98 CPU1.AT30 ; v1(153.16,139.57) 153.2,139.52 DIMM2.204
  L4 w0.089: 92.72,161.93 91.96,162.69 91.18,162.69 91.04,162.83 90.62,162.83 v1(90.22,162.43)
  L4 w0.127: v1(153.16,139.57) 153.53,139.94 153.53,140.31 153.4,140.44 144.33,140.44 142.87,138.98 138.81,138.98 138.41,138.58 124.17,138.58 109.63,153.12 108.68,153.12 107.52,154.28 104.48,154.28 98.8,159.96 94.69,159.96 92.72,161.93
  BOTTOM w0.102: v1(153.16,139.57) v2(154.01,139.57)
M_B_DQ44: length 80.4
  TOP w0.102: v1(150.66,142.98) 150.66,142.26 150.9,142.03 DIMM2.194 ; CPU1.AR33 89.9,163.94 v1(89.58,164.26)
  L4 w0.089: 98.88,161.73 95.22,161.73 93.08,163.87 91.42,163.87 91.41,163.86 89.98,163.86 v1(89.58,164.26)
  L4 w0.127: v1(150.66,142.98) 149.8,142.11 143.63,142.11 142.17,140.65 139.28,140.65 139.04,140.41 131,140.41 130.9,140.31 124.83,140.31 109.05,156.08 105.14,156.08 104.34,156.88 104.34,156.88 102.05,159.17 101.87,159.17 101.72,159.02 101.54,159.02 101.36,159.2 101.36,159.38 101.51,159.53 101.51,159.71 101.33,159.89 101.15,159.89 101,159.74 100.82,159.74 100.64,159.92 100.64,160.1 100.79,160.25 100.79,160.43 100.5,160.72 100.5,161.33 100.1,161.73 98.88,161.73
  BOTTOM w0.102: v1(150.66,142.98) 150.66,142.6 v2(150.02,141.96)
M_B_DQ45: length 80.2
  TOP w0.102: DIMM2.191 147.63,142.78 147.63,142.77 v1(147.86,143) ; CPU1.AP33 89.25,163.92 v1(88.95,164.22)
  L4 w0.089: v1(88.95,164.22) 89.39,164.66 90.39,164.66 90.45,164.6 91.2,164.6 91.51,164.92 92.02,164.92 92.52,164.42 93.13,164.42 94.53,163.02 99.9,163.02 100.22,162.7
  L4 w0.127: v1(147.86,143) 147.66,142.8 143.35,142.8 142.22,141.67 135.48,141.67 135.07,141.26 130.68,141.26 130.3,141.64 128.98,141.64 128.85,141.52 128.85,141.2 128.73,141.07 128.47,141.07 128.34,141.2 128.34,141.52 128.22,141.64 127.96,141.64 127.84,141.52 127.84,141.2 127.71,141.07 127.46,141.07 127.33,141.2 127.33,141.52 127.2,141.64 126.95,141.64 126.82,141.52 126.82,141.2 126.69,141.07 126.44,141.07 126.31,141.2 126.31,141.52 126.19,141.64 125.93,141.64 125.8,141.52 125.8,141.2 125.68,141.07 125.42,141.07 125.3,141.2 125.3,141.52 125.17,141.64 124.46,141.64 108.3,157.81 106.97,157.81 106.84,157.68 106.84,156.9 106.72,156.77 106.46,156.77 106.34,156.9 106.34,157.68 106.21,157.81 105.95,157.81 105.83,157.68 105.83,156.9 105.7,156.77 105.45,156.77 105.32,156.9 105.32,157.68 105.19,157.81 104.38,157.81 101.23,160.96 101.23,161.7 100.22,162.7
  BOTTOM w0.102: v1(147.86,143) v2(146.92,143)
M_B_DQ46: length 78.3
  TOP w0.102: v1(89.57,162.43) 89.57,162.3 CPU1.AR30 ; v1(147.95,139.57) 147.75,139.78 DIMM2.203
  L4 w0.089: 95.28,158.78 91.96,162.11 91.29,162.11 91.22,162.03 89.97,162.03 v1(89.57,162.43)
  L4 w0.127: 95.28,158.78 99.09,158.78 104.27,153.6 107.24,153.6 108.4,152.44 109.34,152.44 123.89,137.9 127.26,137.9 127.39,137.77 127.39,137.46 127.52,137.34 127.77,137.34 127.9,137.46 127.9,137.77 128.02,137.9 128.28,137.9 128.41,137.77 128.41,137.46 128.53,137.34 128.79,137.34 128.91,137.46 128.91,137.77 129.04,137.9 138.43,137.9 138.56,137.77 138.56,137.44 138.69,137.31 138.94,137.31 139.07,137.44 139.07,137.77 139.19,137.9 139.45,137.9 139.57,137.77 139.57,137.44 139.7,137.31 139.96,137.31 140.08,137.44 140.08,137.77 140.21,137.9 140.46,137.9 140.59,137.77 140.59,137.44 140.72,137.31 140.97,137.31 141.1,137.44 141.1,138.15 141.23,138.28 141.48,138.28 141.61,138.15 141.61,137.44 141.73,137.31 141.99,137.31 142.11,137.44 142.11,137.77 142.24,137.9 142.76,137.9 143.15,138.29 144.43,139.57 v1(147.95,139.57)
  BOTTOM w0.102: v1(147.95,139.57) v2(147.07,139.57)
M_B_DQ47: length 79.3
  TOP w0.102: v1(149.22,139.57) 148.35,138.71 147.61,138.71 147.54,138.78 DIMM2.207 ; CPU1.AP30 88.92,162.3 v1(88.92,162.43)
  L4 w0.089: 95.41,158.45 95.33,158.45 93.82,159.96 93.82,159.97 91.86,161.93 91.37,161.93 91.29,161.86 89.5,161.86 v1(88.92,162.43)
  L4 w0.127: 95.41,158.45 95.41,158.45 98.78,158.45 103.98,153.26 107.09,153.26 108.25,152.1 109.2,152.1 123.74,137.55 126.82,137.55 127.41,136.96 129.4,136.96 129.53,137.08 129.53,137.41 129.66,137.54 129.91,137.54 130.04,137.41 130.04,137.08 130.16,136.96 130.42,136.96 130.54,137.08 130.54,137.41 130.67,137.54 130.93,137.54 131.05,137.41 131.05,137.08 131.18,136.96 131.43,136.96 131.56,137.08 131.56,137.41 131.69,137.54 131.94,137.54 132.07,137.41 132.07,137.08 132.2,136.96 142.32,136.96 144.34,138.98 148.62,138.98 v1(149.22,139.57)
  BOTTOM w0.102: v1(149.22,139.57) 149.22,139.94 v2(148.84,140.32)
M_B_DQ48: length 80.3
  TOP w0.102: v1(90.22,159.69) 90.74,159.69 CPU1.AU27 ; DIMM2.225 147.86,134.28 v1(147.95,134.37)
  L4 w0.089: v1(90.22,159.69) 91.06,158.85 92.64,158.85 93.76,157.73 93.76,156.49 95.05,155.19 97.37,155.19
  L4 w0.127: 97.37,155.19 97.83,155.19 102.67,150.36 105.9,150.36 107.1,149.15 107.94,149.15 123.36,133.74 124.06,133.74 124.19,133.62 124.19,133.35 124.32,133.22 124.57,133.22 124.7,133.35 124.7,133.62 124.82,133.74 125.08,133.74 125.21,133.62 125.21,133.35 125.33,133.22 125.59,133.22 125.71,133.35 125.71,133.62 125.84,133.74 126.09,133.74 126.22,133.62 126.22,133.35 126.35,133.22 126.6,133.22 126.73,133.35 126.73,133.62 126.86,133.74 127.11,133.74 127.24,133.62 127.24,133.35 127.36,133.22 127.62,133.22 127.75,133.35 127.75,133.62 127.87,133.74 128.13,133.74 128.25,133.62 128.25,133.35 128.38,133.22 128.63,133.22 128.76,133.35 128.76,133.62 128.89,133.74 129.14,133.74 129.27,133.62 129.27,133.35 129.4,133.22 129.65,133.22 129.78,133.35 129.78,133.62 129.9,133.74 130.16,133.74 130.29,133.62 130.29,133.35 130.41,133.22 130.67,133.22 130.79,133.35 130.79,133.62 130.92,133.74 131.45,133.74 132.12,133.07 142.78,133.07 144.08,134.37 144.65,134.37 144.78,134.49 144.78,135.08 144.9,135.2 145.16,135.2 145.29,135.08 145.29,134.49 145.41,134.37 v1(147.95,134.37)
  BOTTOM w0.102: v1(147.95,134.37) v2(146.97,134.37)
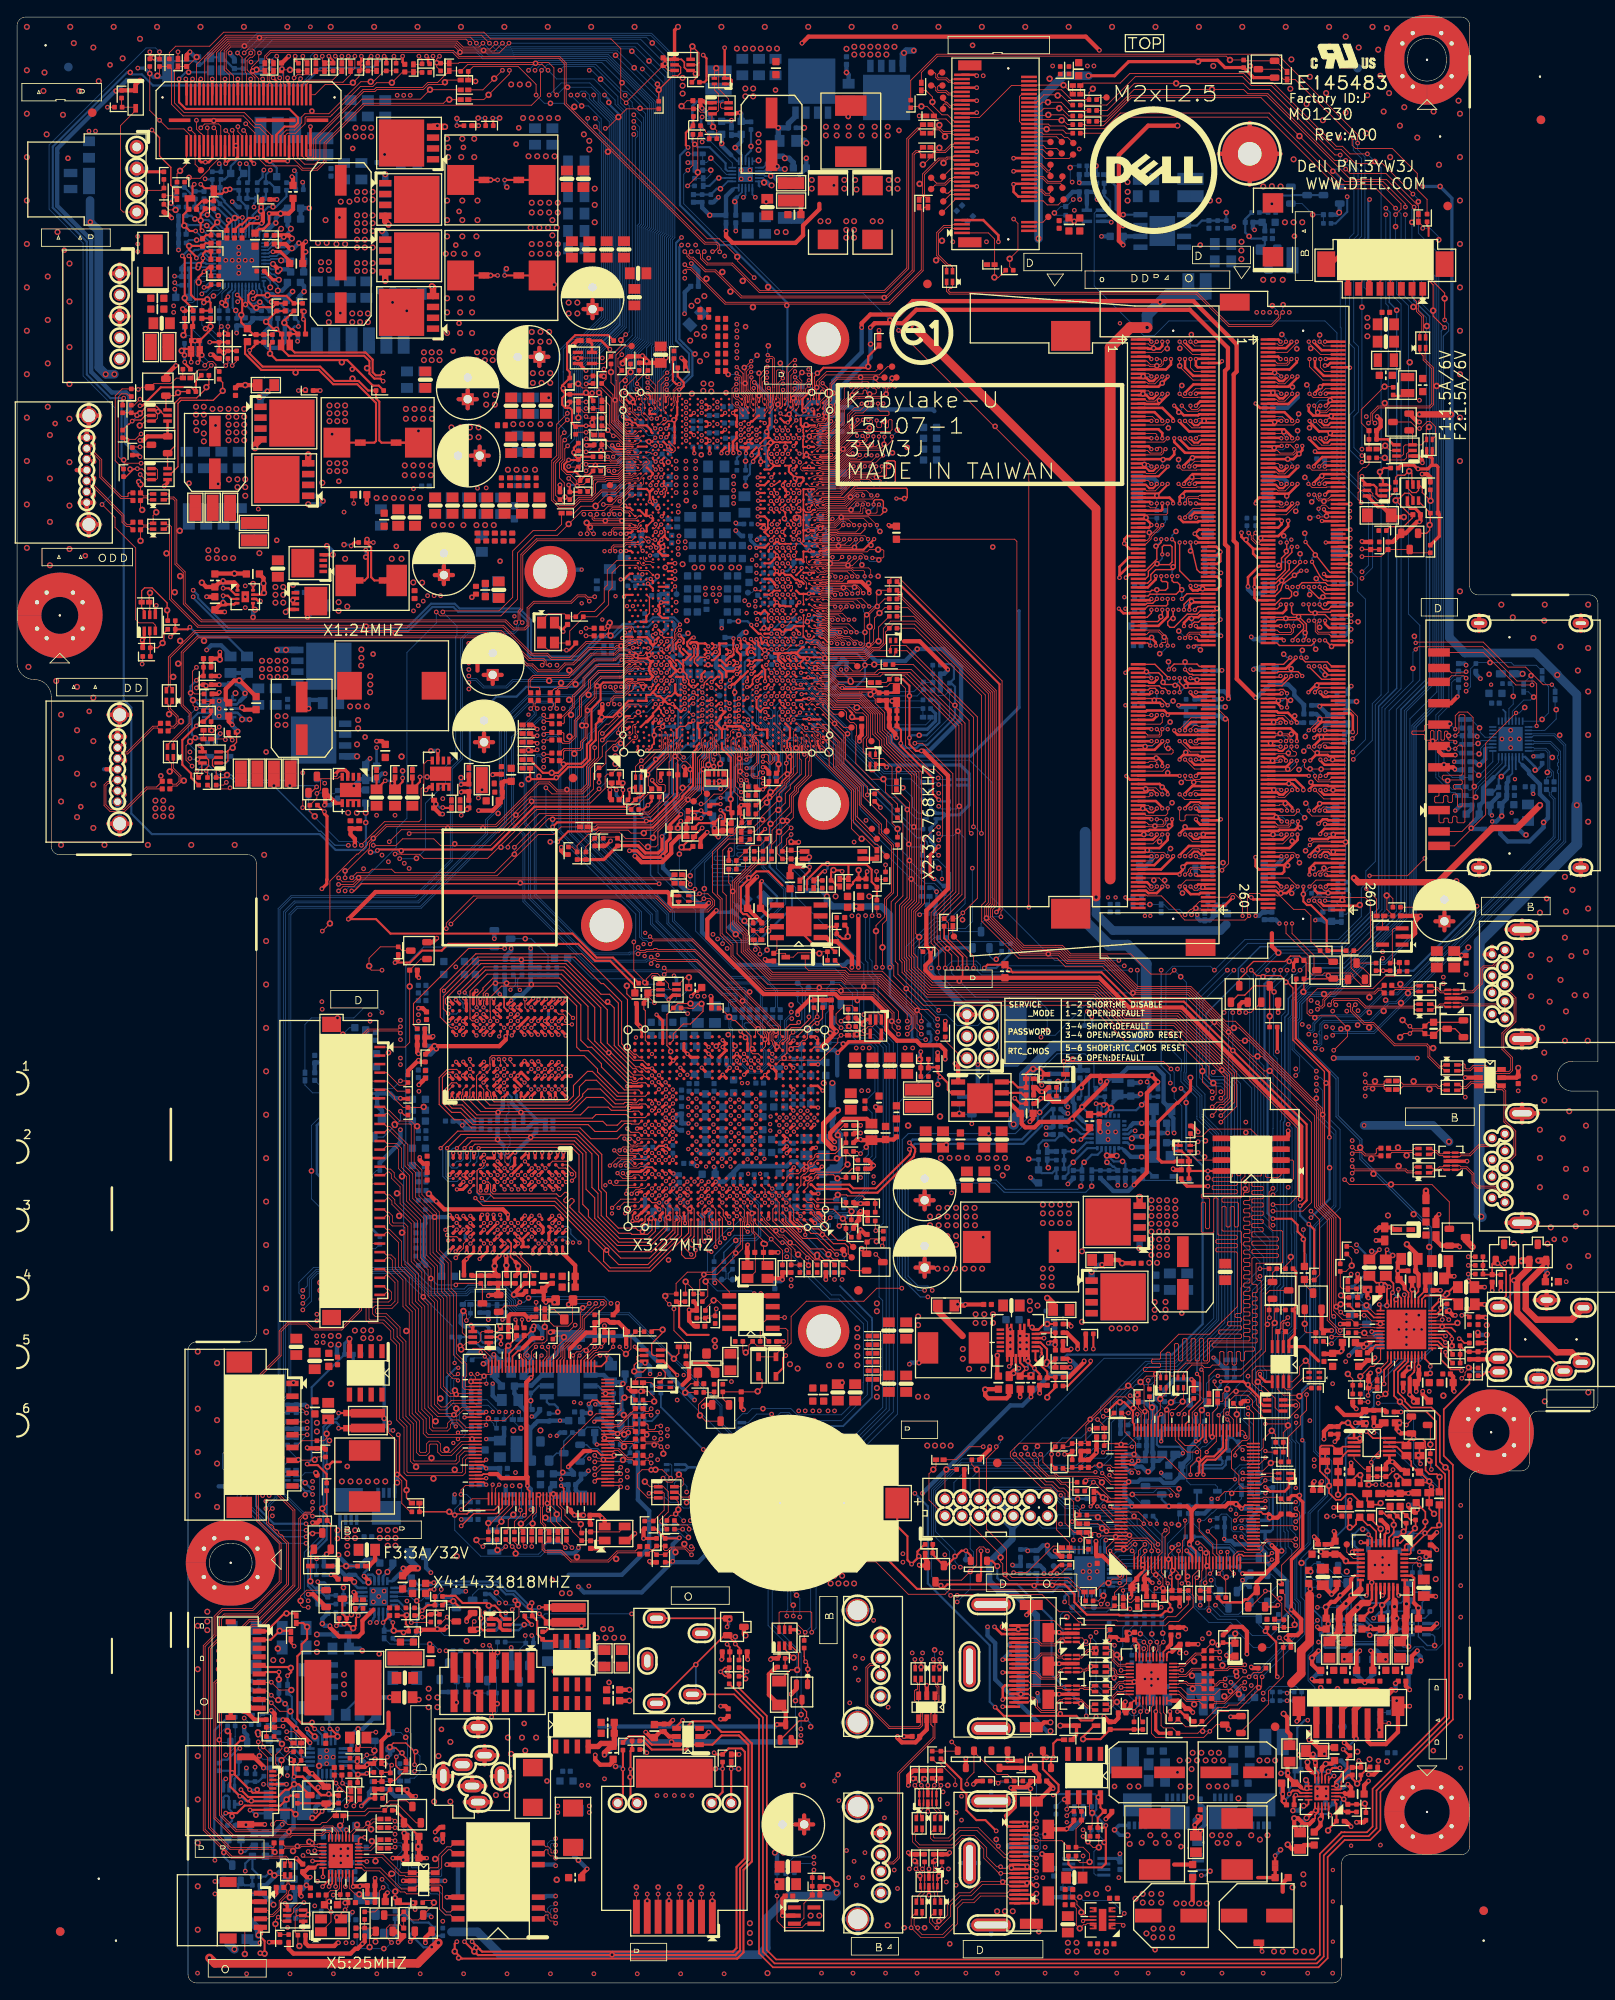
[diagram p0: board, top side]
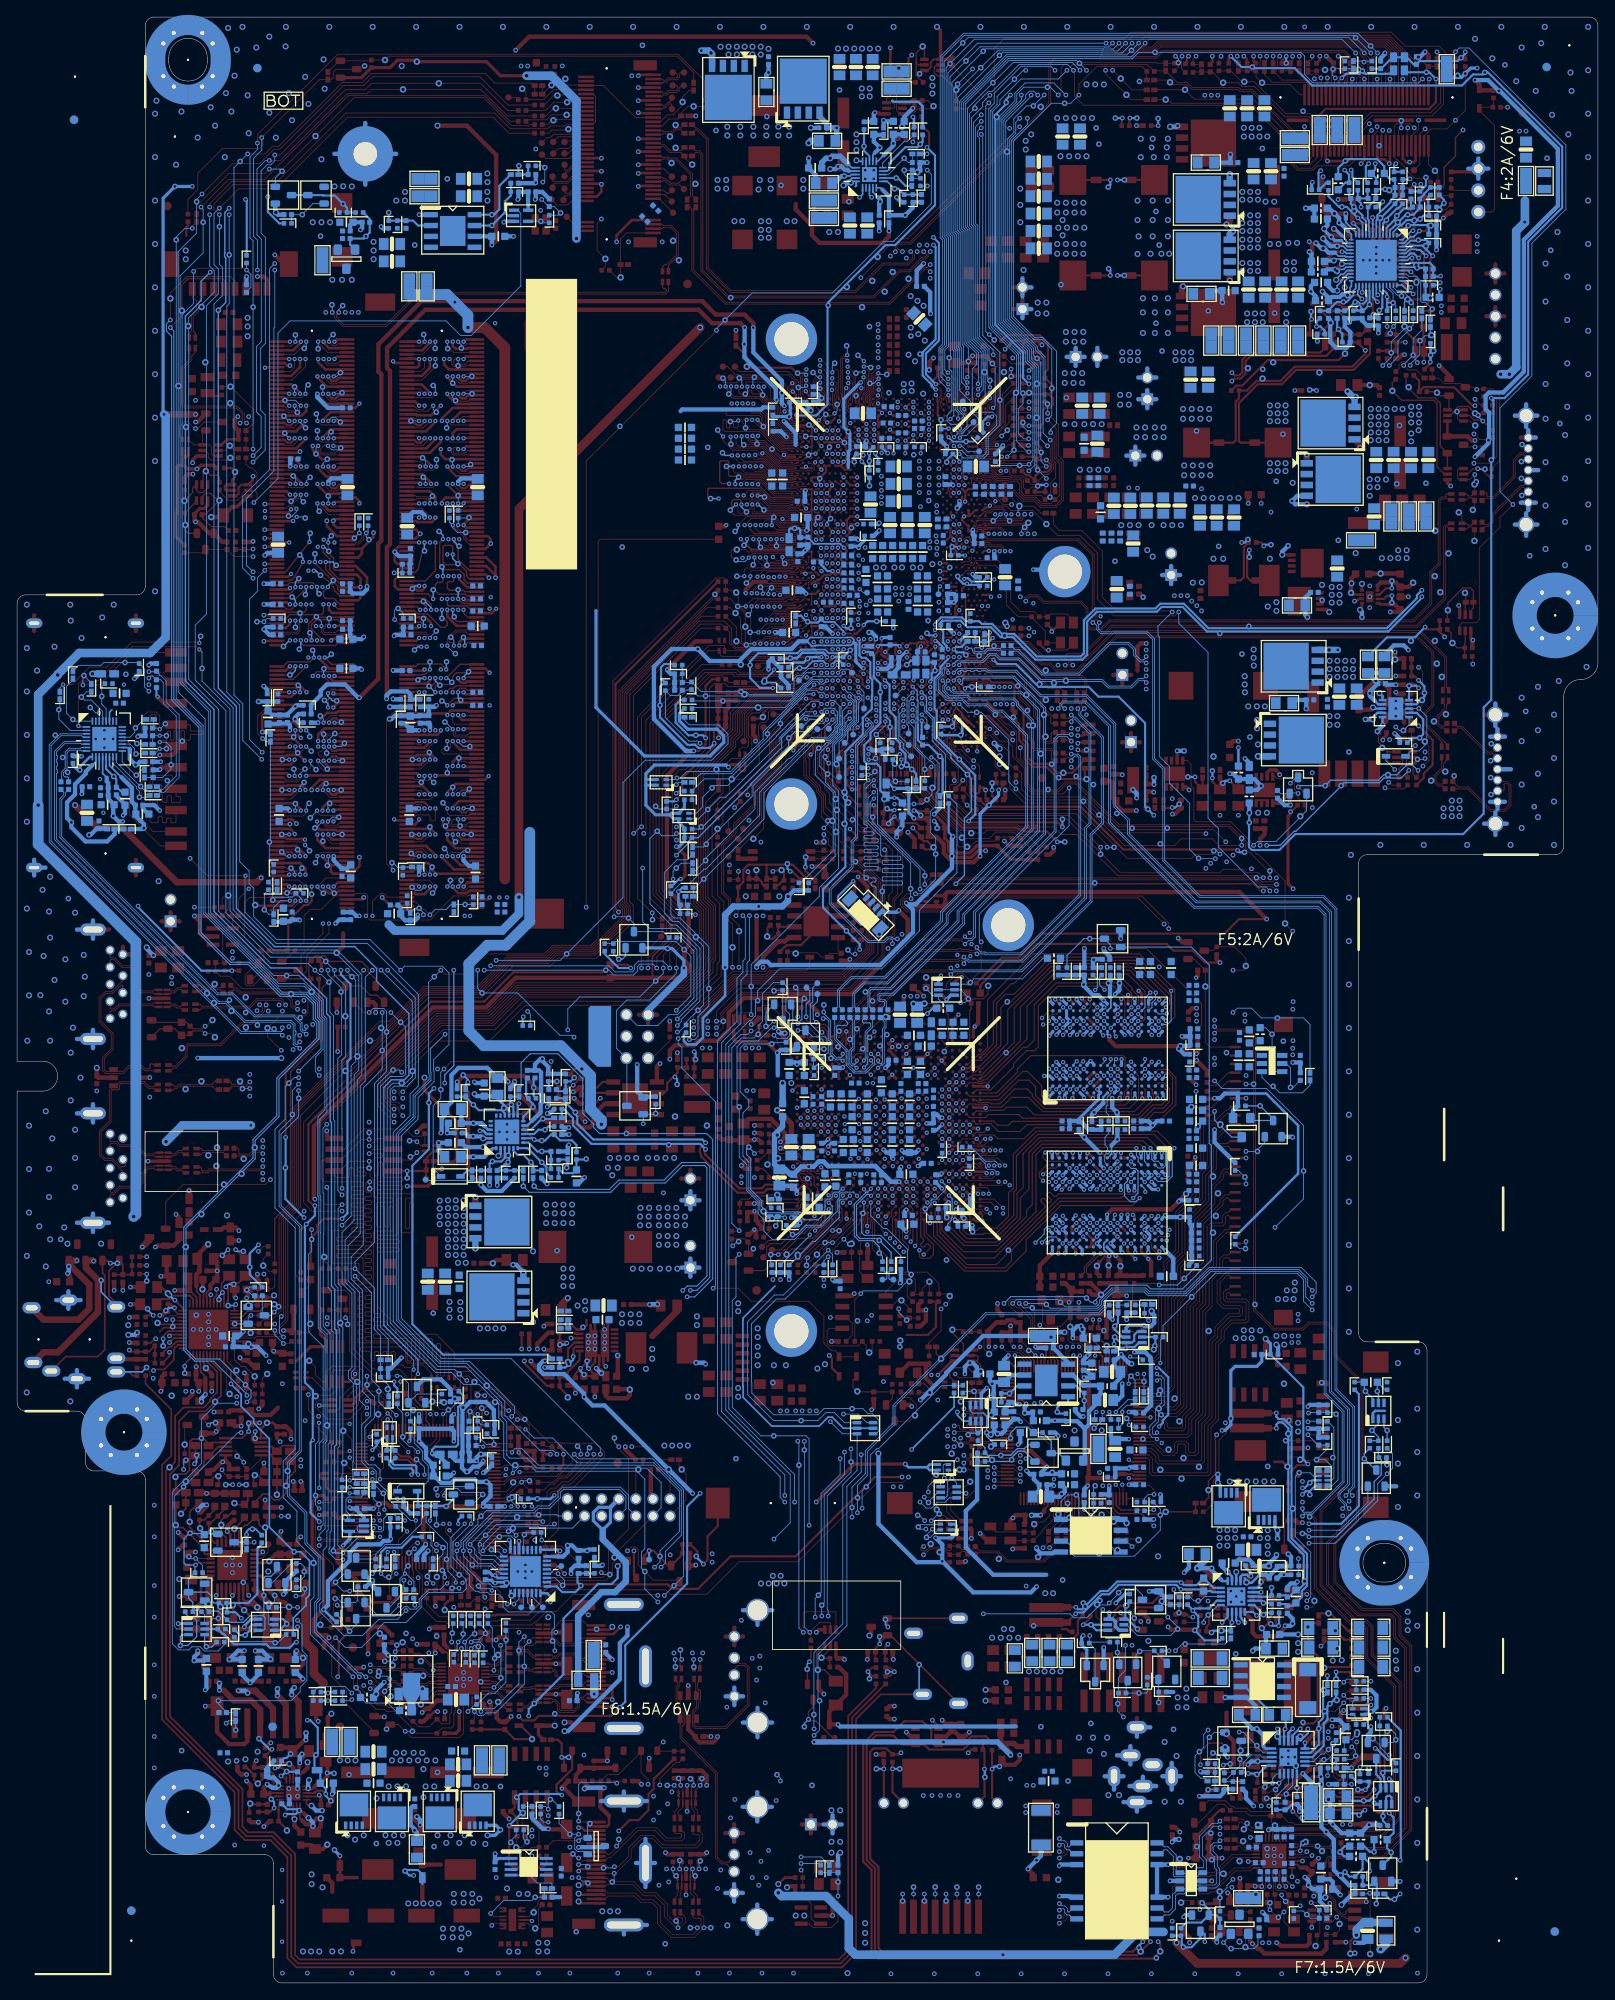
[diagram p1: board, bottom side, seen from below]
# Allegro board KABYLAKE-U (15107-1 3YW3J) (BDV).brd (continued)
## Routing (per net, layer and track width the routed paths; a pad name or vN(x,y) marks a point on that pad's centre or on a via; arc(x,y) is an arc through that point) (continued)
M_B_DQ49: length 81.4
  TOP w0.102: v1(149.89,137.16) 149.7,136.97 149.7,136.84 149.47,136.61 147.4,136.61 147.23,136.78 DIMM2.215 ; v1(90.87,160.6) 90.87,160.47 CPU1.AT27
  L4 w0.089: 96.3,156.25 95.26,156.25 94.78,156.74 94.78,157.99 93.12,159.65 92.35,159.65 91.88,160.12 91.36,160.12 v1(90.87,160.6)
  L4 w0.127: v1(149.89,137.16) 149.11,137.95 145.22,137.95 142.51,135.24 139.63,135.24 139.5,135.37 139.5,135.76 139.38,135.89 139.12,135.89 138.99,135.76 138.99,135.37 138.87,135.24 136.78,135.24 136.65,135.37 136.65,135.76 136.53,135.89 136.27,135.89 136.14,135.76 136.14,135.37 136.02,135.24 132.5,135.24 132.1,135.65 126.96,135.65 126.29,136.32 125.86,136.32 125.74,136.19 125.74,135.79 125.61,135.66 125.35,135.66 125.23,135.79 125.23,136.19 125.1,136.32 124.85,136.32 124.72,136.19 124.72,135.79 124.59,135.66 124.34,135.66 124.21,135.79 124.21,136.19 124.08,136.32 123.15,136.32 108.64,150.83 107.79,150.83 106.59,152.03 103.4,152.03 99.18,156.25 96.3,156.25
  BOTTOM w0.102: v1(149.89,137.16) 149.89,137.11 v2(150.68,136.32)
M_B_DQ50: length 79.2
  TOP w0.102: v1(89.57,158.78) 90.09,158.78 CPU1.AT25 ; DIMM2.228 153.54,133.53 153.51,133.5 151.7,133.5 151.32,133.13 v1(151.29,133.13)
  L4 w0.089: v1(89.57,158.78) 89.88,158.47 92.41,158.47 93.26,157.62 93.26,156.46 95.06,154.65 97.23,154.65
  L4 w0.127: v1(151.29,133.13) 151.26,133.1 144.08,133.1 143.3,132.32 123.81,132.32 107.66,148.47 106.81,148.47 105.61,149.67 102.28,149.67 97.3,154.65 97.23,154.65
  BOTTOM w0.102: v2(150.78,132.46) 150.78,132.62 v1(151.29,133.13)
M_B_DQ51: length 78.6
  TOP w0.102: CPU1.AU25 91.35,159.23 91.6,159.49 91.6,159.64 v1(91.6,159.64) ; v1(148.62,137.16) 148.62,137.37 148.15,137.85 147.77,137.85 147.7,137.77 147.7,137.78 DIMM2.211
  L4 w0.089: 96.3,156.04 95.23,156.04 94.52,156.74 94.52,157.86 92.93,159.46 91.78,159.46 v1(91.6,159.64)
  L4 w0.127: 96.3,156.04 98.88,156.04 103.23,151.69 106.45,151.69 107.65,150.49 108.5,150.49 123.68,135.31 124.17,135.31 124.4,135.08 124.68,135.08 124.91,135.31 125.19,135.31 125.42,135.08 125.7,135.08 125.93,135.31 126.21,135.31 126.43,135.08 126.71,135.08 126.94,135.31 127.22,135.31 127.45,135.08 127.73,135.08 127.96,135.31 128.24,135.31 128.47,135.08 128.75,135.08 128.97,135.31 129.25,135.31 129.48,135.08 129.76,135.08 129.99,135.31 130.27,135.31 130.5,135.08 130.78,135.08 131.01,135.31 131.96,135.31 132.36,134.9 134.99,134.9 135.12,134.77 135.12,134.65 135.25,134.52 135.5,134.52 135.63,134.65 135.63,134.77 135.76,134.9 138.73,134.9 138.86,134.77 138.86,134.54 138.99,134.42 139.24,134.42 139.37,134.54 139.37,134.77 139.5,134.9 139.75,134.9 139.88,134.77 139.88,134.54 140,134.42 140.26,134.42 140.39,134.54 140.39,134.77 140.51,134.9 140.77,134.9 140.89,134.77 140.89,134.54 141.02,134.42 141.27,134.42 141.4,134.54 141.4,134.77 141.53,134.9 142.68,134.9 145.38,137.6 145.56,137.6 145.69,137.48 145.69,137.26 145.82,137.13 146.07,137.13 146.2,137.26 146.2,137.48 146.33,137.6 146.58,137.6 146.71,137.48 146.71,137.26 146.83,137.13 147.09,137.13 147.21,137.26 147.21,137.48 147.34,137.6 148.18,137.6 v1(148.62,137.16)
  BOTTOM w0.102: v1(148.62,137.16) 148.62,137.79 v2(148.42,138)
M_B_DQ52: length 81.6
  TOP w0.102: CPU1.AP27 89.25,160.21 88.92,160.54 v1(88.92,160.6) ; v1(151.16,137.16) 151.16,136.91 151.54,136.53 DIMM2.216
  L4 w0.089: 95.54,157.61 93.36,159.78 93.36,159.92 92.34,160.94 91.15,160.94 91.08,161 89.32,161 v1(88.92,160.6)
  L4 w0.127: v1(151.16,137.16) 151.16,137.9 150.77,138.29 145,138.29 142.29,135.59 140.77,135.59 140.1,136.26 138.73,136.26 138.06,135.59 137.78,135.59 137.1,136.26 135.9,136.26 135.23,135.59 132.65,135.59 132.24,135.99 127.11,135.99 126.43,136.66 123.29,136.66 108.78,151.17 107.93,151.17 106.73,152.37 103.61,152.37 98.76,157.23 95.92,157.23 95.54,157.61
  BOTTOM w0.102: v1(151.16,137.16) 151.16,137.67 v2(150.82,138.01)
M_B_DQ53: length 81.6
  TOP w0.102: CPU1.AN27 88.27,160.47 v1(88.27,160.6) ; v1(152.43,137.16) 152.86,137.59 153.25,137.59 153.31,137.52 DIMM2.212
  L4 w0.089: v1(88.27,160.6) 88.25,160.6 88.12,160.73 88.12,160.99 88.25,161.12 89.09,161.12 89.15,161.18 91.31,161.18 91.38,161.12 92.42,161.12 93.63,159.9 93.63,159.89 95.76,157.77
  L4 w0.127: v1(152.43,137.16) 152.76,137.49 152.76,138.3 152.43,138.63 144.86,138.63 142.82,136.6 132.57,136.6 132.39,136.42 127.16,136.42 126.58,137.01 123.53,137.01 109.02,151.52 108.08,151.52 106.87,152.72 103.73,152.72 98.84,157.6 95.92,157.6 95.76,157.77
  BOTTOM w0.102: v1(152.43,137.16) v2(152.43,137.97)
M_B_DQ54: length 81.2
  TOP w0.102: v1(88.27,159.69) 88.27,159.56 CPU1.AN25 ; DIMM2.224 153.31,134.53 v1(153.16,134.37)
  L4 w0.089: v1(88.27,159.69) 88.27,159.51 89.52,158.26 91.69,158.26 92.27,157.68 92.27,157.48 93.08,156.66 93.08,156.39 95.11,154.36 95.26,154.36
  L4 w0.127: v1(153.16,134.37) 151.47,132.68 144.15,132.68 143.44,131.98 138.87,131.98 138.23,131.34 132.57,131.34 131.94,131.98 123.66,131.98 107.52,148.13 106.67,148.13 105.47,149.33 102.12,149.33 97.09,154.36 95.26,154.36
  BOTTOM w0.102: v1(153.16,134.37) v2(154.03,134.37)
M_B_DQ55: length 80.4
  TOP w0.102: DIMM2.229 148.13,133.28 v1(149.22,134.37) ; CPU1.AP25 88.92,159.56 v1(88.92,159.69)
  L4 w0.089: v1(88.92,159.69) 89.44,159.18 90.47,159.18 90.98,158.66 92.58,158.66 93.52,157.72 93.52,156.45 95.03,154.94 97.29,154.94
  L4 w0.127: v1(149.22,134.37) 148.29,133.44 148.05,133.44 147.92,133.57 147.92,133.81 147.8,133.93 147.54,133.93 147.42,133.81 147.42,133.57 147.29,133.44 147.04,133.44 146.91,133.57 146.91,133.81 146.78,133.93 146.53,133.93 146.4,133.81 146.4,133.57 146.27,133.44 146.02,133.44 145.89,133.57 145.89,133.81 145.77,133.93 145.51,133.93 145.38,133.81 145.38,133.57 145.26,133.44 145,133.44 144.88,133.57 144.88,133.81 144.75,133.93 144.5,133.93 144.37,133.81 144.37,133.57 144.24,133.44 143.78,133.44 143.01,132.66 123.95,132.66 107.8,148.81 106.95,148.81 105.75,150.01 102.53,150.01 97.6,154.94 97.29,154.94
  BOTTOM w0.102: v1(149.22,134.37) v2(149.22,133.58)
M_B_DQ56: length 82.7
  TOP w0.102: v1(153.16,131.83) 153.46,131.53 DIMM2.236 ; v1(90.87,156.95) 90.55,157.27 CPU1.AT22
  L4 w0.089: v1(90.87,156.95) 91.02,156.95 91.52,156.45 91.85,156.45 95.63,152.67
  L4 w0.127: 95.63,152.67 95.77,152.53 96.91,152.53 101.76,147.68 104.86,147.68 106.17,146.37 107.06,146.37 124.24,129.18 124.84,129.18 124.97,129.31 124.97,129.59 125.09,129.72 125.35,129.72 125.48,129.59 125.48,129.31 125.6,129.18 125.86,129.18 125.98,129.31 125.98,129.59 126.11,129.72 126.36,129.72 126.49,129.59 126.49,129.31 126.62,129.18 126.87,129.18 127,129.31 127,129.59 127.13,129.72 127.38,129.72 127.51,129.59 127.51,129.31 127.63,129.18 127.89,129.18 128.02,129.31 128.02,129.59 128.14,129.72 128.4,129.72 128.52,129.59 128.52,129.31 128.65,129.18 128.9,129.18 129.03,129.31 129.03,129.59 129.16,129.72 129.41,129.72 129.54,129.59 129.54,129.31 129.67,129.18 129.92,129.18 130.05,129.31 130.05,129.59 130.17,129.72 130.43,129.72 130.56,129.59 130.56,129.31 130.68,129.18 143.41,129.18 143.87,129.64 150.6,129.64 151.07,130.11 151.44,130.11 v1(153.16,131.83)
  BOTTOM w0.102: v2(154.03,132.33) 153.53,131.83 v1(153.16,131.83)
M_B_DQ57: length 82
  TOP w0.102: v1(90.87,157.86) 90.87,157.61 91.08,157.4 CPU1.AU22 ; v1(148.58,131.83) 148.03,131.28 DIMM2.237
  L4 w0.089: v1(90.87,157.86) 91.28,157.45 92.02,157.45 92.49,156.99 92.49,156.73 95.11,154.1 95.23,154.1
  L4 w0.127: v1(148.58,131.83) 147.97,131.22 147.42,131.22 147.29,131.34 147.29,131.93 147.17,132.05 146.91,132.05 146.78,131.93 146.78,131.34 146.66,131.22 146.4,131.22 146.28,131.34 146.28,131.93 146.15,132.05 145.9,132.05 145.77,131.93 145.77,131.34 145.64,131.22 140.01,131.22 139.61,130.81 131.83,130.81 131.22,131.42 129.86,131.42 129.73,131.29 129.73,130.94 129.6,130.81 129.35,130.81 129.22,130.94 129.22,131.29 129.09,131.42 128.84,131.42 128.71,131.29 128.71,130.94 128.59,130.81 128.33,130.81 128.2,130.94 128.2,131.29 128.08,131.42 127.82,131.42 127.7,131.29 127.7,130.94 127.57,130.81 127.32,130.81 127.19,130.94 127.19,131.29 127.06,131.42 126.81,131.42 126.68,131.29 126.68,130.94 126.55,130.81 126.3,130.81 126.17,130.94 126.17,131.29 126.05,131.42 125.79,131.42 125.66,131.29 125.66,130.94 125.54,130.81 125.28,130.81 125.16,130.94 125.16,131.29 125.03,131.42 124.78,131.42 124.65,131.29 124.65,130.94 124.52,130.81 124.27,130.81 124.14,130.94 124.14,131.29 124.01,131.42 123.46,131.42 107.37,147.51 106.49,147.51 105.29,148.71 102.15,148.71 97.62,153.24 96.1,153.24 95.23,154.1
  BOTTOM w0.102: v1(148.58,131.83) 148.58,130.85 v2(148.7,130.73)
M_B_DQ58: length 81
  TOP w0.102: CPU1.AU21 91.4,156.49 v1(91.78,156.87) ; DIMM2.232 153.68,132.53 153.56,132.64 152.7,132.64 v1(151.89,131.83)
  L4 w0.089: v1(91.78,156.87) 91.79,156.87 95.92,152.74
  L4 w0.127: 95.92,152.74 97.14,152.74 101.87,148.02 105,148.02 106.2,146.82 107.09,146.82 123.78,130.12 131.15,130.12 131.27,130 131.27,129.69 131.4,129.57 131.66,129.57 131.78,129.69 131.78,130 131.91,130.12 132.16,130.12 132.29,130 132.29,129.69 132.42,129.57 132.67,129.57 132.8,129.69 132.8,130 132.93,130.12 133.18,130.12 133.31,130 133.31,129.69 133.43,129.57 133.69,129.57 133.81,129.69 133.81,130 133.94,130.12 134.2,130.12 134.32,130 134.32,129.69 134.45,129.57 134.7,129.57 134.83,129.69 134.83,130 134.96,130.12 138.67,130.12 138.79,130 138.79,129.74 138.92,129.62 139.18,129.62 139.3,129.74 139.3,130 139.43,130.12 139.86,130.12 140.32,129.67 143.41,129.67 143.73,129.98 150.04,129.98 v1(151.89,131.83)
  BOTTOM w0.102: v2(152.18,132.59) 151.89,132.29 v1(151.89,131.83)
M_B_DQ59: length 82
  TOP w0.102: DIMM2.245 148.85,129.28 v1(149.85,128.27) ; v1(89.57,156.03) 90.09,156.03 CPU1.AT21
  L4 w0.089: 93.91,152.88 93.78,153.02 93.78,153.08 91.14,155.71 89.89,155.71 v1(89.57,156.03)
  L4 w0.127: v1(149.85,128.27) 149.07,127.48 144.1,127.48 143.66,127.04 143.66,126.86 143.99,126.53 143.99,126.35 143.81,126.17 143.63,126.17 143.3,126.5 143.12,126.5 142.77,126.15 141.75,126.15 141.63,126.28 141.63,126.77 141.5,126.9 141.25,126.9 141.12,126.77 141.12,126.28 140.99,126.15 124.9,126.15 107.92,143.13 103.67,143.13 93.91,152.88
  BOTTOM w0.102: v1(149.85,128.27) 149.85,128.19 149.85,128.17 v2(149.17,127.48)
M_B_DQ60: length 84.2
  TOP w0.102: CPU1.AN22 88.92,157.08 v1(88.92,156.95) ; v1(148.58,128.27) 148.15,127.84 147.77,127.84 147.33,128.28 DIMM2.249
  L4 w0.089: v1(88.92,156.95) 89.4,156.46 89.76,156.46 90.32,155.9 91.38,155.9 95.59,151.69
  L4 w0.127: v1(148.58,128.27) 148.14,127.83 147.44,127.83 147.31,127.95 147.31,128.17 147.18,128.3 146.93,128.3 146.8,128.17 146.8,127.95 146.67,127.83 146.42,127.83 146.29,127.95 146.29,128.17 146.17,128.3 145.91,128.3 145.78,128.17 145.78,127.95 145.66,127.83 145.4,127.83 145.28,127.95 145.28,128.17 145.15,128.3 144.9,128.3 144.77,128.17 144.77,127.95 144.64,127.83 143.4,127.83 143.27,127.7 143.27,127.03 143.14,126.9 142.89,126.9 142.76,127.03 142.76,127.7 142.63,127.83 141.74,127.83 141.61,127.7 141.61,127.41 141.48,127.28 141.23,127.28 141.1,127.41 141.1,127.7 140.98,127.83 140.15,127.83 139.91,127.58 139.91,127.4 140.45,126.86 140.45,126.68 140.27,126.5 140.09,126.5 139.55,127.04 139.37,127.04 138.82,126.49 131.06,126.49 130.93,126.62 130.93,126.97 130.8,127.1 130.55,127.1 130.42,126.97 130.42,126.62 130.29,126.49 125.05,126.49 108.03,143.51 103.77,143.51 95.59,151.69
  BOTTOM w0.102: v2(147.89,127.48) 148.58,128.18 v1(148.58,128.27)
M_B_DQ61: length 83.4
  TOP w0.102: DIMM2.233 149.4,132.28 v1(149.85,131.83) ; v1(88.92,157.86) 89.25,157.54 CPU1.AP22
  L4 w0.089: v1(88.92,157.86) 89.42,157.37 91.05,157.37 91.14,157.27 91.96,157.27 92.19,157.03 92.19,156.76 95.99,152.96
  L4 w0.127: 95.99,152.96 97.41,152.96 102.01,148.36 105.15,148.36 106.34,147.17 107.23,147.17 123.93,130.47 130.16,130.47 130.29,130.59 130.29,130.91 130.41,131.04 130.67,131.04 130.8,130.91 130.8,130.59 130.92,130.47 139.75,130.47 140.15,130.87 141.6,130.87 141.73,130.75 141.73,130.53 141.86,130.4 142.11,130.4 142.24,130.53 142.24,130.75 142.36,130.87 142.62,130.87 142.74,130.75 142.74,130.53 142.87,130.4 143.13,130.4 143.25,130.53 143.25,130.75 143.38,130.87 143.63,130.87 143.76,130.75 143.76,130.53 143.89,130.4 144.14,130.4 144.27,130.53 144.27,130.75 144.4,130.87 144.65,130.87 144.78,130.75 144.78,130.53 144.9,130.4 145.16,130.4 145.28,130.53 145.28,130.75 145.41,130.87 145.67,130.87 145.79,130.75 145.79,130.53 145.92,130.4 146.17,130.4 146.3,130.53 146.3,130.75 146.43,130.87 146.68,130.87 146.81,130.75 146.81,130.53 146.94,130.4 147.19,130.4 147.32,130.53 147.32,130.75 147.44,130.87 147.7,130.87 147.82,130.75 147.82,130.53 147.95,130.4 148.21,130.4 148.33,130.53 148.33,130.75 148.46,130.87 148.9,130.87 v1(149.85,131.83)
  BOTTOM w0.102: v1(149.85,131.83) 149.85,131.28 v2(150.07,131.06)
M_B_DQ62: length 82.9
  TOP w0.102: v1(88.92,156.03) 88.92,156.16 CPU1.AP21 ; v1(151.25,128.27) 152.01,129.03 DIMM2.246
  L4 w0.089: 93.51,152.78 93.51,153.1 91.08,155.52 89.44,155.52 v1(88.92,156.03)
  L4 w0.127: 93.51,152.78 103.54,142.75 107.75,142.75 124.7,125.81 145.25,125.81 145.56,126.11 145.56,126.29 145.12,126.73 145.12,126.91 145.3,127.08 145.48,127.08 145.91,126.65 146.09,126.65 146.58,127.14 150.12,127.14 v1(151.25,128.27)
  BOTTOM w0.102: v2(150.53,127.38) 151.25,128.1 v1(151.25,128.27)
M_B_DQ63: length 84.2
  TOP w0.102: CPU1.AN21 88.6,156.55 88.27,156.87 v1(88.27,156.95) ; DIMM2.250 153.55,128.03 153.36,127.84 152.95,127.84 v1(152.52,128.27)
  L4 w0.127: v1(88.27,156.95) 87.85,156.53 87.85,155.77 88.07,155.55 88.5,155.55 89.36,154.69 91.64,154.69 93.25,153.07 93.25,152.55 100.4,145.4 100.4,145.4 103.4,142.41 107.61,142.41 124.55,125.46 145.39,125.46 146.72,126.8 150.27,126.8 150.88,127.4 151.65,127.4 152.51,128.27 v1(152.52,128.27)
  BOTTOM w0.102: v1(152.52,128.27) 152.53,128.27 153.27,127.53 v2(153.42,127.53)
M_B_DQS_DN0: length 91.6
  TOP w0.102: v1(85.6,181.74) 85.93,182.06 CPU1.AH66 ; DIMM2.32 153.76,184.53 153.16,183.93 152.33,183.93 152.18,184.07 152.18,184.28 152.43,184.53 v1(152.52,184.53)
  L4 w0.127: v1(152.52,184.53) 151.76,185.29 147.56,185.29 147.36,185.09 146.08,185.09 145.46,185.71 144.01,185.71 142.23,187.49 142.23,188.06 141.79,188.49 141.23,188.49 138.95,190.77 132.01,190.77 129.1,193.68 128.93,193.68 128.28,194.32 111.07,194.32 109.8,195.59 100.67,195.59 100.54,195.72 100.54,196.45 100.26,196.74 99.65,196.74 99.37,196.45 99.37,195.72 99.24,195.59 98.86,195.59 98.74,195.72 98.74,196.45 98.45,196.74 92.69,196.74 89.59,193.64 89.59,189.34 90.07,188.87 90.07,186.17 89.82,185.93 88.87,185.93 88.31,185.37 87.99,185.37 86.07,183.44 86.07,182.26 85.79,181.98 85.79,181.92 v1(85.6,181.74)
  BOTTOM w0.102: v2(152.2,183.74) 152.2,183.85 152.52,184.16 v1(152.52,184.53)
M_B_DQS_DN1: length 91.5
  TOP w0.089: v1(84.17,187.7) 84.35,187.87 84.51,187.87 84.58,187.81 84.58,186.01 85.11,185.48 85.11,185.24 85.06,185.09 85.06,184.89 85.12,184.69 85.12,184.38 CPU1.AG69
  TOP w0.102: v1(148.5,189.99) 148.72,189.76 148.72,189.64 148.58,189.49 147.48,189.49 147.2,189.78 DIMM2.11
  L4 w0.127: v1(84.17,187.7) 84.35,187.7 84.63,187.97 84.63,188.37 85.38,189.12 85.38,194.97 91.09,200.69 102.79,200.69 102.91,200.56 102.91,200.01 103.2,199.73 103.8,199.73 104.08,200.01 104.08,200.56 104.21,200.69 104.59,200.69 104.72,200.56 104.72,200.01 105,199.73 105.6,199.73 105.88,200.01 105.88,200.56 106.01,200.69 106.39,200.69 106.52,200.56 106.52,200.01 106.8,199.73 107.4,199.73 107.69,200.01 107.69,200.56 107.81,200.69 108.29,200.69 109.08,199.9 113.98,199.9 114.59,199.29 129.07,199.29 130.96,197.4 138.47,197.4 145.43,190.44 148.31,190.44 148.5,190.25 v1(148.5,189.99)
  BOTTOM w0.102: v1(84.17,187.7) 84.72,187.15 v2(85.2,187.15)
M_B_DQS_DN2: length 81.1
  TOP w0.102: v1(148.62,179.83) 148.75,179.96 149,179.96 149.55,179.41 149.55,179.25 149.3,178.99 147.8,178.99 147.51,179.28 DIMM2.53 ; v1(90.22,181.64) 90.15,181.64 89.9,181.89 CPU1.AR66
  L4 w0.089: v1(90.22,181.64) 90.22,181.34 90.33,181.23 90.46,181.23 90.83,181.59 90.83,182.35 90.59,182.58 90.59,183.19 90.91,183.51 91.21,183.51 91.41,183.7
  L4 w0.127: 91.41,183.7 92.51,184.8 93.74,184.8 97.3,188.36 101.5,188.36 102.62,189.47 111.6,189.47 112.44,188.63 117.81,188.63 117.94,188.76 117.94,189.54 118.23,189.83 118.83,189.83 119.11,189.54 119.11,188.76 119.24,188.63 119.62,188.63 119.75,188.76 119.75,189.54 120.03,189.83 120.63,189.83 120.91,189.54 120.91,188.76 121.04,188.63 121.42,188.63 121.55,188.76 121.55,189.54 121.83,189.83 122.43,189.83 122.72,189.54 122.72,188.76 122.84,188.63 128.34,188.63 131.61,185.37 138.19,185.37 144.2,179.36 148.66,179.36 148.75,179.45 148.75,179.71 v1(148.62,179.83)
  BOTTOM w0.102: v2(147.12,179.6) 147.35,179.37 148.17,179.37 v1(148.62,179.83)
M_B_DQS_DN3: length 74.7
  TOP w0.102: v1(152.43,174.12) 152.31,173.99 152.31,173.74 152.43,173.62 153.41,173.62 153.82,174.03 DIMM2.74 ; CPU1.AR61 89.9,179.22 v1(89.57,178.89)
  L4 w0.089: v1(89.57,178.89) 89.97,178.49 90.39,178.49 90.46,178.57 91.12,178.57 91.16,178.52 92.82,178.52 94.52,180.22 95.19,180.22 95.58,180.61 95.58,180.94 98.24,183.6 98.79,183.6 98.83,183.64 98.84,183.64
  L4 w0.127: 98.84,183.64 100.86,183.64 101.03,183.47 105.1,183.47 105.26,183.64 126.88,183.64 131.51,179.01 138.66,179.01 143.3,174.37 150.27,174.37 150.83,174.93 152.1,174.93 152.35,174.68 152.35,174.2 v1(152.43,174.12)
  BOTTOM w0.102: v2(152.94,173.34) 152.94,173.36 152.43,173.86 v1(152.43,174.12)
M_B_DQS_DN4: length 77.8
  TOP w0.102: v1(149.13,145.29) 148.97,145.45 148.97,145.88 148.71,146.13 147.31,146.13 147.17,146.28 DIMM2.177 ; CPU1.AT38 90.55,166.76 v1(90.28,167.03)
  L4 w0.089: 103.33,162.07 103.32,162.09 103.26,162.09 102.78,162.57 100.18,165.17 94.59,165.17 93.01,166.75 91.26,166.75 91.07,166.55 90.67,166.55 90.28,166.95 v1(90.28,167.03)
  L4 w0.127: v1(149.13,145.29) 149.02,145.4 149.02,145.78 148.7,146.1 142.61,146.1 142.32,145.82 142.32,144.91 142.2,144.78 141.82,144.78 141.69,144.91 141.69,145.78 141.41,146.06 140.77,146.06 140.48,145.78 140.48,144.87 139.99,144.37 139.5,144.37 139.28,144.16 135.19,144.16 134.98,143.95 125.71,143.95 109.35,160.31 104.64,160.31 103.69,161.26 103.69,161.71 103.33,162.07
  BOTTOM w0.102: v1(149.13,145.29) v2(149.13,146.1)
M_B_DQS_DN5: length 78.6
  TOP w0.102: CPU1.AT32 90.75,163.09 90.75,163.41 90.66,163.5 90.37,163.5 v1(90.25,163.39) ; v1(152.52,141.22) 152.27,140.97 152.27,140.81 152.33,140.74 153.54,140.74 153.82,141.03 DIMM2.198
  L4 w0.089: 93.31,162.85 93.3,162.86 93.24,162.86 92.97,163.14 91.82,163.14 91.75,163.07 91.41,163.07 91.16,163.32 90.31,163.32 v1(90.25,163.39)
  L4 w0.127: 93.31,162.85 93.4,162.76 93.76,162.4 95.63,160.53 98.92,160.53 104.35,155.09 108.8,155.09 124.47,139.42 131.23,139.42 131.59,139.78 142.53,139.78 144,141.24 150.16,141.24 150.87,141.95 151.8,141.95 v1(152.52,141.22)
  BOTTOM w0.102: v1(152.52,141.22) 152.52,141.92 v2(152.61,142.01)
M_B_DQS_DN6: length 80.6
  TOP w0.102: v1(89.57,159.69) 89.9,159.37 CPU1.AR25 ; v1(148.62,135.89) 148.84,135.67 148.84,135.52 148.76,135.45 147.55,135.45 147.22,135.78 DIMM2.219
  L4 w0.089: 96.37,155.47 96.35,155.47 96.31,155.51 94.99,155.51 94.08,156.42 94.08,157.79 92.82,159.04 91.36,159.04 90.93,159.47 90.93,159.71 90.58,160.06 90.44,160.2 89.37,160.2 89.29,160.12 89.29,159.97 v1(89.57,159.69)
  L4 w0.127: 96.37,155.47 98.31,155.47 102.89,150.89 106.12,150.89 107.32,149.69 108.17,149.69 123.58,134.28 131.67,134.28 132.33,133.62 142.54,133.62 145.25,136.33 145.82,136.33 145.95,136.21 145.95,135.4 146.23,135.12 146.84,135.12 147.12,135.4 147.12,136.21 147.25,136.33 148.56,136.33 148.75,136.14 148.75,136.02 v1(148.62,135.89)
  BOTTOM w0.102: v1(148.62,135.89) 148.12,136.4 v2(147.35,136.4)
M_B_DQS_DN7: length 82.1
  TOP w0.102: DIMM2.240 153.54,130.53 153.33,130.31 152.86,130.31 152.65,130.1 152.32,130.1 v1(151.89,129.67) ; v1(90.22,156.95) 90.22,157.28 90.1,157.4 CPU1.AR22
  L4 w0.089: v1(90.22,156.95) 90.08,156.8 90.08,156.67 90.48,156.27 91.67,156.27 94.13,153.81 94.18,153.81
  L4 w0.127: 94.18,153.81 94.36,153.63 95.41,152.58 95.41,152.58 95.76,152.22 96.81,152.22 97.24,151.8 97.24,151.43 101.53,147.14 104.64,147.14 105.64,146.15 105.95,145.83 106.83,145.83 124.74,127.93 125.36,127.93 125.49,128.05 125.49,128.3 125.77,128.59 126.37,128.59 126.66,128.3 126.66,128.05 126.78,127.93 127.16,127.93 127.29,128.05 127.29,128.33 127.57,128.61 128.18,128.61 128.46,128.33 128.46,128.05 128.59,127.93 132.13,127.93 132.37,127.69 138.88,127.69 139.84,128.65 143.88,128.65 144.33,129.11 152,129.11 152.11,129.22 152.11,129.44 v1(151.89,129.67)
  BOTTOM w0.102: v1(151.89,129.67) 151.89,130.21 v2(151.67,130.43)
M_B_DQS_DN8: length 4.5
  TOP w0.102: DIMM2.95 145.62,168.78 145.41,168.57 145.07,168.57 144.65,168.99 144.65,169.34 v3(144.95,169.64)
  BOTTOM w0.102: v2(145.52,169.04) 145.5,169.06 145.5,169.09 v3(144.95,169.64) 144.94,169.65 R559.2
M_B_DQS_DP0: length 92.7
  TOP w0.102: CPU1.AH65 85.74,181.09 v1(85.6,181.09) ; v1(151.8,184.53) 151.96,184.37 151.96,183.98 152.24,183.71 153.25,183.71 153.57,184.03 DIMM2.34
  L4 w0.127: v1(85.6,181.09) 85.85,181.09 86.05,181.29 86.05,181.87 86.33,182.15 86.33,183.33 88.1,185.1 88.42,185.1 88.98,185.66 89.93,185.66 90.33,186.06 90.33,188.98 89.86,189.45 89.86,193.53 92.8,196.47 98.34,196.47 98.47,196.34 98.47,195.61 98.75,195.33 99.35,195.33 99.64,195.61 99.64,196.34 99.76,196.47 100.15,196.47 100.27,196.34 100.27,195.61 100.56,195.33 109.68,195.33 110.95,194.06 128.17,194.06 128.82,193.41 128.99,193.41 131.9,190.5 138.84,190.5 141.12,188.22 141.68,188.22 141.96,187.95 141.96,187.38 143.9,185.45 145.35,185.45 145.97,184.82 147.47,184.82 147.67,185.03 151.65,185.03 151.8,184.88 v1(151.8,184.53)
  BOTTOM w0.102: v2(153.65,185.17) 152.43,185.17 v1(151.8,184.53)
M_B_DQS_DP1: length 91.2
  TOP w0.089: v1(84.21,188.33) 84.48,188.06 84.59,188.06 84.77,187.88 84.77,186.09 85.28,185.57 85.28,185.21 85.24,185.06 85.24,184.92 85.3,184.72 85.3,184.54 CPU1.AG70
  TOP w0.102: v1(149.13,189.99) 148.94,189.8 148.94,189.55 148.67,189.28 DIMM2.13
  L4 w0.127: v1(84.21,188.33) 85.11,189.23 85.11,195.08 90.98,200.95 102.9,200.95 103.18,200.67 103.18,200.12 103.31,200 103.69,200 103.81,200.12 103.81,200.67 104.1,200.95 104.7,200.95 104.98,200.67 104.98,200.12 105.11,200 105.49,200 105.62,200.12 105.62,200.67 105.9,200.95 106.5,200.95 106.79,200.67 106.79,200.12 106.91,200 107.29,200 107.42,200.12 107.42,200.67 107.7,200.95 108.4,200.95 109.19,200.16 114.09,200.16 114.7,199.56 129.18,199.56 131.07,197.66 138.58,197.66 145.54,190.7 148.42,190.7 v1(149.13,189.99)
  BOTTOM w0.102: v1(84.21,188.33) 84.07,188.19 v2(83.22,188.19)
M_B_DQS_DP2: length 80.4
  TOP w0.102: v1(149.77,179.83) 149.77,179.16 149.39,178.78 DIMM2.55 ; CPU1.AR65 89.9,181.05 v1(90.22,180.72)
  L4 w0.089: v1(90.22,180.72) 91.02,181.52 91.02,182.43 90.78,182.66 90.78,183.11 90.99,183.32 91.29,183.32 91.47,183.49 91.5,183.49 91.51,183.51 91.59,183.51 91.6,183.51
  L4 w0.127: v1(149.77,179.83) 149.03,179.1 144.09,179.1 138.08,185.1 131.49,185.1 128.23,188.37 122.73,188.37 122.45,188.65 122.45,189.43 122.32,189.56 121.94,189.56 121.82,189.43 121.82,188.65 121.53,188.37 120.93,188.37 120.65,188.65 120.65,189.43 120.52,189.56 120.14,189.56 120.01,189.43 120.01,188.65 119.73,188.37 119.13,188.37 118.84,188.65 118.84,189.43 118.72,189.56 118.34,189.56 118.21,189.43 118.21,188.65 117.93,188.37 112.33,188.37 111.49,189.2 102.73,189.2 101.61,188.09 97.41,188.09 93.85,184.53 92.62,184.53 91.6,183.51
  BOTTOM w0.102: v2(150.02,178.89) 150.02,179.58 v1(149.77,179.83)
M_B_DQS_DP3: length 74.7
  TOP w0.102: v1(151.8,174.12) 151.82,174.12 152.09,173.85 152.09,173.65 152.34,173.4 153.5,173.4 153.63,173.53 DIMM2.76 ; CPU1.AR60 89.9,178.3 v1(89.57,177.98)
  L4 w0.089: 98.84,183.38 98.83,183.38 98.79,183.41 98.32,183.41 95.77,180.86 95.77,180.53 95.27,180.03 94.6,180.03 92.9,178.33 91.09,178.33 91.04,178.38 90.54,178.38 90.47,178.3 89.82,178.3 89.57,178.06 v1(89.57,177.98)
  L4 w0.127: 98.84,183.38 100.75,183.38 100.92,183.21 105.21,183.21 105.38,183.38 126.77,183.38 131.4,178.74 138.55,178.74 143.19,174.1 150.38,174.1 150.94,174.66 151.99,174.66 152.08,174.57 152.08,174.4 v1(151.8,174.12)
  BOTTOM w0.102: v2(151.5,173.29) 151.8,173.58 v1(151.8,174.12)
M_B_DQS_DP4: length 78.1
  TOP w0.102: v1(89.63,167.01) 89.9,166.75 CPU1.AR38 ; v1(148.5,145.29) 148.75,145.54 148.75,145.79 148.62,145.92 147.31,145.92 147.17,145.78 DIMM2.179
  L4 w0.089: 103.14,161.88 103.14,161.89 103.14,161.95 102.65,162.43 100.1,164.98 94.51,164.98 92.93,166.56 91.34,166.56 91.14,166.36 90.59,166.36 90.46,166.5 90.19,166.5 89.67,167.01 v1(89.63,167.01)
  L4 w0.127: 103.14,161.88 103.42,161.6 103.42,161.15 104.53,160.05 109.24,160.05 125.6,143.69 135.09,143.69 135.3,143.89 139.39,143.89 139.61,144.11 140.1,144.11 140.75,144.76 140.75,145.67 140.88,145.8 141.3,145.8 141.42,145.67 141.42,144.8 141.71,144.51 142.31,144.51 142.59,144.8 142.59,145.71 142.72,145.83 148.58,145.83 148.75,145.67 148.75,145.54 v1(148.5,145.29)
  BOTTOM w0.102: v1(148.5,145.29) 148.5,145.49 v2(147.81,146.18)
M_B_DQS_DP5: length 78.8
  TOP w0.102: v1(89.61,163.37) 89.9,163.09 CPU1.AR32 ; DIMM2.200 152.24,140.52 151.89,140.88 v1(151.89,141.22)
  L4 w0.089: v1(89.61,163.37) 90,162.99 90.42,162.99 90.56,163.13 91.08,163.13 91.12,163.09 91.33,162.88 91.83,162.88 91.9,162.95 92.89,162.95 93.11,162.73 93.11,162.67 93.12,162.66
  L4 w0.127: v1(151.89,141.22) 151.89,141.48 151.69,141.68 150.99,141.68 150.28,140.97 144.11,140.97 142.65,139.51 131.7,139.51 131.34,139.15 124.36,139.15 108.69,154.83 104.24,154.83 98.8,160.26 95.52,160.26 93.49,162.29 93.21,162.57 93.12,162.66
  BOTTOM w0.102: v2(151.32,142.04) 151.89,141.47 v1(151.89,141.22)
M_B_DQS_DP6: length 80.3
  TOP w0.102: v1(149.26,135.89) 149.05,135.69 149.05,135.43 148.85,135.23 147.38,135.23 147.34,135.28 DIMM2.221 ; CPU1.AR27 89.57,160.47 v1(89.57,160.6)
  L4 w0.089: v1(89.57,160.6) 89.78,160.39 90.51,160.39 91.12,159.79 91.12,159.55 91.44,159.23 92.9,159.23 94.27,157.86 94.27,156.5 95.07,155.7 96.31,155.7 96.35,155.74 96.37,155.74
  L4 w0.127: 96.37,155.74 98.42,155.74 103,151.16 106.23,151.16 107.43,149.95 108.28,149.95 123.69,134.54 131.78,134.54 132.44,133.88 142.43,133.88 145.14,136.6 145.93,136.6 146.22,136.32 146.22,135.51 146.35,135.38 146.73,135.38 146.85,135.51 146.85,136.32 147.14,136.6 148.67,136.6 149.02,136.25 149.02,136.13 v1(149.26,135.89)
  BOTTOM w0.102: v1(149.26,135.89) 149.89,135.25 150.02,135.25 v2(150.15,135.13)
M_B_DQS_DP7: length 82.2
  TOP w0.102: v1(89.57,156.95) 89.9,156.62 CPU1.AR21 ; DIMM2.242 153.41,130.03 153.33,130.1 152.95,130.1 v1(152.52,129.67)
  L4 w0.089: 93.99,153.62 93.98,153.64 93.98,153.69 91.59,156.08 90.4,156.08 89.89,156.59 89.89,156.63 v1(89.57,156.95)
  L4 w0.127: 93.99,153.62 95.14,152.47 95.14,152.47 95.65,151.96 96.7,151.96 96.97,151.68 96.97,151.32 101.42,146.88 104.53,146.88 105.37,146.04 105.84,145.57 106.72,145.57 124.63,127.66 125.47,127.66 125.75,127.94 125.75,128.19 125.88,128.32 126.26,128.32 126.39,128.19 126.39,127.94 126.67,127.66 127.27,127.66 127.56,127.94 127.56,128.22 127.68,128.35 128.07,128.35 128.19,128.22 128.19,127.94 128.48,127.66 132.01,127.66 132.26,127.42 138.99,127.42 139.96,128.38 143.99,128.38 144.44,128.84 152.11,128.84 152.37,129.1 152.37,129.52 v1(152.52,129.67)
  BOTTOM w0.102: v1(152.52,129.67) 152.52,130.01 v2(152.94,130.43)
M_B_DQS_DP8: length 4.9
  TOP w0.102: DIMM2.97 145.49,168.28 145.41,168.35 144.98,168.35 144.43,168.9 144.43,169.34 v3(144.13,169.64)
  BOTTOM w0.102: v2(143.82,168.86) 144.13,169.16 144.13,169.21 144.13,169.22 v3(144.13,169.64) 143.92,169.85 R560.2
M_B_EVENT#: length 3.7
  TOP w0.102: v3(156.12,159.26) 155.88,159.03 DIMM2.134
  BOTTOM w0.102: v2(156.93,159.26) v3(156.12,159.26) 155.74,159.64 R569.2
M_B_ODT0: length 78.6
  TOP w0.089: CPU1.BA42 93.92,167.85 94.49,167.85 94.59,167.95 97.88,167.95 v1(98.84,168.91)
  TOP w0.165: v1(149.13,152.91) 148.96,152.74 148.96,152.72 148.02,151.77 148.02,151.78 DIMM2.155
  L4 w0.089: v1(98.84,168.91) 99.47,168.28 101.25,168.28 103.28,166.24 103.54,166.24 103.92,165.86
  L4 w0.216: 103.92,165.86 104.2,165.58 112.53,165.58 120.28,157.83 120.58,157.83 121.35,158.6 121.65,158.6 121.96,158.29 121.96,157.99 121.2,157.22 121.2,156.92 121.5,156.61 121.81,156.61 122.57,157.38 122.88,157.38 123.18,157.07 123.18,156.76 122.42,156 122.42,155.69 122.72,155.39 123.03,155.39 123.79,156.15 124.1,156.15 124.4,155.85 124.4,155.54 123.64,154.78 123.64,154.47 123.94,154.17 124.25,154.17 125.01,154.93 125.32,154.93 125.63,154.63 125.63,154.32 124.86,153.56 124.86,153.25 125.17,152.95 125.47,152.95 126.24,153.71 126.54,153.71 128.64,151.61 128.76,151.49 145.81,151.49 146.73,152.41 148.69,152.41 149.13,152.85 v1(149.13,152.91)
  BOTTOM w0.165: v2(149.09,153.76) 149.13,153.72 v1(149.13,152.91)
M_B_ODT1: length 80.1
  TOP w0.165: v1(91.5,168.86) 91.5,168.75 92.14,168.11 CPU1.AW42 ; DIMM2.161 148.5,150.28 148.62,150.15 v1(148.62,149.22)
  L4 w0.089: 103.67,163.83 101.17,166.33 100.26,166.33 100.26,166.32 96.47,166.32 95.96,166.84 95.96,166.86 93.99,168.83 91.53,168.83 v1(91.5,168.86)
  L4 w0.216: 103.67,163.83 104.71,162.79 110.37,162.79 125.99,147.17 126.56,147.17 126.78,147.39 126.78,147.64 126.99,147.85 127.42,147.85 127.64,147.64 127.64,147.39 127.86,147.17 128.29,147.17 128.5,147.39 128.5,147.64 128.72,147.85 129.15,147.85 129.37,147.64 129.37,147.39 129.58,147.17 130.01,147.17 130.23,147.39 130.23,147.64 130.45,147.85 130.88,147.85 131.09,147.64 131.09,147.39 131.31,147.17 135.11,147.17 135.2,147.26 135.79,147.85 138.74,147.85 139.02,148.13 147.28,148.13 147.49,148.34 150.83,148.34 151.04,148.55 151.04,149.02 150.83,149.22 v1(148.62,149.22)
  BOTTOM w0.165: v1(148.62,149.22) 148.62,149.66 v2(149.03,150.06)
M_VREF_DQ_DIM0: length 3.9
  TOP w0.305: v1(93.08,184.1) 93.27,183.92 CPU1.AY68
  BOTTOM w0.457: 92.68,184.7 92.11,184.12 v2(92.11,183.97)
  BOTTOM w0.508: R544.1 C295.1 92.68,184.7 ; v1(93.08,184.1) 92.95,183.97 v2(92.11,183.97)
M_VREF_DQ_DIM0_R: length 4.7
  BOTTOM w0.381: R544.2 94.52,184.85 94.52,183.39 v2(94.65,183.26) 95.03,183.26 95.04,183.27 96.37,183.27 R545.2 R546.1
M_VREF_DQ_DIM0_RC: length 2.4
  BOTTOM w0.508: C295.2 91.35,184.91 v2(90.84,185.42) 91.28,185.86 R543.1
M_VREF_DQ_DIM1: length 111.9
  TOP w0.089: v1(95.22,184.5) 94.8,184.09 94.8,184 94.61,183.81 94.61,183.44 94.42,183.25 94.26,183.2 CPU1.BA67
  TOP w0.508: v3(98.84,193.68) 98.84,194.18 99.86,195.2 103.24,195.2 104.82,196.77 137.66,196.77 142.72,191.71 142.72,188.53 142.38,188.19 142.38,168.74 142.74,168.38 142.74,152.57 v3(144.94,150.37)
  BOTTOM w0.508: v1(95.22,184.5) 95.5,184.79 v2(95.5,186) 95.5,187.44 98.84,190.78 v3(98.84,193.68) ; v3(144.94,150.37) 145.07,150.37 146.62,151.92 148.75,151.92 149.47,151.2 149.47,150.67 150.59,149.54 R601.1 C387.1
MCT_R: length 4.2
  BOTTOM w0.508: v3(63.03,13.72) 62.9,13.84 XF1.4 ; 60.99,10.03 61.76,10.03 61.88,10.16 v3(63.03,10.16)
  vias: v4(63.15,12.06)
MCT_R_1: length 4.7
  TOP w0.508: v3(66.71,13.34) 66.07,12.7 66.07,12.32
  BOTTOM w0.508: C595.1 65.18,14.86 v2(65.69,14.35) v3(66.71,13.34)
MDA0: length 22.3
  TOP w0.127: VRAM2.A4 v1(64.24,93.71) ; v1(80.15,92.94) 79.71,92.5 GPU1.E18
  L4 w0.102: 79.06,90.36 79.31,90.6 79.31,92.12 80.12,92.94 v1(80.15,92.94)
  L4 w0.165: v1(64.24,93.71) 64.54,93.41 65.64,93.41 67.92,91.13 67.92,91.06 70.8,88.18 74.33,88.18 74.56,88.42 75.85,88.42 77.23,89.79 78.49,89.79 79.06,90.36
MDA1: length 24.1
  TOP w0.127: GPU1.F18 79.68,93.36 v1(80.12,93.8) ; VRAM2.A2 64.47,95.71 65.37,94.81 65.37,94.3 v1(64.93,93.85)
  L4 w0.102: v1(80.12,93.8) 80.12,93.49 79.1,92.47 79.1,90.88 79.03,90.81
  L4 w0.165: v1(64.93,93.85) 65.79,93.85 68.49,91.16 71.89,91.16 74.18,88.87 75.43,88.87 75.84,89.28 76.32,89.28 77.21,90.17 78.39,90.17 79.03,90.81
MDA2: length 25.2
  TOP w0.127: VRAM2.B4 v1(63.44,93.71) ; v1(81.76,92.92) 81.36,92.52 GPU1.E16
  L4 w0.102: 79.32,90.03 79.51,90.22 79.51,92.04 79.98,92.51 81.35,92.51 v1(81.76,92.92)
  L4 w0.165: 79.32,90.03 78.7,89.41 77.44,89.41 76.09,88.06 74.68,88.06 74.38,87.76 70.63,87.76 67.5,90.89 67.5,90.96 65.34,93.12 64.03,93.12 v1(63.44,93.71)
MDA3: length 24.2
  TOP w0.127: v1(64.93,94.61) 64.21,95.33 63.42,95.33 VRAM2.B2 ; GPU1.F17 80.53,93.34 v1(80.92,93.74)
  L4 w0.102: 78.74,90.96 78.9,91.12 78.9,92.8 79.69,93.58 79.69,93.95 79.95,94.21 80.45,94.21 v1(80.92,93.74)
  L4 w0.165: v1(64.93,94.61) 65.62,94.61 68.31,91.93 69.78,91.93 70.19,91.52 72.37,91.52 74.12,89.76 76.32,89.76 77.11,90.55 78.33,90.55 78.74,90.96
MDA4: length 20.9
  TOP w0.127: VRAM2.E4 v1(61.04,93.71) ; v1(77.62,91.28) 78.04,91.69 GPU1.D20
  L4 w0.165: v1(61.04,93.71) 62.38,95.05 65.78,95.05 68.39,92.44 69.88,92.44 70.49,91.82 72.96,91.82 74.72,90.05 75.61,90.05 76.42,90.86 77.21,90.86 v1(77.62,91.28)
MDA5: length 20.5
  TOP w0.127: GPU1.D21 v1(77.61,92.11) ; VRAM2.E2 v1(61.04,95.31)
  L4 w0.102: 75.01,94.13 75.69,94.13 75.77,94.21 76.95,94.21 77.22,93.95 77.22,92.5 v1(77.61,92.11)
  L4 w0.165: v1(61.04,95.31) 61.64,95.92 66.81,95.92 67.55,95.18 71.72,95.18 72.76,94.13 75.01,94.13
MDA6: length 25.5
  TOP w0.127: GPU1.F20 78.04,93.35 v1(78.44,93.75) ; v1(59.46,94.51) 59.46,94.49 VRAM2.F4
  L4 w0.165: v1(59.46,94.51) 59,94.98 59,96.98 59.64,97.62 68.99,97.62 69.64,96.97 72.99,96.97 74.12,95.84 77.05,95.84 78.44,94.44 v1(78.44,93.75)
MDA7: length 21.8
  TOP w0.127: VRAM2.F2 v1(59.44,96.11) ; GPU1.E21 v1(77.62,92.92)
  L4 w0.165: v1(59.44,96.11) 59.66,96.34 67.32,96.34 67.57,96.09 72.52,96.09 73.42,95.19 76.94,95.19 77.62,94.51 v1(77.62,92.92)
MDA8: length 26.5
  TOP w0.127: v1(82.53,92.1) 82.51,92.13 82.51,92.15 GPU1.E15
  L4 w0.165: v1(65.82,86.61) 68.31,84.12 77.14,84.12 80.43,87.42 80.43,88.1 82.97,90.63 82.97,91.48 82.53,91.92 v1(82.53,92.1)
  BOTTOM w0.127: VRAM4.U11 64.44,88.51 64.8,88.15 64.8,87.63 v1(65.82,86.61)
MDA9: length 25.1
  TOP w0.127: GPU1.D15 82.51,91.35 82.51,91.33 v1(82.53,91.3)
  L4 w0.165: v1(82.53,91.3) 82.53,90.6 80.02,88.09 80.02,87.6 76.98,84.56 68.71,84.56 68.7,84.57 68.67,84.57 65.48,87.76 64.8,87.76 64.42,87.38 v1(64.42,86.61)
  BOTTOM w0.127: v1(64.42,86.61) 64.12,86.91 VRAM4.U13
MDA10: length 26.5
  TOP w0.127: v1(82.6,92.92) 82.18,93.34 GPU1.F15
  L4 w0.165: v1(82.6,92.92) 82.06,92.38 82.06,90.58 79.66,88.17 79.66,87.83 76.82,84.99 68.84,84.99 64.92,88.91 v1(63.44,88.91)
  BOTTOM w0.127: v1(63.44,88.91) 63.04,88.51 VRAM4.T11
MDA11: length 29.8
  TOP w0.127: v1(84.24,92.92) 83.84,93.32 GPU1.F13
  L4 w0.165: v1(84.24,92.92) 83.81,92.5 83.25,92.5 82.99,92.24 82.99,91.87 83.33,91.53 83.33,90.34 82.91,89.92 82.91,89.33 82.91,89.33 82.91,88.57 80.1,85.76 80.1,85.46 78.33,83.69 67.98,83.69 v1(65.06,86.61)
  BOTTOM w0.127: VRAM4.T13 63.41,87.28 64.39,87.28 v1(65.06,86.61)
MDA12: length 35
  TOP w0.127: v1(84.24,90.49) 83.84,90.89 GPU1.C13
  L4 w0.165: v1(84.24,90.49) 84.24,90.33 84.68,89.89 84.68,89.53 84.51,89.36 84.51,86.96 79.55,81.99 64.45,81.99 61.63,84.81 61.63,85.46 61.16,85.93 61,85.93 60.6,86.33 60.6,86.82 61.04,87.26 v1(61.04,88.1)
  BOTTOM w0.127: VRAM4.N11 60.64,88.5 v1(61.04,88.1)
MDA13: length 30.7
  TOP w0.127: GPU1.B13 83.85,90.1 v1(84.24,89.71)
  L4 w0.165: v1(84.24,89.71) 84.24,87.28 79.37,82.41 64.73,82.41 61.95,85.19 61.95,85.6 v1(61.03,86.51)
  BOTTOM w0.127: VRAM4.N13 v1(61.03,86.51)
MDA14: length 40
  TOP w0.127: GPU1.E13 83.85,92.5 v1(84.25,92.1)
  L4 w0.165: v1(84.25,92.1) 84.65,91.69 84.65,91.07 85.21,90.52 85.21,89.31 85.05,89.14 85.05,86.52 85,86.47 85,86.25 79.89,81.15 64.1,81.15 64.09,81.17 63.05,81.17 59.44,84.78 v1(59.44,88.12)
  BOTTOM w0.127: VRAM4.M11 59.84,88.51 v1(59.44,88.12)
MDA15: length 37.1
  TOP w0.127: v1(84.22,91.3) 84.21,91.3 84.21,91.33 GPU1.D13
  L4 w0.165: v1(60.24,87.31) 59.85,86.93 59.85,84.96 63.23,81.58 64.26,81.58 64.27,81.57 79.72,81.57 84.58,86.43 84.58,86.6 84.78,86.8 84.78,89.25 84.94,89.42 84.94,90.41 84.3,91.06 84.22,91.13 v1(84.22,91.3)
  BOTTOM w0.127: VRAM4.M13 59.84,86.91 59.84,86.92 v1(60.24,87.31)
MDA16: length 47.1
  TOP w0.127: GPU1.B15 82.16,89.83 82.54,89.45 82.54,87.42 v1(82.84,87.12) ; v1(50.12,88.11) 50.52,88.51 VRAM2.U11
  L3 w0.165: v1(82.84,87.12) 82.84,84.94 78.45,80.55 57.07,80.55 56.31,81.31 53.03,81.31 49.31,85.03 49.31,87.3 v1(50.12,88.11)
MDA17: length 43
  TOP w0.127: GPU1.C16 81.76,90.5 81.76,86.11 v1(81.75,86.11) ; VRAM2.U13 50.5,86.91 v1(50.45,86.87)
  L3 w0.165: v1(50.45,86.87) 50.14,86.56 50.14,85.38 53.38,82.14 56.7,82.14 57.46,81.39 78.1,81.39 81.75,85.04 v1(81.75,86.11)
MDA18: length 49.4
  TOP w0.127: VRAM2.T11 51.84,88.51 v1(51.43,88.92) ; v1(83.35,87.63) 83.84,88.13 GPU1.A13
  L3 w0.165: v1(83.35,87.63) 83.35,84.86 78.62,80.13 56.89,80.13 56.14,80.89 52.86,80.89 48.89,84.85 48.89,87.5 50.31,88.92 v1(51.43,88.92)
MDA19: length 44.6
  TOP w0.127: GPU1.A15 82.16,86.72 v1(82.27,86.61) ; v1(50.33,87.5) 50.52,87.31 51.44,87.31 VRAM2.T13
  L3 w0.165: v1(82.27,86.61) 82.27,84.96 78.27,80.97 57.24,80.97 56.48,81.72 53.2,81.72 49.77,85.15 49.77,86.95 v1(50.33,87.5)
MDA20: length 38.9
  TOP w0.127: v1(54.64,88.91) 54.25,88.51 VRAM2.N11 ; GPU1.B18 79.68,89.87 80.17,89.38 80.17,87 v1(80.42,86.74)
  L3 w0.165: v1(80.42,86.74) 80.42,86.09 80.29,85.95 80.29,85.36 77.58,82.65 58.19,82.65 57.43,83.4 54.82,83.4 53.7,84.53 53.7,87.96 v1(54.64,88.91)
MDA21: length 33.4
  TOP w0.127: v1(79.92,86.23) 79.68,86.47 GPU1.A18 ; v1(54.64,86.51) 54.25,86.91 VRAM2.N13
  L3 w0.165: v1(79.92,86.23) 79.87,86.19 79.87,85.53 77.4,83.06 58.36,83.06 57.61,83.82 55.2,83.82 54.64,84.38 v1(54.64,86.51)
MDA22: length 35.4
  TOP w0.127: v1(55.41,88.92) 55.04,88.54 VRAM2.M11 ; v1(79.41,85.72) 79.41,85.01 79.17,84.77 78.2,84.77 77.76,85.21 77.76,86.38 78.81,87.43 78.81,87.44 78.85,87.48 78.85,89.27 GPU1.A19
  L3 w0.165: v1(55.41,88.92) 55.41,87.51 58.06,84.86 58.06,84.78 58.93,83.9 76.66,83.9 78.49,85.72 v1(79.41,85.72)
MDA23: length 35.4
  TOP w0.127: GPU1.C19 79.24,90.54 79.24,87.33 79.19,87.28 79.19,87.28 78.9,86.98 78.9,86.8 79.25,86.46 79.25,86.28 79.07,86.1 78.89,86.1 78.54,86.44 78.36,86.44 78.14,86.23 78.14,85.97 v1(78.9,85.22) ; VRAM2.M13 55.05,86.91 v1(55.44,86.51)
  L3 w0.165: v1(78.9,85.22) 77.17,83.48 58.54,83.48 57.78,84.24 55.52,84.24 55.02,84.73 55.02,86.09 v1(55.44,86.51)
MDA24: length 40.1
  TOP w0.127: v1(50.33,97.66) 51.94,99.28 65.54,99.28 68.04,96.77 68.04,92.84 68.36,92.53 68.36,89.78 70.43,87.71 71.81,87.71 71.94,87.58 73.79,87.58 74.31,88.1 74.31,89.71 GPU1.B24
  BOTTOM w0.127: v1(50.33,97.66) 50.18,97.52 50.18,94.36 50.43,94.11 VRAM4.A4
MDA25: length 38.8
  TOP w0.127: GPU1.C23 75.91,90.54 75.91,89.68 75.81,89.58 75.81,88.45 74.02,86.66 70.4,86.66 67.6,89.46 67.6,91.85 66.58,92.86 66.58,97.16 65.22,98.51 53.21,98.51 v1(52.36,97.66)
  BOTTOM w0.127: VRAM4.A2 51.04,95.71 51.47,96.14 51.98,96.14 52.21,96.36 52.21,97.51 v1(52.36,97.66)
MDA26: length 40.8
  TOP w0.127: GPU1.A25 73.9,88.37 73.57,88.04 72.68,88.04 72.4,88.32 70.36,88.32 68.97,89.71 68.97,92.46 68.43,93 68.43,96.93 65.7,99.66 51.56,99.66 v1(49.56,97.66)
  BOTTOM w0.127: VRAM4.B4 51.84,94.11 51.49,93.77 50.42,93.77 49.82,94.37 49.82,97.41 v1(49.56,97.66)
MDA27: length 38.4
  TOP w0.127: GPU1.A24 74.7,87.95 73.83,87.08 70.52,87.08 67.98,89.62 67.98,92.37 67.27,93.08 67.27,97.01 65.38,98.89 52.7,98.89 v1(51.47,97.66)
  BOTTOM w0.127: VRAM4.B2 51.47,95.34 50.88,95.34 50.62,95.61 50.62,97.26 51.02,97.66 v1(51.47,97.66)
MDA28: length 33.1
  TOP w0.127: GPU1.A21 76.99,89.09 76.99,87.77 74.03,84.81 70.64,84.81 64.7,90.75 64.7,90.93 65.18,91.42 65.18,91.6 65,91.77 64.82,91.77 64.34,91.29 64.16,91.29 63.98,91.47 63.98,91.65 64.46,92.13 64.46,92.31 64.28,92.49 64.1,92.49 63.62,92.01 63.44,92.01 63.13,92.31 55.7,92.31 55.41,92.61 55.41,93.43 55.13,93.71 v1(54.64,93.71)
  BOTTOM w0.127: v1(54.64,93.71) 54.24,94.11 VRAM4.E4
MDA29: length 36.1
  TOP w0.127: v1(54.64,96.11) 54.64,95.63 54.29,95.28 54.08,95.28 53.83,95.02 53.83,92.54 54.07,92.29 55.32,92.29 55.79,91.82 63.08,91.82 69.22,85.68 69.22,85.22 70.39,84.04 73.81,84.04 77.33,87.57 77.33,88.93 77.56,89.15 77.56,89.45 77.2,89.8 GPU1.B21
  BOTTOM w0.127: VRAM4.E2 v1(54.64,96.11)
MDA30: length 38.9
  TOP w0.127: v1(53.63,91.82) 54.5,90.95 62.88,90.95 66.91,86.92 66.91,85.62 69.25,83.28 74.12,83.28 78.59,87.75 78.59,89.09 78.52,89.15 78.52,90.42 GPU1.C20
  BOTTOM w0.127: VRAM4.F4 55.04,93.83 55.41,93.47 55.41,92.08 54.73,91.4 54.05,91.4 v1(53.63,91.82)
MDA31: length 37.7
  TOP w0.127: v1(54.39,91.82) 54.77,91.44 62.93,91.44 68.64,85.73 68.64,84.44 69.41,83.66 73.97,83.66 77.75,87.45 77.75,89.02 77.78,89.06 77.78,89.55 77.56,89.79 77.56,90.54 GPU1.C21
  BOTTOM w0.127: v1(54.39,91.82) 53.83,92.38 53.83,95.02 54.08,95.28 54.61,95.28 VRAM4.F2
MDA32: length 16.3
  TOP w0.127: GPU1.R22 76.31,100.84 v1(75.9,101.24)
  L4 w0.102: 73.45,101.41 73.67,101.41 73.84,101.24 v1(75.9,101.24)
  L4 w0.165: v1(64.24,106.96) 64.24,105.94 66.07,104.11 66.07,103.35 67.56,101.86 73.01,101.86 73.45,101.41
  BOTTOM w0.127: v1(64.24,106.96) 64.21,106.96 63.79,106.54
MDA33: length 14.2
  TOP w0.127: GPU1.R24 74.7,100.82 75.11,100.41 v1(75.11,100.38)
  L4 w0.102: v1(75.11,100.38) 74.71,100.79 73.72,100.79 73.67,100.83 73.1,100.83
  L4 w0.165: v1(64.19,104.54) 64.85,103.88 64.85,103.39 67.22,101.02 70.52,101.02 70.65,101.14 72.79,101.14 73.1,100.83
  BOTTOM w0.127: 63.79,104.94 v1(64.19,104.54)
MDA34: length 18.9
  TOP w0.127: GPU1.T22 76.34,101.67 v1(76.73,102.07)
  L4 w0.102: v1(76.73,102.07) 76.34,101.68 75.67,101.68 75.47,101.47 73.9,101.47 73.51,101.86
  L4 w0.165: 73.51,101.86 73.11,102.26 72.38,102.26 71.84,102.8 70.62,102.8 70.09,102.27 67.74,102.27 66.53,103.48 66.53,104.25 65.32,105.46 65.32,106.5 64.43,107.4 63.86,107.4 v1(63.41,106.95)
  BOTTOM w0.127: VRAM3.B4 62.99,106.54 63.39,106.95 v1(63.41,106.95)
MDA35: length 16.1
  TOP w0.127: GPU1.R23 75.52,100.84 v1(75.91,100.46)
  L4 w0.102: v1(75.91,100.46) 75.37,100.99 73.8,100.99 73.7,101.09 73.34,101.09
  L4 w0.165: 73.34,101.09 72.87,101.56 70.49,101.56 70.37,101.44 67.39,101.44 65.48,103.35 65.48,103.87 64.37,104.98 63.82,104.98 v1(63.39,104.54)
  BOTTOM w0.127: VRAM3.B2 v1(63.39,104.54)
MDA36: length 19.7
  TOP w0.127: v1(73.49,99.58) 73.9,99.17 GPU1.N25
  L4 w0.14: 60.59,103.9 60.59,105.93 60.56,105.96 60.56,106.51 v1(60.99,106.95)
  L4 w0.165: 60.59,103.9 60.59,103.21 64.45,99.34 73.25,99.34 v1(73.49,99.58)
  BOTTOM w0.127: VRAM3.E4 60.59,106.54 v1(60.99,106.95)
MDA37: length 15.7
  TOP w0.127: GPU1.N26 72.74,99.52 71.84,99.52 v1(71.41,99.95)
  L4 w0.165: v1(71.41,99.95) 71,99.95 70.81,99.76 64.63,99.76 61.01,103.37 v1(61.01,104.54)
  BOTTOM w0.127: VRAM3.E2 60.61,104.94 v1(61.01,104.54)
MDA38: length 24.6
  TOP w0.127: GPU1.N23 75.5,99.19 v1(75.11,99.58)
  L4 w0.165: v1(75.11,99.58) 73.57,98.04 63.96,98.04 58.68,103.32 58.68,104 60.18,105.51 v1(60.18,106.92)
  BOTTOM w0.127: VRAM3.F4 59.8,106.54 v1(60.18,106.92)
MDA39: length 19.7
  TOP w0.127: v1(74.31,99.55) 74.31,99.54 74.69,99.16 GPU1.N24
  L4 w0.165: v1(74.31,99.55) 73.07,98.31 70.76,98.31 70.57,98.5 64.59,98.5 59.69,103.4 59.69,104.07 v1(60.16,104.54)
  BOTTOM w0.127: VRAM3.F2 59.79,104.92 v1(60.16,104.54)
MDA40: length 16.3
  TOP w0.127: v1(64.93,112.14) 64.93,112.14 63.79,112.14 ; GPU1.V23 75.55,103.32 v1(75.95,103.72)
  L4 w0.102: 73.06,105.03 74.17,103.92 75.74,103.92 v1(75.95,103.72)
  L4 w0.165: v1(64.93,112.14) 65.07,112.14 71.03,106.18 71.9,106.18 73.06,105.03
MDA41: length 17.9
  TOP w0.127: GPU1.V22 76.34,103.32 v1(76.74,103.72) ; v1(65.06,112.9) 64.22,113.74 63.79,113.74
  L4 w0.102: v1(76.74,103.72) 76.34,104.12 74.34,104.12 73.31,105.16 73.31,105.4 73.19,105.53
  L4 w0.165: v1(65.06,112.9) 65.06,112.75 70.86,106.95 71.77,106.95 73.19,105.53
MDA42: length 18.1
  TOP w0.127: VRAM1.T11 v1(63.39,111.74) ; GPU1.T23 75.5,101.64 v1(75.95,102.08)
  L4 w0.102: v1(75.95,102.08) 75.55,102.48 75.55,103.05 75.21,103.38 73.57,103.38 72.5,104.44
  L4 w0.165: v1(63.39,111.74) 63.86,111.27 64.76,111.27 70.69,105.34 71.61,105.34 72.5,104.44
MDA43: length 19.3
  TOP w0.127: VRAM1.T13 63.38,113.35 63.9,113.35 64.24,113 v1(64.24,112.56) ; GPU1.U22 76.36,102.48 v1(76.76,102.88)
  L4 w0.102: 72.82,104.68 73.82,103.67 75.3,103.67 75.67,103.3 76.34,103.3 v1(76.76,102.88)
  L4 w0.165: v1(64.24,112.56) 64.24,112.21 64.89,111.56 65.06,111.56 70.89,105.74 71.76,105.74 72.82,104.68
MDA44: length 25.1
  TOP w0.127: v1(74.32,105.37) 74.7,104.99 GPU1.Y24 ; VRAM1.N11 60.19,111.75 v1(60.18,111.75)
  L4 w0.102: 73.74,107.35 73.74,106.99 74.14,106.58 74.47,106.58 74.71,106.34 74.71,105.76 v1(74.32,105.37)
  L4 w0.165: 73.74,107.35 65.47,115.62 60.21,115.62 59.91,115.32 59.91,114.49 59.74,114.32 59.74,112.19 v1(60.18,111.75)
MDA45: length 19
  TOP w0.127: v1(60.18,114.14) 60.19,114.14 VRAM1.N13 ; v1(74.3,106.17) 74.31,106.17 74.68,105.8 GPU1.AA24
  L4 w0.165: v1(74.3,106.17) 74.22,106.17 73.32,107.07 73.32,107.18 65.91,114.58 60.62,114.58 v1(60.18,114.14)
MDA46: length 27.3
  TOP w0.127: GPU1.Y22 76.3,104.96 v1(75.89,105.37) ; VRAM1.M11 59.78,112.14 v1(59.38,111.74)
  L4 w0.165: v1(75.89,105.37) 75.89,106.41 65.96,116.33 60.09,116.33 59.03,115.27 59.03,114.45 59.05,114.43 59.38,114.1 v1(59.38,111.74)
MDA47: length 22.7
  TOP w0.127: v1(75.12,106.2) 75.5,105.82 GPU1.AA23 ; VRAM1.M13 59.43,114.1 59.43,115.04 v1(59.47,115.07)
  L4 w0.165: v1(59.47,115.07) 59.47,115.29 60.22,116.04 65.64,116.04 73.48,108.2 73.72,108.2 75.12,106.8 v1(75.12,106.2)
MDA48: length 36.5
  TOP w0.127: v1(49.94,116.08) 53.89,120.02 65.25,120.02 68.36,116.92 68.63,116.92 70.75,114.8 70.75,109.89 71.2,109.43 71.2,109.33 72.24,108.3 GPU1.AD27
  BOTTOM w0.127: VRAM3.U11 50.38,112.14 49.94,112.58 v1(49.94,116.08)
MDA49: length 35
  TOP w0.127: GPU1.AB25 73.6,106.6 73.25,106.96 73.06,106.96 72.83,107.18 72.37,107.18 69.88,109.68 69.88,114.07 69.45,114.5 68.97,114.5 64.21,119.26 54.27,119.26 50.13,115.13 50.13,114.58 v1(50.55,114.16)
  BOTTOM w0.127: v1(50.55,114.16) 50.98,113.74 VRAM3.U13
MDA50: length 39.8
  TOP w0.127: v1(51.39,111.74) 50.78,111.74 49.52,113 49.52,116.25 53.68,120.4 66.07,120.4 71.43,115.04 71.43,109.43 72.21,108.66 72.45,108.66 72.8,108.3 GPU1.AD26
  BOTTOM w0.127: VRAM3.T11 51.79,112.14 v1(51.39,111.74)
MDA51: length 37.4
  TOP w0.127: GPU1.AC25 73.74,107.45 73.24,107.94 72.15,107.94 70.37,109.73 70.37,114.64 69.33,115.67 68.34,115.67 64.37,119.64 54.11,119.64 49.88,115.41 49.88,113.98 v1(50.45,113.41)
  BOTTOM w0.127: VRAM3.T13 51.41,113.36 50.5,113.36 v1(50.45,113.41)
MDA52: length 32.2
  TOP w0.127: v1(53.79,112.55) 53.25,112.55 53.02,112.79 53.02,112.79 53,112.81 53,116.03 55,118.03 63.7,118.03 67.6,114.13 67.6,110.21 71.81,105.99 72.11,105.99 GPU1.AA27
  BOTTOM w0.127: v1(53.79,112.55) 54.18,112.16 54.18,112.15 VRAM3.N11
MDA53: length 29.6
  TOP w0.127: v1(53.79,114.14) 53.79,115.48 54.52,116.2 54.52,116.4 55.68,117.56 63.51,117.56 66.81,114.26 66.81,110.45 71.6,105.66 71.9,105.66 72.12,105.44 72.45,105.44 72.8,105.8 GPU1.AA26
  BOTTOM w0.127: VRAM3.N13 v1(53.79,114.14)
MDA54: length 29.8
  TOP w0.127: v1(55.38,112.53) 55.38,113.61 55.35,113.64 55.35,115.29 56.68,116.62 63.18,116.62 65.49,114.31 65.49,109.49 65.92,109.07 66.86,109.07 68.38,107.54 68.38,107.16 71.07,104.48 72.74,104.48 GPU1.W26
  BOTTOM w0.127: VRAM3.M11 54.99,112.14 v1(55.38,112.53)
MDA55: length 29.6
  TOP w0.127: GPU1.Y25 73.54,105.32 72.65,105.32 72.55,105.22 72.01,105.22 71.9,105.32 71.4,105.32 67.25,109.47 66.78,109.47 65.97,110.29 65.97,114.43 63.4,117 55.78,117 54.55,115.77 54.55,115.36 54.65,115.27 54.65,114.92 54.59,114.87 v1(54.59,114.13)
  BOTTOM w0.127: VRAM3.M13 54.98,113.74 v1(54.59,114.13)
MDA56: length 29.8
  TOP w0.127: VRAM1.A4 50.97,106.56 50.38,106.56 49.77,105.95 49.77,102.94 50.85,101.85 51.9,101.85 53.33,100.42 66.82,100.42 67.62,99.62 70.16,99.62 71.1,100.56 71.82,100.56 71.89,100.48 72.74,100.48 GPU1.R26
MDA57: length 26.6
  TOP w0.127: GPU1.T25 73.5,101.24 71.69,101.24 71.33,101.6 67.75,101.6 67.33,101.18 53.65,101.18 52.67,102.16 52.11,102.72 51.07,102.72 50.46,103.32 50.46,104.42 VRAM1.A2
MDA58: length 30.9
  TOP w0.127: VRAM1.B4 51.44,106.88 50.35,106.88 49.39,105.93 49.39,102.78 51.18,100.99 52.22,100.99 53.18,100.04 65.88,100.04 67.15,98.77 70.23,98.77 70.67,99.21 72.25,99.21 GPU1.N27
MDA59: length 27.1
  TOP w0.127: GPU1.R27 70.72,100.84 70.24,100.36 68.99,100.36 68.55,100.8 53.49,100.8 52.4,101.89 51.95,102.34 50.91,102.34 50.15,103.09 50.15,104.63 50.83,105.31 51.42,105.31 VRAM1.B2
MDA60: length 25.1
  TOP w0.127: VRAM1.E4 53.77,106.12 53.77,103.37 54.82,102.32 64.79,102.32 66.19,103.72 66.19,103.98 66.8,104.59 68.26,104.59 69.99,102.86 70.98,102.86 71.13,103.01 71.93,103.01 71.97,102.96 72.45,102.96 72.8,103.32 GPU1.V26
MDA61: length 22.4
  TOP w0.127: GPU1.V27 70.09,103.32 67.8,105.61 66.56,105.61 65.81,104.86 65.81,103.82 64.69,102.7 55.32,102.7 54.61,103.42 54.61,104.52 VRAM1.E2
MDA62: length 21
  TOP w0.127: GPU1.W27 70.39,104.12 67.93,106.58 67.93,106.93 66.37,108.5 55.57,108.5 55.32,108.25 55.32,107.52 55.35,107.5 55.35,106.91 VRAM1.F4
MDA63: length 23.8
  TOP w0.127: VRAM1.F2 54.99,104.65 55.42,104.22 55.42,103.8 55.49,103.72 55.49,103.42 55.83,103.09 64.41,103.09 65.11,103.78 65.11,105 66.76,106.65 67.32,106.65 70.23,103.74 73.52,103.74 GPU1.W25
ME_CNTL: length 125.5
  TOP w0.102: v3(138.14,51.47) 138.5,51.47 139.54,50.44 KBC1.23
  L3 w0.127: v3(107.86,113.79) 107.09,113.03 107.09,110.14 106.84,109.89 106.84,108.3 108.59,106.55 116.4,106.55 116.9,107.06 122.84,107.06 124.05,108.27 138.94,108.27 147.82,99.38 147.82,88.14 144.5,84.82 144.5,74.86 141.83,72.18 141.83,69.91 141.07,69.15 141.07,66.04 140.36,65.33 140.36,58.38 137.45,55.47 137.45,52.4 138.14,51.71 v3(138.14,51.47)
  BOTTOM w0.102: R655.1 R656.2 114.98,121.84 107.88,121.84 v2(106.94,120.9) 106.15,120.12 106.15,115.49 v3(107.86,113.79)
ME_CNTL1: length 3.1
  BOTTOM w0.152: R656.1 115.22,120.4 v2(114.59,119.76) 114.21,119.76 113.79,120.17 Q52.B
MEM_VTT: length 102
  TOP w0.305: v4(157.13,126.11) 157.05,126.03 DIMM2.258 152.9,126.03 152.43,126.49 v1(152.43,126.62) ; DIMM1.258 141.3,126.03 142.07,126.79 142.07,126.8 v3(142.27,127)
  TOP w1.016: v5(126.27,127.04) 126.27,172.47 v5(105.06,193.68)
  BOTTOM w1.016: v5(126.27,127.04) 126.27,125.09 128.23,123.13 140.81,123.13 141.51,123.83
  vias: v2(101.48,197.18)
MHL_3V3: length 9.2
  TOP w0.203: SCA1.10 68.29,61.79 67.85,62.23 67.09,62.23
  TOP w0.508: v1(64.49,60.38) 66.34,62.23 67.09,62.23
  BOTTOM w0.508: L27.2 63.69,59.56 v2(63.86,59.74) 64.04,59.56 65.07,59.56 C554.1 65.12,59.74 v1(64.49,60.38)
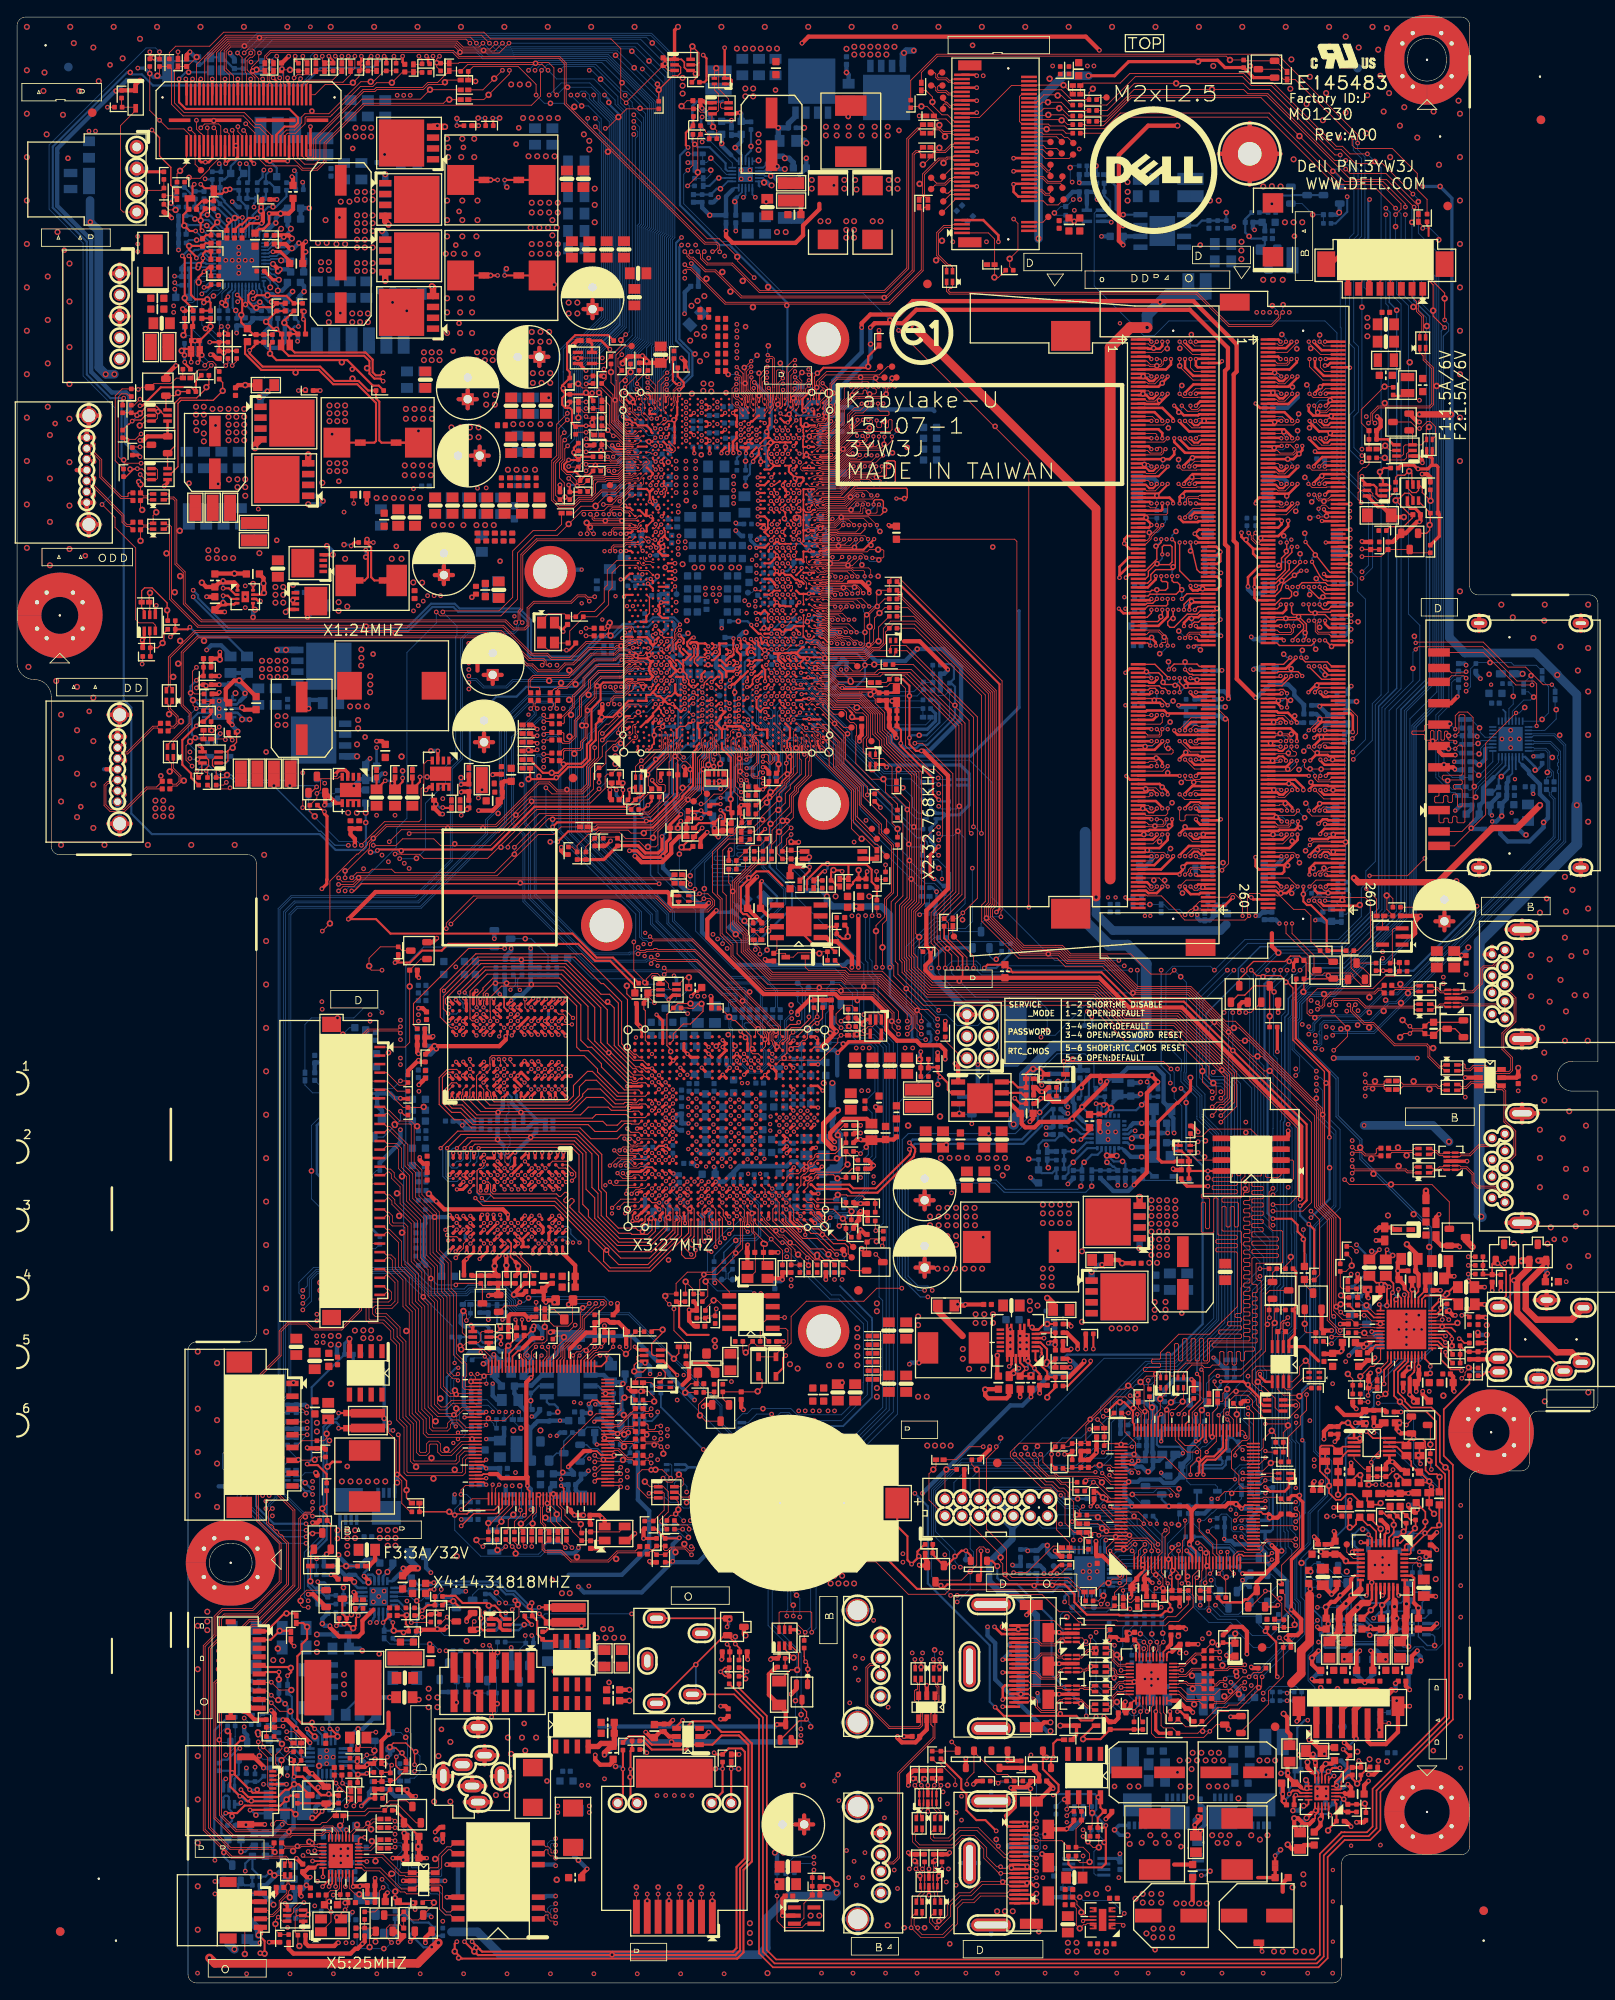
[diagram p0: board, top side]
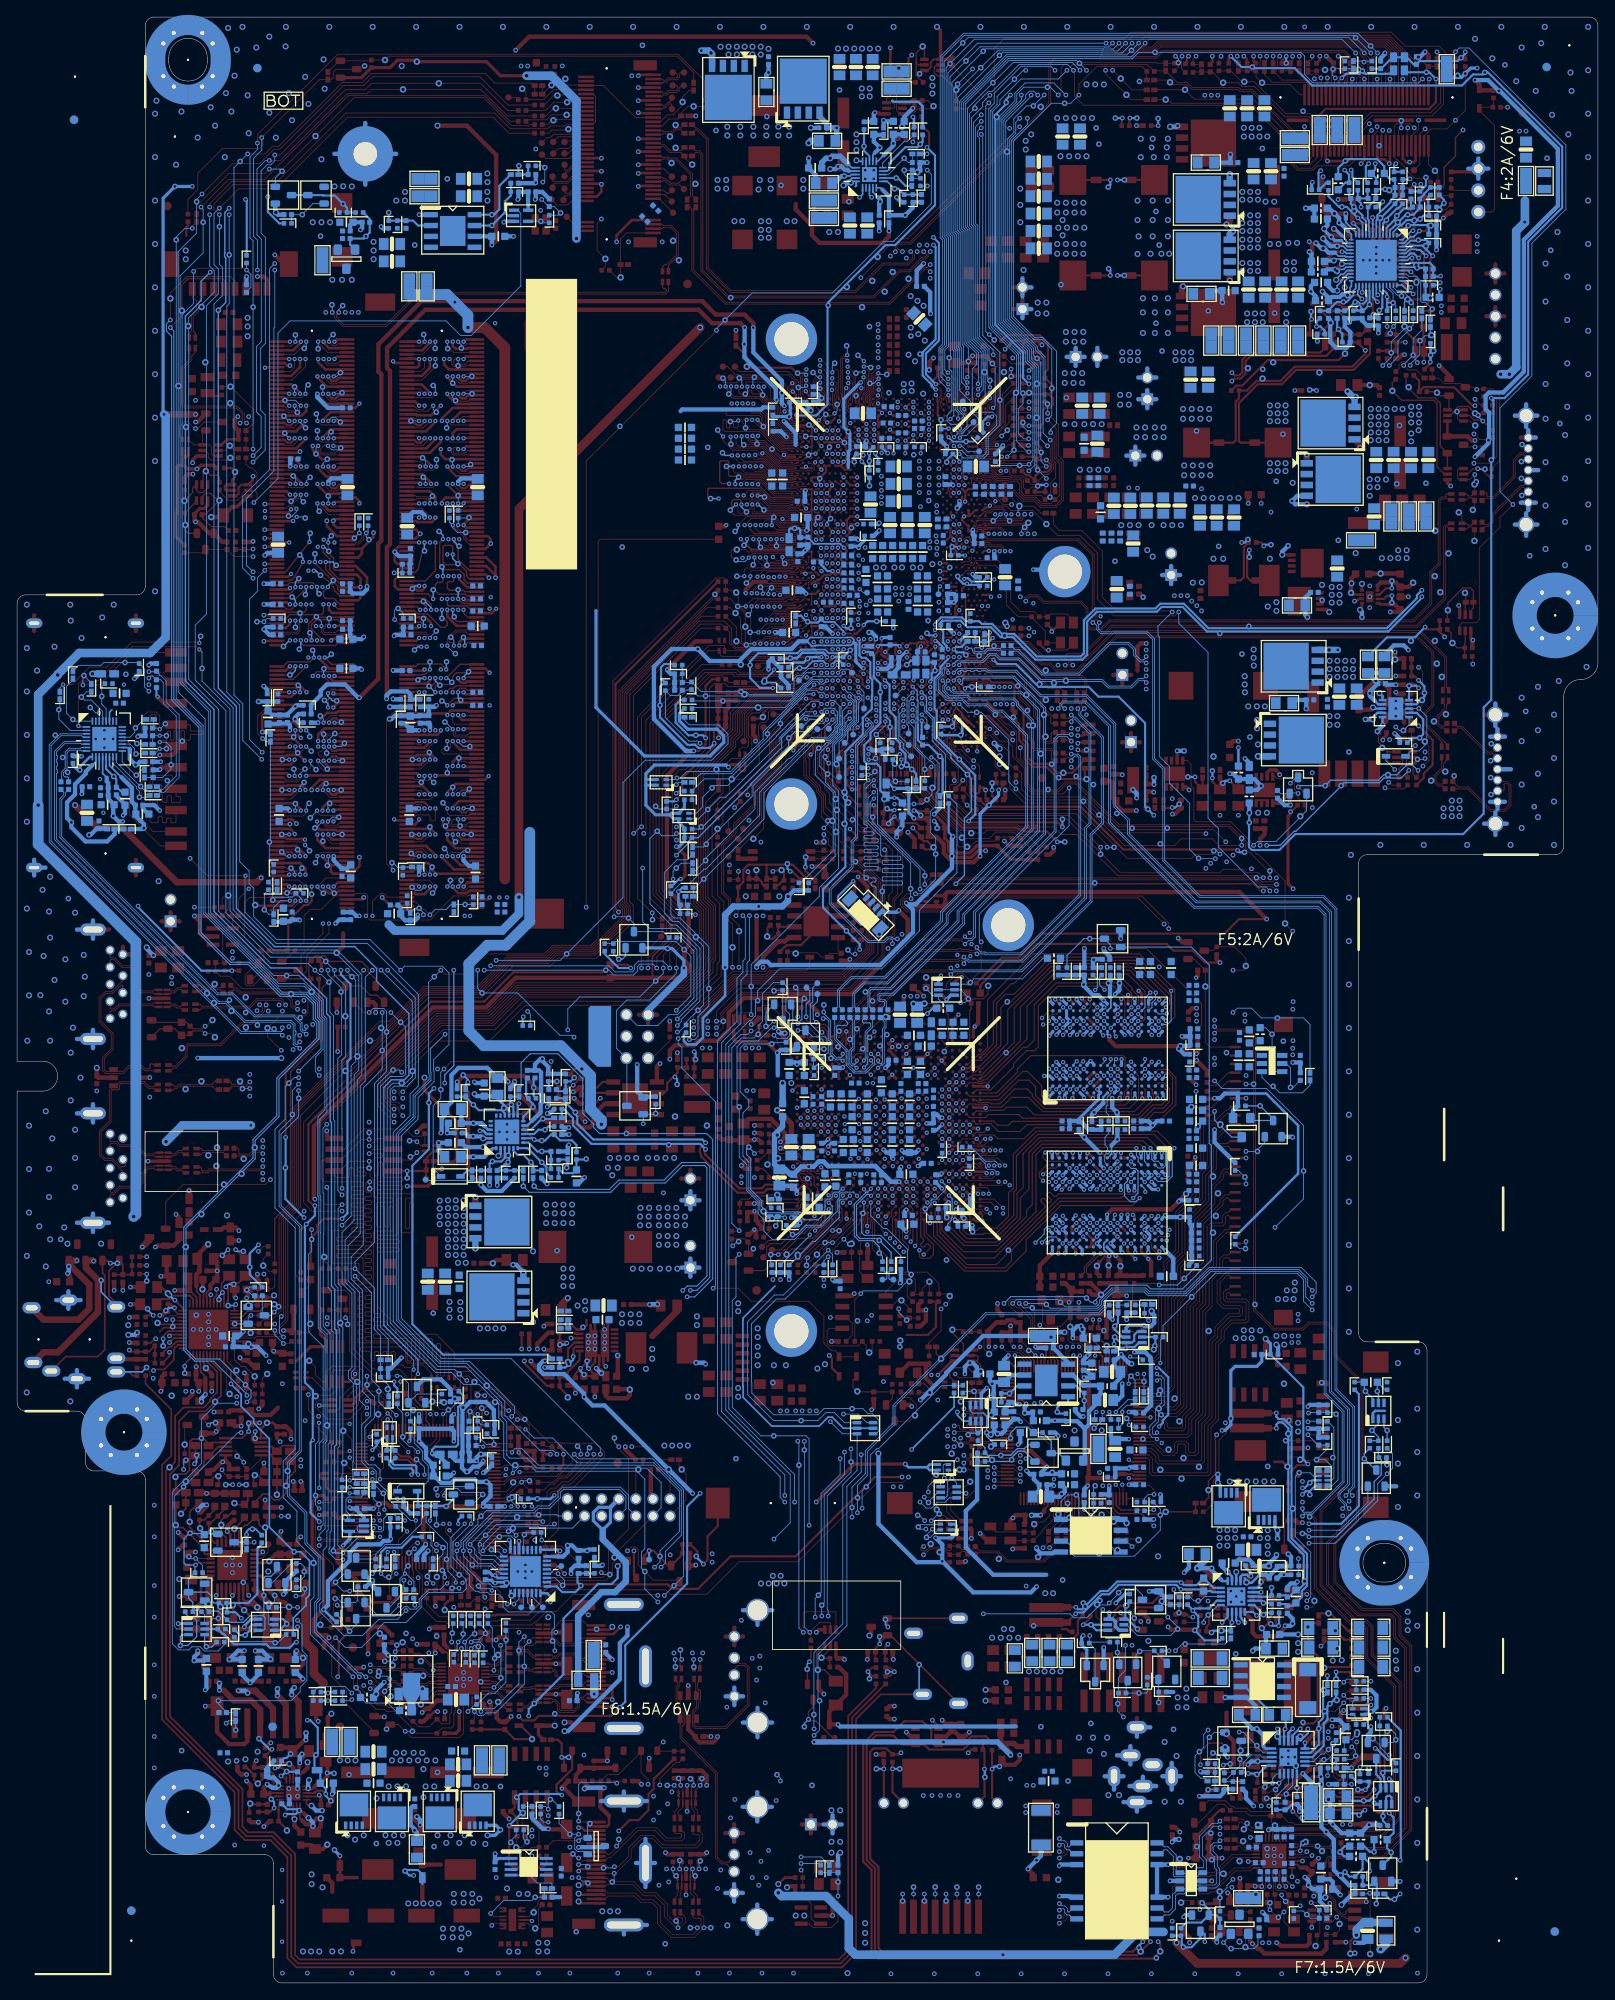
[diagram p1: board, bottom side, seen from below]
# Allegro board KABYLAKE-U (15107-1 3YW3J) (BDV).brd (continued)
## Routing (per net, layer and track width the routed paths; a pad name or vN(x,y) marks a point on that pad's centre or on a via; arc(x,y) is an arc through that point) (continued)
MIC2-L: length 4.7
  TOP w0.203: U11.47 160.79,80.6 v3(160.97,80.77) 160.97,80.95 161.07,81.05 161.07,81.84 C112.1
  BOTTOM w0.203: v2(161.37,79.96) 161.37,80.37 v3(160.97,80.77)
MIC2-L-1: length 13.2
  TOP w0.203: C112.2 160.18,85.65 v3(160.32,85.79) ; R281.1 v3(169.83,83.95)
  L3 w0.203: v3(160.32,85.79) 161.63,85.79 162.91,84.51 169.27,84.51 v3(169.83,83.95)
  BOTTOM w0.203: v2(160.99,85.12) v3(160.32,85.79)
MIC2-R: length 6
  TOP w0.203: C111.1 159.06,81.92 160.08,81.92 v3(160.56,81.43) 160.31,81.18 160.31,79.57 U11.48
  BOTTOM w0.203: v3(160.56,81.43) 160.26,81.74 v2(159.65,81.74)
MIC2-R-1: length 26.8
  TOP w0.203: C111.2 158.3,84.66 v3(159.43,85.79) ; R344.1 167.17,73.34 v3(167.17,73.79)
  L3 w0.203: v3(159.43,85.79) 159.94,85.28 161.49,85.28 162.75,84.02 168.74,84.02 169.32,83.44 169.32,82.72 169.58,82.47 169.58,74.68 168.69,73.79 v3(167.17,73.79)
  BOTTOM w0.203: v2(158.53,85.6) 159.24,85.6 v3(159.43,85.79)
MIC2-VREFO-L: length 21.7
  TOP w0.203: U11.1 159.57,79.23 v3(159.42,79.38) ; R280.1 v3(169.83,84.96)
  L3 w0.203: v3(169.83,84.96) 169.71,85.09 162.97,85.09 161.7,86.36 159.16,86.36 158.66,85.85 158.66,82.04 159.93,80.77 159.93,79.88 v3(159.42,79.38)
  BOTTOM w0.203: v2(160.31,79.25) 159.55,79.25 v3(159.42,79.38)
MIC2-VREFO-R: length 4.5
  TOP w0.203: R338.1 167.9,74.64 v3(167.9,75.36) 167.9,75.67 167.67,75.9 167.32,76.25 U11.30
  BOTTOM w0.203: v2(167.9,74.52) v3(167.9,75.36)
MIC-CAP: length 4.9
  TOP w0.203: U11.36 165.62,78.97
  TOP w0.254: C126.1 168.05,80.01 166.66,80.01 v3(166.53,79.88) 165.62,78.97
  BOTTOM w0.254: v3(166.53,79.88) 166.58,79.88 v2(167.17,80.47)
MINI_POWER_CTRL: length 179.6
  TOP w0.102: KBC1.27 141.14,48.4 v1(140.62,47.88) 141.45,47.05 R441.1 ; R62.2 164.5,205.55 v3(164.5,205.29)
  L3 w0.127: v1(140.62,47.88) 139.8,48.7 139.8,52.29 140.75,53.24 140.75,55.91 141.37,56.53 141.37,63.73 142.84,65.21 142.84,71.76 145.55,74.47 145.55,81.49 146.24,82.17 146.24,85.11 148.84,87.72 148.84,91.8 149.47,92.44 149.47,104.1 v3(152.05,106.68)
  BOTTOM w0.102: v3(164.5,205.29) 165.36,205.29 166.38,204.27 v2(166.38,203.94) 166.38,150.26 163.23,147.11 163.23,125.14 154,115.92 151.03,115.92 149.85,114.73 149.85,112.95 149.44,112.54 149.44,109.3 v3(152.05,106.68)
MODEL_ID_DET: length 7.6
  TOP w0.102: v1(131.1,66.55) 131.14,66.51 KBC1.95
  BOTTOM w0.102: v1(131.1,66.55) 130.02,65.47 R734.2 130.65,65.28 R733.1 131.1,65.94 131.99,66.83 v2(131.99,66.85) 132.11,66.73 C547.1
MONITOR_NAME_ID0: length 180.4
  TOP w0.102: v3(101.28,118.82) v4(101.28,121.16) 101.28,123.88 101.73,124.33 101.73,126.72 102.55,127.53 102.55,133.15 101.15,134.55 101.15,135.56 98.79,137.93 98.79,140.02 96.29,142.52 96.29,145.15 94.5,146.95 94.16,146.95 93.82,147.28 CPU1.BA5 ; v1(55.66,58.29) 55.57,58.21 SCA1.98
  L3 w0.127: v1(55.66,58.29) 55.21,57.85 54.71,57.85 54.45,58.11 46.31,66.25 46.31,76.01 36.47,85.85 36.47,120.38 45.88,129.79 v3(45.88,130.39)
  L4 w0.127: v3(101.28,118.82) 100.81,118.35 83.36,118.35 72.03,129.68 46.9,129.68 46.19,130.39 v3(45.88,130.39)
MONITOR_NAME_ID1: length 183.2
  TOP w0.102: SCA1.99 55.97,57.85 v1(56.42,58.29) ; CPU1.AY5 92.92,147.34 93.35,146.9 93.94,146.9 94.1,146.74 94.44,146.74 96.07,145.11 96.07,142.42 98.56,139.93 98.56,137.83 100.87,135.52 100.87,134.51 102.32,133.06 102.32,127.63 101.51,126.82 101.51,124.71 100.52,123.72 v4(100.52,123.06) v3(100.52,118.82)
  L3 w0.127: v3(45.31,131) 45.31,129.59 36.22,120.49 36.22,85.75 46.06,75.9 46.06,66.14 54.61,57.59 55.72,57.59 v1(56.42,58.29)
  L4 w0.127: v3(45.31,131) 45.94,131 47.01,129.93 72.14,129.93 83.16,118.91 97.06,118.91 97.44,119.29 100.05,119.29 v3(100.52,118.82)
MPCIE_DISABLE_N: length 214.4
  TOP w0.102: v3(163.48,207.77) 160.27,210.99 156.07,210.99 146.24,220.81 130.32,220.81 127.32,217.81 R45.1 ; v3(149.64,53.21) 149.36,53.5 KBC1.40
  BOTTOM w0.102: v3(149.64,53.21) 149.18,53.67 149.18,63.28 148.95,63.51 148.95,75.78 149.75,76.58 149.75,87.81 149.69,87.87 149.69,91.96 149.79,92.06 149.79,101.32 148.98,102.13 148.98,112.73 149.39,113.14 149.39,114.92 151.39,116.92 154.36,116.92 162.57,125.13 162.57,148.76 165.92,152.1 165.92,199.72 164.89,200.75 163.23,202.42 v2(163.23,205.99) 163.23,207.52 v3(163.48,207.77)
NCP81172_FB1: length 2
  BOTTOM w0.254: PC260.1 122.78,105.41 PR206.1 v2(121.83,105.47)
NCT_CLK: length 15.3
  TOP w0.102: RN6.3 151.2,72.41 v4(150.81,72.8) 150.09,72.08 150.09,71.17 149.26,70.34 U12.8 148.84,71.46 148.14,72.16 145.07,72.16 144.53,71.63 144.53,70.18 145.41,69.3 145.64,69.3 146.29,68.65 Q36.1
NCT_DATA: length 15
  TOP w0.102: Q36.4 147.62,66.91 147.23,67.31 147.23,68.4 145.84,69.79 145.74,69.79 145.21,70.32 v4(145.19,70.32) 145.19,70.36 145.02,70.54 145.02,71.43 145.27,71.68 147.94,71.68 148.19,71.43 U12.7 148.19,69.79 148.58,69.4 149.09,69.4 150.49,70.79 RN6.4
NGFF_ALERT#: length 260.2
  TOP w0.089: CPU1.H2 75.66,145.46 75.66,145.25 75.6,145.12 75.6,144.92 75.64,144.82 75.64,144.45 75.25,144.07
  TOP w0.102: R39.1 127.53,219.71 130.86,223.04 143.39,223.04 144.43,222 146.78,222 154.25,214.53 154.95,214.53 156.62,212.85 159.8,212.85 v3(163.36,209.3) ; RN16.1 73.03,142.21 v3(73.06,142.24) 74.89,144.07 75.25,144.07
  L4 w0.127: v3(73.06,142.24) 73.73,141.56 73.73,140.11 75.28,138.56 75.28,134.97 75.94,134.31 75.94,134 87.72,122.22 112.87,122.22 125.87,109.22 146.08,109.22 149.13,106.17 v3(149.64,106.17)
  BOTTOM w0.102: v3(149.64,106.17) 150.1,106.63 150.1,108.31 149.21,109.2 149.21,112.64 149.62,113.05 149.62,114.83 151.42,116.63 154.39,116.63 163,125.24 163,147.89 166.15,151.04 166.15,202.56 163.99,204.72 v2(163.99,208.41) 163.99,208.66 v3(163.36,209.3)
NGFF_ALERT_N: length 6
  TOP w0.102: NGFF1.62 119.25,220 120.16,220.9 121.7,220.9 v4(121.78,220.83) 122.21,220.83 123.33,219.71 R39.2
NGFF_BT_DISABLE: length 299.1
  TOP w0.102: R49.1 125,217.42 125.13,217.3 127.13,217.3 130.42,220.58 145.57,220.58 v4(150.07,216.08) 155.39,210.76 159.86,210.76 162.47,208.15 v3(162.47,207.77) ; CPU1.W4 81.6,146.64 v1(81.25,146.98) ; v3(127.11,66.28) 127.18,66.28 127.19,66.27 127.96,66.27 R365.1
  L4 w0.127: v1(81.25,146.98) 81.25,146.88 79.75,145.38 79.75,140.19 79.07,139.51 79.07,134.47 88.1,125.44 101.38,125.44 102.48,124.33 113.27,124.33 126.19,111.42 134.49,111.42 v3(134.91,111) 135.33,111.42 144.53,111.42 149.83,116.71 151.65,116.71 165.48,130.54 165.48,157.14 161.28,161.33 161.28,205.98 162,206.69 162,207.3 v3(162.47,207.77)
  BOTTOM w0.102: v3(127.11,66.28) 127.11,66.29 126.78,66.62 126.78,67.46 132.04,72.72 135.49,72.72 140.39,77.63 140.39,99.26 138.43,101.23 138.43,103.74 136.56,105.6 136.56,106.55 136.61,106.6 136.61,109.3 v3(134.91,111)
NGFF_BT_DISABLE_EC: length 8.6
  TOP w0.102: v3(130.06,66.67) R365.2 129.64,66.29 129.64,64.45 130.89,63.2 130.89,62.15 130.64,61.9 KBC1.100
  BOTTOM w0.102: v2(130.63,67.25) v3(130.06,66.67)
NGFF_CLKREQ0_N: length 6.8
  TOP w0.102: NGFF1.53 109.71,217.75 108.9,218.57 108.24,218.57 107.12,219.68 v4(107.12,220.07) 107.12,220.66 106.35,221.42 R31.1
NGFF_CLKREQ0_NGFF#: length 45.6
  TOP w0.102: R875.2 147.32,224.89 Q2.S 143.64,224.89 R6.2 v4(141.94,224.98) 141.5,225.42 107.74,225.42 105.82,223.51 R31.2
NGFF_CLKREQ1_N: length 9
  TOP w0.102: v4(125.89,221.62) 125.45,221.17 R36.2 123.38,220.34 122.22,221.5 NGFF1.68
NGFF_CLKREQ1_N_TP: length 1.3
  TOP w0.102: R36.1 126.59,220.6 TP6.1
NGFF_DETECT_PCIE: length 222.5
  TOP w0.102: CPU1.BB7 94.33,148.39 96.75,145.97 96.75,142.71 99.5,139.96 v3(99.5,139) 99.63,139.13 R166.1 ; R37.2 104.58,222.59 107.64,225.65 147.48,225.65 147.59,225.54 156.88,216.25 v3(156.88,215.26)
  L3 w0.127: v3(157.39,179.45) 156.62,178.69 156.62,165.14 155.07,163.58 155.07,130.65 153.83,129.41 153.83,127.94 153.46,127.57 130.49,127.57 129.16,128.91 110.29,128.91 108.95,130.24 107.69,130.24 101.51,136.43 101.51,137.79 100.3,139 v3(99.5,139)
  BOTTOM w0.102: v3(157.39,179.45) v2(157.39,196.06) 157.39,203.83 157.74,204.19 157.74,213.63 156.88,214.49 v3(156.88,215.26)
NGFF_DETECT_PCIE_C: length 7.2
  TOP w0.102: NGFF1.51 109.53,217.25 108.7,218.08 107.64,218.08 R43.2 107.28,218.76 106.48,219.56 v4(105.82,219.56) 104.74,219.56 R37.1
NGFF_DETECT_USB: length 251.1
  TOP w0.102: v1(81.29,147.64) 81.06,147.41 CPU1.U6 ; R64.2 116.16,200.8 v4(116.16,201.73) 117.13,202.69 117.13,205.87 v3(116.62,206.38)
  L4 w0.127: v1(81.29,147.64) 81.67,147.25 81.67,146.77 80,145.1 80,140.09 79.32,139.4 79.32,134.57 88.2,125.69 112.28,125.69 118.91,119.05 126.3,111.67 144.42,111.67 149.72,116.97 151.49,116.97 165.22,130.7 165.22,157.01 160.65,161.58 160.65,199.18 150.28,209.55 145.45,209.55 139.06,215.94 125.42,215.94 124.87,215.39 124.87,213.91 124.2,213.23 123.48,213.23 v3(116.62,206.38)
NGFF_DETECT_USB_C: length 10.3
  TOP w0.102: R64.1 114.83,199.51 114.4,199.51 v4(114.37,199.54) 114.37,199.55 114.4,199.58 R63.2 114.4,203.51 114.38,203.52 114.38,203.9 114.4,203.91 114.4,204.03 113.67,204.75 NGFF1.1
NGFF_PCIE0_RXN: length 4.5
  TOP w0.102: 107.93,214.36 107.3,214.36 R53.1 ; 107.93,214.36 108.55,214.36 109.29,215.11 109.58,215.11 109.72,215.25 NGFF1.43 ; 107.93,214.36 v4(107.93,214.71)
NGFF_PCIE0_RXP: length 5.6
  TOP w0.102: v4(106,212.75) 106.08,212.75 106.9,213.58 R54.1 107.31,214.15 108.64,214.15 109.38,214.89 109.58,214.89 109.73,214.75 NGFF1.41
NGFF_PCIE0_TXN: length 9
  TOP w0.102: 105.97,210.49 105.97,209.05 R55.1 ; 105.97,210.49 v4(105.62,210.49) ; 105.97,210.49 105.97,211.65 107.82,213.5 108.69,213.5 108.82,213.62 109.51,213.62 109.63,213.75 NGFF1.37
NGFF_PCIE0_TXP: length 8.7
  TOP w0.102: 108.41,213.28 v4(108.41,212.93) ; 108.41,213.28 108.78,213.28 108.91,213.41 109.48,213.41 109.63,213.25 NGFF1.35 ; 108.41,213.28 107.91,213.28 106.19,211.56 106.19,209.05 R56.1
NGFF_PCIE1_RXN: length 4.1
  TOP w0.102: TP4.1 107.86,222 107.73,221.87 107.73,221.49 107.83,221.39 108.77,221.39 109.05,221.11 109.36,221.11 109.5,221.25 NGFF1.67
NGFF_PCIE1_RXP: length 4.3
  TOP w0.102: TP3.1 107.26,222 107.51,221.74 107.51,221.4 107.74,221.17 108.68,221.17 108.96,220.89 109.36,220.89 109.5,220.75 NGFF1.65
NGFF_PCIE1_TXN: length 2.8
  TOP w0.102: TP5.1 108.36,220.32 108.63,220.05 108.78,220.05 108.87,219.96 109.23,219.61 109.36,219.61 109.5,219.75 NGFF1.61
NGFF_PCIE1_TXP: length 3
  TOP w0.102: TP7.1 108.36,219.71 108.49,219.84 108.69,219.84 108.72,219.81 109.14,219.39 109.36,219.39 109.5,219.25 NGFF1.59
NGFF_PEWAKE0_N: length 16
  TOP w0.102: R30.1 R34.2 122.49,222.03 v4(122.46,222.03) 122.45,222.05 118.47,222.05 NGFF1.70 118.42,222 116.37,222 112.62,218.25 NGFF1.55
NGFF_POWER_CTRL_1: length 15
  TOP w0.102: R62.1 163.99,207.91 160.19,211.71 155.99,211.71 v3(155.48,212.22)
  BOTTOM w0.102: v3(155.48,212.22) 154.24,212.22 v2(153.98,211.96) 154.78,211.16 Q48.G
NGFF_POWER_CTRL_V2: length 5.4
  BOTTOM w0.102: Q49.B 150.36,208.18 151.62,206.93 v2(151.62,206.88) C290.1 R540.1
NGFF_REFCLKN0: length 4.4
  TOP w0.102: NGFF1.49 109.5,216.75 109.36,216.61 108.42,216.61 108,217.02 107.93,217.02 ; v4(107.93,217.37) 107.93,217.02 ; 107.93,217.02 107.3,217.02 R46.1
NGFF_REFCLKN1: length 4
  TOP w0.102: NGFF1.73 109.5,222.75 109.36,222.61 109.07,222.61 108.8,222.88 107.86,222.88 107.73,223.01 107.73,223.29 107.96,223.52 TP2.1
NGFF_REFCLKP0: length 4.4
  TOP w0.102: v4(108.59,216.03) 108.59,216.39 ; 108.59,216.39 109.36,216.39 109.5,216.25 NGFF1.47 ; 108.59,216.39 108.33,216.39 107.91,216.81 107.3,216.81 R50.1
NGFF_REFCLKP1: length 4.4
  TOP w0.102: NGFF1.71 109.5,222.25 109.36,222.39 108.98,222.39 108.71,222.67 107.77,222.67 107.51,222.92 107.51,223.35 107.35,223.52 TP1.1
NGFF_W_DISABLE1_N: length 7.4
  TOP w0.102: R45.2 125.27,217.98 123.05,217.98 122.46,218.57 120.75,218.57 120.74,218.56 v4(120.68,218.56) 120.62,218.5 NGFF1.56
NGFF_W_DISABLE2_N: length 5.4
  TOP w0.102: R49.2 122.93,217.42 122.42,217.93 v4(122.24,217.93) 122.17,218 NGFF1.54
NGFFCLK_REQ_N: length 194.2
  TOP w0.102: Q2.D 147.66,223.9 147.99,223.57 147.99,222.95 148.24,222.69 R875.1 149.58,222.69 v3(156.37,215.9) 156.24,215.77 156.24,215.01 156.62,214.63 160.94,214.63 163.86,211.71 163.86,209.8 165.01,208.66 R876.2
  L4 w0.127: v1(108.24,129.16) 108.24,128.91 109.85,127.29 113.31,127.29 115.6,125 115.6,124.56 127.53,112.64 144.02,112.64 149.39,118 150.32,118 164.5,132.18 164.5,132.19 164.55,132.25 164.55,157.07 160.22,161.4 160.22,199 158.34,200.88 157.35,200.88 v3(156.88,200.41)
  BOTTOM w0.102: v3(156.37,215.9) 156.37,214.42 157.34,213.46 157.34,204.36 156.88,203.9 v3(156.88,200.41) ; v1(108.24,129.16) 108.24,130.05 v2(107.86,130.43) 107.28,131 R639.2
OS_MODE_SEL: length 125.1
  TOP w0.102: SCA1.47 61.97,72.99 62.26,73.28 62.26,74.3 v1(62.14,74.42) ; CPU1.AC2 83.55,145.39 83.55,144.27 84.07,143.75 84.07,139.99 v1(84.74,139.32) ; RN17.3 80.06,126.55 v3(80.37,126.86) 81.09,126.86 81.4,126.54 81.4,126.16 80.76,125.53 76.54,125.53 74.9,127.17 53.4,127.17 50.23,123.99 v3(50.23,123.35)
  L3 w0.127: v1(62.14,74.42) 62.15,74.43 62.15,75.73 61.3,76.58 54.78,76.58 45.08,86.28 45.08,89.51 43.89,90.71 43.89,117.67 49.56,123.35 v3(50.23,123.35)
  BOTTOM w0.102: v1(84.74,139.32) 85.43,138.63 85.43,136.06 80.43,131.06 v2(80.43,128.02) 80.43,126.91 v3(80.37,126.86)
OSD_BIST_N: length 191.6
  TOP w0.102: R476.2 32.11,28.07 v3(31.55,28.63) ; KBC1.39 143.41,53.1 v1(143.29,53.21)
  L3 w0.127: v3(31.55,28.63) 32.02,29.1 32.02,30.52 30.64,31.91 30.64,35.32 29.43,36.53 29.43,38.38 33.24,42.19 33.24,78.55 v3(33.43,78.74)
  L4 w0.127: v1(143.29,53.21) 143.99,53.91 143.99,55.83 141.71,58.1 132.63,58.1 131.76,57.23 123.96,57.23 123.06,58.13 104.52,58.13 103.68,58.97 83.83,58.97 81.11,61.68 74.91,61.68 72.14,64.45 66.45,64.45 64.91,62.92 56.63,62.92 54.2,65.35 54.2,70.8 54.33,70.93 54.33,71.43 53.22,72.53 v1(51.2,72.53)
  BOTTOM w0.102: v1(51.2,72.53) 51.2,75.26 R712.1 50.9,76.9 v2(47.53,80.26) 44.77,83.02 35.19,83.02 34.45,82.28 34.45,79.76 v3(33.43,78.74)
OSD_BIST_N_1: length 2.6
  BOTTOM w0.254: Q58.2 R712.2 51.79,74.61 v2(51.85,74.55)
OSD_CONTROL_SEL: length 125.2
  TOP w0.089: CPU1.M2 77.65,145.14 77.65,144.92 77.59,144.79 77.56,144.73 77.56,143.83 v1(78.01,143.38)
  TOP w0.102: v1(61.43,74.42) 62.01,73.85 62.01,73.35 61.74,73.08 61.74,73.02 61.57,72.85 SCA1.48 ; RN17.4 79.64,127.2 v3(79.87,127.43) 80.84,127.43 81.63,126.64 81.63,126.07 80.86,125.3 76.41,125.3 74.77,126.94 53.82,126.94 v3(50.77,123.89)
  L3 w0.127: v3(50.77,123.89) 49.74,123.89 43.63,117.77 43.63,90.6 44.83,89.41 44.83,86.18 54.68,76.33 61.19,76.33 61.89,75.62 61.89,74.88 v1(61.43,74.42)
  BOTTOM w0.102: v1(78.01,143.38) 77.81,143.38 77.1,142.67 77.1,139.57 77.45,139.21 77.45,137.72 78.14,137.03 78.14,134.62 77.5,133.99 v2(77.5,132.08) 77.5,129.15 79.22,127.43 v3(79.87,127.43)
OSD_DN: length 195.2
  TOP w0.102: v3(31.12,30.02) 31.01,29.91 C236.1 R470.1 29.18,29.9 R474.1 ; SCA1.43 63.57,72.85 63.87,73.15 63.87,74.31 66.14,76.57 66.14,77.91 v3(67.72,79.5) ; v3(37.63,127.76) 38.16,128.3 39.43,128.3 40.19,129.06 76.46,129.06 76.87,128.65 R205.2
  L3 w0.127: v3(31.12,30.02) 30.94,30.02 29.2,31.76 29.2,36.4 29.18,36.42 29.18,38.48 32.96,42.27 32.96,79.03 v3(33.43,79.5) 34.16,80.23 34.16,81.45 32.96,82.64 32.96,123.1 v3(37.63,127.76)
  BOTTOM w0.102: v3(67.72,79.5) 67.22,78.99 v2(66.2,78.99) 65.92,78.71 58.46,78.71 57.87,79.3 57.87,79.69 56.71,80.85 53.09,80.85 52.65,80.4 48.16,80.4 45.31,83.25 35.1,83.25 34.2,82.35 34.2,80.26 v3(33.43,79.5)
OSD_DN_CPU: length 25.1
  TOP w0.102: R205.1 78.55,127.92 79.28,127.92 v3(79.33,127.97) ; v1(84.74,138.56) 83.88,139.42 83.88,143.54 82.89,144.53 82.89,145.49 83.04,145.65 83.24,145.65 83.47,145.88 83.47,146.38 83.73,146.64 CPU1.AD4
  BOTTOM w0.102: v3(79.33,127.97) 79.33,130.28 84.87,135.82 v2(84.87,136.4) 85.17,136.7 85.17,138.13 v1(84.74,138.56)
OSD_DN_R: length 6
  TOP w0.102: PWRCN1.2 30.38,24.25 30.64,24.51 30.64,25.27 30.26,25.65 30.26,26.67 31,27.41 v4(31,27.97) 30.13,28.83 R474.2
OSD_MENU: length 290.1
  TOP w0.102: v3(150.91,68.83) 150.91,67.01 150.17,66.27 150.17,65.3 148.81,63.94 R378.2 ; v3(37.63,129.29) 38.08,128.84 39.33,128.84 40.03,129.54 56.17,129.54 60.99,134.37 62.77,134.37 63.66,135.25 R163.2 ; v3(66.96,79.5) 65.91,78.45 65.91,76.67 63.64,74.4 63.64,73.32 63.17,72.85 SCA1.44
  L3 w0.127: v3(31.64,24.26) 31.64,27.45 28.7,30.39 28.7,30.42 28.7,36.19 28.67,36.21 28.67,38.69 32.46,42.48 32.46,80.05 v3(33.43,81.03) 33.43,81.28 32.46,82.26 32.46,124.12 v3(37.63,129.29)
  L4 w0.127: v3(66.96,79.5) 67.43,79.03 75.33,79.03 76.48,77.88 83.18,77.88 90.37,70.69 100.62,70.69 102.08,69.23 118.83,69.23 120.57,70.97 131.22,70.97 132.17,70.02 137.42,70.02 137.52,69.91 141.05,69.91 141.12,69.98 149.77,69.98 v3(150.91,68.83)
  BOTTOM w0.102: v3(31.64,24.26) 31.59,24.3 R834.1 C588.1 R831.1 ; v3(33.43,81.03) 33.97,81.56 33.97,82.45 35,83.48 45.4,83.48 48.25,80.63 52.55,80.63 53,81.08 56.8,81.08 58.1,79.78 58.1,79.4 58.55,78.94 64.12,78.94 v2(64.55,79.38) 64.68,79.5 v3(66.96,79.5)
OSD_MENU_CPU: length 21.3
  TOP w0.089: 77.33,143.43 77.33,144.4 77.38,144.51 77.38,144.79 77.4,144.81 77.45,144.91 77.45,145.3 77.58,145.44 77.58,145.72 CPU1.M3
  TOP w0.102: 77.33,143.43 77.88,142.88 78.34,142.88 78.8,142.42 78.8,140.36 78.27,139.83 v4(77.88,139.83) 77.88,139.4 77.55,139.06 77.55,138.76 74.28,135.48 67.85,135.48 67.62,135.25 R163.1
OSD_MENU_R: length 8
  TOP w0.102: PWRCN1.1 29.93,26.5 v3(28.81,27.61) 28.68,27.74 28.68,28.8 v4(28.18,29.31)
  BOTTOM w0.102: R831.2 28.76,26.16 v2(28.35,26.57) 28.35,27.16 v3(28.81,27.61)
OSD_UP: length 201.1
  TOP w0.102: v3(31.55,29.39) 32.37,29.39 33.24,28.52 R476.1 R477.1 R483.2 32.86,25.65 C246.1 ; v3(68.49,79.5) 67.98,78.99 67.68,78.99 66.37,77.67 66.37,76.48 64.1,74.21 64.1,73.03 63.97,72.9 SCA1.42 ; R201.2 76.55,129.29 40.1,129.29 39.34,128.52 v3(37.62,128.52)
  L3 w0.127: v3(31.55,29.39) 31.09,29.39 28.95,31.53 28.95,36.29 28.93,36.32 28.93,38.59 32.71,42.37 32.71,79.54 v3(33.43,80.26) 33.9,80.73 33.9,81.32 32.71,82.51 32.71,123.62 v3(37.62,128.52)
  BOTTOM w0.102: v3(68.49,79.5) 68.03,79.96 63.23,79.96 v2(62.9,79.63) 62.44,79.17 58.64,79.17 58.33,79.49 58.33,79.88 56.9,81.31 52.9,81.31 52.46,80.86 48.35,80.86 45.5,83.71 34.71,83.71 32.98,81.98 32.98,80.72 v3(33.43,80.26)
OSD_UP_CPU: length 21.9
  TOP w0.089: 84.08,145.52 84.08,145.51 84.08,144.91 84.03,144.81 84.03,144.81 84.03,144.35 84.29,144.09 84.29,143.76
  TOP w0.102: CPU1.AD3 84.48,145.91 84.08,145.52 ; v3(78.77,128.52) 78.77,128.65 77.82,129.6 R201.1 ; 84.29,143.76 84.29,140.54 v1(84.74,140.08)
  BOTTOM w0.102: v1(84.74,140.08) 84.31,139.65 84.31,135.59 78.77,130.05 v2(78.77,129.54) v3(78.77,128.52)
OSD_UP_R: length 4.9
  TOP w0.102: R477.2 31.94,27.05 v4(30.94,26.06) 30.94,24.18 30.51,23.75 PWRCN1.3
OZ554_ENA: length 10
  TOP w0.102: R481.1 40.55,26.29 v3(40.93,26.67) 41.69,26.67 41.82,26.8 v4(41.82,27.18) 41.44,27.56 40.1,27.56 C244.1
  BOTTOM w0.102: R836.1 41.51,24.88 41.51,25.76 40.93,26.34 v3(40.93,26.67) 39.53,26.67 39.28,26.42 U36.3
OZ554_PWM: length 6.2
  TOP w0.254: R487.1 41.05,24.64 v3(40.93,24.51) 40.8,24.38 C249.1 R496.1
  BOTTOM w0.254: U36.5 38.75,25.42 39.78,24.38 v2(39.91,24.38) 40.04,24.51 v3(40.93,24.51)
OZ554_VIN: length 5
  TOP w0.508: R484.2 41.08,25.65 v3(40.95,25.53) 40.7,25.27 C245.1
  BOTTOM w0.305: 40.16,25.92 v2(39.81,25.92) U36.4
  BOTTOM w0.508: v3(40.95,25.53) 40.56,25.92 40.16,25.92
P3P3V: length 120.5
  TOP w0.305: C162.1 155.04,65.53 v4(155.76,65.53) 156.46,64.83 U13.1
  TOP w0.508: C162.1 C161.1 153.51,65.09 152.94,64.52 v3(152.94,63.63)
  L4 w0.508: v3(152.94,63.63) 151.54,62.23 149.89,62.23 147.99,60.33 142.77,60.33 141.27,58.83 132.21,58.83 131.31,57.92 124.25,57.92 123.35,58.83 104.81,58.83 103.97,59.66 84.12,59.66 77.96,65.82 75.05,65.82 74.99,65.76 73.21,65.76 72.68,66.29 64.04,66.29 v1(63.53,65.79)
  BOTTOM w0.508: 60.05,64.85 59.55,65.35 59.55,66.9 58.66,67.79 C539.1 58.66,68.5 58.2,68.96 L24.1 58.2,69.85 58.26,69.91 R718.1 60.23,69.91 61.44,71.12 U31.3 ; 60.05,64.85 60.05,61.29 Q61.S ; 60.05,64.85 60.61,65.4 60.93,65.72 R729.1 62.33,65.79 v1(63.53,65.79) L25.1
P5P0V: length 5.8
  BOTTOM w0.508: v2(62.42,76.12) 63.53,76.12 R711.2 63.72,75.45 C532.1 61.99,72.57 U31.4
P2800_DXN: length 53.5
  TOP w0.127: Q24.E 169.04,112.39 R250.2 165.2,112.39 C86.2 164.43,111.63 163.3,111.63 v3(163,111.93) 162.85,111.93 v4(162.14,112.65) ; v3(148.71,77.85) 148.33,77.47 148.14,77.47 147.89,77.23 147.89,76.55 C133.2 147.54,76.19 U12.3
  L4 w0.127: v3(148.71,77.85) 148.97,77.6 149.3,77.6 155.91,84.2 157.03,84.2 157.89,85.07 157.89,90.2 162.09,94.39 162.09,111.25 162.46,111.63 162.7,111.63 v3(163,111.93)
P2800_DXP: length 53.7
  TOP w0.127: U12.2 148.19,75.95 C133.1 148.15,76.49 148.15,77.12 148.24,77.22 148.58,77.22 v3(148.71,77.09) ; Q24.B 168.28,111.63 Q24.C 166.53,111.63 R250.1 164.94,110.87 C86.1 164.43,111.38 163.3,111.38 v3(163,111.08) 162.29,111.08 v4(161.86,110.64)
  L4 w0.127: v3(163,111.08) 162.7,111.38 162.57,111.38 162.34,111.15 162.34,94.28 158.15,90.09 158.15,84.96 157.13,83.95 156.01,83.95 149.41,77.34 148.97,77.34 v3(148.71,77.09)
PANEL_OFF: length 120.4
  TOP w0.102: v3(60.74,79.63) R316.2 R317.2 62.86,78.8 Q32.D ; v3(39.15,129.31) 39.74,129.9 41.16,129.9 41.56,130.3 43.82,130.3 44.23,129.9 55.87,129.9 62.2,136.22 73.27,136.22 73.45,136.4 74.15,136.4 76.82,139.06 76.82,146.34 CPU1.J4
  L4 w0.127: v3(60.74,79.63) 60.27,79.16 54,79.16 52.77,80.39 49.28,80.39 46.48,83.19 46.48,119.03 39.97,125.53 39.97,127.95 39.32,128.61 39.15,128.78 v3(39.15,129.31)
  BOTTOM w0.102: v3(39.15,129.31) 39.15,129.31 39.83,129.31 39.84,129.31 v2(39.96,129.31)
PANEL_OFF_C: length 20.5
  TOP w0.102: R321.2 67.8,78.17 68.94,79.31 68.94,79.69 68.68,79.96 65.16,79.96 Q32.G 64.99,79.79 64.99,77.32 64.5,76.83 62.83,76.83 R317.1 v4(61.76,76.76) 62.01,76.5 62.01,75.21 61.68,74.88 61.5,74.88 61.48,74.85 60.54,74.85 59.29,73.6 59.29,73.23 59.57,72.94 SCA1.53
PANEL_ON: length 18
  TOP w0.102: R326.1 R325.2 71.84,75.68 71.84,74.17 v4(71.25,73.58) 70.52,74.31 v1(70.52,74.42) ; v1(60.72,74.42) 60.18,73.88 60.18,73.06 59.97,72.85 SCA1.52
  L4 w0.127: v1(60.72,74.42) 61.17,74.87 70.07,74.87 v1(70.52,74.42)
PANEL_ON1: length 5.8
  TOP w0.152: R326.2 74.49,76.43 v4(75.55,76.43) 75.55,76.08 74.26,74.8 74.26,73.6 74.46,73.41 Q34.2
PANEL_ON2: length 9.1
  TOP w0.152: 72.69,72.76 Q34.6 ; 72.69,72.76 72.22,72.28 v4(72.22,71.55) 72.3,71.48 73.24,71.48 73.74,71.98 75.31,71.98 75.85,71.44 75.85,70.9 RN21.3 ; 72.69,72.76 72.55,72.9 72.55,73.28 72.68,73.41 Q34.5
PANEL_ON3: length 3.6
  TOP w0.152: 76.87,73.08 77.44,73.65 R339.2 ; 76.87,73.08 v4(76.87,73.03) ; 76.87,73.08 75.89,74.06 Q34.3
PANEL_ON_1: length 8
  BOTTOM w0.102: R881.2 33.69,105.03 34.58,104.14 37.24,104.14 v2(38.01,104.9) 38.26,104.9 39.33,105.97 U40.3
PANEL_ON_2: length 4.9
  BOTTOM w0.102: C629.1 35.66,104.78 v2(35.97,104.78) 35.97,107.06 36.48,107.57 U40.5
PANEL_ON_3: length 7.2
  BOTTOM w0.102: R882.1 38.9,111.76 v2(38.13,111) 38.13,106.81 37.95,106.62 U40.4
PANEL_SEL1_CABLE: length 188.9
  TOP w0.102: v1(127.84,59.41) 128.15,59.1 KBC1.107
  L4 w0.127: v1(55.66,66.8) 56.48,65.98 59.05,65.98 59.6,66.52 59.6,66.92 62.19,69.52 70.44,69.52 71.19,68.77 71.88,68.77 72.68,69.57 76.19,69.57 76.49,69.28 77.31,69.28 80.68,65.91 81.31,65.91 85.89,61.34 v3(88.68,61.34) 90.37,61.34 91.22,60.49 104.34,60.49 105.18,59.65 125.45,59.65 126.01,60.21 127.05,60.21 127.8,59.47 127.8,59.45 v1(127.84,59.41) ; v3(26.58,35.31) 27.59,34.29 27.59,31.37 34.06,24.9 34.06,24.31 34.34,24.03 41.24,24.03 41.64,24.43 41.64,27.61 44.86,30.84 48.78,30.84 53.12,35.18 59.15,35.18 69.25,45.28 71.78,45.28 72.01,45.5 89.61,45.5 91.6,43.51 v3(91.6,42.8)
  BOTTOM w0.102: v3(88.68,61.34) 88.68,59.49 90.9,57.27 90.9,45.68 v2(91.22,45.36) 91.6,44.98 v3(91.6,42.8) ; v1(55.66,66.8) 55.66,67.06 55.14,67.58 53.8,67.58 R721.1 ; v3(26.58,35.31) R813.1
PANEL_SEL1_CABLE_C: length 6.9
  TOP w0.102: CONVT1.7 29.72,35.15 v3(29.75,35.18) 30.67,34.26 v4(32.09,34.26)
  BOTTOM w0.102: R816.2 R813.2 28.52,35.53 29.4,35.53 v3(29.75,35.18)
PANEL_SEL1_CABLE_S: length 3.1
  TOP w0.102: v1(53.12,71.25) 53.27,71.25 53.63,70.89 53.63,70.59
  BOTTOM w0.102: v1(53.12,71.25) v2(53.12,70.36) 53.12,69.15 R721.2
PANEL_SEL2_CABLE: length 186.2
  TOP w0.102: KBC1.106 128.39,59.5 v1(127.77,60.12)
  L4 w0.127: v1(56.42,66.8) 56.87,66.36 58.89,66.36 59.21,66.68 59.21,67.08 62.04,69.9 70.6,69.9 71.35,69.15 71.72,69.15 72.52,69.95 76.35,69.95 76.64,69.66 76.96,69.66 79.09,69.66 86.74,62.01 88.08,62.01 v3(88.17,62.1) 90.15,62.1 91.38,60.87 104.5,60.87 105.34,60.03 125.29,60.03 125.85,60.59 127.3,60.59 v1(127.77,60.12) ; v3(26.58,33.27) 27.08,32.77 27.08,31.34 33.68,24.74 33.68,24.15 34.94,22.9 38.3,22.9 39.03,23.62 41.36,23.62 41.39,23.65 41.4,23.65 42.02,24.28 42.02,27.38 45.09,30.45 48.93,30.45 53.28,34.8 59.31,34.8 69.41,44.89 71.94,44.89 72.17,45.12 89.3,45.12 90.84,43.59 v3(90.84,42.93)
  BOTTOM w0.102: R819.1 v3(26.58,33.27) ; R720.1 54.99,68.24 v1(56.42,66.8) ; v3(90.84,42.93) v2(90.84,44.2) 90.54,44.49 90.54,57.12 88.17,59.5 v3(88.17,62.1)
PANEL_SEL2_CABLE_C: length 5.7
  TOP w0.102: CONVT1.8 29.26,34.15 v3(29.75,33.66) 30.31,33.1 v4(30.56,33.1)
  BOTTOM w0.102: RN20.3 28.7,32.87 R819.2 29.37,33.27 v3(29.75,33.66)
PANEL_SEL2_CABLE_S: length 4.4
  TOP w0.102: v1(54.92,70.1) 54.84,70.19 53.63,70.19
  BOTTOM w0.102: v1(54.92,70.1) 54.92,70.71 v2(54.64,70.99) 54.16,70.51 R720.2
PANEL_SEL3_CABLE: length 184.3
  TOP w0.102: v1(131.22,59.69) 130.79,60.12 130.28,60.12 130.06,59.9 KBC1.105
  L4 w0.127: v1(58.71,66.8) 58.71,67.5 61.48,70.27 61.86,70.27 61.93,70.33 76.51,70.33 76.8,70.04 79.25,70.04 86.81,62.48 v3(87.41,62.48) 87.5,62.57 90.21,62.57 91.53,61.25 104.66,61.25 105.49,60.41 125.14,60.41 125.69,60.97 127.64,60.97 129.36,59.25 130.78,59.25 v1(131.22,59.69) ; v3(26.58,30.99) 26.83,30.73 27.15,30.73 33.3,24.58 33.3,23.99 34.78,22.52 38.46,22.52 39.19,23.24 41.56,23.24 42.45,24.13 42.45,27.2 45.32,30.07 49.09,30.07 53.43,34.42 59.47,34.42 69.57,44.51 72.1,44.51 72.33,44.74 88.87,44.74 90.08,43.54 v3(90.08,42.93)
  BOTTOM w0.102: v3(87.41,62.48) v2(87.41,60.96) 87.41,59.76 90.19,56.98 90.19,43.67 90.08,43.56 v3(90.08,42.93) ; v1(58.71,66.8) 58.9,66.61 R730.1 ; v3(26.58,30.99) 27.34,30.23 R827.1
PANEL_SEL3_CABLE_C: length 8.5
  TOP w0.102: v4(31.99,31.78) 30.74,31.78 v3(29.75,32.77) 29.37,33.15 CONVT1.9
  BOTTOM w0.102: R827.2 28.29,31.02 RN20.4 28.7,31.42 29.94,31.42 30.21,31.69 30.21,32.31 v3(29.75,32.77)
PANEL_SEL3_CABLE_S: length 7.2
  TOP w0.102: 53.63,65.79 57.06,65.79 57.95,66.67 v1(57.95,66.8)
  BOTTOM w0.102: v2(58.96,64.9) 58.91,64.9 58.01,65.8 R730.2 58.01,66.74 v1(57.95,66.8)
PB_IN_N_1: length 36.6
  TOP w0.102: R429.2 123.35,50.74 R428.2 ; R429.2 123.16,51.5 121.65,53 121.65,57.2 120.94,57.91 119.92,57.91 116.24,61.59 116.24,62.1 117.28,63.14 121.12,63.14 121.17,63.2 122.72,63.2 128.99,69.47 129.62,69.47 v4(130.03,69.88) 130.25,69.88 R362.1 ; R429.2 C190.1
PB_IN_SW1: length 14.2
  TOP w0.254: v4(26.35,28.6) 25.49,27.75 25.49,24.32 v3(27.21,22.61) 27.57,22.25 PWRCN1.6
  BOTTOM w0.254: R837.1 28.25,23.56 R839.2 D22.2 26.83,22.99 v3(27.21,22.61) v2(28.1,22.61)
PC_MONITOR_SW: length 111.3
  TOP w0.102: U13.7 159.43,62.24 158.53,61.33 158.53,60.96 v3(158.48,60.91) 158.48,60.44 R388.2 157.67,60.11 156.46,61.32 U13.5 ; SCA1.39 65.17,73.29 v1(65.06,73.41) 65.49,73.84 65.95,73.84 66.33,74.22 66.62,74.22 R329.1
  L4 w0.127: v1(65.06,73.41) 65.5,72.96 80.14,72.96 88.88,64.22 90.9,64.22 91.12,64.01 124.42,64.01 124.75,64.34 125.31,64.34 125.32,64.33 125.69,64.33 125.71,64.34 130.05,64.34 130.32,64.07 141.64,64.07 141.96,64.39 144.12,64.39 144.41,64.1 149.87,64.1 154.1,64.1 157.29,60.91 v3(158.48,60.91)
  BOTTOM w0.102: v3(158.48,60.91) 159.19,61.62 v2(159.27,61.62)
PC_MONITOR_SW_G: length 12.5
  TOP w0.152: v3(161.02,60.05) 161.02,59.89 160.37,59.25 C173.2 R387.1 158.17,59.25 R388.1 ; Q38.G 163.16,65.85 v3(162.59,65.28)
  L3 w0.152: v3(162.59,65.28) 162.34,65.53 162.04,65.53 160.46,63.95 160.46,60.6 v3(161.02,60.05)
  BOTTOM w0.152: v2(161.78,65.53) 162.34,65.53 v3(162.59,65.28)
PCB_VER_ID: length 7.1
  TOP w0.102: KBC1.98 130.42,62.7 v1(130.46,62.74)
  BOTTOM w0.102: R740.1 129.19,63.44 v2(129.19,62.99) 130.08,62.99 130.89,63.8 R741.1 C548.2 130.59,62.87 v1(130.46,62.74)
PCH_ALW_ON: length 84.3
  TOP w0.102: KBC1.20 138.34,48.39 137.55,47.6 137.55,45.43 137.62,45.36 137.62,43.99 135.92,42.29 134.86,42.29 134.35,41.78 128.53,41.78 128.43,41.88 124.78,41.88 124.44,42.22 124.26,42.22 123.05,43.43 121.95,43.43 119.96,45.43 110.11,45.43 v3(110.02,45.34)
  L3 w0.127: v3(110.02,45.34) 109.51,44.83 109.16,44.83 103.45,39.12 103.45,36.07 112.31,27.2 122.47,27.2 125.09,24.58 125.09,18.25 v3(124.75,17.91)
  BOTTOM w0.102: v3(124.75,17.91) 125.32,17.33 v2(125.32,16.51) 125.38,16.51 125.76,16.89 125.76,17.84 R859.1
PCH_AUD_RST_N: length 20.2
  TOP w0.102: v3(149.64,51.18) 149.13,51.69 146.34,51.69 145.8,51.16 145.8,50.7 145.45,50.34 143.66,50.34 143.49,50.51 142.87,50.51 142.34,49.98 KBC1.30
  L4 w0.127: v3(152.18,43.94) 149.64,46.48 v3(149.64,51.18)
  BOTTOM w0.102: R788.1 v2(153.12,43.94) v3(152.18,43.94)
PCH_AUD_RST_N_1: length 4.4
  BOTTOM w0.102: Q71.2 155.48,41.91 155.61,42.04 155.61,43.88 R788.2 154.85,44.64 v2(154.85,45.34)
PCH_DPWROK: length 162.7
  TOP w0.102: R358.2 137.7,68.33 v1(135.92,66.55) ; CPU1.BB20 94.77,155.2 99.29,155.2 100.15,156.06 100.96,156.06 101.63,156.72 101.63,158.05 R130.2 102.56,158.98 105.02,158.98 113.31,150.69 113.31,126.54 112.89,126.11 112.89,124.21 117.2,119.89 121.7,119.89 122.69,118.9 127.05,118.9 130.63,115.32 136.84,115.32 151.47,100.69 151.47,91.29 150.47,90.3 v3(146.97,90.3) ; v1(146.08,65.41) 148.55,65.41 v4(148.73,65.23) 148.73,64.94 148.18,64.39 R885.1 R884.1
  L3 w0.127: v1(135.92,66.55) 135.92,68.43 142.7,75.22 142.7,86.03 v3(146.97,90.3)
  L4 w0.127: v1(146.08,65.41) 145.96,65.53 143.36,65.53 141.82,67.07 140.64,67.07 139.68,66.1 136.37,66.1 v1(135.92,66.55)
PCH_DPWROK_EC13: length 5.2
  TOP w0.102: R885.2 147.29,64.13 v4(146.83,64.59) 145.83,63.6 145.83,62.61 145.51,62.3 KBC1.62
PCH_DPWROK_EC76: length 22
  TOP w0.102: R884.2 146.21,62.1 v1(146.08,62.23) ; KBC1.83 135.94,63.61 136.69,62.87 137.93,62.87 138.51,62.28 138.51,61.65 137.32,60.45 v1(137.32,59.46)
  L4 w0.127: v1(137.32,59.46) 137.99,60.13 141.95,60.13 142.59,60.77 146.01,60.77 146.53,61.28 146.53,61.79 v1(146.08,62.23)
  BOTTOM w0.102: v1(137.32,59.46) 137.32,60.3 v2(138.26,61.24)
PCH_DVI_CLK: length 8.4
  TOP w0.102: R411.1 75.22,53.91 75.22,54.12 76.21,55.11 76.21,57.48 75.63,58.05 Q39.1 74.06,58.05 v4(73.46,58.65)
PCH_DVI_DATA: length 3.6
  TOP w0.102: R409.1 76.04,54.26 76.49,54.71 76.86,54.71 77.38,55.22 v4(77.38,55.37) 77.38,56.3 Q39.4
PCH_JTAG_TCK: length 77.7
  TOP w0.102: CPU1.B56 72.13,176.59 71.86,176.33 70.94,176.33 70.41,175.79 69.01,175.79 68.85,175.63 67.92,175.63 67.67,175.39 67.67,174.32 67.17,173.81 65.74,173.81 65.03,173.1 63.98,173.1 R113.1 63.03,174.05 63.03,177.8 63.63,178.41 63.63,180.97 v3(64.04,181.38) ; R28.1 R26.2 53.39,224.23 58.63,224.23 60.74,222.12 v3(60.74,220.88)
  BOTTOM w0.102: v3(60.74,220.88) 61.7,219.91 v2(62.42,219.91) 63.95,219.91 68.38,215.49 68.38,194.97 65.94,192.53 64.98,192.53 63.36,190.91 63.36,182.45 64.04,181.76 v3(64.04,181.38)
PCH_JTAG_TDI: length 92.1
  TOP w0.089: 69.45,177.32 70.5,177.32 70.84,177.66 71.75,177.66 71.87,177.71 72.16,177.71 72.26,177.66 72.72,177.66 72.77,177.61 73.16,177.61 73.49,177.95 CPU1.D59
  TOP w0.102: v3(64.42,179.83) 64.09,179.5 64.09,178.16 63.71,177.77 63.71,177.07 64.3,176.48 64.74,176.48 65.44,175.78 65.44,175.47 65.6,175.31 66.31,175.31 R110.1 67.32,176.32 68.57,176.32 68.82,176.57 68.82,177.05 69.08,177.32 69.45,177.32 ; v3(38.01,225.43) R14.1
  L4 w0.127: v3(66.33,220.88) 66.33,222 62.91,225.43 51.57,225.43 50.6,226.4 38.98,226.4 v3(38.01,225.43)
  BOTTOM w0.102: v3(64.42,179.83) 65.21,180.62 65.21,189.64 v2(65.64,190.06) 66.05,190.47 66.05,191.26 66.58,191.79 69.3,194.51 69.3,217.77 66.33,220.75 v3(66.33,220.88)
PCH_JTAG_TDO: length 105.9
  TOP w0.102: v3(34.96,225.43) 34.93,225.4 34.93,224.62 R11.1 ; v3(64.09,180.52) 63.86,180.29 63.86,178.25 63.48,177.87 63.48,176.07 64.04,175.51 64.04,174.18 R114.1 65.17,174.04 67.07,174.04 67.44,174.41 67.44,175.74 67.56,175.86 68.76,175.86 68.92,176.02 70.37,176.02 70.94,176.59 CPU1.A56
  L4 w0.127: v3(64.8,220.88) 65.27,220.41 68.93,220.41 69.21,220.68 69.21,222.19 63.73,227.67 37.21,227.67 v3(34.96,225.43)
  BOTTOM w0.102: v3(64.8,220.88) v2(66.07,219.61) 66.86,219.61 68.36,218.11 68.36,216.49 69.07,215.78 69.07,194.6 66.49,192.02 65.82,191.35 65.82,191.07 64.93,190.18 64.93,181.36 v3(64.09,180.52)
PCH_JTAG_TMS: length 88.7
  TOP w0.089: 69,178.1 69.32,178.1 69.47,177.95 70.24,177.95 70.67,178.38 72.26,178.38 72.44,178.21 72.73,178.21 CPU1.C59
  TOP w0.102: v3(38.77,225.43) 38.77,224.85 R15.1 ; 69,178.1 66.8,178.1 66.77,178.13 66.39,178.13 65.69,177.43 R105.1 64.61,177.36 v3(64.55,177.42)
  L4 w0.127: v3(38.77,225.43) 39.49,226.15 50.49,226.15 51.47,225.17 62.8,225.17 65.57,222.41 v3(65.57,220.88)
  BOTTOM w0.102: v3(65.57,220.88) 66.02,221.34 66.52,221.34 66.96,220.89 66.96,220.48 69.53,217.92 69.53,194.41 66.68,191.56 66.28,191.16 66.28,189.97 65.44,189.13 65.44,188.55 65.44,179.35 v2(65.16,179.07) 65.16,178.03 v3(64.55,177.42)
PCH_POPIRCOMP: length 10.7
  TOP w0.203: v1(90.87,154.2) 90.88,154.2 91.2,153.88 CPU1.AU16
  L3 w0.203: v1(96.43,153.67) 95.43,154.66 91.33,154.66 v1(90.87,154.2)
  BOTTOM w0.203: R593.1 96.22,152.13 97.22,152.13 v2(97.52,152.43) 96.43,153.52 v1(96.43,153.67)
PCH_PWROK: length 149.4
  TOP w0.102: R217.1 109.51,122.56 TP82.1 111.92,120.14 v3(111.92,118.75) ; Q7.D 15.46,179.71 v3(14.38,179.71) 13.56,179.71 R102.1
  L4 w0.127: v3(14.38,179.71) 14.44,179.71 15.87,178.28 15.87,164.99 16.06,164.8 16.06,164.65 21.46,159.25 21.46,153.63 20.49,152.66 20.49,146.9 21.34,146.05 23.12,146.05 28.71,140.46 31.67,140.46 34.49,137.64 34.49,136.92 37.8,133.6 40.45,133.6 41.18,132.87 41.18,132.78 45.43,128.54 71.56,128.54 83.09,117.01 110.18,117.01 v3(111.92,118.75)
PCH_PWROK_C_1: length 14.1
  TOP w0.152: Q8.6 17.61,178.96 Q7.G 18.45,179.8 18.45,184.83 19.07,185.44 21.01,185.44 22.15,186.59 v4(22.15,186.7) 22.45,186.99 R77.2
PCH_PWROK_C_2: length 4.8
  TOP w0.152: Q8.2 15.25,176.53 14.64,177.14 14.1,177.14 14.08,177.16 v3(14.07,177.16) 14.05,177.14 13.67,177.14 12.77,176.24 R108.2
  BOTTOM w0.152: v2(13.22,177.11) 14.02,177.11 v3(14.07,177.16)
PCH_PWROK_C_3: length 16.4
  TOP w0.152: R78.2 24.06,187.23 v4(24.06,186.27) 22.95,185.17 22.23,185.17 19.19,185.17 18.83,184.8 18.83,177.4 17.96,176.53 Q8.5
PCH_RTCRST_DOWN: length 3.8
  TOP w0.102: JMP1.2 110.65,108.2 108.62,110.24 R254.1
PCH_RTCRST_PULLUP: length 83.1
  TOP w0.102: v3(107.86,118.75) 107.86,120.78 106.97,121.67 106.97,125.25 109.51,127.79 109.51,141.48 105.96,145.03 v3(105.06,145.03) ; CPU1.AM16 87.95,153.61 v1(88.27,153.29)
  BOTTOM w0.102: Q83.D 113.63,108.14 JMP1.1 114.84,109.35 114.84,113.79 113.63,115 110.97,115 107.86,118.11 v3(107.86,118.75) ; v3(105.06,145.03) 105.32,145.29 106.37,145.29 109.13,148.05 R590.2 108.55,150.62 107.67,150.62 107.16,151.13 C381.1 106.14,151.26 R589.1 105.33,150.57 v2(104.43,150.57) 94.3,150.57 92.84,152.03 92.68,152.03 91.83,152.88 88.68,152.88 v1(88.27,153.29)
PCH_SATA_LED_1: length 5.3
  BOTTOM w0.254: Q78.6 24.15,21.7 24.34,21.9 24.62,21.9 24.8,21.72 Q78.5 24.8,20.35 25.15,19.99 v2(25.15,19.51) 25.15,18.96 R851.2
PCH_SATA_LED_R: length 3.6
  BOTTOM w0.254: R833.2 24.95,24.83 25.18,24.6 v2(25.18,24.59) 25.18,24.2 25.04,24.06 25.04,23.59 24.8,23.34 Q78.2
PCH_SRTCRSTB_PULLUP: length 23.8
  TOP w0.102: v1(88.96,154.2) 88.6,154.56 CPU1.AN18
  BOTTOM w0.102: R578.2 R585.1 C379.1 106.14,152.15 R589.2 104.95,151.08 v2(100.29,151.08) 99.66,151.08 99.35,150.76 94.37,150.76 94.09,151.05 94.09,152.57 93.73,152.93 93.24,152.93 92.41,153.77 89.39,153.77 v1(88.96,154.2)
PCH_SYSPWROK_G: length 4.4
  TOP w0.102: v4(149.05,84.94) 149.05,84.51 148.43,83.88 R292.1 R291.1 146.91,83.06 Q29.G
PCH_THERMTRIP_N: length 3.9
  TOP w0.102: R94.2 65.6,181.43 66.57,181.43 v3(66.58,181.42) 66.59,181.43 67.2,181.43 R96.1
  BOTTOM w0.102: v2(67.3,182.57) 67.3,182.13 v3(66.58,181.42)
PCH_WAKE_N: length 6.1
  TOP w0.102: R136.1 99.84,152.22 v4(97.57,152.22) 96.12,152.22 95.05,153.29 94.37,153.29 CPU1.BB15
PCIE_CLKREQ1_CPU_N: length 23.4
  TOP w0.102: CPU1.AT7 90.55,148.13 v1(90.22,147.8)
  BOTTOM w0.102: v1(90.22,147.8) 90.63,147.4 91.39,147.4 91.88,146.91 91.88,146.74 93.93,144.69 94.26,144.69 98.89,140.06 98.89,138.91 104.35,133.45 v2(104.35,133.22) 104.66,132.91 R636.1
PCIE_CLKREQ2_CPU_N: length 29.9
  TOP w0.102: v1(90.87,148.72) 90.55,149.04 CPU1.AT8
  BOTTOM w0.102: v1(90.87,148.72) 90.46,149.13 89.41,149.13 88.97,148.69 88.97,147.36 89.36,146.98 89.36,146.52 90.14,145.73 92.03,145.73 94.49,143.28 94.69,143.28 98.66,139.31 98.66,137.35 104.43,131.58 v2(104.43,131.32) 105.63,130.11 R639.1
PCIE_CLKREQ3_CPU_N: length 21.6
  TOP w0.102: CPU1.AT10 90.55,150.22 v1(90.22,150.55)
  BOTTOM w0.102: R617.1 105,141.48 101.42,141.48 97.19,145.71 v2(97.19,146.15) 97.19,146.57 92.57,151.19 91.4,151.19 91.19,150.98 90.65,150.98 v1(90.22,150.55)
PCIE_RST#: length 217
  TOP w0.102: v3(161.32,206.88) 161.96,207.52 161.96,208.16 159.72,210.4 154.91,210.4 146.53,218.78 129.11,218.78 127.28,216.94 122.91,216.94 122.59,217.26 120.9,217.26 120.68,217.48 118.44,217.48 NGFF1.52 117.59,217.5 117.32,217.77 117.32,220.73 117.59,221 NGFF1.66
  BOTTOM w0.102: R754.2 145.3,59.6 145.3,70.3 145.88,70.89 145.88,71.43 145.46,71.84 145.46,80.84 146.62,82 146.62,86.94 145.19,88.37 145.19,105.69 144.66,106.22 144.66,117.96 147.55,120.85 155.01,120.85 159.72,125.57 159.72,149.19 161.96,151.43 161.96,196.43 160.97,197.41 160.97,200.74 161.32,201.09 v2(161.32,205.49) v3(161.32,206.88)
PCIE_RX_CPU_N4: length 188.5
  TOP w0.102: CPU1.F16 75.06,153.62 v1(75.38,153.29) ; C259.2 29.8,15.63 24.9,15.63 22.41,18.13 22.41,39.19 23.69,40.48 23.69,42.63 24.23,43.17 28.04,43.17 31.55,46.68 31.55,51.39 29.2,53.73 29.2,55.41 v3(29.12,55.5)
  BOTTOM w0.102: 54.83,135.1 54.83,136.09 56.43,137.69 56.43,147.35 59.79,150.71 65.19,150.71 68.06,153.58 71.38,153.58 71.57,153.77 74.9,153.77 v1(75.38,153.29) ; 54.83,135.1 54.83,134.49 46.92,126.58 32.45,126.58 31.19,125.32 31.19,69.25 29.09,67.15 29.09,58.31 30.19,57.21 30.19,56.79 29.4,56 29.4,55.78 v3(29.12,55.5) ; 54.83,135.1 v2(54.52,135.1)
PCIE_RX_CPU_N5: length 136.1
  TOP w0.102: v3(78.9,202.56) 78.61,202.27 78.61,202.1 78.79,201.91 79.12,201.91 80.61,200.42 81.76,200.42 82.27,199.91 ; v4(82.53,200.18) 82.27,199.91 ; 82.27,199.91 84.82,197.36 101.73,197.36 104.76,200.39 104.76,213.98 105.14,214.36 105.62,214.36 R53.2 ; v1(75.39,154.2) 75.39,154.34 CPU1.G18
  L3 w0.127: v3(52.87,152.91) 52.62,152.66 52.29,152.66 51.7,153.25 51.7,157.64 52.33,158.28 52.33,164.5 59.64,171.81 62.62,171.81 65.36,174.55 65.36,190.42 76.64,201.7 78.26,201.7 78.58,202.02 78.58,202.25 v3(78.9,202.56)
  BOTTOM w0.102: v1(75.39,154.2) 75.39,154.33 75.03,154.69 72.07,154.69 71.21,155.54 70.43,155.54 69.92,155.03 67.72,155.03 65.18,152.49 57.98,152.49 57.22,151.73 54.64,151.73 53.75,152.62 53.16,152.62 v3(52.87,152.91)
PCIE_RX_CPU_N8: length 184.4
  TOP w0.102: v1(74.73,157.86) 74.33,157.86 74.23,157.76 74.23,157.56 74.38,157.4 CPU1.E22
  L3 w0.127: v3(151.16,111.89) 151.16,111.75 150.92,111.51 149.39,111.51 148.71,112.18 128.85,112.18 125.78,115.25 94.16,115.25 79.38,130.04 72.31,130.04 64.04,138.3 64.04,146.94 65.57,148.46 65.57,149.73 62.14,153.16 61.5,153.16 60.87,153.8 60.87,159.77 61.37,160.27 65.15,160.27 65.49,160.6 70.62,160.6 72.89,158.34 74.56,158.34 74.73,158.16 v1(74.73,157.86)
  BOTTOM w0.102: 152.08,112.73 152.6,113.25 157.16,113.25 159.74,115.82 161.5,115.82 179.78,134.1 179.78,138.47 179.31,138.93 179.31,139.3 C399.2 ; 152.08,112.73 v2(151.87,112.93) ; 152.08,112.73 151.65,112.29 151.65,111.56 151.54,111.46 151.24,111.46 151.16,111.53 v3(151.16,111.89)
PCIE_RX_CPU_P4: length 188.4
  TOP w0.102: CPU1.E16 74.41,153.37 74.49,153.29 v1(74.73,153.29) ; C257.2 30.07,15.91 30.01,15.85 24.99,15.85 22.63,18.22 22.63,39.1 23.91,40.39 23.91,42.55 24.32,42.95 28.13,42.95 31.76,46.59 31.76,51.48 31.21,52.04 31.21,52.2 30.99,52.41 30.83,52.41 30.62,52.63 30.62,52.79 30.4,53 30.24,53 30.03,53.22 30.03,53.37 29.81,53.59 29.65,53.59 29.42,53.82 29.42,55.16 29.76,55.5 v3(29.88,55.5)
  BOTTOM w0.102: v2(56.29,136.83) 56.08,137.04 ; 56.08,137.04 56.65,137.6 56.65,147.26 59.88,150.5 65.28,150.5 68.15,153.36 71.47,153.36 71.66,153.56 72.11,153.56 72.22,153.44 72.52,153.44 72.64,153.56 72.94,153.56 73.05,153.44 73.36,153.44 73.47,153.56 73.77,153.56 73.89,153.44 74.19,153.44 74.3,153.56 74.61,153.56 74.73,153.43 v1(74.73,153.29) ; 56.08,137.04 55.04,136 55.04,134.4 47.01,126.36 32.54,126.36 31.4,125.23 31.4,69.16 29.31,67.06 29.31,58.4 30.41,57.3 30.41,56.7 29.61,55.91 29.61,55.77 v3(29.88,55.5)
PCIE_RX_CPU_P5: length 136.1
  TOP w0.102: v4(83.47,197.88) 83.73,198.14 ; 83.73,198.14 81.67,200.2 80.52,200.2 79.03,201.7 78.7,201.7 78.39,202.01 78.39,202.31 v3(78.14,202.56) ; 83.73,198.14 84.73,197.14 101.82,197.14 104.97,200.3 104.97,213.89 105.23,214.15 105.61,214.15 R54.2 ; CPU1.F18 75.06,154.53 v1(74.73,154.2)
  L3 w0.127: v3(52.87,152.15) 52.62,152.39 52.18,152.39 51.43,153.14 51.43,157.75 52.06,158.39 52.06,164.61 59.52,172.07 62.51,172.07 65.1,174.66 65.1,190.53 76.53,201.97 78.15,201.97 78.32,202.13 78.32,202.39 v3(78.14,202.56)
  BOTTOM w0.102: v1(74.73,154.2) 74.73,154.31 74.57,154.47 71.98,154.47 71.13,155.32 70.52,155.32 70.01,154.81 67.81,154.81 65.27,152.27 58.07,152.27 57.31,151.51 54.55,151.51 53.66,152.4 53.12,152.4 v3(52.87,152.15)
PCIE_RX_CPU_P8: length 184.5
  TOP w0.102: CPU1.E23 74.41,158.45 v1(74.73,158.78)
  L3 w0.127: v1(74.73,158.78) 74.56,158.6 73,158.6 70.73,160.87 65.37,160.87 65.04,160.54 61.26,160.54 60.6,159.88 60.6,153.69 61.39,152.9 62.03,152.9 65.3,149.62 65.3,148.57 63.77,147.05 63.77,138.19 72.2,129.77 79.27,129.77 94.05,114.99 125.67,114.99 128.74,111.91 148.6,111.91 149.27,111.24 150.92,111.24 v3(151.16,111)
  BOTTOM w0.102: C398.2 179.53,139.3 179.53,139.02 179.99,138.56 179.99,134.01 161.59,115.61 159.83,115.61 158,113.79 ; 158,113.79 157.25,113.03 152.69,113.03 151.86,112.2 151.86,111.47 151.63,111.24 151.4,111.24 v3(151.16,111) ; 158,113.79 v2(158.25,113.54)
PCIE_TX_CON_N4: length 180.7
  TOP w0.102: v3(62.39,149.1) 62.77,149.48 62.77,149.67 C33.1 ; U23.14 37.28,17.28 37.37,17.37 37.37,17.63 36.85,18.15 35.96,18.15 35.71,17.89 31.95,17.89 31.75,17.69 25.6,17.69 23.69,19.6 23.69,34.76 27,38.06 27,41.49 27.41,41.91 28.61,41.91 32.96,46.27 32.96,54.32 33.73,55.08 34.47,55.08 34.58,55.19 v3(34.58,55.5)
  BOTTOM w0.102: v2(32.34,70.23) 32.04,70.23 ; 32.04,70.23 32.04,68.91 29.93,66.8 29.93,58.65 33.52,55.07 34.48,55.07 34.58,55.17 v3(34.58,55.5) ; 32.04,70.23 32.04,124.97 32.81,125.74 47.29,125.74 57.27,135.72 57.27,147.01 60.01,149.75 62.58,149.75 62.73,149.59 62.73,149.36 62.47,149.1 v3(62.39,149.1)
PCIE_TX_CON_N5: length 119.1
  TOP w0.102: R55.2 105.82,207.51 105.82,200.43 102.03,196.63 82.93,196.63 80.43,199.14 ; v3(78.14,201.04) 78.47,200.71 78.86,200.71 80.43,199.14 ; 80.43,199.14 v4(80.68,199.39)
  L3 w0.127: v3(78.14,201.04) 77.9,200.8 76.45,200.8 65.81,190.15 65.81,174.38 62.8,171.37 59.81,171.37 52.76,164.32 52.76,158.1 52.13,157.46 52.13,154.91 52.42,154.61 52.69,154.61 v3(52.87,154.43)
  BOTTOM w0.102: v3(52.87,154.43) 52.99,154.56 53.56,154.56 54.33,155.32 54.33,155.97 54.99,156.63 57.09,156.63 60.69,153.03 65.11,153.03 67.89,155.82 68.44,155.82 C374.1
PCIE_TX_CON_N8: length 176.6
  TOP w0.102: C28.1 v3(66.58,158.5)
  L3 w0.127: v3(66.58,158.5) 66.58,158.41 66.91,158.08 67.23,158.08 67.99,157.32 67.99,152.03 66.58,150.62 66.58,148.44 64.8,146.66 64.8,139.29 70.84,133.26 70.84,132.5 72.52,130.81 79.59,130.81 94.44,115.96 126.06,115.96 129.14,112.88 151.44,112.88 152.95,111.37 153.82,111.37 153.96,111.51 v3(153.96,111.76)
  BOTTOM w0.102: 154.92,111.3 154.11,111.3 153.96,111.46 v3(153.96,111.76) ; 154.92,111.3 158.74,111.3 181.02,133.59 181.02,144.77 179.86,145.93 177.46,145.93 177.28,145.74 U28.4 ; 154.92,111.3 v2(154.92,111.61)
PCIE_TX_CON_P4: length 180.7
  TOP w0.102: U23.13 37.68,17.28 37.59,17.37 37.59,17.72 36.94,18.36 35.87,18.36 35.62,18.11 31.86,18.11 31.66,17.91 25.69,17.91 23.91,19.68 23.91,34.67 27.21,37.97 27.21,41.4 27.5,41.69 28.7,41.69 33.18,46.18 33.18,54.23 33.82,54.86 34.32,54.86 v3(34.58,54.61) ; C34.1 62.99,149.76 62.99,149.26 v3(63.15,149.1)
  BOTTOM w0.102: 33.74,54.85 34.34,54.85 v3(34.58,54.61) ; 33.74,54.85 v2(33.74,54.53) ; 33.74,54.85 33.43,54.85 29.71,58.57 29.71,66.89 31.82,69 31.82,125.06 32.72,125.96 47.2,125.96 57.06,135.81 57.06,147.1 59.92,149.96 62.67,149.96 62.95,149.68 62.95,149.3 v3(63.15,149.1)
PCIE_TX_CON_P5: length 119.6
  TOP w0.102: v4(86.11,196.06) 86.11,196.42 ; 86.11,196.42 102.12,196.42 106.03,200.34 106.03,207.55 106.24,207.76 R56.2 ; 86.11,196.42 82.84,196.42 78.82,200.44 78.77,200.49 78.23,200.49 78.14,200.41 v3(78.14,200.2)
  L3 w0.127: v3(78.14,200.2) 78.14,200.41 78.01,200.53 76.56,200.53 66.07,190.04 66.07,174.27 62.91,171.11 59.92,171.11 53.03,164.21 53.03,157.99 52.4,157.35 52.4,155.02 52.53,154.88 52.68,154.88 52.87,155.06 v3(52.87,155.19)
  BOTTOM w0.102: C370.1 68.24,156.03 67.8,156.03 65.02,153.25 60.78,153.25 57.18,156.84 54.9,156.84 54.11,156.06 54.11,155.41 53.47,154.77 53.18,154.77 52.87,155.09 v3(52.87,155.19)
PCIE_TX_CON_P8: length 176.6
  TOP w0.102: C29.1 v3(66.58,157.61)
  L3 w0.127: v3(66.58,157.61) 66.79,157.82 67.12,157.82 67.72,157.21 67.72,152.14 66.31,150.73 66.31,148.55 64.54,146.77 64.54,139.18 69.92,133.8 70.57,133.15 70.57,132.39 72.41,130.54 79.48,130.54 94.33,115.7 125.95,115.7 129.03,112.61 151.33,112.61 152.84,111.1 153.73,111.1 v3(153.96,110.87)
  BOTTOM w0.102: 180.32,145.77 181.24,144.86 181.24,133.5 158.83,111.09 154.17,111.09 v3(153.96,110.87) ; 180.32,145.77 179.95,146.14 U28.3 ; 180.32,145.77 v2(180.53,145.98)
PCIE_TX_CPU_N4: length 13
  TOP w0.089: 69.76,154.9 69.78,154.9 69.79,154.89 69.96,154.89 70.51,155.44 71.38,155.44 71.44,155.38 71.8,155.38 71.92,155.44 72.08,155.44 72.25,155.38 72.45,155.38 72.62,155.47 72.82,155.47 CPU1.C19
  TOP w0.102: C33.2 62.89,151.44 63.08,151.44 63.32,151.68 63.66,151.68 ; 63.66,151.68 v4(63.66,152.1) ; 63.66,151.68 64.27,151.68 67.49,154.9 69.76,154.9
PCIE_TX_CPU_N5: length 5.8
  TOP w0.102: v1(73.87,156.15) 73.82,156.21 CPU1.D20
  BOTTOM w0.102: v1(73.87,156.15) 73.33,156.15 73.21,156.03 73.21,155.78 73.01,155.57 72.42,155.57 ; C374.2 69.9,155.91 71.4,155.91 71.74,155.57 72.42,155.57 ; 72.42,155.57 v2(72.42,155.28)
PCIE_TX_CPU_N8: length 5
  TOP w0.102: 69.35,158.75 71.92,158.75 72.12,158.55 72.12,158.34 CPU1.B23 ; 69.35,158.75 v4(69.35,159.13) ; 69.35,158.75 68.84,158.24 68.68,158.24 C28.2
PCIE_TX_CPU_P4: length 13
  TOP w0.089: 69.76,154.69 69.78,154.69 69.79,154.7 70.04,154.7 70.58,155.24 71.32,155.24 71.36,155.2 71.84,155.2 71.96,155.27 72.05,155.27 72.21,155.2 72.5,155.2 72.66,155.3 73.29,155.3 CPU1.D19
  TOP w0.102: 65.1,152.2 64.35,151.46 63.41,151.46 63.28,151.33 C34.2 ; 65.1,152.2 v4(65.36,151.94) ; 65.1,152.2 67.58,154.69 69.76,154.69
PCIE_TX_CPU_P5: length 5.8
  TOP w0.102: CPU1.C20 72.11,156.21 v1(72.1,156.21)
  BOTTOM w0.102: v2(70.67,156.44) 70.67,156.13 ; 70.67,156.13 69.9,156.13 C370.2 ; 70.67,156.13 71.49,156.13 71.83,155.79 72.92,155.79 72.99,155.87 72.99,156.11 72.89,156.21 v1(72.1,156.21)
PCIE_TX_CPU_P8: length 5
  TOP w0.102: CPU1.A23 71.9,158.34 71.9,158.46 71.83,158.53 71.52,158.53 71.41,158.42 71.1,158.42 70.99,158.53 69.44,158.53 69.21,158.3 69.21,158 69.15,157.94 ; C29.2 68.82,157.61 69.15,157.94 ; 69.15,157.94 v4(69.45,157.63)
PD4405_A: length 3.9
  TOP w0.152: v4(34.32,46.99) PD1.A 34.35,48.8 34.35,50.36 PQ1.B
PD4405_K: length 3.2
  TOP w0.152: PR91.2 v4(38.51,48.77) PD1.K
PD_N: length 14.1
  TOP w0.102: Q43.D 140.37,30.23 v3(139.58,29.44) 138.87,28.73 133.23,28.73 132.75,29.21 132.75,32.26 132.95,32.46 U17.36
  BOTTOM w0.102: v3(139.58,29.44) v2(138.74,29.44)
PECI_EC: length 8.5
  TOP w0.102: CPU1.A54 71.36,175.47 70.04,174.14 69.02,174.14 v4(67.7,172.82) 67.65,172.77 66,172.77 65.18,171.96 R115.1
PEG_C_RXN0: length 7.5
  TOP w0.102: v1(86.76,107.07) 87.12,106.72 GPU1.AB9
  BOTTOM w0.102: 87.24,110.39 87.24,109.45 87.55,109.14 87.55,107.54 87.29,107.28 86.97,107.28 v1(86.76,107.07) ; 87.24,110.39 87.24,112.67 C435.2 ; 87.24,110.39 v2(87.54,110.39)
PEG_C_RXN1: length 7.3
  TOP w0.102: GPU1.AC10 v1(85.89,107.92)
  BOTTOM w0.102: 85.75,109.3 85.75,108.07 v1(85.89,107.92) ; 85.75,109.3 v2(86.04,109.3) ; 85.75,109.3 85.75,111.27 85.08,111.93 85.08,112.19 85.21,112.32 85.96,112.32 86.09,112.45 86.09,112.64 C437.2
PEG_C_RXN2: length 12.6
  TOP w0.102: v1(85.07,107.94) 85.28,107.94 85.48,107.75 GPU1.AC11
  BOTTOM w0.102: C434.2 87.79,112.33 87.79,112.17 87.92,112.04 88.96,112.04 89.1,111.9 89.1,111.35 ; v2(88.81,111.35) 89.1,111.35 ; 89.1,111.35 89.1,110.45 87.75,109.11 87.75,107.46 86.96,106.67 85.75,106.67 84.88,107.55 84.88,107.75 v1(85.07,107.94)
PEG_C_RXN3: length 7.3
  TOP w0.102: GPU1.AB12 84.64,106.66 v1(84.23,107.06)
  BOTTOM w0.102: v2(83.22,110.95) 83.51,110.95 ; 83.51,110.95 83.51,111.56 83.31,111.76 83.31,112.75 C440.2 ; 83.51,110.95 83.51,107.61 83.74,107.38 83.92,107.38 v1(84.23,107.06)
PEG_C_RXP0: length 7.5
  TOP w0.102: GPU1.AC9 86.97,107.5 86.74,107.73 v1(86.74,107.91)
  BOTTOM w0.102: v1(86.74,107.91) 86.74,107.68 86.93,107.49 87.2,107.49 87.33,107.63 87.33,109.05 87.03,109.36 87.03,111.63 ; v2(86.72,111.63) 87.03,111.63 ; 87.03,111.63 87.03,112.59 C436.2
PEG_C_RXP1: length 7.2
  TOP w0.102: v1(85.89,107.11) 85.89,107.1 GPU1.AB10
  BOTTOM w0.102: v2(85.22,110.62) 85.53,110.62 ; 85.53,110.62 85.53,111.18 84.87,111.84 C438.2 ; 85.53,110.62 85.53,108.13 85.49,108.09 85.49,107.51 v1(85.89,107.11)
PEG_C_RXP2: length 12.6
  TOP w0.102: GPU1.AD11 85.08,108.7 v1(85.07,108.7)
  BOTTOM w0.102: C433.2 89.31,110.36 88.7,109.75 ; 88.7,109.75 87.97,109.02 87.97,107.37 87.05,106.45 85.67,106.45 84.66,107.46 84.66,108.2 84.66,108.28 v1(85.07,108.7) ; 88.7,109.75 v2(88.93,109.52)
PEG_C_RXP3: length 7.4
  TOP w0.102: GPU1.AC12 84.38,107.5 84.23,107.65 84.23,107.89 v1(84.23,107.9)
  BOTTOM w0.102: 83.73,109.63 83.73,111.65 83.52,111.85 83.52,112.51 C439.2 ; 83.73,109.63 83.73,107.7 83.83,107.59 84.11,107.59 84.23,107.72 v1(84.23,107.9) ; 83.73,109.63 v2(84.03,109.63)
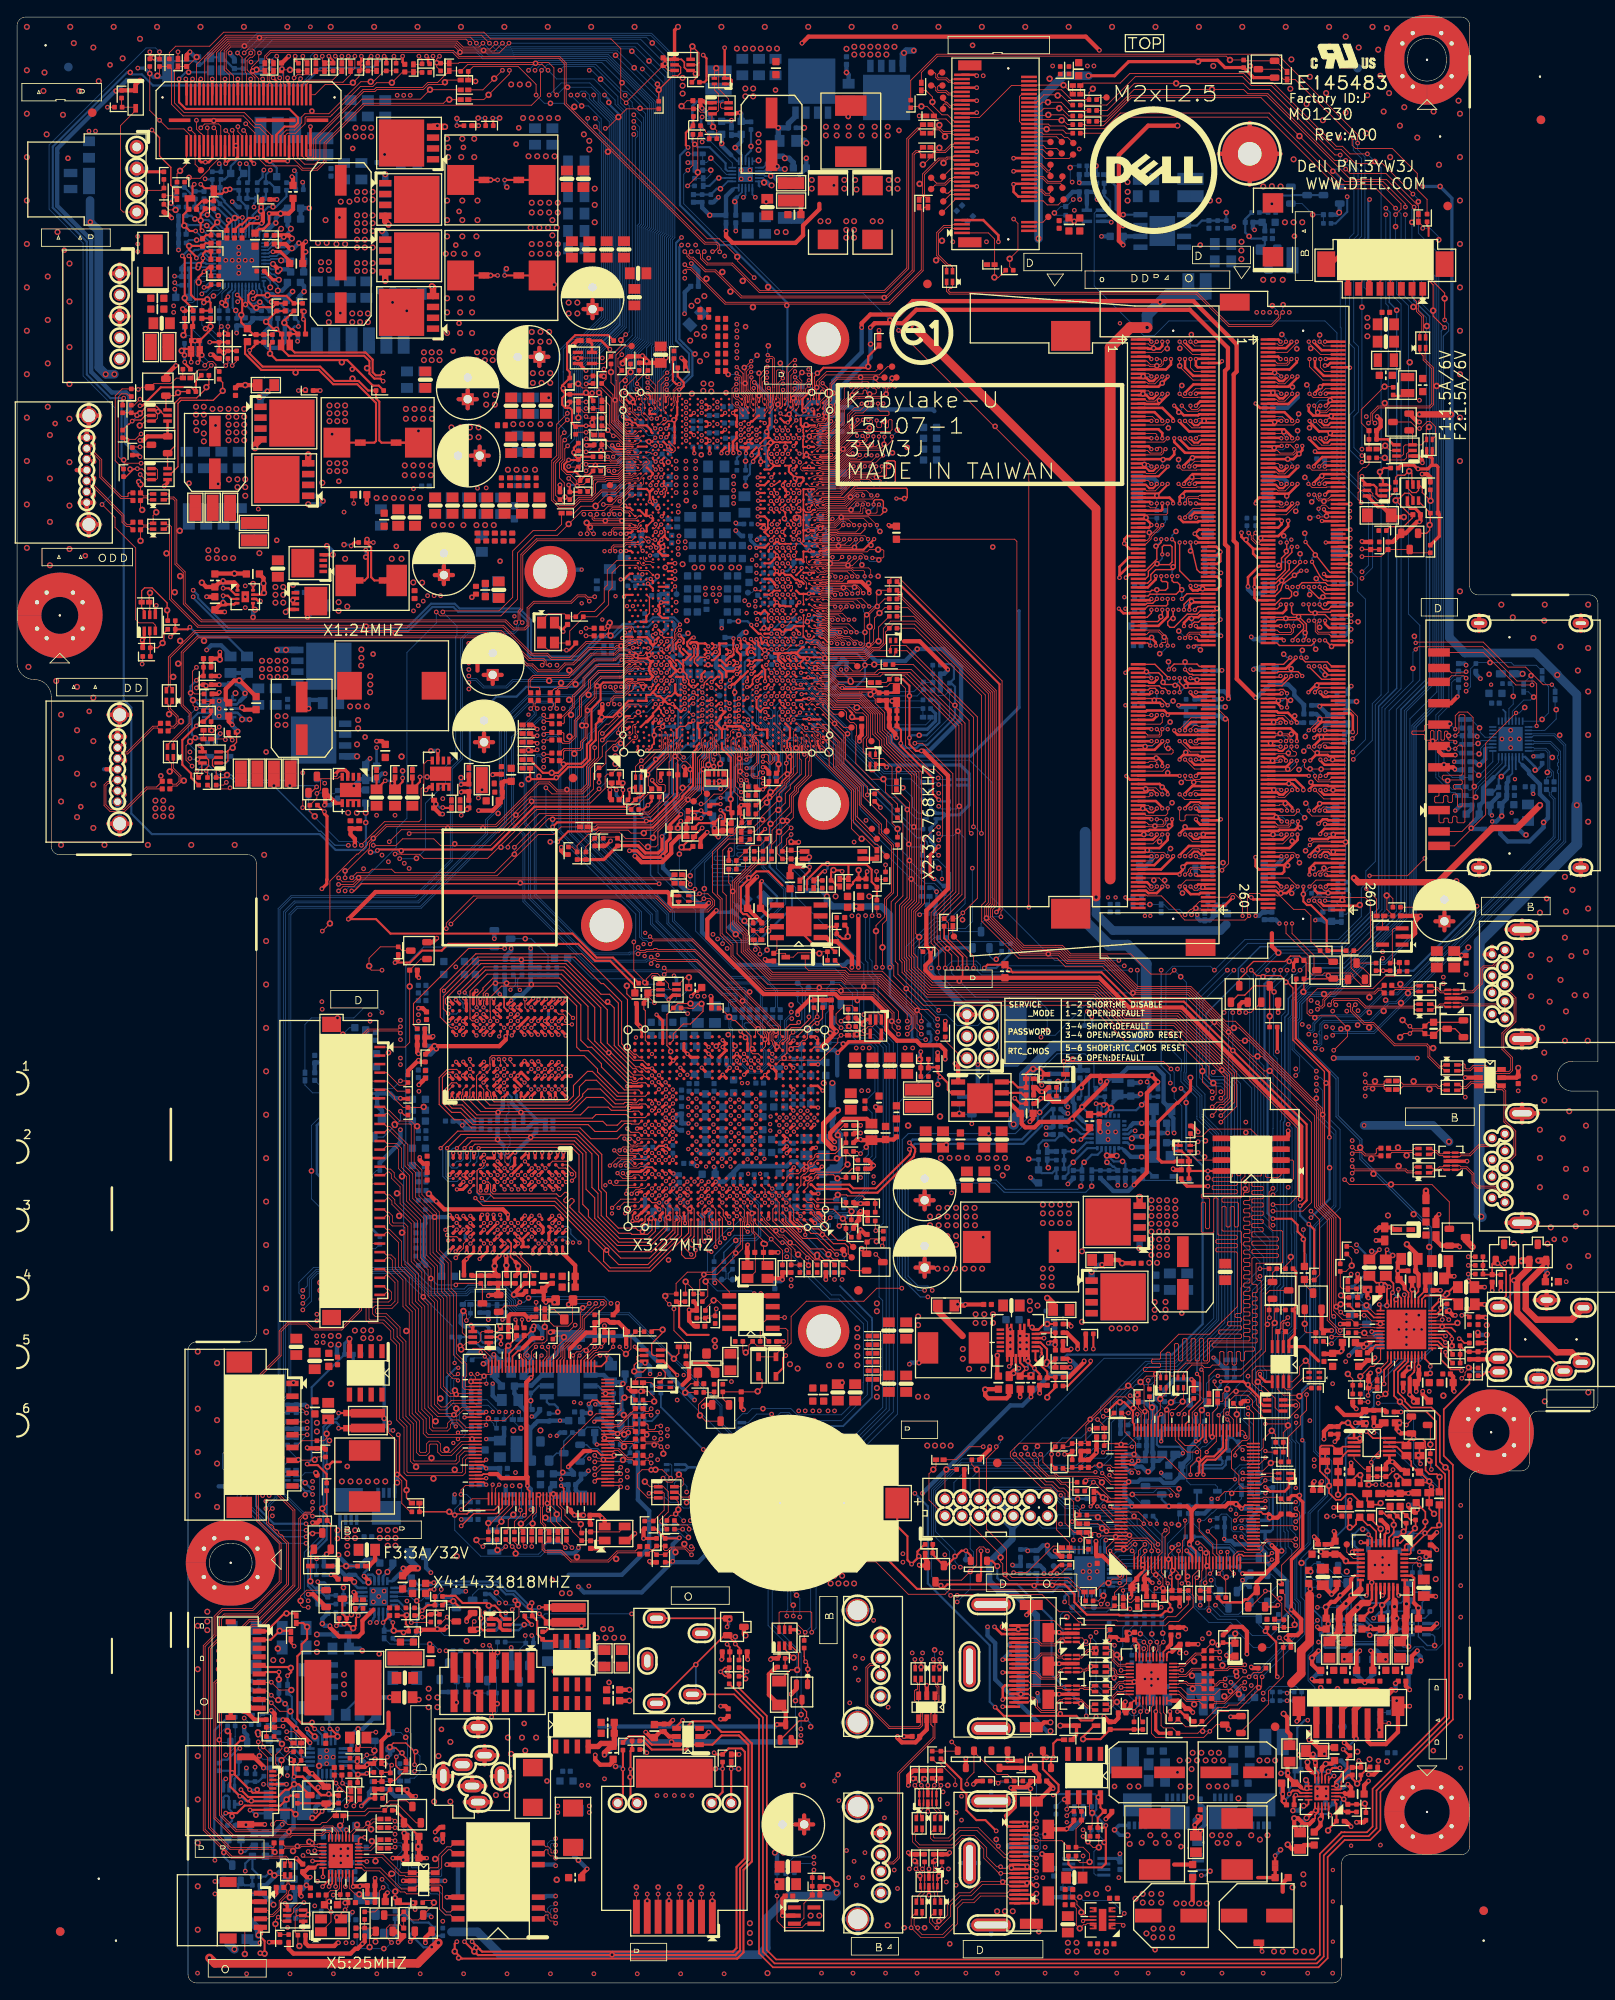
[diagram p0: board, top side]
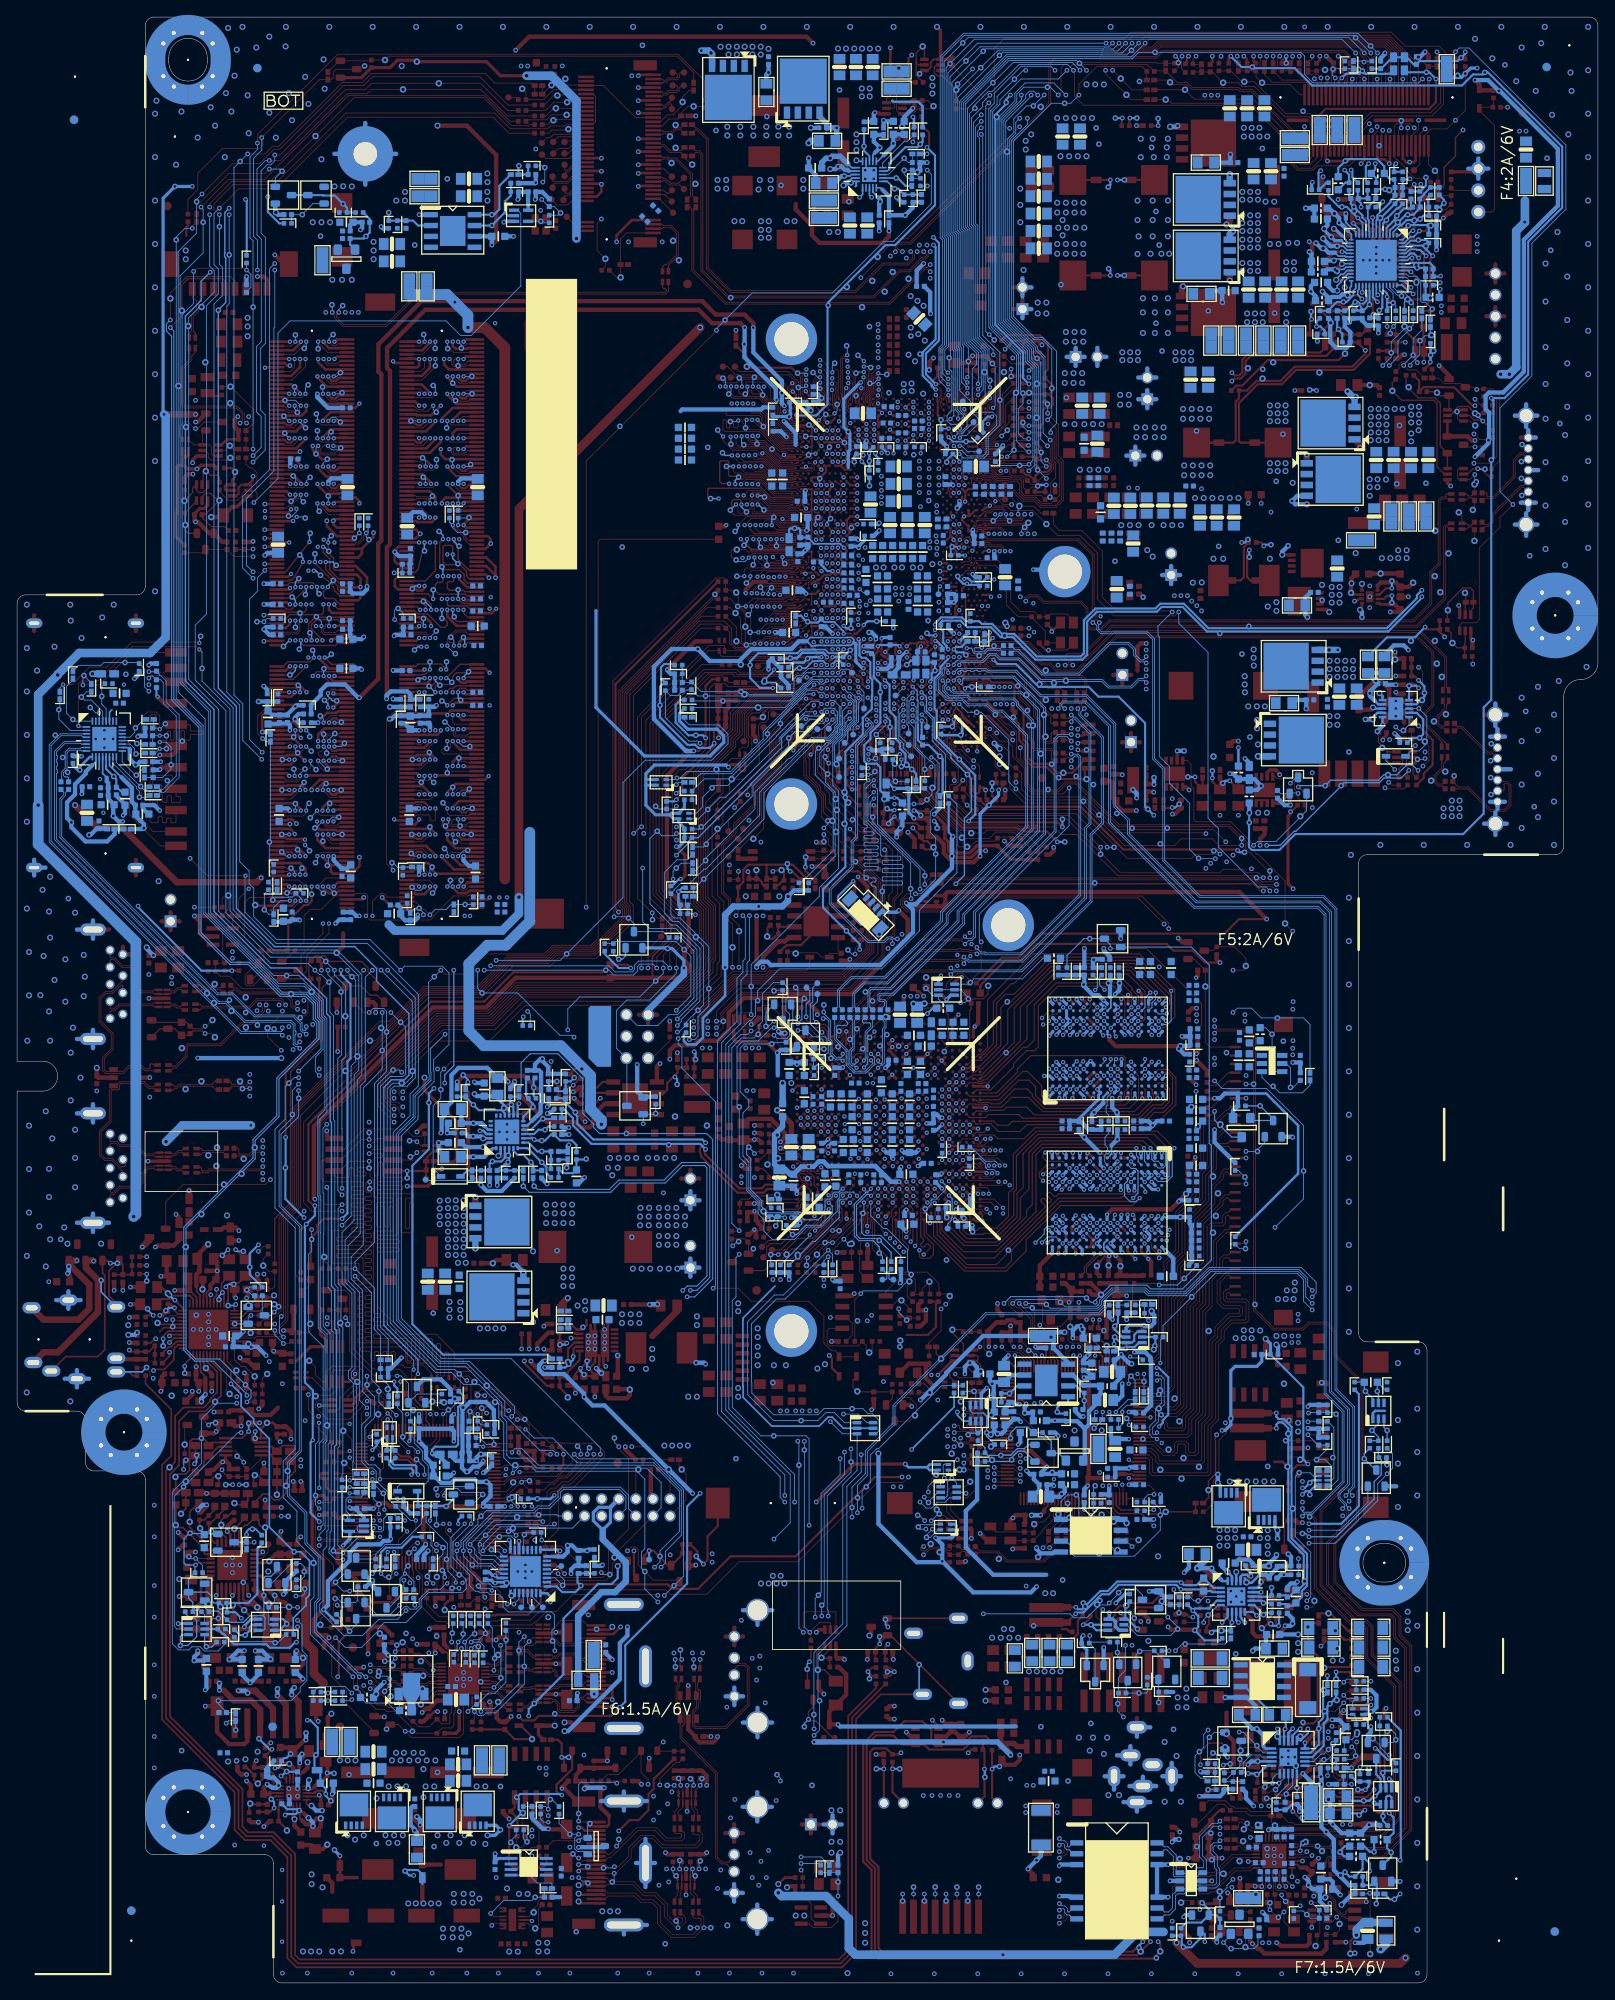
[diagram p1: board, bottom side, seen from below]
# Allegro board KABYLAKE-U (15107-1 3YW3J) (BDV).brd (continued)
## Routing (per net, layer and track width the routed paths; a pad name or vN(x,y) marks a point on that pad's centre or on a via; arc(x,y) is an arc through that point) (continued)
PEG_C_TXN0: length 16.1
  TOP w0.089: 70.32,153.33 70.34,153.33 70.35,153.34 70.9,153.34 71.52,153.96 71.83,153.96 72.16,154.29 CPU1.B17
  TOP w0.102: v4(66.89,150.7) 66.6,150.98 ; 66.6,150.98 66.03,150.41 66.03,148.22 65.43,147.61 65.43,145.8 64.66,145.03 63.85,145.03 C47.2 ; 66.6,150.98 67.1,151.48 67.1,152.34 68.09,153.33 70.32,153.33
PEG_C_TXN1: length 18.1
  TOP w0.089: 70.52,152.88 70.54,152.88 70.56,152.87 70.69,152.87 71.46,153.63 71.87,153.63 72.26,154.02 72.48,154.02 72.52,154.06 72.74,154.06 73.07,153.73 CPU1.D16
  TOP w0.102: 66.48,147.12 66.48,149.36 67.55,150.43 67.55,152.15 68.27,152.88 70.52,152.88 ; 66.48,147.12 66.48,145.74 65.95,145.21 65.95,144.55 65.82,144.43 64.01,144.43 C49.2 ; 66.48,147.12 v4(66.12,147.12)
PEG_C_TXN2: length 14.7
  TOP w0.089: 70.4,154.23 70.42,154.23 70.43,154.21 70.72,154.21 71.13,154.62 71.17,154.67 71.39,154.67 71.59,154.75 71.79,154.75 71.95,154.67 72.05,154.67 72.21,154.74 72.47,154.74 72.65,154.65 73.28,154.65 CPU1.D17
  TOP w0.102: 64.98,150.11 64.98,150.6 66.23,151.84 66.23,152.7 67.75,154.23 70.4,154.23 ; 64.98,150.11 v4(64.6,150.11) ; 64.98,150.11 64.98,149.33 63.86,148.21 C38.2
PEG_C_TXN3: length 16.1
  TOP w0.089: 69.77,155.57 69.79,155.57 69.8,155.56 69.92,155.56 70.4,156.04 71.71,156.04 72.1,155.64 CPU1.B19
  TOP w0.102: 64.88,153.32 67.13,155.57 69.77,155.57 ; 64.88,153.32 64.52,152.96 60.37,152.96 59.82,152.41 59.82,151.22 C31.2 ; 64.88,153.32 v4(64.63,153.57)
PEG_C_TXP0: length 16.1
  TOP w0.089: 70.32,153.54 70.34,153.54 70.35,153.53 70.82,153.53 71.48,154.19
  TOP w0.102: 71.48,154.19 71.58,154.29 CPU1.A17 ; C46.2 63.86,146.3 63.99,146.18 63.99,145.38 64.12,145.25 64.57,145.25 64.9,145.57 ; 64.9,145.57 65.21,145.88 65.21,147.7 65.82,148.31 65.82,150.5 66.89,151.57 66.89,152.43 68,153.54 70.32,153.54 ; 64.9,145.57 v4(64.65,145.82)
PEG_C_TXP1: length 18.1
  TOP w0.089: CPU1.C16 72.56,153.83 72.34,153.83 71.95,153.44 71.53,153.44 70.77,152.68 70.56,152.68 70.54,152.67 70.52,152.67
  TOP w0.102: 70.52,152.67 68.36,152.67 67.76,152.06 67.76,150.34 66.7,149.27 66.7,145.65 66.16,145.12 66.16,144.46 65.91,144.21 65.21,144.21 ; 65.21,144.21 64.12,144.21 63.96,144.06 63.96,143.23 63.74,143 C50.2 ; 65.21,144.21 v4(65.21,143.81)
PEG_C_TXP2: length 14.6
  TOP w0.089: 70.4,154.01 70.49,154.01 70.5,154.02 70.8,154.02 71.27,154.49 71.42,154.49 71.62,154.57 71.75,154.57 71.91,154.49 72.09,154.49 72.25,154.56 72.43,154.56 72.61,154.47 72.8,154.47 CPU1.C17
  TOP w0.102: 64.57,148.61 65.2,149.24 65.2,150.51 66.44,151.75 66.44,152.61 67.84,154.01 70.4,154.01 ; 64.57,148.61 v4(64.83,148.36) ; 64.57,148.61 64.03,148.07 64.03,147.43 63.91,147.32 C44.2
PEG_C_TXP3: length 16.1
  TOP w0.089: 69.77,155.36 69.79,155.36 69.8,155.37 70,155.37 70.47,155.85 71.63,155.85 71.69,155.79 CPU1.A19
  TOP w0.102: C32.2 61.17,151.12 61.17,151.46 61.04,151.59 60.16,151.59 60.04,151.7 60.04,152.32 60.46,152.74 62.26,152.74 ; 69.77,155.36 67.22,155.36 64.61,152.74 62.26,152.74 ; 62.26,152.74 v4(62.26,152.35)
PEG_CLK_CPU: length 114.3
  TOP w0.102: v4(65.21,219.51) 64.94,219.24 ; 64.94,219.24 80.53,203.66 81.9,203.66 82.22,203.33 v3(82.22,202.54) ; 64.94,219.24 64.26,219.93 64.26,224.63 63.48,225.4 51.75,225.4 51.05,226.1 29.64,226.1 28.99,225.45 R7.2 ; CPU1.E43 74.41,169.44 v1(74.74,169.77)
  L3 w0.127: v3(82.22,202.54) 82.22,201.44 71.53,190.75 71.53,189.99 68.45,186.91 68.45,176.72 69.27,175.9 70.52,175.9 73.67,172.75 75.65,172.75 76.61,171.78 76.61,169.93 75.95,169.27 75.24,169.27 v1(74.74,169.77)
PEG_CLK_CPU#: length 114.2
  TOP w0.102: 69.39,214.49 64.04,219.84 64.04,224.54 63.39,225.18 51.66,225.18 50.96,225.88 29.73,225.88 29.2,225.36 29.2,225.18 29.32,225.07 29.88,225.07 30.01,224.94 R8.2 ; 69.39,214.49 80.44,203.44 81.81,203.44 82.01,203.24 82.01,202.98 81.59,202.56 v3(81.39,202.56) ; 69.39,214.49 v4(69.15,214.25) ; v1(75.38,169.73) 75.06,169.41 CPU1.F43
  L3 w0.127: v1(75.38,169.73) 75.57,169.53 75.84,169.53 76.35,170.04 76.35,171.67 75.54,172.48 73.56,172.48 70.41,175.63 69.16,175.63 68.18,176.61 68.18,187.02 71.27,190.1 71.27,190.86 72.54,192.14 72.54,192.33 72.81,192.6 73,192.6 73.27,192.87 73.27,193.06 73.54,193.33 73.74,193.33 74,193.6 74,193.8 74.27,194.07 74.47,194.07 75.46,195.06 75.46,195.25 75.73,195.52 75.92,195.52 76.19,195.79 76.19,195.98 76.46,196.25 76.66,196.25 76.93,196.52 76.93,196.72 77.2,196.99 77.39,196.99 81.96,201.55 81.96,202 v3(81.39,202.56)
PEG_CLK_XDP: length 4.1
  TOP w0.102: XDP1.40 29.33,222.09 29.47,222.22 29.47,222.35 29.28,222.54 29.28,223.42 R7.1 28.16,223.71 v4(28.02,223.85)
PEG_CLK_XDP#: length 3.1
  TOP w0.102: R8.1 29.5,223.2 29.5,222.63 29.62,222.5 29.69,222.44 29.69,222.25 29.83,222.1 XDP1.42
PEG_CLKREQ0_CPU#: length 74.8
  TOP w0.102: v1(90.22,149.63) 89.9,149.96 CPU1.AR10
  L3 w0.127: v3(106.33,110.36) 95.92,110.36 94.84,111.44 v3(93.63,111.44)
  BOTTOM w0.102: v1(90.22,149.63) 89.81,150.04 89.41,150.04 88.78,149.42 88.78,147.29 89.17,146.9 89.17,146.44 90.06,145.54 91.85,145.54 98.09,139.3 98.09,136.63 104.42,130.3 104.62,130.3 106.27,128.65 107.34,128.65 108.11,127.88 108.11,127.83 R877.2 108.49,124.97 108.11,124.59 107.41,124.59 104.05,121.23 v2(104.05,116.33) 104.05,114.3 105.32,113.03 105.32,110.74 105.7,110.36 v3(106.33,110.36) ; v3(93.63,111.44) Q54.D 92.61,111.44 91.87,110.69 90.43,110.69 90.23,110.49 90.23,110.03 90.08,109.88 90.08,108.89 90.22,108.75 90.23,108.75 R672.1
PEG_CLKREQ4_CPU#: length 22.3
  TOP w0.102: CPU1.AU8 91.2,149.3 v1(90.87,149.63)
  BOTTOM w0.102: v1(90.87,149.63) 91.14,149.9 92.11,149.9 96.11,145.9 96.11,145.82 101.83,140.11 103.39,140.11 v2(103.67,139.83) 104.78,138.71 104.78,137.57 105.5,136.85 RN11.2
PEG_CLKREQ5_CPU#: length 20.9
  TOP w0.102: v1(91.62,148.63) 91.25,148.26 CPU1.AU7
  BOTTOM w0.102: RN11.1 105.26,136.2 v2(104.17,137.29) 102.73,138.73 102.06,138.73 95.73,145.05 95.73,145.74 92.76,148.72 91.7,148.72 v1(91.62,148.63)
PEG_RCOMPN_CPU: length 2.8
  TOP w0.305: CPU1.F5 75.06,147.41 75.38,147.73 v1(75.38,147.8)
  BOTTOM w0.305: R607.1 75.56,147 v2(75.55,146.99) 75.38,147.15 v1(75.38,147.8)
PEG_RCOMPP_CPU: length 5
  TOP w0.305: CPU1.E5 74.41,147.48 v1(74.73,147.8)
  BOTTOM w0.305: v1(74.73,147.8) 74.38,147.45 74.38,146.18 v2(74.57,145.99) 76.74,145.99 R607.2
PEG_RXN0: length 58.5
  TOP w0.102: CPU1.H13 76.36,152.05 v1(76.68,152.38)
  BOTTOM w0.102: 66.3,147.12 66.3,135.03 76.26,125.07 76.26,124.04 83.2,117.1 85.88,117.1 87.2,115.78 87.2,114.19 C435.1 ; 66.3,147.12 v2(66.61,147.12) ; 66.3,147.12 66.3,147.68 68.05,149.43 68.05,149.79 68.38,150.11 73.51,150.11 73.82,150.42 75.96,150.42 76.66,151.12 76.66,151.75 76.47,151.93 76.47,152.16 v1(76.68,152.38)
PEG_RXN1: length 57.2
  TOP w0.102: v1(76.03,151.46) 75.71,151.14 CPU1.G11
  BOTTOM w0.089: 72.68,150.85 72.7,150.85 72.71,150.86 75.43,150.86 75.66,151.1 75.67,151.1 v1(76.03,151.46)
  BOTTOM w0.102: 72.68,150.85 67.5,150.85 65.57,148.91 65.57,134.83 74.99,125.41 74.99,124.25 82.8,116.44 85.15,116.44 85.42,116.17 85.42,115.95 ; v2(85.73,115.95) 85.42,115.95 ; 85.42,115.95 85.42,114.19 C437.1
PEG_RXN2: length 60.7
  TOP w0.102: v1(76.03,153.29) 76.36,153.62 CPU1.H16
  BOTTOM w0.089: 74.04,149.99 74.06,150.01 74.08,150.01 74.31,150.24 76.12,150.24 77.18,151.3 77.18,152.45 76.49,153.15 76.49,153.67 76.43,153.73 76.14,153.73 76.03,153.62 v1(76.03,153.29)
  BOTTOM w0.102: 74.04,149.99 73.97,149.92 73.7,149.64 71.45,149.64 70.71,148.91 69.67,148.91 68.63,147.87 ; v2(68.41,148.08) 68.63,147.87 ; 68.63,147.87 66.75,145.99 66.75,135.22 76.71,125.26 76.71,124.22 83.38,117.55 87.29,117.55 88.76,116.07 88.76,114.19 C434.1
PEG_RXN3: length 58.3
  TOP w0.102: CPU1.G15 75.71,152.7 v1(75.39,152.37)
  BOTTOM w0.102: 64.65,139.62 64.65,134.41 74.11,124.95 74.11,123.89 82.43,115.57 83.97,115.57 84.04,115.49 84.04,115.11 83.97,115.04 83.48,115.04 83.27,114.82 83.27,114.03 C440.1 ; 64.65,139.62 v2(64.35,139.62) ; 64.65,139.62 64.65,149.23 68.3,152.89 74.88,152.89 v1(75.39,152.37)
PEG_RXP0: length 58.5
  TOP w0.102: CPU1.G13 75.71,152.05 v1(76.03,152.37)
  BOTTOM w0.102: C436.1 86.98,114.19 86.98,115.69 86.54,116.13 85.79,116.89 83.11,116.89 76.05,123.95 76.05,124.98 66.09,134.94 66.09,147.77 66.97,148.65 ; 66.97,148.65 v2(66.76,148.87) ; 66.97,148.65 67.84,149.52 67.84,149.87 68.29,150.33 73.42,150.33 73.73,150.64 75.87,150.64 76.44,151.21 76.44,151.66 76.25,151.84 76.25,152.15 v1(76.03,152.37)
PEG_RXP1: length 57.2
  TOP w0.102: v1(75.38,151.46) 75.25,151.46 75.06,151.28 CPU1.F11
  BOTTOM w0.089: 72.68,151.06 72.7,151.06 72.71,151.05 75.35,151.05 75.47,151.18 75.47,151.37 v1(75.38,151.46)
  BOTTOM w0.102: v2(84.89,114.88) 85.21,114.88 ; 85.21,114.88 85.21,114.19 C438.1 ; 85.21,114.88 85.21,116.08 85.06,116.23 82.71,116.23 74.77,124.16 74.77,125.32 65.35,134.74 65.35,149 67.41,151.06 72.68,151.06
PEG_RXP2: length 60.8
  TOP w0.102: v1(76.04,154.2) 75.71,153.88 CPU1.G16
  BOTTOM w0.089: v1(76.04,154.2) 76.32,153.92 76.51,153.92 76.68,153.75 76.68,153.23 77.37,152.53 77.37,151.22 76.2,150.05 74.39,150.05 74.21,149.87 74.21,149.85 74.2,149.84
  BOTTOM w0.102: 70.52,148.69 70.8,148.69 71.53,149.43 73.79,149.43 74.12,149.76 74.2,149.84 ; 70.52,148.69 69.76,148.69 66.96,145.9 66.96,135.31 76.92,125.35 76.92,124.31 83.47,117.76 87.38,117.76 88.98,116.16 88.98,114.19 C433.1 ; 70.52,148.69 v2(70.52,148.39)
PEG_RXP3: length 58.3
  TOP w0.102: CPU1.F15 74.86,152.83 74.74,152.71 v1(74.74,152.37)
  BOTTOM w0.102: v2(67.9,151.74) 67.68,151.96 ; 67.68,151.96 68.39,152.67 74.2,152.67 74.33,152.54 74.33,152.06 74.45,151.94 74.62,151.94 74.74,152.06 v1(74.74,152.37) ; 67.68,151.96 64.87,149.14 64.87,134.5 74.33,125.04 74.33,123.98 82.52,115.78 84.06,115.78 84.26,115.58 84.26,115.02 84.06,114.82 83.57,114.82 83.49,114.73 83.49,114.35 C439.1
PEG_TXN0: length 52.7
  TOP w0.102: GPU1.AG7 89.1,111 89.1,111.8 78.98,121.92 74.46,121.92 v1(74.07,121.54) ; C47.1 61.76,145.41 v3(61.63,145.29)
  BOTTOM w0.102: v3(61.63,145.29) 62.19,145.85 63.08,145.85 63.42,145.51 63.42,141.02 ; v2(63.1,141.02) 63.42,141.02 ; 63.42,141.02 63.42,134.66 71.54,126.54 72.84,125.24 72.84,122.36 73.24,121.97 73.64,121.97 v1(74.07,121.54)
PEG_TXN1: length 56.2
  TOP w0.102: GPU1.AE7 88.43,109.86 88.43,110.06 88.24,110.24 88.24,110.99 88.37,111.12 88.37,111.6 79.27,120.7 73.69,120.7 73.57,120.57 72.85,120.57 v3(72.68,120.4) ; C49.1 62.45,143.76 v3(61.63,143.76)
  BOTTOM w0.102: v2(60.21,138.25) 60.52,138.25 ; 60.52,138.25 60.52,127.23 67.46,120.3 71.69,120.3 71.79,120.4 v3(72.68,120.4) ; 60.52,138.25 60.52,143.47 60.82,143.76 v3(61.63,143.76)
PEG_TXN2: length 60.8
  TOP w0.102: v3(74.2,119.25) 74.2,119.37 74.49,119.66 74.68,119.66 74.84,119.51 79.53,119.51 87.33,111.71 87.33,111.06 87.49,110.9 87.49,110.27 GPU1.AF9 ; C38.1 62.33,147.96 61.88,147.96 61.63,148.21 v3(61.63,148.34)
  BOTTOM w0.102: 59.34,140.21 59.34,135.58 59.86,135.06 59.86,126.9 67.32,119.44 73.66,119.44 73.8,119.58 74.05,119.58 74.2,119.43 v3(74.2,119.25) ; 59.34,140.21 59.34,146.31 61.13,148.09 61.39,148.09 v3(61.63,148.34) ; 59.34,140.21 v2(59.04,140.21)
PEG_TXN3: length 60.6
  TOP w0.102: v3(75.73,117.98) 76.03,118.29 79.81,118.29 86.42,111.68 86.42,110.8 GPU1.AG10 ; v3(60.1,149.1) 60.4,149.39 60.4,149.76 C31.1
  BOTTOM w0.102: 59.2,128.7 59.2,134.33 57.86,135.67 57.86,145.76 60.52,148.42 60.52,148.68 v3(60.1,149.1) ; 59.2,128.7 v2(58.88,128.7) ; 59.2,128.7 59.2,126.5 67.41,118.3 75.41,118.3 v3(75.73,117.98)
PEG_TXP0: length 52.8
  TOP w0.102: C46.1 61.88,146.3 v3(61.63,146.05) ; GPU1.AG6 89.32,110.98 89.32,111.89 79.07,122.14 74.37,122.14 v1(74.07,122.43)
  BOTTOM w0.102: v3(61.63,146.05) 61.97,146.05 61.98,146.06 63.17,146.06 63.63,145.6 63.63,142.6 ; 63.63,142.6 v2(63.94,142.6) ; 63.63,142.6 63.63,134.75 73.06,125.33 73.06,122.45 73.33,122.19 73.83,122.19 v1(74.07,122.43)
PEG_TXP1: length 56.1
  TOP w0.102: v3(61.63,143) 61.63,143.12 61.89,143.38 62.21,143.38 C50.1 ; GPU1.AF7 88.64,110.06 88.64,110.15 88.46,110.33 88.46,110.9 88.58,111.03 88.58,111.69 79.36,120.92 74.97,120.92 74.86,121.03 74.55,121.03 74.44,120.92 73.6,120.92 73.48,120.79 72.92,120.79 72.68,121.04 v3(72.68,121.16)
  BOTTOM w0.102: v3(61.63,143) 61.63,143.1 61.18,143.55 60.9,143.55 60.74,143.38 60.74,141.17 ; 60.74,141.17 60.74,127.32 67.55,120.51 71.6,120.51 71.7,120.61 72.25,120.61 72.68,121.04 v3(72.68,121.16) ; 60.74,141.17 v2(61.07,141.17)
PEG_TXP2: length 60.8
  TOP w0.102: C44.1 62.33,147.57 v3(61.63,147.57) ; GPU1.AE9 87.59,109.57 87.59,110.07 87.71,110.18 87.71,110.98 87.54,111.15 87.54,111.8 79.62,119.72 74.92,119.72 74.77,119.88 74.34,119.88 v3(74.2,120.02)
  BOTTOM w0.102: 59.56,144.27 59.56,146.22 61.22,147.88 61.5,147.88 61.63,147.75 v3(61.63,147.57) ; 59.56,144.27 59.56,135.67 60.08,135.15 60.08,126.99 67.41,119.66 73.57,119.66 73.71,119.8 73.99,119.8 v3(74.2,120.02) ; 59.56,144.27 v2(59.85,144.27)
PEG_TXP3: length 60.6
  TOP w0.102: v3(75.73,118.75) 75.97,118.5 79.9,118.5 86.64,111.77 86.64,111.18 GPU1.AG9 ; C32.1 60.61,149.67 60.61,149.35 v3(60.87,149.1)
  BOTTOM w0.102: v3(60.87,149.1) 60.74,148.97 60.74,148.34 58.07,145.67 58.07,136.65 ; v3(75.73,118.75) 75.5,118.52 67.5,118.52 59.42,126.59 59.42,134.42 58.07,135.76 58.07,136.65 ; 58.07,136.65 v2(58.38,136.65)
PEX_CLKREQ: length 6.4
  TOP w0.102: v1(89.97,107.09) 89.6,107.46 GPU1.AC6
  BOTTOM w0.102: v2(90.58,109.27) 91.49,109.27 Q54.S 91.79,109.51 R672.2 91.79,107.14 R674.2 91.33,107.47 90.36,107.47 v1(89.97,107.09)
PEX_PLLVDD_GPU: length 1.2
  TOP w0.356: GPU1.AA15 82.18,105.86 v1(82.58,106.26) 82.98,105.86 GPU1.AA14
  vias: v2(81.82,109.6)
PEX_RST_GPU: length 54.4
  TOP w0.102: R251.2 v3(96.43,110.87) 96.05,110.49 96.05,109.98 94.01,107.95 89.31,107.95 88.86,107.5 GPU1.AC7 ; R673.2 100.43,88.07 v3(100.49,88.01) 100.55,87.95 R279.1
  BOTTOM w0.102: v3(100.49,88.01) 101.35,88.87 101.35,109.41 100.21,110.55 98.78,110.55 98.33,111 v2(98.28,111) 98.18,111.1 98.18,112.09 97.77,112.5 97.77,115.75 96.49,117.03 R668.2 94.78,116.4 94.78,115.32 95.03,115.06 95.03,113.79 94.6,113.36 94.6,110.82 94.9,110.52 96.07,110.52 v3(96.43,110.87)
PEX_RST_GPU_D#: length 4.6
  BOTTOM w0.102: D17.3 R668.1 96.36,116.14 v2(96.43,116.08)
PEX_TERMP: length 8.5
  TOP w0.127: GPU1.AF25 73.52,110.28 73.52,113.76 73.35,113.93 R243.1 73.35,114.9 73.11,115.14 71.94,115.14 71.36,115.72 v4(71.36,116.66)
PEX_TSTCLK_OUT: length 9.5
  TOP w0.127: GPU1.AF22 76.79,110.29 76.79,111.02 77.96,112.19 78.8,112.19 80.27,113.67 80.27,114.38 v4(80.09,114.55) 79.69,114.55 79.15,114.01 78.57,114.01 78.51,114.07 R244.2
PEX_TSTCLK_OUT#: length 7.6
  TOP w0.127: GPU1.AE22 76.4,109.32 76.04,109.68 76.04,113.31 R244.1 77.32,114.58 v4(78.81,114.58)
PIRQA#: length 11.8
  TOP w0.102: CPU1.BB11 94.61,150.81 95.82,149.61 97.94,149.61 v4(98.31,149.23) 98.7,149.23 99.6,148.34 99.6,145.72 99.4,145.52 99.4,144.73 99.6,144.53 100.24,144.53 100.46,144.3 RN18.1
PLT_RST#_EC: length 6.8
  TOP w0.102: KBC1.7 133.14,48.28 134.09,47.32 134.09,46.63 133.71,46.25 133.36,46.25 v3(133.28,46.18) 133.07,45.96 C200.1 R445.1
  BOTTOM w0.102: v2(134.09,46.18) v3(133.28,46.18)
PLT_RST#_TPM: length 10.9
  TOP w0.102: v1(127.92,50.55) 129.85,48.62 129.85,46.79 129.42,46.35 129.23,46.35 129.22,46.34 129.1,46.34 128.43,45.67 R443.2
  BOTTOM w0.102: v1(127.92,50.55) 128.56,51.18 129.04,51.18 129.5,50.72 v2(129.5,50.7) 129.24,50.44 128.62,50.44 U34.17
PLTRST#_PCH: length 31.4
  TOP w0.102: v1(88.27,149.63) 88.6,149.96 CPU1.AN10
  BOTTOM w0.102: R646.1 D25.1 105.63,128.14 v2(104.63,129.15) 97.58,136.2 97.58,139.24 91.47,145.35 89.98,145.35 88.98,146.36 88.98,146.82 88.59,147.21 88.59,149.31 v1(88.27,149.63)
PLTRST*_SIO: length 6.1
  TOP w0.102: R445.2 131.48,44.89 R751.2 130.78,44.89 130.4,44.51 130.14,44.51 129.64,45.02 R749.2 129.45,45.89 v1(129.42,45.91)
  BOTTOM w0.102: v1(129.42,45.91) 129.64,46.13 130.69,46.13 v2(131.01,46.45)
PLTRST_CR: length 133.6
  TOP w0.102: v1(177.83,147.07) 177.83,151.97 177.48,152.32 175.54,152.32 171.52,156.34 163.99,156.34 v1(163.67,156.02)
  BOTTOM w0.102: U28.1 177.71,146.94 v1(177.83,147.07) ; R758.2 145.26,58.59 145.7,59.03 145.7,60.96 145.65,61.01 145.65,70.15 146.24,70.74 146.24,71.57 145.82,71.99 145.82,80.69 146.97,81.85 146.97,87.79 145.55,89.21 145.55,106.25 145.02,106.78 145.02,117.82 147.7,120.5 155.15,120.5 160.08,125.42 160.08,149.04 163.36,152.32 v2(163.36,153.8) 163.36,155.7 v1(163.67,156.02)
PLTRST_LAN_N: length 138.6
  TOP w0.102: v3(34.83,15.46) U23.19
  L4 w0.127: v3(34.83,15.46) 38.28,18.91 42.72,18.91 43.2,19.39 57.6,19.39 64.02,25.82 103.35,25.82 110.34,32.8 112.66,32.8 114.28,34.42 115.81,34.42 121.52,40.14 123.22,40.14 125.63,42.55 133.23,42.55 136.35,45.67 144.33,45.67 147.8,49.14 147.8,55.58 v1(146.09,57.28)
  BOTTOM w0.102: v2(34.53,16.36) 34.83,16.06 v3(34.83,15.46) ; R760.2 145.38,57.28 v1(146.09,57.28)
PLTRST_N: length 465.5
  TOP w0.102: v3(164.75,131.57) 162.72,129.54 v1(158.28,129.54) ; v3(130.23,43.76) 129.81,43.76 R749.1 R443.1 128.16,43.87 125.01,43.87 124.19,44.69 124.19,45.78 122.9,47.07 116.11,47.07 115.35,47.83 115.35,49.02 115.1,49.28 v4(115.1,49.78) 115.1,50.12 LPC1.3
  L3 w0.127: v3(30.39,225.43) 31.41,226.45 50.33,226.45 50.68,226.1 58.27,226.1 58.87,226.69 79.82,226.69 81.2,225.32 81.2,210.75 81.61,210.33 83.88,208.06 86.81,208.06 87.54,208.79 119.96,208.79 126.05,214.88 136.62,214.88 144.59,206.92 150.53,206.92 152,205.45 157.76,205.45 162.89,200.32 162.89,194.55 165.2,192.25 165.2,132.02 v3(164.75,131.57) ; v1(158.28,129.54) 158.34,129.48 158.34,125.31 155.71,122.68 131.7,122.68 130.18,124.21 116.92,124.21 115.36,125.76 106.4,125.76 v3(105.62,124.98) ; v3(130.23,43.76) 130.41,43.76 130.7,43.47 134.27,43.47 135.47,44.67 140.61,44.67 142.87,46.92 142.87,47.63 142.86,47.65 142.86,50.79 142.08,51.56 142.08,52.6 142.15,52.66 142.15,52.83 v1(142.53,53.21)
  BOTTOM w0.102: U32.1 145.07,52.82 145.19,52.94 145.19,53.34 145.07,53.47 U32.2 143.65,53.47 143.47,53.64 142.96,53.64 v1(142.53,53.21) ; R646.2 106.78,126.36 C416.1 R651.1 105.74,125.09 v3(105.62,124.98) ; v3(30.39,225.43) 30.2,225.43 R530.1 ; LPC1.3 109.63,55.58 109.63,58.55 111.31,60.22 124.16,60.22 125.32,61.39 127.34,61.39 127.69,61.75 127.69,65.68 128.28,66.26 128.28,67.89 132.52,72.14 135.73,72.14 140.98,77.39 140.98,99.5 139.01,101.47 139.01,103.98 138.04,104.94 138.04,115.66 144.01,121.63 154.69,121.63 158.33,125.27 158.33,129.49 v1(158.28,129.54)
PLTRST_N_1A: length 5.2
  TOP w0.102: v3(101.25,86.23) 101.38,86.36 R279.2 99.86,87.06 C106.2 99.41,86.61 Q28.G
  BOTTOM w0.102: v2(100.57,86.74) 100.74,86.74 v3(101.25,86.23)
PLTRST_N_D: length 33.4
  TOP w0.102: v3(133.89,43.94) 133.54,43.59 131.52,43.59 R751.1
  L3 w0.127: v1(142.02,55.37) 141.77,55.12 141.77,52.82 141.7,52.76 141.7,51.4 142.08,51.02 142.08,48.62 141.93,48.46 141.93,46.61 140.47,45.15 135.1,45.15 v3(133.89,43.94)
  BOTTOM w0.102: R758.1 R760.1 144.37,57.19 144.71,56.85 146.23,56.85 146.51,56.57 146.51,55.23 146.06,54.78 U32.4 ; R758.1 R754.1 ; R758.1 144.05,58.1 R756.1 142.97,58.1 v2(142.15,57.28) 142.02,57.15 v1(142.02,55.37)
PLTRST_SL_N: length 119.3
  TOP w0.102: U7.2 100.49,112.27 100.11,111.89 99.6,111.89 v3(99.09,111.38) 98.65,111.38 R247.1
  L4 w0.127: v3(94.01,56.26) 94.52,55.75 95.44,55.75 95.64,55.96 95.64,57 96.05,57.4 102.8,57.4 103.56,56.64 106.89,56.64 107.75,57.49 122.8,57.49 123.7,56.59 132.04,56.59 132.91,57.47 141.45,57.47 142.65,56.26 v1(142.65,54.86)
  BOTTOM w0.102: R756.2 143.29,56.64 v2(142.65,56.01) v1(142.65,54.86) ; v3(99.09,111.38) 99.52,110.95 100.32,110.95 101.71,109.56 101.71,67.17 94.01,59.48 v3(94.01,56.26)
PM_CLKRUN#_EC: length 148.8
  TOP w0.102: v1(134.4,52.96) 133.99,52.55 133.99,50.36 133.54,49.9 KBC1.8
  L3 w0.127: v3(146.97,88.65) 143.66,85.33 143.66,74.91 138.41,69.67 138.41,65.86 134.4,61.85 134.4,59.57 131.78,56.95 130,56.95 125.34,52.29 124.07,52.29 v3(123.6,51.82)
  L4 w0.127: v3(107.86,139.19) 108.62,139.19 109.76,138.05 109.76,135.48 113.16,132.08 113.61,132.08 120.89,124.8 120.89,124.31 129.01,116.19 135.35,116.19 139.39,120.23 144.6,120.23 v3(146.34,118.49) ; v3(123.6,51.82) 124.68,52.9 134.11,52.9 134.18,52.96 v1(134.4,52.96)
  BOTTOM w0.102: R773.1 123.67,51.88 v3(123.6,51.82) ; v3(107.86,139.19) 107.6,139.45 R623.1 ; v3(146.34,118.49) 146.34,118.26 v2(145.8,117.73) 145.37,117.3 145.37,107.8 145.91,107.27 145.91,89.71 v3(146.97,88.65)
PM_CLKRUN#_TPM: length 3
  BOTTOM w0.102: U34.13 125.76,52.33 v2(125.64,52.45) 125.38,52.7 R773.2
PM_PCH_PWROK: length 49.3
  TOP w0.089: 95.31,154.99 94.53,154.99 93.86,155.65 CPU1.BA20
  TOP w0.102: 95.31,154.99 99.35,154.99 100.22,155.86 RN3.3 102.2,156.39 102.27,156.47 104.04,156.47 112.38,148.13 112.38,126.9 v3(110.68,125.2) 110,124.52 R217.2
  BOTTOM w0.102: v3(110.68,125.2) 110.65,125.17 110.65,124.39 v2(110.64,124.38)
PM_PWRBTN_N: length 424.4
  TOP w0.089: 96.96,151.68 96.72,151.92 96.15,151.92 95.09,152.97 94.05,152.97 93.91,153.11 CPU1.BA15
  TOP w0.102: 96.96,151.68 96.98,151.66 101.79,151.66 102.14,152.02 103.41,152.02 103.97,151.46 103.97,144.76 106.74,141.99 107.42,141.99 108.31,141.1 108.31,134.19 v3(107.84,133.72) ; R4.2 v3(18.83,225.93) ; R428.1 124.76,52.25 124.65,52.25 124.3,52.59 R412.2 123.73,52.7 122.64,53.8 122.64,57.24 122.35,57.53 121.82,57.53 121.08,58.27 120.31,58.27 116.75,61.83 v3(116.75,61.85)
  L3 w0.127: v3(18.83,225.93) 20.35,227.46 122.15,227.46 123.58,226.02 123.58,222.63 125.12,221.1 130.57,215.65 136.94,215.65 144.9,207.68 159.38,207.68 v3(160.18,206.88)
  L4 w0.127: v3(107.84,133.72) 112.36,129.2 114.1,129.2 117.51,125.79 117.51,125.35 128.32,114.54 136.16,114.54 v3(140.11,118.49)
  BOTTOM w0.102: v3(160.18,206.88) v2(160.18,202.18) 160.18,196.47 160.46,196.19 160.46,151.02 158.95,149.51 158.95,131.2 157.84,130.1 157.84,128.61 157.31,128.08 157.31,124.76 154.63,122.07 143.7,122.07 v3(140.11,118.49) 139.66,118.95 135.23,118.95 134.45,118.17 134.45,109.8 136.25,108 136.25,106.75 136.2,106.69 136.2,105.45 138.07,103.59 138.07,101.37 138.07,101.08 140.04,99.11 140.04,77.77 135.34,73.08 127.21,73.08 116.75,62.61 v3(116.75,61.85)
PM_RSMRST_PWRGD_XDP: length 20.8
  TOP w0.102: v4(16.42,223.14) 16.67,223.39 R2.2 R3.2 18.07,223.96 18.07,219.81 19.43,218.44 26.48,218.44 27.21,217.71 27.21,217.66 27.8,217.07 28.37,217.07 29.33,216.1 XDP1.39
PM_SLP_S3#_R: length 5.4
  TOP w0.102: R328.1 63.06,75.69 63.86,75.69 v4(64,75.55) 64,75.26 63.29,74.55 63.29,73.47 62.77,72.95 SCA1.45
PORTC_SPK_L: length 31.6
  TOP w0.203: C174.1 v3(159.01,58.29) ; U11.43 162.39,80.46 v3(162.34,80.52)
  L3 w0.203: v3(162.34,80.52) 164.17,80.52 165.03,79.65 165.03,73.32 165.31,73.04 165.31,73.02 166.25,72.08 166.25,68.17 164.38,66.31 164.38,65.61 161.83,63.06 161.83,59.61 161.15,58.93 159.65,58.93 v3(159.01,58.29)
  BOTTOM w0.203: v3(159.01,58.29) v2(158.2,58.29)
PORTC_SPK_L_1: length 2.8
  TOP w0.203: R391.1 156.12,58.7 156.83,59.41 v4(157.18,59.41) 157.34,59.26 157.34,58.43 C174.2
PORTC_SPK_R: length 33.9
  TOP w0.203: v3(161.65,81.15) 161.65,80.44 161.99,80.1 U11.44 ; C175.1 v3(159.77,58.29)
  L3 w0.203: v3(161.65,81.15) 161.7,81.1 164.41,81.1 165.62,79.9 165.62,73.57 165.9,73.29 165.9,73.26 166.83,72.32 166.83,67.87 164.97,66 164.97,65.37 162.47,62.87 162.47,59.42 161.34,58.29 v3(159.77,58.29)
  BOTTOM w0.203: v3(159.77,58.29) v2(160.59,58.29)
PORTC_SPK_R_1: length 2.5
  TOP w0.203: R392.1 161.86,59.28 v4(161.45,59.28) 161.45,59.26 161.4,59.21 161.4,58.41 C175.2
PP_TPM: length 2
  BOTTOM w0.102: TP78.1 121.7,48.77 122.58,47.88 U34.4
PQ4206_D: length 6
  TOP w0.152: PQ5.3 90.58,39.45 91.45,38.58 91.45,36.78 v4(91.3,36.63) 90.51,36.63 PR111.2
PQ4406_2: length 4.2
  BOTTOM w0.152: R743.1 PR243.2 25.69,63.88 v2(26.45,64.64) 25.69,65.41 PQ8.2
PQ4406_3: length 2.7
  BOTTOM w0.152: PQ8.3 25.04,65.01 v2(24.67,64.64) PR244.2
PQ4406_5: length 4
  BOTTOM w0.152: PR242.2 24.94,69.41 PC275.1 v2(25.81,69.22) 25.69,69.09 PQ8.5
PQ4406_6: length 4
  BOTTOM w0.152: PQ8.6 26.34,68.34 v2(27.21,69.22) 27.34,69.34 PC275.2 27.35,70.29 PR241.1
PQ4409_C: length 18.9
  TOP w0.152: v3(33.82,52.2) 34.26,52.64 PQ1.C
  BOTTOM w0.152: v2(34.58,52.58) 34.2,52.58 v3(33.82,52.2) 30.6,52.2 26.2,56.61 26.2,58.62 25.36,59.46 25.36,61.2 PR245.1 25.69,61.53 PR243.1
PQ4409_E: length 7.5
  TOP w0.152: PR89.2 36.23,56.01 v4(35.72,55.5) 35.72,55.24 36.29,54.67 PR90.1 36.7,53.69 PQ1.E
PRE: length 6.3
  TOP w0.102: U17.16 132.55,38.92 132.54,38.93 132.54,39.42 132.62,39.5 v3(132.62,39.88)
  BOTTOM w0.102: R794.2 131.45,41.57 v2(131.45,40.85) 131.65,40.85 v3(132.62,39.88) 132.49,39.75 R808.1
PROC_SELECT#: length 12.3
  TOP w0.089: CPU1.C64 72.61,180.93 71.19,180.93 70.26,181.87
  TOP w0.102: 70.26,181.87 69.54,182.59 69.54,185.43 68.36,186.61 66.15,186.61 v4(65.67,187.1) 64.89,187.1 R83.1
PROCHOT#_CPU: length 12
  TOP w0.089: 69.73,182.78 69.73,182.67 71.29,181.11 72.31,181.11 72.75,181.55 CPU1.C65
  TOP w0.102: 69.73,182.78 69.73,185.81 R82.2 68.94,187.67 68.94,188.54 v3(68.66,188.82)
  BOTTOM w0.102: v2(68.66,187.96) v3(68.66,188.82)
PSID_D: length 4.9
  BOTTOM w0.102: Q74.D 55.21,35.18 L30.2 v2(53.7,33.91) 52.87,33.91 52.74,34.04 R812.1
PSID_D_1: length 4.1
  BOTTOM w0.102: R812.2 51.69,35.75 Q73.B 51.44,34.07 R817.1 v2(51.4,32.82)
PSID_G: length 5.5
  BOTTOM w0.102: Q73.C R805.2 53.55,38.86 v2(53.63,38.79) 54.04,38.37 Q74.G
PSL_IN1#: length 5.8
  TOP w0.102: KBC1.73 139.94,66.75 140.5,67.31 R359.2 141,68.01 141.12,68.12 141.12,68.97 v4(141.61,69.47)
PSL_IN2#: length 5.8
  TOP w0.102: v3(130.26,68.71) 130.36,68.71 131.06,68.01 R362.2 131.22,67.38 131.94,66.66 KBC1.93
  BOTTOM w0.102: v3(130.26,68.71) 130.34,68.78 v2(131.1,68.78)
PSL_OUT#: length 33.8
  TOP w0.102: v1(139.35,66.55) 139.54,66.36 KBC1.74 ; R449.1 147.99,48.88 150.1,50.99 150.1,55.04 v1(149.64,55.5)
  L4 w0.127: v1(139.35,66.55) 140.28,67.48 142.36,67.48 143.92,65.91 149.3,65.91 v1(149.68,65.53)
  BOTTOM w0.102: v1(149.68,65.53) 149.68,63.43 150.07,63.04 v2(150.07,57.02) 150.07,55.93 v1(149.64,55.5)
PSYS: length 3.7
  BOTTOM w0.203: PU24.50 22.61,203.15 21.93,203.84 21.5,203.84
  BOTTOM w0.254: 21.5,203.84 21.09,203.84 v2(21.01,203.91) 20.11,203.91 PR172.2
PURE_HW_SHUTDOWN#: length 140.1
  TOP w0.102: v1(140.52,71.02) 143.19,71.02 146.08,73.91 146.08,80.52 146.59,81.03 Q29.D ; v3(100.49,85.24) 101.32,84.42 Q28.D
  L3 w0.127: v3(124.42,51.82) 125.38,51.82 130.23,56.67 131.86,56.67 134.65,59.46 134.65,61.74 138.67,65.76 138.67,69.56 140.12,71.02 v1(140.52,71.02)
  L4 w0.127: v3(124.42,51.82) 124.42,51.79 123.97,51.35 123.24,51.35 122.5,52.08 106.81,52.08 105.46,53.43 92.43,53.43 v3(92.31,53.54)
  BOTTOM w0.102: R725.1 138.18,68.9 Q59.B ; v3(100.49,85.24) 100.87,84.86 100.87,80.26 101.3,79.83 101.3,67.34 97.97,64.01 v2(96.45,64.01) 92.67,64.01 92.31,63.65 v3(92.31,53.54) ; v1(140.52,71.02) 140.06,71.02 139.19,70.15 Q59.B ; Q59.B 138.92,67.61 138.92,65.77 R732.2 138.51,65.27 138.51,63.17 137.57,62.23 137.57,61.21 136.89,60.53 136.89,58.72 137.33,58.28 140.23,58.28 140.47,58.04 D19.K
PW_CLEAR: length 84.4
  TOP w0.102: CPU1.U7 80.95,148.28 v1(81.27,148.28)
  L3 w0.127: v3(125.26,113.67) 116.62,113.67 JMP1.3
  L4 w0.127: v1(81.27,148.28) 81.89,147.66 81.89,146.65 80.26,145.02 80.26,139.98 79.57,139.29 79.57,134.68 88.31,125.95 112.47,125.95 124.75,113.67 v3(125.26,113.67)
  BOTTOM w0.102: v3(125.26,113.67) 124.94,113.35 R252.1
PWR_1D0V_BOOT: length 3.2
  TOP w0.508: PR43.1 24.77,147.6 v3(25.18,147.19)
  BOTTOM w0.305: v3(25.18,147.19) 25.2,147.22 PU28.10
  BOTTOM w0.508: v2(25.81,146.43) 25.81,146.46 25.18,147.09 v3(25.18,147.19)
PWR_1D0V_BOOT_R: length 6.5
  TOP w0.508: PC77.2 26.09,152.37 v4(25.99,152.37) 25.41,152.37 24.42,151.38 24.42,150.11 PR43.2
PWR_1D0V_CS: length 6
  BOTTOM w0.254: PU28.2 21.21,148.6 20.45,147.85 20.45,146.08 v2(20.86,145.67) 21.74,145.67 PR204.1
PWR_1D0V_EN: length 13.7
  TOP w0.102: PR44.2 22.82,149.85 PC76.1 PR42.2 21.71,150.09 v4(20.58,150.09) 20.58,149.48 v3(20.96,149.11)
  BOTTOM w0.102: PU28.3 20.97,149.1 v3(20.96,149.11) 20.02,148.17 20.02,145.03 20.91,144.15 21.88,144.15 D23.A
PWR_1D0V_FB: length 7.4
  TOP w0.254: v3(20.99,152.4) 21.5,152.91 PR40.1 PR39.2 PC75.2
  BOTTOM w0.254: PU28.4 21.22,149.6 20.3,150.52 v2(20.3,150.93) 20.3,151.71 v3(20.99,152.4)
PWR_1D0V_LGATE: length 13
  L4 w0.762: v5(25.56,150.9) 26.96,152.3 26.96,155.19 27.72,155.96 v5(31.46,155.96)
  BOTTOM w0.305: PU28.6 25.2,150.55 v5(25.56,150.9)
  BOTTOM w0.762: PU27.4 v5(31.46,155.96) v2(30.44,155.96)
PWR_1D0V_PG: length 5
  TOP w0.102: PR45.2 PR46.1 23.27,146.56 v3(23.66,146.94)
  BOTTOM w0.102: v3(23.66,146.94) 23.25,146.53 v2(22.77,146.53) 22.11,147.19 PU28.1
PWR_1D0V_PHASE: length 18.4
  TOP w0.508: v5(26.32,149.22) 26.58,148.97 PC77.1
  L4 w0.762: v5(39.78,144.91) 38.9,145.8 30.01,145.8 27.72,148.08 27.72,148.41 26.9,149.22 v5(26.32,149.22)
  BOTTOM w0.305: PU28.8 26.2,149.1 v5(26.32,149.22)
  vias: v2(40.72,145.77) v2(41.66,155.47) v5(38.97,149.35) v5(39.91,149.35) v5(39.91,147.75) v5(39.91,146.79) v5(40.29,156.01) v5(40.29,155.04) v5(40.27,154.13) v5(40.93,149.35) v5(41.33,152.88) v5(41.33,151.92) v5(41.31,151)
PWR_1D0V_RF: length 3.9
  TOP w0.254: PR41.1 21.37,151.89 v3(20.99,151.51)
  BOTTOM w0.254: PU28.5 v2(22.11,151.76) 21.24,151.76 v3(20.99,151.51)
PWR_1D0V_SNB: length 2.8
  BOTTOM w0.508: PR203.2 35.39,150.11 PC255.1 v2(34.13,149.1)
PWR_1D0V_UGATE: length 19.3
  L4 w0.762: v5(39.78,143.51) 39.15,143.51 38.26,144.4 29.43,144.4 26.32,147.5 v5(26.32,147.83)
  BOTTOM w0.305: PU28.9 25.81,148.6 26.32,148.08 v5(26.32,147.83)
  BOTTOM w0.508: v5(26.32,147.83) v2(27.21,147.83)
  BOTTOM w0.762: PU29.4 v5(39.78,143.51)
PWR_1D0V_VCC: length 7.4
  BOTTOM w0.305: 26.11,150 25.71,149.6 PU28.7
  BOTTOM w0.508: PR273.1 PR202.1 26.91,153.17 PC252.1 26.68,151.09 v2(26.68,150.88) 26.68,150.57 26.11,150
PWR_1D35V_VGA: length 27.4
  TOP w0.508: v3(123.35,74.17) 123.22,74.04 PC106.1 PR77.1
  L3 w0.508: v3(123.35,74.17) 122.21,74.17 121.95,73.91 121.95,71.12 120.94,70.1 104.94,70.1 104.43,70.61 v3(104.43,72.39)
  BOTTOM w0.508: v3(104.43,72.39) 104.6,72.57 v2(105.54,72.57)
PWR_2D5V_EN_R: length 7.8
  BOTTOM w0.254: PU21.8 v2(129.45,206.88) 129.19,206.88 128.56,207.52 128.56,210.25 PR146.2
PWR_2D5V_FB: length 6.1
  BOTTOM w0.254: PU21.2 138.08,205.61 138.65,206.18 PC145.2 PR135.2 PR137.1 v2(141.51,207.14)
PWR_2D5V_PG: length 9.1
  BOTTOM w0.254: PU21.7 v2(129.45,205.61) 127.92,207.14 ; 127.92,207.14 127.92,208.41 127.22,209.11 PR159.2 PC157.1 ; 127.92,207.14 127.54,206.76 U27.2
PWR_2D5V_VIN:
  vias: v2(134.65,211.07)
PWR_2D5V_VOUT:
  vias: v2(138.46,203.33)
PWR_2V5_EN: length 3.2
  BOTTOM w0.254: v2(126.27,212.6) 126.33,212.53 PR146.1 C287.1 R534.2
PWR_3D3V_5V_PG: length 5.4
  TOP w0.203: PU17.7 153.09,24.29 153.38,24.58
  TOP w0.254: v3(154.82,25.15) 153.94,25.15 153.38,24.58
  BOTTOM w0.254: v2(152.99,26.8) 153.47,26.31 153.72,26.31 PR263.2 154.15,25.88 154.15,25.46 154.46,25.15 v3(154.82,25.15)
PWR_3D3V_BOOT2: length 5
  TOP w0.203: 151.98,25.25 151.98,24.92 152.29,24.61 PU17.9
  TOP w0.508: PR112.2 151.93,26.04 v3(151.93,25.76) 151.93,25.7 151.98,25.65 151.98,25.25
  BOTTOM w0.508: v3(151.93,25.76) 151.93,26.49 v2(151.67,26.75)
PWR_3D3V_BOOT2_A: length 4.5
  TOP w0.508: PC125.2 153.17,27.53 PR112.1 152.64,27.13 151.35,28.42 v3(151.2,28.42)
  BOTTOM w0.508: v2(151.19,29.24) 151.19,29.23 151.19,28.45 151.2,28.43 v3(151.2,28.42)
PWR_3D3V_CS2: length 7.5
  TOP w0.203: PU17.5 154.24,23.5
  TOP w0.254: v3(155.18,27.33) 155.9,26.61 PR113.1 155.68,26.3 155.68,25.1 155,24.41 155,24.26 154.24,23.5
  BOTTOM w0.254: v2(156.7,28.57) 155.46,27.33 v3(155.18,27.33)
PWR_3D3V_EN2: length 17
  TOP w0.203: PU17.6 153.53,23.78 153.96,24.21 v3(154.12,24.21)
  L4 w0.254: v3(154.12,24.21) 154.12,27.01 151.67,29.46 151.67,31.11 148.88,33.91 v3(148.62,33.91)
  BOTTOM w0.254: PC289.1 153.31,24.7 153.35,24.74 v2(153.45,24.74) 153.5,24.74 154.12,24.12 v3(154.12,24.21) ; PR272.1 148.5,34.04 v3(148.62,33.91) 148.75,34.04 PR266.1
PWR_3D3V_FB2: length 7
  TOP w0.203: PU17.4 154.85,22.63 154.97,22.75 154.97,23.5 155.1,23.62
  TOP w0.254: 155.1,23.62 155.8,24.32 PC126.2 156.24,23.9 v4(156.83,23.32) 157.26,23.75 PR116.2 158.21,25.27 PR115.1
PWR_3D3V_FB2_A: length 33.1
  TOP w0.381: v3(157.01,26.01) 157.26,25.76 PR116.1 PC126.1
  L3 w0.381: v3(138.59,12.57) 139.63,11.53 147.09,11.53 154.43,18.86 154.43,19.95 154.3,20.08 154.3,20.92 157.01,23.62 v3(157.01,26.01)
  BOTTOM w0.254: v3(138.59,12.57) 139.1,12.57 v2(139.61,13.08) 139.48,13.21 138.08,13.21 137.57,12.7 PG23.1
PWR_3D3V_HG2: length 35.7
  TOP w0.203: 151.54,24.64 151.89,24.3 PU17.10
  TOP w0.508: v5(151.01,25.82) 151.01,25.17 151.54,24.64
  L3 w0.762: v5(129.95,17.27) 130.21,17.53 130.21,17.73 133.89,21.41 133.89,25.99 136.33,28.42 146.95,28.42 149.55,25.82 v5(151.01,25.82)
  BOTTOM w0.406: v5(129.95,17.27) 129.07,17.27 v2(128.43,17.91) 128.95,18.43 PU36.4
PWR_3D3V_LDO3: length 6.8
  TOP w0.203: PU17.3 155.35,22.23
  TOP w0.508: v3(155.74,23.24) 156.12,22.86 PC128.1 155.48,22.1 155.35,22.23
  BOTTOM w0.508: PG21.2 155.56,24.03 154.97,24.03 154.4,23.46 v2(154.4,23.09) 154.66,22.83 155.11,22.83 155.67,23.17 v3(155.74,23.24)
PWR_3D3V_LG2: length 17.4
  TOP w0.203: PU17.11 151.14,23.43 v5(150.83,23.74)
  L3 w0.762: v5(137.45,21.72) 137.83,21.72 138.34,22.23 138.34,23.62 139.1,24.38 146.45,24.38 147.1,23.74 v5(150.83,23.74)
  BOTTOM w0.508: v2(150.93,22.76) 150.93,23.63 v5(150.83,23.74)
PWR_3D3V_PH2: length 40.3
  TOP w0.203: PU17.8 152.69,24.89
  TOP w0.508: 152.69,24.89 152.69,25.17 v5(153.14,25.63) 153.17,25.65 153.83,25.65 PC125.1
  L3 w0.762: v5(153.14,25.63) 152.71,26.06 152.71,26.08 152.41,26.39 152.41,26.4 151.59,27.22 150.16,27.22 147.04,30.34 136.27,30.34 132.49,26.57 132.49,21.99 128.81,18.31 128.81,16.92 129.47,16.26 v5(130.21,16.26)
  vias: v2(136.2,15.95) v5(131.61,16.38) v5(132.62,17.27) v5(133.26,16.38) v5(134.27,17.27) v5(134.78,16.38) v5(135.8,17.27)
PWR_3D3V_SN: length 4.7
  BOTTOM w0.508: PC294.1 138.72,20.64 138.95,20.41 138.95,18.47 138.49,18.01 v2(138.49,17.86) 138.21,17.58 PR268.2
PWR_5V3V_EMN_R: length 6.8
  BOTTOM w0.254: D18.3 133.95,56.58 v2(134.78,55.75) 134.84,55.82 R771.1 R770.1 R769.1 138.08,57.43 D19.A
PWR_5V_BOOT1: length 6.5
  TOP w0.203: PU17.17 152.29,20.02 151.9,19.63 151.9,19.25 151.68,19.04
  TOP w0.508: PR120.1 149.46,18.29 v4(149.46,19.25) 149.92,19.25 150.6,18.57 151.21,18.57 151.68,19.04
PWR_5V_BOOT1_A: length 3.5
  TOP w0.508: 151.8,16.13 150.6,16.13 PR120.2 149.21,15.67 v4(148.7,16.18)
PWR_5V_BYP1: length 20
  TOP w0.203: PU17.14 149.79,21.82 v3(149.64,21.97)
  TOP w0.305: PG19.1 v3(147.23,14.88)
  TOP w0.381: PC129.1 149.45,21.78 v3(149.64,21.97)
  L4 w0.305: v3(147.23,14.88) 147.25,14.86 150.01,14.86 154.36,19.21 154.36,20.15 153.43,21.08 152.15,21.08 151.16,22.07 149.74,22.07 v3(149.64,21.97)
  BOTTOM w0.381: v3(147.23,14.88) 147.86,15.52 v2(147.86,15.57)
PWR_5V_CS1: length 4.1
  TOP w0.203: 154.24,21.11 PU17.1
  TOP w0.254: v4(153.42,17.83) 153.42,17.95 PR119.1 154.4,20.18 154.39,20.19 154.39,20.96 154.24,21.11
PWR_5V_EN1: length 24.6
  TOP w0.203: PU17.20 153.49,19.77 v3(153.63,19.63)
  L3 w0.254: v3(153.63,19.63) 153.73,19.74 153.73,21.23 155.1,22.61 155.1,24.3 155.35,24.56 155.35,25.78 151.67,29.46 151.67,31.11 149.77,33.02 v3(148.62,33.02)
  BOTTOM w0.254: PR267.1 v3(148.62,33.02) PR271.1 ; PC293.1 153.77,20.7 153.77,20.69 153.39,20.32 152.13,20.32 v2(151.98,20.17) 152.38,19.76 153.5,19.76 v3(153.63,19.63)
PWR_5V_FB1: length 5
  TOP w0.203: PU17.2 154.8,21.82 PC130.2
  TOP w0.254: PR118.1 157.84,20.85 v4(157.72,20.98) 157.63,20.89 PR117.2 PC130.2
PWR_5V_FB1_A: length 27.3
  TOP w0.254: PR117.1 PC130.1 155.39,20 v3(154.92,20.47)
  TOP w0.381: PG20.1 145.63,3.76 v3(145.7,3.68)
  L3 w0.381: v3(154.92,20.47) 155.1,20.29 155.1,18.64 151.82,15.36 151.82,8.48 150.91,7.57 150.91,5.33 150.52,4.94 146.58,4.94 145.7,4.06 v3(145.7,3.68)
  BOTTOM w0.254: v2(155.26,21.5) 154.92,21.17 v3(154.92,20.47)
PWR_5V_HG1: length 10.3
  TOP w0.203: PU17.16 151.89,20.28 151.48,19.88
  TOP w0.508: 151.48,19.88 v5(150.91,19.3)
  L3 w0.762: v5(150.91,19.3) 150.27,18.67 145.76,18.67 144.43,17.34 v5(144.43,17.27)
  BOTTOM w0.508: v2(150.38,18.34) 150.38,18.77 v5(150.91,19.3)
PWR_5V_LDO5: length 6.7
  TOP w0.203: PU17.13 150.33,22.23
  TOP w0.254: 150.33,22.23 150.19,22.23 149.91,22.5 149.28,22.5 v3(148.88,22.1)
  BOTTOM w0.254: v2(148.3,21.31) 148.88,21.89 v3(148.88,22.1) 148.88,22.73 PC290.1 149.51,24.82 PG22.1
PWR_5V_LG1: length 10.6
  TOP w0.203: v5(150.55,20.73) 150.93,20.73 151.14,20.93 PU17.15
  L3 w0.762: v5(150.55,20.73) 143.8,20.73 v5(142.93,21.59)
  BOTTOM w0.508: v2(149.31,20.17) 149.99,20.17 v5(150.55,20.73)
PWR_5V_PH1: length 10.5
  TOP w0.203: 152.69,19.68 PU17.18
  TOP w0.508: 152.69,19.68 152.69,19.35 152.53,19.2 v5(152.53,19.15) 152.53,18.39 PC132.2
  L3 w0.762: v5(146.34,17.27) 150.85,17.27 152.53,18.95 v5(152.53,19.15)
  vias: v2(142.96,16.31) v5(139.86,17.27) v5(140.5,16.38) v5(140.88,17.27) v5(141.51,16.38) v5(141.89,17.27) v5(145.45,16.76)
PWR_5V_SN: length 3.6
  TOP w0.508: PR121.2 137.83,17.35 v3(137.83,18.47) 138.44,19.08 138.44,19.34 PC131.1
  BOTTOM w0.508: v2(138.21,19.46) 137.83,19.08 v3(137.83,18.47)
PWR_CHG_ACDET: length 7.3
  TOP w0.254: PC124.1 PR96.1 45.5,41.97 45.82,41.66 PR104.2 44.14,41.15 v4(44.08,41.21) 43.98,41.31 v3(43.98,42.16)
  BOTTOM w0.254: PU34.6 43.32,42.82 v3(43.98,42.16)
PWR_CHG_ACN: length 21.7
  TOP w0.254: PG17.2 v3(61.09,43.94) ; v3(48.77,46.83) 47.91,46.83 PC121.1
  BOTTOM w0.254: 59.93,44.15 60.37,43.71 60.86,43.71 v3(61.09,43.94) ; 59.93,44.15 v2(60.23,44.45) ; 59.93,44.15 58.23,45.85 57.36,45.85 56.25,46.96 48.9,46.96 v3(48.77,46.83) 48.48,46.55 46.96,46.55 PC283.2 44.98,46.21 PU34.1
PWR_CHG_ACP: length 21.7
  TOP w0.254: v3(61.12,43.18) 61.96,42.34 PG18.2 ; v3(48.8,46.04) 48.28,46.04 PC122.1
  BOTTOM w0.254: PU34.2 45.11,45.71 45.25,45.85 PC283.1 46.32,46.04 v3(48.8,46.04) 49.34,46.58 56.09,46.58 57.2,45.47 58.07,45.47 58.54,45 ; 58.54,45 60.21,43.33 60.97,43.33 v3(61.12,43.18) ; 58.54,45 v2(58.28,44.73)
PWR_CHG_AD_OFF: length 82.6
  TOP w0.102: PQ5.5 89.82,42.04 89.95,42.16 91.09,42.16 v3(92.24,41.02) 92.11,40.89 PR108.1 ; KBC1.63 143.97,62.7 143.8,62.87 143.29,62.87 142.55,62.13 v1(142.55,61.72)
  L4 w0.127: v1(142.55,61.72) 141.57,61.72 140.88,61.02 131.92,61.02 131.32,61.62 129.93,61.62 129.04,62.51 125.26,62.51 124.13,61.38 120.87,61.38 120.26,61.98 120.26,62.04 119.48,62.83 115.58,62.83 115.02,62.27 105.98,62.27 105.34,62.9 93.34,62.9 v3(92.87,63.37)
  BOTTOM w0.102: v3(92.24,41.02) 92.87,41.66 v2(92.87,62.36) v3(92.87,63.37)
PWR_CHG_AD_OFF_R: length 5.4
  TOP w0.152: PR108.2 92.11,38.2 92.13,38.18 92.13,37.72 v3(92.27,37.58) 92.5,37.35 PQ6.B
  BOTTOM w0.152: v2(92.54,36.7) 92.54,37.31 v3(92.27,37.58)
PWR_CHG_BT_LR: length 1.8
  TOP w0.305: 37.88,60.96 36.89,60.96 v4(36.33,60.4)
PWR_CHG_BTST: length 4.4
  TOP w0.508: v3(40.6,47.59) 41.13,47.06 v4(41.13,46.86)
  BOTTOM w0.305: PR247.1 41.24,48.6 40.6,47.96 v3(40.6,47.59) 40.9,47.59 41.06,47.75 41.59,47.75 41.82,47.52 PU34.17
PWR_CHG_BTST_1: length 6.1
  BOTTOM w0.508: v2(37.63,50.09) 37.63,49.91 38.7,48.84 PD3.K 40.28,48.77 PR247.2 40.36,49.06 40.8,49.5 40.9,49.5 40.93,49.53 42.04,49.53 PC281.1
PWR_CHG_CMPIN: length 15.1
  TOP w0.254: PR92.1 PR94.2 48.04,44.2 v3(47.4,43.56) 46.83,42.99 PR97.1
  BOTTOM w0.254: PR252.2 47.4,43.65 v3(47.4,43.56) ; v3(47.4,43.56) 46.77,42.93 46.77,41.66 v2(47.18,41.25) 46.01,40.08 44.22,40.08 PR255.2 ; v3(47.4,43.56) 47.15,43.81 45.5,43.81 44.6,44.71 PU34.4
PWR_CHG_CMPIN_R: length 9.1
  TOP w0.254: PQ4.6 56.98,42.56 56.55,42.99 56.55,43.52 55.92,44.15 v4(55.2,44.15) 55.2,44.2 54.95,44.45 52.14,44.45 51.3,45.29 49.86,45.29 PR92.2
PWR_CHG_CMPIN_RR: length 8.5
  TOP w0.254: PR94.1 50.24,44.65 v4(51.04,44.65) 51.09,44.65 51.8,43.94 53.95,43.94 54.24,43.66 54.24,41.54 54.52,41.26 PQ4.3
PWR_CHG_HIDRV: length 16.7
  L3 w0.762: v5(44.48,58.53) 44.48,55.4 45.52,54.36 45.52,50.98 44.08,49.53 42.58,49.53 42.07,49.02 42.07,48.34 v5(42.32,48.08)
  BOTTOM w0.305: PU34.18 v5(42.32,48.08)
  BOTTOM w0.406: v5(44.48,58.53) 44.48,58.51 44.19,58.21 PU32.4
  BOTTOM w0.508: v5(44.48,58.53) v2(44.48,59.49)
PWR_CHG_ILIM: length 8.3
  TOP w0.254: PR95.1 39.59,43.32 v3(39.94,42.98) 39.66,42.7 39.66,41.83 v4(39.33,41.5) 39.17,41.5 38.58,42.1 PR100.2 38.07,43.18 PQ2.D
  BOTTOM w0.254: PU34.10 40.37,43.41 v3(39.94,42.98)
PWR_CHG_IOUT: length 5.8
  TOP w0.254: PC123.1 43.59,42.93 v3(42.83,42.16)
  BOTTOM w0.254: v2(45.22,41) 45.22,41.02 45.03,41.21 PR255.1 PR256.1 42.96,42.04 v3(42.83,42.16) 42.82,42.17 PU34.7
PWR_CHG_LODRV: length 11.8
  TOP w0.508: v5(39.45,46.91) 39.12,47.24 PC119.1
  L3 w0.762: v5(39.45,46.91) 37.5,48.87 v5(37.5,52.96)
  BOTTOM w0.305: v5(39.45,46.91) 39.53,46.84 39.53,46.56 39.88,46.21 PU34.15
  BOTTOM w0.406: v5(37.5,52.96) 37.79,53.25 PU33.4
  BOTTOM w0.508: v5(37.5,52.96) v2(37.5,51.99)
PWR_CHG_NC: length 2.9
  BOTTOM w0.254: PR254.1 38.87,43.31 39.1,43.08 v2(39.12,43.08) 39.12,43.1 40.23,44.21 PU34.11
PWR_CHG_PHASE: length 20.2
  L3 w0.762: v5(43.09,58.67) 43.09,59.11 43.9,59.93 45.06,59.93 46.92,58.07 46.92,50.4 44.61,48.08 v5(43.34,48.08)
  BOTTOM w0.305: v5(43.34,48.08) 42.82,47.57 PU34.19
  BOTTOM w0.508: PC281.2 43.98,48.72 v5(43.34,48.08)
  vias: v2(38.64,60.43) v5(38.01,58.67) v5(39.02,58.67) v5(40.04,58.67) v5(41.05,58.67) v5(42.07,58.67)
PWR_CHG_SRN: length 2.5
  BOTTOM w0.254: PU34.12 39.39,44.71 39.15,44.48 v2(39.15,44.45) 38.32,44.45 PR253.1
PWR_CHG_SRN_1: length 28
  TOP w0.254: PG15.2 v3(37.63,66.67)
  BOTTOM w0.254: 36.38,65.59 35.85,65.05 35.85,52.02 34.04,50.21 34.04,46.46 34.65,45.85 34.65,45.14 PC284.2 35.66,44.13 PC285.1 36.55,44.32 PR253.2 ; 36.38,65.59 36.76,65.97 37.37,65.97 37.63,66.22 v3(37.63,66.67) ; 36.38,65.59 v2(36.15,65.81)
PWR_CHG_SRP: length 3.3
  BOTTOM w0.254: PU34.13 39.65,45.21 39.62,45.19 38.35,45.19 PR250.1 v2(38.2,46.25)
PWR_CHG_SRP_1: length 26
  TOP w0.254: PG16.2 v3(37.63,64.9)
  BOTTOM w0.254: v2(36.56,63.45) 36.23,63.45 ; 36.23,63.45 36.23,64.9 36.92,65.58 37.37,65.58 37.63,65.33 v3(37.63,64.9) ; 36.23,63.45 36.23,51.86 34.42,50.06 34.42,46.61 35.07,45.97 PC284.1 36.16,45.15 C570.1 36.55,45.34 PR250.2
PWR_CHG_VCC: length 8.5
  TOP w0.762: v3(46.9,48.51) 46.01,48.51 PC120.1
  BOTTOM w0.305: 44.09,47.18 43.92,47.01 PU34.20
  BOTTOM w0.508: 46.77,48.51 v2(45.19,48.51) 45.19,48.29 44.09,47.18
  BOTTOM w0.762: 46.77,48.51 v3(46.9,48.51) 45.93,49.48 PR246.2
PWR_DCBATOUT_1D0V:
  vias: v2(29.14,144.02) v5(30.49,148.21) v5(30.49,147.19) v5(31.4,148.21) v5(31.4,147.19)
PWR_DCBATOUT_VDDQ: length 6.3
  BOTTOM w0.305: 82.58,220.22 82.46,220.09 79.54,220.09 79.03,219.58 PR133.1
  vias: v2(88.76,221.46) v5(85.22,221.64) v5(85.22,220.73) v5(86.14,221.64) v5(86.14,220.73)
PWR_DDR_SN: length 2.4
  BOTTOM w0.508: PC135.1 v2(97.06,223.52) 97.32,223.27 PR124.2
PWR_LED_YELLOW_C: length 16.5
  TOP w0.254: v3(24.42,19.87) 25.74,19.87 26.63,20.75 PWRCN1.9 30.82,20.75 v4(31.53,21.46) 31.97,21.91 R502.1
  BOTTOM w0.254: Q79.D 24.19,14.77 v2(24.19,15.27) 24.67,15.75 R854.2 23.91,17.53 23.91,19.36 v3(24.42,19.87)
PWR_LED_YELLOW_C2: length 3.3
  BOTTOM w0.254: R853.2 27.36,16 26.7,15.34 v2(26.2,15.34) R854.1
PWR_V1P8A_EN: length 10
  TOP w0.102: PU10.8 88.92,120.83 PC87.1 89.89,120.46 89.95,120.4 D24.A 90.84,120.02 91.35,120.52 93.81,120.52 v4(93.89,120.45) 94.09,120.65 PR58.2 PR57.1
PWR_V1P8A_FB: length 6.1
  TOP w0.254: PC85.2 97.19,123.43 97.19,122.45 v4(97.21,122.43) 96.96,122.17 96.55,122.17 96.3,122.43 96.24,122.43 PR55.1 PR53.2 95.73,123.57 PU10.2
PWR_V1P8A_PG: length 6
  TOP w0.102: PR54.2 86.14,123.24 v4(85.12,124.26) ; PR54.2 PC86.1 87.6,123.57 PU10.7 ; PR54.2 87.09,122.17 R220.2
PWR_VCC_CSN_SA: length 64.9
  TOP w0.254: v3(41.69,168.53) PR37.2 41.44,167.96 41.44,164.47 41.82,164.08 PG14.1
  L4 w0.254: v3(18.42,199.69) 18.45,199.67 18.52,199.67 18.65,199.54 18.67,199.54 19.36,198.85 19.36,194.45 17.23,192.32 17.23,180.36 18.09,179.49 18.09,177.03 25.89,169.24 39.74,169.24 40.45,168.53 v3(41.69,168.53)
  BOTTOM w0.203: 22.1,201.15 PU24.45
  BOTTOM w0.254: 22.1,201.15 22,201.24 19.67,201.24 19.27,200.85 PC180.1 PC181.2 18.47,199.64 v3(18.42,199.69) ; v3(41.69,168.53) 41.31,168.53 v2(40.96,168.88)
PWR_VCCGT_BSTA: length 5
  BOTTOM w0.203: PU24.14 28.85,204.59 29.24,204.98
  BOTTOM w0.508: PR167.2 31.45,207.65 30.28,206.47 v2(30.28,205.92) 30.19,205.92 29.24,204.98
PWR_VCCGT_BSTA_R: length 2.3
  BOTTOM w0.508: PC169.1 PR167.1 v2(34.2,207.65)
PWR_VCCGT_BSTB: length 3.4
  BOTTOM w0.203: PU24.22 29.48,200.75 29.75,200.48 v2(30.77,200.48)
  BOTTOM w0.508: v2(30.77,200.48) 31.71,200.48 PR173.1
PWR_VCCGT_BSTB_R: length 2.5
  BOTTOM w0.508: v2(33.76,202.54) 33.54,202.31 PC179.1 PR173.2
PWR_VCCGT_COMP: length 6.1
  BOTTOM w0.203: 24.74,205.34 PU24.4
  BOTTOM w0.254: PC161.2 21.88,207.96 PC166.1 21.86,207.59 22.69,207.59 v2(23.53,206.76) 23.75,206.54 23.75,206.34 24.74,205.34
PWR_VCCGT_COMP_R: length 3
  BOTTOM w0.254: v2(20.12,211.24) 20.12,210.29 20.78,209.64 20.84,209.64 PR160.1 PC161.1
PWR_VCCGT_CSCOMP: length 47.3
  TOP w0.254: v3(54.77,218.19) 54.83,218.12 PR2.2
  L4 w0.254: v3(22,211.07) 22.02,211.05 30.07,211.05 30.89,211.87 30.89,213.14 31.49,213.74 33.94,213.74 39.02,218.82 54.14,218.82 v3(54.77,218.19)
  BOTTOM w0.203: PU24.6 25.54,206.13 25.36,206.32 25.36,206.56
  BOTTOM w0.254: v3(22,211.07) 22.07,211.01 PR148.1 22.85,211 PC158.1 PC160.1 22.85,209.11 23.74,208.22 PR164.2 23.76,208.15 25.36,206.56 ; v3(54.77,218.19) v2(53.96,218.19)
PWR_VCCGT_CSNA: length 44.9
  TOP w0.254: v3(57.06,210.95) PG2.1
  L4 w0.254: v3(57.06,210.95) 56.83,211.17 56.83,218.82 55.44,220.22 38.23,220.22 34.29,216.28 31.5,216.28 29.05,213.84 29.05,212.28 v3(28.88,212.11)
  BOTTOM w0.254: v3(28.88,212.11) 28.74,211.96 28.74,211.26 PR154.1 ; v2(57.31,210.11) 57.06,210.36 v3(57.06,210.95)
PWR_VCCGT_CSNB: length 63
  TOP w0.254: v3(57.06,199.77) PG6.1
  L4 w0.254: v3(57.06,199.77) 56.83,199.55 56.83,199.14 57.21,198.75 57.6,198.75 57.93,199.09 57.93,218.68 55.63,220.98 47.91,220.98 47.28,221.62 36.64,221.62 32.88,217.85 31.61,217.85 27.62,213.87 26.96,213.87 26.64,213.55 26.64,213.04 v3(26.83,212.85)
  BOTTOM w0.254: v3(57.06,199.77) 57.06,200.35 v2(57.26,200.56) ; PR155.1 27.16,210.83 27.16,212.52 v3(26.83,212.85)
PWR_VCCGT_CSPA: length 6.1
  BOTTOM w0.203: 27.57,206.55 27.14,206.13 PU24.10
  BOTTOM w0.254: 27.57,206.55 27.57,206.81 v2(28.56,207.8) 28.93,208.17 PC164.1 29.12,208.98 PR153.1
PWR_VCCGT_CSPB: length 6.9
  BOTTOM w0.203: PR165.2 26.93,207.74 26.93,206.39 26.81,206.28 26.81,204.98 26.74,204.91 PU24.9
  BOTTOM w0.254: PR165.2 26,208.66 PC165.2 26,209.68 PR156.1 25.83,209.85 v2(24.9,209.85)
PWR_VCCGT_CSREF: length 11
  TOP w0.254: v3(26.37,206.55) 25.54,206.55 v4(25.48,206.5) 25.46,206.5 24.54,205.59 PC8.1
  L4 w0.254: v3(26.37,206.55) 27.58,207.77 v3(27.72,207.77)
  BOTTOM w0.203: v3(26.37,206.55) 26.34,206.53 PU24.8
  BOTTOM w0.254: PC164.2 PC165.1 26.96,208.85 PR155.2 ; PC164.2 28.1,208.85 PR154.2 ; PC164.2 28.04,208.52 27.72,208.2 v3(27.72,207.77)
PWR_VCCGT_CSSUM: length 17
  BOTTOM w0.203: PU24.7 25.94,206.2 25.86,206.28 25.86,206.78 25.18,207.45
  BOTTOM w0.254: PR151.1 30.39,212.34 v2(29.56,213.17) 29.34,213.39 25.85,213.39 25,212.54 PR145.1 24.3,211.01 PR147.2 23.74,210.9 PC158.2 PC160.2 23.74,209.04 24.28,208.5 24.28,208.35 25.18,207.45
PWR_VCCGT_DIFFOUT: length 7.9
  BOTTOM w0.203: 23.02,205.63 23.16,205.63 23.94,204.84 PU24.2
  BOTTOM w0.254: 23.02,205.63 22.4,206.25 20.94,206.25 v2(20.81,206.38) 20.43,206.76 PR168.1 PR166.1 19.85,207.84 19.85,208.93 PR158.1
PWR_VCCGT_DIFFOUT_R: length 2.2
  BOTTOM w0.254: PR166.2 18.48,207.77 v2(18.02,208.23) 18.02,208.62 PC159.2
PWR_VCCGT_FB: length 9.2
  BOTTOM w0.203: PU24.3 24.34,205.02 24.04,205.33
  BOTTOM w0.254: PC159.1 PR158.2 20.33,209.33 20.33,209.26 PR160.2 20.86,207.84 PC166.2 20.8,207.68 21.61,206.87 v2(22.26,206.87) 22.49,206.87 24.04,205.33
PWR_VCCGT_ILIM: length 4.7
  BOTTOM w0.203: 25.14,205.19 PU24.5
  BOTTOM w0.254: PR164.1 23.39,207.62 23.52,207.62 24.57,206.57 24.57,206.43 v2(24.75,206.25) 25.14,205.85 25.14,205.19
PWR_VCCGT_ILIM_NTC: length 41.3
  TOP w0.254: PR2.1 55.72,218.12 v3(55.66,218.19)
  L4 w0.254: v3(55.66,218.19) 54.52,219.33 38.81,219.33 33.73,214.25 31.28,214.25 30.39,213.36 30.39,212.08 29.86,211.56 23.93,211.56 23.66,211.84 v3(23.66,212.85)
  BOTTOM w0.254: v3(55.66,218.19) v2(56.47,218.19) ; v3(23.66,212.85) 23.86,212.65 PR147.1 PR148.2
PWR_VCCGT_IOUT: length 5.4
  BOTTOM w0.203: PU24.1 23.26,204.46 22.63,205.09
  BOTTOM w0.254: 22.63,205.09 22.63,205.19 22.21,205.61 v2(22.2,205.61) 22.14,205.66 19.83,205.66 PR171.2 PC174.2
PWR_VCCGT_LGA: length 26.8
  TOP w0.508: v5(32.16,204.09) 31.78,204.47 PR9.1
  TOP w0.762: v5(43.47,205.74) 43.09,206.12 PU2.4
  L4 w0.762: 43.09,207.77 43.09,206.5 43.47,206.12 v5(43.47,205.74) ; 43.09,207.77 v5(43.09,211.61) ; 43.09,207.77 39.48,207.77 36.56,204.85 33.69,204.85 32.93,204.09 v5(32.16,204.09)
  BOTTOM w0.203: 30.39,203.2 29.81,203.2 29.36,202.75 PU24.17
  BOTTOM w0.508: v5(32.16,204.09) 31.28,203.2 v2(30.51,203.2) 30.39,203.2
  BOTTOM w0.762: v5(43.09,211.61) PU22.4
PWR_VCCGT_LGB: length 26.5
  TOP w0.508: v5(32.16,202.95) 31.91,202.95 31.4,203.45 PR10.1
  TOP w0.762: PU3.4 v5(43.09,199.16)
  L4 w0.762: v5(32.16,202.95) 33.31,202.95 34.07,202.18 43.09,202.18 ; v5(42.71,204.98) 42.71,204.47 43.09,204.09 43.09,202.18 ; 43.09,202.18 v5(43.09,199.16)
  BOTTOM w0.203: 30.77,202.44 30.37,202.04 29.58,202.04 29.49,201.95 PU24.19
  BOTTOM w0.508: v2(32.98,203.56) 32.37,202.95 v5(32.16,202.95) 32.04,202.95 31.53,202.44 30.77,202.44
  BOTTOM w0.762: v5(42.71,204.98) 43.09,204.6 43.09,203.96 PU23.4
PWR_VCCGT_SNB1: length 2.8
  BOTTOM w0.508: PR144.2 PC149.1 43.01,212.99 v2(43.01,213.93)
PWR_VCCGT_SNB2: length 3
  BOTTOM w0.508: PR177.2 45.04,197.99 PC188.1 43.98,196.66 v2(43.94,196.62)
PWR_VCCGT_SWA: length 30.4
  TOP w0.254: 52.03,210.95 PG1.2
  L4 w0.762: v5(50.33,215.77) 46.26,215.77 43.98,213.49 40.29,213.49 v5(32.04,205.23)
  BOTTOM w0.203: PU24.16 29.29,203.15 30,203.85
  BOTTOM w0.381: v5(32.04,205.23) 32.04,205.09 v2(31.21,204.26) 30.8,203.85 30,203.85
  BOTTOM w0.508: PC169.2 31.66,205.61 v5(32.04,205.23)
  vias: v2(51.72,207.26) v2(52.23,214.76) v5(50.33,208.53) v5(50.33,206.25) v5(50.45,214.76) v5(50.45,213.61) v5(51.98,213.61) v5(52.1,215.77) v5(52.1,208.53) v5(52.1,206.25) v5(53.5,215.77) v5(53.5,213.61) v5(53.88,208.53) v5(53.88,206.25)
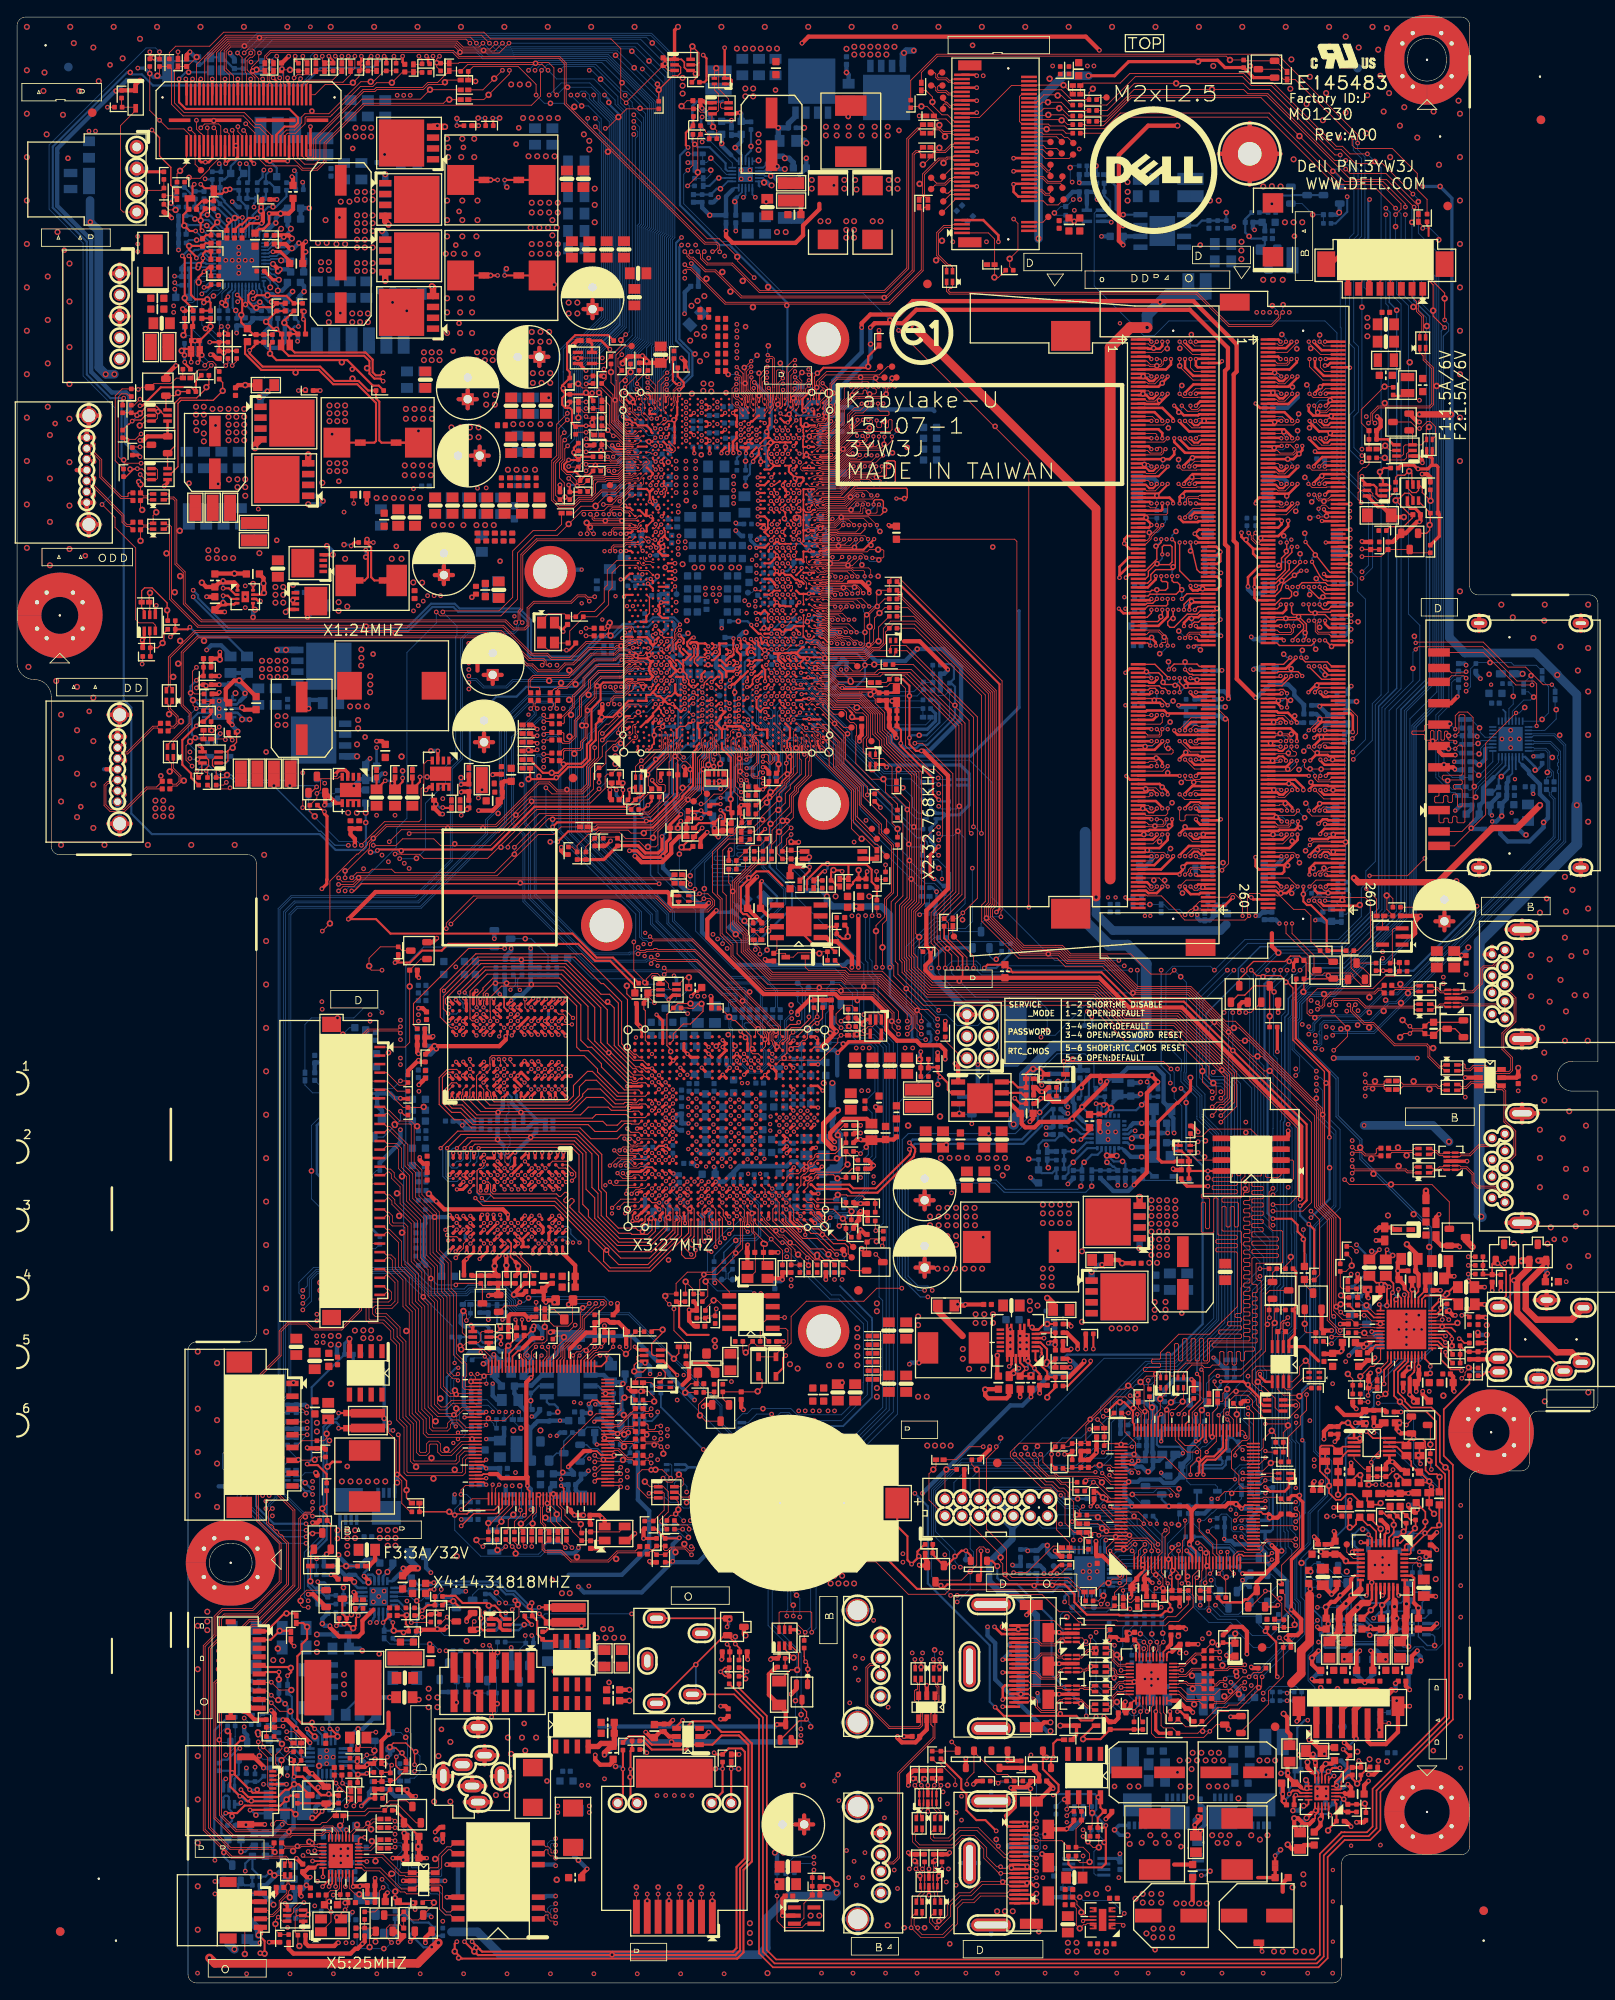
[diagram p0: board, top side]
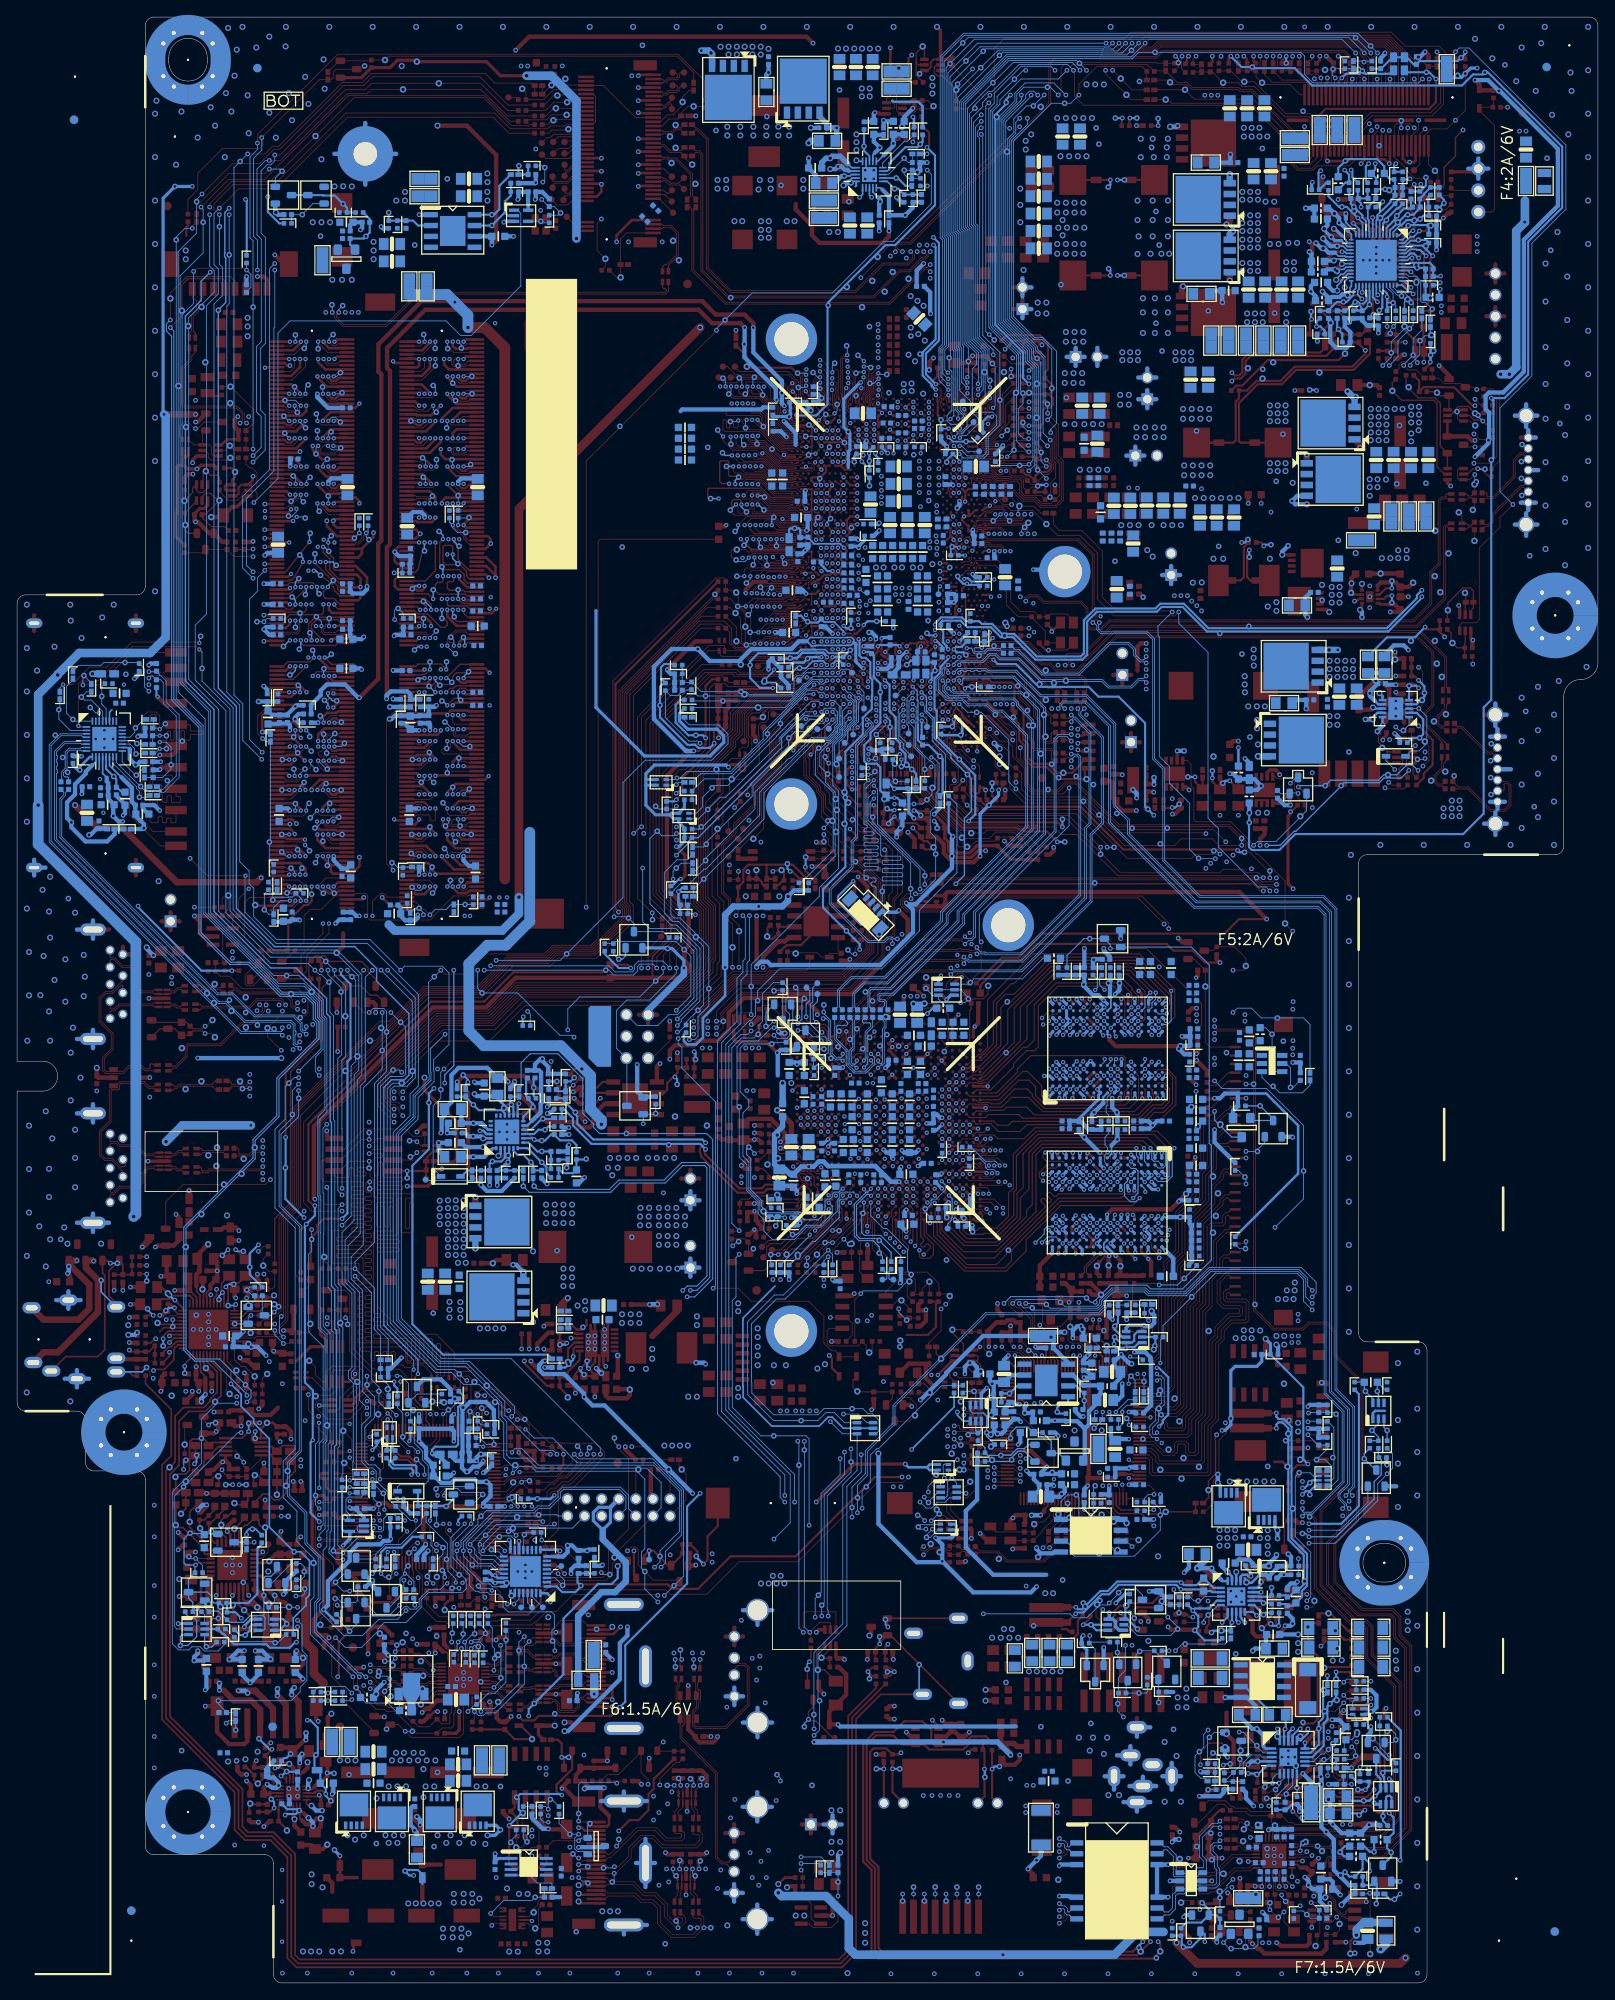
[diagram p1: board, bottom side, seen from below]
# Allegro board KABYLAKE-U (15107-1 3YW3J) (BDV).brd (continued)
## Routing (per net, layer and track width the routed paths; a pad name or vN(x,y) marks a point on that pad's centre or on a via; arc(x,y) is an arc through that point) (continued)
PWR_VCCGT_SWB: length 28.5
  TOP w0.254: PL3.1 PG5.2
  L4 w0.762: v5(50.17,202.31) 49.3,201.43 49.25,201.43 45.58,197.76 42.51,197.76 41.77,198.5 35.09,198.5 32.06,201.52 v5(30.89,201.52)
  BOTTOM w0.203: PU24.20 29.56,201.55 29.71,201.7 30.72,201.7 v5(30.89,201.52)
  BOTTOM w0.508: PC179.2 31.91,201.52 v5(30.89,201.52)
  vias: v2(51.34,203.33) v2(51.72,194.18) v5(50.33,204.34) v5(50.33,197.1) v5(50.33,195.45) v5(50.33,193.04) v5(51.09,202.31) v5(51.85,197.1) v5(51.85,195.45) v5(51.85,193.04) v5(52.1,204.34) v5(52.36,202.31) v5(53.25,197.1) v5(53.25,195.45) v5(53.25,193.04) v5(53.75,204.34) v5(53.88,202.29)
PWR_VCCGT_SWNA: length 44.9
  TOP w0.254: v3(56.23,210.95) PG1.1
  L4 w0.254: v3(56.23,210.95) 56.45,211.17 56.45,218.66 55.28,219.84 38.39,219.84 34.45,215.9 31.66,215.9 29.43,213.68 29.43,212.3 v3(29.64,212.09)
  BOTTOM w0.254: v3(29.64,212.09) 29.12,211.57 PR153.2 29.56,210.63 PR151.2 ; v3(56.23,210.95) v2(55.42,210.95)
PWR_VCCGT_SWNB: length 65.6
  TOP w0.254: v3(56.23,199.77) PG5.1
  L4 w0.254: v3(26.07,212.85) 26.26,213.04 26.26,213.71 26.8,214.25 27.47,214.25 31.45,218.23 32.72,218.23 36.48,222 47.44,222 48.07,221.36 55.79,221.36 58.31,218.84 58.31,198.93 57.75,198.37 57.06,198.37 56.45,198.98 56.45,199.55 v3(56.23,199.77)
  BOTTOM w0.254: v2(55.42,199.77) v3(56.23,199.77) ; v3(26.07,212.85) 26.07,212.17 PR145.2 25.94,211.12 PR156.2
PWR_VCCGT_TSENSE: length 10.8
  TOP w0.254: v3(28.1,206.5) 27.09,206.5 26.33,205.74 26.07,205.74 25.43,205.1 PC9.1
  BOTTOM w0.203: PU24.11 27.54,205.94 v3(28.1,206.5)
  BOTTOM w0.254: PR152.1 31.53,209.02 30.3,207.8 v2(29.95,207.8) 29.4,207.8 v3(28.1,206.5)
PWR_VCCGT_TSENSE_NTC: length 27.9
  TOP w0.254: v3(51.47,217.3) PR1.2
  L4 w0.254: v3(32.45,212.04) 33.3,212.04 39.58,218.31 51.09,218.31 51.47,217.93 v3(51.47,217.3)
  BOTTOM w0.254: v2(51.47,218.14) v3(51.47,217.3) ; v3(32.45,212.04) 32.7,211.79 32.7,209.89 PR157.2 31.78,210.63 PR152.2
PWR_VCCGT_UGA: length 29.8
  TOP w0.762: PU1.4 v5(50.07,217.17)
  L4 w0.762: v5(30.89,205.23) 30.89,206.06 39.71,214.88 43.34,214.88 45.63,217.17 v5(50.07,217.17)
  BOTTOM w0.203: 29.94,204.41 29.5,203.96 29.5,203.84 29.21,203.55 PU24.15
  BOTTOM w0.381: 29.94,204.41 30.77,205.23 v5(30.89,205.23)
  BOTTOM w0.508: v5(50.07,217.17) 49.31,217.17 v2(49.18,217.3)
PWR_VCCGT_UGB: length 24.8
  TOP w0.508: v4(30.54,200.28) 30.54,200.53 v5(29.95,201.12)
  TOP w0.762: PU4.4 48.68,198.37 v5(48.55,198.5)
  L4 w0.762: v5(29.95,201.12) 30.54,200.53 31.08,200.53 34.51,197.1 41.19,197.1 41.93,196.37 46.41,196.37 v5(48.55,198.5)
  BOTTOM w0.203: v5(29.95,201.12) 29.92,201.15 PU24.21
PWR_VCCGT_VSN: length 5.7
  TOP w0.254: v3(21.65,205) 21.48,205.17 v4(21.48,206.2) 21.48,206.95 22,207.47 PC4.2 PR7.2
  BOTTOM w0.203: v3(21.65,205) 21.8,205 22.86,203.95 PU24.52
PWR_VCCGT_VSN_G: length 5.1
  TOP w0.254: v4(24.42,209.75) 23.99,209.32 23.07,209.32 PG3.1 PR7.1 PC4.1 21.62,208.47 21,207.85 PC6.1
PWR_VCCGT_VSP: length 7.9
  TOP w0.254: PG4.1 19.92,207.71 PC6.2 19.44,206.84 19.44,205.74 v4(19.57,205.61) 20.2,204.97 v3(20.89,204.97)
  BOTTOM w0.203: PU24.51 22.68,203.55 21.91,204.32 21.55,204.32 v3(20.89,204.97)
PWR_VCCSA_BST: length 5.3
  TOP w0.305: 25.79,163.47 PU8.1
  TOP w0.508: v4(21.62,163.83) 22.13,163.32 PR38.1 23.68,163.86 25.41,163.86 25.79,163.47
PWR_VCCSA_BST_RC: length 3.7
  TOP w0.508: PR38.2 23.2,164.9 v4(25.43,164.9) 26.78,164.9 PC70.1
PWR_VCCSA_COMP: length 7
  TOP w0.254: PC13.2 22.06,203.55 PC12.2 21.69,203.17 21.64,203.23 v4(20.12,203.23) 20.12,202.79 20.99,201.92 v3(20.99,201.8)
  BOTTOM w0.203: PU24.47 22.37,201.95 22.13,202.18
  BOTTOM w0.254: 22.13,202.18 21.98,202.34 21.52,202.34 v3(20.99,201.8)
PWR_VCCSA_COMP_1: length 3
  TOP w0.254: v4(23.43,205.99) 22.7,205.27 PR8.2 22.11,204.49 PC12.1
PWR_VCCSA_CSP: length 6.3
  BOTTOM w0.203: 21.37,200.66 21.46,200.75 PU24.44
  BOTTOM w0.254: 21.37,200.66 v2(21.17,200.66) 20.29,200.66 PC180.2 PC181.1 PR174.2 20.16,197.27 PR178.1
PWR_VCCSA_CSP_R: length 51.9
  TOP w0.254: PR37.1 39.4,168.53 39.1,168.22 v3(39.1,168.12)
  L4 w0.254: v3(18.45,198.93) 17.06,197.54 17.06,193.41 16.34,192.69 16.34,179.99 17.2,179.12 17.2,176.67 25.52,168.35 38.87,168.35 v3(39.1,168.12)
  BOTTOM w0.254: v3(39.1,168.12) 38.95,168.28 v2(38.26,168.28) ; v3(18.45,198.93) 18.75,198.63 PR174.1
PWR_VCCSA_DRVH: length 14.5
  TOP w0.305: v5(27.61,163.69) PU8.8
  TOP w0.406: v5(36.95,167.09) PU7.4
  L4 w0.762: v5(27.61,163.69) 27.59,163.71 27.59,164.48 29.6,166.5 36.36,166.5 v5(36.95,167.09)
  BOTTOM w0.508: v2(36.25,168.15) 36.95,167.45 v5(36.95,167.09)
PWR_VCCSA_DRVL: length 6.8
  TOP w0.305: PU8.5 27.61,160.89 v5(27.85,160.66)
  TOP w0.406: v5(31.44,160.4) 31.74,160.7 PU9.4
  L4 w0.762: v5(31.44,160.4) 28.1,160.4 v5(27.85,160.66)
  BOTTOM w0.508: v5(27.85,160.66) 27.62,160.43 v2(27.62,159.78)
PWR_VCCSA_ILIM: length 4.9
  TOP w0.254: PC18.1 22.68,202.58 PR11.2 22.04,202.61 21.75,202.31 v3(21.75,201.8) 21.75,201.47 v4(21.27,200.99)
  BOTTOM w0.203: PU24.46 22.28,201.55 22.03,201.8 v3(21.75,201.8)
PWR_VCCSA_IOUT: length 4.7
  TOP w0.254: v4(21.24,199.03) 21.24,199.57 v3(21.87,200.2) 22.41,200.74 PC20.2 PR13.1
  BOTTOM w0.203: PU24.43 22.23,200.35 22.08,200.2 v3(21.87,200.2)
PWR_VCCSA_PH: length 15.7
  TOP w0.305: v4(28.89,162.64) 28.68,162.43 PU8.7 ; PG13.2 PL5.1
  TOP w0.508: v4(28.89,162.64) 28.89,163.7 v5(28.84,163.75) 28.84,164.36 PC70.2
  L4 w0.762: v5(28.84,163.75) 30.18,165.1 36.93,165.1 38.39,166.55 v5(38.39,166.62)
  vias: v5(37.63,161.54) v5(37.63,160.53) v5(38.64,161.04)
PWR_VCCSA_PWM: length 47.5
  TOP w0.254: PR14.2 22.37,198.37 v3(21.88,198.37) ; v3(24.11,163.17) 24.8,163.17 25.54,162.43 PU8.2
  L3 w0.254: v3(21.88,198.37) 21.93,198.37 22.16,198.14 22.16,194.41 23.88,192.68 23.88,188.44 23.12,187.68 21.35,187.68 18.58,184.91 18.58,167.64 21.94,164.27 23.01,164.27 v3(24.11,163.17)
  BOTTOM w0.203: v3(21.88,198.37) 21.93,198.37 22.7,199.15 PU24.40
  BOTTOM w0.254: v3(24.11,163.17) v2(24.11,164.03)
PWR_VCCSA_SNB: length 3.3
  BOTTOM w0.508: PC296.1 34.25,162.06 PR270.1 34.25,160.05 v2(33.99,159.79)
PWR_VCCSA_SWN: length 55.8
  TOP w0.254: PG13.1 40.67,164.08 41.05,164.47 41.05,167.39 v3(40.8,167.64)
  L4 w0.254: v3(40.8,167.64) 39.58,168.86 25.73,168.86 17.71,176.88 17.71,179.34 16.85,180.2 16.85,192.48 18.98,194.61 18.98,197.71 18.55,198.15 18.47,198.15 v3(18.45,198.17)
  BOTTOM w0.254: PR178.2 18.58,198.04 v3(18.45,198.17) ; v3(40.8,167.64) v2(40.8,166.83)
PWR_VCCSA_VSN: length 12.7
  TOP w0.254: v3(20.1,202.06) 20.35,201.8 20.35,197.49 20.86,196.98 v4(22.26,196.98) 22.64,196.6 PR20.2 PC24.2
  BOTTOM w0.203: PU24.48 22.47,202.35 22,202.82 21.24,202.82 21.18,202.76
  BOTTOM w0.254: 21.18,202.76 20.8,202.76 v3(20.1,202.06)
PWR_VCCSA_VSN_G: length 5.2
  TOP w0.254: PC24.1 PR20.1 v4(22.64,193.8) 22.64,193.41 21.38,192.15 PC33.1 21.37,192.09 PG10.1
PWR_VCCSA_VSP_: length 12.4
  TOP w0.254: v3(19.34,202.06) 19.62,201.78 v4(19.62,197.13) 19.62,196.82 20.61,195.83 PR19.1 PR18.2
  BOTTOM w0.203: 20.56,203.28 22.01,203.28 22.54,202.75 PU24.49
  BOTTOM w0.254: 20.56,203.28 v3(19.34,202.06)
PWR_VCCSA_VSP_G: length 4.9
  TOP w0.254: v4(19.26,190.96) 19.49,191.19 PG9.1 20.35,192.09 PC33.2 20.42,193.68 PC26.1 20.61,193.87 PR19.2
PWR_VCCSA_VSP_RC: length 2.1
  TOP w0.254: v4(19.46,192.79) 19.65,192.98 PC26.2 19.65,194.69 PR18.1
PWR_VCORE_ALERT#: length 3.9
  BOTTOM w0.102: PU24.37 24.34,198.36 23.44,197.46 23.07,197.46 v2(22.98,197.37) 22.64,197.03 PR184.2
PWR_VCORE_BST: length 5.6
  BOTTOM w0.203: PU24.26 28.85,198.5 28.99,198.36 28.99,197.99 29.24,197.74
  BOTTOM w0.508: 29.24,197.74 29.4,197.59 29.88,197.59 30.21,197.26 31.12,197.26 PR179.1 31.53,197.18 v2(32.24,197.89)
PWR_VCORE_BST_R: length 2.5
  BOTTOM w0.508: PC182.2 33.59,198.53 v2(33.59,197.89) 33.05,197.36 PR179.2
PWR_VCORE_COMP: length 5.9
  BOTTOM w0.203: v2(28.4,196.65) 28.02,196.65 27.85,196.48 27.45,196.48 27.18,196.74 27.08,196.84 27.08,198 27.14,198.06 PU24.30
  BOTTOM w0.254: v2(28.4,196.65) 28.46,196.65 29.46,195.64 PC191.1 PC190.1
PWR_VCORE_COMP_RC: length 3
  BOTTOM w0.254: PR197.1 29.92,192.98 30.36,193.42 v2(30.36,193.47) 30.51,193.62 PC190.2
PWR_VCORE_CSN: length 36
  TOP w0.254: v4(39.25,187.71) 39.25,187.43 ; 39.25,187.43 37.15,187.43 35.47,189.1 28.74,189.1 27.21,190.63 v3(27.21,191.01) 27.64,191.44 27.67,191.44 27.97,191.74 PC31.2 PC32.2 ; 39.25,187.43 39.97,187.43 41.09,186.31 PR29.1 42.01,185.39 42.39,185.01 42.39,180.47 42.64,180.21 PG12.1
  L4 w0.254: v3(27.21,191.01) 26.51,191.01 26.32,191.2 26.32,196.19 v3(25.81,196.7)
  BOTTOM w0.203: PU24.32 26.34,198.25
  BOTTOM w0.254: 26.34,198.25 26.34,197.22 v3(25.81,196.7)
PWR_VCORE_CSP: length 9
  TOP w0.254: PR24.1 PC32.1 PC31.1 27.66,192.85 PR21.1 26.23,194.27 v4(26.23,195.15) 26.35,195.27 26.35,196.92 25.78,197.49 v3(25.76,197.49)
  BOTTOM w0.203: v3(25.76,197.49) 25.94,197.66 PU24.33
PWR_VCORE_CSP_NTC: length 16.8
  TOP w0.254: PR29.2 42.32,186.88 41.63,186.88 38.64,189.87 38.01,189.87 ; 38.01,189.87 30.36,189.87 v4(29.6,190.63) 29.6,191.68 PR24.2 ; 38.01,189.87 v4(38.01,189.61)
PWR_VCORE_DRON: length 47.4
  TOP w0.254: PU8.3 25.05,161.93 24.67,162.31 v3(24.11,162.31)
  L3 w0.254: v3(21.62,197.61) 21.62,194.23 23.38,192.47 23.38,188.65 22.91,188.19 21.09,188.19 18.07,185.17 18.07,167.39 21.69,163.77 22.65,163.77 v3(24.11,162.31)
  BOTTOM w0.203: PU24.39 22.9,198.64 22.9,198.63 22.14,197.87 21.88,197.87 v3(21.62,197.61)
  BOTTOM w0.254: v2(24.11,161.49) v3(24.11,162.31)
PWR_VCORE_EN: length 5.6
  BOTTOM w0.102: PU24.41 22.41,199.55 21.92,199.06 21.42,199.06 v2(21.24,198.88) 21.09,198.73 21.09,196.13 PR186.1
PWR_VCORE_ILIM: length 4.5
  BOTTOM w0.203: 26.73,197.99 26.74,198.01 PU24.31
  BOTTOM w0.254: PR181.1 PC192.1 27.45,195.64 v2(26.73,196.37) 26.73,197.99
PWR_VCORE_IOUT: length 5.3
  BOTTOM w0.203: PU24.34 25.54,198.02 25.23,197.71 25.23,197.07
  BOTTOM w0.254: PC194.2 26.65,194.75 PR187.1 25.69,195.55 25.59,195.66 v2(25.59,195.68) 25.56,195.68 25.23,196.01 25.23,197.07
PWR_VCORE_LG: length 30.1
  TOP w0.381: PR12.1 29.94,199.26 v5(30.64,199.26)
  TOP w0.762: v5(27.85,179.58) 27.85,179.96 PU5.4
  L4 w0.762: v5(30.64,199.26) 30.51,199.39 28.99,199.39 28.4,198.81 28.4,185.6 v5(28.35,185.55) 27.85,185.04 v5(27.85,179.58)
  BOTTOM w0.203: PU24.23 29.35,200.35 29.8,199.9 30.08,199.9 30.64,199.34 v5(30.64,199.26)
  BOTTOM w0.762: PU25.4 28.48,185.42 v5(28.35,185.55) 28.63,185.55 v2(29.29,186.21)
PWR_VCORE_SCLK: length 4.3
  BOTTOM w0.102: PU24.38 23.94,198.38 23.6,198.04 22.94,198.04 21.85,196.96 v2(21.85,196.6) 21.62,196.37 PR185.2
PWR_VCORE_SDIO: length 3.5
  BOTTOM w0.102: PU24.36 24.74,198.37 24.43,198.07 24.37,198.07 23.97,197.66 v2(23.97,196.57) 23.66,196.26 PR183.2
PWR_VCORE_SNB: length 2.7
  TOP w0.508: PC41.1 25.88,186.94 v4(26.7,186.94) PR27.2
PWR_VCORE_SW: length 31.7
  TOP w0.254: PG11.2 PL4.1
  L4 w0.762: v5(30.51,197.99) 31.66,196.85 31.66,183.39 35.59,179.45 35.59,175.64 v5(35.72,175.51)
  BOTTOM w0.203: PU24.24 29.27,199.95 30.06,199.16 30.06,199.02 30.51,198.56 v5(30.51,197.99)
  BOTTOM w0.508: PC182.1 31.63,198.6 31.02,197.99 v5(30.51,197.99)
  vias: v2(36.86,181.2) v2(37.65,175.69) v5(36.56,184.56) v5(36.56,183.64) v5(36.56,182.73) v5(36.56,177.8) v5(36.56,176.89) v5(37.47,184.56) v5(37.47,183.64) v5(37.47,182.73) v5(37.47,177.8) v5(37.47,176.89) v5(38.39,184.56) v5(38.39,183.64) v5(38.39,182.73) v5(38.39,177.8) v5(38.39,176.89)
PWR_VCORE_SWN: length 25.6
  TOP w0.254: PG11.1 41.82,180.21 42.01,180.4 42.01,184.85 39.81,187.05 36.99,187.05 35.31,188.72 32.6,188.72 ; v4(32.6,188.42) 32.6,188.72 ; 32.6,188.72 28.58,188.72 26.68,190.62 26.68,191.74 PR21.2
PWR_VCORE_TSENSE: length 6
  BOTTOM w0.203: 28.74,197.35 28.61,197.48 28.61,197.99 28.34,198.26 PU24.27
  BOTTOM w0.254: PR180.1 PC189.1 31.53,195.71 30.56,196.67 v2(29.78,196.67) 29.41,196.67 28.74,197.35
PWR_VCORE_TSENSE_NTC: length 12.2
  TOP w0.254: PR28.1 v3(32.93,186.31)
  L4 w0.254: v3(32.93,186.31) 33.36,186.74 33.36,193.37 v3(32.93,193.8)
  BOTTOM w0.254: v2(33.74,186.39) 33,186.39 v3(32.93,186.31) ; PR189.2 31.97,193.31 32.47,193.8 v3(32.93,193.8) 32.93,194.37 PR180.2
PWR_VCORE_UG: length 33.8
  TOP w0.762: PU6.4 v5(34.07,178.81)
  L4 w0.762: v5(29.62,198.37) 29.62,196.85 30.26,196.22 30.26,182.63 v5(34.07,178.81) 34.07,173 v5(34.07,173)
  BOTTOM w0.203: v5(29.62,198.37) 29.62,199.09 29.17,199.55 PU24.25
  BOTTOM w0.508: v5(34.07,173) 35.42,173 v2(35.8,173.38) 35.19,173.99 PU26.4
PWR_VCORE_VCC: length 10.6
  TOP w0.305: v3(29.5,207.01) 29.5,205.82 28.88,205.21 28.33,205.21 PC11.1
  TOP w0.508: PR4.2 32.29,207.52 31.78,207.01 v4(30.84,207.01) v3(29.5,207.01)
  BOTTOM w0.203: PU24.13 28.34,204.84 29.5,205.99 29.5,206.38
  BOTTOM w0.508: 29.5,206.38 v3(29.5,207.01)
PWR_VCORE_VR_RDY: length 8
  BOTTOM w0.102: PR188.1 19.59,195.64 v2(19.39,195.85) 20.14,196.6 20.54,196.6 20.73,196.79 20.73,199.16 21.24,199.67 22.13,199.67 22.41,199.95 PU24.42
PWR_VCORE_VRHOT#: length 4.3
  TOP w0.254: v4(24.39,196.32) 24.39,197 v3(24.67,197.28)
  BOTTOM w0.203: 24.87,197.85 25.14,198.12 PU24.35
  BOTTOM w0.254: PR182.2 v3(24.67,197.28) 24.67,197.65 24.87,197.85
PWR_VCORE_VRMP: length 7.3
  TOP w0.305: v3(28.61,205.87) 27.21,205.87 26.39,205.04 PC10.1
  TOP w0.508: PR5.1 28.58,208.57 28.58,207.37 v4(28.53,207.31) 28.76,207.09 28.76,206.02 v3(28.61,205.87)
  BOTTOM w0.203: PU24.12 27.94,205.2 v3(28.61,205.87)
PWR_VCORE_VSN: length 7.1
  TOP w0.254: v3(27.59,197.79) 27.37,197.79 27.06,197.48 27.06,196.7 27.69,196.06 27.93,196.06 v4(27.99,196) 28.05,196.06 29.92,196.06 PR15.1 PC23.1
  BOTTOM w0.203: PU24.29 27.54,197.84 v3(27.59,197.79)
PWR_VCORE_VSN_G: length 6.2
  TOP w0.254: PC23.2 PR15.2 30.36,195.58 v4(29.14,194.36) 29.95,193.55 30.32,193.55 PC28.1 31.02,192.85 31.02,192.07 PG7.1
PWR_VCORE_VSP: length 8.2
  TOP w0.254: PR17.1 PR16.2 31.52,197.38 29.37,197.38 v4(29.31,197.45) 28.04,197.45 v3(27.62,197.03)
  BOTTOM w0.203: v3(27.62,197.03) 28.1,197.51 28.1,198 27.94,198.16 PU24.28
PWR_VCORE_VSP_G: length 6
  TOP w0.254: PG8.1 31.85,192.01 PC28.2 PC29.2 32.28,193.5 32.01,193.5 v4(31.28,194.23) 31.28,194.5 PR16.1
PWR_VCORE_VSP_RC: length 3.8
  TOP w0.254: PR17.2 33.41,194.74 v3(33.51,194.64) 33.69,194.46 33.69,192.98 PC29.1
  BOTTOM w0.254: v3(33.51,194.64) 33.59,194.72 v2(33.59,195.55)
PWR_VDDQ_BOOT: length 3.2
  BOTTOM w0.203: v2(88.19,211.4) 87.54,211.4 87.36,211.58 PU20.18
  BOTTOM w0.508: v2(88.19,211.4) 88.48,211.4 89.31,210.57 PR150.1
PWR_VDDQ_BOOT_A: length 3.3
  BOTTOM w0.508: PR150.2 91.55,211.53 PC151.1 v2(92.36,213.49)
PWR_VDDQ_CS: length 4
  BOTTOM w0.203: PU20.13 85.25,213.74 85.5,214
  BOTTOM w0.254: 85.5,214 85.89,214.38 v2(85.89,214.88) PR125.1
PWR_VDDQ_EN: length 5.5
  BOTTOM w0.102: PR141.2 PC148.1 80.68,212.98 v2(81.19,213.49) 82.39,212.28 82.39,212.2 83.01,211.58 PU20.8
PWR_VDDQ_EN_R: length 55.9
  L3 w0.127: v3(78.52,214) 79.15,213.36 79.15,209.41 81.3,207.26 87.77,207.26 88.5,207.99 122.94,207.99 v3(123.6,208.66)
  BOTTOM w0.102: v3(123.6,208.66) 122.78,207.84 C289.1 122.14,207.84 v2(121.39,207.09) 121.66,206.82 R539.2 ; PR141.1 v3(78.52,214)
PWR_VDDQ_FB: length 5.2
  BOTTOM w0.203: v2(82.31,209.91) 83.18,210.78 PU20.6
  BOTTOM w0.254: v2(82.31,209.91) 81.87,209.91 PR161.1 PR162.2 PC163.2
PWR_VDDQ_HG: length 9.4
  L3 w0.762: v5(92.36,215.26) 91.47,214.38 91.47,212.72 90.97,212.22 v5(89.85,212.22)
  BOTTOM w0.203: 87.66,211.98 PU20.17
  BOTTOM w0.508: 87.66,211.98 87.8,212.12 88.12,212.12 88.53,212.52 v2(88.93,212.52) 89.24,212.22 v5(89.85,212.22)
  BOTTOM w0.762: PR136.2 92.11,215.52 v5(92.36,215.26)
PWR_VDDQ_HG_R: length 4.9
  BOTTOM w0.635: PR136.1 89.09,215.67 v2(89.09,217.04) PR126.1 90.27,217.55 91.09,218.38 PU18.4
PWR_VDDQ_LG: length 28.7
  L3 w0.762: v5(86.77,213.23) 87.54,213.23 88.04,213.74 88.04,216.53 93.38,221.87 101.89,221.87 103.79,223.77 v5(103.79,225.81)
  BOTTOM w0.203: PU20.15 86.67,213.13 v5(86.77,213.23)
  BOTTOM w0.762: PU19.4 103.67,225.68 v5(103.79,225.81) 104.07,226.09 v2(104.94,226.09)
PWR_VDDQ_PG: length 469.3
  TOP w0.102: R91.1 13.71,184.59 14.38,185.27 v3(14.38,185.29) ; v1(142.53,58.93) 142.45,59 136.86,59 134.35,61.52 129.81,61.52 129.79,61.5 KBC1.101
  L3 w0.127: v3(80.17,215.39) 78.72,216.84 78.72,219.53 79.64,220.45 79.64,223.53 77.88,225.29 59.39,225.29 58.79,224.7 49.97,224.7 48.37,223.1 35.23,223.1 33.62,221.49 19.56,221.49 16.2,218.13 16.2,217.64 16.25,217.59 16.25,214.54 15.65,213.94 15.65,189.12 13.71,187.17 13.71,185.97 v3(14.38,185.29) 14.85,184.82 14.85,182.31 13.53,180.99 13.53,155.41 14,154.94 20.64,154.94 21.69,153.89 21.69,145.26 26.59,140.36 33.8,140.36 34.28,140.84 35.52,140.84 v3(36,140.36)
  L4 w0.127: v3(144.05,70.99) 144.62,71.56 144.62,84.39 151.16,90.93 154.28,90.93 159.16,95.81 159.16,116.68 158.66,117.19 158.66,122.56 167.51,131.41 167.51,147.41 170.14,150.04 170.14,154.25 170.05,154.34 170.05,154.37 169.77,154.65 168.6,154.65 161.7,161.54 161.7,205.23 162.94,206.46 162.94,208.06 161.32,209.68 159.42,209.68 157.77,211.33 154.97,211.33 138.32,227.98 83.71,227.98 83.7,227.97 83.22,227.97 80.93,225.68 80.93,216.15 v3(80.17,215.39)
  BOTTOM w0.102: v3(80.17,215.39) 80.04,215.52 PR132.2 80.84,215.42 81.21,215.42 83.7,212.93 PU20.10 ; v3(144.05,70.99) v2(144.05,69.98) 144.05,69.47 143.16,68.58 143.16,66.17 144.31,65.02 144.31,61.08 143.83,60.6 143.09,60.6 142.67,60.19 142.64,60.19 142.53,60.07 v1(142.53,58.93) ; D16.3 35.33,141.03 v3(36,140.36)
PWR_VDDQ_PG_N: length 6.2
  TOP w0.152: R90.2 R91.2 13.43,183.64 v4(14.38,183.64) 14.87,184.13 14.87,184.17 15.14,184.44 16.32,184.44 16.9,183.87 16.9,183.75 17.26,183.39 Q5.5
PWR_VDDQ_PH: length 11.1
  L3 w0.762: v5(92.11,217.04) 91.91,217.04 89.85,214.98 v5(89.85,213.49)
  BOTTOM w0.203: PU20.16 87.32,212.38 87.79,212.85
  BOTTOM w0.508: PR126.2 v5(92.11,217.04)
  BOTTOM w0.635: 87.79,212.85 88.65,213.72 89.62,213.72 v5(89.85,213.49) 90.33,213.49 90.84,212.98 PC151.2
  vias: v2(97.26,218.36) v2(103.21,216.74) v5(94.65,217.17) v5(94.65,216.15) v5(95.92,217.17) v5(95.92,216.15) v5(97.32,217.17) v5(97.32,216.15) v5(98.84,217.17) v5(98.84,216.15) v5(100.36,217.17) v5(100.36,216.15) v5(101.89,217.17) v5(101.89,216.15)
PWR_VDDQ_TON: length 7.3
  BOTTOM w0.203: PU20.9 83.15,211.98 83,212.13
  BOTTOM w0.254: PR133.2 79.03,215.39 v2(79.31,215.11) 79.64,214.78 81.03,214.78 82.91,212.9 82.91,212.22 83,212.13
PWR_VDDQ_VDD: length 4.9
  BOTTOM w0.203: PU20.12 84.85,213.89 84.62,214.12
  BOTTOM w0.508: 84.62,214.12 84.04,214.7 v2(84.04,214.73) 84.74,215.43 PC141.1 84.68,216.22 PR131.1
PWR_VDDQ_VDDQ: length 8.9
  BOTTOM w0.203: 83.73,209.8 83.95,210.03 PU20.5
  BOTTOM w0.508: 83.73,209.8 82.96,209.04 PR170.1 v2(81.06,206.82) 80.17,207.71 PR162.1 PC163.1
PWR_VDDQ_VID: length 5.3
  BOTTOM w0.203: PU20.11 84.29,213.13 83.58,213.84
  BOTTOM w0.508: 83.58,213.84 82.46,214.96 v2(82.46,215.21) PR127.1 PC142.1
PWR_VDDQ_VLDOIN: length 1.9
  BOTTOM w0.203: PU20.19 87.28,211.18 87.72,210.75
  BOTTOM w0.508: v5(88.3,210.31) 88.15,210.31 87.72,210.75
  vias: v4(87.42,210.65)
PWR_VDDQ_VTT: length 0.6
  BOTTOM w0.254: PU20.20 86.8,210.29 86.9,210.19
  vias: v2(87.66,208.41)
PWR_VDDQ_VTTREF: length 3.6
  BOTTOM w0.203: PU20.4 84.85,209.53 84.23,208.91
  BOTTOM w0.508: PC168.1 84.11,208.28 v2(83.98,208.41) 83.98,208.66 84.23,208.91
PWR_VGA_CORE_BOOT1: length 4.6
  BOTTOM w0.305: U30.1 129.32,97.66 129.57,97.41
  BOTTOM w0.508: 129.57,97.41 130.34,96.65 v2(131.61,96.65) PR225.1
PWR_VGA_CORE_BOOT1_1: length 3.1
  BOTTOM w0.508: PC263.1 v2(135.67,98.3) 135.67,97.33 PR225.2
PWR_VGA_CORE_COMP: length 5.9
  BOTTOM w0.254: U30.12 125.76,101.35 v2(124.62,102.49) 124.62,102.83 125.17,103.38 PR214.2 125.43,103.77 125.43,105.73 PC257.1
PWR_VGA_CORE_COMP_1: length 2.5
  BOTTOM w0.254: PR214.1 124.54,103.77 v2(124.54,104.75) 124.54,105.73 PC258.2
PWR_VGA_CORE_EN: length 7.7
  BOTTOM w0.254: PD2.A 133,94.36 132.3,95.06 PR229.2 PR230.2 PC265.1 129.7,95.86 129.45,96.11 v2(129.37,96.11) 128.33,96.11 127.92,96.52 U30.3
PWR_VGA_CORE_FB: length 15.1
  BOTTOM w0.305: U30.11 125.27,100.32 124.75,100.84
  BOTTOM w0.508: PC258.1 124.39,107.47 123.76,108.1 v2(123.53,108.1) 123.53,107.87 122.84,107.19 PR206.2 PR207.1 ; PC258.1 PC257.2 ; PC258.1 123.92,106.77 123.68,106.53 123.68,103.96 123.54,103.82 123.54,103.05 123.73,102.86 123.73,101.85 124.75,100.84
PWR_VGA_CORE_FBRTN: length 4.2
  BOTTOM w0.254: U30.10 124.87,99.82 123.59,101.09 v2(123.48,101.09) 122.27,101.09 PR218.2
PWR_VGA_CORE_FS: length 4
  BOTTOM w0.254: PR219.1 122.84,100.2 v2(123.22,99.82) 123.99,99.82 124.49,99.32 U30.9
PWR_VGA_CORE_LGATE1: length 19.8
  TOP w0.762: PU12.4 131.36,91.93 v5(131.35,91.95)
  L3 w0.762: v5(130.46,98.81) 131.1,98.81 131.86,98.04 131.86,92.46 v5(131.35,91.95) v5(131.35,85.95)
  BOTTOM w0.305: U30.23 130.45,98.82 v5(130.46,98.81)
  BOTTOM w0.508: v5(130.46,98.81) 130.69,99.03 v2(131.63,99.03) 132.12,99.03 132.53,99.44 PR220.1
  BOTTOM w0.762: PU30.4 131.36,85.97 v5(131.35,85.95)
PWR_VGA_CORE_PGOOD: length 6.7
  BOTTOM w0.254: PR209.1 PR210.2 132.49,103.63 v2(131.61,102.74) 130.97,102.11 128.29,102.11 127.92,101.74 U30.16
PWR_VGA_CORE_PHASE1: length 19.7
  L3 w0.762: v5(124.62,85.6) 125.89,86.87 125.89,94.11 127.16,95.38 129.26,95.38 130.46,96.58 v5(130.46,97.79)
  BOTTOM w0.305: U30.24 129.93,98.32 v5(130.46,97.79)
  BOTTOM w0.508: v5(130.46,97.79) 132.49,97.79 PC263.2
  vias: v2(121.8,85.67) v5(120.05,91.06) v5(120.05,90.04) v5(120.05,88.9) v5(120.05,83.57) v5(120.05,82.55) v5(120.05,81.53) v5(121.06,91.06) v5(121.06,90.04) v5(121.06,88.9) v5(121.06,83.57) v5(121.06,82.55) v5(121.06,81.53) v5(122.08,91.06) v5(122.08,90.04) v5(122.08,88.9) v5(123.1,91.06) v5(123.1,90.04) v5(123.1,88.9)
PWR_VGA_CORE_PSI: length 6.4
  BOTTOM w0.254: U30.4 127.42,97.06 127.41,97.05 127.41,96.14 v2(127.54,96.01) 127.77,95.78 127.94,95.78 128.22,95.5 128.37,95.5 PC266.1 PR231.1 PR232.2 R682.1
PWR_VGA_CORE_PVCC: length 5.4
  BOTTOM w0.305: 130.31,100.25 129.87,99.82 U30.21
  BOTTOM w0.508: PR216.2 133,102.18 PC261.1 v2(131.61,100.58) 130.64,100.58 130.31,100.25
PWR_VGA_CORE_REFIN: length 5.7
  BOTTOM w0.254: U30.7 125.15,98.32 124.11,97.28 v2(123.6,97.28) PC264.1 PR226.1 PR228.2
PWR_VGA_CORE_SENCE+: length 36.6
  TOP w0.254: GPU1.F2 92.98,93.4 93.49,92.89 97.2,92.89 97.64,92.46 100.7,92.46 104.96,96.72 104.96,96.84 105.1,97.26 105.1,97.62 104.95,97.77 104.66,98.06 104.66,98.07 v3(104.43,98.3)
  BOTTOM w0.254: PR215.2 120.87,103.5 PR213.1 120.81,103 v2(119.67,101.85) 119.67,101.63 119.44,101.4 119.44,100.54 117.58,98.68 104.81,98.68 v3(104.43,98.3)
PWR_VGA_CORE_SENCE-: length 33.7
  TOP w0.254: v3(104.43,97.54) 104.46,97.54 104.59,97.41 104.59,97.35 104.48,97 104.45,96.93 104.45,96.93 100.49,92.96 97.85,92.96 97.41,93.4 GPU1.F1
  BOTTOM w0.254: v3(104.43,97.54) 105.06,98.17 108.62,98.17 v2(108.75,98.04) 108.87,98.17 117.79,98.17 119.95,100.33 119.95,101.16 121.02,102.23 PR217.1 PR218.1
PWR_VGA_CORE_SENSE+_1: length 3.5
  BOTTOM w0.254: PC260.2 121.7,104.33 PR213.2 PR207.2 120.24,105.47 v2(119.79,105.92)
PWR_VGA_CORE_SNB: length 3.1
  TOP w0.508: PR70.1 128.94,84.58 v4(129.32,84.2) PC99.1
PWR_VGA_CORE_TALERT#: length 3.4
  BOTTOM w0.254: U30.14 126.92,102.5 v2(127.16,102.74) 127.29,102.87 PR211.1 PR212.2
PWR_VGA_CORE_TSNS: length 54.4
  TOP w0.254: PR68.2 125.57,101.66 PC92.1 127.33,101.66 v4(128.02,102.36) 127.52,102.87 v3(126.27,102.87) ; PR75.1 v3(125.95,74.17)
  L3 w0.254: v3(125.95,74.17) 126.08,74.3 132.62,74.3 136.69,78.36 136.69,101.14 135.49,102.34 126.8,102.34 v3(126.27,102.87)
  BOTTOM w0.254: v3(126.27,102.87) 126.42,102.72 U30.13
PWR_VGA_CORE_UGATE1: length 25.7
  TOP w0.508: v4(127.54,96.8) 127.57,96.77 v5(128.68,96.77)
  TOP w0.762: v5(120.56,80.14) 121.24,79.45 PR72.1
  L3 w0.762: v5(128.68,96.77) 126.58,96.77 124.49,94.69 124.49,87.45 122.59,85.54 122.59,81.03 121.7,80.14 v5(120.56,80.14)
  BOTTOM w0.305: U30.2 128.42,97.04 v5(128.68,96.77)
PWR_VGA_CORE_UGATE1_R: length 8.9
  L3 w0.762: v5(124.62,77.34) 125.75,78.47 v5(125.75,83.19)
  BOTTOM w0.508: v5(125.75,83.19) 126.59,84.02 v2(126.96,84.02)
  BOTTOM w0.762: PU31.4 v5(125.75,83.19)
PWR_VGA_CORE_VCC: length 5.9
  BOTTOM w0.305: 128.3,103.12 128.3,103 127.42,102.11 U30.15
  BOTTOM w0.508: 128.3,103.12 128.79,103.61 PR208.2 128.96,103.76 PC259.1 131.22,103.76 v2(131.48,104.01)
PWR_VGA_CORE_VID: length 5
  BOTTOM w0.254: PC267.1 PR233.1 124.62,95.76 v2(124.87,96.01) 125.76,96.9 126.46,96.9 126.92,97.36 U30.5
PWR_VGA_CORE_VIDBUF: length 5.7
  BOTTOM w0.254: U30.6 125.26,97.66 v2(123.6,96.01) 123.05,95.45 123.05,94.75 PR234.1
PWR_VGA_CORE_VREF: length 9.8
  TOP w0.254: v3(124.49,98.68) 125.51,99.69 PR68.1
  BOTTOM w0.254: PR224.1 119.54,98.04 120.07,98.58 121.47,98.58 122.14,99.25 PC262.1 122.51,99.26 123.22,98.55 v2(123.6,98.55) 124.37,98.55 v3(124.49,98.68) 124.63,98.82 U30.8
PWR_VGA_CORE_VREF_1: length 5.9
  BOTTOM w0.254: v2(118.4,96.39) 118.46,96.33 PR224.2 PC268.1 119.92,94.74 121.13,94.74 PR228.1 PR234.2
PWR_VGA_CORE_VREF_2: length 2.1
  BOTTOM w0.254: PR226.2 121.57,96.33 PR223.1 120.56,95.5 v2(120.68,95.38)
PWR_VGA_VRAM_BOOT: length 3.8
  TOP w0.305: PU14.20 116.88,72.26 v3(117.23,71.91) 116.9,71.91 116.62,71.63
  TOP w0.508: 116.62,71.63 116.11,71.12 PR86.1
  BOTTOM w0.508: v2(116.62,71.32) 116.64,71.32 v3(117.23,71.91)
PWR_VGA_VRAM_BOOT_RC: length 6.1
  TOP w0.508: PC112.1 113.34,69.47 v4(113.29,69.42) 113.29,68.76 113.65,68.4 115.8,68.4 116.11,68.71 PR86.2
PWR_VGA_VRAM_FB: length 6.2
  TOP w0.254: v3(120.68,74.85) 120.89,75.06 PR77.2 ; PR77.2 PR74.1 119.81,76.07 119.67,75.93 PU14.5 ; PR77.2 PC106.2
  BOTTOM w0.254: v3(120.68,74.85) 120.86,74.67 v2(121.48,74.67)
PWR_VGA_VRAM_LX: length 7
  TOP w0.508: PC112.2 114.71,71.12 114.71,73.15
  TOP w0.762: 110.65,75.69 107.75,78.59 PR71.2
  vias: v2(114.71,73.41) v3(116.24,76.45) v3(116.24,75.69) v3(116.24,74.93) v3(116.24,74.17) v5(110.68,74.17) v5(110.68,73.03) v5(111.41,71.84) v5(113.06,71.84)
PWR_VGA_VRAM_PFM: length 5.3
  TOP w0.254: PR82.1 PR80.1 121.13,72.64 v4(120.53,72.64) 120.53,74.17 119.76,74.93 PU14.3
PWR_VGA_VRAM_POK: length 7.4
  TOP w0.254: v4(120.56,68.5) 120.58,68.53 120.58,68.73 121.51,69.66 R350.2 PR84.2 120.62,70.87 PC111.1 120.56,71.5 119.18,72.88 PU14.1
PWR_VGA_VRAM_SNB: length 4.4
  TOP w0.508: PC101.1 v3(110.98,79.38) 110.85,79.25 PR71.1
  BOTTOM w0.508: v2(110.07,79.4) 110.95,79.4 v3(110.98,79.38)
PWR_VGA_VRAM_SS: length 3.8
  TOP w0.254: PU14.23 118.38,72.54 119.01,71.91 v3(119.06,71.91) 119.06,71.86 119.67,71.25 PC110.1
  BOTTOM w0.254: v3(119.06,71.91) 119.06,71.58 v2(118.65,71.17)
PWR_VGA_VRAM_TON: length 2.6
  TOP w0.254: PU14.6 119.52,76.43 120.18,77.09 v4(120.56,77.09) PR73.2
PWR_VGA_VRAM_VCC: length 5
  TOP w0.254: PU14.21 117.38,72.57 118.07,71.88 v3(118.12,71.88) 117.38,71.15 PC113.1 PR87.2
  BOTTOM w0.254: v2(118.3,72.75) 118.3,72.06 v3(118.12,71.88)
PWR_VTT_EN: length 3.8
  BOTTOM w0.203: v2(82.13,211.18) 82.88,211.18 82.89,211.18 PU20.7
  BOTTOM w0.254: PR149.2 81.02,210.25 81.95,211.18 v2(82.13,211.18)
PWR_VTT_EN_R: length 3.5
  BOTTOM w0.102: C286.1 v2(81.19,212.09) 81.19,211.61 80.72,211.14 PR149.1 R536.2
PWRBTN_N: length 138.9
  TOP w0.102: v3(116.62,48.01) 118.17,48.01 121.27,51.11 122.09,51.11 R429.1
  L4 w0.127: v3(116.62,48.01) 116.3,47.69 99.07,47.69 97.95,48.81 81.54,48.81 80.07,47.33 71.25,47.33 71.02,47.1 68.49,47.1 59.4,38.01 44.03,38.01 36.1,45.94 33.87,45.94 33.6,45.66 33.6,44.21 29.39,39.99 28.37,39.99 23.03,34.65 23.03,22.86 26.15,19.75 27.46,19.75 28.84,21.13 v3(28.84,23.24)
  BOTTOM w0.102: v3(28.84,23.24) C591.1 29.76,23.32 R837.2 ; v3(116.62,48.01) 116.39,47.78 v2(115.63,47.78)
PWRCN_DET_N: length 163.6
  TOP w0.089: CPU1.H3 76.12,146.05 76.12,145.56 76.08,145.48 76.08,145.19 76.12,145.11 76.12,144.91 76.08,144.81 76.08,143.73 75.73,143.38
  TOP w0.102: PWRCN1.5 29.6,22.75 29.33,23.02 29.33,26.35 28.23,27.45 v3(28.23,28.19) ; v3(44.23,132.07) 44.99,132.07 45.01,132.05 47.08,132.05 47.56,131.57 55.07,131.57 60.78,137.29 R172.1 72.31,137.74 72.48,137.74 74.26,139.53 C58.1 73.87,140.09 73.87,141.53 75.73,143.38
  L3 w0.127: v3(44.23,132.07) 43.49,132.07 42.3,130.89 36.65,130.89 31.26,125.5 31.26,43.08 27.55,39.37 27.55,29.71 28.23,29.04 v3(28.23,28.19)
  BOTTOM w0.102: v2(44.95,132.46) 44.89,132.46 44.89,132.46 44.62,132.46 v3(44.23,132.07)
PWRGD_3V: length 53.9
  TOP w0.102: Q23.G 144.4,113.54 v3(143.8,113.54) ; R291.2 v3(145.45,83.57)
  BOTTOM w0.102: v3(143.8,113.54) 143.34,114 142.08,114 141.77,113.68 v2(141.77,111.25) 141.77,106.63 143.17,105.22 143.17,86.65 145.45,84.38 v3(145.45,83.57) 143.17,81.29 143.17,76.43 142.46,75.72 R715.2 C535.1 R717.1 141.51,69.91 R724.2
PWRGD_3V_B: length 10.1
  TOP w0.152: Q22.B 142.88,115.57 143.67,115.57 144.75,116.65 Q23.D v4(146.59,113.11) 146.59,111.85 R248.2
PWRGD_3V_C: length 19.1
  TOP w0.152: Q18.G 154.12,117.41 Q17.G 153.99,117.47 R233.2 ; R233.2 150.59,116.01 v4(150.53,115.95) ; R233.2 150.85,117.73 150.85,119.38 C78.1 150.08,120.14 149,120.14 148.37,119.51 144.69,119.51 143.92,118.75 143.92,118.32 143.04,117.43 Q22.C
PWROK3_1: length 12.1
  TOP w0.102: KBC1.84 135.54,63.5 136.94,62.1 v1(138.08,62.1)
  BOTTOM w0.102: R724.1 R726.2 140.5,67.31 139.86,66.67 v2(139.86,63.88) 139.86,63.52 139.07,62.74 138.72,62.74 v1(138.08,62.1)
Q1212_G: length 5.3
  BOTTOM w0.254: R858.1 R860.2 26.61,11.43 Q79.G 25.88,11.59 R863.1 25.88,9.33 v2(25.94,9.27)
Q9637_AB_EC: length 3.9
  TOP w0.102: Q5.1 16.04,184.04 16.42,183.66 16.42,183.06 16.1,182.74 Q5.3 15,182.74 14.49,182.22 v4(14.36,182.22)
Q9639_AB_EC: length 5
  TOP w0.102: Q8.1 16.27,177.18 16.44,177.01 16.44,176.05 16.27,175.88 Q8.3 15.01,175.88 v3(14.41,176.48)
  BOTTOM w0.102: v2(14.23,175.64) 14.41,175.82 v3(14.41,176.48)
Q9664_D: length 3.4
  BOTTOM w0.152: Q63.D 26,60.01 v2(27.34,61.34) 27.34,61.91 R743.2
REXT: length 3.3
  TOP w0.102: v3(131.86,39.12) 131.75,39.01 U17.18
  BOTTOM w0.102: v3(131.86,39.12) 131.5,39.47 131.15,39.47 v2(131.02,39.34) 131.02,38.8 R809.1
RING2: length 32.1
  TOP w0.203: U11.31 167.85,76.65 168.31,76.2
  TOP w0.762: v3(178.02,84.52) Q27.2 178.94,84.11 176.55,81.71 176.55,78.88 177.83,77.6 181.91,77.6 UHS1.3
  L3 w0.762: v3(178.02,84.52) 176.44,82.93 176.44,77.81 174.44,75.82 v5(171.99,75.82)
  BOTTOM w0.508: v5(171.99,75.82) 171.23,75.82 v2(170.95,76.1)
ROM_CS*: length 24.1
  TOP w0.102: v1(85.1,91.31) 84.71,91.7 GPU1.D12 ; v3(86.27,80.64) 86.96,79.95 R335.1
  BOTTOM w0.102: v1(85.1,91.31) 85.1,89.76 83.6,88.27 83.22,88.27 80.81,85.85 80.81,83.31 v2(80.37,82.88) 80.37,82.54 81.95,80.97 85.94,80.97 v3(86.27,80.64)
ROM_CS_R*: length 11
  TOP w0.102: R334.2 84.93,73.95 85.12,73.76 v4(85.28,73.76) 85.33,73.76 85.63,74.07 85.63,74.61 R335.2 86.6,74.53 89.93,74.53 90.2,74.8 90.2,76.33 89.95,76.58 88.43,76.58
ROM_SCLK: length 19.2
  TOP w0.102: v1(85.5,87.88) 85.12,88.27 85.12,88.97 85.19,89.04 85.19,89.56 85.11,89.64 85.11,90.42 84.64,90.89 GPU1.C12 ; R318.1 R319.1 80.81,78.04 R322.2 81.69,78.74 v3(81.82,78.87)
  L3 w0.127: v3(81.82,78.87) 81.82,81.13 85.93,85.24 85.93,87.46 v1(85.5,87.88)
  BOTTOM w0.102: v3(81.82,78.87) 81.82,78.46 v2(80.91,77.55)
ROM_SCLK_R: length 3.7
  TOP w0.102: R319.2 80.55,78.89 v4(81.52,79.86) 81.95,79.86 82.68,79.12 83.35,79.12
ROM_SI: length 17
  TOP w0.102: GPU1.B12 84.64,89.82 84.98,89.48 84.98,89.12 84.91,89.05 84.91,85.9 81.9,82.88 80.5,82.88 79.89,82.27 79.89,80.91 R311.1 80.17,80.58 79.2,80.58 R310.1 79.07,80.72 79.07,81.22 v4(78.24,82.04) 78.24,80.68 R309.2
ROM_SI_R: length 6.7
  TOP w0.102: U10.5 83.35,80.86 81.85,82.36 80.86,82.36 v4(80.58,82.07) 80.58,81.86 80.83,81.61 80.83,80.35 R311.2
ROM_SO: length 35.5
  TOP w0.102: GPU1.A12 84.64,86.44 81.36,83.16 78.44,83.16 77.12,81.84 77.12,80.72 77.15,80.7 R308.2 76.09,80.61 v4(75.85,80.37) 75.85,79.88 v3(76.33,79.41) ; R336.1 87.27,75.77 87.27,77.2 87.92,77.85 v3(89.82,77.85)
  L4 w0.127: v3(89.82,77.85) 88.3,79.38 76.39,79.38 76.36,79.41 v3(76.33,79.41)
RREF: length 3.6
  BOTTOM w0.203: U28.9 176.46,143.46
  BOTTOM w0.305: 176.46,143.46 177.66,142.27 v2(177.66,141.9) 177.9,141.9 178.47,142.47 R612.1
RSMRST_N: length 553.5
  TOP w0.089: CPU1.AY17 93.12,154.43 93.43,154.73 95.23,154.73
  TOP w0.102: v3(111.92,135.26) 111.92,136.02 111.92,148.08 104.14,155.86 RN3.4 102.72,155.74 102.72,155.39 102.53,155.19 99.82,155.19 99.36,154.73 95.23,154.73 ; v3(112.85,134.49) 112.85,150.64 105,158.5 R130.1 ; v3(9.94,172.97) 11.46,171.45 11.46,170.31 13.88,167.89 13.88,159.51 14.26,159.13 15.91,159.13 16.18,158.86 Q12.3 ; R2.1 v3(16.67,225.93) ; KBC1.15 136.34,50.32 136.38,50.36 136.38,51.71 136.69,52.02 v1(136.69,54.1)
  L3 w0.127: v3(162.47,206.88) 161.96,206.38 151.61,206.38 150.69,207.3 144.74,207.3 136.78,215.26 125.89,215.26 119.8,209.18 87.38,209.18 86.65,208.45 84.04,208.45 82.81,209.68 82.7,209.79 81.99,210.49 81.99,213.16 81.58,213.57 81.58,225.47 79.98,227.08 58.71,227.08 58.11,226.48 50.93,226.48 50.58,226.83 20.46,226.83 19.09,225.46 17.14,225.46 v3(16.67,225.93)
  L4 w0.127: v1(136.69,54.1) 136.94,54.1 137.38,54.55 139.16,54.55 v1(139.61,54.1) ; v3(112.85,134.49) 113.18,134.49 122.28,125.38 122.28,124.89 129.58,117.59 134.36,117.59 134.91,118.13 134.91,118.65 137.98,121.72 146.16,121.72 148.88,119 149.64,119 v3(150.15,118.49)
  BOTTOM w0.102: v3(9.94,172.97) 11.46,174.5 11.46,184.28 7.73,188.01 7.73,203.54 3.75,207.53 3.75,215.04 15.1,226.39 16.21,226.39 v3(16.67,225.93) ; v3(112.85,134.49) 112.81,134.49 112.04,135.26 v3(111.92,135.26) ; v1(139.61,54.1) 139.86,54.36 R768.1 140.93,54.85 141.56,54.85 142.1,54.32 142.1,53.03 142.35,52.78 143.34,52.78 143.94,52.18 145.04,52.18 146.47,50.75 147.02,50.75 147.47,51.19 147.47,62.57 147.24,62.8 147.24,76.49 147.44,76.69 147.44,81.31 147.82,81.7 147.82,100.84 147.98,100.99 147.98,113.15 148.39,113.56 148.39,116.99 v2(148.5,117.09) 149.39,117.98 149.64,117.98 v3(150.15,118.49) 150.92,119.26 155.28,119.26 161.41,125.39 161.41,149.01 164.92,152.52 164.92,194.83 161.94,197.81 161.94,200.34 162.47,200.87 v3(162.47,206.88)
RSMRST_N_B: length 2.6
  TOP w0.152: v4(15.55,162.64) 15.46,162.55 R125.1 15.53,161.48 Q12.5
RSMRST_PWRGD#: length 249.2
  TOP w0.102: v1(144.05,66.55) 144.18,66.42 144.18,63.7 143.93,63.45 143.37,63.45 142.12,62.2 142.12,60.22 142.98,59.36 142.98,58.34 143.43,57.9 KBC1.51 ; v3(20.48,142.37) 20.47,142.37 19.77,143.07 19.77,144.75 v4(20.25,145.24) 20.56,145.54 PR48.2 PR46.2 ; PR30.1 13.18,185.61 12.86,185.93 12.23,185.93 11.84,185.55 11.84,178.56 12.61,177.8 v3(14.51,177.8)
  L4 w0.127: v3(14.51,177.8) 14.88,177.43 14.88,164.45 19.21,160.12 19.21,143.61 20.45,142.37 v3(20.48,142.37) 20.61,142.49 22.39,142.49 22.68,142.2 22.68,140.15 24.36,138.47 30.04,138.47 34.82,133.69 34.82,129.9 39.03,125.69 39.28,125.69 46.1,118.87 46.1,83.04 49.12,80.01 52.61,80.01 53.97,78.65 56.44,78.65 58.52,76.57 60.28,76.57 60.61,76.9 64.71,76.9 65.34,76.26 75.18,76.26 75.63,75.82 82.2,75.82 89.61,68.42 97.82,68.42 99.75,66.48 121.22,66.48 123.65,68.91 129.37,68.91 130.06,68.22 131.05,68.22 131.42,67.86 142.74,67.86 v1(144.05,66.55)
RSVD_TP_AK12: length 6.1
  TOP w0.102: v1(86.54,151.01) 86.7,151.01 CPU1.AK12
  BOTTOM w0.102: TP68.1 87.16,146.95 86.52,147.58 86.52,149.78 86.13,150.17 86.13,150.6 v1(86.54,151.01)
RSVD_TP_AK13: length 3.4
  TOP w0.102: v1(86.54,151.64) 86.86,151.97 CPU1.AK13
  BOTTOM w0.102: TP62.1 85.89,149.11 85.89,151 v1(86.54,151.64)
RSVD_TP_BA68: length 13.3
  TOP w0.102: TP31.1 101.86,189.1 100.9,188.14 94.67,188.14 93.87,187.34 93.87,187 94.27,186.6 94.39,186.6 94.63,186.36 94.63,185.64 93.99,185 93.99,184.34 CPU1.BA68
RSVD_TP_BA70: length 10.9
  TOP w0.102: TP30.1 100.44,188.54 94.75,188.54 93.53,187.33 93.53,184.84 CPU1.BA70
RSVD_TP_BB68: length 12.1
  TOP w0.102: TP33.1 102.27,187.2 100.8,187.2 100.36,187.64 95.99,187.64 95.33,186.98 95.33,185.21 94.82,184.71 94.82,184.64 94.62,184.44 94.62,184.08 94.31,183.77 CPU1.BB68
RSVD_TP_BB69: length 9.9
  TOP w0.102: CPU1.BB69 94.31,184.4 94.63,184.72 94.63,184.84 95.14,185.35 95.14,187.11 95.89,187.86 101.47,187.86 TP32.1
RSVD_TP_F65: length 5.8
  TOP w0.102: CPU1.F65 75,181.41 75.32,181.73 v1(75.32,181.81)
  BOTTOM w0.102: v1(75.32,181.81) 74.98,181.47 74.51,181.47 73.83,182.15 73.83,183.23 74.56,183.96 74.56,184.81 TP54.1
RSVD_TP_G65: length 3.6
  TOP w0.102: v1(75.35,180.85) 75.65,181.15 CPU1.G65
  BOTTOM w0.102: TP55.1 74.45,181.24 74.96,181.24 v1(75.35,180.85)
RT: length 2.7
  BOTTOM w0.102: R846.1 35.21,22.72 35.23,22.73 v2(35.23,22.86) U36.10
RTC_DET#: length 31.1
  TOP w0.102: Q40.D 107.67,47.12 110.52,47.12 112.3,48.9 112.3,50.68 112.62,51 113.11,51 v3(113.57,50.55) ; v1(126.4,55.75) 126.55,55.75 128.41,53.9 KBC1.120
  L3 w0.127: v3(113.57,50.55) 114.8,51.78 122.72,51.78 126.4,55.46 v1(126.4,55.75)
  BOTTOM w0.102: R762.1 126.08,56.83 126.4,57.15 127.16,57.15 127.41,56.9 v2(127.41,56.64) 126.53,55.75 v1(126.4,55.75)
RTD2506S_VREF: length 9.1
  TOP w0.203: SCA1.57 57.97,73.31 58.64,73.98 58.88,73.98 59.16,74.27
  TOP w0.508: 59.16,74.27 60.34,75.44 v1(61.45,75.44)
  BOTTOM w0.508: C530.1 60.23,76.58 v2(60.49,76.83) 60.91,76.83 61.45,76.3 v1(61.45,75.44)
RTD_PIN110: length 4.8
  TOP w0.102: R417.1 58.96,53.02 v4(58.96,53.72) 59.06,53.72 60.54,55.19 60.54,55.59 60.37,55.75 SCA1.110
RTD_PIN111: length 4.1
  TOP w0.102: R418.1 60.23,53.64 v4(60.33,53.75) 60.33,54.63 60.77,55.07 SCA1.111
RTD_PIN112: length 4.2
  TOP w0.102: SCA1.112 61.17,55.72 61.27,55.63 61.27,53.85 61.65,53.47 61.65,53.17 R419.1
RTD_PIN113: length 4.6
  TOP w0.102: v4(61.83,54.43) 61.48,54.43 ; 61.48,54.43 61.48,55.63 61.57,55.72 SCA1.113 ; 61.48,54.43 61.48,53.94 61.86,53.56 61.86,53.17 R420.1
RTD_PIN114: length 5.3
  TOP w0.102: SCA1.114 61.97,55.47 v3(62.16,55.28) 62.44,55 62.44,53.97 63.28,53.13 R421.1
  BOTTOM w0.102: v2(62.06,56.11) 62.06,55.38 v3(62.16,55.28)
RTD_PIN115: length 4.7
  TOP w0.102: R422.1 64.3,52.8 63.11,53.98 63.11,54.8 v4(63.15,54.84) 63.15,55.15 62.37,55.93 SCA1.115
RTD_REXT: length 4.2
  TOP w0.203: 64.8,55.37 64.37,55.8 SCA1.120
  TOP w0.508: R403.1 v3(65.23,54.74) 64.8,55.16 64.8,55.37
  BOTTOM w0.508: v2(66.28,54.71) 65.25,54.71 v3(65.23,54.74)
RTL_ISOLATE_N: length 15.7
  TOP w0.102: v3(34.07,15.37) 34.43,15 35.34,15 35.4,15.06 U23.20 ; R527.2 R526.1 30.23,6.18 v4(30.23,6.9) 30.23,7.37 v3(30.56,7.7) 31.04,7.22 Q45.6
  L3 w0.127: v3(30.56,7.7) 30.89,8.03 30.89,11.68 34.07,14.85 v3(34.07,15.37)
RTL_ISOLATE_N_1: length 8.5
  TOP w0.102: v3(33.56,9.4) 33.03,9.4 32.37,8.74 32.37,8.27 31.97,7.87 Q45.5
  BOTTOM w0.102: R868.1 34.49,8.42 v2(34.07,8) 33.64,7.57 C620.1 R865.2 33.5,9.4 v3(33.56,9.4)
RTL_ISOLATE_N_2: length 6.1
  TOP w0.102: 32.75,7.87 32.65,7.98 32.65,8.43 32.74,8.52 Q45.3 ; 32.75,7.87 32.55,7.67 32.55,5.91 R525.2 32.86,4.49 v4(33.04,4.32) ; 32.75,7.87 Q45.2
RTN1: length 5.3
  TOP w0.254: CONVT1.1 28.33,41.15 29.19,41.15 31.28,43.23 v4(31.53,43.23) 32.43,43.23 R446.1
RTN2: length 4.2
  TOP w0.254: R452.1 31.92,41.2 v4(30.73,41.2) 29.68,40.15 CONVT1.2
RTN3: length 6
  TOP w0.254: v3(31.66,35.94) 32.08,36.36 32.08,36.81 v4(32.04,36.86) 31.94,36.96 29.12,36.96 28.92,37.15 CONVT1.5
  BOTTOM w0.254: R814.1 v3(31.66,35.94)
RTN4: length 4.8
  TOP w0.254: CONVT1.6 28.89,36.15 29.12,36.37 v3(30.64,36.37) v4(30.64,35.51)
  BOTTOM w0.254: R815.1 v3(30.64,36.37)
RX_3V3: length 7.1
  TOP w0.203: SCA1.119 63.97,57.85 v1(63.66,58.17)
  BOTTOM w0.508: v1(63.66,58.17) 63.79,58.29 C556.2 64.49,57.16 C558.1 64.21,56.89 63.03,56.89 62.77,57.15 v2(62.77,57.2) 62.67,57.2 62.39,57.48 62.39,57.91 L28.2
S5_ENABLE: length 23.4
  TOP w0.102: v1(133.66,46.84) 133.66,47.09 132.74,48.01 KBC1.6
  BOTTOM w0.102: v1(133.66,46.84) 133.66,47.27 134.58,48.18 134.58,49.38 v2(134.75,49.56) 134.65,49.66 134.65,51.44 137.12,53.9 137.12,54.88 ; 137.12,54.88 R770.2 ; 137.12,54.88 137.7,54.29 137.7,53.72 140.14,51.28 141.92,51.28 143.04,50.17 R777.2 145.19,49.59 Q67.D
S_LVDS_BL_EN: length 5.6
  BOTTOM w0.102: R838.1 R832.1 R835.1 R840.1 44.8,22.73 R842.2 v2(45.63,22.61)
S_TXE0+: length 34.2
  TOP w0.089: 53.63,67.39 52.66,67.39 52.63,67.36 52.05,67.36 51.64,66.96 ; 51.64,66.96 51.29,66.61 49.36,66.61 48.45,67.52 48.45,79.46 47.71,80.2 47.71,83.29 46.46,84.53 46.46,88.97 44.2,91.23 44.2,91.63 43.63,92.2 43.21,92.2 42.91,92.5 LVDS1.18 ; 51.64,66.96 v4(51.39,67.21)
S_TXE0-: length 34.2
  TOP w0.089: v4(44.71,89.74) 44.96,89.99 ; 44.96,89.99 46.12,88.83 46.12,84.39 47.37,83.14 47.37,80.06 48.1,79.32 48.1,67.38 49.22,66.26 51.44,66.26 52.19,67.02 52.63,67.02 52.66,66.99 53.63,66.99 ; 44.96,89.99 43.86,91.09 43.86,91.48 43.49,91.85 43.34,91.85 42.99,91.5 LVDS1.19
S_TXE1+: length 36.3
  TOP w0.089: LVDS1.15 42.97,95.5 43.25,95.22 43.71,95.22 44.14,94.78 44.14,94.31 45.17,93.28 45.17,91.31 47.2,89.28 47.2,84.83 48.45,83.59 48.45,80.5 49.18,79.77 49.18,68.38 ; 49.18,68.38 v4(49.54,68.38) ; 49.18,68.38 49.18,67.83 49.63,67.39 50.07,67.39 50.85,68.16 52.63,68.16 52.66,68.19 53.63,68.19
S_TXE1-: length 36.4
  TOP w0.089: 53.63,67.79 52.66,67.79 52.63,67.82 50.99,67.82 50.21,67.04 49.48,67.04 48.84,67.69 48.84,79.62 48.1,80.36 48.1,83.45 46.86,84.69 46.86,89.14 44.83,91.17 44.83,92.38 ; v4(44.46,92.38) 44.83,92.38 ; 44.83,92.38 44.83,93.14 43.8,94.17 43.8,94.64 43.56,94.87 43.34,94.87 42.97,94.5 LVDS1.16
S_TXE2+: length 37.2
  TOP w0.089: v4(51.24,69.32) 51.24,68.96 ; 51.24,68.96 50.73,68.96 49.92,69.78 49.92,80.07 49.18,80.81 49.18,83.9 47.94,85.14 47.94,89.59 45.91,91.62 45.91,94.49 44.99,95.4 44.99,97.65 44.42,98.22 43.27,98.22 43,98.5 LVDS1.12 ; 51.24,68.96 52.63,68.96 52.66,68.99 53.63,68.99
S_TXE2-: length 37.3
  TOP w0.089: 45.3,94.61 45.56,94.35 45.56,91.48 47.59,89.45 47.59,85 48.84,83.75 48.84,80.67 49.58,79.93 49.58,69.63 50.59,68.62 52.63,68.62 52.66,68.59 53.63,68.59 ; 45.3,94.61 44.65,95.26 44.65,97.51 44.28,97.88 43.21,97.88 42.83,97.5 LVDS1.13 ; 45.3,94.61 v4(45.04,94.36)
S_TXE3+: length 39.7
  TOP w0.089: 53.63,69.79 52.89,69.79 52.87,69.76 52.54,69.76 52.45,69.85 52.45,70.87 52.62,71.03 52.62,72.41 51.4,73.62 51.4,80.67 50.79,81.28 50.79,84.37 49.41,85.75 49.41,90.2 47.38,92.23 47.38,95.1 46.47,96.01 46.47,100.23 ; 46.47,100.23 46.47,100.5 46.13,100.84 44.79,100.84 43.53,102.1 43.34,102.1 42.94,102.5 LVDS1.8 ; 46.47,100.23 v4(46.82,100.23)
S_TXE3-: length 39.6
  TOP w0.089: v4(44.18,100.46) 44.43,100.71 ; 44.43,100.71 43.39,101.75 43.23,101.75 42.97,101.5 LVDS1.9 ; 44.43,100.71 44.65,100.5 45.99,100.5 46.12,100.36 46.12,95.87 47.04,94.96 47.04,92.09 49.07,90.06 49.07,85.61 50.45,84.23 50.45,81.14 51.06,80.53 51.06,73.48 52.27,72.27 52.27,71.17 52.11,71.01 52.11,69.71 52.4,69.42 52.87,69.42 52.89,69.39 53.63,69.39
S_TXO0+: length 38
  TOP w0.089: LVDS1.29 42.88,81.5 43.23,81.15 43.48,81.15 43.83,80.81 43.83,80.01 43.48,79.67 41.31,79.67 41.18,79.54 41.18,77.69 41.31,77.56 42.92,77.56 44.08,76.41 44.08,75.44 44.76,74.75 44.76,66 45.63,65.13 45.63,59.82 45.75,59.69 51.21,59.69 ; 51.21,59.69 52.01,59.69 52.14,59.82 52.14,61.36 52.55,61.76 52.87,61.76 52.89,61.79 53.63,61.79 ; 51.21,59.69 v4(51.21,60.05)
S_TXO0-: length 38
  TOP w0.089: v4(48.72,59) 48.72,59.35 ; 48.72,59.35 52.16,59.35 52.48,59.67 52.48,61.21 52.69,61.42 52.87,61.42 52.89,61.39 53.63,61.39 ; 48.72,59.35 45.61,59.35 45.28,59.67 45.28,64.99 44.42,65.85 44.42,74.61 43.73,75.3 43.73,76.26 42.78,77.22 41.17,77.22 40.84,77.54 40.84,79.68 41.17,80.01 43.34,80.01 43.49,80.16 43.49,80.66 43.34,80.81 43.25,80.81 42.94,80.5 LVDS1.30
S_TXO1+: length 36.9
  TOP w0.089: 48.5,61.06 51.28,61.06 51.4,61.19 51.4,61.74 52.23,62.56 52.87,62.56 52.89,62.59 53.63,62.59 ; 48.5,61.06 46.49,61.06 46.36,61.19 46.36,65.44 45.5,66.3 45.5,75.06 44.81,75.75 44.81,76.71 43.23,78.3 42.07,78.3 41.94,78.42 41.94,78.8 42.07,78.93 43.88,78.93 44.57,79.61 44.57,82.09 43.48,83.17 43.21,83.17 42.88,83.5 LVDS1.27 ; 48.5,61.06 v4(48.5,61.42)
S_TXO1-: length 36.9
  TOP w0.089: 53.63,62.19 52.89,62.19 52.87,62.22 52.37,62.22 51.75,61.59 51.75,61.05 51.42,60.72 46.69,60.72 ; 46.69,60.72 46.35,60.72 46.02,61.05 46.02,65.3 45.16,66.16 45.16,74.92 44.5,75.58 44.47,75.6 44.47,76.57 43.09,77.95 41.93,77.95 41.6,78.28 41.6,78.95 41.93,79.27 43.74,79.27 44.22,79.76 44.22,81.95 43.34,82.83 43.21,82.83 42.88,82.5 LVDS1.28 ; 46.69,60.72 v4(46.69,60.38)
S_TXO2+: length 35.4
  TOP w0.089: 50.25,62.04 50.67,62.04 51.99,63.36 52.87,63.36 52.89,63.39 53.63,63.39 ; 50.25,62.04 v4(50.25,62.41) ; 50.25,62.04 49.77,62.04 49.56,62.25 49.56,63.06 49.24,63.39 48.23,63.39 47.9,63.06 47.9,62.18 47.77,62.05 47.23,62.05 47.1,62.18 47.1,65.74 46.24,66.61 46.24,78.54 45.5,79.28 45.5,82.37 44.25,83.61 44.25,84.71 43.79,85.17 43.21,85.17 42.88,85.5 LVDS1.25
S_TXO2-: length 35.4
  TOP w0.089: 45.89,76.28 45.89,78.4 45.16,79.14 45.16,82.23 43.91,83.47 43.91,84.57 43.65,84.83 43.23,84.83 42.9,84.5 LVDS1.26 ; 45.89,76.28 45.89,66.46 46.76,65.6 46.76,62.04 47.08,61.71 47.91,61.71 48.24,62.04 48.24,62.92 48.37,63.04 49.09,63.04 49.22,62.92 49.22,62.1 49.62,61.7 50.81,61.7 52.13,63.02 52.87,63.02 52.89,62.99 53.63,62.99 ; 45.89,76.28 v4(45.55,76.28)
S_TXO3+: length 35.6
  TOP w0.089: v4(48.98,65.71) 48.61,65.71 ; 48.61,65.71 48.61,65.05 48.74,64.92 50.24,64.92 50.36,65.05 50.36,65.47 50.76,65.87 51.66,65.87 52.57,64.96 52.87,64.96 52.89,64.99 53.63,64.99 ; 48.61,65.71 48.61,66.32 47.71,67.22 47.71,79.16 46.97,79.89 46.97,82.98 45.73,84.22 45.73,88.49 45.31,88.91 44.04,88.91 43.92,89.03 43.92,89.75 43.51,90.17 43.24,90.17 42.91,90.5 LVDS1.20
S_TXO3-: length 35.6
  TOP w0.089: 53.63,64.59 52.89,64.59 52.87,64.62 52.43,64.62 51.52,65.53 50.9,65.53 50.71,65.33 50.71,64.91 50.38,64.58 48.6,64.58 48.27,64.91 48.27,66.17 47.37,67.08 47.37,79.01 46.63,79.75 46.63,82.84 45.38,84.08 45.38,87.78 ; 45.38,87.78 45.38,88.35 45.17,88.57 43.9,88.57 43.58,88.88 43.58,89.61 43.37,89.83 43.24,89.83 42.91,89.5 LVDS1.21 ; 45.38,87.78 v4(45.04,87.78)
S_TXOC+: length 76
  TOP w0.089: 53.63,64.19 52.89,64.19 52.87,64.16 51.82,64.16 v1(51.6,64.39) 51.39,64.18 48.12,64.18 47.87,64.43 47.87,66.01 46.97,66.91 46.97,78.85 46.24,79.59 46.24,82.67 44.99,83.92 44.99,86.77 43.59,88.17 43.21,88.17 42.88,88.5 LVDS1.22 ; LVDS1.10 42.97,100.5 43.25,100.22 43.61,100.22 45.73,98.09 45.73,95.71 46.64,94.8 46.64,91.93 48.67,89.89 48.67,85.45 50.03,84.09 50.03,81 50.66,80.38 50.66,71.51 51.09,71.08 51.43,71.08 v1(51.6,71.25)
  BOTTOM w0.089: v1(51.6,71.25) 51.6,71.14 51.46,71 51.08,71 50.76,70.68 50.76,67.68 51.41,67.02 51.41,66.47 ; v1(51.6,64.39) 51.8,64.18 52.02,64.18 52.1,64.26 52.1,65.02 51.41,65.72 51.41,66.47 ; v2(51.11,66.47) 51.41,66.47
S_TXOC-: length 75.9
  TOP w0.089: v1(51.6,70.48) 51.34,70.74 50.94,70.74 50.31,71.37 50.31,80.24 49.69,80.86 49.69,83.02 49.69,83.95 48.33,85.3 48.33,89.75 46.3,91.78 46.3,94.65 45.39,95.56 45.39,97.95 43.47,99.87 43.34,99.87 42.97,99.5 LVDS1.11 ; LVDS1.23 42.88,87.5 43.21,87.83 43.45,87.83 44.65,86.63 44.65,83.78 45.89,82.53 45.89,79.44 46.63,78.71 46.63,66.77 46.86,66.54 47.53,65.87 47.53,64.28 47.98,63.84 51.39,63.84 v1(51.6,63.63) 51.79,63.82 52.88,63.82 52.88,63.82 52.91,63.79 53.63,63.79
  BOTTOM w0.089: v1(51.6,70.48) 51.42,70.66 51.23,70.66 51.1,70.53 51.1,68.86 ; v2(51.39,68.86) 51.1,68.86 ; 51.1,68.86 51.1,67.82 51.75,67.16 51.75,65.86 52.45,65.17 52.45,64.12 52.16,63.84 51.8,63.84 v1(51.6,63.63)
SA0_DIMM1: length 8.9
  TOP w0.102: DIMM1.256 138.37,126.53 137.45,125.6 137.32,125.6 v3(136.69,124.97)
  BOTTOM w0.102: R650.1 v2(132.57,126.17) R653.2 134.21,126.17 134.78,125.6 136.05,125.6 v3(136.69,124.97)
SA0_DIMM2: length 8.4
  TOP w0.102: v1(153.07,126.62) 153.16,126.53 DIMM2.256
  BOTTOM w0.102: v1(153.07,126.62) 154.16,126.62 154.97,125.81 R648.2 155.54,125.03 v2(156.07,125.55) 156.07,127.42 R642.1
SA1_DIMM1: length 5.8
  TOP w0.102: DIMM1.260 137.75,125.53 137.45,125.22 v3(137.45,124.97)
  BOTTOM w0.102: R649.1 139.35,125.56 R652.2 138.48,125.73 137.96,125.73 v2(137.95,125.74) 137.45,125.23 v3(137.45,124.97)
SA1_DIMM2: length 8.8
  TOP w0.102: DIMM2.260 152.89,125.53 v1(151.8,126.62)
  BOTTOM w0.102: v1(151.8,126.62) 151.8,126.91 R647.2 152.8,127.05 153.25,127.05 153.28,127.02 154.75,127.02 v2(155.07,126.7) 155.07,127.39 R643.1
SA2_DIMM1: length 24.4
  TOP w0.102: DIMM1.166 140.57,149.03 141.77,147.83 141.77,130.94 v3(141,130.18)
  BOTTOM w0.102: v3(141,130.18) 141.13,130.3 v2(141.13,131.06) 141,131.06 140.43,130.49 R641.1 139.8,130.56 R638.2
SA2_DIMM2: length 21.1
  TOP w0.102: DIMM2.166 156.02,149.03 156.85,148.19 156.85,146.18 v3(156.27,145.59)
  BOTTOM w0.102: v3(156.27,145.59) 155.9,145.22 R637.2 155.35,133.6 v2(155.48,133.48) 155.48,131.38 R640.1
SATA__RXN0_C: length 7.5
  TOP w0.102: C41.2 16.45,146.82 15.97,146.82 12.94,143.8 12.28,143.8 HDD1.5
  BOTTOM w0.102: v2(12.56,143) HDD1.5
SATA__RXN1_C: length 9.9
  TOP w0.102: ODD1.5 8.68,178.8 9.03,178.8 9.69,178.14 9.69,176.15 12.16,173.68 13.32,173.68 C22.2
  BOTTOM w0.102: ODD1.5 v2(8.96,178)
SATA__RXP0_C: length 7.5
  TOP w0.102: C40.2 16.45,147.03 15.88,147.03 12.85,144.01 12.28,144.01 HDD1.6
  BOTTOM w0.102: v2(12.48,144.98) HDD1.6
SATA__RXP1_C: length 10.1
  TOP w0.102: C21.2 13.06,174.33 12.99,174.26 12.99,173.96 12.92,173.89 12.24,173.89 9.9,176.24 9.9,178.23 9.12,179.01 8.68,179.01 ODD1.6
  BOTTOM w0.102: ODD1.6 v2(8.88,179.98)
SATA__TXN0_C: length 13.3
  TOP w0.102: HDD1.3 11.27,140.73 11.11,140.56 10.57,140.56 10.18,140.17 10.18,137.76 10.87,137.07 12.59,137.07 15.22,139.7 C53.2
  BOTTOM w0.102: HDD1.3 v2(12.56,141.02)
SATA__TXN1_C: length 8.9
  TOP w0.102: ODD1.3 8.68,175.2 9.03,175.2 12.5,171.74 12.5,171 12.88,170.62 13.27,170.62 C24.2
  BOTTOM w0.102: ODD1.3 v2(8.96,176.02)
SATA__TXP0_C: length 13.5
  TOP w0.102: C52.2 16.31,139.92 15.13,139.92 12.5,137.29 10.96,137.29 10.4,137.85 10.4,140.08 10.66,140.35 10.87,140.35 10.98,140.23 10.98,139.57 11.09,139.46 HDD1.2
  BOTTOM w0.102: HDD1.2 v2(12.5,139.04)
SATA__TXP1_C: length 9
  TOP w0.102: ODD1.2 8.68,174.99 8.94,174.99 12.28,171.65 12.28,170.91 12.79,170.4 13.17,170.4 C25.2
  BOTTOM w0.102: ODD1.2 v2(8.9,174.04)
SATA_LED_N: length 159.6
  TOP w0.102: CPU1.H1 75.86,144.03 75.73,143.89
  TOP w0.254: v3(42.17,132.49) 42.28,132.61 55.54,132.61 60.55,137.62 71.33,137.62 71.53,137.82 71.75,137.82 R165.2 72.61,138.68 72.95,138.68 73.49,139.22 73.49,141.66 75.73,143.89
  L3 w0.254: v3(26.07,27.43) 26.04,27.46 26.04,39.39 30.41,43.76 30.41,125.81 36.31,131.71 41.39,131.71 v3(42.17,132.49)
  BOTTOM w0.254: v2(41.36,132.28) 41.96,132.28 v3(42.17,132.49) ; R833.1 24.02,26.11 24.61,26.11 25.93,27.43 v3(26.07,27.43)
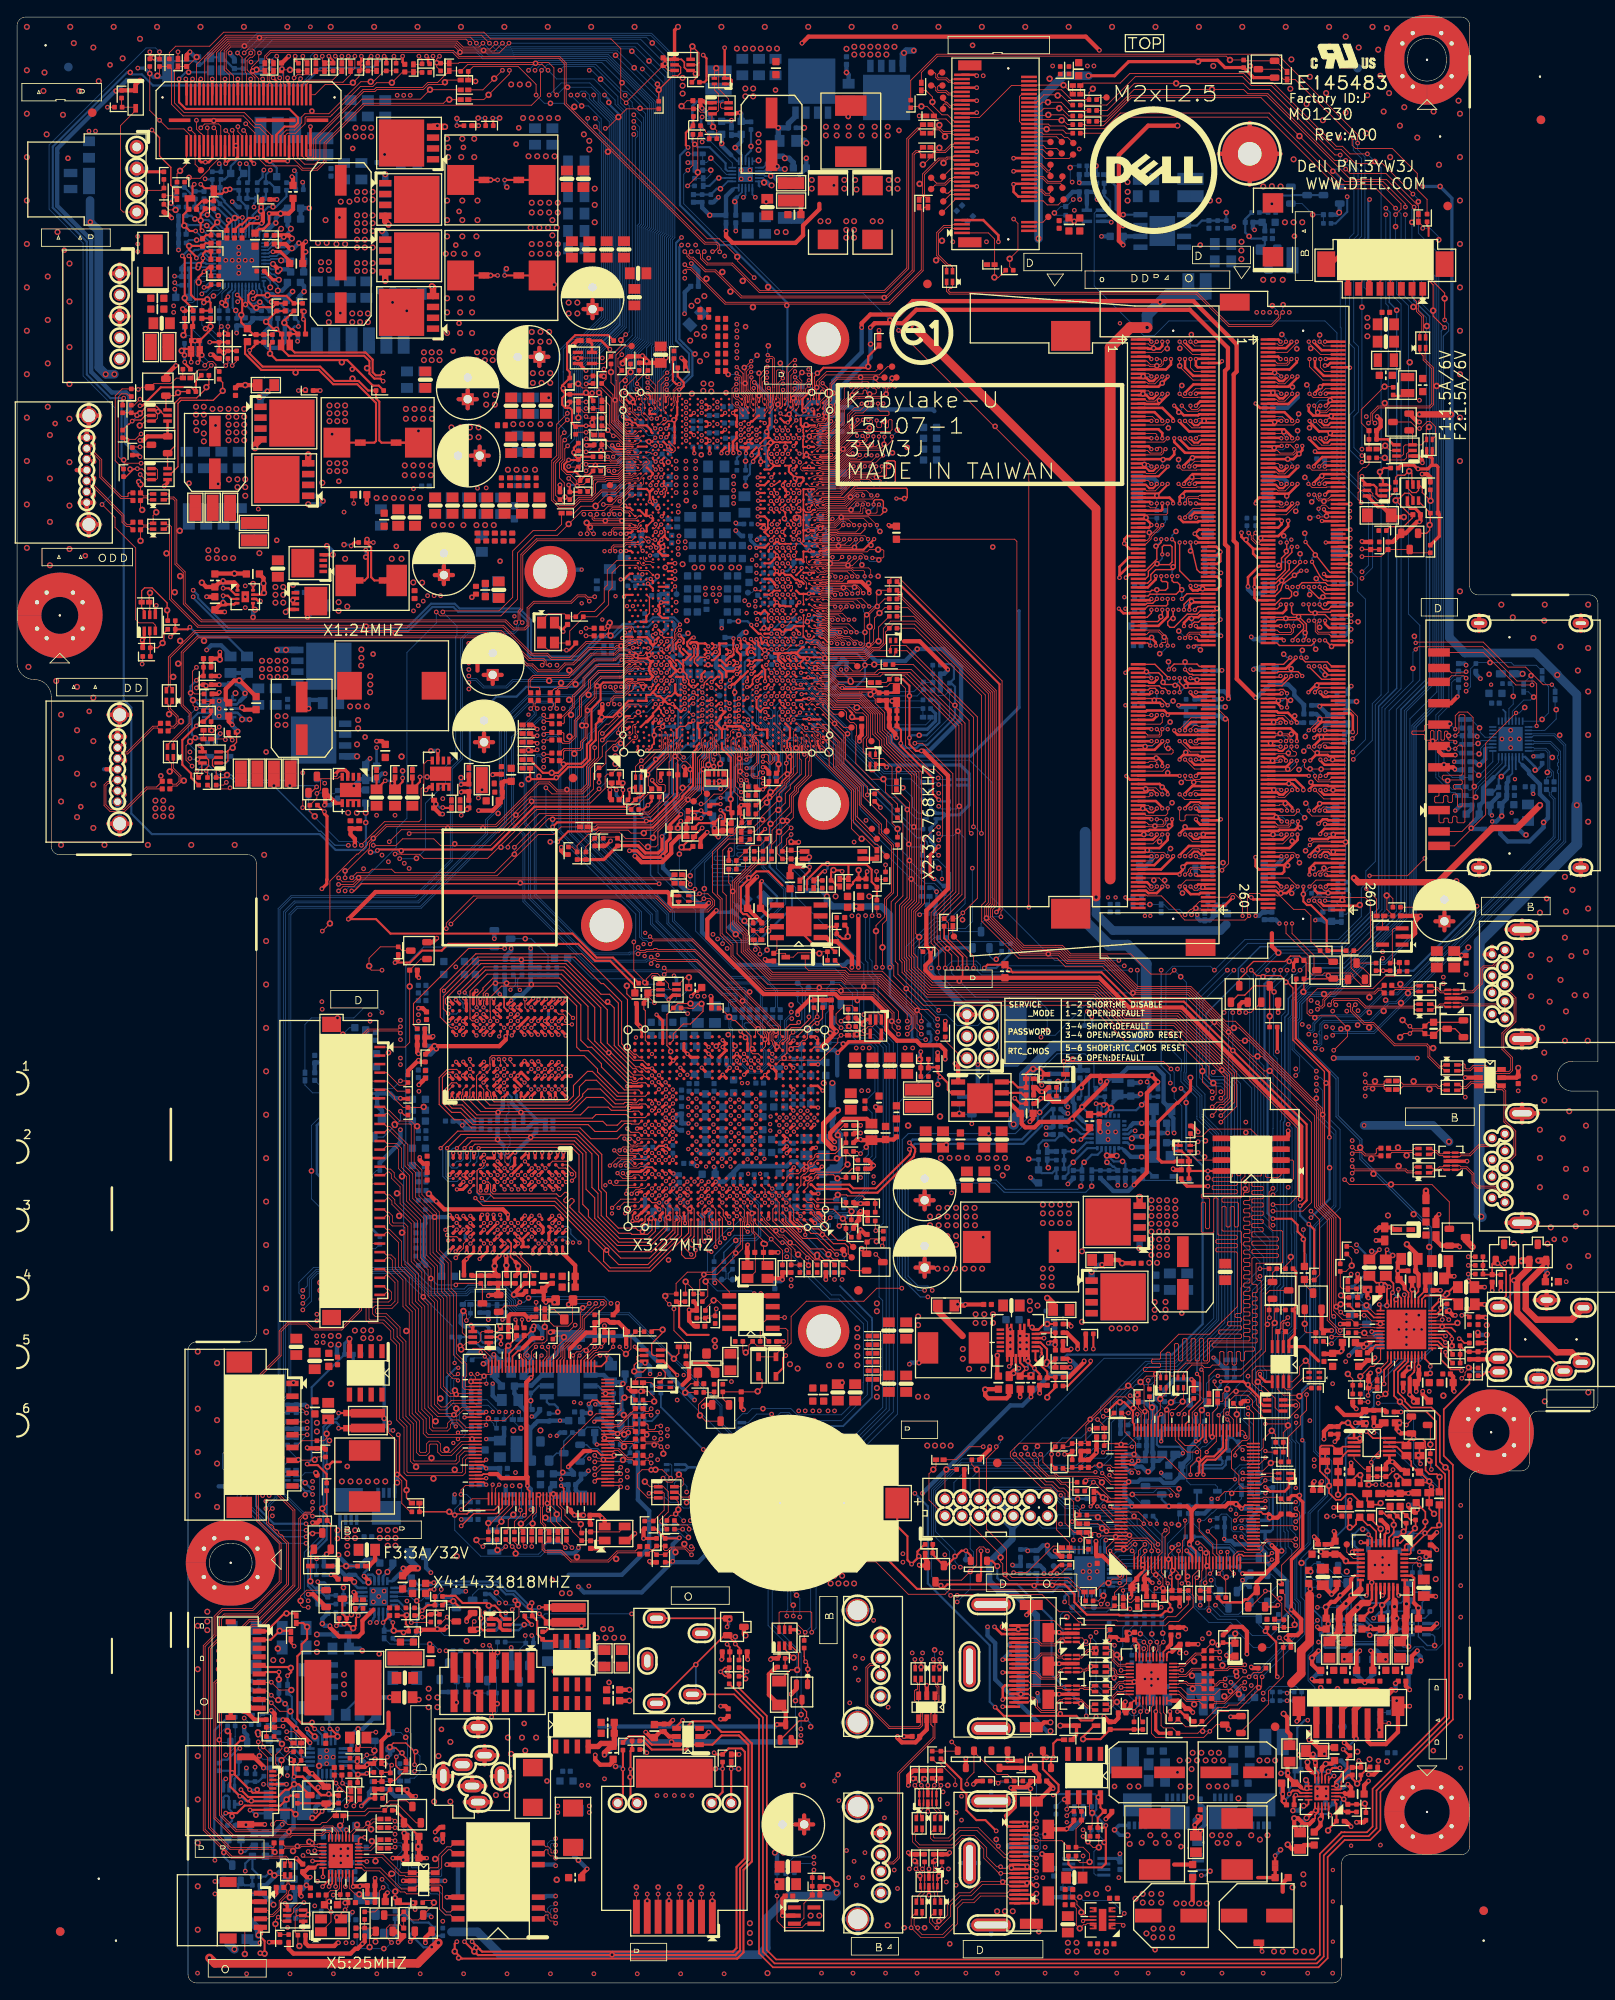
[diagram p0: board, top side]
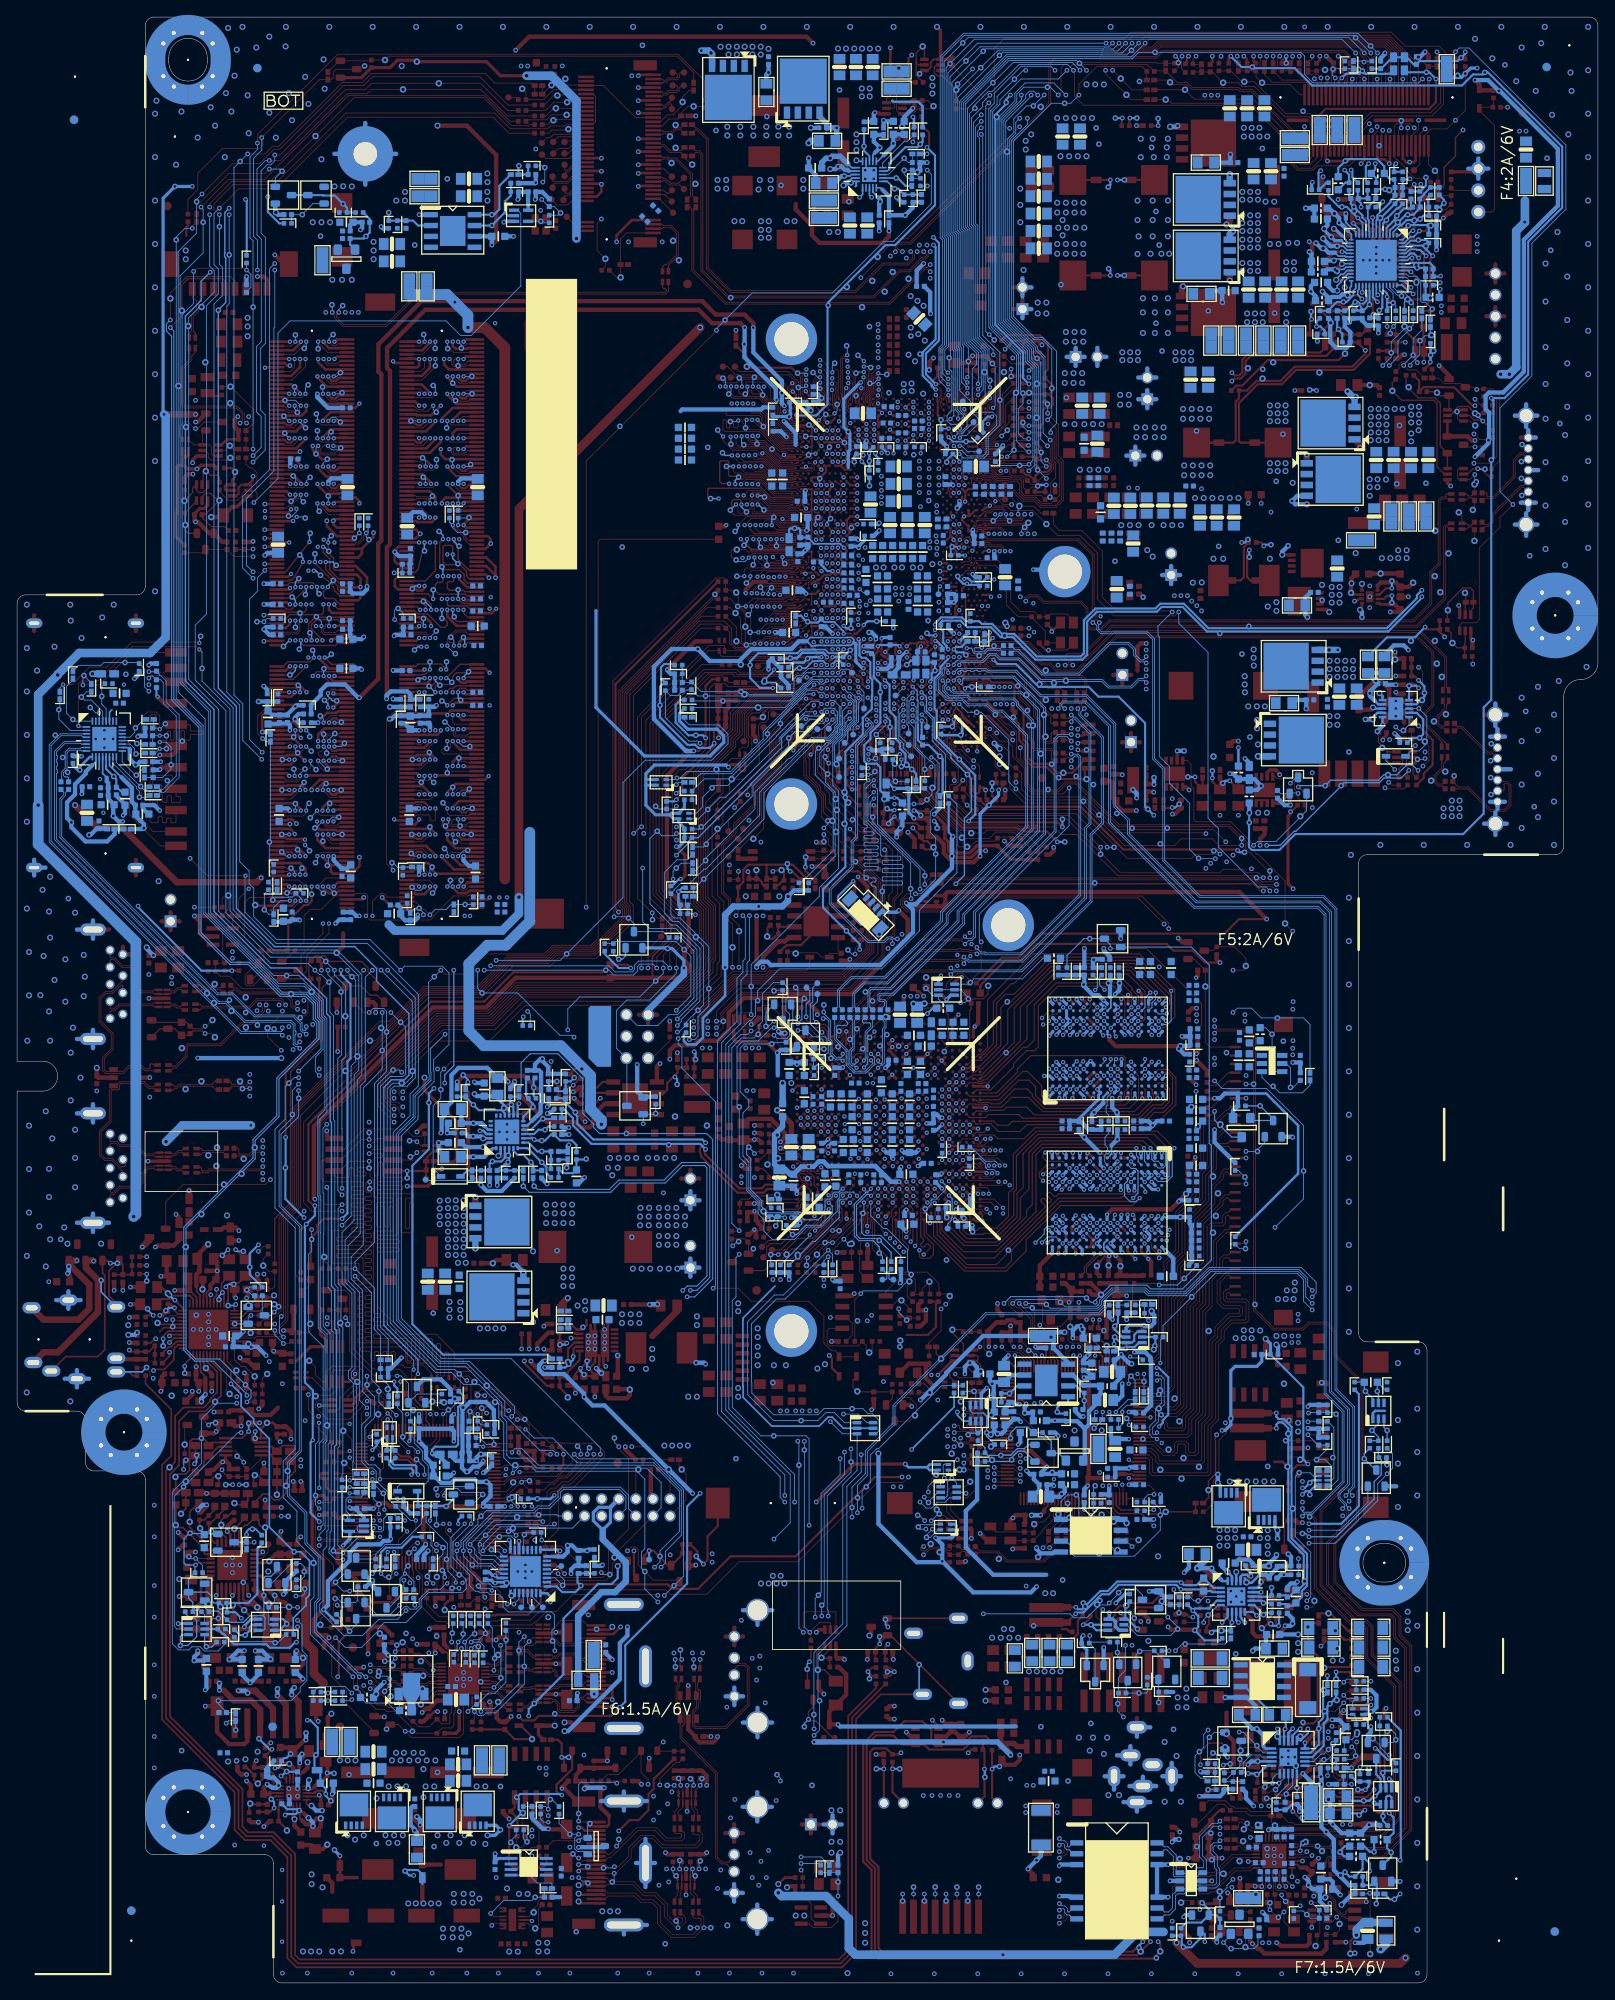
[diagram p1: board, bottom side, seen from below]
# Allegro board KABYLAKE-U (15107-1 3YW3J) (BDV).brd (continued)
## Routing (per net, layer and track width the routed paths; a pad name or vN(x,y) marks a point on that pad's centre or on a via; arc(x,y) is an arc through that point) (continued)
SATA_RXN0_C_N: length 5.1
  TOP w0.102: 18.84,147.6 18.84,148.2 17.92,149.12 17.92,149.54 18.15,149.77 L3.1 ; 18.84,147.6 v4(19.18,147.6) ; 18.84,147.6 18.84,147.26 18.4,146.82 18.01,146.82 C41.1
SATA_RXN1_C_N: length 2.9
  TOP w0.102: v4(14.64,172.34) 14.45,172.53 C22.1 14.76,173.76 15.16,173.76 15.39,173.52 L1.1
SATA_RXP0_C_N: length 4.7
  TOP w0.102: 18.04,148.69 17.71,149.03 17.71,149.54 17.47,149.77 L3.4 ; 18.04,148.69 18.63,148.11 18.63,147.35 18.31,147.03 18.01,147.03 C40.1 ; 18.04,148.69 v4(17.79,148.44)
SATA_RXP1_C_N: length 2.7
  TOP w0.102: L1.4 15.39,174.2 15.16,173.97 14.81,173.97 C21.1 v4(14.45,175.32)
SATA_TXN0_C_N: length 5.2
  TOP w0.102: 19.17,140.67 19.17,140.5 18.71,140.04 18.21,140.04 C53.1 ; 19.17,140.67 v4(19.51,140.67) ; 19.17,140.67 19.17,141.26 18.28,142.15 L4.1
SATA_TXN1_C_N: length 3.1
  TOP w0.102: C24.1 14.78,170.57 15.18,170.57 15.39,170.77 L2.4 15.92,171.7 v4(16.29,172.06)
SATA_TXP0_C_N: length 5.1
  TOP w0.102: 18.13,142 18.06,142.06 18.06,142.68 17.6,143.15 L4.4 ; 18.13,142 v4(17.86,141.73) ; 18.13,142 18.96,141.17 18.96,140.59 18.62,140.25 18.21,140.25 C52.1
SATA_TXP1_C_N: length 3
  TOP w0.102: L2.1 15.39,170.09 15.13,170.35 14.78,170.35 C25.1 v4(14.45,168.72)
SATAHDR_RX_DN0: length 71.3
  TOP w0.102: v3(61.45,154.18) 61.69,154.42 61.69,154.6 61.56,154.72 59.88,154.72 56.6,158 20.87,158 17.92,155.05 17.92,152.81 ; L3.2 18.15,151.41 17.92,151.64 17.92,152.81 ; v4(18.27,152.81) 17.92,152.81 ; v1(75.38,155.12) 75.06,155.45 CPU1.F20
  L3 w0.127: v1(75.38,155.12) 75.34,155.12 74.8,155.66 71.19,155.66 67.62,159.23 66.15,159.23 65.28,158.36 65.28,156.05 64.68,155.45 61.98,155.45 61.67,155.13 61.67,154.39 v3(61.45,154.18)
SATAHDR_RX_DN1: length 80.9
  TOP w0.102: 19.45,164.59 19.45,165.01 18.47,165.99 18.47,173.41 18.24,173.63 17.52,173.63 17.41,173.52 L1.2 ; 19.45,164.59 19.45,161.34 21.55,159.25 57.12,159.25 58.06,158.31 59.46,158.31 59.9,158.75 59.9,160.81 60.52,161.43 64.89,161.43 65.64,162.18 66.45,162.18 v3(66.96,161.67) ; 19.45,164.59 v4(19.08,164.59) ; v1(76.08,156.97) 75.71,156.6 CPU1.G21
  L3 w0.127: v1(76.08,156.97) 76.08,159.21 75.29,159.99 74.61,159.99 71.33,163.27 67.77,163.27 67.13,162.62 67.13,161.84 v3(66.96,161.67)
SATAHDR_RX_DP0: length 71.6
  TOP w0.102: CPU1.E20 74.41,155.19 74.48,155.12 v1(74.73,155.12) ; v3(62.34,154.18) 61.96,154.18 61.91,154.23 61.91,154.68 61.65,154.94 59.97,154.94 56.69,158.22 20.78,158.22 19.34,156.77 ; v4(19.08,157.02) 19.34,156.77 ; 19.34,156.77 17.71,155.14 17.71,151.66 17.47,151.43 L3.3
  L3 w0.127: v3(62.34,154.18) 62.06,154.18 61.93,154.31 61.93,155.02 62.09,155.18 64.79,155.18 65.54,155.94 65.54,158.25 66.26,158.97 67.51,158.97 71.08,155.4 74.61,155.4 74.73,155.27 v1(74.73,155.12)
SATAHDR_RX_DP1: length 80.5
  TOP w0.102: v1(75.38,156.95) 75.38,156.68 75.19,156.49 CPU1.F21 ; 18.69,169.9 18.69,166.08 19.67,165.1 19.67,161.43 21.64,159.46 57.21,159.46 58.15,158.52 59.37,158.52 59.68,158.84 59.68,160.9 60.43,161.65 64.8,161.65 65.55,162.39 66.54,162.39 66.81,162.13 67.55,162.13 v3(67.6,162.18) ; 18.69,169.9 v4(19.03,169.9) ; 18.69,169.9 18.69,173.5 18.33,173.85 17.85,173.85 17.79,173.91 17.79,174.12 17.7,174.2 L1.3
  L3 w0.127: v3(67.6,162.18) 67.44,162.33 67.44,162.56 67.89,163 71.22,163 74.5,159.73 75.18,159.73 75.81,159.1 75.81,157.3 75.47,156.95 v1(75.38,156.95)
SATAHDR_TX_DN0: length 69.2
  TOP w0.089: 69.62,156.02 69.64,156.02 69.65,156.03 69.98,156.03 70.23,156.28 71.32,156.28 71.53,156.49 71.69,156.49 arc(71.8,156.51) 71.89,156.56 CPU1.B21
  TOP w0.102: 21.88,157.38 56.34,157.38 59.62,154.1 60.26,154.1 60.95,153.4 63.37,153.4 64.18,154.21 65.14,154.21 66.95,156.02 69.62,156.02 ; 21.88,157.38 v4(21.88,157.02) ; 21.88,157.38 21.19,157.38 19.43,155.61 19.43,149.52 20.35,148.59 20.35,147.29 18.28,145.22 L4.2
SATAHDR_TX_DN1: length 69.3
  TOP w0.089: CPU1.D21 73.16,157.06 73.01,157.16 72.58,157.16 72.46,157.22 72.21,157.22 72.08,157.16 71.93,157.16 71.81,157.22 71.8,157.22 71.79,157.22 71.41,157.22 71.12,156.93 69.65,156.93 69.63,156.95 69.61,156.95
  TOP w0.102: 69.61,156.95 66.58,156.95 64.68,155.05 62.6,155.05 62.09,155.56 60.23,155.56 56.95,158.84 21.2,158.84 18.07,161.98 18.07,162.71 ; L2.3 17.37,170.77 17.55,170.6 17.83,170.6 18.07,170.36 18.07,162.71 ; 18.07,162.71 v4(18.45,162.71)
SATAHDR_TX_DP0: length 69.1
  TOP w0.089: 69.62,156.24 69.64,156.24 69.65,156.22 69.91,156.22 70.15,156.47 71.24,156.47 71.54,156.77 CPU1.A21
  TOP w0.102: 69.62,156.24 66.86,156.24 65.05,154.43 64.09,154.43 63.28,153.62 61.04,153.62 60.35,154.32 59.71,154.32 56.43,157.59 21.1,157.59 19.21,155.7 19.21,154.36 ; L4.3 17.6,144.85 20.14,147.38 20.14,148.5 19.21,149.43 19.21,154.36 ; 19.21,154.36 v4(18.85,154.36)
SATAHDR_TX_DP1: length 69.2
  TOP w0.089: 69.61,156.73 69.63,156.73 69.65,156.74 71.2,156.74 71.49,157.03 71.79,157.03 71.92,156.97 72.07,156.97 72.11,156.98 72.25,157.03 72.44,157.03 72.57,156.97 72.64,156.9 72.64,156.58 72.74,156.49 72.91,156.49 72.99,156.57 CPU1.C21
  TOP w0.102: L2.2 17.29,170.09 17.58,170.38 17.74,170.38 17.85,170.27 17.85,167.26 ; 69.61,156.73 66.67,156.73 64.77,154.83 62.51,154.83 62,155.35 60.14,155.35 56.86,158.62 21.12,158.62 19.24,160.5 17.85,161.89 17.85,167.26 ; 17.85,167.26 v4(17.48,167.26)
SB3V: length 1022.7
  TOP w0.254: PR58.1 95.03,121.35 94.95,121.35 94.87,121.42 93.26,121.42 91.47,123.22 PU10.9 ; v3(14.38,184.53) 14.67,184.53 16.82,186.68 18.16,186.68 18.2,186.72 20.39,186.72 R85.1 20.92,187.45 R77.1 ; R203.1 R204.1 97.29,130.84 ; 97.29,130.84 99.42,130.84 100.01,130.24 100.01,128.82 R206.1 R213.1 ; 97.29,130.84 94.22,130.84 92.44,129.05 92.44,127.89 ; v3(80.3,225.55) 80.68,225.17 80.68,222.63 80.42,222.38 R29.2 ; 165.19,204.4 165.19,205.43 165.01,205.61 R876.1 ; R483.1 32.35,25.49 32.29,25.43 32.29,24.26 v3(32.42,24.13) ; R238.1 72.3,116.51 72.22,116.58 72.22,116.76 69.4,119.58 67.65,119.58 65.67,121.56 50.48,121.56 49.69,120.78 47.38,120.78 45.99,119.38 v3(44.23,119.38) ; v3(70.14,139.57) 69.57,140.14 R161.1 ; R480.1 110.49,23.84 110.49,22.71 111.11,22.1 111.11,20.21 112.27,19.05 113.32,19.05 v3(114.59,17.78) ; R171.2 35.91,137.03 v3(35.97,137.03) ; PR54.1 86.14,124.28 85.38,125.04 84.99,125.04 84.69,125.35 84.69,128.23 86.51,130.05 87.92,130.05 89.57,128.4 ; PR44.1 22.7,148.46 PR45.1 21.5,147.57 v3(20.99,147.07) 19.34,145.41 19.34,142.53 20.38,141.49 20.38,141.01 R157.2
  TOP w0.305: R515.1 95.16,12.32 v5(95.92,11.56) ; v3(69.38,191.13) 68.36,192.15 C16.1 67.28,191.77 U1.5 ; R229.1 v3(159.86,118.43) R228.1 ; v3(46.58,8.59) R520.1 46.45,9.27 44.86,9.27 C275.1 ; R199.1 83.28,132.4 v3(83.47,132.59) ; v3(32.42,24.13) 33.43,24.13 35.59,21.97 37.56,21.97 R503.1 ; R5.1 48.1,224.71 48.1,225.23 v3(47.91,225.43) ; R17.1 41.1,224.65 41.1,225.09 v3(41.44,225.43)
  TOP w0.356: 165.41,178.56 165.16,178.56 164.96,178.77 RN2.1 ; 165.41,178.56 165.61,178.36 165.61,177.66 165.51,177.56 ; 165.41,178.56 165.61,178.77 RN2.2 ; 166.28,177.36 166.28,171.97 R116.2
  TOP w0.381: R265.1 135.54,96.14 135.44,96.04 133.94,96.04 133.54,96.44 133.54,100.76 135.72,102.95 135.83,102.95 137.32,104.44 v5(137.32,105.92) ; R181.1 78.33,136.02 R175.1 79.98,136.21 v3(80.04,136.27) ; R106.1 161.97,177.57 163.46,177.57 163.89,177.14 v3(163.95,177.14) 165.09,177.14 165.51,177.56 166.08,177.56 166.28,177.36 ; R152.2 75.32,141.39 v3(75.32,140.67) ; v3(149.13,43.69) 149.13,49.51 150.46,50.84 150.46,56.24 149.69,57.02 149.19,57.02 R398.2 ; v3(35.67,128.02) 36.24,128.59 36.24,129.07 36.27,129.09 36.27,136.49 35.97,136.78 v3(35.97,137.03) ; R116.2 166.43,171.82 166.43,169.25 R121.2
  TOP w0.508: 111.16,112.22 JMP1.6 ; JMP1.6 112.23,113.28 ; JMP1.6 110.09,113.28 ; v3(72.3,131.83) 72.37,131.83 73.07,131.13 75.49,131.13 76.55,132.19 76.55,133.22 77.44,134.11 R184.1 R181.1 ; v3(149.13,43.69) 150.27,42.55 150.27,41.11 149.85,40.69 148.8,40.69 v3(148.5,40.39) 149.07,39.81 R466.1 ; R470.2 27.78,30.8 26.83,31.75 v3(26.58,31.75) ; v3(37.6,4.7) 37.5,4.7 37.12,4.32 34.07,4.32 33.75,4.64 R525.1 ; v3(44.23,119.38) 44.61,119.76 R223.1 ; PC133.1 135.42,13.84
  L3 w0.254: v3(20.99,147.07) 20.99,147.12 13.09,155.02 13.09,181.17 13.46,181.54 14.38,182.47 v3(14.38,184.53)
  L3 w0.305: v3(80.17,218.31) 80.73,218.87 80.73,225.12 v3(80.3,225.55) 79.62,226.23 59.06,226.23 58.42,225.59 50.34,225.59 49.94,225.98 48.34,225.98 47.91,225.55 v3(47.91,225.43) 47.35,225.98 41.97,225.98 41.44,225.45 v3(41.44,225.43)
  L3 w0.381: v1(133.38,53.72) 133.38,53.67 132.79,53.09 131.78,53.09 129.4,50.71 129.4,49.96 126.22,46.77 124.2,46.77 122.46,48.51 117.44,48.51 117.06,48.9 v3(116.49,48.9)
  L3 w0.508: v5(156.85,27.05) 156.85,28.6 150.78,34.67 147.12,34.67 146.74,35.05 146.74,38.46 148.5,40.21 v3(148.5,40.39) ; 113.57,10.31 113.57,16.76 v3(114.59,17.78) ; v3(70.14,139.57) 70.14,139.74 70.63,140.23 72.27,140.23 72.75,139.75 74.51,139.75 75.32,140.56 v3(75.32,140.67)
  L3 w1.016: v5(41.94,4.83) 41.94,5.08 45.45,8.59 v3(46.58,8.59) 46.63,8.64 48.85,8.64 49.82,7.67 v3(49.82,7.21) ; v5(95.92,11.56) 95.92,20.3 90.27,25.95 90.27,32.29 87.22,35.34 87.22,43.01 85.6,44.63 68.71,44.63 v3(66.91,46.43) 61.25,52.09 v5(61.25,64.64)
  L4 w0.203: v3(80.31,62.41) 80.13,62.23 75.13,62.23 72.36,65 66.22,65 64.68,63.46 61.67,63.46 61.25,63.88 v5(61.25,64.64)
  L4 w0.254: v3(69.38,191.13) 69.38,191.76 76.39,198.78 80.29,198.78 83.33,201.82 83.33,202.83 79.41,206.76 79.41,217.55 v3(80.17,218.31)
  L4 w0.381: v3(20.99,147.07) 21.46,147.54 23.94,147.54 29.99,141.48 31.91,141.48 35.38,138.01 35.38,137.55 35.89,137.03 v3(35.97,137.03) ; v3(41.44,225.43) 40.84,224.83 34.71,224.83 34.07,225.47 34.07,225.63 33.3,226.4 23.87,226.4 22.26,224.79 14.05,224.79 13.22,223.96 13.22,217.49 15.16,215.55 15.16,185.22 14.47,184.53 v3(14.38,184.53) ; v1(133.38,53.72) 133.95,54.29 135.35,54.29 136.18,53.47 139.73,53.47 v1(141.26,51.94) ; v3(83.47,132.59) 82.33,132.59 81.35,133.57 81.35,134.96 v3(80.04,136.27) ; v3(60.23,40.64) 61.63,42.04 61.63,42.1 61.97,42.45 61.97,46.17 62.79,46.99 66.35,46.99 v3(66.91,46.43)
  L4 w0.508: v5(139.61,208.53) 138.72,207.65 127.41,207.65 v3(126.4,208.66) ; v5(41.94,4.83) 41.28,5.49 38.16,5.49 37.6,4.93 v3(37.6,4.7) ; v3(72.3,131.83) 72.17,131.7 48.04,131.7 46.44,133.3 45.38,133.3 44.12,134.56 38.2,134.56 35.97,136.79 v3(35.97,137.03) ; v3(35.67,128.02) 38.56,125.12 39.04,125.12 44.23,119.93 v3(44.23,119.38) 45.52,118.08 45.52,100.48 v3(44.86,99.82) 45.44,99.25 45.44,82.89 48.88,79.44 52.17,79.44 54.01,77.6 v3(55.15,77.6) ; v3(26.58,31.75) 26.4,31.75 25.92,31.26 25.92,29.54 29.33,26.12 30.95,26.12 32.42,24.66 v3(32.42,24.13)
  L4 w0.762: v5(94.78,127.13) 90.46,127.13 85,132.59 v3(83.47,132.59) ; v3(102.14,118.82) 102.22,118.75 v3(106.97,118.75) ; v5(30.01,9.14) 29.78,8.92 29.78,7.24 32.32,4.7 v3(37.6,4.7)
  L4 w1.016: v3(157.64,100.33) 154.47,100.33 152.84,101.95 146.28,101.95 142.59,105.64 137.6,105.64 v5(137.32,105.92)
  BOTTOM w0.203: R722.1 75.34,67.38 v3(80.31,62.41)
  BOTTOM w0.254: R767.2 133.38,54.17 v1(133.38,53.72) ; v3(170.85,125.98) 170.85,125.86 163.42,118.43 v3(159.86,118.43) ; R622.1 82.96,140.34 v3(82.33,139.7) ; v3(125.76,113.03) 125.83,112.97 R252.2 ; PG23.2 137.57,11.56
  BOTTOM w0.305: PR132.1 80.04,218.19 v3(80.17,218.31) ; R635.1 106.97,110.93 106.97,110.21 106.56,109.8 105.54,109.8 104.73,110.61 104.73,112.9 102.14,115.49 v3(102.14,118.82) ; R791.1 147.67,42.23 v3(149.13,43.69)
  BOTTOM w0.356: RN20.1 26.97,31.42 26.84,31.55 26.77,31.55 v3(26.58,31.75) 26.75,31.93 26.82,31.93 26.97,32.08 RN20.2
  BOTTOM w0.381: v3(72.3,131.83) 72.3,136.78 v2(71.28,137.79) 70.14,138.94 v3(70.14,139.57) ; R768.2 R772.2 141.32,52.01 v1(141.26,51.94) ; v3(106.97,118.75) 106.97,119.63 108.36,121.03 v2(108.87,121.03) 108.94,121.09 Q52.E ; R618.1 80.64,139.6 80.64,136.91 80.17,136.44 80.17,136.4 v3(80.04,136.27) ; R618.1 R619.1 R620.2 ; R618.1 82.27,139.76 v3(82.33,139.7) ; v3(60.23,40.64) 60.42,40.45 R803.1 60.42,39.56 59.82,38.96 D20.2
  BOTTOM w0.406: U27.5 125.19,208.09
  BOTTOM w0.508: R776.1 R780.1 116.58,48.81 v3(116.49,48.9) ; v5(94.78,127.13) 94.08,127.83 R644.1 R645.2 ; v3(44.86,99.82) 44.86,98.36 R681.1 ; R834.2 32.48,24.19 v3(32.42,24.13) 32.42,24 32.35,23.94 32.35,18.22 v2(31.8,17.67) 30.89,16.76 30.89,13.21 29.12,11.43 R860.1 R862.1 28.74,10.41 v5(30.01,9.14) ; v3(55.15,77.6) R708.1 R709.1 ; R816.1 26.58,34.29 25.92,33.63 25.92,32.24 26.4,31.75 v3(26.58,31.75) ; v3(149.13,43.69) 148.62,44.2 148.62,46.99 146.85,48.77 146.71,48.77 146.08,49.39 146.08,50.33 145.11,51.31 142.51,51.31 142.1,51.71 141.49,51.71 v1(141.26,51.94) ; R579.1 170.7,153.45 170.7,153.16 v3(171.25,152.6) ; v3(126.4,208.66) 126.33,208.72 PR159.1 C288.1 125.19,208.09
  BOTTOM w0.762: v3(106.97,118.75) 106.97,117.98 111.16,113.79 JMP1.6 ; v3(102.14,118.82) 102.14,124.97 101.16,125.95 v2(98.2,125.95) 95.45,125.95 94.78,126.62 v5(94.78,127.13)
  BOTTOM w1.016: v3(157.64,100.33) 165.67,100.33 v5(167.57,98.42) ; v5(95.92,10.54) 95.54,10.16 90.33,10.16 87.66,7.49 87.66,4.06 86.9,3.3 v2(69.63,3.3) 56.55,3.3 53.88,5.97 50.83,5.97
  vias: v2(149.49,204.37) v2(159.32,25.98) v5(130.89,9.86) v5(131.73,10.41) v5(131.73,9.4) v5(132.75,10.41) v5(132.75,9.4) v5(133.89,10.41) v5(133.89,9.4) v5(139.61,209.55) v5(140.62,208.53) v5(148.37,205.99) v5(149.26,11.18) v5(149.39,205.99) v5(150.4,205.99) v5(150.53,12.7) v5(150.53,11.56) v5(158.28,26.16) v5(160.31,25.91) v5(165.26,202.69) v5(165.26,201.68)
SB5V: length 778.7
  TOP w0.254: PG20.2 144.81,4.7
  TOP w0.305: 24.42,161.29 25.42,161.29 25.56,161.43 PU8.4
  TOP w0.381: R248.1 147.48,111.82 v3(147.48,108.97) ; PC19.1 31.91,201.46 30.82,202.55 v3(29.95,202.55)
  TOP w0.406: v3(37.24,141.35) 37.24,141.45 37.71,141.91 38.39,141.91 38.7,141.6 U4.3 ; 145.19,12.32 PC134.1 PG19.2 ; U3.3 v3(49.24,144.15) ; v1(87.16,128.91) 87,128.75 PC84.1 87.89,124.84 88.92,124.84
  TOP w0.508: v3(126.65,226.12) 125.06,227.71 92.62,227.71 v3(91.85,226.95) ; v3(129.45,203.33) 128.94,203.84 128.94,213.87 132.37,217.3 v5(135.8,217.3) ; 24.42,161.29 23.78,161.29 PC74.1 23.4,160.4 v3(24.29,160.4) ; v3(32.16,211.33) 32.29,211.2 PR4.1 ; R453.1 142.08,41.66 143.37,41.66 143.92,41.1 v3(143.92,38.48) ; v3(108.62,108.08) 108.62,109.09 108.01,109.7 105.8,109.7 105.27,110.24 102.99,110.24 101.72,111.5 101.72,113.48 99.96,115.24 96.2,115.24 95.75,115.7 87.36,115.7 80.78,122.28 80.78,124.43 v3(81.82,125.48)
  TOP w0.762: v3(164.88,92.68) R273.2
  L3 w0.254: v3(50.2,38.86) 50.2,37.59 47.23,34.62 47.23,24.72 43.97,21.46 37.85,21.46 34.92,18.54 v3(31.02,18.54)
  L3 w0.381: v3(37.24,141.35) 34.07,141.35 33.69,140.97 26.7,140.97 22.19,145.47 22.19,155.94 v3(22.18,155.96) 22.19,155.97 22.19,158.31 v3(24.29,160.4) 24.95,161.06 24.95,163.8 23.91,164.85 22.32,164.85 19.15,168.02 19.15,184.68 21.58,187.11 24.46,187.11 25.94,188.59 25.94,191.39 26.68,192.13 26.68,198.25 28.61,200.18 28.61,201.42 29.73,202.55 v3(29.95,202.55)
  L3 w0.508: v3(29.95,202.55) 27.21,205.28 27.21,206.88 25.69,208.41 v3(25.18,208.41) ; v3(118.65,26.67) 118.65,26.63 112.07,26.63 102.88,35.83 102.88,41.53 98.56,45.85 94.4,45.85 88.71,51.54 86.68,51.54 79.64,58.58 79.64,67.84 v3(79.28,68.2) ; v5(154.08,108.2) 153.96,108.33 148.12,108.33 v3(147.48,108.97) 139.59,108.97 139.33,109.22 129.19,109.22 126.14,112.27 118.78,112.27 115.98,109.47 110.02,109.47 v3(108.62,108.08) ; v3(126.65,226.12) 126.97,226.12 v5(135.8,217.3) ; v3(83.6,217.93) 83.6,223.77 84.23,224.41 89.31,224.41 v3(91.85,226.95)
  L3 w1.016: v5(168.44,128.91) 166.15,131.19 166.15,192.46 165.64,192.97 165.64,200.26 166.71,201.32 166.71,209.27 164.67,211.3 154.74,211.3 148.75,217.3 v5(135.8,217.3)
  L4 w0.381: v3(25.18,208.41) 26.62,209.85 30.68,209.85 v3(32.16,211.33)
  L4 w0.406: v3(49.24,144.15) 45.75,144.15 43.7,142.09 42.83,142.09 42.1,141.35 v3(37.24,141.35)
  L4 w0.508: v3(81.82,125.48) 81.62,125.28 80.62,125.28 71.38,134.52 56.46,134.52 56.07,134.12 55.26,133.31 48.05,133.31 45.65,135.7 38.68,135.7 37.24,137.13 v3(37.24,141.35) ; v3(31.02,18.54) 29.47,16.99 24.85,16.99 22.49,14.62 22.49,6.88 v5(25.43,3.94)
  L4 w1.016: 131.99,4.45 129.88,2.34 27.03,2.34 v5(25.43,3.94)
  BOTTOM w0.203: v3(29.95,202.55) 29.63,202.55 29.43,202.35 PU24.18
  BOTTOM w0.254: R805.1 v3(50.2,38.86) ; CN1.1 85.33,123.83 86.27,123.83 88.93,126.49 88.93,127.13 v1(87.16,128.91)
  BOTTOM w0.406: v3(81.82,125.48) 82.02,125.28 CN1.1
  BOTTOM w0.457: v3(25.18,208.41) 25.81,207.77 PR165.1
  BOTTOM w0.508: v3(22.18,155.96) 22.72,156.49 23.88,156.49 24.98,155.39 PR273.2 ; PU21.6 PC146.1 v3(129.45,203.33) ; v3(79.28,68.2) 79.27,68.2 76.28,71.2 76.28,71.37 71.96,75.69 R711.1 ; PR131.2 v3(83.6,217.93) 83.47,217.81 PR127.2 ; v5(154.08,108.2) v3(163.86,108.2) ; R843.1 R850.1 31.35,18.87 v3(31.02,18.54) 30.01,17.53 R852.1 R853.1 27.76,17.53 v2(26.78,18.51) 25.59,18.51 R851.1 ; v2(48.43,144.15) v3(49.24,144.15)
  BOTTOM w1.016: v5(25.43,3.94) 24.8,4.57 F7.1
  vias: v2(119.57,5.99) v2(133.18,3.89) v3(159.8,120.65) v3(159.8,119.89) v5(101.89,6.73) v5(114.69,8.38) v5(115.6,8.38) v5(116.52,8.38) v5(132.16,5.79) v5(133,6.35) v5(133,5.33) v5(134.02,6.35) v5(134.02,5.33) v5(135.16,6.35) v5(135.16,5.33)
SCA_AGND: length 1.4
  TOP w0.203: SCA1.54 59.17,72.94 58.83,73.28 v1(58.83,73.41)
  vias: v2(57.82,76.33)
SCALAR_EN: length 84.9
  TOP w0.102: KBC1.33 143.9,50.7 142.53,52.07 v1(142.53,52.2)
  L4 w0.127: v1(142.53,52.2) 141.64,53.09 141.64,54.48 141.19,54.93 133.46,54.93 133.08,54.55 125.26,54.55 123.55,52.84 107.14,52.84 105.78,54.19 93.74,54.19 93.54,54.39 90.45,54.39 90.25,54.19 88.57,54.19 88.17,53.8 87.21,53.8 86.11,54.9 v3(86.11,55.53)
  BOTTOM w0.102: v3(86.11,55.53) 86.11,57.56 v2(85.63,58.04) 85.15,58.52 85.15,61.75 84.4,62.5 84.18,62.5 76.77,69.91 R722.2 R723.2
SCALAR_EN_G: length 3.1
  BOTTOM w0.102: PQ9.2 72.8,69.02 v2(72.99,69.22) 74.14,69.22 R723.1
SCALAR_MUTE: length 128.8
  TOP w0.102: R331.2 v1(69.76,74.42) 69.17,73.84 68.05,73.84 67.98,73.76 67.68,73.76 66.77,72.85 SCA1.35
  L4 w0.127: v1(69.76,74.42) 70.26,73.91 81.43,73.91 86.39,68.95 86.39,67.79 89.2,64.99 91.22,64.99 91.43,64.77 123.98,64.77 124.97,65.76 125.93,65.76 126.25,65.45 126.64,65.45 126.65,65.47 130.12,65.47 130.75,64.83 141.32,64.83 141.64,65.15 144.43,65.15 144.72,64.86 154.42,64.86 155.89,63.39 157.78,63.39 v3(158.78,64.39)
  BOTTOM w0.102: v3(158.78,64.39) 159.16,64.39 v2(165.51,58.04) 166.61,56.95 166.61,41.73 166.28,41.4 Q72.2
SCALAR_OUT_L: length 5.7
  TOP w0.203: v4(60.36,76.45) 60.31,76.45 59.61,75.76 C132.1 59.34,75.48 58.43,74.57 58.43,74.5 57.57,73.64 SCA1.58
SCALAR_OUT_L_C: length 110.5
  TOP w0.203: U13.2 157.25,63.24 157.51,63.5 157.51,64.07 157.31,64.27 157.31,64.34 v3(157.13,64.52) ; v1(59.09,77.6) 59.09,76.9 C132.2
  L4 w0.203: v3(157.13,64.52) 156.88,64.52 153.11,68.29 150.68,68.29 149.54,69.43 141.34,69.43 141.28,69.37 132.05,69.37 130.99,70.42 122.97,70.42 120.54,68 100.37,68 98.23,70.14 90.14,70.14 82.96,77.33 76.26,77.33 75.1,78.49 59.98,78.49 v1(59.09,77.6)
  BOTTOM w0.203: v2(157.13,63.7) v3(157.13,64.52)
SCALAR_OUT_R: length 4.1
  TOP w0.203: SCA1.59 57.17,74.24 v4(57.49,74.55) 58.45,75.51 C131.1
SCALAR_OUT_R_C: length 113.2
  TOP w0.203: v3(157.89,64.52) 158.67,63.74 U13.10 ; v1(58.33,77.6) 58.45,77.47 C131.2
  L4 w0.203: v3(157.89,64.52) 157.31,63.93 156.64,63.93 152.86,67.7 150.4,67.7 149.26,68.85 141.58,68.85 141.52,68.78 131.81,68.78 130.75,69.84 123.21,69.84 120.78,67.41 100.13,67.41 98.2,69.34 90.12,69.34 82.71,76.75 76.01,76.75 74.86,77.9 60.84,77.9 60.05,77.11 58.81,77.11 v1(58.33,77.6)
  BOTTOM w0.203: v2(157.89,65.48) v3(157.89,64.52)
SCALAR_PC_SW1: length 7
  BOTTOM w0.152: Q62.E 67.1,62.2 67.85,62.2 68.61,61.44 v2(68.61,61.21) 68.82,61.01 R746.2
SCALAR_PC_SW2: length 8.2
  BOTTOM w0.152: R739.1 71.72,62.61 R742.2 71.42,61.72 v2(69.88,61.72) 69.86,61.75 68.71,61.75 67.95,62.51 67.11,62.51 66.66,62.96 Q62.B
SCALAR_PC_SW3: length 11.1
  BOTTOM w0.152: Q61.G 63.13,61.98 Q62.C 63.98,63.37 R738.1 C544.1 66.71,65.02 68.06,65.02 68.74,64.35 v2(68.74,63.75) 69.5,62.99 R737.1
SCALAR_PC_SW4: length 4.3
  BOTTOM w0.152: R739.2 72.15,64.72 PQ9.6 ; R739.2 73.5,64.33 v2(73.69,64.14) ; R739.2 72.8,64.58 PQ9.5
SCALAR_PC_SW5: length 6.6
  BOTTOM w0.152: R737.2 71.53,63.94 v2(71.53,64.39) 71.53,66.29 71.92,66.67 73.19,66.67 73.45,66.94 PQ9.3
SD_CD#: length 22.6
  TOP w0.102: MEMCD1.11 168.22,133.03 171.86,136.68 171.86,145.03 v1(175.42,148.59)
  BOTTOM w0.102: v2(176.44,149.22) 175.8,148.59 v1(175.42,148.59) 175.38,148.55 U28.30
SD_CLK_C_1: length 23.3
  TOP w0.102: MEMCD1.5 164.85,147.22 164.73,147.09 164.73,146.57 164.63,146.47 163.33,146.47 163.23,146.37 163.23,146.17 163.33,146.06 164.63,146.06 164.73,145.96 164.73,145.52 164.85,145.39 165.31,145.39 165.41,145.49 165.41,146.41 165.53,146.53 165.7,146.53 165.82,146.41 165.82,145.49 165.92,145.39 166.12,145.39 166.23,145.49 166.23,146.41 166.34,146.53 166.51,146.53 166.63,146.41 166.63,145.49 166.73,145.39 166.94,145.39 167.04,145.49 167.04,146.34 167.16,146.46 167.33,146.46 167.44,146.34 167.44,145.54 167.59,145.39 168.08,145.39 v1(168.31,145.16)
  BOTTOM w0.102: R616.2 C397.1 167.97,141.03 166.98,142.02 v2(166.98,142.52) 166.98,144.6 167.55,145.16 v1(168.31,145.16)
SD_CMD: length 24.8
  TOP w0.102: v1(168.31,144.4) 168.74,144.83 169,144.83 169.13,144.7 169.13,141.43 169,141.3 166.91,141.3 166.78,141.17 166.78,140.87 166.91,140.74 169,140.74 169.13,140.61 169.13,140.34 169,140.21 168.21,140.21 168.08,140.08 168.08,139.83 168.21,139.7 169,139.7 169.13,139.57 169.13,137.72 169,137.59 168.69,137.59 168.56,137.72 168.56,138.96 168.44,139.09 168.1,139.09 167.98,138.96 167.98,138.23 167.85,138.1 167.57,138.1 167.45,138.23 167.45,138.79 167.32,138.91 167.07,138.91 166.94,138.79 166.94,138.18 166.84,138.07 166.02,138.07 165.9,138.2 165.9,138.71 166.02,138.84 166.28,138.84 166.41,138.96 MEMCD1.2
  BOTTOM w0.102: v2(167.52,144.4) v1(168.31,144.4) 168.82,143.89 R611.2
SD_DAT0: length 20.7
  TOP w0.089: MEMCD1.7 167.16,152.22 167.87,152.93 169.3,152.93 v3(169.58,152.65)
  BOTTOM w0.089: 167.17,140.41 166.38,141.2 166.38,148.21 167.9,149.72 167.9,152.17 168.19,152.46 C380.1 169.13,152.91 169.32,152.91 v3(169.58,152.65) ; 167.17,140.41 167.95,139.62 168.3,139.62 R621.2 ; 167.17,140.41 v2(167.42,140.67)
SD_DAT1: length 21.8
  TOP w0.089: MEMCD1.8 167.29,153.85 167.86,153.28 169.44,153.28 v3(169.58,153.42)
  BOTTOM w0.089: v2(165.67,145.29) 166.03,145.29 ; 166.03,145.29 166.03,148.35 167.55,149.87 167.55,152.31 168.19,152.95 168.28,152.95 168.37,153.03 168.37,153.16 C376.1 168.75,153.42 v3(169.58,153.42) ; 166.03,145.29 166.03,141.34 166.03,141.06 167.81,139.28 168.28,139.28 R624.2
SD_DAT2: length 23.5
  TOP w0.102: MEMCD1.9 169.1,134.72 170.39,136.01 170.39,148.06 169.76,148.69 168.74,148.69 168.31,148.26 v1(168.31,146.69)
  BOTTOM w0.102: R604.2 169.01,146.94 C394.1 168.44,146.81 v1(168.31,146.69) 168.28,146.69 v2(167.65,147.32)
SD_DAT3: length 24.9
  TOP w0.102: MEMCD1.1 166.41,135.86 166.53,135.74 166.88,135.74 166.98,135.84 166.98,136.17 167.08,136.27 167.39,136.27 167.49,136.17 167.49,135.84 167.59,135.74 167.89,135.74 168,135.84 168,136.37 168.12,136.5 168.38,136.5 168.5,136.37 168.5,135.84 168.6,135.74 169.3,135.74 169.43,135.86 169.43,148.26 169.3,148.39 168.87,148.39 168.74,148.26 168.74,146.35 v1(168.31,145.92)
  BOTTOM w0.102: R608.2 C395.1 v1(168.31,145.92) v2(167.52,145.92)
SD_RCOMP: length 4.1
  TOP w0.203: CPU1.AB7 83.2,148.06 v1(83.4,148.26)
  BOTTOM w0.203: v1(83.4,148.26) 83.4,148.24 82.84,147.68 v2(82.84,146.94) 82.84,145.35 R610.1
SD_VDD2: length 5.3
  BOTTOM w0.203: U28.13 174.59,142.4
  BOTTOM w0.254: 174.59,142.4 174.59,142.04 v2(173.69,141.15) 173.39,140.84 C402.2 173.35,139.85 173.26,139.85 172.73,139.32 C404.1
SD_WAKE#_IC: length 7.8
  BOTTOM w0.102: U28.32 178.27,147.63 v2(178.47,147.83) 179.23,148.59 179.23,151.66 178.47,152.42 R586.2
SD_WAKE_N: length 174
  TOP w0.102: CPU1.B7 72.07,147.94 71.51,147.94 70.36,146.8 v3(70.36,146.26)
  L4 w0.127: v3(70.36,146.26) 72.21,144.41 72.21,141.69 73.02,140.88 73.02,135.77 75.3,133.5 75.91,133.5 87.58,121.82 112.74,121.82 125.72,108.84 145.86,108.84 150.78,103.92 152.25,103.92 152.94,104.61 152.94,108.68 154.94,110.68 154.94,119.44 165.86,130.35 165.86,148.42 168.57,151.13 v3(169.58,151.13)
  BOTTOM w0.102: R586.1 177.79,154.16 175.17,154.16 174.85,154.48 v2(172.37,154.48) 170.84,154.48 R579.2 170.09,153.73 170.09,151.64 v3(169.58,151.13)
SD_WP: length 15
  TOP w0.102: MEMCD1.10 171.58,155.66 175.39,151.86 v3(177.29,151.86)
  BOTTOM w0.102: v3(177.29,151.86) 177.29,152.84 v2(177.17,152.96) 176.31,152.1 R592.2
SDIN: length 4.6
  TOP w0.102: R414.2 56.17,53.47 v4(56.68,53.98) 56.68,54.44 57.97,55.74 SCA1.104
SDIN_1: length 4
  TOP w0.102: R414.1 56.09,51.8 56.09,50.77 v4(56.22,50.65) 56.78,50.65 v3(57.18,51.05)
  BOTTOM w0.102: v3(57.18,51.05) 56.93,51.05 56.29,50.42 U33.5
SDOUT: length 4.4
  TOP w0.102: R415.1 57.48,53.06 57.48,54.19 v4(58.07,54.79) 58.37,55.09 SCA1.105
SE_BJT_B1: length 5
  TOP w0.102: R104.2 v4(160.05,178.44) 160.31,178.18 162.34,178.18 162.62,178.46 162.62,178.93 162.99,179.3 U2.2
SE_BJT_B2: length 9.9
  TOP w0.102: R101.2 R98.1 C18.1 157.31,182.51 157.31,184.07 160,186.77 v4(160.03,186.77) 160.95,186.77 R97.2
SE_BJT_B3: length 2.7
  TOP w0.102: U2.5 160.66,179.3 v4(160.1,179.86) 159.7,179.45 R101.1
SE_VDDQ_EN: length 2.5
  BOTTOM w0.102: R539.1 123.54,205.93 v2(123.72,206.11) U27.4
SE_VPP_EN: length 74.8
  TOP w0.102: Q6.C 163.1,182.63 163.87,181.86 v3(164.12,181.86) 164.22,181.86 165.03,182.68 165.39,182.68 166,182.07 166,180.97 RN2.3
  L3 w0.127: v3(123.48,210.69) 126.87,214.08 136.29,214.08 144.25,206.12 146.6,206.12 148.08,204.65 155.56,204.65 161.83,198.37 161.83,195.07 164.82,192.09 164.82,182.56 v3(164.12,181.86)
  BOTTOM w0.102: v3(123.48,210.69) 123.25,210.92 v2(123.25,212.39) 123.45,212.6 R534.1
SE_VPP_EN_B: length 8.3
  TOP w0.102: U2.3 163.3,181.25 Q6.B ; U2.3 164.33,179.95 RN2.4 164.9,180.64 164.9,181.71 v4(165.23,182.04) ; U2.3 162.46,179.95 162.26,179.76 162.26,178.87 162.04,178.65 U2.6
SE_VTT_EN: length 10.4
  TOP w0.102: v3(78.47,210.25) 79.66,211.44 v4(79.66,211.84) 79.66,215.96 R51.2 R47.2 80.55,216.73 80.55,216.6 81,216.15 R48.2
  BOTTOM w0.102: R536.1 v3(78.47,210.25)
SENSE_A: length 24.9
  TOP w0.102: v3(165.51,60.07) 165.39,60.2 R376.2 ; v3(167.55,77.6) 167.09,78.05 166.35,78.05 166.15,77.85 U11.34
  L3 w0.127: v3(167.55,77.6) 167.08,78.07 166.59,78.07 166.31,77.79 166.31,75.29 166.44,75.16 166.44,73.49 167.38,72.55 167.38,67.64 166.92,67.18 165.51,65.78 v3(165.51,60.07)
  BOTTOM w0.102: v3(165.51,60.07) 165.51,60.88 v2(165.23,61.16)
SENSE_A_C: length 3.5
  TOP w0.102: Q38.D 165.39,64.96 v4(165.39,62.99) R376.1
SENSE_B: length 12.5
  TOP w0.102: U11.33 166.64,77.45 v3(166.78,77.6) ; v3(169.07,70.74) 169.45,71.12 169.45,71.44 R345.2 R346.2
  L3 w0.127: v3(169.07,70.74) 168.57,71.24 168.57,71.72 166.7,73.59 166.7,77.51 v3(166.78,77.6)
  BOTTOM w0.102: v3(166.78,77.6) v2(166.78,76.78)
SERIRQ_CPU: length 175.2
  TOP w0.089: 95.74,149.4 94.6,150.54 93.46,150.54 93.13,150.87 CPU1.AY11
  TOP w0.102: v3(140.88,103.5) 141.33,103.96 141.33,106.03 135.35,112.01 129.26,112.01 125.93,115.34 106.45,115.34 103.56,118.23 103.56,119.41 103.26,119.72 103.26,126.09 104.15,126.97 104.15,137.49 102.4,139.24 102.4,142.25 101.4,143.25 100.09,143.25 99.81,143.53 RN18.2 99.28,143.75 99.02,144.02 99.02,145.53 99.41,145.92 99.41,148.15 98.97,148.59 98.16,148.59 97.35,149.4 95.74,149.4 ; v3(114.59,62.74) 114.59,62.48 113.44,61.34 113.44,53.09 115.8,50.73 115.8,48.07 116.44,47.42 123.05,47.42 124.73,45.75 R436.2 124.91,44.83 R442.1
  L3 w0.127: v3(140.88,103.5) 140.37,103 139.7,103 139.09,102.38 139.09,100.3 139.19,100.2 139.19,96.14 138.88,95.83 138.88,77.01 133.57,71.69 130.86,71.69 128.56,69.39 128.56,66.31 125.62,63.37 115.22,63.37 v3(114.59,62.74)
  BOTTOM w0.102: v2(115.1,63.75) 115.1,63.25 v3(114.59,62.74)
SERIRQ_TPM: length 4.3
  TOP w0.102: R442.2 126.55,44.7 127.13,45.29 v4(127.13,45.31) 127.29,45.16 127.29,44.7 126.91,44.32 v3(126.86,44.32)
  BOTTOM w0.102: v3(126.86,44.32) 126.26,44.92 U34.27
SIDE_USB3_RX0+: length 10.1
  TOP w0.102: SSUSB1.6 174.12,114.05 174.02,113.95 173.66,113.95 173.08,114.54 169.09,114.54 168.96,114.67 U6.2 U6.9 167.1,114.67 166.97,114.54 166.51,114.54 166.26,114.28 165.84,114.28 165.6,114.51 L6.3
SIDE_USB3_RX0-: length 10.1
  TOP w0.102: SSUSB1.5 174.12,113.63 174.02,113.73 173.57,113.73 172.99,114.32 169.09,114.32 168.96,114.19 U6.1 U6.10 167.12,114.19 166.99,114.32 166.6,114.32 166.35,114.07 165.84,114.07 165.6,113.83 L6.2
SIDE_USB3_RX1+: length 11.8
  TOP w0.102: L10.3 165.48,95.46 165.71,95.23 166.21,95.23 166.46,95.49 166.84,95.49 166.97,95.62 U9.9 U9.2 168.84,95.62 168.97,95.49 169.67,95.49 170.49,94.67 170.49,93.7 170.98,93.22 173.01,93.22 173.78,92.45 174.02,92.45 174.12,92.55 SSUSB2.6
SIDE_USB3_RX1-: length 11.8
  TOP w0.102: SSUSB2.5 174.12,92.13 174.02,92.23 173.69,92.23 172.92,93 170.89,93 170.28,93.61 170.28,94.58 169.58,95.27 168.97,95.27 168.84,95.14 U9.1 U9.10 167,95.14 166.87,95.27 166.55,95.27 166.3,95.02 165.71,95.02 165.48,94.78 L10.2
SIDE_USB3_TX0+: length 12.5
  TOP w0.102: L5.3 165.6,116.67 165.84,116.44 166.28,116.44 166.66,116.06 166.99,116.06 167.12,116.19 U6.6 U6.5 168.96,116.19 169.09,116.06 170.32,116.06 171.23,116.97 171.23,118.62 171.61,119 172.63,119 173.57,119.95 174.02,119.95 174.12,120.05 SSUSB1.9
SIDE_USB3_TX0-: length 12.5
  TOP w0.102: L5.2 165.6,115.99 165.84,116.22 166.19,116.22 166.57,115.84 166.97,115.84 167.1,115.71 U6.7 U6.4 168.96,115.71 169.09,115.84 170.41,115.84 171.44,116.88 171.44,118.53 171.7,118.78 172.72,118.78 173.66,119.73 174.02,119.73 174.12,119.63 SSUSB1.8
SIDE_USB3_TX1+: length 10.7
  TOP w0.102: SSUSB2.9 174.12,98.55 174.02,98.45 173.33,98.45 172.94,98.06 171.04,98.06 169.97,96.99 168.98,96.99 168.84,97.14 U9.5 U9.6 166.99,97.14 166.86,97.01 166.53,97.01 166.14,97.39 165.71,97.39 165.48,97.62 L9.3
SIDE_USB3_TX1-: length 10.7
  TOP w0.102: SSUSB2.8 174.12,98.13 174.02,98.23 173.42,98.23 173.03,97.84 171.13,97.84 170.06,96.77 168.95,96.77 168.84,96.66 U9.4 U9.7 166.97,96.66 166.84,96.79 166.44,96.79 166.05,97.17 165.71,97.17 165.48,96.94 L9.2
SIO_EUP_EN: length 319
  TOP w0.102: v3(105.82,112.52) 105.82,113.3 101.78,117.34 101.11,118.01 97.35,118.01 96.89,118.47 92.62,118.47 92.24,118.85 D24.K
  L3 w0.127: v3(145.83,33.91) 139,33.91 137.99,34.92 137.1,34.92 134.3,37.72 131.32,37.72 129.16,35.56 125.86,35.56 123.73,33.43 123.73,29.49 122.2,27.97 112.63,27.97 104.29,36.3 104.29,38.82 108.3,42.84 117.22,42.84 118.08,41.97 125.93,41.97 128.09,44.13 128.09,47.36 129.29,48.56 132.58,48.56 135.11,51.1 v1(135.11,53.72) 135.2,53.81 135.2,54.12 136.81,55.73 136.81,55.74 139.72,58.64 139.72,65.59 140.18,66.05 140.18,68.8 141.45,70.07 141.45,72.34 144.05,74.95 144.05,84.91 147.44,88.3 147.44,97.07 v3(143.8,100.71)
  L4 w0.127: v3(143.8,100.71) 142.53,99.44 139.87,99.44 135.01,104.31 127.63,104.31 127.07,104.86 123.31,104.86 121.37,106.81 108.96,106.81 107.06,108.71 107.06,110.8 106.41,111.45 106.41,111.84 105.82,112.42 v3(105.82,112.52) 104.03,114.31 76.35,114.31 75.47,115.19 73.14,115.19 62.47,125.86 44.31,125.86 38.67,131.5 38.27,131.5 35.71,134.06 33.85,135.92 30.41,139.36 29.71,139.36 24.73,139.36 23.78,140.31 v3(23.78,141.97)
  BOTTOM w0.102: R771.2 135.92,54.8 v2(135.92,53.59) 135.24,53.59 v1(135.11,53.72) ; D23.K 24.8,142.98 v3(23.78,141.97) ; v3(145.83,33.91) 146.59,34.67 149.7,34.67 PR266.2 PR267.2
SIO_GPU_EN: length 194.4
  TOP w0.102: 73.63,117.03 72.17,118.49 v3(72.17,121.79) ; 73.63,117.03 R235.2 ; 73.63,117.03 73.63,117.45 74.28,118.1 74.96,118.1 75.54,117.53 75.59,117.53 76.23,116.88 76.23,116.46 76.49,116.2 Q21.5 ; CPU1.A6 71.37,147.53 70.75,146.91 70.75,146.48 70.8,146.43 70.8,146.08 70.01,145.29 69.12,145.29 68.49,144.65 68.49,143.51 67.09,142.11 67.09,140.05 66.16,139.12 62.59,139.12 v3(61.88,139.83) ; PR65.2 PR63.1 122.69,105.83 D2.K 122.5,106.49 v3(122.5,107.81) 134.16,107.81 v3(135.03,106.93) ; v3(103.54,81.28) 100.62,81.28 99.09,79.76 92.36,79.76 90.58,77.98 90.58,74.86 89.73,74.01 89.28,74.01 88.81,73.53 D6.K D5.K
  L3 w0.127: v3(107.63,110.49) 107.63,110.14 107.22,109.73 107.22,108.46 108.75,106.93 116.24,106.93 116.75,107.44 122.13,107.44 v3(122.5,107.81)
  L4 w0.127: v3(72.17,121.79) 72.17,119.32 75.92,115.57 77.91,115.57 78.91,114.57 104.44,114.57 106.4,112.62 106.4,112.22 106.66,111.96 106.66,111.56 107.63,110.59 v3(107.63,110.49)
  BOTTOM w0.102: v3(72.17,121.79) 72.4,122.02 72.4,125.04 63.48,133.96 63.32,133.96 61.88,135.4 v3(61.88,139.83) ; v3(103.54,81.28) 103.26,81.56 103.26,103.07 107.2,107.01 107.2,109.45 107.63,109.88 v3(107.63,110.49) ; v3(135.03,106.93) 135.42,106.55 v2(135.42,104.52) 135.42,103.5 136.3,102.62 136.3,95.28 PD2.K
SIO_GPU_RST: length 43.9
  TOP w0.102: v3(99.09,113.28) 99.31,113.5 100.77,113.5 101.14,113.13 U7.1 ; CPU1.AN7 88.27,147.93 v1(87.56,147.93)
  BOTTOM w0.102: v1(87.56,147.93) 88.02,147.47 88.02,146.97 88.4,146.59 88.4,146.12 89.54,144.98 89.54,140.13 88.86,139.45 88.86,130.4 91.12,128.14 91.12,127.12 99.09,119.15 v2(99.09,116.59) v3(99.09,113.28)
SIO_GREEN_PWM: length 135.3
  TOP w0.203: KBC1.16 136.74,47.06 v3(137.07,46.74)
  L4 w0.254: v3(23.15,10.41) 23.77,11.03 28,11.03 34.06,17.09 34.76,17.09 37.3,19.63 42.41,19.63 42.9,20.12 57.29,20.12 64.64,27.46 103.97,27.46 110.04,33.53 112.36,33.53 113.98,35.15 115.51,35.15 121.42,41.06 121.42,41.24 121.73,41.55 123.03,41.55 126.34,44.86 128.07,44.86 129.7,43.23 132.43,43.23 133.67,44.48 133.69,44.48 135.44,46.23 136.56,46.23 v3(137.07,46.74)
  BOTTOM w0.254: R863.2 24.35,9.78 v2(23.81,9.78) 23.78,9.78 v3(23.15,10.41)
SIO_HDD_LED: length 143.8
  TOP w0.102: v3(119.79,61.85) 120.05,61.59 120.05,60.92 121.43,59.54 121.61,59.54 121.88,59.27 126.57,59.27 126.72,59.13 127.18,59.13 128.01,58.3 KBC1.109
  L4 w0.127: v3(109.25,45.34) 109.21,45.38 96.85,45.38 93.8,42.33 89.28,42.33 87.24,44.36 72.49,44.36 72.26,44.13 69.76,44.13 59.66,34.04 53.59,34.04 49.25,29.69 46.74,29.69 46.11,29.06 45.02,29.06 42.83,26.87 42.83,23.97 41.72,22.86 39.34,22.86 38.62,22.14 30.98,22.14 29.37,23.75 27.34,23.75 v3(24.42,26.67)
  BOTTOM w0.102: v3(24.42,26.67) 24.58,26.67 25.52,27.6 25.52,28.83 25.52,28.84 R828.1 R826.2 ; v3(119.79,61.85) 119.26,61.32 110.6,61.32 107.02,57.73 107.02,47.57 v2(108.11,46.48) v3(109.25,45.34)
SIO_HDD_LED_1: length 3.5
  BOTTOM w0.102: R828.2 23.66,29.1 v2(23.66,28.45) 23.97,28.13 Q77.B
SIO_SMCLK0: length 181.3
  TOP w0.102: v3(39.4,20.7) 40.09,21.39 R499.2 ; Q36.6 149.67,68.21 150.1,67.79 150.1,67.37 148.69,65.96 146.06,65.96 144.58,67.44 144.58,68.15 143.98,68.76 142.54,68.76 141.89,68.11 141.89,66.88 v1(141.64,66.62) 142.34,65.92 KBC1.67
  L3 w0.127: v3(88.3,66.55) 86.22,64.47 v3(86.22,61.81)
  L4 w0.127: v1(141.64,66.62) 141.44,66.42 141.43,66.42 140.6,65.6 131.42,65.6 130.65,66.36 130.65,66.87 130.18,67.34 129.69,67.34 129,68.02 124.24,68.02 121.81,65.6 99.38,65.6 98.68,66.29 91.22,66.29 90.97,66.55 v3(88.3,66.55) ; v3(39.4,20.7) 39.91,21.21 45.2,21.21 48.17,24.17 48.17,26.54 53.26,31.64 61.16,31.64 64.61,28.19 90.97,28.19 v3(91.73,28.96)
  BOTTOM w0.102: v3(86.22,61.81) 86.22,59.76 87.89,58.09 87.89,41.81 91.27,38.43 91.27,33.2 v2(91.09,33.02) 91.09,29.59 v3(91.73,28.96) ; RN13.3 141.06,66.05 v1(141.64,66.62) ; Q60.6 85.55,65.55 86.55,66.55 v3(88.3,66.55)
SIO_SMDAT0: length 168.7
  TOP w0.102: KBC1.68 141.94,65.61 v1(141.64,65.91) 141.21,66.34 141.21,67.11 141.41,67.31 141.41,68.31 142.34,69.24 144.18,69.24 145.07,68.35 145.07,67.64 145.79,66.91 Q36.3 ; R498.2 39.07,21.26 v3(38.51,20.7)
  L4 w0.127: v3(89.82,65.66) 89.91,65.75 98.51,65.75 99.17,65.09 122.18,65.09 124.61,67.51 128.53,67.51 130.96,65.09 140.81,65.09 v1(141.64,65.91) ; v3(38.51,20.7) 39.53,21.72 44.99,21.72 47.66,24.38 47.66,26.75 53.05,32.14 61.37,32.14 64.82,28.7 90.71,28.7 v3(91.73,29.72)
  BOTTOM w0.102: v3(89.82,65.66) 88.41,64.25 Q60.3 86.7,59.96 88.37,58.29 88.37,42.01 91.75,38.63 v2(91.75,31.39) 91.75,29.74 v3(91.73,29.72) ; RN13.4 141.71,65.84 v1(141.64,65.91)
SIO_UART1_RX: length 73.1
  TOP w0.102: SCA1.50 60.77,73.24 v1(60.61,73.41) ; R394.1 123.93,57.67 123.35,57.67 122.68,58.34 122.16,58.34 121.42,59.08 120.65,59.08 119.03,60.69 119.03,61.09 v3(118.27,61.85)
  L4 w0.127: v1(60.61,73.41) 61.56,72.45 78.46,72.45 87.19,63.72 90.69,63.72 92.01,62.4 105.13,62.4 105.97,61.56 115.03,61.56 115.79,62.32 117.8,62.32 v3(118.27,61.85)
  BOTTOM w0.102: v3(118.27,61.85) 118.27,62.36 v2(118.01,62.62)
SIO_UART1_TX: length 72.4
  TOP w0.102: v1(61.37,73.41) 61.17,73.21 SCA1.49 ; v3(119.03,61.85) 119.54,61.34 119.54,60.51 120.74,59.31 121.52,59.31 122.25,58.57 R390.1
  L4 w0.127: v3(119.03,61.85) 118.31,62.57 115.68,62.57 114.92,61.81 106.07,61.81 105.24,62.65 92.11,62.65 90.79,63.97 87.3,63.97 78.56,72.71 62.07,72.71 v1(61.37,73.41)
  BOTTOM w0.102: v3(119.03,61.85) 119.03,62.41 v2(119.41,62.79)
SIO_YELLOW: length 147.1
  TOP w0.203: v1(146.08,56.39) 145.99,56.3 KBC1.47
  TOP w0.254: Q44.G 36.16,20.54 v3(35.69,20.07) 34.92,19.29 v4(34.55,19.29) ; Q44.G 37.59,20.99 R503.2 ; Q44.G 36.13,21.02 R502.2
  L4 w0.254: v1(146.08,56.39) 147.35,55.12 147.35,49.32 144.31,46.27 138.42,46.27 137.42,47.27 135.9,47.27 133.52,44.88 133.5,44.88 133.2,44.58 128.93,44.58 128.24,45.26 126.17,45.26 122.87,41.96 121.56,41.96 121.01,41.41 121.01,41.23 115.34,35.55 113.81,35.55 112.19,33.93 109.87,33.93 104.23,28.3 93.91,28.3 91.96,30.25 91.24,30.25 90.46,29.46 88.17,29.46 87.76,29.87 67.02,29.87 64.41,32.49 52.91,32.49 47.32,26.9 47.32,24.81 44.56,22.06 39.39,22.06 38.69,21.36 36.99,21.36 v3(35.69,20.07)
SKEW1: length 20.8
  TOP w0.102: R191.1 68.75,134.06 70.12,134.06 R192.2 70.61,133.58 72.78,133.58 73.44,132.92 v4(73.82,132.92) 74.73,132.92 74.99,133.17 74.99,134.68 78.62,138.31 78.62,138.52 79.87,139.77 79.87,143.08 80.42,143.64 80.42,144.61 CPU1.U1
SKEW2: length 23.4
  TOP w0.089: CPU1.U2 80.28,145.11 80.28,144.87 80.23,144.75 80.23,143.95 80.1,143.82
  TOP w0.102: R189.2 66.56,132.91 67.57,133.92 R190.1 68.32,134.65 70.47,134.65 71.23,133.88 74.33,133.88 v4(74.43,133.99) 74.53,134.08 74.53,134.55 78.39,138.41 78.39,138.62 79.64,139.86 79.64,143.36 80.1,143.82
SKEW3: length 25.6
  TOP w0.089: CPU1.U3 80.5,145.87 80.1,145.47 80.1,144.92 80.05,144.79 80.05,144.79 80.05,144.54 79.92,144.41
  TOP w0.102: 79.92,144.41 79.41,143.9 79.41,139.96 78.16,138.71 78.16,138.5 74.53,134.87 73.68,134.87 v4(73.34,134.53) 71.85,134.53 71.51,134.87 68.11,134.87 67.6,134.37 66.84,134.37 65.54,133.07 R188.2 64.96,132.91 R187.1
SKTOCC#: length 12
  TOP w0.102: TP29.1 71.14,191.52 70.09,190.46 70.09,187.48 70.11,187.46 70.11,182.82 71.39,181.55 CPU1.A65
SLEEVE: length 38.9
  TOP w0.203: v4(168.56,77.22) 168.4,77.05 U11.32
  TOP w0.762: Q25.D 169.51,86.93 v3(170.34,86.11) ; v3(176.06,84.45) 176.12,84.52 Q27.1 176.94,84.49 176.94,83.66 175.53,82.25 175.53,78.46 180.21,73.79 181.9,73.79 UHS1.4
  L3 w0.762: v3(170.34,86.11) 171.43,85.01 175.5,85.01 v3(176.06,84.45) 175.42,83.82 175.42,78.23 174.15,76.96 v5(171.99,76.96)
SLEEVE_G: length 33.9
  TOP w0.102: Q30.C 150.66,81.72 R293.1 151.73,82.3 R296.2 152.43,82.87 152.43,89.28 v3(151.42,90.3) ; v3(155.35,93.98) 155.91,93.42 v4(160.79,93.42) 160.82,93.4 165.59,93.4 167.61,91.38 Q25.G
  L3 w0.127: v3(151.42,90.3) 151.67,90.3 v3(155.35,93.98)
SLP_A_N: length 2.6
  TOP w0.102: v1(88.92,153.29) 88.6,153.61 CPU1.AN16
  BOTTOM w0.102: TP59.1 87.69,153.69 88.52,153.69 v1(88.92,153.29)
SLP_LAN_N: length 2.8
  TOP w0.102: v1(91.74,153.29) 92.35,153.29 CPU1.AW15
  BOTTOM w0.102: TP60.1 92.99,152.91 92.99,152.92 92.62,153.29 v1(91.74,153.29)
SLP_S0_N: length 153.2
  TOP w0.102: CPU1.AT11 90.55,151.14 v1(90.22,151.46) ; R158.1 22.73,139.7 24.8,139.7 v3(24.93,139.83)
  L4 w0.127: v3(24.93,139.83) 25.05,139.7 30.39,139.7 30.47,139.61 30.51,139.61 32.54,137.59 34.03,136.1 35.89,134.24 38.38,131.75 39.96,131.75 44.9,126.81 71.1,126.81 82.46,115.44 104.79,115.44 107.26,112.97 107.26,112.58 107.73,112.11 v3(107.73,112.01) ; v1(90.22,151.46) 90.64,151.04 91.23,151.04 91.39,151.2 92.31,151.2 94.78,148.72 94.78,147.35 107.65,134.48 v3(107.84,134.48)
  BOTTOM w0.102: v3(107.84,134.48) 108.09,134.22 109.57,134.22 v2(110.09,134.75) 110.94,133.89 110.94,126.27 108.45,123.77 107.82,123.77 105.09,121.05 105.09,114.91 107.27,112.72 107.27,112.47 v3(107.73,112.01)
SLP_S3_N: length 596.9
  TOP w0.102: R95.1 12.92,180.78 13.11,180.59 13.83,180.59 14.46,181.23 v3(14.51,181.23) ; R51.1 79.09,212.69 v3(78.49,212.09) ; v1(144.05,67.29) 144.69,66.65 KBC1.64 ; v3(65.31,76.96) 64.63,76.28 62.76,76.28 R328.2 ; v3(103.16,193.35) 103.16,193.29 118.4,178.05 v3(118.4,125.86) ; v1(89.57,152.37) 89.25,152.7 CPU1.AP15 ; R159.1 24.17,140.14 v3(24.49,140.46)
  L3 w0.127: v3(149.72,66.29) 150.85,65.16 150.85,44.51 146.17,39.84 146.17,34.58 146.46,34.29 146.46,33.02 146.08,32.64 139.19,32.64 137.73,34.1 125.57,34.1 124.66,33.19 124.66,31.05 126.27,29.43 126.27,16.48 124.75,14.96 v3(124.75,14.86)
  L4 w0.127: v3(149.72,66.29) 145.04,66.29 v1(144.05,67.29) 143.1,68.24 131.58,68.24 130.53,69.29 123.49,69.29 121.06,66.87 99.91,66.87 97.98,68.8 89.89,68.8 82.49,76.2 75.79,76.2 74.63,77.36 65.7,77.36 v3(65.31,76.96) ; v3(24.49,140.46) 24.49,143.6 22.84,145.25 21.06,145.25 19.59,146.72 19.59,160.58 15.68,164.49 15.68,164.64 15.49,164.83 15.49,178.12 14.41,179.2 14.23,179.2 13.91,179.51 13.91,180.66 14.48,181.23 v3(14.51,181.23) 14.51,183.69 13.88,184.32 13.88,185.45 14.65,186.22 14.65,186.63 14.64,186.64 14.64,200.66 12.26,203.03 12.26,223.72 16.59,228.05 69.92,228.05 74.2,223.77 74.2,216.38 v3(78.49,212.09) ; v1(89.57,152.37) 89.99,152.79 91.62,152.79 95.54,148.87 95.54,147.67 106.3,136.91 108.17,136.91 108.87,136.2 108.87,135.11 113.43,130.56 113.88,130.56 118.4,126.04 v3(118.4,125.86) 120,124.26 120,123.94 128.64,115.3 135.72,115.3 139.76,119.34 142.57,119.34 v3(143.42,118.49)
  BOTTOM w0.102: R861.2 122.4,11.56 122.52,11.68 124.11,11.68 124.75,12.32 v3(124.75,14.86) ; v3(103.16,193.35) 103.16,193.55 v2(102.14,194.56) 98.99,197.71 89.6,197.71 83.83,203.48 83.55,203.76 82.42,203.76 78.01,208.16 78.01,211.61 v3(78.49,212.09) ; v1(144.05,67.29) 144.91,68.15 144.91,80.8 146.26,82.14 146.26,86.26 144.84,87.68 144.84,104.93 144.25,105.51 144.25,117.65 v3(143.42,118.49)
SLP_S4_N: length 413.9
  TOP w0.102: 157.18,174.62 156.93,174.88 156.93,176.7 157.52,177.29 157.83,177.29 158.21,177.67 R104.1 ; 157.18,174.62 Q9.5 158.28,174.62 158.66,174.25 158.66,174.03 159.2,173.48 160.31,173.48 160.42,173.59 160.43,173.59 160.54,173.7 160.54,173.71 161.32,174.5 R109.1 ; 157.18,174.62 156.93,174.37 156.93,173.56 v3(157.28,173.2) ; CPU1.BA16 93.81,153.86 93.89,153.77 95.31,153.77 96.01,153.07 100.69,153.07 100.94,153.33 104.48,153.33 110.57,147.23 110.57,127.34 108.03,124.8 108.03,122.12 110.14,120.02 v3(110.14,118.75) ; R215.1 159.1,126.81 v1(157.89,128.02) ; R440.2 v3(139.48,43.56)
  L4 w0.127: v3(130.34,118.49) 130.8,118.96 132.38,118.96 136.89,123.47 153.35,123.47 v1(157.89,128.02) 156.92,128.99 156.92,150.81 156.62,151.11 156.62,172.54 v3(157.28,173.2) ; v3(139.48,43.56) 139.48,44.2 138.86,44.82 137.61,44.82 134.58,41.78 128.29,41.78 122.58,36.07 120.72,36.07 115.64,30.99 112.28,30.99 109.89,28.6 109.89,28.04 105.94,24.09 95.47,24.09 94.01,22.64 94.01,15.97 93.25,15.21 v3(93.25,14.73) ; v3(148.75,100.46) 146.61,100.46 142.25,104.81 137.19,104.81 135.92,106.08 134.62,106.08 133.85,106.86 124.42,106.86 112.72,118.55 112.72,118.61 112.11,119.21 110.61,119.21 v3(110.14,118.75)
  BOTTOM w0.102: U27.1 126.41,207.41 126.06,207.05 126.06,198.53 131.85,192.74 133.08,192.74 134.8,194.46 153.05,194.46 154.47,193.04 154.47,176.02 v3(157.28,173.2) ; R857.1 90.9,14.73 v3(93.25,14.73) ; v3(130.34,118.49) v2(116.11,118.49) 115.72,118.49 115.17,117.93 112.85,117.93 112.38,118.41 112.38,118.93 112.11,119.2 110.6,119.2 v3(110.14,118.75) ; v3(148.75,100.46) 149.21,100 149.21,92.46 149.11,92.35 149.11,87.63 149.17,87.57 149.17,76.82 148.37,76.02 148.37,63.27 148.6,63.04 148.6,52.99 148.75,52.84 148.75,51.05 149.18,50.62 149.18,44.7 149.59,44.3 149.59,43.47 146.76,40.64 144.56,40.64 142.65,42.55 140.5,42.55 v3(139.48,43.56)
SLP_S4_N_SIO: length 7
  TOP w0.102: v3(138.49,50.8) 138.49,50.8 138.74,50.55 KBC1.21 138.74,48.29 138.64,48.19 138.64,47.17 138.44,46.96 138.44,45.94 R439.1 R440.1
  BOTTOM w0.102: v3(138.49,50.8) 138.62,50.8 139.11,50.31 v2(139.14,50.31)
SLP_S5_N: length 158.4
  TOP w0.089: CPU1.AY16 92.98,153.56 93.58,153.56
  TOP w0.102: R439.2 137.9,45.58 137.9,47.25 v3(138.06,47.41) ; 93.58,153.56 95.11,153.56 95.79,152.88 101.02,152.88 101.28,153.14 104.17,153.14 110.22,147.09 110.22,127.49 107.68,124.95 107.68,121.96 109.38,120.26 v3(109.38,118.75)
  L3 w0.127: v3(120.56,111.51) 123.41,108.65 139.1,108.65 148.2,99.54 148.2,87.98 144.88,84.66 144.88,74.7 142.21,72.03 142.21,65.47 140.74,64 140.74,58.22 139.07,56.56 139.07,53.18 138.91,53.02 138.91,52.65 139.03,52.52 139.03,48.83 138.21,48.01 138.21,47.6 138.06,47.45 v3(138.06,47.41)
  BOTTOM w0.102: v3(109.38,118.75) 109.38,118.11 v2(110.27,117.22) 112.14,115.35 119.16,115.35 120.56,113.96 v3(120.56,111.51)
SLP_SUSB: length 405.5
  TOP w0.102: R133.1 14.7,154.37 v3(14.64,154.31) ; v1(88.92,152.37) 88.6,152.7 CPU1.AN15 ; v1(126.99,59.64) 127.36,59.27 127.94,58.7 KBC1.108 ; PR57.2 96.54,118.82 97.04,118.82 97.5,118.36 101.26,118.36 102.14,117.49 105.73,113.89 106.61,113.89 v3(107.73,112.78) ; v3(20.99,153.92) 20.53,153.47 20.53,151.08 20.8,150.81 PR42.1
  L3 w0.127: v3(145.83,33.15) 144.81,33.15 144.43,33.53 138.84,33.53 137.83,34.54 136.94,34.54 134.15,37.34 131.48,37.34 129.32,35.18 126.02,35.18 124.11,33.27 124.11,29.34 122.36,27.58 112.47,27.58 103.83,36.22 103.83,38.96 109.32,44.45 109.89,44.45 v3(110.02,44.58) ; v3(14.64,154.31) 20.61,154.31 v3(20.99,153.92)
  L4 w0.127: v3(142.4,118.49) 141.93,118.96 139.92,118.96 135.88,114.92 128.48,114.92 117.89,125.51 117.89,125.95 114.26,129.58 112.64,129.58 v3(111.79,130.43) 111.79,131.1 108.49,134.4 108.49,136.05 108.01,136.53 106.14,136.53 95.16,147.51 95.16,148.65 92.4,151.41 91.52,151.41 90.99,151.94 89.39,151.94 88.96,152.37 v1(88.92,152.37) ; v3(20.99,153.92) 20.11,153.05 20.11,146.74 21.18,145.67 22.96,145.67 28.55,140.08 30.64,140.08 30.64,140.08 31.51,140.08 34.11,137.48 34.11,136.76 38.74,132.13 40.12,132.13 44.88,127.37 71.08,127.37 82.61,115.84 105.05,115.84 107.73,113.16 v3(107.73,112.78)
  BOTTOM w0.102: v3(111.79,130.43) 111.79,124.17 110.98,123.36 107.9,123.36 105.44,120.9 105.44,115.06 107.72,112.78 v3(107.73,112.78) ; v3(142.4,118.49) 138.76,114.85 138.76,106.04 139.52,105.27 141.02,105.27 141.69,104.6 141.69,77.09 136.02,71.42 134.15,71.42 132.76,70.03 130.93,70.03 128.63,67.73 128.63,66.11 128.05,65.53 128.05,61.47 126.99,60.41 v1(126.99,59.64) 126.21,60.43 124.86,60.43 124.3,59.87 112.48,59.87 111.54,58.93 111.54,50.8 111.92,50.42 111.92,48.51 v2(111.54,48.13) 111.54,46.1 v3(110.02,44.58) ; PR272.2 PR271.2 145.96,33.02 v3(145.83,33.15)
SLP_SUSB_C: length 8.9
  TOP w0.152: R129.1 17.62,160.54 v4(17.56,160.6) 17.56,161.46 15.79,163.22 14.92,163.22 14.57,162.88 R125.2 14.57,160.85 14.88,160.54 Q12.6
SLP_SUSB_R: length 6.5
  TOP w0.152: R132.1 16.47,156.21 v4(17.03,156.77) 17.18,156.92 17.18,157.92 R131.1 ; R132.1 R133.2 ; R132.1 15.59,156.72 15.53,156.78 Q12.2
SLP_WLAN_N: length 4.2
  TOP w0.102: TP36.1 97.96,154.43 CPU1.BB17
SM_DRAMRST#: length 19
  TOP w0.102: v1(90.22,152.38) 90.55,152.05 CPU1.AT13
  BOTTOM w0.102: R603.1 R602.2 105.91,149.2 v2(98.2,149.2) 95.12,149.2 92.68,151.65 92.52,151.65 91.87,152.3 91.37,152.3 91.04,151.97 90.63,151.97 90.23,152.38 v1(90.22,152.38)
SM_DRAMRST#_R: length 143.5
  TOP w0.102: v3(140.88,164.97) 140.32,165.53 DIMM1.108 ; DIMM2.108 155.75,165.53 v3(156.01,165.26)
  L3 w0.127: v3(140.88,164.97) 141.13,164.72 151.42,164.72 151.99,165.29 155.98,165.29 v3(156.01,165.26)
  L4 w0.127: v3(156.32,143.99) 155.61,143.28 155.61,142.47 156.15,141.92 156.15,132.15 155.23,131.22 155.23,126.65 154.56,125.98 148.21,125.98 146.59,124.36 136.7,124.36 135.91,123.57 133.13,123.57 129.19,119.63 v3(128.94,119.63)
  BOTTOM w0.102: v3(156.01,165.26) 156.85,164.42 156.85,162.84 157.79,161.9 157.79,145.47 v3(156.32,143.99) ; v3(140.88,164.97) D15.1 C334.1 ; R603.2 106.9,147.76 106.33,147.19 102.88,147.19 101.81,146.12 101.81,144.96 103.71,143.05 111.49,143.05 114.08,140.46 114.08,127 v2(120.68,120.4) 121.45,119.63 v3(128.94,119.63)
SM_INTRUDER#: length 28.6
  TOP w0.102: v1(89.57,153.29) 89.25,153.61 CPU1.AP16
  L3 w0.127: v3(107.86,137.67) 93.89,151.64 93.89,152.04 92.21,153.71 90,153.71 v1(89.57,153.29)
  BOTTOM w0.102: v2(110.27,137.67) 109.95,137.35 R629.2 108.17,137.35 v3(107.86,137.67)
SM_RCOMP_0: length 3
  TOP w0.305: CPU1.AR18 89.57,154.98 v1(89.57,155.11)
  BOTTOM w0.305: v1(89.57,155.11) 89.55,155.13 R577.1 v2(87.49,155.93)
SM_RCOMP_1: length 6.6
  TOP w0.305: v1(90.22,155.12) 90.22,154.99 CPU1.AT18
  BOTTOM w0.305: R576.1 94.57,154.94 v2(94.52,154.99) 93.74,154.99 93.1,155.63 90.66,155.63 90.22,155.19 v1(90.22,155.12)
SM_RCOMP_2: length 4.9
  TOP w0.305: v1(90.87,155.12) 91.2,154.79 CPU1.AU18
  BOTTOM w0.305: R580.1 94.15,154.48 92.95,154.48 v2(92.49,154.94) 92.31,155.12 v1(90.87,155.12)
SMB0_CVT_CLK: length 6.1
  TOP w0.102: C248.1 38.01,23.44 v3(38.08,23.37) 38.56,22.89 39.31,22.89 39.31,22.89 39.64,22.89 R499.1
  BOTTOM w0.102: U36.6 37.55,24.46 38.08,23.93 v3(38.08,23.37) 38.54,23.37 v2(38.97,22.94)
SMB0_CVT_DATA: length 5.6
  TOP w0.102: R498.1 38.86,22.23 38.47,22.23 v3(37.32,23.38) 37.12,23.58 C247.1
  BOTTOM w0.102: v2(37.73,22.61) 37.32,23.01 v3(37.32,23.38) 36.73,23.97 U36.7
SMB_CLK_MAIN: length 384.3
  TOP w0.102: Q17.S 153.8,119.48 R224.2 151.41,121.86 151.41,124.88 150.69,125.6 149.39,125.6 147.81,127.18 147.45,127.18 147.36,127.28 DIMM2.253 145.62,127.28 145.44,127.46 144.24,127.46 143.97,127.19 143.97,125.04 v1(144.18,124.84) 143.7,124.36 136.65,124.36 136.23,124.78 136.23,124.87 133.92,127.18 132.25,127.18 132.16,127.28 DIMM1.253 ; v3(56.8,223.77) v4(55.84,222.81) 54.52,221.49 R32.2
  L3 w0.127: v3(154.85,200.41) 154.59,200.15 144.13,200.15 143.63,199.64 129.36,199.64 121.9,207.11 88.87,207.11 88.14,206.38 80.93,206.38 77.38,209.93 77.38,219.44 78.73,220.8 78.73,223.17 77.49,224.4 59.75,224.4 59.16,223.81 58.37,223.81 57.86,223.3 57.27,223.3 v3(56.8,223.77) ; v3(157.39,165.1) 156.88,164.59 156.88,164.13 156.92,164.09 156.92,131.78 154.34,129.2 154.34,127.73 153.67,127.06 150.85,127.06 149.74,125.95 145.29,125.95 v1(144.18,124.84) 142.53,126.49 131.86,126.49 131.48,126.11 119.82,126.11 118.27,127.67 108.27,127.67 107.8,128.14 102.58,128.14 v3(99.3,124.87)
  L4 w0.127: v3(78.36,57.43) 78.39,57.4 81.19,57.4 81.83,56.76 84.94,56.76 85.74,57.57 94.61,57.57 v3(95.16,57.02)
  BOTTOM w0.102: v3(157.39,165.1) 158.15,165.86 158.15,173.69 154.95,176.89 154.95,193.62 154.85,193.72 v3(154.85,200.41) ; v3(95.16,57.02) 95.16,59.44 102.55,66.83 102.55,110.02 100.28,112.28 100.28,117.32 99.58,118.03 99.58,119.35 99.3,119.63 v3(99.3,124.87) ; Q65.1 76.92,58.48 77.16,58.72 77.76,58.72 78.39,58.09 78.39,57.47 v3(78.36,57.43)
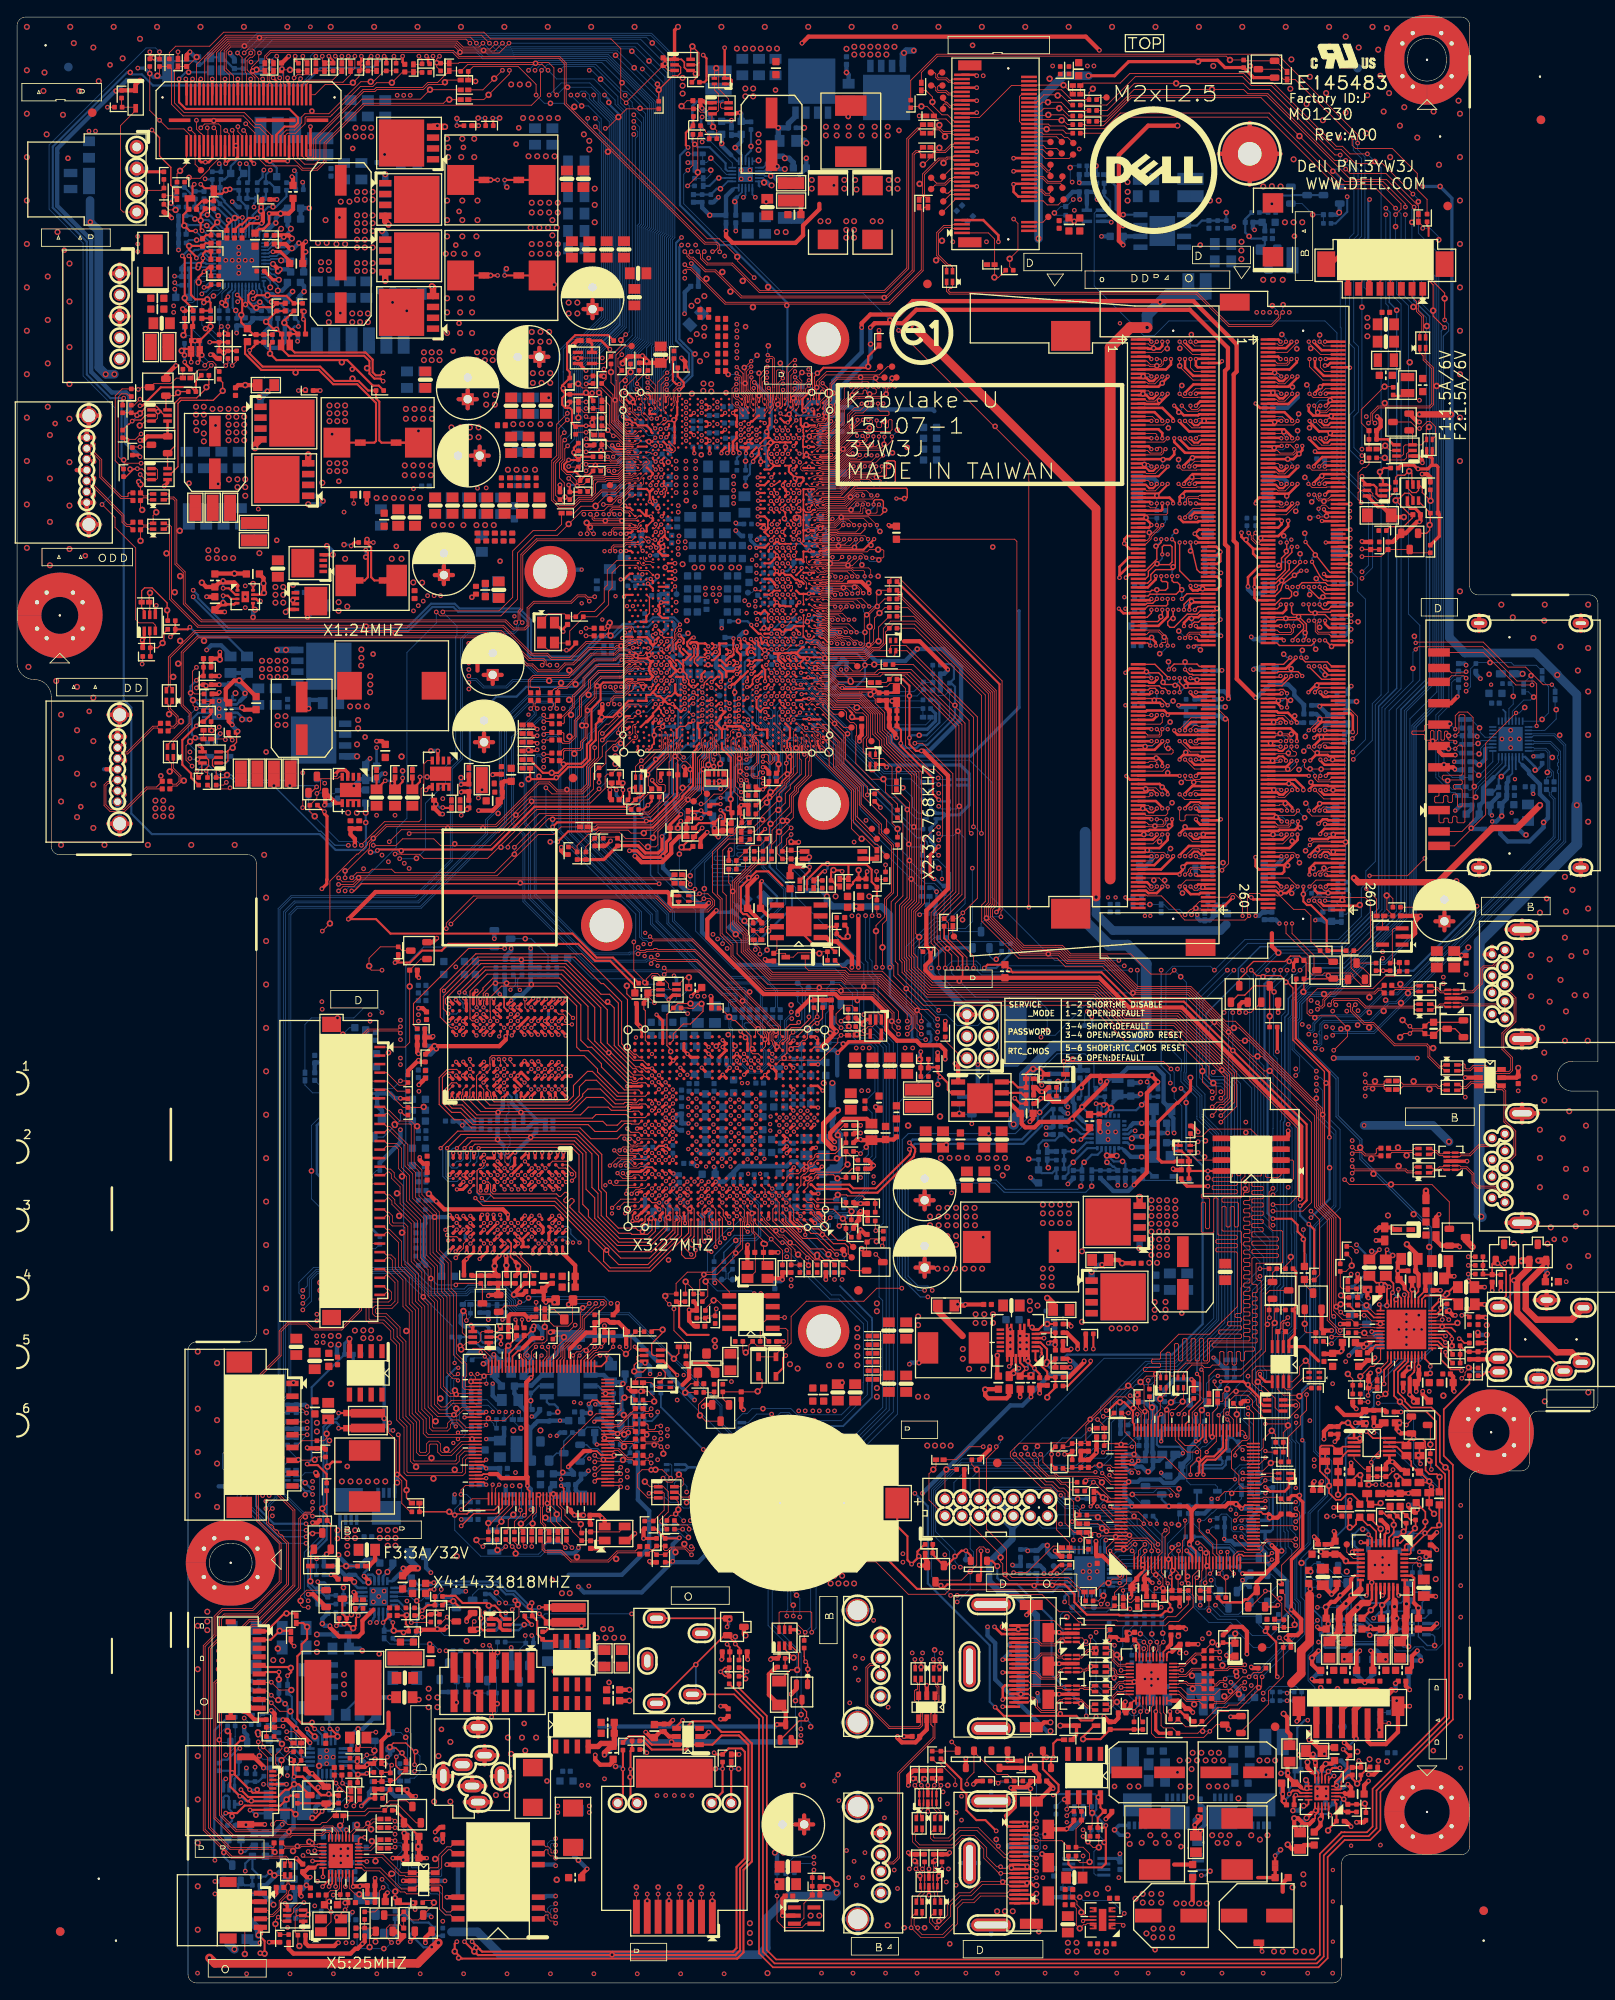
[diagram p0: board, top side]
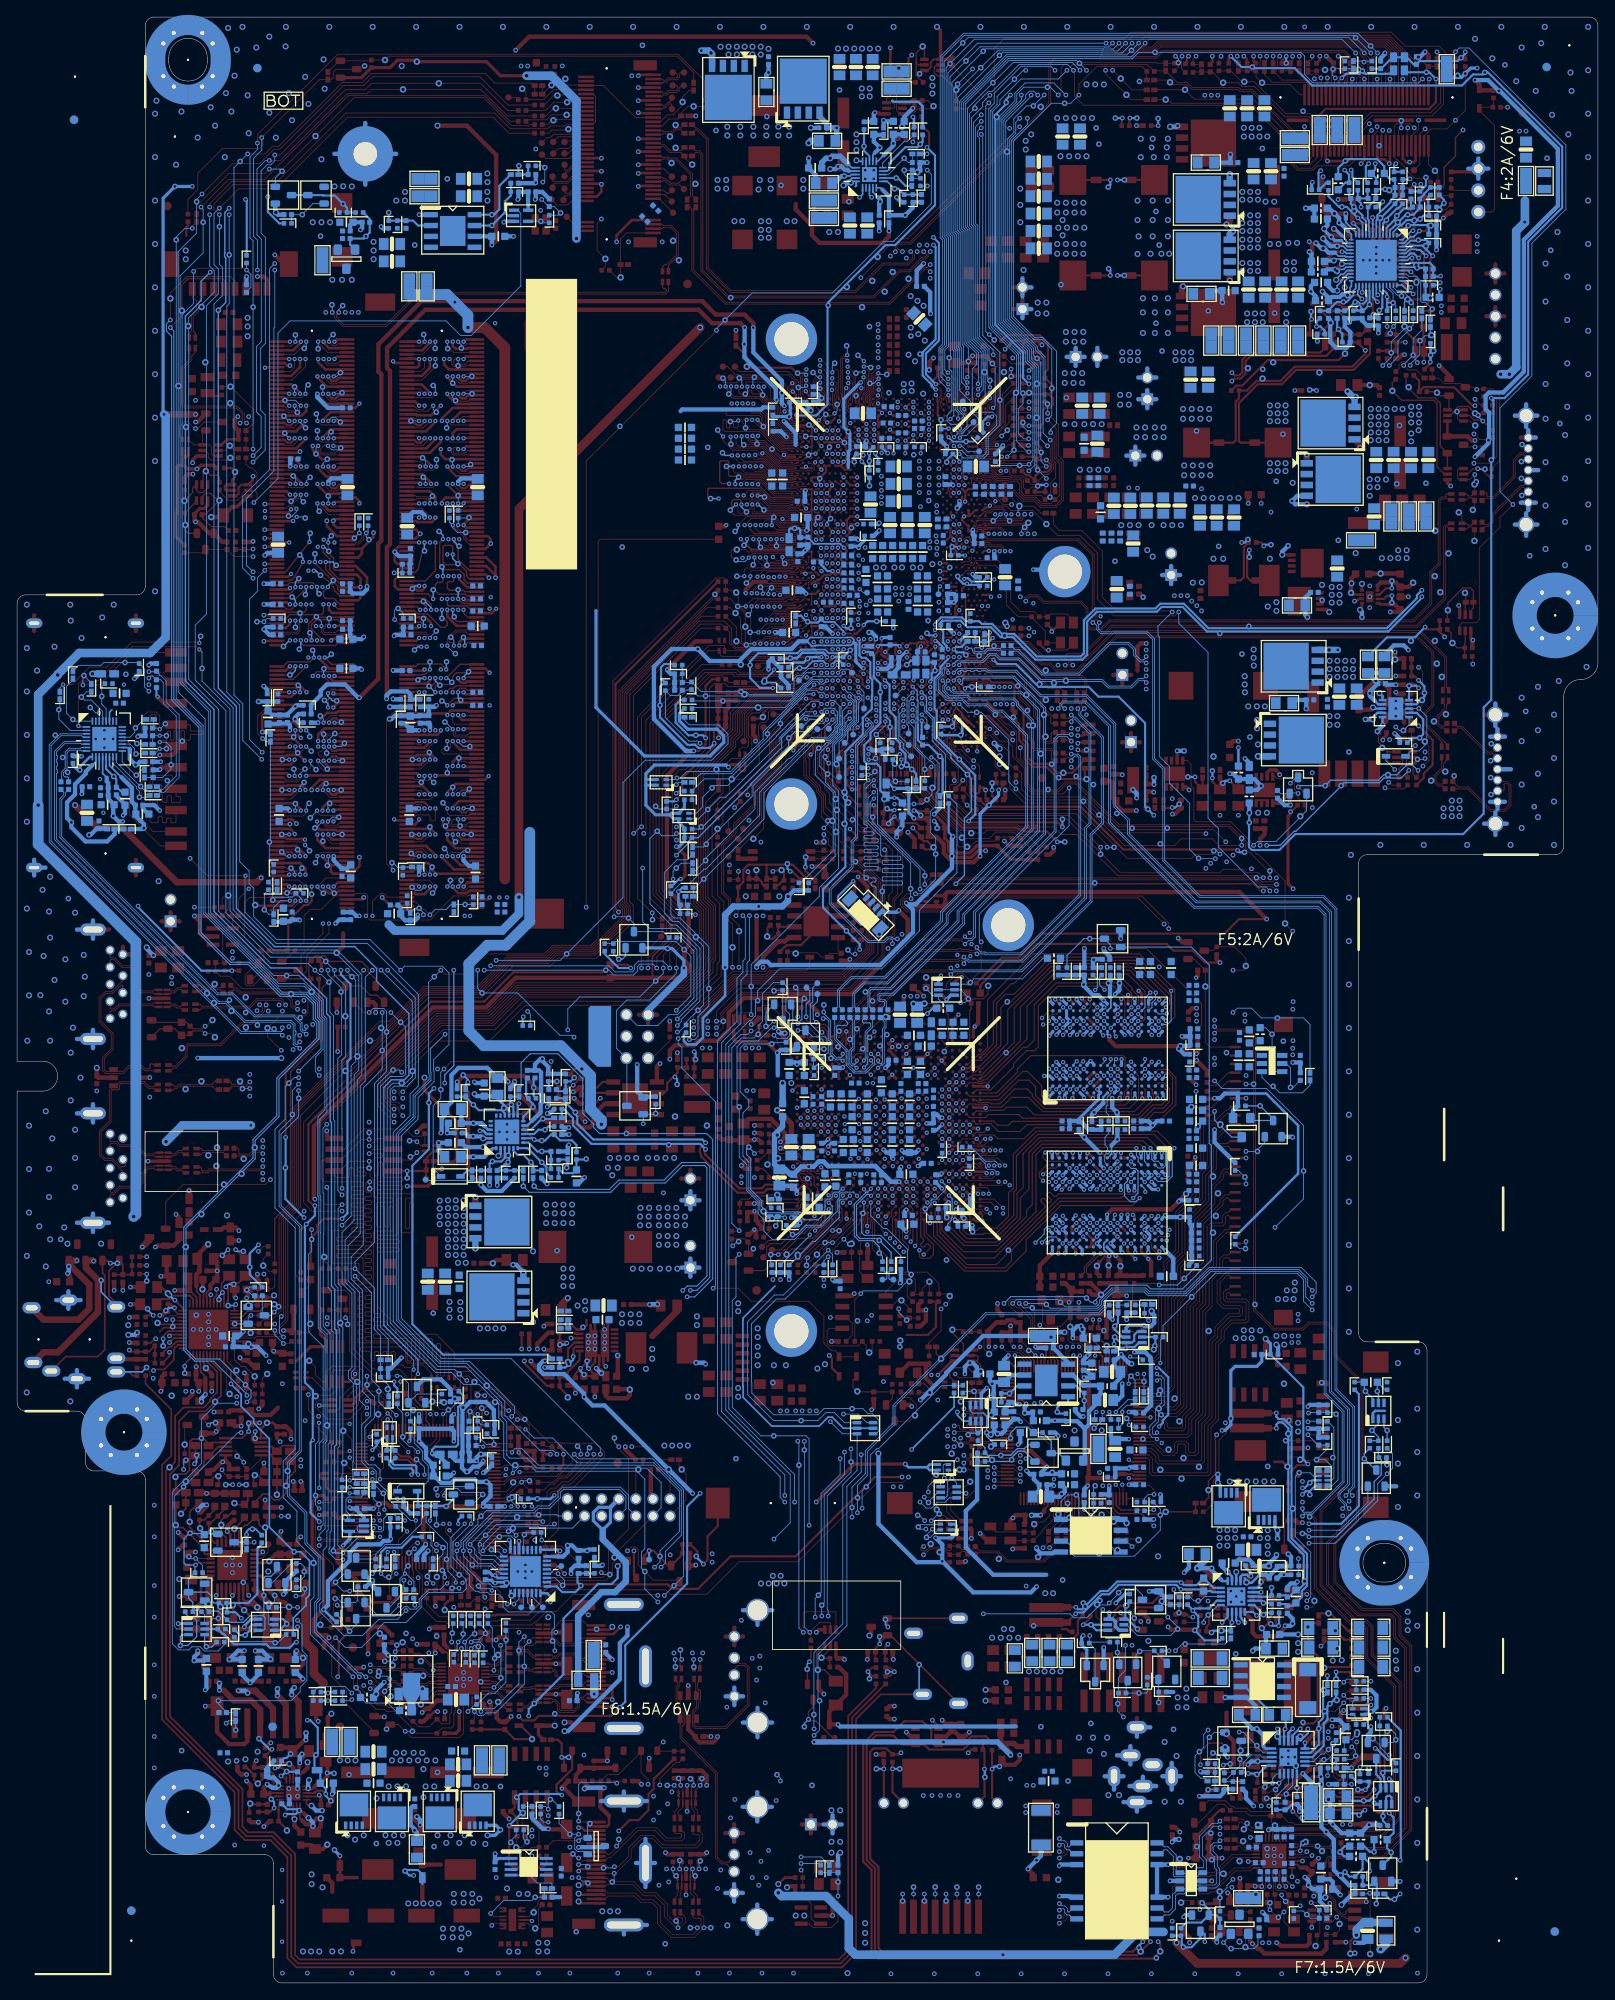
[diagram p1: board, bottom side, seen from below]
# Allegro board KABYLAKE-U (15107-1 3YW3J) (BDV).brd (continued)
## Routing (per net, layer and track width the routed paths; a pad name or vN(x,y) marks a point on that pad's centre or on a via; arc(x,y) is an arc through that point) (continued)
SMB_CLK_RESUME: length 235.3
  TOP w0.102: v1(80.19,148.29) 79.97,148.06 CPU1.R7 ; v3(154.85,213.87) 154.23,213.87 146.58,221.52 144.23,221.52 143.5,222.25 v4(135.64,222.25) 130.76,222.25 127.58,219.07 R41.1 ; v3(100.87,124.87) 100.62,125.12 R213.2 ; Q17.D 151.77,118.83 151.77,120.21 149.21,122.78 v1(149.21,123.95)
  L3 w0.127: v3(100.87,124.87) 102.65,126.65 115.73,126.65 117.29,125.09 131.1,125.09 132.62,123.57 145.32,123.57 146.46,124.71 148.95,124.71 149.21,124.46 v1(149.21,123.95) 149.59,123.57 155.34,123.57 156.94,125.17 156.94,129.93 158.02,131.01 158.02,177.29 v3(157.39,177.93)
  L4 w0.127: v1(80.19,148.29) 80.62,147.86 80.62,147.32 78.99,145.68 78.99,140.51 78.3,139.82 78.3,134.15 88.12,124.33 100.34,124.33 v3(100.87,124.87)
  BOTTOM w0.102: v3(154.85,213.87) 154.85,213.19 155.31,212.72 155.74,212.72 156.45,212.01 156.45,204.72 155.94,204.22 155.94,191.81 156.5,191.25 156.5,184.01 155.96,183.47 155.96,179.35 v3(157.39,177.93)
SMB_DATA_MAIN: length 380.7
  TOP w0.102: Q18.S 157.45,117.41 156.12,118.75 156.12,120.46 R225.2 156.88,120.78 158.4,122.3 158.4,126.36 157.77,127 154.63,127 DIMM2.254 153.27,127.03 153.25,127.05 151.61,127.05 151.18,126.62 v1(151.16,126.62) ; DIMM1.254 141.65,127.03 142.08,127.46 142.46,127.46 143.42,126.5 v1(143.42,124.84) ; R35.2 54.62,220.34 v4(55.18,220.9) 57.61,223.34 v3(57.61,223.77)
  L3 w0.127: v3(57.61,223.77) 58.16,224.32 58.95,224.32 59.54,224.91 77.7,224.91 79.24,223.38 79.24,220.58 77.88,219.23 77.88,210.14 81.14,206.88 87.93,206.88 88.66,207.61 122.11,207.61 129.57,200.15 143.42,200.15 143.92,200.66 154.34,200.66 v3(154.85,201.17) ; v3(157.39,164.34) 157.42,164.3 157.42,131.57 154.85,128.99 154.85,127.52 153.5,126.17 151.61,126.17 v1(151.16,126.62) 149.97,125.43 146.15,125.43 145.12,124.4 143.86,124.4 v1(143.42,124.84) 142.27,125.98 132.07,125.98 131.69,125.6 119.61,125.6 118.06,127.16 102.35,127.16 v3(100.06,124.87)
  L4 w0.127: v3(79.33,56.26) 79.54,56.26 79.54,56.25 85.15,56.25 85.95,57.06 94.36,57.06 v3(95.16,56.26)
  BOTTOM w0.102: Q65.4 75.89,56.75 76.41,56.24 77.3,56.24 77.99,55.55 78.62,55.55 v3(79.33,56.26) ; v3(95.16,56.26) 95.69,56.8 95.69,59.21 103.03,66.55 103.03,110.22 100.76,112.48 100.76,117.52 100.06,118.23 100.06,119.55 99.78,119.83 99.78,124.59 v3(100.06,124.87) ; v3(154.85,201.17) 155.46,200.56 155.46,177.06 158.63,173.89 158.63,165.58 v3(157.39,164.34)
SMB_DATA_RESUME: length 250
  TOP w0.102: v1(148.5,123.95) 148.5,122.81 151.1,120.21 151.1,118.42 151.59,117.93 152.76,117.93 152.99,118.16 156.1,118.16 156.33,117.94 156.33,117.74 157.4,116.66 158.07,116.66 158.29,116.89 158.29,117.94 157.49,118.75 157.32,118.75 Q18.D R228.2 ; CPU1.R8 79.97,148.71 v1(80.21,148.96) ; v3(155.48,213.23) 154.18,213.23 146.38,221.04 144.03,221.04 143.53,221.54 v4(139.83,221.54) 130.73,221.54 127.63,218.44 R44.1
  L3 w0.127: v3(157.39,178.69) 158.53,177.55 158.53,130.8 157.45,129.72 157.45,124.96 155.55,123.07 149.26,123.07 148.5,123.83 v1(148.5,123.95) 147.61,123.07 131.86,123.07 130.34,124.59 117.07,124.59 115.52,126.14 104.46,126.14 102.7,124.38 98.67,124.38 98.61,124.33 98.2,124.33 v3(97.7,124.84)
  L4 w0.127: v1(80.21,148.96) 80.21,148.93 80.84,148.3 80.84,147.23 79.5,145.88 79.5,140.3 78.81,139.61 78.81,134.36 88.21,124.97 97.57,124.97 v3(97.7,124.84)
  BOTTOM w0.102: v3(155.48,213.23) 155.91,213.23 156.93,212.21 156.93,204.52 156.42,204.02 156.42,192.01 156.98,191.45 156.98,183.81 156.45,183.27 156.45,179.63 v3(157.39,178.69)
SMBUS_ISP: length 87.7
  TOP w0.102: v3(78.84,56.84) 77.79,56.84 77.23,57.4 Q39.5 ; v1(140.5,56.64) 141.35,57.5 KBC1.50 ; v3(73.95,57.28) 74.07,57.4 Q39.2 75.6,57.4 75.73,57.28 75.73,55.31 R400.2 R393.1
  L4 w0.127: v3(73.95,57.28) 77.34,57.28 77.77,56.84 v3(78.84,56.84) 78.86,56.82 78.86,56.07 79.14,55.79 80.46,55.79 80.67,56 87.76,56 88.68,55.08 89.88,55.08 90.08,55.28 93.9,55.28 94.11,55.08 106.15,55.08 107.46,53.78 121.13,53.78 123.57,56.21 138.41,56.21 139.29,57.09 140.05,57.09 v1(140.5,56.64)
  BOTTOM w0.102: Q39.5 77.23,57.4 78.34,56.29 v2(78.34,56.2) 78.84,56.69 v3(78.84,56.84) ; Q39.2 74.07,57.4 v3(73.95,57.28)
SML0_CLK: length 21
  TOP w0.102: v1(80.19,149.65) 79.95,149.65 CPU1.R9 ; v3(80.04,137.94) 80.42,137.94 81.57,139.09 82.48,139.09 83.24,139.86 83.24,140.93 RN4.5
  BOTTOM w0.102: v3(80.04,137.94) 79.01,137.94 v2(78.52,138.43) 77.93,139.01 77.93,139.42 77.58,139.77 77.58,142.47 78.09,142.98 78.18,142.98 79.84,144.64 79.84,147.41 79.8,147.45 79.8,147.95 79.79,147.96 79.79,149.24 v1(80.19,149.65)
SML0_DATA: length 4.2
  TOP w0.089: CPU1.W2 81.83,145.1 82.13,144.8 82.13,144.57
  TOP w0.102: RN4.6 82.07,142.44 v4(82.28,142.65) 82.28,143.61 82.13,143.77 82.13,144.57
SML1_CLK: length 5.7
  TOP w0.089: CPU1.W3 81.78,145.93 81.61,145.71 81.61,145.54 81.57,145.43 81.57,145.23 81.6,145.16 81.6,144.87 81.55,144.75 81.55,144.44 81.29,144.18 81.29,143.35 v1(81.52,143.13)
  TOP w0.102: RN4.7 81.57,143.07 v1(81.52,143.13)
  BOTTOM w0.102: v2(81.52,142.32) v1(81.52,143.13)
SML1_DATA: length 5.2
  TOP w0.089: CPU1.V3 81.42,146.05 81.42,145.57 81.39,145.47 81.39,145.19 81.42,145.12 81.42,144.92 81.38,144.79 81.38,144.79 81.38,144.54 81.36,144.5 81.05,144.19 81.05,143.31
  TOP w0.102: 81.05,143.31 81.05,142.66 v4(80.91,142.52) 80.92,142.51 RN4.8
SNB: length 3.3
  BOTTOM w0.508: C574.1 38.84,40.69 R804.2 40.14,39.12 v2(40.39,38.86)
SO_1: length 9.7
  TOP w0.102: v4(58.35,50.24) 58.33,50.27 58.33,50.67 v3(57.95,51.05) 57.18,51.82 R415.2
  BOTTOM w0.102: v3(57.95,51.05) 58.83,50.16 61.02,50.16 61.53,50.67 61.53,52.6 61.88,52.96 62.83,52.96
SP1: length 7.3
  BOTTOM w0.089: U28.15 173.79,142.71 171.04,139.96 171.04,139.77 170.7,139.43 v2(170.7,138.73) 170.64,138.68 169.77,138.68 R624.1
SP2: length 6
  BOTTOM w0.089: R621.1 169.9,139.57 170.13,139.57 v2(170.53,139.98) 170.57,139.98 173.38,142.8 U28.16
SP3: length 4.8
  BOTTOM w0.102: U28.17 172.7,142.88 171.12,141.3 v2(171.05,141.3) 170.43,141.92 R616.1
SP4: length 3.5
  BOTTOM w0.102: U28.19 171.77,144.94 171.28,144.45 171.28,143.98 v2(171.09,143.8) 170.12,143.8 R611.1
SP5: length 2.9
  BOTTOM w0.102: U28.20 171.31,145.34 v2(170.98,145.01) 170.87,144.91 R608.1
SP6: length 3.9
  BOTTOM w0.102: U28.21 171.79,145.74 171.23,146.3 171.23,146.76 v2(171.15,146.84) 170.16,147.83 R604.1
SP7: length 5.8
  BOTTOM w0.102: U28.29 174.98,148.77 176.31,150.09 177.12,150.09 v2(177.48,150.44) 176.86,151.07 R592.1
SP_PLLVDD: length 15.1
  TOP w0.381: GPU1.M6 90.01,98.71 v1(90.08,98.71) 90.08,98.74 GPU1.N6
  TOP w0.508: v3(95.66,98.4) 95.16,98.91 95.16,99.45 95.38,99.68 95.38,99.71 96.77,101.09 99.42,101.09 C96.1
  L3 w0.508: v1(90.08,98.71) 92.45,98.71 92.76,99.02 94.15,99.02 94.77,98.4 v3(95.66,98.4)
  BOTTOM w0.381: C500.1 90.56,98.23 v1(90.08,98.71)
  vias: v4(104.27,100.3)
SPDIF_IC: length 112.8
  TOP w0.102: SCA1.37 65.97,72.85 67.54,74.42 v1(67.6,74.42) ; U11.16 161.59,72.91 160.46,71.78 160.46,69.24 v4(160.13,68.91) 159.8,68.58 v3(159.29,68.58)
  L4 w0.127: v3(159.29,68.58) 159.29,68.48 159.76,68.01 159.76,67.62 159.55,67.41 159.55,64.13 158.3,62.88 155.68,62.88 154.21,64.35 149.76,64.35 144.51,64.35 144.22,64.64 141.85,64.64 141.53,64.33 130.42,64.33 129.83,64.92 126.12,64.92 126.1,64.94 126.03,64.94 125.76,65.21 125.27,65.21 124.32,64.26 91.22,64.26 91,64.48 88.98,64.48 85.89,67.58 85.89,68.74 81.22,73.41 69.62,73.41 69.18,73.85 68.17,73.85 v1(67.6,74.42)
SPEAKER1_L1: length 15.2
  TOP w0.203: C180.1 157.13,56.29 156.23,57.19 155.62,57.19 154.95,56.52 154.34,56.52 153.53,57.33 153.53,58.16 v4(153.53,58.17) 153.53,58.17 153.53,58.82 152.46,59.89 152.46,62.67 152.65,62.87 153.93,62.87 R373.2 155.13,62.74 U13.3
SPEAKER1_R1: length 12
  TOP w0.203: U13.9 162.22,63.24 R369.2 162.59,63.12 163.03,63.56 163.47,63.56 163.54,63.63 164.49,63.63 164.78,63.34 164.78,62.74 164.83,62.69 164.83,59.97 165.26,59.54 166.14,59.54 v4(166.47,59.2) 166.43,59.16 C176.1
SPEED_100*_CON: length 7.4
  TOP w0.254: R894.2 v3(70.9,25.02) 70.9,21.66 RJ1.12
  BOTTOM w0.254: v2(70.04,25.32) 70.59,25.32 v3(70.9,25.02)
SPEED_100_N: length 101.1
  TOP w0.203: v3(35.76,11.28) 36.48,12 U23.25
  TOP w0.254: v3(51.47,4.83) 51.21,4.57 v4(51.21,3.68) 52.05,2.84 84.28,2.84 85.01,3.57 85.01,13.23 85.98,14.2 85.98,28.02 84.64,29.36 82.43,29.36 81.19,30.61 79.03,30.61 78.01,29.59 78.01,28.19 77.69,27.88 U20.6 74.26,27.88 73.29,28.85 71.62,28.85 R894.1
  L4 w0.254: v3(51.47,4.83) 51.22,4.83 49.77,6.27 46.34,6.27 42.3,10.31 42.3,11.02 40.67,12.65 37.13,12.65 v3(35.76,11.28)
SPEED_1000*_CON: length 8.6
  TOP w0.254: RJ1.11 71.79,21.82 v3(71.79,25.02) 71.79,27.11 R895.2 R893.2
  BOTTOM w0.254: v2(71.74,24.08) 71.74,24.97 v3(71.79,25.02)
SPEED_1000_N: length 93.7
  TOP w0.203: v3(36.52,11.28) 36.88,11.64 U23.26
  TOP w0.254: R893.1 73.25,28.32 74.26,27.3 78.27,27.3 78.84,27.88 U20.1 81.38,27.88 82.46,28.96 84.47,28.96 85.58,27.85 85.58,14.37 84.6,13.39 84.6,3.8 84.06,3.25 53.93,3.25 v4(53.51,3.67) v3(52.36,4.83)
  L4 w0.254: v3(36.52,11.28) 37.48,12.24 40.5,12.24 41.89,10.85 41.89,10.14 46.17,5.87 49.6,5.87 51.18,4.29 51.82,4.29 v3(52.36,4.83)
SPI_CLK: length 185.7
  TOP w0.102: RN7.4 133.82,71.43 133.72,71.53 131.94,71.53 131.81,71.66 131.81,71.89 131.94,72.01 133.72,72.01 133.82,72.11 133.82,72.39 133.72,72.49 132.88,72.49 132.75,72.62 132.75,72.85 132.88,72.98 133.72,72.98 133.82,73.08 133.82,73.77 135.95,75.9 139.57,75.9 142.8,79.12 142.8,85.39 142.65,85.53 140.42,85.53 140.29,85.66 140.29,85.89 140.42,86.01 142.67,86.01 142.8,86.14 142.8,86.37 142.65,86.51 140.42,86.51 140.29,86.64 140.29,86.87 140.42,87 142.67,87 142.8,87.12 142.8,87.35 142.67,87.48 140.65,87.48 140.52,87.6 140.52,91.72 140.39,91.85 140.16,91.85 140.04,91.72 140.04,87.86 139.94,87.76 138.74,87.76 138.59,87.91 138.59,91.22 138.72,91.35 138.95,91.35 139.07,91.22 139.07,88.37 139.2,88.24 139.43,88.24 139.56,88.37 139.56,91.71 139.43,91.83 138.69,91.83 138.59,91.93 138.59,92.2 138.72,92.33 142.67,92.33 142.8,92.46 142.8,92.68 142.67,92.81 139.96,92.81 139.86,92.91 139.86,93.19 139.96,93.29 142.67,93.29 142.8,93.42 142.8,93.65 142.67,93.78 139.99,93.78 139.86,93.9 139.86,94.13 139.99,94.26 142.12,94.26 142.25,94.39 142.25,95.94 142.37,96.06 142.6,96.06 142.73,95.94 142.73,94.56 142.86,94.44 143.09,94.44 143.21,94.56 143.21,96.42 143.09,96.55 142.37,96.55 142.27,96.65 142.27,96.93 142.37,97.03 v3(143.8,97.03) 143.29,97.54 SRCON1.6 ; v3(103.16,112.52) 103.16,113.66 100.44,116.38 96.68,116.38 96.22,116.84 87.83,116.84 84.26,120.41 84.26,121.69 82.99,122.96 82.99,127.23 82.58,127.64 82.58,132.53 83.41,133.35 84.5,133.35 84.54,133.31 85.28,133.31 R183.1
  L4 w0.127: v3(103.16,112.52) 102.18,111.54 102.18,109.37 108.56,103 123.35,103 123.99,102.36 134.27,102.36 136.41,100.23 136.41,97.43 137.88,95.96 138.34,95.5 144.18,95.5 144.43,95.76 144.43,96.39 v3(143.8,97.03)
  BOTTOM w0.102: v3(103.16,112.52) v2(102.34,112.52)
SPI_CLK_CPU: length 14.1
  TOP w0.089: CPU1.AV2 91.8,145.07 91.57,144.84 91.57,143.28 91.77,143.07 91.77,141.42
  TOP w0.102: R183.2 86.33,134.68 88.88,137.24 v4(89.09,137.24) 89.9,138.05 89.9,139.15 90.48,139.73 90.48,140.13 91.77,141.42
SPI_CS0_N: length 189.7
  TOP w0.102: RN7.3 134.47,73.66 134.6,73.79 134.83,73.79 134.96,73.66 134.96,71.12 135.08,70.99 135.31,70.99 135.44,71.12 135.44,74.7 135.54,74.8 135.82,74.8 135.92,74.7 135.92,72.9 136.05,72.77 136.28,72.77 136.41,72.9 136.41,75.29 136.53,75.41 136.81,75.41 136.91,75.31 136.91,72.87 137.01,72.77 137.29,72.77 137.39,72.87 137.39,75.31 137.5,75.41 137.78,75.41 137.88,75.31 137.88,72.87 137.98,72.77 138.26,72.77 138.36,72.87 138.36,75.31 138.46,75.41 138.74,75.41 138.84,75.31 138.84,72.87 138.94,72.77 139.22,72.77 139.32,72.87 139.32,75.31 139.43,75.41 139.77,75.41 143.16,75.41 143.29,75.54 143.29,75.81 143.19,75.92 140.75,75.92 140.62,76.04 140.62,76.26 140.76,76.4 143.19,76.4 143.29,76.5 143.29,76.78 143.19,76.88 141.77,76.88 141.64,77.01 141.64,77.24 141.77,77.36 143.19,77.36 143.29,77.47 143.29,77.74 143.19,77.85 142.65,77.85 142.53,77.97 142.53,78.17 142.69,78.33 143.19,78.33 143.29,78.43 143.29,87.83 143.16,87.96 141.13,87.96 141,88.09 141,90.73 141.13,90.86 141.36,90.86 141.49,90.73 141.49,88.57 141.61,88.44 141.84,88.44 141.97,88.57 141.97,90.73 142.1,90.86 142.32,90.86 142.45,90.73 142.45,88.57 142.58,88.44 142.81,88.44 142.93,88.57 142.93,91.21 142.81,91.34 141.13,91.34 141,91.47 141,91.72 141.13,91.85 143.19,91.85 143.28,91.94 143.28,93.95 143.7,94.36 143.7,95.28 143.8,95.38 145.05,95.38 145.16,95.28 145.16,95 145.05,94.89 144.31,94.89 144.18,94.77 144.18,94.54 144.31,94.41 145.54,94.41 145.64,94.51 145.64,95.25 145.77,95.38 145.99,95.38 146.12,95.25 146.12,94.36 146.25,94.23 147.61,94.23 147.92,94.55 U8.1 SRCON1.1 147.23,95 146.08,96.14 v3(143.8,96.14) ; v3(103.16,111.76) 102.63,112.29 102.63,113.51 100.24,115.9 96.48,115.9 96.02,116.36 87.63,116.36 83.78,120.21 83.78,121.49 82.51,122.76 82.51,126.82 81.95,127.38 81.95,132.57 83.21,133.83 84.7,133.83 R182.2
  L4 w0.127: v3(143.8,96.14) 138.56,96.14 136.91,97.78 136.91,100.44 134.32,103.03 127.1,103.03 126.54,103.59 122.78,103.59 120.88,105.5 119.73,105.5 119.28,105.05 107.22,105.05 102.69,109.58 102.69,111.29 v3(103.16,111.76)
  BOTTOM w0.102: v2(143.8,95.33) v3(143.8,96.14)
SPI_CS_CPU_N0: length 14.7
  TOP w0.089: 91.29,143.74 91.37,143.81 91.37,145.66 91.31,145.79 CPU1.AU3
  TOP w0.102: 91.29,143.74 91.29,141.62 90,140.33 90,139.93 89.19,139.12 v4(89.19,138.51) 87.1,136.42 87.1,136.14 86.13,135.17 85.22,135.17 R182.1
SPI_HOLD_CPU: length 13.1
  TOP w0.089: 90.85,144.03 90.85,146.38 CPU1.AU4
  TOP w0.102: 90.85,144.03 90.85,141.5 89.77,140.42 89.77,140.13 88.4,138.76 88.4,138.76 v4(87.74,138.1) 86.93,137.29 86.93,137.25 R173.2 86.46,136.53 R176.2
SPI_IO2: length 93.2
  TOP w0.102: v3(105.82,111) 105.09,111.73 105.09,113.39 100.92,117.55 97.16,117.55 96.7,118.01 88.32,118.01 85.43,120.9 85.43,122.14 85.43,122.52 85.43,122.8 84.16,124.07 84.16,128.68 86.54,131.06 86.84,131.06 R196.1 ; SRCON1.3 146.72,97.54 144.36,99.9 139.52,99.9 138.69,99.06 137.64,99.06 R261.1 137.28,99.34 RN5.4 137.77,97.99 v3(138.21,98.42)
  L4 w0.127: v3(105.82,111) 105.82,110.13 106.55,109.41 106.55,108.5 108.75,106.3 121.16,106.3 123.1,104.36 126.86,104.36 127.42,103.8 134.63,103.8 137.68,100.75 137.68,98.96 v3(138.21,98.42)
  BOTTOM w0.102: v3(138.21,98.42) 138.31,98.53 v2(139.07,98.53)
SPI_IO3: length 92.2
  TOP w0.102: R176.1 84.06,135.01 84.06,134.53 83.77,134.24 83.29,134.24 81.39,132.34 81.39,127.62 82.28,126.73 82.28,122.61 83.55,121.34 83.55,120.12 87.54,116.13 95.92,116.13 96.38,115.67 100.14,115.67 102.4,113.42 102.4,111.76 v3(103.16,111) ; v3(138.21,97.16) 138.03,97.34 RN5.3 137.28,97.06 138.08,96.27 U8.7
  L4 w0.127: v3(103.16,111) 103.16,109.48 107.28,105.36 119.23,105.36 119.62,105.75 120.99,105.75 122.89,103.85 126.65,103.85 127.21,103.29 134.42,103.29 137.17,100.54 137.17,98.2 v3(138.21,97.16)
  BOTTOM w0.102: v3(138.21,97.16) 138.72,96.65 v2(138.97,96.65)
SPI_MISO: length 183.2
  TOP w0.102: v3(105.82,111.76) 105.32,112.27 105.32,113.48 101.02,117.78 97.26,117.78 96.8,118.24 88.41,118.24 85.66,120.99 85.66,122.05 85.66,122.43 85.66,122.43 85.66,122.89 84.39,124.16 84.39,128.59 86.63,130.84 87.62,130.84 R197.1 ; RN8.3 136.5,71.32 137.47,72.29 138.67,72.29 138.95,72.01 139.61,72.01 139.89,72.29 140.62,72.29 140.75,72.42 140.75,73.76 140.85,73.86 141.13,73.86 141.23,73.76 141.23,72.42 141.36,72.29 141.59,72.29 141.71,72.42 141.71,73.76 141.81,73.86 142.09,73.86 142.2,73.76 142.2,72.42 142.32,72.29 142.55,72.29 142.68,72.42 142.68,73.76 142.78,73.86 143.06,73.86 143.16,73.76 143.16,72.9 143.29,72.77 143.52,72.77 143.64,72.9 143.64,73.79 143.77,73.91 144.69,73.91 144.81,74.04 144.81,74.27 144.69,74.4 139.99,74.4 139.86,74.52 139.86,74.75 139.99,74.88 144.99,74.88 145.12,75.01 145.12,75.35 145.02,75.45 144.66,75.45 144.56,75.55 144.56,75.83 144.66,75.93 145.02,75.93 145.12,76.03 145.12,76.31 145.02,76.41 144.66,76.41 144.56,76.52 144.56,76.8 144.66,76.9 145.02,76.9 145.12,77 145.12,77.28 145.02,77.38 144.66,77.38 144.56,77.48 144.56,77.76 144.66,77.86 145.02,77.86 145.12,77.96 145.12,78.24 145.02,78.35 144.66,78.35 144.56,78.45 144.56,78.73 144.66,78.83 145.02,78.83 145.12,78.93 145.12,79.21 145.02,79.31 144.66,79.31 144.56,79.41 144.56,79.69 144.66,79.79 145.02,79.79 145.12,79.89 145.12,80.17 145.02,80.28 144.66,80.28 144.56,80.38 144.56,80.66 144.66,80.76 145.02,80.76 145.12,80.86 145.12,81.61 144.99,81.74 144.61,81.74 144.51,81.84 144.51,84.73 144.64,84.86 147.48,84.86 147.61,84.99 147.61,85.21 147.48,85.34 144.64,85.34 144.51,85.47 144.51,85.7 144.64,85.82 147.48,85.82 147.61,85.95 147.61,86.18 147.48,86.31 144.64,86.31 144.51,86.43 144.51,86.66 144.64,86.79 147.48,86.79 147.61,86.92 147.61,87.14 147.48,87.27 144.64,87.27 144.51,87.4 144.51,87.78 144.61,87.88 145.73,87.88 145.83,87.98 145.83,88.26 145.73,88.36 144.61,88.36 144.51,88.47 144.51,88.74 144.61,88.85 145.73,88.85 145.83,88.95 145.83,89.23 145.73,89.33 144.61,89.33 144.51,89.43 144.51,89.71 144.61,89.81 145.73,89.81 145.83,89.91 145.83,90.19 145.73,90.29 144.61,90.29 144.51,90.4 144.51,90.68 144.61,90.78 145.73,90.78 145.83,90.88 145.83,91.16 145.73,91.26 144.61,91.26 144.51,91.36 144.51,91.64 144.61,91.74 145.73,91.74 145.83,91.84 145.83,92.12 145.73,92.22 144.61,92.22 144.51,92.33 144.51,92.61 144.61,92.71 145.73,92.71 145.83,92.81 145.83,93.09 145.73,93.19 144.61,93.19 144.51,93.29 144.51,93.57 144.66,93.73 149,93.73 149.39,94.11 149.39,96.14 149.26,96.27 U8.2 SRCON1.2 147.1,96.27 144.69,98.68 v3(143.8,98.68)
  L4 w0.127: v3(105.82,111.76) 105.82,111.68 106.8,110.7 106.8,108.61 108.86,106.55 121.26,106.55 123.21,104.61 126.97,104.61 127.52,104.05 134.9,104.05 140.28,98.68 v3(143.8,98.68)
  BOTTOM w0.102: v2(143.8,99.49) v3(143.8,98.68)
SPI_MOSI: length 181.3
  TOP w0.102: v3(143.74,93.73) 144.05,93.73 144.18,93.6 144.18,92.63 144.05,92.5 143.64,92.5 143.54,92.4 143.54,92.12 143.64,92.02 144.18,92.02 144.28,91.92 144.28,91.64 144.18,91.54 143.64,91.54 143.54,91.44 143.54,91.16 143.64,91.05 144.18,91.05 144.28,90.95 144.28,90.67 144.18,90.57 143.64,90.57 143.54,90.47 143.54,90.19 143.64,90.09 144.18,90.09 144.28,89.99 144.28,89.71 144.18,89.61 143.64,89.61 143.54,89.51 143.54,89.23 143.64,89.12 144.18,89.12 144.28,89.02 144.28,88.74 144.18,88.64 143.64,88.64 143.54,88.54 143.54,88.26 143.64,88.16 144.18,88.16 144.28,88.06 144.28,87.78 144.18,87.68 143.64,87.68 143.54,87.57 143.54,87.3 143.64,87.19 144.18,87.19 144.28,87.09 144.28,86.81 144.18,86.71 143.64,86.71 143.54,86.61 143.54,86.33 143.64,86.23 144.18,86.23 144.28,86.13 144.28,85.85 144.18,85.75 143.64,85.75 143.54,85.64 143.54,85.37 143.64,85.26 144.18,85.26 144.28,85.16 144.28,84.88 144.18,84.78 143.64,84.78 143.54,84.68 143.54,84.4 143.64,84.3 144.18,84.3 144.28,84.2 144.28,83.92 144.18,83.82 143.64,83.82 143.54,83.71 143.54,83.43 143.64,83.33 144.18,83.33 144.28,83.23 144.28,82.95 144.18,82.85 143.64,82.85 143.54,82.75 143.54,82.47 143.64,82.37 144.18,82.37 144.28,82.27 144.28,81.99 144.18,81.89 143.64,81.89 143.54,81.78 143.54,81.5 143.64,81.4 144.18,81.4 144.28,81.3 144.28,81.02 144.18,80.92 143.64,80.92 143.54,80.82 143.54,80.54 143.64,80.44 144.18,80.44 144.28,80.34 144.28,80.06 144.18,79.95 143.64,79.95 143.54,79.85 143.54,79.57 143.64,79.47 144.18,79.47 144.28,79.37 144.28,79.09 144.18,78.99 143.64,78.99 143.54,78.89 143.54,78.61 143.64,78.51 144.18,78.51 144.28,78.41 144.28,78.13 144.18,78.02 143.64,78.02 143.54,77.92 143.54,77.64 143.64,77.54 144.18,77.54 144.28,77.44 144.28,77.16 144.18,77.06 143.64,77.06 143.54,76.96 143.54,76.68 143.64,76.58 144.18,76.58 144.28,76.48 144.28,76.2 144.18,76.09 143.64,76.09 143.54,75.99 143.54,75.71 143.64,75.61 144.18,75.61 144.28,75.51 144.28,75.23 144.15,75.11 139.68,75.11 139.55,74.98 139.55,72.78 139.29,72.52 136.77,72.52 135.85,71.6 RN8.4 ; R194.1 85.25,130.42 83.7,128.87 83.7,123.88 84.97,122.61 84.97,120.71 88.13,117.55 96.51,117.55 96.97,117.09 100.73,117.09 104.63,113.2 104.63,112.22 v3(104.17,111.76) ; SRCON1.5 142.91,98.81 v3(143.8,97.92)
  L4 w0.127: v3(143.74,93.73) 148.37,93.73 148.5,93.85 148.5,96.87 148.37,96.99 148.12,96.99 147.99,96.87 147.99,94.36 147.86,94.23 147.61,94.23 147.48,94.36 147.48,96.87 147.35,96.99 147.1,96.99 146.97,96.87 146.97,94.36 146.85,94.23 146.59,94.23 146.46,94.36 146.46,96.87 146.34,96.99 146.08,96.99 145.96,96.87 145.96,94.36 145.83,94.23 142.78,94.23 142.65,94.36 142.65,94.61 142.78,94.74 145.32,94.74 145.45,94.87 145.45,97.37 145.58,97.5 148.37,97.5 148.5,97.63 148.5,97.92 148.37,98.04 143.92,98.04 v3(143.8,97.92) 138.05,97.92 137.42,98.55 137.42,100.65 134.53,103.54 127.31,103.54 126.75,104.1 123,104.1 121.05,106.05 108.64,106.05 106.29,108.4 106.29,109.23 105.28,110.25 105.28,110.66 v3(104.17,111.76)
  BOTTOM w0.102: v2(143.74,92.91) v3(143.74,93.73)
SPI_SI_CPU: length 20.5
  TOP w0.089: 92.46,143.41 92.54,143.48 92.54,143.89 92.09,144.34 92.09,146.02 CPU1.AV3
  TOP w0.102: 92.46,143.41 92.28,143.23 92.28,141.24 90.96,139.93 90.96,139.53 90.38,138.95 90.38,137.62 88.37,135.61 v4(88.17,135.61) 88.06,135.5 88.06,134.2 R185.1 86.96,133.1 85.95,133.1 R194.2 R199.2 R200.2
SPI_SI_XDP: length 249.7
  TOP w0.102: v3(104.17,112.52) 104.17,113.33 100.64,116.87 96.88,116.87 96.42,117.32 88.03,117.32 84.74,120.61 84.74,122.05 v4(84.1,122.69) 83.47,123.32 83.47,128.52 83.28,128.71 R200.1 ; v3(47.02,225.43) 47.39,225.06 R5.2 47.33,224.47 R23.2
  L3 w0.127: v3(20.23,144.02) 16.69,147.55 16.69,150.22 12.26,154.65 12.26,184.47 12.95,185.15 12.95,187.49 13.79,188.33 13.79,201.76 12.98,202.57 12.98,218.94 17.68,223.63 28.21,223.63 28.9,224.32 33.23,224.32 33.57,224.66 46.26,224.66 v3(47.02,225.43)
  L4 w0.127: v3(20.23,144.02) 21.76,144.02 23.31,142.47 23.31,140.42 24.62,139.1 30.3,139.1 38.17,131.24 38.57,131.24 44.21,125.6 62.37,125.6 73.91,114.06 102.65,114.06 104.17,112.53 v3(104.17,112.52)
SPI_SO_CPU: length 15.7
  TOP w0.102: R197.2 88.3,133.17 88.84,133.71 88.84,134.35 v4(89.16,134.67) 90.84,136.35 90.84,138.76 91.42,139.34 91.42,139.74 92.93,141.25 92.93,144.11 92.87,144.17 92.87,145.04 92.69,145.22 92.69,145.64 CPU1.AW3
SPI_WP_CPU: length 16.5
  TOP w0.089: CPU1.AW2 92.36,145 92.27,144.9 92.27,144.5 92.74,144.02 92.74,143.01
  TOP w0.102: 92.74,143.01 92.65,142.91 92.65,141.29 91.19,139.83 91.19,139.44 90.61,138.86 90.61,136.98 v4(89.59,135.97) 89.47,135.97 88.35,134.85 88.35,133.54 87.28,132.48 R196.2 R195.2
SPI_WP_XDP: length 253.1
  TOP w0.102: v3(104.17,111) 104.86,111.68 104.86,113.29 100.83,117.32 97.07,117.32 96.61,117.78 88.22,117.78 85.2,120.8 85.2,122.24 85.2,122.7 83.93,123.97 83.93,128.78 86.27,131.11 R195.1 ; R18.1 42.2,224.73 v3(42.2,225.43)
  L3 w0.127: v3(20.23,143.26) 18.96,144.53 16.44,147.04 16.44,150.09 12.01,154.52 12.01,186.91 13.54,188.44 13.54,201.52 12.73,202.32 12.73,219.04 17.57,223.89 28.09,223.89 28.77,224.57 33.12,224.57 33.47,224.92 41.69,224.92 v3(42.2,225.43)
  L4 w0.127: v3(104.17,111) 103.63,111.54 103.63,112.72 103.26,113.08 99.91,113.08 99.52,112.7 98.31,112.7 97.47,113.54 92.36,113.54 92.11,113.28 92.11,112.27 91.73,111.89 90.71,111.89 90.46,112.14 77.12,112.14 75.46,113.8 73.81,113.8 62.26,125.35 44.1,125.35 38.46,130.99 38.06,130.99 30.2,138.85 24.52,138.85 23.06,140.31 23.06,142.36 22.16,143.26 v3(20.23,143.26)
  BOTTOM w0.102: v3(20.23,143.26) 20.33,143.15 v2(21.12,143.15)
SPKR_DET: length 42.6
  TOP w0.102: KBC1.48 145.78,56.7 145.9,56.82 147.75,56.82 R398.1 148.38,56.18 149.56,56.18 v1(149.64,56.26)
  L4 w0.127: v3(152.18,42.42) 152.65,42.89 152.65,44.14 150.91,45.88 150.91,54.99 v1(149.64,56.26)
  BOTTOM w0.102: v3(152.18,42.42) 151.65,41.88 151.65,38.89 151.09,38.33 151.09,35.37 151.87,34.58 151.87,34.05 152.9,33.02 v2(161.45,33.02) 161.45,32.64 160.5,31.69 C637.1 159.48,31.62 R456.1
SPKR_DET_C: length 3.3
  TOP w0.102: SPK1.6 v3(160.53,30.38)
  BOTTOM w0.102: v2(159.42,29.59) R456.2 160.24,30.67 v3(160.53,30.38)
SPKR_IN_L: length 7.4
  TOP w0.203: C183.2 155.79,54.47 155.79,53.49 155.96,53.31 ; 155.96,53.31 156.34,53.31 156.7,53.67 156.7,54.2 156.98,54.48 C180.2 158.05,53.57 158.3,53.57 159.05,52.82 U14.6 ; 155.96,53.31 v4(155.96,53.29)
SPKR_IN_R: length 8.2
  TOP w0.203: U14.31 162.95,50.14 163.1,50.29 163.1,50.8 165.56,53.26 166.2,53.26 166.43,53.49 v4(166.43,53.57) C176.2
SPKR_L+_C: length 4.6
  TOP w0.711: SPK1.1 152.05,32.89
  TOP w0.762: 152.05,32.89 v3(152.86,33.71)
  BOTTOM w0.508: v2(152.56,34.54) 152.86,34.24 v3(152.86,33.71)
SPKR_L+_SNB: length 4.3
  TOP w0.508: R459.2 152.26,36.58 151.54,37.29 v4(151.54,38.02) 151.54,38.1 v3(152.31,38.86)
  BOTTOM w0.508: v3(152.31,38.86) 152.43,38.73 C582.1
SPKR_L-_C: length 4.4
  TOP w0.711: SPK1.2 153.55,32.61
  TOP w0.762: 153.55,32.61 v3(154.53,33.59)
  BOTTOM w0.508: v3(154.53,33.59) v2(154.53,34.42)
SPKR_L-_SNB: length 6.1
  TOP w0.508: R460.2 156.75,38.48 v3(157.13,38.86)
  BOTTOM w0.508: v3(157.13,38.86) 156.32,38.86 v2(155.33,37.87) 155.35,37.85 C581.1
SPKR_OUT_L+: length 8.7
  TOP w0.305: U14.16 157.21,46.05
  TOP w0.762: L15.1 154.72,41.1 C206.1 C201.2 154.72,43.56 v4(155.53,44.37) 157.21,46.05
SPKR_OUT_L-: length 8
  TOP w0.305: 158.12,44.45 158.55,44.88 U14.18
  TOP w0.762: L16.1 155.86,40.21 C207.1 C202.2 155.86,42.91 v4(156.89,43.94) 157.4,44.45 158.12,44.45
SPKR_OUT_R+: length 7.6
  TOP w0.305: U14.25 162.39,46.3 162.59,46.1
  TOP w0.762: 162.59,46.1 v4(162.59,44.35) 162.59,42.8 C204.2 C209.1 162.47,40.59 L18.1
SPKR_OUT_R-: length 7
  TOP w0.305: U14.23 161.05,44.85 161.2,44.7
  TOP w0.762: 161.2,44.7 v4(161.2,44.02) C203.2 C208.1 161.2,41.35 L17.1
SPKR_R+_C: length 7.6
  TOP w0.711: 160.84,34.24 159.65,33.05 157.61,33.05 156.55,31.98 SPK1.4
  BOTTOM w0.508: v2(161.32,35.05) v3(161.32,34.24)
SPKR_R+_SNB: length 5.5
  TOP w0.508: v3(163.86,38.86) 163.23,38.23 163.23,36.96 R462.2
  BOTTOM w0.508: C579.1 163.1,37.72 v2(164.27,37.72) 164.27,38.15 163.86,38.56 v3(163.86,38.86)
SPKR_R-_C: length 7.9
  TOP w0.711: 155.72,32.78 155.05,32.11 SPK1.3
  TOP w0.762: 155.72,32.78 157.13,34.19 v3(159.11,34.19)
  BOTTOM w0.508: v2(158.02,33.91) 158.3,34.19 v3(159.11,34.19)
SPKR_R-_SNB: length 6.1
  TOP w0.508: R461.2 158.66,38.61 v3(158.4,38.86)
  BOTTOM w0.508: v3(158.4,38.86) 159.14,38.86 v2(160.15,37.85) C580.1
SSTCMP: length 4.4
  BOTTOM w0.102: R830.1 31.64,26.11 v2(32.06,26.11) 32.31,26.11 33.01,25.42 U36.11
SSTCMP_1: length 2.9
  BOTTOM w0.102: R830.2 29.69,28.26 C587.1 28.81,28.45 v2(28.23,29.03)
STATUS: length 5.2
  BOTTOM w0.102: U36.8 36.23,23.24 37.63,21.84 R845.1 37.94,21.15 38.39,21.59 v2(38.77,21.59)
STRAP0: length 8.6
  TOP w0.127: GPU1.D1 95.54,91.7 v4(96.05,92.2) 97.07,92.2 97.19,92.08 98.96,92.08 99.33,91.7 100.23,91.7 100.43,91.5 R270.1 R269.2
STRAP1: length 6.6
  TOP w0.127: R274.2 97.63,90.26 v4(97.65,90.27) 97.65,90.32 97,90.97 R271.1 96.97,91.28 93.62,91.28 93.2,91.7 GPU1.D2
STRAP2: length 10.8
  TOP w0.127: GPU1.E4 91.3,92.9 91.73,93.32 91.73,94.33 92.01,94.61 92.18,94.61 92.54,94.98 92.54,95.19 92.88,95.52 93.05,95.52 93.26,95.73 93.26,95.94 93.58,96.27 95.74,96.27 v4(95.94,96.47) 96.25,96.47 96.55,96.77 96.55,97.85 R263.1 R262.2
STRAP3: length 8.4
  TOP w0.127: R266.1 97.7,95.25 97,94.55 R267.2 96.9,94.13 v4(95.99,94.13) 95.89,94.23 95.87,94.23 95.55,94.56 93.55,94.56 93.34,94.35 93.34,94.14 93.05,93.84 92.84,93.84 92.54,93.55 92.54,93.15 92.1,92.7 GPU1.E3
STRAP4: length 8.2
  TOP w0.127: R276.1 97,87.88 R275.2 97,89.06 v4(96.63,89.42) 95.54,90.52 93.54,90.52 93.32,90.74 93.32,91.02 93.03,91.31 92.49,91.31 GPU1.D3
STRAP_REF0: length 12.5
  TOP w0.127: GPU1.F6 90.08,93.88 90.08,94.28 90.47,94.67 91.43,94.67 91.73,94.97 91.73,95.17 92.07,95.51 92.23,95.51 92.53,95.81 92.53,96.01 92.83,96.31 93.03,96.31 93.34,96.62 93.34,96.83 93.55,97.04 95.75,97.04 96.32,97.61 96.32,98.86 96.05,99.14 v4(96.05,99.19) 96.05,99.64 96.73,100.33 R260.2
SUS_CLK: length 274.1
  TOP w0.102: R361.2 139.48,71.04 140.24,71.81 143.26,71.81 145.6,74.15 145.6,82.09 145.47,82.22 145.45,82.19 145.22,82.19 144.99,82.42 144.99,84.12 145.07,84.2 147.99,84.2 148.12,84.33 148.12,87.88 147.99,88.01 146.96,88.01 146.51,88.46 146.51,92.51 v3(146.97,92.96) ; R52.1 127.43,216.41 129.31,218.29 146.33,218.29 154.71,209.92 159.05,209.92 v3(161.32,207.65) ; R134.2 104.86,154.25 111.41,147.7 111.41,134.75 v3(111.67,134.5)
  L4 w0.127: v3(147.86,118.49) 145.58,120.78 139.22,120.78 135.14,116.7 129.22,116.7 121.4,124.52 121.4,125.02 113.06,133.35 112.61,133.35 111.67,134.3 v3(111.67,134.5)
  BOTTOM w0.102: v3(146.97,92.96) 146.97,99.95 146.98,99.96 146.98,107.94 146.54,108.38 146.54,116.61 147.86,117.93 v3(147.86,118.49) v2(148.88,119.51) 149.39,120.02 155.35,120.02 160.56,125.22 160.56,148.84 164.16,152.44 164.16,158.84 162.82,160.17 162.82,196.24 161.45,197.61 161.45,200.54 161.96,201.05 161.96,207.01 v3(161.32,207.65)
SUS_CLK_EC: length 3.8
  TOP w0.102: R361.1 138.67,67.2 138.67,67.03 v4(138.65,67.01) 138.64,67 138.64,66.95 138.46,66.78 138.46,65.48 138.34,65.36 KBC1.77
SUS_CLK_PCH: length 8.7
  TOP w0.089: 94.56,154.17 94.12,154.17 93.86,154.43 CPU1.BA17
  TOP w0.102: 94.56,154.17 97.14,154.17 97.81,153.49 98.66,153.49 99.42,154.25 v4(100.31,154.25) R134.1
SUS_LED_GREEN_C: length 25.5
  TOP w0.254: Q44.D 32.99,23.24 v4(32.42,23.24) 31.78,22.61 31.37,22.61 30.51,21.75 PWRCN1.7 27.05,21.75 v3(26.2,22.61)
  L3 w0.254: v3(26.2,22.61) 26.73,22.07 26.73,13.11 v3(26.7,13.08)
  BOTTOM w0.254: v2(29.6,12.95) 29.09,12.45 R858.2 27.54,13.32 R855.2 26.7,13.97 v3(26.7,13.08)
SUS_LED_GREEN_C2: length 2.8
  BOTTOM w0.254: R855.1 29.7,14.81 v2(30.18,15.29) 30.16,15.32 30.16,15.47 29.62,16 R852.2
SUS_PWR_ACK: length 147.8
  TOP w0.102: KBC1.25 140.34,49.86 139.94,50.27 139.94,51.28 138.34,52.88 v1(138.34,54.1) ; CPU1.AP11 89.25,150.87 v1(88.92,150.55) ; R202.2 v3(101.63,130.81)
  L4 w0.127: v1(88.92,150.55) 89.38,150.09 91.75,150.09 94.08,147.77 94.08,146.49 100.17,140.4 100.17,137.72 100.86,137.03 100.86,131.58 v3(101.63,130.81) 102.01,130.43 109.33,130.43 111.65,128.11 113.65,128.11 116.42,125.34 116.42,124.9 127.87,113.45 140.15,113.45 140.71,114.01 141.8,114.01 v3(142.27,113.54)
  BOTTOM w0.102: v3(142.27,113.54) v2(142.27,109.09) 142.27,106.91 144.48,104.7 144.48,86.36 145.91,84.94 145.91,82.37 144.56,81.03 144.56,69.19 143.62,68.25 143.62,66.34 144.66,65.3 144.66,60.93 143.97,60.25 143.36,60.25 142.98,59.87 142.98,58.77 141.99,57.78 141.94,57.78 141.41,57.26 141.41,56.48 R883.2 139.92,54.99 139.82,54.99 138.94,54.1 v1(138.34,54.1)
SUS_WARNB: length 131.3
  TOP w0.102: v1(89.57,151.46) 89.9,151.79 CPU1.AR13 ; R202.1 R206.2 100.58,129.13 v3(100.58,130.05) ; v1(138.59,71.75) 138.82,71.53 138.82,68.03 137.52,66.74 137.52,66.09 137.54,66.08 KBC1.79
  L3 w0.127: v3(100.58,130.05) 100.58,133.64 98.79,135.43 98.79,138.88 98.84,138.93 98.84,143.13 91.39,150.58 91.39,150.62 90.97,151.04 89.99,151.04 v1(89.57,151.46)
  L4 w0.127: v3(141.26,113.54) 140.79,113.07 127.71,113.07 116.04,124.74 116.04,125.18 113.49,127.72 111.5,127.72 109.17,130.05 v3(100.58,130.05)
  BOTTOM w0.102: v3(141.26,113.54) v2(140.11,112.39) 139.53,111.81 139.53,106.36 139.85,106.05 141.34,106.05 142.46,104.92 142.46,76.73 138.59,72.85 v1(138.59,71.75)
SUSCLK_NGFF: length 5.4
  TOP w0.102: R52.2 122.76,216.41 122.39,216.78 120.59,216.78 v4(120.48,216.89) 120.37,217 NGFF1.50
SW_ON_N_SIO: length 5.3
  TOP w0.102: KBC1.124 126.67,52.3 v3(126.6,52.36) 126.26,52.7 R412.1
  BOTTOM w0.102: v2(127.49,52.84) 127.08,52.84 v3(126.6,52.36)
SYS_FAN_TACH1_1: length 4.3
  TOP w0.102: FANC3.3 16.91,209.73 R59.2 R57.2
SYS_FAN_TACH1_2: length 4.3
  TOP w0.102: v4(18.55,207.44) 17.83,207.44 R61.2 R59.1 18.21,209.11 18.59,208.72 R60.2
SYS_PEX_RST_MON_GPU#: length 48.2
  TOP w0.102: v1(86.7,92.1) 86.7,92.08 86.32,91.7 GPU1.D10 ; v3(96.43,111.76) 95.84,112.34 95.84,113.37 96.85,114.38 97.68,114.38 R245.2
  BOTTOM w0.102: v1(86.7,92.1) 87.12,92.52 88.54,92.52 88.78,92.28 88.78,91.82 89.01,91.59 89.01,90.29 90.87,88.43 92.58,88.43 94.02,87 96.63,87 97.59,87.96 97.59,89.31 98.28,89.99 98.28,91.37 99.6,92.69 99.6,95.73 100.49,96.62 v2(100.49,102.49) 100.74,102.74 100.74,109.52 100.06,110.2 98.28,110.2 96.71,111.76 v3(96.43,111.76)
SYS_PRES: length 5
  TOP w0.102: v4(36.23,64.26) 36.23,63.75 35.91,63.44 R370.2 33.37,63.44 32.57,62.64 BAT2.6
SYS_PWROK: length 328.8
  TOP w0.102: v3(43.56,133.52) 44.97,134.92 56.24,134.92 60.07,138.76 66.53,138.76 67.44,139.68 67.44,141.52 R147.1 68.36,142.18 68.9,142.71 68.9,144 69.8,144.91 70.03,144.91 71.11,146 71.81,146 72.04,146.23 72.04,147.07 72.21,147.24 72.37,147.24 CPU1.B6 ; v3(48.67,225.43) 48.72,225.37 48.72,223.96 R27.1
  L3 w0.127: v3(43.56,133.52) 43.33,133.52 40.93,135.92 38.9,135.92 37.47,137.34 37.47,137.35 36.82,137.99 36.82,138.15 36.28,138.7 34.89,138.7 34.23,139.36 23.36,139.36 22.75,139.97 22.75,142.64 17.07,148.31 17.07,150.4 12.64,154.83 12.64,184.31 13.33,185 13.33,187.33 15.27,189.27 15.27,220.69 16.87,222.29 27.53,222.29 29.18,223.94 33.39,223.94 33.73,224.28 47.53,224.28 v3(48.67,225.43)
  L4 w0.127: v3(43.56,133.52) 44.72,132.35 45.37,132.35 47.4,130.31 72.3,130.31 83.32,119.29 96.81,119.29 97.19,119.67 113.09,119.67 125.52,107.24 134.01,107.24 134.78,106.46 136.5,106.46 136.78,106.74 139.8,106.74 v3(139.99,106.55)
  BOTTOM w0.102: v3(139.99,106.55) 140.24,106.81 v2(141,106.81) 141.08,106.81 142.82,105.07 142.82,76.58 141.57,75.34 R715.1
SYSTEM_FAN_PWM1_1: length 17.3
  TOP w0.102: FANC3.4 12.43,207.19 12.1,207.52 12.1,217.3 13.88,219.07 D1.A 13.75,219.46 R40.2 12.23,219.52 R33.2
T_CRIT#: length 5.5
  TOP w0.102: U12.4 146.89,76.92 v4(147.18,77.21) 147.18,77.22 147.18,78.5 R314.1 R315.2
THERM_SYS_SHDN#: length 3.3
  TOP w0.102: Q29.S 146.53,79.66 R314.2 146.53,77.86 v3(146.57,77.83)
  BOTTOM w0.102: v2(146.32,77.05) 146.32,77.58 v3(146.57,77.83)
THERMTRIP#_CPU: length 5.2
  TOP w0.089: 70.86,179.99 70.9,179.96 71.79,179.96 71.8,179.96 71.92,180.01 72.34,180.01 72.42,180.09 72.65,180.09 CPU1.C63
  TOP w0.102: R96.2 69.13,180.39 70.47,180.39 70.86,179.99
TP1_AY4: length 16.5
  TOP w0.089: 94.22,145.47 94.01,145.68
  TOP w0.102: CPU1.AY4 93.18,146.73 93.64,146.26 93.81,146.26 94.01,146.06 94.01,145.68 ; 94.22,145.47 94.45,145.47 95.54,144.37 95.54,142.25 98.1,139.69 98.1,136.13 100.37,133.86 TP44.1
TP2_BB3: length 13.6
  TOP w0.102: CPU1.BB3 94.77,145.8 95.84,144.73 95.84,142.33 98.33,139.84 98.33,136.39 99.69,135.03 TP42.1
TP4_BB5: length 15.8
  TOP w0.102: CPU1.BB5 94.75,147.21 96.52,145.45 96.52,142.61 99.04,140.09 99.04,138.81 101.76,136.09 TP43.1
TP5_AU5: length 20.7
  TOP w0.089: CPU1.AU5 91.24,147.35 92.2,146.39 93.09,146.39 93.36,146.11 93.36,145.88 93.61,145.63 93.79,145.63 93.99,145.44 93.99,145.01 94.41,144.58
  TOP w0.102: TP45.1 101.13,132.46 101.13,132.75 100.66,133.22 100.41,133.22 97.87,135.76 97.87,139.59 95.03,142.44 95.03,143.97 94.41,144.58
TP6_AT5: length 3.3
  TOP w0.102: v1(90.87,147.8) 90.55,147.48 CPU1.AT5
  BOTTOM w0.102: TP63.1 92.95,147.07 92.22,147.8 v1(90.87,147.8)
TP3131_GVDD: length 6.1
  TOP w0.203: C177.2 160.69,55.44 R405.1 162.34,53.78 R408.2 162.57,53.12 v4(162.25,52.8) 162.24,52.79 162.24,52.78 161.63,52.17 161.25,52.17 161.05,51.97 U14.2
TP_DDPC_CTRLDATA: length 2.4
  TOP w0.102: CPU1.N8 78.94,148.38 v1(79.13,148.38)
  BOTTOM w0.102: TP64.1 78.52,147.77 v1(79.13,148.38)
TP_DET_N: length 153
  TOP w0.102: v1(139.23,62.1) 139.23,62.23 140.34,63.34 KBC1.72 ; v4(26.65,3.38) 26.65,10.45 v3(26.7,10.5) TOUCH1.1
  L3 w0.127: v1(139.23,62.1) 139.47,61.86 139.47,58.75 136.56,55.84 136.56,55.84 135.08,54.36 134.41,54.36 133.95,53.91 133.95,51.69 134.01,51.64 134.01,50.35 132.58,48.93 129.25,48.93 127.62,47.29 v3(127.62,44.32)
  L4 w0.127: v3(127.62,44.32) 127.62,44.3 127.54,44.22 127.54,44.07 126.82,43.35 125.89,43.35 123.06,40.52 121.36,40.52 115.65,34.81 114.12,34.81 112.5,33.19 110.18,33.19 103.19,26.2 63.86,26.2 57.44,19.77 43.04,19.77 42.56,19.29 37.44,19.29 34.9,16.75 34.2,16.75 27.95,10.5 v3(26.7,10.5)
  BOTTOM w0.102: v3(26.7,10.5) 26.79,10.41 R862.2
TP_L_BKLTEN: length 5.8
  TOP w0.102: v1(80.2,150.97) 79.85,151.32 CPU1.R12
  BOTTOM w0.102: v1(80.2,150.97) 80.86,150.31 80.86,147.22 80.68,147.04 TP67.1
TP_L_VDDEN: length 2
  TOP w0.102: v1(81.26,151.52) 80.81,151.97 CPU1.U13
  BOTTOM w0.102: TP61.1 82.16,150.62 v1(81.26,151.52)
TP_NGFF_COEX1: length 5.7
  TOP w0.102: NGFF1.48 119.9,216.5 120.1,216.29 122.19,216.29 122.56,215.93 122.94,215.93 TP10.1
TP_NGFF_COEX2: length 4.1
  TOP w0.102: NGFF1.46 121.65,216 TP9.1
TP_NGFF_COEX3: length 2.6
  TOP w0.102: TP8.1 120.83,215.5 NGFF1.44
TP_NGFF_LED1: length 2.5
  TOP w0.102: NGFF1.6 120.05,206 TP28.1
TP_NGFF_LED2: length 4.5
  TOP w0.102: TP27.1 121.83,208.03 120.56,208.03 120.08,208.5 NGFF1.16
TP_NGFF_MLDIR: length 3
  TOP w0.102: TP25.1 109.88,208.75 NGFF1.17
TP_PMODE_XDP_RST_R_N: length 5.6
  TOP w0.102: XDP1.46 30.83,222.78 v3(30.73,222.88)
  BOTTOM w0.102: R531.1 R530.2 30.96,223.96 v2(31,223.93) 31.07,223.85 31.07,223.22 v3(30.73,222.88)
TPA3113_SD: length 18.1
  BOTTOM w0.152: 156.12,42.87 155.99,42.75 155.99,41.43 156.16,41.26 Q71.6 ; 156.12,42.87 v2(156.12,45.34) 156.16,45.38 156.16,47.34 155.92,47.57 155.28,47.57 154.59,48.26 Q84.D ; 156.12,42.87 156.21,42.97 157.73,42.97 158.5,42.19 160.14,42.19 R787.2 161.45,43.5 162.47,43.5 R790.1 163.04,43.94 Q68.G
TPA3113_SD1#: length 20.9
  TOP w0.152: U14.29 163.87,49.15 v3(164.12,48.9)
  BOTTOM w0.152: Q66.G 163.01,52.55 C564.1 163.23,52.58 164.7,52.58 v2(164.75,52.63) 164.83,52.63 165.46,51.99 165.46,49.12 165.23,48.9 v3(164.12,48.9) 164.18,48.83 R781.1 164.94,47.24 Q68.D ; Q68.D 162.72,45.72 162.21,45.21 162.21,44.7 161.96,44.45 R786.2 ; Q68.D 164.94,45.02 164.43,44.51 R789.1
TPA3131_BSNL: length 4.4
  TOP w0.305: C202.1 157.48,42.67 v4(158.43,43.62) 159.05,44.24 U14.19
TPA3131_BSNR: length 4
  TOP w0.305: C203.1 159.67,44.11 159.75,44.19 v4(159.75,44.2) 159.75,44.2 160.55,44.99 U14.22
TPA3131_BSPL: length 7.3
  TOP w0.305: U14.15 156.52,47.65 156.12,47.24
  TOP w0.508: 156.12,47.24 156.12,46.49 154.2,44.58 153.78,44.58 v4(153.2,43.99) C201.1
TPA3131_BSPR: length 6.2
  TOP w0.305: 163.48,44.45 163.48,47.37 163.21,47.65 U14.26
  TOP w0.508: C204.1 v4(163.99,43.87) 163.99,43.94 163.48,44.45
TPA3131_FAULT#: length 4.6
  TOP w0.102: v3(164.12,49.66) 164.11,49.65 U14.30
  BOTTOM w0.102: v2(164.9,49.87) 164.69,49.66 v3(164.12,49.66) 163.29,48.83 R781.2
TPA3131_GAIN: length 4.8
  TOP w0.203: R407.1 159.89,55.03 160.31,54.61 R405.2 161.11,54.13 v4(161.11,53.59) 161.11,52.67 160.55,52.11 U14.3
TPA3131_LINN: length 3.5
  TOP w0.203: U14.5 159.55,53.1 v4(159.58,53.13) 158.4,54.3 C181.2
TPA3131_LINN_1: length 2.7
  TOP w0.203: R396.2 158,56.41 C181.1 158.45,55.96 159.39,55.96 v4(159.57,56.13)
TPA3131_MUTE: length 6
  TOP w0.203: U14.7 158.55,52.05 v3(158.15,52.45)
  BOTTOM w0.203: R774.2 157.07,53.09 v2(157.47,53.09) 157.89,53.09 158.15,52.83 v3(158.15,52.45) R775.1 158.21,51.56 Q66.D
TPA3131_PLIMIT: length 6.4
  TOP w0.203: C178.2 161.86,55.38 R408.1 163.08,54.17 R406.2 163.66,53.26 v4(163.58,53.19) 163.58,53.19 161.88,51.49 U14.1
TPA3131_RINN: length 7.1
  TOP w0.203: C179.2 164.8,55.12 v4(164.8,53.95) 164.8,53.33 162.83,51.36 162.59,51.36 162.39,51.16 U14.32
TPA3131_RINN_1: length 2.7
  TOP w0.203: v4(165.82,54.89) 165.82,54.93 165.39,55.36 165.26,55.49 C179.1 R395.2
TPA3131_SYNC: length 2.9
  TOP w0.102: U14.11 156.37,49.65 155.61,50.41 TP52.1
TPM_VDD: length 24.3
  TOP w0.508: v3(126.26,51.67) 126.26,51.59 126.27,51.58 126.27,50.1 C191.1 127,49.97 128.63,48.34 128.63,48.09 v1(129.05,47.68)
  L3 w0.508: v3(118.27,50.55) 118.93,51.21 121.74,51.21 121.8,51.16 125.61,51.16 126.13,51.67 v3(126.26,51.67)
  BOTTOM w0.305: U34.14 v3(126.26,51.67) ; U34.8 122.18,49.88 ; U34.22 128.76,47.38 v1(129.05,47.68)
  BOTTOM w0.381: v1(129.05,47.68) 129.37,47.68 129.76,48.07 C569.1 ; 122.18,49.88 121.7,49.88
  BOTTOM w0.508: 121.7,49.88 121.7,49.89 121.1,49.89 120.57,50.42 v2(120.57,51.18) 120.05,51.18 119.46,50.6 C565.1 118.32,50.6 v3(118.27,50.55) 118.1,50.71 R776.2
TPM_VSB: length 8.1
  BOTTOM w0.254: U34.1 121.84,46.38 121.83,46.37 121.83,46.35 121.19,45.72 119.67,45.72 119.03,46.35 v2(119.03,46.48) 119.41,46.86 119.41,47.78 C567.1 119.27,47.92 C568.1 R780.2
USB2_C_N1: length 6.6
  TOP w0.102: 165.29,104.92 162.2,104.92 161.8,104.52 R257.1 ; 165.29,104.92 166.01,104.92 166.26,104.67 166.54,104.67 166.77,104.43 TR4.4 ; 165.29,104.92 v4(165.29,104.57)
USB2_C_P1: length 6.6
  TOP w0.102: R256.1 161.8,105.54 162.2,105.14 163.43,105.14 ; v4(163.43,105.49) 163.43,105.14 ; 163.43,105.14 166.1,105.14 166.35,104.88 166.54,104.88 166.77,105.12 TR4.1
USB2_ID: length 7.4
  TOP w0.102: CPU1.AG3 85.05,145.99 84.85,145.78 84.85,141.88 v1(85.38,141.35)
  BOTTOM w0.102: v2(84.62,141.73) 85,141.35 v1(85.38,141.35) 85.44,141.29 R886.1
USB2_N0: length 116.4
  TOP w0.102: 158.22,112.15 158.66,112.15 161.17,109.65 164.93,109.65 165.11,109.47 165.11,108.33 166.4,107.04 166.76,107.04 167.07,106.72 TR3.4 ; 158.22,112.15 v4(158.22,111.79) ; 158.22,112.15 157.58,112.15 156.07,113.66 156.07,114.21 v3(155.85,114.43) ; v1(83.38,149.04) 83.06,149.37 CPU1.AB9
  L3 w0.089: v1(83.38,149.04) 83.38,149.23 83.46,149.3 83.7,149.3 83.81,149.19 83.85,149.15 83.85,147.29 84.07,147.08 84.07,146.47 84.03,146.43 84.03,146.41
  L3 w0.127: 84.03,146.41 84.03,146.16 83.28,145.41 83.28,135.83 84.48,134.64 84.48,130.49 94.97,119.99 113.7,119.99 114.18,119.51 127.08,119.51 128.91,117.67 155.03,117.67 155.86,116.84 155.86,114.44 v3(155.85,114.43)
USB2_N1: length 114.6
  TOP w0.102: R257.2 160.08,104.52 159.98,104.62 159.98,104.82 159.88,104.92 158.04,104.92 v3(157.77,104.65) ; v1(84.46,147.6) 84.27,147.41 CPU1.AD6
  L3 w0.089: 84.91,146.15 84.91,146.17 84.95,146.2 84.95,147.59 84.75,147.78 84.64,147.78 v1(84.46,147.6)
  L3 w0.127: 84.91,146.15 84.91,145.58 84.03,144.7 84.03,136.09 85.19,134.94 85.19,131.52 96,120.7 113.97,120.7 114.4,120.27 128.99,120.27 130.19,119.07 156.82,119.07 157.63,118.25 157.63,107.35 156.84,106.56 156.84,105.23 157.17,104.9 157.52,104.9 v3(157.77,104.65)
  BOTTOM w0.102: v2(158.63,104.62) 157.79,104.62 v3(157.77,104.65)
USB2_N2: length 219.1
  TOP w0.089: CPU1.AH3 86.45,146.31 86.1,145.97 86.07,145.9 86.07,145.9 86.02,145.77 86,145.72 86,145.57 86.07,145.44 86.07,145.25 86.02,145.12 86,145.07 86,144.92 86.06,144.79 86.06,143.72 85.89,143.54 85.57,143.54 v1(85.35,143.77)
  TOP w0.102: v3(105.82,37.85) 105.78,37.81 TR7.1
  L3 w0.127: v1(85.35,143.77) 85.61,143.5 85.72,143.5 86.15,143.07 86.15,131.92 89.14,128.93 96.4,121.67 114.58,121.67 114.95,121.3 129.32,121.3 130.59,120.03 157.22,120.03 158.59,118.65 158.59,95.03 149.45,85.89 149.45,74.13 144.93,69.61 144.93,51.33 144.29,50.7 144.29,46.85 140.16,42.72 136.43,42.72 136.43,42.72 130.5,42.72 125.87,38.1 123.6,38.1 122.33,39.37 115.47,39.37 114.05,40.79 107.25,40.79 105.49,39.04 105.49,38.18 v3(105.82,37.85)
  BOTTOM w0.102: v3(105.82,37.85) 105.82,37.06 105.8,37.03 v2(105.8,36.96)
USB2_N3: length 222.1
  TOP w0.102: v1(84.46,149.59) 84.23,149.37 CPU1.AD9 ; v3(107.22,37.85) 107.42,37.64 107.42,36.98 TR8.4
  L3 w0.089: 85.95,146.26 85.95,146.28 85.99,146.32 85.99,148.21 84.9,149.3 84.9,149.78 84.79,149.89 84.56,149.89 84.46,149.78 v1(84.46,149.59)
  L3 w0.127: v3(107.22,37.85) 107.37,38 107.37,38.91 108.83,40.36 113.87,40.36 114.09,40.14 116.12,38.11 122.7,38.11 123.14,37.67 127.54,37.67 132.16,42.29 140.34,42.29 144.72,46.67 144.72,50.52 145.36,51.16 145.36,69.43 149.88,73.95 149.88,85.69 159.02,94.83 159.02,118.83 157.4,120.46 130.77,120.46 129.44,121.79 115.1,121.79 114.79,122.1 96.58,122.1 86.58,132.1 86.58,144.02 85.95,144.65 85.95,146.26
  BOTTOM w0.102: v3(107.22,37.85) 107.37,38 v2(107.37,38.96)
USB2_N4: length 166
  TOP w0.102: CPU1.AJ1 87.32,144.69 88.39,143.62 88.39,143.02 88.2,142.82 88.04,142.82 87.92,142.95 87.92,143.59 87.75,143.75 87.52,143.75 v1(87.28,143.51) ; v3(158.15,182.5) 158.42,182.77 158.42,183.67 159.25,184.49 160.05,184.49 ; 160.05,184.49 165.3,184.49 165.55,184.75 165.55,188.88 164.55,189.88 164.55,190.35 164.16,190.74 TR2.1 ; 160.05,184.49 v4(160.05,184.84)
  L3 w0.127: v1(87.28,143.51) 87.56,143.51 87.7,143.37 87.7,142.83 89.07,141.46 89.07,131.96 97.15,123.89 98.78,123.89 98.84,123.95 115.73,123.95 116,123.68 130.09,123.68 131.65,122.13 155.76,122.13 159,125.36 159,181.19 158.4,181.8 158.4,182.25 v3(158.15,182.5)
USB2_N5: length 209.7
  TOP w0.102: CPU1.AF6 85.18,147.41 85.44,147.15 v1(85.54,147.15) ; v3(44.86,111.12) 44.61,111.38 41.11,111.38 40.29,110.57 40.29,78.69 37.99,76.39 34.51,76.39 33.82,77.09 31.78,77.09 30.89,76.2 30.89,73.38 27.72,70.2 27.72,58.04 28.26,57.5 28.26,54.11 30.89,51.47 30.89,46.86 27.61,43.57 24.05,43.57 23.27,42.8 23.27,40.64 22,39.37 22,17.96 25.14,14.82 31.49,14.82 31.76,14.55 31.76,14.07 TR13.4
  L3 w0.127: v3(44.86,111.12) 45.11,111.37 45.48,111.37 46.27,112.16 46.27,115.82 57.01,126.56 76.05,126.56 81.21,121.39 81.94,121.39 82.13,121.59 v3(82.56,121.59)
  BOTTOM w0.102: 86.88,136.09 86.88,134.09 87.38,133.58 87.38,130.58 89.95,128.02 89.95,126.24 85.44,121.73 83.48,121.73 83.07,122.15 82.68,122.15 82.56,122.02 v3(82.56,121.59) ; 86.88,136.09 v2(87.23,136.09) ; 86.88,136.09 86.88,144.86 85.76,145.97 85.76,146.34 85.03,147.07 85.03,147.26 85.2,147.42 85.42,147.42 85.54,147.29 v1(85.54,147.15)
USB2_N6: length 217.2
  TOP w0.102: v3(148.12,195.45) 147.82,195.16 147.82,194.78 146.85,193.8 141.78,193.8 137.99,197.59 109.1,197.59 108.79,197.9 TR1.4 ; CPU1.AH1 86.47,145 86.56,144.91 86.56,142.81 85.91,142.16 85.91,141.21 86.16,140.96 87.27,140.96 v1(87.28,140.97)
  L3 w0.127: v3(148.12,195.45) 147.87,195.21 147.87,195.06 148.14,194.79 154.75,194.79 155.49,194.04 155.49,191.63 159.98,187.14 159.98,124.87 156.27,121.16 131.19,121.16 129.8,122.56 115.48,122.56 115.16,122.87 96.8,122.87 88.02,131.65 88.02,140.97 87.84,141.15 87.44,141.15 87.28,141 v1(87.28,140.97)
  BOTTOM w0.102: v2(148.16,196.34) 148.12,196.3 v3(148.12,195.45)
USB2_NGFF_N6: length 8.8
  TOP w0.102: 107.86,201.85 107.62,202.09 107.62,204.79 108.43,205.61 109.36,205.61 109.5,205.75 NGFF1.5 ; 107.86,201.85 108.79,200.92 TR1.3 ; 107.86,201.85 v4(107.55,201.55)
USB2_NGFF_P6: length 8.7
  TOP w0.102: 107.84,203.84 107.84,204.7 108.52,205.39 109.36,205.39 109.5,205.25 NGFF1.3 ; 107.84,203.84 107.84,202.18 108.98,201.03 109.23,201.03 109.47,200.8 TR1.2 ; 107.84,203.84 v4(108.24,203.84)
USB2_P0: length 116.5
  TOP w0.102: 165.32,109.37 165.32,109.56 165.08,109.8 165.02,109.87 161.26,109.87 158.75,112.37 157.67,112.37 156.28,113.75 156.28,114.11 v3(156.61,114.45) ; 165.32,109.37 v4(165.72,109.37) ; 165.32,109.37 165.32,108.42 166.49,107.25 166.8,107.25 166.95,107.4 TR3.1 ; CPU1.AB10 83.09,150.02 v1(83.38,149.72)
  L3 w0.089: 84.3,146.41 84.3,146.43 84.26,146.47 84.26,147.16 84.04,147.37 84.04,149.22 83.78,149.49 83.61,149.49 v1(83.38,149.72)
  L3 w0.127: v3(156.61,114.45) 156.13,114.93 156.13,116.95 155.14,117.94 129.02,117.94 127.19,119.77 114.29,119.77 113.81,120.26 95.08,120.26 84.74,130.6 84.74,134.75 83.55,135.94 83.55,145.3 84.3,146.05 84.3,146.41
USB2_P1: length 114.2
  TOP w0.102: R256.2 160.08,105.54 159.98,105.44 159.98,105.24 159.88,105.14 158.91,105.14 ; 158.91,105.14 158.04,105.14 v3(157.77,105.41) ; 158.91,105.14 v4(158.91,105.49) ; v1(84.47,148.25) 84.47,148.14 84.31,147.98 84.02,147.98 CPU1.AD7
  L3 w0.089: v1(84.47,148.25) 84.75,147.97 84.9,147.97 85.14,147.73 85.14,146.19 85.17,146.15
  L3 w0.127: 85.17,146.15 85.17,145.47 84.3,144.59 84.3,136.2 85.45,135.05 85.45,131.63 96.11,120.97 114.08,120.97 114.51,120.54 129.1,120.54 130.3,119.33 156.93,119.33 157.89,118.37 157.89,107.24 157.1,106.45 157.1,105.34 157.28,105.16 157.52,105.16 v3(157.77,105.41)
USB2_P2: length 219.1
  TOP w0.089: v1(85.35,143.13) 85.57,143.35 85.96,143.35 86.26,143.64 86.26,144.79 86.25,144.8 86.25,144.81 86.19,144.93 86.19,145.08 86.25,145.21 86.25,145.46 86.19,145.58 86.19,145.73 86.25,145.86 86.36,145.97 87.12,145.97 CPU1.AJ3
  TOP w0.102: TR7.4 105.1,37.81 v3(105.06,37.85)
  L3 w0.127: v1(85.35,143.13) 85.72,143.13 85.89,142.96 85.89,131.81 89.03,128.67 96.29,121.4 114.47,121.4 114.84,121.03 129.21,121.03 130.48,119.76 157.11,119.76 158.33,118.54 158.33,95.14 149.18,86 149.18,74.24 144.66,69.72 144.66,51.45 144.03,50.81 144.03,46.96 140.05,42.99 136.59,42.99 130.39,42.99 125.76,38.37 123.71,38.37 122.44,39.64 115.58,39.64 114.16,41.06 107.14,41.06 105.23,39.15 105.23,38.01 v3(105.06,37.85)
  BOTTOM w0.102: v1(85.35,143.13) 84.67,143.13 v2(84.54,143.26)
USB2_P3: length 221.9
  TOP w0.102: v3(107.98,37.85) 107.94,37.81 TR8.1 ; v1(84.49,150.29) 84.22,150.02 CPU1.AD10
  L3 w0.089: v1(84.49,150.29) 84.7,150.08 84.87,150.08 85.09,149.86 85.09,149.38 86.18,148.29 86.18,146.32 86.22,146.28 86.22,146.26
  L3 w0.127: 86.22,146.26 86.22,144.76 86.85,144.13 86.85,132.21 96.69,122.36 114.9,122.36 115.21,122.06 129.55,122.06 130.88,120.73 157.51,120.73 159.29,118.94 159.29,94.72 150.15,85.58 150.15,73.84 145.63,69.32 145.63,51.05 144.99,50.41 144.99,46.56 140.45,42.02 132.27,42.02 127.65,37.4 123.03,37.4 122.59,37.85 116.01,37.85 113.98,39.88 113.76,40.09 108.94,40.09 107.64,38.8 107.64,38.19 v3(107.98,37.85)
  BOTTOM w0.102: v3(107.98,37.85) 107.98,37.01 v2(107.96,36.98)
USB2_P4: length 166.1
  TOP w0.102: TR2.4 164.84,190.74 164.76,190.67 164.76,189.97 165.77,188.97 165.77,186.84 ; v4(166.12,186.84) 165.77,186.84 ; 165.77,186.84 165.77,184.66 165.39,184.28 159.34,184.28 158.64,183.58 158.64,182.77 v3(158.91,182.5) ; v1(87.28,142.88) 87.69,142.88 87.95,142.61 88.29,142.61 88.6,142.93 88.6,143.71 87.13,145.19 CPU1.AJ2
  L3 w0.127: v1(87.28,142.88) 87.8,142.35 88.81,141.35 88.81,131.85 97.04,123.62 98.89,123.62 98.96,123.69 115.62,123.69 115.89,123.41 129.98,123.41 131.54,121.86 155.87,121.86 159.27,125.25 159.27,181.31 158.66,181.91 158.66,182.25 v3(158.91,182.5)
USB2_P5: length 209.9
  TOP w0.102: CPU1.AF7 85.22,148.06 85.47,147.81 v1(85.55,147.81) ; TR13.1 31.55,14.07 31.55,14.46 31.4,14.61 25.05,14.61 21.79,17.87 21.79,39.46 23.06,40.73 23.06,42.89 23.96,43.79 27.52,43.79 30.68,46.95 30.68,51.38 28.04,54.02 28.04,57.41 27.5,57.95 27.5,70.29 30.68,73.47 30.68,76.29 31.69,77.3 33.9,77.3 34.6,76.61 37.9,76.61 40.08,78.78 40.08,110.66 41.02,111.59 44.61,111.59 44.86,111.85 v3(44.86,111.89)
  L3 w0.127: v3(81.98,122.14) 81.98,121.81 81.83,121.66 81.32,121.66 76.16,126.82 56.89,126.82 46.01,115.93 46.01,112.27 45.37,111.63 45.12,111.63 v3(44.86,111.89)
  BOTTOM w0.102: 87.17,131.19 87.17,133.49 86.66,134 86.66,144.77 85.55,145.88 85.55,146.25 84.82,146.98 84.82,147.35 85.28,147.81 v1(85.55,147.81) ; 87.17,131.19 87.17,130.49 89.73,127.93 89.73,126.33 85.35,121.95 83.57,121.95 83.15,122.36 82.59,122.36 82.37,122.14 v3(81.98,122.14) ; 87.17,131.19 v2(86.88,131.19)
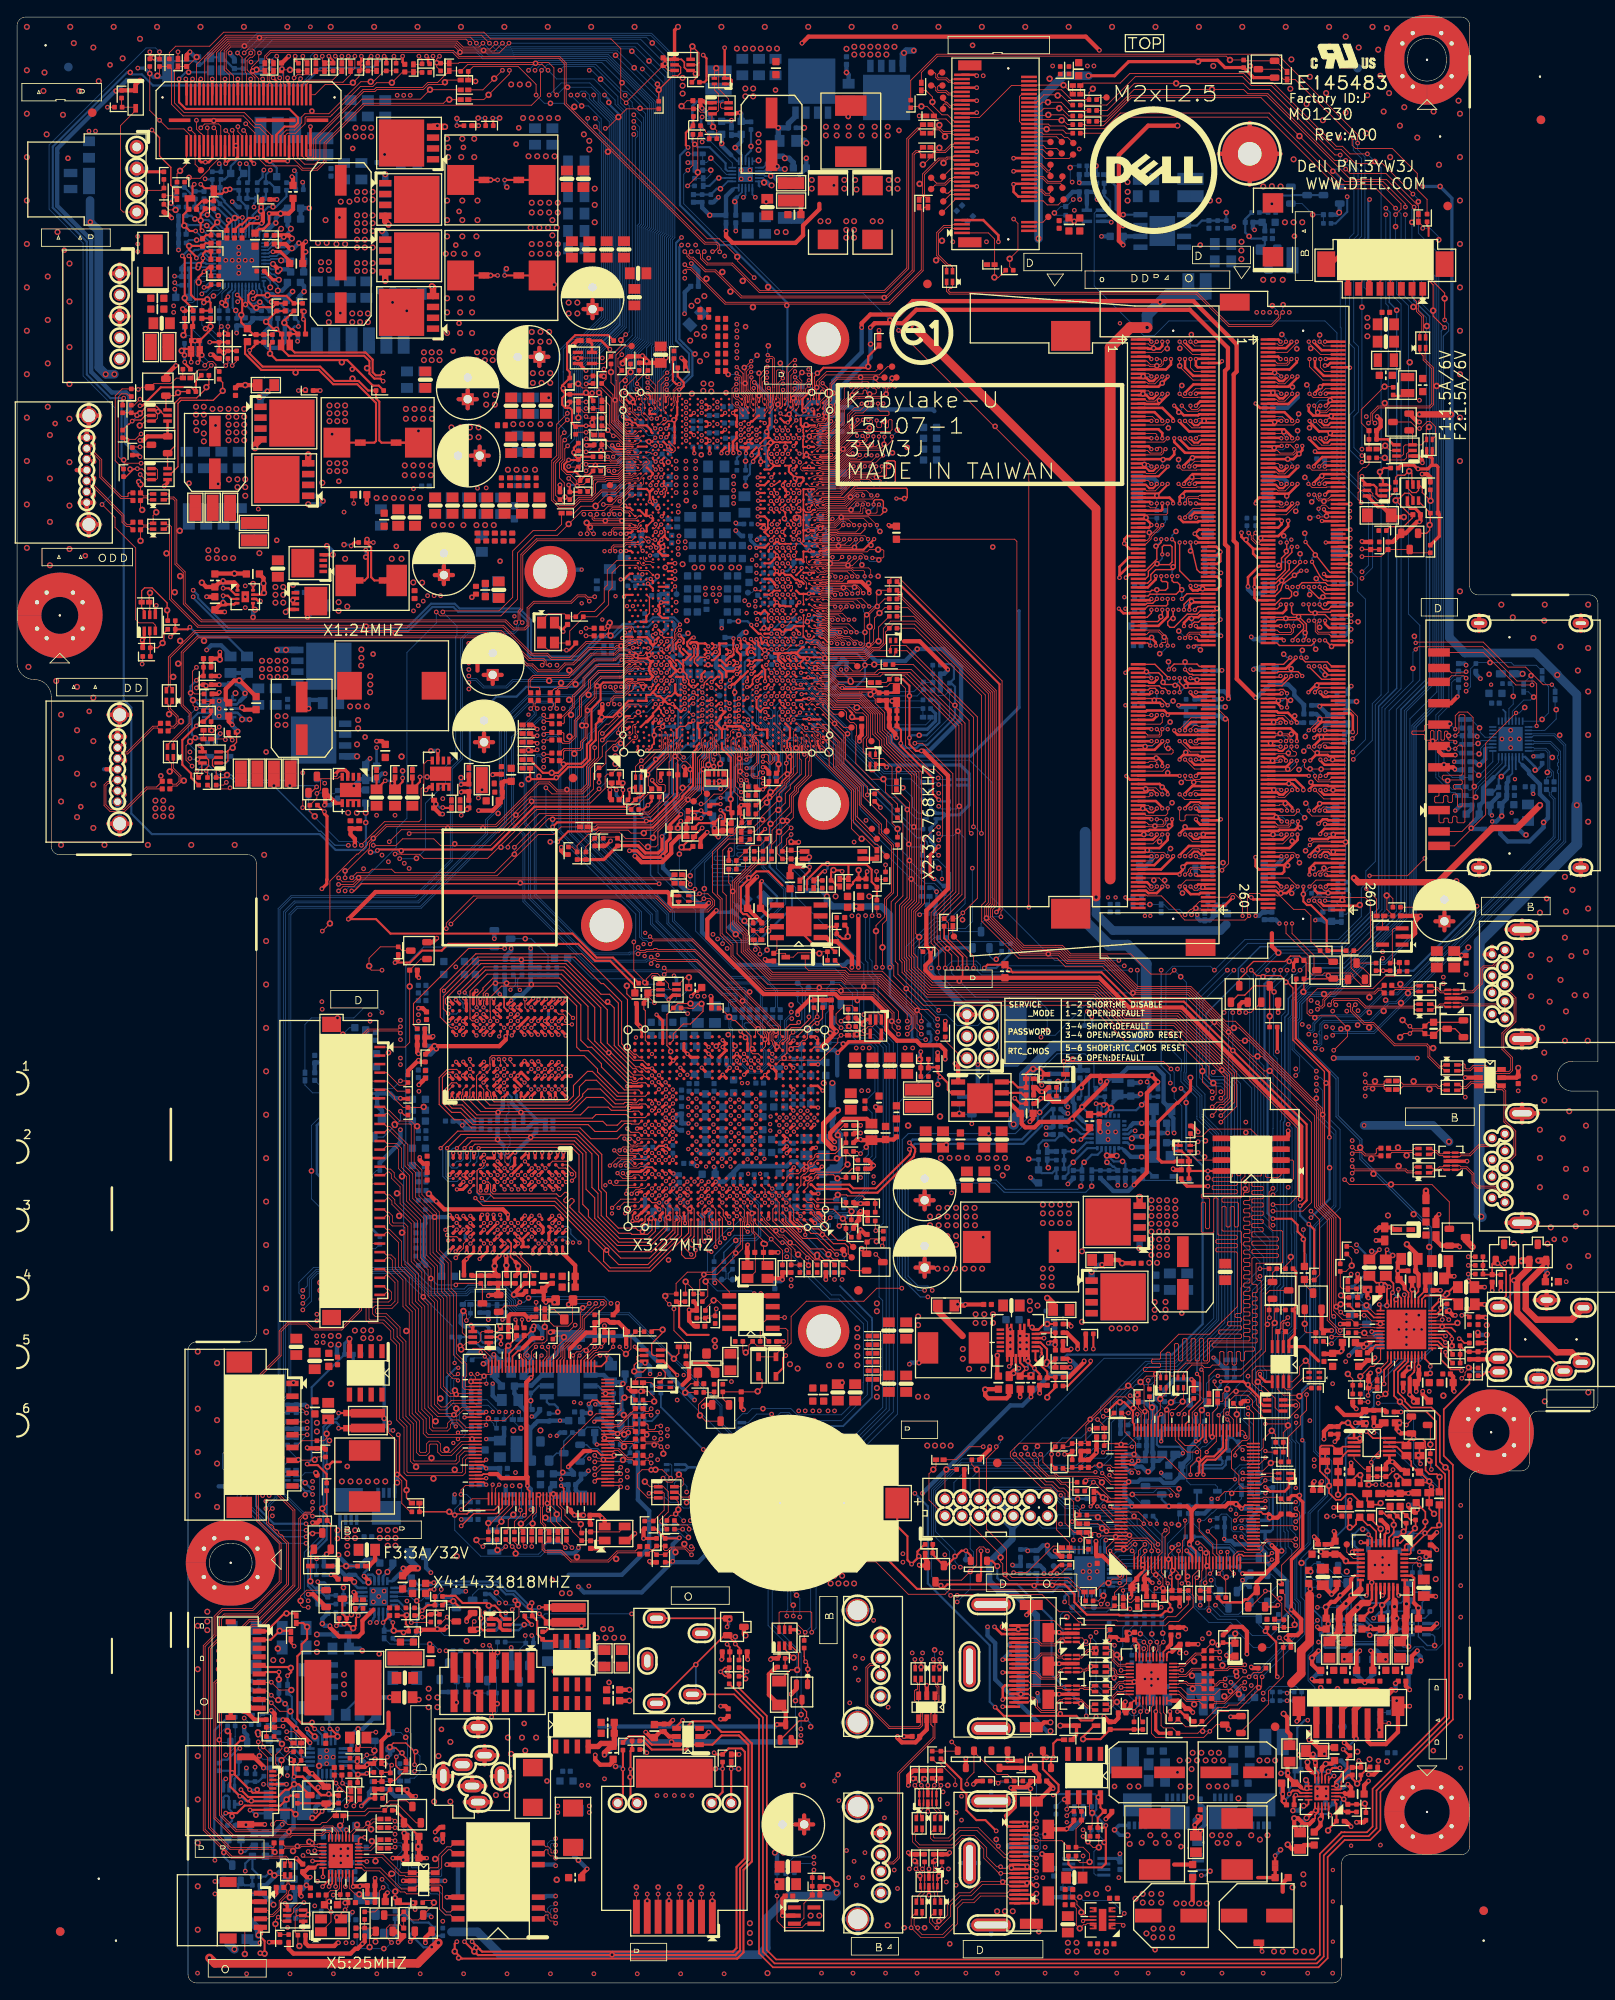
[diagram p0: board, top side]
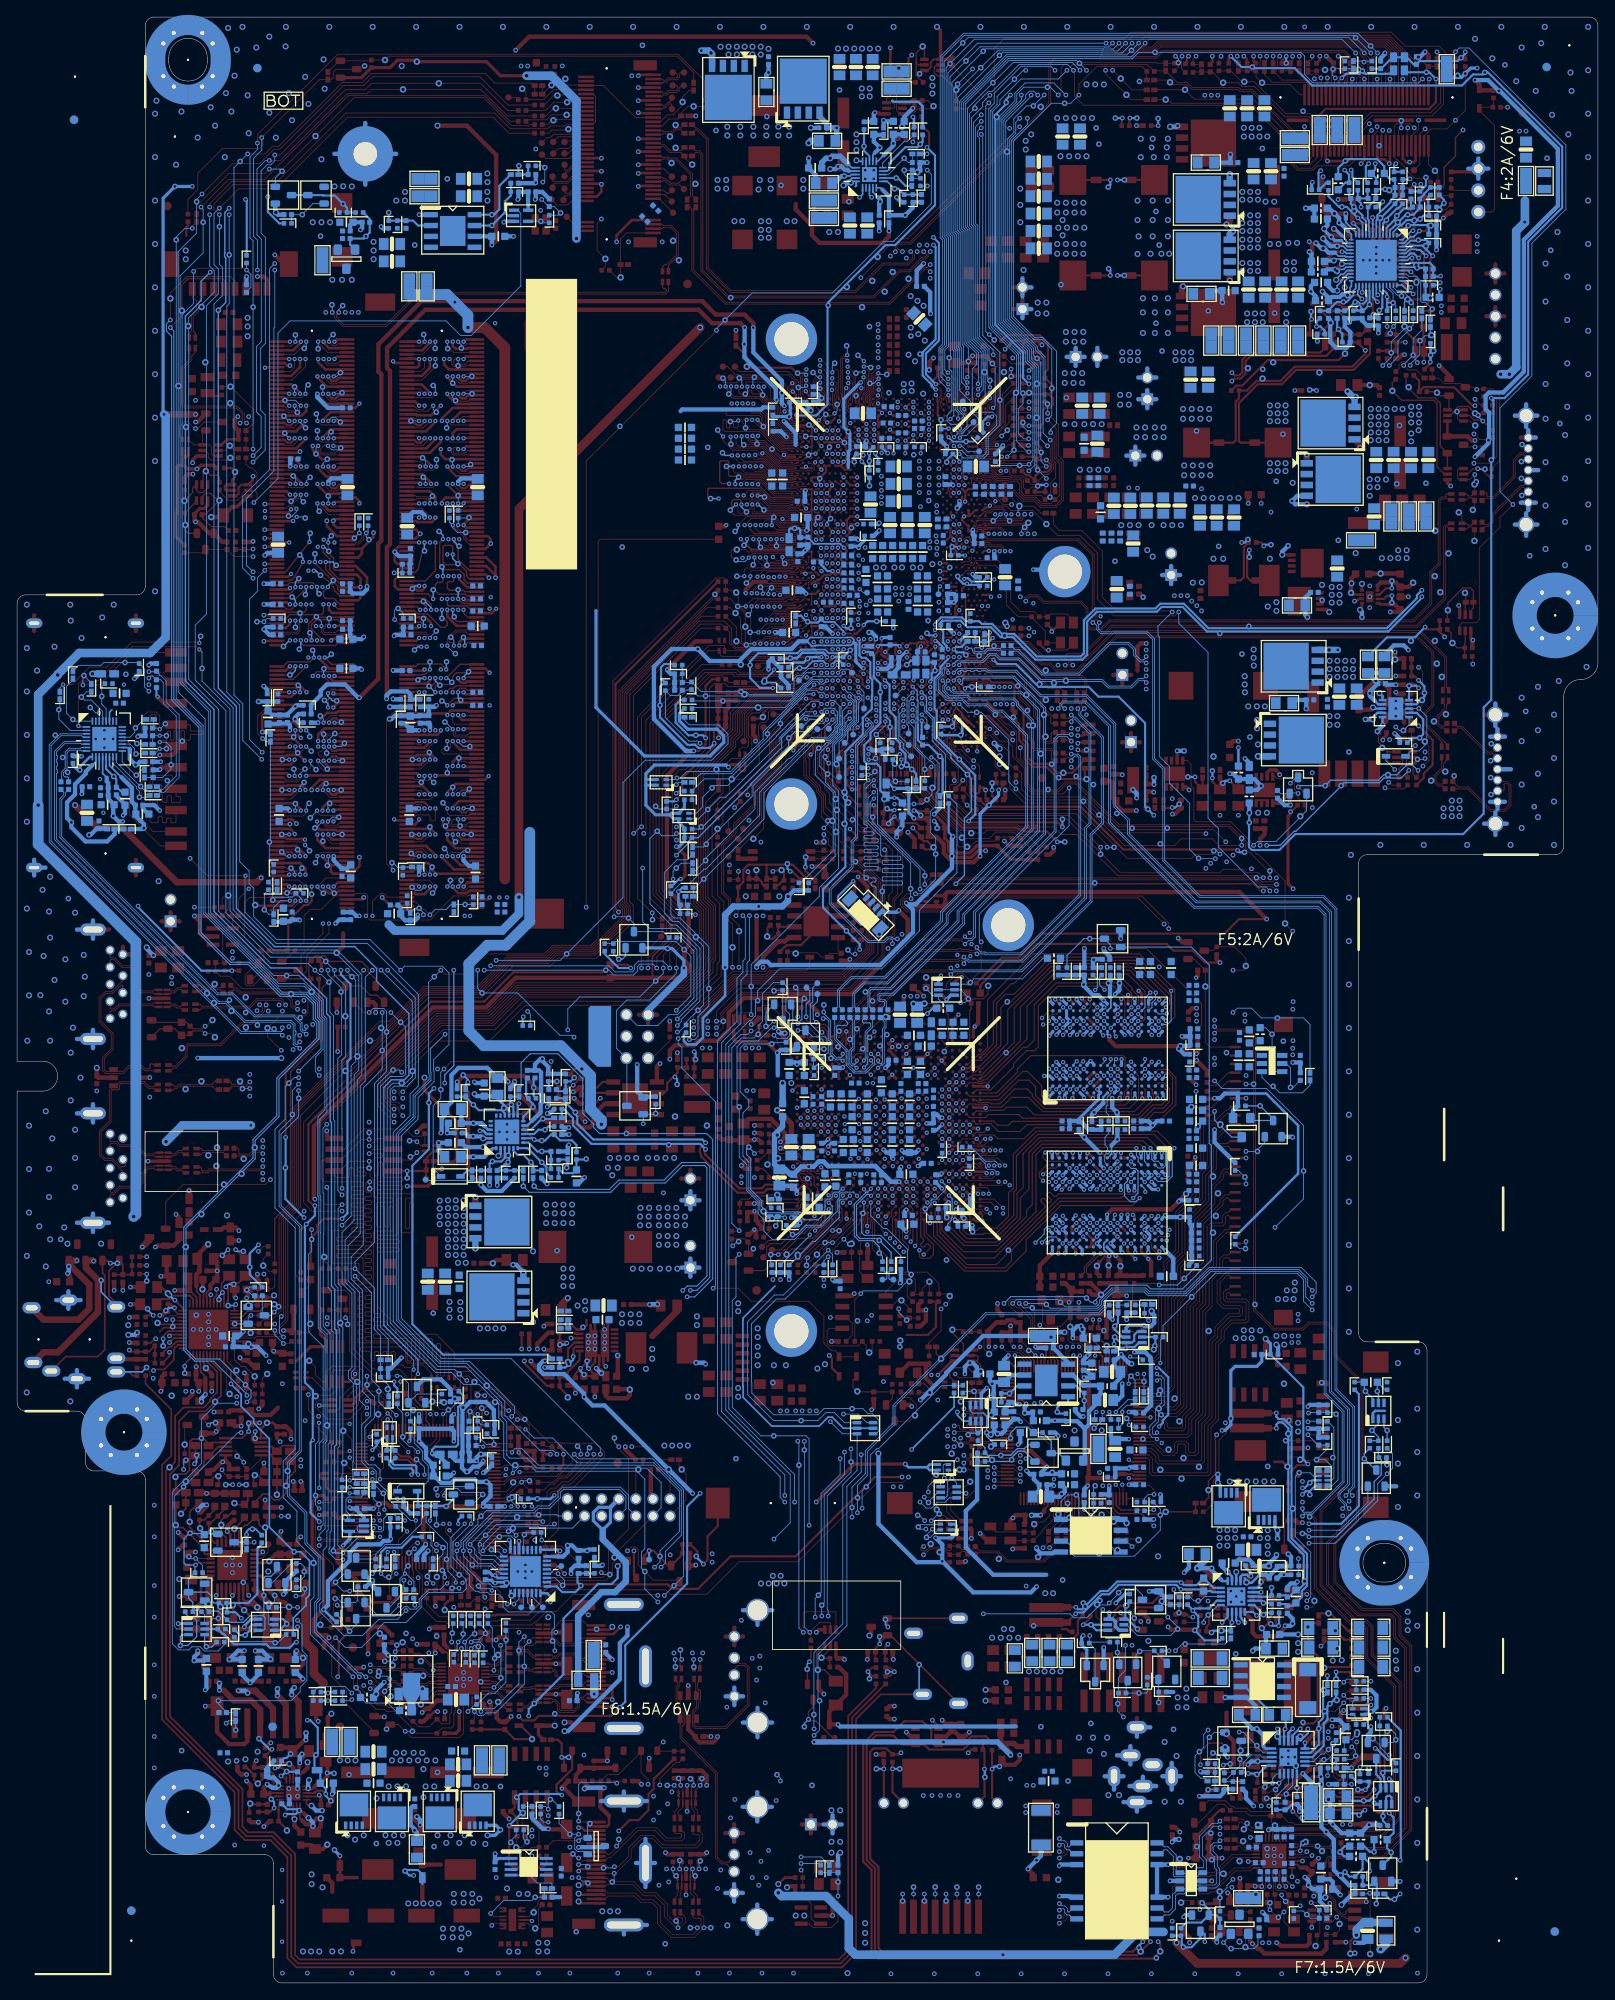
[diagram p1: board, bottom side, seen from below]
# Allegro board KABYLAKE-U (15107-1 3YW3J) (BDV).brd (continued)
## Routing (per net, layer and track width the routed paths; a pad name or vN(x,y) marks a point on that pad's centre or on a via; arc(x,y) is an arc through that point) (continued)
USB2_P6: length 217.3
  TOP w0.102: v1(87.28,141.6) 87.08,141.81 86.9,141.81 86.77,141.68 86.77,141.3 86.65,141.17 86.25,141.17 86.13,141.3 86.13,142.07 86.77,142.72 86.77,145.29 86.47,145.59 CPU1.AH2 ; TR1.1 109.47,198.37 109.34,198.25 109.15,198.25 109.02,198.12 109.02,197.97 109.19,197.8 138.08,197.8 141.87,194.02 146.76,194.02 147.61,194.87 147.61,195.2 v3(147.35,195.45)
  L3 w0.127: v1(87.28,141.6) 87.47,141.42 87.95,141.42 88.29,141.08 88.29,131.76 96.91,123.14 115.27,123.14 115.59,122.82 129.91,122.82 131.3,121.43 156.16,121.43 159.71,124.98 159.71,187.03 155.23,191.52 155.23,193.93 154.64,194.52 148.03,194.52 147.61,194.94 147.61,195.2 v3(147.35,195.45)
  BOTTOM w0.102: v3(147.35,195.45) 147.35,195.78 v2(146.9,196.24)
USB2_PWR_EN: length 12.5
  TOP w0.102: v3(88.93,10.16) 88.93,7.24 89.7,6.48 91.85,6.48 92.3,6.92 U25.4
  BOTTOM w0.102: v3(88.93,10.16) v2(88.93,11.81) C605.1 R857.2 R856.2
USB2N_EXT: length 20.3
  TOP w0.102: TR7.2 105.78,35.34 105.58,35.14 105.58,33.68 D8.3 105.51,32.26 105.98,31.79 105.98,30.14 105.6,29.76 102.05,29.76 101.99,29.82 99.33,32.47 99.33,36.92 99.77,37.35 100.38,37.35 USB3.2
USB2P_EXT: length 20.3
  TOP w0.102: USB3.3 101.06,36.69 100.62,37.13 99.86,37.13 99.55,36.83 99.55,32.56 102.14,29.97 105.51,29.97 105.76,30.23 105.76,30.66 D8.4 105.76,31.17 105.76,31.7 105.29,32.17 105.29,32.77 105.04,33.02 105.04,34.19 105.14,34.29 105.27,34.29 105.37,34.39 105.37,35.09 105.1,35.35 TR7.3
USB3_PWR_EN: length 7.1
  TOP w0.102: U5.4 159.8,124.65 R215.2 C74.1 161.01,124.9 160.31,125.6 160.31,127.2 v4(160.28,127.23) 160.64,127.23 161.01,126.86 R214.2
USB3_TX0_EMI_DN: length 3.9
  TOP w0.102: v4(162.77,115.8) 162.77,116.22 ; 162.77,116.22 161.28,116.22 C82.2 ; 162.77,116.22 163.36,116.22 163.6,115.99 L5.1
USB3_TX0_EMI_DP: length 3.9
  TOP w0.102: v4(161.88,116.87) 161.88,116.44 ; 161.88,116.44 163.36,116.44 163.6,116.67 L5.4 ; 161.88,116.44 161.15,116.44 C81.2
USB3_TX1_EMI_DN: length 4.1
  TOP w0.102: L9.1 163.47,96.94 163.24,97.17 162.62,97.17 ; C101.2 160.9,97.17 162.62,97.17 ; 162.62,97.17 v4(162.62,96.82)
USB3_TX1_EMI_DP: length 4.1
  TOP w0.102: L9.4 163.47,97.62 163.24,97.39 161.6,97.39 ; 161.6,97.39 160.77,97.39 C100.2 ; 161.6,97.39 v4(161.6,97.74)
USB3N_EXT: length 25.9
  TOP w0.102: USB4.2 101.09,14.79 101.74,14.14 102.49,14.14 103.07,14.72 103.07,24.6 107.2,28.73 107.2,29.97 106.94,30.23 106.94,31.5 107.41,31.97 D8.1 107.67,33.86 107.67,34.57 107.53,34.71 107.53,35.08 107.26,35.34 TR8.3
USB3P_EXT: length 25.8
  TOP w0.102: TR8.2 107.94,35.37 107.74,35.17 107.74,34.8 107.88,34.66 107.88,33.02 107.63,32.77 107.63,31.88 107.41,31.66 D8.6 107.41,28.64 103.28,24.51 103.28,14.63 102.58,13.92 101.98,13.92 USB4.3
USB30_RX_CPU_N0: length 127.1
  TOP w0.102: v3(154.34,114.43) 154.05,114.72 154.05,114.84 154.14,114.94 156.88,114.94 157.75,114.07 159.93,114.07 ; 159.93,114.07 163.36,114.07 163.6,113.83 L6.1 ; 159.93,114.07 v4(159.93,113.72) ; v1(76.69,148.72) 76.36,149.05 CPU1.H8
  L3 w0.127: v3(154.34,114.43) 154.03,114.73 154.03,115.93 153.56,116.41 128.58,116.41 126.79,118.2 95.16,118.2 80.43,132.94 74.2,132.94 67.09,140.05 67.09,145.73 68.79,147.43 69.74,147.43 70.59,148.29 76.26,148.29 v1(76.69,148.72)
USB30_RX_CPU_N1: length 143.9
  TOP w0.102: 158.73,95.02 162.44,95.02 162.68,94.78 L10.1 ; 158.73,95.02 v4(158.73,94.67) ; 158.73,95.02 156.52,95.02 v3(156.24,94.74) ; v1(76.69,147.8) 77.01,148.12 CPU1.J6
  L3 w0.127: v1(76.69,147.8) 76.49,147.6 76.49,147.32 76.11,146.95 73.44,146.95 73.2,147.18 70.63,147.18 69.22,145.77 69.22,144.35 68.88,144 68.88,139.25 74.48,133.65 80.7,133.65 94.79,119.56 113.52,119.56 114.06,119.01 126.96,119.01 128.81,117.16 154.5,117.16 155.11,116.55 155.11,113.01 155.74,112.39 155.74,101.22 157.84,99.11 157.84,95.56 157.26,94.97 156.47,94.97 v3(156.24,94.74)
USB30_RX_CPU_P0: length 127.1
  TOP w0.102: v1(76.04,148.72) 75.71,149.05 CPU1.G8 ; v4(161.96,114.66) 161.96,114.28 ; 161.96,114.28 163.36,114.28 163.6,114.51 L6.4 ; 161.96,114.28 157.84,114.28 156.97,115.15 154.05,115.15 153.83,114.93 153.83,114.68 v3(153.58,114.43)
  L3 w0.127: v1(76.04,148.72) 75.87,148.55 70.48,148.55 69.63,147.7 68.68,147.7 66.98,146 66.82,145.84 66.82,139.94 74.09,132.67 80.32,132.67 95.05,117.93 126.67,117.93 128.47,116.14 153.45,116.14 153.77,115.82 153.77,114.62 v3(153.58,114.43)
USB30_RX_CPU_P1: length 143.8
  TOP w0.102: L10.4 163.56,95.46 163.43,95.34 163.43,95.13 163.3,95 162.77,95 162.53,95.23 161.68,95.23 ; CPU1.H6 76.36,148.12 v1(76.04,147.8) ; 161.68,95.23 v4(161.68,95.58) ; 161.68,95.23 156.52,95.23 v3(156.24,95.5)
  L3 w0.127: v3(156.24,95.5) 156.51,95.24 157.14,95.24 157.58,95.67 157.58,99 155.47,101.11 155.47,112.28 154.85,112.9 154.85,116.44 154.39,116.89 128.7,116.89 126.85,118.75 113.95,118.75 113.41,119.29 94.68,119.29 80.59,133.38 74.37,133.38 68.61,139.14 68.61,144.12 68.96,144.46 68.96,145.88 70.52,147.45 73.31,147.45 73.55,147.21 76,147.21 76.22,147.43 76.22,147.62 v1(76.04,147.8)
USB30_TX_CPU_N0: length 126.8
  TOP w0.089: CPU1.C13 72.8,152 72.61,152 72.43,152.08 72.25,152.08 72.09,152.01 71.91,152.01 71.75,152.09 71.62,152.09 71.42,152.01 71.36,151.95 71.36,151.46 70.84,150.94 70.07,150.94 69.63,151.38 69.63,151.44
  TOP w0.102: 158.25,115.71 v4(158.25,115.32) ; 158.25,115.71 158.91,115.71 159.36,116.16 159.65,116.16 C82.1 ; 158.25,115.71 153.79,115.71 153.03,114.95 153.03,114.34 152.75,114.06 152.32,114.06 v3(152.18,113.92) ; 69.63,151.44 69.43,151.64 v1(69.43,151.64)
  L3 w0.127: v1(69.43,151.64) 69.61,151.45 69.61,151.24 69.41,151.04 67.79,151.04 67.2,150.46 67.2,148.45 65.3,146.55 65.3,139.49 73.55,131.24 79.77,131.24 94.5,116.51 126.12,116.51 128.47,114.16 151.94,114.16 v3(152.18,113.92)
USB30_TX_CPU_N1: length 136.9
  TOP w0.102: CPU1.B13 72.12,151.6 72.12,151.38 71.86,151.13 71.69,151.13 70.93,150.37 69.93,150.37 69.72,150.15 69.72,149.77 v1(69.88,149.61) ; 158.48,96.76 159.6,96.76 C101.1 ; 158.48,96.76 157.73,96.76 157.31,97.18 156.4,97.18 v3(156.24,97.03) ; 158.48,96.76 v4(158.48,96.42)
  L3 w0.127: v3(156.24,97.03) 156.52,97.31 156.73,97.31 157.15,97.72 157.15,98.82 154.97,100.99 154.97,112 153.08,113.89 153.08,115.11 152.48,115.71 128.29,115.71 126.5,117.49 94.88,117.49 80.15,132.23 73.93,132.23 66.28,139.88 66.28,146.13 68.36,148.21 68.99,148.21 69.66,148.88 69.66,149.39 v1(69.88,149.61)
USB30_TX_CPU_P0: length 126.9
  TOP w0.089: 69.93,151.51 69.93,151.35 70.15,151.13 70.76,151.13 71.17,151.54 71.17,152.03 71.33,152.19 71.39,152.19 71.59,152.27 71.79,152.27 71.95,152.19 72.05,152.19 72.21,152.26 72.47,152.26 72.65,152.17 73.28,152.17 CPU1.D13
  TOP w0.102: 153.21,115.43 v4(152.94,115.7) ; 153.21,115.43 153.7,115.93 158.82,115.93 159.28,116.38 159.65,116.38 C81.1 ; 153.21,115.43 152.81,115.04 152.81,114.43 152.66,114.27 152.47,114.27 152.18,114.57 v3(152.18,114.68) ; 69.93,151.51 v1(70.06,151.64)
  L3 w0.127: v3(152.18,114.68) 151.93,114.43 128.58,114.43 126.23,116.78 94.61,116.78 79.88,131.51 73.66,131.51 65.57,139.6 65.57,146.43 67.47,148.34 67.47,150.35 67.9,150.77 69.52,150.77 69.88,151.13 69.88,151.45 v1(70.06,151.64)
USB30_TX_CPU_P1: length 136.9
  TOP w0.102: 157.18,97.4 156.64,97.4 v3(156.24,97.79) ; 157.18,97.4 v4(157.18,97.74) ; 157.18,97.4 157.4,97.4 157.82,96.98 158.94,96.98 159.06,97.1 159.06,97.54 159.19,97.66 C100.1 ; CPU1.A13 71.69,151.43 70.84,150.58 69.84,150.58 69.5,150.24 69.5,149.94 v1(69.17,149.61)
  L3 w0.127: v3(156.24,97.79) 156.46,97.57 156.62,97.57 156.88,97.83 156.88,98.71 154.71,100.88 154.71,111.89 152.81,113.78 152.81,115 152.37,115.44 128.18,115.44 126.39,117.23 94.77,117.23 80.04,131.96 73.82,131.96 66.01,139.77 66.01,146.24 68.25,148.48 68.88,148.48 69.4,148.99 69.4,149.38 v1(69.17,149.61)
USB_EN_S3WAKE: length 165.8
  TOP w0.102: v1(140.62,66.42) 140.74,66.3 KBC1.71 ; R214.1 v3(164.24,125.86)
  L3 w0.127: v1(140.62,66.42) 140.62,66.13 139.97,65.49 139.97,58.54 137.07,55.63 137.07,55.63 135.55,54.11 135.55,53.54 135.45,53.44 135.45,51.08 132.43,48.06 130.08,48.06 129.27,47.24 129.25,47.24 129.24,47.23 128.75,47.23 128.35,46.84 128.35,43.1 v3(126.27,41.02)
  L4 w0.127: v3(93.25,13.97) 92.78,14.44 92.78,15.28 93.63,16.13 93.63,23.43 94.68,24.47 103.68,24.47 110.83,31.62 115.38,31.62 121.91,38.15 122.61,38.15 125.48,41.02 v3(126.27,41.02) ; v3(164.24,125.86) 162.59,125.86 159.04,122.3 159.04,117.35 159.55,116.84 159.55,95.66 157.35,93.46 157.35,85.28 156.78,84.71 153.83,84.71 151.8,82.68 v3(145.45,82.68)
  BOTTOM w0.102: v3(93.25,13.97) 91.16,13.97 R856.1 ; v3(145.45,82.68) 143.53,80.76 143.53,70.6 142.65,69.72 v2(142.65,69.22) 142.65,67.94 141.89,67.18 141.38,67.18 v1(140.62,66.42)
USB_OC#0_1: length 146.6
  TOP w0.102: U5.3 161.13,123.38 160.94,123.19 160.94,119.57 R229.2 161.7,119.32 C79.1 R231.1 161.18,117.78 160.1,117.78 158.66,116.33 152.17,116.33 150.96,115.12 150.96,113.48 151.28,113.16 154.26,113.16 v4(155.7,111.72) 155.7,110.73 v3(154.08,109.12) ; CPU1.A9 71.69,149.28 68.58,146.18 v3(68.49,146.18)
  L4 w0.127: v3(68.49,146.18) 68.74,145.92 69.71,145.92 71.83,143.8 71.83,141.54 72.64,140.72 72.64,135.61 75.14,133.11 75.75,133.11 87.58,121.28 112.36,121.28 112.36,121.29 112.73,121.29 125.56,108.46 145.71,108.46 150.62,103.54 152.4,103.54 153.32,104.46 153.32,108.43 154.01,109.12 v3(154.08,109.12)
USB_OC#2_3: length 215.8
  TOP w0.102: CPU1.C9 72.72,149.6 71.53,149.6 71.37,149.45 71.37,149.4 69.24,147.27 68.93,147.27 68.03,146.37 68.03,145.23 68.05,145.2 68.05,143.4 66.86,142.21 66.86,140.14 66.06,139.34 63.16,139.34 62.22,140.28 61.09,140.28 56.09,135.28 43.23,135.28 41.23,133.29 41.23,132.77 38.39,129.92 v3(38.39,129.29) ; v3(93.25,13.21) 93.06,13.02 R515.2 R516.1 C271.1 92.08,9.31 92.08,7.56 91.45,6.92 U25.3
  L3 w0.127: v3(38.39,129.29) 39.62,128.06 39.62,127.57 38.92,126.87 38.87,126.87 34.69,122.7 34.69,85.05 44.76,74.99 44.76,66.01 54.19,56.58 60.29,56.58 60.55,56.32 60.55,51.4 60.7,51.25 60.7,47.28 64.05,43.93 85.31,43.93 86.39,42.85 86.39,35.18 89.57,32 89.57,25.53 94.39,20.7 94.39,14.35 v3(93.25,13.21)
  BOTTOM w0.102: v3(38.39,129.29) 38.39,130.1 38.39,130.1 v2(38.39,130.11)
USB_PCH_DN4_NN: length 6.6
  TOP w0.102: 163.77,196.09 163.77,195.55 164.39,194.93 164.39,193.28 164.16,193.05 TR2.2 ; 163.77,196.09 163.77,196.73 163.25,197.25 WEBCM1.2 ; 163.77,196.09 v4(163.41,196.09)
USB_PCH_DP4_PP: length 6.6
  TOP w0.102: 164.61,193.85 164.61,193.28 164.84,193.05 TR2.3 ; 164.61,193.85 v4(164.98,193.85) ; 164.61,193.85 164.61,195.01 163.98,195.64 163.98,196.73 164.5,197.25 WEBCM1.1
USB_TOUCH_N: length 8
  TOP w0.102: v4(31.91,10.01) 31.64,10.27 ; 31.64,10.27 30.89,9.53 30.89,8.71 29.95,7.77 29.64,7.77 29.38,7.5 TOUCH1.4 ; 31.64,10.27 31.78,10.41 31.78,10.73 C267.1 31.81,11.59 31.81,12.19 32,12.37 TR13.3
USB_TOUCH_P: length 8.7
  TOP w0.102: TOUCH1.3 29.37,8.5 29.49,8.38 29.49,8.1 29.61,7.98 29.86,7.98 30.68,8.8 30.68,9.61 31.57,10.5 31.57,10.82 C266.1 31.6,11.56 31.6,12.19 31.32,12.48 TR13.2 v4(30.11,12.58)
USBCOMP: length 3.7
  TOP w0.102: v1(83.4,147.59) 83.22,147.41 CPU1.AB6
  BOTTOM w0.102: R609.1 83.98,145.57 v2(84.46,146.05) 83.4,147.12 v1(83.4,147.59)
USBP0N_EXT: length 21
  TOP w0.102: TR3.3 170.08,106.72 170.23,106.87 170.48,107.12 170.77,107.12 D3.1 171.03,106.9 171.25,107.12 171.83,107.12 172.55,106.4 174.66,106.4 175.01,106.76 175.01,108.28 173.98,109.31 173.98,111.04 175.41,112.46 175.41,115.25 174.68,115.98 173.92,115.98 172.62,117.28 SSUSB1.2
USBP0P_EXT: length 20.9
  TOP w0.102: SSUSB1.3 172.62,116.63 172.72,116.73 172.86,116.73 173.83,115.76 174.59,115.76 175.19,115.16 175.19,112.55 173.77,111.13 173.77,109.22 174.8,108.19 174.8,106.85 174.57,106.62 173.97,106.62 D3.6 173.4,106.87 173.15,106.62 172.64,106.62 171.91,107.34 170.39,107.34 169.99,106.94 169.58,106.94 169.45,107.06 169.45,107.42 169.32,107.54 169.19,107.54 169.04,107.4 TR3.2
USBP1N_EXT: length 18.8
  TOP w0.102: TR4.3 168.75,104.43 168.94,104.63 169.6,104.63 170.19,105.22 170.48,105.22 170.73,104.97 D3.3 171.43,104.97 171.69,105.22 172.87,105.22 173.03,105.05 173.03,104.6 173.13,104.5 173.79,104.5 174,104.28 174,100.74 175.17,99.57 175.17,96.95 174.66,96.44 173.81,96.44 172.85,95.48 172.49,95.48 172.32,95.66 172.32,96.04 SSUSB2.2
USBP1P_EXT: length 18.7
  TOP w0.102: SSUSB2.3 172.62,94.95 173.9,96.23 174.75,96.23 175.38,96.86 175.38,99.66 174.21,100.83 174.21,104.37 173.72,104.87 D3.4 173.45,104.97 172.98,105.44 170.1,105.44 169.51,104.85 169,104.85 168.73,105.12 TR4.2
USBVCC01: length 36.3
  TOP w0.508: D3.5 175.48,105.92 C94.2 v5(175.67,107.06) ; 171.73,120.34 SSUSB1.1 172.62,121.23 ; 165.98,124.21 TC3.1 ; TC3.1 167.04,123.15 ; TC3.1 168.09,124.21 ; TC3.1 167.04,125.26
  L3 w1.016: v5(175.67,107.06) 172.62,104.01 SSUSB2.1
  L3 w1.27: v5(169.83,121.16) 170.77,120.22 170.77,111.96 v5(175.67,107.06)
  BOTTOM w0.508: v2(169.04,120.22) 169.71,120.88 169.71,121.03 v5(169.83,121.16)
USBVCC23: length 30.8
  TOP w0.508: 92.11,17.49 TC4.1 ; TC4.1 92.11,19.6 ; TC4.1 91.05,18.54 ; TC4.1 93.16,18.54 ; v3(103.03,28.83) 103.03,28.66 103.54,28.14 105.14,28.14 105.63,28.64 C241.1 106.46,29.65 D8.5 ; USB3.1 102.09,40.53 ; USB3.1 100.03,40.53 ; USB3.1 101.06,41.56 ; USB3.1 101.06,39.5 ; 100.06,17.53 USB4.1 ; USB4.1 101.09,16.5 ; USB4.1 101.09,18.56 ; USB4.1 102.12,17.53
  L3 w0.508: USB3.1 102.24,39.35 102.24,35.2 103.03,34.42 v3(103.03,28.83)
USBVCCTP: length 7.9
  TOP w0.254: v5(28.27,5.59) 28.28,5.59 28.96,4.91 v4(28.96,3.43)
  TOP w0.635: TOUCH1.5 28.47,5.8 v5(28.27,5.59)
  BOTTOM w0.889: F7.2 24.82,7.06 C623.1 27.47,7.06 28.27,6.26 v5(28.27,5.59)
V_1P5_HDMI: length 22.3
  TOP w0.203: U17.12 134.15,38.74 134.65,39.24 ; U17.40 135.16,33.02 ; U17.20 130.95,39.27 130.72,39.5 ; 130.34,32.66 130.69,33.02 U17.31 ; U17.19 131.35,39.56 C213.1
  TOP w0.508: 130.34,32.66 130.34,32.3 129.76,31.73 C235.1 129.57,31.79 129.57,32.77 v3(129.7,32.89) ; 134.65,39.24 135.03,39.62 C210.1 ; 135.16,33.02 135.88,33.02 C233.1 137.17,32.09 137.6,31.66 v3(137.6,31.65)
  L3 w0.508: v3(129.7,32.89) 136.35,32.89 v3(137.6,31.65)
  vias: v2(139.48,40.89) v3(138.72,40.26)
V_1P05_LAN: length 6.1
  TOP w0.203: U23.30 38.48,11.33 v3(38.42,11.28) ; U23.24 v3(35.79,12.42) ; U23.8 39.96,16.81 40.17,17.02 v3(40.67,17.02) ; U23.3 40.88,14.26 v3(40.93,14.21) ; U23.22 v3(34.58,14.26)
  vias: v2(32.8,16) v2(41.05,18.66) v3(35.16,11.89)
V_3_CARD: length 21.7
  TOP w0.508: v3(168.31,143.66) 166.83,143.66 166.41,144.09 MEMCD1.4
  L3 w0.508: v1(172.63,135.89) 171.71,135.89 170.59,137.01 170.59,141.38 v3(168.31,143.66)
  BOTTOM w0.203: U28.12 174.98,141.5 174.51,141.02
  BOTTOM w0.508: 174.51,141.02 174.51,140.56 174.34,140.4 C401.2 C403.2 174.34,138.54 C405.1 173.74,137.74 v2(173.74,136.53) 173.11,135.89 v1(172.63,135.89)
V_3P0_BAT_VREG: length 186.3
  TOP w0.254: R397.2 126.02,56.13 v1(125.64,55.75) ; v3(112.81,50.55) 112.81,47.64 D7.3 ; v3(107.86,138.43) 107.17,139.12 107.17,140.95 103.41,144.71 v3(103.41,145.03) 103.44,145.06 103.44,146.6 C45.1 C42.1 C37.1 102.97,149.8 R137.1 ; R293.2 150.66,87.12 149.85,87.92 149.85,88.68 149.13,89.41 v3(146.97,89.41)
  L3 w0.254: v3(112.81,50.55) 114.49,52.22 122.53,52.22 125.64,55.33 v1(125.64,55.75) 125.68,55.75 126.19,56.26 128.69,56.26 129.82,57.39 130.9,57.39 132.97,59.46 132.97,61.05 137.14,65.22 137.14,69.02 143.21,75.1 143.21,85.65 v3(146.97,89.41)
  L4 w0.254: v3(107.86,138.43) 108.36,138.43 109.32,137.48 109.32,135.3 113.27,131.34 113.72,131.34 120.44,124.62 120.44,124.13 128.82,115.75 135.54,115.75 139.58,119.79 144.15,119.79 145.98,117.96 146.57,117.96 v3(147.1,118.49)
  BOTTOM w0.254: R629.1 108.05,138.24 v3(107.86,138.43) ; R578.1 108.17,154.31 109.26,154.31 109.63,153.93 109.63,152.59 R590.1 109.32,152.08 109.76,151.64 v2(109.76,149.48) 109.76,148.07 106.55,144.86 105.64,144.86 105.28,144.5 103.94,144.5 v3(103.41,145.03) ; v3(147.1,118.49) 147.1,117.98 145.98,116.87 145.98,108.15 146.34,107.8 146.34,90.04 v3(146.97,89.41)
V_3P3_A: length 411.2
  TOP w0.203: v1(139.1,63.37) 139.14,63.41 KBC1.75
  TOP w0.254: v3(37.37,41.78) 37.69,42.1 PR100.1 ; v3(147.54,44.2) 147.35,44.01 Q41.S ; D7.1 114.1,49.39 v5(114.71,48.77) ; 146.34,40.89 147.35,39.88 147.35,35.94 v3(147.48,35.81) ; PR102.1 PR101.1 48.1,43.12 47.79,42.8 v3(47.4,42.8) ; v3(150.15,90.93) 150.28,90.93 150.91,91.56 150.91,100.45 136.55,114.81 130.35,114.81 126.92,118.24 116.49,118.24 R230.1 113.57,119.13 v3(113.19,118.75) ; R371.1 121.06,62.29 v3(121.06,61.85) 121.06,60.64 R383.1 ; R296.1 151.8,88.14 v3(151.16,88.77)
  L3 w0.254: v3(47.4,42.8) 47.38,42.82 45.65,42.82 44.33,41.5 37.65,41.5 v3(37.37,41.78) 36.74,41.15 35.97,41.15 35.21,41.91 35.21,45.59 34.45,46.35 34.45,53.09 v3(33.82,53.72) ; v3(128.94,12.32) 126.78,14.48 126.78,29.59 v3(125.13,31.24) ; v3(158.76,42.67) 157.26,42.67 150.4,35.81 v3(147.48,35.81)
  L4 w0.254: v3(125.13,31.24) 125.89,32 129.95,32 130.51,32.56 143.55,32.56 146.81,35.81 v3(147.48,35.81) ; v3(47.4,42.8) 47.58,42.8 48.24,43.46 50.6,43.46 51.57,42.49 51.57,42.4 52.34,41.63 57.18,41.63 59.02,43.47 59.02,46.35 61.9,49.23 69.29,49.23 69.54,49.48 72.84,49.48 73.9,50.53 77.26,50.53 78.37,49.43 79.2,49.43 81.38,51.61 95.45,51.61 96.05,51.02 105.08,51.02 106.7,49.4 114.08,49.4 v5(114.71,48.77) ; v3(121.06,61.85) 122.52,63.31 124.71,63.31 124.91,63.51 129.89,63.51 130.03,63.37 132.75,63.37 133.26,62.87 138.34,62.87 138.84,63.37 v1(139.1,63.37) 139.23,63.25 150.15,63.25 v1(150.4,63.5) ; v3(147.54,44.2) 148.62,45.28 148.62,52.96 v3(149.64,53.98) ; v3(37.37,41.78) 37.37,41.61 36.88,41.12 36.25,41.12 35.87,41.5 32.86,41.5 29.96,38.61 28.94,38.61 25.46,35.12 25.46,31.86 25.28,31.68 25.28,29.28 27.08,27.47 27.08,26.01 v3(27.85,25.25)
  BOTTOM w0.254: v2(38.29,42.01) 38.06,41.78 v3(37.37,41.78) 37.31,41.85 PR254.2 ; v3(158.76,42.67) 159.46,43.37 R787.1 160.43,44.39 R786.1 157.94,44.45 156.88,45.51 156.88,50.8 156.37,51.31 R774.1 ; v1(139.1,63.37) 138.97,63.5 R732.1 ; v3(33.82,53.72) 30.05,53.72 27.97,55.8 27.97,68.9 PR241.2 ; v3(150.15,90.93) 150.15,89.79 v3(151.16,88.77) 151.32,88.62 151.32,70.26 150.38,69.32 150.38,68.43 150.4,68.41 v1(150.4,63.5) 150.66,63.25 150.66,54.99 v3(149.64,53.98) ; v5(114.71,48.77) 114.71,47.37 115.41,46.67 117.01,46.67 121.06,42.62 121.06,36.09 v2(124.47,32.69) 125.13,32.03 v3(125.13,31.24) ; v3(113.19,118.75) 114.59,118.75 116.24,120.4 R655.2 ; R839.1 v3(27.85,25.25)
  BOTTOM w0.508: PG21.1 155.74,25.18 PR263.1
V_3P3_LAN: length 93.2
  TOP w0.203: v3(39.34,11.28) 39.28,11.34 U23.32 ; U23.23 35.18,13.86 34.81,13.49 ; U23.11 38.48,17.83 v3(38.56,17.91)
  TOP w0.254: R879.1 44.28,20.19 45.28,19.2 Q82.G 45.44,18.73 C255.1
  TOP w0.305: v3(73.69,26.92) 73.31,27.3 R895.1
  TOP w0.508: v3(39.34,11.28) 39.36,11.3 v3(40.11,11.3) 40.19,11.38 C265.1 R517.1 ; v3(34.3,12.37) 33.89,12.37 33.43,12.83 C262.1 33.65,13.02 34.12,13.49 34.81,13.49 ; C255.1 C258.1 C260.1 v1(47.94,14.61) ; R482.2 v3(84.49,26.73) ; U20.5 76.3,28.83 C238.1 75.28,29.4 C239.1 74.2,28.7 v3(73.57,29.34) ; U24.5 v3(47.53,11.94)
  L3 w0.508: v3(47.53,11.94) 46.39,11.94 44.33,9.88 41.54,9.88 v3(40.11,11.3) ; v3(84.49,26.73) 84.02,26.26 74.35,26.26 v3(73.69,26.92) 73.69,29.21 v3(73.57,29.34) 71.41,29.34 69.83,27.76 69.83,24.97 v3(68.74,23.88)
  L4 w0.508: v3(68.74,23.88) 64.04,23.88 55.7,15.54 48.87,15.54 v1(47.94,14.61) 47.53,14.2 v3(47.53,11.94)
  BOTTOM w0.508: U39.5 v3(47.53,11.94) ; v3(38.56,17.91) 38.49,17.97 C597.1 C598.1 C599.1 ; R865.1 31.72,8.73 32.55,9.55 C614.1 33.41,10.97 v2(33.87,11.43) 33.87,11.94 v3(34.3,12.37)
V_3P3_PCIVAUX: length 46.6
  TOP w0.381: v5(125.38,223.14) 128.43,223.14 130.08,224.79 v4(138.21,224.79) 138.37,224.96 140.5,224.96 141.36,224.09 R6.1 144.72,222.92 Q2.G
  BOTTOM w1.016: v5(125.38,223.14) 122.46,223.14 119.54,220.22 v5(119.54,204.09)
  vias: v4(120.84,222.78) v5(145.83,199.26) v5(146.97,199.26) v5(148.12,199.26)
V_5_CODEC: length 3.4
  TOP w0.203: U11.39 163.99,80.2 C123.2
  TOP w0.508: C115.1 164.82,82.18 C123.2
  vias: v4(165.26,86.11)
V_5_CODEC_R:
  vias: v4(163.43,89.94)
V_5HDD: length 8.5
  TOP w0.508: 12,198.93 SATAP1.1 ; SATAP1.1 12,201.07 ; SATAP1.1 13.07,200 ; SATAP1.1 10.93,200 ; SATAP1.3 12,196.07 ; SATAP1.3 13.07,195 ; SATAP1.3 12,193.93 ; SATAP1.3 10.93,195
V_5P0_A: length 255.2
  TOP w0.254: v3(114.46,32.26) 115.48,31.24 123.96,31.24 124.49,30.71 125.8,30.71 v3(126.27,31.18) ; R129.2 R131.2 ; R131.2 18.51,158.05 v3(17.94,157.48) ; R131.2 19.97,158.37 v3(20.23,158.62)
  L3 w0.254: v3(151.04,30.73) 149.64,32.13 138.97,32.13 137.45,33.66 127.67,33.66 126.27,32.26 v3(126.27,31.18)
  L4 w0.254: v3(105.06,57.28) 104.38,57.28 103.39,58.27 83.54,58.27 81.89,59.92 74.19,59.92 73.82,59.92 73.21,60.53 73.21,60.69 70.15,63.75 66.74,63.75 65.2,62.22 55.41,62.22 52.99,64.63 52.99,67.31 38.51,81.79 38.51,114.17 33.61,119.08 33.61,133.19 29.59,137.21 23.8,137.21 17.94,143.07 v3(17.94,157.48)
  BOTTOM w0.254: v3(114.46,32.26) 113.83,32.89 113.83,39.5 106.59,46.74 106.59,55.75 v3(105.06,57.28) ; v3(151.04,30.73) 150.68,30.73 149.82,29.87 149.82,26.87 v2(150.02,26.67) 150.2,26.49 PG22.2 ; PR202.2 24.67,157.43 21.42,157.43 v3(20.23,158.62)
V_5P0_HDMI_CONN: length 2.2
  TOP w0.305: v5(115.35,41.66) 115.69,41.32 HDMI1.18
  vias: v2(117.18,41.38)
V_5P0_HDMI_CONN_L: length 1.7
  BOTTOM w1.016: F6.2 v2(117.46,33.78)
V_19_INV: length 6.3
  TOP w0.508: R484.1 42.64,28.31 v4(43.47,29.13) 43.47,31.62
VD1_EN#: length 3.3
  TOP w0.102: R364.1 142.74,67.42 v4(142.74,66.53) KBC1.66
VD_IN1: length 246.4
  TOP w0.102: v1(126.19,59.77) 122.83,59.77 R383.2 123.36,60.2 R382.2 C171.1 C172.1 125.81,60.31 126.08,60.58 v4(126.7,60.58) 127.92,60.58 128.21,60.3 KBC1.104 ; R112.1 v3(39.4,173.1)
  L3 w0.127: v3(39.4,173.1) 39.4,172.56 38.19,171.35 31.09,171.35 26.5,166.75 26.5,166.19 25.94,165.63 25.94,160.49 23.19,157.73 23.19,145.98 27.09,142.07 46.96,142.07 50.29,138.75 50.29,133.23 37.32,120.26 37.32,85.92 46.95,76.29 46.95,69.57 50.8,65.72 61.16,65.72 62.39,64.49 v1(62.39,64.01)
  L4 w0.127: v1(62.39,64.01) 62.39,65.27 63.86,66.74 72.84,66.74 73.76,67.65 76.76,67.65 84.3,60.11 104.18,60.11 105.02,59.27 125.7,59.27 v1(126.19,59.77)
VD_IN2: length 167.6
  TOP w0.102: v3(121.83,61.85) 121.83,62.17 R371.2 123.11,62.74 R372.2 C167.1 C168.1 125.08,63.41 125.08,65.23 128.42,68.57 129.71,68.57 131.54,66.74 KBC1.94 ; v3(135.42,118.49) 134.96,118.03 132.7,118.03 130.33,120.4 123.32,120.4 122.32,121.39 121.56,121.39 117.83,121.39 117,122.22 117,168.66 116.75,168.91 R119.1
  BOTTOM w0.102: v3(121.83,61.85) 122.28,62.31 123.82,62.31 127.92,66.41 127.92,68.05 132.37,72.49 135.58,72.49 140.62,77.53 140.62,99.35 138.65,101.32 138.65,101.62 138.65,101.62 138.65,103.83 136.79,105.7 136.79,106.45 136.84,106.5 136.84,117.07 v2(136.18,117.73) v3(135.42,118.49)
VD_OUT1#: length 11.9
  TOP w0.102: KBC1.110 134.92,57.9 v1(135.8,57.02)
  BOTTOM w0.102: D18.2 132.12,58.06 135.75,58.06 135.97,57.84 v2(135.97,57.81) 135.97,57.2 v1(135.8,57.02)
VD_OUT2#: length 13.2
  TOP w0.102: KBC1.112 134.96,57.1 v1(135.03,57.02)
  BOTTOM w0.102: D18.1 131.5,56.17 v2(130.51,57.15) 130.74,57.38 132.98,57.38 133.44,57.84 134.6,57.84 135.03,57.4 v1(135.03,57.02)
VGA_CORE_DISCHG: length 4
  BOTTOM w0.102: R666.2 76.11,114.05 77.17,115.11 Q53.3 77.87,115.55 78.62,116.31 78.62,116.33 v2(78.65,116.36)
VIDALERT#_CPU: length 5.8
  TOP w0.089: 70.96,180.16 71.81,180.16 71.87,180.19 72.1,180.19 CPU1.B63
  TOP w0.102: R93.1 68.6,182.18 v3(69.78,181) 70.13,181 70.96,180.16
  BOTTOM w0.102: v2(69.12,181.66) v3(69.78,181)
VIDALERT#_CPU_R: length 82.5
  TOP w0.102: PR26.2 25.69,189.74 v3(25.18,189.23) ; R93.2 R92.2 66.77,183.07 v3(66.58,183.26)
  L4 w0.127: v3(25.18,189.23) 23.15,187.2 20.31,187.2 18.96,185.84 18.96,180.87 19.68,180.15 19.68,177.97 26.82,170.83 46.57,170.83 52.44,176.7 55.23,176.7 56.82,178.29 58.38,178.29 59.37,178.29 63.15,182.07 63.15,183.78 63.99,184.62 65.22,184.62 v3(66.58,183.26)
  BOTTOM w0.102: v3(25.18,189.23) 24.19,190.22 v2(24.19,190.73) 24.19,192 22.64,193.55 PR184.1
VIDSCK_CPU: length 8.9
  TOP w0.102: v4(65.69,183.13) R89.2 66.01,184.09 66.38,183.72 68.53,183.72 68.92,183.33 68.92,182.56 71.05,180.42 CPU1.A63
VIDSCK_CPU_R: length 82.9
  TOP w0.102: v3(66.58,184.98) R89.1 R86.2 ; PR25.2 24.67,189.48 v3(24.42,189.23)
  L4 w0.127: v3(24.42,189.23) 24.89,189.7 24.93,189.7 24.97,189.74 25.39,189.74 25.69,189.44 25.69,189.02 23.27,186.61 20.52,186.61 19.46,185.55 19.46,181.15 20.19,180.42 20.19,180.36 20.19,178.18 27.03,171.34 46.36,171.34 52.23,177.21 55.02,177.21 56.61,178.8 59.16,178.8 62.64,182.28 62.64,183.99 63.78,185.13 66.43,185.13 v3(66.58,184.98)
  BOTTOM w0.102: PR185.1 21.62,193.99 v2(22.05,193.56) 22.05,193.46 23.4,192.1 23.4,190.25 v3(24.42,189.23)
VIDSOUT_CPU: length 9.2
  TOP w0.089: CPU1.D64 73.07,180.99 72.78,180.7 71.05,180.7 69.85,181.9
  TOP w0.102: 69.85,181.9 69.35,182.4 69.35,184.56 68.8,185.1 R88.2 68.44,185.72 v4(68.11,186.06)
VIDSOUT_CPU_R: length 84.9
  TOP w0.102: v3(23.91,193.8) 23.66,193.55 PR22.2 ; R88.1 R87.2 v3(66.58,184.21)
  L4 w0.127: v3(23.91,193.8) 23.53,193.42 23.53,188.34 22.96,187.77 20.16,187.77 18.45,186.06 18.45,180.66 19.17,179.94 19.17,177.76 26.61,170.32 46.78,170.32 52.65,176.19 55.44,176.19 56.93,177.67 59.48,177.67 63.66,181.86 63.66,183.57 64.2,184.11 64.7,184.11 66.02,182.79 66.78,182.79 67.05,183.07 67.05,183.74 v3(66.58,184.21)
  BOTTOM w0.102: PR183.1 23.66,194.06 v3(23.91,193.8) 24.3,193.41 v2(24.3,192.99)
VOUT_INV: length 13.4
  L3 w0.508: v3(35.72,29.74) 35.72,30.23 35.47,30.48 33.18,30.48 32.42,31.24 32.42,37.21 31.91,37.72 v5(31.02,37.72)
  BOTTOM w0.305: v3(35.72,29.74) 36.23,29.24 U36.18
  vias: v4(30.51,39.12) v5(29.98,37.76)
VR_EN: length 9.4
  TOP w0.102: R80.1 21.23,188.72 22.2,188.72 v3(22.73,189.25)
  BOTTOM w0.102: v3(22.73,189.25) 22.73,189.35 v2(21.62,190.45) 21.62,192.35 20.61,193.37 PR186.2
VR_EN_C_1: length 4.6
  TOP w0.152: Q5.6 17.42,184.23 Q4.G 18.48,185.71 v4(18.83,186.06) 18.96,186.18 R85.2
VR_EN_C_2: length 5
  TOP w0.152: R95.2 13.05,182.37 13.11,182.37 v3(13.47,182.73) 13.6,182.85 14.49,182.85 15.02,183.39 Q5.2
  BOTTOM w0.152: v3(13.47,182.73) 14.03,183.29 v2(14.03,183.41)
VR_RDY: length 8.5
  TOP w0.102: v3(21.96,189.25) 22.42,189.7 22.92,189.7 23.27,189.35 23.27,188.92 R78.1
  BOTTOM w0.102: v3(21.96,189.25) 21.96,189.4 21.42,189.94 21.41,189.94 20.85,190.5 20.85,192.1 v2(20.81,192.14) 20.22,192.72 PR190.2 PR188.2
VREF: length 6.3
  TOP w0.102: C243.2 41.51,29.34 v3(41.98,29.34)
  BOTTOM w0.102: U36.2 39.17,26.92 39.92,27.66 v2(39.92,27.77) 41.49,29.34 v3(41.98,29.34)
VREF_1: length 2.9
  TOP w0.203: U11.41 163.19,81.04 v4(163.3,81.15)
  TOP w0.508: v4(163.3,81.15) 163.25,81.2 C119.1
VREG_PCIAUX_PCH: length 8.7
  BOTTOM w0.254: Q48.D Q49.C 149.23,209.17 149.18,209.12 147.81,209.12 v2(146.85,208.15) 146.4,207.71 R537.2 R538.1
VREG_PCIAUX_PCH_1: length 6.8
  BOTTOM w0.254: Q50.G 146.02,203.37 PC175.2 144.43,204.09 v2(144.18,204.34) 143.73,204.79 C292.1 143.73,206.38 R538.2
VRP: length 5.3
  TOP w0.203: 164.75,80.37 164.39,80.01 U11.38
  TOP w0.254: 164.75,80.37 164.8,80.42 167.1,80.42 v4(167.36,80.67) 168.09,81.41 C122.1
WAKE_N: length 428.7
  TOP w0.102: v3(108.62,118.75) 108.62,120.52 107.32,121.81 107.32,125.1 109.86,127.64 109.86,146.94 103.86,152.95 102.5,152.95 R135.2 101.7,152.15 R136.2 ; v3(33.46,14.91) 33.65,14.72 35.34,14.72 35.4,14.66 U23.21 ; v3(158.02,214) 155.99,214 155.1,214.88 154.4,214.88 146.92,222.36 144.58,222.36 143.54,223.39 130.21,223.39 129.09,222.28 124.71,222.28 R30.2 R34.1
  L3 w0.127: v3(42.71,131.95) 42.02,131.27 36.49,131.27 30.88,125.65 30.88,43.6 27.17,39.89 27.17,27.47 29.37,25.28 29.37,22.61 28.23,21.46 28.23,18.03 30.89,15.37 33,15.37 v3(33.46,14.91)
  L4 w0.127: v3(156.37,143.15) 156.54,142.99 156.54,131.99 155.61,131.06 155.61,126.49 154.72,125.6 148.37,125.6 146.74,123.98 136.85,123.98 136.07,123.19 133.29,123.19 129.57,119.48 v3(129.57,119) ; v3(108.62,118.75) 107.64,117.77 83.41,117.77 71.88,129.3 45.99,129.3 43.34,131.95 v3(42.71,131.95)
  BOTTOM w0.102: v3(156.37,143.15) 158.59,145.38 158.59,149.66 159.62,150.69 159.62,212.38 v2(158.89,213.11) 158.02,213.98 v3(158.02,214) ; v3(129.57,119) 115.73,119 115.02,118.29 113,118.29 112.73,118.56 112.73,119.1 112.27,119.56 109.43,119.56 v3(108.62,118.75)
WEBCAM_DET_N: length 177
  TOP w0.102: v3(164.34,200.25) 163.99,200.61 158.35,200.61 v3(158.15,200.41) 157.39,199.64 157.39,199.01 157,198.62 WEBCM1.7 ; v3(149.64,51.94) 149.61,51.92 146.22,51.92 145.4,51.1 KBC1.34
  BOTTOM w0.102: R541.2 v3(158.15,200.41) 157.64,199.9 157.64,198.37 158.15,197.87 PC183.2 ; v3(149.64,51.94) 149.64,52.45 148.95,53.14 148.95,63.19 148.72,63.42 148.72,75.88 149.52,76.68 149.52,87.71 149.46,87.78 149.46,92.05 149.56,92.16 149.56,101.04 148.75,101.85 148.75,112.83 149.16,113.24 149.16,115.02 152,117.86 v2(153.45,117.86) 154.97,117.86 162.35,125.23 162.35,148.85 165.69,152.2 165.69,195.15 164.34,196.5 v3(164.34,200.25)
XCLK_BIASREF: length 2.5
  TOP w0.203: v1(74.79,167.92) 74.79,167.99 CPU1.E42
  BOTTOM w0.203: R564.1 75.74,167.86 v2(75.58,168.02) 74.89,168.02 v1(74.79,167.92)
XDP_DBRESET#: length 173.4
  TOP w0.102: v3(33.43,225.43) 33.43,225.11 R10.1 ; CPU1.B5 72.34,146.22 72.63,145.93 72.63,145.68 72.45,145.5 72.05,145.5 70.54,143.99 70.54,142.4 70.23,142.09 70.23,142.09 R151.2 69.07,141.43 68.82,141.17 68.82,139.76 67.1,138.05 60.37,138.05 55.38,133.06 49.56,133.06 48.76,133.86 45.12,133.86 44.32,133.06 41.73,133.06 v3(41.69,133.1)
  L3 w0.127: v3(33.43,225.43) 32.96,224.96 28.44,224.96 28.19,225.21 25.85,225.21 25.38,224.74 17.53,224.74 12.09,219.31 12.09,201.88 12.9,201.07 12.9,188.7 11.37,187.17 11.37,153.89 15.65,149.61 15.65,145.99 23.05,138.6 33.75,138.6 37.19,135.15 39.63,135.15 v3(41.69,133.1)
  BOTTOM w0.102: v2(41.69,133.91) v3(41.69,133.1)
XDP_DBRESET_XDP#: length 6.1
  TOP w0.102: XDP1.48 31.33,222.08 31.2,222.21 31.2,223.48 C2.1 31.04,223.83 31.9,223.83 31.91,223.82 v4(31.94,223.82) 31.94,223.83 32.81,223.83 R9.2 R10.2
XDP_PRDY#: length 116.4
  TOP w0.089: 70.51,175 71.24,175.73 72.76,175.73 73.01,175.98 73.01,176.14 73.47,176.59 CPU1.D56
  TOP w0.102: TP15.1 20.83,212.78 XDP1.5 20.83,216.31 v3(20.23,216.92) ; v3(64.4,183.64) 64.4,183.62 63.15,182.37 63.15,178.69 62.57,178.1 62.57,173.45 63.37,172.64 65.22,172.64 65.93,173.35 67.35,173.35 68.45,174.45 69.96,174.45 70.51,175
  L3 w0.127: v3(20.23,216.92) 20.95,216.19 23.37,216.19 23.87,216.69 23.87,216.85 26.56,219.54 39.25,219.54 39.67,219.96 56.83,219.96 57.97,218.82 67,218.82 v3(67.66,218.16)
  BOTTOM w0.102: v3(64.4,183.64) 64.4,184.71 v2(64.42,184.73) 64.7,185.01 64.7,190.27 65.59,191.16 65.59,191.45 68.84,194.69 68.84,215.69 68.13,216.39 68.13,217.69 v3(67.66,218.16)
XDP_PREQ#: length 116.5
  TOP w0.102: R1.2 15.53,219.07 v3(16.67,217.93) 17.69,216.92 19.52,216.92 20.33,216.1 XDP1.3 ; v1(74.73,178.89) 74.26,178.89 74.08,179.07 CPU1.D61
  L3 w0.127: v3(72.17,216.28) 69.25,219.2 58.13,219.2 55.85,221.48 35.71,221.48 34.31,220.08 26.56,220.08 23.49,217.01 23.49,216.85 23.21,216.57 21.3,216.57 20.49,217.39 17.22,217.39 v3(16.67,217.93)
  BOTTOM w0.102: v3(72.17,216.28) 71.99,216.1 71.99,192.75 69.98,190.75 v2(69.98,185.19) 69.98,182.3 71.36,180.92 71.36,178.89 71.84,178.41 74.25,178.41 v1(74.73,178.89)
XDP_PRSENT_PIN60: length 9.3
  TOP w0.102: XDP1.60 34.86,220.92 36.06,222.12 39.1,222.12 v4(39.3,222.33) 40.01,223.04 40.01,223.69 R16.1 R17.2 R18.2
XDP_PRSNT_PIN1: length 4.7
  TOP w0.102: XDP1.1 19.83,212.78 v4(19.07,212.01) 18.71,211.66 R58.2
XDP_SMBCLK: length 25.6
  TOP w0.102: R32.1 51.89,221.51 v4(48.32,221.51) 47.21,220.4 40.36,220.4 35.44,215.48 35.44,213.38 34.86,212.8 33.64,212.8 32.85,213.58 32.85,213.74 32.83,213.76 XDP1.53
XDP_SMBDAT: length 26.1
  TOP w0.102: XDP1.51 32.33,213.42 33.44,212.31 35.06,212.31 35.92,213.18 35.92,215.28 40.56,219.91 49.89,219.91 50.33,220.34 v4(50.58,220.34) R35.1
XDP_SYS_PWROK: length 20.8
  TOP w0.102: XDP1.47 31.33,216.1 31.64,216.41 32.59,216.41 33.7,217.51 33.7,218.22 33.82,218.34 36.63,218.34 36.84,218.55 40.17,221.88 41.63,221.88 42.08,222.33 v4(43.86,222.33) 45.12,223.58 C3.1 R23.1 47.33,223.58 R27.2
XDP_TCK_JTAGX: length 75.2
  TOP w0.089: 68.77,177.39 68.93,177.55 70.47,177.55 70.87,177.95 CPU1.A59
  TOP w0.102: R21.2 R22.1 51.67,224.6 51.76,224.69 62.19,224.69 62.82,224.06 62.82,221.21 v3(63.15,220.88) ; v3(66.58,176.91) 67.04,177.37 67.84,177.37 R107.1 68.77,177.39
  BOTTOM w0.102: v3(63.15,220.88) 64.07,221.79 v2(64.42,221.79) 67.2,221.79 68,220.99 68,220.09 69.98,218.11 69.98,194.22 66.73,190.97 66.73,189.78 65.9,188.94 65.9,177.6 v3(66.58,176.91)
XDP_TCLK: length 94.2
  TOP w0.089: CPU1.B61 72.14,179.27 71.92,179.27 71.79,179.33 71.59,179.33 71.47,179.29 71.46,179.28 71.42,179.27 71.35,179.2 69.76,179.2 68.99,179.96 R99.1
  TOP w0.102: R99.1 68.42,180.28 68.23,180.47 66.79,180.47 v3(66.61,180.65) ; v3(62.14,223.77) 61.45,224.46 52.73,224.46 R26.1 51.85,223.71 R22.2 49.21,222.35 48.04,222.35 47.46,221.77 42.02,221.77 41.78,221.52 40.48,221.52 34.66,215.71 34.66,213.61 34.56,213.51 34.07,213.51 33.83,213.74 XDP1.57
  BOTTOM w0.102: v3(62.14,223.77) 63.15,222.76 67.51,222.76 69.98,220.28 69.98,219.79 70.82,218.95 70.82,193.88 67.57,190.62 67.57,186.28 v2(67.29,186) 67.29,184.73 67.83,184.2 67.83,181.28 67.2,180.65 v3(66.61,180.65)
XDP_TCLK1: length 25.1
  TOP w0.102: XDP1.55 33.33,213.78 33.84,213.28 34.66,213.28 34.96,213.58 34.96,215.68 40.57,221.3 41.88,221.3 42.12,221.54 47.56,221.54 48.14,222.12 49.81,222.12 v4(50.07,222.38) 50.33,222.63 R28.2
XDP_TDI: length 103.1
  TOP w0.089: 71.6,176.93 72.8,176.93 73.48,177.61 73.78,177.61 73.97,177.81 73.97,178.08 73.55,178.51 CPU1.D60
  TOP w0.102: v3(37.24,225.43) 37.5,225.17 37.5,223.98 37.76,223.71 R14.2 36.93,222.63 33.88,222.63 33.33,222.08 XDP1.56 ; 71.6,176.93 71.01,176.93 70.33,176.25 68.82,176.25 68.66,176.09 67.47,176.09 67.22,175.84 67.22,174.94 R111.1 66.26,175.01 65.57,175.01 v3(64.55,176.02)
  L4 w0.127: v3(37.24,225.43) 38.48,226.66 50.7,226.66 51.68,225.68 63.01,225.68 67.47,221.22 v3(67.47,220.88)
  BOTTOM w0.102: v3(64.55,176.02) 65.54,177.01 v2(65.57,177.01) 65.57,177.04 65.67,177.14 65.67,189.04 66.5,189.88 66.5,191.07 66.77,191.33 69.76,194.32 69.76,218.01 67.47,220.3 v3(67.47,220.88)
XDP_TDO: length 27.9
  TOP w0.102: R21.1 49.11,224.17 49.11,225.09 v3(49.44,225.43) ; R13.1 R12.1 R11.2 34.51,223.27 32.8,223.27 v3(32.42,222.88) 32.33,222.8 XDP1.52
  L3 w0.127: v3(49.44,225.43) 47.91,223.9 33.89,223.9 33.54,223.56 33.09,223.56 v3(32.42,222.88)
  BOTTOM w0.102: v3(49.44,225.43) 49.11,225.09 v2(49.11,224.66)
XDP_TDO_CPU: length 89.3
  TOP w0.089: 69.65,179.02 71.46,179.02 71.51,179.07 CPU1.A61
  TOP w0.102: R100.1 66.44,179.26 66.57,179.13 v3(66.58,179.13) 66.59,179.13 66.66,179.2 69.47,179.2 69.65,179.02 ; v3(35.72,225.43) 35.72,224.85 R12.2
  L4 w0.127: v3(35.72,225.43) 37.71,227.42 63.32,227.42 v3(66.96,223.77)
  BOTTOM w0.102: v3(66.58,179.13) 66.77,179.13 68.05,180.42 68.05,185.83 67.8,186.09 67.8,190.53 71.05,193.78 71.05,219.05 70.31,219.79 70.31,220.7 v2(68.28,222.73) 67.24,223.77 v3(66.96,223.77)
XDP_TMS: length 92.3
  TOP w0.089: CPU1.C60 72.61,178.56 70.57,178.56 70.37,178.36
  TOP w0.102: v3(39.53,225.43) 39.53,224.03 39.21,223.71 R15.2 39.02,223.27 38.13,222.38 34.13,222.38 33.83,222.08 XDP1.58 ; 70.37,178.36 70.16,178.16 69.53,178.16 v1(69.12,178.56) R103.1
  L4 w0.127: v3(39.53,225.43) 40,225.89 50.36,225.89 51.34,224.92 62.39,224.92 v3(63.53,223.77)
  BOTTOM w0.102: v3(63.53,223.77) 63.99,224.23 67.5,224.23 70.65,221.09 70.65,219.92 71.28,219.28 71.28,193.69 68.03,190.44 68.03,186.18 68.34,185.87 v2(68.34,179.34) v1(69.12,178.56)
XDP_TRST#: length 100.2
  TOP w0.089: v1(69.76,178.56) 70.01,178.81 72.73,178.81 CPU1.C61 ; CPU1.B59 72.3,177.95 72.04,178.21 70.75,178.21 70.31,177.77 68.84,177.77
  TOP w0.102: XDP1.54 32.83,222.46 v3(33.18,222.8) ; v3(66.58,177.67) 66.68,177.77 68.84,177.77
  L4 w0.127: v3(62.26,220.88) 60.38,222.76 49.08,222.76 48.82,223.01 48.8,223.01 48.48,223.33 33.71,223.33 v3(33.18,222.8)
  BOTTOM w0.102: v1(69.76,178.56) 70.33,177.99 R554.1 70.07,177.55 v2(67.67,177.55) 66.71,177.55 v3(66.58,177.67) 66.12,178.13 66.12,180.15 66.13,180.15 66.13,180.53 66.12,180.53 66.12,188.85 66.96,189.69 66.96,190.88 70.21,194.13 70.21,218.2 68.23,220.18 68.23,221.09 67.02,222.3 63.69,222.3 v3(62.26,220.88)
XRF_TDC2: length 13.6
  TOP w0.508: C256.1 v3(49.82,16.48) ; 51.6,10.03 v3(50.3,10.03) ; XF1.9 v3(50.3,13.84)
  L3 w0.508: v3(49.82,16.48) 49.82,14.33 v3(50.3,13.84)
  BOTTOM w0.508: v3(50.3,13.84) XF1.9 51.6,10.03 v3(50.3,10.03) ; v2(49.03,16.79) 49.51,16.79 v3(49.82,16.48)
XTAL_OUTBUFF: length 10.8
  TOP w0.102: GPU1.C10 86.72,90.5 86.72,89.22 89.32,86.61 v3(89.57,86.61) 89.8,86.61 90.58,85.83 R284.1 R285.2
  BOTTOM w0.102: v2(90.46,86.61) v3(89.57,86.61)
XTAL_SSFOUT: length 7.6
  TOP w0.102: R283.1 89.57,85.7 v3(88.25,87.02) 86.39,88.88 86.39,89.04 86.32,89.1 GPU1.A10
  BOTTOM w0.102: v2(87.56,86.44) 87.66,86.44 v3(88.25,87.02)
XTALIN: length 9.4
  TOP w0.102: GPU1.C11 85.48,90.66 85.82,90.32 85.82,89.91 85.77,89.86 85.77,88.95 85.98,88.74 85.98,87.88 86.33,87.53 C107.1 86.39,85.41 86.39,83.19 85.64,82.43 X3.1
XTALOUT: length 7.1
  TOP w0.102: GPU1.B10 85.98,89.76 85.98,89.16 86.18,88.95 86.18,87.97 87.24,86.91 87.24,86.6 v4(87.35,86.5) C108.1 87.35,84.41 X3.3
XTL_24M_X1_CPU: length 18.9
  TOP w0.089: CPU1.E37 74.09,165.95 73.55,165.95 73.43,165.83 73.19,165.83 72.95,166.08 72.95,166.24 72.78,166.4 70.26,166.4
  TOP w0.102: 70.26,166.4 70.17,166.4 69.07,165.3 69.07,163.54 68.71,163.18 68.71,161.59 67.57,160.45 65.98,160.45 R128.1 64.43,159.84 C27.1 64.08,160.17 62.16,160.17 61.38,159.39 X1.1
XTL_24M_X2_CPU: length 18.6
  TOP w0.102: CPU1.E35 73.87,165.26 72.87,165.26 72.69,165.43 72.69,165.67 72.5,165.86 70.52,165.86 69.63,164.97 69.63,163.23 69.23,162.83 69.23,161.24 67.83,159.84 R128.2 66.26,159.77 64.68,158.18 64.68,156.96 C30.1 62.94,156.77 X1.3
XTL_32K_X1_CPU: length 30.4
  TOP w0.102: CPU1.AM18 87.95,154.48 v1(87.68,154.21) ; X2.1 90.6,131.53 C71.1 R198.1 89.57,131.54 88.96,132.14 88.96,132.97 89.45,133.46 89.45,134.09 90.48,135.13 v3(90.58,135.13)
  L3 w0.127: v3(90.58,135.13) 90.58,143 88.55,145.03 88.55,146.06 86.77,147.84 86.77,149.51 86.12,150.17 86.12,152.43 87.68,153.99 v1(87.68,154.21)
  BOTTOM w0.102: v3(90.58,135.13) 90.13,135.59 v2(90.13,135.97)
XTL_32K_X2_CPU: length 29.9
  TOP w0.102: v3(90.58,134.37) 90.06,133.84 90.06,133.21 89.57,132.72 R198.2 90.46,132.4 C70.1 90.73,132.38 X2.4 ; v1(87.59,155.09) 87.95,155.45 CPU1.AM20
  L3 w0.127: v3(90.58,134.37) 89.82,135.13 89.82,142.1 88.04,143.88 88.04,146.18 86.52,147.7 86.52,149.43 85.9,150.04 85.9,152.53 87.07,153.69 87.07,154.57 v1(87.59,155.09)
  BOTTOM w0.102: v3(90.58,134.37) v2(90.58,133.53)
N37189306: length 6.8
  BOTTOM w0.152: Q55.G 40.38,100.9 Q56.D 38.01,101.09 v2(39.53,102.62) R675.2

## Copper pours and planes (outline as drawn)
1V_EDRAM on BOTTOM: 79.15,178.44 78.9,178.69 78.9,178.94 79.15,179.2 79.54,179.2 79.66,179.32 79.66,179.96 79.79,180.09 80.17,180.09 80.3,179.96 80.3,179.32 80.42,179.2 82.08,179.2 82.46,179.58 82.46,179.96 82.58,180.09 83.09,180.09 83.22,179.96 83.22,179.45 82.71,178.94 82.71,178.69 82.46,178.44
1V_S3 on TOP: 48.67,137.92 48.42,138.18 48.42,138.81 49.06,139.45 49.06,140.21 49.18,140.34 50.96,140.34 51.34,139.95 51.34,138.94 51.6,138.68 52.1,138.68 52.23,138.56 52.23,138.18 52.1,138.05 51.54,138.05 51.42,137.92 ; 1 cut-out
1V_VCCGT on TOP: 76.11,169.54 75.98,169.67 75.98,174.37 76.23,174.62 76.23,175.01 75.98,175.26 75.98,178.94 76.11,179.07 76.36,179.07 76.61,178.82 77,178.82 77.12,178.94 77.12,182.75 77.63,183.26 77.63,185.42 78.77,186.56 78.77,190.12 78.27,190.63 73.82,190.63 71.66,192.79 69.88,192.79 69.38,193.29 64.3,193.29 62.77,191.77 62.77,185.17 62.52,184.91 57.06,184.91 56.93,185.04 56.93,187.58 57.31,187.96 59.34,187.96 59.79,188.4 59.79,192.28 58.83,193.23 58.83,212.98 58.58,213.23 58.58,214 58.96,214.38 63.03,214.38 63.41,214 63.41,211.07 63.79,210.69 71.41,210.69 77.25,204.85 77.25,199.52 77.88,198.88 77.88,195.96 78.67,195.17 82.1,195.17 82.33,194.94 82.33,188.21 83.09,187.45 83.09,185.93 83.47,185.55 83.47,180.59 83.35,180.47 83.22,180.47 81.95,179.2 81.95,178.94 81.69,178.69 77.88,178.69 77.63,178.44 77.63,170.31 76.87,169.54 ; 14 cut-outs
1V_VCCGT on BOTTOM: 57.06,184.91 56.93,185.04 56.93,187.58 57.31,187.96 59.34,187.96 59.72,188.34 59.72,192.41 57.95,194.18 57.95,215.52 58.07,215.65 65.06,215.65 65.57,215.14 65.57,197.1 66.2,196.47 68.23,196.47 68.23,195.07 66.07,192.91 63.91,192.91 62.77,191.77 62.77,185.17 62.52,184.91
1V_VCCGT on BOTTOM: 78.65,191.64 77.88,192.41 77.88,195.45 78.01,195.58 78.27,195.58 78.39,195.45 78.39,195.07 79.41,194.06 80.81,194.06 80.93,193.93 80.93,192.79 79.79,191.64
1V_VCCGT on BOTTOM: outline of 85 points within 73.19,170.69 85.89,187.45 ; 4 cut-outs
1V_VCCGT on L3: 77.38,187.45 82.33,187.45 82.58,187.2 82.58,186.31 83.35,185.55 83.35,174.24 82.96,173.86 76.61,173.86 76.36,174.12 76.36,186.44
1V_VCCGT on L3: 59.72,215.65 65.06,215.65 65.57,215.14 65.57,197.61 66.07,197.1 67.85,197.1 68.11,196.85 68.11,195.45 67.6,194.94 64.93,194.94 63.41,193.42 63.41,186.94 62.9,186.44 59.98,186.44 59.72,186.69 59.72,192.33 58.77,193.28 58.77,214.69
1V_VCCGT on L4: 77.38,187.45 76.36,186.44 76.36,174.12 76.61,173.86 82.96,173.86 83.35,174.24 83.35,185.55 82.58,186.31 82.58,187.2 82.33,187.45
1V_VCCGT on L4: 59.85,215.65 64.17,215.65 64.42,215.39 64.42,200.41 64.17,200.15 59.72,200.15 59.09,200.79 59.09,214.88
1V_VCCGT on L5GND: 78.85,171.49 76.41,173.93 75.42,173.93 68.04,181.31 68.04,187.78 67.17,188.66 64.98,188.66 62.82,186.5 57.39,186.5 57.12,186.77 57.12,187.88 57.52,188.28 59.29,188.28 59.79,188.77 59.79,197.44 58.9,198.33 58.9,214.17 59.17,214.44 64.98,214.44 65.37,214.04 65.37,211.25 65.74,210.88 67.52,210.88 82.14,196.26 82.14,185.21 83.28,184.07 83.28,172.29 82.48,171.49
1V_VCCGTUS on TOP: 86.77,168.15 86.65,168.28 85.89,168.28 85.5,168.66 85.5,177.16 85.89,177.55 86.39,177.55 86.65,177.8 86.65,178.31 86.9,178.56 87.28,178.56 88.17,177.67 88.17,177.42 88.04,177.29 87.28,177.29 87.16,177.16 87.16,176.91 87.28,176.78 88.04,176.78 88.17,176.66 88.17,176.53 87.16,175.51 86.9,175.51 86.77,175.64 86.39,175.64 86.27,175.51 86.27,175.01 86.39,174.88 86.9,174.88 87.03,175.01 88.04,175.01 88.17,174.88 88.17,174.75 87.92,174.5 87.92,174.12 88.04,173.99 88.04,173.74 87.79,173.48 87.79,173.35 88.04,173.1 88.04,172.85 87.92,172.72 87.92,172.21 88.04,172.09 88.04,171.83 87.92,171.7 87.66,171.7 87.54,171.83 86.9,171.83 86.77,171.96 86.39,171.96 86.27,171.83 86.27,171.32 86.39,171.2 86.77,171.2 86.9,171.32 87.28,171.32 87.66,170.94 87.66,170.31 87.28,169.93 87.28,169.42 87.66,169.04 87.66,168.53 87.28,168.15
1V_VCCGTUS on BOTTOM: 86.01,169.93 85.63,170.31 85.63,170.81 85.76,170.94 85.89,170.94 86.01,171.07 86.01,177.29 86.27,177.55 89.7,177.55 89.95,177.8 89.95,178.18 90.08,178.31 90.33,178.31 90.58,178.56 90.58,179.96 90.71,180.09 97.19,180.09 98.08,179.2 98.08,178.82 96.74,177.48 94.71,177.48 93.76,176.53 88.04,176.53 87.79,176.28 87.79,170.05 87.66,169.93 ; 1 cut-out
1V_VCCIO on TOP: 38.77,135.64 38.39,136.02 38.39,137.03 38.51,137.16 38.51,138.43 40.93,138.43 41.05,138.3 41.05,136.14 40.55,135.64 ; 3 cut-outs
1V_VCCIO on TOP: 86.27,160.78 86.14,160.91 86.14,161.93 86.39,162.18 88.04,162.18 88.17,162.05 88.17,161.04 88.04,160.91 86.77,160.91 86.65,160.78
1V_VCCIO on BOTTOM: 87.16,160.27 86.77,160.66 86.27,160.66 86.14,160.78 86.14,162.56 87.16,163.58 87.54,163.58 87.66,163.45 87.66,163.07 87.54,162.94 87.41,162.94 87.16,162.69 87.16,161.93 87.28,161.8 87.54,161.8 87.66,161.67 87.66,160.4 87.54,160.27 ; 1 cut-out
1V_VCCIO on L3: 86.77,160.02 86.01,159.26 82.46,159.26 82.08,158.88 82.08,157.1 81.82,156.84 80.68,156.84 80.55,156.72 80.55,155.07 80.42,154.94 80.42,153.8 79.92,153.29 79.92,142.75 78.27,141.1 70.14,141.1 69.63,141.6 69.63,144.78 70.77,145.92 75.73,145.92 77,147.19 77,149.86 76.36,150.5 76.36,154.31 76.87,154.81 76.87,159.38 77.76,160.27 77.76,162.05 78.27,162.56 86.52,162.56 86.77,162.31
1V_VCCIO on L4: 70.52,141.73 70.01,141.22 68.36,141.22 62.26,135.13 56.29,135.13 55.02,133.86 48.29,133.86 45.88,136.27 38.9,136.27 38.39,136.78 38.39,139.7 38.9,140.21 46.26,140.21 49.82,136.65 50.58,136.65 51.98,138.05 60.1,138.05 66.2,144.15 68.99,144.15 69.63,144.78 70.14,144.78 70.52,144.4
1V_VCCMPHYGTAON on TOP: 79.03,152.15 78.9,152.27 78.9,152.53 78.65,152.78 78.65,153.29 78.52,153.42 78.52,154.18 78.65,154.31 78.9,154.31 79.41,153.8 79.66,153.8 79.92,153.54 79.92,152.78 79.28,152.15
1V_VCCMPHYGTAON on TOP: 53.88,137.79 53.63,138.05 53.63,140.59 53.75,140.72 56.04,140.72 56.17,140.59 56.17,139.06 56.04,138.94 55.66,138.94 55.53,138.81 55.53,137.92 55.41,137.79 ; 2 cut-outs
1V_VCCMPHYGTAON on BOTTOM: 78.9,152.15 78.39,152.65 78.39,153.67 78.52,153.8 80.17,153.8 80.55,153.42 81.57,153.42 81.57,152.65 80.42,152.65 80.3,152.78 79.79,152.78 79.66,152.65 79.66,152.27 79.54,152.15
1V_VCCSA on TOP: 43.47,162.05 43.21,162.31 43.21,168.02 41.94,169.29 41.94,171.07 47.28,171.07 49.31,169.04 58.2,169.04 58.33,168.91 58.33,168.4 57.18,167.26 57.18,163.19 57.06,163.07 47.66,163.07 47.15,162.56 46.01,162.56 45.5,162.05 ; 13 cut-outs
1V_VCCSA on TOP: 75.98,157.73 75.47,158.24 75.47,159.26 75.6,159.38 76.36,159.38 76.49,159.51 76.49,159.89 76.36,160.02 75.98,160.02 75.9,159.94 75.62,159.94 75.47,160.1 75.47,161.11 75.6,161.24 76.31,161.24 76.49,161.42 76.49,162.05 76.61,162.18 77.38,162.18 77.5,162.05 77.5,159.38 76.87,158.75 76.87,158.24 76.36,157.73
1V_VCCSA on TOP: 86.9,158.12 86.27,158.75 86.27,159.77 86.39,159.89 86.65,159.89 87.28,159.26 87.28,159.13 87.16,159 87.16,158.5 87.28,158.37 87.28,158.24 87.16,158.12
1V_VCCSA on BOTTOM: 67.72,158.37 67.09,159 66.33,159 65.06,160.27 59.85,160.27 57.06,163.07 47.66,163.07 46.64,162.05 43.47,162.05 43.21,162.31 43.21,168.02 41.94,169.29 41.94,171.07 47.28,171.07 49.31,169.04 50.71,169.04 51.47,168.28 55.15,168.28 55.53,168.66 55.53,168.91 55.66,169.04 58.2,169.04 58.33,168.91 58.33,168.4 57.69,167.77 57.69,165.61 60.61,162.69 64.68,162.69 65.44,163.45 68.13,163.45 68.44,163.14 68.44,162.99 70.01,161.42 74.71,161.42 75.09,161.04 76.61,161.04 76.74,161.16 76.74,161.67 76.87,161.8 77.25,161.8 77.38,161.67 77.38,161.04 77.5,160.91 85.25,160.91 86.27,159.89 86.65,159.89 87.16,159.38 87.16,158.75 87.03,158.62 86.39,158.62 86.27,158.75 86.27,159.13 85.63,159.77 81.74,159.77 81.11,159.13 78.14,159.13 77.12,160.15 74.33,160.15 74.07,159.89 72.3,159.89 71.79,159.38 70.77,159.38 69.76,158.37 ; 11 cut-outs
1V_VCCSA on L4: 74.2,161.16 74.2,160.53 74.46,160.27 79.92,160.27 80.55,159.64 82.46,159.64 82.58,159.77 85.63,159.77 86.27,159.13 86.27,158.75 86.39,158.62 86.77,158.62 86.9,158.75 86.9,159.64 86.65,159.89 86.27,159.89 85.63,160.53 85.63,161.67 85.25,162.05 75.09,162.05
1V_VCCSA on L5GND: 68.57,157.16 65.52,160.21 60.18,160.21 59.04,161.35 52.69,161.35 50.91,163.13 48.5,163.13 48.23,163.4 48.23,170.1 50.91,172.78 58.25,172.78 69.55,161.48 75.93,161.48 76.57,162.12 87.6,162.12 87.6,158.07 86.7,157.16 76.38,157.16 76.25,157.29 76.07,157.33 76.07,157.33 75.37,157.31 75.37,157.31 75.22,157.27 75.1,157.16 ; 1 cut-out
1V_VCCST on TOP: 51.72,136.27 51.6,136.4 51.6,137.67 51.72,137.79 53.12,137.79 53.25,137.67 53.25,136.4 53.12,136.27 ; 1 cut-out
3V3_VDD33 on TOP: 84.49,93.85 84.36,93.98 84.36,94.61 84.62,94.87 88.04,94.87 88.17,94.74 88.17,94.11 88.04,93.98 87.92,93.98 87.66,94.23 87.41,94.23 87.16,93.98 86.27,93.98 86.01,94.23 85.12,94.23 84.74,93.85
3V3_VDD33 on BOTTOM: 91.98,90.3 91.85,90.42 91.85,93.47 91.35,93.98 89.95,93.98 89.7,94.23 84.49,94.23 84.36,94.36 84.36,94.74 84.74,95.12 90.58,95.12 90.71,95 93,95 93.25,94.74 93.25,92.08 93.38,91.95 96.05,91.95 96.17,91.82 96.17,91.44 96.05,91.31 95.28,91.31 95.16,91.19 95.16,90.68 94.9,90.42 93.25,90.42 93.12,90.3 ; 3 cut-outs
3V3AUX_CR on BOTTOM: 173.39,148.72 173.13,148.97 173.13,152.53 173.01,152.65 171.91,152.65 171.79,152.78 171.79,153.47 171.99,153.67 174.02,153.67 174.15,153.54 174.15,148.97 173.9,148.72 ; 4 cut-outs
3V_VA on TOP: 165.54,68.55 165.01,69.09 165.01,69.6 164.63,69.98 164.63,71.75 164.45,71.93 164.45,72.31 164.29,72.47 164.29,73.91 164.5,73.91 164.5,72.87 165.06,72.31 165.26,72.31 165.46,72.52 165.46,72.75 165.13,73.08 165.13,74.35 166.1,74.35 166.15,74.3 166.15,73.41 166.66,72.9 166.66,72.26 167.17,71.75 167.17,68.71 167.01,68.55 ; 7 cut-outs
+19V_AMP_PVCC on TOP: 163.99,46.61 163.86,46.74 163.86,47.75 163.61,48.01 161.83,48.01 161.83,48.77 164.12,48.77 164.5,49.15 165.51,49.15 166.53,48.13 166.53,46.86 166.28,46.61 ; 2 cut-outs
+19V_AMP_PVCC on TOP: 150.15,47.75 149.89,48.01 149.89,49.53 151.04,50.67 151.93,50.67 152.05,50.55 152.05,49.53 152.43,49.15 154.72,49.15 155.1,48.77 157.77,48.77 157.77,48.01 156.24,48.01 155.99,47.75 ; 4 cut-outs
AGND on L2GND: outline of 120 points within 72.58,1.68 184.24,87.86
GND on TOP: 83.35,95.25 83.22,95.38 83.22,95.63 86.77,99.19 87.16,99.19 87.28,99.06 87.28,98.81 83.73,95.25
GND on TOP: 17.31,193.42 17.31,194.82 16.67,195.45 16.67,197.61 18.45,197.61 18.7,197.36 18.7,193.68 18.45,193.42 ; 3 cut-outs
GND on TOP: 29.75,161.16 29.62,161.29 29.62,164.97 29.75,165.1 31.15,165.1 31.4,164.85 31.4,164.08 31.53,163.96 32.93,163.96 33.05,163.83 33.05,161.16
GND on TOP: 141.64,194.82 140.62,195.83 140.62,197.61 140.75,197.74 146.72,197.74 146.85,197.61 146.85,194.94 146.72,194.82
GND on TOP: 87.66,211.96 87.54,212.09 87.54,213.74 87.28,214 86.65,214 86.39,214.25 86.39,216.41 86.65,216.66 87.41,216.66 87.54,216.53 88.93,216.53 89.06,216.41 89.06,212.09 88.93,211.96
GND on TOP: 51.09,187.2 50.45,187.83 47.15,187.83 46.9,188.09 46.9,191.01 47.28,191.39 55.28,191.39 55.91,192.02 59.09,192.02 59.34,191.77 59.34,188.72 59.09,188.47 56.68,188.47 55.41,187.2
GND on TOP: 84.11,204.47 83.85,204.72 83.85,207.01 84.23,207.39 90.58,207.39 90.71,207.26 90.71,204.98 90.2,204.47 ; 1 cut-out
GND on TOP: 98.46,223.65 97.44,224.66 96.43,224.66 96.3,224.79 96.3,226.82 96.43,226.95 102.9,226.95 103.03,226.82 103.03,226.31 102.78,226.06 102.78,224.41 102.01,223.65
GND on TOP: 121.06,190.88 120.94,191.01 120.94,194.82 121.19,195.07 128.68,195.07 129.32,194.44 129.32,194.06 126.14,190.88
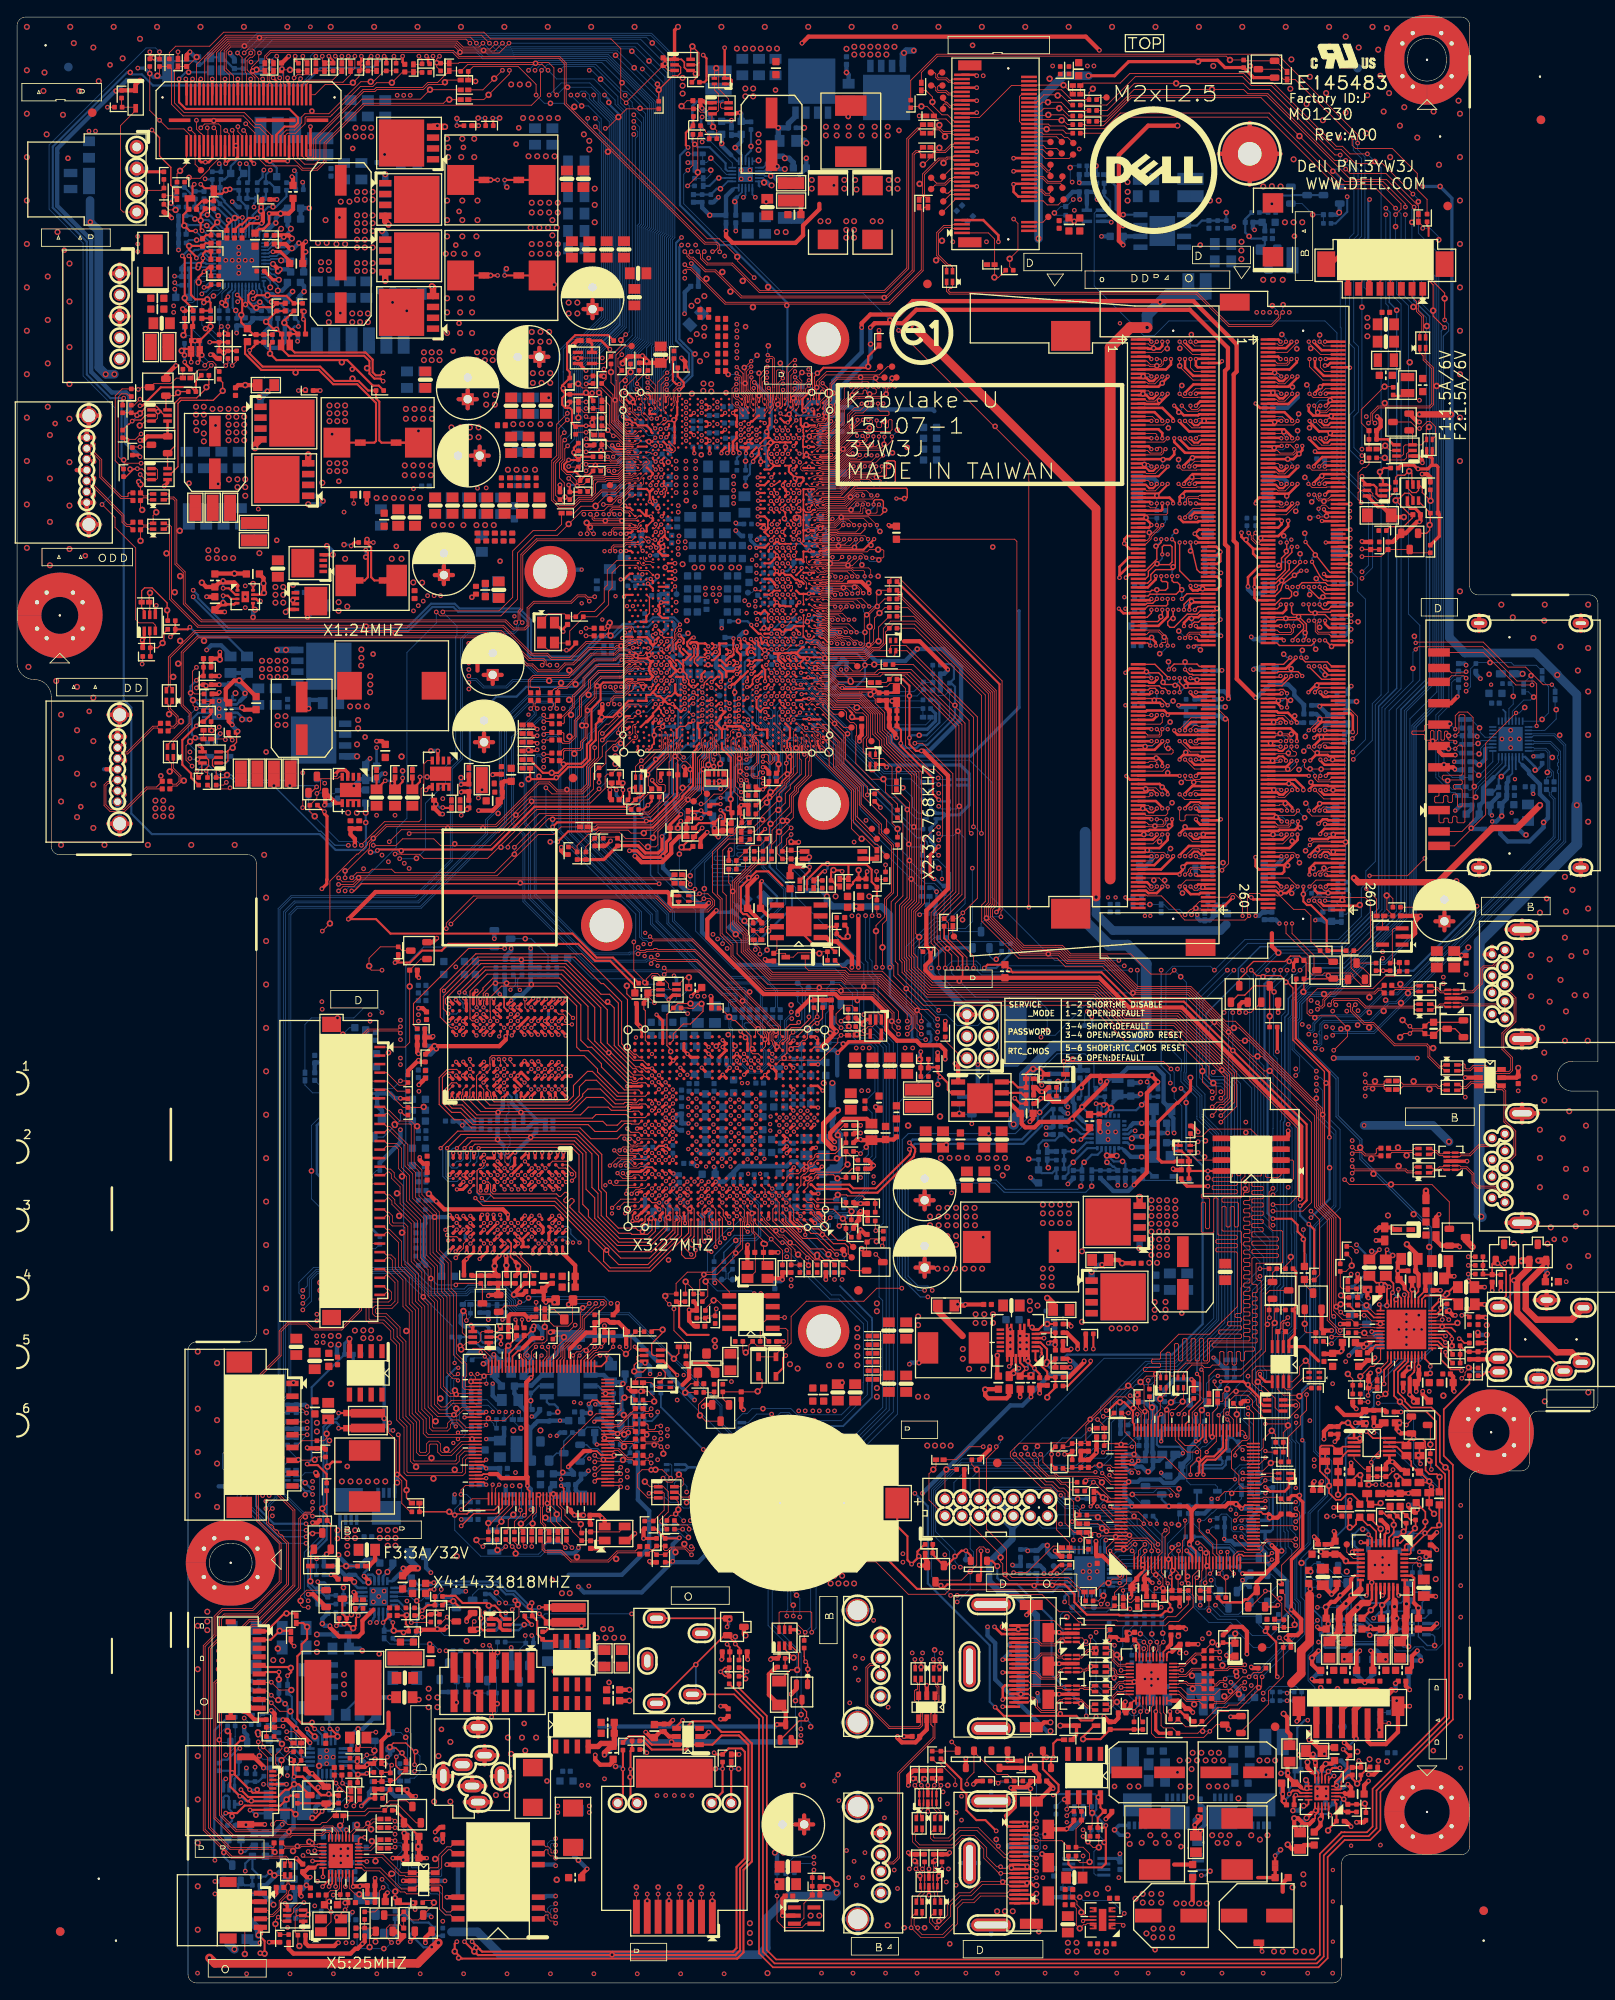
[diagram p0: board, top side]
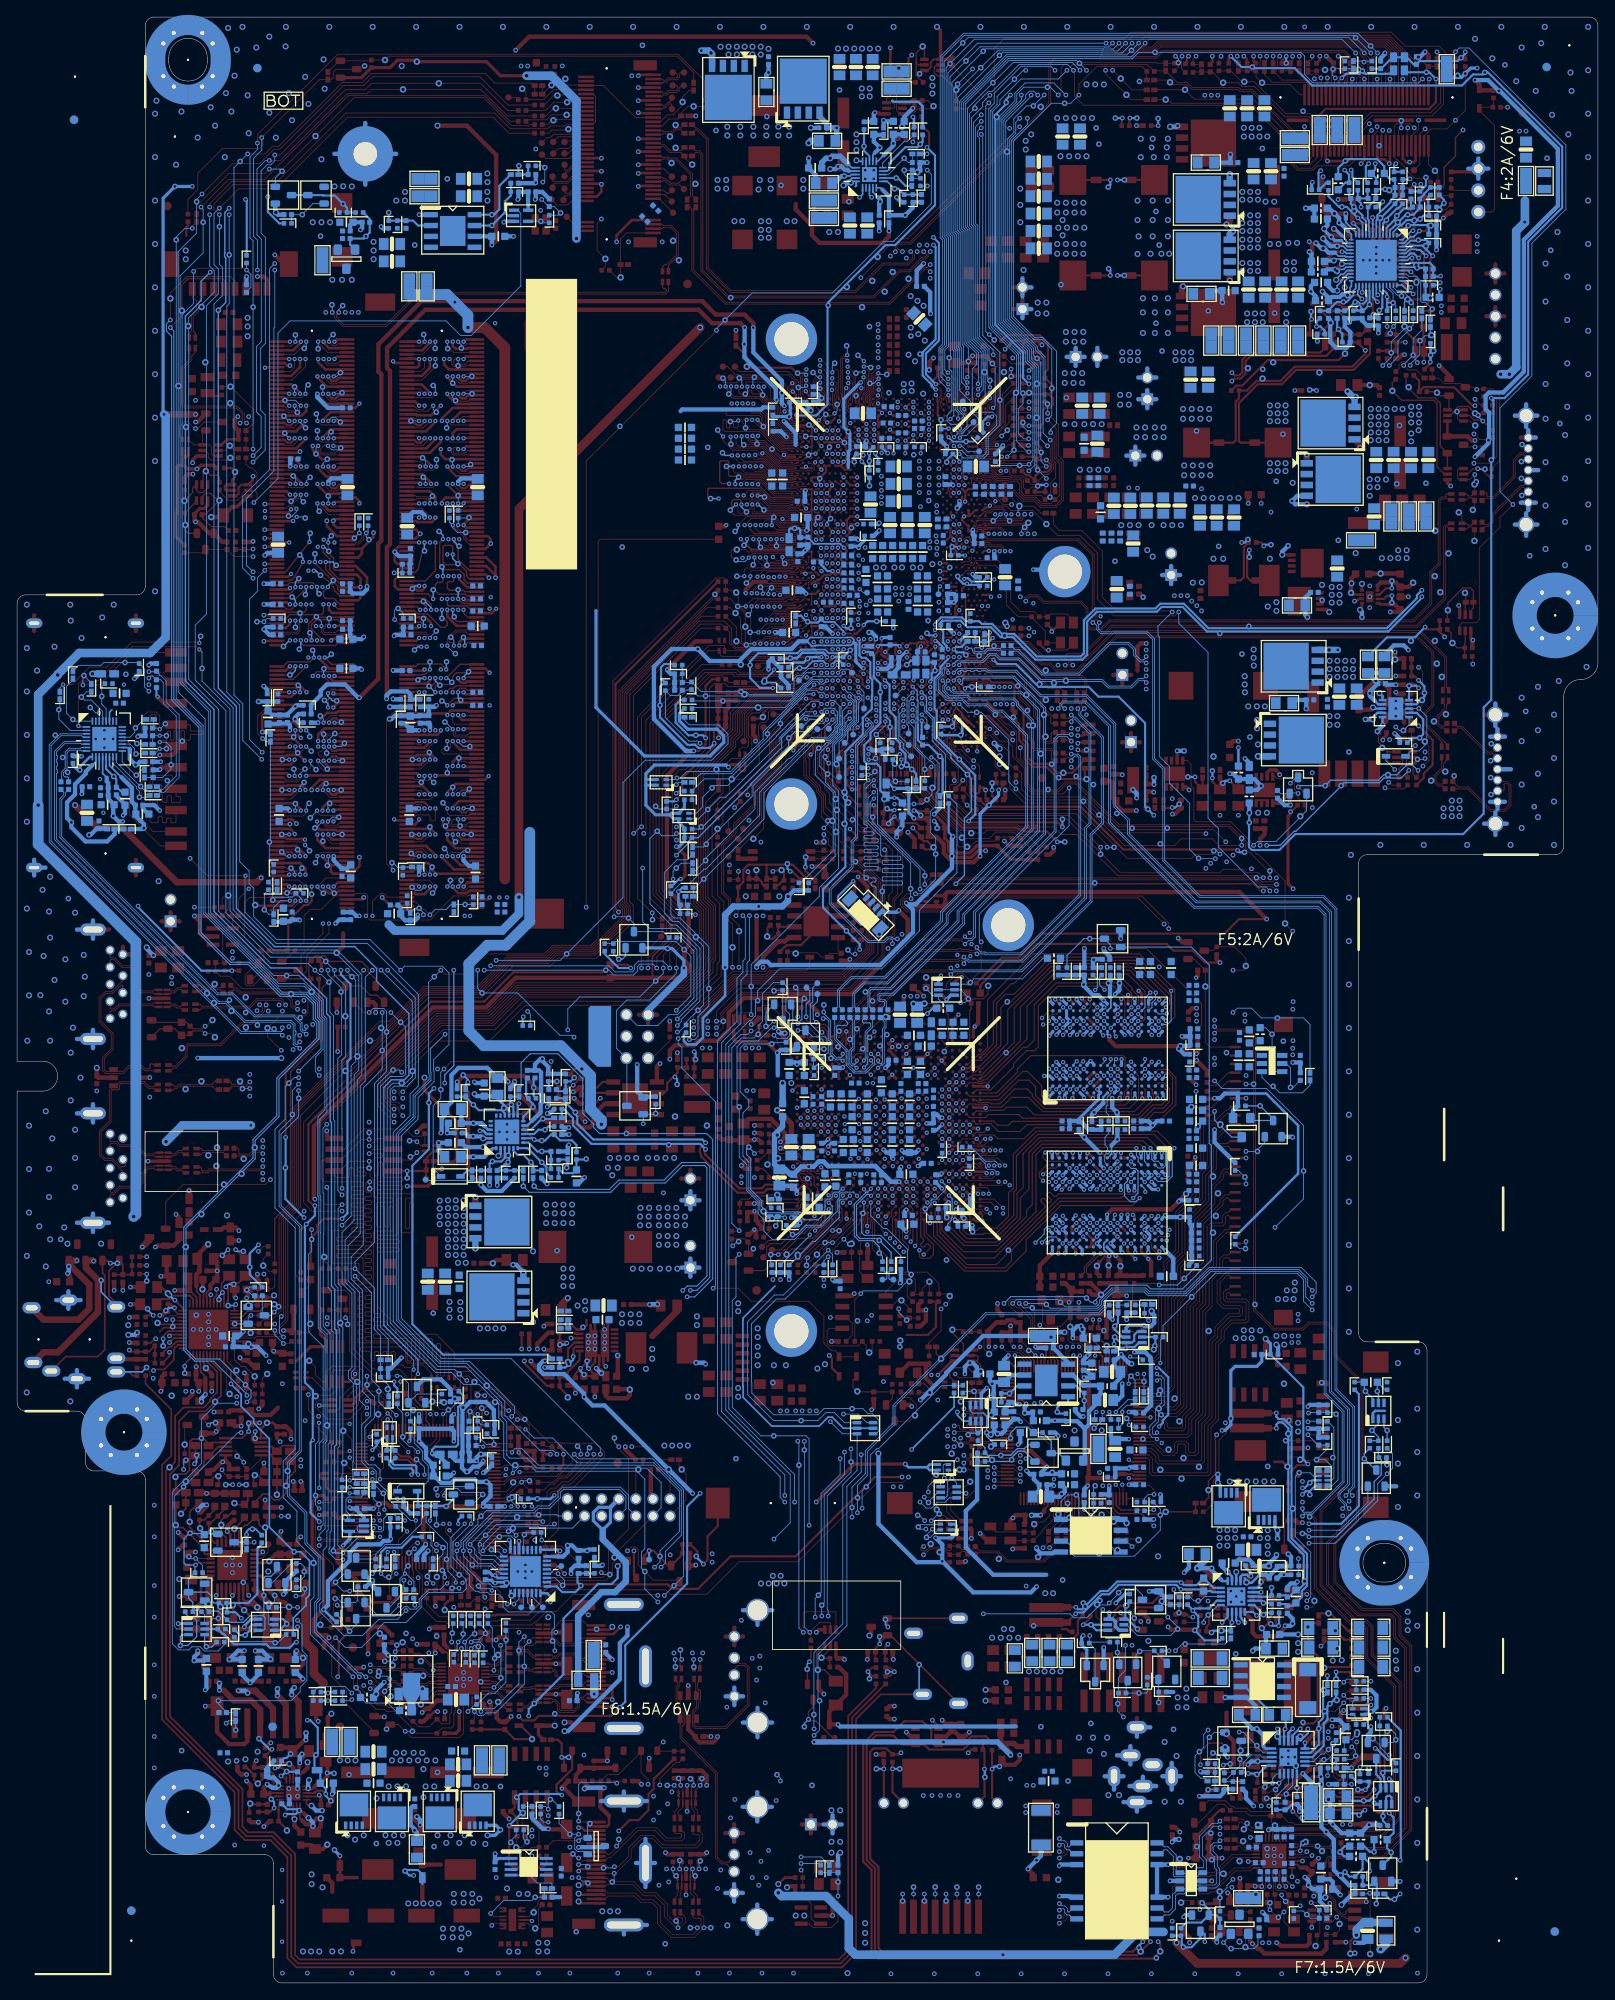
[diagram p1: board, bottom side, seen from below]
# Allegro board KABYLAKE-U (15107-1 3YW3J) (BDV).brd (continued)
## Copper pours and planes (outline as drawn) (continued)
GND on TOP: 84.49,224.28 84.23,224.54 84.23,225.81 83.85,226.19 83.85,226.69 83.98,226.82 89.31,226.82 89.82,226.31 89.82,224.54 89.57,224.28 ; 2 cut-outs
GND on TOP: 117.51,4.06 117.25,4.32 117.25,7.49 118.65,8.89 118.65,11.56 118.91,11.81 119.54,11.81 119.79,12.06 119.79,12.57 119.92,12.7 119.92,15.11 120.05,15.24 121.32,15.24 121.45,15.11 121.45,13.21 121.57,13.08 123.22,13.08 123.35,12.95 123.35,11.68 122.97,11.3 122.97,8.64 123.22,8.38 123.6,8.38 123.6,7.24 121.7,7.24 120.3,5.84 120.3,4.32 120.05,4.06 ; 4 cut-outs
GND on TOP: 26.45,160.66 26.32,160.78 26.32,163.58 26.45,163.7 26.83,163.7 26.96,163.58 26.96,160.78 26.83,160.66
GND on TOP: 23.53,36.96 23.27,37.21 23.27,38.99 24.29,40.01 24.29,42.42 24.42,42.55 25.69,42.55 25.81,42.42 25.81,38.48 24.29,36.96
GND on TOP: 48.93,19.18 48.29,19.81 48.29,30.73 47.15,31.88 46.01,31.88 45.75,32.13 45.75,36.32 46.01,36.58 47.53,36.58 47.91,36.96 47.91,37.97 48.04,38.1 50.07,38.1 51.09,39.12 54.39,39.12 54.64,38.86 54.64,30.99 55.15,30.48 55.15,28.96 54.77,28.57 53.75,28.57 53.12,27.94 53.12,25.65 54.14,24.64 57.82,24.64 59.98,22.48 61.25,22.48 61.63,22.1 61.63,19.68 61.5,19.56 58.33,19.56 57.95,19.18 ; 1 cut-out
GND on TOP: 88.68,10.79 88.3,11.18 88.3,20.57 88.55,20.83 90.58,20.83 90.71,20.7 90.71,17.27 90.08,16.64 90.08,11.05 89.82,10.79
GND on TOP: 114.59,74.8 114.21,75.18 114.21,76.58 113.95,76.83 111.79,76.83 111.67,76.96 111.67,78.23 112.05,78.61 113.57,78.61 113.7,78.74 113.7,79.88 113.95,80.14 115.86,80.14 115.98,80.01 115.98,78.61 115.48,78.11 115.48,74.8 ; 2 cut-outs
GND on TOP: 122.59,24.13 122.46,24.26 122.46,27.56 122.59,27.69 126.91,27.69 127.03,27.56 127.03,24.38 126.78,24.13
GND on TOP: 35.72,111.25 35.47,111.51 35.47,114.94 35.59,115.06 37.63,115.06 38.01,114.68 38.01,111.38 37.88,111.25
GND on TOP: 93.51,202.69 93.12,203.07 93.12,205.61 94.01,206.5 101.38,206.5 102.01,205.87 102.01,203.07 101.63,202.69
GND on TOP: 34.7,198.63 34.58,198.75 34.58,205.74 37.5,208.66 39.15,208.66 39.28,208.79 39.28,209.55 40.67,210.95 43.85,210.95 43.85,207.65 42.07,207.65 41.94,207.52 41.94,204.47 42.07,204.34 43.85,204.34 43.85,201.04 42.2,201.04 41.94,200.79 41.94,198.75 41.82,198.63
GND on TOP: 57.06,180.47 56.93,180.59 56.93,184.4 57.06,184.53 62.64,184.53 62.77,184.4 62.77,180.59 62.64,180.47 ; 2 cut-outs
GND on TOP: 104.94,93.22 104.68,93.47 104.68,95.5 104.94,95.76 116.11,95.76 116.24,95.63 116.24,94.49 115.98,94.23 107.86,94.23 106.84,93.22
GND on TOP: 144.31,207.14 140.11,211.33 140.11,217.55 140.5,217.93 145.96,217.93 150.02,213.87 150.02,209.55 149.96,209.49 149.96,208.98 148.12,207.14
GND on TOP: 38.51,49.78 38.26,50.04 38.26,54.74 40.67,54.74 40.8,54.61 40.8,51.69 40.55,51.44 40.55,50.04 40.29,49.78
GND on TOP: 53.63,169.29 52.74,170.18 48.8,170.18 47.53,171.45 41.82,171.45 41.69,171.58 41.69,174.75 42.07,175.13 46.52,175.13 47.53,174.12 47.53,173.1 48.17,172.47 61.76,172.47 61.88,172.34 61.88,170.69 61.5,170.31 59.98,170.31 58.96,169.29 ; 8 cut-outs
GND on TOP: 64.68,197.49 64.17,197.99 64.17,202.44 64.3,202.56 71.66,202.56 72.55,201.68 72.55,199.14 72.93,198.75 72.93,197.61 72.8,197.49
GND on TOP: 35.09,76.96 34.83,77.22 34.83,78.49 35.09,78.74 37.88,78.74 38.01,78.61 38.01,77.09 37.88,76.96
GND on TOP: 38.13,4.45 38.01,4.57 38.01,5.08 37.75,5.33 37.37,5.33 36.74,4.7 34.58,4.7 34.32,4.95 34.32,9.14 33.94,9.53 33.94,10.54 35.34,10.54 35.59,10.29 35.59,9.96 35.34,9.7 35.34,8.38 35.47,8.26 36.23,8.26 36.36,8.13 36.36,7.11 36.23,6.99 34.83,6.99 34.58,6.73 34.58,5.46 34.83,5.21 36.36,5.21 36.86,5.71 36.86,6.48 37.12,6.73 38.64,6.73 38.9,6.99 38.9,7.01 38.96,7.07 38.96,8.45 39.28,8.76 39.28,9.65 39.33,9.7 39.86,9.7 39.91,9.65 39.91,7.37 38.9,6.35 38.9,5.97 39.02,5.84 39.91,5.84 40.04,5.71 40.04,5.08 39.4,4.45 ; 2 cut-outs
GND on TOP: 112.3,96.14 112.17,96.27 112.17,98.17 112.3,98.3 115.98,98.3 116.11,98.17 116.11,96.27 115.98,96.14
GND on TOP: 102.01,156.72 101.89,156.84 101.89,157.61 102.01,157.73 103.41,157.73 103.92,157.23 103.92,156.84 103.79,156.72
GND on TOP: 34.2,56.01 33.43,56.77 31.78,56.77 31.4,57.15 31.4,59.69 31.66,59.94 35.34,59.94 35.47,59.82 35.47,56.26 35.21,56.01
GND on TOP: 85.86,95.73 85.73,95.86 85.73,96.04 87.4,97.71 87.51,97.71 87.74,97.48 87.74,97.36 86.12,95.73
GND on TOP: 121.06,223.9 120.81,224.16 120.81,224.92 121.06,225.17 126.02,225.17 126.4,224.79 126.4,224.16 126.14,223.9 ; 4 cut-outs
GND on TOP: 34.2,72.9 33.94,73.15 33.94,74.3 33.43,74.8 32.04,74.8 31.78,75.06 31.78,76.2 32.04,76.45 33.94,76.45 34.45,75.95 37.88,75.95 38.01,75.82 38.01,73.15 37.75,72.9 ; 3 cut-outs
GND on TOP: 63.91,211.46 63.79,211.58 63.79,214.12 63.03,214.88 58.58,214.88 57.69,215.77 57.69,218.57 57.95,218.82 64.68,218.82 67.34,216.15 67.34,211.58 67.22,211.46
GND on TOP: 121.7,205.87 121.57,205.99 121.57,207.26 121.83,207.52 123.35,207.52 123.99,208.15 123.99,214.88 124.24,215.14 125.38,215.14 125.76,214.76 125.76,206.76 124.87,205.87 ; 5 cut-outs
GND on TOP: 138.21,19.94 138.08,20.07 138.08,22.23 137.7,22.61 133.26,22.61 133,22.86 133,27.18 133.38,27.56 142.15,27.56 142.27,27.43 142.27,22.86 142.02,22.61 139.61,22.61 139.23,22.23 139.23,21.34 138.84,20.95 138.84,20.07 138.72,19.94
GND on TOP: 158.66,191.26 157.64,192.28 157.64,195.2 158.28,195.83 159.93,195.83 160.05,195.71 160.05,191.52 159.8,191.26 ; 1 cut-out
GND on TOP: 19.46,179.71 19.21,179.96 19.21,184.66 19.34,184.78 24.93,184.78 25.05,184.91 25.05,185.8 25.18,185.93 25.94,185.93 26.07,185.8 26.07,184.91 26.2,184.78 29.24,184.78 29.24,181.48 27.08,181.48 26.96,181.36 26.96,180.21 26.45,179.71
GND on TOP: 101.38,76.58 101.25,76.71 101.25,77.09 101,77.34 99.47,77.34 99.22,77.6 99.22,79.5 99.98,80.26 105.06,80.26 105.7,79.63 105.7,76.71 105.57,76.58
GND on TOP: 80.04,54.48 79.92,54.61 79.92,58.04 80.17,58.29 82.84,58.29 83.35,57.78 83.35,54.74 83.09,54.48
GND on TOP: 23.4,198.5 23.27,198.63 23.27,204.6 23.4,204.72 23.78,204.72 24.04,204.47 26.58,204.47 26.7,204.34 26.7,203.96 26.96,203.71 28.74,203.71 28.86,203.84 28.86,204.6 28.99,204.72 29.37,204.72 29.5,204.6 29.5,203.07 28.35,201.93 28.35,199.14 25.05,199.14 24.42,198.5 ; 14 cut-outs
GND on TOP: 146.46,3.3 146.34,3.43 146.34,5.33 145.83,5.84 145.83,10.67 145.96,10.79 151.8,10.79 151.93,10.67 151.93,3.56 151.67,3.3
GND on TOP: outline of 192 points within 0.76,0.76 184.24,229.24 ; 4 cut-outs
GND on TOP: 97.95,131.19 97.57,131.57 97.57,133.73 97.7,133.86 98.08,133.86 98.33,133.6 98.33,133.35 98.46,133.22 99.22,133.22 99.73,132.72 99.73,131.32 99.6,131.19
GND on TOP: 97.44,107.7 97.44,109.35 97.7,109.6 104.94,109.6 105.06,109.47 105.06,107.82 104.94,107.7
GND on TOP: 41.94,136.27 41.44,136.78 41.44,138.3 46.9,138.3 47.02,138.18 47.02,136.53 46.77,136.27
GND on TOP: 124.62,46.35 123.73,47.24 123.73,49.15 123.86,49.28 126.91,49.28 127.03,49.15 127.03,46.48 126.91,46.35 ; 2 cut-outs
GND on TOP: 32.67,148.59 32.29,148.97 32.29,150.24 31.91,150.62 29.12,150.62 28.74,151 28.74,152.02 27.97,152.78 27.97,154.69 28.35,155.07 33.82,155.07 34.07,154.81 34.07,148.72 33.94,148.59
GND on TOP: 82.66,188.24 82.63,188.26 82.63,195.12 82.28,195.48 78.75,195.48 78.52,195.71 78.52,198.63 77.88,199.26 77.88,199.64 78.01,199.77 78.52,199.77 81.69,196.6 83.98,196.6 84.74,195.83 84.74,189.84 84.59,189.69 83.95,189.69 83.35,189.08 83.35,188.34 83.24,188.24 ; 10 cut-outs
GND on TOP: 46.26,160.27 46.13,160.4 46.13,162.18 46.26,162.31 47.53,162.31 47.91,162.69 53.25,162.69 53.37,162.81 56.8,162.81 57.06,162.56 57.06,161.67 56.42,161.04 48.55,161.04 47.79,160.27 ; 4 cut-outs
GND on TOP: 96.68,103 96.55,103.12 96.55,104.27 96.81,104.52 99.86,104.52 99.98,104.39 99.98,103.12 99.86,103 ; 2 cut-outs
GND on TOP: 81.48,95.24 81.28,95.44 81.28,95.63 86.9,101.24 87.12,101.24 87.28,101.09 87.28,100.86 81.66,95.24
GND on TOP: 110.65,200.28 109.13,201.8 109.13,204.09 109.25,204.22 113.7,204.22 113.83,204.09 113.83,201.93 113.57,201.68 113.57,200.41 113.44,200.28
GND on TOP: 135.54,7.11 135.42,7.24 135.42,9.4 135.67,9.65 139.35,9.65 139.48,9.53 139.48,7.24 139.35,7.11
GND on TOP: 13.88,202.31 13.75,202.44 13.75,204.34 14,204.6 17.05,204.6 17.05,202.31
GND on TOP: 126.27,3.3 126.14,3.43 126.14,4.95 126.65,5.46 126.65,9.4 126.78,9.53 126.78,11.43 126.91,11.56 127.92,11.56 128.15,11.33 128.15,9.5 127.41,8.76 127.41,5.33 127.8,4.95 127.8,3.43 127.67,3.3 ; 4 cut-outs
GND on TOP: 63.03,19.43 62.9,19.56 62.9,21.21 63.28,21.59 67.85,21.59 68.23,21.21 68.23,19.68 67.98,19.43
GND on TOP: 56.29,175.77 56.17,175.9 56.17,177.42 56.29,177.55 60.99,177.55 61.12,177.42 61.12,175.9 60.99,175.77 ; 4 cut-outs
GND on TOP: 166.66,116.71 165.77,117.6 162.47,117.6 162.34,117.73 162.34,119.63 162.47,119.76 168.56,119.76 168.69,119.63 169.96,119.63 170.09,119.51 170.09,117.98 168.82,116.71 ; 4 cut-outs
GND on TOP: 80.42,152.53 80.3,152.65 80.3,152.91 80.55,153.16 80.68,153.16 80.81,153.29 80.81,153.8 80.68,153.92 79.54,153.92 79.41,154.05 79.41,154.18 79.54,154.31 79.79,154.31 80.42,154.94 80.55,154.94 80.81,154.69 81.06,154.69 81.31,154.94 81.57,154.94 81.69,154.81 81.69,154.69 81.95,154.43 82.2,154.43 82.33,154.31 82.33,153.92 82.2,153.8 81.95,153.8 81.57,153.42 81.57,153.29 81.44,153.16 81.19,153.16 80.55,152.53
GND on TOP: 105.95,96.14 105.7,96.39 105.7,98.3 111.41,98.3 111.54,98.17 111.54,96.39 111.29,96.14 ; 2 cut-outs
GND on TOP: 79.46,95.33 79.29,95.5 79.29,95.65 86.88,103.24 87.12,103.24 87.27,103.09 87.27,102.9 79.7,95.33
GND on TOP: 133.26,119.13 129.07,123.32 120.94,123.32 120.81,123.44 120.81,126.62 121.06,126.87 125.51,126.87 125.64,126.75 125.64,125.6 126.14,125.09 132.75,125.09 132.88,124.97 132.88,122.56 133.51,121.92 136.43,121.92 136.69,122.17 140.75,122.17 141,121.92 141,119.38 140.75,119.13
GND on TOP: 73.44,21.46 72.42,22.48 72.42,26.16 72.55,26.29 81.31,26.29 81.44,26.16 81.44,22.48 80.42,21.46
GND on TOP: 34.83,64.01 34.58,64.26 34.58,66.04 34.45,66.17 34.45,66.93 34.58,67.06 35.21,67.06 35.72,66.55 37.12,66.55 37.12,65.28 36.99,65.15 35.85,65.15 35.72,65.02 35.72,64.26 35.47,64.01 ; 1 cut-out
GND on TOP: 78.86,96.66 78.68,96.84 78.68,96.99 85.41,103.73 85.41,104.12 85.18,104.36 84.82,104.36 79.07,98.6 78.82,98.6 78.65,98.77 78.65,99.01 83.54,103.89 83.54,104.18 83.24,104.48 82.93,104.48 82.69,104.23 82.68,104.23 78.73,100.28 78.44,100.28 78.32,100.41 78.32,100.68 81.42,103.79 81.42,104.09 81.19,104.33 80.81,104.33 79.18,102.7 78.95,102.7 78.75,102.89 78.75,103.09 80.43,104.78 86.77,104.78 86.8,104.75 86.8,104.3 79.16,96.66
GND on TOP: 131.35,83.57 131.22,83.69 131.22,84.71 131.35,84.84 132.24,84.84 132.37,84.96 132.37,86.49 132.24,86.61 130.59,86.61 130.59,89.92 132.24,89.92 132.37,90.04 132.37,91.69 132.62,91.95 137.96,91.95 138.08,91.82 138.08,85.72 138.72,85.09 142.02,85.09 142.15,84.96 142.15,83.69 142.02,83.57 ; 2 cut-outs
GND on TOP: 90.71,65.53 90.08,66.17 90.08,68.45 90.33,68.71 98.97,68.71 100.24,69.98 106.59,69.98 106.84,69.72 106.84,68.2 106.71,68.07 106.08,68.07 105.82,67.82 105.82,66.17 105.19,65.53 ; 4 cut-outs
GND on TOP: 112.17,218.57 112.05,218.69 112.05,223.01 111.92,223.14 109.63,223.14 109.63,223.39 110.02,223.77 110.02,224.92 110.14,225.04 112.94,225.04 113.44,224.54 113.44,219.46 112.56,218.57
GND on TOP: 65.95,161.8 66.45,161.8 68.36,163.7 68.36,166.24 69.88,167.77 74.96,167.77 75.34,167.39 75.34,162.69 74.8,162.14 71.51,162.14 71.51,162.13 68.64,159.26 66.84,159.26 66.2,158.62 66.2,157.86 66.07,157.73 65.82,157.73 65.57,157.99 65.57,158.62 66.58,159.64 67.85,159.64 68.11,159.89 67.34,160.66 66.2,160.66 65.82,161.04 65.82,161.67
GND on TOP: 98.33,125.48 98.18,125.63 98.18,128.52 98.31,128.65 99.6,128.65 99.98,128.27 99.98,125.6 99.86,125.48 ; 5 cut-outs
GND on BOTTOM: 86.77,125.35 84.87,127.25 84.87,127.76 86.27,129.16 86.27,129.67 86.39,129.79 86.65,129.79 86.9,129.54 86.9,129.29 86.77,129.16 86.77,128.52 88.55,126.75 88.55,126.62 87.28,125.35
GND on BOTTOM: 84.36,100.2 84.23,100.33 84.23,100.84 84.11,100.97 83.22,100.97 83.09,100.84 80.17,100.84 79.79,101.22 79.41,101.22 79.28,101.35 79.28,101.73 79.41,101.85 83.6,101.85 84.74,103 87.66,103 87.79,102.87 87.79,100.97 87.66,100.84 87.16,100.84 86.65,100.33 86.27,100.33 86.01,100.58 85.12,100.58 84.74,100.2 ; 5 cut-outs
GND on BOTTOM: 23.53,199.14 23.53,203.96 28.35,203.96 28.35,199.14
GND on BOTTOM: 78.9,179.32 78.77,179.45 78.77,184.91 78.9,185.04 79.28,185.04 79.41,184.91 79.41,179.45 79.28,179.32
GND on BOTTOM: 36.48,12.7 36.36,12.83 36.36,13.84 36.48,13.97 36.48,15.52 36.23,15.77 35.57,15.77 35.47,15.88 35.47,17.27 35.59,17.4 40.04,17.4 40.09,17.35 40.09,16.36 40.22,16.23 40.22,15.29 39.48,14.55 39.48,13.64 39.91,13.21 39.91,12.83 39.78,12.7 ; 13 cut-outs
GND on BOTTOM: 79.66,194.44 78.65,195.45 78.65,196.72 79.66,197.74 80.55,197.74 80.81,197.49 80.81,195.07 80.17,194.44
GND on BOTTOM: 129.45,208.03 129.19,208.28 129.19,211.71 129.7,212.22 131.61,212.22 131.86,211.96 131.86,208.15 131.73,208.03
GND on BOTTOM: 84.23,224.54 83.73,225.04 83.73,226.57 83.98,226.82 89.31,226.82 89.82,226.31 89.82,225.55 89.44,225.17 89.44,224.66 89.31,224.54
GND on BOTTOM: 88.17,103.38 88.04,103.5 88.04,104.78 87.92,104.9 87.16,104.9 87.03,105.03 87.03,105.41 87.16,105.54 93.51,105.54 93.76,105.28 93.76,104.9 93.89,104.78 94.39,104.78 94.52,104.65 94.52,103.89 94.39,103.76 92.49,103.76 92.11,103.38 ; 9 cut-outs
GND on BOTTOM: 33.31,38.23 33.18,38.35 33.18,42.42 34.58,42.42 34.96,42.04 34.96,41.53 35.85,40.64 35.85,38.48 35.59,38.23
GND on BOTTOM: 29.75,161.16 29.62,161.29 29.62,164.97 29.75,165.1 31.15,165.1 31.4,164.85 31.4,164.08 31.53,163.96 32.93,163.96 33.05,163.83 33.05,161.29 32.93,161.16 ; 2 cut-outs
GND on BOTTOM: 141.64,200.66 141.38,200.91 141.38,204.47 141.64,204.72 142.91,204.72 143.67,203.96 143.67,201.55 142.78,200.66
GND on BOTTOM: 82.71,189.74 81.82,190.63 81.82,196.85 82.08,197.1 85.89,197.1 86.27,196.72 86.27,190.75 85.25,189.74
GND on BOTTOM: 84.23,122.3 83.22,123.32 82.58,123.32 81.69,122.43 81.31,122.43 81.19,122.56 81.19,122.94 82.58,124.33 83.98,124.33 85.12,123.19
GND on BOTTOM: 76.61,154.81 76.49,154.94 76.49,155.32 76.61,155.45 77.12,155.45 78.9,157.23 81.06,157.23 81.19,157.1 81.19,156.21 81.06,156.08 80.17,156.08 79.54,156.72 79.15,156.72 78.9,156.46 78.9,155.32 78.77,155.19 78.01,155.19 77.76,154.94 77.38,154.94 77.25,154.81 ; 2 cut-outs
GND on BOTTOM: 94.9,176.15 94.78,176.28 94.78,177.16 94.9,177.29 97.32,177.29 98.2,178.18 99.6,178.18 99.73,178.31 99.73,178.82 99.86,178.94 100.11,178.94 100.24,178.82 100.24,178.31 100.36,178.18 101.63,178.18 101.76,178.31 101.76,179.32 104.94,182.5 106.46,182.5 106.59,182.37 106.59,177.55 105.19,176.15 ; 7 cut-outs
GND on BOTTOM: 119.16,9.14 118.78,9.53 118.78,11.43 119.16,11.81 119.79,11.81 119.92,11.94 119.92,12.7 120.05,12.83 121.57,12.83 121.7,12.7 121.7,9.27 121.57,9.14 ; 1 cut-out
GND on BOTTOM: 85.5,160.93 85.15,161.29 84.62,161.29 84.49,161.42 77.88,161.42 77.76,161.54 77.76,163.32 78.01,163.58 84.62,163.58 85.38,164.34 85.89,164.34 86.01,164.21 86.01,163.45 85.89,163.32 85.5,163.32 84.87,162.69 84.87,162.31 85.25,161.93 85.63,161.93 85.94,161.62 85.94,161.11 85.76,160.93 ; 10 cut-outs
GND on BOTTOM: outline of 86 points within 0.76,0.76 184.24,229.24 ; 13 cut-outs
GND on BOTTOM: 57.31,175.77 57.06,176.02 57.06,177.29 57.18,177.42 60.87,177.42 60.99,177.29 60.99,176.02 60.74,175.77 ; 3 cut-outs
GND on BOTTOM: 23.66,36.07 23.27,36.45 23.27,41.66 24.16,42.55 25.69,42.55 25.81,42.42 25.81,36.2 25.69,36.07
GND on BOTTOM: 151.93,21.59 151.8,21.72 151.8,22.99 151.93,23.11 153.32,23.11 153.45,22.99 153.45,21.72 153.32,21.59
GND on BOTTOM: 31.4,149.86 31.28,149.99 31.28,150.5 31.15,150.62 27.72,150.62 27.72,151.76 27.97,152.02 27.97,154.69 28.35,155.07 33.56,155.07 33.56,149.99 33.43,149.86 ; 2 cut-outs
GND on BOTTOM: 25.56,170.05 25.56,171.2 25.69,171.32 27.08,171.32 27.97,172.21 27.97,172.59 28.1,172.72 28.99,172.72 29.12,172.59 29.12,171.45 27.72,170.05
GND on BOTTOM: 157.77,45.09 157.64,45.21 157.64,50.93 157.77,51.05 158.53,51.05 158.66,50.93 160.31,50.93 160.82,51.44 163.86,51.44 164.37,50.93 164.37,50.29 164.24,50.16 162.97,50.16 162.72,49.91 162.72,47.24 162.85,47.12 163.48,47.12 163.61,46.99 163.61,46.35 163.48,46.23 162.09,46.23 161.96,46.1 161.96,45.21 161.83,45.09 ; 3 cut-outs
GND on BOTTOM: 79.03,113.67 78.9,113.79 78.9,115.32 79.28,115.7 81.19,115.7 82.46,114.43 82.46,113.79 82.33,113.67
GND on BOTTOM: 83.98,203.84 83.85,203.96 83.85,205.1 83.98,205.23 90.2,205.23 90.46,204.98 90.46,203.96 90.33,203.84
GND on BOTTOM: 40.55,105.79 40.29,106.05 40.29,107.06 40.04,107.31 38.64,107.31 38.64,107.95 42.32,107.95 42.58,107.7 42.58,106.05 42.32,105.79 ; 2 cut-outs
GND on BOTTOM: 98.46,223.65 97.82,224.28 97.82,224.66 97.44,225.04 96.55,225.04 96.3,225.3 96.3,226.82 96.43,226.95 102.9,226.95 103.03,226.82 103.03,226.31 102.78,226.06 102.78,223.65 ; 2 cut-outs
GND on BOTTOM: 46.26,160.15 46.01,160.4 46.01,160.78 47.91,162.69 53.25,162.69 53.37,162.81 56.8,162.81 57.06,162.56 57.06,161.67 56.93,161.54 51.85,161.54 51.6,161.8 48.17,161.8 46.52,160.15 ; 2 cut-outs
GND on BOTTOM: 85.38,182.12 85.25,182.25 85.25,182.5 85.5,182.75 86.01,182.75 86.39,183.13 86.39,185.55 85.89,186.06 85.89,186.69 86.01,186.82 86.27,186.82 87.66,185.42 87.66,183.01 87.54,182.88 87.28,182.88 86.52,182.12
GND on BOTTOM: 38.51,49.78 38.26,50.04 38.26,54.74 40.67,54.74 40.8,54.61 40.8,51.69 40.55,51.44 40.55,50.04 40.29,49.78 ; 2 cut-outs
GND on BOTTOM: 53.37,168.78 51.98,170.18 48.8,170.18 47.53,171.45 41.82,171.45 41.69,171.58 41.69,174.75 42.07,175.13 46.26,175.13 46.52,175.39 47.4,175.39 47.53,175.26 47.53,173.1 48.17,172.47 57.31,172.47 57.95,171.83 58.45,171.83 58.58,171.7 58.58,169.67 58.33,169.42 58.33,169.29 55.53,169.29 55.02,168.78 ; 6 cut-outs
GND on BOTTOM: 133.64,21.21 133.51,21.34 133.51,27.3 133.76,27.56 141.26,27.56 141.51,27.81 142.91,27.81 143.04,27.69 143.04,22.73 142.91,22.61 141.77,22.61 141.64,22.48 141.64,21.21 138.21,21.21 138.08,21.34 138.08,22.23 137.7,22.61 136.3,22.61 136.05,22.35 136.05,21.21 ; 4 cut-outs
GND on BOTTOM: 79.54,103.12 78.65,104.01 77.5,104.01 77.38,104.14 77.38,104.65 77.5,104.78 78.01,104.78 78.14,104.65 84.23,104.65 84.36,104.52 84.36,103.89 83.6,103.12 ; 9 cut-outs
GND on BOTTOM: 64.68,22.86 64.42,23.11 64.42,25.02 64.8,25.4 67.47,25.4 67.85,25.02 67.85,23.11 67.6,22.86 ; 4 cut-outs
GND on BOTTOM: 129.57,149.1 129.45,149.22 129.45,151.64 130.34,152.53 130.34,153.8 129.45,154.69 129.45,161.29 128.81,161.93 128.81,163.7 128.94,163.83 130.97,163.83 131.1,163.7 131.1,149.22 130.97,149.1 ; 12 cut-outs
GND on BOTTOM: 46.13,31.88 46.13,38.86 47.53,38.86 49.82,36.58 49.82,32 49.69,31.88
GND on BOTTOM: 42.2,197.49 42.07,197.61 42.07,197.74 41.31,198.5 34.45,198.5 34.45,199.64 34.58,199.77 34.58,205.74 36.36,207.52 36.36,211.58 36.48,211.71 37.24,211.71 37.37,211.58 40.8,211.58 41.44,212.22 41.44,213.36 41.56,213.49 42.32,213.49 42.45,213.36 42.45,211.96 41.94,211.46 41.94,209.8 42.07,209.68 43.85,209.68 43.85,206.38 42.2,206.38 41.94,206.12 41.94,204.47 42.07,204.34 42.07,203.2 42.2,203.07 43.85,203.07 43.85,199.77 42.45,199.77 42.32,199.64 42.32,198.88 42.96,198.25 42.96,197.74 42.71,197.49 ; 3 cut-outs
GND on BOTTOM: 88.04,161.16 87.92,161.29 87.92,161.93 87.79,162.05 87.41,162.05 87.28,162.18 87.28,162.56 87.41,162.69 87.79,162.69 87.92,162.81 87.92,167.26 88.04,167.39 89.06,167.39 89.19,167.26 89.19,166.75 89.06,166.62 88.81,166.62 88.55,166.37 88.55,165.74 88.68,165.61 89.82,165.61 89.95,165.48 89.95,164.85 89.82,164.72 88.81,164.72 88.55,164.47 88.55,163.83 88.68,163.7 89.06,163.7 89.19,163.58 89.19,163.19 88.55,162.56 88.55,162.31 88.93,161.93 89.95,161.93 90.08,161.8 90.08,161.29 89.95,161.16 ; 2 cut-outs
GND on BOTTOM: 176.06,135.38 175.8,135.64 175.17,135.64 174.66,136.14 174.66,138.18 174.91,138.43 174.91,140.84 175.17,141.1 175.42,141.1 175.55,140.97 175.55,137.16 175.8,136.91 177.33,136.91 177.71,136.53 177.71,135.64 177.45,135.38 ; 2 cut-outs
GND on BOTTOM: 83.6,180.34 83.47,180.47 83.47,181.23 83.35,181.36 82.58,181.36 82.46,181.48 82.46,181.86 82.58,181.99 83.22,181.99 83.35,182.12 83.35,183.26 83.22,183.39 82.71,183.39 82.58,183.51 82.58,183.77 82.33,184.02 82.33,184.66 82.46,184.78 82.84,184.78 82.96,184.66 82.96,184.02 83.09,183.9 83.85,183.9 84.11,183.64 84.11,180.47 83.98,180.34
GND on BOTTOM: 57.06,180.47 56.93,180.59 56.93,184.4 57.06,184.53 62.64,184.53 62.77,184.4 62.77,180.59 62.64,180.47 ; 2 cut-outs
GND on BOTTOM: 79.92,106.81 79.41,107.31 78.9,107.31 78.9,108.33 78.77,108.46 78.39,108.46 78.27,108.58 78.27,108.84 78.39,108.97 78.52,108.97 78.9,109.35 78.9,111.25 79.03,111.38 79.79,111.38 79.92,111.25 79.92,110.24 80.17,109.98 80.81,109.98 81.19,109.6 81.19,108.2 81.31,108.08 81.31,107.44 81.19,107.31 80.68,107.31 80.17,106.81 ; 3 cut-outs
GND on BOTTOM: 72.8,111.63 72.68,111.76 72.68,113.28 72.93,113.54 75.09,113.54 75.34,113.28 77.12,113.28 77.25,113.16 77.25,112.01 77.12,111.89 73.82,111.89 73.57,111.63 ; 5 cut-outs
GND on BOTTOM: 160.43,74.17 160.31,74.3 160.31,78.23 160.82,78.74 164.75,78.74 164.88,78.61 164.88,74.3 164.75,74.17 ; 3 cut-outs
GND on BOTTOM: 69.88,161.93 68.99,162.81 68.87,162.81 68.74,162.94 68.74,163.32 68.49,163.58 68.46,163.58 68.31,163.73 67.32,163.73 67.09,163.96 65.44,163.96 64.55,163.07 60.74,163.07 59.34,164.47 59.34,166.37 61.12,168.15 63.66,168.15 67.47,164.34 70.01,164.34 70.26,164.08 70.26,162.05 70.14,161.93
GND on BOTTOM: 78.01,167.64 77.88,167.77 77.88,168.91 78.01,169.04 78.01,169.67 77.88,169.8 77.12,169.8 77,169.67 77,169.16 76.87,169.04 76.11,169.04 75.85,169.29 75.85,170.56 75.98,170.69 77.76,170.69 78.27,170.18 83.6,170.18 83.73,170.05 83.73,169.04 83.98,168.78 85.38,168.78 86.01,168.15 86.01,167.77 85.89,167.64 ; 7 cut-outs
GND on BOTTOM: 132.88,82.3 132.75,82.42 132.75,83.31 132.37,83.69 132.37,87.76 132.24,87.88 130.59,87.88 130.59,91.19 131.99,91.19 132.11,91.31 132.11,91.44 132.62,91.95 137.96,91.95 138.08,91.82 138.08,82.55 137.83,82.3 ; 1 cut-out
GND on BOTTOM: 91.98,96.14 91.35,96.77 87.16,96.77 86.65,96.27 86.27,96.27 85.76,96.77 85.12,96.77 85,96.9 85,97.66 85.12,97.79 85.89,97.79 86.14,98.04 86.14,98.68 86.27,98.81 86.65,98.81 86.77,98.68 86.77,97.92 86.9,97.79 89.57,97.79 89.82,97.54 90.33,97.54 90.58,97.79 93.12,97.79 93.25,97.92 93.63,97.92 93.76,97.79 95.16,97.79 95.28,97.66 95.28,96.27 95.16,96.14 ; 1 cut-out
GND on BOTTOM: 48.93,19.18 48.29,19.81 48.29,30.23 48.8,30.73 54.9,30.73 55.15,30.48 55.15,28.96 54.77,28.57 53.75,28.57 53.12,27.94 53.12,25.65 54.14,24.64 57.82,24.64 57.95,24.51 57.95,20.32 56.8,19.18
GND on BOTTOM: 90.84,90.3 90.71,90.42 90.71,91.69 90.46,91.95 89.95,91.95 89.82,92.08 89.82,92.71 89.7,92.84 88.81,92.84 88.68,92.96 88.68,93.22 88.55,93.34 86.77,93.34 86.01,92.58 85.76,92.58 85.63,92.71 85.63,93.22 85.5,93.34 83.98,93.34 83.73,93.09 83.73,92.84 83.6,92.71 83.22,92.71 83.09,92.84 83.09,93.47 83.6,93.98 89.7,93.98 89.95,93.73 91.22,93.73 91.73,93.22 91.73,90.42 91.6,90.3 ; 4 cut-outs
GND on BOTTOM: 38.39,219.71 38.26,219.84 38.26,221.11 38.39,221.23 46.13,221.23 46.26,221.11 46.26,219.84 46.13,219.71
GND on BOTTOM: 62.9,19.43 62.64,19.68 62.64,21.34 62.9,21.59 67.09,21.59 67.34,21.34 67.34,19.68 67.09,19.43
GND on BOTTOM: 172.37,149.48 171.86,149.99 171.86,151.89 172.12,152.15 172.63,152.15 172.88,151.89 172.88,149.61 172.75,149.48
GND on BOTTOM: 111.79,76.83 111.67,76.96 111.67,80.01 111.79,80.14 116.11,80.14 116.24,80.01 116.24,77.22 116.11,77.09 114.84,77.09 114.59,76.83 ; 1 cut-out
GND on BOTTOM: 80.81,179.32 80.68,179.45 80.68,184.4 80.81,184.53 81.19,184.53 81.31,184.4 81.31,179.45 81.19,179.32
GND on BOTTOM: 45.75,84.58 45.6,84.73 45.6,90.5 45.88,90.78 45.88,118.75 47.4,120.27 57.31,120.27 57.44,120.14 57.44,118.62 57.31,118.49 54.64,118.49 54.26,118.87 51.85,118.87 51.6,118.62 51.09,118.62 50.71,119 47.91,119 47.28,118.36 47.28,104.27 46.9,103.89 46.9,100.2 47.28,99.82 47.28,98.55 46.9,98.17 46.9,97.16 47.28,96.77 47.28,96.39 46.9,96.01 46.9,95.12 47.28,94.74 47.28,90.93 47.15,90.81 47.15,89.28 46.9,89.03 46.9,84.71 46.77,84.58 ; 36 cut-outs
GND on BOTTOM: 7.4,214.76 7.27,214.88 7.27,216.03 8.29,217.04 9.56,217.04 9.69,216.92 9.69,214.88 9.56,214.76
GND on BOTTOM: 66.33,196.98 65.95,197.36 65.95,215.77 65.44,216.28 58.07,216.28 57.82,216.53 57.82,218.44 57.95,218.57 64.8,218.57 68.04,215.33 68.04,197.07 67.95,196.98
GND on BOTTOM: 128.05,124.46 127.54,124.97 127.54,125.48 127.67,125.6 129.32,125.6 130.21,126.49 130.84,126.49 130.97,126.36 130.97,125.86 131.22,125.6 134.02,125.6 134.27,125.35 134.27,124.59 134.15,124.46 ; 3 cut-outs
GND on BOTTOM: 68.61,174.75 68.49,174.88 68.49,176.91 68.87,177.29 71.03,177.29 71.15,177.42 71.15,178.05 71.28,178.18 72.55,178.18 72.8,177.93 72.8,176.28 73.19,175.9 73.19,174.88 73.06,174.75 ; 4 cut-outs
GND on BOTTOM: 19.34,178.56 19.21,178.69 19.21,184.66 19.34,184.78 26.7,184.78 26.83,184.66 26.83,183.77 27.08,183.51 29.24,183.51 29.24,180.21 27.34,180.21 27.08,179.96 27.08,178.94 26.7,178.56
GND on BOTTOM: 51.09,187.2 50.45,187.83 44.99,187.83 44.74,188.09 44.74,188.98 44.99,189.23 46.52,189.23 46.9,189.61 46.9,191.01 47.28,191.39 55.28,191.39 55.91,192.02 59.09,192.02 59.34,191.77 59.34,188.72 59.09,188.47 56.68,188.47 55.41,187.2
GND on BOTTOM: 64.93,66.55 63.15,68.33 63.15,72.26 63.28,72.39 65.82,72.39 65.95,72.26 65.95,69.01 66.05,68.91 67.9,68.91 67.94,68.87 67.94,68.29 67.93,68.28 66.35,68.28 66.28,68.2 66.28,67.69 66.11,67.53 65.78,67.53 65.57,67.31 65.57,66.8 65.31,66.55 ; 1 cut-out
GND on BOTTOM: 40.42,110.87 40.29,111 40.29,113.28 40.55,113.54 41.82,113.54 42.32,113.03 42.32,111 42.2,110.87 ; 2 cut-outs
GND on BOTTOM: 82.33,172.59 82.2,172.72 82.2,178.05 82.33,178.18 83.35,178.18 83.47,178.05 83.47,177.67 83.85,177.29 84.49,177.29 84.62,177.16 84.62,176.66 85.89,175.39 85.89,173.48 85.76,173.35 84.36,173.35 84.23,173.23 84.23,172.85 83.98,172.59 ; 1 cut-out
GND on BOTTOM: 132.11,32.38 131.86,32.64 131.86,33.02 131.73,33.15 131.1,33.15 130.08,34.16 130.08,37.72 130.21,37.85 134.02,37.85 134.15,37.72 134.15,34.54 133.38,33.78 133.38,32.51 133.26,32.38 ; 9 cut-outs
GND on L2GND: outline of 177 points within 0.76,0.76 184.24,229.24 ; 21 cut-outs
GND on L3: 56.93,125.98 71.03,125.98 81.44,115.57 81.44,114.81 81.31,114.68 79.03,114.68 78.01,115.7 68.99,115.7 66.71,117.98 57.18,117.98 56.42,117.22 56.42,113.92 56.29,113.79 55.79,113.79 55.66,113.67 55.66,110.87 53.37,108.58 52.74,108.58 52.48,108.33 52.48,106.05 52.1,105.66 51.21,105.66 49.31,103.76 49.31,99.57 51.47,97.41 54.52,97.41 54.9,97.03 54.9,94.36 54.77,94.23 52.61,94.23 52.48,94.11 52.48,92.96 51.6,92.08 46.64,92.08 46.39,92.33 46.39,111.38 46.52,111.51 46.52,115.57
GND on L3: 116.87,226.95 117.51,226.31 117.51,210.31 117,209.8 105.57,209.8 104.94,210.44 104.94,225.43 106.46,226.95
GND on L3: 48.29,27.43 48.29,20.83 48.61,20.51 56.48,20.51 57.95,21.97 57.95,24.51 57.82,24.64 52.36,24.64 51.72,25.27 51.72,29.08 51.6,29.21 50.07,29.21
GND on L3: outline of 162 points within 0.76,0.76 184.24,229.24 ; 3 cut-outs
GND on L3: 79.92,111.63 79.79,111.51 79.79,105.41 80.04,105.16 96.93,105.16 98.08,104.01 101.51,104.01 101.89,104.39 101.89,109.47 101.25,110.11 94.52,110.11 93,111.63
GND on L3: 82.46,73.79 82.46,81.28 86.65,85.47 86.65,87.63 86.01,88.27 85,88.27 84.62,88.65 84.62,89.53 85.25,90.17 87.66,90.17 89.57,88.27 89.57,84.58 89.82,84.33 94.39,84.33 98.2,80.52 98.84,80.52 99.47,79.88 105.7,79.88 105.95,79.63 105.95,75.69 101,70.74 85.5,70.74
GND on L3: 72.52,51.02 72.52,53.88 71.79,54.61 67.85,54.61 67.72,54.48 67.72,50.8 67.98,50.55 68.74,50.55 68.99,50.8 72.3,50.8
GND on L4: 72.52,51.02 72.3,50.8 68.99,50.8 68.74,50.55 67.98,50.55 67.72,50.8 67.72,54.48 67.85,54.61 71.79,54.61 72.52,53.88
GND on L4: outline of 147 points within 0.76,0.76 184.24,229.24 ; 2 cut-outs
GND on L4: 79.92,111.63 93,111.63 94.52,110.11 101.25,110.11 101.89,109.47 101.89,104.39 101.51,104.01 98.08,104.01 97.06,105.03 97.06,106.05 96.17,106.93 88.17,106.93 87.54,107.57 84.11,107.57 83.73,107.19 83.73,106.93 83.6,106.81 83.35,106.81 82.84,107.31 80.68,107.31 80.17,106.81 80.04,106.81 79.79,107.06 79.79,111.51
GND on L4: 89.44,87.12 91.6,87.12 94.9,83.82 94.9,82.55 96.93,80.52 98.84,80.52 99.47,79.88 105.7,79.88 105.95,79.63 105.95,75.69 102.27,72.01 92.87,72.01 90.97,73.91 88.17,73.91 84.23,77.85 84.23,81.92
GND on L4: 56.17,125.22 62.14,125.22 66.58,120.78 66.58,118.24 66.33,117.98 57.18,117.98 56.42,117.22 56.42,113.92 56.29,113.79 55.79,113.79 55.66,113.67 55.66,110.87 53.37,108.58 52.74,108.58 52.48,108.33 52.48,106.05 52.1,105.66 51.21,105.66 49.31,103.76 49.31,99.57 51.21,97.66 51.21,96.9 50.83,96.52 50.83,94.11 51.09,93.85 52.36,93.85 52.48,93.73 52.48,92.96 51.6,92.08 46.9,92.08 46.64,92.33 46.64,115.57 56.17,125.09
PVCC_3V3 on BOTTOM: 53.75,52.58 53.63,52.7 53.63,56.64 52.87,57.4 52.87,65.28 52.1,66.04 52.1,66.8 52.36,67.06 53.37,67.06 53.5,66.93 53.5,64.64 53.75,64.39 53.75,61.72 54.01,61.47 55.02,61.47 55.15,61.34 55.15,61.09 55.02,60.96 53.63,60.96 53.5,60.83 53.5,59.69 53.63,59.56 55.02,59.56 55.15,59.44 55.15,58.93 55.02,58.8 54.77,58.8 54.64,58.93 53.63,58.93 53.5,58.8 53.5,57.91 54.9,56.52 58.33,56.52 58.45,56.39 58.45,55.88 58.33,55.75 57.06,55.75 56.68,55.37 56.68,52.7 56.55,52.58 ; 7 cut-outs
VCC on TOP: 10.19,187.71 9.94,187.96 9.94,188.98 10.07,189.1 14.64,189.1 14.77,189.23 14.77,190.88 14.89,191.01 18.32,191.01 18.45,190.88 18.45,189.99 16.16,187.71
VCC on TOP: 121.45,3.3 121.06,3.68 121.06,6.1 121.45,6.48 125.26,6.48 125.51,6.73 126.27,6.73 126.27,5.59 125.89,5.21 125.89,4.32 125.76,4.19 125.76,3.56 125.51,3.3 ; 2 cut-outs
VCC on BOTTOM: 5.37,208.03 5.24,208.15 5.24,210.31 5.37,210.44 9.18,210.44 9.3,210.31 9.3,208.15 9.18,208.03
VCC on BOTTOM: 121.7,29.72 121.57,29.84 121.57,31.11 120.05,32.64 120.05,34.04 119.67,34.42 119.03,34.42 118.91,34.54 118.91,36.32 119.03,36.45 119.67,36.45 122.02,34.1 122.02,32.45 122.84,31.62 122.84,29.84 122.72,29.72 ; 2 cut-outs
VCC on BOTTOM: 34.45,108.2 34.2,108.46 34.2,110.62 34.32,110.74 37.37,110.74 37.63,110.49 37.63,108.2 ; 2 cut-outs
VCC on L3: 85.63,1.65 22,1.65 21.88,1.78 21.88,43.69 22,43.81 25.43,43.81 25.56,43.69 25.56,20.68 25.73,20.51 25.73,18.38 25.69,18.34 25.69,5.33 26.83,4.19 48.17,4.19 48.42,4.45 48.42,4.7 49.44,5.71 54.26,5.71 55.41,4.57 83.85,4.57 83.98,4.7 83.98,7.24 84.11,7.37 86.01,7.37 86.14,7.24 86.14,2.16
VCC on L3: 96.05,5.21 124.37,5.21 124.62,4.95 124.62,3.43 124.49,3.3 94.39,3.3 92.36,5.33 92.36,8.13 92.49,8.26 94.9,8.26 95.03,8.13 95.03,6.22
VCC on L4: 124.62,3.43 124.49,3.3 85.38,3.3 85.25,3.43 85.25,7.24 85.38,7.37 92.24,7.37 92.36,7.49 92.36,8.13 92.49,8.26 94.9,8.26 95.03,8.13 95.03,6.22 95.54,5.71 124.24,5.71 124.62,5.33
VCC on L4: 22,43.81 26.83,43.81 30.13,47.12 30.13,53.72 30.39,53.98 30.39,57.78 27.97,60.2 27.97,72.9 29.88,74.8 29.88,132.08 28.1,133.86 22.39,133.86 14.26,141.99 14.26,149.73 10.57,153.42 10.57,173.1 9.69,173.99 9.69,188.85 9.94,189.1 11.59,189.1 11.97,188.72 11.97,185.04 12.03,184.98 12.03,175.32 12.99,174.37 12.99,155.07 16.8,151.26 16.8,142.88 23.4,136.27 29.24,136.27 32.67,132.84 32.67,111.12 33.05,110.74 36.23,110.74 36.36,110.62 36.36,108.46 36.1,108.2 33.82,108.2 33.43,107.82 33.43,82.93 34.51,81.85 34.51,73.72 31.66,70.87 31.66,61.72 33.18,60.2 33.18,53.59 32.93,53.34 32.93,46.1 32.8,45.97 32.8,44.96 28.74,40.89 22.13,40.89 21.88,41.15 21.88,43.69
VCC3 on TOP: 76.11,70.48 76.11,68.58 76.87,67.82 77.5,67.82 77.63,67.94 77.63,69.34 78.01,69.72 78.01,70.23 77.76,70.48
VCC3 on TOP: 125.26,8.13 125.26,8.51 124.37,9.4 124.37,9.65 124.24,9.78 124.24,10.41 123.99,10.67 123.35,10.67 123.22,10.79 123.22,11.18 123.35,11.3 123.86,11.3 124.11,11.56 124.11,12.95 124.24,13.08 126.53,13.08 126.65,12.95 126.65,10.16 126.27,9.78 126.27,8.13
VCC3 on TOP: 80.3,69.6 80.04,69.85 80.04,70.36 80.55,70.87 80.55,72.01 80.93,72.39 84.49,72.39 84.62,72.26 84.62,69.85 84.49,69.72 81.19,69.72 81.06,69.6 ; 5 cut-outs
VCC3 on TOP: 149.51,60.2 149.39,60.33 149.39,64.01 150.53,65.15 150.53,66.04 152.05,67.56 152.05,72.9 152.18,73.03 153.32,73.03 153.58,72.77 154.72,72.77 156.12,74.17 158.28,74.17 158.4,74.04 158.4,73.53 158.28,73.41 157.51,73.41 157.26,73.15 157.01,73.15 155.86,72.01 155.61,72.01 154.97,71.37 154.97,67.44 152.05,64.52 152.05,60.33 151.93,60.2 ; 7 cut-outs
VCC3 on TOP: 161.96,184.78 161.83,184.91 161.83,186.56 161.96,186.69 164.88,186.69 165.01,186.56 165.01,185.04 164.75,184.78 ; 1 cut-out
VCC3 on BOTTOM: 153.83,79.88 153.7,80.01 153.7,87.12 157.39,90.81 161.07,90.81 161.2,90.68 161.2,89.15 161.07,89.03 158.78,89.03 155.48,85.72 155.48,80.14 155.23,79.88
VCC3 on BOTTOM: 57.82,62.74 57.69,62.87 57.69,64.77 57.95,65.02 58.2,65.02 59.22,64.01 59.22,62.87 59.09,62.74
VCC3 on BOTTOM: 135.67,125.86 134.78,126.75 129.7,126.75 129.57,126.87 129.57,129.54 129.83,129.79 135.03,129.79 135.54,129.29 138.97,129.29 139.61,129.92 140.24,129.92 140.37,129.79 147.99,129.79 148.37,130.18 149.89,130.18 151.16,131.44 153.45,131.44 154.72,130.18 156.62,130.18 156.75,130.05 156.75,128.65 156.62,128.52 150.91,128.52 149.77,127.38 145.32,127.38 144.69,126.75 144.18,126.75 144.05,126.87 144.05,127.38 143.8,127.64 141.26,127.64 140.5,126.87 138.97,126.87 138.46,126.36 137.57,126.36 137.07,125.86 ; 16 cut-outs
VCC3 on BOTTOM: 133,31.5 132.88,31.62 132.88,31.88 133,32 133.51,32 133.89,32.38 133.89,33.78 134.53,34.42 134.53,39.24 134.65,39.37 134.65,42.42 134.4,42.67 129.7,42.67 128.81,41.78 122.59,41.78 122.46,41.91 122.46,42.93 122.59,43.05 127.67,43.05 128.56,43.94 128.56,45.34 128.68,45.47 136.56,45.47 137.32,44.7 137.32,43.69 137.57,43.43 137.57,34.92 137.83,34.67 137.83,32.89 137.57,32.64 135.67,32.64 135.16,32.13 135.16,31.62 135.03,31.5 ; 9 cut-outs
VCC3 on BOTTOM: 176.06,137.29 175.93,137.41 175.93,140.84 175.17,141.6 175.17,141.99 175.29,142.11 175.67,142.11 176.82,140.97 176.82,138.94 177.2,138.56 177.96,138.56 178.6,137.92 178.6,137.41 178.47,137.29
VCC3 on L3: 171.86,91.06 171.74,91.19 160.69,91.19 160.05,90.55 160.05,88.39 160.18,88.27 171.74,88.27 171.86,88.39
VCC3 on L3: 155.48,78.74 154.59,79.63 154.59,80.39 154.72,80.52 156.88,80.52 157.26,80.14 157.26,72.39 156.88,72.01 155.35,72.01 155.23,72.14 155.23,73.28 155.48,73.53
VCC3 on L4: 183.04,137.41 182.91,137.29 177.96,137.29 177.83,137.41 177.83,138.56 177.96,138.68 182.91,138.68 183.04,138.56
VCC3 on L4: 154.47,41.66 154.47,46.23 153.2,47.5 153.2,52.7 151.67,54.23 151.67,55.88 150.53,57.02 150.53,60.96 151.04,61.47 153.83,61.47 154.59,60.71 154.59,56.9 155.61,55.88 155.61,55.75 156.5,54.86 156.5,51.44 157.13,50.8 157.13,45.59 156.5,44.96 156.5,39.88 155.93,39.31 149.96,39.31 148.5,40.77 138.21,40.77 137.7,40.26 137.7,38.61 137.45,38.35 135.67,38.35 135.54,38.48 135.54,42.1 137.89,44.45 138.72,44.45 138.84,44.32 138.84,43.56 139.29,43.12 149.32,43.12 151.29,41.15 153.96,41.15
VCC3 on L4: 128.18,20.57 128.18,13.08 127.03,11.94 127.03,10.16 126.91,10.03 124.87,10.03 124.49,10.41 124.49,13.21 125.38,14.1 125.38,22.23 125.76,22.61 125.76,24.51 132.88,31.62 132.88,31.88 133.13,32.13 135.03,32.13 135.16,32 135.16,29.59 128.75,23.18 128.75,21.15
VCC3_CAM on TOP: 160.69,187.2 160.31,187.58 160.31,195.96 161.58,197.23 161.58,199.01 162.47,199.01 162.47,197.23 162.59,197.1 162.59,190.75 164.88,188.47 164.88,187.32 164.75,187.2 ; 5 cut-outs
VCC5_PANEL on TOP: 41.94,107.06 41.69,107.31 41.69,108.58 41.82,108.71 44.36,108.71 44.61,108.46 44.99,108.46 45.12,108.33 45.12,107.31 44.86,107.06
VCC5_PANEL on BOTTOM: 43.59,107.19 42.58,108.2 38.64,108.2 38.64,110.49 38.77,110.62 43.59,110.62 45.12,109.09 45.12,107.31 44.99,107.19 ; 10 cut-outs
VCC_CORE on TOP: 48.29,173.23 48.17,173.35 48.17,174.62 47.91,174.88 47.91,175.64 47.79,175.77 45.25,175.77 44.61,176.4 44.61,186.94 44.86,187.2 50.2,187.2 50.83,186.56 56.29,186.56 56.55,186.31 56.55,180.09 56.8,179.83 62.77,179.83 62.77,179.07 61.88,178.18 61.88,173.35 61.76,173.23 ; 12 cut-outs
VCC_CORE on TOP: 75.6,161.8 75.47,161.93 75.47,162.94 75.6,163.07 76.36,163.07 76.49,163.19 76.49,163.58 76.36,163.7 75.85,163.7 75.73,163.58 75.6,163.58 75.47,163.7 75.47,164.72 75.6,164.85 76.74,164.85 76.87,164.72 77.38,164.72 77.5,164.85 77.5,165.48 77.38,165.61 76.87,165.61 76.74,165.48 75.6,165.48 75.47,165.61 75.47,166.62 75.6,166.75 76.36,166.75 76.49,166.88 76.49,167.13 76.36,167.26 75.6,167.26 75.47,167.39 75.47,168.4 75.6,168.53 76.36,168.53 76.49,168.66 76.49,169.42 77.12,169.42 77.25,169.54 77.63,169.54 77.76,169.42 77.76,167 78.14,166.62 78.14,162.56 77.88,162.31 76.36,162.31 75.85,161.8
VCC_CORE on TOP: 86.14,162.69 85.89,162.94 85.89,167.39 86.14,167.64 87.16,167.64 88.17,166.62 88.17,166.5 88.04,166.37 87.41,166.37 87.28,166.24 87.28,165.86 87.41,165.74 87.79,165.74 87.92,165.86 88.04,165.86 88.17,165.74 88.17,164.72 88.04,164.59 87.41,164.59 87.28,164.47 87.28,164.08 87.41,163.96 88.04,163.96 88.17,163.83 88.17,162.81 88.04,162.69
VCC_CORE on BOTTOM: 70.39,161.54 70.26,161.67 70.26,161.93 70.52,162.18 70.52,162.69 70.39,162.81 70.39,164.34 70.01,164.72 67.47,164.72 63.53,168.66 59.34,168.66 58.96,169.04 58.96,172.21 58.83,172.34 57.95,172.34 57.06,173.23 48.29,173.23 48.17,173.35 48.17,174.62 47.91,174.88 47.91,175.64 47.79,175.77 45.25,175.77 44.61,176.4 44.61,186.94 44.86,187.2 50.2,187.2 50.83,186.56 56.29,186.56 56.55,186.31 56.55,180.09 56.8,179.83 62.9,179.83 62.9,175.01 63.41,174.5 73.06,174.5 73.19,174.37 73.19,174.12 73.57,173.74 73.57,173.35 75.6,171.32 75.6,169.29 76.11,168.78 77,168.78 77.12,168.91 77.12,169.42 77.25,169.54 77.63,169.54 77.76,169.42 77.76,167.64 78.14,167.26 86.01,167.26 86.14,167.39 87.66,167.39 87.79,167.26 87.79,163.83 87.66,163.7 87.16,163.7 87.03,163.83 86.39,163.83 86.27,163.96 86.27,164.47 86.01,164.72 85.38,164.72 84.49,163.83 77.25,163.83 76.49,163.07 74.96,163.07 74.58,162.69 74.58,161.8 74.33,161.54 ; 50 cut-outs
VCC_CORE on L3: 86.65,162.81 77.25,162.81 76.74,163.32 76.74,169.42 76.87,169.54 85.76,169.54 86.01,169.29 86.01,167.89 86.77,167.13 86.77,162.94
VCC_CORE on L4: 86.01,167.89 86.77,167.13 86.77,162.94 86.65,162.81 77.25,162.81 76.74,163.32 76.74,171.2 77.25,171.7 85.63,171.7 86.01,171.32
VCC_CORE on L5GND: 69.71,161.86 58.41,173.16 50.75,173.16 48.23,170.64 48.23,174.7 47.36,175.58 45.32,175.58 44.67,176.23 44.67,186.87 44.94,187.13 50.37,187.13 50.88,186.63 56.74,186.63 56.74,186.61 57.23,186.12 62.98,186.12 65.14,188.28 67.01,188.28 67.66,187.63 67.66,181.15 75.27,173.55 76.26,173.55 78.69,171.11 82.39,171.11 82.39,170.48 83.39,169.48 86.31,169.48 86.71,169.09 86.71,167.43 87.46,166.69 87.71,166.69 88.11,166.29 88.11,163.05 87.6,162.54 87.6,162.5 76.41,162.5 75.77,161.86
VCC_FAN on BOTTOM: 5.49,210.82 5.24,211.07 5.24,213.87 5.49,214.12 10.07,214.12 10.45,213.74 15.27,213.74 15.65,213.36 15.65,212.04 14.43,210.82
1D0V_S5 on TOP: 37.75,138.68 37.75,140.46 39.02,140.46 39.15,140.59 39.15,141.99 41.05,143.89 43.47,143.89 45.5,145.92 45.5,155.7 45.75,155.96 49.82,155.96 50.45,155.32 50.45,153.92 50.58,153.8 57.92,153.8 58.43,153.29 59.22,153.29 59.47,153.03 59.47,141.73 59.34,141.6 57.44,141.6 57.31,141.73 57.31,141.86 57.18,141.99 55.28,141.99 55.15,141.86 55.15,141.35 54.9,141.1 53.75,141.1 53.63,141.22 53.63,141.6 53.37,141.86 52.23,141.86 50.96,140.59 48.42,140.59 48.29,140.72 48.29,142.24 48.42,142.37 49.82,142.37 49.82,144.4 49.56,144.65 48.17,144.65 46.77,143.26 46.77,141.86 43.72,141.86 43.47,142.11 42.83,142.11 42.58,141.86 41.31,141.86 40.93,141.48 40.93,138.81 40.8,138.68 ; 6 cut-outs
1D8V_S5 on TOP: 95.66,124.33 95.54,124.46 93.38,124.46 93.25,124.59 93.25,126.36 95.03,126.36 95.28,126.62 95.28,127.38 94.9,127.76 94.01,127.76 93.89,127.89 93.89,128.27 94.01,128.4 95.41,128.4 95.56,128.24 95.56,128.02 95.94,127.64 97.57,127.64 97.7,127.51 97.7,125.6 97.57,125.48 97.44,125.48 97.19,125.22 97.19,124.46 97.06,124.33 ; 5 cut-outs
2D5V_VPP on TOP: 133.64,122.3 133.26,122.68 133.26,125.22 133,125.48 127.41,125.48 127.16,125.73 127.16,130.18 127.54,130.56 128.94,130.56 129.19,130.3 129.19,126.75 129.45,126.49 133.89,126.49 134.4,125.98 134.4,123.95 134.78,123.57 136.05,123.57 136.43,123.95 145.19,123.95 145.45,124.21 145.45,126.36 145.58,126.49 147.86,126.49 148.12,126.24 148.12,123.83 146.85,122.56 136.56,122.56 136.3,122.3
2D5V_VPP on BOTTOM: 127.54,125.86 127.41,125.98 127.41,127.13 127.67,127.38 129.07,127.38 129.19,127.25 129.19,125.98 129.07,125.86 ; 1 cut-out
3D3V_VCCPDSW on BOTTOM: 120.05,13.08 119.92,13.21 119.92,16 120.18,16.26 123.6,16.26 123.73,16.13 123.73,14.73 123.86,14.61 123.86,13.08 ; 2 cut-outs
+V_1P05_VGA on TOP: 103.79,101.73 103.41,102.11 102.52,102.11 101.38,103.25 100.49,103.25 100.36,103.38 100.36,104.65 100.11,104.9 94.14,104.9 94.01,105.03 94.01,106.68 94.27,106.93 104.81,106.93 105.19,106.55 105.19,101.85 105.06,101.73 ; 3 cut-outs
+V_1P05_VGA on TOP: 83.61,104.92 83.6,104.93 76.9,104.93 73.21,108.62 72.26,108.62 72.04,108.84 71.92,108.97 71.92,110.49 72.04,110.62 72.04,110.74 72.17,110.87 72.42,110.87 75.98,107.31 76.23,107.31 76.26,107.28 76.98,107.28 77,107.26 77,106.43 77.12,106.3 81.19,106.3 81.57,105.92 81.57,105.66 81.69,105.54 83.35,105.54 83.47,105.66 83.47,105.92 83.6,106.05 84.74,106.05 85,105.79 85.25,105.79 85.47,106.02 86.39,106.02 86.52,105.89 86.52,105.03 86.41,104.92
+V_1P05_VGA on BOTTOM: 78.52,104.9 74.96,108.46 73.57,108.46 72.17,109.86 72.17,111.12 72.42,111.38 78.39,111.38 78.65,111.12 78.65,109.47 78.01,108.84 78.01,108.46 78.27,108.2 78.52,108.2 78.65,108.08 78.65,107.06 78.9,106.81 79.66,106.81 79.79,106.68 80.3,106.68 80.42,106.81 81.31,106.81 82.33,105.79 82.84,105.79 83.09,106.05 84.74,106.05 85,105.79 86.65,105.79 86.77,105.66 86.77,105.03 86.65,104.9 ; 16 cut-outs
+V_1P05_VGA on L4: 80.3,104.65 80.17,104.78 80.17,106.43 80.81,107.06 82.84,107.06 83.22,106.68 86.9,106.68 87.28,107.06 87.92,107.06 88.3,106.68 95.66,106.68 95.79,106.55 95.79,104.78 95.66,104.65
+V_1P35_VGA on TOP: 50.45,110.11 48.29,112.27 47.66,112.27 47.53,112.39 47.53,112.9 47.66,113.03 48.55,113.03 51.09,110.49 51.72,110.49 51.85,110.62 51.85,110.87 52.48,111.51 52.87,111.51 52.99,111.38 52.99,110.87 52.23,110.11
+V_1P35_VGA on TOP: 47.53,106.43 47.4,106.55 47.4,106.93 47.66,107.19 48.55,107.19 50.33,108.97 54.64,108.97 54.9,108.71 54.9,107.7 54.39,107.19 53.88,107.19 53.75,107.31 53.75,108.33 53.63,108.46 52.61,108.46 52.48,108.33 52.48,107.82 52.87,107.44 52.87,107.31 52.61,107.06 52.48,107.06 51.85,107.7 51.85,107.95 51.6,108.2 50.83,108.2 49.06,106.43
+V_1P35_VGA on TOP: 63.53,80.9 63.41,81.03 63.41,82.17 63.15,82.42 62.26,82.42 62.01,82.17 61.25,82.17 61.12,82.3 61.12,83.44 60.74,83.82 60.74,85.72 61.37,86.36 61.5,86.36 61.63,86.23 61.63,85.09 61.76,84.96 62.77,84.96 62.9,85.09 62.9,85.47 63.03,85.6 63.28,85.6 63.41,85.47 63.41,85.09 64.42,84.07 64.42,81.15 64.17,80.9 ; 3 cut-outs
+V_1P35_VGA on TOP: 82.83,93.21 81.93,94.11 81.57,94.11 81.44,93.98 81.31,93.98 81.19,94.11 79.92,94.11 79.45,93.64 79.43,93.63 79.21,93.63 79.18,93.66 79.1,93.66 78.65,94.11 78.27,94.11 77.38,93.22 77.12,93.22 77,93.34 77,93.47 77.25,93.73 77.25,93.85 77,94.11 77,94.23 77.25,94.49 77.25,95 76.87,95.38 76.87,95.89 77.12,96.14 77.12,96.43 76.23,97.33 76.19,97.33 75.73,97.79 75.22,97.79 74.71,97.28 74.58,97.28 74.46,97.41 74.46,97.66 74.84,98.04 75.6,98.04 75.73,98.17 76.11,98.17 76.23,98.04 76.61,98.04 77.12,98.55 77.12,98.93 77,99.06 77,99.31 77.12,99.44 77.12,100.58 76.98,100.72 76.98,100.85 77.12,100.99 77.12,101.35 77,101.46 77,101.61 77,101.62 77,101.73 77.12,101.85 77.12,103.12 77,103.25 77,103.38 77.12,103.5 77.12,104.01 76.87,104.27 76.61,104.27 76.49,104.39 76.49,104.65 76.61,104.78 78.01,104.78 78.14,104.65 78.14,95.25 78.39,95 83.85,95 84.12,94.73 84.12,94.12 83.21,93.21
+V_1P35_VGA on TOP: 48.29,92.2 47.53,92.96 47.53,94.11 47.66,94.23 48.55,94.23 48.67,94.36 48.67,96.14 48.42,96.39 47.79,96.39 47.66,96.52 47.66,97.03 47.79,97.16 50.2,97.16 50.58,96.77 50.58,96.39 50.78,96.19 51.26,96.19 51.47,96.39 51.47,97.16 51.6,97.28 51.98,97.28 52.1,97.16 52.1,96.27 51.98,96.14 51.72,96.14 51.47,95.89 51.47,95.58 52.05,95 52.05,94.84 51.87,94.67 51.87,94.59 51.47,94.18 51.47,93.22 51.72,92.96 51.72,92.58 51.34,92.2 ; 1 cut-out
+V_1P35_VGA on TOP: 90.33,69.09 90.08,69.34 90.08,72.77 90.2,72.9 95.79,72.9 97.7,74.8 97.7,76.83 97.95,77.09 100.87,77.09 101,76.96 101,76.58 100.87,76.45 99.86,76.45 99.73,76.33 99.73,69.98 98.84,69.09 ; 4 cut-outs
+V_1P35_VGA on BOTTOM: outline of 178 points within 47.28,67.56 98.84,120.4 ; 56 cut-outs
+V_1P35_VGA on L4: 54.14,92.2 54.01,92.33 54.01,93.22 54.07,93.28 53.12,94.23 51.21,94.23 51.09,94.36 51.09,96.14 51.34,96.39 51.34,97.16 51.47,97.28 53.63,97.28 53.75,97.16 53.75,95.89 54.01,95.63 54.77,95.63 55.79,94.61 55.79,94.23 55.91,94.11 56.29,94.11 56.42,93.98 56.42,92.46 56.17,92.2
+V_3P3_VGA on TOP: 98.08,93.47 97.57,93.98 97.57,94.49 97.7,94.61 100.36,94.61 100.49,94.49 100.49,93.6 100.36,93.47 ; 1 cut-out
+V_3P3_VGA on TOP: 80.3,73.03 80.17,73.15 80.17,77.09 80.3,77.22 81.19,77.22 81.44,77.47 82.33,77.47 82.46,77.6 82.46,78.11 82.58,78.23 85.25,78.23 85.76,77.72 85.76,75.82 85.63,75.69 84.62,75.69 84.36,75.44 84.36,73.28 84.11,73.03 ; 5 cut-outs
+V_3P3_VGA on TOP: 87.54,78.74 87.54,79.5 89.82,79.5 90.2,79.88 90.2,82.42 90.33,82.55 91.09,82.55 91.22,82.68 91.22,83.31 91.35,83.44 93.89,83.44 94.01,83.31 94.01,81.92 94.27,81.66 95.16,81.66 95.28,81.79 95.28,83.31 95.41,83.44 96.93,83.44 97.06,83.31 97.06,81.03 96.55,80.52 91.98,80.52 90.2,78.74 ; 6 cut-outs
+V_3P3_VGA on BOTTOM: 85.5,77.09 84.62,77.98 84.62,78.23 85.76,79.38 87.03,79.38 88.17,80.52 88.17,81.41 88.3,81.53 89.7,81.53 90.08,81.92 90.08,82.68 89.95,82.8 89.31,82.8 89.19,82.93 89.19,83.31 89.31,83.44 90.84,83.44 90.97,83.31 90.97,81.15 86.9,77.09 ; 1 cut-out
+V_3P3_VGA on BOTTOM: 95.54,81.41 95.41,81.53 95.41,82.42 95.54,82.55 97.19,82.55 97.95,83.31 97.95,89.79 99.86,91.69 99.86,94.36 100.11,94.61 100.87,94.61 101,94.49 101,90.55 99.86,89.41 99.86,83.31 97.95,81.41
+V_3P3_VGA on BOTTOM: 96.55,90.3 96.43,90.42 96.43,92.33 96.93,92.84 96.93,99.69 96.62,100.01 96.62,105.09 95.92,105.79 94.39,105.79 94.27,105.66 87.54,105.66 87.28,105.92 87.28,106.43 87.41,106.55 92.36,106.55 92.49,106.68 96.43,106.68 97.7,105.41 97.7,100.58 98.46,99.82 98.97,99.82 99.09,99.69 99.09,99.19 98.97,99.06 98.46,99.06 98.2,98.81 98.2,96.65 98.97,95.89 98.97,93.34 97.57,91.95 97.57,90.81 97.06,90.3 ; 1 cut-out
+V_VGA_CORE on TOP: 84.37,95.14 84.24,95.28 84.21,95.31 84.21,95.57 87.42,98.78 87.42,99.16 87.06,99.52 86.85,99.52 82.61,95.28 82.46,95.28 82.28,95.45 82.28,95.66 87.43,100.81 87.43,101.16 87.14,101.44 86.89,101.44 80.64,95.19 80.4,95.19 80.28,95.31 80.28,95.65 86.83,102.2 86.83,102.2 87.4,102.78 87.4,103.14 87.14,103.4 86.87,103.4 78.8,95.33 78.38,95.33 78.23,95.47 78.27,95.5 78.27,99.57 82.99,104.3 82.99,104.29 83.19,104.29 83.4,104.09 83.4,103.88 78.48,98.96 78.48,98.71 78.73,98.45 79.08,98.45 84.87,104.24 85.12,104.24 85.29,104.07 85.29,103.84 79.22,97.77 79.22,97.77 78.56,97.1 78.56,96.74 78.78,96.52 79.17,96.52 86.95,104.29 86.95,104.78 87.92,104.78 88.39,104.31 88.39,96.96 87.94,96.52 87.94,96.52 87.05,95.63 86.87,95.63 86.7,95.81 86.7,96.04 87.87,97.21 87.87,97.64 87.67,97.83 87.29,97.83 84.6,95.14
+V_VGA_CORE on TOP: 78.37,101.29 78.35,101.31 78.35,103.63 78.96,104.23 79.16,104.23 79.34,104.05 79.34,103.86 78.58,103.1 78.58,102.86 78.93,102.52 79.16,102.52 80.88,104.24 81.12,104.24 81.29,104.07 81.29,103.83 78.75,101.29
+V_VGA_CORE on TOP: 105.44,82.3 104.55,83.19 104.55,92.71 104.81,92.96 107.22,92.96 107.86,93.6 114.46,93.6 114.59,93.47 114.59,82.55 114.33,82.3
+V_VGA_CORE on BOTTOM: 88.04,103.12 92.24,103.12 92.49,103.38 94.52,103.38 94.65,103.25 94.65,100.2 95.16,99.69 95.16,98.3 95.03,98.17 91.73,98.17 90.71,99.19 89.44,99.19 88.81,98.55 88.81,98.42 88.55,98.17 87.03,98.17 86.77,98.42 86.77,98.93 86.65,99.06 86.01,99.06 85.89,98.93 85.89,98.3 85.76,98.17 85,98.17 84.74,97.92 84.74,97.03 82.96,95.25 80.42,95.25 78.27,97.41 78.27,101.98 78.01,102.23 77.63,102.23 77.38,102.49 77.38,103.76 77.5,103.89 78.52,103.89 79.41,103 83.85,103 85.25,104.39 87.66,104.39 87.79,104.27 87.79,103.38 ; 1 cut-out
+V_VGA_CORE on BOTTOM: 105.44,82.3 104.68,83.06 104.68,92.71 104.94,92.96 114.21,92.96 114.59,92.58 114.59,82.55 114.33,82.3
+V_VGA_CORE on L3: 78.9,104.52 96.93,104.52 97.82,103.63 104.94,103.63 107.22,101.35 107.22,96.14 107.73,95.63 113.7,95.63 113.95,95.38 113.95,95.12 114.59,94.49 114.59,82.55 114.33,82.3 99.86,82.3 88.81,93.34 83.73,93.34 81.95,95.12 78.77,95.12 78.14,95.76 78.14,103.76
+V_VGA_CORE on L4: 82.08,94.23 82.96,93.34 88.81,93.34 99.86,82.3 114.33,82.3 114.59,82.55 114.59,94.49 113.95,95.12 113.95,95.38 113.7,95.63 107.73,95.63 107.22,96.14 107.22,101.35 104.94,103.63 97.82,103.63 97.32,104.14 78.52,104.14 78.14,103.76 78.14,95.25 79.15,94.23
AD+_TO_SYS on TOP: 63.91,38.35 63.79,38.48 63.79,40.89 63.41,41.27 62.64,41.27 62.39,41.53 62.39,42.67 71.15,42.67 71.41,42.42 71.41,38.35
AD+_TO_SYS on BOTTOM: 67.47,38.35 66.84,38.99 61.37,38.99 61.37,42.29 61.76,42.67 71.15,42.67 71.41,42.42 71.41,38.35
AD_JK on TOP: 59.6,23.5 57.44,25.65 56.17,25.65 55.79,25.27 54.26,25.27 53.5,26.04 53.5,27.81 53.88,28.19 54.9,28.19 55.53,28.83 55.53,30.1 56.68,31.24 56.68,38.61 56.8,38.73 61.63,38.73 62.01,38.35 62.01,31.37 62.39,30.99 68.74,30.99 68.87,30.86 68.87,28.96 68.74,28.83 66.2,28.83 65.82,28.45 65.82,26.67 64.68,25.53 64.68,23.88 64.3,23.5 ; 2 cut-outs
AD_JK on BOTTOM: 60.23,22.86 57.44,25.65 56.17,25.65 55.79,25.27 54.26,25.27 53.5,26.04 53.5,27.81 53.88,28.19 54.9,28.19 55.53,28.83 55.53,30.1 56.8,31.37 68.11,31.37 68.36,31.11 68.36,28.45 67.6,27.69 66.71,27.69 64.17,25.15 64.17,23.11 63.91,22.86 ; 4 cut-outs
AD_JK on L3: 55.79,25.27 56.17,25.65 57.44,25.65 58.83,24.26 60.36,24.26 64.8,28.7 68.61,28.7 68.74,28.83 68.74,30.61 68.49,30.86 62.64,30.86 62.26,30.48 57.18,30.48 54.9,28.19 53.88,28.19 53.5,27.81 53.5,26.04 54.26,25.27
BT+ on TOP: 39.02,66.04 39.02,67.18 38.9,67.31 35.72,67.31 35.47,67.56 34.58,67.56 33.82,68.33 31.53,68.33 31.4,68.45 31.4,73.79 31.66,74.04 33.31,74.04 33.56,73.79 33.56,72.9 33.94,72.52 42.71,72.52 43.09,72.14 43.09,66.17 42.96,66.04 ; 5 cut-outs
